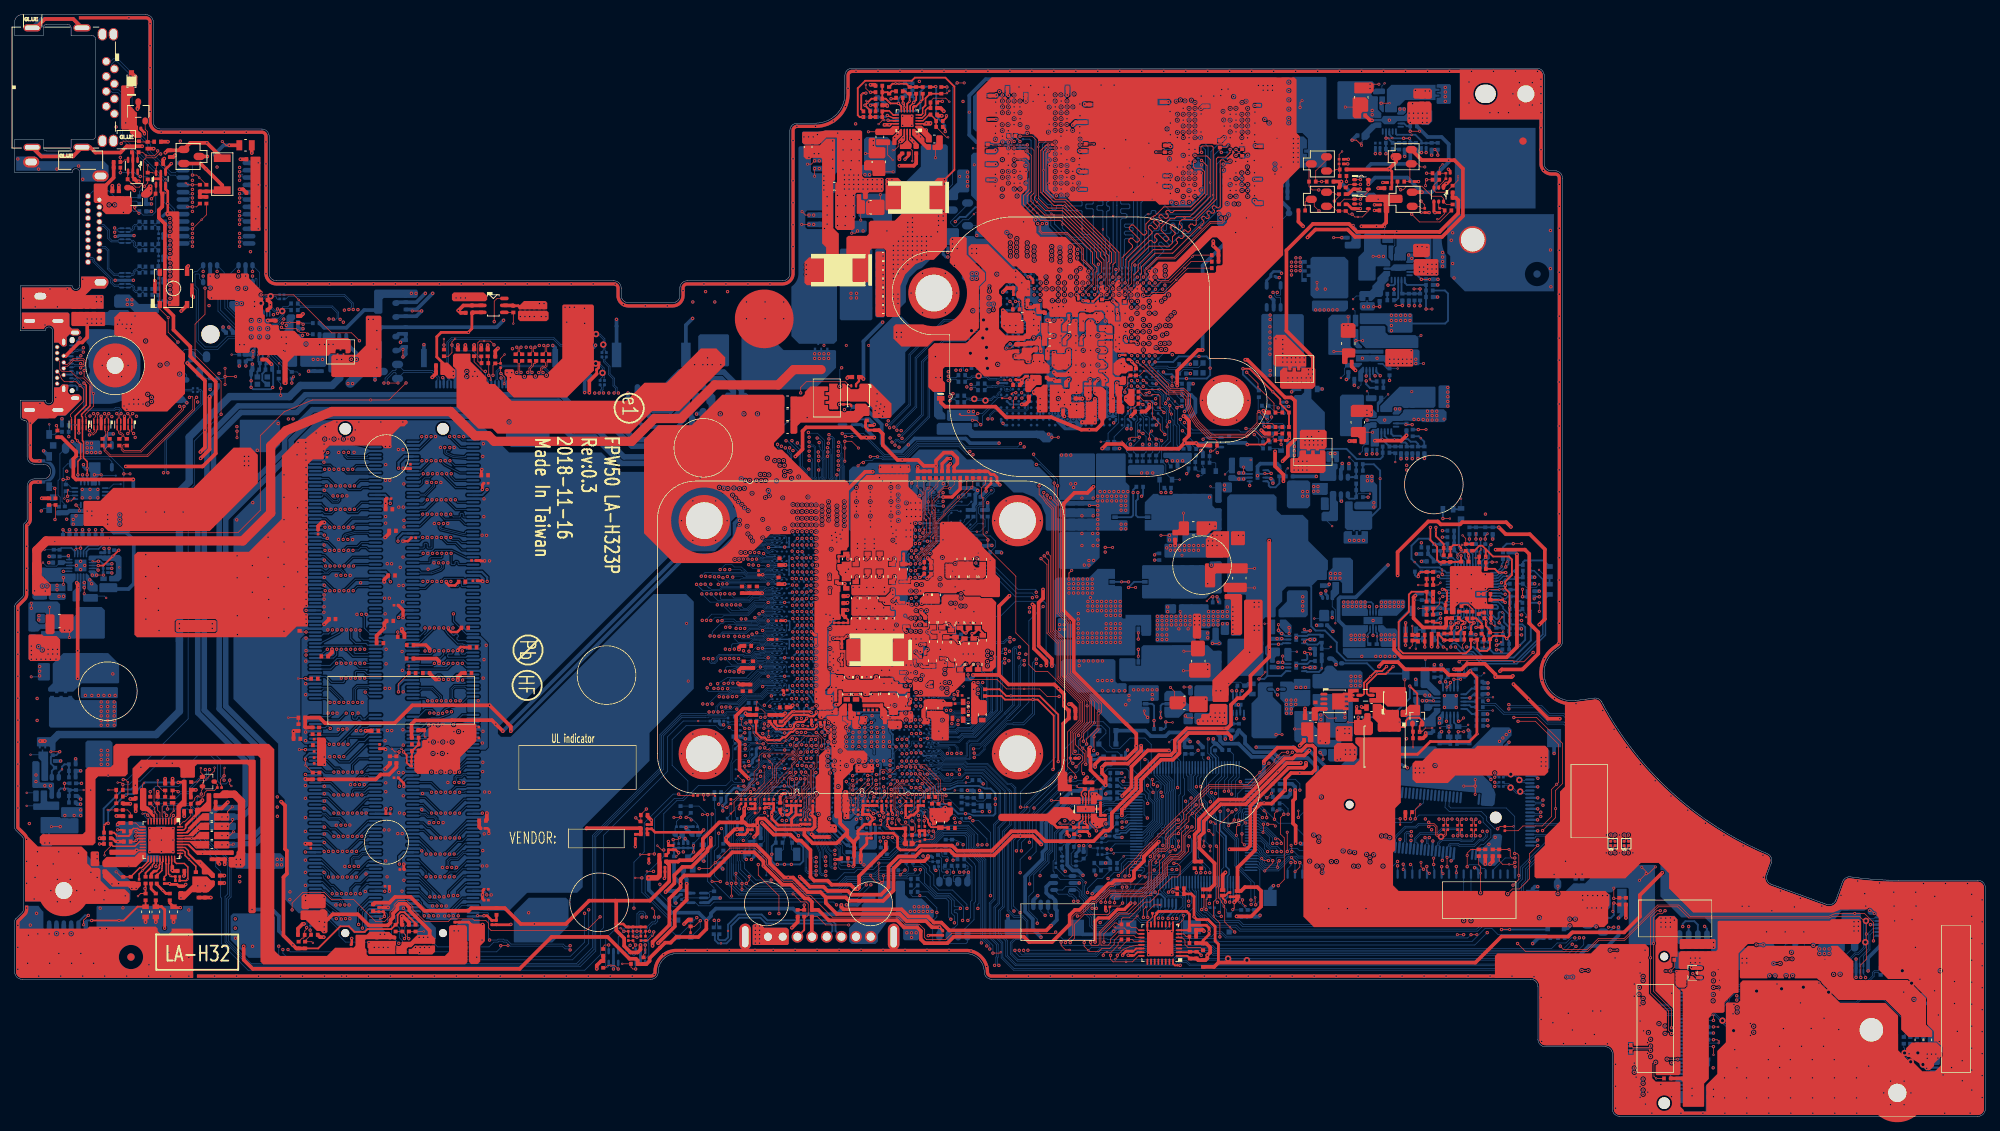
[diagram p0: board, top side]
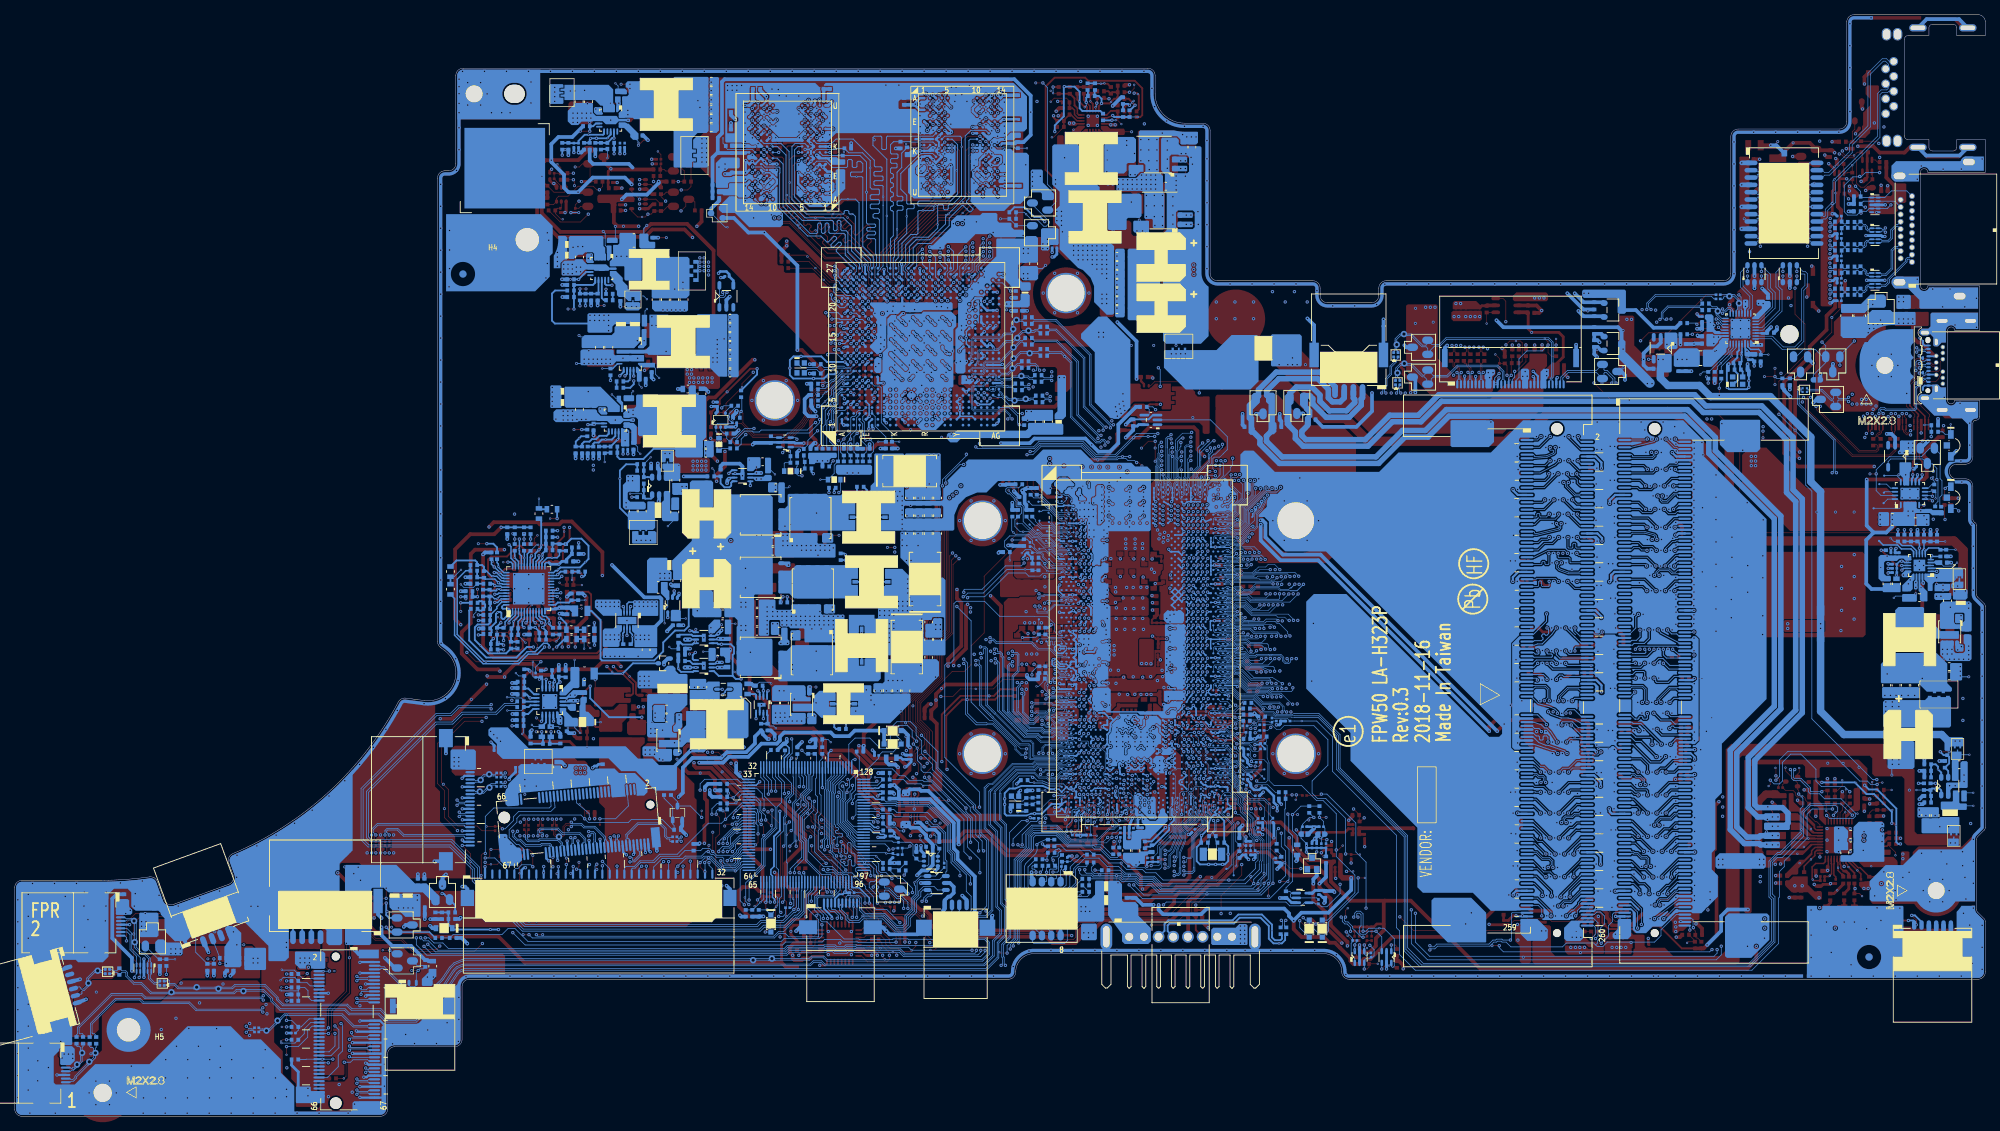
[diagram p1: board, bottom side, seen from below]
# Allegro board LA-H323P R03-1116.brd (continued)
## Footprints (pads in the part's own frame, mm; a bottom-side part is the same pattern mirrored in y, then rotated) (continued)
KC_FBMA-L11160808601LMA10T_2P
  rect 0.559x1.041 smd: 1(0,0) 2(1.3,0)
L2N7002DW1T1G_SC88-6
  oval 0.406x0.508 smd: 1(0,0) 2(0.65,0) 3(1.3,0) 4(1.3,1.9) 5(0.65,1.9) 6(0,1.9)
L03ESDL5V0CC3-2_SOT23-3
  oval 1.016x1.524 smd: 1(0,0) 2(0.965,2.083) 3(-0.965,2.083)
L05ESDL5V0NA-4_SLP2510P8-10-9
  rect 0.203x0.686 smd: 1(0,0) 2(-0.5,0) 4(-1.5,0) 5(-2,0) 6(-2,-0.875) 7(-1.5,-0.875) 8(-0.5,-0.875) 9(0,-0.875)
  rect 0.406x1.549 smd: 3(-1,-0.437)
L30ESD24VC3-2_SOT23-3
  oval 1.016x1.524 smd: 1(0,0) 2(0.965,2.083) 3(-0.965,2.083)
L_4X4X2_F_2P
  rect 1.194x3.708 smd: 1(0,0) 2(2.8,0)
L_5X5X3_M
  custom 0.54x0.54 smd: 1(0,0) 4(4.35,0)
  rect 0.762x0.508 smd: 2(0.699,0) 3(3.652,0)
L_5X5X3_M_2P
  rect 2.159x2.794 smd: 1(0,0) 2(4.35,0)
L_7X7X3_M
  custom 0.591x0.591 smd: 1(0,0) 4(6.05,0)
  rect 0.762x0.508 smd: 2(0.8,0) 3(5.25,0)
L_7X7X3_M_2P
  rect 2.362x3.505 smd: 1(0,0) 2(6.05,0)
L_7X7X4_M
  custom 0.591x0.591 smd: 1(0,0) 4(6.05,0)
  rect 0.762x0.508 smd: 2(0.8,0) 3(5.25,0)
LBSS138LT1G_SOT23-3
  oval 1.016x1.524 smd: 1(0,0) 2(0.965,2.083) 3(-0.965,2.083)
LED_LTW-110DC5-C_3P
  rect 1.194x0.787 smd: 1(0,0) 2(3,0)
  rect 0.889x0.889 smd: 3(1.5,-0.55)
LOTES_AHDM0064-P001A_19P
  round 0.787 hole 0.559: 1(0,0) 2(0.5,1.55) 3(1,0) 4(1.5,1.55) 5(2,0) 6(2.5,1.55) 7(3,0) 8(3.5,1.55) 9(4,0) 10(4.5,1.55) 11(5,0) 12(5.5,1.55) 13(6,0) 14(6.5,1.55) 15(7,0) 16(7.5,1.55) 17(8,0) 18(8.5,1.55) 19(9,0)
  oval 1.499x2.21 hole 0.889x1.6: 20(-2.75,1.7) 21(-4.65,-6.5) 22(11.75,1.7) 23(13.65,-7.75)
LOTES_APCI0019-P003H_67P
  round 1.092 hole 1.092 unplated: (-0.75,-5.275)
  round 1.6 hole 1.6 unplated: (19.25,-5.275)
  oval 0.305x1.549 smd: 1(0,0) 2(0.25,-7.55) 3(0.5,0) 4(0.75,-7.55) 5(1,0) 6(1.25,-7.55) 7(1.5,0) 8(1.75,-7.55) 9(2,0) 10(2.25,-7.55) 11(2.5,0) 12(2.75,-7.55) 13(3,0) 14(3.25,-7.55) 15(3.5,0) 16(3.75,-7.55) 17(4,0) 18(4.25,-7.55) 19(4.5,0) 20(4.75,-7.55) 21(5,0) 22(5.25,-7.55) 23(5.5,0) 24(7.75,-7.55) 25(8,0) 26(8.25,-7.55) 27(8.5,0) 28(8.75,-7.55) 29(9,0) 30(9.25,-7.55) 31(9.5,0) 32(9.75,-7.55) 33(10,0) 34(10.25,-7.55) 35(10.5,0) 36(10.75,-7.55) 37(11,0) 38(11.25,-7.55) 39(11.5,0) 40(11.75,-7.55) 41(12,0) 42(12.25,-7.55) 43(12.5,0) 44(12.75,-7.55) 45(13,0) 46(13.25,-7.55) 47(13.5,0) 48(13.75,-7.55) 49(14,0) 50(14.25,-7.55) 51(14.5,0) 52(14.75,-7.55) 53(15,0) 54(15.25,-7.55) 55(15.5,0) 56(15.75,-7.55) 57(16,0) 58(16.25,-7.55) 59(16.5,0) 60(16.75,-7.55) 61(17,0) 62(17.25,-7.55) 63(17.5,0) 64(17.75,-7.55) 65(18,0) 66(18.25,-7.55) 67(18.5,0)
  rect 1.194x2.743 smd: 68(-1.1,-0.775) 69(19.6,-0.775)
LUDZS3P6BT1G_SOD323-2
  rect 0.635x0.838 smd: 1(0,0) 2(2.225,0)
MMBF170-7-F_SOT23-3
  oval 1.016x1.524 smd: 1(0,0) 2(0.965,2.083) 3(-0.965,2.083)
MMBT3904WH_SOT323-3
  oval 0.61x0.787 smd: 1(0,0) 2(-0.65,-1.6) 3(0.65,-1.6)
MURAT_BLM15BD601SN1D_2P
  rect 0.508x0.762 smd: 1(0,0) 2(0.75,0)
MURAT_BLM15EG221SN1D_2P
  rect 0.508x0.762 smd: 1(0,0) 2(0.75,0)
MURAT_BLM15PX471SN1D_2P
  rect 0.508x0.762 smd: 1(0,0) 2(0.75,0)
MURAT_BLM18PG300SN1D_2P
  rect 0.66x1.041 smd: 1(0,0) 2(1.2,0)
MURAT_DLM0NSN900HY2D_4P
  rect 0.305x0.305 smd: 1(0,0) 2(0.6,0) 3(0.6,-0.5) 4(0,-0.5)
N16S-GT-S-A2_BGA_595P
  round 0.381 smd: A2(0.8,0) A3(1.6,0) A4(2.4,0) A6(4.1,0) A7(4.9,0) A9(6.58,0) A10(7.38,0) A12(9.06,0) A13(9.86,0) A15(11.54,0) A16(12.34,0) A18(14.02,0) A19(14.82,0) A21(16.5,0) A22(17.3,0) A24(19,0) A25(19.8,0) A26(20.6,0) AA1(0,-16.5) AA2(0.8,-16.5) AA3(1.6,-16.5) AA4(2.4,-16.5) AA5(3.2,-16.5) AA6(4.04,-16.5) AA7(4.9,-16.5) AA8(5.74,-16.5) AA9(6.58,-16.56) AA10(7.38,-16.56) AA12(9.06,-16.56) AA13(9.86,-16.56) AA14(10.7,-16.56) AA15(11.54,-16.56) AA16(12.34,-16.56) AA18(14.02,-16.56) AA19(14.82,-16.56) AA20(15.66,-16.5) AA21(16.5,-16.5) AA22(17.36,-16.5) AA23(18.2,-16.5) AA24(19,-16.5) AA25(19.8,-16.5) AA26(20.6,-16.5) AA27(21.4,-16.5) AB1(0,-17.3) AB2(0.8,-17.3) AB3(1.6,-17.3) AB4(2.4,-17.3) AB5(3.2,-17.3) AB6(4.1,-17.3) AB7(4.9,-17.36) AB8(5.74,-17.36) AB9(6.58,-17.36) AB10(7.38,-17.36) AB11(8.22,-17.36) AB12(9.06,-17.36) AB13(9.86,-17.36) AB14(10.7,-17.36) AB15(11.54,-17.36) AB16(12.34,-17.36) AB17(13.18,-17.36) AB18(14.02,-17.36) AB19(14.82,-17.36) AB20(15.66,-17.36) AB21(16.5,-17.36) AB22(17.3,-17.3) AB23(18.2,-17.3) AB24(19,-17.3) AB25(19.8,-17.3) AB26(20.6,-17.3) AB27(21.4,-17.3) AC2(0.8,-18.15) AC3(1.6,-18.15) AC4(2.4,-18.15) AC5(3.25,-18.15) AC6(4.1,-18.2) AC7(4.9,-18.2) AC8(5.74,-18.2) AC9(6.58,-18.2) AC10(7.38,-18.2) AC11(8.22,-18.2) AC12(9.06,-18.2) AC13(9.86,-18.2) AC14(10.7,-18.2) AC15(11.54,-18.2) AC16(12.34,-18.2) AC17(13.18,-18.2) AC18(14.02,-18.2) AC19(14.82,-18.2) AC20(15.66,-18.2) AC21(16.5,-18.2) AC22(17.3,-18.2) AC23(18.15,-18.15) AC24(19,-18.15) AC25(19.8,-18.15) AC26(20.6,-18.15) AD1(0,-19) AD2(0.8,-19) AD3(1.6,-19) AD4(2.4,-19) AD5(3.25,-19) AD6(4.1,-19) AD7(4.9,-19) AD8(5.74,-19) AD9(6.58,-19) AD10(7.38,-19) AD11(8.22,-19) AD12(9.06,-19) AD13(9.86,-19) AD14(10.7,-19) AD15(11.54,-19) AD16(12.34,-19) AD17(13.18,-19) AD18(14.02,-19) AD19(14.82,-19) AD20(15.66,-19) AD21(16.5,-19) AD22(17.3,-19) AD23(18.15,-19) AD24(19,-19) AD25(19.8,-19) AD26(20.6,-19) AD27(21.4,-19) AE1(0,-19.8) AE2(0.8,-19.8) AE3(1.6,-19.8) AE4(2.4,-19.8) AE5(3.25,-19.8) AE6(4.1,-19.8) AE7(4.9,-19.8) AE8(5.74,-19.8) AE9(6.58,-19.8) AE10(7.38,-19.8) AE11(8.22,-19.8) AE12(9.06,-19.8) AE13(9.86,-19.8) AE14(10.7,-19.8) AE15(11.54,-19.8) AE16(12.34,-19.8) AE17(13.18,-19.8) AE18(14.02,-19.8) AE19(14.82,-19.8) AE20(15.66,-19.8) AE21(16.5,-19.8) AE22(17.3,-19.8) AE23(18.15,-19.8) AE24(19,-19.8) AE25(19.8,-19.8) AE26(20.6,-19.8) AE27(21.4,-19.8) AF1(0,-20.6) AF2(0.8,-20.6) AF3(1.6,-20.6) AF4(2.4,-20.6) AF5(3.25,-20.6) AF6(4.1,-20.6) AF7(4.9,-20.6) AF8(5.74,-20.6) AF9(6.58,-20.6) AF10(7.38,-20.6) AF11(8.22,-20.6) AF12(9.06,-20.6) AF13(9.86,-20.6) AF14(10.7,-20.6) AF15(11.54,-20.6) AF16(12.34,-20.6) AF17(13.18,-20.6) AF18(14.02,-20.6) AF19(14.82,-20.6) AF20(15.66,-20.6) AF21(16.5,-20.6) AF22(17.3,-20.6) AF23(18.15,-20.6) AF24(19,-20.6) AF25(19.8,-20.6) AF26(20.6,-20.6) AF27(21.4,-20.6) AG2(0.8,-21.4) AG3(1.6,-21.4) AG4(2.4,-21.4) AG6(4.1,-21.4) AG7(4.9,-21.4) AG9(6.58,-21.4) AG10(7.38,-21.4) AG12(9.06,-21.4) AG13(9.86,-21.4) AG15(11.54,-21.4) AG16(12.34,-21.4) AG18(14.02,-21.4) AG19(14.82,-21.4) AG21(16.5,-21.4) AG22(17.3,-21.4) AG24(19,-21.4) AG25(19.8,-21.4) AG26(20.6,-21.4) B1(0,-0.8) B2(0.8,-0.8) B3(1.6,-0.8) B4(2.4,-0.8) B5(3.25,-0.8) B6(4.1,-0.8) B7(4.9,-0.8) B8(5.74,-0.8) B9(6.58,-0.8) B10(7.38,-0.8) B11(8.22,-0.8) B12(9.06,-0.8) B13(9.86,-0.8) B14(10.7,-0.8) B15(11.54,-0.8) B16(12.34,-0.8) B17(13.18,-0.8) B18(14.02,-0.8) B19(14.82,-0.8) B20(15.66,-0.8) B21(16.5,-0.8) B22(17.3,-0.8) B23(18.15,-0.8) B24(19,-0.8) B25(19.8,-0.8) B26(20.6,-0.8) B27(21.4,-0.8) C1(0,-1.6) C2(0.8,-1.6) C3(1.6,-1.6) C4(2.4,-1.6) C5(3.25,-1.6) C6(4.1,-1.6) C7(4.9,-1.6) C8(5.74,-1.6) C9(6.58,-1.6) C10(7.38,-1.6) C11(8.22,-1.6) C12(9.06,-1.6) C13(9.86,-1.6) C14(10.7,-1.6) C15(11.54,-1.6) C16(12.34,-1.6) C17(13.18,-1.6) C18(14.02,-1.6) C19(14.82,-1.6) C20(15.66,-1.6) C21(16.5,-1.6) C22(17.3,-1.6) C23(18.15,-1.6) C24(19,-1.6) C25(19.8,-1.6) C26(20.6,-1.6) C27(21.4,-1.6) D1(0,-2.4) D2(0.8,-2.4) D3(1.6,-2.4) D4(2.4,-2.4) D5(3.25,-2.4) D6(4.1,-2.4) D7(4.9,-2.4) D8(5.74,-2.4) D9(6.58,-2.4) D10(7.38,-2.4) D11(8.22,-2.4) D12(9.06,-2.4) D13(9.86,-2.4) D14(10.7,-2.4) D15(11.54,-2.4) D16(12.34,-2.4) D17(13.18,-2.4) D18(14.02,-2.4) D19(14.82,-2.4) D20(15.66,-2.4) D21(16.5,-2.4) D22(17.3,-2.4) D23(18.15,-2.4) D24(19,-2.4) D25(19.8,-2.4) D26(20.6,-2.4) D27(21.4,-2.4) E2(0.8,-3.25) E3(1.6,-3.25) E4(2.4,-3.25) E5(3.25,-3.25) E6(4.1,-3.2) E7(4.9,-3.2) E8(5.74,-3.2) E9(6.58,-3.2) E10(7.38,-3.2) E11(8.22,-3.2) E12(9.06,-3.2) E13(9.86,-3.2) E14(10.7,-3.2) E15(11.54,-3.2) E16(12.34,-3.2) E17(13.18,-3.2) E18(14.02,-3.2) E19(14.82,-3.2) E20(15.66,-3.2) E21(16.5,-3.2) E22(17.3,-3.2) E23(18.15,-3.25) E24(19,-3.25) E25(19.8,-3.25) E26(20.6,-3.25) F1(0,-4.1) F2(0.8,-4.1) F3(1.6,-4.1) F4(2.4,-4.1) F5(3.2,-4.1) F6(4.1,-4.1) F7(4.9,-4.04) F8(5.74,-4.04) F9(6.58,-4.04) F10(7.38,-4.04) F11(8.22,-4.04) F12(9.06,-4.04) F13(9.86,-4.04) F14(10.7,-4.04) F15(11.54,-4.04) F16(12.34,-4.04) F17(13.18,-4.04) F18(14.02,-4.04) F19(14.82,-4.04) F20(15.66,-4.04) F21(16.5,-4.04) F22(17.3,-4.1) F23(18.2,-4.1) F24(19,-4.1) F25(19.8,-4.1) F26(20.6,-4.1) F27(21.4,-4.1) G1(0,-4.9) G2(0.8,-4.9) G3(1.6,-4.9) G4(2.4,-4.9) G5(3.2,-4.9) G6(4.04,-4.9) G7(4.9,-4.9) G8(5.74,-4.9) G9(6.58,-4.84) G10(7.38,-4.84) G12(9.06,-4.84) G13(9.86,-4.84) G14(10.7,-4.84) G15(11.54,-4.84) G16(12.34,-4.84) G18(14.02,-4.84) G19(14.82,-4.84) G20(15.66,-4.9) G21(16.5,-4.9) G22(17.36,-4.9) G23(18.2,-4.9) G24(19,-4.9) G25(19.8,-4.9) G26(20.6,-4.9) G27(21.4,-4.9) H2(0.8,-5.74) H3(1.6,-5.74) H4(2.4,-5.74) H5(3.2,-5.74) H6(4.04,-5.74) H22(17.36,-5.74) H23(18.2,-5.74) H24(19,-5.74) H25(19.8,-5.74) H26(20.6,-5.74) J1(0,-6.58) J2(0.8,-6.58) J3(1.6,-6.58) J4(2.4,-6.58) J5(3.2,-6.58) J6(4.04,-6.58) J7(4.84,-6.58) J21(16.56,-6.58) J22(17.36,-6.58) J23(18.2,-6.58) J24(19,-6.58) J25(19.8,-6.58) J26(20.6,-6.58) J27(21.4,-6.58) K1(0,-7.38) K2(0.8,-7.38) K3(1.6,-7.38) K4(2.4,-7.38) K5(3.2,-7.38) K6(4.04,-7.38) K7(4.84,-7.38) K21(16.56,-7.38) K22(17.36,-7.38) K23(18.2,-7.38) K24(19,-7.38) K25(19.8,-7.38) K26(20.6,-7.38) K27(21.4,-7.38) L2(0.8,-8.22) L3(1.6,-8.22) L4(2.4,-8.22) L5(3.2,-8.22) L6(4.04,-8.22) L22(17.36,-8.22) L23(18.2,-8.22) L24(19,-8.22) L25(19.8,-8.22) L26(20.6,-8.22) M1(0,-9.06) M2(0.8,-9.06) M3(1.6,-9.06) M4(2.4,-9.06) M5(3.2,-9.06) M6(4.04,-9.06) M7(4.84,-9.06) M21(16.56,-9.06) M22(17.36,-9.06) M23(18.2,-9.06) M24(19,-9.06) M25(19.8,-9.06) M26(20.6,-9.06) M27(21.4,-9.06) N1(0,-9.86) N2(0.8,-9.86) N3(1.6,-9.86) N4(2.4,-9.86) N5(3.2,-9.86) N6(4.04,-9.86) N7(4.84,-9.86) N21(16.56,-9.86) N22(17.36,-9.86) N23(18.2,-9.86) N24(19,-9.86) N25(19.8,-9.86) N26(20.6,-9.86) N27(21.4,-9.86) P2(0.8,-10.7) P3(1.6,-10.7) P4(2.4,-10.7) P5(3.2,-10.7) P6(4.04,-10.7) P22(17.36,-10.7) P23(18.2,-10.7) P24(19,-10.7) P25(19.8,-10.7) P26(20.6,-10.7) R1(0,-11.54) R2(0.8,-11.54) R3(1.6,-11.54) R4(2.4,-11.54) R5(3.2,-11.54) R6(4.04,-11.54) R7(4.84,-11.54) R21(16.56,-11.54) R22(17.36,-11.54) R23(18.2,-11.54) R24(19,-11.54) R25(19.8,-11.54) R26(20.6,-11.54) R27(21.4,-11.54) T1(0,-12.34) T2(0.8,-12.34) T3(1.6,-12.34) T4(2.4,-12.34) T5(3.2,-12.34) T6(4.04,-12.34) T7(4.84,-12.34) T21(16.56,-12.34) T22(17.36,-12.34) T23(18.2,-12.34) T24(19,-12.34) T25(19.8,-12.34) T26(20.6,-12.34) T27(21.4,-12.34) U2(0.8,-13.18) U3(1.6,-13.18) U4(2.4,-13.18) U5(3.2,-13.18) U6(4.04,-13.18) U22(17.36,-13.18) U23(18.2,-13.18) U24(19,-13.18) U25(19.8,-13.18) U26(20.6,-13.18) V1(0,-14.02) V2(0.8,-14.02) V3(1.6,-14.02) V4(2.4,-14.02) V5(3.2,-14.02) V6(4.04,-14.02) V7(4.84,-14.02) V21(16.56,-14.02) V22(17.36,-14.02) V23(18.2,-14.02) V24(19,-14.02) V25(19.8,-14.02) V26(20.6,-14.02) V27(21.4,-14.02) W1(0,-14.82) W2(0.8,-14.82) W3(1.6,-14.82) W4(2.4,-14.82) W5(3.2,-14.82) W6(4.04,-14.82) W7(4.84,-14.82) W21(16.56,-14.82) W22(17.36,-14.82) W23(18.2,-14.82) W24(19,-14.82) W25(19.8,-14.82) W26(20.6,-14.82) W27(21.4,-14.82) Y2(0.8,-15.66) Y3(1.6,-15.66) Y4(2.4,-15.66) Y5(3.2,-15.66) Y6(4.04,-15.66) Y22(17.36,-15.66) Y23(18.2,-15.66) Y24(19,-15.66) Y25(19.8,-15.66) Y26(20.6,-15.66)
  round 0.406 smd: K10(6.7,-6.7) K11(7.7,-6.7) K12(8.7,-6.7) K13(9.7,-6.7) K14(10.7,-6.7) K15(11.7,-6.7) K16(12.7,-6.7) K17(13.7,-6.7) K18(14.7,-6.7) L10(6.7,-7.7) L11(7.7,-7.7) L12(8.7,-7.7) L13(9.7,-7.7) L14(10.7,-7.7) L15(11.7,-7.7) L16(12.7,-7.7) L17(13.7,-7.7) L18(14.7,-7.7) M10(6.7,-8.7) M11(7.7,-8.7) M12(8.7,-8.7) M13(9.7,-8.7) M14(10.7,-8.7) M15(11.7,-8.7) M16(12.7,-8.7) M17(13.7,-8.7) M18(14.7,-8.7) N10(6.7,-9.7) N11(7.7,-9.7) N12(8.7,-9.7) N13(9.7,-9.7) N14(10.7,-9.7) N15(11.7,-9.7) N16(12.7,-9.7) N17(13.7,-9.7) N18(14.7,-9.7) P10(6.7,-10.7) P11(7.7,-10.7) P12(8.7,-10.7) P13(9.7,-10.7) P14(10.7,-10.7) P15(11.7,-10.7) P16(12.7,-10.7) P17(13.7,-10.7) P18(14.7,-10.7) R10(6.7,-11.7) R11(7.7,-11.7) R12(8.7,-11.7) R13(9.7,-11.7) R14(10.7,-11.7) R15(11.7,-11.7) R16(12.7,-11.7) R17(13.7,-11.7) R18(14.7,-11.7) T10(6.7,-12.7) T11(7.7,-12.7) T12(8.7,-12.7) T13(9.7,-12.7) T14(10.7,-12.7) T15(11.7,-12.7) T16(12.7,-12.7) T17(13.7,-12.7) T18(14.7,-12.7) U10(6.7,-13.7) U11(7.7,-13.7) U12(8.7,-13.7) U13(9.7,-13.7) U14(10.7,-13.7) U15(11.7,-13.7) U16(12.7,-13.7) U17(13.7,-13.7) U18(14.7,-13.7) V10(6.7,-14.7) V11(7.7,-14.7) V12(8.7,-14.7) V13(9.7,-14.7) V14(10.7,-14.7) V15(11.7,-14.7) V16(12.7,-14.7) V17(13.7,-14.7) V18(14.7,-14.7)
NC7ST32P5X_SC70-5
  oval 0.406x0.508 smd: 1(0,0) 2(0.65,0) 3(1.3,0) 4(1.3,1.9) 5(0,1.9)
OCTEK_BTJ-08TFBRZB_8P
  round 1.6 hole 1.092: 1(0,0) 2(2,0) 3(4,0) 4(6,0) 5(8,0) 6(10,0) 7(12,0) 8(14,0)
  oval 1.6x3.607 hole 0.889x2.896: 9(-3.125,0) 10(17.125,0)
PESD5V0U2BT_SOT23-3
  oval 1.016x1.524 smd: 1(0,0) 2(0.965,2.083) 3(-0.965,2.083)
PJ2301_SOT23-3
  oval 1.016x1.524 smd: 1(0,0) 2(0.965,2.083) 3(-0.965,2.083)
Q_N_DFN56-8-5
  oval 0.61x1.27 smd: 1(0,0) 2(1.27,0) 3(2.54,0) 4(3.81,0)
  custom 1.105x1.105 smd: 5(1.905,3.715)
R0201_0OHM
  rect 0.381x0.356 smd: 1(0,0) 2(0.584,0)
R0402_0OHM
  rect 0.508x0.559 smd: 1(0,0) 2(0.914,0)
R0603_0OHM
  rect 0.635x0.889 smd: 1(0,0) 2(1.397,0)
R0603_0OHM-NPM
  rect 0.635x0.889 smd: 1(0,0) 2(1.397,0)
R0805_0OHM
  rect 0.813x1.397 smd: 1(0,0) 2(1.702,0)
R_0201
  rect 0.381x0.356 smd: 1(0,0) 2(0.584,0)
R_0402
  rect 0.508x0.559 smd: 1(0,0) 2(0.914,0)
R_0603
  rect 0.635x0.889 smd: 1(0,0) 2(1.397,0)
R_0805
  rect 0.813x1.397 smd: 1(0,0) 2(1.702,0)
R_1206
  rect 1.016x1.651 smd: 1(0,0) 2(2.667,0)
R_1206_4P-D
  custom 0.371x0.371 smd: 1(0,0) 4(3.327,0)
  custom 0.114x0.114 smd: 2(0.775,0) 3(2.553,0)
RB751S40T1G_SOD523-2
  rect 0.61x0.787 smd: 1(0,0) 2(1.7,0)
RB751V-40_SOD323-2
  rect 0.787x0.889 smd: 1(0,0) 2(2.14,0)
RT3602AJGQW_WQFN48_6X6
  oval 0.889x0.203 smd: 1(0,0) 2(0,-0.4) 3(0,-0.8) 4(0,-1.2) 5(0,-1.6) 6(0,-2) 7(0,-2.4) 8(0,-2.8) 9(0,-3.2) 10(0,-3.6) 11(0,-4) 12(0,-4.4) 25(6.1,-4.4) 26(6.1,-4) 27(6.1,-3.6) 28(6.1,-3.2) 29(6.1,-2.8) 30(6.1,-2.4) 31(6.1,-2) 32(6.1,-1.6) 33(6.1,-1.2) 34(6.1,-0.8) 35(6.1,-0.4) 36(6.1,0)
  oval 0.203x0.889 smd: 13(0.85,-5.25) 14(1.25,-5.25) 15(1.65,-5.25) 16(2.05,-5.25) 17(2.45,-5.25) 18(2.85,-5.25) 19(3.25,-5.25) 20(3.65,-5.25) 21(4.05,-5.25) 22(4.45,-5.25) 23(4.85,-5.25) 24(5.25,-5.25) 37(5.25,0.85) 38(4.85,0.85) 39(4.45,0.85) 40(4.05,0.85) 41(3.65,0.85) 42(3.25,0.85) 43(2.85,0.85) 44(2.45,0.85) 45(2.05,0.85) 46(1.65,0.85) 47(1.25,0.85) 48(0.85,0.85)
  rect 4.293x4.293 smd: 49(3.05,-2.2)
RT8812AGQW_WQFN20_3X3
  oval 0.203x0.889 smd: 1(0,0) 2(0.4,0) 3(0.8,0) 4(1.2,0) 5(1.6,0) 11(1.6,3.1) 12(1.2,3.1) 13(0.8,3.1) 14(0.4,3.1) 15(0,3.1)
  oval 0.889x0.203 smd: 6(2.35,0.75) 7(2.35,1.15) 8(2.35,1.55) 9(2.35,1.95) 10(2.35,2.35) 16(-0.75,2.35) 17(-0.75,1.95) 18(-0.75,1.55) 19(-0.75,1.15) 20(-0.75,0.75)
  rect 1.702x1.702 smd: 21(0.8,1.55)
RT9610CGQW_WDFN8_2X2
  oval 0.254x0.838 smd: 1(0,0) 2(0.5,0) 3(1,0) 4(1.5,0) 5(1.5,2.15) 6(1,2.15) 7(0.5,2.15) 8(0,2.15)
  rect 1.118x0.533 smd: 9(0.75,1.075)
RTL8166EH-CG_QFN32_4X4
  oval 0.203x0.889 smd: 1(0,0) 2(0.4,0) 3(0.8,0) 4(1.2,0) 5(1.6,0) 6(2,0) 7(2.4,0) 8(2.8,0) 17(2.8,4.1) 18(2.4,4.1) 19(2,4.1) 20(1.6,4.1) 21(1.2,4.1) 22(0.8,4.1) 23(0.4,4.1) 24(0,4.1)
  oval 0.889x0.203 smd: 9(3.45,0.65) 10(3.45,1.05) 11(3.45,1.45) 12(3.45,1.85) 13(3.45,2.25) 14(3.45,2.65) 15(3.45,3.05) 16(3.45,3.45) 25(-0.65,3.45) 26(-0.65,3.05) 27(-0.65,2.65) 28(-0.65,2.25) 29(-0.65,1.85) 30(-0.65,1.45) 31(-0.65,1.05) 32(-0.65,0.65)
  rect 2.692x2.692 smd: 33(1.4,2.05)
SHORTPADS
  custom 0.19x0.19 smd: 1(-0.483,0) 2(0.483,0)
SINGA_2RJ3081-1A8211F_12P-T
  round 1.194 hole 0.889: 1(0,0) 2(1.02,1.1) 3(2.04,0) 4(3.06,1.1) 5(4.08,0) 6(5.1,1.1) 7(6.12,0) 8(7.14,1.1)
  oval 0.991x2.388 hole 0.61x2.007: 9(-4.58,-3.3) 10(-4.58,-10.1) 11(11.72,-10.1) 12(11.72,-3.3)
  oval 1.702x1.295 hole 1.397x0.991: A1(10.845,0.98) A2(10.845,-0.52) B1(-3.705,0.98) B2(-3.705,-0.52)
SINGA_2UB3C02-002111F_24P-T
  round 0.66 hole 0.66 unplated: (-0.7,0.09)
  oval 0.838x0.66 hole 0.838x0.66 unplated: (6.2,0.09)
  oval 0.813x1.397 hole 0.508x1.092: 1(7.225,0.49)
  oval 0.991x2.007 hole 0.508x1.499: 2(8.825,-1.85) 3(8.825,-5.71) 5(-3.325,-1.85) 6(-3.325,-5.71)
  oval 0.991x1.6 hole 0.508x1.092: 4(-1.725,0.49)
  rect 0.508x0.305 smd: 7(5.95,0.78) 8(3.75,0.78) 9(1.75,0.78) 10(-0.45,0.78)
  oval 0.305x0.61 smd: A1(0,0) A2(0.5,0) A3(1,0) A4(1.5,0) A5(2,0) A6(2.5,0) A7(3,0) A8(3.5,0) A9(4,0) A10(4.5,0) A11(5,0)
  oval 0.229x0.61 smd: A12(5.462,0)
  oval 1.194x0.711 hole 0.889x0.406: B1(5.95,-1.05) B12(-0.45,-1.05)
  round 0.61 hole 0.406: B2(5.25,-1.95) B3(4.45,-1.95) B4(4.05,-1.05) B5(3.6,-1.95) B6(3.15,-1.05) B7(2.35,-1.05) B8(1.9,-1.95) B9(1.45,-1.05) B10(1.05,-1.95) B11(0.25,-1.95)
SLB9670VQ1P2-FW4P4X_VQFN32_5X5
  oval 0.889x0.254 smd: 1(0,0) 2(0,-0.5) 3(0,-1) 4(0,-1.5) 5(0,-2) 6(0,-2.5) 7(0,-3) 8(0,-3.5) 17(5.1,-3.5) 18(5.1,-3) 19(5.1,-2.5) 20(5.1,-2) 21(5.1,-1.5) 22(5.1,-1) 23(5.1,-0.5) 24(5.1,0)
  oval 0.254x0.889 smd: 9(0.8,-4.3) 10(1.3,-4.3) 11(1.8,-4.3) 12(2.3,-4.3) 13(2.8,-4.3) 14(3.3,-4.3) 15(3.8,-4.3) 16(4.3,-4.3) 25(4.3,0.8) 26(3.8,0.8) 27(3.3,0.8) 28(2.8,0.8) 29(2.3,0.8) 30(1.8,0.8) 31(1.3,0.8) 32(0.8,0.8)
  rect 3.607x3.607 smd: 33(2.55,-1.75)
SN74AHC1G08DCKR_SC70-5
  oval 0.381x1.295 smd: 1(0,0.15) 2(0.65,0.15) 3(1.3,0.15) 4(1.3,1.89) 5(0,1.89)
SSM3K7002FU_SC70-3
  oval 0.508x0.991 smd: 1(0,0) 2(0.65,1.9) 3(-0.65,1.9)
SW_TJG-533-V-T-R_6P
  rect 0.61x0.991 smd: 1(0,0) 2(0,-4.4) 3(-3.7,0) 4(-3.7,-4.4)
  rect 0.457x1.397 smd: 5(0.675,-2.2) 6(-4.375,-2.2)
SY8032ABC_SOT23-6
  oval 0.61x0.991 smd: 1(0,0) 2(0.95,0) 3(1.9,0) 4(1.9,2.4) 5(0.95,2.4) 6(0,2.4)
SY8270CTMC_QFN13_4X3
  custom 0.337x0.337 smd: 1(0,0)
  rect 0.457x1.702 smd: 2(1.18,-0.75) 12(1.18,1.25)
  rect 0.838x1.702 smd: 3(2.06,-0.75) 11(2.06,1.25)
  oval 0.203x0.787 smd: 4(2.81,-1.2) 10(2.81,1.7)
  oval 0.787x0.254 smd: 5(3.625,-0.65) 6(3.625,-0.2) 7(3.625,0.25) 8(3.625,0.7) 9(3.625,1.15)
  oval 0.254x0.787 smd: 13(0.55,1.7)
SY8284BRAC_QFN20_3X3
  oval 0.889x0.254 smd: 1(0,0) 2(0,-0.45) 3(0,-0.9) 4(0,-1.35) 5(0,-1.8) 11(3.1,-1.8) 12(3.1,-1.35) 13(3.1,-0.9) 14(3.1,-0.45) 15(3.1,0)
  oval 0.254x0.889 smd: 6(0.65,-2.45) 7(1.1,-2.45) 8(1.55,-2.45) 9(2,-2.45) 10(2.45,-2.45) 16(2.45,0.65) 17(2,0.65) 18(1.55,0.65) 19(1.1,0.65) 20(0.65,0.65)
  custom 0.15x0.15 smd: 21(1.55,-0.9)
SY8286RAC_QFN20_3X3
  oval 0.889x0.254 smd: 1(0,0) 2(0,-0.45) 3(0,-0.9) 4(0,-1.35) 5(0,-1.8) 11(3.1,-1.8) 12(3.1,-1.35) 13(3.1,-0.9) 14(3.1,-0.45) 15(3.1,0)
  oval 0.254x0.889 smd: 6(0.65,-2.45) 7(1.1,-2.45) 8(1.55,-2.45) 9(2,-2.45) 10(2.45,-2.45) 16(2.45,0.65) 17(2,0.65) 18(1.55,0.65) 19(1.1,0.65) 20(0.65,0.65)
  rect 0.991x0.991 smd: 21(1.55,-0.9)
TAI-T_HPC252012F-1R0Y_2P
  rect 0.94x2.21 smd: 1(0,0) 2(1.75,0)
TAI-T_LAN-8700GS_25P
  oval 0.635x1.778 smd: 1(0,0) 2(1,0) 3(2,0) 4(3,0) 5(4,0) 6(5,0) 7(6,0) 8(7,0) 9(8,0) 10(9,0) 11(10,0) 12(11,0) 13(11,8.99) 14(10,8.99) 15(9,8.99) 16(8,8.99) 17(7,8.99) 18(6,8.99) 19(5,8.99) 20(4,8.99) 21(3,8.99) 22(2,8.99) 23(1,8.99) 24(0,8.99)
  rect 0.889x0.787 smd: 25(-1.32,4.54)
TC7SH08FUF_SSOP5
  oval 0.457x0.711 smd: 1(0,0) 2(0.65,0) 3(1.3,0) 4(1.3,1.875) 5(0,1.875)
TPC12
  round 0.305 smd: 1(0,0)
TPS22961DNYR_WSON8
  oval 0.305x0.508 smd: 1(0,0) 2(0.65,0) 3(1.3,0) 4(1.95,0) 5(1.95,2.7)
  oval 1.6x0.508 smd: 6(0.65,2.7)
  rect 2.388x1.6 smd: 7(0.975,1.35)
TPS22966DPUR_SON14_2X3
  oval 0.203x0.762 smd: 1(0,0) 2(0.4,0) 3(0.8,0) 4(1.2,0) 5(1.6,0) 6(2,0) 7(2.4,0) 8(2.4,2.05) 9(2,2.05) 10(1.6,2.05) 11(1.2,2.05) 12(0.8,2.05) 13(0.4,2.05) 14(0,2.05)
  rect 2.489x0.889 smd: 15(1.2,1.025)
TPS25810RVCR_QFN20_4X3
  oval 0.254x0.889 smd: 1(0,0) 2(0.5,0) 3(1,0) 4(1.5,0) 5(2,0) 6(2.5,0) 11(2.5,3.1) 12(2,3.1) 13(1.5,3.1) 14(1,3.1) 15(0.5,3.1) 16(0,3.1)
  oval 0.889x0.254 smd: 7(3.3,0.8) 8(3.3,1.3) 9(3.3,1.8) 10(3.3,2.3) 17(-0.8,2.3) 18(-0.8,1.8) 19(-0.8,1.3) 20(-0.8,0.8)
  rect 2.591x1.6 smd: 21(1.25,1.55)
VISHAY_IHLP-2525CZ-01_2P
  rect 2.54x3.556 smd: 1(-2.857,0) 2(2.857,0)
WHL-U42_BGA_1528P-T
  round 0.356 smd: A3(0.919,0) A36(22.17,0) B2(0.46,-0.46) B37(22.63,-0.46) C1(0,-0.919) CP1(0,-44.17) CP37(22.63,-44.17) CR2(0.46,-44.63) CR36(22.17,-44.63)
  round 0.33 smd: A4(1.569,0) A35(21.52,0) B3(1.088,-0.628) B36(22.002,-0.628) C2(0.628,-1.088) C37(22.63,-1.11) CN1(0,-43.52) CN37(22.63,-43.52) CP2(0.628,-44.002) CP36(22.002,-44.002) CR3(1.11,-44.63) CR35(21.52,-44.63) D1(0,-1.569)
  round 0.305 smd: A5(2.219,-0.023) A6(3.083,0) A32(19.543,0) A34(20.87,0) AA4(1.95,-11.894) AA9(5.105,-11.691) AA24(14.994,-11.834) AA26(15.921,-11.834) AA34(20.68,-11.596) AB3(0.981,-12.552) AB4(1.99,-12.552) AB5(2.697,-12.153) AB6(3.347,-12.153) AB7(3.997,-12.153) AB8(4.647,-12.153) AB9(5.105,-12.615) AB10(5.562,-12.153) AB25(15.457,-12.29) AB27(16.384,-12.29) AB28(17.034,-12.29) AB29(17.684,-12.29) AB30(18.334,-12.29) AB31(18.984,-12.29) AB32(19.634,-12.29) AB33(20.355,-12.247) AB34(21.005,-12.247) AC4(1.95,-13.209) AC5(2.697,-13.077) AC6(3.347,-13.077) AC7(3.997,-13.077) AC8(4.647,-13.077) AC10(5.562,-13.077) AC24(14.994,-12.745) AC25(15.457,-13.201) AC26(15.921,-12.745) AC27(16.384,-13.201) AC28(17.034,-13.201) AC29(17.684,-13.201) AC30(18.334,-13.201) AC31(18.984,-13.201) AC32(19.634,-13.201) AC34(20.68,-12.898) AD4(1.625,-13.772) AD9(5.105,-13.539) AD24(14.994,-13.657) AD26(15.921,-13.657) AD33(20.355,-13.505) AD35(21.56,-13.505) AE4(1.95,-14.335) AE5(2.697,-14.001) AE6(3.347,-14.001) AE7(3.997,-14.001) AE8(4.647,-14.001) AE9(5.105,-14.463) AE10(5.562,-14.001) AE24(14.994,-14.568) AE25(15.457,-14.112) AE26(15.921,-14.568) AE27(16.384,-14.112) AE28(17.034,-14.112) AE29(17.684,-14.112) AE30(18.334,-14.112) AE31(18.984,-14.112) AE32(19.634,-14.112) AE34(20.68,-14.113) AF3(0.981,-14.993) AF4(1.99,-14.993) AF5(2.697,-14.925) AF6(3.347,-14.925) AF7(3.997,-14.925) AF8(4.647,-14.925) AF10(5.562,-14.925) AF25(15.457,-15.024) AF27(16.384,-15.024) AF28(17.034,-15.024) AF29(17.684,-15.024) AF30(18.334,-15.024) AF31(18.984,-15.024) AF32(19.634,-15.024) AF33(20.355,-14.764) AF34(21.005,-14.764) AG4(1.95,-15.65) AG5(2.697,-15.848) AG6(3.347,-15.848) AG7(3.997,-15.848) AG8(4.647,-15.848) AG9(5.105,-15.386) AG10(5.562,-15.848) AG24(14.994,-15.48) AG26(15.921,-15.48) AG34(20.68,-15.414) AH4(1.625,-16.213) AH9(5.105,-16.31) AH24(14.994,-16.391) AH25(15.457,-15.935) AH26(15.921,-16.391) AH27(16.384,-15.935) AH28(17.034,-15.935) AH29(17.684,-15.935) AH30(18.334,-15.935) AH31(18.984,-15.935) AH32(19.634,-15.935) AH33(20.355,-16.022) AH35(21.56,-16.022) AJ4(1.95,-16.776) AJ5(2.697,-16.772) AJ6(3.347,-16.772) AJ7(3.997,-16.772) AJ8(4.647,-16.772) AJ10(5.562,-16.772) AJ25(15.457,-16.847) AJ27(16.384,-16.847) AJ28(17.034,-16.847) AJ29(17.684,-16.847) AJ30(18.334,-16.847) AJ31(18.984,-16.847) AJ32(19.634,-16.847) AJ34(20.68,-16.63) AK3(0.981,-17.433) AK4(1.99,-17.433) AK9(5.105,-17.234) AK24(14.994,-17.302) AK26(15.921,-17.302) AK33(20.355,-17.281) AK34(21.005,-17.281) AL4(1.95,-18.091) AL5(2.697,-17.696) AL6(3.347,-17.696) AL7(3.997,-17.696) AL8(4.647,-17.696) AL9(5.105,-18.158) AL10(5.562,-17.696) AL24(14.994,-18.214) AL25(15.457,-17.758) AL26(15.921,-18.214) AL27(16.384,-17.758) AL28(17.034,-17.758) AL29(17.684,-17.758) AL30(18.334,-17.758) AL31(18.984,-17.758) AL32(19.634,-17.758) AL34(20.68,-17.932) AM4(1.625,-18.654) AM5(2.697,-18.62) AM6(3.347,-18.62) AM7(3.997,-18.62) AM8(4.647,-18.62) AM10(5.562,-18.62) AM25(15.457,-18.669) AM27(16.384,-18.669) AM28(17.034,-18.669) AM29(17.684,-18.669) AM30(18.334,-18.669) AM31(18.984,-18.669) AM32(19.634,-18.669) AM33(20.355,-18.539) AM35(21.56,-18.539) AN4(1.95,-19.217) AN5(2.697,-19.544) AN6(3.347,-19.544) AN7(3.997,-19.544) AN8(4.647,-19.544) AN9(5.105,-19.081) AN10(5.562,-19.544) AN24(14.994,-19.125) AN25(15.457,-19.581) AN26(15.921,-19.125) AN27(16.384,-19.581) AN28(17.034,-19.581) AN29(17.684,-19.581) AN30(18.334,-19.581) AN31(18.984,-19.581) AN32(19.634,-19.581) AN34(20.68,-19.147) AP3(0.981,-19.874) AP4(1.99,-19.874) AP9(5.105,-20.005) AP24(14.994,-20.037) AP26(15.921,-20.037) AP33(20.355,-19.798) AP34(21.005,-19.798) AR4(1.95,-20.532) AR5(2.697,-20.467) AR6(3.347,-20.467) AR7(3.997,-20.467) AR8(4.647,-20.467) AR10(5.562,-20.467) AR25(15.457,-20.492) AR27(16.384,-20.492) AR28(17.034,-20.492) AR29(17.684,-20.492) AR30(18.334,-20.492) AR31(18.984,-20.492) AR32(19.634,-20.492) AR34(20.68,-20.449) AT4(1.625,-21.094) AT9(5.105,-20.929) AT24(14.994,-20.948) AT26(15.921,-20.948) AT33(20.355,-21.056) AT35(21.56,-21.056) AU4(1.95,-21.658) AU5(2.697,-21.391) AU6(3.347,-21.391) AU7(3.997,-21.391) AU8(4.647,-21.391) AU9(5.105,-21.853) AU10(5.562,-21.391) AU24(14.994,-21.859) AU25(15.457,-21.404) AU26(15.921,-21.859) AU27(16.384,-21.404) AU28(17.034,-21.404) AU29(17.684,-21.404) AU30(18.334,-21.404) AU31(18.984,-21.404) AU32(19.634,-21.404) AU34(20.68,-21.664) AV3(0.981,-22.315) AV4(1.99,-22.315) AV5(2.697,-22.315) AV6(3.347,-22.315) AV7(3.997,-22.315) AV8(4.647,-22.315) AV10(5.562,-22.315) AV25(15.457,-22.315) AV27(16.384,-22.315) AV28(17.034,-22.315) AV29(17.684,-22.315) AV30(18.334,-22.315) AV31(18.984,-22.315) AV32(19.634,-22.315) AV33(20.355,-22.315) AV34(21.005,-22.315) AW4(1.95,-22.972) AW5(2.697,-23.239) AW6(3.347,-23.239) AW7(3.997,-23.239) AW8(4.647,-23.239) AW9(5.105,-22.777) AW10(5.562,-23.239) AW24(14.994,-22.771) AW25(15.457,-23.226) AW26(15.921,-22.771) AW27(16.384,-23.226) AW28(17.034,-23.226) AW29(17.684,-23.226) AW30(18.334,-23.226) AW31(18.984,-23.226) AW32(19.634,-23.226) AW34(20.68,-22.965) AY4(1.625,-23.535) AY9(5.105,-23.701) AY24(14.994,-23.682) AY26(15.921,-23.682) AY33(20.355,-23.573) AY35(21.56,-23.573) B4(1.8,-0.608) B5(2.449,-0.631) B33(20.216,-0.311) B34(20.711,-0.733) B35(21.352,-0.628) BA4(1.95,-24.098) BA5(2.697,-24.163) BA6(3.347,-24.163) BA7(3.997,-24.163) BA8(4.647,-24.163) BA10(5.562,-24.163) BA25(15.457,-24.138) BA27(16.384,-24.138) BA28(17.034,-24.138) BA29(17.684,-24.138) BA30(18.334,-24.138) BA31(18.984,-24.138) BA32(19.634,-24.138) BA34(20.68,-24.181) BB3(0.981,-24.756) BB4(1.99,-24.756) BB9(5.105,-24.625) BB24(14.994,-24.593) BB26(15.921,-24.593) BB33(20.355,-24.832) BB34(21.005,-24.832) BC4(1.95,-25.413) BC5(2.697,-25.086) BC6(3.347,-25.086) BC7(3.997,-25.086) BC8(4.647,-25.086) BC9(5.105,-25.548) BC10(5.562,-25.086) BC24(14.994,-25.505) BC25(15.457,-25.049) BC26(15.921,-25.505) BC27(16.384,-25.049) BC28(17.034,-25.049) BC29(17.684,-25.049) BC30(18.334,-25.049) BC31(18.984,-25.049) BC32(19.634,-25.049) BC34(20.68,-25.483) BD4(1.625,-25.976) BD5(2.697,-26.01) BD6(3.347,-26.01) BD7(3.997,-26.01) BD8(4.647,-26.01) BD10(5.562,-26.01) BD25(15.457,-25.961) BD27(16.384,-25.961) BD28(17.034,-25.961) BD29(17.684,-25.961) BD30(18.334,-25.961) BD31(18.984,-25.961) BD32(19.634,-25.961) BD33(20.355,-26.09) BD35(21.56,-26.09) BE4(1.95,-26.539) BE5(2.697,-26.934) BE6(3.347,-26.934) BE7(3.997,-26.934) BE8(4.647,-26.934) BE9(5.105,-26.472) BE10(5.562,-26.934) BE24(14.994,-26.416) BE25(15.457,-26.872) BE26(15.921,-26.416) BE27(16.384,-26.872) BE28(17.034,-26.872) BE29(17.684,-26.872) BE30(18.334,-26.872) BE31(18.984,-26.872) BE32(19.634,-26.872) BE34(20.68,-26.698) BF3(0.981,-27.197) BF4(1.99,-27.197) BF9(5.105,-27.396) BF24(14.994,-27.328) BF26(15.921,-27.328) BF33(20.355,-27.349) BF34(21.005,-27.349) BG4(1.95,-27.854) BG5(2.697,-27.858) BG6(3.347,-27.858) BG7(3.997,-27.858) BG8(4.647,-27.858) BG10(5.562,-27.858) BG25(15.457,-27.783) BG27(16.384,-27.783) BG28(17.034,-27.783) BG29(17.684,-27.783) BG30(18.334,-27.783) BG31(18.984,-27.783) BG32(19.634,-27.783) BG34(20.68,-27.999) BH4(1.625,-28.417) BH9(5.105,-28.32) BH24(14.994,-28.239) BH25(15.457,-28.695) BH26(15.921,-28.239) BH27(16.384,-28.695) BH28(17.034,-28.695) BH29(17.684,-28.695) BH30(18.334,-28.695) BH31(18.984,-28.695) BH32(19.634,-28.695) BH33(20.355,-28.608) BH35(21.56,-28.608) BJ4(1.95,-28.98) BJ5(2.697,-28.782) BJ6(3.347,-28.782) BJ7(3.997,-28.782) BJ8(4.647,-28.782) BJ9(5.105,-29.244) BJ10(5.562,-28.782) BJ24(14.994,-29.15) BJ26(15.921,-29.15) BJ34(20.68,-29.215) BK3(0.981,-29.637) BK4(1.99,-29.637) BK5(2.697,-29.705) BK6(3.347,-29.705) BK7(3.997,-29.705) BK8(4.647,-29.705) BK10(5.562,-29.705) BK25(15.457,-29.606) BK27(16.384,-29.606) BK28(17.034,-29.606) BK29(17.684,-29.606) BK30(18.334,-29.606) BK31(18.984,-29.606) BK32(19.634,-29.606) BK33(20.355,-29.866) BK34(21.005,-29.866) BL4(1.95,-30.295) BL5(2.697,-30.629) BL6(3.347,-30.629) BL7(3.997,-30.629) BL8(4.647,-30.629) BL9(5.105,-30.167) BL10(5.562,-30.629) BL24(14.994,-30.062) BL25(15.457,-30.518) BL26(15.921,-30.062) BL27(16.384,-30.518) BL28(17.034,-30.518) BL29(17.684,-30.518) BL30(18.334,-30.518) BL31(18.984,-30.518) BL32(19.634,-30.518) BL34(20.68,-30.517) BM4(1.625,-30.858) BM9(5.105,-31.091) BM24(14.994,-30.973) BM26(15.921,-30.973) BM33(20.355,-31.124) BM35(21.56,-31.124) BN4(1.95,-31.421) BN5(2.697,-31.553) BN6(3.347,-31.553) BN7(3.997,-31.553) BN8(4.647,-31.553) BN10(5.562,-31.553) BN25(15.457,-31.429) BN27(16.384,-31.429) BN28(17.034,-31.429) BN29(17.684,-31.429) BN30(18.334,-31.429) BN31(18.984,-31.429) BN32(19.634,-31.429) BN34(20.68,-31.732) BP3(0.981,-32.078) BP4(1.99,-32.078) BP5(2.697,-32.477) BP6(3.347,-32.477) BP7(3.997,-32.477) BP8(4.647,-32.477) BP9(5.297,-32.477) BP11(6.222,-32.101) BP12(7.062,-32.101) BP14(7.902,-32.101) BP15(8.741,-32.101) BP16(9.581,-32.101) BP18(10.421,-32.101) BP19(11.261,-32.101) BP20(12.101,-32.101) BP22(12.941,-32.101) BP23(13.78,-32.101) BP24(14.62,-32.101) BP25(15.46,-32.101) BP27(16.384,-32.34) BP28(17.034,-32.34) BP29(17.684,-32.34) BP30(18.334,-32.34) BP31(18.984,-32.34) BP32(19.634,-32.34) BP33(20.355,-32.383) BP34(21.005,-32.383) BR4(1.95,-32.736) BR11(6.222,-32.751) BR12(7.062,-32.751) BR14(7.902,-32.751) BR15(8.741,-32.751) BR16(9.581,-32.751) BR18(10.421,-32.751) BR19(11.261,-32.751) BR20(12.101,-32.751) BR22(12.941,-32.751) BR23(13.78,-32.751) BR24(14.62,-32.751) BR25(15.46,-32.751) BR34(20.68,-33.033) BT4(1.625,-33.299) BT5(2.697,-33.4) BT6(3.347,-33.4) BT7(3.997,-33.4) BT8(4.647,-33.4) BT9(5.297,-33.4) BT11(6.222,-33.4) BT12(7.062,-33.4) BT14(7.902,-33.4) BT15(8.741,-33.4) BT16(9.581,-33.4) BT18(10.421,-33.4) BT19(11.261,-33.4) BT20(12.101,-33.4) BT22(12.941,-33.4) BT23(13.78,-33.4) BT24(14.62,-33.4) BT25(15.46,-33.4) BT27(16.384,-33.252) BT28(17.034,-33.252) BT29(17.684,-33.252) BT30(18.334,-33.252) BT31(18.984,-33.252) BT32(19.634,-33.252) BT33(20.355,-33.642) BT35(21.56,-33.642) BU4(1.95,-33.862) BU5(2.697,-34.324) BU6(3.347,-34.324) BU7(3.997,-34.324) BU8(4.647,-34.324) BU9(5.297,-34.324) BU11(6.222,-34.05) BU12(7.062,-34.05) BU14(7.902,-34.05) BU15(8.741,-34.05) BU16(9.581,-34.05) BU18(10.421,-34.05) BU19(11.261,-34.05) BU20(12.101,-34.05) BU22(12.941,-34.05) BU23(13.78,-34.05) BU24(14.62,-34.05) BU25(15.46,-34.05) BU27(16.384,-34.163) BU28(17.034,-34.163) BU29(17.684,-34.163) BU30(18.334,-34.163) BU31(18.984,-34.163) BU32(19.634,-34.163) BU34(20.68,-34.249) BV3(0.981,-34.519) BV4(1.99,-34.519) BV11(6.222,-34.7) BV12(7.062,-34.7) BV14(7.902,-34.7) BV15(8.741,-34.7) BV16(9.581,-34.7) BV18(10.421,-34.7) BV19(11.261,-34.7) BV20(12.101,-34.7) BV22(12.941,-34.7) BV23(13.78,-34.7) BV24(14.62,-34.7) BV25(15.46,-34.7) BV27(16.384,-35.075) BV28(17.034,-35.075) BV29(17.684,-35.075) BV30(18.334,-35.075) BV31(18.984,-35.075) BV32(19.634,-35.075) BV33(20.355,-34.9) BV34(21.005,-34.9) BW4(1.95,-35.176) BW5(2.697,-35.248) BW6(3.347,-35.248) BW7(3.997,-35.248) BW8(4.647,-35.248) BW9(5.297,-35.248) BW11(6.222,-35.35) BW12(7.062,-35.35) BW14(7.902,-35.35) BW15(8.741,-35.35) BW16(9.581,-35.35) BW18(10.421,-35.35) BW19(11.261,-35.35) BW20(12.101,-35.35) BW22(12.941,-35.35) BW23(13.78,-35.35) BW24(14.62,-35.35) BW25(15.46,-35.35) BW34(20.68,-35.551) BY4(1.625,-35.739) BY5(2.697,-36.172) BY6(3.347,-36.172) BY7(3.997,-36.172) BY8(4.647,-36.172) BY9(5.297,-36.172) BY11(6.222,-36) BY12(7.062,-36) BY14(7.902,-36) BY15(8.741,-36) BY16(9.581,-36) BY18(10.421,-36) BY19(11.261,-36) BY20(12.101,-36) BY22(12.941,-36) BY23(13.78,-36) BY24(14.62,-36) BY25(15.46,-36) BY27(16.384,-35.986) BY28(17.034,-35.986) BY29(17.684,-35.986) BY30(18.334,-35.986) BY31(18.984,-35.986) BY32(19.634,-35.986) BY33(20.355,-36.158) BY35(21.56,-36.158) C3(1.256,-1.256) C4(2.102,-1.183) C9(5.01,-1.07) C21(12.59,-1.07) C25(15.107,-1.07) C29(17.624,-1.07) C33(20.141,-1.07) C34(20.711,-1.383) C35(21.352,-1.278) C36(22.002,-1.278) CA4(1.95,-36.302) CA11(6.222,-36.65) CA12(7.062,-36.65) CA14(7.902,-36.65) CA15(8.741,-36.65) CA16(9.581,-36.65) CA18(10.421,-36.65) CA19(11.261,-36.65) CA20(12.101,-36.65) CA22(12.941,-36.65) CA23(13.78,-36.65) CA24(14.62,-36.65) CA25(15.46,-36.65) CA27(16.384,-36.897) CA28(17.034,-36.897) CA29(17.684,-36.897) CA30(18.334,-36.897) CA31(18.984,-36.897) CA32(19.634,-36.897) CA34(20.68,-36.766) CB3(0.981,-36.96) CB4(1.99,-36.96) CB5(2.697,-37.096) CB6(3.347,-37.096) CB7(3.997,-37.096) CB8(4.647,-37.096) CB9(5.297,-37.096) CB11(6.222,-37.3) CB12(7.062,-37.3) CB14(7.902,-37.3) CB15(8.741,-37.3) CB16(9.581,-37.3) CB18(10.421,-37.3) CB19(11.261,-37.3) CB20(12.101,-37.3) CB22(12.941,-37.3) CB23(13.78,-37.3) CB24(14.62,-37.3) CB25(15.46,-37.3) CB33(20.355,-37.417) CB34(21.005,-37.417) CC4(1.95,-37.617) CC5(2.697,-38.019) CC6(3.347,-38.019) CC7(3.997,-38.019) CC8(4.647,-38.019) CC9(5.297,-38.019) CC11(6.222,-37.95) CC12(7.062,-37.95) CC14(7.902,-37.95) CC15(8.741,-37.95) CC16(9.581,-37.95) CC18(10.421,-37.95) CC19(11.261,-37.95) CC20(12.101,-37.95) CC22(12.941,-37.95) CC23(13.78,-37.95) CC24(14.62,-37.95) CC25(15.46,-37.95) CC27(16.384,-37.809) CC28(17.034,-37.809) CC29(17.684,-37.809) CC30(18.334,-37.809) CC31(18.984,-37.809) CC32(19.634,-37.809) CC34(20.68,-38.067) CD4(1.625,-38.18) CD11(6.222,-38.6) CD12(7.062,-38.6) CD14(7.902,-38.6) CD15(8.741,-38.6) CD16(9.581,-38.6) CD18(10.421,-38.6) CD19(11.261,-38.6) CD20(12.101,-38.6) CD22(12.941,-38.6) CD23(13.78,-38.6) CD24(14.62,-38.6) CD25(15.46,-38.6) CE4(1.95,-38.743) CE5(2.697,-38.943) CE6(3.347,-38.943) CE7(3.997,-38.943) CE8(4.647,-38.943) CE9(5.297,-38.943) CE27(16.384,-38.72) CE28(17.034,-38.72) CE29(17.684,-38.72) CE30(18.334,-38.72) CE31(18.984,-38.72) CE32(19.634,-38.72) CE33(20.355,-38.675) CE35(21.56,-38.675) CF3(0.981,-39.4) CF4(1.99,-39.4) CF11(5.945,-39.43) CF12(6.947,-39.43) CF14(7.985,-39.43) CF15(9.023,-39.43) CF17(10.061,-39.43) CF19(11.099,-39.43) CF20(12.137,-39.43) CF22(13.175,-39.43) CF23(14.213,-39.43) CF25(15.251,-39.43) CF27(16.384,-39.632) CF28(17.034,-39.632) CF29(17.684,-39.632) CF30(18.334,-39.632) CF31(18.984,-39.632) CF32(19.634,-39.632) CF34(20.68,-39.283) CG4(1.95,-40.058) CG5(2.697,-39.867) CG6(3.347,-39.867) CG7(3.997,-39.867) CG8(4.647,-39.867) CG9(5.297,-39.867) CG11(5.945,-40.08) CG12(6.947,-40.08) CG14(7.985,-40.08) CG15(9.023,-40.08) CG17(10.061,-40.08) CG19(11.099,-40.08) CG20(12.137,-40.08) CG22(13.175,-40.08) CG23(14.213,-40.08) CG25(15.251,-40.08) CG33(20.355,-39.934) CG34(21.005,-39.934) CH4(1.625,-40.621) CH5(2.697,-40.791) CH6(3.347,-40.791) CH7(3.997,-40.791) CH8(4.647,-40.791) CH9(5.297,-40.791) CH11(5.945,-40.73) CH12(6.947,-40.73) CH14(7.985,-40.73) CH15(9.023,-40.73) CH17(10.061,-40.73) CH19(11.099,-40.73) CH20(12.137,-40.73) CH22(13.175,-40.73) CH23(14.213,-40.73) CH25(15.251,-40.73) CH27(16.384,-40.543) CH28(17.034,-40.543) CH29(17.684,-40.543) CH30(18.334,-40.543) CH31(18.984,-40.543) CH32(19.634,-40.543) CH34(20.68,-40.585) CJ4(1.95,-41.184) CJ11(5.945,-41.38) CJ12(6.947,-41.38) CJ14(7.985,-41.38) CJ15(9.023,-41.38) CJ17(10.061,-41.38) CJ19(11.099,-41.38) CJ20(12.137,-41.38) CJ22(13.175,-41.38) CJ23(14.213,-41.38) CJ25(15.251,-41.38) CJ27(16.384,-41.454) CJ28(17.034,-41.454) CJ29(17.684,-41.454) CJ30(18.334,-41.454) CJ31(18.984,-41.454) CJ32(19.634,-41.454) CJ33(20.355,-41.147) CJ35(21.56,-41.192) CK1(0,-41.876) CK3(1.42,-42.144) CK4(1.99,-41.833) CK5(2.697,-41.715) CK6(3.347,-41.715) CK7(3.997,-41.715) CK8(4.647,-41.715) CK9(5.297,-41.715) CK11(5.945,-42.03) CK12(6.947,-42.03) CK14(7.985,-42.03) CK15(9.023,-42.03) CK17(10.061,-42.03) CK19(11.099,-42.03) CK20(12.137,-42.03) CK22(13.175,-42.03) CK23(14.213,-42.03) CK25(15.251,-42.03) CK33(20.465,-41.819) CK34(21.09,-41.641) CK36(21.927,-41.777) CK37(22.63,-41.689) CL2(0.419,-42.373) CL35(21.376,-42.225) CL36(22.263,-42.334) CM1(0,-42.87) CM3(0.982,-42.698) CM4(1.819,-42.658) CM5(2.533,-42.68) CM6(3.183,-42.685) CM7(3.75,-43.005) CM8(4.316,-42.685) CM9(5.01,-42.68) CM10(5.705,-42.685) CM11(6.271,-43.005) CM12(6.837,-42.685) CM13(7.532,-42.68) CM14(8.227,-42.685) CM15(8.793,-43.005) CM16(9.359,-42.685) CM17(10.054,-42.68) CM18(10.749,-42.685) CM19(11.315,-43.005) CM20(11.881,-42.685) CM21(12.576,-42.68) CM22(13.271,-42.685) CM23(13.837,-43.005) CM24(14.403,-42.685) CM25(15.098,-42.68) CM26(15.792,-42.685) CM27(16.359,-43.005) CM28(16.925,-42.685) CM29(17.619,-42.68) CM30(18.269,-42.68) CM31(18.846,-43.129) CM32(19.491,-42.68) CM33(20.141,-42.68) CM34(20.786,-42.601) CM35(21.762,-42.748) CM37(22.63,-42.87) CN2(0.563,-43.195) CN3(1.308,-43.261) CN4(1.957,-43.293) CN5(2.521,-43.682) CN9(5.01,-43.56) CN13(7.532,-43.56) CN17(10.054,-43.56) CN21(12.576,-43.56) CN25(15.098,-43.56) CN29(17.619,-43.56) CN33(20.141,-43.56) CN34(20.711,-43.247) CN35(21.352,-43.352) CN36(22.002,-43.352) CP3(1.278,-44.002) CP4(1.925,-43.942) CP5(2.373,-44.413) CP33(20.186,-44.283) CP34(20.711,-43.897) CP35(21.352,-44.002) CR4(1.76,-44.63) CR6(3.083,-44.63) CR32(19.636,-44.63) CR34(20.87,-44.63) D2(0.675,-1.736) D4(1.721,-1.71) D5(2.533,-1.95) D6(3.183,-1.944) D7(3.75,-1.625) D8(4.316,-1.944) D9(5.01,-1.81) D21(12.59,-1.72) D22(13.198,-1.95) D23(13.849,-1.625) D24(14.499,-1.95) D25(15.107,-1.72) D26(15.715,-1.95) D27(16.366,-1.625) D28(17.016,-1.95) D30(18.232,-1.95) D31(18.883,-1.625) D32(19.533,-1.95) D34(20.711,-2.033) D35(21.762,-1.882) D37(22.63,-1.76) E1(0,-2.219) E3(1.307,-2.226) E4(1.95,-2.32) E9(5.105,-2.453) E23(13.936,-2.275) E27(16.366,-2.275) E29(17.624,-2.275) E31(18.883,-2.275) E33(20.096,-2.275) E35(21.376,-2.405) E36(22.263,-2.296) F2(0.314,-2.788) F3(0.981,-2.788) F4(1.625,-2.883) F5(2.697,-2.915) F6(3.347,-2.915) F7(3.997,-2.915) F8(4.647,-2.915) F21(12.464,-2.6) F22(13.373,-2.6) F24(14.499,-2.6) F25(15.408,-2.6) F33(20.465,-2.811) F34(21.09,-2.989) F36(21.927,-2.852) F37(22.63,-2.941) G1(0,-3.471) G4(1.95,-3.446) G9(5.105,-3.377) G21(12.464,-3.25) G22(13.373,-3.25) G24(14.499,-3.25) G25(15.408,-3.25) G27(16.384,-3.176) G28(17.034,-3.176) G29(17.684,-3.176) G30(18.334,-3.176) G31(18.984,-3.176) G32(19.634,-3.176) G33(20.355,-3.482) G35(21.56,-3.437) H4(1.625,-4.009) H5(2.697,-3.839) H6(3.347,-3.839) H7(3.997,-3.839) H8(4.647,-3.839) H9(5.105,-4.301) H21(12.464,-3.9) H22(13.373,-3.9) H24(14.499,-3.9) H25(15.408,-3.9) H27(16.384,-4.087) H28(17.034,-4.087) H29(17.684,-4.087) H30(18.334,-4.087) H31(18.984,-4.087) H32(19.634,-4.087) H34(20.68,-4.045) J4(1.95,-4.572) J5(2.697,-4.763) J6(3.347,-4.763) J7(3.997,-4.763) J8(4.647,-4.763) J21(12.464,-4.55) J22(13.373,-4.55) J24(14.499,-4.55) J25(15.408,-4.55) J33(20.355,-4.696) J34(21.005,-4.696) K3(0.981,-5.229) K4(1.99,-5.229) K9(5.105,-5.225) K11(5.993,-5.2) K12(6.935,-5.2) K14(7.877,-5.2) K15(8.819,-5.2) K17(9.76,-5.2) K18(10.702,-5.2) K20(11.644,-5.2) K21(12.464,-5.2) K22(13.373,-5.2) K24(14.499,-5.2) K25(15.408,-5.2) K27(16.384,-4.998) K28(17.034,-4.998) K29(17.684,-4.998) K30(18.334,-4.998) K31(18.984,-4.998) K32(19.634,-4.998) K34(20.68,-5.346) L4(1.95,-5.887) L5(2.697,-5.687) L6(3.347,-5.687) L7(3.997,-5.687) L8(4.647,-5.687) L10(5.562,-5.687) L25(15.457,-5.91) L27(16.384,-5.91) L28(17.034,-5.91) L29(17.684,-5.91) L30(18.334,-5.91) L31(18.984,-5.91) L32(19.634,-5.91) L33(20.355,-5.955) L35(21.56,-5.955) M4(1.625,-6.45) M9(5.105,-6.148) M24(14.994,-6.365) M26(15.921,-6.365) N4(1.95,-7.013) N5(2.697,-6.61) N6(3.347,-6.61) N7(3.997,-6.61) N8(4.647,-6.61) N9(5.105,-7.072) N10(5.562,-6.61) N25(15.457,-6.821) N27(16.384,-6.821) N28(17.034,-6.821) N29(17.684,-6.821) N30(18.334,-6.821) N31(18.984,-6.821) N32(19.634,-6.821) N34(20.68,-6.562) P3(0.981,-7.67) P4(1.99,-7.67) P5(2.697,-7.534) P6(3.347,-7.534) P7(3.997,-7.534) P8(4.647,-7.534) P10(5.562,-7.534) P24(14.994,-7.277) P26(15.921,-7.277) P33(20.355,-7.213) P34(21.005,-7.213) R4(1.95,-8.327) R9(5.105,-7.996) R24(14.994,-8.188) R25(15.457,-7.733) R26(15.921,-8.188) R27(16.384,-7.733) R28(17.034,-7.733) R29(17.684,-7.733) R30(18.334,-7.733) R31(18.984,-7.733) R32(19.634,-7.733) R34(20.68,-7.864) T4(1.625,-8.891) T5(2.697,-8.458) T6(3.347,-8.458) T7(3.997,-8.458) T8(4.647,-8.458) T9(5.105,-8.92) T10(5.562,-8.458) T25(15.457,-8.644) T27(16.384,-8.644) T28(17.034,-8.644) T29(17.684,-8.644) T30(18.334,-8.644) T31(18.984,-8.644) T32(19.634,-8.644) T33(20.355,-8.471) T35(21.56,-8.471) U4(1.95,-9.454) U5(2.697,-9.382) U6(3.347,-9.382) U7(3.997,-9.382) U8(4.647,-9.382) U10(5.562,-9.382) U24(14.994,-9.1) U26(15.921,-9.1) U34(20.68,-9.079) V3(0.981,-10.111) V4(1.99,-10.111) V9(5.105,-9.844) V24(14.994,-10.011) V25(15.457,-9.555) V26(15.921,-10.011) V27(16.384,-9.555) V28(17.034,-9.555) V29(17.684,-9.555) V30(18.334,-9.555) V31(18.984,-9.555) V32(19.634,-9.555) V33(20.355,-9.73) V34(21.005,-9.73) W4(1.95,-10.768) W5(2.697,-10.306) W6(3.347,-10.306) W7(3.997,-10.306) W8(4.647,-10.306) W9(5.105,-10.767) W10(5.562,-10.306) W25(15.457,-10.467) W27(16.384,-10.467) W28(17.034,-10.467) W29(17.684,-10.467) W30(18.334,-10.467) W31(18.984,-10.467) W32(19.634,-10.467) W34(20.68,-10.38) Y4(1.625,-11.331) Y5(2.697,-11.229) Y6(3.347,-11.229) Y7(3.997,-11.229) Y8(4.647,-11.229) Y10(5.562,-11.229) Y24(14.994,-10.923) Y25(15.457,-11.378) Y26(15.921,-10.923) Y27(16.384,-11.378) Y28(17.034,-11.378) Y29(17.684,-11.378) Y30(18.334,-11.378) Y31(18.984,-11.378) Y32(19.634,-11.378) Y33(20.355,-10.988) Y35(21.56,-10.988)
  oval 0.254x0.343 smd: A8(4.4,0) A22(13.198,0) A24(14.499,0) A26(15.715,0) A28(17.016,0) A30(18.232,0) B6(3.099,-0.65) B7(3.75,-0.325) B8(4.4,-0.65) B9(5.01,-0.42) B21(12.59,-0.42) B22(13.198,-0.65) B23(13.849,-0.325) B24(14.499,-0.65) B25(15.107,-0.42) B26(15.715,-0.65) B27(16.366,-0.325) B28(17.016,-0.65) B29(17.624,-0.42) B30(18.232,-0.65) B31(18.883,-0.325) B32(19.533,-0.65) C6(3.099,-1.3) C7(3.75,-0.975) C8(4.316,-1.294) C22(13.198,-1.3) C23(13.849,-0.975) C24(14.499,-1.3) C26(15.715,-1.3) C27(16.366,-0.975) C28(17.016,-1.3) C30(18.232,-1.3) C31(18.883,-0.975) C32(19.533,-1.3) CN6(3.099,-43.33) CN7(3.75,-43.655) CN8(4.316,-43.335) CN10(5.705,-43.335) CN11(6.271,-43.655) CN12(6.837,-43.335) CN14(8.227,-43.335) CN15(8.793,-43.655) CN16(9.359,-43.335) CN18(10.749,-43.335) CN19(11.315,-43.655) CN20(11.881,-43.335) CN22(13.271,-43.335) CN23(13.837,-43.655) CN24(14.403,-43.335) CN26(15.792,-43.335) CN27(16.359,-43.655) CN28(16.925,-43.335) CN30(18.227,-43.329) CN31(18.919,-43.776) CN32(19.534,-43.329) CP6(3.099,-43.98) CP7(3.75,-44.305) CP8(4.4,-43.98) CP9(5.01,-44.21) CP10(5.621,-43.98) CP11(6.271,-44.305) CP12(6.922,-43.98) CP13(7.532,-44.21) CP14(8.142,-43.98) CP15(8.793,-44.305) CP16(9.444,-43.98) CP17(10.054,-44.21) CP18(10.664,-43.98) CP19(11.315,-44.305) CP20(11.965,-43.98) CP21(12.576,-44.21) CP22(13.186,-43.98) CP23(13.837,-44.305) CP24(14.487,-43.98) CP25(15.098,-44.21) CP26(15.708,-43.98) CP27(16.359,-44.305) CP28(17.009,-43.98) CP29(17.619,-44.21) CP30(18.298,-43.984) CP31(18.919,-44.505) CP32(19.611,-43.98) CR8(4.4,-44.63) CR10(5.621,-44.63) CR12(6.922,-44.63) CR14(8.142,-44.63) CR16(9.444,-44.63) CR18(10.664,-44.63) CR20(11.965,-44.63) CR22(13.186,-44.63) CR24(14.487,-44.63) CR26(15.708,-44.63) CR28(17.009,-44.63) CR30(18.227,-44.63)
  round 0.406 smd: A11(5.993,0) A12(6.935,0) A14(7.877,0) A15(8.819,0) A17(9.76,0) A18(10.702,0) A20(11.644,0) B11(5.993,-0.65) B12(6.935,-0.65) B14(7.877,-0.65) B15(8.819,-0.65) B17(9.76,-0.65) B18(10.702,-0.65) B20(11.644,-0.65) C11(5.993,-1.3) C12(6.935,-1.3) C14(7.877,-1.3) C15(8.819,-1.3) C17(9.76,-1.3) C18(10.702,-1.3) C20(11.644,-1.3) D11(5.993,-1.95) D12(6.935,-1.95) D14(7.877,-1.95) D15(8.819,-1.95) D17(9.76,-1.95) D18(10.702,-1.95) D20(11.644,-1.95) F11(5.993,-2.6) F12(6.935,-2.6) F14(7.877,-2.6) F15(8.819,-2.6) F17(9.76,-2.6) F18(10.702,-2.6) F20(11.644,-2.6) G11(5.993,-3.25) G12(6.935,-3.25) G14(7.877,-3.25) G15(8.819,-3.25) G17(9.76,-3.25) G18(10.702,-3.25) G20(11.644,-3.25) H11(5.993,-3.9) H12(6.935,-3.9) H14(7.877,-3.9) H15(8.819,-3.9) H17(9.76,-3.9) H18(10.702,-3.9) H20(11.644,-3.9) J11(5.993,-4.55) J12(6.935,-4.55) J14(7.877,-4.55) J15(8.819,-4.55) J17(9.76,-4.55) J18(10.702,-4.55) J20(11.644,-4.55)
  oval 0.343x0.254 smd: AA1(0,-11.894) AA2(0.65,-11.894) AA3(1.3,-11.894) AA35(21.33,-11.596) AA36(21.98,-11.596) AA37(22.63,-11.596) AB2(0.325,-12.552) AB35(21.655,-12.247) AB36(22.305,-12.247) AC1(0,-13.209) AC2(0.65,-13.209) AC3(1.3,-13.209) AC35(21.33,-12.898) AC36(21.98,-12.898) AC37(22.63,-12.898) AD3(0.975,-13.772) AD36(22.21,-13.505) AE1(0,-14.335) AE2(0.65,-14.335) AE3(1.3,-14.335) AE35(21.33,-14.113) AE36(21.98,-14.113) AE37(22.63,-14.113) AF2(0.325,-14.993) AF35(21.655,-14.764) AF36(22.305,-14.764) AG1(0,-15.65) AG2(0.65,-15.65) AG3(1.3,-15.65) AG35(21.33,-15.414) AG36(21.98,-15.414) AG37(22.63,-15.414) AH3(0.975,-16.213) AH36(22.21,-16.022) AJ1(0,-16.776) AJ2(0.65,-16.776) AJ3(1.3,-16.776) AJ35(21.33,-16.63) AJ36(21.98,-16.63) AJ37(22.63,-16.63) AK2(0.325,-17.433) AK35(21.655,-17.281) AK36(22.305,-17.281) AL1(0,-18.091) AL2(0.65,-18.091) AL3(1.3,-18.091) AL35(21.33,-17.932) AL36(21.98,-17.932) AL37(22.63,-17.932) AM3(0.975,-18.654) AM36(22.21,-18.539) AN1(0,-19.217) AN2(0.65,-19.217) AN3(1.3,-19.217) AN35(21.33,-19.147) AN36(21.98,-19.147) AN37(22.63,-19.147) AP2(0.325,-19.874) AP35(21.655,-19.798) AP36(22.305,-19.798) AR1(0,-20.532) AR2(0.65,-20.532) AR3(1.3,-20.532) AR35(21.33,-20.449) AR36(21.98,-20.449) AR37(22.63,-20.449) AT3(0.975,-21.094) AT36(22.21,-21.056) AU1(0,-21.658) AU2(0.65,-21.658) AU3(1.3,-21.658) AU35(21.33,-21.664) AU36(21.98,-21.664) AU37(22.63,-21.664) AV2(0.325,-22.315) AV35(21.655,-22.315) AV36(22.305,-22.315) AW1(0,-22.972) AW2(0.65,-22.972) AW3(1.3,-22.972) AW35(21.33,-22.965) AW36(21.98,-22.965) AW37(22.63,-22.965) AY3(0.975,-23.535) AY36(22.21,-23.573) BA1(0,-24.098) BA2(0.65,-24.098) BA3(1.3,-24.098) BA35(21.33,-24.181) BA36(21.98,-24.181) BA37(22.63,-24.181) BB2(0.325,-24.756) BB35(21.655,-24.832) BB36(22.305,-24.832) BC1(0,-25.413) BC2(0.65,-25.413) BC3(1.3,-25.413) BC35(21.33,-25.483) BC36(21.98,-25.483) BC37(22.63,-25.483) BD3(0.975,-25.976) BD36(22.21,-26.09) BE1(0,-26.539) BE2(0.65,-26.539) BE3(1.3,-26.539) BE35(21.33,-26.698) BE36(21.98,-26.698) BE37(22.63,-26.698) BF2(0.325,-27.197) BF35(21.655,-27.349) BF36(22.305,-27.349) BG1(0,-27.854) BG2(0.65,-27.854) BG3(1.3,-27.854) BG35(21.33,-27.999) BG36(21.98,-27.999) BG37(22.63,-27.999) BH3(0.975,-28.417) BH36(22.21,-28.608) BJ1(0,-28.98) BJ2(0.65,-28.98) BJ3(1.3,-28.98) BJ35(21.33,-29.215) BJ36(21.98,-29.215) BJ37(22.63,-29.215) BK2(0.325,-29.637) BK35(21.655,-29.866) BK36(22.305,-29.866) BL1(0,-30.295) BL2(0.65,-30.295) BL3(1.3,-30.295) BL35(21.33,-30.517) BL36(21.98,-30.517) BL37(22.63,-30.517) BM3(0.975,-30.858) BM36(22.21,-31.124) BN1(0,-31.421) BN2(0.65,-31.421) BN3(1.3,-31.421) BN35(21.33,-31.732) BN36(21.98,-31.732) BN37(22.63,-31.732) BP2(0.325,-32.078) BP35(21.655,-32.383) BP36(22.305,-32.383) BR1(0,-32.736) BR2(0.65,-32.736) BR3(1.3,-32.736) BR35(21.33,-33.033) BR36(21.98,-33.033) BR37(22.63,-33.033) BT3(0.975,-33.299) BT36(22.21,-33.642) BU1(0,-33.862) BU2(0.65,-33.862) BU3(1.3,-33.862) BU35(21.33,-34.249) BU36(21.98,-34.249) BU37(22.63,-34.249) BV2(0.325,-34.519) BV35(21.655,-34.9) BV36(22.305,-34.9) BW1(0,-35.176) BW2(0.65,-35.176) BW3(1.3,-35.176) BW35(21.33,-35.551) BW36(21.98,-35.551) BW37(22.63,-35.551) BY3(0.975,-35.739) BY36(22.21,-36.158) CA1(0,-36.302) CA2(0.65,-36.302) CA3(1.3,-36.302) CA35(21.33,-36.766) CA36(21.98,-36.766) CA37(22.63,-36.766) CB2(0.325,-36.96) CB35(21.655,-37.417) CB36(22.305,-37.417) CC1(0,-37.617) CC2(0.65,-37.617) CC3(1.3,-37.617) CC35(21.33,-38.067) CC36(21.98,-38.067) CC37(22.63,-38.067) CD3(0.975,-38.18) CE1(0,-38.743) CE2(0.65,-38.743) CE3(1.3,-38.743) CE36(22.21,-38.675) CF2(0.325,-39.4) CF35(21.33,-39.283) CF36(21.98,-39.283) CF37(22.63,-39.283) CG1(0,-40.058) CG2(0.65,-40.058) CG3(1.3,-40.058) CG35(21.655,-39.934) CG36(22.305,-39.934) CH3(0.975,-40.621) CH35(21.33,-40.585) CH36(21.98,-40.585) CH37(22.63,-40.585) CJ1(0,-41.184) CJ2(0.65,-41.184) CJ3(1.3,-41.184) CJ36(22.21,-41.192) CK2(0.83,-41.87) G2(0.65,-3.446) G3(1.3,-3.446) G36(22.21,-3.437) H3(0.975,-4.009) H35(21.33,-4.045) H36(21.98,-4.045) H37(22.63,-4.045) J1(0,-4.572) J2(0.65,-4.572) J3(1.3,-4.572) J35(21.655,-4.696) J36(22.305,-4.696) K2(0.325,-5.229) K35(21.33,-5.346) K36(21.98,-5.346) K37(22.63,-5.346) L1(0,-5.887) L2(0.65,-5.887) L3(1.3,-5.887) L36(22.21,-5.955) M3(0.975,-6.45) N1(0,-7.013) N2(0.65,-7.013) N3(1.3,-7.013) N35(21.33,-6.562) N36(21.98,-6.562) N37(22.63,-6.562) P2(0.325,-7.67) P35(21.655,-7.213) P36(22.305,-7.213) R1(0,-8.327) R2(0.65,-8.327) R3(1.3,-8.327) R35(21.33,-7.864) R36(21.98,-7.864) R37(22.63,-7.864) T3(0.975,-8.891) T36(22.21,-8.471) U1(0,-9.454) U2(0.65,-9.454) U3(1.3,-9.454) U35(21.33,-9.079) U36(21.98,-9.079) U37(22.63,-9.079) V2(0.325,-10.111) V35(21.655,-9.73) V36(22.305,-9.73) W1(0,-10.768) W2(0.65,-10.768) W3(1.3,-10.768) W35(21.33,-10.38) W36(21.98,-10.38) W37(22.63,-10.38) Y3(0.975,-11.331) Y36(22.21,-10.988)
Y_1TJF125BJ1A000A_2P
  rect 0.991x1.803 smd: 1(0,0) 2(2.5,0)
Y_XRCGB24M000F2P51R0_4P
  rect 0.762x0.711 smd: 1(0,0) 2(1.35,0) 3(1.35,1) 4(0,1)
Y_XRCGB25M000F2P34R0_4P
  rect 0.762x0.711 smd: 1(0,0) 2(1.35,0) 3(1.35,1) 4(0,1)
Y_XRCGB27M000F2P18R0_4P
  rect 0.762x0.711 smd: 1(0,0) 2(1.35,0) 3(1.35,1) 4(0,1)
YB8251ST23_TSOT-23-3
  oval 0.787x0.991 smd: 1(0,0) 2(-0.95,-2.6) 3(0.95,-2.6)
YSLC05CH_SOT23-3
  oval 1.016x1.524 smd: 1(0,0) 2(0.965,2.083) 3(-0.965,2.083)
YSUSB2P0-5_SOT-23-6-6
  oval 0.61x0.889 smd: 1(0,0) 2(0.95,0) 3(1.9,0) 4(1.9,2.3) 5(0.95,2.3) 6(0,2.3)

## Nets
1.35V_PWR_EN: PRW1.1 RV201.2 UV23.4
3V_FB: PC312.1 PU301.13
3V_FB_1: PC312.2 PR305.1
3V_SN: PC311.1 PR303.2
5V_3V_EN: PC327.1 PR301.2 PR311.2 PR313.1 PU301.12 PU302.6
5V_FB: PC326.1 PU302.7
5V_FB_1: PC326.2 PR312.1
5V_SN: PC324.1 PR308.2
+0.6V_0.6VS: CD7.1 CD8.1 CD9.1 CD66.1 CD67.1 CD68.1 JDIMM1.258 JDIMM2.258 PJM3.2
+0.6V_B_VREFDQ: CD82.1 RD27.2 UC1.E36
+0.6V_DDR_VREFCA: CD11.2 CD12.2 CD14.2 JDIMM1.164 RD8.1 RD9.1 RD10.2
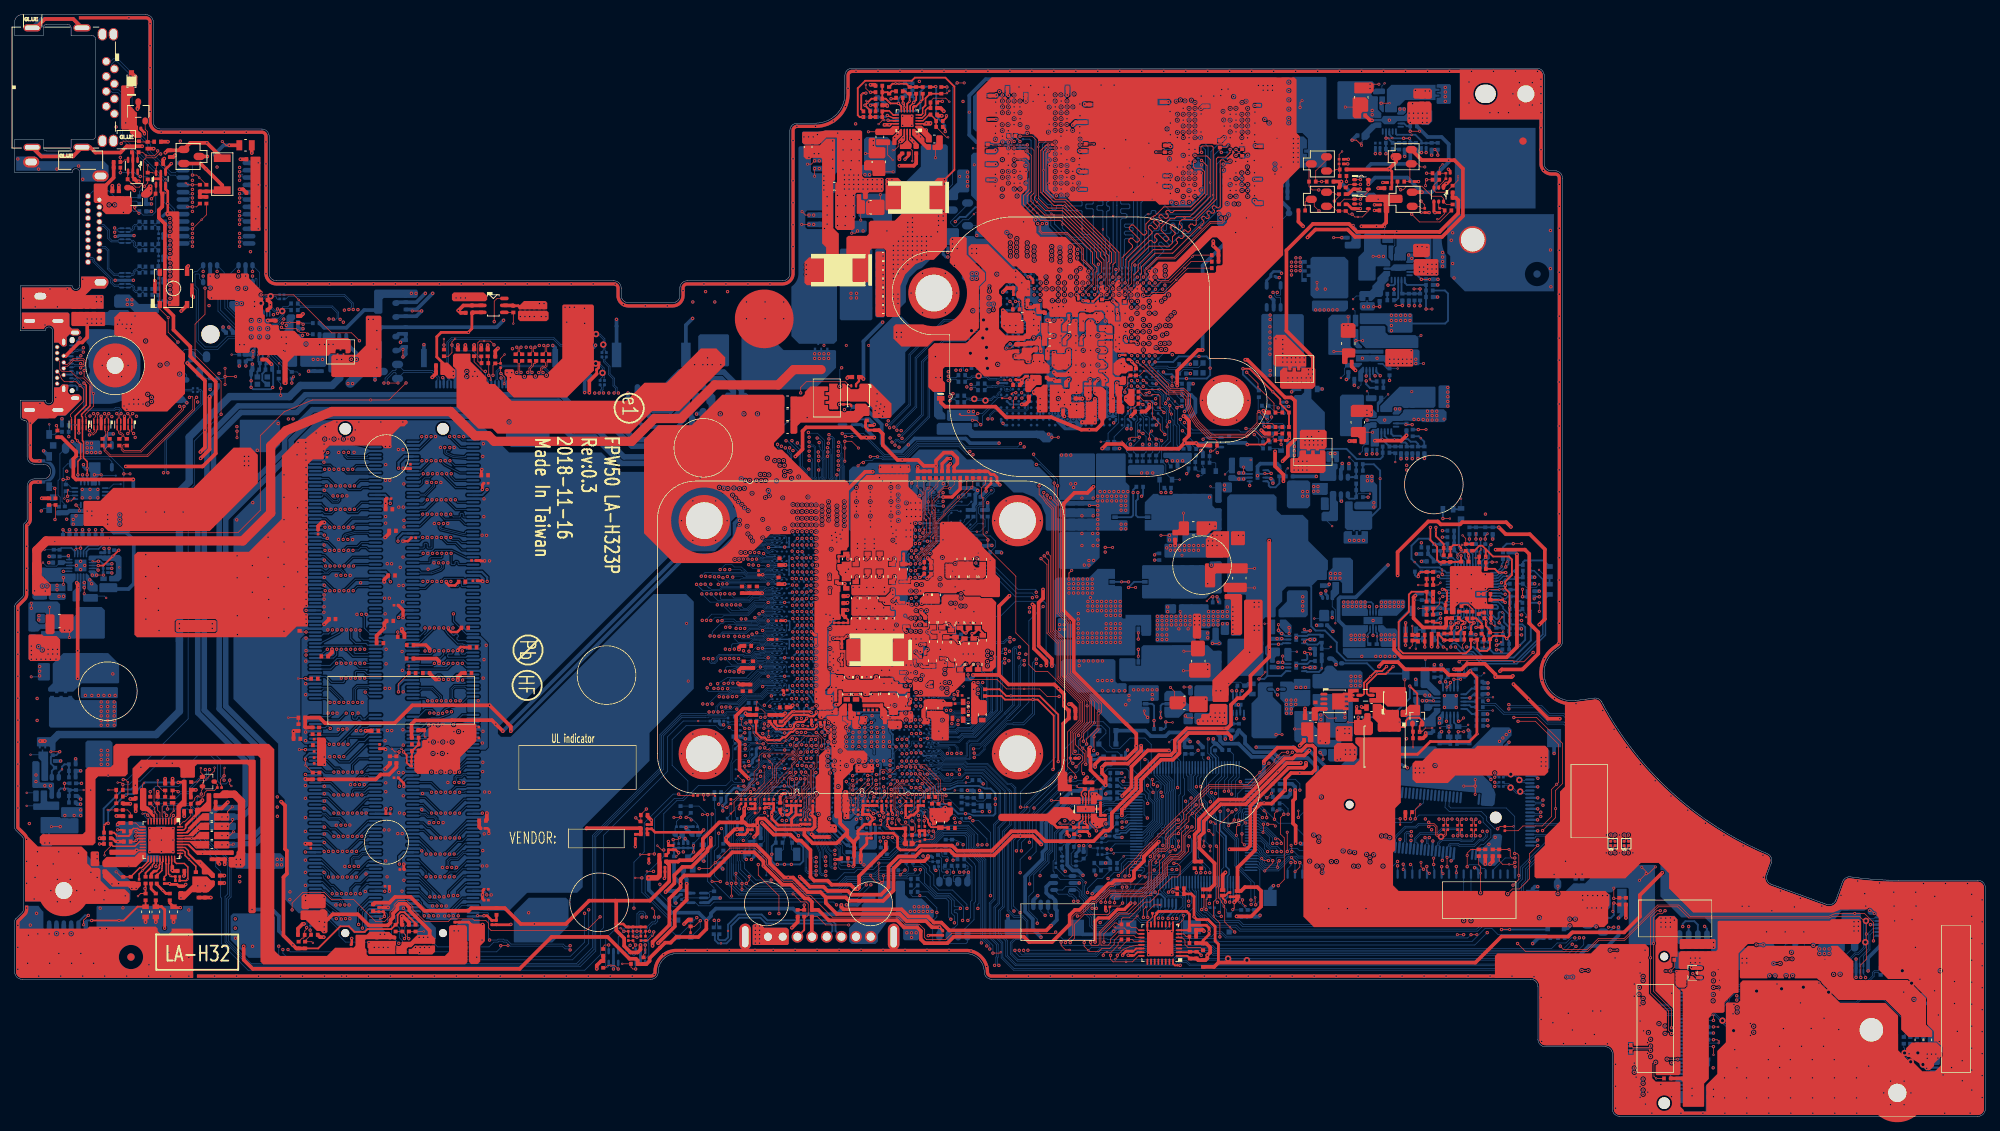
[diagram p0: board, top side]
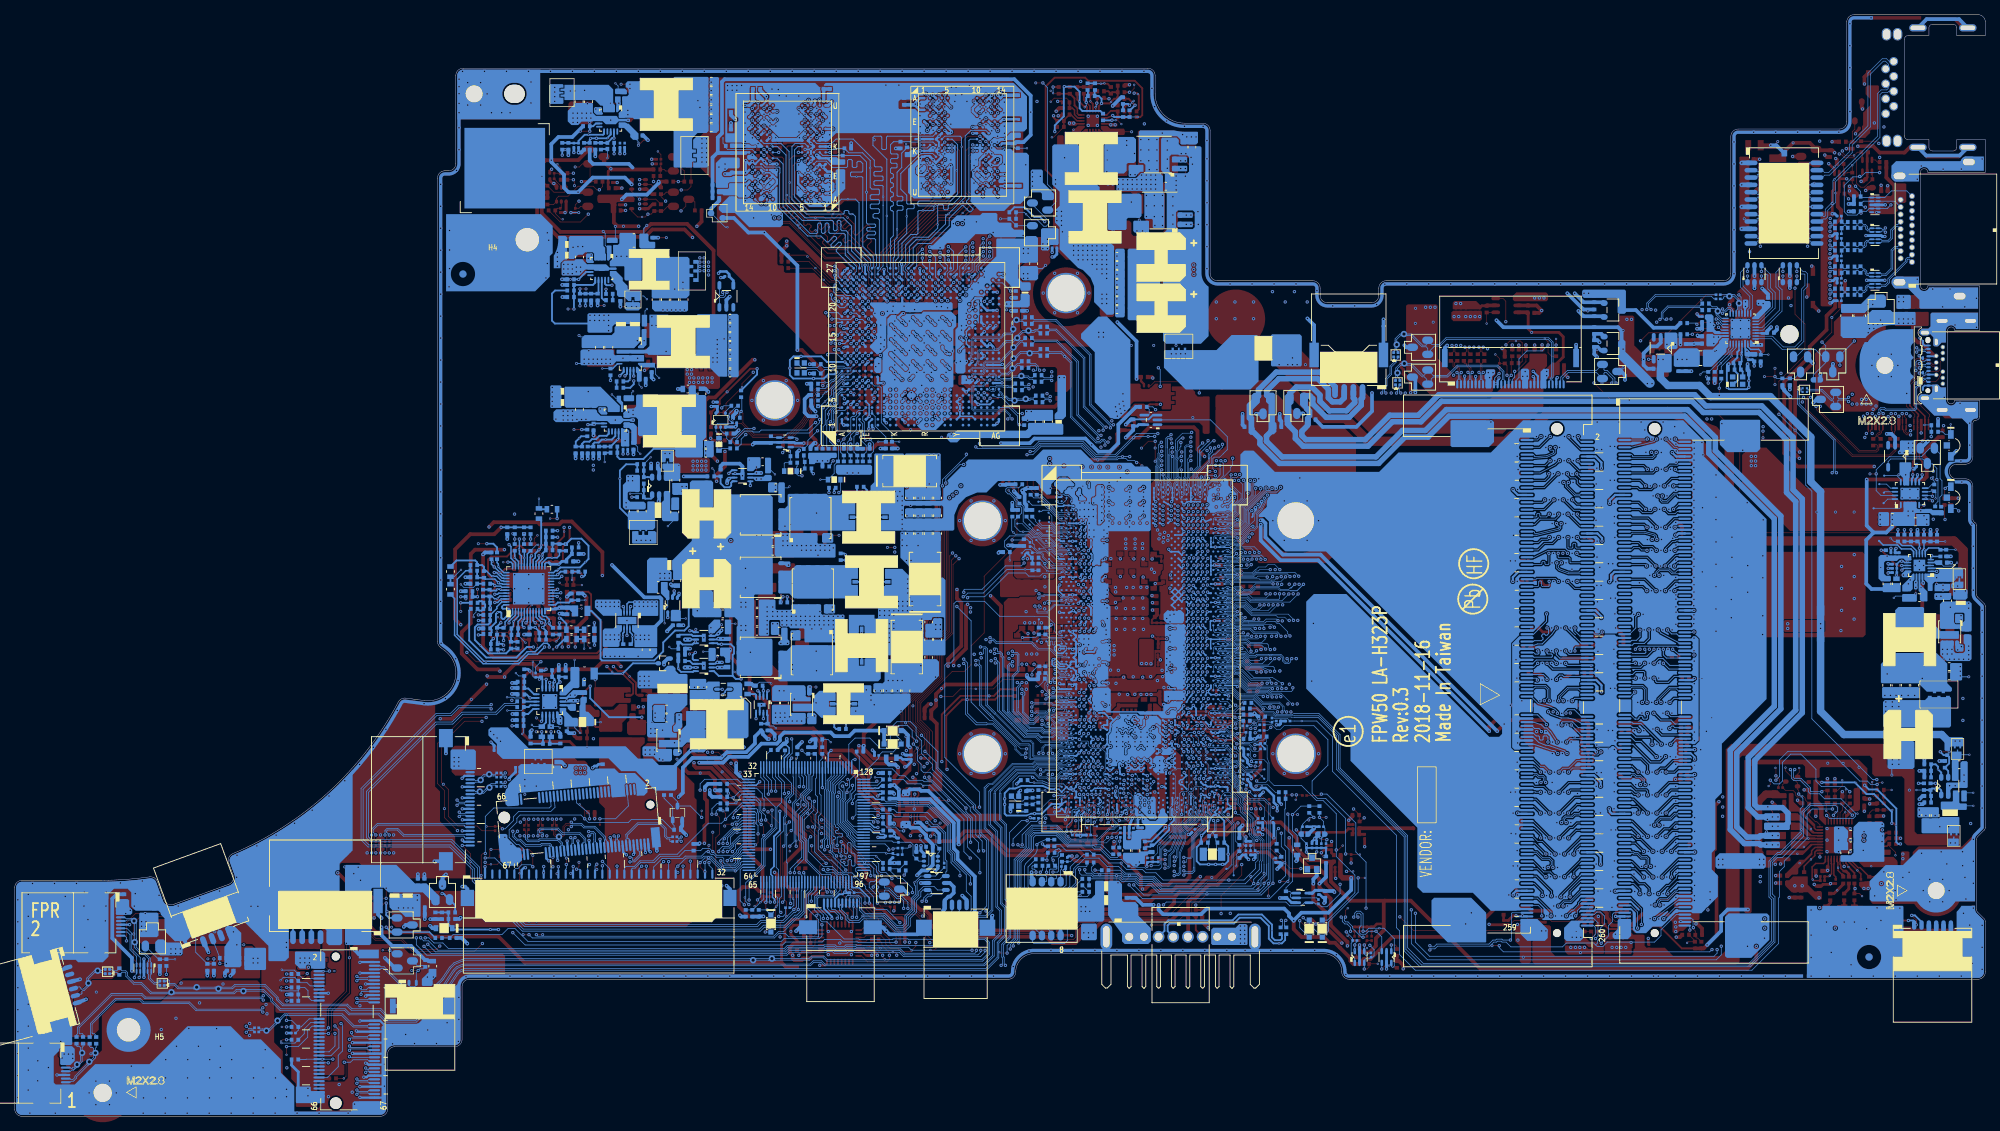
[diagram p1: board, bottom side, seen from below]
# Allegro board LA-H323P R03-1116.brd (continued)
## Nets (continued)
+0.6V_DDRB_VREFCA: CD69.2 CD70.2 CD72.2 CD81.2 JDIMM2.164 RD26.1 RD27.1 RD28.2
+0.6V_VREFCA: CD15.1 RD9.2 UC1.F36
+0.6VSP: PCM5.1 PCM6.1 PJM3.1 PUM1.2 PUM1.20
+1.0VS_DGPU: CV2.1 CV3.1 CV7.1 CV8.1 CV10.1 CV20.1 CV198.1 CV199.1 CV200.1 CV201.1 CV202.1 CV203.1 CV204.1 CV205.1 CV316.1 CV393.1 CV394.1 LV5.1 LV6.1 LV7.2 QV5.3 RV377.1 UV1.AA10 UV1.AA12 UV1.AA13 UV1.AA16 UV1.AA18 UV1.AA19 UV1.AA20 UV1.AA21 UV1.AA22 UV1.AB22 UV1.AB23 UV1.AC23 UV1.AC24 UV1.AD24 UV1.AD25 UV1.AE25 UV1.AE26 UV1.AE27 UV1.AF26 UV1.AF27
+1.0VS_PLLAVDD: CV22.1 CV51.1 CV52.2 CV53.1 CV55.1 LV7.1 UV1.F16 UV1.H22 UV1.P22
+1.2V_VDDQ: C174.1 CC37.1 CC38.1 CC39.1 CC40.1 CC41.1 CC42.1 CC43.1 CC44.1 CC45.1 CC46.1 CC57.1 CC58.1 CC59.1 CC60.1 CC356.1 CC357.1 CC366.2 CD13.2 CD16.1 CD17.1 CD18.1 CD19.1 CD20.1 CD21.1 CD22.1 CD23.1 CD24.1 CD25.1 CD26.1 CD27.1 CD28.1 CD29.1 CD30.1 CD31.1 CD71.2 CD73.1 CD74.1 CD75.1 CD76.1 CD77.1 CD78.1 CD79.1 CD80.1 CD83.1 CD84.1 CD85.1 CD86.1 CD87.1 CD88.1 CD89.1 CD90.1 CD93.1 CD94.1 CD95.1 CD96.1 JDIMM1.12 JDIMM1.33 JDIMM1.54 JDIMM1.75 JDIMM1.96 JDIMM1.111 JDIMM1.112 JDIMM1.117 JDIMM1.118 JDIMM1.123 JDIMM1.124 JDIMM1.129 JDIMM1.130 JDIMM1.135 JDIMM1.136 JDIMM1.141 JDIMM1.142 JDIMM1.147 JDIMM1.148 JDIMM1.153 JDIMM1.154 JDIMM1.159 JDIMM1.160 JDIMM1.163 JDIMM1.178 JDIMM1.199 JDIMM1.220 JDIMM1.241 JDIMM2.12 JDIMM2.33 JDIMM2.54 JDIMM2.75 JDIMM2.96 JDIMM2.111 JDIMM2.112 JDIMM2.117 JDIMM2.118 JDIMM2.123 JDIMM2.124 JDIMM2.129 JDIMM2.130 JDIMM2.135 JDIMM2.136 JDIMM2.141 JDIMM2.142 JDIMM2.147 JDIMM2.148 JDIMM2.153 JDIMM2.154 JDIMM2.159 JDIMM2.160 JDIMM2.163 JDIMM2.178 JDIMM2.199 JDIMM2.220 JDIMM2.241 PJM2.2 RC32.1 RC938.1 RD7.2 RD8.2 RD25.2 RD26.2 UC1.AD36 UC1.AH32 UC1.AH36 UC1.AM36 UC1.AN32 UC1.AW32 UC1.AY36 UC1.BE32 UC1.BH36 UC1.R32 UC1.Y36 UC3.5
+1.2VP: PCM8.1 PCM9.1 PCM10.1 PCM11.1 PCM12.1 PCM13.1 PJM2.1 PLM1.1 PRM6.2 PUM1.5 PUM1.19
+1.2VS_VCCPLL_OC: CC49.1 CC321.1 RC938.2 UC1.BL27 UC1.BM26
+1.05V_MPHYPLL: CC81.1 CC86.1 RC471.2 UC1.BV2
+1.05V_PRIM: CC61.1 CC68.1 CC76.1 CC80.1 CC82.1 CC91.1 CC97.1 CC111.1 CC112.1 CC117.1 CC134.1 CC270.1 CC317.1 CC329.1 CC351.1 CV133.1 CV314.1 JPHW1.1 PJ1002.2 QV5.1 RC14.2 RC393.1 RC471.1 RC477.1 UC1.BP14 UC1.BP20 UC1.BP22 UC1.BR12 UC1.BR14 UC1.BR15 UC1.BR20 UC1.BT12 UC1.BT18 UC1.BT19 UC1.BT22 UC1.BU12 UC1.BU14 UC1.BU15 UC1.BU18 UC1.BU19 UC1.BU22 UC1.BV12 UC1.BV14 UC1.BV15 UC1.BV16 UC1.BV18 UC1.BV19 UC1.BV20 UC1.BV22 UC1.BW12 UC1.BW14 UC1.BW16 UC1.BW18 UC1.BW19 UC1.BW20 UC1.BW22 UC1.BY12 UC1.BY14 UC1.BY16 UC1.BY20 UC1.CA12 UC1.CA14 UC1.CA16 UC1.CA18 UC1.CA19 UC1.CA20 UC1.CB12 UC1.CB14 UC1.CB15 UC1.CC12 UC6.1 UC6.2 UC7.1 UC7.2 UC7.7
+1.05V_PRIMP: PC1010.1 PC1011.1 PC1012.1 PC1013.1 PC1014.1 PJ1002.1 PL1001.2 PR1008.2
+1.05V_VCCDSW: CC316.1 UC1.BT24
+1.05V_VCCST: CC48.1 CC55.1 CC62.1 CC96.1 CC346.1 CC358.1 PCZ227.1 PRZ36.1 PRZ38.1 PRZ39.1 RC2.1 RC113.1 RC179.1 RC181.1 RC427.2 RC935.2 UC1.BP2 UC1.BP11 UC1.BR11 UC1.BT11
+1.05V_VCCSTU_IN: RC427.1 UC6.13 UC6.14
+1.05V_XTAL: CC318.1 CC319.1 RC477.2 UC1.CP5
+1.05VS_PG: PR1005.2 PU1001.9 UK1.108
+1.05VS_VCCIO: CC27.1 CC28.1 CC29.1 CC30.1 CC31.1 CC32.1 CC33.1 CC34.1 CC35.1 CC36.1 CC90.1 CC347.1 CC348.1 CC349.1 CC350.1 RC1.1 RC189.2 RC190.2 RC191.2 UC1.AK24 UC1.AK26 UC1.AL24 UC1.AL25 UC1.AL26 UC1.AL27 UC1.AM25 UC1.AM27 UC1.BH24 UC1.BH25 UC1.BH26 UC1.BH27 UC1.BJ24 UC1.BJ26 UC1.BP16 UC1.BP18
+1.05VS_VCCSTG: CC89.1 CC142.1 RC3.1 RC188.2 RC389.2 RC390.2 RC391.2 RC937.2 RC1157.1 UC1.BG1 UC1.BG2 UC1.BG3
+1.05VS_VCCSTG_IO: JPHW1.2 RC188.1 RC189.1 RC190.1 RC191.1 UC7.6
+1.8V_PG: PR1001.1 PR1801.2 PU1801.5
+1.8V_PRIM: CC87.1 CC103.1 CC115.1 CC116.1 CC274.1 CC337.1 CC338.1 CC341.1 PJ1802.2 R5093.1 RC72.2 RC183.2 RC403.1 RC404.2 RC1155.2 UC1.CC15 UC1.CC18 UC1.CC19 UC1.CD15 UC1.CD16 UC1.CD18 UC1.CD19 UC1.CP17 UC1.CP23 UC6.6 UC6.7
+1.8VS: CA39.2 CC275.1 RA5.1 UA1.29 UC6.8 UC6.9
+1.8VS_AVDD: CA8.1 RA5.2 UA1.33
+1.8VSP: PC1802.1 PC1803.1 PC1804.1 PJ1802.1 PL1801.2 PR1803.1
+1.35VGS_PGOOD: PRW5.2 PUW1.9 RV31.1
+1.35VRAMP: PCW10.1 PCW11.1 PCW12.1 PCW13.1 PCW14.1 PCW18.1 PCW19.1 PJW2.1 PLW1.2 PRW8.2
+1.35VS_VRAM: CV38.1 CV44.1 CV45.1 CV46.1 CV160.2 CV161.1 CV162.1 CV163.1 CV164.1 CV165.1 CV166.1 CV167.1 CV168.2 CV169.1 CV170.1 CV171.1 CV172.1 CV173.1 CV174.1 CV175.1 CV215.1 CV217.1 CV218.1 CV221.1 CV222.1 CV373.2 CV374.1 CV375.1 CV376.1 CV377.1 CV378.1 CV379.1 CV380.1 CV381.2 CV382.1 CV383.1 CV384.1 CV385.1 CV386.1 CV387.1 CV388.1 CV389.1 CV390.1 PJW2.2 RV41.2 RV82.2 RV83.2 RV117.2 RV125.1 RV2439.2 RV2440.2 UV1.B26 UV1.C25 UV1.E23 UV1.E26 UV1.F14 UV1.F21 UV1.G13 UV1.G14 UV1.G15 UV1.G16 UV1.G18 UV1.G19 UV1.G20 UV1.G21 UV1.H24 UV1.H26 UV1.J21 UV1.K21 UV1.L22 UV1.L24 UV1.L26 UV1.M21 UV1.N21 UV1.R21 UV1.T21 UV1.V21 UV1.W21 UV6.B1 UV6.B3 UV6.B12 UV6.B14 UV6.C5 UV6.C10 UV6.D1 UV6.D3 UV6.D11 UV6.D12 UV6.D14 UV6.E5 UV6.E10 UV6.F1 UV6.F3 UV6.F12 UV6.F14 UV6.G1 UV6.G2 UV6.G4 UV6.G11 UV6.G13 UV6.G14 UV6.H3 UV6.H12 UV6.K3 UV6.K12 UV6.L1 UV6.L2 UV6.L4 UV6.L11 UV6.L13 UV6.L14 UV6.M1 UV6.M3 UV6.M12 UV6.M14 UV6.N5 UV6.N10 UV6.P1 UV6.P3 UV6.P11 UV6.P12 UV6.P14 UV6.R5 UV6.R10 UV6.T1 UV6.T3 UV6.T12 UV6.T14 UV7.B1 UV7.B3 UV7.B12 UV7.B14 UV7.C5 UV7.C10 UV7.D1 UV7.D3 UV7.D11 UV7.D12 UV7.D14 UV7.E5 UV7.E10 UV7.F1 UV7.F3 UV7.F12 UV7.F14 UV7.G1 UV7.G2 UV7.G4 UV7.G11 UV7.G13 UV7.G14 UV7.H3 UV7.H12 UV7.K3 UV7.K12 UV7.L1 UV7.L2 UV7.L4 UV7.L11 UV7.L13 UV7.L14 UV7.M1 UV7.M3 UV7.M12 UV7.M14 UV7.N5 UV7.N10 UV7.P1 UV7.P3 UV7.P11 UV7.P12 UV7.P14 UV7.R5 UV7.R10 UV7.T1 UV7.T3 UV7.T12 UV7.T14
+2.5V: CC159.1 CD3.1 CD4.1 CD5.1 CD6.1 CD62.1 CD63.1 CD64.1 CD65.1 CD97.1 CD98.1 CD99.1 CD100.1 JDIMM1.257 JDIMM1.259 JDIMM2.257 JDIMM2.259 PJ2502.2
+2.5VP: PC2504.1 PC2505.1 PC2506.1 PJ2502.1 PL2501.2 PR2506.1
+3V_EC_VDD: RK3.1 UK1.125
+3V_FPR: JFPR.1 JFPR.2 RF1.2
+3V_HDA: CC269.1 RC150.2 UC1.BT20
+3V_LID: C18.1 CK11.1 DH2.1 PR18.2 PR20.1 R126.1 R215.1 RC462.1 U4018.2 UK1.111
+3V_LID_R: PJPB1.5 PR18.1
+3V_PRIM: CC51.1 CC63.1 CC67.1 CC72.1 CC73.1 CC74.1 CC102.1 CC141.1 CC314.1 CC328.1 CC332.1 CC333.1 CC334.1 CC335.1 CC336.1 CC343.1 PR1801.1 QC7.2 QC7.5 RC49.2 RC50.2 RC115.1 RC127.1 RC150.1 RC154.1 RC226.2 RC360.2 RC374.2 RC379.2 RC380.2 RC467.2 RC468.2 RC469.2 RC470.2 RC472.2 RC491.2 RC900.2 RC916.2 RC959.1 RC963.2 RC964.2 RC965.2 RC966.2 RC967.2 RC980.2 RC985.1 RC1158.2 RC1159.2 RD32.1 RD33.1 UC1.BP23 UC1.BW23 UC1.CB16 UC1.CB22 UC1.CB23 UC1.CC22 UC1.CC23 UC1.CD22 UC1.CD23 UC1.CP29
+3V_PRIM_DA: CD1.2 CD2.2 JDIMM1.255 RD32.2
+3V_PRIM_DB: CD60.1 CD61.2 JDIMM2.255 RD33.2
+3V_SMBUS: DH4.1 DH5.1 RK110.1 RK111.1
+3V_SPI: CC8.1 RC154.2 RC357.2 RC383.2 RC384.2 RC941.2 UC1.BV23 UC2.8
+3VALW: CC50.1 CC331.1 CL28.1 DT2.5 JL33.1 JTP1.1 JTP2.1 PC1006.1 PC1016.1 PCW8.1 PCW16.1 PJ302.2 PJ1801.1 PJ2501.1 PR304.1 PR1003.1 PR1005.1 PR2504.1 PRW3.1 PU1001.15 PUW1.15 Q21.6 Q21.7 QWL1.3 RC81.2 RC82.2 RC173.1 RC434.2 RC934.2 RC967.1 RK12.2 RK13.2 UL2.5
+3VALW_DSW: CC323.1 CC342.1 RC103.1 RC104.1 RC106.1 RC173.2 RC187.2 RC483.2 RC926.1 UC1.BR24 UC1.BT23
+3VALW_EC: CK1.1 CK2.1 CK8.1 LK1.1 PR9.1 RG67.2 RK1.2 RK2.2 RK7.2 RK21.1 RV26.2 UK1.9 UK1.22 UK1.33 UK1.96 UK1.124
+3VALWP: PC306.1 PC307.1 PC308.1 PC309.1 PJ302.1 PL302.2 PR305.2 PU301.14
+3VL: DC1.3 DH2.2 DH4.2 PJ303.2 PQ2.5 PR16.1 PRB15.1 PRB16.2 Q4108.2 R295.2 RK1.1 RK3.2
+3VLP: PC310.1 PJ303.1 PU301.16 PU301.17
+3VS: C570.1 C5233.1 CC14.1 CC127.1 CC315.1 CG1.1 CG4.1 CG75.1 CG76.1 CG77.1 CG78.1 CSS5.1 CSS6.1 CTS7.1 CV223.1 FG4.1 JCR.1 JPHW9.1 LED2.2 PRW5.1 PRZ23.2 Q21.8 Q21.9 QC1.2 QC1.5 QG1.2 QG1.5 QG2.2 QG2.5 QV20.3 QV26.3 R5201.1 RA1.1 RA2.1 RA10.1 RA23.2 RC105.1 RC107.2 RC117.1 RC118.1 RC122.2 RC165.1 RC201.1 RC215.2 RC216.2 RC381.2 RC382.2 RC409.2 RC410.2 RC429.1 RC475.2 RC952.1 RC953.1 RC954.1 RC955.1 RC961.2 RC962.2 RC978.2 RD1.1 RD2.1 RD4.1 RD19.1 RD20.1 RD21.1 RE50.1 RF1.1 RG47.1 RG110.1 RG111.1 RK14.1 RK112.1 RK113.1 RM6.1 RS21.2 RS22.1 RV15.2 UC4.5 UC11.4 UG1.5 UV12.5 UV23.5
+3VS_CAMERA: C5221.1 C5222.1 C5232.1 JEDP.24 JEDP.25 UG1.3
+3VS_DGPU: CV211.1 CV216.1 CV219.1 CV220.1 CV318.2 CV319.1 QV26.1 RV17.1 RV80.1 RV81.1 RV84.1 UV1.G8 UV1.G9
+3VS_DGPU_AON: CV4.1 CV5.1 CV207.1 CV212.1 CV213.1 CV214.1 CV311.2 CV312.1 PRV3.2 PRV22.2 PRV27.2 QV2.2 QV2.5 QV20.1 RV23.2 RV30.2 RV51.1 RV61.1 RV68.1 RV69.2 RV72.2 RV203.2 RV204.2 RV382.1 RV384.1 RV389.1 RV2751.1 RV2762.2 RV2763.2 RV2764.2 RV2765.2 RV2766.2 UV1.AA8 UV1.AA9 UV1.AB8 UV1.G10 UV1.G12 UV15.5
+3VS_SSD: CS8.1 CS9.1 CS10.1 CS27.1 CSS7.1 JPHW9.2 JSSD.2 JSSD.4 JSSD.12 JSSD.14 JSSD.16 JSSD.18 JSSD.62 JSSD.64 JSSD.66
+3VS_TOUCH: CTS3.1 FG4.3 JEDP.23
+3VS_TPM: CT1.1 CT2.1 CT3.1 CT4.1 CT5.1 RC934.1 RT10.2 RT35.1 UT1.1 UT1.8 UT1.14 UT1.22
+3VS_WLAN: C5181.1 C5182.1 C5183.1 C5184.1 CN3.1 CN4.1 CN5.1 CWL2.1 JWLAN.2 JWLAN.4 JWLAN.64 JWLAN.66 QWL1.1 R5179.1 R5180.1 R5273.1 RN3.1 RN7.2 RN15.1 RWL2.1
+5V_TYPEC: CC170.1 CC171.1 CU6.1 CU7.1 CU8.2 CU9.1 CU10.2 CU11.1 DC6.2 DC6.3 JTC1.A4 JTC1.A9 JTC1.B4 JTC1.B9 UU2.1
+5V_TYPEC_IC: CU12.1 UU1.14 UU1.15 UU2.5
+5VALW: CC88.1 CC98.1 CC339.1 CU3.2 CU4.2 CU13.2 JIO.1 JIO.2 JIO.3 JIO.4 JIO.5 PJ305.2 PRA1.1 PRG1.1 PRM4.1 PRM5.1 PRZ65.1 PRZ72.1 PRZ80.1 PRZ81.1 PRZ104.1 PRZ105.1 Q21.1 Q21.2 Q21.4 R5092.1 RLED3.2 RU2.1 RU3.2 RV2739.2 RV2745.2 RV2752.2 UC6.4 UC7.3 UU1.2 UU1.3 UU1.4 UU1.5
+5VALWP: PC301.1 PC319.1 PC322.1 PC323.1 PC328.1 PC329.1 PC330.1 PJ305.1 PL301.3 PL301.4 PR312.2 PU302.8
+5VLP: PC325.1 PU302.9
+5VS: C575.1 CC140.1 CC163.1 CTS1.1 FG1.1 FG2.1 JKB.1 JKB.6 PRV14.2 Q21.13 Q21.14 R23.1 R24.2 R201.1 R202.1 R5261.1 R5262.1 RA4.1 RA8.1 RA39.1 RK28.2
+5VS_AVDD: CA5.1 CA6.1 CA7.1 CA47.1 RA4.2 UA1.20
+5VS_HDD1: C140.2 JHDD.1 JHDD.2 R201.2 R202.2
+5VS_KBL: JKBL.3 JKBL.4 R24.1
+5VS_PVDD1: CA19.1 CA20.1 CA45.1 RA8.2 UA1.34
+5VS_PVDD2: CA21.1 CA22.1 CA46.1 RA39.2 UA1.39
+5VS_TOUCH: CTS6.1 FG2.3 JEDP.22
+12.6V_BATT: PC9.1 PC11.1 PCB9.1 PCB15.1 PCB16.1 PL13.2 PL14.2 PQB13.1 PQB13.2 PQB13.3 PRB11.4
+12.6V_BATT+: PC8.1 PC10.1 PJPB1.1 PJPB1.2 PL13.1 PL14.1
+19V_ADPIN: PC1.1 PC2.1 PD2.2 PJP1.1 PJP1.2 PL11.1 PL12.1
+19V_VIN: PC3.1 PC4.1 PCB4.1 PDB1.3 PL11.2 PL12.2 PQB11.5 PRB17.1
+19VB: FU1.2 PDB1.2 PJV1.2 PJW1.2 PL303.1 PL304.1 PL305.1 PL306.1 PL1002.1 PL1003.1 PLB11.1 PLM2.1 PLZ3.2 PQB13.5 PR19.1 PR307.1 PRB1.4
+19VB_1V: PC1001.1 PC1003.1 PC1004.1 PL1002.2 PL1003.2 PU1001.2 PU1001.3 PU1001.4 PU1001.5
+19VB_3V: PC303.1 PC304.1 PC305.1 PL303.2 PL304.2 PU301.2 PU301.3 PU301.4 PU301.5
+19VB_5V: PC314.1 PC315.1 PC316.1 PC317.1 PL305.2 PL306.2 PU302.1
+19VB_CHG: PCB6.1 PCB7.1 PCB8.1 PCB25.1 PLB11.2 PQB1.2 PQB1.3 PQB1.4 PQB1.10
+19VB_CPU: PCA2.1 PCA4.1 PCA5.1 PCA6.1 PCG4.1 PCG5.1 PCG10.1 PCG12.1 PCZ1.1 PCZ26.1 PCZ29.1 PCZ30.1 PCZ31.1 PCZ32.1 PCZ33.1 PCZ34.1 PCZ36.1 PCZ37.1 PCZ47.1 PCZ229.1 PLZ3.1 PQA1.2 PQA1.3 PQA1.4 PQA1.10 PQG1.5 PQZ1.5 PQZ3.5 PRZ53.2
+19VB_DDR: PCM1.1 PCM2.1 PLM2.2 PQM1.2 PQM1.3 PQM1.4 PQM1.10 PRM7.1
+19VB_VGA_CORE: PCV2.1 PCV3.1 PCV5.1 PCV6.1 PCV9.1 PCV10.1 PCV15.1 PCV16.1 PCV19.1 PCV20.1 PJV1.1 PQV1.3 PQV1.4 PQV1.10 PQV2.3 PQV2.4 PQV2.10 PRV15.1
+19VB_VRAM: PCW2.1 PCW3.1 PCW5.1 PCW17.1 PJW1.1 PUW1.2 PUW1.3 PUW1.4 PUW1.5
+DVDD: CA36.1 CA37.1 RA1.2 RA9.1 RA41.1 UA1.1
+DVDD_IO: CA32.1 CA33.1 RA2.2 UA1.8
+VCC_CORE: PCZ68.1 PCZ78.1 PCZ79.1 PCZ80.1 PCZ81.1 PCZ82.1 PCZ97.1 PCZ98.1 PCZ99.1 PCZ100.1 PCZ101.1 PCZ102.1 PCZ103.1 PCZ104.1 PCZ127.1 PCZ150.1 PCZ154.1 PCZ155.1 PCZ167.1 PCZ168.1 PCZ169.1 PCZ170.1 PCZ171.1 PCZ172.1 PCZ173.1 PCZ174.1 PCZ175.1 PCZ176.1 PCZ187.1 PCZ188.1 PCZ189.1 PCZ190.1 PCZ191.1 PCZ192.1 PCZ193.1 PCZ194.1 PCZ195.1 PCZ196.1 PCZ200.1 PCZ201.1 PCZ202.1 PCZ203.1 PCZ204.1 PCZ205.1 PCZ206.1 PCZ207.1 PCZ208.1 PCZ209.1 PCZ210.1 PCZ211.1 PCZ212.1 PCZ213.1 PCZ214.1 PCZ215.1 PCZ233.1 PCZ234.1 PCZ235.1 PCZ236.1 PCZ237.1 PCZ238.1 PCZ239.1 PCZ240.1 PCZ243.1 PCZ244.1 PCZ245.1 PCZ246.1 PCZ247.1 PCZ248.1 PLZ1.4 PLZ2.4 PRZ41.1 UC1.AA9 UC1.AB2 UC1.AB8 UC1.AB9 UC1.AB10 UC1.AC8 UC1.AD9 UC1.AE8 UC1.AE9 UC1.AE10 UC1.AF2 UC1.AF8 UC1.AF10 UC1.AG8 UC1.AG9 UC1.AH9 UC1.AJ8 UC1.AJ10 UC1.AK2 UC1.AK9 UC1.AL8 UC1.AL9 UC1.AL10 UC1.AM8 UC1.AN9 UC1.AN10 UC1.AN24 UC1.AN26 UC1.AN27 UC1.AP2 UC1.AP9 UC1.AP24 UC1.AP26 UC1.AR5 UC1.AR6 UC1.AR7 UC1.AR8 UC1.AR10 UC1.AR25 UC1.AR27 UC1.AT9 UC1.AT24 UC1.AT26 UC1.AU5 UC1.AU6 UC1.AU7 UC1.AU8 UC1.AU9 UC1.AU24 UC1.AU25 UC1.AU26 UC1.AU27 UC1.AV2 UC1.AV5 UC1.AV7 UC1.AV10 UC1.AV27 UC1.AW5 UC1.AW6 UC1.AW7 UC1.AW8 UC1.AW9 UC1.AW10 UC1.AW24 UC1.AW25 UC1.AW26 UC1.AW27 UC1.AY24 UC1.AY26 UC1.BA5 UC1.BA7 UC1.BA8 UC1.BA25 UC1.BA27 UC1.BB2 UC1.BB26 UC1.BC5 UC1.BC6 UC1.BC7 UC1.BC9 UC1.BC10 UC1.BC26 UC1.BC27 UC1.BD5 UC1.BD8 UC1.BD10 UC1.BD25 UC1.BD27 UC1.BE9 UC1.BE24 UC1.BE25 UC1.BE26 UC1.BE27 UC1.BF2 UC1.BF9 UC1.BF24 UC1.BF26 UC1.BG27 UC1.V2 UC1.Y8 UC1.Y10
+VCC_GT: PCZ69.1 PCZ70.1 PCZ71.1 PCZ72.1 PCZ73.1 PCZ74.1 PCZ75.1 PCZ76.1 PCZ77.1 PCZ85.1 PCZ86.1 PCZ109.1 PCZ110.1 PCZ111.1 PCZ112.1 PCZ113.1 PCZ114.1 PCZ115.1 PCZ116.1 PCZ117.1 PCZ131.1 PCZ132.1 PCZ134.1 PCZ135.1 PCZ136.1 PCZ137.1 PCZ157.1 PCZ158.1 PCZ159.1 PCZ160.1 PCZ161.1 PCZ162.1 PCZ163.1 PCZ164.1 PCZ165.1 PCZ166.1 PCZ177.1 PCZ178.1 PCZ179.1 PCZ180.1 PCZ181.1 PCZ182.1 PCZ183.1 PCZ184.1 PCZ185.1 PCZ186.1 PCZ197.1 PCZ198.1 PCZ199.1 PLG1.4 PRZ59.2 UC1.A5 UC1.A6 UC1.A8 UC1.A11 UC1.A12 UC1.A14 UC1.A15 UC1.A17 UC1.A18 UC1.A20 UC1.B3 UC1.B4 UC1.B6 UC1.B8 UC1.B11 UC1.B14 UC1.B17 UC1.B20 UC1.C2 UC1.C3 UC1.C6 UC1.C7 UC1.C8 UC1.C11 UC1.C12 UC1.C14 UC1.C15 UC1.C17 UC1.C18 UC1.C20 UC1.D4 UC1.D7 UC1.D11 UC1.D12 UC1.D14 UC1.D15 UC1.D17 UC1.D18 UC1.D20 UC1.E4 UC1.F5 UC1.F6 UC1.F7 UC1.F8 UC1.F11 UC1.F14 UC1.F17 UC1.F20 UC1.G11 UC1.G12 UC1.G14 UC1.G15 UC1.G17 UC1.G18 UC1.G20 UC1.H5 UC1.H6 UC1.H7 UC1.H8 UC1.H11 UC1.H12 UC1.H14 UC1.H15 UC1.H17 UC1.H18 UC1.H20 UC1.J7 UC1.J8 UC1.J11 UC1.J14 UC1.J17 UC1.J20 UC1.K2 UC1.K11 UC1.L7 UC1.L8 UC1.L10 UC1.M9 UC1.N7 UC1.N8 UC1.N9 UC1.N10 UC1.P2 UC1.P8 UC1.R9 UC1.T8 UC1.T9 UC1.T10 UC1.U8 UC1.U10 UC1.V9 UC1.W8 UC1.W9
+VCC_SA: PCZ87.1 PCZ88.1 PCZ89.1 PCZ90.1 PCZ91.1 PCZ93.1 PCZ94.1 PCZ95.1 PCZ96.1 PCZ119.1 PCZ140.1 PCZ141.1 PCZ142.1 PCZ143.1 PCZ144.1 PCZ145.1 PCZ146.1 PLA1.4 PRZ1.1 UC1.BG8 UC1.BG10 UC1.BH9 UC1.BJ8 UC1.BJ9 UC1.BJ10 UC1.BK8 UC1.BK25 UC1.BK27 UC1.BL8 UC1.BL9 UC1.BL10 UC1.BL24 UC1.BL26 UC1.BM24 UC1.BN25
+VCCDPHY_1P24: CC325.2 RC977.2 UC1.BY23 UC1.BY24 UC1.CA23 UC1.CA24
AVCCSA: PCA7.2 PCZ3.2 PHA1.2 PLA1.3 PRA8.2 PUZ1.41
AVCCSA_R: PHA1.1 PRA7.2 PRA8.1
GND: C11.2 C12.2 C13.2 C14.2 C18.2 C19.2 C117.2 C118.2 C140.1 C174.2 C193.1 C554.2 C557.2 C570.2 C575.2 C593.2 C594.2 C4801.2 C5181.2 C5182.2 C5183.2 C5184.2 C5185.2 C5186.2 C5214.2 C5221.2 C5222.2 C5228.2 C5230.2 C5231.2 C5232.2 C5233.2 CA9.1 CA10.1 CA11.1 CA12.1 CA13.1 CA15.1 CA19.2 CA20.2 CA21.2 CA22.2 CA23.2 CA28.2 CA32.2 CA33.2 CA34.1 CA36.2 CA37.2 CA39.1 CA41.2 CA45.2 CA46.2 CC7.1 CC8.2 CC9.2 CC10.1 CC11.1 CC12.2 CC13.2 CC14.2 CC15.2 CC16.2 CC27.2 CC28.2 CC29.2 CC30.2 CC31.2 CC32.2 CC33.2 CC34.2 CC35.2 CC36.2 CC37.2 CC38.2 CC39.2 CC40.2 CC41.2 CC42.2 CC43.2 CC44.2 CC45.2 CC46.2 CC48.2 CC49.2 CC50.2 CC51.2 CC55.2 CC57.2 CC58.2 CC59.2 CC60.2 CC61.2 CC62.2 CC63.2 CC67.2 CC68.2 CC71.2 CC72.2 CC73.2 CC74.2 CC76.2 CC80.2 CC81.2 CC82.2 CC86.2 CC87.2 CC88.2 CC89.2 CC90.2 CC91.2 CC94.2 CC95.2 CC96.2 CC97.2 CC98.2 CC102.2 CC103.2 CC111.2 CC112.2 CC115.2 CC116.2 CC117.2 CC122.2 CC123.2 CC127.2 CC134.2 CC140.2 CC141.2 CC142.2 CC144.2 CC159.2 CC163.2 CC170.2 CC171.2 CC256.2 CC261.2 CC269.2 CC270.2 CC274.2 CC275.2 CC292.1 CC293.1 CC295.1 CC296.2 CC297.1 CC298.2 CC299.2 CC300.2 CC301.1 CC302.2 CC303.2 CC312.1 CC314.2 CC315.2 CC316.2 CC317.2 CC318.2 CC319.2 CC320.2 CC321.2 CC323.2 CC324.1 CC325.1 CC328.2 CC329.2 CC331.2 CC332.2 CC333.2 CC334.2 CC335.2 CC336.2 CC337.2 CC338.2 CC339.2 CC341.2 CC342.2 CC343.2 CC346.2 CC347.2 CC348.2 CC349.2 CC350.2 CC351.2 CC352.2 CC353.2 CC354.1 CC355.1 CC356.2 CC357.2 CC358.2 CC359.2 CC360.2 CC361.2 CC362.2 CC363.2 CC364.2 CC365.2 CC366.1 CD1.1 CD2.1 CD3.2 CD4.2 CD5.2 CD6.2 CD7.2 CD8.2 CD9.2 CD10.2 CD11.1 CD12.1 CD13.1 CD14.1 CD16.2 CD17.2 CD18.2 CD19.2 CD20.2 CD21.2 CD22.2 CD23.2 CD24.2 CD25.2 CD26.2 CD27.2 CD28.2 CD29.2 CD30.2 CD31.2 CD60.2 CD61.1 CD62.2 CD63.2 CD64.2 CD65.2 CD66.2 CD67.2 CD68.2 CD69.1 CD70.1 CD71.1 CD72.1 CD73.2 CD74.2 CD75.2 CD76.2 CD77.2 CD78.2 CD79.2 CD80.2 CD81.1 CD83.2 CD84.2 CD85.2 CD86.2 CD87.2 CD88.2 CD89.2 CD90.2 CD92.2 CD93.2 CD94.2 CD95.2 CD96.2 CD97.2 CD98.2 CD99.2 CD100.2 CE24.2 CG1.2 CG2.2 CG3.2 CG4.2 CG46.2 CG47.2 CG75.2 CG76.2 CG77.2 CG78.2 CK1.2 CK2.2 CK4.2 CK5.1 CK8.2 CK9.1 CK10.2 CK11.2 CL1.1 CL3.2 CL4.2 CL5.2 CL8.2 CL9.2 CL10.2 CL11.2 CL12.2 CL13.2 CL14.2 CL15.2 CL16.2 CL19.2 CL20.2 CL23.2 CL24.1 CL25.1 CL26.2 CL27.2 CL28.2 CL29.2 CLED1.2 CLED2.2 CLRP1.1 CLRP2.1 CLRP3.2 CM17.2 CM26.2 CM27.2 CN3.2 CN4.2 CN5.2 CS8.2 CS9.2 CS10.2 CS16.1 CS27.2 CSS5.2 CSS6.2 CSS7.2 CT1.2 CT2.2 CT3.2 CT4.2 CT5.2 CTS1.2 CTS3.2 CTS6.2 CTS7.2 CU3.1 CU4.1 CU6.2 CU7.2 CU8.1 CU9.2 CU10.1 CU11.2 CU12.2 CU13.1 CV2.2 CV3.2 CV4.2 CV5.2 CV6.2 CV7.2 CV8.2 CV10.2 CV20.2 CV22.2 CV30.2 CV31.2 CV34.2 CV35.2 CV38.2 CV44.2 CV45.2 CV46.2 CV51.2 CV52.1 CV53.2 CV55.2 CV60.2 CV61.2 CV121.2 CV133.2 CV158.2 CV159.2 CV160.1 CV161.2 CV162.2 CV163.2 CV164.2 CV165.2 CV166.2 CV167.2 CV168.1 CV169.2 CV170.2 CV171.2 CV172.2 CV173.2 CV174.2 CV175.2 CV190.2 CV198.2 CV199.2 CV200.2 CV201.2 CV202.2 CV203.2 CV204.2 CV205.2 CV206.2 CV207.2 CV208.2 CV209.1 CV210.1 CV211.2 CV212.2 CV213.2 CV214.2 CV215.2 CV216.2 CV217.2 CV218.2 CV219.2 CV220.2 CV221.2 CV222.2 CV223.2 CV311.1 CV312.2 CV313.2 CV314.2 CV315.2 CV316.2 CV317.2 CV318.1 CV319.2 CV320.2 CV321.2 CV373.1 CV374.2 CV375.2 CV376.2 CV377.2 CV378.2 CV379.2 CV380.2 CV381.1 CV382.2 CV383.2 CV384.2 CV385.2 CV386.2 CV387.2 CV388.2 CV389.2 CV390.2 CV391.2 CV392.2 CV393.2 CV394.2 CV395.2 CV396.2 CWL1.2 CWL2.2 D1.1 D6.1 D7.1 D21.3 D22.3 D31.3 D32.3 D33.3 DA6.1 DA7.1 DC6.1 DG1.3 DL1.1 DM1.1 DM5.1 DM12.2 DM13.2 DM15.1 DM16.3 DT2.2 FG1.2 FG2.2 FG4.2 H4.1(TP-1) H5.1(TP-1) H6.1(TP-1) H7.1(TP-1) H8.1(TP-1) H9.1(TP-1) H10.1(TP-1) H11.1(TP-1) H13.1(TP-1) H14.1(TP-1) H15.1(TP-1) H17.1(TP-1) JCMOS1.2 JCR.3 JCR.6 JCR.7 JCR.8 JDIMM1.1 JDIMM1.2 JDIMM1.5 JDIMM1.6 JDIMM1.9 JDIMM1.10 JDIMM1.14 JDIMM1.15 JDIMM1.18 JDIMM1.19 JDIMM1.22 JDIMM1.23 JDIMM1.26 JDIMM1.27 JDIMM1.30 JDIMM1.31 JDIMM1.35 JDIMM1.36 JDIMM1.39 JDIMM1.40 JDIMM1.43 JDIMM1.44 JDIMM1.47 JDIMM1.48 JDIMM1.51 JDIMM1.52 JDIMM1.56 JDIMM1.57 JDIMM1.60 JDIMM1.61 JDIMM1.64 JDIMM1.65 JDIMM1.68 JDIMM1.69 JDIMM1.72 JDIMM1.73 JDIMM1.77 JDIMM1.78 JDIMM1.81 JDIMM1.82 JDIMM1.85 JDIMM1.86 JDIMM1.89 JDIMM1.90 JDIMM1.93 JDIMM1.94 JDIMM1.98 JDIMM1.99 JDIMM1.102 JDIMM1.103 JDIMM1.106 JDIMM1.107 JDIMM1.167 JDIMM1.168 JDIMM1.171 JDIMM1.172 JDIMM1.175 JDIMM1.176 JDIMM1.180 JDIMM1.181 JDIMM1.184 JDIMM1.185 JDIMM1.188 JDIMM1.189 JDIMM1.192 JDIMM1.193 JDIMM1.196 JDIMM1.197 JDIMM1.201 JDIMM1.202 JDIMM1.205 JDIMM1.206 JDIMM1.209 JDIMM1.210 JDIMM1.213 JDIMM1.214 JDIMM1.217 JDIMM1.218 JDIMM1.222 JDIMM1.223 JDIMM1.226 JDIMM1.227 JDIMM1.230 JDIMM1.231 JDIMM1.234 JDIMM1.235 JDIMM1.238 JDIMM1.239 JDIMM1.243 JDIMM1.244 JDIMM1.247 JDIMM1.248 JDIMM1.251 JDIMM1.252 JDIMM1.261 JDIMM1.262 JDIMM2.1 JDIMM2.2 JDIMM2.5 JDIMM2.6 JDIMM2.9 JDIMM2.10 JDIMM2.14 JDIMM2.15 JDIMM2.18 JDIMM2.19 JDIMM2.22 JDIMM2.23 JDIMM2.26 JDIMM2.27 JDIMM2.30 JDIMM2.31 JDIMM2.35 JDIMM2.36 JDIMM2.39 JDIMM2.40 JDIMM2.43 JDIMM2.44 JDIMM2.47 JDIMM2.48 JDIMM2.51 JDIMM2.52 JDIMM2.56 JDIMM2.57 JDIMM2.60 JDIMM2.61 JDIMM2.64 JDIMM2.65 JDIMM2.68 JDIMM2.69 JDIMM2.72 JDIMM2.73 JDIMM2.77 JDIMM2.78 JDIMM2.81 JDIMM2.82 JDIMM2.85 JDIMM2.86 JDIMM2.89 JDIMM2.90 JDIMM2.93 JDIMM2.94 JDIMM2.98 JDIMM2.99 JDIMM2.102 JDIMM2.103 JDIMM2.106 JDIMM2.107 JDIMM2.167 JDIMM2.168 JDIMM2.171 JDIMM2.172 JDIMM2.175 JDIMM2.176 JDIMM2.180 JDIMM2.181 JDIMM2.184 JDIMM2.185 JDIMM2.188 JDIMM2.189 JDIMM2.192 JDIMM2.193 JDIMM2.196 JDIMM2.197 JDIMM2.201 JDIMM2.202 JDIMM2.205 JDIMM2.206 JDIMM2.209 JDIMM2.210 JDIMM2.213 JDIMM2.214 JDIMM2.217 JDIMM2.218 JDIMM2.222 JDIMM2.223 JDIMM2.226 JDIMM2.227 JDIMM2.230 JDIMM2.231 JDIMM2.234 JDIMM2.235 JDIMM2.238 JDIMM2.239 JDIMM2.243 JDIMM2.244 JDIMM2.247 JDIMM2.248 JDIMM2.251 JDIMM2.252 JDIMM2.261 JDIMM2.262 JEDP.3 JEDP.6 JEDP.12 JEDP.28 JEDP.31 JEDP.32 JFAN.1 JFAN.5 JFAN.6 JFPR.5 JFPR.9 JFPR.10 JHDD.5 JHDD.8 JHDD.9 JHDD.10 JHDMI.2 JHDMI.5 JHDMI.8 JHDMI.11 JHDMI.17 JHDMI.20 JHDMI.21 JHDMI.22 JHDMI.23 JIO.7 JIO.10 JIO.13 JIO.16 JIO.19 JIO.22 JIO.25 JIO.27 JIO.28 JKB.33 JKB.34 JKBL.5 JKBL.6 JP6.1 JSPK.5 JSPK.6 JSSD.1 JSSD.3 JSSD.9 JSSD.15 JSSD.21 JSSD.27 JSSD.33 JSSD.39 JSSD.45 JSSD.51 JSSD.57 JSSD.63 JSSD.65 JSSD.67 JSSD.68 JSSD.69 JTC1.1 JTC1.2 JTC1.3 JTC1.4 JTC1.5 JTC1.6 JTC1.7 JTC1.8 JTC1.9 JTC1.10 JTC1.A1 JTC1.A12 JTC1.B1 JTC1.B12 JTP1.4 JTP1.11 JTP1.12 JTP2.4 JTP2.5 JTP2.6 JWLAN.1 JWLAN.7 JWLAN.13 JWLAN.18 JWLAN.19 JWLAN.25 JWLAN.31 JWLAN.37 JWLAN.43 JWLAN.49 JWLAN.55 JWLAN.61 JWLAN.67 JWLAN.68 JWLAN.69 LK2.1 PC1.2 PC2.2 PC3.2 PC4.2 PC5.2 PC6.2 PC8.2 PC9.2 PC10.2 PC11.2 PC301.2 PC303.2 PC304.2 PC305.2 PC306.2 PC307.2 PC308.2 PC309.2 PC310.2 PC311.2 PC314.2 PC315.2 PC316.2 PC317.2 PC318.2 PC319.2 PC322.2 PC323.2 PC324.2 PC325.2 PC327.2 PC328.2 PC329.2 PC330.2 PC331.2 PC1001.2 PC1003.2 PC1004.2 PC1005.2 PC1006.2 PC1008.2 PC1009.2 PC1011.2 PC1012.2 PC1013.2 PC1014.2 PC1016.2 PC1801.1 PC1803.2 PC1804.2 PC1805.2 PC1806.2 PC2501.1 PC2502.2 PC2503.2 PC2505.2 PC2506.2 PC2507.2 PCA1.2 PCA2.2 PCA4.2 PCA5.2 PCA6.2 PCA8.2 PCB1.2 PCB6.2 PCB7.2 PCB8.2 PCB11.2 PCB13.1 PCB14.2 PCB15.2 PCB16.2 PCB17.2 PCB18.2 PCB19.2 PCB21.2 PCB22.2 PCB23.2 PCB24.2 PCB25.2 PCG1.2 PCG4.2 PCG5.2 PCG9.2 PCG10.2 PCG12.2 PCM1.2 PCM2.2 PCM3.2 PCM5.2 PCM6.2 PCM7.1 PCM8.2 PCM9.2 PCM10.2 PCM11.2 PCM12.2 PCM13.2 PCM14.2 PCM15.2 PCM16.2 PCM17.2 PCM18.2 PCM19.2 PCM20.1 PCM21.1 PCV1.2 PCV2.2 PCV3.2 PCV5.2 PCV6.2 PCV9.2 PCV10.2 PCV11.2 PCV15.2 PCV16.2 PCV18.2 PCV19.2 PCV20.2 PCV22.2 PCV25.2 PCV28.2 PCV29.2 PCV30.2 PCV31.2 PCV32.2 PCV34.2 PCV35.2 PCV37.2 PCV38.2 PCV39.2 PCV40.2 PCV41.2 PCV42.2 PCV43.2 PCV44.2 PCV45.2 PCV46.2 PCV47.2 PCV48.2 PCV49.2 PCV50.2 PCV51.2 PCV52.2 PCV53.2 PCV56.2 PCV57.2 PCV58.2 PCV59.2 PCV60.2 PCV61.2 PCV66.2 PCV67.2 PCV68.2 PCV69.2 PCV70.2 PCV71.2 PCV72.2 PCV73.2 PCV74.2 PCV75.2 PCV76.2 PCW1.2 PCW2.2 PCW3.2 PCW4.2 PCW5.2 PCW7.2 PCW8.2 PCW9.2 PCW11.2 PCW12.2 PCW13.2 PCW14.2 PCW16.2 PCW17.2 PCW18.2 PCW19.2 PCZ1.2 PCZ3.1 PCZ4.2 PCZ7.2 PCZ9.1 PCZ13.1 PCZ15.2 PCZ16.1 PCZ18.2 PCZ19.2 PCZ23.2 PCZ26.2 PCZ29.2 PCZ30.2 PCZ31.2 PCZ32.2 PCZ33.2 PCZ34.2 PCZ36.2 PCZ37.2 PCZ40.2 PCZ41.2 PCZ44.2 PCZ45.2 PCZ47.2 PCZ68.2 PCZ69.2 PCZ70.2 PCZ71.2 PCZ72.2 PCZ73.2 PCZ74.2 PCZ75.2 PCZ76.2 PCZ77.2 PCZ78.2 PCZ79.2 PCZ80.2 PCZ81.2 PCZ82.2 PCZ85.2 PCZ86.2 PCZ87.2 PCZ88.2 PCZ89.2 PCZ90.2 PCZ91.2 PCZ93.2 PCZ94.2 PCZ95.2 PCZ96.2 PCZ97.2 PCZ98.2 PCZ99.2 PCZ100.2 PCZ101.2 PCZ102.2 PCZ103.2 PCZ104.2 PCZ109.2 PCZ110.2 PCZ111.2 PCZ112.2 PCZ113.2 PCZ114.2 PCZ115.2 PCZ116.2 PCZ117.2 PCZ119.2 PCZ127.2 PCZ131.2 PCZ132.2 PCZ134.2 PCZ135.2 PCZ136.2 PCZ137.2 PCZ140.2 PCZ141.2 PCZ142.2 PCZ143.2 PCZ144.2 PCZ145.2 PCZ146.2 PCZ150.2 PCZ154.2 PCZ155.2 PCZ157.2 PCZ158.2 PCZ159.2 PCZ160.2 PCZ161.2 PCZ162.2 PCZ163.2 PCZ164.2 PCZ165.2 PCZ166.2 PCZ167.2 PCZ168.2 PCZ169.2 PCZ170.2 PCZ171.2 PCZ172.2 PCZ173.2 PCZ174.2 PCZ175.2 PCZ176.2 PCZ177.2 PCZ178.2 PCZ179.2 PCZ180.2 PCZ181.2 PCZ182.2 PCZ183.2 PCZ184.2 PCZ185.2 PCZ186.2 PCZ187.2 PCZ188.2 PCZ189.2 PCZ190.2 PCZ191.2 PCZ192.2 PCZ193.2 PCZ194.2 PCZ195.2 PCZ196.2 PCZ197.2 PCZ198.2 PCZ199.2 PCZ200.2 PCZ201.2 PCZ202.2 PCZ203.2 PCZ204.2 PCZ205.2 PCZ206.2 PCZ207.2 PCZ208.2 PCZ209.2 PCZ210.2 PCZ211.2 PCZ212.2 PCZ213.2 PCZ214.2 PCZ215.2 PCZ227.2 PCZ228.1 PCZ229.2 PCZ230.2 PCZ233.2 PCZ234.2 PCZ235.2 PCZ236.2 PCZ237.2 PCZ238.2 PCZ239.2 PCZ240.2 PCZ243.2 PCZ244.2 PCZ245.2 PCZ246.2 PCZ247.2 PCZ248.2 PD1.1 PD2.1 PD3.2 PJP1.3 PJP1.4 PJP1.9 PJP1.10 PJPB1.7 PJPB1.8 PJPB1.9 PJPB1.10 PQ2.1 PQ2.4 PQA1.5 PQA1.6 PQA1.7 PQB1.5 PQB1.6 PQB1.7 PQG2.1 PQG2.2 PQG2.3 PQM1.5 PQM1.6 PQM1.7 PQV1.9 PQV2.9 PQZ2.1 PQZ2.2 PQZ2.3 PQZ4.1 PQZ4.2 PQZ4.3 PR2.2 PR5.2 PR6.2 PR13.2 PR21.2 PR309.2 PR313.2 PR1002.2 PR1004.2 PR1009.2 PR1805.2 PR1806.2 PR2503.2 PR2507.2 PRB2.1 PRB20.2 PRB21.2 PRM9.2 PRV26.2 PRV28.2 PRV33.2 PRW2.2 PRW4.2 PRW9.2 PRZ21.1 PRZ22.1 PRZ28.2 PRZ29.2 PRZ30.2 PRZ31.2 PRZ73.2 PRZ74.2 PRZ75.2 PRZ107.2 PU301.7 PU301.8 PU301.18 PU301.21 PU302.3 PU302.11 PU1001.7 PU1001.8 PU1001.18 PU1001.21 PU1801.2 PU2501.2 PUA1.6 PUA1.9 PUB1.14 PUB1.21 PUG1.6 PUG1.9 PUM1.1 PUM1.3 PUM1.14 PUM1.21 PUV1.21 PUW1.7 PUW1.8 PUW1.18 PUW1.21 PUZ1.49 PUZ2.6 PUZ2.9 PUZ3.6 PUZ3.9 Q9.3 Q21.11 Q21.15 Q5001.1 Q5001.4 QG1.4 QS1.3 QU3.3 QV30.1 QV30.4 QV50.3 QV146.3 QWL2.3 R163.2 R5176.2 R5179.2 R5180.2 RA6.1 RA7.1 RA17.2 RA51.1 RA52.1 RA54.1 RC5.2 RC6.2 RC38.2 RC39.2 RC40.2 RC51.2 RC76.1 RC96.2 RC100.1 RC101.2 RC119.2 RC123.1 RC124.1 RC128.2 RC132.1 RC185.2 RC193.2 RC218.2 RC227.1 RC388.2 RC398.2 RC399.2 RC401.2 RC402.2 RC421.2 RC473.2 RC474.2 RC480.2 RC481.2 RC482.2 RC484.2 RC485.2 RC486.1 RC487.1 RC488.1 RC489.1 RC901.1 RC936.2 RC940.1 RC956.1 RC957.1 RC958.1 RC979.2 RC983.2 RC984.2 RC986.2 RC987.2 RC1154.2 RC1156.1 RD3.2 RD5.2 RD6.2 RD10.1 RD11.1 RD22.2 RD23.2 RD24.2 RD28.1 RD29.1 RG56.2 RK4.1 RK26.2 RK27.2 RK108.1 RK115.1 RK116.1 RK117.1 RL11.1 RL55.2 RM11.1 RS46.2 RT11.2 RT12.2 RV20.2 RV21.2 RV42.1 RV43.1 RV64.2 RV65.2 RV67.2 RV70.2 RV71.2 RV88.1 RV102.2 RV116.2 RV118.2 RV119.2 RV120.2 RV121.2 RV127.2 RV205.2 RV206.2 RV218.1 RV376.2 RV378.2 RV380.2 RV381.2 RV383.2 RV385.2 RV387.2 RV388.2 RV390.2 RV579.2 RV2437.1 RV2438.1 RV2753.1 RV2758.2 RV2759.2 RV2760.2 RV2761.2 RV2767.2 RV2768.2 RWL2.2 SW1.3 SW1.4 SW1.5 SW1.6 U4018.1 UA1.41 UC1.A3 UC1.A4 UC1.A32 UC1.A36 UC1.AB3 UC1.AB4 UC1.AB7 UC1.AB27 UC1.AB30 UC1.AB33 UC1.AB36 UC1.AC5 UC1.AC10 UC1.AC27 UC1.AC30 UC1.AD33 UC1.AD35 UC1.AE7 UC1.AE24 UC1.AE25 UC1.AE26 UC1.AE27 UC1.AE30 UC1.AF3 UC1.AF4 UC1.AF7 UC1.AF25 UC1.AF27 UC1.AF30 UC1.AF33 UC1.AF36 UC1.AG5 UC1.AG10 UC1.AG24 UC1.AG26 UC1.AH24 UC1.AH25 UC1.AH27 UC1.AH28 UC1.AH29 UC1.AH30 UC1.AH31 UC1.AH33 UC1.AH35 UC1.AJ7 UC1.AJ25 UC1.AJ28 UC1.AK3 UC1.AK4 UC1.AK33 UC1.AK36 UC1.AL7 UC1.AL28 UC1.AL29 UC1.AL32 UC1.AM5 UC1.AM10 UC1.AM28 UC1.AM33 UC1.AM35 UC1.AN7 UC1.AN8 UC1.AN25 UC1.AN28 UC1.AN29 UC1.AN30 UC1.AN31 UC1.AP3 UC1.AP4 UC1.AP33 UC1.AP36 UC1.AR4 UC1.AR28 UC1.AT4 UC1.AT33 UC1.AT35 UC1.AT36 UC1.AU4 UC1.AU10 UC1.AU28 UC1.AU29 UC1.AU32 UC1.AV3 UC1.AV4 UC1.AV6 UC1.AV8 UC1.AV25 UC1.AV28 UC1.AV33 UC1.AV36 UC1.AW1 UC1.AW3 UC1.AW4 UC1.AW28 UC1.AW29 UC1.AW30 UC1.AW31 UC1.AY4 UC1.AY33 UC1.AY35 UC1.B2 UC1.B5 UC1.B7 UC1.B9 UC1.B12 UC1.B15 UC1.B18 UC1.B21 UC1.B23 UC1.B25 UC1.B27 UC1.B29 UC1.B31 UC1.B34 UC1.B36 UC1.B37 UC1.BA3 UC1.BA4 UC1.BA6 UC1.BA10 UC1.BA28 UC1.BB3 UC1.BB4 UC1.BB33 UC1.BB36 UC1.BC4 UC1.BC8 UC1.BC25 UC1.BC29 UC1.BC32 UC1.BD4 UC1.BD6 UC1.BD7 UC1.BD28 UC1.BD33 UC1.BD35 UC1.BD36 UC1.BE3 UC1.BE4 UC1.BE8 UC1.BE10 UC1.BE28 UC1.BE29 UC1.BE30 UC1.BE31 UC1.BF3 UC1.BF4 UC1.BF33 UC1.BF36 UC1.BG4 UC1.BG25 UC1.BG28 UC1.BH28 UC1.BH29 UC1.BH32 UC1.BH33 UC1.BH35 UC1.BJ7 UC1.BK2 UC1.BK3 UC1.BK4 UC1.BK7 UC1.BK10 UC1.BK28 UC1.BK33 UC1.BL7 UC1.BL25 UC1.BL28 UC1.BL29 UC1.BL30 UC1.BL31 UC1.BL32 UC1.BM9 UC1.BM33 UC1.BM35 UC1.BM36 UC1.BN7 UC1.BN30 UC1.BP3 UC1.BP4 UC1.BP7 UC1.BP12 UC1.BP15 UC1.BP19 UC1.BP25 UC1.BP32 UC1.BP33 UC1.BP36 UC1.BR16 UC1.BR19 UC1.BR22 UC1.BR25 UC1.BT5 UC1.BT14 UC1.BT15 UC1.BT16 UC1.BT25 UC1.BT28 UC1.BT33 UC1.BT35 UC1.BT36 UC1.BU7 UC1.BU11 UC1.BU16 UC1.BU20 UC1.BU23 UC1.BU24 UC1.BU25 UC1.BV3 UC1.BV4 UC1.BV11 UC1.BV31 UC1.BV33 UC1.BW7 UC1.BW11 UC1.BW15 UC1.BW24 UC1.BY5 UC1.BY11 UC1.BY15 UC1.BY18 UC1.BY19 UC1.BY22 UC1.BY25 UC1.BY28 UC1.BY33 UC1.BY35 UC1.BY36 UC1.C1 UC1.C4 UC1.C9 UC1.C21 UC1.C25 UC1.C29 UC1.C33 UC1.C36 UC1.C37 UC1.CA11 UC1.CA15 UC1.CA22 UC1.CA25 UC1.CB2 UC1.CB3 UC1.CB4 UC1.CB7 UC1.CB11 UC1.CB18 UC1.CB19 UC1.CB20 UC1.CB24 UC1.CB25 UC1.CB33 UC1.CC7 UC1.CC11 UC1.CC14 UC1.CC16 UC1.CC20 UC1.CC24 UC1.CC25 UC1.CC28 UC1.CC31 UC1.CD11 UC1.CD12 UC1.CD14 UC1.CD20 UC1.CD24 UC1.CD25 UC1.CE7 UC1.CE33 UC1.CE35 UC1.CE36 UC1.CF2 UC1.CF3 UC1.CF4 UC1.CF11 UC1.CF14 UC1.CF19 UC1.CF23 UC1.CF28 UC1.CG7 UC1.CG33 UC1.CH31 UC1.CJ2 UC1.CJ3 UC1.CJ4 UC1.CJ11 UC1.CJ14 UC1.CJ19 UC1.CJ23 UC1.CJ28 UC1.CJ33 UC1.CJ35 UC1.CJ36 UC1.CK1 UC1.CK4 UC1.CK7 UC1.CK37 UC1.CL2 UC1.CM1 UC1.CM4 UC1.CM5 UC1.CM9 UC1.CM13 UC1.CM17 UC1.CM21 UC1.CM25 UC1.CM29 UC1.CM31 UC1.CM33 UC1.CM37 UC1.CN1 UC1.CN2 UC1.CN5 UC1.CN9 UC1.CN13 UC1.CN17 UC1.CN21 UC1.CN25 UC1.CN29 UC1.CN37 UC1.CP1 UC1.CP2 UC1.CP9 UC1.CP11 UC1.CP13 UC1.CP15 UC1.CP19 UC1.CP21 UC1.CP27 UC1.CP35 UC1.CP37 UC1.CR2 UC1.CR6 UC1.CR34 UC1.CR36 UC1.D1 UC1.D5 UC1.D6 UC1.D8 UC1.D9 UC1.D21 UC1.D25 UC1.E9 UC1.E23 UC1.E27 UC1.E29 UC1.E31 UC1.E33 UC1.E35 UC1.F2 UC1.F3 UC1.F4 UC1.F12 UC1.F15 UC1.F18 UC1.F21 UC1.F24 UC1.F33 UC1.G9 UC1.G21 UC1.G27 UC1.G33 UC1.G35 UC1.G36 UC1.H9 UC1.H21 UC1.H27 UC1.J5 UC1.J6 UC1.J12 UC1.J15 UC1.J18 UC1.J21 UC1.J24 UC1.J33 UC1.J36 UC1.K3 UC1.K4 UC1.K9 UC1.K21 UC1.K22 UC1.K24 UC1.K25 UC1.K27 UC1.K28 UC1.K29 UC1.K30 UC1.K31 UC1.K32 UC1.L6 UC1.L27 UC1.L33 UC1.L35 UC1.L36 UC1.N6 UC1.N25 UC1.N27 UC1.P3 UC1.P4 UC1.P7 UC1.P10 UC1.P33 UC1.P36 UC1.R27 UC1.R28 UC1.R29 UC1.R30 UC1.R31 UC1.T7 UC1.T27 UC1.T30 UC1.T33 UC1.T35 UC1.T36 UC1.U7 UC1.U24 UC1.U26 UC1.V3 UC1.V4 UC1.V26 UC1.V27 UC1.V30 UC1.V33 UC1.V36 UC1.W7 UC1.W10 UC1.W27 UC1.W30 UC1.Y7 UC1.Y26 UC1.Y27 UC1.Y30 UC1.Y33 UC1.Y35 UC2.4 UC3.3 UC4.3 UC6.11 UC6.15 UC7.5 UC11.2 UG1.2 UK1.11 UK1.24 UK1.35 UK1.94 UK1.113 UL1.33 UL2.2 UT1.2 UT1.9 UT1.16 UT1.23 UT1.32 UT1.33 UU1.12 UU1.21 UU2.2 UV1.A2 UV1.A26 UV1.AA7 UV1.AB7 UV1.AB11 UV1.AB14 UV1.AB17 UV1.AB20 UV1.AB24 UV1.AC2 UV1.AC5 UV1.AC8 UV1.AC22 UV1.AC26 UV1.AD12 UV1.AD13 UV1.AD15 UV1.AD16 UV1.AD18 UV1.AD19 UV1.AD21 UV1.AD22 UV1.AE11 UV1.AE14 UV1.AE17 UV1.AE20 UV1.AF1 UV1.AF5 UV1.AF8 UV1.AF11 UV1.AF14 UV1.AF17 UV1.AF20 UV1.AF23 UV1.AG2 UV1.AG26 UV1.B1 UV1.B5 UV1.B8 UV1.B11 UV1.B14 UV1.B17 UV1.B20 UV1.B23 UV1.B27 UV1.E2 UV1.E5 UV1.E8 UV1.E11 UV1.E14 UV1.E17 UV1.E20 UV1.E22 UV1.E25 UV1.H2 UV1.H5 UV1.H23 UV1.H25 UV1.K11 UV1.K13 UV1.K15 UV1.K17 UV1.L2 UV1.L5 UV1.L10 UV1.L12 UV1.L14 UV1.L16 UV1.L18 UV1.L23 UV1.L25 UV1.M11 UV1.M13 UV1.M15 UV1.M17 UV1.N10 UV1.N12 UV1.N14 UV1.N16 UV1.N18 UV1.P2 UV1.P5 UV1.P11 UV1.P13 UV1.P15 UV1.P17 UV1.P23 UV1.P26 UV1.R10 UV1.R12 UV1.R14 UV1.R16 UV1.R18 UV1.T11 UV1.T13 UV1.T15 UV1.T17 UV1.U2 UV1.U5 UV1.U10 UV1.U12 UV1.U14 UV1.U16 UV1.U18 UV1.U23 UV1.U26 UV1.V11 UV1.V13 UV1.V15 UV1.V17 UV1.Y2 UV1.Y5 UV1.Y23 UV1.Y26 UV6.A1 UV6.A3 UV6.A12 UV6.A14 UV6.B5 UV6.B10 UV6.C1 UV6.C3 UV6.C4 UV6.C11 UV6.C12 UV6.C14 UV6.D10 UV6.E1 UV6.E3 UV6.E12 UV6.E14 UV6.F5 UV6.F10 UV6.G5 UV6.G10 UV6.H1 UV6.H2 UV6.H13 UV6.H14 UV6.K1 UV6.K2 UV6.K13 UV6.K14 UV6.L5 UV6.L10 UV6.M5 UV6.M10 UV6.N1 UV6.N3 UV6.N12 UV6.N14 UV6.P10 UV6.R1 UV6.R3 UV6.R4 UV6.R11 UV6.R12 UV6.R14 UV6.T5 UV6.T10 UV6.U1 UV6.U3 UV6.U12 UV6.U14 UV7.A1 UV7.A3 UV7.A12 UV7.A14 UV7.B5 UV7.B10 UV7.C1 UV7.C3 UV7.C4 UV7.C11 UV7.C12 UV7.C14 UV7.D10 UV7.E1 UV7.E3 UV7.E12 UV7.E14 UV7.F5 UV7.F10 UV7.G5 UV7.G10 UV7.H1 UV7.H2 UV7.H13 UV7.H14 UV7.K1 UV7.K2 UV7.K13 UV7.K14 UV7.L5 UV7.L10 UV7.M5 UV7.M10 UV7.N1 UV7.N3 UV7.N12 UV7.N14 UV7.P10 UV7.R1 UV7.R3 UV7.R4 UV7.R11 UV7.R12 UV7.R14 UV7.T5 UV7.T10 UV7.U1 UV7.U3 UV7.U12 UV7.U14 UV12.3 UV15.3 UV23.3 YC2.2 YC2.4
GND_SENSE_GPU: PRV18.1 UV1.F1
GNDA: CA5.2 CA6.2 CA7.2 CA8.2 CA9.2 CA10.2 CA11.2 CA12.2 CA13.2 CA24.2 CA25.2 CA26.2 CA27.2 CA29.1 CA30.1 CA31.1 CA47.2 JHP.4 JHP.6 JHP.7 JHP.8 RA6.2 RA7.2 RA24.1 RA51.2 RA52.2 RA54.2 UA1.13 UA1.19 UA1.31
PVCC_NVVDD: PCV22.1 PRV14.1 PUV1.18
VCC_1V: PC1008.1 PU1001.16 PU1001.17
VCC_5V: PC318.1 PU302.10
VCC_CHG: PCB13.2 PRB6.2 PUB1.20
VCC_CORE1: PCZ40.1 PRZ80.2 PUZ2.8
VCC_CORE2: PCZ41.1 PRZ81.2 PUZ3.8
VCC_GT: PCG1.1 PRG1.2 PUG1.8
VCC_SA: PCA1.1 PRA1.2 PUA1.8
VCC_VRAM: PCW9.1 PUW1.16 PUW1.17
VCCCORE_SENSE: PRZ47.1 UC1.AN6
VCCDPHY_EC_1P24: CC320.1 RC977.1 UC1.CP25
VCCGT_SENSE: PRZ50.2 UC1.E3
VCCSA_SENSE: PRZ15.1 UC1.BG7
VCCSA_SENSE_R: PCZ5.1 PRZ1.2 PRZ8.1 PRZ15.2
VDD_DDR: PCM3.1 PCM16.1 PCM19.1 PRM2.1 PRM4.2 PUM1.11
VDD_SENSE_GPU: PRV24.1 UV1.F2
VDDP_DDR: PCM7.2 PCM20.2 PCM21.2 PRM5.2 PUM1.12
VSSCORE_SENSE: PRZ95.1 UC1.AN5
VSSGT_SENSE: PRZ93.2 UC1.D2
VSSSA_SENSE: PRZ94.1 UC1.BE7
+EC_VCCA: CK3.1 LK1.2 UK1.67
+FAN1: C4801.1 C5214.1 JFAN.4 R5261.2 R5262.2 RE51.1
+FB_VREFC0: CV158.1 CV159.1 RV125.2 RV127.1 RV200.2 UV6.J14 UV7.J14
+HDMI_CRT_5V: CG46.1 CG47.1 FG1.3 JHDMI.18 RG105.1 RG109.1
+LAN_REGOUT: LL2.1 UL1.24
+LAN_VDD_1V0: CL8.1 CL11.1 CL12.1 CL13.1 CL14.1 CL15.1 CL23.1 CL26.1 CL27.1 CL29.1 LL2.2 UL1.3 UL1.8 UL1.22 UL1.30
+LAN_VDD_3V3: CL5.1 CL9.1 CL10.1 CL16.1 CL19.1 CL20.1 DM12.5 DM13.5 JL33.2 JLAN.A1 JLAN.B1 RL15.1 RL56.2 UL1.11 UL1.23 UL1.32 UL2.1
+LCDVDD: C5231.1 CG2.1 CG3.1 JEDP.9 JEDP.10 UG1.1
+RTCVCC: CC7.2 CC324.2 DC1.1 RC91.1 RC93.1 RC94.1 RC462.2 UC1.BR23
+V_DAC: CL1.2 CL4.1 TSL1.1 TSL1.4 TSL1.7 TSL1.10
+VGA_CORE: PCV28.1 PCV29.1 PCV30.1 PCV31.1 PCV32.1 PCV34.1 PCV35.1 PCV37.1 PCV38.1 PCV39.1 PCV40.1 PCV41.1 PCV42.1 PCV43.1 PCV44.1 PCV45.1 PCV46.1 PCV47.1 PCV48.1 PCV49.1 PCV50.1 PCV51.1 PCV52.1 PCV53.1 PCV56.1 PCV57.1 PCV58.1 PCV59.1 PCV60.1 PCV61.1 PCV66.1 PCV67.1 PCV68.1 PCV69.1 PCV70.1 PCV71.1 PCV72.1 PCV73.1 PCV74.1 PCV75.1 PCV76.1 PLV3.3 PLV3.4 PLV4.3 PLV4.4 RV217.1 UV1.K10 UV1.K12 UV1.K14 UV1.K16 UV1.K18 UV1.L11 UV1.L13 UV1.L15 UV1.L17 UV1.M10 UV1.M12 UV1.M14 UV1.M16 UV1.M18 UV1.N11 UV1.N13 UV1.N15 UV1.N17 UV1.P10 UV1.P12 UV1.P14 UV1.P16 UV1.P18 UV1.R11 UV1.R13 UV1.R15 UV1.R17 UV1.T10 UV1.T12 UV1.T14 UV1.T16 UV1.T18 UV1.U11 UV1.U13 UV1.U15 UV1.U17 UV1.V10 UV1.V12 UV1.V14 UV1.V16 UV1.V18
A4WP_PRESENT: RC936.1 UC1.CF17
AC_LED#: PR1.1 PR2.1 UK1.34
AC_PRESENT_R: RC106.2 RC108.1 UC1.BU35
ACDET_CHG: PCB22.1 PRB17.2 PRB21.1 PUB1.6
ACDRV_CHG: PRB9.2 PUB1.4
ACDRV_CHG_R: PCB4.2 PCB5.2 PQB2.1 PQB11.4 PQB12.4 PRB9.1
ACIN: RC108.2 UK1.93
ACIN_LED: PD1.2 PJP1.8 PR1.2
ACN_CHG: PCB10.2 PCB11.1 PRB1.3 PUB1.1
ACP_CHG: PCB1.1 PCB10.1 PRB1.2 PUB1.2
ADP_I: PCB24.1 PR10.1 PRB22.2 UK1.65
ADP_ID: PC5.1 PC6.1 PD3.1 PR3.2 PR5.1 UK1.75
ADP_SIGNAL: PD2.3 PJP1.6 PR3.1
AISP1: PCG8.1 PRG7.1 PRG9.2 PUZ1.29
AISP1_R: PLG1.2 PRG6.1
AISPCORE1: PCZ42.1 PRZ88.1 PRZ102.2 PUZ1.10
AISPCORE1_R: PLZ1.2 PRZ85.1 PRZ108.2
AISPCORE2: PCZ43.1 PRZ90.1 PRZ103.2 PRZ104.2 PUZ1.9
AISPCORE2_R: PLZ2.2 PRZ87.1 PRZ109.2
AISPVCCSA: PCA7.1 PRA7.1 PRA9.2 PUZ1.40
AISPVCCSA_R: PLA1.2 PRA6.1
AVCORE1: PCZ13.2 PCZ42.2 PLZ1.3 PRZ88.2 PUZ1.7
AVCORE2: PCZ16.2 PCZ43.2 PLZ2.3 PRZ90.2 PRZ106.1
AVGT1: PCG8.2 PCZ18.1 PHG1.2 PLG1.3 PRG8.2 PUZ1.28
AVGT1_R: PHG1.1 PRG7.2 PRG8.1
B/I#: PR16.2 PR17.2 UK1.63
B/I#_R: PJPB1.6 PR17.1
BAT_CHG_LED: PR4.1 PR6.1 UK1.90
BATDRV_CHG: PRB5.1 PUB1.11
BATDRV_CHG_R: PCB9.2 PQB13.4 PRB5.2
BKL_PWM_CPU: R259.1 UC1.CH11
BOARD_ID: RK2.1 RK4.2 UK1.66
BST1_NVVDD: PRV12.1 PUV1.1
BST1_NVVDD-R: PCV14.1 PRV12.2
BST2_NVVDD: PRV20.1 PUV1.15
BST2_NVVDD-R: PCV24.2 PRV20.2
BST_1V: PR1006.1 PU1001.1
BST_1V_R: PC1007.1 PR1006.2
BST_3V: PR302.1 PU301.1
BST_3V_R: PC302.1 PR302.2
BST_5V: PR306.1 PU302.13
BST_5V_R: PC313.1 PR306.2
BST_DDR: PRM1.2 PUM1.18
BST_DDR_R: PCM4.1 PRM1.1
BST_VRAM: PRW7.1 PUW1.1
BST_VRAM_R: PCW6.1 PRW7.2
BT_ON_EC: JWLAN.46 RN15.2 UK1.121
BTST_CHG: PRB7.2 PUB1.17
CAP_LOCK#: R203.1 UK1.91
CAP_LOCK#_R: CC122.1 JKB.5 R203.2
CATERR#: RC935.1 UC1.AA4
CBN: CA16.2 CA48.2 UA1.28
CBP: CA16.1 CA48.1 UA1.30
CC1: D33.4 D33.7 JTC1.A5 UU1.11
CC2: D33.2 D33.8 JTC1.B5 UU1.13
CFG0: RC480.1 RC1157.2 UC1.T4
CFG1: RC481.1 UC1.R4
CFG2: RC486.2 UC1.T3
CFG3: RC482.1 UC1.R3
CFG4: RC193.1 UC1.J4
CFG5: RC487.2 UC1.M4
CFG6: RC488.2 UC1.J3
CFG7: RC489.2 UC1.M3
CFG8: T365.1(TP-1) UC1.R2
CFG9: T366.1(TP-1) UC1.N2
CFG10: T367.1(TP-1) UC1.R1
CFG11: T368.1(TP-1) UC1.N1
CFG12: T369.1(TP-1) UC1.J2
CFG13: T370.1(TP-1) UC1.L2
CFG14: T371.1(TP-1) UC1.J1
CFG15: T372.1(TP-1) UC1.L1
CFG16: T323.1(TP-1) UC1.L3
CFG17: T324.1(TP-1) UC1.L4
CFG18: T325.1(TP-1) UC1.N3
CFG19: T326.1(TP-1) UC1.N4
CFG_RCOMP: RC185.1 UC1.AB5
CHARGE_LED: PD1.3 PJP1.7 PR4.2
CHG: PLB1.2 PRB11.1
CHG_N001: PCB12.2 PDB2.1 PRB7.1
CHG_N002: PQB2.2 PRB2.2 PRB3.1
CHG_N003: PDB1.1 PRB6.1
CL_CK_R: T327.1(TP-1) UC1.CH7
CL_DATA_R: T328.1(TP-1) UC1.CH8
CL_RST_N_R: T329.1(TP-1) UC1.CH9
CLK_PCI0: RC457.1 UC1.BV32
CLK_PCI_LPC: CC256.1 RC457.2 RK109.2 UK1.12
CLK_PCIE_N1: UC1.BC1 UL1.16
CLK_PCIE_N2: C5185.1 JWLAN.41 UC1.BD3
CLK_PCIE_N3: JSSD.53 UC1.BH3
CLK_PCIE_P1: UC1.BC2 UL1.15
CLK_PCIE_P2: C5186.1 JWLAN.39 UC1.BC3
CLK_PCIE_P3: JSSD.55 UC1.BH4
CLK_PCIE_XDP_DN: T306.1(TP-1) UC1.AU1
CLK_PCIE_XDP_DP: T307.1(TP-1) UC1.AU2
CLK_PEG_N0: UC1.AW2 UV1.AD8
CLK_PEG_P0: UC1.AY3 UV1.AE8
CLKIN_XTAL_LCP: JWLAN.56 RC957.2 UC1.CM3
CLKREQ_PCIE#0_R: QV3.3 RV68.2 RV375.1 UV1.AC6
CLKREQ_PCIE#1: RC954.2 UC1.CE32 UL1.12
CLKREQ_PCIE#2: JWLAN.45 RC953.2 UC1.CF30
CLKREQ_PCIE#3: JSSD.52 RC955.2 UC1.CE31
CLKREQ_PCIE#4: RC165.2 UC1.CE30
CLKREQ_PCIE#5: RC105.2 UC1.CF31
CLKREQ_PEG#0: QV3.1 RC952.2 RV375.2 UC1.CF32
CLR_CMOS#: JCMOS1.1 R1088.1 R1089.1 UK1.27
CMSRC_CHG: PRB10.2 PUB1.3
CNV_WT_RCOMP: RC132.2 UC1.CP32 UC1.CR32
CNVI_BRI_DT: RC404.1 RW8.2 UC1.CJ20
CNVI_BRI_DT_R: JWLAN.28 RW8.1
CNVI_BRI_RSP: RW5.2 UC1.CK20
CNVI_BRI_RSP_R: JWLAN.22 RC72.1 RW5.1 RW11.1
CNVI_RF_RESET_N: RC401.1 RW3.2 UC1.CJ32
CNVI_RF_RESET_R_N: JWLAN.10 RW3.1
CNVI_RGI_DT: RC1155.1 RW6.2 UC1.CG19
CNVI_RGI_DT_R: JWLAN.24 RC183.1 RW6.1 RW12.1
CNVI_RGI_RSP: RC403.2 RW7.2 UC1.CH19
CNVI_RGI_RSP_R: JWLAN.26 RW7.1
CNVI_WGR_CLK_DN: JWLAN.21 UC1.CN31
CNVI_WGR_CLK_DP: JWLAN.23 UC1.CP31
CNVI_WGR_DATA0_DN: JWLAN.15 UC1.CR30
CNVI_WGR_DATA0_DP: JWLAN.17 UC1.CP30
CNVI_WGR_DATA1_DN: JWLAN.9 UC1.CM30
CNVI_WGR_DATA1_DP: JWLAN.11 UC1.CN30
CNVI_WT_CLK_DN: JWLAN.63 UC1.CP34
CNVI_WT_CLK_DP: JWLAN.65 UC1.CN34
CNVI_WT_DATA0_DN: JWLAN.57 UC1.CN32
CNVI_WT_DATA0_DP: JWLAN.59 UC1.CM32
CNVI_WT_DATA1_DN: JWLAN.51 UC1.CP33
CNVI_WT_DATA1_DP: JWLAN.53 UC1.CN33
COMP_CORE: PCZ12.2 PRZ45.2 PUZ1.4
COMP_GT: PCZ20.1 PRZ54.1 PUZ1.26
COMP_SA: PCZ6.2 PRZ10.2 PUZ1.43
CORE1_BST: PRZ76.1 PUZ2.4
CORE1_BST_R: PCZ28.1 PRZ76.2
CORE1_LG: PQZ2.4 PUZ2.7
CORE1_LX: PCZ28.2 PLZ1.1 PQZ1.1 PQZ1.2 PQZ1.3 PQZ2.5 PRZ82.1 PUZ2.2
CORE1_SNUB: PCZ44.1 PRZ82.2
CORE1_UG: PQZ1.4 PUZ2.3
CORE2_BST: PRZ77.1 PUZ3.4
CORE2_BST_R: PCZ35.1 PRZ77.2
CORE2_LG: PQZ4.4 PUZ3.7
CORE2_LX: PCZ35.2 PLZ2.1 PQZ3.1 PQZ3.2 PQZ3.3 PQZ4.5 PRZ84.1 PUZ3.2
CORE2_SNUB: PCZ45.1 PRZ84.2
CORE2_UG: PRZ79.1 PUZ3.3
CORE2_UG_R: PQZ3.4 PRZ79.2
CPU_C10_GATE#: RC985.2 UC1.CN27
CPU_POPIRCOMP: RC5.1 UC1.BP27
CPU_XDP_TCK0: RC398.1 UC1.P6 UC1.T6
CPVEE: CA15.2 UA1.27
CS_DDR: PRM2.2 PUM1.13
D_MIC_CLK: CA41.1 DM1.2 JEDP.29 LA6.2
D_MIC_CLK_R: LA6.1 UA1.3
D_MIC_DATA: DM1.3 JEDP.30 UA1.2
DDI2_HPD: T408.1(TP-1) UC1.CM6
DDI3_HPD: T2404.1(TP-1) UC1.CP7
DDR_DRAMRST#: CC359.1 CD10.1 CD92.1 JDIMM1.108 JDIMM2.108 RC32.2 UC1.BU31
DDR_M0_ACT#: JDIMM1.114 UC1.V35
DDR_M0_ALERT#: JDIMM1.116 UC1.W37
DDR_M0_BA0: JDIMM1.150 UC1.W32
DDR_M0_BA1: JDIMM1.145 UC1.AB31
DDR_M0_BG0: JDIMM1.115 UC1.V34
DDR_M0_BG1: JDIMM1.113 UC1.W35
DDR_M0_CKE0: JDIMM1.109 UC1.U36
DDR_M0_CKE1: JDIMM1.110 UC1.U37
DDR_M0_CLK0: JDIMM1.137 UC1.V31
DDR_M0_CLK1: JDIMM1.138 UC1.T31
DDR_M0_CLK#0: JDIMM1.139 UC1.V32
DDR_M0_CLK#1: JDIMM1.140 UC1.T32
DDR_M0_CS#0: JDIMM1.149 UC1.AE32
DDR_M0_CS#1: JDIMM1.157 UC1.AF32
DDR_M0_D0: JDIMM1.7 UC1.A26
DDR_M0_D1: JDIMM1.16 UC1.D26
DDR_M0_D2: JDIMM1.4 UC1.D28
DDR_M0_D3: JDIMM1.17 UC1.C28
DDR_M0_D4: JDIMM1.3 UC1.B26
DDR_M0_D5: JDIMM1.8 UC1.C26
DDR_M0_D6: JDIMM1.21 UC1.B28
DDR_M0_D7: JDIMM1.20 UC1.A28
DDR_M0_D8: JDIMM1.24 UC1.B30
DDR_M0_D9: JDIMM1.25 UC1.D30
DDR_M0_D10: JDIMM1.42 UC1.B33
DDR_M0_D11: JDIMM1.41 UC1.D32
DDR_M0_D12: JDIMM1.28 UC1.A30
DDR_M0_D13: JDIMM1.29 UC1.C30
DDR_M0_D14: JDIMM1.37 UC1.B32
DDR_M0_D15: JDIMM1.38 UC1.C32
DDR_M0_D16: JDIMM1.45 UC1.H37
DDR_M0_D17: JDIMM1.50 UC1.H34
DDR_M0_D18: JDIMM1.63 UC1.K34
DDR_M0_D19: JDIMM1.58 UC1.K35
DDR_M0_D20: JDIMM1.49 UC1.H36
DDR_M0_D21: JDIMM1.46 UC1.H35
DDR_M0_D22: JDIMM1.62 UC1.K36
DDR_M0_D23: JDIMM1.59 UC1.K37
DDR_M0_D24: JDIMM1.67 UC1.N36
DDR_M0_D25: JDIMM1.66 UC1.N34
DDR_M0_D26: JDIMM1.83 UC1.R37
DDR_M0_D27: JDIMM1.79 UC1.R34
DDR_M0_D28: JDIMM1.71 UC1.N37
DDR_M0_D29: JDIMM1.70 UC1.N35
DDR_M0_D30: JDIMM1.84 UC1.R36
DDR_M0_D31: JDIMM1.80 UC1.R35
DDR_M0_D32: JDIMM1.174 UC1.AN35
DDR_M0_D33: JDIMM1.169 UC1.AN34
DDR_M0_D34: JDIMM1.187 UC1.AR35
DDR_M0_D35: JDIMM1.183 UC1.AR34
DDR_M0_D36: JDIMM1.170 UC1.AN37
DDR_M0_D37: JDIMM1.173 UC1.AN36
DDR_M0_D38: JDIMM1.182 UC1.AR36
DDR_M0_D39: JDIMM1.186 UC1.AR37
DDR_M0_D40: JDIMM1.190 UC1.AU35
DDR_M0_D41: JDIMM1.191 UC1.AU34
DDR_M0_D42: JDIMM1.207 UC1.AW35
DDR_M0_D43: JDIMM1.208 UC1.AW34
DDR_M0_D44: JDIMM1.195 UC1.AU37
DDR_M0_D45: JDIMM1.194 UC1.AU36
DDR_M0_D46: JDIMM1.203 UC1.AW36
DDR_M0_D47: JDIMM1.204 UC1.AW37
DDR_M0_D48: JDIMM1.215 UC1.BA35
DDR_M0_D49: JDIMM1.212 UC1.BA34
DDR_M0_D50: JDIMM1.229 UC1.BC35
DDR_M0_D51: JDIMM1.225 UC1.BC34
DDR_M0_D52: JDIMM1.211 UC1.BA37
DDR_M0_D53: JDIMM1.216 UC1.BA36
DDR_M0_D54: JDIMM1.228 UC1.BC36
DDR_M0_D55: JDIMM1.224 UC1.BC37
DDR_M0_D56: JDIMM1.232 UC1.BE35
DDR_M0_D57: JDIMM1.236 UC1.BE34
DDR_M0_D58: JDIMM1.245 UC1.BG35
DDR_M0_D59: JDIMM1.249 UC1.BG34
DDR_M0_D60: JDIMM1.237 UC1.BE37
DDR_M0_D61: JDIMM1.233 UC1.BE36
DDR_M0_D62: JDIMM1.250 UC1.BG36
DDR_M0_D63: JDIMM1.246 UC1.BG37
DDR_M0_DQS0: JDIMM1.13 UC1.D27
DDR_M0_DQS1: JDIMM1.34 UC1.C31
DDR_M0_DQS2: JDIMM1.55 UC1.J34
DDR_M0_DQS3: JDIMM1.76 UC1.P35
DDR_M0_DQS4: JDIMM1.179 UC1.AP34
DDR_M0_DQS5: JDIMM1.200 UC1.AV35
DDR_M0_DQS6: JDIMM1.221 UC1.BB34
DDR_M0_DQS7: JDIMM1.242 UC1.BF35
DDR_M0_DQS#0: JDIMM1.11 UC1.C27
DDR_M0_DQS#1: JDIMM1.32 UC1.D31
DDR_M0_DQS#2: JDIMM1.53 UC1.J35
DDR_M0_DQS#3: JDIMM1.74 UC1.P34
DDR_M0_DQS#4: JDIMM1.177 UC1.AP35
DDR_M0_DQS#5: JDIMM1.198 UC1.AV34
DDR_M0_DQS#6: JDIMM1.219 UC1.BB35
DDR_M0_DQS#7: JDIMM1.240 UC1.BF34
DDR_M0_MA0: JDIMM1.144 UC1.AC37
DDR_M0_MA1: JDIMM1.133 UC1.AC36
DDR_M0_MA2: JDIMM1.132 UC1.AC34
DDR_M0_MA3: JDIMM1.131 UC1.AC35
DDR_M0_MA4: JDIMM1.128 UC1.AA35
DDR_M0_MA5: JDIMM1.126 UC1.AB35
DDR_M0_MA6: JDIMM1.127 UC1.AA37
DDR_M0_MA7: JDIMM1.122 UC1.AA36
DDR_M0_MA8: JDIMM1.125 UC1.AB34
DDR_M0_MA9: JDIMM1.121 UC1.W36
DDR_M0_MA10: JDIMM1.146 UC1.Y31
DDR_M0_MA11: JDIMM1.120 UC1.W34
DDR_M0_MA12: JDIMM1.119 UC1.AA34
DDR_M0_MA13: JDIMM1.158 UC1.AC32
DDR_M0_MA14_WE#: JDIMM1.151 UC1.AC31
DDR_M0_MA15_CAS#: JDIMM1.156 UC1.AB32
DDR_M0_MA16_RAS#: JDIMM1.152 UC1.Y32
DDR_M0_ODT0: JDIMM1.155 UC1.AE31
DDR_M0_ODT1: JDIMM1.161 UC1.AF31
DDR_M0_PAR: JDIMM1.143 UC1.W31
DDR_M1_ACT#: JDIMM2.114 UC1.W28
DDR_M1_ALERT#: JDIMM2.116 UC1.Y29
DDR_M1_BA0: JDIMM2.150 UC1.AJ37
DDR_M1_BA1: JDIMM2.145 UC1.AJ36
DDR_M1_BG0: JDIMM2.115 UC1.W29
DDR_M1_BG1: JDIMM2.113 UC1.Y28
DDR_M1_CKE0: JDIMM2.109 UC1.T28
DDR_M1_CKE1: JDIMM2.110 UC1.T29
DDR_M1_CLK0: JDIMM2.137 UC1.AF29
DDR_M1_CLK1: JDIMM2.138 UC1.AE29
DDR_M1_CLK#0: JDIMM2.139 UC1.AF28
DDR_M1_CLK#1: JDIMM2.140 UC1.AE28
DDR_M1_CS#0: JDIMM2.149 UC1.AL37
DDR_M1_CS#1: JDIMM2.157 UC1.AL35
DDR_M1_D0: JDIMM2.28 UC1.J22
DDR_M1_D1: JDIMM2.42 UC1.H25
DDR_M1_D2: JDIMM2.25 UC1.G22
DDR_M1_D3: JDIMM2.24 UC1.H22
DDR_M1_D4: JDIMM2.41 UC1.F25
DDR_M1_D5: JDIMM2.38 UC1.J25
DDR_M1_D6: JDIMM2.37 UC1.G25
DDR_M1_D7: JDIMM2.29 UC1.F22
DDR_M1_D8: JDIMM2.16 UC1.D22
DDR_M1_D9: JDIMM2.3 UC1.C22
DDR_M1_D10: JDIMM2.7 UC1.C24
DDR_M1_D11: JDIMM2.20 UC1.D24
DDR_M1_D12: JDIMM2.21 UC1.A22
DDR_M1_D13: JDIMM2.17 UC1.B22
DDR_M1_D14: JDIMM2.4 UC1.A24
DDR_M1_D15: JDIMM2.8 UC1.B24
DDR_M1_D16: JDIMM2.45 UC1.G31
DDR_M1_D17: JDIMM2.49 UC1.G32
DDR_M1_D18: JDIMM2.58 UC1.H29
DDR_M1_D19: JDIMM2.62 UC1.H28
DDR_M1_D20: JDIMM2.50 UC1.G28
DDR_M1_D21: JDIMM2.46 UC1.G29
DDR_M1_D22: JDIMM2.63 UC1.H31
DDR_M1_D23: JDIMM2.59 UC1.H32
DDR_M1_D24: JDIMM2.71 UC1.L31
DDR_M1_D25: JDIMM2.70 UC1.L32
DDR_M1_D26: JDIMM2.80 UC1.N29
DDR_M1_D27: JDIMM2.84 UC1.N28
DDR_M1_D28: JDIMM2.66 UC1.L28
DDR_M1_D29: JDIMM2.67 UC1.L29
DDR_M1_D30: JDIMM2.79 UC1.N31
DDR_M1_D31: JDIMM2.83 UC1.N32
DDR_M1_D32: JDIMM2.170 UC1.AJ29
DDR_M1_D33: JDIMM2.173 UC1.AJ30
DDR_M1_D34: JDIMM2.187 UC1.AM32
DDR_M1_D35: JDIMM2.183 UC1.AM31
DDR_M1_D36: JDIMM2.182 UC1.AM30
DDR_M1_D37: JDIMM2.186 UC1.AM29
DDR_M1_D38: JDIMM2.174 UC1.AJ31
DDR_M1_D39: JDIMM2.169 UC1.AJ32
DDR_M1_D40: JDIMM2.191 UC1.AR31
DDR_M1_D41: JDIMM2.190 UC1.AR32
DDR_M1_D42: JDIMM2.204 UC1.AV30
DDR_M1_D43: JDIMM2.208 UC1.AV29
DDR_M1_D44: JDIMM2.195 UC1.AR30
DDR_M1_D45: JDIMM2.194 UC1.AR29
DDR_M1_D46: JDIMM2.207 UC1.AV32
DDR_M1_D47: JDIMM2.203 UC1.AV31
DDR_M1_D48: JDIMM2.216 UC1.BA32
DDR_M1_D49: JDIMM2.212 UC1.BA31
DDR_M1_D50: JDIMM2.225 UC1.BD31
DDR_M1_D51: JDIMM2.229 UC1.BD32
DDR_M1_D52: JDIMM2.211 UC1.BA30
DDR_M1_D53: JDIMM2.215 UC1.BA29
DDR_M1_D54: JDIMM2.228 UC1.BD29
DDR_M1_D55: JDIMM2.224 UC1.BD30
DDR_M1_D56: JDIMM2.232 UC1.BG31
DDR_M1_D57: JDIMM2.236 UC1.BG32
DDR_M1_D58: JDIMM2.249 UC1.BK32
DDR_M1_D59: JDIMM2.245 UC1.BK31
DDR_M1_D60: JDIMM2.237 UC1.BG29
DDR_M1_D61: JDIMM2.233 UC1.BG30
DDR_M1_D62: JDIMM2.250 UC1.BK30
DDR_M1_D63: JDIMM2.246 UC1.BK29
DDR_M1_DQS0: JDIMM2.34 UC1.G24
DDR_M1_DQS1: JDIMM2.13 UC1.D23
DDR_M1_DQS2: JDIMM2.55 UC1.H30
DDR_M1_DQS3: JDIMM2.76 UC1.N30
DDR_M1_DQS4: JDIMM2.179 UC1.AL30
DDR_M1_DQS5: JDIMM2.200 UC1.AU30
DDR_M1_DQS6: JDIMM2.221 UC1.BC30
DDR_M1_DQS7: JDIMM2.242 UC1.BH30
DDR_M1_DQS#0: JDIMM2.32 UC1.H24
DDR_M1_DQS#1: JDIMM2.11 UC1.C23
DDR_M1_DQS#2: JDIMM2.53 UC1.G30
DDR_M1_DQS#3: JDIMM2.74 UC1.L30
DDR_M1_DQS#4: JDIMM2.177 UC1.AL31
DDR_M1_DQS#5: JDIMM2.198 UC1.AU31
DDR_M1_DQS#6: JDIMM2.219 UC1.BC31
DDR_M1_DQS#7: JDIMM2.240 UC1.BH31
DDR_M1_MA0: JDIMM2.144 UC1.AG36
DDR_M1_MA1: JDIMM2.133 UC1.AG35
DDR_M1_MA2: JDIMM2.132 UC1.AF34
DDR_M1_MA3: JDIMM2.131 UC1.AG37
DDR_M1_MA4: JDIMM2.128 UC1.AE35
DDR_M1_MA5: JDIMM2.126 UC1.AF35
DDR_M1_MA6: JDIMM2.127 UC1.AE37
DDR_M1_MA7: JDIMM2.122 UC1.AC29
DDR_M1_MA8: JDIMM2.125 UC1.AE36
DDR_M1_MA9: JDIMM2.121 UC1.AB29
DDR_M1_MA10: JDIMM2.146 UC1.AG34
DDR_M1_MA11: JDIMM2.120 UC1.AC28
DDR_M1_MA12: JDIMM2.119 UC1.AB28
DDR_M1_MA13: JDIMM2.158 UC1.AK35
DDR_M1_MA14_WE#: JDIMM2.151 UC1.AJ35
DDR_M1_MA15_CAS#: JDIMM2.156 UC1.AK34
DDR_M1_MA16_RAS#: JDIMM2.152 UC1.AJ34
DDR_M1_ODT0: JDIMM2.155 UC1.AL36
DDR_M1_ODT1: JDIMM2.161 UC1.AL34
DDR_M1_PAR: JDIMM2.143 UC1.AE34
DDR_PG_CTRL: UC1.C35 UC3.2
DEVSLP0: T2405.1(TP-1) UC1.CP8
DEVSLP1: RC978.1 UC1.CR8
DEVSLP2: JSSD.38 RS46.1 UC1.CM8
DGPU_HOLD_RST#: RV2753.2 UC1.CH12 UV12.2
DGPU_MAIN_EN: PRV5.2 RV2747.1 RV2763.1 UV1.A3
DGPU_MAIN_EN#: QV30.6 QV146.2 RV2745.1 RV2746.1
DGPU_MAIN_EN#_GATE: CV320.1 QV26.2 RV2746.2
DGPU_MAIN_EN_GATE: QV146.1 RV85.1 RV2752.1
DGPU_MAIN_EN_R_GATE: CV315.1 QV5.2 RV85.2
DGPU_OVT#: QG4.1 RG67.1 UK1.19
DGPU_PWR_EN: RC382.1 RV2748.1 UC1.CG12 UK1.106
DGPU_PWR_EN#: QV30.3 RV2739.1 RV2741.1
DGPU_PWR_EN#_GATE: CV313.1 QV20.2 RV2741.2
DGPU_PWROK: CC353.1 DV3.1 PRV22.1 PUV1.13 RV16.1 RV201.1 UV23.1
DH1_NVVDD: PQV1.1 PUV1.2
DH2_NVVDD: PQV2.1 PUV1.14
DIMM1_CHA_EVENT#: JDIMM1.134 RD7.1
DIMM2_CHB_EVENT#: JDIMM2.134 RD25.1
DISPOFF#: C594.1 JEDP.15 R166.2
DL1_NVVDD: PQV1.8 PRV28.1 PUV1.19
DL2_NVVDD: PQV2.8 PUV1.17
DRVEN: PUA1.1 PUG1.1 PUZ1.35 PUZ2.1 PUZ3.1
DRVEN_SET: PRZ72.2 PRZ75.1 PUZ1.18
E51RXD_P80CLK: JWLAN.32 UK1.31
E51TXD_P80DATA: JWLAN.30 RK26.1 UK1.30
EC_BEEP#: CA44.1 UK1.23
EC_BKOFF#: CC364.1 R166.1 R5176.1 UK1.105
EC_CC_CHG: UK1.83 UU1.7
EC_CC_CHG_HI: UK1.84 UU1.8
EC_CC_EN: UK1.73 UU1.6
EC_FAN_PWM1: JFAN.2 RE51.2 UK1.26
EC_KBRST#: RC381.1 UC1.BV29 UK1.2
EC_LAN_ISOLATEB#_R: RM6.2 RM11.2 UL1.20
EC_MUTE#: R5260.1 UK1.72
EC_ON: CC363.1 DH5.2 PR301.1 RK116.2 UK1.112
EC_PCIE_WAKE#: JWLAN.47 RK6.1 RN3.2
EC_PECI: RK17.1 UK1.118
EC_PME#: R5178.2 RL15.2 UL1.21
EC_PME#_EC_R: R5178.1 UK1.76
EC_RST#: CK5.2 RK7.1 UK1.37
EC_SCI#: RC410.1 RK14.2 UC1.CP6 UK1.20
EC_SMB_CK1: PR14.2 PRB19.2 RK110.2 UK1.77
EC_SMB_CK1_R: PJPB1.3 PR14.1
EC_SMB_CK2: QV2.3 RK112.2 UC11.1 UK1.79
EC_SMB_DA1: PR15.2 PRB18.2 RK111.2 UK1.78
EC_SMB_DA1_R: PJPB1.4 PR15.1
EC_SMB_DA2: QV2.6 RK113.2 UC11.5 UK1.80
EC_SPI_CLK: RC369.1 UK1.126
EC_SPI_CS0#: RC948.1 UK1.128
EC_SPI_SI: RC947.1 UK1.120
EC_SPI_SO: RC946.1 UK1.119
EC_VCCST_PG: RC116.2 UC1.BJ2
EC_VCCST_PG_R: RC113.2 RC116.1 UK1.18
EC_VCIN1_AC_BYPASS: CV190.1 DV4.1 RV26.1 RV126.2 RV579.1 UK1.64
ECAGND: CK3.2 LK2.2 PH1.2 UK1.69
EDP_AUXN: CT101.1 UC1.AH4
EDP_AUXN_C: CT101.2 JEDP.8
EDP_AUXP: CT102.1 UC1.AH3
EDP_AUXP_C: CT102.2 JEDP.7
EDP_COMP: RC1.2 UC1.AM6
EDP_HPD: RT11.1 RT34.1 UC1.CM7
EDP_HPD_R: JEDP.11 RT34.2
EDP_TXN0: CT97.1 UC1.AG4
EDP_TXN0_C: CT97.2 JEDP.5
EDP_TXN1: CT100.1 UC1.AG2
EDP_TXN1_C: CT100.2 JEDP.2
EDP_TXP0: CT98.1 UC1.AG3
EDP_TXP0_C: CT98.2 JEDP.4
EDP_TXP1: CT103.1 UC1.AG1
EDP_TXP1_C: CT103.2 JEDP.1
EMMC_RCOMP: RC227.2 UC1.CK15
EN_1.0V_VCCSTU: CC261.1 RC142.2 UC6.3
EN_1.8V: PC1805.1 PR1804.2 PR1805.1 PU1801.1
EN_1V: PC1005.1 PR1001.2 PR1002.1 PU1001.11
EN_2.5V: PC2502.1 PR2501.2 PR2502.2 PR2503.1 PU2501.1
ENBKL: RC124.2 UC1.CK11 UK1.97
ENLDO_3V5V: PC331.1 PR307.2 PR309.1 PU301.11 PU302.5
ENVDD_CPU: RC123.2 UC1.CG11 UG1.6
FAN_SPEED1: CE24.1 JFAN.3 RE50.2 UK1.28
FB_1.8V: PC1802.2 PR1803.2 PR1806.1 PU1801.6
FB_1V: PR1008.1 PR1009.1 PR1010.2 PU1001.14
FB_2.5V: PC2504.2 PR2506.2 PR2507.1 PU2501.6
FB_CLAMP: RV2768.1 UV1.F3
FB_CLK0: RV123.2 UV1.D24 UV6.J12
FB_CLK1: RV175.2 UV1.N22 UV7.J12
FB_CLK#0: RV123.1 UV1.D25 UV6.J11
FB_CLK#1: RV175.1 UV1.M22 UV7.J11
FB_CMD0: UV1.C27 UV6.G12
FB_CMD1: UV1.C26 UV6.H10
FB_CMD2: UV1.E24 UV6.H11
FB_CMD3: UV1.F24 UV6.K11
FB_CMD4: UV1.D27 UV6.K10
FB_CMD5: UV1.D26 UV6.L12
FB_CMD6: UV1.F25 UV6.K4
FB_CMD7: UV1.F26 UV6.K5
FB_CMD8: UV1.F23 UV6.J4
FB_CMD9: UV1.G22 UV6.J5
FB_CMD10: UV1.G23 UV6.H4
FB_CMD11: UV1.G24 UV6.H5
FB_CMD12: UV1.F27 UV6.G3
FB_CMD13: RV2438.2 UV1.G25 UV6.J2
FB_CMD14: RV2439.1 UV1.G27 UV6.J3
FB_CMD15: UV1.G26 UV6.L3
FB_CMD16: UV1.M24 UV7.L12
FB_CMD17: UV1.M23 UV7.K10
FB_CMD18: UV1.K24 UV7.K11
FB_CMD19: UV1.K23 UV7.H11
FB_CMD20: UV1.M27 UV7.H10
FB_CMD21: UV1.M26 UV7.G12
FB_CMD22: UV1.M25 UV7.H4
FB_CMD23: UV1.K26 UV7.H5
FB_CMD24: UV1.K22 UV7.J4
FB_CMD25: UV1.J23 UV7.J5
FB_CMD26: UV1.J25 UV7.K4
FB_CMD27: UV1.J24 UV7.K5
FB_CMD28: UV1.K27 UV7.L3
FB_CMD29: RV2437.2 UV1.K25 UV7.J2
FB_CMD30: RV2440.1 UV1.J27 UV7.J3
FB_CMD31: UV1.J26 UV7.G3
FB_CORE: PCZ11.2 PCZ12.1 PRZ43.2 PRZ45.1 PUZ1.3
FB_D0: UV1.E18 UV6.A4
FB_D1: UV1.F18 UV6.A2
FB_D2: UV1.E16 UV6.B4
FB_D3: UV1.F17 UV6.B2
FB_D4: UV1.D20 UV6.E4
FB_D5: UV1.D21 UV6.E2
FB_D6: UV1.F20 UV6.F4
FB_D7: UV1.E21 UV6.F2
FB_D8: UV1.E15 UV6.A11
FB_D9: UV1.D15 UV6.A13
FB_D10: UV1.F15 UV6.B11
FB_D11: UV1.F13 UV6.B13
FB_D12: UV1.C13 UV6.E11
FB_D13: UV1.B13 UV6.E13
FB_D14: UV1.E13 UV6.F11
FB_D15: UV1.D13 UV6.F13
FB_D16: UV1.B15 UV6.U11
FB_D17: UV1.C16 UV6.U13
FB_D18: UV1.A13 UV6.T11
FB_D19: UV1.A15 UV6.T13
FB_D20: UV1.B18 UV6.N11
FB_D21: UV1.A18 UV6.N13
FB_D22: UV1.A19 UV6.M11
FB_D23: UV1.C19 UV6.M13
FB_D24: UV1.B24 UV6.U4
FB_D25: UV1.C23 UV6.U2
FB_D26: UV1.A25 UV6.T4
FB_D27: UV1.A24 UV6.T2
FB_D28: UV1.A21 UV6.N4
FB_D29: UV1.B21 UV6.N2
FB_D30: UV1.C20 UV6.M4
FB_D31: UV1.C21 UV6.M2
FB_D32: UV1.R22 UV7.U4
FB_D33: UV1.R24 UV7.U2
FB_D34: UV1.T22 UV7.T4
FB_D35: UV1.R23 UV7.T2
FB_D36: UV1.N25 UV7.N4
FB_D37: UV1.N26 UV7.N2
FB_D38: UV1.N23 UV7.M4
FB_D39: UV1.N24 UV7.M2
FB_D40: UV1.V23 UV7.U11
FB_D41: UV1.V22 UV7.U13
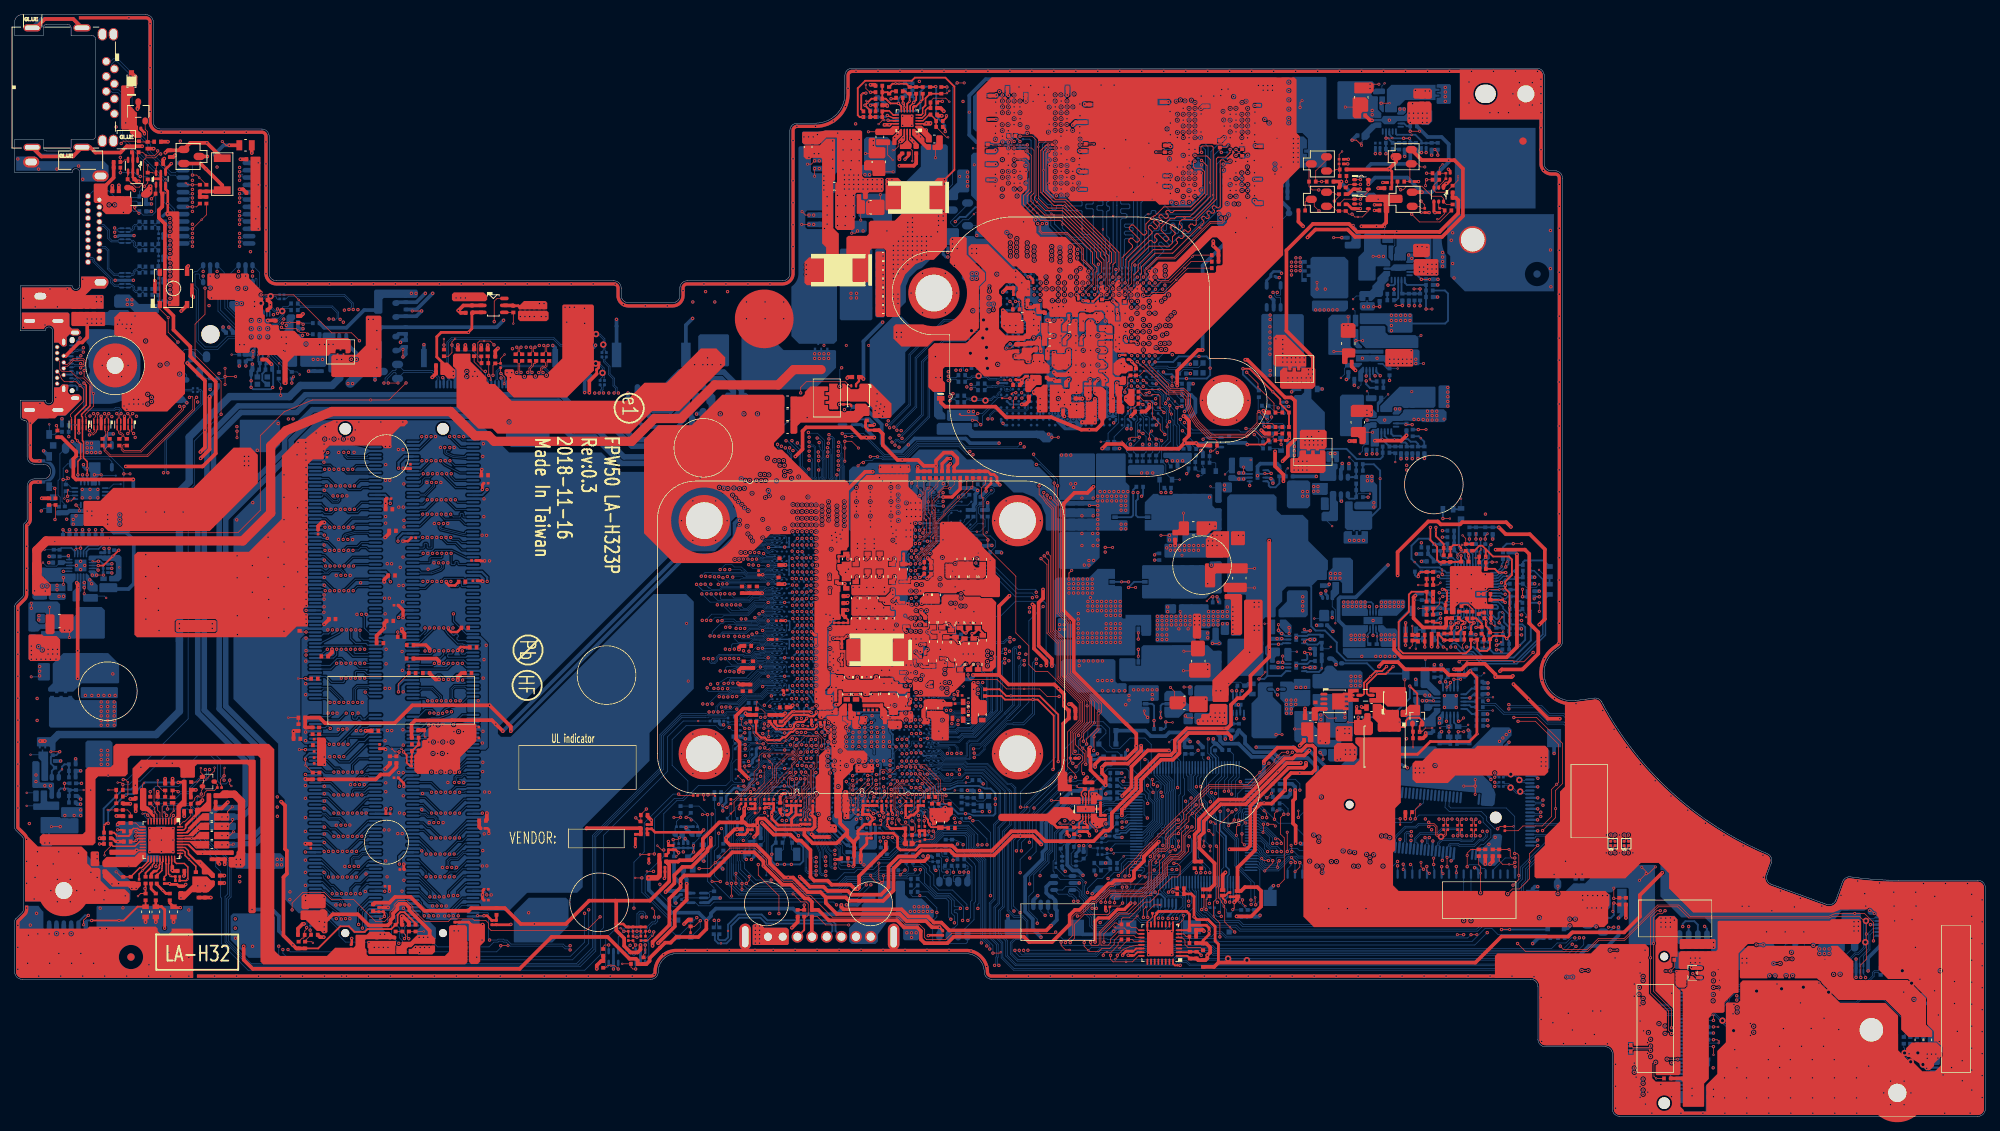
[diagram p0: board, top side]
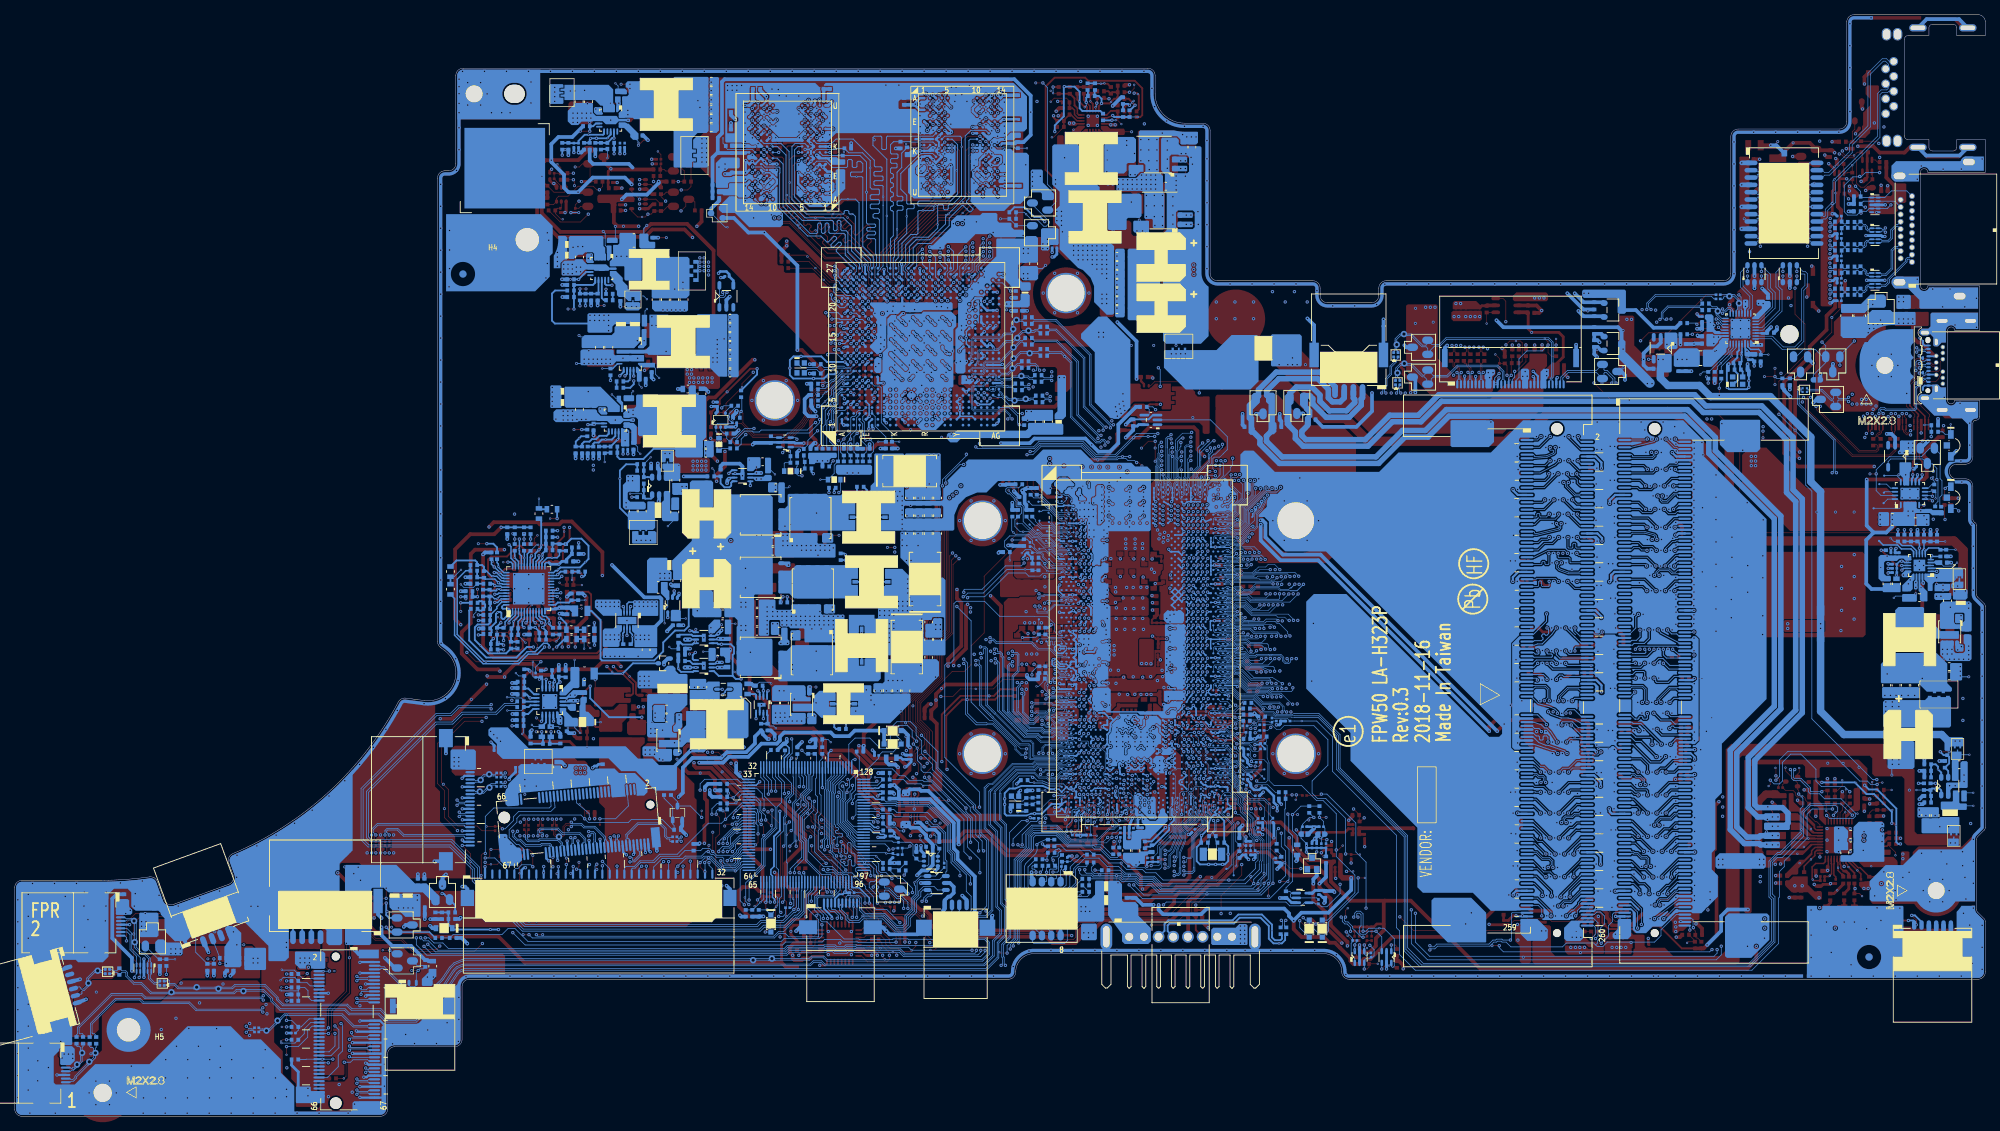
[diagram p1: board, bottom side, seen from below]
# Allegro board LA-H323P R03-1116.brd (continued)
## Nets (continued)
FB_D42: UV1.T23 UV7.T11
FB_D43: UV1.U22 UV7.T13
FB_D44: UV1.Y24 UV7.N11
FB_D45: UV1.AA24 UV7.N13
FB_D46: UV1.Y22 UV7.M11
FB_D47: UV1.AA23 UV7.M13
FB_D48: UV1.AD27 UV7.A11
FB_D49: UV1.AB25 UV7.A13
FB_D50: UV1.AD26 UV7.B11
FB_D51: UV1.AC25 UV7.B13
FB_D52: UV1.AA27 UV7.E11
FB_D53: UV1.AA26 UV7.E13
FB_D54: UV1.W26 UV7.F11
FB_D55: UV1.Y25 UV7.F13
FB_D56: UV1.R26 UV7.A4
FB_D57: UV1.T25 UV7.A2
FB_D58: UV1.N27 UV7.B4
FB_D59: UV1.R27 UV7.B2
FB_D60: UV1.V26 UV7.E4
FB_D61: UV1.V27 UV7.E2
FB_D62: UV1.W27 UV7.F4
FB_D63: UV1.W25 UV7.F2
FB_DBI0: UV1.D19 UV6.D2
FB_DBI1: UV1.D14 UV6.D13
FB_DBI2: UV1.C17 UV6.P13
FB_DBI3: UV1.C22 UV6.P2
FB_DBI4: UV1.P24 UV7.P2
FB_DBI5: UV1.W24 UV7.P13
FB_DBI6: UV1.AA25 UV7.D13
FB_DBI7: UV1.U25 UV7.D2
FB_DDR: PRM6.1 PRM9.1 PUM1.6
FB_EDC0: UV1.E19 UV6.C2
FB_EDC1: UV1.C15 UV6.C13
FB_EDC2: UV1.B16 UV6.R13
FB_EDC3: UV1.B22 UV6.R2
FB_EDC4: UV1.R25 UV7.R2
FB_EDC5: UV1.W23 UV7.R13
FB_EDC6: UV1.AB26 UV7.C13
FB_EDC7: UV1.T26 UV7.C2
FB_GT: PCZ20.2 PCZ21.1 PRZ54.2 PRZ56.1 PUZ1.24
FB_SA: PCZ5.2 PCZ6.1 PRZ8.2 PRZ10.1 PUZ1.45
FB_VRAM: PRW8.1 PRW9.1 PRW10.2 PUW1.14
FB_VREF: T2401.1(TP-1) UV1.D23
FB_WCK01: UV1.D18 UV6.D4
FB_WCK01#: UV1.C18 UV6.D5
FB_WCK23: UV1.D17 UV6.P4
FB_WCK23#: UV1.D16 UV6.P5
FB_WCK45: UV1.T24 UV7.P4
FB_WCK45#: UV1.U24 UV7.P5
FB_WCK67: UV1.V24 UV7.D4
FB_WCK67#: UV1.V25 UV7.D5
FPR_LOCK#: DM16.4 DM16.7 JFPR.6 UK1.68
FPR_OFF: DM16.5 DM16.6 JFPR.7 UK1.1
GC6_FB_EN: RV88.2 RV202.2 UC1.CE27 UV23.2
GPIO0_GC6_FB_EN: RV202.1 UV1.C6
GPIO8_OVERT#: QG4.3 RV69.1 UV1.A6
GPIO9_ALERT#: RV2766.1 UV1.F8
GPU_ALL_PGOOD: CC352.1 DV3.2 RV30.1 RV31.2 UC1.CF12
GPU_BUFRST: C5230.1 RV67.1 UV1.D11
GPU_EVENT#: DV1.1 UC1.CN14
GPU_EVENT#_D: DV1.2 RV72.1 UV1.A4
GPU_JTAG_TCK: T231.1(TP-1) UV1.AE5
GPU_JTAG_TDI: T242.1(TP-1) UV1.AE6
GPU_JTAG_TDO: T243.1(TP-1) UV1.AF6
GPU_JTAG_TMS: T232.1(TP-1) UV1.AD6
GPU_JTAG_TRST#: RV2767.1 UV1.AG4
GPU_PLLVDD: CV31.1 CV395.1 CV396.1 LV5.2 UV1.L6
GPU_TESTMODE: RV71.1 UV1.AD9
GPU_VID0: PRV6.1 UV1.E7
GSPI0_MOSI: RC118.2 UC1.CE29
GSPI1_MOSI: RC201.2 UC1.CA30
GT_BST: PRG2.1 PUG1.4
GT_BST_R: PCG2.1 PRG2.2
GT_LG: PQG2.4 PUG1.7
GT_LX: PCG2.2 PLG1.1 PQG1.1 PQG1.2 PQG1.3 PQG2.5 PRG4.1 PUG1.2
GT_SNUB: PCG9.1 PRG4.2
GT_UG: PRG3.1 PUG1.3
GT_UG_R: PQG1.4 PRG3.2
H_CPUPWRGD: CC303.1 RC102.2 UC1.AR2
H_PECI: RK17.2 UC1.AR1
H_PROCHOT#_EC: CC365.1 RK9.1 UK1.103
H_PROCHOT#_R: RC4.2 UC1.Y4
H_THERMTRIP#: RC2.2 UC1.BJ1
HDA_BIT_CLK: RC459.2 RC987.1 UC1.BN37
HDA_BIT_CLK_R: CC296.1 RA53.2 RC459.1 UA1.5
HDA_RST#: RC950.2 UC1.BL35
HDA_RST#_R: QA2.3 RC950.1
HDA_SDIN0: CC312.2 RA26.2 UC1.BN35
HDA_SDIN0_R: RA26.1 UA1.7
HDA_SDOUT: RC77.2 RC951.2 RC980.1 UC1.BN36
HDA_SDOUT_R: RC951.1 RC1156.2 UA1.4
HDA_SPKR: CA43.1 RC117.2 UC1.CF35
HDA_SYNC: RC949.2 UC1.BN34
HDA_SYNC_R: RC949.1 UA1.9
HDMI_CLKN: CG15.2 RG60.1 RG117.2
HDMI_CLKP: CG14.2 RG59.1 RG116.2
HDMI_CTRL_CLK: CM26.1 DG1.4 DG1.7 JHDMI.15 QG2.6 RG105.2
HDMI_CTRL_DAT: CM27.1 DG1.2 DG1.8 JHDMI.16 QG2.3 RG109.2
HDMI_HPD: QG1.6 RG56.1 RG108.1
HDMI_R_CLKN: CG71.1 D21.4 D21.7 JHDMI.12 RG60.2
HDMI_R_CLKP: CG71.2 D21.5 D21.6 JHDMI.10 RG59.2
HDMI_R_TX_N0: CG74.1 D21.1 D21.9 JHDMI.9 RG13.2
HDMI_R_TX_N1: CG73.1 D22.1 D22.9 JHDMI.6 RG10.2
HDMI_R_TX_N2: CG72.2 D22.4 D22.7 JHDMI.3 RG63.2
HDMI_R_TX_P0: CG74.2 D21.2 D21.8 JHDMI.7 RG12.2
HDMI_R_TX_P1: CG73.2 D22.2 D22.8 JHDMI.4 RG65.2
HDMI_R_TX_P2: CG72.1 D22.5 D22.6 JHDMI.1 RG61.2
HDMI_TX_N0: CG13.2 RG13.1 RG119.2
HDMI_TX_N1: CG11.2 RG10.1 RG115.2
HDMI_TX_N2: CG9.2 RG63.1 RG113.2
HDMI_TX_P0: CG12.2 RG12.1 RG118.2
HDMI_TX_P1: CG10.2 RG65.1 RG114.2
HDMI_TX_P2: CG8.2 RG61.1 RG112.2
HOST_DP1_CTRL_CLK: QG2.1 RG110.2 UC1.CC8
HOST_DP1_CTRL_DATA: QG2.4 RG111.2 UC1.CC9
HOST_DP1_HPD: QG1.1 RG47.2 UC1.CN6
HOST_DP1_N0: CG9.1 UC1.AL5
HOST_DP1_N1: CG11.1 UC1.AJ5
HOST_DP1_N2: CG13.1 UC1.AF6
HOST_DP1_N3: CG15.1 UC1.AE5
HOST_DP1_P0: CG8.1 UC1.AL6
HOST_DP1_P1: CG10.1 UC1.AJ6
HOST_DP1_P2: CG12.1 UC1.AF5
HOST_DP1_P3: CG14.1 UC1.AE6
HOST_SPI_0_CLK: RC456.1 RC986.1 RT6.1 UC1.CH37
HOST_SPI_0_CLK_R: CC144.1 CC295.2 RC369.2 RC456.2 UC2.6
HOST_SPI_0_CLK_R_TPM: RT6.2 UT1.19
HOST_SPI_0_CS0#: CC9.1 RC357.1 RC948.2 RC1160.1 UC2.1
HOST_SPI_0_CS0#_R: RC1160.2 UC1.CG36
HOST_SPI_0_CS2#: RT7.1 UC1.CH34
HOST_SPI_0_CS2#_TPM: RT7.2 UT1.20
HOST_SPI_0_HOLD#: RC942.2 UC2.7
HOST_SPI_0_SI: RC941.1 RC943.1 RT8.1 UC1.CF36
HOST_SPI_0_SI_R: RC943.2 RC947.2 UC2.5
HOST_SPI_0_SI_TPM: RT8.2 UT1.21
HOST_SPI_0_SIO2: RC383.1 RC944.1 UC1.CF34
HOST_SPI_0_SIO3: RC51.1 RC384.1 RC942.1 UC1.CG34
HOST_SPI_0_SO: RC945.1 RT9.1 UC1.CF37
HOST_SPI_0_SO_R: RC945.2 RC946.2 UC2.2
HOST_SPI_0_SO_TPM: RT9.2 UT1.24
HOST_SPI_0_WP#: RC944.2 UC2.3
HP_DETECT: CM17.1 DG1.1 DG1.9 JHDMI.19 RG108.2
HP_OUTL: RA14.1 RA37.2
HP_OUTL_R: CA25.1 JHP.3 RA14.2
HP_OUTR: RA15.1 RA38.2
HP_OUTR_R: CA26.1 JHP.5 RA15.2
HPOUT_L: RA37.1 UA1.25
HPOUT_R: RA38.1 UA1.26
I2C0_SCL_TP: R5265.1 RC1158.1 UC1.CN11
I2C0_SDA_TP: R5268.1 RC1159.1 UC1.CM11
I2C_INT: DT2.1 JTP1.7 R5269.2
I2CA_SCL: RV2758.1 UV1.B7
I2CA_SDA: RV2759.1 UV1.A7
I2CB_SCL: RV2761.1 UV1.C9
I2CB_SDA: RV2760.1 UV1.C8
I2CC_SCL: RV205.1 UV1.A9
I2CC_SDA: RV206.1 UV1.B9
I2CS_SCL: QV2.4 RV203.1 UV1.D9
I2CS_SDA: QV2.1 RV204.1 UV1.D8
ILIM_CHG: PCB21.1 PRB16.1 PRB20.1 PUB1.10
ILMT_1V: PR1003.2 PR1004.1 PU1001.13
ILMT_VRAM: PRW3.2 PRW4.1 PUW1.13
IMON_CORE: PCZ9.2 PCZ231.1 PCZ232.1 PRZ35.2 PUZ1.1
IMON_CORE_R: PHZ1.2 PRZ33.2 PRZ35.1
IMON_GT: PCZ15.1 PRZ48.1 PUZ1.30
IMON_SA: PCZ4.1 PRZ13.2 PUZ1.39
IN_1.8V: PC1801.2 PJ1801.2 PU1801.4
IN_2.5V: PC2501.2 PJ2501.2 PU2501.4
INPUT3VSEL: RC187.1 RC474.1 UC1.BT27
INT_MIC: RA13.1 RA40.1 UA1.14
INT_MIC_R: CA24.1 JHP.1 RA13.2
INVPWR_B+: C117.1 C118.1 FU1.1 JEDP.19 JEDP.20
INVTPWM: C593.1 JEDP.16 R163.1 R259.2
IOUT_CHG: PCB23.1 PRB22.1 PUB1.7
ISEN1N_MAIN: PRZ105.2 PRZ106.2 PUZ1.8
IST_TRIG: T377.1(TP-1) UC1.CP36
KBL_ON: Q9.2 UK1.21
KBL_ON_GND: JKBL.1 JKBL.2 Q9.1 R23.2
KSI0: C193.2 JKB.21 UK1.55
KSI1: JKB.32 UK1.56
KSI2: JKB.25 UK1.57
KSI3: JKB.24 UK1.58
KSI4: JKB.28 UK1.59
KSI5: JKB.27 UK1.60
KSI6: JKB.30 UK1.61
KSI7: JKB.31 UK1.62
KSO0: JKB.26 UK1.39
KSO1: JKB.22 UK1.40
KSO2: JKB.20 UK1.41
KSO3: JKB.15 UK1.42
KSO4: JKB.19 UK1.43
KSO5: JKB.23 UK1.44
KSO6: JKB.16 UK1.45
KSO7: JKB.18 UK1.46
KSO8: JKB.17 UK1.47
KSO9: JKB.29 UK1.48
KSO10: JKB.10 UK1.49
KSO11: JKB.11 UK1.50
KSO12: JKB.14 UK1.51
KSO13: JKB.13 UK1.52
KSO14: JKB.12 UK1.53
KSO15: JKB.9 UK1.54
KSO16: JKB.8 UK1.81
KSO17: JKB.7 UK1.82
LAN_ACT#: RL31.2 UL1.27
LAN_ACT#_R: JLAN.A2 RL31.1
LAN_LINK#: RL30.2 UL1.25
LAN_LINK#_R: JLAN.B2 RL30.1
LAN_MDIN0: DM12.3 TSL1.3 UL1.2
LAN_MDIN1: DM12.6 TSL1.6 UL1.5
LAN_MDIN2: DM13.3 TSL1.9 UL1.7
LAN_MDIN3: DM13.6 TSL1.12 UL1.10
LAN_MDIP0: DM12.4 TSL1.2 UL1.1
LAN_MDIP1: DM12.1 TSL1.5 UL1.4
LAN_MDIP2: DM13.4 TSL1.8 UL1.6
LAN_MDIP3: DM13.1 TSL1.11 UL1.9
LAN_PWR_EN: UK1.86 UL2.4
LAN_WAKE#: RC926.2 UC1.BU32
LANGND: CL2.1 CL3.1 DL1.2 JLAN.9 JLAN.10 JLAN.11 JLAN.12
LDO1_CAP: CA30.2 RA24.2 UA1.21
LED1/GPO: RL56.1 UL1.26
LG_CHG: PQB1.8 PUB1.15
LG_DDR: PQM1.8 PUM1.15
LID_SW#: C19.1 C5228.1 D1.2 JFPR.8 R126.2 U4018.3 UK1.115
LPC_AD0: UC1.CA29 UK1.10
LPC_AD1: UC1.BY29 UK1.8
LPC_AD2: UC1.BY27 UK1.7
LPC_AD3: UC1.BV27 UK1.5
LPC_FRAME#: UC1.CA28 UK1.4
LX1_NVVDD: PCV14.2 PQV1.2 PUV1.20
LX1_NVVDD-1: PLV3.1 PLV3.2 PQV1.5 PQV1.6 PQV1.7 PRV7.1
LX2_NVVDD: PCV24.1 PQV2.2 PUV1.16
LX2_NVVDD-1: PLV4.1 PLV4.2 PQV2.5 PQV2.6 PQV2.7 PRV17.1
LX_1.8V: PL1801.1 PR1802.1 PU1801.3
LX_1V: PC1007.2 PL1001.1 PR1007.1 PU1001.6 PU1001.19 PU1001.20
LX_2.5V: PL2501.1 PR2505.1 PU2501.3
LX_3V: PC302.2 PL302.1 PR303.1 PU301.6 PU301.19 PU301.20
LX_5V: PC313.2 PL301.1 PL301.2 PR308.1 PU302.2 PU302.12
LX_CHG: PCB12.1 PLB1.1 PQB1.9 PRB12.1 PUB1.19
LX_DDR: PCM4.2 PLM1.2 PQM1.9 PRM3.1 PUM1.16
LX_VRAM: PCW6.2 PLW1.1 PRW6.1 PUW1.6 PUW1.19 PUW1.20
MAINPWON: PR311.1 UK1.104
MCT1: RL57.1 TSL1.24
MCT2: RL58.1 TSL1.21
MCT3: RL59.1 TSL1.18
MCT4: RL60.1 TSL1.15
ME_FLASH_EN: RC77.1 UK1.99
MEM_VREF: QV50.2 RV102.1 UV1.C5
MIC2-VREFO: RA40.2 UA1.23
MIC2_CAP: CA29.2 UA1.15
MUTE_LED_IN: RK108.2 UA1.24 UK1.25
MUTE_LED_OUT: R207.1 RK28.1 UK1.36
MUTE_LED_OUT_R: CC123.1 JKB.4 R207.2
NMI_DBG#: DK2.1 RK21.2 UK1.70
NMI_DBG#_CPU: DK2.2 RC374.1 UC1.CE9
NVVDD_EN: PCV1.1 PRV3.1 PRV5.1 PUV1.3
NVVDD_PSI_R: PRV1.2 PRV26.1 PUV1.4
NVVDD_VID: PRV6.2 PRV27.1 PUV1.5
ON/OFF#: CC355.2 Q4108.1 R215.2 UK1.114
ON/OFF#_R: D1.3 JP6.2 Q4108.3 SW1.1 SW1.2
OPC_RCOMP: RC485.1 UC1.N5
OPCE_RCOMP: RC484.1 UC1.L5
P1: PCB5.1 PQB2.3 PQB11.1 PQB11.2 PQB11.3 PQB12.1 PQB12.2 PQB12.3 PRB3.2 PRB10.1
P2: PQB12.5 PRB1.1
PBTN_OUT#: R295.1 RC109.2 UK1.122
PBTN_OUT#_R: RC109.1 UC1.BU28
PC_BEEP: CA42.2 UA1.11
PC_BEEP_R: CA43.2 CA44.2 RA16.1
PCH_DPWROK: RC101.1 RC230.2 UK1.127
PCH_DPWROK_R: RC230.1 UC1.BP30
PCH_JTAG_TCK1: RC399.1 UC1.W6
PCH_OPIRCOMP: RC6.1 UC1.BW25
PCH_PWR_EN: CC362.1 PR1804.1 Q5001.2 RK117.2 UK1.107
PCH_PWR_EN#: Q5001.5 Q5001.6 R5092.2
PCH_PWROK: CC299.1 DC3.2 RC956.2 UC1.BP31 UK1.32
PCH_RSMRST#: CC298.1 CC361.1 DC3.1 DC4.2 RC958.2 UC1.BR36 UK1.100
PCH_RTCRST#: CC11.2 CLRP2.2 R1088.2 RC93.2 UC1.BR34
PCH_RTCX1: CC15.1 RC98.1 UC1.BN31 YC1.1
PCH_RTCX2: CC16.1 RC98.2 UC1.BN32 YC1.2
PCH_SMBCLK: JDIMM1.253 JDIMM2.253 QC1.1 RC216.1
PCH_SMBDATA: JDIMM1.254 JDIMM2.254 QC1.4 RC215.1
PCH_SRTCRST#: CC10.2 CLRP1.2 R1089.2 RC91.2 UC1.BR37
PCH_SUSWARN#: UC1.BV34 UK1.17
PCH_XTAL24_IN: CC13.1 RC92.2 RC448.2 YC2.1
PCH_XTAL24_IN_R: RC448.1 UC1.CK3
PCH_XTAL24_OUT: CC12.1 RC92.1 RC447.2 YC2.3
PCH_XTAL24_OUT_R: RC447.1 UC1.CK2
PCIE_CRX_C_DTX_N9: CR13.2 UL1.18
PCIE_CRX_C_DTX_P9: CR11.2 UL1.17
PCIE_CRX_DTX_N9: CR13.1 UC1.BP5
PCIE_CRX_DTX_N10: JWLAN.35 UC1.BN6
PCIE_CRX_DTX_N13: JSSD.5 UC1.BK6
PCIE_CRX_DTX_N14: JSSD.17 UC1.BJ6
PCIE_CRX_DTX_N15: JSSD.29 UC1.BG5
PCIE_CRX_DTX_N16: JSSD.43 UC1.BE5
PCIE_CRX_DTX_P9: CR11.1 UC1.BP6
PCIE_CRX_DTX_P10: JWLAN.33 UC1.BN5
PCIE_CRX_DTX_P13: JSSD.7 UC1.BK5
PCIE_CRX_DTX_P14: JSSD.19 UC1.BJ5
PCIE_CRX_DTX_P15: JSSD.31 UC1.BG6
PCIE_CRX_DTX_P16: JSSD.41 UC1.BE6
PCIE_CTX_C_DRX_N9: CC327.1 UL1.14
PCIE_CTX_C_DRX_N10: CC20.2 JWLAN.29
PCIE_CTX_C_DRX_N13: CC184.1 JSSD.11
PCIE_CTX_C_DRX_N14: CC186.1 JSSD.23
PCIE_CTX_C_DRX_N15: CC288.1 JSSD.35
PCIE_CTX_C_DRX_N16: CC290.1 JSSD.47
PCIE_CTX_C_DRX_P9: CC326.1 UL1.13
PCIE_CTX_C_DRX_P10: CC19.2 JWLAN.27
PCIE_CTX_C_DRX_P13: CC185.1 JSSD.13
PCIE_CTX_C_DRX_P14: CC187.1 JSSD.25
PCIE_CTX_C_DRX_P15: CC289.1 JSSD.37
PCIE_CTX_C_DRX_P16: CC291.1 JSSD.49
PCIE_CTX_DRX_N9: CC327.2 UC1.BR2
PCIE_CTX_DRX_N10: CC20.1 UC1.BR4
PCIE_CTX_DRX_N13: CC184.2 UC1.BM4
PCIE_CTX_DRX_N14: CC186.2 UC1.BL2
PCIE_CTX_DRX_N15: CC288.2 UC1.BL4
PCIE_CTX_DRX_N16: CC290.2 UC1.BJ4
PCIE_CTX_DRX_P9: CC326.2 UC1.BR1
PCIE_CTX_DRX_P10: CC19.1 UC1.BR3
PCIE_CTX_DRX_P13: CC185.2 UC1.BM3
PCIE_CTX_DRX_P14: CC187.2 UC1.BL1
PCIE_CTX_DRX_P15: CC289.2 UC1.BL3
PCIE_CTX_DRX_P16: CC291.2 UC1.BJ3
PCIE_RCOMPN: RC120.2 UC1.CE6
PCIE_RCOMPP: RC120.1 UC1.CE5
PDB: CA23.1 QA2.1 R5260.2 RA9.2 UA1.40
PEG_CRX_C_GTX_N5: CV12.2 UV1.AB9
PEG_CRX_C_GTX_N6: CV14.2 UV1.AC10
PEG_CRX_C_GTX_N7: CV16.2 UV1.AC11
PEG_CRX_C_GTX_N8: CV18.2 UV1.AB12
PEG_CRX_C_GTX_P5: CV11.2 UV1.AC9
PEG_CRX_C_GTX_P6: CV13.2 UV1.AB10
PEG_CRX_C_GTX_P7: CV15.2 UV1.AD11
PEG_CRX_C_GTX_P8: CV17.2 UV1.AC12
PEG_CRX_GTX_N5: CV12.1 UC1.BW9
PEG_CRX_GTX_N6: CV14.1 UC1.BU6
PEG_CRX_GTX_N7: CV16.1 UC1.BT7
PEG_CRX_GTX_N8: CV18.1 UC1.BU9
PEG_CRX_GTX_P5: CV11.1 UC1.BW8
PEG_CRX_GTX_P6: CV13.1 UC1.BU5
PEG_CRX_GTX_P7: CV15.1 UC1.BT6
PEG_CRX_GTX_P8: CV17.1 UC1.BU8
PEG_CTX_C_GRX_N5: CC276.1 UV1.AG7
PEG_CTX_C_GRX_N6: CC277.1 UV1.AE7
PEG_CTX_C_GRX_N7: CC279.1 UV1.AF9
PEG_CTX_C_GRX_N8: CC282.1 UV1.AG10
PEG_CTX_C_GRX_P5: CC281.1 UV1.AG6
PEG_CTX_C_GRX_P6: CC278.1 UV1.AF7
PEG_CTX_C_GRX_P7: CC280.1 UV1.AE9
PEG_CTX_C_GRX_P8: CC283.1 UV1.AG9
PEG_CTX_GRX_N5: CC276.2 UC1.BW4
PEG_CTX_GRX_N6: CC277.2 UC1.BU4
PEG_CTX_GRX_N7: CC279.2 UC1.BU2
PEG_CTX_GRX_N8: CC282.2 UC1.BT4
PEG_CTX_GRX_P5: CC281.2 UC1.BW3
PEG_CTX_GRX_P6: CC278.2 UC1.BU3
PEG_CTX_GRX_P7: CC280.2 UC1.BU1
PEG_CTX_GRX_P8: CC283.2 UC1.BT3
PEX_PLL_CLK_OUT: RV4.2 UV1.AF22
PEX_PLL_CLK_OUT#: RV4.1 UV1.AE22
PEX_PLLVDD_GPU: CV6.1 CV206.1 CV208.1 RV377.2 UV1.AA14 UV1.AA15
PEX_TERMP: RV376.1 UV1.AF25
PG_+2.5V: PC2507.1 PR2504.2 PRM8.1 PU2501.5
PHZ1_R: PHZ1.1 PRZ26.2
PLAT_SEL0: RC916.1 RC940.2 UC1.CM35
PLT_RST#: CK4.1 JWLAN.44 R28.1 R5270.2 RK115.2 RT3.2 UC4.4 UK1.13 UL1.19 UV12.1
PLT_RST#_PCH: CC300.1 R5270.1 UC1.BJ35 UC4.1 UC4.2
PLT_RST#_SSD: JSSD.50 RT3.1
PLT_RST#_TPM: R28.2 UT1.17
PLT_RST_VGA#: QG4.2 RV378.1 RV379.2 UV1.AC7 UV15.4
PLT_RST_VGA_HOLD#: RV2762.1 UV1.C4 UV15.2
PLT_RST_VGA_MON#: RV70.1 RV379.1 UV1.E9 UV12.4 UV15.1
PLUG_IN#: JHP.2 RA42.1
PM_BATLOW#: RC103.2 UC1.BV36
PM_CLKRUN#: RC107.1 RK10.1 UC1.BY30
PM_CLKRUN#_R: RK6.2 RK10.2 UK1.38
PM_SLP_A#: T258.1(TP-1) UC1.BU37
PM_SLP_S0#: T254.1(TP-1) UC1.BJ37
PM_SLP_S3#: RC979.1 UC1.BU36 UK1.6
PM_SLP_S4#: PR2501.1 RC983.1 UC1.BU27 UK1.123
PM_SLP_S5#: T257.1(TP-1) UC1.BT29 UK1.14
PM_SLP_SUS#: RC984.1 UC1.BU29 UK1.16
PRIMCORE_VID0: T62.1(TP-1) UC1.CB36
PRIMCORE_VID1: T63.1(TP-1) UC1.CB35
PROCHOT#: CC292.2 RC3.2 RC4.1 RK8.2 RK9.2
PROJECT_ID: RC127.2 RC128.1 UC1.CL36
PSI: PRV1.1 RV2764.1 UV1.B4
PWM_CORE1: PUZ1.17 PUZ2.5
PWM_CORE2: PUZ1.16 PUZ3.5
PWM_GT: PUG1.5 PUZ1.22
PWM_SA: PUA1.5 PUZ1.36
PWR_LED#: CLED1.1 RLED1.2 UK1.92
PWR_LED#_R: LED1.1 RLED1.1
PWROK_DDR: PTPM1.1(TP-1) PUM1.10
REFADJ_NVVDD: PRV10.2 PUV1.6
REFIN_NVVDD: PCV12.1 PRV9.1 PRV11.1 PUV1.7
REGN_CHG: PCB14.1 PDB2.2 PUB1.16
RGND_AUXI: PCZ230.1 PRZ93.1 PRZ107.1 PUZ1.25
RGND_MAIN: PRZ21.2 PRZ95.2 PUZ1.48
RGND_NVVDD: PCV12.2 PCV13.2 PCV21.2 PCV26.1 PRV13.2 PRV18.2 PUV1.10 RV218.2
RGND_SA: PRZ22.2 PRZ94.2 PUZ1.44
RJ45_MDIN0: JLAN.2 TSL1.22
RJ45_MDIN1: JLAN.6 TSL1.19
RJ45_MDIN2: JLAN.5 TSL1.16
RJ45_MDIN3: JLAN.8 TSL1.13
RJ45_MDIP0: JLAN.1 TSL1.23
RJ45_MDIP1: JLAN.3 TSL1.20
RJ45_MDIP2: JLAN.4 TSL1.17
RJ45_MDIP3: JLAN.7 TSL1.14
ROM_SCLK: RV80.2 RV381.1 UV1.C12
ROM_SI: RV65.1 RV84.2 UV1.B12
ROM_SO: RV64.1 RV81.2 UV1.A12
RSET: RL11.2 UL1.31
RT3602_EN: PRZ25.1 PUZ1.37
RT3602_SET1: PRZ5.2 PRZ17.1 PUZ1.2
RT3602_SET2: PRZ6.2 PRZ18.1 PUZ1.5
RT3602_SET3: PRZ11.2 PRZ19.1 PUZ1.6
RT3602_VCC: PCZ23.1 PRZ65.2 PUZ1.13
RT3602_VIN: PCZ19.1 PRZ53.1 PUZ1.12
RT3602_VREF: PRZ2.1 PRZ3.1 PRZ4.1 PRZ14.1 PRZ24.2 PRZ26.1 PRZ33.1 PRZ49.2 PRZ63.1 PRZ64.1 PUZ1.42
S0_C10_STATE: RC492.2 UC7.4
S3_DDR: PCM18.1 PRM11.2 PRM12.2 PUM1.7
S5_DDR: PCM17.1 PRM8.2 PRM10.2 PUM1.8
SA0_CHA_DIM1: JDIMM1.256 RD1.2 RD3.1
SA0_CHB_DIM2: JDIMM2.256 RD19.2 RD22.1
SA1_CHA_DIM1: JDIMM1.260 RD4.2 RD5.1
SA1_CHB_DIM2: JDIMM2.260 RD20.2 RD23.1
SA2_CHA_DIM1: JDIMM1.166 RD2.2 RD6.1
SA2_CHB_DIM2: JDIMM2.166 RD21.2 RD24.1
SA_BST: PRA2.1 PUA1.4
SA_BST_R: PCA3.1 PRA2.2
SA_LG: PQA1.8 PUA1.7
SA_LX: PCA3.2 PLA1.1 PQA1.9 PRA4.1 PUA1.2
SA_SNUB: PCA8.1 PRA4.2
SA_UG: PQA1.1 PUA1.3
SATA_CRX_C_DTX_N0: C153.2 JHDD.6
SATA_CRX_C_DTX_P0: C154.2 JHDD.7
SATA_CRX_DTX_N0: C153.1 UC1.BN10
SATA_CRX_DTX_P0: C154.1 UC1.BN8
SATA_CTX_C_DRX_N0: C156.2 JHDD.4
SATA_CTX_C_DRX_P0: C155.2 JHDD.3
SATA_CTX_DRX_N0: C156.1 UC1.BN4
SATA_CTX_DRX_P0: C155.1 UC1.BN3
SATA_GP0: RC962.1 UC1.CN8
SATA_LED#: CLED2.1 RC961.1 RLED2.2 UC1.CN7
SATA_LED#_R: LED2.1 RLED2.1
SCL_CHG: PRB19.1 PUB1.9
SD_RCOMP: RC76.2 UC1.CK33 UC1.CM34
SDA_CHG: PRB18.1 PUB1.8
SERIRQ: R5202.1 RC122.1 UC1.BV28 UK1.3
SM_INTRUDER#: RC94.2 UC1.BR35
SM_PG_CTRL: PRM12.1 RC429.2 UC3.4
SM_RCOMP0: RC38.1 UC1.BN28
SM_RCOMP1: RC39.1 UC1.BN27
SM_RCOMP2: RC40.1 UC1.BN29
SMBALERT#: R5269.1 RC380.1 UC1.CJ15
SMBCLK: QC1.6 R5266.1 RC470.1 UC1.CK14
SMBDATA: QC1.3 R5267.1 RC469.1 UC1.CH15
SML0ALERT#: RC218.1 RC360.1 T305.1(TP-1) UC1.CG15
SML0CLK: RC49.1 UC1.CH14
SML0DATA: RC50.1 UC1.CF15
SML1ALERT#: RC379.1 T90.1(TP-1) UC1.CC34
SML1CLK: RC467.1 UC1.CN15
SML1DATA: RC468.1 UC1.CM15
SNB_1V: PC1009.1 PR1007.2
SNB_2.5V: PC2503.1 PR2505.2
SNB_DDR: PCM14.1 PRM3.2
SNUB_1.8V: PC1806.1 PR1802.2
SNUB_CHG: PCB19.1 PRB12.2
SNUB_NVVDD1: PCV11.1 PRV7.2
SNUB_NVVDD2: PCV25.1 PRV17.2
SNUB_VRAM: PCW7.1 PRW6.2
SOC_GPIOA7: RC475.1 UC1.CC32
SOC_GPIOA12: T354.1(TP-1) UC1.BW37
SOC_GPIOB4: T81.1(TP-1) UC1.CC35
SOC_GPIOB21: RC409.1 UC1.CC30
SOC_GPP_D7: RC483.1 UC1.BV35
SOC_GPP_H21: RC472.1 RC473.1 UC1.CF25
SOC_GPP_H23: RC491.1 UC1.CM26
SOC_SVID_ALERT#: RC180.1 UC1.AA3
SOC_VRALERT#: RC115.2 UC1.CC36
SOC_XDP_TDI: RC389.1 UC1.U5 UC1.U6
SOC_XDP_TDO: RC391.1 RC937.1 UC1.W5 UC1.Y5
SOC_XDP_TMS: RC390.1 UC1.P5 UC1.T5
SOC_XDP_TRST#: CC293.2 RC421.1 UC1.AB6 UC1.Y6
SPK_L+: RA35.1 UA1.35
SPK_L+_CONN: C14.1 DA6.3 JSPK.4 RA35.2
SPK_L-: RA33.1 UA1.36
SPK_L-_CONN: C13.1 DA6.2 JSPK.3 RA33.2
SPK_R+: RA34.1 UA1.38
SPK_R+_CONN: C12.1 DA7.3 JSPK.2 RA34.2
SPK_R-: RA36.1 UA1.37
SPK_R-_CONN: C11.1 DA7.2 JSPK.1 RA36.2
SPOK: CC354.2 DC4.1 PR304.2 PR310.2 PU301.9 RC434.1
SPOK_5V: PR310.1 PU302.4
SRN: PRB14.1 PUB1.12
SRN_R: PCB18.1 PCB20.2 PRB11.3 PRB14.2
SRP: PRB13.1 PUB1.13
SRP_R: PCB17.1 PCB20.1 PRB11.2 PRB13.2
SS_NVVDD: PRV29.1 PRV31.2 PUV1.11
SSD1_IF: QS1.1 RS21.1 UC1.CP10
SSD_PDET: CS16.2 JSSD.61 QS1.2 RS22.2
STRAP0: RV383.1 RV384.2 UV1.D1
STRAP1: RV51.2 RV390.1 UV1.D2
STRAP2: RV382.2 RV388.1 UV1.E4
STRAP3: RV387.1 RV389.2 UV1.E3
STRAP4: RV61.2 RV385.1 UV1.D3
STRAPREF0: RV380.1 RV2751.2 UV1.F6
SUSACK#: RC110.2 UK1.15
SUSACK#_R: RC110.1 UC1.BY32
SUSCLK: CC297.2 JWLAN.42 RC100.2 RC460.1
SUSCLK_R: RC460.2 UC1.BT32
SUSP#: CK10.1 PRM11.1 Q21.3 Q21.5 RC492.1 RK27.1 UC6.5 UK1.116
SYS_PWROK: CC301.2 UC1.CR10 UK1.74
SYS_RESET#: CC302.1 CLRP3.1 RC959.2 UC1.CN10
SYSON: CC360.1 PR2502.1 PRM10.1 RC142.1 UK1.95
TBTB_SBU1: D33.1 D33.9 JTC1.A8
TBTB_SBU2: D33.5 D33.6 JTC1.B8
TON_DDR: PRM7.2 PUM1.9
TON_NVVDD: PRV15.2 PUV1.9
TP_CLK: DM5.3 JTP1.3 RK12.1 UK1.87
TP_DATA: DM5.2 JTP1.2 RK13.1 UK1.88
TP_ENABLE: DT2.6 JTP1.8 UK1.117
TP_L_BTN: JTP1.9 JTP2.2
TP_R_BTN: JTP1.10 JTP2.3
TP_SMBCLK: DT2.3 JTP1.5 QC7.6 R5272.2 RC81.1
TP_SMBDATA: DT2.4 JTP1.6 QC7.3 R5271.2 RC82.1
TPM_GPIO: RT10.1 UT1.6
TPM_PP: RT12.1 RT35.2 UT1.7
TPM_SERIRQ: R5202.2 UT1.18
TS_GPIO: JEDP.17 R5187.2
TS_GPIO_EC: R5187.1 UK1.89
TSEN_CORE: PHZ2.2 PRZ52.2 PUZ1.11
TSEN_CORE_R: PHZ2.1 PRZ51.1 PRZ67.2 PRZ70.1
TSEN_GT: PHZ3.1 PRZ66.1 PUZ1.23
TSEN_GT_R: PHZ3.2 PRZ68.2 PRZ69.2 PRZ71.1
UART_2_CRXD_DTXD: RW11.2 UC1.CR12
UART_2_CTXD_DRXD: RW12.2 UC1.CP12
UFP: QU3.1 RU3.1 UU2.4
UFP#: QU3.2 RU2.2 UU1.19
UG1_EN2: R5201.2 UG1.4
UG_CHG: PQB1.1 PUB1.18
UG_DDR: PQM1.1 PUM1.17
USB2_COMP: RC119.1 UC1.CC5
USB2_ID: RC388.1 UC1.CE8
USB2_VBUSSENSE: RC402.1 UC1.CC6
USB3_CRX_DTX_N1: D31.4 D31.7 JTC1.B10 UC1.CB5
USB3_CRX_DTX_N2: D32.2 D32.8 JTC1.A10 UC1.BY8
USB3_CRX_DTX_N3: JIO.14 UC1.BY7
USB3_CRX_DTX_N4: JIO.17 UC1.BW6
USB3_CRX_DTX_P1: D31.5 D31.6 JTC1.B11 UC1.CB6
USB3_CRX_DTX_P2: D32.1 D32.9 JTC1.A11 UC1.BY9
USB3_CRX_DTX_P3: JIO.15 UC1.BY6
USB3_CRX_DTX_P4: JIO.18 UC1.BW5
USB3_CTX_C_DRX_N1: CS31.1 D32.4 D32.7 JTC1.A3
USB3_CTX_C_DRX_N2: CS34.1 D31.2 D31.8 JTC1.B3
USB3_CTX_C_DRX_N3: CS2.2 JIO.8
USB3_CTX_C_DRX_N4: CS23.2 JIO.11
USB3_CTX_C_DRX_P1: CS32.1 D32.5 D32.6 JTC1.A2
USB3_CTX_C_DRX_P2: CS33.1 D31.1 D31.9 JTC1.B2
USB3_CTX_C_DRX_P3: CS1.2 JIO.9
USB3_CTX_C_DRX_P4: CS24.2 JIO.12
USB3_CTX_DRX_N1: CS31.2 UC1.CA4
USB3_CTX_DRX_N2: CS34.2 UC1.CA2
USB3_CTX_DRX_N3: CS2.1 UC1.BY4
USB3_CTX_DRX_N4: CS23.1 UC1.BW2
USB3_CTX_DRX_P1: CS32.2 UC1.CA3
USB3_CTX_DRX_P2: CS33.2 UC1.CA1
USB3_CTX_DRX_P3: CS1.1 UC1.BY3
USB3_CTX_DRX_P4: CS24.1 UC1.BW1
USB20_N1: LM3.4 RS48.1 UC1.CE3
USB20_N1_R: JIO.20 LM3.3 RS48.2
USB20_N2: LM5.4 RS50.1 UC1.CE1
USB20_N2_R: JIO.23 LM5.3 RS50.2
USB20_N3: LM7.1 UC1.CG3
USB20_N3_C: DM15.3 JTC1.A7 JTC1.B7 LM7.2
USB20_N4: CC154.2 LM6.4 RS53.1 UC1.CD3
USB20_N4_R: JCR.4 LM6.3 RS53.2
USB20_N5: L12.4 R170.1 UC1.CG5
USB20_N5_R: D7.2 JEDP.26 L12.3 R170.2
USB20_N6: L14.4 R5263.1 UC1.CC1
USB20_N6_R: DM16.1 DM16.9 JFPR.3 L14.3 R5263.2
USB20_N7: L13.1 R5175.1 UC1.CG8
USB20_N7_R: D6.3 JEDP.14 L13.2 R5175.2
USB20_N10: JWLAN.5 UC1.CC3
USB20_P1: LM3.1 RS47.1 UC1.CE4
USB20_P1_R: JIO.21 LM3.2 RS47.2
USB20_P2: LM5.1 RS49.1 UC1.CE2
USB20_P2_R: JIO.24 LM5.2 RS49.2
USB20_P3: LM7.4 UC1.CG4
USB20_P3_C: DM15.2 JTC1.A6 JTC1.B6 LM7.3
USB20_P4: CC154.1 LM6.1 RS54.1 UC1.CD4
USB20_P4_R: JCR.5 LM6.2 RS54.2
USB20_P5: L12.1 R171.1 UC1.CG6
USB20_P5_R: D7.3 JEDP.27 L12.2 R171.2
USB20_P6: L14.1 R5264.1 UC1.CC2
USB20_P6_R: DM16.2 DM16.8 JFPR.4 L14.2 R5264.2
USB20_P7: L13.4 R173.1 UC1.CG9
USB20_P7_R: D6.2 JEDP.13 L13.3 R173.2
USB20_P10: JWLAN.3 UC1.CC4
USB_OC0#: RC965.1 UC1.CK6
USB_OC1#: RC963.1 UC1.CK5
USB_OC2#: RC966.1 UC1.CK8
USB_OC3#: RC964.1 UC1.CK9
USB_ON#: JIO.26 UK1.101
VCIN0_PH: PH1.1 PR9.2 UK1.109
VCIN1_AC_IN_R: R5094.2 UK1.110
VCIN1_ACOK: PRB15.2 PUB1.5 R5094.1
VCIN1_PH: PR10.2 PR13.1 UK1.102
VD33STB: RA23.1 UA1.16
VGA_AC_DET: DV4.2 RV15.1 RV126.1 RV2765.1 UV1.D7
VID_PLLVDD: CV30.1 CV34.1 CV35.1 CV60.1 CV61.1 LV6.2 UV1.M6 UV1.N6
VR_ALERT#: PUZ1.33 RC179.2 RC180.2
VR_HOT#: PRZ39.2 PRZ100.2 RK8.1
VR_ON: PRZ25.2 UK1.85
VR_PSYS: PCZ7.1 PRZ20.1 PUZ1.46
VR_PWRGD: PRZ23.1 PUZ1.38 UK1.71
VR_SVID_CLK: PRZ36.2 PRZ98.2 UC1.AA1
VR_SVID_DATA: PRZ38.2 PRZ99.2 RC181.2 UC1.AA2
VRAMCLK_SEL: RC900.1 RC901.2 UC1.CL35
VREF: CA31.2 UA1.22
VREF_NVVDD: PCV21.1 PRV8.1 PUV1.8
VSEN_CORE: PCZ11.1 PRZ41.2 PRZ43.1 PRZ47.2 PUZ1.47
VSEN_GT: PCZ21.2 PRZ50.1 PRZ56.2 PRZ59.1 PUZ1.27
VSNS_NVVDD: PCV26.2 PRV24.2 PRV30.2 PRV31.1 RV217.2
VSNS_NVVDD_R: PRV30.1 PRV32.1 PUV1.12
VTTREF_DDR: PCM15.1 PUM1.4
WAKE#: RC104.2 UC1.BU30
WL_OFF#: JWLAN.48 RC226.1 UC1.CM14
WL_PWREN_EC#: QWL2.2 RWL1.1 UK1.98
XCLK_BIASREF: RC96.1 UC1.CJ1
XDP_BPM#0: T96.1(TP-1) UC1.U1
XDP_BPM#1: T103.1(TP-1) UC1.U2
XDP_BPM#2: T78.1(TP-1) UC1.U3
XDP_BPM#3: T79.1(TP-1) UC1.U4
XDP_ITP_PMODE: RC393.2 UC1.W4
XDP_PRDY#: T178.1(TP-1) UC1.W1
XDP_PREQ#: RC14.1 UC1.W2
XGND: RL55.1 TSL1.25
XTAL_CLKREQ: RC1154.1 RW4.2 UC1.CH29
XTAL_CLKREQ_R: JWLAN.14 RW4.1
XTAL_OUT: CV209.2 UV1.B10 YV1.3
XTAL_OUTBUFF: RV20.1 RV23.1 UV1.C10
XTALIN: CV210.2 UV1.C11 YV1.1
XTLI: CL25.2 RL7.2 UL1.28 YL1.1
XTLO: CL24.2 RL7.1 UL1.29 YL1.3
N17253436: Q5001.3 R5093.2
N19936727: PQ2.6 PR19.2
N19936733: PQ2.2 PQ2.3 PR20.2 PR21.1
N19945980: PC1010.2 PR1010.1
N19949685: PRZ20.2 PRZ31.1
N19949733: PRZ48.2 PRZ49.1
N19949817: PRZ100.1 PUZ1.31
N19949829: PRZ3.2 PRZ6.1
N19949837: PRZ19.2 PRZ30.1
N19949849: PRZ2.2 PRZ5.1
N19949851: PRZ4.2 PRZ11.1
N19949853: PRZ18.2 PRZ29.1
N19949855: PRZ17.2 PRZ28.1
N19950053: PRZ51.2 PRZ52.1
N19950078: PRZ98.1 PUZ1.34
N19950080: PRZ99.1 PUZ1.32
N19950082: PRZ64.2 PRZ68.1
N19950094: PRZ63.2 PRZ67.1
N19950096: PRZ71.2 PRZ74.1
N19950098: PRZ70.2 PRZ73.1
N19950243: PRZ13.1 PRZ14.2
N19951289: PCZ228.2 PRZ24.1
N19951364: PRZ66.2 PRZ69.1
N19954151: PRZ85.2 PRZ102.1
N19954155: PRZ87.2 PRZ103.1
N19954157: PRG6.2 PRG9.1
N19955043: PRA6.2 PRA9.1
N19956576: PCW1.1 PCW4.1 PRW1.2 PRW2.1 PUW1.11
N19967665: PCW10.2 PRW10.1
N25791938: QV50.1 RV200.1
N27704602: CD15.2 RD11.2
N27707230: CD82.2 RD29.2
N29443682: PCV13.1 PRV8.2 PRV9.2 PRV10.1
N31237512: RU1.2 UU1.10
N31237514: RU1.1 UU1.9
N31237586: T404.1(TP-1) UU1.16
N31237588: T405.1(TP-1) UU1.17
N31237590: T406.1(TP-1) UU1.18
N31237594: T402.1(TP-1) UU1.1
N31237596: T403.1(TP-1) UU1.20
N32566675: CV321.1 CV392.1 QV30.2 RV2747.2
N32566729: CV317.1 QV30.5 RV2748.2
N34065508: JSSD.10 TS123.1(TP-1)
N35399579: CWL1.1 QWL1.2 RWL1.2
N36039023: QA2.2 RA10.2
N36039105: RA41.2 RA42.2 UA1.12
N36039393: CA27.1 UA1.32
N36039405: CA28.1 UA1.6
N36039462: CA42.1 RA16.2 RA17.1
N36040271: CA34.2 RA53.1
N36339666: JWLAN.6 RN7.1
N37258528: C557.1 Q21.12
N37258636: C554.1 Q21.10
N38526335: CK9.2 RK109.1
N39192541: PCZ232.2 PRZ108.1
N39192659: PCZ231.2 PRZ109.1
N39559226: PRV11.2 PRV13.1
N39644525: PCV18.1 PRV29.2 PRV32.2 PRV33.1
N39815852: CV121.1 CV391.1 QV3.2 RV16.2 RV17.2
N40833009: T2406.1(TP-1) UC1.CR35
N42543998: LED1.2 RLED3.1
N43563713: QC7.1 R5265.2 R5266.2 R5272.1
N43563982: QC7.4 R5267.2 R5268.2 R5271.1
N44699188: QWL2.1 R5273.2
N91785360: QG1.3 RG112.1 RG113.1 RG114.1 RG115.1 RG116.1 RG117.1 RG118.1 RG119.1
N100118189: CL2.2 DL1.3 RL57.2 RL58.2 RL59.2 RL60.2
N101473516: RV116.1 UV6.J1
N101473793: RV120.1 UV6.J13
N101474312: RV118.1 UV6.J10
N101484120: RV117.1 UV7.J1
N101484397: RV121.1 UV7.J13
N101484914: RV119.1 UV7.J10
N114621639: CC95.1 UC6.12
N114621686: CC94.1 UC6.10
N119900622: RV21.1 UV1.A10
N119904431: RV43.2 UV1.B25
N119904459: RV41.1 UV1.D22
N119904461: RV42.2 UV1.C24
N119910434: RV82.1 UV1.F22
N119910451: RV83.1 UV1.J22
N124440208: RC102.1 T140.1(TP-1)
N124859178: T276.1(TP-1) UC1.AM7
N125272452: CC71.1 UC1.BP24

Pads without a net: DC1 2; DG1 5 6; FD1 1; FD2 1; FD3 1; FD4 1; JCR 2; JDIMM1 87 88 91 92 95 97 100 101 104 105 162 165; JDIMM2 87 88 91 92 95 97 100 101 104 105 162 165; JEDP 18 21; JHDMI 13 14; JIO 6; JKB 2 3; JSSD 6 8 20 22 24 26 28 30 32 34 36 40 42 44 46 48 54 56 58 59 60; JWLAN 8 12 16 20 34 36 38 40 50 52 54 58 60 62; LED1 3; LED2 3; PJP1 5; PU301 10 15; PU1001 10 12; PUW1 10 12; PUZ1 14 15 19 20 21; UA1 10 17 18; UC1 A34 A35 AA24 AA26 AB25 AC1 AC2 AC3 AC4 AC6 AC7 AC24 AC25 AC26 AD3 AD4 AD24 AD26 AE1 AE2 AE3 AE4 AG6 AG7 AH26 AJ1 AJ2 AJ3 AJ4 AJ27 AL1 AL2 AL3 AL4 AM3 AM4 AN1 AN2 AN3 AN4 AR3 AT3 AU3 AY9 B35 BA1 BA2 BB9 BB24 BC24 BC28 BE1 BE2 BJ34 BJ36 BK34 BK35 BK36 BL5 BL6 BL34 BL36 BL37 BN1 BN2 BP8 BP9 BP28 BP29 BP34 BP35 BR18 BT8 BT9 BT30 BT31 BU34 BV24 BV25 BV30 BW34 BW35 BW36 BY31 C34 CA27 CA31 CA32 CA34 CA35 CA36 CA37 CB8 CB9 CB34 CC27 CC29 CC37 CE28 CF20 CF22 CF27 CF29 CG1 CG2 CG14 CG17 CG20 CG22 CG23 CG25 CG35 CH3 CH4 CH5 CH6 CH17 CH20 CH22 CH23 CH25 CH27 CH28 CH30 CH32 CH35 CH36 CJ12 CJ17 CJ22 CJ25 CJ27 CJ29 CJ30 CJ31 CK12 CK17 CK19 CK22 CK23 CK25 CK34 CK36 CM10 CM12 CM16 CM18 CM19 CM20 CM22 CM23 CM24 CM27 CM28 CN3 CN4 CN12 CN16 CN18 CN19 CN20 CN22 CN23 CN24 CN26 CN28 CN35 CN36 CP3 CP4 CP14 CP16 CP18 CP20 CP22 CP24 CP26 CP28 CR3 CR4 CR14 CR16 CR18 CR20 CR22 CR24 CR26 CR28 D34 D35 D37 E1 F34 F37 G1 G2 G3 G4 H3 H4 K12 K14 K15 K17 K18 K20 L25 M24 M26 P24 P26 R24 R25 R26 T25 U34 U35 V24 V25 V28 V29 W3 W25 Y3 Y24 Y25; UC3 1; UC11 3; UK1 29; UL2 3; UT1 3 4 5 10 11 12 13 15 25 26 27 28 29 30 31; UU2 3; UV1 A16 A22 AA1 AA2 AA3 AA4 AA5 AA6 AB1 AB2 AB3 AB4 AB5 AB6 AB13 AB15 AB16 AB18 AB19 AB21 AB27 AC3 AC4 AC13 AC14 AC15 AC16 AC17 AC18 AC19 AC20 AC21 AD1 AD2 AD3 AD4 AD5 AD7 AD10 AD14 AD17 AD20 AD23 AE1 AE2 AE3 AE4 AE10 AE12 AE13 AE15 AE16 AE18 AE19 AE21 AE23 AE24 AF2 AF3 AF4 AF10 AF12 AF13 AF15 AF16 AF18 AF19 AF21 AF24 AG3 AG12 AG13 AG15 AG16 AG18 AG19 AG21 AG22 AG24 AG25 B2 B3 B6 B19 C1 C2 C3 C7 C14 D4 D5 D6 D10 D12 E6 E10 E12 F4 F5 F7 F9 F10 F11 F12 F19 G1 G2 G3 G4 G5 G6 G7 H3 H4 H6 J1 J2 J3 J4 J5 J6 J7 K1 K2 K3 K4 K5 K6 K7 L3 L4 M1 M2 M3 M4 M5 M7 N1 N2 N3 N4 N5 N7 P3 P4 P6 P25 R1 R2 R3 R4 R5 R6 R7 T1 T2 T3 T4 T5 T6 T7 T27 U3 U4 U6 V1 V2 V3 V4 V5 V6 V7 W1 W2 W3 W4 W5 W6 W7 W22 Y3 Y4 Y6; UV6 A5 A10 U5 U10; UV7 A5 A10 U5 U10; YL1 2 4; YV1 2 4

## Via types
v1: diameter 0.305, hole 0.152, TOP to BOTTOM, 443 vias
v2: diameter 0.406, hole 0.203, TOP to BOTTOM, 368 vias
v3: diameter 0.457, hole 0.203, TOP to BOTTOM, 5804 vias
v4: diameter 0.884, hole 0.442, TOP to BOTTOM, 39 vias

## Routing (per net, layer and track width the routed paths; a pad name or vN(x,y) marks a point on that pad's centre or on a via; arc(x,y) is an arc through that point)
1.35V_PWR_EN: length 56.4
  TOP w0.102: v3(194.04,131.13) 194.04,131.52 v2(193.65,131.91)
  IN1 w0.127: v3(194.04,131.13) 194.42,130.75 194.42,123.44 193.3,122.32 183.33,122.32 182.85,121.84 180.75,121.84 179.65,120.74 179.65,118.64 177.4,116.4 177.4,114.75 174.86,112.21 174.13,112.21 171.85,109.94 171.85,107.84 171.57,107.56 171.57,102.25 172.29,101.54 v3(172.29,96.65)
  BOTTOM w0.102: v3(172.29,96.65) 172,96.95 RV201.2 171.79,96.14 UV23.4
  BOTTOM w0.254: PRW1.1 v3(194.04,131.13)
3V_FB: length 3.2
  BOTTOM w0.254: PU301.13 188.64,111.64 188.35,111.35 PC312.1
3V_FB_1: length 0.9
  BOTTOM w0.254: PR305.1 187.16,111.35 PC312.2
3V_SN: length 2.2
  BOTTOM w0.127: v2(182.51,121.56) 182.91,121.15 PR303.2
5V_3V_EN: length 26.7
  TOP w0.102: v3(191.63,112.88) v2(190.8,112.88)
  IN2 w0.254: v3(185.49,101.02) 185.49,100.74 185.8,100.44 186.48,100.44 186.99,100.95 191.18,100.95 193.42,103.18 193.42,109.98 191.63,111.77 v3(191.63,112.88)
  BOTTOM w0.254: v3(191.63,112.88) PR301.2 PR311.2 PR313.1 PC327.1 189.09,112.36 PU301.12 ; PU302.6 185.21,101.3 v3(185.49,101.02)
5V_FB: length 2.4
  BOTTOM w0.254: PC326.1 185.07,100.26 v1(184.78,100.55) 184.78,101.23 184.76,101.25 PU302.7
5V_FB_1: length 0.9
  BOTTOM w0.254: PR312.1 186.62,99.4 PC326.2
5V_SN: length 2.1
  TOP w0.102: 182,104.35 v2(179.88,104.35)
+0.6V_0.6VS: length 84.9
  TOP w0.508: v3(42.27,26.48) 43.36,27.57 46.78,27.57 48.29,26.06 50.88,26.06 51.24,26.41 51.24,26.77 51.6,27.13 51.6,27.69 52.17,28.27 52.17,28.72 52.46,29 53.28,29 53.82,28.47 53.82,28.1 56.59,25.33 56.59,24.69 v3(56.33,24.43)
  IN1 w1.016: 31.53,32.99 31.87,33.33 31.87,38.44 30.23,40.08 30.23,41.03 29.32,41.94 28.58,41.94 28.28,42.25 24.94,42.25 23.78,43.4 17.39,43.4 16.59,44.2 6.65,44.2 5.89,44.97 5.89,46.44 7.22,47.77 7.22,60.22 9.19,62.19 9.19,68.09 7.79,69.49 6.13,69.49 4.91,70.71
  vias: v2(41.52,26.59) v3(3.78,72.35) v3(4.39,72.37) v3(30.68,32.72) v3(30.69,32.01) v3(42.21,25.85) v3(42.21,25.21) v3(55.15,24.42) v3(55.75,24.42)
+0.6V_B_VREFDQ: length 85.4
  TOP w0.508: RD27.2 39.67,53.06 39.6,53.13 CD82.1 41.58,54.39 42.34,53.63 51.79,53.63 54.24,56.08 v2(64.75,56.08) 67.65,53.18 v3(67.65,52.55)
  IN1 w0.457: v3(98.8,80.73) 99.12,80.73 99.84,81.45 100.86,81.45 102.91,83.51 102.91,84.65 102.89,84.67 v3(102.89,84.67)
  BOTTOM w0.203: v3(102.89,84.67) 102.89,84.31 103.3,83.9 103.62,83.9 UC1.E36
  BOTTOM w0.508: v3(67.65,52.55) 90.96,75.86 96.1,75.86 98.8,78.57 v3(98.8,80.73)
+0.6V_DDR_VREFCA: length 8.8
  TOP w0.127: v3(53.01,49.72) 53.01,49.87 v1(52.72,50.17)
  TOP w0.254: 54.1,47.8 CD14.2 ; 54.1,47.8 CD12.2 54.1,48.42 CD11.2 54.17,49.13 RD10.2 RD8.1 RD9.1 ; 54.1,47.8 53.92,47.8 53.45,48.26 53.45,49.27 v3(53.01,49.72)
  BOTTOM w0.305: v3(53.01,49.72) 53.32,50.03 JDIMM1.164
+0.6V_DDRB_VREFCA: length 2.2
  TOP w0.127: v3(39.64,50.03) v2(38.81,50.03)
  BOTTOM w0.305: JDIMM2.164 39.69,50.03 39.68,50.03 v3(39.64,50.03)
+0.6V_VREFCA: length 67.8
  TOP w0.508: v3(66.56,52.55) v2(65.6,53.51) 65.06,54.05 59.6,54.05 59.57,54.01 54.6,54.01 54.11,53.53 CD15.1 54.11,51.72 RD9.2
  IN1 w0.457: v3(98.83,81.32) 99.53,82.02 100.61,82.02 102.37,83.78 v3(102.37,84.42)
  BOTTOM w0.203: v3(102.37,84.42) 102.37,84.42 103.23,83.56 103.46,83.56 103.56,83.46 103.84,83.46 UC1.F36
  BOTTOM w0.508: v3(98.83,81.32) 98.55,81.32 98.15,80.92 98.15,79.01 95.78,76.64 90.64,76.64 v3(66.56,52.55)
+0.6VSP: length 0.9
  TOP w0.102: v3(6.64,73.49) v2(6.64,72.59)
+1.0VS_DGPU:
  vias: v2(125.54,103.65) v3(125.61,100.79) v3(126.25,100.79) v3(130.52,118.38) v3(130.52,117.74) v3(131.15,118.38) v3(131.15,117.74) v3(136.49,115.3) v3(136.49,114.5) v3(137.32,113.71) v3(138.18,112.86) v3(138.93,103) v3(138.95,109.55) v3(138.95,108.72) v3(138.95,107.9) v3(139.6,107.85) v3(139.6,107.27) v3(139.75,103) v3(140.32,102.81)
+1.0VS_PLLAVDD: length 4.8
  TOP w0.102: v3(133.44,110.82) v2(133.44,110.03)
  TOP w0.356: CV52.2 149.77,111.23 v3(149.73,111.23)
  TOP w0.381: CV53.1 151.44,105.91 v3(151.44,106.27) ; v3(145.68,111.27) 146.33,111.27 CV55.1
  BOTTOM w0.305: v3(145.68,111.27) 145.3,111.66 UV1.P22 ; UV1.H22 v3(149.73,111.23) ; UV1.F16 151.49,106.27 v3(151.44,106.27)
  vias: v3(132.85,110.82)
+1.2V_VDDQ: length 92.6
  TOP w0.381: CC366.2 85.35,38.48 RC938.1
  TOP w0.508: RC938.1 85.38,39.26 RC32.1 78.01,39.31 77.96,39.26 ; v3(117.2,92.6) v2(116.12,92.6) 115.41,92.6 114.02,94 107.93,94 107.42,93.49 107.42,91 v3(106.45,90.02) ; CD95.1 63.34,39.5 CD30.1
  IN1 w0.508: v3(106.45,90.02) 106.45,88.68 107.46,87.66 107.46,85.83 103.59,81.96 103.59,79.29 104.02,78.86 v3(106.73,78.86)
  BOTTOM w0.089: UC1.AD36 103.41,72.63
  BOTTOM w0.09: v3(102.74,75.15) 102.75,75.14 103.68,75.14 103.68,75.14 103.73,75.14 UC1.Y36 ; v3(102.74,67.6) UC1.AM36 ; UC1.AY36 v3(102.74,62.56) ; 103.41,72.63 v3(102.74,72.63)
  BOTTOM w0.102: UC1.AH36 103.51,70.11 103.48,70.1 103.43,70.11 v3(102.74,70.11)
  BOTTOM w0.2: UC1.AN32 v3(106.73,67.01)
  BOTTOM w0.203: UC1.AW32 106.31,62.91 106.73,63.36 v3(106.73,63.36) ; UC1.BH36 103.66,57.45 103.26,57.45 v3(103.17,57.36) ; v3(106.71,70.59) 106.71,70.59 106.71,70.58 106.34,70.2 UC1.AH32 ; v3(106.73,78.86) UC1.R32 ; UC1.BE32 v3(106.73,59.72)
  BOTTOM w0.305: v3(52.46,34.42) 52.46,35.44 53.04,36.03 54.3,36.03 JDIMM1.220 ; JDIMM2.96 v3(39.74,69.03) ; v3(64.4,85.52) 64.4,85.46 64.37,85.43 64.37,85.39 63.75,84.78 JDIMM1.33 ; JDIMM2.54 40.98,79.53 41.83,79.53 42.06,79.3 v3(42.22,79.3) ; v3(50.46,30.71) 50.17,30.71 50.11,30.78 JDIMM2.241 ; v3(52.27,78.48) 52.27,78.89 52.9,79.53 54.3,79.53 JDIMM1.54 ; JDIMM2.220 39.67,36.03 v3(39.64,36.06) ; JDIMM2.178 39.81,46.53 39.69,46.64 v3(39.64,46.64) ; JDIMM1.96 53.16,69.03 52.37,68.23 v3(52.37,68.05) ; JDIMM2.199 49.18,41.27 50.9,41.27 51.21,41.58 51.21,41.89 v3(51.28,41.96) ; v3(52.46,45.03) 52.46,45.64 53.34,46.53 JDIMM1.178 ; v3(63.78,41.37) 63.68,41.28 JDIMM1.199 ; JDIMM2.75 50.57,74.28 51.02,73.82 51.02,73.15 v3(51.24,72.93) ; JDIMM1.241 63.97,30.78 64.38,30.37 v3(64.38,30.21) ; JDIMM1.75 63.7,74.28 64.43,73.55 v3(64.43,72.98) ; v3(42.69,90.56) 42.15,90.02 40.98,90.02 JDIMM2.12 ; JDIMM2.33 50.48,84.78 51.21,84.04 v3(51.21,83.63) ; v3(52.34,88.43) 52.34,89.2 53.17,90.03 JDIMM1.12
  BOTTOM w0.381: UC3.5 115.44,94.37 115.63,94.18 116.19,94.18 CC57.1
  BOTTOM w0.508: CC57.1 116.19,93.62 v3(117.2,92.6)
  vias: v3(11.79,56.54) v3(11.79,55.9) v3(11.79,55.27) v3(11.79,54.63) v3(11.79,54) v3(11.79,53.36) v3(12.68,56.54) v3(12.68,55.9) v3(12.68,55.27) v3(12.68,54.63) v3(12.68,54) v3(12.68,53.36) v3(13.57,56.54) v3(13.57,55.9) v3(13.57,55.27) v3(13.57,54.63) v3(13.57,54) v3(13.57,53.36) v3(39.72,65.24) v3(39.73,63.52) v3(39.69,62.1) v3(39.68,59.03) v3(39.68,57.53) v3(39.67,52.43) v3(39.67,51.25) v3(50.51,58.39) v3(50.5,51.24) v3(50.65,63.72) v3(50.64,61.74) v3(50.82,52.64) v3(51.11,58.39) v3(51.42,52.64) v3(52.82,63.43) v3(52.86,60.85) v3(52.93,52.75) v3(52.97,57.91) v3(52.98,50.65) v3(63.2,56.7) v3(63.77,50.94) v3(63.88,59.79) v3(63.85,52.54) v3(64,62.3) v3(64.29,64.26)
+1.2VP: length 38.9
  TOP w0.508: v3(8.59,59.75) v2(8.59,63.52) 8.59,72.65 v3(8.47,72.78)
  IN2 w0.254: v3(7.32,76.49) 14.05,76.49 15.07,75.47 15.07,62.05 v3(13.38,60.36)
  BOTTOM w0.203: PRM6.2 7.22,76.38 v3(7.32,76.49) 7.44,76.37 PUM1.5
+1.2VS_VCCPLL_OC: length 38.9
  TOP w0.076: v3(109.3,56.02) 109.06,56.02 v2(108.72,55.68)
  TOP w0.356: RC938.2 86.22,38.58 CC321.1 CC49.1 87.32,38.76 93.62,38.76 v3(93.95,39.08)
  IN1 w0.254: v3(93.95,39.08) 93.95,41.99 98.71,46.76 98.71,48.16 98.81,48.26 98.81,51.94 98.71,52.04 98.71,53.64 99.38,54.31 100.59,54.31 101.44,55.16 103.3,55.16 103.77,55.63 106.96,55.63 106.96,55.63 107.33,55.63 107.33,55.63 108.91,55.63 v3(109.3,56.02)
  BOTTOM w0.203: v3(109.3,56.02) 109.32,56.02 109.32,56 UC1.BL27 UC1.BM26
+1.05V_MPHYPLL: length 0.9
  BOTTOM w0.18: UC1.BV2 126.51,51.62 v3(126.52,51.62)
  vias: v2(126.01,52.55)
+1.05V_PRIM: length 32.7
  TOP w0.381: 141.59,39.95 142.11,39.43 CC97.1
  TOP w0.457: RC393.1 127.28,88.74 v3(127.57,89.03)
  TOP w1.016: 134.6,40.79 141.68,40.79
  IN1 w0.508: v3(134.56,76.88) 133.39,76.88 131.49,78.77 131.49,81.34 128.55,84.28 128.55,85.52 127.57,86.49 v3(127.57,89.03)
  BOTTOM w0.254: UC1.CC12 119.27,47.88 v3(119.35,47.89) ; UC1.BU14 v3(118.46,52.41) UC1.BT12 ; v3(116.82,53.06) 116.82,53.09 UC1.BR15 ; 117.56,53.71 117.55,53.66 UC1.BR15 ; UC1.BR15 117.55,53.12 v3(117.56,53.04) ; UC1.BP14 118.46,53.71 UC1.BR12 ; UC1.BU12 v3(118.46,51.76) ; UC1.CA12 UC1.CB12 118.88,48.78 118.48,48.5 v3(118.46,48.5)
  BOTTOM w0.508: RC14.2 134.45,76.98 v3(134.56,76.88)
  vias: v2(117.58,98.57) v3(113.42,51.11) v3(113.42,50.46) v3(114.3,52.38) v3(114.26,51.73) v3(114.26,51.11) v3(114.26,50.46) v3(115.14,52.43) v3(115.14,51.73) v3(115.14,51.1) v3(115.91,53.03) v3(115.94,52.41) v3(115.94,51.11) v3(115.94,50.46) v3(116.83,51.78) v3(116.84,51.08) v3(116.91,54.66) v3(116.85,48.5) v3(117.33,96.29) v3(117.46,96.92) v3(117.58,97.56) v3(117.62,51.8) v3(117.61,51.1) v3(117.62,50.46) v3(117.6,48.52) v3(117.84,95.91) v3(117.97,96.54) v3(118.09,97.18) v3(118.35,95.52) v3(118.4,53.04) v3(118.45,50.46) v3(118.47,96.16) v3(118.46,51.12) v3(118.6,96.79) v3(119.27,51.1) v3(120.25,106.95) v3(120.25,106.32) v3(120.89,106.95) v3(120.89,106.32) v3(127.87,119.65) v3(127.87,119.02) v3(127.87,118.38) v3(128.13,40.66) v3(128.25,40.09) v3(128.51,119.02) v3(128.51,118.38) v3(128.89,40.09) v3(174.44,88.75) v3(174.44,88.17) v3(174.46,89.38) v3(175.04,89.38) v3(175.03,88.75) v3(175.03,88.17) v3(175.62,89.38) v3(175.61,88.75) v3(175.61,88.17) v3(176.21,89.38) v3(176.2,88.75) v3(176.2,88.17)
+1.05V_PRIMP: length 12.9
  BOTTOM w0.254: PR1008.2 PC1010.1 186.53,90.01 186.2,89.68 182.98,89.68 181.59,91.07 176.32,91.07 175.85,90.6
  vias: v2(177.81,93.44) v3(175.94,92.18) v3(175.94,91.6) v3(176.25,92.72) v3(176.53,92.18) v3(176.53,91.6) v3(176.83,92.72) v3(177.11,92.18) v3(177.11,91.6) v3(177.69,92.18) v3(177.69,91.6) v3(178.28,92.18) v3(178.28,91.6)
+1.05V_VCCDSW: length 2.7
  TOP w0.076: v2(110.47,51.97) v3(110.91,52.41)
  TOP w0.254: v3(110.91,52.41) 110.42,52.89 CC316.1
  BOTTOM w0.2: UC1.BT24 111.23,52.73 v3(110.91,52.41)
+1.05V_VCCST: length 182
  TOP w0.508: 134.22,60.22 134.22,69.62 135.62,71.01 v3(135.63,71.01) ; 134.22,60.22 v3(130.67,60.22) ; 134.22,60.22 135.52,58.92 141.77,58.92 v2(142.32,58.37) 143.07,57.61 v3(143.07,56.79) 143.07,55.99 CC358.1 CC346.1 142.97,53.58 142.97,46.74 ; v3(202.37,80.36) 203.31,79.42 206.59,79.42 208.64,77.36 208.64,67.84 v3(207.88,67.08)
  IN1 w0.254: v3(135.63,71.01) 135.62,71.01 135.62,71.37 131.54,75.44 131.54,75.74 v3(131.2,76.08)
  IN1 w0.508: v3(207.88,67.08) 207.88,65.87 205.7,63.69 205.7,52.11 203.78,50.19 201.5,50.19 196.45,45.13 184.24,45.13 183.5,45.87 176.68,45.87 175.78,46.77 169.2,46.77 168.78,47.19 154.35,47.19 152.48,49.05 151.13,49.05 145.25,54.93 144.14,54.93 143.07,56 v3(143.07,56.79) 143.07,57.61 142.78,57.91 140.39,57.91 136.76,54.27 133.6,54.27 131.42,52.09 127.82,52.09 126.49,53.43 v3(126.49,54.06)
  BOTTOM w0.203: UC1.BP2 126.1,54.06 126.1,54.06 v3(126.49,54.06)
  BOTTOM w0.254: RC179.1 129.93,76.14 RC181.1 130.01,76.22 130.54,76.75 RC935.2 130.72,76.89 130.92,76.69 130.92,76.53 131.2,76.25 v3(131.2,76.08) ; UC1.BP11 UC1.BR11 120.15,53.38 v3(120.4,53.14) 119.79,52.72 UC1.BT11 ; v3(202.37,80.36) PCZ227.1 PRZ36.1 PRZ38.1 PRZ39.1
  BOTTOM w0.508: RC113.1 129.14,60.33 RC2.1 129.23,59.62 130.32,59.62 130.67,59.96 v3(130.67,60.22)
+1.05V_VCCSTU_IN: length 2
  TOP w0.102: RC427.1 v2(141.36,43.11)
+1.05V_XTAL: length 5.8
  TOP w0.076: v3(124.06,40.91) v1(124.06,41.55)
  TOP w0.254: RC477.2 127.22,39.39 CC318.1 126.16,39.45 124.98,39.45 124.72,39.71 CC319.1 124.53,40.09 124.53,40.44 v3(124.06,40.91)
  BOTTOM w0.254: v3(124.06,40.91) 123.94,41.04 123.94,41.23 123.82,41.35 123.82,41.48 UC1.CP5
+1.05VS_PG: length 128.3
  TOP w0.102: v3(190.54,94.37) v2(189.7,94.37)
  IN1 w0.127: v3(190.54,94.37) 192.48,94.37 203.15,83.69 203.15,79.37 202.76,78.98 202.76,73.72 202.93,73.55 203.31,73.55 203.82,74.06 203.82,74.57 205.85,76.6 207.78,76.6 209.08,75.3 209.08,66.05 206.4,63.37 206.4,51.81 204.08,49.49 201.79,49.49 196.74,44.43 183.95,44.43 183.21,45.17 176.39,45.17 175.49,46.07 163.76,46.07 161.58,43.89 160.9,43.89 160.68,44.1 159.78,44.1 159.59,43.91 157.72,43.91 156.57,45.06 v3(155.82,45.06)
  BOTTOM w0.102: v3(155.82,45.06) 155.62,44.85 155.62,43.3 155.88,43.04 155.88,40.15 154.4,38.67 154.4,38.5 153.87,37.97 UK1.108
  BOTTOM w0.254: PU1001.9 189.75,94.54 PR1005.2 189.92,94.37 v3(190.54,94.37)
+1.05VS_VCCIO: length 43.8
  TOP w0.508: 113.42,85.39 115.96,87.93 v3(117,87.93) ; RC1.1 124.16,68.18 123.58,68.77 v3(123.58,68.99)
  IN1 w0.508: v3(123.58,68.99) 123.58,68.75 124.42,67.91 126.23,67.91 126.86,68.54 126.86,70.25 128,71.39 128.27,71.39 129.43,72.56 129.43,73.7 128.93,74.21 127.68,74.21 127.06,74.83 127.06,76.78 128.01,77.74 128.01,80.47 127.04,81.45 125.32,81.45 124.71,82.06 124.71,85.22 124.48,85.45 124.48,86.98 123.52,87.93 v3(117,87.93)
  BOTTOM w0.254: UC1.BP18 115.92,54.34 115.96,54.34 v3(116.04,54.4) 116.35,54.16 UC1.BP16 v3(115.94,53.71)
  vias: v2(110.63,68.5) v3(109.27,57.9) v3(109.32,56.96) v3(111.17,68.38) v3(111.17,67.47) v3(111.4,79.23) v3(111.4,57.26) v3(111.4,56.66) v3(111.46,78.59) v3(111.62,67.92) v3(111.91,79.67) v3(112.04,78.97) v3(112.1,78.34) v3(112.54,79.42) v3(112.67,78.78) v3(112.86,79.99)
+1.05VS_VCCSTG: length 91.7
  TOP w0.356: RC3.1 132.7,88 CC142.1
  TOP w0.381: CC142.1 133.52,87.59 133.93,87.18 133.93,86.56 v3(134.34,86.15) ; 117.2,93.62 116.4,93.62 116.02,94 CC89.1 116.02,94.77 RC188.2
  TOP w0.457: RC390.2 v3(125.62,88.75) 125.62,89.46 ; RC3.1 RC937.2 RC391.2 RC389.2 128.1,88.65 128.11,88.67
  TOP w0.508: v3(138.77,69.85) 138.98,69.64 138.98,63.82 140.68,62.13 v3(140.68,61.5) ; 125.62,89.46 126.71,90.55 127.78,90.55 128.53,89.79 128.53,89.08 128.11,88.67 ; v3(125.62,88.75) 123.96,88.75 123.16,89.55 v2(121.01,89.55) 120.38,89.55 118.37,91.56 118.37,93.1 117.85,93.62 117.2,93.62
  IN1 w0.508: v3(125.62,88.75) 125.11,88.24 125.11,85.71 125.34,85.48 125.34,82.66 125.95,82.05 127.53,82.05 128.61,80.97 128.61,77.49 127.66,76.54 127.66,75.15 128,74.81 129.41,74.81 130.13,74.09 130.13,73.43 133.52,70.04 138.58,70.04 v3(138.77,69.85) ; v3(126.42,58.43) 125.69,57.7 125.69,56.56 126.22,56.03 128.51,56.03 129.67,57.19 130.39,57.19 130.67,56.92 136.55,56.92 140.68,61.05 v3(140.68,61.5)
  BOTTOM w0.254: v3(126.42,58.43) 126.28,58.28 UC1.BG1 UC1.BG2 UC1.BG3
  BOTTOM w0.508: v3(134.34,86.15) 133.59,86.15 133.51,86.23 RC1157.1
+1.05VS_VCCSTG_IO:
  vias: v2(108.06,95.33)
+1.8V_PG: length 16.1
  TOP w0.127: v3(191.38,93.7) v2(192.44,93.7)
  IN1 w0.381: v3(191.38,93.7) 187.32,89.63 181.44,89.63 181.01,89.2 v3(181.01,89.07)
  BOTTOM w0.254: PR1001.1 v3(191.38,93.7)
  BOTTOM w0.508: v3(181.01,89.07) PR1801.2 180.83,88.23 PU1801.5
+1.8V_PRIM: length 294.5
  TOP w0.508: v3(204.36,58.96) v2(206.43,56.89) 209.08,54.25 v3(210.68,54.25)
  IN1 w0.508: v3(183.92,78.58) 188.91,78.58 192.49,82.16 v3(200.54,82.16) ; v3(145.66,32.89) 146.25,32.3 147.76,32.3 148.23,31.83 149.65,31.83 149.74,31.92 158.94,31.92 160.87,33.85 163.97,33.85 164.48,33.34 164.48,33.03 165.21,32.3 165.21,32.28 165.57,31.92 167.01,31.92 170.39,28.54 202.86,28.54 211.45,19.96 211.45,18.87 212.54,17.77 214.38,17.77 220.96,11.2 220.96,8.02 223.66,5.32 226.67,5.32 227.97,6.62 v3(231.59,6.62) 233.12,8.15 233.12,10.85 232.6,11.37 v3(231.63,11.37) 231.05,11.37 230.6,11.82 230.6,16.07 231.15,16.62 v3(231.61,16.62) ; 114.97,41.42 114.97,44.02 115.04,44.1 115.04,45.3 114.83,45.51 114.83,46.94 v3(115.1,47.21) ; 117.25,39.17 117.77,38.66 122.92,38.66 123.1,38.83 123.71,38.83 124.3,38.23 129.07,38.23 129.17,38.14 133.58,38.14 135.34,39.9 142.1,39.9 142.74,39.25 146.4,39.25 v3(147.11,39.96)
  IN2 w0.508: v3(200.54,82.16) 203.68,82.16 206.48,79.36 206.48,72.54 207.25,71.78 207.25,65.67 205.6,64.02 205.6,60.2 v3(204.36,58.96) ; v3(210.68,54.25) 213.8,54.25 237.78,30.27 237.78,23.11 238.34,22.55 238.34,18.63 240.18,16.78 240.18,10.31 236.49,6.62 v3(231.59,6.62)
  BOTTOM w0.254: v3(115.1,47.86) UC1.CC18 ; v3(115.1,47.86) UC1.CC19 ; v3(115.1,47.86) UC1.CD18 ; v3(116.84,47.86) 117.17,47.53 UC1.CD15 ; v3(116.84,47.86) 116.88,47.86 UC1.CC15 ; v3(116.84,47.86) 116.83,47.85 116.78,47.86 UC1.CD16 ; UC1.CD16 116.76,47.22 116.81,47.23 v3(116.88,47.18) ; UC1.CD16 116.14,47.31 115.75,47.31 UC1.CD18 ; UC1.CD18 v3(115.1,47.21) 114.83,47.42 UC1.CD19
  BOTTOM w0.356: RC183.2 v3(231.63,11.37)
  BOTTOM w0.508: RC72.2 v3(231.61,16.62) ; v3(147.11,39.96) 146.52,39.36 145.44,39.36 144.42,38.35 144.42,37.98 143.52,37.08 R5093.1 143.52,34.28 144.25,33.55 145,33.55 v3(145.66,32.89)
  vias: v3(114.78,40.53) v3(147.62,39.52) v3(182.01,78.58) v3(182.65,78.58) v3(183.28,78.58)
+1.8VS: length 159.2
  TOP w0.203: 21.5,34.09 21.41,34.18 UA1.29
  TOP w0.508: v3(107.04,32.7) 108.42,31.33 110.28,31.33 110.85,30.75 113.6,30.75 114.12,30.23 118.13,30.23 119.15,31.25 119.15,34.08 120.52,35.45 122.79,35.45 123.62,36.28 127.52,36.28 128.19,35.61 133.51,35.61 136.14,38.23 v2(137.13,38.23) 138.82,38.23 v3(139.96,37.1) ; CA39.2 21.58,33.48 v3(21.5,33.56) 21.5,34.09 ; RA5.1 v3(28.59,32.85)
  IN1 w0.508: v3(102.95,27.69) 98.78,27.69 96.6,25.51 90.38,25.51 89.77,26.12 82.77,26.12 79.38,22.73 78.57,22.73 77.49,21.65 40.64,21.65 38.07,24.21 34.69,24.21 30.83,28.07 30.83,28.67 29.23,30.27 29.23,32.2 v3(28.59,32.85) 28.59,32.88 27.16,34.31 27.16,34.69 24.24,37.61 22.37,37.61 21.83,37.08 21.42,37.08 20.81,36.47 20.81,34.25 v3(21.5,33.56)
  IN2 w0.508: v3(102.95,27.69) 102.95,28.61 v3(107.04,32.7)
  BOTTOM w0.508: v3(146.95,43.97) 146.95,44.31 146.65,44.61 145.31,44.61 145.11,44.41 144.13,44.41 143.08,43.35 140.01,40.29 140.01,37.15 v3(139.96,37.1)
  vias: v3(147.53,43.87)
+1.8VS_AVDD:
  vias: v1(25.32,34.55)
+1.8VSP: length 10.3
  BOTTOM w0.254: 185.06,81.9 186.18,83.01 v2(186.18,87) 186.18,88.11 185.33,88.96 183.82,88.96 ; 183.82,88.96 183.82,88.11 PC1802.1 ; 183.82,88.96 PR1803.1
+1.35VGS_PGOOD: length 71.3
  TOP w0.102: v3(190.28,134.4) v2(191.58,134.4)
  IN1 w0.127: v3(169.01,93.02) 169.18,93.18 169.18,93.91 169.77,94.51 170.67,94.51 170.88,94.3 171.77,94.3 171.98,94.51 172.68,95.21 172.68,96.45 172.82,96.59 172.82,98 172.54,98.28 172.54,101.67 171.83,102.38 171.83,107.46 172.11,107.74 172.11,109.83 174.23,111.96 174.97,111.96 177.66,114.64 177.66,116.29 179.92,118.55 179.92,120.62 180.88,121.58 182.95,121.58 183.43,122.07 193.4,122.07 194.67,123.34 194.67,133.18 193.45,134.4 v3(190.28,134.4)
  BOTTOM w0.102: v3(169.01,93.02) 169.64,92.39 169.64,91.71 RV31.1
  BOTTOM w0.254: v3(190.28,134.4) PRW5.2 189.82,135.08 189.45,135.46 PUW1.9
+1.35VRAMP: length 18.4
  TOP w0.102: v3(175.26,137.64) 175.26,138.29 v2(175.54,138.57)
  IN2 w0.254: v3(186.97,131.33) 185.71,132.58 185.39,132.58 183.93,134.04 176.26,134.04 175.26,135.04 v3(175.26,137.64)
  BOTTOM w0.254: PRW8.2 186.97,132.81 PCW10.1 v3(186.97,131.33)
+1.35VS_VRAM: length 87.1
  IN2 w0.203: 166.53,126.31 v3(166.53,126.31)
  BOTTOM w0.127: v3(166.53,127.11) 166.53,127.11 166.53,126.88 166.53,126.55 166.53,126.55 v3(166.53,126.31) 166.53,126.31 165.75,126.31 v3(165.75,126.31) ; v3(136.28,127.31) v3(137.08,127.31) ; UV7.M1 144.28,129.71 144.28,128.98 144.25,128.95 144.25,128.93 144.27,128.93
  BOTTOM w0.203: UV6.E10 165.76,128.74 166.49,128.74 v3(166.52,128.71) ; UV7.N10 137.1,129.7 137.1,130.5 137.05,130.55 ; v3(135.48,129.76) 135.47,129.75 135.25,129.75 135.24,129.74 134.66,129.74 UV7.M14
  BOTTOM w0.254: UV7.M14 134.2,130.19 134.2,130.83 UV7.L14 ; UV7.L1 144.56,131.04 144,131.04 UV7.L2 ; v3(160.93,131.92) 160.93,131.91 160.13,131.91 v3(160.13,131.92) 160.13,131.68 v3(160.13,131.1) ; v3(142.67,132.12) 142.68,132.14 142.68,132.91 UV7.H3 ; UV6.B12 166.93,125.91 v3(166.53,126.31) ; UV7.T3 v3(142.68,126.51) ; UV6.H12 UV6.G13 167.76,129.91 v3(168.12,130.28) ; v3(152.75,116.13) 152.75,115 UV1.E26 ; UV1.L26 147.77,114.99 v3(147.77,116.26) ; UV6.D12 v3(166.53,127.11)
  BOTTOM w0.305: v3(153.08,112.88) 152.65,112.46 UV1.E23 ; UV1.L22 147.68,110.77 v3(147.43,110.52) ; v3(150.16,115.54) 150.16,115.54 UV1.H26 ; v3(150.59,113.69) 150.19,113.3 UV1.H24 ; UV1.C25 v3(154.7,114.5) ; UV7.T14 133.7,126.91 ; UV1.L24 147.68,113.3 v3(148.1,112.88) ; v3(154.7,115.29) 155.1,114.9 UV1.B26
  BOTTOM w0.33: UV6.G11 v3(166.49,130.27) UV6.H12 ; UV6.M3 159.74,133.91 v3(160.13,133.52) 160.53,133.12 UV6.L4 160.52,133.11 v3(160.12,132.72) 159.73,132.32 UV6.K3 159.73,132.31 v3(160.13,131.92) ; UV7.L2 143.88,130.91 v3(143.47,130.51) 143.08,130.12 UV7.M3 UV7.L4 142.29,130.91 v3(142.69,131.31) 143.08,131.71 UV7.K3 143.08,131.71 v3(142.67,132.12) ; UV7.G4 142.28,134.1 v3(142.66,133.72) 143.07,133.31 UV7.H3 ; v3(160.92,126.3) 160.93,126.3 160.93,126.31 UV6.C5 161.87,127.25 161.87,128.62 v3(161.8,128.68) 161.77,128.68 161.4,128.31 UV6.E5 ; UV6.G4 160.51,129.91 v3(160.13,130.3) 159.73,130.7 UV6.H3 159.74,130.71 v3(160.13,131.1) ; v3(160.13,127.11) 159.73,127.51 UV6.D3 ; UV7.P12 135.88,128.51 v3(136.28,128.11) 136.28,128.11 UV7.P11 v3(137.08,128.91) UV7.N10 137.5,129.31 v3(137.9,128.91) 137.98,128.83 137.98,128.22 UV7.R10 137.48,127.71 v3(137.08,127.31) ; v3(145.14,129.84) 145.66,129.31 145.66,128.73 145.33,128.4 144.79,128.4 UV7.P1 144.27,128.92 144.27,128.93 v3(144.28,128.93) ; v3(145.14,129.84) 144.86,130.11 UV7.M1 ; v3(145.14,129.84) 145.21,129.91 v3(145.21,130.69) 144.99,130.91 UV7.L1 ; v3(158.52,129.51) 158.13,129.13 UV6.F1 157.9,128.89 157.43,128.89 157.38,128.84 157.36,128.84 157.06,128.53 157.06,128.1 157.07,128.08 157.07,128.06 157.4,127.73 157.53,127.73 v3(157.57,127.69) ; v3(158.52,129.51) 158.13,129.9 UV6.G1 ; v3(158.52,129.51) 158.53,129.51 UV6.G2 158.93,129.9 v3(159.32,129.52) 159.72,129.11 UV6.F3 ; v3(168.12,130.28) 168.14,130.28 168.51,129.91 UV6.G14 v3(169.02,130.4) 169.02,128.77 v3(169.05,128.74) 168.91,128.74 UV6.F14 ; UV7.T1 144.68,126.91 v3(144.28,127.31) ; UV6.M12 166.93,133.92 v3(166.53,134.32) ; v3(166.53,127.11) 166.13,127.51 UV6.D11 v3(165.72,127.92) UV6.E10 165.31,128.31 164.79,127.79 164.79,127.26 UV6.C10 165.35,126.71 v3(165.75,126.31) ; UV7.P14 v3(133.73,128.51) ; UV7.L13 135.08,130.92 v3(135.48,131.31) 135.88,131.71 UV7.K12 136.27,131.32 v3(136.27,131.32) 136.67,130.91 UV7.L11 137.05,130.55 ; UV7.L13 134.96,131.03 134.4,131.03 UV7.L14 ; UV7.L13 UV7.M12 135.53,129.76 v3(135.48,129.76) ; v3(142.69,128.92) 143.08,128.53 UV7.P3 143.08,128.51 v3(143.47,128.12) ; UV6.L11 166.13,133.12 v3(165.74,133.51) ; v3(157.57,127.69) 157.07,127.2 157.07,126.42 157.58,125.92 v3(157.58,125.91) 157.58,125.91 UV6.B1 ; v3(157.57,127.69) 157.95,127.69 UV6.D1 ; UV7.T12 135.89,126.91 v3(136.28,127.31) ; UV6.B3 v3(160.14,125.5) ; UV7.N5 v3(141.09,129.71) 141.03,129.65 141.03,129.61 140.98,129.57 140.98,127.37 v3(141.05,127.3) 141.06,127.3 141.06,127.3 141.48,127.71 UV7.R5 ; 133.7,126.91 v3(133.7,126.91) ; UV6.F12 166.53,128.71 v3(166.52,128.71)
  BOTTOM w0.35: UV7.B1 v3(145.24,138.11)
  BOTTOM w0.508: RV2439.2 v3(154.65,132.77) ; RV2440.2 v3(148.56,132.05) ; v3(171.84,128.56) 171.12,128.56 CV374.1 170.87,128.74 v3(169.05,128.74) ; CV166.1 v3(165.44,140.15) ; CV168.2 133.66,126.96 v3(133.7,126.91)
  vias: v2(151.5,133.23) v3(133.73,134.11) v3(133.76,138.37) v3(133.82,136.9) v3(133.76,135.09) v3(134.68,133.72) v3(135.48,134.46) v3(136.28,137.72) v3(136.28,136.92) v3(136.27,135.3) v3(136.94,140.43) v3(137.06,137.72) v3(137.09,136.11) v3(138.54,140.62) v3(138.86,138.47) v3(139.56,139.39) v3(140.34,140.41) v3(140.39,139.33) v3(140.51,138.47) v3(140.98,140.41) v3(141.05,135.36) v3(141.49,110.3) v3(141.88,137.72) v3(142.34,110.47) v3(142.7,138.51) v3(142.98,110.47) v3(143.49,136.1) v3(143.47,134.52) v3(145.23,135.02) v3(145.22,134.17) v3(145.26,136.51) v3(146,110.06) v3(148.13,140.69) v3(148.92,110.52) v3(148.99,109.86) v3(149.71,109.83) v3(149.91,140.69) v3(150.1,105.92) v3(150.16,104.99) v3(150.61,107.95) v3(150.61,106.3) v3(150.6,105.41) v3(150.65,104.65) v3(151.41,109.55) v3(151.5,107.06) v3(155.53,111.18) v3(157.54,137.09) v3(157.58,135.51) v3(157.58,133.91) v3(158.53,133.55) v3(159.33,137.53) v3(159.34,135.91) v3(161.79,139.2) v3(161.77,136.75) v3(161.76,134.3) v3(163.5,139.2) v3(164.45,139.26) v3(164.58,140.09) v3(164.92,135.11) v3(165.73,136.72) v3(165.73,135.11) v3(166.53,136.72) v3(166.53,135.91) v3(167.33,132.72) v3(168.11,133.5) v3(169.11,137.01) v3(169.11,135.51) v3(169.09,133.91) v3(169.08,133) v3(169.07,126.94) v3(169.05,125.6) v3(169.58,140.65) v3(170.23,140.62) v3(170.23,139.99) v3(170.87,140.62) v3(170.87,139.99) v3(171.5,140.62) v3(171.5,139.99) v3(174.35,133.37) v3(174.35,132.74) v3(174.35,132.1) v3(174.35,131.47) v3(174.35,130.83) v3(174.35,130.2) v3(174.99,133.37) v3(174.99,132.74) v3(174.99,132.1) v3(174.99,131.47) v3(174.99,130.83) v3(174.99,130.2)
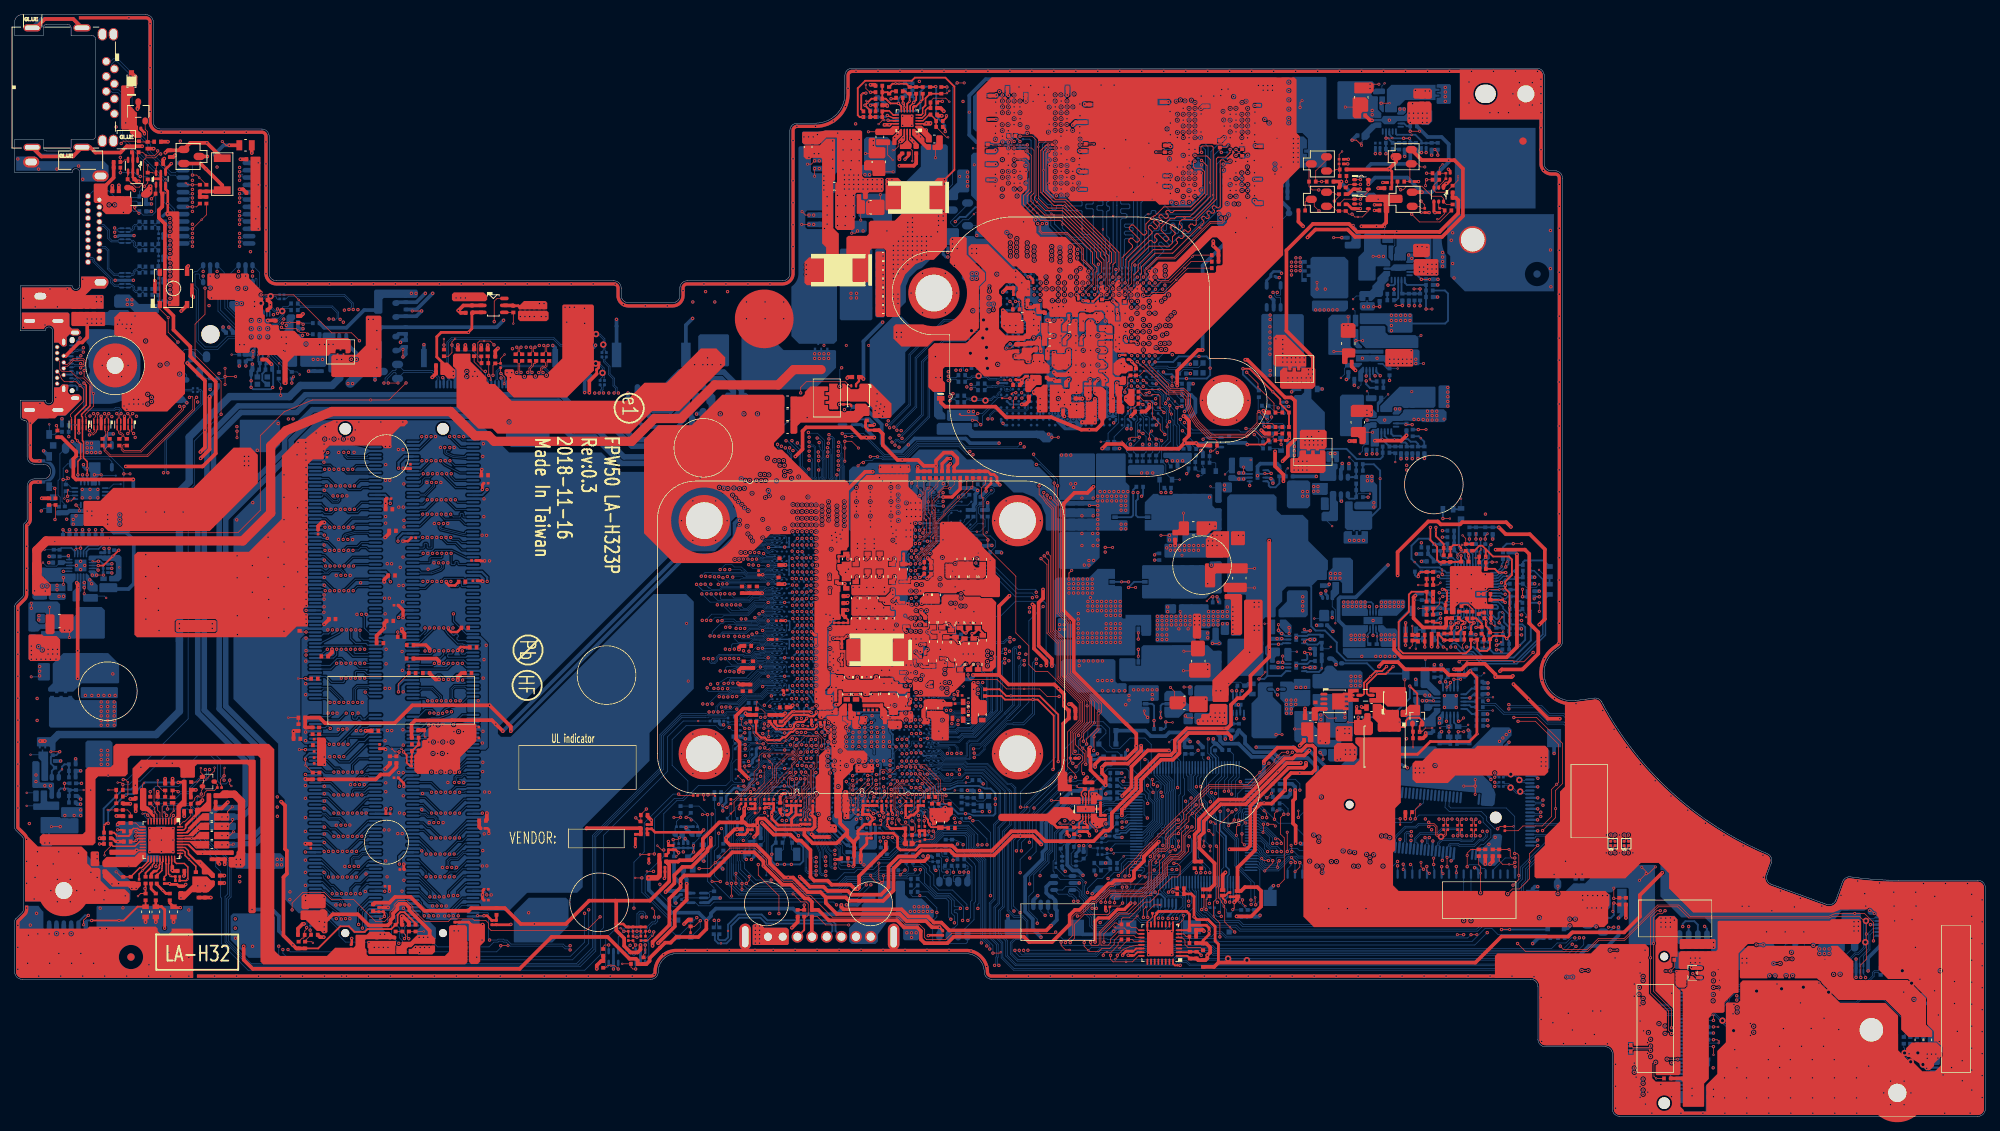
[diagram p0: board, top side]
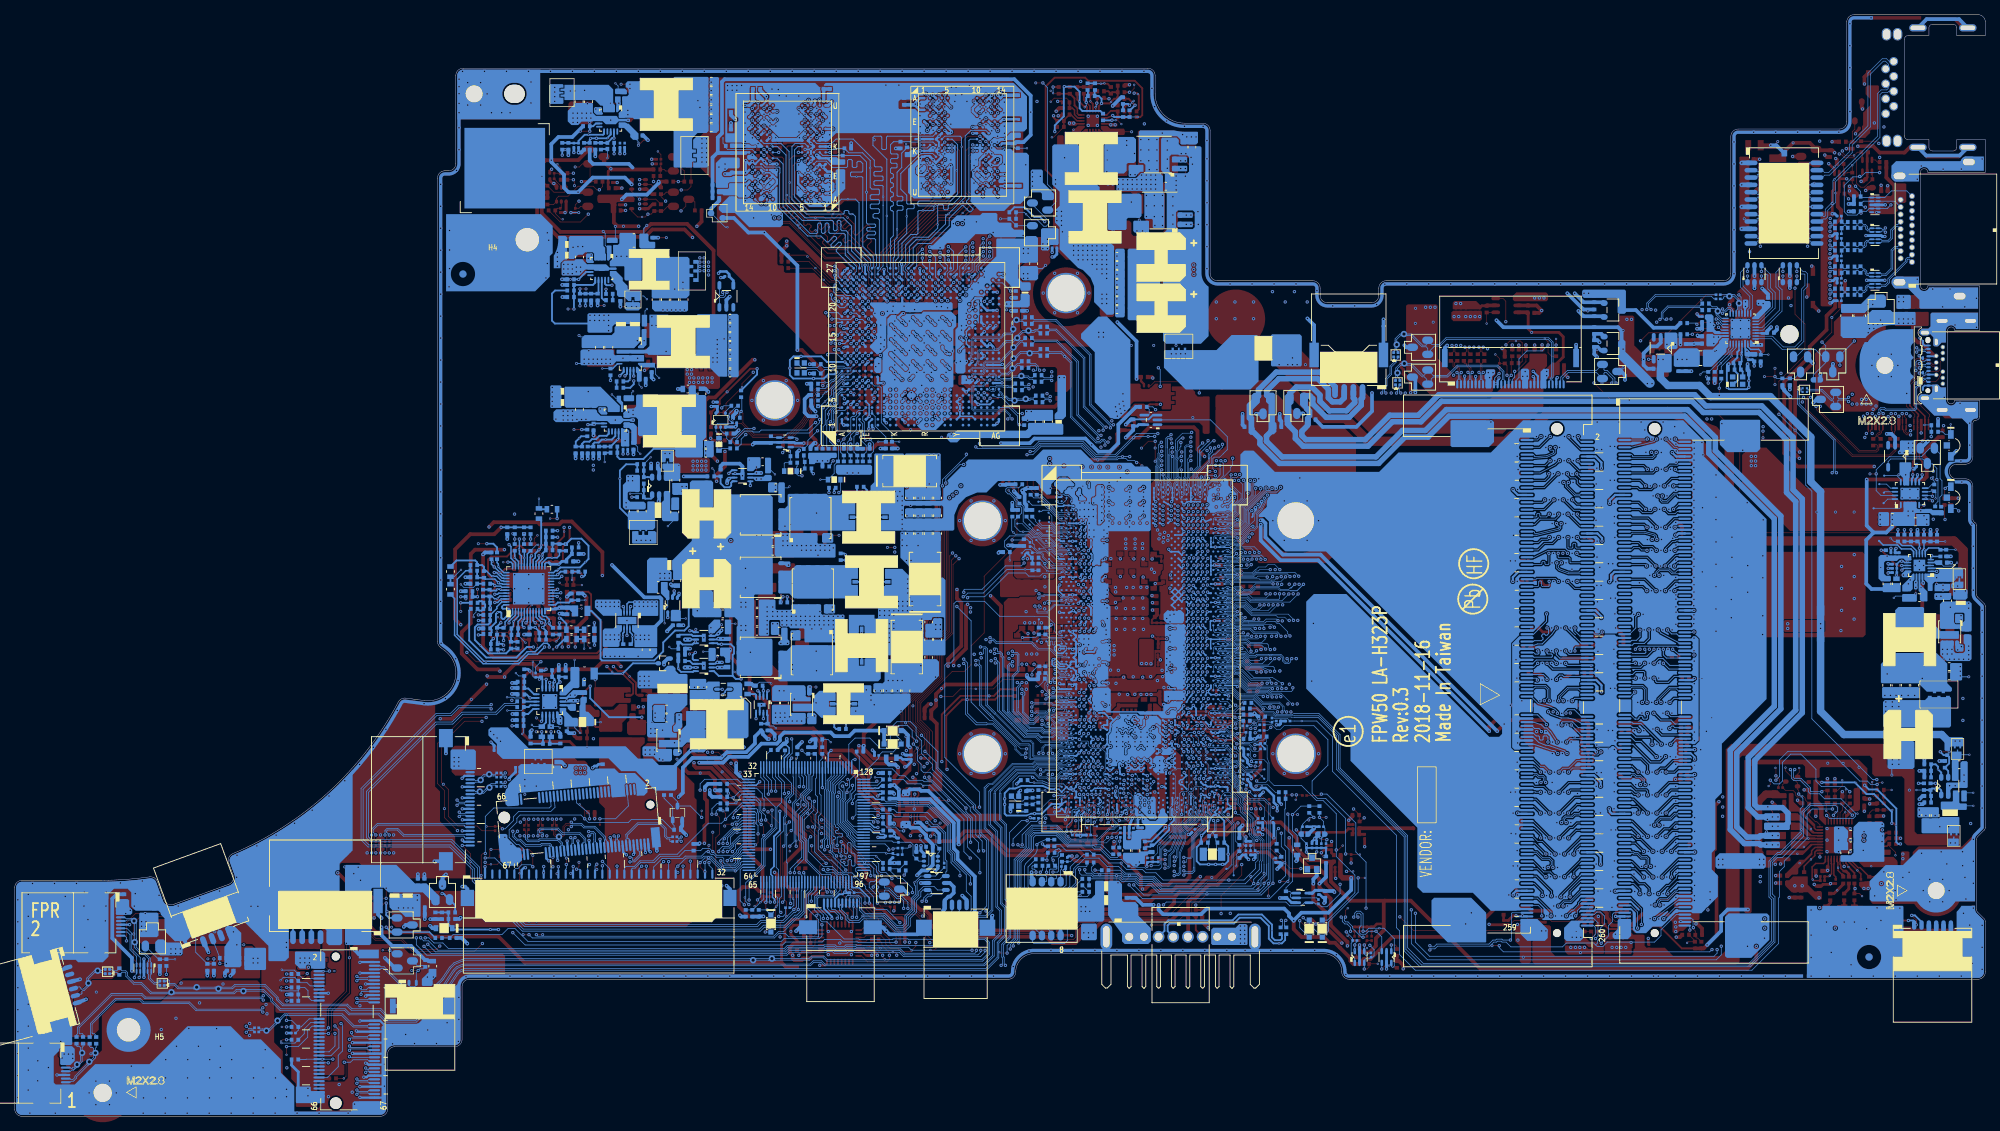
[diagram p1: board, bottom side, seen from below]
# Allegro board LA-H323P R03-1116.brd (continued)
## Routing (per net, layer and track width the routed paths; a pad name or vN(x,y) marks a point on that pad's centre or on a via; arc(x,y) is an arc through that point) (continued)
+2.5V:
  vias: v2(10.36,44.51) v3(4.11,37.29) v3(4.75,37.29) v3(49.84,24.84) v3(50.45,24.84) v3(59.92,25.3) v3(60.5,25.3)
+2.5VP: length 11.6
  TOP w0.102: v3(6.21,39.52) v2(5,39.52)
  IN2 w0.254: v3(6.21,39.52) 7.48,40.79 7.48,45.61 v3(9,47.14)
  BOTTOM w0.508: PR2506.1 PC2504.1 v3(9,47.14)
+3V_EC_VDD: length 2.8
  BOTTOM w0.203: UK1.125 v1(151.38,44.77) 150.9,44.77 150.59,45.08 RK3.1
+3V_FPR: length 0.8
  TOP w0.102: v3(252.94,28.1) 253.12,28.1 v2(253.56,27.66)
+3V_HDA: length 3
  TOP w0.076: v2(113.71,52.58) 113.42,52.87 v3(113.42,53.06)
  TOP w0.254: CC269.1 113.88,53.51 v3(113.42,53.06)
  TOP w0.356: RC150.2 113.19,54.21 113.61,53.79 CC269.1
  BOTTOM w0.254: UC1.BT20 113.49,53.01 v3(113.42,53.06)
+3V_LID: length 410.5
  TOP w0.508: v3(26.58,98.19) 26.58,98.07 26.58,98.07 26.58,91 v3(25.35,89.77) ; v3(156,37.47) 153.97,35.44 153.97,34.83 152.61,33.47 152.61,32.52 152.27,32.18 150,32.18 149.59,31.77 149.18,31.77 147.17,29.76 146.79,29.76 145.19,28.16 144.57,28.16 143.85,27.45 143.85,26.18 141.45,23.78 138.32,23.78 137.6,24.51 128.05,24.51 127.17,23.63 124.07,23.63 123.55,24.15 123.55,25.29 123.07,25.77 121.27,25.77 120.3,26.74 111.01,26.74 109.58,28.16 PR18.2 108.69,29.26 108.23,29.73 107.73,29.73 105.85,31.6 104.68,31.6 102.1,34.19 102.1,34.78 100.86,36.02 v2(99.16,36.02) 97.85,36.02 94.69,32.86 91.31,32.86 90.8,32.35 v3(90.8,31.74) 90.8,31.24 89.26,29.7 89.26,26.09 86.98,23.81 v3(86.98,23.26) ; v3(176.07,48.24) 176.07,47.85 175.78,47.56 173.71,47.56 168.48,42.32 168.48,36.95 167.97,36.44 v3(165.65,36.44) ; v3(201.93,77.31) 205.93,77.31 206.51,76.73 206.51,67.28 207.74,66.05 207.74,63.13 205.59,60.98 202.78,60.98 v3(202.54,60.74)
  IN1 w0.508: v3(165.65,36.44) 165.62,36.44 164.32,37.74 160.93,37.74 160.72,37.52 159.46,37.52 159.25,37.73 156.36,37.73 156.1,37.47 v3(156,37.47) 155.97,37.49 155.94,37.49 155.7,37.74 151.3,37.74 v3(150.99,38.06) ; v3(201.93,77.31) 200.05,75.43 196.31,75.43 195.88,75 195.88,73.31 195.08,72.51 183.71,72.51 182.62,71.42 180.5,71.42 177.52,68.44 v3(177.52,67) ; v3(202.54,60.74) 202.54,53.24 197.83,48.53 188.64,48.53 187.37,47.26 177.28,47.26 176.3,48.24 v3(176.07,48.24) ; v3(30.08,26.94) 30.57,26.94 36.76,20.76 78.01,20.76 78.71,21.46 85.56,21.46 86.98,22.87 v3(86.98,23.26) ; v3(15.13,135.53) 15.13,125.58 14.82,125.27 14.82,117.05 17.32,114.55 17.32,107.31 24.45,100.18 24.45,100.14 26.4,98.19 v3(26.58,98.19)
  IN2 w0.508: v3(30.08,26.94) 32.39,26.94 33.41,27.96 33.41,44.68 25.35,52.74 v3(25.35,89.77)
  BOTTOM w0.203: 149.94,38.23 150.19,38.48 150.64,38.48 150.85,38.68 151.56,38.68 152.05,39.17 UK1.111
  BOTTOM w0.356: v3(150.99,38.06) 150.97,38.04 150.14,38.04 149.94,38.23 CK11.1
  BOTTOM w0.508: v3(26.58,98.19) 27.41,99.02 27.41,99.14 27.67,99.4 R215.1 ; PR20.1 v3(177.52,67) ; v3(90.8,31.74) 89.9,32.65 RC462.1
+3V_LID_R: length 8.3
  TOP w0.102: PR18.1 109.44,27.25 110.59,26.11 v2(113.72,26.11)
  TOP w0.508: PR18.1 108.69,24.53 PJPB1.5
+3V_PRIM: length 268
  TOP w0.076: 114.37,37.36 114.33,37.39
  TOP w0.356: v3(121.48,40.79) 121.48,42.36 RC964.2 RC966.2 ; RC1158.2 RC470.2 RC1159.2 RC469.2 83.38,25.84 82.98,26.25 82.02,26.25 ; CC336.1 116.91,38.63 119.82,38.63 ; RC965.2 RC963.2
  TOP w0.381: v3(99.46,41.96) 99.46,42.13 99.68,42.35 RC115.1 ; RC965.2 123.17,41.7 122.58,41.1 122.21,41.1 121.89,40.79 v3(121.48,40.79) ; CC314.1 114.46,34.26 v3(114.32,34.12) ; 114.98,38.56 114.98,38.04 ; 114.98,38.56 114.98,38.95 115.88,39.85 RC467.2 116.62,40.08 v3(117.2,40.66) 117.03,40.66 116.49,41.19 RC468.2 115.62,41.19 RC360.2 RC380.2 115.68,41.89 RC50.2 RC49.2 RC226.2 RC374.2 ; 114.98,38.56 115.01,38.54 CC74.1 CC336.1 ; RC985.1 108.82,41.51 v3(108.54,41.23) ; RC959.1 122.83,36.34 120.76,36.34 120.38,36.72 120.38,38.07 119.82,38.63
  TOP w0.508: RC154.1 99.17,40.79 99.46,41.08 v3(99.46,41.96) ; RC154.1 96.07,40.1 93.84,37.87 93.84,36.47 92.31,34.95 90.66,34.95 90.47,34.75 RC967.2 89.09,34.5 89.09,34.49 89.24,34.34 89.24,32.05 86.61,29.42 81.91,29.42 ; RC154.1 99.51,40.1 CC67.1 CC332.1 100.69,39.68 100.72,39.71 v3(101.28,39.71) ; 107.68,39.14 108.69,39.14 109.08,39.52 109.08,40.7 v3(108.54,41.23) ; 107.68,39.14 107.68,38.37 108.8,37.26 112.06,37.26 113.52,38.72 ; 107.68,39.14 103.74,39.14 102.25,40.63 101.43,40.63 101.25,40.45 101.25,39.73 v3(101.28,39.71) ; v3(171.05,78.56) 171.05,62.67 168.5,60.12 168.5,58.17 167.37,57.04 166.73,57.04 165.84,56.15 165.84,53.44 165.34,52.93 159.83,52.93 158.19,51.29 158.19,49.82 157.65,49.28 156.03,49.28 152.91,46.16 152.91,44.7 149.6,41.39 149.6,39.44 149.16,39 148.55,39 147.1,37.55 140.52,37.55 139.19,38.88 135.89,38.88 133.24,36.24 128.49,36.24 127.8,36.94 RC959.1 ; v3(101.28,39.71) 101.28,38.58 v3(100.82,38.12) ; 81.91,29.42 82.02,29.31 82.02,25.37 83.1,24.29 83.1,23.25 83.99,22.36 84.93,22.36 85.33,22.75 v3(85.33,23.37) ; 81.91,29.42 78.33,29.42 75.15,26.25 v2(70.86,26.25) 68.99,26.25 66.82,28.42 RD32.1 62.26,28.42 61.89,28.04 55.87,28.04 53.98,29.93 51.88,29.93 51.09,29.14 49.12,29.14 48.9,28.93 RD33.1 ; 113.52,38.72 113.52,39.01 112.56,39.97 112.56,40.91 ; 113.52,38.72 113.52,38.2 114.33,37.39 114.98,38.04 ; 114.37,37.36 114.46,37.26 CC314.1 ; RC980.2 100.21,55.62 99.34,55.62 98.37,54.65 98.37,51.49 98.84,51.02 98.84,47.31 v3(100.08,46.07)
  IN1 w0.508: v3(171.05,78.56) 173.83,81.34 173.83,85.43 174.99,86.58 180.13,86.58 181.92,88.37 v3(181.92,89.06) ; v3(99.46,41.96) 99.46,41.61 99.98,41.09 99.98,38.96 v3(100.82,38.12)
  IN2 w0.508: v3(99.46,41.96) 99.46,44.26 100.1,44.89 100.1,46.06 v3(100.08,46.07)
  BOTTOM w0.203: UC1.CP29 108.54,41.71 v3(108.54,41.23)
  BOTTOM w0.254: UC1.BP23 111.95,53.92 v3(111.74,53.71) ; v3(115.92,48.49) 116.27,48.83 UC1.CB16 ; UC1.BW23 v3(111.76,50.47) ; RC491.2 RC472.2 114.16,34.72 CC51.1 114.32,34.55 v3(114.32,34.12)
  BOTTOM w0.356: v3(100.08,46.07) 100.08,46.28 100.44,46.63 RC379.2
  BOTTOM w0.381: v3(85.33,23.37) 85.33,20.94 ; v3(100.82,38.12) RC127.1 RC916.2
  BOTTOM w0.508: v3(101.28,39.71) 101.71,39.27 RC900.2 ; PR1801.1 v3(181.92,89.06)
  vias: v3(111.81,47.86) v3(112.58,48.51) v3(112.58,47.86) v3(112.58,47.21)
+3V_PRIM_DA: length 5.2
  TOP w0.102: v3(63.99,27.37) 63.12,27.37 v2(63.11,27.38)
  TOP w0.356: RD32.2 CD2.2 CD1.2 64.42,27.37 v3(63.99,27.37)
  BOTTOM w0.254: JDIMM1.255 62.5,27.28 63.9,27.28 v3(63.99,27.37)
+3V_PRIM_DB: length 4.1
  TOP w0.102: v1(49.82,26.97) 50.11,26.97 v3(50.41,27.28)
  TOP w0.254: v3(50.41,27.28) 50.41,27.78 CD61.2 CD60.1 48.97,27.92 RD33.2
  BOTTOM w0.305: JDIMM2.255 49.18,27.28 v3(50.41,27.28)
+3V_SMBUS: length 57.7
  TOP w0.508: RK111.1 RK110.1 163.61,31.64 163.61,34.51 161.53,36.6 161.53,38.12 162.14,38.73 162.14,40.27 164.45,42.58 167.83,42.58 v2(172.24,46.99) 173.45,48.19 175.29,48.19 v3(175.36,48.25)
  BOTTOM w0.508: DH5.1 DH4.1 154.16,52.62 154.91,51.87 156.93,51.87 157.42,52.37 163.77,52.37 164.36,51.79 164.36,51.27 164.78,50.85 166.87,50.85 168.67,49.05 171.32,49.05 172.11,48.25 v3(175.36,48.25)
+3V_SPI: length 85.3
  TOP w0.356: v3(126.09,25.8) 126.55,25.34 CC8.1
  TOP w0.508: v3(126.09,25.8) 125.08,25.8 124.24,26.64 121.63,26.64 120.66,27.6 112.1,27.6 110.6,29.1 110.6,29.87 ; v3(124.53,35.52) 124.53,35.33 124.02,34.82 120.85,34.82 119.83,33.8 119.83,30.82 118.42,29.41 113.79,29.41 113.33,29.86 110.6,29.86 ; 110.6,29.87 109.88,30.59 108.12,30.59 106.14,32.58 v2(105.47,32.58) 104.93,32.58 102.96,34.55 102.96,35.18 101.1,37.04 97.52,37.04 97.01,37.55 v3(97.01,37.99) 98.17,39.15 v3(98.5,39.15) 98.54,39.19 RC154.2
  IN2 w0.254: v3(111.74,51.11) 111.23,50.6 111.23,50.11 111.35,49.99 111.35,49.63 111.34,49.62 111.34,47.61 110.77,47.03 110.77,46.92 108.44,44.6 107.81,44.6 107.36,44.15 107.36,43.14 106.03,41.8 106.03,40.47 105.44,39.88 104.57,39.88 102.77,40.63 102.39,40.79 101.24,40.79 100.69,40.24 99.77,40.24 98.68,39.15 v3(98.5,39.15)
  BOTTOM w0.254: UC1.BV23 v3(111.74,51.11)
  BOTTOM w0.356: v3(124.53,35.52) 124.98,35.52 RC357.2
  BOTTOM w0.381: RC941.2 97.01,39.96 v3(97.01,37.99) ; RC384.2 RC383.2 98.53,39.18 v3(98.5,39.15)
  BOTTOM w0.508: UC2.8 v3(126.09,25.8)
+3VALW: length 405.2
  TOP w0.381: 164.13,20.98 164.13,23.5 163.69,23.95 163.69,25.88 162.72,26.84 161.2,26.84 v3(160.82,27.22) 160.81,27.23 160.81,29.97 160.43,30.35 RK12.2 RK13.2
  TOP w0.508: v3(189.77,92.9) 189.06,92.18 v3(185.47,92.18) ; v3(141.31,26) 140.67,25.37 127.42,25.37 126.36,26.44 125.34,26.44 124.5,27.27 121.89,27.27 120.92,28.24 113.04,28.24 112.72,28.56 v3(112.72,28.84) ; v3(224.65,33.23) 221.6,30.18 221.6,27.25 219.45,25.1 212.4,25.1 211.82,24.52 202.71,24.52 199.17,20.98 164.13,20.98 163.55,20.39 RC934.2 ; v3(94.31,26.7) 94.31,25.55 93.23,24.47 RC434.2 90.22,24.47 89.44,23.69 88.69,23.69 88,23.01 87.99,23.01 86.57,21.58 86.57,21.2 86.14,20.77 RC81.2 84.98,20.77 RC82.2 84.95,21.27 84.72,21.5 83.83,21.5 80.84,24.48 73.21,24.48 68.85,20.12 32.46,20.12 31.22,21.36 v3(31.22,23.2) ; v3(3.48,51.2) v3(4.11,51.2)
  IN1 w0.508: v3(141.31,26) 143.21,26 144.47,24.74 149.5,24.74 149.65,24.59 157.15,24.59 157.21,24.53 159.88,24.53 160.82,25.47 v3(160.82,27.22)
  IN2 w0.457: v3(157.27,26.99) 157.27,27.24 157.63,27.6 158.67,27.6 159.09,27.17 160.76,27.17 v3(160.82,27.22)
  IN2 w0.508: v3(31.22,23.2) 31.22,23.64 34.68,27.1 34.68,45.21 26.95,52.94 v3(26.95,66.57)
  IN2 w1.016: 180.91,90.43 182.42,90.43 184.39,88.46 188.78,88.46
  BOTTOM w0.254: v3(157.27,26.99) 157.27,27.26 158.35,28.34 JTP1.1
  BOTTOM w0.508: 184.45,129.43 184.96,129.94 189.85,129.94 190.29,130.39 PRW3.1 ; DT2.5 141.18,31.83 140.66,31.31 140.66,30.49 141.17,29.98 141.39,29.98 141.9,29.47 JTP2.1 141.9,28.28 142.1,28.09 142.1,26.79 v3(141.31,26) ; PR1003.1 v3(189.81,89.73) ; v3(86.47,32.53) 86.47,30.88 89.57,27.78 93.25,27.78 94.31,26.73 v3(94.31,26.7) 94.94,27.34 94.94,27.68 95.6,28.34 106.15,28.34 106.92,27.58 112.12,27.58 112.72,28.18 v3(112.72,28.84) ; PR304.1 v3(194.06,114.19) ; PR1005.1 v3(189.77,92.9)
  BOTTOM w1.016: 22.46,68.47 22.46,85.24 23.8,86.57 23.8,92.67 29.32,98.19 37.45,98.19 38.97,99.72 43.29,99.72 44.31,100.74 CL28.1 ; 22.46,65.3 22.46,55.27 19.29,52.09 5.95,52.09 5.06,51.2
  vias: v2(49.39,107.21) v2(49.39,104.67) v2(49.39,102.13) v3(22.46,67.2) v3(22.46,66.57) v3(26.95,67.2) v3(43.94,103.26) v3(44.58,103.26) v3(48.24,108.73) v3(48.88,108.73) v3(174.1,116.54) v3(174.1,115.96) v3(174.1,115.37) v3(174.1,114.79) v3(174.69,117.13) v3(174.69,116.54) v3(174.69,115.96) v3(174.69,115.37) v3(175.28,117.13) v3(175.28,116.54) v3(175.28,115.96) v3(175.28,115.37) v3(179.38,90.43) v3(180.02,90.43) v3(186.35,70.15) v3(186.35,69.56) v3(186.93,70.15) v3(186.93,69.56) v3(187.52,70.15) v3(187.52,69.56) v3(188.1,70.15) v3(188.1,69.56) v3(188.69,70.15) v3(188.69,69.56) v3(189.27,70.15) v3(189.27,69.56) v3(189.8,88.82) v3(189.8,88.18) v3(246.12,22.84) v3(246.12,22.21) v3(246.76,22.84) v3(246.76,22.21) v3(247.39,22.84) v3(247.39,22.21)
+3VALW_DSW: length 20.4
  TOP w0.102: v1(90.2,35.44) 90.53,35.77 v3(90.53,35.96)
  TOP w0.356: v3(90.53,35.96) 90.13,36.37 CC342.1 CC323.1 89.14,35.95 RC173.2
  TOP w0.381: v3(100.08,41.97) RC187.2 RC926.1 RC103.1
  IN2 w0.508: v3(99.35,37.65) 97.94,37.65 97.39,37.1 92.38,37.1 91.87,36.6 91.87,35.77 91.39,35.29 90.95,35.29 90.53,35.71 v3(90.53,35.96)
  BOTTOM w0.254: v3(110.89,53.08) 110.92,53.07 UC1.BR24 ; v3(111.72,52.44) 111.78,52.43 UC1.BT23
  BOTTOM w0.356: v3(100.13,47.85) 100.22,47.85 100.63,48.25 RC483.2 100.63,48.66 101.11,49.14 RC106.1
  BOTTOM w0.381: v3(101.65,50.27) 101.26,50.27 RC104.1 RC106.1
+3VALW_EC: length 245.9
  TOP w0.457: v3(147.32,23.78) 147.32,26.61 147.77,27.07 149.21,27.07 150.38,28.24 151.32,28.24 v3(152.17,29.1)
  TOP w0.508: v3(166.61,27.28) 168.59,27.28 169.95,28.63 169.95,30.77 169.44,31.27 167.75,31.27 167.22,30.75 LK1.1 166.73,33.92 169.11,36.3 169.11,41.88 169.9,42.67 171.38,42.67 v3(173.22,44.51) 173.22,46.02 174.04,46.83 v2(175.23,46.83) 176.86,46.83 177.33,47.3 177.33,50.22 176.96,50.59 176.16,50.59 175.45,49.88 174.89,49.88 174.48,50.29 172.18,50.29 170.33,48.43 v3(170.33,48.18) ; v3(147.09,85.88) 146.26,85.06 144.5,85.06 143.01,83.57 143.01,69.01 144.41,67.61 144.41,60.67 151.59,53.49 151.62,53.49 152.93,52.18 v3(152.93,50.57) 152.93,50.15 151.59,48.81 148.09,48.81 147.33,48.05 v3(147.33,47.67) ; v3(167.79,103.22) 168.07,103.22 173.21,98.08 174.09,98.08 174.57,97.59 174.57,92.35 173.6,91.38 173.6,90.11 v3(172.88,89.39) ; RG67.2 175.04,122.06 v3(175.67,121.43) ; v3(151.02,43.71) 152.27,44.96 152.27,47.7 154.49,49.92 v3(157.39,49.92)
  IN1 w0.508: v3(170.33,48.18) 169.63,48.88 v3(162.76,48.88) 162.58,48.7 159.43,48.7 159.07,49.05 159.06,49.05 158.2,49.92 v3(157.39,49.92) 157.3,50.01 155.78,50.01 155.32,50.46 154.39,50.46 153.85,49.93 153.24,49.93 152.93,50.24 v3(152.93,50.57) ; v3(167.79,103.22) 167.79,107.61 169.22,109.05 169.22,114.98 v3(175.67,121.43) ; v3(166.61,27.28) 165.96,27.28 161.62,22.93 148.12,22.93 147.32,23.73 v3(147.32,23.78)
  IN2 w0.508: v3(147.09,85.88) 158.01,85.88 v3(159.8,87.68) 160.18,87.68 161.07,88.56 164.73,88.56 165.06,88.89 172.39,88.89 v3(172.88,89.39)
  BOTTOM w0.203: v3(151.02,43.71) 150.77,43.96 150.53,43.96 CK8.1 150.48,44.37 UK1.124 ; v3(152.17,29.1) 152.17,29.8 153.57,31.19 154.36,31.19 154.57,31.4 UK1.96 ; UK1.22 162.97,48.67 v3(162.76,48.88) ; v3(157.39,49.92) 157.76,49.54 UK1.9 ; UK1.33 169.38,45.97 169.79,46.38
  BOTTOM w0.254: RV26.2 160.06,87.93 v3(159.8,87.68)
  BOTTOM w0.356: RK1.2 147.85,48.93 147.62,48.7 CK1.1 146.48,48.7 CK2.1 146.46,48.36 147.15,47.67 v3(147.33,47.67)
  BOTTOM w0.508: RK7.2 173.19,44.47 v3(173.22,44.51) ; RK2.2 RK21.1 167.16,27.25 167.13,27.28 v3(166.61,27.28) ; v3(170.33,48.18) 170.33,46.92 169.79,46.38 ; PR9.1 152.98,50.52 v3(152.93,50.57)
+3VALWP: length 23.6
  TOP w0.102: v3(177.58,112.86) v2(177.58,113.79)
  IN2 w0.254: v3(177.58,112.86) 178.59,111.86 185.35,111.86 186.34,112.85 v3(188.07,112.85)
  IN2 w0.381: v3(178.7,112.86) 179.2,112.36 185.15,112.36 186.18,113.39 v3(187.26,113.39)
  BOTTOM w0.254: PR305.2 v3(188.07,112.85) ; v3(187.26,113.39) 188.02,113.39 188.19,113.57 PU301.14
+3VL: length 480.5
  TOP w0.508: v3(87.74,23.64) 90,25.9 90,27.91 91.63,29.53 v3(91.63,31.73) ; DH2.2 16.48,141.81 v3(16.48,140.85) ; v3(23.54,102.76) 25.94,100.36 v2(25.94,93.62) 25.94,91.26 v3(25.32,90.63) ; v3(204.28,60.09) 204.12,59.94 v3(201.9,59.94) 201.9,60.29 200.46,61.73 198,61.73 197.26,60.99 v3(196.25,60.99) ; PR16.1 106.76,26.52 v3(105.97,25.73) ; v3(153.59,50.57) 153.59,49.92 151.8,48.13 148.76,48.13 v3(148.26,47.62) 148.26,46.82 148.75,46.32 v3(148.75,45.18) 146.69,47.24 146.69,48.95 146.51,49.14 146.51,50.2 v3(146.63,50.32) ; v3(188.57,73.79) 188.57,76.98 192.74,81.16 194.05,81.16 194.45,80.77 197.09,80.77 197.38,81.06 203.37,81.06 v3(204.02,80.42)
  IN1 w0.508: v3(204.02,80.42) 204.02,95.96 193.96,106.01 193.96,110.37 193.04,111.3 185.56,111.3 185.03,110.78 ; v3(201.9,59.94) 201.9,53.78 201.39,53.28 v3(200.88,53.28) 200.88,52.49 197.57,49.17 188.38,49.17 187.11,47.9 177.54,47.9 176.56,48.88 171.97,48.88 171.22,49.63 162.42,49.63 162.12,49.33 159.69,49.33 159.44,49.58 158.38,50.64 156.04,50.64 155.58,51.1 154.12,51.1 v3(153.59,50.57) ; v3(16.48,140.85) 16.48,140.32 16.02,139.87 16.02,127.49 17.08,126.43 17.08,116.04 18.21,114.91 18.21,108.1 v3(23.54,102.76) ; v3(188.57,73.79) 183.46,73.79 182.1,72.44 180.02,72.44 179.27,71.69 v3(178.77,71.69) ; v3(139.94,24.44) 125.65,24.44 124.44,25.65 121.38,25.65 120.21,26.82 119.36,26.82 118.59,26.04 114.62,26.04 114.51,25.93 106.65,25.93 106.45,25.73 v3(105.97,25.73) 105.22,26.48 103.74,26.48 103.52,26.7 99.13,26.7 96.56,24.14 88.24,24.14 v3(87.74,23.64) 87.74,22.74 85.76,20.76 78.96,20.76 78.33,20.12 36.5,20.12 30.94,25.67 v3(30.08,25.67)
  IN2 w0.508: v3(25.32,90.63) 25.62,90.63 25.99,90.27 25.99,53 34.04,44.94 34.04,27.55 32.16,25.67 v3(30.08,25.67) ; v3(204.02,80.42) 205.72,78.71 205.72,71.9 206.48,71.14 206.48,65.81 204.96,64.28 204.96,60.78 v3(204.28,60.09)
  BOTTOM w0.254: PRB15.1 196.43,60.81 v3(196.25,60.99) ; PRB16.2 v3(200.88,53.28)
  BOTTOM w0.381: v3(178.77,71.69) 178.77,71.24 179,71.01 PQ2.5
  BOTTOM w0.508: R295.2 148.18,43.35 ; 148.18,43.35 148.09,43.26 143.88,43.26 140.65,40.02 140.65,36.55 140.14,36.04 140.14,35.09 137.78,32.72 137.78,27.94 138.82,26.9 138.82,25.56 v3(139.94,24.44) ; 148.18,43.35 148.14,43.39 148.14,44.57 v3(148.75,45.18) 149.28,45.18 RK3.2 ; v3(146.63,50.32) 146.9,50.59 146.9,52.01 147.51,52.62 DH4.2 ; RK1.1 149.87,48.38 149.49,48 148.64,48 v3(148.26,47.62) ; DC1.3 91.15,32.83 91.63,32.35 v3(91.63,31.73) ; v3(23.54,102.76) 24.23,103.45 Q4108.2
  vias: v3(183.93,110.45) v3(184.56,110.45)
+3VLP: length 1.2
  BOTTOM w0.102: v1(182.49,111.49) 182.93,111.92 183.5,111.92
+3VS: length 605.5
  TOP w0.254: RD20.1 41.39,22.91 44.4,25.93 45.58,25.93 46.34,25.17 47.74,25.17 48.12,25.55 51.35,25.55 RD1.1 52.22,26.41 52.22,27.49 52.59,27.86 53.13,27.86 54.66,26.34 RD4.1 ; v3(11.57,37.16) 12.17,37.16 RA23.2
  TOP w0.356: QG1.5 QG1.2 19.92,126.08 RG47.1 ; RC952.1 RC105.1 RC953.1 RC955.1 ; RG110.1 16.11,131.4 QG2.2 QG2.5 16.11,128.11 16.32,127.91 RG111.1
  TOP w0.381: RC105.1 105.9,41.51 105.52,41.13 RC954.1 ; v3(18.91,127.91) 19.92,127.91 ; RC122.2 RC201.1 RC118.1 107.04,39.73 105.93,39.73 ; RC410.2 RC382.2 RC961.2 123.38,38.89 v3(123.38,38.23) ; 106.54,41.17 106.57,41.13 RC165.1 ; 106.54,41.17 RC953.1 ; 106.54,41.17 105.93,40.56 105.93,39.73 ; 105.93,39.73 104.1,39.73 103.23,40.6 v3(103.23,41.19) 103.23,41.52 103.49,41.78 RC381.2 RC475.2 RC107.2 ; R5201.1 68.66,110.59 CG1.1
  TOP w0.508: v3(15.15,88.66) 25.63,88.66 27.41,90.44 27.41,100.22 23.95,103.69 23.95,105.01 21.65,107.31 21.65,109.21 20.49,110.37 20.49,121.76 19.67,122.58 19.67,123.65 20.13,124.11 RG47.1 ; v3(140.22,71.88) 140.22,70.67 139.62,70.07 139.62,64.19 141.43,62.38 v3(141.43,61.44) ; RG111.1 16.38,127.85 16.66,127.56 v3(16.94,127.56) ; v3(79.37,20.12) 79.37,20.59 79.95,21.18 RC215.2 RC216.2 ; QV20.3 v3(191.88,126.08) ; v3(176.53,49.92) 175.85,49.24 174.66,49.24 174.25,48.83 173.18,48.83 167.57,43.21 164.18,43.21 161.48,40.5 161.48,39.02 160.89,38.44 RK113.1 RK112.1 ; RD21.1 v3(42.24,45.98) 49.24,45.98 49.89,46.63 51.04,46.63 52.05,47.64 RD2.1 ; v3(94.92,37.99) 94.92,36.91 94.47,36.47 94.47,36.21 92.3,34.03 91.07,34.03 89.95,32.91 89.95,31.8 v3(88.76,30.6) ; v3(204.83,76.66) 204.83,64.03 203.44,62.63 189.12,62.63 188.08,63.67 v3(188.08,65.04) ; R5201.1 67.94,110.64 66.76,110.64 ; QV26.3 191.85,130.46 195.52,130.46 v3(195.53,130.45) 196.31,130.45 197.47,129.29 197.47,122.83 194.62,119.98 182.76,119.98 181.76,120.99 177.35,120.99 v3(176.27,119.91) ; v3(118.79,37.49) 118.79,36.43 115.13,32.77 115.13,31.22 v3(114.92,31.01) 114.56,31.01 113.97,31.6 111.4,31.6 110.85,32.15 109.01,32.15 108.5,32.66 108.5,36.33 107.21,37.62 106.61,37.62 105.8,38.44 103.49,38.44 v3(101.9,40.03) ; v3(36.33,42.93) 36.86,42.4 36.86,36.47 37.12,36.22 37.12,33.09 36.65,32.62 36.65,24.67 v3(37.93,23.39) 38.41,22.91 RD19.1 RD20.1 ; UV12.5 v3(184.57,127.15)
  IN1 w0.508: v3(94.92,37.99) 95.3,38.37 95.3,39.76 96.56,41.02 v3(96.56,41.68) ; v3(169.27,50.36) 164.18,50.36 164.18,50.36 162.49,50.36 161.78,51.08 v3(161.35,51.08) 161.08,51.08 160.42,50.41 159.5,50.41 158.64,51.28 156.3,51.28 155.32,52.26 151.19,52.26 142.01,61.44 v3(141.43,61.44) ; v3(134.22,91.84) 134.65,91.84 138.58,87.91 144.81,87.91 145.3,88.4 152.51,88.4 153.14,89.02 156.23,89.02 157.61,87.64 158.75,87.64 159.86,88.75 160.38,88.75 160.87,89.24 160.87,89.99 v3(161.73,90.86) 162.3,90.86 163.13,91.69 167,91.69 167.71,92.4 170.5,92.4 173.26,95.16 173.26,96.38 173.72,96.84 v3(173.72,96.84) ; v3(101.9,40.03) 102.73,40.03 103.23,40.53 v3(103.23,41.19) ; v3(176.27,119.91) 172.74,116.37 v3(172.74,115.02) ; v3(140.22,71.88) 139.82,72.28 135.42,72.28 133.18,74.53 133.18,75.11 130.09,78.19 130.09,80.76 128.6,82.25 128.17,82.25 127.78,82.64 126.25,82.64 125.98,82.92 125.98,85.75 125.75,85.98 125.75,87.98 126.59,88.82 126.59,89.7 125.98,90.3 123.15,90.3 v3(121.85,91.61) ; v3(26.5,110.61) 24.63,110.61 22.72,112.53 22.72,126.89 21.7,127.91 v3(18.91,127.91) 17.76,127.91 17.42,127.56 v3(16.94,127.56) ; v3(36.33,42.93) 37.61,44.22 40.48,44.22 v3(42.24,45.98) ; v3(118.79,37.49) 120.63,37.49 121.15,38.01 123.15,38.01 v3(123.38,38.23)
  IN2 w0.508: v3(173.72,96.84) 174.11,97.23 174.11,97.84 172.6,99.34 172.6,102.09 171.79,102.91 171.79,109.58 173.12,110.92 173.12,114.64 v3(172.74,115.02) ; v3(3.94,90.79) 5.99,90.79 7.22,89.56 12.56,89.56 13.45,88.66 v3(15.15,88.66)
  BOTTOM w0.254: v3(16.45,45.17) 15.87,44.59 14.74,44.59 12.13,41.98 12.13,37.42 11.88,37.16 v3(11.57,37.16)
  BOTTOM w0.356: UC11.4 170.71,114.03 CC127.1 171.28,114.89 171.65,115.26 172.5,115.26 v3(172.74,115.02) ; RC409.2 100.59,45.83 100.15,45.38 RC117.1 100.15,44.98 99.72,44.55 98.98,44.55 98.73,44.8 98.11,44.8 97.01,43.7 97.01,42.82 96.56,42.36 v3(96.56,41.68)
  BOTTOM w0.381: UV23.5 172.88,96.13 CV223.1 173.71,96.86 173.72,96.84 v3(173.72,96.84) ; v3(81.64,20.1) QC1.5 QC1.2 ; RC962.2 123.52,38.37 v3(123.38,38.23) 123.24,38.37 RC978.2
  BOTTOM w0.406: UC4.5 91.76,30.45 91.38,30.83 CC14.1 90.13,30.83 CC315.1
  BOTTOM w0.508: 178.75,47.24 178.75,47.7 v3(176.53,49.92) 174.84,49.92 174.39,50.36 v3(169.27,50.36) ; RC429.1 115.81,96.79 118.22,94.38 118.22,91.84 119.37,90.69 120.93,90.69 v3(121.85,91.61) 122.72,92.48 129.65,92.48 130.28,91.84 v3(134.22,91.84) ; v3(37.93,23.39) 36.03,25.29 36.03,27.33 35.14,28.21 v3(32.37,28.21) ; v3(161.73,90.86) 162.01,90.59 RV15.2 ; LED2.2 v3(3.94,90.79) ; RE50.1 v3(241.54,19.2) ; v3(88.76,30.6) 88.9,30.74 CC315.1 ; RK14.1 161.98,50.44 v3(161.35,51.08) ; RF1.1 254.78,30.3 255.39,29.69 255.39,24.3 252.71,21.62 v3(252.71,19.84) ; PRW5.1 192.67,133.61 194.56,133.61 195.53,132.64 v3(195.53,130.45) 195.53,130.2 193.8,128.47 193.8,126.69 193.19,126.08 v3(191.88,126.08) 189.89,128.07 185.5,128.07 v3(184.57,127.15) ; FG4.1 47.65,110 45.24,107.59 42.2,107.59 RM6.1 ; JCR.1 v3(262.54,19.86) ; PRZ23.2 204.57,76.93 v3(204.83,76.66)
  vias: v2(17.22,47.62) v2(19.39,48.17) v2(21.48,48.18) v3(54.08,112.29) v3(54.72,112.29) v3(71.55,110.89) v3(72.18,110.89) v3(186.33,65.68) v3(186.33,65.04) v3(186.91,65.68) v3(186.91,65.04) v3(187.5,65.68) v3(187.5,65.04) v3(188.08,65.68) v3(202.46,51.16) v3(202.92,51.62) v3(203.37,52.08) v3(203.81,52.52)
+3VS_CAMERA: length 13.2
  TOP w0.381: 62.34,109.54 62.34,107.46 61.86,106.98 v2(61.86,106.95) 58.15,106.95 57.55,106.36 57.55,103.6 58.36,102.79 C5221.1 ; 62.34,109.54 62.34,109.61 ; 62.34,109.54 C5232.1
  TOP w0.508: 62.34,109.61 62.42,109.69 UG1.3
  vias: v3(59.8,101.63) v3(59.81,101.05)
+3VS_DGPU: length 90.5
  TOP w0.254: v3(167.47,102) 168.4,102 v2(171.56,98.84) 172.56,97.84 172.56,97.21 RV81.1 RV80.1
  TOP w0.356: CV319.1 187.78,126.73 CV318.2 187.78,128.92 v3(187.41,129.28)
  TOP w0.508: RV17.1 187.31,129.18 v3(187.41,129.28) 188.35,130.22 QV26.1
  IN1 w0.508: v3(167.47,102) 166.85,102.62 166.85,108.02 168.33,109.51 168.33,115.79 175.37,122.83 175.37,127.27 179.43,131.34 184.01,131.34 186.06,129.28 v3(187.41,129.28)
  IN2 w0.254: v3(167.47,102) 167.21,101.73 163.57,101.73 161.04,99.2 157.03,99.2 155.84,100.39 154.88,100.39 154.16,101.1 151.36,101.1 v3(150.28,100.02)
  BOTTOM w0.254: v3(167.47,102) 167.47,101.21 RV84.1
  BOTTOM w0.305: v3(150.28,100.02) 150.3,100.04 UV1.G8 151,100.82 UV1.G9
+3VS_DGPU_AON: length 168.1
  TOP w0.254: v3(168.07,91.65) 170.4,91.65 RV30.2 ; v3(126.88,134.35) 126.88,134.67 PRV3.2 ; v3(125.59,140.48) 125.54,140.43 PRV27.2
  TOP w0.508: RV2765.2 161.4,91.54 v3(161.1,91.84) 159.51,91.84 v3(159.5,91.85) ; v3(159.5,91.85) 159.5,92.27 160.12,92.89 160.12,94.82 160.01,94.99 160,95.02 159.5,95.52 v3(159.37,95.52) ; v3(159.5,91.85) 158.73,91.08 151.75,91.08 151.1,91.73 148.89,91.73 v3(148.28,91.12) ; RV69.2 180.7,126.85 180.7,127.34 v3(180.89,127.53) RV68.1 ; CV312.1 187,121.94 186.5,121.43 v2(185.7,121.43) v3(183.62,121.43)
  IN1 w0.254: v3(126.88,134.35) 126.88,133.95 122.3,129.37 122.3,127.28 116.75,121.73 116.75,120.82 115.83,119.91 114.41,119.91 113.5,118.99 113.5,108.58 122.35,99.73 128,99.73 128.93,100.65 132.21,100.65 133.66,99.21 138.03,99.21
  IN1 w0.508: v3(168.07,91.65) 170.65,91.65 173.9,94.9 173.9,95.94 174.48,96.53 174.48,97.45 172.99,98.95 172.99,101.93 172.27,102.65 172.27,107.27 172.55,107.55 172.55,109.65 174.42,111.51 175.15,111.51 176.27,112.63 176.27,112.63 178.29,114.65 178.29,116.1 v3(183.62,121.43)
  BOTTOM w0.254: PRV22.2 120.67,137.17 123.12,137.17 123.49,137.54 123.49,139.78 124.19,140.48 v3(125.59,140.48) 125.65,140.42 125.65,136.42 126.88,135.19 v3(126.88,134.35)
  BOTTOM w0.356: v3(161.1,91.84) 162.29,91.84 162.4,91.95 QV2.2 QV2.5 165.51,91.95 RV203.2
  BOTTOM w0.508: v3(159.37,95.52) 160.48,95.52 160.99,96.03 160.99,97.85 160.41,98.42 RV23.2 ; v3(185.91,125.12) 185.28,125.75 182.48,125.75 180.89,127.34 v3(180.89,127.53) ; v3(168.07,91.65) 167.84,91.88 RV203.2 ; RV204.2 160.18,91.35 159.68,91.85 v3(159.5,91.85) ; RV2766.2 v3(148.28,91.12)
  vias: v3(138.16,100.44) v3(138.95,100.44) v3(150.88,102.7) v3(151.3,102.29) v3(151.53,97.94) v3(153.65,87.78) v3(154.41,87.78) v3(155.18,87.78)
+3VS_SSD: length 3.6
  TOP w0.127: v3(199.14,45.05) v2(197.58,45.05) ; v3(199.14,45.05) v2(199.14,45.94) ; v3(199.14,45.05) v2(199.14,43.92)
+3VS_TOUCH: length 7.2
  TOP w0.127: v3(55.48,109.88) v2(54.2,109.88)
  BOTTOM w0.254: JEDP.23 61,99.97 61,100.98 v3(61.65,101.63)
  BOTTOM w0.508: FG4.3 52.09,109.16 CTS3.1 54.77,109.16 v3(55.48,109.88)
+3VS_TPM: length 38.8
  TOP w0.254: CT2.1 152.55,22.54 152.9,22.89 UT1.22 ; UT1.1 159.9,21.89 CT3.1 ; CT5.1 155.72,27.55 155.44,27.27 UT1.14 ; CT4.1 160.15,25.39 UT1.8
  TOP w0.381: v3(151.08,21.98) 151.08,22.07 151.54,22.54 CT2.1 ; 160.18,26.07 CT4.1 ; 160.18,26.07 160.18,27.57 159.8,27.95 155.96,27.95 CT5.1 ; 160.18,26.07 162.48,26.07 162.86,25.69 v2(162.86,25.24) 162.86,24.81 162.03,23.98 RT10.2
  TOP w0.508: RT35.1 161.98,23.64 RT10.2 162.47,23.59 163,23.06 163,22.36 v3(162.62,21.98) 162.62,21.56 162.37,21.31 RC934.1 161.37,21.31 CT1.1 CT3.1
  IN1 w0.508: v3(151.08,21.98) 151.08,21.86 151.64,21.31 158.21,21.31 158.52,21.61 159.81,21.61 160.12,21.31 162.15,21.31 162.62,21.78 v3(162.62,21.98)
+3VS_WLAN: length 8.1
  TOP w0.508: v3(228.71,3.82) 227.36,5.18 RN3.1
  BOTTOM w0.102: 227.96,21.62 227.82,21.62
  BOTTOM w0.381: C5184.1 230.03,6.07 230.95,6.98 RN15.1
  vias: v2(238.87,25.17) v2(241.41,25.17) v2(243.95,25.17) v3(228.51,21.59) v3(228.51,20.95) v3(228.71,2.8) v3(229.14,21.59) v3(229.14,20.95) v3(229.78,21.59) v3(229.78,20.95) v3(250.79,26.55) v3(250.79,25.91) v3(250.79,25.28) v3(251.39,26.56) v3(251.39,25.93) v3(251.39,25.29)
+5V_TYPEC: length 8.3
  TOP w0.508: JTC1.B4 6.96,103.75 8.79,105.58 9.19,105.58 9.89,106.28 v3(9.89,108.2)
  BOTTOM w0.254: JTC1.A4 6.74,101.2 JTC1.B9 ; JTC1.A9 6.74,103.7 JTC1.B4
  vias: v2(16.42,109.19) v3(9.89,108.78) v3(9.89,91.84) v3(9.89,91.21) v3(9.89,90.57) v3(10.52,108.78) v3(10.52,108.2) v3(10.47,91.84) v3(10.47,91.21) v3(10.47,90.57) v3(11.06,90.57) v3(11.16,108.78) v3(11.16,108.2) v3(11.64,90.57) v3(11.79,108.78) v3(11.79,108.2) v3(14.03,108.07) v3(14.3,108.64) v3(14.66,108.07) v3(14.91,96.91) v3(15.2,107.49) v3(15.3,108.07) v3(15.3,96.46) v3(15.6,97.18) v3(15.79,107.47) v3(15.93,108.07) v3(15.97,106.92) v3(16.24,97.81) v3(16.24,97.18) v3(16.87,97.81) v3(16.87,97.18) v3(17.51,97.18)
+5V_TYPEC_IC: length 0.9
  TOP w0.102: v3(10.87,87.52) v2(11.79,87.52)
+5VALW: length 208.7
  TOP w0.203: v3(145.88,40.07) 145.88,40.1 146.03,40.25 UC6.4
  TOP w0.305: v3(145.88,40.07) 146.29,39.67 CC339.1 CC98.1 ; CC88.1 115.12,100.3 114.72,99.9 UC7.3
  TOP w0.508: RV2739.2 RV2745.2 196.52,125.32 196.83,125 196.83,123.21 194.29,120.67 183.02,120.67 181.94,121.75 177.01,121.75 173.4,118.14 173.4,107.17 177,103.58 v3(177,101.86) ; RLED3.2 6.4,92.65 8.39,90.66 8.39,90.08 8,89.69 8,87.26 8.36,86.89 16.16,86.89 v3(16.17,86.88) ; CC88.1 115.48,100.86 v3(115.73,100.6) ; v3(190.97,71.04) 190.74,70.81 190.74,67.97 192.01,66.7 PRZ104.1 195.18,66.9 PRZ72.1 195.26,67.97 PRZ105.1 ; v3(165.87,51.48) 165.87,51.79 165.36,52.29 160.09,52.29 158.82,51.03 158.82,49.56 157.91,48.65 156.32,48.65 153.58,45.91 153.58,44.47 150.97,41.86 v3(150.97,41.05)
  IN1 w0.508: v3(176.61,63.81) 177.41,63.81 178.9,65.3 178.9,68.36 180.7,70.16 v3(181.21,70.16) ; v3(145.88,40.07) 146.03,40.07 146.68,40.72 150.64,40.72 v3(150.97,41.05) ; v3(184.13,70.16) 185.01,71.04 v3(190.97,71.04)
  IN2 w0.508: v3(118.35,108.35) 119.11,109.11 119.11,112.57 121.83,115.29 124.76,116.5 125.46,117.2 125.46,119.02 126.86,120.42 126.86,121.18 127.74,122.07 v3(128.25,122.07)
  BOTTOM w0.203: Q21.4 185.21,69.91 184.96,70.16 v3(184.13,70.16)
  BOTTOM w0.254: RV2752.2 132.39,124.02 130.99,124.02 129.67,122.7 128.89,122.7 v3(128.25,122.07)
  BOTTOM w0.508: v3(177.48,87.31) PRG1.1 ; v3(118.35,108.35) 115.73,105.73 v3(115.73,100.6) ; PRZ81.1 PRZ80.1 177.27,63.81 v3(176.61,63.81) ; PRZ65.1 191.27,71.34 v3(190.97,71.04) ; v3(16.17,86.88) 16.17,80.6 15.22,79.65 ; v3(178.18,43.57) 177.59,44.15 177.59,47.58 176.28,48.89 172.37,48.89 171.58,49.68 168.95,49.68 167.76,50.87 167.76,51.81 PRA1.1 166.71,52.43 166.71,52.15 166.04,51.48 v3(165.87,51.48) ; v3(145.88,40.07) 145.25,40.07 144.28,39.11 143.21,39.11 142.63,38.53 R5092.1 ; 15.22,79.65 13.51,79.65 12.68,80.47 v3(12.68,80.79) ; 15.22,79.65 16.24,78.63 16.24,72.66 15.52,71.94 PRM4.1
  vias: v2(17.89,82.44) v2(20.43,82.44) v2(22.97,82.44) v3(9.89,82.57) v3(10.52,82.57) v3(10.52,81.94) v3(12.68,82.06) v3(12.68,81.43) v3(31.33,90.04) v3(31.33,89.4) v3(31.33,88.77) v3(31.91,90.04) v3(31.91,89.4) v3(31.91,88.77) v3(173.6,100.74) v3(173.6,100.16) v3(174.24,100.74) v3(174.24,100.16) v3(174.87,100.74) v3(174.87,100.13) v3(175.46,100.74) v3(175.47,100.13) v3(176.09,100.74) v3(176.11,100.13) v3(176.41,101.86) v3(176.41,101.26) v3(176.68,100.74) v3(176.69,100.13) v3(177,101.26) v3(181.21,69.57) v3(181.79,70.16) v3(181.79,69.57) v3(182.38,70.16) v3(182.38,69.57) v3(182.96,70.16) v3(182.96,69.57) v3(183.54,70.16) v3(183.54,69.57) v3(184.13,69.57) v3(190.98,47.51) v3(190.98,46.87) v3(191.56,47.51) v3(191.56,46.87) v3(192.15,47.51) v3(192.15,46.87) v3(208.14,48.95) v3(208.14,48.37) v3(208.14,47.78) v3(208.78,48.95) v3(208.78,48.37) v3(208.78,47.78)
+5VALWP: length 28.8
  IN2 w0.254: v3(172.91,104.1) 176.07,104.1 179.05,101.11 181.87,101.11 182.67,100.31 184.26,100.31 v3(184.29,100.34)
  IN2 w0.381: v3(184.29,101) 184.26,101.02 182.72,101.02 182.12,101.62 179.31,101.62 176.25,104.68 v3(172.91,104.68)
  BOTTOM w0.254: PU302.8 184.31,101.02 v3(184.29,101) ; PR312.2 184.77,99.4 184.29,99.88 v3(184.29,100.34)
  vias: v2(171.97,106.08) v3(172.91,105.95) v3(172.91,105.32) v3(172.91,103.49) v3(172.91,102.9) v3(173.49,103.49) v3(173.49,102.9) v3(174.07,103.49) v3(174.07,102.9) v3(174.66,103.49) v3(174.66,102.9) v3(175.24,103.49) v3(175.24,102.9) v3(175.83,103.49) v3(175.83,102.9)
+5VLP: length 1.3
  BOTTOM w0.102: v1(183.21,99.42) 183.57,99.79 PC325.1
+5VS: length 244.5
  TOP w0.381: v3(121.39,130.58) 121.92,131.1 PRV14.2
  TOP w0.508: v3(174.6,44.51) 174.6,43.35 174.3,43.06 174.3,39.97 174.66,39.62 v3(174.66,37.26) ; v3(171.85,90.71) 171.85,88.69 173,87.55 v3(173,86.65)
  TOP w1.016: 28.61,43.95 29.94,43.95 30.93,42.96 30.93,35.87
  IN1 w0.508: v3(187.26,75.22) 186.81,75.66 172.82,75.66 170.1,78.38 170.1,79.34 173,82.24 v3(173,86.65) ; 110.37,109.43 108.67,109.43 106.7,107.46 67.8,107.46 v3(66.66,108.61) ; 110.37,109.43 121.28,98.52 124.24,98.52 133.65,89.11 136.48,89.11 138.32,87.27 145.07,87.27 145.56,87.76 152.78,87.76 153.4,88.39 155.96,88.39 157.36,86.99 160.08,86.99 161.12,88.03 162.34,88.03 165.02,90.71 v3(171.85,90.71) ; 110.37,109.43 110.37,117.14 115.17,121.94 115.88,121.94 121.39,127.45 v3(121.39,130.58)
  BOTTOM w0.305: JKB.1 v3(204.57,34.07) ; JKB.6 199.57,33.61 199.26,33.92 v3(199.06,33.92)
  BOTTOM w0.508: v3(174.6,44.51) 174.6,44.94 174.18,45.36 RK28.2 ; 181.59,66.57 180.51,67.65 180.51,70.58 180.74,70.81 182.85,70.81 v3(187.26,75.22) ; v3(218.68,25.8) 218.68,24.71 217.23,23.26 214.66,23.26 R23.1 212.39,21.31 212.25,21.17 R24.2 ; v3(66.66,108.61) 65.72,107.67 CTS1.1 50.09,107.67 49.58,107.16 FG2.1
  BOTTOM w2.032: 32.16,34.81 34.44,34.81
  vias: v2(257.57,16.95) v3(11.24,35.78) v3(11.24,35.15) v3(18.52,126.89) v3(18.52,126.26) v3(30.21,35.07) v3(30.21,34.31) v3(30.79,35.07) v3(30.79,34.31) v3(35.8,35.07) v3(35.8,34.31) v3(36.38,35.07) v3(36.38,34.31) v3(37.32,95.14) v3(37.96,95.14) v3(45.45,99.97) v3(46.08,99.97) v3(182.22,65.64) v3(182.22,65.05) v3(182.81,65.64) v3(182.81,65.05) v3(183.39,65.64) v3(183.39,65.05) v3(183.98,65.64) v3(183.98,65.05) v3(235.54,21.56) v3(235.54,20.92) v3(236.18,21.56) v3(236.18,20.92)
+5VS_AVDD:
  vias: v1(15.56,34.13)
+5VS_HDD1:
  vias: v2(258.3,8.53) v2(260.71,6.56) v2(262.24,7.96) v3(260.78,8.49) v3(260.78,7.91) v3(261.36,8.49) v3(261.95,8.49)
+5VS_KBL: length 0.8
  TOP w0.102: v3(212.43,19.01) v2(211.6,19.01)
+5VS_PVDD1:
  vias: v1(25.63,35.82)
+5VS_PVDD2:
  vias: v1(24.43,40.75)
+5VS_TOUCH: length 17.9
  TOP w0.127: v3(52.94,103.6) v2(52.94,104.64)
  IN1 w0.508: v3(61.65,100.93) 61.65,100.27 60.85,99.47 54.9,99.47 52.94,101.43 v3(52.94,103.6)
  BOTTOM w0.254: JEDP.22 61.5,100.78 v3(61.65,100.93)
  BOTTOM w0.508: v3(52.94,103.6) 53.32,103.98 CTS6.1 52.88,104.97 52.39,104.48 FG2.3
+12.6V_BATT:
  vias: v2(123.43,30.12) v3(122.12,27.96) v3(122.66,28.6) v3(122.7,27.96) v3(123.29,28.6) v3(123.29,27.96) v3(123.87,28.6) v3(123.87,27.96) v3(124.46,28.6) v3(124.46,27.96) v3(125.08,27.96) v3(173.4,56.79) v3(173.4,56.2) v3(173.43,55.58) v3(173.43,55) v3(174.04,56.79) v3(174.04,56.2) v3(174.06,55.58) v3(174.06,55) v3(174.67,56.79) v3(174.67,56.2)
+12.6V_BATT+: length 6
  TOP w0.102: v3(118.26,31.87) 117.52,31.87 116.72,32.67 v2(116.72,32.89) ; v3(118.26,31.87) 118.26,31.9 117.83,32.33 v2(117.83,34.55) ; v3(118.26,31.87) 118.46,32.07 v2(118.46,32.84)
+19V_ADPIN: length 4
  TOP w0.102: v3(222.46,33.12) 222.46,33.38 v2(221.86,33.98) ; v3(222.46,33.12) v2(221.55,32.2) ; v3(222.46,33.12) 222.79,33.12 v2(223.71,34.03)
+19V_VIN: length 44.5
  TOP w0.381: v3(198.45,60.76) 199.37,59.84 199.37,52.15 198.36,51.14 193.02,51.14 191.28,49.39 PQB11.5
  TOP w0.508: v3(198.45,60.76) 197.93,60.23 195.56,60.23 194.8,60.99 189.58,60.99 188.6,61.97 186.61,61.97 186.04,61.4 v3(186.04,61.36)
  IN1 w0.508: v3(180.16,61.63) 180.88,61.63 181.11,61.4 186,61.4 v3(186.04,61.36)
  BOTTOM w0.381: PRB17.1 198.69,60.99 v3(198.45,60.76)
  BOTTOM w0.508: PDB1.3 179.65,62.46 180.16,61.95 v3(180.16,61.63)
  vias: v2(179.18,28.34) v2(181.72,28.34) v2(184.26,28.34) v3(213.8,30.12) v3(213.8,29.51) v3(214.42,28.43) v3(214.49,30.12) v3(215.06,28.43) v3(215.18,30.12) v3(215.68,28.43) v3(215.82,30.12) v3(216.37,28.43) v3(216.52,30.12) v3(217.15,30.12)
+19VB: length 139.3
  TOP w1.27: 109.96,101.87 106.21,101.87 104.12,99.79 95.45,99.79 90.86,95.21 87.24,95.21 84.13,92.1 65.38,92.1 64.61,92.86 62.73,92.86 59.43,96.16 43.26,96.16 37.02,93.57 34.91,91.46 34.91,82.32 31.1,78.51 4.3,78.51 3.02,77.22 3.02,74.28 3.01,74.26
  BOTTOM w0.254: 190.5,108.16 195.04,108.16 195.44,108.55 195.44,112.25 195.02,112.67 PR307.1
  vias: v2(110.35,105.18) v2(113.39,105.18) v2(116.44,105.18) v3(2.71,71.69) v3(4.17,71.66) v3(109.08,104.03) v3(109.08,103.4) v3(109.71,104.03) v3(109.71,103.4) v3(110.35,104.03) v3(110.35,103.4) v3(110.98,104.03) v3(110.98,103.4) v3(179.43,74.06) v3(179.43,73.43) v3(180.07,74.06) v3(180.07,73.43) v3(180.7,74.06) v3(180.7,73.43) v3(182.22,60.03) v3(182.22,59.39) v3(182.22,58.76) v3(182.84,60.03) v3(182.84,59.39) v3(182.84,58.76) v3(183.45,60.03) v3(183.45,59.39) v3(183.45,58.76) v3(187.71,109.29) v3(187.71,108.58) v3(187.71,107.89) v3(187.71,107.18) v3(188.35,109.29) v3(188.35,108.58) v3(188.98,109.29) v3(188.98,108.58) v3(189.62,109.29) v3(189.62,108.58) v3(190.25,109.29) v3(190.25,108.58) v3(194.7,117.86) v3(194.7,117.23) v3(194.7,116.62) v3(194.7,115.98) v3(195.06,140.38) v3(195.07,139.75) v3(195.06,139.11) v3(195.07,138.48) v3(195.41,99.44) v3(195.41,98.81) v3(195.41,98.17) v3(195.41,97.54) v3(195.41,96.9)
+19VB_1V:
  vias: v2(190.5,98.88)
+19VB_3V:
  vias: v2(192.57,118.56) v3(191.26,118.66) v3(191.89,118.66)
+19VB_5V: length 1.1
  BOTTOM w0.102: 190.75,106.34 191.56,106.34 v2(191.75,106.53)
+19VB_CHG:
  vias: v2(180.36,52.69) v3(181.38,52.88) v3(181.38,52.24) v3(181.96,52.88) v3(181.96,52.24)
+19VB_CPU: length 28.2
  BOTTOM w0.254: 176.51,72.52 176.79,72.24 176.79,66.86 177.38,66.28 178.65,66.28 180.27,64.65 180.27,63.43 181.5,62.2 188.63,62.2 188.82,62.39 188.82,67.72 190.06,68.96 PRZ53.2
  vias: v2(168.38,63.32) v3(163.81,58.06) v3(164.45,58.06) v3(166.86,79.27) v3(167.5,79.27) v3(169.02,70.12) v3(169.02,69.49) v3(169.02,66.95) v3(169.02,66.31) v3(169.65,70.12) v3(169.65,69.49) v3(169.65,66.95) v3(169.65,66.31)
+19VB_DDR: length 20.5
  TOP w0.102: v3(2.27,69.32) v2(2.27,70.01)
  IN1 w0.254: v3(2.27,69.32) 3.25,70.3 3.25,78.66 3.73,79.14 11.3,79.14 11.92,79.76 v3(11.92,80.03)
  BOTTOM w0.254: v3(11.92,80.03) PRM7.1
+19VB_VGA_CORE: length 17.7
  TOP w0.254: v3(119.49,138.83) 120.05,138.83 PRV15.1
  IN1 w0.254: v3(119.49,138.83) 119.49,141.24 119.03,141.7 115.25,141.7 114.5,140.95 114.5,137.27 111.54,134.31 v3(111.54,133.08)
  vias: v2(110.42,121.13) v3(108.3,130.83) v3(109.01,131.34) v3(109.63,131.34) v3(110.33,128.29) v3(110.33,127.66) v3(110.33,127.02) v3(110.33,126.39) v3(110.78,125.46) v3(110.78,124.21) v3(110.78,122.97) v3(110.78,121.72) v3(111.02,115.88) v3(111.02,115.25) v3(111.02,114.61) v3(111.54,131.83) v3(111.54,130.59) v3(111.54,129.34) v3(111.67,115.86) v3(111.67,115.22) v3(111.67,114.59)
+19VB_VRAM:
  vias: v2(190.99,139.97) v3(192.32,139.9) v3(192.93,139.89)
+DVDD: length 15.3
  TOP w0.254: RA41.1 12.18,38.83 12.19,38.84 v1(12.19,39.68) 12.5,39.98 v3(12.75,39.98)
  TOP w0.381: v3(22.29,45.56) 22.32,45.58 RA1.2
  BOTTOM w0.254: v3(12.75,39.98) 12.75,41.54 15.18,43.97 16.2,43.97 17.79,45.56 v3(22.29,45.56)
+DVDD_IO: length 2.1
  TOP w0.102: RA2.2 17.42,45.28 v1(17.63,45.5)
  TOP w0.203: 19.01,41.09 19.01,40.24 UA1.8
+VCC_CORE: length 98.6
  TOP w0.127: v2(144.13,74.49) 143.75,74.11 v3(143.75,73.3)
  TOP w0.356: v3(109.27,64.28) 109.23,64.32 PCZ205.1
  IN1 w0.254: v3(205.47,68.41) 202.67,65.62 202.67,63.14 201.39,61.86 201.39,56.17 200.07,54.85 200.07,52.39 197.41,49.73 192.64,49.73 190.37,52 188.27,52 184.95,48.67 177.89,48.67 177.25,49.31 177.25,50.1 176.91,50.44 175.99,50.44 175.5,49.94 174.98,49.94 174.73,50.19 170.17,50.19 169.36,51 163.92,51 162.57,51 161.76,51.81 156.49,51.81 155.54,52.76 151.87,52.76 144.38,60.25 144.38,64.03 v3(145.02,64.66)
  IN1 w0.508: v3(145.02,65.3) v3(145.02,64.66)
  BOTTOM w0.18: UC1.BB2 126.17,61.38 126.61,61.81 v3(126.82,61.81) ; v3(126.16,66.06) 125.96,66.26 UC1.AP2
  BOTTOM w0.203: UC1.AF2 125.75,71.14 125.77,71.16 125.81,71.16 126.39,71.74 126.39,72.24 126.2,72.43 v3(126.2,72.5) ; v3(126.24,68.78) 126.16,68.7 UC1.AK2
  BOTTOM w0.254: PRZ41.1 v3(205.47,68.41) ; v3(126.49,76.24) 126.3,76.05 126,76.05 125.97,76.02 UC1.V2 ; UC1.AV2 126.11,63.82 v3(126.22,63.71) ; v3(126.22,59.08) 126.08,58.94 UC1.BF2 ; v3(126.16,73.35) 125.94,73.58 UC1.AB2
  vias: v3(109.24,62.46) v3(109.27,63.36) v3(109.27,61.54) v3(109.27,60.63) v3(109.27,59.72) v3(109.27,58.81) v3(111.17,65.64) v3(111.17,64.73) v3(111.17,62.91) v3(111.17,62) v3(111.59,63.35) v3(111.62,62.45) v3(111.59,60.69) v3(111.65,61.58) v3(112.25,60.85) v3(113.81,59.99) v3(114.79,66.44) v3(114.89,67.93) v3(116.1,67.93) v3(116.06,66.44) v3(116.19,59.96) v3(117.31,67.93) v3(117.33,66.44) v3(118.22,60.85) v3(118.51,67.93) v3(118.47,66.44) v3(118.6,70.12) v3(118.79,64.22) v3(118.79,63.58) v3(118.79,62.95) v3(119.27,60.88) v3(119.43,64.22) v3(119.43,63.58) v3(119.43,62.95) v3(119.72,71.8) v3(119.75,71.2) v3(119.75,69.36) v3(119.72,67.93) v3(119.88,66.35) v3(119.88,65.74) v3(120.1,69.83) v3(121.56,61.57) v3(121.75,69.83) v3(122.2,61.56) v3(122.2,60.52) v3(122.26,65.13) v3(122.27,64.35) v3(122.89,65.13) v3(122.93,64.38) v3(123.49,63.39) v3(123.59,65.13) v3(128.25,69.24) v3(128.7,67.33) v3(129.33,63.08) v3(129.65,67.33) v3(130.03,63.08) v3(130.28,67.33) v3(130.73,63.08) v3(130.79,68.85) v3(130.98,67.33) v3(143.75,72.66) v3(143.75,72.03) v3(143.75,71.39) v3(144.38,73.3) v3(144.38,72.66) v3(144.38,72.03) v3(144.38,71.39) v3(145.02,73.3) v3(145.02,72.66) v3(145.02,72.03) v3(145.02,71.39) v3(145.02,68.6) v3(145.02,67.84) v3(145.02,67.2) v3(145.02,66.57) v3(145.02,65.93) v3(145.65,73.3) v3(145.65,72.66) v3(145.65,72.03) v3(145.65,71.39) v3(145.65,65.93) v3(145.65,65.3) v3(145.65,64.66) v3(146.29,73.3) v3(146.29,72.66) v3(146.29,72.03) v3(146.29,71.39) v3(146.34,70.25) v3(146.34,69.62) v3(146.34,68.98) v3(146.29,65.93) v3(146.29,65.3) v3(146.29,64.66) v3(146.67,70.76) v3(146.92,73.3) v3(146.92,72.66) v3(146.92,72.03) v3(146.92,71.39) v3(146.92,65.93) v3(146.92,65.3) v3(146.92,64.66) v3(146.97,70.25) v3(146.97,69.62) v3(146.97,68.98) v3(147.61,70.25) v3(147.61,69.62) v3(147.61,68.98) v3(147.56,65.93) v3(147.56,65.3) v3(147.56,64.66) v3(148.19,70.25) v3(148.19,69.62) v3(148.19,68.98) v3(148.19,65.93) v3(148.19,65.3) v3(148.19,64.66) v3(148.83,70.25) v3(148.83,69.62) v3(148.83,68.98) v3(148.83,68.35) v3(148.83,67.2) v3(148.83,66.57) v3(148.83,65.93) v3(148.83,65.3) v3(148.83,64.66) v3(149.46,70.25) v3(149.46,69.62) v3(149.46,68.98) v3(149.46,68.35) v3(149.46,67.2) v3(149.46,66.57) v3(149.46,65.93) v3(149.46,65.3) v3(149.46,64.66) v3(150.1,70.25) v3(150.1,69.62) v3(150.1,68.98) v3(150.1,68.35) v3(150.1,67.2) v3(150.1,66.57) v3(150.1,65.93) v3(150.1,65.3) v3(150.1,64.66) v3(150.73,70.25) v3(150.73,69.62) v3(150.73,68.98) v3(150.73,68.35) v3(150.73,67.2) v3(150.73,66.57) v3(150.73,65.93) v3(150.73,65.3) v3(150.73,64.66)
+VCC_GT: length 56.3
  TOP w0.102: v3(147.68,83.33) v2(146.54,83.33)
  IN2 w0.254: v3(194.67,79.9) 194.03,79.26 191.38,79.26 189.49,77.36 162.21,77.36 161.35,76.5 157.44,76.5 156.19,77.74 149.33,77.74 149.21,77.87 149.21,80.03 148.45,80.79 v3(147.68,80.79)
  BOTTOM w0.203: v3(126.6,80.86) 126.55,80.91 126.22,80.91 UC1.K2 ; UC1.N7 v3(122.18,79.99)
  BOTTOM w0.254: PRZ59.2 v3(194.67,79.9) ; v3(126.58,78.66) 126.24,78.66 126.05,78.46 UC1.P2 ; v3(122.18,79.99) UC1.L7
  vias: v3(113.31,74.21) v3(113.69,74.66) v3(114.32,72.18) v3(114.77,85.16) v3(114.79,84.51) v3(114.77,83.21) v3(114.77,82.56) v3(114.92,78.13) v3(114.92,77.49) v3(115.15,72.18) v3(115.93,78.76) v3(115.93,78.13) v3(115.93,77.49) v3(116.19,72.16) v3(116.66,85.16) v3(116.66,84.51) v3(116.66,83.21) v3(116.66,82.56) v3(116.66,81.26) v3(116.7,80.41) v3(117.08,72.16) v3(117.2,78.76) v3(117.2,78.13) v3(117.2,77.49) v3(117.92,87.13) v3(118.37,86.67) v3(118.6,72.16) v3(118.58,71.55) v3(119.24,76.09) v3(119.47,86.46) v3(119.48,85.16) v3(119.48,84.51) v3(119.48,83.21) v3(119.48,82.56) v3(119.48,81.22) v3(119.53,80.44) v3(119.75,79.52) v3(120.18,79.99) v3(120.18,79.06) v3(120.18,78.14) v3(121.55,79.99) v3(121.55,79.06) v3(121.62,82.78) v3(121.62,81.83) v3(122.18,83.68) v3(122.18,80.91) v3(122.18,79.06) v3(122.27,82.78) v3(122.26,81.83) v3(122.82,83.68) v3(122.84,81.84) v3(122.86,82.79) v3(123.44,82.74) v3(123.45,83.68) v3(123.47,81.84) v3(123.53,71.67) v3(128.23,72.24) v3(129.43,71.74) v3(130.62,76.07) v3(147.68,84.6) v3(147.68,83.97) v3(147.68,82.7) v3(147.68,82.06) v3(147.68,81.43) v3(147.68,80.16) v3(148,85.24) v3(148.32,84.6) v3(148.32,83.97) v3(148.61,85.24) v3(148.95,84.6) v3(148.95,83.97) v3(149.25,85.24) v3(149.59,84.6) v3(149.59,83.97) v3(149.88,85.24) v3(150.22,84.6) v3(150.22,83.97) v3(150.52,85.24) v3(150.86,84.6) v3(150.86,83.97) v3(150.86,83.33) v3(150.86,82.7) v3(150.86,80.79) v3(150.86,80.16) v3(151.15,85.24) v3(151.49,84.6) v3(151.49,83.97) v3(151.49,83.33) v3(151.49,82.7) v3(151.49,80.79) v3(151.49,80.16) v3(151.79,85.24)
+VCC_SA: length 73.6
  TOP w0.127: v3(154.48,54.43) 154.02,54.88 v2(154.02,55.29)
  IN1 w0.203: v3(197.98,64.03) 196.24,62.29 189.51,62.29 188.34,63.46 180.22,63.46 178.94,62.17 178.94,60.63 177.91,59.6 174.73,59.6 174.21,59.08 171.84,59.08 169.25,56.48 169.25,53.59 168.02,52.36 165.71,52.36 165.52,52.17 156.72,52.17 155.76,53.12 152.41,53.12 151.49,54.04 v3(151.49,56.15)
  BOTTOM w0.254: PRZ1.1 206.73,69.01 206.73,64.92 204.4,62.59 200.3,62.59 198.86,64.03 v3(197.98,64.03)
  vias: v3(112.04,56.18) v3(113.75,57.56) v3(114.35,57.56) v3(115.13,57.56) v3(116.95,57.55) v3(118.09,57.59) v3(119.4,56.11) v3(119.91,57.59) v3(121.48,55.96) v3(151.94,57.42) v3(151.94,56.79) v3(152.57,58.19) v3(153.21,58.19) v3(153.84,58.19) v3(154.48,58.19) v3(155.11,58.19) v3(155.11,57.55) v3(155.11,56.92) v3(155.75,58.19)
+VCCDPHY_1P24: length 5.6
  TOP w0.076: v3(110.91,49.81) v2(110.91,50.34)
  BOTTOM w0.254: UC1.CA23 UC1.CA24 v3(110.91,49.81) 110.98,49.8 ; RC977.2 113.69,37.5 v3(111.78,39.41)
AVCCSA: length 74.7
  TOP w0.102: v3(155.35,54) v1(155.35,53.27)
  IN1 w0.203: v3(155.35,54) 156.85,52.5 165.38,52.5 165.57,52.69 167.88,52.69 168.92,53.73 168.92,56.62 171.7,59.41 174.07,59.41 174.6,59.93 177.77,59.93 178.61,60.77 178.61,62.31 180.1,63.8 188.47,63.8 189.63,62.63 196.11,62.63 196.96,63.48 196.96,64.03 197.72,64.79 200.64,64.79 203.12,67.27 203.12,68.85 202.57,69.4 202.57,72.64 v3(202.74,72.81)
  BOTTOM w0.203: PUZ1.41 202.16,72.58 202.26,72.68 202.61,72.68 v3(202.74,72.81) 203.23,73.3 204.53,73.3 PCA7.2
  BOTTOM w0.254: PCA7.2 205.57,73.48 PCZ3.2 PRA8.2 ; PLA1.3 155.1,56.28 155.35,56.03 v3(155.35,54) PHA1.2
AVCCSA_R: length 76.7
  TOP w0.102: v1(157.88,53.74) 157.02,53.74 v3(156.95,53.8)
  IN1 w0.203: v3(195.82,64.03) 195.82,63.39 195.39,62.96 189.77,62.96 188.6,64.13 179.96,64.13 178.28,62.45 178.28,60.91 177.63,60.26 174.4,60.26 173.88,59.74 171.57,59.74 168.59,56.76 168.59,53.86 167.74,53.02 165.44,53.02 165.25,52.83 157.16,52.83 156.95,53.03 v3(156.95,53.8)
  BOTTOM w0.203: PRA8.1 207.18,74.44 208.36,73.26 208.36,65.76 204.69,62.08 200.12,62.08 198.81,63.39 197.73,63.39 196.59,64.54 196.07,64.54 195.82,64.28 v3(195.82,64.03)
  BOTTOM w0.254: PRA7.2 PRA8.1 ; v3(156.95,53.8) 156.95,53.11 156.7,52.85 PHA1.1
GND: length 1932.2
  TOP w0.127: UT1.16 154.44,26.53 154.64,26.73 154.67,26.73 155.13,27.18 155.13,27.41 155.14,27.42 CT5.2 ; v3(235.54,28.66) v2(236.47,28.66) ; v2(183.65,132.48) 182.95,133.18 v3(182.35,133.18) ; v3(180.96,119.88) v2(179.84,119.88) ; v3(186.11,110.46) v2(185.3,110.46) ; v3(189.21,110.62) v2(188.34,110.62) ; v2(158.91,68.87) 158.99,68.79 v3(158.99,68.22) ; v3(216.26,14.37) v2(215.17,14.37)
  TOP w0.203: v3(145.97,43.96) 146.03,43.9 UC6.11 v3(146.03,41.93)
  TOP w0.254: UT1.2 160.2,22.39 CT3.2 CT1.2 161.31,22.45 v3(161.78,21.98) ; v3(157.77,25.22) 157.94,25.39 UT1.9 ; v3(158.92,20.6) 158.57,20.6 158.56,20.59 158.2,20.59 157.94,20.85 UT1.32 ; PCZ179.2 CC30.2 ; PCZ189.2 PCZ167.2 PCZ168.2 PCZ200.2 113.65,67.36 113.65,67.72 CC347.2 ; CV53.2 152.78,105.73 v3(153.08,105.44) ; RV381.2 170.43,94.05 v3(170.4,94.09) ; v3(118.99,39.69) 118.99,40.51 R163.2 ; UC7.5 113.9,97.14 CC117.2 v3(112.47,97.14) ; RC983.2 98.81,42.43 v3(98.81,41.96) ; v3(8.75,93.24) D33.3 ; UT1.23 153.08,22.39 152.64,21.95 CT2.2 ; v3(150.65,103.81) 150.71,103.87 CV222.2 ; UT1.16 154.44,25.39 v3(154.62,25.22) ; CC270.2 v3(128.6,57.96) ; v3(119.71,41.2) 119.71,41.45 119.49,41.66 RC124.1
  TOP w0.279: v3(148.1,112.08) 147.96,112.08 147.07,111.19 CV55.2
  TOP w0.305: PCZ98.2 127.67,61.73 v3(127.1,62.3) 126.92,62.48 PCZ174.2 ; PCZ238.2 129.41,65.18 128.89,64.66 v3(128.7,64.66) 128.63,64.66 128.29,65.01 PCZ237.2 PCZ127.2 ; CC29.2 v3(111.12,73.86) ; PCZ110.2 113.06,76.4 CC30.2 ; PCZ103.2 129.62,61.68 v3(129.71,61.68) ; v3(130.73,61.68) 130.13,61.08 PCZ101.2 ; PCZ170.2 v3(111.62,65.16) ; PCZ208.2 124.16,63.42 v3(124.43,63.69) ; PCZ234.2 125.13,66.71 v3(124.51,66.09) 125.18,65.43 PCZ236.2 ; v3(113.57,65.51) 113.42,65.51 113.06,65.16 PCZ169.2 ; v3(124.5,58.78) 124.65,58.63 PCZ214.2 ; v3(122.87,63.36) 122.87,63.32 123.46,62.72 PCZ173.2 ; PCZ195.2 122.73,61.74 v3(122.89,61.58) ; PCZ79.2 130.11,66.39 129.71,66 v3(129.71,65.93) 129.52,65.93 128.89,66.57 PCZ240.2 ; PCZ233.2 127.68,66.76 v3(127.36,67.08) 126.83,67.08 PCZ246.2 ; v3(123.51,64.33) 123.57,64.38 PCZ187.2 ; PCZ102.2 130.54,65.41 v3(130.54,65.87) 130.6,65.93 130.86,65.93 131.33,66.4 PCZ80.2 132,65.95 PCZ104.2 ; PCZ97.2 124.98,61.31 PCZ203.2 ; v3(111.18,72.05) 111.15,72.02 CC31.2 ; PCZ99.2 v3(131.35,61.69)
  TOP w0.356: v3(122.18,75.37) 122.15,75.34 PCZ166.2 121.22,75.38 PCZ199.2 PCZ197.2 ; CC342.2 CC323.2 v3(89.14,37.5) ; v3(108.63,66.1) 109.07,65.67 PCZ205.2 ; RC101.2 v3(86.47,34.56) ; PCZ203.2 123.77,61.31 v3(123.5,61.58) ; v3(146.64,100.52) CV34.2 CV60.2 ; CV171.2 133.66,127.76 v3(133.7,127.72) ; CD25.2 53.06,45.44 v3(53.06,45.02) ; CD65.2 CD99.2 ; CD22.2 61.3,63.98 61.26,64.03 60.81,64.03 60.5,63.72 60.5,63.56 v3(60.39,63.56) ; CD85.2 53.63,78.48 v3(52.93,78.48) ; CV201.2 136.57,100.45 v3(137.31,100.45) 137.84,100.98 CV207.2 ; v3(59.13,66.63) 59.13,66.44 59.49,66.08 60.35,66.08 CD16.2 ; v3(169.11,137.91) 169.13,137.94 CV161.2 ; CC45.2 102.75,65.07 v3(102.74,65.08) ; v3(124.5,58.78) 124.5,58.87 124.85,59.23 PCZ207.2 ; v3(133.79,136.02) CV172.2 ; CC339.2 146.29,38.77 146.56,38.5 v3(146.56,38.29) ; PCZ210.2 PCZ211.2 120.48,70.31 PCZ183.2 120.17,70.75 v3(119.74,70.31) ; v3(157.58,128.31) 156.81,128.31 CV163.2 ; CD31.2 63.79,29.7 v3(63.79,30.21) 63.84,30.26 63.84,30.83 CD96.2 ; v3(132.45,85.3) 132.45,85.69 133.12,86.35 CC142.2 ; CV45.2 150.41,109.5 v3(150.38,109.53) 150.3,109.61 CV52.1 ; CG2.2 79.62,102.14 CG3.2 79.36,101.3 ; v3(195.49,129.22) 195.73,128.98 CV321.2 ; PCZ142.2 122.18,56.43 v3(122.18,56.89) ; CV221.2 145.02,111.9 v3(144.82,112.11) ; CD61.1 CD60.2 ; CC43.2 104.46,67.62 v3(105.11,67.62) ; PCZ170.2 PCZ169.2 112.77,65.13 PCZ192.2 ; v3(122.15,73.51) 121.94,73.31 PCZ178.2 ; v3(104.87,57.53) 104.87,58.03 CC46.2 ; v3(21.35,129.97) 20.57,129.19 QG1.4 ; CV205.2 138.85,114.15 138.46,114.53 v3(138.19,114.53) ; RC474.2 102.33,42.15 v3(102.83,42.15) ; CD30.2 64.46,39.3 64.66,39.1 v3(64.66,38.6) ; CA15.1 v3(21.11,31.75) ; CV317.2 v3(193.66,123.3) ; v3(88.58,32.47) 88.67,32.56 CC331.2 CC50.2 ; v3(121.56,66.15) 121.31,66.4 PCZ213.2 PCZ212.2 ; v3(157.58,126.79) 157.5,126.87 156.83,126.87 CV164.2 ; v3(145.08,126.52) 145.13,126.47 CV170.2 ; v3(192.86,123.3) CV313.2 ; v3(118.99,39.69) 119.42,39.26 ; CD98.2 45.96,23.52 v3(45.96,24.28) ; v3(86.8,40.41) 86.85,40.36 CC49.2 CC321.2 ; CD18.2 60.54,72.93 60.05,72.43 59.22,72.43 58.84,72.81 v3(58.84,72.98) ; CV31.2 147.27,100.07 v3(147.7,100.5) ; v3(112.48,62.27) 112.8,61.96 PCZ209.2 ; CC8.2 124.62,24.71 v3(124.57,24.66) ; CV204.2 136.18,112.1 CV202.2 ; v3(121.56,59.68) 121.86,59.37 PCZ204.2 ; v3(108.75,53.34) 108.64,53.45 CC71.2 ; CV162.2 v3(169.05,127.85) ; CV391.2 v3(181.85,130.58) ; v3(102.01,73.89) 101.97,73.86 CC44.2 ; v3(109.94,53.2) 109.94,53.41 109.84,53.51 CC316.2 ; RV380.2 152.9,102.36 152.34,102.92 v3(152.34,102.97) 152.06,103.25 CV214.2
  TOP w0.381: v3(50.62,41.96) 50.62,41.96 CD27.2 ; C18.2 17.2,134.69 17.7,134.2 v3(17.7,134.04) ; CV392.2 195.73,127.66 195.35,127.27 v3(195.18,127.27) ; v3(63.83,72.98) 63.83,72.97 63.73,73.06 CD86.2 ; v3(143.81,38.24) 143.81,38.26 143.78,38.26 143.49,38.55 CC97.2 ; v3(143.7,108.5) 143.73,108.53 CV390.2 ; 148.06,41.93 CC275.2 ; 148.06,41.93 CC341.2 CC274.2 ; 148.06,41.93 v3(146.03,41.93) ; v3(98.53,38.44) 99.55,38.44 99.93,38.82 CC67.2 CC332.2 ; CD24.2 50.48,50.15 v3(50.59,50.05) ; v3(151.83,21.98) 151.83,21.98 151.98,21.98 152,21.95 CT2.2 ; CLRP3.2 121.42,38.35 CC302.2 CC301.1 119.42,39.26 ; CC366.1 v3(84.63,36.79) ; CC364.2 145.09,48.85 v3(145.14,48.9) ; CC339.2 CC98.2 CC261.2 ; CD26.2 51.1,31.37 v3(51.1,30.73) ; RC1154.2 112.56,35.05 v3(111.84,35.05) ; CD99.2 61.91,26.49 62.32,26.08 62.32,25.35 CD62.2 ; v3(169.15,132.42) 169.25,132.32 CV160.1 ; RC76.1 104.38,41.42 v3(104.69,41.1) ; v3(52.97,88.43) 53.02,88.37 CD89.2 ; CD83.2 63.77,86.17 v3(63.77,85.52) ; v3(112.48,62.27) 112.82,62.62 PCZ191.2 ; v3(53.06,34.42) 53.06,33.72 CD87.2 ; v3(173.8,92.51) 173.52,92.22 CC352.2 ; v3(145.7,106.5) 145.4,106.2 PCV47.2 ; PCZ206.2 112.78,64.47 PCZ192.2 ; CV312.2 v3(185.4,123.59) ; v3(186.55,127.4) CV318.1 ; v3(64.09,75.78) 63.57,75.78 63.54,75.8 63.43,75.8 63.39,75.84 CD94.2 ; CV121.2 v3(181.77,129.94) ; v3(118.41,41.41) 118.22,41.6 RC123.1 ; PCZ135.2 113.21,72.22 113.21,72.66 v3(113.18,72.69) ; CD93.2 63.63,88.16 v3(63.71,88.24) ; PCZ180.2 PCZ177.2 PCZ178.2 ; CV311.1 v3(185.4,124.35) ; v3(67.66,26.19) 67.61,26.14 CD2.1 CD1.1 ; v3(21.11,31.75) 21.22,31.64 22.13,31.64 22.38,31.4 CA11.1 23.08,31.4 v3(23.33,31.64) ; v3(121.59,60.49) 121.52,60.56 PCZ176.2 ; v3(144.02,46.29) 143.91,46.18 CC96.2 ; CC361.2 148.73,28.14 v3(148.83,28.04) ; CV320.2 v3(191.42,127.53) ; v3(117.2,94.38) 117.08,94.25 CC89.2 ; CC336.2 CC74.2 116.19,37.18 115.38,36.37 CC314.2
  TOP w0.406: RV378.2 181.73,124.43 182.33,123.83 UV15.3 v3(183.49,123.83) ; D32.3 v3(14.97,95.51) ; QV30.4 193.52,123.44 v3(193.66,123.3) ; D31.3 v3(11.79,95.51)
  TOP w0.432: RV2753.1 181.83,125.81 182.52,126.5 UV12.3 v3(183.48,126.5)
  TOP w0.457: CC27.2 112.3,72.69 v3(113.18,72.69) ; v3(124.42,73.39) 124.94,73.91 RC185.2 ; v3(19.09,114) 19.13,113.97 SW1.5 ; CD75.2 56.06,64.3 56.59,63.77 v3(56.59,63.5) ; RC421.2 CC293.1 124.94,75.72 v3(124.48,76.18) ; CA39.1 23.14,32.86 v3(23.06,32.78) ; v3(123.15,88.63) RC484.2 RC485.2 RC398.2 ; v3(119.95,76.05) 119.95,75.7 PCZ158.2 ; v3(135.48,139.31) 135.37,139.43 CV387.2 ; CD13.1 52.95,69.07 v3(52.95,68.05) ; RV67.2 173.8,93.1 v3(173.8,92.51) ; RC481.2 126.45,89.02 127.17,89.75 v3(127.58,89.75) ; SW1.6 24.17,112.3 24.18,112.3 24.18,111.97 24.37,111.78 v3(24.35,111.78) ; v3(119.97,73.64) 119.97,73.3 PCZ165.2 ; RC399.2 128.91,85.58 127.83,84.49 v3(126.59,84.49)
  TOP w0.508: CV204.2 135.28,113 v3(134.73,112.45) ; CD84.2 50.59,84.14 v3(50.59,83.63) 50.58,83.62 CD80.2 ; CA46.2 27.41,42.03 CA21.2 28.22,42.02 v3(29.07,42.86) ; CC88.2 113.65,100.86 v3(113.52,100.73) ; v3(39.31,109.48) 39.01,109.18 RM11.1 ; QWL2.3 228.76,20.23 v3(228.65,20.34) ; v3(101.93,71.38) 101.21,71.38 CC42.2 CC356.2 CC357.2 ; v3(52.78,66.48) 52.81,66.48 52.81,66.35 52.84,66.33 52.84,66.18 53.15,65.88 CD92.2 ; CC349.2 113.5,70.02 v3(113.56,70.08) ; CV384.2 145.94,138.05 v3(145.89,138.09) ; CV174.2 145.23,128.88 v3(145.14,128.97) ; CC38.2 105.81,55.8 v3(106.09,56.07) ; RV118.2 164.5,133.1 v3(164.92,133.52) ; RV64.2 170.51,96.02 v3(170.26,96.27) ; CV386.2 137.86,138.53 v3(137.88,138.51) ; CLED1.2 v3(3.69,84.32) ; CV375.2 169.89,124.58 169.37,124.58 169.04,124.91 v3(169.07,124.91) ; v3(43.27,63.72) 43.27,63.3 CD19.2 ; v3(182.82,101.77) 182.3,102.29 PC324.2 ; C5228.2 v3(18.96,132.02) ; v3(116.7,140.74) 117.25,140.74 RV218.1 ; CA41.2 v3(21.53,46.07) ; PCV18.2 118.89,137.94 v3(118.98,137.85) ; v3(126.69,137.13) 126.26,137.56 PRV26.2 ; v3(13.87,40.97) 14.76,40.97 CA9.1 ; CA19.2 27.75,34.61 v3(27.92,34.44) ; CA19.2 CA45.2 v3(28.64,34.38) ; CA19.2 CA20.2 ; CV2.2 138.09,111.26 v3(138.09,110.39) 138.85,110.39 139.05,110.59 CV44.2 139.56,110.09 139.61,110.04 CV203.2 140.37,109.72 CV38.2 ; CC122.2 v3(200.52,34.42) ; RT12.2 CT4.2 162.01,25.42 v3(162.15,25.28) ; PRZ74.2 v3(193.4,70.89) PRZ73.2 ; v3(39.64,46.03) 39.69,45.98 RD24.2 ; v3(86.8,40.41) 86.29,40.91 CC359.2 ; PCV43.2 142.96,95.68 v3(143.14,95.5) ; U4018.1 16.85,137.66 16.75,137.56 v3(16.75,137.43) ; v3(133.76,129.89) 133.75,129.89 CV382.2 ; CC59.2 105.08,75.22 v3(105.09,75.23) ; v3(91.27,26.23) 91.87,26.83 CC354.1 ; v3(39.45,26.26) 39.27,26.26 38.63,25.62 RD22.2 ; CC314.2 115.35,35.55 v3(115.35,34.69) ; SW1.4 23.5,115.83 v3(23.67,116) ; RT11.2 65.53,104.41 v3(65.9,104.78) ; PCV50.2 141.88,100.32 v3(141.7,100.5) 141.67,100.53 141,100.53 CV393.2 ; v3(195.18,127.27) 194.82,126.91 QV30.1 ; PCZ111.2 114.66,75.42 114.83,75.59 v3(114.83,76.05) ; v3(169.98,93.61) 170.44,93.15 C5230.2 ; v3(143.53,139.35) 143.55,139.37 CV385.2 ; CV319.2 v3(185.91,126.64) ; CD23.2 50.41,67.29 v3(50.41,66.63) 49.35,65.57 CD79.2 ; v3(42.19,67.13) 42.83,67.77 CD21.2 ; v3(143.7,106.5) 143.15,105.94 PCV46.2 ; v3(24.71,44.54) CA36.2 CA37.2 ; RC40.2 RC39.2 RC38.2 104.82,54.76 v3(105.05,55) ; v3(152.18,95.5) 152.75,96.07 RV102.2 ; CA23.2 23.11,41.62 v3(23.11,40.95) ; CL19.2 35.51,108.58 v3(34.5,108.58) ; 79.36,101.3 78.35,100.3 v3(78.35,98.72) ; v3(30.67,126.48) 31.13,126.48 CL1.1 ; PCW7.2 184.82,135.88 v3(185.07,135.88) ; PCG9.2 v3(158.22,77.87) ; CC325.1 109.04,38.11 108.67,38.47 v3(108.67,38.47) ; v3(116.1,76.05) 116.3,76.26 PCZ112.2 ; CD74.2 57.52,62.46 57.86,62.12 v3(57.86,61.81) ; CD17.2 50.39,73.23 v3(50.39,72.93) ; CG47.2 v3(14.21,127.02) ; C117.2 v3(61.45,105.23) ; CC40.2 CC39.2 99.07,61.17 98.74,60.84 v3(98.74,60.64) ; LK2.1 164.7,32.9 v3(165.09,33.29) ; PCZ157.2 v3(117.94,76.07) ; PCZ134.2 114.83,73.08 v3(114.83,73.58) ; C19.2 v3(20.9,132.96) ; PCV22.2 120.63,130.98 v3(120.63,130.58) ; CD73.2 56.57,60.43 57.4,59.61 v3(57.86,59.61) ; RD3.2 52.77,26.22 v3(52.77,27.28) 52.95,27.28 53.75,26.47 RD5.2 ; PRB2.1 192.03,51.58 192.39,51.94 v3(192.39,52.28) ; v3(120.63,129.69) 122.59,129.69 122.92,130.02 PRV28.2 ; CC60.2 104.97,72.61 v3(104.99,72.63) ; RA17.2 14.82,42.64 v3(15.77,42.64) ; CC41.2 99.28,58.91 CC58.2 98.78,58.92 v3(98.62,59.08) ; CD20.2 60.93,60.47 60.42,59.96 v3(60.42,59.53) ; CD77.2 51.07,79.53 v3(50.51,78.98) ; CC37.2 98.98,64.18 98.76,63.96 v3(98.76,63.69) ; v3(163.43,119.4) v3(163.43,118.77) 164.14,118.05 RV43.1 RV42.1 ; v3(50.51,47.38) 51.16,48.03 RD6.2 ; v3(113.61,76.04) 113.61,76.51 PCZ110.2 ; v3(47.84,52.61) 47.86,52.6 CD76.2 ; PCZ16.1 v3(193.2,64.08) ; RA6.1 v3(11.57,37.94) ; CA32.2 16.4,43.3 v3(15.76,43.3) ; v3(99.65,54.99) 99.88,54.76 RC6.2 RC5.2 ; C5185.2 C5186.2 219.44,10.67 220.42,11.66 v3(222.11,11.66) ; v3(143.7,108.5) 143.15,107.95 PCV58.2 ; CA10.1 RA7.1 v3(26.74,29.85) ; v3(113.56,69.07) CC350.2 112.94,68.43 CC347.2 ; v3(143.7,100.5) 143.37,100.17 PCV56.2 ; CL9.2 34.87,110.4 v3(34.87,110.73) 34.87,111 CL20.2 ; RL55.2 v3(32.33,131.43) ; v3(39.64,37.21) 39.67,37.18 CD71.1 ; RG56.2 20.25,130.53 v3(20.39,130.66) ; CV383.2 144.66,135.63 v3(144.27,135.25) ; CC346.2 CC358.2 144.64,55.68 144.08,56.24 v3(143.76,56.24) ; v3(161.75,137.52) 162.04,137.81 CV376.2 ; R5176.2 v3(63.61,105.21) ; CG46.2 v3(13.32,126.96) ; C5221.2 C5222.2 57.45,101.34 v3(56.93,100.82) ; v3(133.73,131.82) 133.58,131.67 RV119.2 ; v3(116.1,73.64) 116.31,73.85 PCZ109.2 ; CL5.2 34.36,103.25 v3(34.99,102.62) ; C594.2 v3(64.5,105.23) ; 63.76,110.64 62.35,110.64 C5231.2 61.18,110.62 v3(60.5,109.94) 60.82,109.62 C5232.2 ; v3(146.23,46.25) 145.91,45.93 CC95.2 CC94.2 ; CA12.1 v3(28.59,31.83) ; PCV49.2 145.56,97.94 v3(145.6,97.9) ; v3(133.85,139.34) 133.75,139.24 CV388.2 ; C593.2 v3(62.64,105.24) ; RS46.2 v3(189.62,40.61) ; CV373.1 157.27,138.38 v3(157.29,138.4) ; v3(137.33,97.13) 137.84,97.13 138.29,97.57 CV4.2 ; RD23.2 41.64,24.45 v3(42.14,24.45) ; DL1.1 v3(26.27,130.96) ; CL4.2 v3(30.78,130.58) ; CD95.2 64.39,40.48 v3(64.39,41.37) ; CA13.1 11.28,33.33 11.28,32.62 v3(11.25,32.59) ; v3(126.41,136.51) 125.95,136.51 PCV1.2 ; CC348.2 113.56,70.97 v3(113.62,71.04) ; v3(21.89,131.15) 21.63,130.88 CL3.2 ; RD29.1 38.1,52.59 v3(38.03,52.53) CD78.2 ; RV71.2 137.31,100.04 v3(137.31,100.45) ; v3(145.25,131.72) 145.25,131.73 145.28,131.7 CV175.2 ; FG1.2 15.94,126.7 v3(16.32,126.32) ; v3(157.58,132.31) 157.43,132.46 RV116.2 ; v3(22.72,109.88) 23.5,110.66 SW1.3 ; v3(25.6,43.13) 25.17,42.7 CA22.2 ; PR2.2 v3(219.69,27.07) ; v3(42.22,81.03) 41.88,81.03 41.37,80.52 CD29.2 ; v3(50.91,28.51) CD61.1 ; PCZ164.2 v3(117.94,73.64) ; v3(175.21,50.57) 175.8,51.16 PCB19.2 ; v3(201.16,34.41) 201.53,34.78 CC123.2 ; CA34.1 v3(20.51,46.07) ; CA33.2 v3(16.5,41.62) ; PC1009.2 v3(181.96,92.13) ; C118.2 v3(60.43,105.25) ; CA28.2 v3(19.5,44.29)
  VCC w0.203: 91.9,51.6 H10.1 ; H10.1 94.03,46.54 ; H10.1 91.1,49.47 ; H10.1 96.16,51.6 ; H10.1 91.9,47.34 ; H10.1 96.96,49.47 ; H10.1 94.03,52.4 ; H10.1 96.16,47.34 ; H8.1 96.96,81.27 ; H8.1 96.16,79.14 ; H8.1 94.03,78.34 ; H8.1 91.9,83.4 ; H8.1 96.16,83.4 ; H8.1 91.9,79.14 ; H8.1 94.03,84.2 ; H8.1 91.1,81.27 ; JHDMI.22 12.98,128.3 ; JHDMI.22 10.42,128.3 ; JHDMI.22 11.7,129.23 ; JHDMI.22 12.98,127.37 ; JHDMI.22 10.42,129.23 ; JHDMI.22 10.42,127.37 ; JHDMI.22 12.98,129.23 ; JHDMI.22 11.7,127.37 ; 10.42,112.87 JHDMI.20 ; JHDMI.20 10.42,113.8 ; JHDMI.20 12.98,112.87 ; JHDMI.20 11.7,112.87 ; JHDMI.20 12.98,114.73 ; JHDMI.20 11.7,114.73 ; JHDMI.20 12.98,113.8 ; JHDMI.20 10.42,114.73 ; JHDMI.23 3.53,130.2 ; JHDMI.23 2.25,131.13 ; JHDMI.23 3.53,131.13 ; JHDMI.23 2.25,129.27 ; JHDMI.23 3.53,129.27 ; JHDMI.23 0.97,129.27 ; JHDMI.23 0.97,130.2 ; JHDMI.23 0.97,131.13 ; H5.1 254.65,10.31 ; H5.1 255.2,11.8 ; H5.1 253.17,9.77 ; H5.1 251.13,11.8 ; H5.1 251.68,10.31 ; H5.1 253.17,13.83 ; H5.1 251.68,13.29 ; H5.1 254.65,13.29 ; 204.88,140.67 H15.1 ; H15.1 207.64,139.5 ; H15.1 206.05,141.09 ; H15.1 207.22,138.33 ; H15.1 204.88,138.33 ; H15.1 204.46,139.5 ; H15.1 207.22,140.67 ; H15.1 206.05,137.91 ; H13.1 14.87,101.28 ; H13.1 12.11,102.45 ; H13.1 15.29,102.45 ; H13.1 12.53,103.62 ; H13.1 13.7,104.04 ; H13.1 13.7,100.86 ; H13.1 12.53,101.28 ; H13.1 14.87,103.62 ; H14.1 7.87,29.63 ; H14.1 8.29,30.8 ; H14.1 7.87,31.97 ; H14.1 6.7,29.21 ; H14.1 5.53,29.63 ; H14.1 5.11,30.8 ; H14.1 6.7,32.39 ; H14.1 5.53,31.97 ; H4.1 200.29,118.11 ; H4.1 196.77,119.6 ; H4.1 197.31,121.09 ; H4.1 200.29,121.09 ; H4.1 198.8,121.63 ; H4.1 200.83,119.6 ; H4.1 197.31,118.11 ; H4.1 198.8,117.57 ; 256.7,1.52 H17.1 ; H17.1 257.94,4.44 ; H17.1 255.46,4.44 ; H17.1 256.7,4.88 ; H17.1 255.46,1.96 ; H17.1 255.02,3.2 ; H17.1 257.94,1.96 ; H17.1 258.38,3.2 ; 2.22,111.9 JHDMI.21 ; JHDMI.21 2.22,112.83 ; JHDMI.21 2.22,110.97 ; JHDMI.21 3.5,110.97 ; JHDMI.21 4.78,111.9 ; JHDMI.21 4.78,112.83 ; JHDMI.21 3.5,112.83 ; JHDMI.21 4.78,110.97
  GND w0.203: 94.03,78.34 H8.1 ; H8.1 91.1,81.27 ; H8.1 91.9,83.4 ; H8.1 96.16,79.14 ; H8.1 96.96,81.27 ; H8.1 94.03,84.2 ; H8.1 96.16,83.4 ; H8.1 91.9,79.14 ; JTC1.5 7.07,97.05 ; JTC1.5 5.3,95.7 ; JTC1.5 7.07,96.37 ; JTC1.5 5.89,95.7 ; JTC1.5 4.71,96.37 ; JTC1.5 7.07,95.7 ; JTC1.5 4.71,95.7 ; JTC1.5 5.89,97.05 ; 101.75,24.5 PJPB1.8 ; PJPB1.8 102.72,25.48 ; PJPB1.8 102.72,23.52 ; PJPB1.8 103.47,23.76 ; PJPB1.8 103.47,25.24 ; PJPB1.8 101.98,23.76 ; PJPB1.8 102.31,23.54 ; PJPB1.8 101.98,25.24 ; H15.1 207.22,138.33 ; H15.1 206.05,141.09 ; H15.1 207.22,140.67 ; H15.1 204.46,139.5 ; H15.1 204.88,140.67 ; H15.1 204.88,138.33 ; H15.1 206.05,137.91 ; H15.1 207.64,139.5 ; 2.03,107.85 JTC1.3 ; JTC1.3 3.21,107.85 ; JTC1.3 3.21,108.53 ; JTC1.3 2.03,109.2 ; JTC1.3 2.62,109.2 ; JTC1.3 3.21,108.86 ; JTC1.3 1.44,107.85 ; JTC1.3 3.21,109.2 ; 3.5,110.97 JHDMI.21 ; JHDMI.21 4.78,111.9 ; JHDMI.21 2.22,110.97 ; JHDMI.21 4.78,110.97 ; JHDMI.21 2.22,112.83 ; JHDMI.21 2.22,111.9 ; JHDMI.21 4.78,112.83 ; JHDMI.21 3.5,112.83 ; 11.7,127.37 JHDMI.22 ; JHDMI.22 10.42,127.37 ; JHDMI.22 11.7,129.23 ; JHDMI.22 12.98,127.37 ; JHDMI.22 10.42,128.3 ; JHDMI.22 12.98,128.3 ; JHDMI.22 12.98,129.23 ; JHDMI.22 10.42,129.23 ; 0.97,130.2 JHDMI.23 ; JHDMI.23 0.97,129.27 ; JHDMI.23 2.25,131.13 ; JHDMI.23 3.53,131.13 ; JHDMI.23 3.53,129.27 ; JHDMI.23 2.25,129.27 ; JHDMI.23 0.97,131.13 ; JHDMI.23 3.53,130.2 ; 9.41,118.29 JHDMI.5 ; JHDMI.5 9.54,118.09 ; JHDMI.5 9.54,119 ; JHDMI.5 10.57,118.55 ; JHDMI.5 10.46,119 ; JHDMI.5 9.43,118.55 ; JHDMI.5 10.46,118.09 ; JHDMI.5 10.59,118.81 ; 5.53,29.63 H14.1 ; H14.1 7.87,29.63 ; H14.1 6.7,29.21 ; H14.1 8.29,30.8 ; H14.1 7.87,31.97 ; H14.1 6.7,32.39 ; H14.1 5.53,31.97 ; H14.1 5.11,30.8 ; PJPB1.10 99.6,26.48 ; PJPB1.10 98.62,22.52 ; PJPB1.10 98.62,26.48 ; PJPB1.10 98.62,24.5 ; PJPB1.10 100.58,22.52 ; PJPB1.10 100.58,26.48 ; PJPB1.10 100.58,24.5 ; PJPB1.10 99.6,22.52 ; 9.54,125 JHDMI.17 ; JHDMI.17 9.54,124.09 ; JHDMI.17 9.43,124.55 ; JHDMI.17 10.57,124.55 ; JHDMI.17 10.46,124.09 ; JHDMI.17 9.41,124.29 ; JHDMI.17 10.59,124.81 ; JHDMI.17 10.46,125 ; H11.1 139.67,49.47 ; H11.1 138.87,51.6 ; H11.1 136.74,46.54 ; H11.1 134.61,51.6 ; H11.1 133.81,49.47 ; H11.1 136.74,52.4 ; H11.1 134.61,47.34 ; H11.1 138.87,47.34 ; 10.96,119.79 JHDMI.8 ; JHDMI.8 11.09,120.5 ; JHDMI.8 12.01,120.5 ; JHDMI.8 11.09,119.59 ; JHDMI.8 12.01,119.59 ; JHDMI.8 12.12,120.05 ; JHDMI.8 10.98,120.05 ; JHDMI.8 12.14,120.31 ; JTC1.6 3.21,96.71 ; JTC1.6 2.03,97.05 ; JTC1.6 3.21,95.7 ; JTC1.6 2.03,95.7 ; JTC1.6 3.21,97.05 ; JTC1.6 2.62,97.05 ; JTC1.6 1.44,95.7 ; JTC1.6 3.21,96.37 ; 6.42,98.47 JTC1.B12 ; JTC1.B12 6.16,99.25 ; JTC1.B12 7.23,98.47 ; JTC1.B12 6.16,98.47 ; JTC1.B12 6.69,98.47 ; JTC1.B12 6.96,100.03 ; JTC1.B12 7.23,100.03 ; JTC1.B12 6.69,100.03 ; JTC1.2 7.07,107.85 ; JTC1.2 7.07,108.53 ; JTC1.2 5.89,107.85 ; JTC1.2 5.89,109.2 ; JTC1.2 7.07,109.2 ; JTC1.2 4.71,108.53 ; JTC1.2 5.3,107.85 ; JTC1.2 4.71,109.2 ; 94.03,46.54 H10.1 ; H10.1 96.16,51.6 ; H10.1 94.03,52.4 ; H10.1 91.9,51.6 ; H10.1 91.1,49.47 ; H10.1 91.9,47.34 ; H10.1 96.96,49.47 ; H10.1 96.16,47.34 ; H5.1 254.65,13.29 ; H5.1 251.13,11.8 ; H5.1 251.68,13.29 ; H5.1 254.65,10.31 ; H5.1 255.2,11.8 ; H5.1 251.68,10.31 ; H5.1 253.17,13.83 ; H5.1 253.17,9.77 ; 104.31,23.54 PJPB1.7 ; PJPB1.7 104.72,25.48 ; PJPB1.7 105.47,23.76 ; PJPB1.7 103.98,25.24 ; PJPB1.7 105.14,25.46 ; PJPB1.7 105.47,25.24 ; PJPB1.7 103.98,23.76 ; PJPB1.7 104.72,23.52 ; JTC1.B1 6.69,106.43 ; JTC1.B1 7.23,104.87 ; JTC1.B1 6.16,106.43 ; JTC1.B1 6.42,104.87 ; JTC1.B1 6.96,106.43 ; JTC1.B1 6.16,105.65 ; JTC1.B1 7.23,106.43 ; JTC1.B1 6.69,104.87 ; H13.1 14.87,101.28 ; H13.1 12.53,101.28 ; H13.1 14.87,103.62 ; H13.1 13.7,100.86 ; H13.1 12.53,103.62 ; H13.1 15.29,102.45 ; H13.1 12.11,102.45 ; H13.1 13.7,104.04 ; JHDMI.20 11.7,114.73 ; JHDMI.20 12.98,113.8 ; JHDMI.20 11.7,112.87 ; JHDMI.20 12.98,114.73 ; JHDMI.20 12.98,112.87 ; JHDMI.20 10.42,113.8 ; JHDMI.20 10.42,114.73 ; JHDMI.20 10.42,112.87 ; JTC1.1 8.67,107.51 ; JTC1.1 9.11,106.34 ; JTC1.1 9.11,107.51 ; JTC1.1 9.11,106.93 ; JTC1.1 7.35,106.63 ; JTC1.1 8.23,107.51 ; JTC1.1 7.35,106.93 ; JTC1.1 7.35,107.51 ; 118.87,22.52 PJPB1.9 ; PJPB1.9 118.87,26.48 ; PJPB1.9 119.85,22.52 ; PJPB1.9 120.83,22.52 ; PJPB1.9 120.83,24.5 ; PJPB1.9 119.85,26.48 ; PJPB1.9 120.83,26.48 ; PJPB1.9 118.87,24.5 ; JHDMI.11 10.46,121.09 ; JHDMI.11 9.41,121.29 ; JHDMI.11 10.46,122 ; JHDMI.11 10.59,121.81 ; JHDMI.11 10.57,121.55 ; JHDMI.11 9.54,122 ; JHDMI.11 9.43,121.55 ; JHDMI.11 9.54,121.09 ; H4.1 198.8,121.63 ; H4.1 200.29,121.09 ; H4.1 200.29,118.11 ; H4.1 197.31,118.11 ; H4.1 196.77,119.6 ; H4.1 200.83,119.6 ; H4.1 198.8,117.57 ; H4.1 197.31,121.09 ; JTC1.4 9.21,97.3 ; JTC1.4 8.23,97.3 ; JTC1.4 7.25,97.98 ; JTC1.4 8.72,98.65 ; JTC1.4 9.21,98.65 ; JTC1.4 7.74,97.3 ; JTC1.4 7.25,97.3 ; JTC1.4 9.21,97.98 ; 136.74,78.34 H9.1 ; H9.1 134.61,79.14 ; H9.1 138.87,83.4 ; H9.1 138.87,79.14 ; H9.1 134.61,83.4 ; H9.1 139.67,81.27 ; H9.1 136.74,84.2 ; H9.1 133.81,81.27 ; H7.1 167.99,97.68 ; H7.1 162.93,99.81 ; H7.1 167.19,99.81 ; H7.1 162.13,97.68 ; H7.1 162.93,95.55 ; H7.1 167.19,95.55 ; H7.1 165.06,94.75 ; H7.1 165.06,100.61 ; 11.55,116.48 JHDMI.2 ; JHDMI.2 11.09,117.5 ; JHDMI.2 12.01,116.59 ; JHDMI.2 12.12,117.05 ; JHDMI.2 12.01,117.5 ; JHDMI.2 11.29,116.46 ; JHDMI.2 11.09,116.59 ; JHDMI.2 10.98,117.05 ; H17.1 257.94,1.96 ; H17.1 255.46,4.44 ; H17.1 257.94,4.44 ; H17.1 256.7,4.88 ; H17.1 255.46,1.96 ; H17.1 255.02,3.2 ; H17.1 256.7,1.52 ; H17.1 258.38,3.2 ; H6.1 128.27,112.32 ; H6.1 122.41,112.32 ; H6.1 127.47,114.45 ; H6.1 125.34,109.39 ; H6.1 123.21,110.19 ; H6.1 125.34,115.25 ; H6.1 127.47,110.19 ; H6.1 123.21,114.45
  BOTTOM w0.076: 112.1,86.89 112.1,86.83 112.1,86.83 UC1.B23 ; v3(102.74,80.18) 103.02,80.18 103.02,80.18 103.61,80.18 103.61,80.18 UC1.L36 ; UC1.BD35 UC1.BD36 v3(102.74,60.04) ; v3(101.99,81.44) 103.34,81.44 UC1.J36 ; UC1.B27 109.58,87.11 109.58,88.08 109.62,88.12 v3(109.62,88.18) ; 104.39,55.01 UC1.BM35 UC1.BM36 ; v3(102.91,47.57) 103.02,47.46 UC1.CE36 ; UC1.BP33 105.26,54.08 103.97,54.08 UC1.BP36 ; UC1.G35 UC1.G36 ; UC1.P36 v3(102.01,78.92)
  BOTTOM w0.089: UC1.AF36 103.33,71.37 103.29,71.36 103.25,71.37 v3(101.93,71.38) ; v3(102.74,65.08) UC1.AT36 ; v3(101.98,66.29) 102.03,66.34 UC1.AP36 ; v3(102.01,68.85) UC1.AK36
  BOTTOM w0.1: UC1.AV3 125.3,63.82 ; 125.3,63.82 125.3,64.05 125.41,64.16 125.47,64.16 ; 125.3,63.82 125.3,63.65 125.38,63.57
  BOTTOM w0.102: UC1.CJ2 125.7,45.36 127.56,45.36 128.55,45.77 129.23,45.77 129.71,46.25 v3(129.9,46.25) 130.09,46.44 131.75,46.44 132.57,45.61 132.57,44.72 ; v3(138.19,114.53) 138.19,113.71 UV1.AB24
  BOTTOM w0.127: v3(191.05,102.71) v2(192.1,102.71) ; v2(128.14,116.1) 128.6,115.64 CV7.2 ; v3(141.87,139.37) v3(141.87,138.52) ; v3(112.11,87.52) 112.1,87.51 112.1,86.89 ; 12.75,47.51 v2(12.75,46.55) ; v3(3.41,60.09) 3.28,59.96 v2(2.26,59.96) ; v3(111.13,40.61) 111.17,40.65 111.17,42.04 111.11,42.1 111.11,42.12 110.85,42.38 UC1.CN25 ; v3(101.96,63.87) 101.96,63.87 102.01,63.82 UC1.AV36 ; v3(192.86,123.3) v2(191.79,123.3) ; UC1.L33 v3(104.99,80.18) UC1.L35 UC1.L36 ; v3(102.79,77.61) 102.79,77.61 103.68,77.61 UC1.T36 ; UC1.CL2 v3(126.98,43.76) ; v3(102.11,76.78) 102.13,76.78 102.5,76.4 UC1.V36
  BOTTOM w0.152: UC1.BF36 102.14,58.79 v3(101.99,58.63) ; UC1.BK3 UC1.BK2 126.49,56.5 v3(126.6,56.61) ; UC1.CP27 109.59,41.2 v3(109.58,41.2) ; v3(106.89,87.23) 107.06,87.06 UC1.B31
  BOTTOM w0.16: UC1.AH33 v3(104.99,70.11)
  BOTTOM w0.178: UC1.AB36 v3(102.01,73.89)
  BOTTOM w0.18: UC1.CF2 125.62,46.74 124.97,46.74 UC1.CF3 ; v3(119.71,41.2) 119.67,41.23 UC1.CP11 ; UC1.BB36 103.63,61.32 101.69,61.32 v3(101.67,61.3) ; UC1.CP15 117.3,41.83 117.5,41.64 117.5,41.33 117.8,41.03 v3(117.93,41.03) ; UC1.CB2 UC1.CB3
  BOTTOM w0.2: v3(119.95,76.05) 120.17,75.83 UC1.W10 ; v3(119.74,70.31) 119.77,70.29 UC1.AG10 ; v3(120.23,67.04) 120.23,67.36 UC1.AM10 ; v3(111.46,55.1) 111.46,55.22 111.07,55.62 UC1.BL25 ; UC1.P10 v3(119.75,78.6) ; v3(117.48,44.68) 117.53,44.72 117.78,44.72 117.81,44.76 UC1.CJ14 ; UC1.BB3 125.29,61.71 125.84,61.71 126.11,61.71 126.84,62.44 126.96,62.44 v3(127.1,62.3) 127.24,62.16 ; UC1.BB3 124.74,61.15 124.43,61.15 ; UC1.BB3 125.29,61.05 126.24,61.05 126.58,61.4 127,61.4 ; v3(124.5,58.78) 124.65,58.94 UC1.BF3 ; v3(108,59.72) 108.26,59.26 UC1.BE29 ; v3(108,61.54) UC1.BC29 ; UC1.BC32 106.11,61.51 v3(106.06,61.53) UC1.BB33 ; UC1.AU29 v3(108,65.19) ; v3(102.83,42.15) 102.84,42.26 UC1.CN37 UC1.CM37 ; UC1.CK1 126.32,44.63 v3(126.78,44.63) ; 125.47,64.16 126.12,64.16 126.22,64.26 126.23,64.26 126.27,64.31 126.6,64.31 126.91,63.99 126.91,63.64 126.44,63.16 UC1.AW1 125.79,63.16 125.38,63.57 ; UC1.AV3 124.56,63.82 v3(124.43,63.69) ; v3(122.18,75.37) UC1.W7 ; UC1.AU32 106.1,65.18 v3(106.11,65.22) ; UC1.B25 UC1.C25 ; UC1.AF4 v3(124.46,71.14) ; UC1.BH28 v3(108.63,57.9) ; 108.13,68.6 v3(108,68.83) ; UC1.Y35 105.01,75.15 v3(105.09,75.23) 105.17,75.15 UC1.Y33 ; UC1.BC25 v3(111.17,61.09) ; v3(111.4,58.53) 111.22,58.35 UC1.BG25 ; UC1.AN25 v3(111.17,66.55) ; UC1.Y7 v3(122.18,74.44) ; UC1.AV25 v3(111.17,63.82)
  BOTTOM w0.203: UC1.AH28 108.63,69.92 v3(108.63,69.74) 108.26,70.12 UC1.AH29 ; v3(106.11,65.22) 106.06,65.16 106,65.16 UC1.AT33 ; UC1.T36 UC1.T35 v3(104.99,77.66) UC1.T33 105.59,78.11 105.61,78.13 105.61,78.41 105.59,78.43 UC1.P33 ; UC1.AE30 108,72.41 v3(108,72.44) ; UC1.B36 UC1.A36 ; UC1.BD28 v3(108.63,60.63) ; UC1.AT33 105.62,65.05 105.62,63.85 UC1.AV33 ; UC1.AT33 UC1.AT35 UC1.AT36 ; UC1.W30 107.44,76 107.41,76.01 107.34,76.14 v3(107.36,76.17) ; UC1.AJ7 121.94,69.35 121.95,69.35 ; v3(109.27,76.12) UC1.W27 UC1.V26 ; UC1.CJ28 109.48,45.25 109.7,45.25 109.9,45.45 109.9,45.73 109.7,45.93 109.48,45.93 UC1.CF28 109.24,46.83 v3(109.24,46.91) ; UC1.CB3 124.91,49.23 124.3,49.23 124.25,49.18 UC1.CB4 ; RC979.2 98.24,50.21 98.83,50.79 RC956.1 ; UC1.R31 v3(107.36,78.86) UC1.R30 ; v3(124.39,44.5) 124.41,44.51 UC1.CJ3 ; v3(124.39,44.5) 124.4,44.52 UC1.CJ4 123.99,45.12 v3(123.73,45.38) ; v3(124.39,44.5) 124.39,44.5 UC1.CK4 ; v3(124.39,44.5) 124.97,44.61 UC1.CJ2 125.29,44.91 UC1.CK1 ; UC1.AH25 110.54,70.15 UC1.AH24 UC1.AJ25 ; UC1.AH25 UC1.AG26 ; UC1.AH25 UC1.AG24 UC1.AF25 ; UC1.A32 106.28,86.26 106.23,86.36 106.23,86.75 v3(105.94,87.04) ; UC1.CP9 v3(120.93,41.42) ; UC1.CM31 106.89,43.89 v3(106.92,43.93) 106.7,43.93 106.56,43.8 106.27,43.8 106.07,43.51 UC1.CM33 ; UC1.AW3 UC1.AW4 ; UC1.AB3 124.61,73.58 v3(124.42,73.39) 124.22,73.58 UC1.AB4 ; UC1.BL28 UC1.BL29 v3(108,56.07) UC1.BL30 ; UC1.CN5 123.48,42.95 ; UC1.F4 UC1.F3 UC1.F2 125.75,83.23 126.6,83.23 v3(126.62,83.25) ; UC1.AF25 UC1.AE26 ; UC1.AF25 UC1.AG26 ; UC1.AF25 UC1.AE24 UC1.AE25 UC1.AE26 ; RK108.1 163.1,50.27 163.1,49.54 163.76,48.87 UK1.24 ; UC1.BL32 v3(106.09,56.07) UC1.BK33 ; UC1.CM1 UC1.CN1 UC1.CN2 ; UC1.J21 113.15,81.42 v3(113.11,81.27) ; v3(107.27,73.36) 107.4,73.33 UC1.AC30 ; UC1.V30 v3(107.36,77.04) ; UV1.AB14 138.94,105.4 138.94,106.2 v3(138.96,106.23) 138.94,106.25 138.94,107.08 UV1.AB17 ; UC1.P7 UC1.T7 v3(122.3,77.17) ; UC1.N6 v3(122.82,79.06) ; v3(109.27,70.66) UC1.AH27 UC1.AG26 ; v3(113.11,81.9) 113.15,82.06 UC1.H21 ; v3(108.01,71.52) 108.01,71.52 108.01,71.51 UC1.AF30 ; UC1.C25 UC1.D25 ; UC1.BU7 121.95,51.75 v3(121.64,51.44) ; UC1.AG26 UC1.AF27 ; UC1.BM33 105.15,55.01 105.11,54.97 105.08,54.97 v3(105.05,55) 105.03,55 105.01,55.01 104.39,55.01 ; UC1.AL28 v3(108.63,68.83) UC1.AJ28 ; 127,61.4 127.24,61.64 127.24,62.16 ; v3(122.21,55.04) 122.21,55.05 UC1.BL7 ; UC1.CC31 v3(106.73,47.87) ; UC1.AH31 107.32,70.61 v3(107.35,70.61) 107.4,70.6 UC1.AH30 ; UC1.BE31 v3(107.36,59.72) UC1.BE30 ; UC1.F21 113.16,83.37 v3(113.11,83.19) ; UC1.BT25 110.28,52.73 110.07,52.53 v3(110.07,52.43) 110.07,52.41 110.39,52.08 UC1.BU25 ; UC1.CE33 v3(104.99,47.46) UC1.CE35 UC1.CE36 ; UC1.AN28 v3(108.63,67.01) ; UC1.AY33 v3(104.99,62.56) UC1.AY35 ; UK1.113 152.04,39.97 151.48,39.42 v3(151,39.42) ; UC1.AF27 UC1.AE26 ; UC1.AF27 v3(109.27,71.57) ; v3(109.27,77.04) UC1.V27 UC1.U26 UC1.U24 111.1,77.04 111.34,77.27 v3(111.34,77.37) ; UC1.AK33 106.03,68.83 106.03,68.84 v3(106.1,68.84) 106.09,68.83 UC1.AL32 ; UC1.AD35 v3(104.99,72.63) UC1.AD33 ; UC1.CJ35 UC1.CJ36 ; UC1.T27 v3(109.27,77.95) ; UC1.AB7 v3(122.15,73.51) ; v3(158.56,44.85) 158.57,44.86 UK1.11 ; UC1.AB33 105.59,74.38 105.61,74.4 105.61,74.68 105.59,74.7 UC1.Y33 105.59,75.59 105.61,75.61 105.61,75.9 105.59,75.91 UC1.V33 ; UC1.AE26 UC1.AE27 v3(109.27,72.48) ; UC1.BL31 v3(106.7,56.1) ; UC1.BE28 v3(108.63,59.72) ; UC1.BK4 123.99,56.54 124.93,56.54 UC1.BK3 ; UC1.AM35 105.09,67.6 v3(105.11,67.62) 105.13,67.6 UC1.AM33 105.67,67.51 105.67,66.42 UC1.AP33 ; UC1.AW31 v3(107.36,63.36) UC1.AW30 ; UC1.K27 v3(109.27,80.68) ; UC1.H27 v3(109.27,81.59) ; UC1.CJ11 120.5,44.76 120.51,44.76 121.44,44.76 121.78,44.42 UC1.CK7 ; UC1.AM28 v3(108.63,67.92) ; UC1.AL29 108.13,68.6 ; UC1.BY28 108.71,49.82 108.71,49.81 v3(108.66,49.73) ; UC1.CC16 v3(115.93,47.85) ; UC1.J24 v3(110.99,81.35) UC1.K24 ; PUM1.1 v3(6.64,74.35) ; UC1.U7 121.81,76.62 121.81,75.96 UC1.W7 ; v3(113.11,83.84) 113.11,83.87 113.35,84.12 UC1.D21 UC1.C21 UC1.B21 ; UC1.K28 v3(108.63,81.59) ; UC1.V3 124.64,76.02 v3(124.48,76.18) 124.32,76.02 UC1.V4 ; v3(8.91,106.19) 8.52,105.8 JTC1.7 ; v3(114.25,46.47) UC1.CF19 ; v3(185.21,65.62) Q21.11 v3(185.21,67.65) ; v3(126.88,41.52) 126.19,41.63 UC1.CP1 UC1.CR2 UC1.CP2 ; UC1.AB27 v3(109.27,74.3) ; UC1.AW29 v3(108,63.36) ; UC1.AH35 v3(104.99,70.11) ; UC1.BG28 v3(108.63,58.81) ; UC1.BP25 UC1.BR25 110.13,53.38 109.94,53.19 109.94,53.2 v3(109.94,53.2) ; v3(121.59,60.49) 121.54,60.55 121.54,60.65 121.33,61.04 UC1.BC8 ; UC1.AV28 v3(108.63,64.28) ; UC1.BD33 v3(104.99,60.04) UC1.BD35 ; v3(11.38,74.53) 11.15,74.75 PUM1.14 ; v3(155.5,30.6) 155.37,30.73 UK1.94 ; v3(109.35,75.19) 109.33,75.11 UC1.Y27 UC1.Y26 ; UC1.BV3 124.49,51.62 v3(124.45,51.57) 124.41,51.62 UC1.BV4 ; UC1.AN30 v3(107.36,67.01) UC1.AN31 ; PUM1.3 v3(8.42,75.15) ; v3(108.33,43.96) UC1.CM29 UC1.CN29 ; UC1.E23 UC1.F24 v3(110.99,83.26) ; UC1.CC28 v3(108.57,47.77) ; UC1.B37 UC1.C37 UC1.C36 ; UC1.L27 v3(109.27,79.77) UC1.N27 UC1.N25 ; UC1.AB30 v3(107.38,74.27) ; UC1.K21 113.18,80.79 v3(113.11,80.58) ; UC1.K31 v3(106.73,81.59) UC1.K32 UC1.J33 ; UC1.AW28 v3(108.63,63.36) ; v3(108.75,53.34) 108.76,53.34 108.76,53.03 UC1.BT28 ; UC1.T30 v3(107.36,77.95) ; UC1.B29 UC1.C29 ; UC1.AU28 v3(108.63,65.19) ; UC1.J12 v3(119.48,81.91) ; UC1.AN29 v3(108,67.01) ; v3(113.1,82.59) 113.12,82.67 UC1.G21 ; UC1.CM5 UC1.CM4 ; UC1.AC27 v3(109.27,73.39) ; UC1.E27 v3(109.27,83.42) 108.84,83.84 108.79,83.84 108.77,83.86 UC1.E29 107.87,83.86 107.86,83.84 107.57,83.84 107.55,83.86 UC1.E31 ; UC1.BY36 UC1.BY35 v3(104.99,49.98) UC1.BY33 ; UC1.R28 v3(108.63,78.86) ; UC1.AF3 v3(124.46,71.14) ; 106.08,57.94 UC1.BH33 v3(104.87,57.53) UC1.BH35 ; JTC1.8 8.71,103.45 v3(9.03,103.77) ; UC1.K22 v3(112.12,80.72) ; UK1.35 167.6,45.17 v3(167.11,45.65) ; UC1.K29 v3(108,81.59) ; v3(9,101.4) 8.96,101.45 JTC1.9 ; UC1.G27 v3(109.27,82.5) ; UC1.K30 v3(107.36,81.59) ; UC1.R29 v3(108,78.86) ; UC1.R27 v3(109.27,78.86) ; UC1.BA28 v3(108.63,62.45) ; UC1.AR28 v3(108.63,66.1) ; UC1.CR34 104.59,41.99 UC1.CP35 ; UC1.K25 v3(110.08,80.72) ; UV1.AC2 138.15,95.5 139.8,95.5 139.82,95.52 ; v3(106.08,57.94) 106.32,57.49 UC1.BH32 ; v3(123.45,80.91) UC1.J5 ; UC1.CN25 UC1.CM25 ; v3(107.33,75.23) 107.36,75.22 UC1.Y30 ; v3(152.18,95.5) 152.19,95.51 152.19,97.09 UV1.E5 ; 130.11,41.3 130.72,41.04 ; v3(108,57.9) UC1.BH29 108.51,57.19 UC1.BK28 ; UC1.CC7 v3(122.18,47.65)
  BOTTOM w0.229: JTC1.7 8.52,105.4 8.29,105.16 JTC1.A12 ; UV1.AC22 138.12,111.17 138.12,110.42 v3(138.09,110.39) ; UC1.AC5 v3(122.77,73.51) ; 7.14,99.7 JTC1.A1 8.29,99.7 8.52,99.47 JTC1.10
  BOTTOM w0.25: UV1.B17 v3(155.65,107.48)
  BOTTOM w0.254: UC1.BP12 118.32,54.47 v3(118.26,54.46) ; UC1.BP12 119.22,54.38 v3(119.36,54.38) 119.46,54.38 120.12,55.04 UC1.BM9 ; UC1.BP12 119.27,53.58 119.27,53.17 119.28,53.16 119.39,52.46 UC1.BU11 UC1.BV11 UC1.BW11 ; UC1.CJ19 114.82,44.7 v3(114.28,44.52) ; v3(114.2,48.51) 114.25,48.56 114.41,48.56 UC1.CB19 114.7,48.72 114.99,48.5 115.11,48.51 v3(115.12,48.5) 115.21,48.58 115.22,48.6 UC1.CB18 ; v3(121.64,51.44) 121.95,51.13 UC1.BW7 ; UV6.U12 166.8,137.91 166.2,138.51 v3(166.2,139.12) ; UC1.CM13 118.63,43.67 118.63,44.32 v3(118.58,44.38) ; UC1.CG33 105.77,46.2 v3(106.01,45.96) ; UC1.AF7 v3(122.18,71.67) UC1.AE7 ; v3(106.13,48.79) 105.67,48.79 UC1.CB33 ; PUA1.6 167.11,55.9 v3(166.86,56.15) ; UC1.L6 v3(122.82,79.99) ; UC1.BY22 112.86,50.13 112.54,49.89 v3(112.54,49.84) 112.54,49.83 112.59,49.8 112.6,49.69 112.86,49.48 UC1.CA22 ; UC1.BF33 105.59,58.43 106.08,57.94 v3(106.08,57.94) ; v3(122.89,61.58) 122.76,61.62 UC1.BA6 ; UC1.BY25 110.89,50.45 110.89,50.46 v3(110.89,51.1) 111.21,50.78 UC1.BW24 ; UC1.AL7 121.95,69.35 ; UC1.AK3 v3(124.35,68.99) UC1.AK4 ; UC1.AU4 123.66,64.48 v3(123.51,64.33) ; UC1.AU4 123.99,63.86 UC1.AV4 ; UC1.AU4 123.99,64.72 UC1.AT4 123.99,65.37 UC1.AR4 124.05,65.6 124.51,66.06 v3(124.51,66.09) ; UC1.BD6 122.6,60.2 122.83,60.43 122.83,60.52 v3(122.85,60.54) ; UC1.BJ7 v3(122.18,56.89) 122.18,56.66 UC1.BK7 ; UC1.AP3 124.79,66.09 v3(124.51,66.09) ; UC1.CM4 123.96,43.65 UC1.CK4 ; v3(123.53,52.24) 123.53,52.46 UC1.BT5 ; v3(119.49,64.85) 120,64.85 120.11,64.74 UC1.AU10 ; UC1.CH31 106.96,45.58 106.6,45.22 106.33,45.22 106.1,44.99 UC1.CJ33 105.04,44.99 v3(104.94,45.09) 104.53,45.09 UC1.CJ35 ; UC1.AV6 122.63,63.81 122.84,63.37 v3(122.87,63.36) 121.55,63.36 UC1.AV8 ; UC1.BY18 v3(115.1,50.46) UC1.BY19 ; UC1.K3 UC1.K4 123.46,80.91 v3(123.45,80.91) 123.45,80.91 v3(122.82,80.91) UC1.J6 ; UU1.12 9.53,86.93 9.25,87.21 v3(9.25,87.52) ; v3(119.66,61.7) 119.93,61.97 UC1.BA10 ; v3(156.63,101.55) 156.94,101.24 157.77,101.24 158.36,100.66 v3(159.78,100.66) 162.54,100.66 163,101.12 v3(163,102.08) 163,103.18 162.51,103.68 v3(161.48,103.68) 158.72,103.68 157.96,102.92 v3(155.5,102.92) ; v3(126.78,44.63) 127.44,44.63 128.52,45.08 131.44,45.08 132.3,44.72 133.07,44.72 133.71,44.08 v3(133.71,43.33) v3(133.71,42.57) 133.71,41.3 133.46,41.04 130.72,41.04 ; v3(106.03,51.58) 105.94,51.58 UC1.BV33 ; UC1.CC11 119.37,48.46 v3(119.36,48.52) 119.36,48.56 UC1.CB11 UC1.CA11 UC1.BY11 119.72,50.14 v3(119.3,50.46) UC1.BW11 ; v3(116.67,85.83) 116.78,85.83 UC1.B15 ; UC1.CA25 110.82,49.15 110.85,49.15 v3(110.85,49.15) 110.92,49.15 111.23,48.83 UC1.CB24 111.42,48.83 v3(111.79,48.47) 111.41,48.17 UC1.CC24 110.91,47.86 110.91,47.86 v3(110.87,47.83) ; UC1.B7 122.2,86.28 v3(122.32,86.4) ; v3(126.88,42.14) 126.34,42.14 125.94,42.54 UC1.CN1 127.31,42.61 128.63,41.3 v3(129.65,41.3) 130.11,41.3 ; v3(120.18,50.4) 120.16,50.4 119.78,50.78 UC1.BW11 ; UC1.CF3 124.92,46.69 v3(124.44,46.69) 124,46.69 UC1.CF4 ; v3(104.69,41.1) 105.2,41.1 105.58,40.72 105.9,39.95 105.9,39.28 v3(106.87,38.31) 106.92,38.27 CC15.2 107.53,36.73 107.53,34.82 107.08,34.37 v3(105.9,34.37) v3(104.96,34.37) v3(104,34.37) 103.68,34.37 103.23,34.82 v3(103.23,35.77) 103.23,36.84 103.74,37.34 CC16.2 103.78,40.32 104.57,41.1 v3(104.69,41.1) ; v3(104.69,41.1) 105.07,41.48 UC1.CR34 ; UC1.BR22 112.58,53.06 112.53,53.01 112.53,52.45 UC1.BU23 111.83,51.83 v3(111.75,51.84) 111.66,51.82 UC1.BU24 ; v3(98.53,38.44) 98.88,38.78 RC51.2 ; UC1.BT36 UC1.BT35 104.57,52.3 v3(104.99,52.3) 105.4,52.3 UC1.BT33 ; UC1.BY5 123.25,49.9 v3(123.56,49.59) 123.56,49.57 UC1.CB4 ; UC1.BE10 120.38,59.2 119.7,59.2 v3(119.59,59.1) ; UC1.BP7 122.23,53.94 v3(122.23,54.08) 122.19,54.09 UC1.BN7 ; UC1.AF33 105.9,71.37 v3(106.05,71.52) ; v3(202.04,64.92) PCZ9.1 ; UC1.CR36 UC1.CP37 103.01,41.96 v3(102.83,42.15) ; v3(169.46,87.4) 169.71,87.65 PUG1.6 ; UC1.CK37 103.32,44.84 103.42,44.94 UC1.CJ36 ; v3(119.97,73.64) 120.04,73.64 120.38,73.29 UC1.AC10 ; UC1.CD25 v3(110.87,47.83) ; v3(110.87,47.83) 110.93,47.83 111.23,47.53 UC1.CD24 ; v3(110.87,47.83) 110.86,47.9 110.49,48.18 UC1.CC25 110.8,48.49 110.82,48.49 ; v3(114.77,81.91) UC1.J18 ; UC1.BP4 124.43,54.06 v3(124.44,54.05) 124.45,54.06 UC1.BP3 ; 110.82,48.49 UC1.CB25 ; 110.82,48.49 v3(110.89,48.49) ; UC1.CB20 113.7,48.69 113.7,48.33 UC1.CC20 v3(113.42,47.86) UC1.CD20 ; UC1.CM9 120.67,43.19 v3(120.67,42.98) 120.67,42.84 UC1.CN9 ; JTC1.B12 7.14,99.7 ; 124.46,78.46 v3(124.46,78.47) 124.46,78.46 ; 124.46,78.46 UC1.P4 ; 124.46,78.46 UC1.P3 ; PUB1.14 195.25,54.32 195.22,54.29 v3(195.22,53.91) ; UC1.CD11 119.72,47.48 119.47,47.22 v3(119.35,47.22) 119.19,47.22 UC1.CD12 ; UC1.CR6 123.24,41.13 v3(123.24,41.04) ; v3(110.96,83.86) 110.84,83.98 UC1.D25 ; v3(174.73,61.49) 174.98,61.74 PUZ3.6 176.27,61.74 176.66,62.12 PCZ41.2 ; UC1.BD4 124.32,59.92 UC1.BE3 124.53,59.48 124.11,59.48 UC1.BE4 123.96,59.63 123.96,59.79 123.74,60 v3(123.74,60.14) 123.99,60.39 UC1.BC4 124,60.72 124.43,61.15 ; UC1.CF23 111.72,46.72 v3(111.72,47.22) ; UC1.BB3 124.74,61.61 124.74,61.95 UC1.BA3 UC1.BA4 ; PCZ40.2 178.02,65.72 176.41,65.72 176.24,65.55 PUZ2.6 174.98,65.55 v3(174.73,65.3) ; v3(122.32,69.83) 122.32,69.74 UC1.AJ7 ; v3(121.61,48.47) 121.61,48.47 121.61,48.7 UC1.CB7 ; UC1.BP32 105.81,53.3 v3(105.76,53.3) 105.59,53.47 UC1.BP33 ; v3(124.51,66.09) 124.34,66.26 UC1.AP4 ; v3(122.21,66.19) 122.14,66.21 UC1.AN7 ; UC1.BE8 121.3,59.42 v3(121.56,59.68) 121.59,59.9 121.67,59.97 121.67,59.98 UC1.BD7 ; v3(117.48,46.62) 117.75,46.62 UC1.CF14 117.96,46.71 118.04,47.53 UC1.CD14 118.13,47.62 118.13,48.1 UC1.CC14 117.96,48.18 v3(117.66,47.89) ; UC1.CN13 UC1.CP13 118.31,41.72 v3(118.41,41.41) ; UC1.CA15 UC1.BY15 116.85,50.41 v3(116.85,50.46) 116.85,50.51 UC1.BW15 ; v3(116.67,81.9) 116.82,81.9 UC1.J15 ; UV1.AF5 135.72,97.13 v3(137.33,97.13) ; UC1.B18 114.83,85.77 v3(114.77,85.81) ; UC1.BU16 v3(115.94,51.76) ; v3(126.59,84.49) 126.58,84.48 126.03,84.48 UC1.D1 ; UC1.BA4 123.99,61.42 UC1.BB4 123.73,61.38 123.53,61.58 v3(123.5,61.58) ; UC1.BA4 123.99,62.27 UC1.AY4 123.99,62.92 UC1.AW4 123.96,63.2 UC1.AV4 ; UC1.AN8 121.51,66.16 v3(121.56,66.15) ; UC1.BG4 123.96,58.32 UC1.BF4 ; v3(123.68,70) 123.39,70.29 UC1.AG5 ; UC1.BT14 117.67,52.45 v3(117.66,52.38) UC1.BT15 116.85,52.41 v3(116.84,52.41) 116.75,52.41 UC1.BT16 ; RC957.1 130.15,40.66 v3(130.24,40.75) ; UC1.BP15 v3(116.82,53.74) 116.82,53.74 UC1.BR16 ; UC3.3 113.51,95.67 114.08,95.09 CC57.2 ; UC1.AV4 124.31,63.82 v3(124.43,63.69) ; v3(106.55,50.58) 106.55,50.69 106.92,51.06 UC1.BV31 ; CC13.2 130.86,41.57 v3(131.94,41.57) ; v3(155.5,30.6) 155.8,30.3 156.27,30.3 156.85,29.72 JTP1.4 ; JEDP.3 v3(71,100.99) ; UC1.AM5 v3(123.45,67.06) ; UC1.BU20 v3(113.42,51.76) ; UC1.BN30 UC1.BL30 ; v3(66.32,100.74) 66.32,100.57 66.5,100.38 JEDP.12 ; v3(112.29,44.99) 111.97,44.99 UC1.CJ23 ; UC1.E29 108.32,84.34 v3(108.16,84.5) 108.32,84.66 UC1.C29 ; UC1.BP19 114.71,54.01 114.71,53.41 UC1.BR19 115,53.07 v3(115.15,53.07) ; v3(120.02,56.07) UC1.BK10 ; CL25.1 35.25,101.74 35.25,99.51 v3(35.18,99.44) 34.95,99.21 32.49,99.21 v3(32.24,99.46) v3(32.24,100.35) 32.24,101.11 ; UC1.F15 v3(116.66,83.86) ; UC1.F12 v3(119.48,83.86) ; v3(114.78,83.85) UC1.F18 ; JEDP.6 v3(69.5,100.95) ; CC295.1 128.24,36.84 v3(128.56,37.15) ; UC1.CG7 122.26,46.58 v3(122.26,46.73) 122.28,46.81 122.12,47.13 UC1.CE7 ; UV1.Y2 139.82,95.52 v3(139.82,96.3) v3(139.82,97.1) 139.84,97.1 UV1.Y5 v3(139.82,97.92) ; v3(99.59,50.72) 98.99,50.72 RC956.1 ; JIO.22 207.67,38.95 v3(207.67,38.95) ; UC1.B12 v3(119.47,85.8) ; v3(119.35,46.39) 119.66,46.71 UC1.CF11 ; v3(119.52,44.59) UC1.CJ11 ; 123.48,42.95 UC1.CM5
  BOTTOM w0.305: v3(222.64,10.05) JWLAN.37 218.36,10.05 218.36,10.05 ; UV1.P5 145.2,97.5 v3(145.6,97.9) ; UV1.U14 142.2,104.7 v3(141.71,104.2) 141.5,104 UV1.V13 ; UV1.B8 155.21,99.93 v3(155.65,99.93) ; UV1.AE17 136.1,107.49 v3(135.7,107.89) ; UV1.AD19 UV1.AD18 136.53,107.96 136.53,107.92 v3(136.51,107.9) ; UV1.AF1 135.01,94.3 v3(134.76,94.55) 134.5,94.81 UV1.AG2 ; v3(138.16,103) 138.16,102.89 138.54,102.52 UV1.AB11 ; UV1.AB7 138.92,98.82 v3(138.95,98.82) 139.02,98.82 UV1.AA7 ; v3(147.52,109.53) 147.67,109.53 UV1.L18 148.2,108.96 v3(147.68,108.44) 147.64,108.44 UV1.M17 ; JWLAN.19 220.68,16.55 v3(220.84,16.39) ; UV1.T11 v3(143.7,102.5) UV1.R12 ; v3(221.63,2.59) 221.58,2.55 JWLAN.67 218.31,2.55 218.3,2.56 ; UV1.AD13 136.9,104.14 v3(136.5,103.74) 136.88,103.36 UV1.AD12 ; v3(221.63,21.01) 221.58,21.05 JWLAN.1 ; v3(138.19,114.53) 138.12,114.53 UV1.AC26 ; UV1.L2 v3(147.29,94.71) ; v3(134.91,107.87) 135.3,107.48 UV1.AF17 ; 218.25,8.55 JWLAN.43 222.6,8.55 v3(222.64,8.59) ; v3(207.67,44.95) 207.67,44.95 JIO.10 ; UV1.AC8 137.52,100.22 137.52,100.22 137.31,100.43 v3(137.31,100.45) ; UV1.U23 142.68,112.5 v3(142.29,112.88) ; v3(188.89,37.79) JSSD.27 ; UC1.BF4 124.23,58.94 124.39,58.78 v3(124.5,58.78) ; v3(134.07,100.07) 134.11,100.04 UV1.AF8 ; UV1.T17 v3(143.7,108.5) UV1.R18 ; UV1.AF14 135.52,105.22 135.69,105.39 v3(135.74,105.39) 135.94,105.18 135.94,105.16 UV1.AE14 136.42,105.32 136.9,105.8 UV1.AD15 ; UV1.P11 v3(145.7,102.5) UV1.N12 ; JSSD.57 196.21,35.17 v3(195.86,34.86) ; UV1.A26 155.9,114.98 v3(155.54,115.34) 155.18,115.7 UV1.B27 ; v3(134.75,109.96) UV1.AF20 UV1.AE20 136.15,109.96 136.9,110.71 UV1.AD21 136.94,110.84 136.94,110.97 136.95,110.98 136.95,111.38 136.94,111.38 136.94,111.56 UV1.AD22 UV1.AC22 ; UV1.N14 v3(145.7,104.5) UV1.P13 ; UV1.P15 v3(145.7,106.5) UV1.N16 ; UV1.B14 155.5,105 v3(155.63,104.87) ; v3(153.03,110.39) 152.7,110.06 UV1.E20 ; v3(221.63,4.05) JWLAN.61 218.34,4.05 v3(218.28,4.11) ; v3(207.69,46.12) 207.36,46.45 JIO.7 ; UV1.K17 148.73,107.53 v3(148.73,107.5) 148.23,107 UV1.L16 v3(147.7,106.5) UV1.M15 ; JIO.13 207.67,43.45 v3(207.67,43.45) ; JSSD.15 185.7,35.99 v3(185.29,35.68) ; UV1.L23 v3(148.1,112.08) ; v3(140.64,112.91) 140.24,112.51 UV1.Y23 ; v3(58.36,100.78) 58.5,100.65 JEDP.28 ; UV1.R10 v3(143.7,100.5) ; UV1.B5 155.43,97.22 v3(155.59,97.22) ; UV1.B20 v3(155.49,109.57) ; v3(187.5,38.02) 187.35,37.49 JSSD.21 ; v3(39.31,109.48) 39.31,109.42 39,109.11 CL15.2 ; v3(150.57,114.49) 150.19,114.1 UV1.H25 ; UV1.B23 155.15,112.45 v3(155.55,112.85) ; UV1.E17 152.7,107.49 v3(152.29,107.9) ; UV1.P26 145.28,114.98 v3(145.28,115.68) ; UV1.V11 v3(141.7,102.5) UV1.U12 ; UV1.U26 142.72,115.24 v3(142.51,115.45) ; UV1.L5 v3(147.3,97.88) ; v3(134.04,102.59) 134.11,102.52 UV1.AF11 UV1.AE11 ; JSSD.51 v3(194.66,34.92) ; JSSD.33 v3(190.39,37.64) ; JSSD.1 182.22,36.25 v3(182.04,36.09) ; UV1.AC5 v3(137.33,97.13) ; JIO.16 207.67,41.95 v3(207.67,41.95) ; JHDD.5 v3(262.93,5.65) ; UV1.T15 v3(143.7,106.5) UV1.R16 ; UV1.U18 142.09,109 v3(141.7,108.61) 141.2,108.11 UV1.V17 ; UV1.E2 152.59,95.1 v3(152.18,95.5) ; v3(152.34,102.97) 152.34,102.88 UV1.E11 ; v3(153.08,105.44) 152.7,105.06 UV1.E14 ; UV1.V15 v3(141.67,106.47) UV1.U16 ; v3(144.82,112.11) 144.82,112.12 UV1.P23 ; UV1.P17 v3(145.7,108.5) UV1.N18 ; JWLAN.18 v3(225.94,16.8) ; 218.11,12.28 218.88,13.05 JWLAN.25 221.58,13.05 v3(221.63,13.01) ; UV1.AF23 134.73,112.45 v3(134.73,112.45) ; UV1.L25 v3(148.1,114.52) ; UV7.A12 v3(135.48,139.31) ; UV7.A12 v3(136.28,138.51) ; UV7.A12 v3(135.48,138.51) ; 218.23,11.58 218.26,11.55 JWLAN.31 222,11.55 v3(222.11,11.66) ; UV1.Y26 v3(140.63,114.51) ; v3(221.09,5.35) 220.71,5.35 220.51,5.55 JWLAN.55 218.36,5.55 218.36,5.54 ; JSSD.3 v3(182.7,35.98) ; CC303.2 127.77,66.67 v3(127.36,67.08) ; JFPR.5 v3(253.03,26.15) ; UV1.B11 v3(155.5,102.92) ; JWLAN.7 v3(221.63,19.55) ; UV1.AB20 138.51,109.96 v3(138.09,110.39) ; v3(147.7,100.5) UV1.L10 148.23,101 v3(148.73,101.5) 148.73,101.53 UV1.K11 ; v3(143.14,95.5) 143.12,95.5 UV1.U2 ; v3(155.66,94.33) 155.9,94.57 UV1.A2 ; v3(150.58,112.13) 150.21,112.5 UV1.H23 ; JSSD.39 v3(191.91,37.56) ; UV1.AG26 v3(133.91,114.9) ; JIO.25 207.42,37.45 v3(207.67,37.7) ; v3(136.49,107.05) UV1.AD16 ; v3(184.34,35.73) 184.21,35.88 184.3,37.03 ; JSSD.45 v3(193.37,37.56) ; v3(220.84,7.26) 220.69,7.26 220.47,7.05 JWLAN.49 218.34,7.05 v3(218.28,7.11) ; v3(152.29,100.38) 152.36,100.38 UV1.E8 ; v3(149.85,94.61) 150.16,94.93 UV1.H2 ; v3(153.08,114.5) 153.05,114.5 UV1.E25 ; UV1.R14 v3(143.7,104.5) UV1.T13 ; JWLAN.13 v3(220.84,18.05) ; v3(207.65,40.45) JIO.19 ; UV1.M13 v3(147.7,104.5) UV1.L14 v3(148.7,105.5) UV1.K15 ; UV1.U10 v3(141.7,100.5) ; UV1.U5 v3(142.3,97.92) ; UV1.H5 v3(149.76,97.9) ; UV7.C11 v3(137.08,136.92)
  BOTTOM w0.33: UV7.E3 143.07,135.71 v3(142.68,135.32) ; v3(157.13,134.71) UV6.N1 ; UV6.R11 166.13,136.31 v3(165.72,135.91) 165.33,135.52 UV6.P10 165.27,135.51 v3(164.85,135.94) ; v3(157.58,132.31) UV6.K1 UV6.K2 ; UV6.R14 168.12,136.72 168.12,136.73 v3(168.13,136.73) ; v3(158.53,136.73) 158.53,136.73 158.53,136.73 158.13,136.33 UV6.R1 ; v3(167.34,135.92) 166.94,136.31 UV6.R12 ; v3(143.5,137.72) 143.48,137.72 UV7.C3 143.08,137.31 v3(142.68,136.92) 142.29,137.31 UV7.C4 ; v3(138.06,134.94) 138.03,134.91 UV7.F10 ; v3(167.34,135.13) 167.32,135.13 167.32,135.11 UV6.N12 166.93,134.71 v3(167.37,134.28) ; v3(159.31,134.25) 159.31,134.3 UV6.N3 159.73,134.72 v3(160.12,135.11) ; v3(143.53,139.35) 143.51,139.35 UV7.A3 ; v3(138.07,134.12) 138.06,134.11 UV7.G10 ; UV7.E1 144.68,135.71 144.27,135.31 v3(144.27,135.25) ; v3(135.45,135.3) 135.42,135.3 135.42,135.33 135.47,135.37 135.54,135.37 UV7.E12 ; UV7.D10 138.06,137.09 138.06,137.53 UV7.B10 137.48,138.12 v3(137.88,138.51) ; v3(134.69,137.72) 134.66,137.72 134.66,137.69 UV7.C14 ; v3(160.13,136.72) 159.73,136.33 UV6.R3 v3(160.13,135.92) 160.53,136.31 UV6.R4 160.54,136.31 160.92,136.7 160.92,136.7 v3(160.93,136.7) 161.33,137.11 UV6.T5 160.94,137.51 v3(160.94,137.51) ; v3(134.68,139.34) 134.28,138.94 UV7.A14 134.27,138.91 v3(133.85,139.34) ; v3(141.87,134.52) 141.48,134.13 UV7.G5 141.11,134.11 v3(140.95,134.27) 140.95,134.39 UV7.F5 141.48,134.93 v3(141.87,135.32) ; 168.15,135.11 168.15,135.1 UV6.N14 ; UV7.E14 133.98,136.02 v3(133.79,136.02) ; UV6.T10 164.76,137.11 v3(164.76,137.12) ; v3(141.87,138.52) 141.48,138.12 141.48,138.11 UV7.B5 ; UV7.C12 v3(135.49,136.92) ; v3(159.58,138.54) 159.58,138.07 UV6.U3 ; UV7.A1 145.27,138.91 145.82,138.36 145.82,138.17 v3(145.89,138.09) 145.82,138.02 145.82,137.82 145.32,137.31 UV7.C1
  BOTTOM w0.35: v3(169.11,137.91) UV6.U14 168.53,137.91 ; v3(161.75,137.52) 161.74,137.52 UV6.T5 ; v3(141.06,137.68) 141.49,138.11 UV7.B5
  BOTTOM w0.356: v3(13.25,74.12) 13.19,74.19 PCM7.1 ; v3(170.4,94.09) 170.26,94.23 CC353.2 ; CS10.2 CS8.2 201.28,46.1 v3(201.28,45.95) ; PCW1.2 v3(191.82,131.49) ; v3(133.79,136.02) 133.78,136.03 131.81,136.03 CV169.2 ; CK2.2 146.48,49.28 CK1.2 147.29,49.28 147.47,49.46 v3(147.65,49.46) ; v3(189.9,47.56) 189.66,47.8 CS9.2 189.09,48.04 CSS7.2 ; CK11.2 148.85,38.23 v3(148.78,38.31) 148.78,38.74 149.03,39 RK116.1 ; CC7.1 91.17,37.61 v3(91.42,37.87) 91.8,37.49 CC324.1 ; PC1006.2 v3(185.74,90.37) ; CSS5.2 CSS6.2 203.33,50.63 v3(203.75,51.05) ; v3(12.17,77.49) 12.3,77.36 PCM19.2 ; CC315.2 90.32,29.83 90.74,30.25 CC14.2 ; RC901.1 101.29,35.67 RC128.2 ; v3(172.42,114.43) 172.41,114.43 172.03,114.43 CC127.2 ; PCM16.2 v3(12.87,77.49) ; CC10.1 91.68,39.52 v3(91.55,39.39) 91.42,39.52 CC11.1 ; v3(13.24,74.76) PCM20.1 ; v3(155.5,30.6) 155.41,30.51 CC360.2 ; CL11.2 v3(31.52,102.37) ; PC1016.2 v3(185.11,90.39)
  BOTTOM w0.381: v3(153.08,112.06) 153.08,111.98 UV1.E22 ; RC940.1 RC986.2 99.55,35.26 v3(99.76,35.05) ; PCW8.2 v3(185.53,131.34) ; PCW16.2 v3(186.16,131.34) ; v3(251.07,18.96) DM16.3 v3(251.07,21.46) ; CC337.2 CC338.2 RC227.1 116.73,39.61 116.29,40.67 v3(116.29,40.67) ; CC299.2 99.18,51.81 99.49,51.5 v3(99.64,51.5) CC298.2 RC958.1 ; UC4.3 94.6,29.15 95.23,29.79 CC300.2 ; v3(115.38,40.66) 115.55,40.49 CC87.2 CC103.2 ; v3(155.66,94.33) 155.63,94.3 UV1.B1 ; PCM3.2 PCM19.2 ; v3(96.67,53.41) 96.25,53.41 96.08,53.58 RC987.2 CC296.2 ; PQ2.4 178.35,70.85 178.11,71.09 v3(178.11,71.36) ; v3(16.19,114.07) D22.3 v3(13.7,114.07) ; PCW4.2 v3(192.45,131.49) ; CU12.2 9.38,88.63 v3(9.38,88.92) ; v3(13.7,120.04) 14.06,120.04 14.18,120.16 D21.3 v3(16.28,120.16) ; PCM21.1 13.19,75.33 v3(13.25,75.39) ; CC256.2 96.33,42.93 v3(95.98,42.58) ; RC128.2 100.82,35.41 v3(100.45,35.05) ; DG1.3 v3(13.64,124.35) ; v3(148.78,38.31) 148.44,37.97 CC362.2 ; v3(98.46,44.23) RC984.2 ; CC363.2 151.47,49.69 v3(151.75,49.97) ; v3(127.24,117.24) 126.98,117.24 126.6,117.62 CV314.2 ; CV133.2 v3(127.24,117.88) ; PQ2.1 v3(179.65,68.04) ; CL11.2 31.74,103.22 CL27.2 ; v3(131.55,44.47) 131.79,44.23 YC2.2 ; UV1.N10 v3(146.64,100.52) ; UV1.P2 v3(145.59,94.71) ; CC9.2 125.4,33.76 v3(125.6,33.55) ; CV223.2 v3(173.45,97.44) ; RC100.1 96.16,34.65 CC297.1 ; v3(132.06,45.36) 131.55,45.87 RC96.2 ; RC132.1 108.46,38.47 v3(108.67,38.47) ; CC365.2 149,35.29 149.39,34.91 PR13.2
  BOTTOM w0.4: v3(168.13,135.13) 168.14,135.13 168.14,135.12 168.15,135.11 ; v3(157.29,138.4) 157.77,137.91 UV6.U1 ; 168.53,137.91 167.95,138.5 v3(167.91,138.5)
  BOTTOM w0.406: v3(170.4,94.09) 170.43,94.05 171.76,94.05 UV23.3
  BOTTOM w0.432: v3(145.13,36.92) 145.13,36.25 144.72,35.84 Q5001.1 ; v3(143.24,33.42) 142.82,33.84 Q5001.4
  BOTTOM w0.457: CC312.1 99.82,54.82 v3(99.65,54.99) 99.2,54.54 RC1156.1 ; v3(169.98,93.61) 170.44,93.15 RV88.1 ; CV165.2 158.38,140.12 v3(158.38,138.49) ; CV209.1 v3(160.31,101.34) ; CV210.1 v3(160.31,102.61)
  BOTTOM w0.508: JTP2.4 138.9,29.51 v3(139.5,30.11) ; FG4.2 52.1,111.07 CTS7.2 54.77,111.07 v3(55.99,112.29) ; v3(207.67,31.34) 207.3,31.34 206.97,31.01 JKB.33 ; CC12.2 130.65,44.47 v3(129.9,44.47) ; PRW2.2 v3(193.2,131.13) ; v3(235.54,28.66) 234.83,29.38 PJP1.10 ; v3(193.4,70.89) 192.96,71.33 PCZ23.2 ; CV378.2 171.03,136.59 v3(170.45,136.01) ; PCB11.2 v3(193.57,61.62) ; RV2768.2 v3(150.65,91.12) ; DT2.2 v3(145.14,31.83) ; v3(192.39,52.28) 193.15,52.28 PCB14.2 ; RV376.2 v3(132.83,111.68) ; JTP2.6 135.45,26.35 135.45,27.32 v3(135.38,27.39) ; v3(189.53,130.97) PRW9.2 ; v3(20.77,102.66) 20.8,102.63 D1.1 ; DA7.1 93.05,95.89 v3(92.97,95.82) ; v3(96.2,29.79) CC300.2 ; QU3.3 8.77,91.16 v3(7.84,92.08) ; CC292.1 132.57,77.82 132.64,77.89 v3(133.25,77.89) ; 32.24,101.11 32.24,101.7 CL24.1 v3(32.42,102.63) ; v3(240.03,19.17) 240.03,19.62 C5214.2 ; JFAN.5 v3(245.24,23.33) ; PC311.2 v3(180.96,119.88) ; PCM15.2 v3(4.65,75.54) ; CL12.2 29.62,112.15 v3(30.42,112.95) ; PR2507.2 v3(8.31,48.78) ; v3(153.81,91.69) RV383.2 RV390.2 ; v3(218.22,21.61) 216.85,20.24 Q9.3 ; C13.2 95.99,94.85 C12.2 v3(96.21,95.84) ; v3(34.99,102.62) 35.11,102.5 CL25.1 ; DM1.1 49.64,101.62 49.13,101.11 v3(49.13,100.48) ; v3(218.68,27.06) 219.15,27.53 PJP1.9 ; C11.2 91.32,95.03 90.36,94.06 85.76,94.06 83.63,96.2 v3(83.63,98.69) ; v3(132.92,41.57) 132.92,42.21 YC2.4 ; PRW4.2 191.46,131.49 v3(191.82,131.49) ; CL26.2 28.42,107.32 v3(28.42,107.68) ; CV22.2 v3(130.64,109.9) ; v3(96.55,33.75) 95.99,34.31 CC297.1 ; JKB.34 171.17,31 v3(171.64,31.47) ; v3(207.89,27.1) 208.06,26.93 PR5.2 ; RK117.1 v3(145.75,36.93) ; v3(117.2,94.38) 116.49,95.09 CC57.2 ; CWL1.2 v3(248.9,19.39) ; CV166.2 167.04,139.96 v3(166.2,139.12) ; JFAN.1 v3(242.27,22.38) ; PCB17.2 194.29,52.22 v3(194.55,52.47) ; CS27.2 194.14,48.33 v3(193.67,47.86) ; v3(146.92,30.37) 147.56,31.01 DM5.1 ; RV205.2 RV206.2 159.96,96.77 159.96,96.61 v3(159.5,96.16) ; v3(130.04,33.3) 130.04,32.62 129.9,32.48 UC2.4 ; v3(182.35,133.18) 182.99,133.81 PCW9.2 ; PC1.2 v3(213.72,33.04) ; JIO.27 v3(209.9,49.51) ; v3(22.5,101.26) 22.49,101.25 JP6.1 ; JTP2.5 145.61,24.84 149.41,24.84 149.82,25.24 v3(149.85,25.24) 149.85,25.28 150.38,25.8 JTP1.12 ; v3(177.12,38.37) 177.85,39.1 CS16.1 177.87,39.43 177.68,39.62 QS1.3 ; v3(209.9,33) 210.37,32.53 PD2.1 ; PC3.2 PC4.2 v3(212.78,26.91) ; v3(173.92,44.51) 173.92,43.92 173.58,43.58 CK5.1 ; v3(79.21,105.2) 78.93,104.92 D7.1 ; RV65.2 170.74,95.59 170.31,96.02 170.31,96.17 170.28,96.19 170.28,96.25 v3(170.26,96.27) ; CC355.1 v3(26.65,99.16) ; RV387.2 v3(152.13,91.7) ; PRZ107.2 v3(191.11,76.73) ; DA6.1 v3(99.44,95.84) ; PR313.2 v3(190.1,110.61) ; C193.1 175.4,37.17 v3(175.31,37.26) ; CL29.2 39.73,105.37 v3(39.72,105.37) 39.67,105.42 CL10.2 ; v3(212.03,26.91) PC6.2 PC5.2 ; v3(169.81,27.43) 169.63,27.25 RK4.1 ; v3(23.47,97.35) 23.01,97.81 DM15.1 ; PR6.2 207.75,24.34 v3(206.98,23.57) ; PR309.2 v3(194.04,113.43) ; UL2.2 44.26,105.56 44.77,105.05 45.65,105.05 46.59,104.11 v3(46.59,103.27) 46.59,102.5 46.08,101.99 CL28.2 ; CV173.2 133.83,139.32 v3(133.85,139.34) ; CV379.2 171.03,135.51 v3(171.04,135.52) ; RK115.1 CK4.2 159.51,50.46 CK9.1 159.96,51.43 v3(160.27,51.12) ; C14.2 101.28,94.34 v3(101.28,95.84) ; PCB24.2 v3(148.75,34.56) PR13.2 ; v3(91.42,37.87) 91.02,38.27 CLRP2.1 ; v3(215.64,25.85) 215.39,26.11 PD1.1 ; PRM9.2 v3(4.7,76.39) ; CK8.2 148.97,44.19 v3(148.78,43.99) ; PC1012.2 174.54,99.27 v3(174.11,98.84) ; JSSD.68 v3(181.14,36.22) ; PR1002.2 v3(191.33,89.74) ; v3(39.25,106.54) 39.16,106.44 CL16.2 ; v3(163.43,51.49) 163.43,51.09 RK108.1 163.86,50.85 164.66,50.05 RK26.2 ; PCM18.2 v3(7.48,80.03) ; JFAN.6 v3(239.59,28.05) ; v3(179.74,66.16) 179.74,66.21 PR21.2 ; PC2.2 v3(212.83,33.04) ; v3(180.91,83.93) 180.83,84.01 PU1801.2 ; v3(158.56,89.43) RV70.2 ; JKBL.5 216.55,15.05 216.26,14.76 v3(216.26,14.37) ; v3(150.95,46.82) 150.92,46.84 CC144.2 ; v3(31.48,112.97) 31.48,112.97 DM13.2 ; PR2503.2 8.56,43.71 v3(8.99,43.28) ; v3(222.31,22.66) 221.8,22.15 JWLAN.68 ; v3(167.91,138.5) 168.06,138.65 168.06,140.12 CV377.2 ; PCM17.2 v3(9.25,80.03) ; v3(39.31,107.45) CL13.2 CL14.2 ; PCZ19.2 193.94,68.5 194.03,68.59 v3(194.42,68.59) ; PRB21.2 200.28,59.13 v3(200.88,59.13) ; JEDP.31 73.7,104.85 v3(73.38,105.17) ; v3(145.89,138.09) 145.98,138.01 CV381.1 ; DM12.2 v3(26.65,113) ; PCZ228.1 v3(207.25,72.66) ; PC1008.2 v3(184.32,90.3) ; v3(8.99,42.59) 8.54,42.59 PC2502.2 ; v3(132.67,83.72) RC486.1 RC480.2 ; RV388.2 v3(155.64,91.69) ; 260.16,15.5 v3(258.97,15.96) ; PCA1.2 165.6,52.65 165.07,52.12 v3(165.07,51.48) ; PC318.2 181.85,100.79 v3(181.58,100.53) ; CLED2.2 v3(6.45,95.17) ; v3(30.63,102.37) RL11.1 ; RV385.2 v3(154.72,91.69) ; PRZ21.1 205.39,66.57 v3(205.45,66.51) ; PCB21.2 v3(200.84,54.89) ; v3(113.41,28.85) 114.89,28.85 115.86,29.81 PC10.2 PC8.2 ; v3(13.44,93.11) 12.81,93.11 12.3,92.6 UU2.2 ; v3(93.96,34.82) 93.84,34.95 JCMOS1.2 ; JKBL.6 v3(209.74,12.77) ; PCG1.2 172.45,88.72 172.12,89.05 169.85,89.05 169.46,88.67 v3(169.46,87.4) ; PRB20.2 v3(200.84,54.05) ; v3(82.06,108.73) 82.06,107.81 82.07,107.8 JSPK.5 ; v3(239.29,19.17) 238.87,19.59 C4801.2 ; PC310.2 v3(186.11,110.46) ; v3(148.78,39.9) 148.84,39.96 CK10.2 RK27.2 ; v3(118.98,137.85) 117.8,139.03 PRV33.2 ; PCB18.2 198.36,52.52 v3(198.19,52.69) ; PCB1.2 v3(194.51,61.6) ; v3(18.65,124.48) CM27.2 CM17.2 ; C5184.2 v3(231.63,3.69) ; CC315.2 90.04,29.22 v3(90.15,29.1) ; PR1009.2 v3(189.02,89.72) ; FG2.2 52.35,106.75 CTS1.2 CTS6.2 52.88,105.89 v3(52.6,105.61) ; RC193.2 RC488.1 130.7,85.72 130.85,85.57 130.98,85.57 131.15,85.39 v3(131.3,85.39) 131.3,85.34 131.24,85.27 131.24,85.13 130.98,84.87 130.98,83.64 130.76,83.41 130.76,82.73 RC487.1 RC489.1 ; PCZ230.2 v3(191.82,75.71) ; v3(262.42,10.21) 262.33,10.12 C140.1 ; v3(212.06,25.99) 211.73,25.67 PD3.2 ; PC327.2 v3(189.21,110.62) ; v3(132.45,85.3) 132.37,85.22 132.37,85.18 131.71,84.52 RC482.2 ; JCR.3 v3(259.79,18.7) ; JEDP.32 v3(55.8,105.28) ; PR1004.2 v3(190.57,89.73) ; R5179.2 v3(231.63,2.68) ; RV20.2 RV21.2 v3(160.69,99.95) ; CV380.2 157.55,140.16 CV165.2 ; PC331.2 v3(194.01,111.78) ; JIO.28 v3(211.46,34.8) ; UC11.2 171.66,111.37 v3(171.2,111.83) ; v3(191.03,59.62) 191.1,59.56 PCB13.1 ; PCZ3.1 v3(207.25,73.55) ; v3(200.9,57.63) 200.2,57.63 PCB23.2 ; PRZ22.1 v3(207.88,71.65) ; CLRP1.1 92.31,38.5 91.55,39.26 v3(91.55,39.39) ; CTS3.2 54.79,110.08 v3(57,112.29) ; CM26.2 v3(18.65,123.46) ; v3(92.44,108.86) 91.52,107.94 JSPK.6 ; JTP1.11 161.63,25.8 v3(162.15,25.28) ; v3(77.72,98.75) 77.72,100.46 D6.1 ; v3(40.07,101.66) CL23.2 CL8.2 ; PCB22.2 v3(200.9,58.45) ; CE24.2 v3(242.43,19.2) ; CV51.2 v3(132.85,109.9) ; PC325.2 v3(182.66,99.74) ; PC2507.2 v3(6.27,48.48) ; PCZ13.1 v3(199.25,65.73) ; PC1014.2 v3(178.28,99.23) ; PCZ227.2 v3(201.53,78.76) ; PCZ47.2 179.05,72.41 v3(179.23,72.59) ; PC1005.2 v3(192.22,89.76)
  vias: v2(5.63,62.38) v2(38.5,90.25) v2(38.57,83.03) v2(38.59,74.28) v2(48.31,23.71) v2(55.22,22.33) v2(63,21.71) v2(91.61,67.25) v2(91.84,59.38) v2(93.47,87.09) v2(112.23,134.14) v2(128.85,128.24) v2(130.84,129.81) v2(137.57,122.03) v2(143.14,59.93) v2(155.76,127.36) v2(159.16,76.55) v2(164.73,53.69) v2(167.94,122.57) v2(172.68,129.51) v2(180.32,48.62) v2(180.78,48.76) v2(190.29,135.59) v2(190.42,104.46) v2(190.61,138.16) v2(194.9,95.12) v2(234.83,6.62) v2(240.66,6.66) v3(0.43,130.61) v3(0.43,69.04) v3(0.43,66.04) v3(0.43,63.04) v3(0.43,60.05) v3(0.43,57.05) v3(0.43,54.05) v3(0.43,51.06) v3(0.43,48.06) v3(0.43,45.06) v3(0.43,42.06) v3(1.21,111.61) v3(1.21,107.64) v3(1.63,77.78) v3(1.63,74.78) v3(1.63,71.79) v3(1.63,37.79) v3(1.63,34.8) v3(1.63,31.8) v3(1.84,80.79) v3(2,39.95) v3(2.13,94.58) v3(2.13,91.58) v3(2.13,83.75) v3(2.27,64.16) v3(2.27,63.56) v3(2.27,62.97) v3(2.27,62.36) v3(2.65,29.65) v3(2.8,110.43) v3(2.78,32.6) v3(2.9,46.57) v3(2.9,45.68) v3(2.97,62.36) v3(3.06,57.01) v3(3.06,54.01) v3(3.11,36.1) v3(3.09,34.2) v3(3.21,86.54) v3(3.27,129.23) v3(3.33,89.41) v3(3.45,97.27) v3(3.41,61.36) v3(3.41,60.73) v3(3.6,62.36) v3(4.14,107.97) v3(4.11,45.11) v3(4.24,62.36) v3(4.55,63.71) v3(4.55,63.08) v3(4.82,112.87) v3(4.87,62.36) v3(4.87,45.11) v3(4.93,30.8) v3(5.19,63.71) v3(5.19,63.08) v3(5.25,34.44) v3(5.6,98.09) v3(5.76,129.23) v3(5.82,110.43) v3(5.77,72.45) v3(5.77,71.84) v3(5.82,63.71) v3(5.82,63.08) v3(5.82,32.33) v3(5.82,29.27) v3(6.02,36.09) v3(6.05,70.95) v3(6.66,70.95) v3(6.84,41.04) v3(7.09,88.02) v3(7.09,81.47) v3(7.18,112.87) v3(7.58,32.33) v3(7.58,29.27) v3(7.98,81.43) v3(7.98,80.79) v3(8.11,41.04) v3(8.36,81.94) v3(8.47,30.8) v3(8.73,129.65) v3(8.7,35.9) v3(8.99,75.72) v3(8.99,74.58) v3(9,41.8) v3(9,41.04) v3(9.21,85.53) v3(9.21,84.39) v3(9.28,127.85) v3(9.28,114.21) v3(9.56,75.15) v3(9.63,57.42) v3(10.27,95.54) v3(10.27,94.25) v3(10.28,85.53) v3(10.28,84.39) v3(10.4,33.29) v3(10.52,57.42) v3(10.9,30.88) v3(11.16,111.78) v3(11.16,111.15) v3(11.34,85.53) v3(11.34,84.39) v3(11.41,57.42) v3(11.79,111.78) v3(11.79,111.15) v3(11.79,49.93) v3(11.79,49.3) v3(11.79,48.66) v3(11.79,48.03) v3(11.93,102.45) v3(12.17,57.42) v3(12.17,29.55) v3(12.3,30.8) v3(12.68,49.93) v3(12.68,49.3) v3(12.68,48.66) v3(12.68,48.03) v3(12.82,103.98) v3(12.82,100.92) v3(12.94,57.42) v3(13.25,95.46) v3(13.7,57.42) v3(13.83,134.98) v3(14.33,82.06) v3(14.33,81.43) v3(14.33,80.79) v3(14.58,103.98) v3(14.58,100.92) v3(15.08,30.08) v3(15.35,111.4) v3(15.35,110.76) v3(15.47,102.45) v3(15.58,149.87) v3(15.98,111.4) v3(15.98,110.76) v3(16.43,92.62) v3(16.61,95.52) v3(17.88,76.64) v3(17.88,73.64) v3(17.88,70.64) v3(17.89,67.84) v3(18.14,98.51) v3(18.14,97.18) v3(18.43,39.26) v3(18.43,37.69) v3(18.43,36.11) v3(18.47,149.07) v3(18.47,146.07) v3(18.47,143.07) v3(18.47,140.08) v3(18.47,137.08) v3(19.6,75.02) v3(19.6,72.03) v3(19.6,69.03) v3(19.69,66.27) v3(19.97,134.27) v3(20.01,39.26) v3(20.01,37.69) v3(20.01,36.11) v3(21.15,122.5) v3(21.18,120.75) v3(21.18,119.45) v3(21.18,117.7) v3(21.19,116.4) v3(21.18,114.65) v3(21.18,113.35) v3(21.18,111.6) v3(21.58,39.26) v3(21.58,37.69) v3(21.58,36.11) v3(22.59,134.27) v3(22.59,133.05) v3(24.24,127.71) v3(24.24,126.46) v3(24.24,124.71) v3(24.24,123.46) v3(24.24,121.71) v3(24.24,120.46) v3(24.24,118.71) v3(24.95,97.46) v3(25.59,134.27) v3(27.26,19.13) v3(27.59,129.51) v3(28.59,134.27) v3(30.11,24.31) v3(30.29,81.38) v3(30.33,76.47) v3(30.33,73.47) v3(30.35,68.3) v3(30.26,19.13) v3(30.37,65.73) v3(30.67,129.46) v3(30.67,127.71) v3(30.67,124.71) v3(30.67,123.46) v3(30.67,121.71) v3(30.67,120.46) v3(30.67,118.71) v3(31.58,134.27) v3(32.15,117.96) v3(32.27,108.58) v3(32.27,107.46) v3(32.27,106.34) v3(32.4,75.14) v3(32.4,71.51) v3(32.43,23.2) v3(32.47,83.73) v3(33.08,90.88) v3(33.25,19.13) v3(33.38,108.58) v3(33.38,107.46) v3(33.38,106.34) v3(34.27,132.94) v3(34.27,129.94) v3(34.27,126.94) v3(34.27,123.95) v3(34.27,120.95) v3(34.27,117.95) v3(34.27,114.95) v3(34.5,107.46) v3(34.5,106.34) v3(34.55,79.01) v3(34.55,76.27) v3(34.55,73.53) v3(34.64,70.52) v3(34.64,68.03) v3(35.29,109.37) v3(35.81,43.58) v3(35.81,42.2) v3(35.82,40.94) v3(35.92,94.51) v3(36.25,19.13) v3(36.72,87.51) v3(36.72,84.46) v3(36.72,81.41) v3(36.72,78.37) v3(36.72,75.32) v3(36.72,72.27) v3(36.72,69.22) v3(36.72,66.17) v3(36.93,113.57) v3(37.54,30.63) v3(37.52,29.56) v3(38.64,91.94) v3(39.25,19.13) v3(39.64,45.13) v3(39.64,43.39) v3(39.64,40.76) v3(39.64,38.87) v3(39.64,34.96) v3(39.64,33.29) v3(39.64,31.51) v3(39.7,91.94) v3(39.7,91.15) v3(39.7,90.37) v3(39.73,89.53) v3(39.73,88.53) v3(39.73,86.52) v3(39.73,85.53) v3(39.73,84.02) v3(39.73,83.03) v3(39.73,82.03) v3(39.73,79.03) v3(39.73,78.03) v3(39.73,76.99) v3(39.73,76.03) v3(39.73,75.03) v3(39.73,73.52) v3(39.73,72.53) v3(39.73,71.53) v3(39.73,70.53) v3(39.73,68.42) v3(39.73,67.84) v3(39.73,62.94) v3(39.67,30.1) v3(39.66,29.45) v3(39.75,87.53) v3(39.75,81.05) v3(39.75,80.05) v3(39.75,69.67) v3(39.76,67.22) v3(39.92,113.57) v3(41.11,93.23) v3(42.14,90.77) v3(42.19,91.71) v3(42.17,89.25) v3(42.22,85.41) v3(42.19,77.95) v3(42.22,75.89) v3(42.22,73.53) v3(42.22,72.46) v3(42.19,71.14) v3(42.19,70.56) v3(42.19,69.51) v3(42.17,68.78) v3(42.22,49.03) v3(42.22,48.03) v3(42.22,45.03) v3(42.22,44.01) v3(42.22,43.02) v3(42.19,42.03) v3(42.22,39.47) v3(42.22,38.53) v3(42.22,37.36) v3(42.19,36.14) v3(42.19,33.29) v3(42.19,29.86) v3(42.25,19.13) v3(42.35,94.1) v3(42.62,78.86) v3(42.7,66.37) v3(42.74,55) v3(42.92,113.57) v3(42.86,108.78) v3(42.91,92.4) v3(42.91,88.28) v3(42.95,80.37) v3(42.95,77.22) v3(43.02,75.08) v3(42.98,71.71) v3(42.97,49.07) v3(43.14,86.01) v3(43.14,82.82) v3(43.41,84.65) v3(43.43,36.15) v3(43.43,32.65) v3(43.52,50.75) v3(43.59,56.47) v3(43.85,73.81) v3(43.84,39.72) v3(43.8,28.84) v3(43.94,94.72) v3(43.93,30.37) v3(43.97,66.37) v3(43.96,55) v3(44.11,52.8) v3(44.18,92.4) v3(44.18,90.57) v3(44.18,88.28) v3(44.22,80.37) v3(44.16,78.7) v3(44.22,77.22) v3(44.25,49.07) v3(44.16,46.96) v3(44.16,43.85) v3(44.16,41.37) v3(44.16,38.2) v3(44.29,75.08) v3(44.25,71.71) v3(44.41,86.01) v3(44.41,82.82) v3(44.54,63.72) v3(44.54,61.82) v3(44.54,59.79) v3(44.54,26.92) v3(44.6,19.13) v3(44.7,36.15) v3(44.7,32.65) v3(44.81,108.35) v3(44.79,50.78) v3(44.96,109.99) v3(45.01,34.1) v3(45.24,66.37) v3(45.2,30.37) v3(45.24,19.13) v3(45.3,84.65) v3(45.32,52.85) v3(45.45,88.28) v3(45.43,46.96) v3(45.43,43.85) v3(45.43,41.37) v3(45.43,38.2) v3(45.45,92.4) v3(45.49,80.37) v3(45.49,77.22) v3(45.52,71.71) v3(45.49,56.47) v3(45.56,75.08) v3(45.61,28.84) v3(45.68,86.01) v3(45.68,82.82) v3(45.7,39.74) v3(45.7,26.96) v3(45.75,73.81) v3(45.81,63.72) v3(45.81,61.82) v3(45.81,59.79) v3(45.8,45.25) v3(45.92,113.57) v3(45.97,36.15) v3(45.97,32.65) v3(46.08,78.69) v3(46.28,90.6) v3(46.43,93.64) v3(46.51,66.37) v3(46.47,30.37) v3(46.57,52.61) v3(46.66,68.49) v3(46.7,46.96) v3(46.7,43.85) v3(46.7,41.37) v3(46.7,38.2) v3(46.8,110.06) v3(46.83,55.02) v3(46.93,94.72) v3(46.87,34.1) v3(47.08,63.72) v3(47.08,61.82) v3(47.08,59.79) v3(47.17,72.79) v3(47.4,56.47) v3(47.67,45.25) v3(47.8,30.68) v3(47.93,68.49) v3(47.93,41.38) v3(47.91,33.06) v3(48.24,19.13) v3(48.91,113.57) v3(49.03,23.05) v3(49.67,23.05) v3(49.93,94.72) v3(50.26,23.05) v3(50.4,39.07) v3(50.54,91.39) v3(50.45,70.7) v3(50.51,68.55) v3(50.59,88.91) v3(50.56,86.78) v3(50.58,81.82) v3(50.59,80.93) v3(50.6,45.5) v3(50.6,44.29) v3(50.58,34.84) v3(50.8,75.39) v3(50.78,32.67) v3(50.9,23.05) v3(51.03,39.07) v3(51.15,91.41) v3(51.15,86.78) v3(51.09,70.7) v3(51.24,19.13) v3(51.4,75.39) v3(51.91,113.57) v3(52.24,38.57) v3(52.32,90.97) v3(52.37,83.12) v3(52.39,72.43) v3(52.37,46.9) v3(52.48,41.4) v3(52.57,74.9) v3(52.84,38.57) v3(52.81,30.73) v3(52.93,94.72) v3(52.89,70.2) v3(52.95,90.97) v3(52.99,83.12) v3(52.95,76.3) v3(52.98,72.43) v3(52.98,46.88) v3(52.99,43.73) v3(53.01,28.39) v3(53.06,86.28) v3(53.08,81.32) v3(53.08,80.42) v3(53.11,41.28) v3(53.07,32.21) v3(54.23,19.13) v3(54.66,23.05) v3(54.91,113.57) v3(55.29,23.05) v3(55.51,41.84) v3(55.51,36.22) v3(55.61,44.05) v3(55.89,23.05) v3(56.14,92.74) v3(56.16,89.45) v3(56.21,86.49) v3(56.35,87.67) v3(56.27,82.16) v3(56.27,78.98) v3(56.34,76.81) v3(56.3,72.98) v3(56.36,74.65) v3(56.46,51.06) v3(56.51,40.07) v3(56.49,27.35) v3(56.52,23.05) v3(56.59,66.63) v3(56.59,55.03) v3(56.75,35.78) v3(56.75,32.69) v3(56.91,84.11) v3(56.93,56.69) v3(56.97,28.7) v3(57.1,53.4) v3(57.22,80.89) v3(57.17,75.52) v3(57.23,19.13) v3(57.25,29.95) v3(57.38,92.74) v3(57.43,89.45) v3(57.54,82.14) v3(57.54,78.98) v3(57.48,46.96) v3(57.48,44.22) v3(57.48,41.37) v3(57.45,37.98) v3(57.62,87.67) v3(57.61,76.81) v3(57.57,72.98) v3(57.73,51.06) v3(57.67,49.5) v3(57.76,54.97) v3(57.76,27.35) v3(57.91,113.57) v3(57.86,66.63) v3(57.86,63.53) v3(58.02,35.78) v3(58.02,32.69) v3(58.06,91.25) v3(58.11,86.49) v3(58.18,84.11) v3(58.33,33.96) v3(58.37,53.4) v3(58.42,40.07) v3(58.52,29.95) v3(58.61,27.33) v3(58.7,89.45) v3(58.75,46.96) v3(58.75,44.22) v3(58.75,41.37) v3(58.72,37.98) v3(58.81,82.14) v3(58.81,78.98) v3(58.81,56.69) v3(58.84,28.7) v3(58.89,87.67) v3(58.88,76.81) v3(58.93,55.2) v3(59,51.06) v3(59.04,49.5) v3(59.06,80.88) v3(59.07,75.52) v3(59.13,63.53) v3(59.13,61.81) v3(59.13,59.61) v3(59.07,45.55) v3(59.29,35.78) v3(59.29,32.69) v3(59.45,84.11) v3(59.83,30.12) v3(59.8,27.36) v3(59.95,92.75) v3(59.93,91.25) v3(59.89,52.49) v3(60.02,46.96) v3(60.02,44.22) v3(60.02,41.37) v3(59.99,37.98) v3(60.24,33.96) v3(60.23,19.13) v3(60.4,61.81) v3(60.74,56.69) v3(60.9,113.57) v3(61.2,92.74) v3(61.19,52.49) v3(61.23,45.55) v3(63.23,19.13) v3(63.73,79.28) v3(63.74,24.05) v3(63.83,90.03) v3(63.83,48.31) v3(63.81,47.02) v3(63.83,36.26) v3(63.77,34.16) v3(63.8,26.18) v3(63.9,113.57) v3(63.9,91.77) v3(63.99,84.24) v3(63.97,81.82) v3(64.02,38.53) v3(64.09,44.25) v3(64.34,79.27) v3(64.38,34.17) v3(64.72,44.22) v3(64.75,75.78) v3(64.97,30.2) v3(66.22,19.13) v3(66.9,113.57) v3(67.42,94.73) v3(67.88,104.72) v3(68.94,109.11) v3(69.22,19.13) v3(69.58,109.11) v3(69.74,104.93) v3(69.9,113.57) v3(70.08,27.77) v3(70.21,109.11) v3(70.85,109.11) v3(71.53,105.17) v3(71.8,109.11) v3(72.22,19.13) v3(72.44,109.11) v3(72.5,101.11) v3(72.89,113.57) v3(75.21,19.13) v3(75.89,113.57) v3(78.21,19.13) v3(78.89,113.57) v3(79.09,98.67) v3(81.01,98.69) v3(81.21,19.13) v3(81.88,113.54) v3(82.99,110.75) v3(84.21,19.13) v3(85.99,110.57) v3(87.2,19.35) v3(88.49,22.05) v3(88.98,110.57) v3(90.92,81.27) v3(90.92,49.47) v3(91.13,112.66) v3(91.43,22.63) v3(92.46,111.1) v3(92.47,83.96) v3(92.47,78.58) v3(92.47,52.16) v3(92.47,46.78) v3(93.56,72.58) v3(93.75,67.66) v3(93.83,56.26) v3(93.99,113.57) v3(93.96,62.45) v3(94.2,112.51) v3(94.2,73.69) v3(94.37,71.29) v3(94.43,22.63) v3(94.69,55.17) v3(94.91,72.6) v3(94.89,58.95) v3(95.1,56.26) v3(95.34,58.38) v3(95.4,65.51) v3(95.46,111.1) v3(95.59,83.96) v3(95.59,78.58) v3(95.64,71.29) v3(95.59,52.16) v3(95.59,46.78) v3(95.81,69.78) v3(95.86,67.59) v3(96.01,73.63) v3(96.2,60.77) v3(96.31,62.43) v3(96.52,72.64) v3(96.51,58.34) v3(96.51,55.19) v3(96.67,85.71) v3(96.72,59.06) v3(96.65,57.22) v3(96.83,74.59) v3(96.83,71.3) v3(96.9,63.74) v3(96.98,113.57) v3(97.14,81.27) v3(97.14,49.47) v3(97.2,112.51) v3(97.3,65.49) v3(97.43,22.63) v3(97.53,66.73) v3(97.49,62.47) v3(97.56,55.83) v3(97.73,69.78) v3(98.09,71.29) v3(98.67,83.88) v3(98.95,66.57) v3(99.07,86.99) v3(99.07,67.86) v3(99.36,76.03) v3(99.41,65.49) v3(99.51,83.03) v3(99.63,49.22) v3(99.78,111.1) v3(99.78,108.82) v3(99.98,113.57) v3(100.29,76.93) v3(100.57,75.99) v3(100.69,75.22) v3(100.93,22.63) v3(100.99,25.97) v3(100.99,25.38) v3(100.99,24.8) v3(100.99,24.21) v3(100.99,23.63) v3(101.57,25.97) v3(101.57,25.38) v3(101.57,24.8) v3(101.57,24.21) v3(101.57,23.63) v3(102.25,87.57) v3(102.32,111.1) v3(102.32,108.82) v3(102.39,86.76) v3(102.76,85.37) v3(102.98,113.57) v3(103.42,22.63) v3(103.64,89.45) v3(103.87,86.7) v3(104.54,91.42) v3(104.83,89.45) v3(104.86,111.1) v3(104.86,108.82) v3(104.94,88.82) v3(106.13,133.13) v3(106.13,130.64) v3(106.13,127.64) v3(106.13,124.64) v3(106.13,121.65) v3(106.13,118.65) v3(106.13,115.65) v3(106.12,90.83) v3(106.42,22.63) v3(106.65,135.07) v3(107.62,133.62) v3(107.93,116.16) v3(107.93,115.53) v3(107.92,114.85) v3(108.25,133.62) v3(108.33,92.65) v3(108.33,90.75) v3(108.89,133.62) v3(109.19,135.07) v3(109.28,34.11) v3(109.42,22.63) v3(109.46,133.94) v3(109.57,90.64) v3(110,54.46) v3(110.6,34.21) v3(110.94,91.84) v3(111.63,135.79) v3(112,58.5) v3(112.19,125.64) v3(112.19,124.22) v3(112.19,122.75) v3(112.19,121.54) v3(112.16,59.99) v3(112.3,91.38) v3(112.3,89.42) v3(112.42,22.63) v3(112.89,117.37) v3(112.89,116.64) v3(112.89,115.97) v3(112.89,59.46) v3(112.95,133.26) v3(112.95,131.84) v3(112.95,130.37) v3(112.95,129.16) v3(113.14,128.42) v3(113.14,127.78) v3(113.14,127.15) v3(113.14,126.51) v3(113.23,121.54) v3(113.24,44.24) v3(113.27,137.75) v3(113.31,125.64) v3(113.31,124.22) v3(113.31,122.75) v3(113.25,40.75) v3(113.41,41.32) v3(113.63,140.25) v3(113.6,43.03) v3(113.77,128.42) v3(113.77,127.78) v3(113.77,127.15) v3(113.77,126.51) v3(113.77,61.74) v3(114,129.16) v3(114.03,112.29) v3(114.03,111.65) v3(114.07,133.26) v3(114.07,131.84) v3(114.07,130.37) v3(114.41,128.42) v3(114.41,127.78) v3(114.41,127.15) v3(114.41,126.51) v3(114.38,125.64) v3(114.38,124.22) v3(114.38,122.75) v3(114.41,61.77) v3(114.39,54.46) v3(114.72,142.57) v3(114.66,135.4) v3(114.79,112.29) v3(114.79,111.65) v3(114.83,69.32) v3(114.89,70.72) v3(114.89,59.91) v3(115.04,128.42) v3(115.04,127.78) v3(115.04,127.15) v3(115.04,126.51) v3(115.03,61.78) v3(115.15,133.26) v3(115.15,131.84) v3(115.15,130.37) v3(115.41,22.63) v3(115.54,43.79) v3(115.68,127.78) v3(115.68,127.15) v3(115.68,126.51) v3(115.8,34.31) v3(115.97,57.58) v3(116.1,69.27) v3(116.23,70.72) v3(116.31,127.78) v3(116.31,127.15) v3(116.31,126.51) v3(116.95,127.78) v3(116.95,127.15) v3(116.95,126.51) v3(117.24,69.27) v3(117.5,59.91) v3(117.58,127.78) v3(117.58,127.15) v3(117.58,126.51) v3(117.56,70.72) v3(117.72,142.57) v3(118.07,88.56) v3(118.22,127.78) v3(118.22,127.15) v3(118.22,126.51) v3(118.41,117.37) v3(118.41,116.73) v3(118.41,116.1) v3(118.41,115.46) v3(118.41,114.83) v3(118.41,114.07) v3(118.41,113.43) v3(118.41,112.8) v3(118.41,112.16) v3(118.41,111.53) v3(118.41,110.89) v3(118.41,110.26) v3(118.41,22.63) v3(118.49,69.37) v3(118.54,59.08) v3(118.98,127.78) v3(118.98,127.2) v3(119.11,94.89) v3(119.36,92.55) v3(119.62,127.78) v3(119.62,127.2) v3(119.66,88.58) v3(120.47,85.87) v3(120.47,84.78) v3(120.47,84.04) v3(120.47,83.19) v3(120.47,82.36) v3(120.5,81.28) v3(120.59,91.3) v3(120.71,142.57) v3(120.77,88.58) v3(120.87,93.55) v3(121.07,136.44) v3(121.07,135.2) v3(121.41,22.63) v3(121.57,83.69) v3(121.65,25.04) v3(121.86,88.59) v3(122.23,112.32) v3(122.32,136.44) v3(122.32,135.2) v3(122.26,70.66) v3(122.28,25.04) v3(122.28,24.4) v3(122.92,25.04) v3(123.35,141.19) v3(123.41,84.69) v3(123.71,142.57) v3(123.78,115.01) v3(123.78,109.63) v3(124.4,22.63) v3(125.11,40.95) v3(125.43,40.46) v3(126.6,86.32) v3(126.71,142.57) v3(126.9,115.01) v3(126.9,109.63) v3(127.3,101.58) v3(127.4,22.63) v3(127.78,53.57) v3(127.94,98.6) v3(128.35,101.8) v3(128.25,73.62) v3(128.45,112.32) v3(129.31,138.46) v3(129.71,142.57) v3(129.83,99.51) v3(129.93,128.81) v3(129.93,128.18) v3(129.93,127.54) v3(129.93,126.91) v3(130.08,96.16) v3(130.4,22.55) v3(130.56,114.96) v3(130.56,114.33) v3(130.71,96.16) v3(130.76,59.16) v3(130.75,58.26) v3(131.14,114.96) v3(131.14,114.33) v3(131.19,120.18) v3(132.53,20.45) v3(132.7,142.57) v3(133.12,62.46) v3(133.21,63.19) v3(133.63,81.27) v3(133.63,49.47) v3(133.73,133.31) v3(134.71,132.93) v3(135.18,83.96) v3(135.18,78.58) v3(135.18,52.16) v3(135.18,46.78) v3(135.23,19.13) v3(135.28,120.58) v3(135.48,132.92) v3(135.49,132.12) v3(135.49,128.92) v3(135.47,128.11) v3(135.63,63.46) v3(135.56,62.16) v3(135.7,142.57) v3(135.76,119.16) v3(135.76,117.96) v3(136.3,126.51) v3(136.25,65.04) v3(136.64,119.74) v3(136.62,118.57) v3(136.63,117.38) v3(136.91,62.56) v3(137.08,128.11) v3(137.89,129.72) v3(137.9,127.32) v3(137.87,63.04) v3(138.04,117.98) v3(138.06,118.56) v3(138.23,19.13) v3(138.3,83.96) v3(138.3,78.58) v3(138.3,52.16) v3(138.3,46.78) v3(138.7,142.57) v3(138.99,118.03) v3(138.98,117.39) v3(139.01,112.07) v3(139.2,122.32) v3(139.85,81.27) v3(139.94,61.49) v3(139.85,49.47) v3(140.7,121.79) v3(141.06,130.48) v3(141.22,19.13) v3(141.4,118.03) v3(141.4,117.44) v3(141.69,142.57) v3(141.88,131.3) v3(141.88,129.71) v3(141.88,126.51) v3(142.52,118.5) v3(142.53,117.2) v3(142.48,67.08) v3(142.48,66.44) v3(142.68,128.11) v3(142.68,127.31) v3(142.7,125.69) v3(142.73,90.22) v3(143.11,67.08) v3(143.11,66.44) v3(143.37,90.22) v3(143.49,132.11) v3(143.48,129.71) v3(143.93,118.61) v3(143.91,117.34) v3(144,90.22) v3(144,86.28) v3(144.22,19.13) v3(144.38,85.8) v3(144.65,86.33) v3(144.69,142.57) v3(144.91,117.69) v3(145.08,127.32) v3(145.14,62.12) v3(145.14,61.49) v3(145.27,133.32) v3(145.52,84.35) v3(145.52,81.94) v3(145.52,79.52) v3(145.52,77.87) v3(145.84,75.2) v3(145.78,62.12) v3(146.41,62.12) v3(146.48,75.84) v3(146.48,75.2) v3(147.05,84.35) v3(147.05,81.94) v3(146.99,79.52) v3(147.05,77.87) v3(147.05,62.12) v3(147.11,75.84) v3(147.22,19.13) v3(147.29,95.51) v3(147.69,142.57) v3(147.7,102.5) v3(147.68,79.52) v3(147.68,78.63) v3(147.68,77.87) v3(147.68,62.12) v3(147.68,59.46) v3(148.32,62.12) v3(148.32,59.46) v3(148.32,58.06) v3(148.73,103.5) v3(148.95,59.46) v3(149.08,58.06) v3(149.59,59.46) v3(149.84,58.06) v3(150.21,19.13) v3(150.6,58.06) v3(150.69,142.57) v3(151.37,58.06) v3(153.21,19.13) v3(153.68,142.57) v3(154.62,22.07) v3(155.47,106.26) v3(155.81,68.22) v3(155.81,67.63) v3(155.81,67.05) v3(155.81,66.47) v3(155.81,65.68) v3(155.81,65.04) v3(156.19,23.64) v3(156.21,19.13) v3(156.45,68.22) v3(156.45,67.63) v3(156.45,67.05) v3(156.45,66.47) v3(156.45,65.68) v3(156.45,65.04) v3(156.68,142.57) v3(156.83,111.6) v3(156.82,105.46) v3(156.88,115.37) v3(156.94,104.61) v3(157.08,106.79) v3(157.08,77.55) v3(157.08,68.22) v3(157.08,67.63) v3(157.08,67.05) v3(157.08,66.47) v3(157.08,65.68) v3(157.08,65.04) v3(157.46,130.62) v3(157.53,107.87) v3(157.59,77.87) v3(157.59,77.24) v3(157.73,124.71) v3(157.67,109.22) v3(157.72,68.22) v3(157.72,67.63) v3(157.72,67.05) v3(157.77,22.07) v3(157.86,89.43) v3(158.22,77.24) v3(158.35,68.22) v3(158.35,67.63) v3(158.35,67.05) v3(158.73,66.5) v3(158.86,77.87) v3(158.86,77.24) v3(158.99,67.63) v3(158.99,67.05) v3(159.21,19.13) v3(159.33,131.1) v3(159.34,127.91) v3(159.28,124.68) v3(159.25,89.43) v3(159.49,77.87) v3(159.49,77.24) v3(159.62,68.22) v3(159.62,67.63) v3(159.62,67.05) v3(159.68,142.57) v3(160,66.5) v3(160.13,128.71) v3(160.13,126.31) v3(160.13,77.87) v3(160.13,77.24) v3(160.26,68.22) v3(160.26,67.63) v3(160.26,67.05) v3(160.44,138.64) v3(160.76,77.87) v3(160.76,77.24) v3(160.93,134.32) v3(160.94,128.71) v3(160.89,68.22) v3(160.89,67.63) v3(160.89,67.05) v3(161.4,77.87) v3(161.4,77.24) v3(161.4,53.93) v3(161.53,68.22) v3(161.53,67.63) v3(161.53,67.05) v3(161.7,133.51) v3(161.82,129.8) v3(161.79,126.38) v3(161.95,97.68) v3(162.03,77.87) v3(162.03,53.93) v3(162.16,68.22) v3(162.16,67.63) v3(162.16,67.05) v3(162.2,19.13) v3(162.68,142.57) v3(162.67,77.87) v3(162.67,53.93) v3(162.77,78.51) v3(162.8,68.85) v3(162.8,68.22) v3(162.8,67.63) v3(162.8,67.05) v3(163.05,54.5) v3(163.3,77.87) v3(163.3,53.93) v3(163.36,79.27) v3(163.36,78.51) v3(163.43,68.85) v3(163.43,68.22) v3(163.43,67.63) v3(163.43,67.05) v3(163.5,100.37) v3(163.5,94.99) v3(163.69,55.02) v3(163.69,54.44) v3(163.94,79.27) v3(163.94,78.51) v3(163.94,77.87) v3(164,53.93) v3(164.07,68.85) v3(164.07,68.22) v3(164.07,67.63) v3(164.07,67.05) v3(164.2,123.09) v3(164.32,55.02) v3(164.32,54.44) v3(164.57,79.27) v3(164.7,68.85) v3(164.7,68.22) v3(164.8,129.91) v3(164.83,129.09) v3(164.96,55.02) v3(164.96,54.44) v3(165.2,19.13) v3(165.33,124.52) v3(165.34,69.49) v3(165.34,68.85) v3(165.34,68.22) v3(165.52,122.99) v3(165.67,142.57) v3(165.73,127.11) v3(166.1,69.49) v3(166.1,68.85) v3(166.1,68.22) v3(166.1,67.63) v3(166.1,67.05) v3(166.1,66.47) v3(166.1,65.87) v3(166.54,125.51) v3(166.62,100.37) v3(166.62,94.99) v3(167.33,127.92) v3(167.33,127.13) v3(168.12,131.13) v3(168.11,126.31) v3(168.17,97.68) v3(168.2,19.13) v3(168.67,142.57) v3(171.18,109.32) v3(171.18,108.72) v3(171.15,107.73) v3(171.15,107) v3(171.15,106.22) v3(171.15,105.49) v3(171.15,104.69) v3(171.15,103.97) v3(171.18,101.76) v3(171.18,101.12) v3(171.19,19.13) v3(171.67,142.57) v3(171.84,129.92) v3(171.84,129.24) v3(173.73,141.09) v3(173.73,139.95) v3(173.73,138.68) v3(173.73,137.41) v3(173.73,136.14) v3(173.72,135.54) v3(174.19,19.13) v3(174.48,91.37) v3(174.48,90.79) v3(174.48,90.2) v3(174.66,142.57) v3(174.73,58.53) v3(175.37,58.53) v3(175.62,85.24) v3(175.62,84.6) v3(175.62,70.89) v3(175.62,70.25) v3(175.62,69.62) v3(175.62,68.98) v3(176,58.53) v3(176.26,85.24) v3(176.26,84.6) v3(177.12,85.92) v3(177.12,85.29) v3(177.19,19.13) v3(177.38,110.02) v3(177.66,142.57) v3(177.71,85.92) v3(177.71,85.29) v3(177.97,110.02) v3(178.55,110.02) v3(179.14,110.02) v3(179.72,110.02) v3(180.19,19.13) v3(180.31,110.03) v3(180.66,142.57) v3(181.38,55.01) v3(181.38,54.43) v3(181.45,49.98) v3(181.45,49.4) v3(182.09,49.98) v3(182.09,49.4) v3(182.72,49.98) v3(182.72,49.4) v3(183.18,19.13) v3(183.66,142.57) v3(183.69,62.76) v3(183.76,103.43) v3(184.39,94.99) v3(184.45,87.29) v3(184.45,86.71) v3(185.05,87.29) v3(185.05,86.71) v3(185.33,83.71) v3(185.33,83.13) v3(185.59,62.76) v3(185.76,103.43) v3(186.23,62.76) v3(186.18,19.13) v3(186.65,142.57) v3(186.8,94.99) v3(186.86,62.76) v3(187.43,135.91) v3(187.49,103.3) v3(187.49,102.71) v3(187.5,62.76) v3(188.07,103.3) v3(188.07,102.71) v3(188.13,62.76) v3(188.66,103.3) v3(188.66,102.71) v3(189.24,103.3) v3(189.24,102.71) v3(189.18,19.13) v3(189.65,142.57) v3(189.83,103.3) v3(189.83,102.71) v3(190.13,136.86) v3(190.13,136.19) v3(190.41,103.3) v3(190.41,102.71) v3(190.74,136.86) v3(190.74,136.19) v3(190.81,95.09) v3(191.05,103.3) v3(191.35,136.86) v3(191.35,136.19) v3(191.41,95.07) v3(191.54,115.86) v3(191.54,115.22) v3(191.96,136.86) v3(191.96,136.19) v3(191.96,135.59) v3(192.04,95.07) v3(192.12,115.86) v3(192.12,115.22) v3(192.18,19.13) v3(192.35,40.57) v3(192.65,142.57) v3(192.57,136.86) v3(192.57,136.19) v3(192.57,135.59) v3(192.64,96.2) v3(192.64,95.61) v3(192.64,95) v3(192.67,116.24) v3(192.67,115.6) v3(192.67,114.97) v3(193.2,39.1) v3(193.25,116.24) v3(193.25,115.6) v3(193.25,114.97) v3(193.27,96.2) v3(193.27,95.61) v3(193.27,95) v3(193.84,116.24) v3(193.84,115.6) v3(193.84,114.97) v3(193.91,96.2) v3(193.91,95.61) v3(193.91,95) v3(194.22,40.56) v3(194.95,57.39) v3(194.95,55.79) v3(195.17,19.13) v3(195.64,142.57) v3(195.88,119.53) v3(195.98,40.56) v3(196.07,120.54) v3(196.07,116.35) v3(196.15,38.27) v3(196.26,114.38) v3(196.55,57.39) v3(196.55,55.79) v3(196.69,73.9) v3(196.69,71.98) v3(196.69,70.07) v3(197.93,40.53) v3(197.98,38.27) v3(198.17,19.13) v3(198.3,141.11) v3(198.3,138.26) v3(198.64,142.57) v3(198.61,73.9) v3(198.61,71.98) v3(198.61,70.07) v3(199.75,40.14) v3(199.8,38.27) v3(200.53,73.9) v3(200.53,71.98) v3(200.53,70.07) v3(201.01,37.12) v3(201.15,136.93) v3(201.17,19.13) v3(201.64,142.57) v3(201.86,38.07) v3(202.29,136.93) v3(203.69,136.93) v3(204.16,19.13) v3(204.28,139.5) v3(204.64,142.57) v3(205.17,141.03) v3(205.17,137.97) v3(206.93,141.03) v3(206.93,137.97) v3(207.16,19.06) v3(207.63,142.56) v3(208.11,141.5) v3(208.11,140.48) v3(208.11,139.53) v3(208.11,138.2) v3(208.11,136.93) v3(208.12,134.88) v3(208.12,131.88) v3(208.13,16.22) v3(208.13,13.22) v3(208.24,59.45) v3(208.2,10.23) v3(208.45,129.05) v3(208.57,62.43) v3(209.41,120.86) v3(209.41,118.19) v3(209.41,115.65) v3(209.47,113.18) v3(209.97,57) v3(210.55,64.54) v3(210.62,127.16) v3(210.62,124.16) v3(210.62,121.16) v3(210.62,118.16) v3(210.62,115.17) v3(210.62,112.17) v3(210.62,109.17) v3(210.62,106.18) v3(210.62,103.18) v3(210.62,100.18) v3(210.62,97.18) v3(210.62,94.19) v3(210.62,91.19) v3(210.62,88.19) v3(210.62,85.2) v3(210.62,82.2) v3(210.62,79.2) v3(210.62,76.2) v3(210.62,73.17) v3(210.62,70.25) v3(210.62,67.27) v3(211.18,9.93) v3(211.83,14.07) v3(212.39,11.78) v3(212.88,56.3) v3(214.18,9.93) v3(215.39,11.17) v3(216.53,55.37) v3(217.04,38.39) v3(217.03,35.94) v3(217.18,9.89) v3(218.08,52.81) v3(218.28,1.11) v3(218.82,38.39) v3(218.8,35.94) v3(219.8,50.35) v3(220.65,35.95) v3(221.63,15.09) v3(221.67,48.01) v3(222.36,1.67) v3(222.68,3.3) v3(223.23,0.43) v3(223.69,45.79) v3(224.48,27.05) v3(224.48,26.46) v3(224.48,25.83) v3(224.46,4.35) v3(225.11,27.05) v3(225.11,26.46) v3(225.11,25.83) v3(225.75,26.46) v3(225.75,25.83) v3(225.84,43.71) v3(225.76,27.07) v3(225.92,2.69) v3(226.3,26.77) v3(227.2,0.43) v3(228.13,41.77) v3(230.19,0.43) v3(230.54,39.99) v3(231.64,23.72) v3(231.64,23.07) v3(233.06,38.36) v3(233.14,5.25) v3(233.15,2.52) v3(233.19,0.43) v3(234.3,13.99) v3(234.42,15.26) v3(234.54,9.1) v3(235.67,36.9) v3(236.14,5.25) v3(236.15,2.52) v3(236.19,0.43) v3(236.66,12.67) v3(236.67,11.04) v3(238.38,35.62) v3(238.43,32.62) v3(239.11,7.73) v3(239.13,5.25) v3(239.15,2.52) v3(239.18,0.43) v3(240.29,18.05) v3(240.64,9.56) v3(240.77,30.74) v3(241.17,11.97) v3(242.11,7.73) v3(242.13,5.25) v3(242.14,2.52) v3(242.18,0.43) v3(242.67,28.57) v3(243.48,29.75) v3(243.49,15.48) v3(243.64,9.56) v3(244.95,12) v3(245.1,7.73) v3(245.13,5.25) v3(245.14,2.52) v3(245.18,0.43) v3(246.01,18.18) v3(246.4,28.69) v3(246.64,9.56) v3(246.71,13.38) v3(248.1,7.73) v3(248.12,5.25) v3(248.14,2.52) v3(248.18,0.43) v3(248.71,11.84) v3(249.02,30.16) v3(251.12,5.25) v3(251.13,2.52) v3(251.17,0.43) v3(251.29,32.1) v3(252.26,30.39) v3(252.4,28.68) v3(252.79,6.85) v3(254.28,31.84) v3(254.85,3.2) v3(255.77,4.81) v3(255.77,1.59) v3(256.21,30.58) v3(256.25,28.69) v3(256.33,26.66) v3(257.63,4.81) v3(257.63,1.59) v3(258.55,3.2) v3(258.71,26.84) v3(259.21,30.58) v3(259.16,23.06) v3(259.25,28.69) v3(260.27,31.77) v3(261.81,30) v3(261.78,17.13) v3(262.29,13.82) v3(263.16,0.43) v3(263.27,31.77) v3(264.1,6.66) v3(264.5,18.39) v3(264.5,15.39) v3(264.88,11.6) v3(265.55,7.58) v3(265.56,4.85) v3(266.27,31.77) v3(266.63,0.44) v3(266.84,30.29) v3(266.84,27.29) v3(266.84,24.3) v3(266.84,21.3) v3(266.84,18.3) v3(266.84,15.3) v3(266.84,12.31) v3(266.84,9.31) v3(266.84,6.31) v3(266.86,3.58) v3(268.27,29.54) v3(268.27,26.54) v3(268.27,23.54) v3(268.27,20.55) v3(268.27,17.55) v3(268.27,14.55) v3(268.27,11.55) v3(268.27,8.56) v3(268.27,5.56) v3(268.27,2.56)
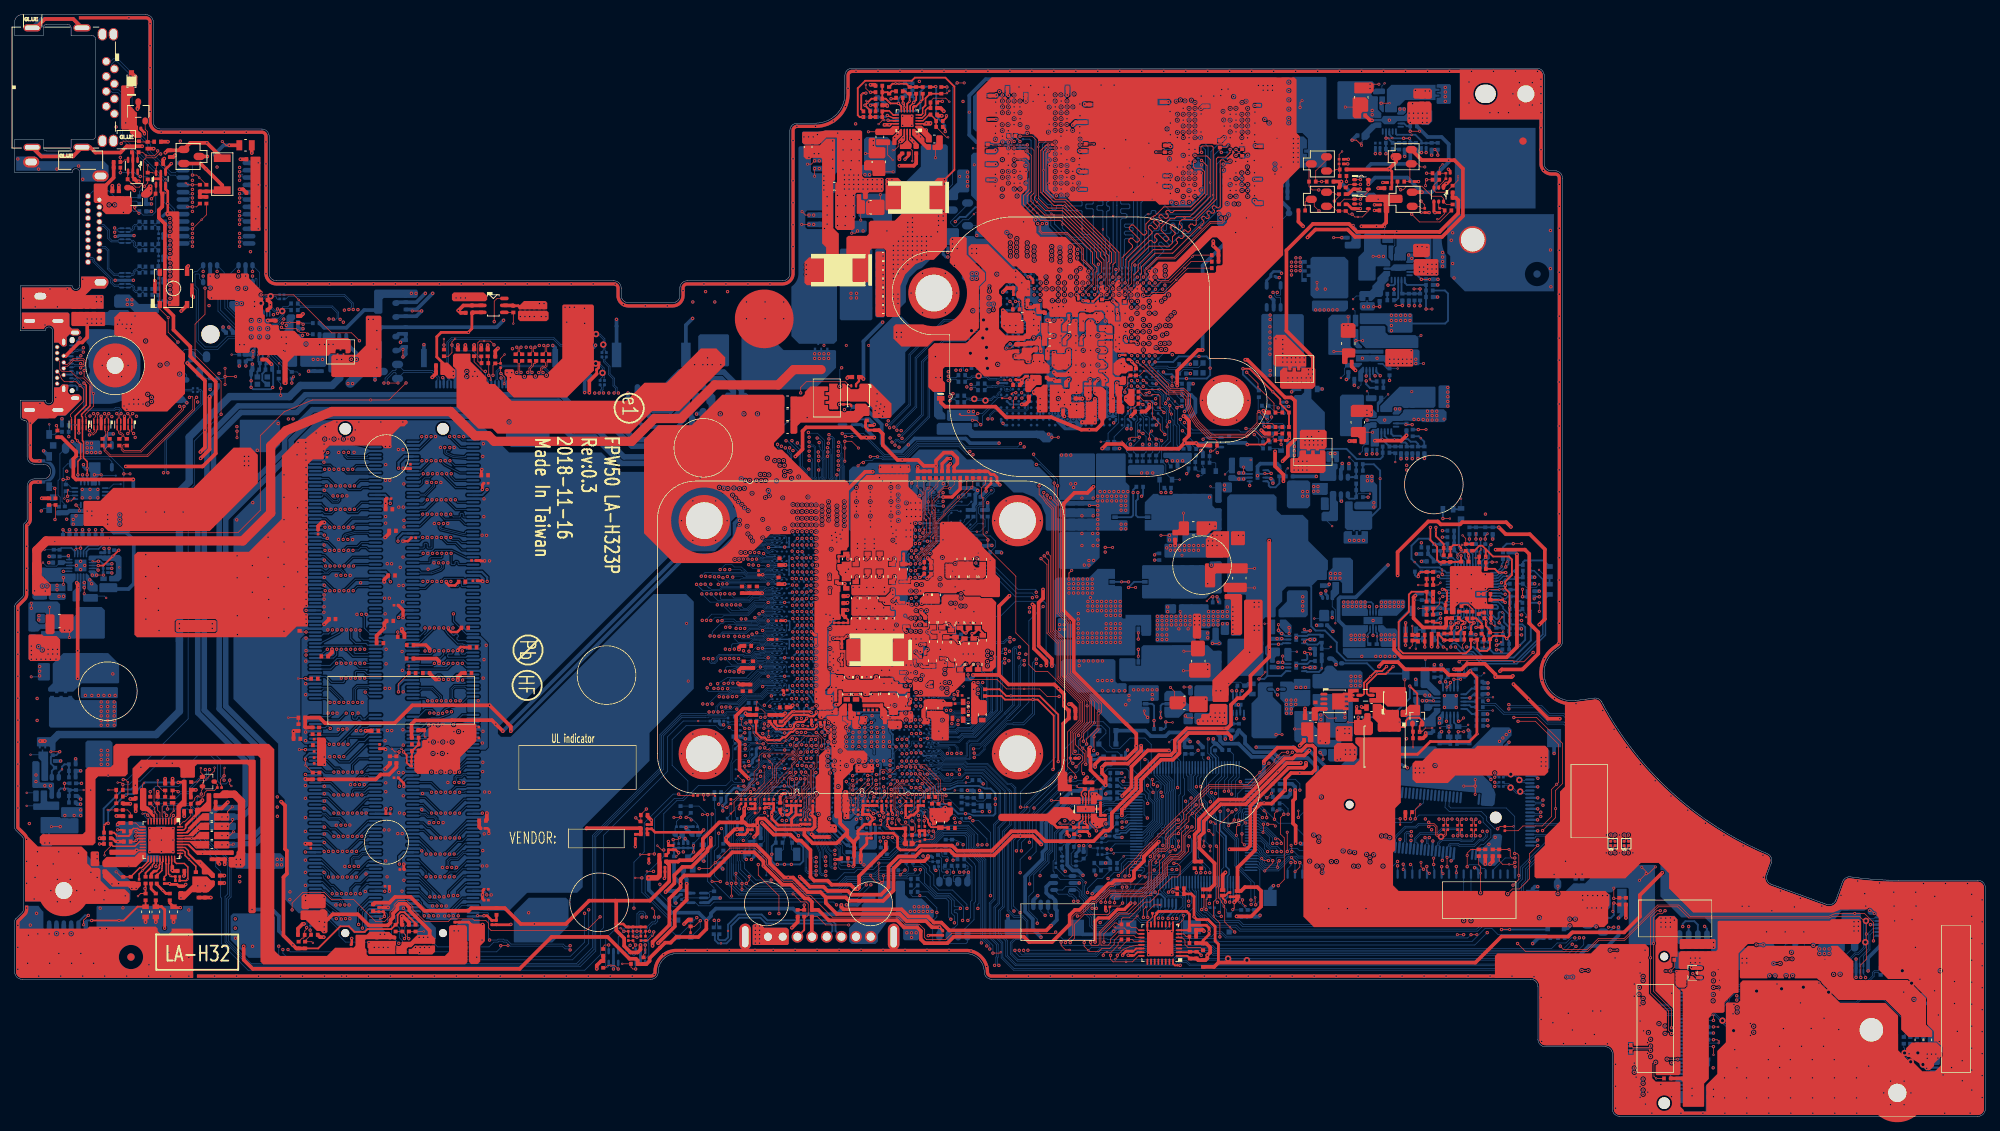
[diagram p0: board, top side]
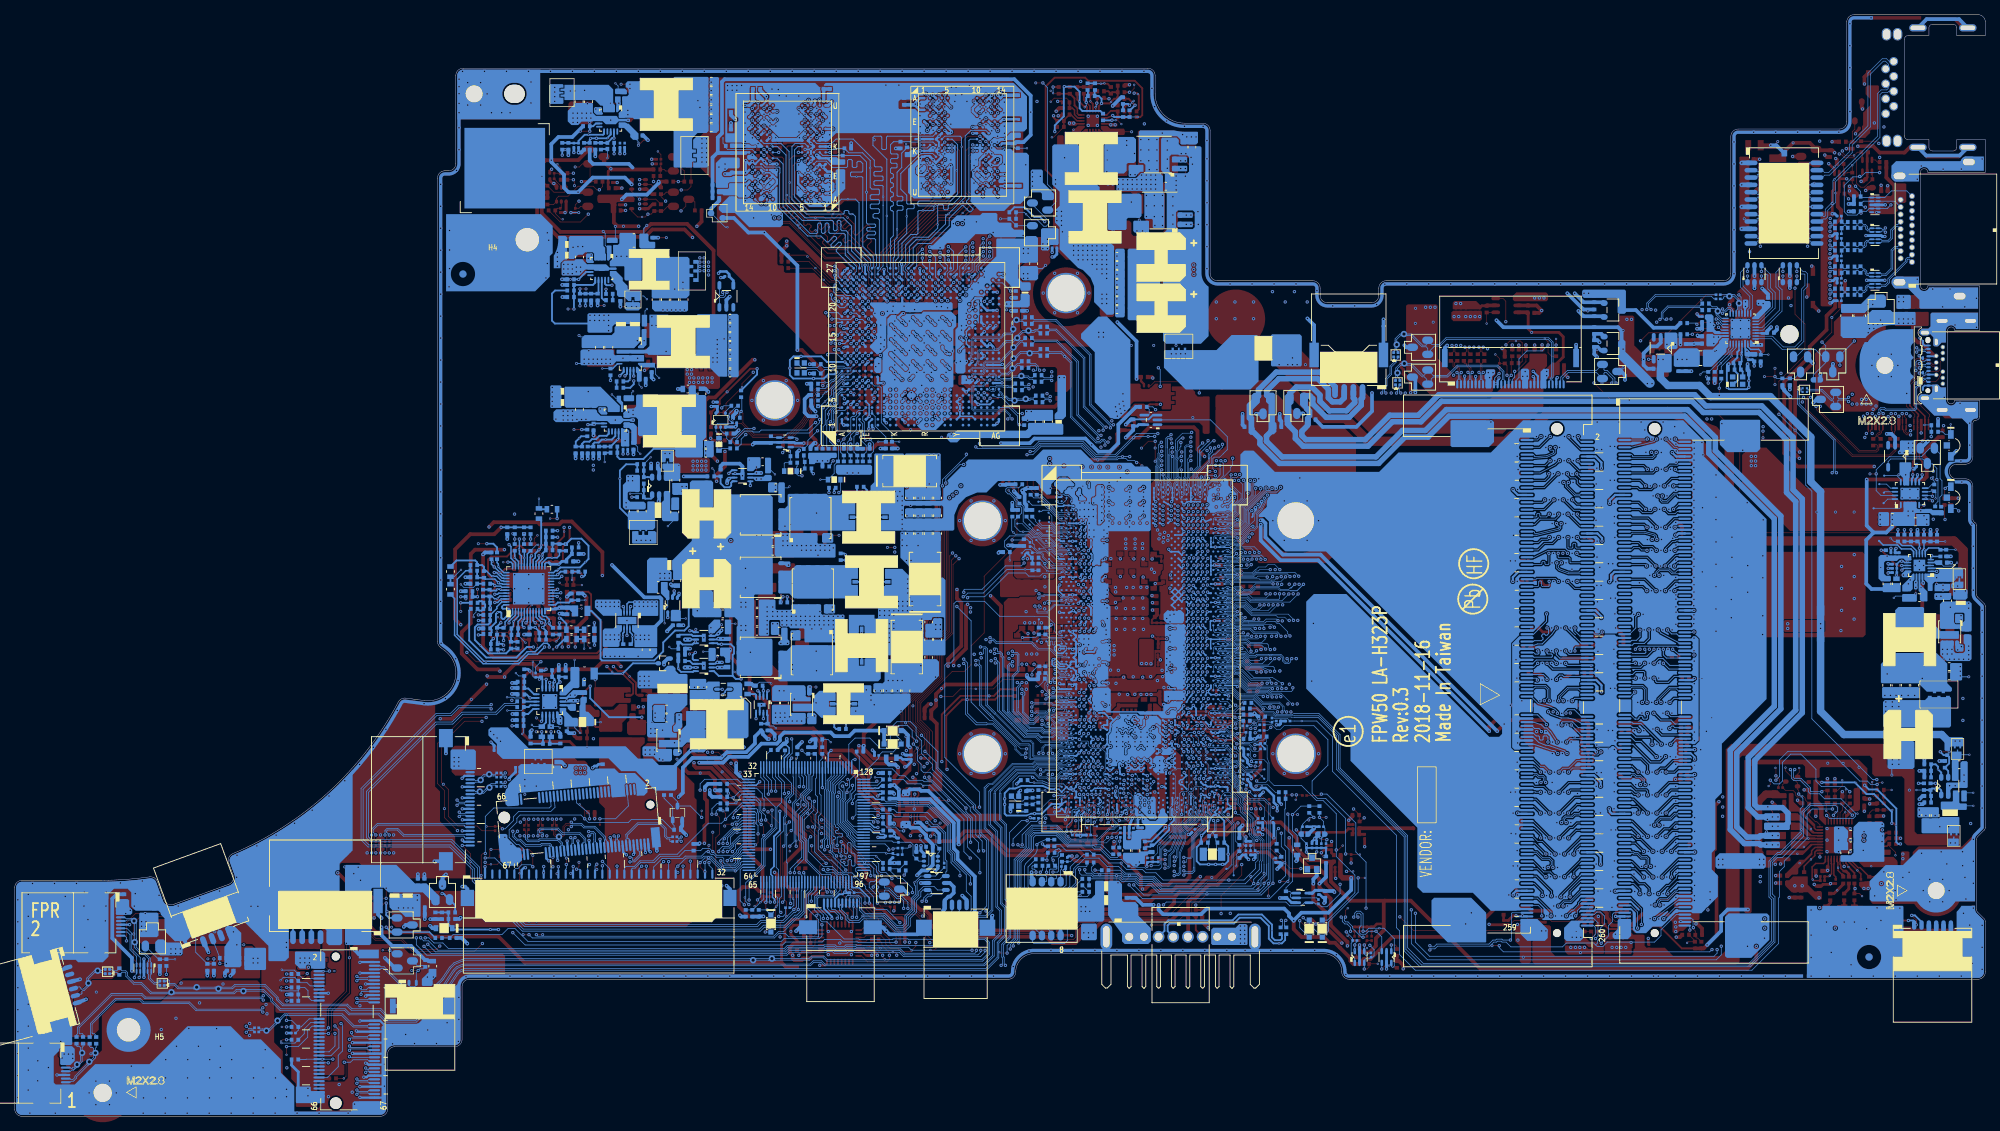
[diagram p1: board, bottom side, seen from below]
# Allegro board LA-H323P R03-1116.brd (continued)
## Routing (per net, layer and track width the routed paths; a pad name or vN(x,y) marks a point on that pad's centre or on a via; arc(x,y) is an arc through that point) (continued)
GND_SENSE_GPU: length 75.1
  TOP w0.102: v1(116.06,140.74) 116.06,140.24 116.58,139.72 v3(116.7,139.72)
  TOP w0.254: PRV18.1 v3(116.7,139.72)
  IN2 w0.254: v3(116.7,139.72) 116.78,139.81 122.55,139.81 124.74,137.61 127.03,137.61 127.88,136.76 127.88,124.44 129.46,122.86 129.46,119.41 129.15,119.1 129.15,117.17 129.95,116.37 131.22,116.37 132.13,115.47 132.13,113.95 131.16,112.99 131.16,109.31 133.53,106.94 135.45,106.94 136.25,106.14 137.9,106.14 138.79,105.25 141.64,105.25 142.21,104.68 142.84,104.68 143.85,103.66 144.68,103.66 145.24,103.1 145.24,102.31 145.51,102.04 145.91,102.04 146.16,101.79 146.16,101.3 146.48,100.99 146.96,100.99 147.24,100.7 147.24,100.31 147.51,100.04 148.01,100.04 149.28,98.78 149.28,97.73 151.33,95.68 151.33,94.73 151.65,94.41 v3(151.65,93.8)
  BOTTOM w0.305: v3(151.65,93.8) 151.65,93.93 151.8,94.08 UV1.F1
GNDA: length 15.4
  TOP w0.102: v3(4.7,24.89) v2(3.16,24.89) ; v3(12.52,25.62) v2(11.64,25.62)
  TOP w0.203: v3(16.53,38.84) 16.69,38.69 UA1.13 ; UA1.31 v3(22.56,35.39)
  TOP w0.381: v3(14.08,37.49) 13.78,37.49 13.32,37.94 RA6.2
  TOP w0.508: CA25.2 v3(19.24,26.51) ; CA24.2 v3(17.85,26.51) ; CA9.2 14.24,40.02 v3(14.06,39.84) ; CA26.2 v3(21.66,26.51) ; v3(14.08,37.49) CA29.1
  BOTTOM w0.508: JHP.8 v3(1.88,24.71) ; JHP.7 v3(12.52,25.62)
  BOTTOM w0.635: JHP.4 6.7,24.93 v3(6.7,24.92) ; v3(4.7,24.89) 4.7,24.89 JHP.6
  vias: v2(13.26,31.7) v3(0.43,26.06) v3(0.43,23.06) v3(0.43,20.06) v3(1.63,28.42) v3(1.77,20.88) v3(2.13,26.09) v3(2.98,27.71) v3(3.28,19.13) v3(4.77,20.88) v3(6.02,22.22) v3(6.28,19.13) v3(7.76,20.88) v3(9.02,22.22) v3(9.28,19.13) v3(10.76,20.88) v3(11.65,28.4) v3(12.27,19.13) v3(14.17,31.75) v3(14.77,28.44) v3(15.27,19.13) v3(15.98,31.09) v3(16.18,25.6) v3(16.65,36.29) v3(16.56,31.09) v3(18.31,20.68) v3(18.27,19.13) v3(21.01,22.36) v3(21.26,19.13) v3(22.67,29.81) v3(23.75,28.15) v3(23.75,24.72) v3(23.75,21.67) v3(23.75,19.13) v3(24.97,31.45) v3(25.98,31.45)
PVCC_NVVDD: length 2.2
  TOP w0.102: v1(122.39,130.32) 122.39,131.8 121.89,132.29 PRV14.1
VCC_1V: length 1.9
  BOTTOM w0.102: PC1008.1 183.75,91.32 183.75,90.74 v1(183.4,90.38)
VCC_5V: length 2.2
  BOTTOM w0.102: PC318.1 181.73,102.46 181.34,102.06 181.34,101.25 v1(180.83,100.74)
VCC_CHG: length 1.9
  BOTTOM w0.102: PRB6.2 v1(192.35,62.28)
VCC_CORE1: length 4.8
  BOTTOM w0.102: PRZ80.2 179.18,63.79 v1(179.45,64.05)
  BOTTOM w0.254: PUZ2.8 176.12,64.55 176.3,64.37 177.64,64.37 177.94,64.67 178.16,64.67 PCZ40.1
  BOTTOM w0.381: PRZ80.2 178.21,64.61 PCZ40.1
VCC_CORE2: length 4.6
  BOTTOM w0.254: PUZ3.8 176.12,60.74 176.22,60.64 177.83,60.64 178.21,61.02 v1(178.21,61.13) PCZ41.1
  BOTTOM w0.508: PRZ81.2 PCZ41.1
VCC_GT: length 5.8
  BOTTOM w0.102: PRG1.2 173.33,88.15 v1(173.59,88.41)
  BOTTOM w0.254: PRG1.2 173.31,87.32 PCG1.1 172.45,86.35 171.92,85.82 171.23,85.82 171,86.05 171,86.44 170.8,86.65 PUG1.8
VCC_SA: length 3.8
  BOTTOM w0.102: PCA1.1 165.73,53.26 165.21,53.26 v1(164.91,52.95)
  BOTTOM w0.254: PRA1.2 PCA1.1 166.04,54.72 166.11,54.79 PUA1.8
VCC_VRAM: length 1.2
  BOTTOM w0.102: PCW9.1 184.02,133.34 183.7,133.03 183.7,132.87 v1(183.62,132.8)
VCCCORE_SENSE: length 111.1
  IN1 w0.127: v3(138.36,69.39) 132.87,69.39 131.85,68.38 129.06,68.38 128.84,68.16 127.49,68.16 126.73,67.39 125.26,67.39 124.55,66.69 124.19,66.69 124.03,66.53 123.21,66.53 v3(122.84,66.15)
  IN2 w0.127: v3(205.47,67.65) 203.94,66.12 203.94,63.17 199.88,59.1 199.88,56.34 199.67,56.13 199.67,51.88 197.69,49.9 191.85,49.9 191.52,49.58 187.65,49.58 184.85,46.78 175.24,46.78 173.73,47.04 173.08,47.31 171.54,48.85 168.65,48.85 166.44,51.06 164.9,51.06 164.57,51.38 164.57,51.71 163.91,52.37 151.93,52.37 141.84,62.46 141.84,64.77 138.79,67.82 138.79,68.98 138.55,69.23 138.53,69.23 v3(138.36,69.39)
  BOTTOM w0.102: v3(122.84,66.15) 122.81,66.16 UC1.AN6
  BOTTOM w0.254: v3(205.47,67.65) PRZ47.1
VCCDPHY_EC_1P24: length 7.6
  BOTTOM w0.229: 110.64,40.82 110.9,41.09 110.9,41.78 UC1.CP25
  BOTTOM w0.254: RC977.1 114.4,36.79 113.85,36.79 CC320.1 113.38,36.99 111.29,39.09 v1(111.29,39.53) 111.29,39.72 110.64,40.37 110.64,40.82
VCCGT_SENSE: length 80.5
  TOP w0.102: v3(148.7,77.62) v2(149.7,77.62)
  IN1 w0.127: v3(148.7,77.62) 148.32,77.24 146.14,77.24 144.52,75.61 133.94,75.61 130.98,78.56 130.98,81.13 127.04,85.07 126.7,85.07 126.69,85.08 v3(126.59,85.08)
  IN2 w0.127: v3(194.67,79.01) 194.52,78.86 191.49,78.86 189.67,77.05 162.34,77.05 161.48,76.18 157.23,76.18 155.98,77.43 148.89,77.43 v3(148.7,77.62)
  BOTTOM w0.102: UC1.E3 124.64,84.3 125.06,84.72 125.49,84.72 125.66,84.89 126.39,84.89 v3(126.59,85.08)
  BOTTOM w0.254: PRZ50.2 v3(194.67,79.01)
VCCSA_SENSE: length 118
  TOP w0.102: v3(207.88,70.06) v2(207.88,68.89)
  IN1 w0.127: v3(122.15,58.74) 123.73,58.74 124.44,58.03 124.44,56.81 126.39,54.87 129.1,54.87 129.95,54.02 131.38,54.02 132.57,55.21 136.15,55.21 139.67,58.73 143.62,58.73 151.77,50.58 151.94,50.58 153.1,49.42 153.98,49.42 154.22,49.66 155.44,49.66 155.68,49.42 157.78,49.42 159.05,48.15 169.34,48.15 169.77,47.72 176.18,47.72 177.08,46.82 183.9,46.82 184.63,46.08 196.01,46.08 202.98,53.06 202.98,62.46 206.61,66.09 206.61,67.66 207.88,68.93 207.88,69.21 207.79,69.31 206.88,69.31 206.75,69.44 206.75,69.91 206.9,70.06 v3(207.88,70.06)
  BOTTOM w0.102: UC1.BG7 122.15,58.48 v3(122.15,58.74)
  BOTTOM w0.254: PRZ15.1 v3(207.88,70.06)
VCCSA_SENSE_R: length 4.3
  BOTTOM w0.102: PRZ1.2 205.79,69.03 205.79,68.79 206.12,68.46 v1(206.12,68.12)
  BOTTOM w0.254: PRZ15.2 205.36,70.28 205,70.28 PRZ8.1 204.55,69.83 204.55,69.47 PCZ5.1 205.02,68.99 205.34,68.99 PRZ1.2
VDD_DDR:
  vias: v1(14.26,74.89)
VDD_SENSE_GPU: length 78.7
  TOP w0.254: PRV24.1 115.43,137.41 115.43,139.34 v1(115.55,139.47) 115.68,139.59 v3(116.06,139.59)
  IN2 w0.254: v3(152.24,93.8) 152.24,94.33 151.69,94.88 151.69,96.86 148.2,100.36 148.2,100.88 147.03,102.04 146.5,102.04 146.16,102.38 146.16,102.82 144.93,104.04 144.51,104.04 144.24,104.31 144.24,104.73 143.94,105.04 142.35,105.04 141.78,105.61 138.94,105.61 138.05,106.5 136.4,106.5 135.57,107.32 133.69,107.32 131.54,109.47 131.54,112.83 132.51,113.8 132.51,115.62 131.38,116.75 130.11,116.75 129.53,117.33 129.53,118.94 129.84,119.26 129.84,123.02 128.33,124.53 128.33,136.93 127.26,137.99 124.9,137.99 122.68,140.22 116.33,140.22 116.06,139.95 v3(116.06,139.59)
  BOTTOM w0.254: UV1.F2 152.24,94.66 v3(152.24,93.8)
VDDP_DDR: length 4.6
  TOP w0.102: v3(11.41,75.73) v1(10.63,75.73)
  BOTTOM w0.203: PUM1.12 11.01,75.55 11.19,75.73 v3(11.41,75.73) 11.67,75.73 PCM21.2 PCM20.2 PCM7.2 12.07,73.39 PRM5.2
VSSCORE_SENSE: length 111.1
  IN1 w0.127: v3(123.47,66.15) 123.96,66.15 124.28,66.47 124.7,66.47 125.33,67.1 126.77,67.1 127.57,67.9 128.95,67.9 129.17,68.12 131.96,68.12 132.95,69.12 137.68,69.12 137.8,69 137.8,68.59 137.92,68.47 138.27,68.47 138.37,68.57 v3(138.37,68.81)
  IN2 w0.127: v3(205.47,65.68) 205.47,65.89 204.98,66.38 204.56,66.38 204.2,66.02 204.2,63.04 200.13,58.98 200.13,56.24 199.92,56.02 199.92,51.77 197.79,49.64 191.95,49.64 191.63,49.32 187.76,49.32 184.96,46.52 175.22,46.52 174.18,46.7 174.18,46.7 173.66,46.79 172.94,47.09 171.43,48.6 168.55,48.6 166.34,50.81 164.79,50.81 164.32,51.28 164.32,51.6 163.81,52.12 151.83,52.12 141.56,62.38 141.56,64.66 138.52,67.71 138.52,68.28 138.43,68.36 138.34,68.36 138.22,68.49 138.22,68.66 138.37,68.81 v3(138.37,68.81)
  BOTTOM w0.102: v3(123.47,66.15) 123.48,66.2 UC1.AN5
  BOTTOM w0.254: PRZ95.1 204.91,65.68 v3(205.47,65.68)
VSSGT_SENSE: length 75.1
  IN1 w0.127: v3(126.59,83.9) 126.62,83.87 127.7,83.87 130.6,80.97 130.6,78.4 133.78,75.23 144.67,75.23 146.3,76.86 148.57,76.86 v3(148.7,76.98)
  IN2 w0.127: v3(148.7,76.98) 148.89,77.17 155.88,77.17 157.12,75.93 161.58,75.93 162.45,76.79 190.34,76.79 v3(191.8,78.25)
  BOTTOM w0.102: v3(126.59,83.9) 126.3,83.61 125.81,83.61 125.27,84.15 UC1.D2
  BOTTOM w0.254: PRZ93.2 v3(191.8,78.25)
VSSSA_SENSE: length 118.2
  TOP w0.102: v2(207.18,70.59) 207.48,70.89 v3(207.88,70.89)
  IN1 w0.127: v3(207.88,70.89) 208.39,70.38 208.39,68.99 207.12,67.72 207.12,66.06 203.23,62.17 203.23,52.9 196.16,45.83 184.53,45.83 183.79,46.57 176.97,46.57 176.07,47.47 169.66,47.47 169.23,47.9 158.95,47.9 157.68,49.17 155.58,49.17 155.34,49.41 154.32,49.41 154.08,49.17 152.99,49.17 152.66,49.5 151.41,49.5 150.91,50 150.91,50.87 143.41,58.36 139.9,58.36 136.49,54.95 132.79,54.95 131.47,53.64 129.79,53.64 128.9,54.53 126.24,54.53 124.05,56.72 124.05,57.94 123.61,58.38 122.41,58.38 122.2,58.17 121.77,58.17 121.51,58.42 v3(121.51,58.75)
  BOTTOM w0.102: v3(121.51,58.75) 121.95,59.19 UC1.BE7
  BOTTOM w0.254: PRZ94.1 v3(207.88,70.89)
+EC_VCCA: length 5.9
  TOP w0.127: v3(166.28,29.2) 166.28,28.4 v2(166.09,28.2)
  TOP w0.356: LK1.2 166.69,29.95 CK3.1
  TOP w0.508: LK1.2 166.73,29.65 v3(166.28,29.2)
  BOTTOM w0.203: UK1.67 166.17,29.32 v3(166.28,29.2)
+FAN1: length 1
  TOP w0.127: v3(238.41,23.4) v2(237.46,23.4)
+FB_VREFC0: length 74
  BOTTOM w0.305: UV6.J14 168.98,131.51 169.06,131.43
  BOTTOM w0.33: 133.32,132.73 134.06,132.73 UV7.J14
  BOTTOM w0.508: RV200.2 RV125.2 RV127.1 173.55,130.81 172.83,131.52 ; 133.32,132.73 132.33,132.73 132.14,132.92 CV159.1 131.9,132.91 131.15,132.91 130.16,133.89 v2(130.16,137) 130.16,139.26 132.4,141.5 171.9,141.5 172.26,141.14 172.26,134.12 172.83,133.54 172.83,131.52 ; 172.83,131.52 172.75,131.43 CV158.1 169.06,131.43
+HDMI_CRT_5V: length 3.8
  TOP w0.508: RG109.1 RG105.1 13.5,128.07 12.3,126.88
  vias: v2(14.83,123.32)
+LAN_REGOUT:
  vias: v1(36.65,104.48)
+LAN_VDD_1V0: length 3.4
  TOP w0.102: v3(32.49,104.38) v2(32.49,103.58)
  BOTTOM w0.203: UL1.3 30.55,106.86 30.5,106.81 ; 29.84,106.81 CL26.1
  BOTTOM w0.381: 30.5,106.81 29.84,106.81
  BOTTOM w0.508: v3(29.21,107.67) 29.74,107.13 CL26.1
  vias: v3(30.29,110.88) v3(30.93,110.88) v3(37.03,107.91) v3(40.71,103.26) v3(41.34,103.26) v3(41.98,103.26)
+LAN_VDD_3V3: length 52.2
  IN1 w0.508: JLAN.A1 14.44,134.04 14.44,136.01 14.79,136.37 14.79,146.3 JLAN.B1
  IN2 w0.508: v3(26.84,111.65) 25.51,111.65 25,112.16 25,112.23 24.51,112.73 24.51,116.53 23.47,117.57 23.47,118.74 22.61,119.59 22.61,122.55 21.32,123.85 20.56,123.85 19.41,122.7 17.51,122.7 17.13,123.08 17.13,124.23 15.44,125.91 15.44,130.77 13.47,132.75 JLAN.A1
  BOTTOM w0.508: RL15.1 v3(41.57,105.29) ; DM12.5 v3(26.65,114.64) ; DM13.5 v3(31.48,114.64) ; RL56.2 v3(36.9,100.03)
  vias: v2(36.86,104.39) v3(30.68,105.28) v3(31.29,105.28) v3(32.71,111.14) v3(32.71,110.5) v3(36.39,106.31) v3(37.02,106.31) v3(37.02,105.42) v3(42.25,105.32) v3(42.83,105.32) v3(43.42,105.32)
+LCDVDD:
  vias: v2(75.28,108.35) v2(77.69,110.24) v2(77.72,108.19) v3(60.18,111.65) v3(60.82,111.65) v3(61.45,111.65) v3(67.13,101.47) v3(67.6,100.78) v3(67.78,101.47) v3(75.04,110.38) v3(75.67,110.38) v3(76.31,110.38)
+RTCVCC: length 45.1
  TOP w0.102: v3(92.57,36.06) v2(92.57,36.94)
  IN1 w0.254: v3(92.57,36.06) 93.46,36.96 93.46,42.05 98.37,46.96 98.37,48.3 98.47,48.4 98.47,51.78 98.37,51.87 98.37,53.79 99.21,54.62 99.21,55.21 99.64,55.64 101.31,55.64 101.45,55.5 103.16,55.5 104.2,56.54 106.52,56.54 106.52,56.55 106.89,56.55 106.94,56.5 107.54,56.5 107.56,56.52 109.42,56.52 109.47,56.47 109.48,56.47 109.9,56.05 109.9,55.58 111.02,54.46 111.62,54.46 112.25,53.84 112.25,53.43 111.84,53.02 v3(111.74,53.02)
  BOTTOM w0.254: DC1.1 v3(92.57,36.06) RC91.1 CC324.2 CC7.2 RC93.1 RC94.1 RC462.2 ; v3(111.74,53.02) 111.8,53.02 UC1.BR23
+V_DAC: length 5.1
  BOTTOM w0.635: TSL1.10 v3(33.21,121.08) ; TSL1.4 v3(33.21,127.08) ; TSL1.7 v3(33.21,124.08) ; TSL1.1 v3(33.21,130.08)
  vias: v2(32.88,122.45)
+VGA_CORE: length 32.1
  TOP w0.254: RV217.1 115.21,136.34 114.96,136.6 114.96,140.27 115.97,141.28 122.32,141.28 122.74,141.7 126.9,141.7 128.13,140.48 128.13,129.13 v3(126.78,127.78)
  vias: v2(118.93,120.8) v3(119.81,118.77) v3(119.81,118.13) v3(119.81,117.5) v3(119.81,116.86) v3(119.81,116.23) v3(119.81,115.59) v3(119.81,114.96) v3(119.81,114.32) v3(119.81,112.16) v3(119.81,111.53) v3(119.81,110.89) v3(120.44,118.77) v3(120.44,118.13) v3(120.44,117.5) v3(120.44,116.86) v3(120.44,116.23) v3(120.44,115.59) v3(120.44,114.96) v3(120.44,112.16) v3(120.44,111.53) v3(120.44,110.89) v3(120.51,119.4) v3(121.14,120.04) v3(121.14,119.4) v3(121.14,118.77) v3(121.14,118.13) v3(121.14,117.5) v3(121.14,116.86) v3(121.14,116.23) v3(121.14,115.59) v3(121.78,121.94) v3(121.78,121.31) v3(121.78,120.67) v3(121.78,120.04) v3(121.78,119.4) v3(121.78,118.77) v3(121.78,118.13) v3(121.78,117.5) v3(121.78,116.86) v3(121.78,116.23) v3(122.41,122.58) v3(122.41,121.94) v3(122.41,121.31) v3(122.41,120.67) v3(122.41,120.04) v3(122.41,119.4) v3(122.41,118.77) v3(122.41,118.13) v3(122.41,117.5) v3(122.41,116.86) v3(123.05,120.04) v3(123.05,119.4) v3(123.05,118.77) v3(123.05,118.13) v3(123.05,117.5) v3(123.05,116.86) v3(123.68,120.04) v3(123.68,119.4) v3(123.68,118.77) v3(123.68,118.13) v3(123.68,117.5) v3(123.68,116.86) v3(124.32,120.04) v3(124.32,119.4) v3(124.32,118.77) v3(124.32,118.13) v3(124.32,117.5) v3(124.44,124.99) v3(124.95,120.04) v3(125.84,120.67) v3(125.97,123.46) v3(125.97,122.83) v3(125.97,122.19) v3(125.97,121.56) v3(126.6,123.46) v3(126.6,122.83) v3(126.6,122.19) v3(126.78,127.2) v3(140.8,108.61) v3(140.83,104.41) v3(141.7,101.5) v3(142.3,98.78) v3(142.3,97.1) v3(142.53,105.53) v3(142.7,108.61) v3(142.67,106.47) v3(143.14,98.78) v3(143.14,97.1) v3(143.7,101.5) v3(143.96,97.1) v3(144.7,108.5) v3(144.7,106.5) v3(144.69,105.51) v3(144.7,104.5) v3(144.7,102.5) v3(144.7,101.5) v3(144.78,98.78) v3(144.8,97.1) v3(144.8,96.3) v3(145.03,99.72) v3(145.7,101.5) v3(146.7,108.5) v3(146.7,106.5) v3(146.7,104.5) v3(146.7,102.5) v3(146.7,101.5) v3(148.7,108.5) v3(148.7,106.5) v3(148.7,104.5) v3(148.7,102.5) v3(148.7,100.5)
A4WP_PRESENT: length 5.7
  TOP w0.076: RC936.1 114.13,42.63 114.13,43.26 113.9,43.49 113.9,45.22 114.14,45.46 114.65,45.46 v1(114.86,45.66) 115.11,45.91 v3(115.42,45.91)
  BOTTOM w0.076: UC1.CF17 115.73,46.64 v3(115.42,45.91)
AC_LED#: length 64.5
  TOP w0.102: PR2.1 PR1.1 218.73,29.74 v3(218.04,29.74) v2(218.04,31.14)
  IN1 w0.127: v3(175.24,44.51) 175.59,44.15 182.79,44.15 183.53,43.42 198.05,43.42 198.37,43.74 203.16,43.74 206.84,40.05 206.84,33.5 208.83,31.52 211.66,31.52 212.44,30.73 217.81,30.73 218.04,30.5 v3(218.04,29.74)
  BOTTOM w0.102: UK1.34 169.77,45.57 170.18,45.98 174.62,45.98 175.24,45.36 v3(175.24,44.51)
AC_PRESENT_R: length 9.8
  IN1 w0.076: v3(99.6,50.13) 99.6,49.8 100.07,49.33 v3(100.07,48.43)
  BOTTOM w0.076: RC106.2 100.53,49.13 100.07,48.68 v3(100.07,48.43) 99.95,48.3 RC108.1 ; UC1.BU35 104.36,51.89 104.26,51.99 104.26,51.99 104.11,52.15 102.68,52.15 102.25,51.72 101.72,51.19 101.72,51.09 101.47,50.84 100.31,50.84 v3(99.6,50.13)
ACDET_CHG: length 5
  BOTTOM w0.102: v1(200.36,60.47) 199.97,60.08 PRB17.2
  BOTTOM w0.254: PUB1.6 197.88,57.59 198.67,58.37 199.21,58.37 PCB22.1 PRB21.1 199.21,60.07 PRB17.2
ACDRV_CHG: length 32.1
  TOP w0.102: v3(196.24,59.62) v2(197.15,59.62)
  TOP w0.381: PRB9.2 182.98,55.36 v3(182.98,55.87)
  IN1 w0.381: v3(196.24,59.62) 197.87,57.98 197.87,56.64 199.54,54.97 199.54,52.49 197.31,50.26 192.85,50.26 187.42,55.68 184.5,55.68 183.94,55.13 183.18,55.13 182.98,55.32 v3(182.98,55.87)
  BOTTOM w0.254: PUB1.4 196.25,59.6 v3(196.24,59.62)
ACDRV_CHG_R: length 15.5
  TOP w0.102: PRB9.1 v1(181.81,53.75)
  TOP w0.254: v3(190.23,58.69) 191.24,57.68 PQB2.1
  TOP w0.381: PRB9.1 v3(183.19,54.45)
  BOTTOM w0.254: v3(183.19,54.45) 187.64,54.45 190.23,57.04 v3(190.23,58.69)
ACIN: length 84
  TOP w0.076: v1(100.03,47) 99.55,47.48 v3(99.55,47.77)
  IN1 w0.076: 98.94,45.82 98.94,45.84 99.3,46.19 99.3,47.5 99.55,47.76 v3(99.55,47.77)
  IN1 w0.127: 98.94,45.82 98.94,45.39 98.03,44.47 98.03,36.09 99.61,34.51 100.56,34.51 101.14,33.93 101.68,33.93 101.96,34.21 101.96,36.66 102.94,37.64 109.68,37.64 110.6,36.72 112.01,36.72 113.66,35.07 116.08,35.07 116.52,34.63 120.94,34.63 121.24,34.33 125.89,34.33 126.48,33.74 130.41,33.74 130.73,33.42 136.32,33.42 136.83,33.93 137.36,33.93 137.53,33.76 139.3,33.76 139.38,33.84 147.8,33.84 148.01,33.64 149.93,33.64 150.07,33.77 153.78,33.77 154.04,33.51 154.87,33.51 155.2,33.18 155.9,33.18 156.39,33.67 v3(157.81,33.67)
  BOTTOM w0.076: v3(99.55,47.77) 99.04,47.77 98.83,47.99 RC108.2
  BOTTOM w0.102: UK1.93 155.76,32.82 155.97,33.03 156.47,33.03 157.11,33.67 v3(157.81,33.67)
ACIN_LED: length 20.6
  TOP w0.102: PR1.2 218.47,28.9 218.26,29.1 v3(218.04,29.1) 217.91,28.98 v2(217.91,27.96)
  IN1 w0.254: v3(218.04,29.1) 227.24,29.1 v3(230.42,25.92)
  BOTTOM w0.254: PD1.2 217.65,27.07 218.04,27.46 v3(218.04,29.1) ; PJP1.8 230.75,25.59 v3(230.42,25.92)
ACN_CHG: length 17.3
  TOP w0.254: PRB1.3 183.77,57.44 183.99,57.66 183.99,59.14 v1(184.86,60.01) 185.59,60.75 186.44,60.75 v3(187.05,61.36)
  IN2 w0.254: v3(194.33,59.24) 193.35,60.22 188.2,60.22 v3(187.05,61.36)
  BOTTOM w0.254: PCB11.1 193.65,59.97 PCB10.2 194.51,59.55 194.33,59.37 v3(194.33,59.24) 194.46,59.24 194.75,58.94 PUB1.1
ACP_CHG: length 17.4
  TOP w0.254: v3(187.94,61.36) v1(187.23,60.65) 186.93,60.35 185.76,60.35 184.37,58.95 184.37,57.7 184.62,57.44 PRB1.2
  IN2 w0.254: v3(195.09,59.29) 193.78,60.6 188.7,60.6 v3(187.94,61.36)
  BOTTOM w0.254: PCB1.1 PCB10.1 195.09,59.64 v3(195.09,59.29) 195.17,59.29 195.25,59.21 PUB1.2
ADP_I: length 34.4
  TOP w0.102: v1(167.81,28.67) 167.41,29.07 v3(167.41,29.53)
  IN1 w0.127: v3(167.41,29.53) 166.44,30.5 160.62,30.5 159.06,28.93 154.1,28.93 153.52,29.52 150.73,29.52 150.35,29.89 148.37,29.89 147.93,30.33 147.66,30.33 147.15,30.84 146.59,30.84 v3(146.29,30.54)
  BOTTOM w0.102: UK1.65 166.97,29.97 v3(167.41,29.53) ; v3(146.29,30.54) 146.29,31.11 147.63,32.46 148.28,32.46 149.39,33.56 PR10.1 148.34,33.78 PRB22.2 148.12,33.65 PCB24.1
ADP_ID: length 55.9
  TOP w0.102: v3(202.73,25.48) v2(203.85,25.48)
  IN1 w0.127: v3(202.73,25.48) 200.37,27.85 165.74,27.85 165.2,28.39 163.55,28.39 v3(162.9,29.04)
  BOTTOM w0.102: UK1.75 162.97,29.11 v3(162.9,29.04)
  BOTTOM w0.254: PC6.1 PC5.1 PR3.2 PR5.1 209.56,26.19 PD3.1 208.85,25.48 v3(202.73,25.48)
ADP_SIGNAL: length 27.4
  TOP w0.102: v2(210.42,31.4) v3(210.42,30.39)
  IN1 w0.254: v3(228.25,25.9) 228.25,25.49 226.78,24.02 216.7,24.02 210.42,30.3 v3(210.42,30.39)
  BOTTOM w0.254: v3(210.42,30.39) 210.22,30.39 PD2.3 208.64,28.81 PR3.1 ; PJP1.6 v3(228.25,25.9)
AISP1: length 10.2
  TOP w0.254: PCG8.1 195.77,76.58 PRG7.1 196.16,77.93 v1(196.85,77.93) 196.88,77.93 197.21,77.6 v3(197.21,77.29)
  BOTTOM w0.203: 197.72,76.78 197.72,76.22 198.01,75.93 PUZ1.29
  BOTTOM w0.254: 197.72,76.78 v3(197.21,77.29) 196.91,77.59 196.91,81.24 PRG9.2
AISP1_R: length 51.5
  TOP w0.102: v3(194.74,81.55) v1(195.69,81.55)
  IN2 w0.203: v3(194.74,81.55) 191.51,81.55 189.96,80 169.93,80 167.01,82.93 157.81,82.93 155.62,85.11 v3(153.14,85.11)
  BOTTOM w0.254: PLG1.2 153.14,81.74 152.89,82 152.89,83.97 153.14,84.22 v3(153.14,85.11) ; v3(194.74,81.55) PRG6.1
AISPCORE1: length 10
  IN1 w0.254: v3(194.42,67.97) 196.07,67.97 196.3,67.74 196.3,67.1 v3(196.71,66.7)
  BOTTOM w0.203: v3(196.71,66.7) 196.32,67.08 v1(196.32,67.18) 196.32,67.63 196.49,67.8 196.79,67.8 197.21,68.21 PUZ1.10
  BOTTOM w0.254: PRZ102.2 193.47,67.2 194.23,67.97 v3(194.42,67.97) ; PRZ88.1 PCZ42.1 196.25,66.24 v3(196.71,66.7)
AISPCORE1_R: length 47.3
  TOP w0.102: v3(151.87,72.16) v2(152.84,72.16)
  TOP w0.254: v3(189.66,67.33) 189.64,67.32 PRZ108.2
  IN2 w0.254: v3(151.87,72.16) 152,72.03 159.24,72.03 160.89,73.68 174.32,73.68 179.47,68.52 180.27,68.52 180.58,68.22 188.77,68.22 v3(189.66,67.33)
  BOTTOM w0.254: PLZ1.2 152.64,72.92 v3(151.87,72.16) ; PRZ85.1 v3(189.66,67.33)
AISPCORE2: length 12.3
  TOP w0.102: v1(195.3,63.71) 194.98,64.03 v3(194.8,64.03)
  TOP w0.254: v3(196.83,67.33) 196.53,67.33 PRZ104.2 195.89,65.96 PCZ43.1 PRZ90.1
  IN1 w0.254: v3(194.8,64.03) 194.8,64.79 195.94,65.93 196.96,65.93 197.21,66.19 197.21,66.95 v3(196.83,67.33)
  BOTTOM w0.203: PUZ1.9 197.61,68.11 v3(196.83,67.33)
  BOTTOM w0.254: PRZ103.2 193.71,65.12 v3(194.8,64.03)
AISPCORE2_R: length 45.4
  TOP w0.102: v3(153.21,63.71) v2(153.21,62.77) ; PRZ109.2 v3(189.64,64.28)
  IN2 w0.254: v3(189.64,64.28) 188.76,63.39 180.61,63.39 179.48,62.27 179.48,60.85 177.83,59.2 171.83,59.2 170.71,60.32 166.51,60.32 163.56,63.27 153.65,63.27 v3(153.21,63.71)
  BOTTOM w0.254: v3(189.64,64.28) 189.66,64.29 PRZ87.1 ; v3(153.21,63.71) PLZ2.2
AISPVCCSA: length 9.7
  BOTTOM w0.203: PUZ1.40 202.04,72.98 202.13,73.07 202.34,73.07 202.95,73.68 v1(203.49,73.68) 203.64,73.68 204.35,74.39 PCA7.1
  BOTTOM w0.254: PRA9.2 208.45,75.84 205.9,75.84 205.65,75.59 PRA7.1 204.96,75.2 204.71,74.95 PCA7.1
AISPVCCSA_R: length 74.4
  TOP w0.102: v3(156.26,54.38) v1(156.26,55.2)
  IN1 w0.203: v3(196.45,64.03) 196.45,64.59 196.25,64.79 195.82,64.79 195.31,64.28 195.31,63.77 194.83,63.29 189.95,63.29 188.78,64.46 179.82,64.46 177.95,62.59 177.95,61.04 177.5,60.59 174.2,60.59 173.68,60.08 171.44,60.08 168.26,56.9 168.26,54 167.61,53.35 165.3,53.35 165.11,53.16 157.79,53.16 157.59,53.36 157.59,53.87 157.15,54.31 156.32,54.31 v3(156.26,54.38)
  BOTTOM w0.203: v3(196.45,64.03) 197.42,63.06 198.68,63.06 199.99,61.75 204.83,61.75 208.72,65.64 208.72,70.64 PRA6.1
  BOTTOM w0.254: PLA1.2 156.51,56.28 156.26,56.03 v3(156.26,54.38)
AVCORE1: length 61.1
  TOP w0.102: v3(151.87,72.92) v2(150.92,72.92)
  IN2 w0.254: v3(151.87,72.92) 152.38,72.41 158.99,72.41 160.64,74.06 174.48,74.06 179.63,68.9 180.43,68.9 180.73,68.6 191.37,68.6 192.39,69.62 195.69,69.62 196.32,68.98 196.32,67.08 196.09,66.84 196.09,66.48 196.46,66.11 197.13,66.11 v3(197.72,66.7)
  BOTTOM w0.203: PCZ13.2 198.48,66.9 198.41,66.97 PUZ1.7
  BOTTOM w0.254: PCZ13.2 198.43,66.7 v3(197.72,66.7) 197.16,66.14 PCZ42.2 PRZ88.2 ; v3(151.87,72.92) PLZ1.3
AVCORE2: length 53.6
  TOP w0.102: v3(153.21,65.11) v2(153.21,65.96)
  TOP w0.254: PRZ106.1 PCZ43.2 PRZ90.2 194.12,65.78 ; 194.12,65.78 PCZ16.2 ; 194.12,65.78 194.04,65.7 v3(194.04,64.03)
  IN2 w0.254: v3(153.21,65.11) 153.21,64.6 154.16,63.65 163.72,63.65 166.66,60.7 170.87,60.7 171.98,59.58 177.67,59.58 179.09,61.01 179.09,62.42 180.45,63.77 188.45,63.77 189.47,64.79 193.2,64.79 193.96,64.03 v3(194.04,64.03)
  BOTTOM w0.254: PLZ2.3 v3(153.21,65.11)
AVGT1: length 60.9
  TOP w0.254: v3(197.21,76.47) PCZ18.1 196.67,75.66 196.64,75.64 PCG8.2 PRG8.2 194.24,75.64 193.95,75.93 193.95,77.71 v1(193.58,78.07) 193.04,78.62 v3(193.04,80.35)
  IN2 w0.203: v3(193.04,80.35) 191.3,80.35 190.29,79.34 169.52,79.34 166.88,81.99 157.67,81.99 155.56,84.09 153.02,84.09 152.51,84.6 v3(152.51,85.11)
  BOTTOM w0.203: PUZ1.28 197.61,75.7 197.21,76.09 v3(197.21,76.47)
  BOTTOM w0.254: PHG1.2 152.51,85.45 v3(152.51,85.11) 152.51,82 152.26,81.74 PLG1.3
AVGT1_R: length 48.4
  TOP w0.254: PRG8.1 PRG7.2 194.85,78.07 193.78,79.14 v1(193.78,79.79) v3(193.78,80.35)
  IN2 w0.203: v3(153.65,84.6) 155.59,84.6 157.83,82.37 167.03,82.37 169.73,79.67 190.1,79.67 191.23,80.8 193.33,80.8 v3(193.78,80.35)
  BOTTOM w0.254: PHG1.1 153.86,84.81 v3(153.65,84.6)
B/I#: length 74.9
  TOP w0.102: v3(169.21,28.86) 169.15,28.92 v1(169.15,29.87)
  TOP w0.254: v3(107.65,28.83) PR17.2 PR16.2
  IN1 w0.127: v3(169.21,28.86) 168.8,28.46 167.76,28.46 166.38,29.84 161.8,29.84 160.13,28.17 150.86,28.17 149.8,27.11 146.23,27.11 144.98,28.35 144.05,28.35 143.79,28.62 138.94,28.62 138.11,29.45 137.54,29.45 137.29,29.7 134.58,29.7 133.9,29.01 132.11,29.01 131.8,29.33 125.5,29.33 125.04,29.78 118.26,29.78 117.54,29.06 114.21,29.06 113.62,29.65 111.96,29.65 111.82,29.52 108.86,29.52 108.17,28.83 v3(107.65,28.83)
  BOTTOM w0.102: UK1.63 169.46,33.97 169.78,33.65 169.78,29.43 v3(169.21,28.86)
B/I#_R: length 7.9
  TOP w0.102: v2(106.13,30.35) 107.22,29.26 107.91,29.26 108.2,28.96 108.2,27.43 108.02,27.25 PR17.1
  TOP w0.254: PJPB1.6 107.65,25.43 PR17.1
BAT_CHG_LED: length 65.2
  TOP w0.102: v2(159.34,27.43) 159.34,26.84 v3(158.63,26.13)
  IN2 w0.127: v3(158.44,26.99) 158.63,26.8 v3(158.63,26.13)
  BOTTOM w0.102: v3(158.44,26.99) 158.44,27.49 159.44,28.49 159.44,29.85 159.14,30.15 157.19,30.15 156.69,30.66 156.69,30.88 156.97,31.16 UK1.90 ; v3(158.63,26.13) 158.62,26.12 158.62,24.61 158.96,24.26 163.78,24.26 164.17,23.87 198.73,23.87 200.49,25.64 201.42,25.64 202.26,24.8 208.92,24.8 PR6.1 PR4.1
BATDRV_CHG: length 30.2
  TOP w0.102: v3(196.87,53.91) 197.11,53.91 v2(197.56,54.35)
  TOP w0.508: PRB5.1 v3(175.94,55.65)
  IN1 w0.508: v3(196.87,53.91) 197.49,53.28 197.49,52.14 196.69,51.34 194.22,51.34 192.46,53.11 191.84,53.11 187.5,57.45 179.68,57.45 177.77,55.54 176.04,55.54 v3(175.94,55.65)
  BOTTOM w0.254: PUB1.11 196.75,54.02 v3(196.87,53.91)
BATDRV_CHG_R: length 2.6
  TOP w0.102: v1(180.11,54.33) 179.08,54.33 178.51,54.9 PQB13.4
BKL_PWM_CPU: length 4.8
  TOP w0.076: v1(119.66,45.91) 120.19,45.91 v3(120.35,45.74) 120.35,45.63 119.88,45.16 119.88,44.46 119.62,44.2 119.38,44.2 119.05,43.86 119.05,43.49 118.85,43.3 R259.1
  BOTTOM w0.076: UC1.CH11 120.01,45.41 v3(120.35,45.74)
BOARD_ID: length 5.4
  BOTTOM w0.102: UK1.66 166.57,29.65 v1(167.01,29.2) 168.05,28.16 RK2.1 RK4.2
BST1_NVVDD:
  vias: v1(124.33,134.6)
BST1_NVVDD-R: length 1.4
  TOP w0.102: PCV14.1 v2(125.55,130.78)
BST2_NVVDD: length 1.6
  TOP w0.102: PRV20.1 v2(116.4,134.32)
BST2_NVVDD-R: length 2.7
  TOP w0.102: v1(119.73,130.47) 119.03,131.17 PCV24.2
BST_1V: length 1.2
  BOTTOM w0.102: v1(187.27,98.5) 186.74,97.96 PR1006.1
BST_1V_R: length 1
  BOTTOM w0.102: v1(184.39,98.93) 184.57,98.75 PC1007.1
BST_3V: length 2.7
  BOTTOM w0.102: v2(188.45,120.73) 188.18,120.47 188.18,118.84 187.87,118.52 PR302.1 187.64,118.52
BST_3V_R: length 2
  BOTTOM w0.102: PC302.1 v2(186.8,121.42)
BST_5V: length 0.9
  TOP w0.102: v2(183.8,105.82) v3(182.88,105.82)
BST_5V_R: length 1.3
  BOTTOM w0.102: v1(182.49,110.14) 182.76,109.88 PC313.1
BST_DDR:
  vias: v1(8.76,72.13)
BST_DDR_R: length 1.7
  BOTTOM w0.102: v1(12.48,70.73) 12.24,70.97 PCM4.1
BST_VRAM: length 1.2
  TOP w0.102: v3(186.32,138.22) v1(187.47,138.22)
BST_VRAM_R: length 1.3
  BOTTOM w0.102: v1(186.79,140.94) 186.42,140.57 186.42,139.75
BT_ON_EC: length 105.5
  TOP w0.102: v3(225.31,7.8) v2(226.76,7.8)
  IN1 w0.127: v3(154.44,40.7) 154.61,40.86 159.42,40.86 159.6,40.69 161.03,40.69 161.04,40.67 163.27,40.67 164.28,39.66 164.94,39.66 168.1,36.5 168.1,34.79 170.05,32.83 172.53,32.83 173,32.37 175.88,32.37 176.06,32.19 203.09,32.19 203.37,32.47 204.99,32.47 206.17,31.29 206.17,27.91 207.59,26.48 208.85,26.48 211.64,23.69 211.64,22.98 212.73,21.89 216.48,21.89 218.21,20.16 222.51,20.16 223.97,18.7 223.97,16.06 226.83,13.2 226.83,8.34 226.29,7.8 v3(225.31,7.8)
  BOTTOM w0.102: RN15.2 228.99,7.76 228.95,7.8 JWLAN.46 v3(225.31,7.8) ; UK1.121 153.78,43.17 153.99,42.96 153.99,41.15 v3(154.44,40.7)
CAP_LOCK#: length 52.8
  TOP w0.102: R203.1 199.63,34.35 199.88,34.09 v1(199.88,33.17) v3(199.88,30.5)
  IN1 w0.127: v3(199.88,30.5) 199.46,30.92 176.89,30.92 176.2,30.22 170.43,30.22 166.16,34.49 165.43,35.22 160.46,35.22 159.66,34.42 159.2,34.42 v3(158.45,33.68)
  BOTTOM w0.102: UK1.91 156.57,32.8 156.99,33.23 158.01,33.23 v3(158.45,33.68)
CAP_LOCK#_R: length 8
  TOP w0.102: CC122.1 R203.2 198.56,36.42 198.05,35.91 v2(198.05,35.59) v3(198.05,34.06)
  BOTTOM w0.102: JKB.5 200.57,33.66 200.43,33.8 200.08,33.8 199.56,34.32 198.32,34.32 v3(198.05,34.06)
CATERR#: length 9.1
  BOTTOM w0.076: UC1.AA4 124.28,74.52 125.09,74.52 125.46,74.89 127.2,74.89 128.6,76.29 128.6,76.6 128.77,76.78 129.31,76.78 129.42,76.89 129.68,76.89
  BOTTOM w0.102: 129.68,76.89 RC935.1 129.96,77.06 130.21,77.31 130.91,77.31 v1(131.38,76.84)
CBN: length 3.7
  TOP w0.203: UA1.28 21.01,34.49 20.97,34.45 20.97,33.09 v1(21.21,32.84) 21.33,32.72 CA16.2
  TOP w0.254: CA16.2 CA48.2
CBP: length 5.9
  TOP w0.203: CA48.1 23.38,32.15 v1(23.53,32.3) 23.62,32.39 23.62,34.01 23.14,34.5 22.06,34.5 21.81,34.75 UA1.30
  TOP w0.254: CA16.1 CA48.1
CC1: length 17.5
  TOP w0.203: v3(8.62,87.52) 8.62,89.36 9,89.75 9,91.74 v2(8.58,92.16) 8.25,92.49 D33.7 D33.4 8.25,95.53 9.76,97.05 9.76,99.73 v3(9.45,100.04)
  BOTTOM w0.089: v3(9.45,100.04) 8.45,101.04 8.31,101.04 8.21,101.14 8.21,101.39 7.9,101.7 JTC1.A5
  BOTTOM w0.254: v3(8.62,87.52) 8.62,87.21 9.03,86.8 UU1.11
CC2: length 20.7
  TOP w0.089: JTC1.B5 6.16,102.94 6.16,101.93 6.35,101.69 6.5,101.59 7.69,101.59 8.56,100.73 9.32,100.73 10.27,99.79 10.27,99.59
  TOP w0.203: v3(9.89,87.52) v2(9.89,88.42) 9.89,89.34 9.38,89.85 9.38,92.06 9.25,92.19 D33.8 D33.2 9.25,95.39 9.12,95.52 9.12,95.77 10.27,96.92 10.27,99.59
  BOTTOM w0.254: UU1.13 10.03,87.01 9.89,87.14 v3(9.89,87.52)
CFG0: length 18.8
  BOTTOM w0.076: 129.68,79.15 129.22,79.15 128.2,78.12 127.37,78.12 126.97,77.72 126.67,77.72 126.32,77.37 125.25,77.37 125.12,77.5 124.57,77.5 UC1.T4
  BOTTOM w0.102: 129.68,79.15 129.78,79.15 130.39,79.76 v1(131.19,79.76) 131.61,79.76 132.32,80.47 132.32,81.39 131.89,81.81 RC480.1 131.42,82.3 131.42,83.04 131.54,83.17 132.06,83.17 132.17,83.27 132.17,83.86 132.41,84.1 132.41,84.28 133.04,84.92 133.26,84.92 133.56,85.22 133.56,85.57 133.37,85.76 131.78,85.76 RC1157.2
CFG1: length 11.8
  TOP w0.076: v3(123.69,77.4) 123.99,77.4 124.88,78.29 124.88,79.15 125.22,79.5 125.22,82.25 v1(125.09,82.38) 124.96,82.51 124.96,85.05 125.88,85.96 125.88,86.52 126.27,86.91
  TOP w0.102: RC481.1 126.27,86.91
  BOTTOM w0.076: UC1.R4 123.99,77.71 v3(123.69,77.4)
CFG2: length 10.9
  BOTTOM w0.076: 129.68,78.92 129.55,78.92 129.53,78.95 129.26,78.95 128.12,77.82 127.3,77.82 126.69,77.2 125.18,77.2 125.14,77.24 UC1.T3
  BOTTOM w0.102: RC486.2 132.75,81.74 132.75,79.89 v1(132.53,79.66) 132.28,79.42 130.42,79.42 129.93,78.92 129.68,78.92
CFG3: length 13.1
  BOTTOM w0.076: 129.68,79.69 129.5,79.51 129.07,79.51 128.63,79.08 127.63,79.08 126.76,78.21 126.42,78.21 126.41,78.19 125.28,78.19 124.89,77.81 UC1.R3
  BOTTOM w0.102: 129.68,79.69 130.25,80.26 130.31,80.26 131.19,81.14 131.19,83.24 131.55,83.6 RC482.1 131.71,83.73 132.17,84.18 132.17,84.36 133.17,85.37 v1(133.17,85.41)
CFG4: length 7.1
  BOTTOM w0.076: 127.15,83.18 126.35,82.38 125.83,82.38 125.81,82.41 124.2,82.41 123.99,82.2 UC1.J4
  BOTTOM w0.102: 127.15,83.18 128.77,84.8 RC193.1
CFG5: length 7.5
  BOTTOM w0.076: UC1.M4 124.57,79.69 124.82,79.43 125.12,79.43 125.34,79.65 126.88,79.65 127.37,80.14 128.77,80.14 129.28,80.65 129.64,80.65 129.68,80.7
  BOTTOM w0.102: 129.68,80.7 130.73,81.74 RC487.2
CFG6: length 6.9
  BOTTOM w0.076: UC1.J3 124.95,81.87 125.12,81.87 125.12,81.88 125.18,81.88 125.37,82.07 126.27,82.07 127.22,83.02 127.24,83.02 127.71,83.49 127.78,83.49
  BOTTOM w0.102: RC488.2 129.74,84.37 128.66,84.37 127.78,83.49
CFG7: length 6
  BOTTOM w0.076: 129.51,81.37 129.51,81.17 128.67,80.33 127.32,80.33 126.82,79.83 125.11,79.83 UC1.M3
  BOTTOM w0.102: 129.51,81.37 RC489.2
CFG8: length 3.3
  BOTTOM w0.076: UC1.R2 125.54,77.56 125.79,77.56 125.8,77.55 126.09,77.55 126.1,77.56 126.24,77.56 126.56,77.88 126.9,77.88 127.32,78.3 127.82,78.3 T365.1
CFG9: length 3
  BOTTOM w0.076: UC1.N2 125.47,79.12 125.84,79.49 126.95,79.49 127.28,79.83 T366.1
CFG10: length 7.3
  BOTTOM w0.076: UC1.R1 126.25,77.81 126.49,78.05 126.83,78.05 127.63,78.85 128.69,78.85 129.18,79.34 129.64,79.34 130.3,80 130.46,80 131.33,80.87 T367.1
CFG11: length 3.6
  BOTTOM w0.076: UC1.N1 126.09,79.12 126.28,79.31 127.19,79.31 127.28,79.41 128.5,79.41 129.08,79.99 T368.1
CFG12: length 4.8
  BOTTOM w0.076: UC1.J2 125.37,81.56 125.69,81.88 126.31,81.88 127.29,82.85 127.3,82.85 127.64,83.19 127.78,83.19
  BOTTOM w0.102: 127.78,83.19 127.8,83.19 128.47,83.85 T369.1
CFG13: length 3.9
  BOTTOM w0.076: UC1.L2 125.46,80.25 125.71,80.5 126.01,80.5 126.13,80.5 126.22,80.41 126.7,80.41 127.27,80.98 127.27,81.89 T370.1
CFG14: length 5.5
  BOTTOM w0.076: UC1.J1 126.23,81.56 127.36,82.69 127.37,82.69 127.65,82.96 127.78,82.96
  BOTTOM w0.102: 127.78,82.96 127.9,82.96 128.32,83.38 129.97,83.38 T371.1
CFG15: length 2.1
  BOTTOM w0.076: T372.1 127.48,80.86 127.39,80.86 126.77,80.25 UC1.L1
CFG16: length 5.1
  BOTTOM w0.076: T323.1 128.96,80.97 128.62,80.63 127.38,80.63 126.75,79.99 125.15,79.99 125,80.14 125,80.16 124.9,80.25 UC1.L3
CFG17: length 6.3
  BOTTOM w0.076: UC1.L4 123.99,80.31 124.23,80.55 124.72,80.55 124.8,80.63 125.08,80.63 125.24,80.79 125.24,81.02 125.24,81.02 125.24,81.05 125.43,81.24 126.16,81.24 127.62,82.7 127.78,82.7
  BOTTOM w0.102: T324.1 128.66,82.54 128.51,82.7 127.78,82.7
CFG18: length 6.7
  BOTTOM w0.076: T325.1 129.92,80.33 129.92,80.23 129.36,79.67 129,79.67 128.57,79.24 127.35,79.24 127.25,79.15 126.37,79.15 126.06,78.83 125.18,78.83 124.89,79.12 UC1.N3
CFG19: length 1.1
  TOP w0.076: T326.1 124.04,79.78 v3(123.85,79.59)
  BOTTOM w0.076: UC1.N4 123.99,79.44 v3(123.85,79.59)
CFG_RCOMP: length 1.9
  TOP w0.076: v1(123.07,73.97) 123.07,73.82 123.38,73.51 v3(123.4,73.51)
  TOP w0.254: v3(123.4,73.51) 123.52,73.51 RC185.1
  BOTTOM w0.254: UC1.AB5 v3(123.4,73.51)
CHARGE_LED: length 23.6
  TOP w0.102: v3(218.04,25.8) v2(217.31,25.8)
  IN1 w0.254: v3(218.04,25.8) 218.04,24.87 218.45,24.47 226.02,24.47 v3(227.44,25.89)
  BOTTOM w0.203: v3(218.04,25.8) 217.38,25.14 PD1.3 212.15,25.14 PR4.2
  BOTTOM w0.254: v3(227.44,25.89) 227.44,26.26 227.81,26.63 229.01,26.63 229.5,26.14 PJP1.7
CHG: length 0.8
  TOP w0.102: v3(171.99,52.08) v2(172.8,52.08)
CHG_N001: length 1.4
  BOTTOM w0.102: PDB2.1 v1(188.79,53.78)
CHG_N002: length 3.2
  TOP w0.102: PRB2.2 v1(190.66,50.36)
  TOP w0.254: PRB2.2 PRB3.1 190.59,52.54 PQB2.2
CHG_N003: length 9.3
  BOTTOM w0.254: PDB1.1 184.39,61.81 v1(185.79,60.4) PRB6.1
CL_CK_R: length 4.1
  TOP w0.076: T327.1 120.33,43.56 120.33,44.12 120.52,44.31 120.52,44.86 120.85,45.19 121.91,45.19 v3(122.25,44.85)
  BOTTOM w0.076: v3(122.25,44.85) 122.29,44.88 122.29,45.01 UC1.CH7
CL_DATA_R: length 7.9
  TOP w0.076: v3(121.65,45.76) 121.29,45.4 120.77,45.4 120.3,44.93 120.3,44.34 120.05,44.08 120.05,42.03 120.54,41.54 120.54,40.93 120.13,40.52 120.13,40.07 120.14,40.06 T328.1
  BOTTOM w0.076: UC1.CH8 121.3,45.41 v3(121.65,45.76)
CL_RST_N_R: length 6
  TOP w0.076: v3(121.07,45.76) 120.9,45.76 120.1,44.97 120.1,44.38 119.88,44.16 119.88,41.89 120.21,41.56 T329.1
  BOTTOM w0.076: UC1.CH9 v3(121.07,45.76)
CLK_PCI0: length 15.1
  TOP w0.076: v3(99.44,45.04) v1(98.64,45.04)
  IN2 w0.076: v3(99.44,45.04) 99.72,45.32 99.72,45.9 99.7,45.91 99.7,46.27 99.93,46.5 100.22,46.5 101.3,47.58 101.3,47.82 102.05,48.57 102.64,48.57 102.85,48.79 v3(102.85,49.17)
  BOTTOM w0.076: UC1.BV32 106.31,50.84 106.19,50.73 106.19,50.59 105.91,50.3 105.15,50.3 105.12,50.33 104.77,50.33 104.76,50.33 103.87,50.33 103.57,50.2 103.46,50.13 102.98,49.65 102.98,49.5 102.85,49.37 v3(102.85,49.17) ; v3(99.44,45.04) 99.25,45.23 97.84,45.23 96.82,44.22 RC457.1
CLK_PCI_LPC: length 100.3
  IN2 w0.127: v3(148,26.44) 147.98,26.46 146.37,26.46 145.09,27.74 144.62,27.74 141.07,31.29 139.85,31.29 138.9,32.24 137.83,32.24 137.61,32.02 136.64,32.02 136.44,32.23 132.12,32.23 131.68,31.79 127.25,31.79 126.49,32.54 121.1,32.54 120.85,32.29 117.93,32.29 117.59,31.95 117.1,31.95 v3(116.74,31.59)
  BOTTOM w0.102: v3(148,26.44) 149.78,28.21 151.24,28.21 151.62,28.6 151.62,30 152.67,31.05 152.67,31.37 154.52,33.22 155.59,33.22 157.34,34.97 157.64,34.97 159.14,36.46 159.14,39 159.01,39.12 159.01,39.85 159.08,39.91 159.08,40.95 158.75,41.28 158.75,43.79 158.97,44.01 UK1.12 158.97,48.44 158.59,48.81 RK109.2 ; v3(116.74,31.59) 116.74,31.51 114.95,29.72 97.57,29.72 94.94,32.34 94.94,36.43 95.51,37 95.51,41.9 95.41,42.01 CC256.1 RC457.2
CLK_PCIE_N1: length 141.1
  IN2 w0.076: 130.29,74.09 130.29,69.7 128.14,67.55 128.14,67.18 127.49,66.53 127.49,60.69 127.36,60.56 127.27,60.56 127.19,60.64 127.19,60.8 127.24,60.84 127.24,60.99 127.16,61.07 126.91,61.07 126.84,60.99 v3(126.84,60.98)
  IN2 w0.127: 130.29,74.09 130.32,74.13 130.38,74.13 130.77,74.52 130.77,74.52 130.77,74.57 131.62,75.43 131.62,76.25 130.5,77.37 130.5,86.38 131.05,86.92 131.05,87.97 114.56,104.45 106.45,104.45 105.58,105.32 80.64,105.32 79,106.96 68.57,106.96 67.55,105.94 54.85,105.94 53.83,104.92 46.37,104.92 44.08,107.21 43.25,107.21 40.56,109.9 37.7,109.9 37.7,109.89 36.26,109.89 35.93,109.56 v3(35.84,109.56)
  BOTTOM w0.076: UC1.BC1 125.67,60.72 125.58,60.63 125.58,60.52 125.65,60.45 126.09,60.45 126.41,60.77 126.76,60.77 126.84,60.84 v3(126.84,60.98)
  BOTTOM w0.102: UL1.16 34.78,109.82 34.69,109.92 34.69,110 34.79,110.1 35.06,110.1 35.42,109.75 35.65,109.75 v3(35.84,109.56)
CLK_PCIE_N2: length 176.8
  TOP w0.102: C5185.1 220.72,9.19 222.87,9.19 v3(223.06,9.01)
  IN2 w0.127: v3(127.45,59.19) 127.62,59.02 127.85,59.02 129.8,60.98 141.96,60.98 151.51,51.43 155.02,51.43 155.47,50.99 157.69,50.99 159.42,49.26 161.73,49.26 162.02,49.55 166.16,49.55 169.43,46.27 171.93,45.24 185.57,45.24 186.6,46.27 196.22,46.27 203.23,53.28 206.62,53.28 206.95,53.61 212.09,53.61 236.3,29.4 236.3,22.64 237,21.94 237,17.93 238.97,15.96 238.97,11.4 235.52,7.94 227.66,7.94 226.44,9.17 223.22,9.17 v3(223.06,9.01)
  BOTTOM w0.076: UC1.BD3 124.93,60.19 124.93,60.3 125.04,60.4 125.15,60.4 125.31,60.24 125.31,60.15 125.39,60.08
  BOTTOM w0.102: 125.39,60.08 126.15,60.08 126.33,59.9 127.02,59.9 127.25,59.67 127.25,59.33 127.39,59.19 v3(127.45,59.19) ; JWLAN.41 220.43,9.05 220.57,9.19 222.87,9.19 v3(223.06,9.01)
CLK_PCIE_N3: length 97.2
  IN2 w0.127: v3(200.14,38.9) 200.52,39.28 200.52,41.42 197.97,43.96 187.78,43.96 186.67,42.86 184.1,42.86 182.65,41.4 177.06,41.4 176,42.46 172.23,42.46 172.08,42.62 169.53,42.62 167.83,44.32 167.25,44.32 164.76,46.81 157.6,46.81 156.65,47.76 153.58,47.76 152.89,48.45 152.15,48.45 151.99,48.61 151.05,48.61 144.75,54.91 143.64,54.91 139.92,58.63 133.6,58.63 131.98,57.02 131.06,57.02 130.45,57.63 129.96,57.63 129.22,58.38 129.21,58.38 128.33,58.38 127.77,57.82 v3(127.11,57.82)
  BOTTOM w0.076: v3(127.11,57.82) 126.9,58.03 126.79,58.03 126.59,57.83 125.4,57.83 125.34,57.78 125.34,57.53 125.27,57.45 125.09,57.45 124.97,57.57 UC1.BH3
  BOTTOM w0.102: v3(200.14,38.9) 200.56,38.48 200.56,38.23 200.13,37.8 199.72,37.8 198.98,37.07 197.04,37.07 196.87,37.23 195.7,37.23 195.49,37.02 195.47,36.84 195.31,36.71 JSSD.53
CLK_PCIE_P1: length 141.5
  IN2 w0.076: v3(126.84,60.39) 127.43,60.39 127.66,60.62 127.66,66.46 128.3,67.11 128.3,67.48 130.45,69.63 130.45,70.82 130.5,70.87 130.5,73.95
  IN2 w0.127: v3(35.84,110.15) 37.59,110.15 37.6,110.15 40.66,110.15 43.35,107.46 44.19,107.46 46.48,105.18 53.73,105.18 54.74,106.19 67.44,106.19 68.46,107.21 79.11,107.21 80.75,105.57 105.69,105.57 106.55,104.71 114.67,104.71 131.3,88.07 131.3,86.82 130.76,86.27 130.76,77.47 131.88,76.35 131.88,75.32 130.5,73.95
  BOTTOM w0.076: UC1.BC2 125.39,60.63 125.39,60.44 125.57,60.26 126.13,60.26 126.48,60.6 126.63,60.6 v3(126.84,60.39)
  BOTTOM w0.102: v3(35.84,110.15) 35.65,109.96 35.51,109.96 35.15,110.32 34.7,110.32 34.47,110.09 34.47,109.91 34.38,109.82 UL1.15
CLK_PCIE_P2: length 176.8
  TOP w0.102: C5186.1 220.66,9.41 222.87,9.41 v3(223.06,9.59)
  IN2 w0.127: v3(126.87,59.19) 127.29,58.77 127.9,58.77 129.74,60.61 129.81,60.61 129.93,60.73 141.85,60.73 151.41,51.18 154.92,51.18 155.36,50.73 157.59,50.73 159.31,49 161.84,49 162.13,49.3 166.05,49.3 169.29,46.06 171.88,44.99 185.67,44.99 186.71,46.02 196.33,46.02 203.34,53.03 206.73,53.03 207.06,53.36 211.98,53.36 236.05,29.29 236.05,22.53 236.75,21.83 236.75,17.82 238.72,15.85 238.72,11.5 235.42,8.2 227.77,8.2 226.54,9.43 223.22,9.43 v3(223.06,9.59)
  BOTTOM w0.076: 125.37,59.88 124.85,59.88 124.64,60.08 UC1.BC3
  BOTTOM w0.102: 125.37,59.88 125.38,59.86 126.1,59.86 126.25,59.71 126.95,59.71 127.06,59.59 127.06,59.38 v3(126.87,59.19) ; JWLAN.39 220.44,9.55 220.58,9.41 222.87,9.41 v3(223.06,9.59)
CLK_PCIE_P3: length 97.7
  IN2 w0.127: v3(200.78,38.9) 200.78,41.52 198.08,44.22 187.67,44.22 186.57,43.11 184,43.11 182.54,41.66 177.17,41.66 176.11,42.72 172.34,42.72 172.19,42.87 169.64,42.87 167.94,44.57 167.35,44.57 164.86,47.06 157.71,47.06 156.76,48.01 153.68,48.01 153,48.7 152.26,48.7 152.09,48.86 151.15,48.86 144.85,55.16 143.75,55.16 140.03,58.88 133.49,58.88 131.88,57.27 131.16,57.27 130.55,57.88 130.07,57.88 129.33,58.62 128.27,58.62 127.68,58.03 127.48,58.03 v3(127.11,58.4)
  BOTTOM w0.076: v3(127.11,58.4) 126.91,58.2 126.72,58.2 126.52,57.99 124.92,57.99 124.32,57.73 UC1.BH4
  BOTTOM w0.102: JSSD.55 195.81,36.65 195.68,36.8 195.7,36.92 195.79,37.02 196.78,37.02 196.95,36.85 199.07,36.85 199.81,37.59 200.22,37.59 200.78,38.14 v3(200.78,38.9)
CLK_PCIE_XDP_DN: length 4.4
  BOTTOM w0.076: UC1.AU1 125.94,64.76 126.02,64.84 126.8,64.84 126.88,64.76 126.88,64.4 126.97,64.31 127.11,64.31 127.19,64.38 127.19,64.76 127.26,64.84 127.41,64.84 127.49,64.76 127.49,64.29 127.59,64.19 127.74,64.19 127.83,64.28 127.83,64.73 127.91,64.81 T306.1
CLK_PCIE_XDP_DP: length 4.4
  BOTTOM w0.076: T307.1 128.99,65.14 125.96,65.14 UC1.AU2
CLK_PEG_N0: length 62.6
  IN2 w0.127: v3(135.71,65.32) 135.55,65.16 135.37,65.16 135.21,65.32 135.21,71.78 138.68,75.25 140.64,75.25 142.89,77.49 142.89,84.66 141.04,86.51 141.04,86.6 135.58,92.06 135.58,92.68 133.95,94.3 133.73,94.3 133.17,94.86 133.17,95.03 v3(133.29,95.15)
  BOTTOM w0.076: v3(133.29,95.15) 133.08,95.36 133.08,95.65 133.65,96.22 137.95,96.22 138.23,96.5 138.23,98.12 138.2,98.15 138.2,99.54 138.02,99.71 136.65,99.71 136.51,99.86 136.51,100.07 136.58,100.15 136.79,100.15 UV1.AD8 ; 129.53,64.29 129.52,64.28 129.52,64.24 129.1,63.82 127.42,63.82 126.45,62.86 125.87,62.86 125.76,62.74 125.35,62.74 125.24,62.85 125.24,63.11 UC1.AW2
  BOTTOM w0.102: v3(135.71,65.32) 135.51,65.12 135.19,65.12 134.81,64.74 129.98,64.74 129.53,64.29
CLK_PEG_P0: length 62.6
  IN2 w0.127: v3(135.71,64.73) 135.53,64.91 135.27,64.91 134.96,65.22 134.96,71.89 138.58,75.51 140.54,75.51 142.63,77.6 142.63,84.56 140.79,86.4 140.79,86.5 135.33,91.96 135.33,92.57 133.85,94.05 133.63,94.05 132.92,94.76 132.92,94.92 132.87,94.97 132.87,94.98 v3(132.7,95.15)
  BOTTOM w0.076: v3(132.7,95.15) 132.91,95.36 132.91,95.72 133.58,96.38 137.88,96.38 138.07,96.57 138.07,98.05 138.03,98.08 138.03,99.47 137.96,99.54 136.58,99.54 136.32,99.81 136.32,99.89 136.17,100.04 UV1.AE8 ; UC1.AY3 125.04,62.67 125.15,62.67 125.27,62.55 125.84,62.55 125.95,62.67 126.55,62.67 127.5,63.62 129.18,63.62 129.68,64.12
  BOTTOM w0.102: 129.68,64.12 129.72,64.16 129.72,64.18 130.07,64.52 134.9,64.52 135.28,64.9 135.54,64.9 v3(135.71,64.73)
CLKIN_XTAL_LCP: length 129.4
  IN2 w0.127: v3(132.57,37.05) 132.99,36.63 137.44,36.63 138.32,35.76 138.5,35.76 139.1,35.16 140.37,35.16 141.68,33.85 142.21,33.85 143.2,32.86 143.33,32.86 146.46,29.73 149.9,29.73 150.37,29.53 150.64,29.26 150.64,28.87 150.84,28.68 159.02,28.68 159.47,28.23 160.89,28.23 161.32,28.66 162.62,28.66 163.05,28.23 163.05,26.96 165.29,24.73 196.7,24.73 197.23,25.25 198.99,25.25 199.69,24.55 203.48,24.55 204.18,25.25 207.74,25.25 208.44,24.55 210.23,24.55 211.22,23.57 211.22,22.88 212.49,21.61 217.1,21.61 218.14,20.57 222.5,20.57 224.2,18.86 v3(224.2,12.65)
  BOTTOM w0.076: 125.68,41.14 125.42,41.14 125.13,41.43 125.13,41.63 124.96,41.79 UC1.CM3
  BOTTOM w0.102: JWLAN.56 226.05,5.3 224.58,6.76 224.58,8.33 224.01,8.9 224.01,12.46 v3(224.2,12.65) ; 125.68,41.14 128.17,41.14 128.65,40.66 RC957.2 129.1,40.47 129.36,40.22 130.2,40.22 132.57,37.85 v3(132.57,37.05)
CLKREQ_PCIE#0_R: length 94.8
  TOP w0.102: QV3.3 178.87,130.47 177.4,129 RV375.1 v3(178.21,127.53) RV68.2
  IN1 w0.127: v3(178.21,127.53) 178.54,127.53 180.7,125.37 180.7,123.98 178.54,121.82 178.54,118.98 176.39,116.82 176.39,115.17 174.7,113.48 170.93,113.48 170.18,112.73 170.18,108.65 169.35,107.83 169.35,102.72 169.99,102.09 169.99,99.79 171.27,98.51 171.27,97.6 170.93,97.26 170.93,95.99 170.43,95.49 169.52,95.49 168.31,94.28 168.31,93.67 168.04,93.4 167.39,93.4 167.36,93.38 167.18,93.3 166.22,92.83 162.78,92.83 162.5,93.11 160.96,93.11 160.45,92.6 158.32,92.6 157.22,93.7 156.37,93.7 156.1,93.42 156.1,90.83 155.97,90.7 153.47,90.7 152.12,89.35 144.9,89.35 144.41,88.86 140.06,88.86 139.52,89.4 138.55,89.4 136.63,91.31 136.63,97.28 v3(137.33,97.98)
  BOTTOM w0.102: UV1.AC6 137.7,98.35 v3(137.33,97.98)
CLKREQ_PCIE#1: length 193.4
  TOP w0.076: v3(106.5,46.93) 106.5,46.72 106.1,46.32 105.84,46.32 105.65,46.12 105.65,45.23 106.17,44.71 106.17,43.77 105.97,43.57 105.26,43.57 104.88,43.2 104.88,41.78 104.95,41.71 RC954.2
  TOP w0.102: v3(47.01,105.81) 45.93,106.89 43.23,106.89 v1(38.72,111.4) 38.05,112.07 v3(33.61,112.07)
  IN1 w0.127: v3(91.17,36.07) 91.17,36.09 90.28,36.98 87.55,36.98 85.83,35.26 85.83,34.92 77.66,26.75 74.23,26.75 73.24,25.76 62.25,25.76 61.72,26.3 59.58,26.3 58.18,26.88 55.68,26.88 54.77,27.78 53.31,27.78 53.13,27.96 52.35,27.96 52.21,27.82 50.91,27.82 50.14,28.6 46.68,28.6 45.89,29.38 43.44,29.38 42.75,28.69 39.29,28.69 38.79,29.19 38.79,37.07 35.12,40.74 35.12,65.92 35.82,66.62 35.82,86.58 35.39,87.01 35.39,92.61 36.61,93.83 41,93.83 47.01,99.84 v3(47.01,105.81)
  IN2 w0.076: v3(106.5,46.93) 106.5,46.85 106.15,46.5 104.25,46.5 100.88,43.14 100.88,41.61 100.31,41.04 98.41,41.04 98,40.63
  IN2 w0.127: v3(91.17,36.07) 91.17,37.02 93.67,39.52 95.85,39.52 96.1,39.77 97.14,39.77 98,40.63
  BOTTOM w0.076: UC1.CE32 106.31,47.23 106.5,47.05 v3(106.5,46.93)
  BOTTOM w0.102: v3(33.61,112.07) 33.31,111.77 33.31,110.09 33.18,109.97 UL1.12
CLKREQ_PCIE#2: length 150.9
  TOP w0.076: RC953.2 107.29,43.73 107.29,44.95 v1(107.62,45.29) 107.75,45.42 v3(107.75,46.04)
  IN1 w0.076: v3(107.75,46.04) 106.13,44.42 106.13,42.72 106.28,42.56
  IN1 w0.127: v3(223.06,8.14) 223.64,8.73 223.64,11.73 214.5,20.87 212.12,20.87 205.41,27.58 205.41,29.87 204.1,31.17 176.79,31.17 176.09,30.47 170.54,30.47 166.42,34.6 166.42,34.6 165.54,35.48 160.36,35.48 159.56,34.68 158.82,34.68 158.23,34.09 157.24,34.09 157.16,34.02 154.25,34.02 153.99,34.28 149.86,34.28 149.72,34.14 148.22,34.14 148.01,34.35 139.17,34.35 139.13,34.31 137.7,34.31 137.57,34.44 136.62,34.44 136.11,33.93 130.94,33.93 130.62,34.25 126.69,34.25 126.1,34.83 121.45,34.83 121.23,35.06 116.7,35.06 116.64,35.12 116.26,35.5 113.94,35.5 112.22,37.23 110.81,37.23 109.89,38.14 109.59,38.14 108.84,38.89 107.41,38.89 106.28,40.03 106.28,42.56
  BOTTOM w0.076: UC1.CF30 107.69,46.42 107.69,46.1 v3(107.75,46.04)
  BOTTOM w0.102: JWLAN.45 222.97,8.05 v3(223.06,8.14)
CLKREQ_PCIE#3: length 138.8
  TOP w0.076: v3(107.26,46.97) 107.26,46.67 107.42,46.5 107.91,46.5 108.11,46.31 108.11,45.28 107.46,44.64 107.46,43.28 RC955.2
  TOP w0.102: v3(204.3,31.54) 205.09,32.33 v2(205.09,32.87) 205.09,35.62 204.85,35.86 v3(204.53,35.86)
  IN1 w0.076: v3(107.26,46.97) 107.33,46.97 107.84,46.46 107.91,46.46 108.11,46.26 108.11,45.89 107.12,44.91 106.85,44.91 106.29,44.35 106.29,43.05 106.47,42.87 106.47,42.12 106.54,42.06
  IN1 w0.127: 106.54,42.06 106.54,40.13 107.52,39.15 108.95,39.15 109.7,38.4 110,38.4 110.92,37.48 112.33,37.48 114.09,35.72 116.35,35.72 116.79,35.28 121.32,35.28 121.51,35.09 126.21,35.09 126.79,34.5 130.73,34.5 131.05,34.18 136,34.18 136.51,34.69 137.68,34.69 137.81,34.56 139.03,34.56 139.06,34.6 148.14,34.6 148.52,34.98 149.34,34.98 149.79,34.54 154.09,34.54 154.36,34.27 157.05,34.27 157.71,34.93 158.82,34.93 159.45,34.93 160.25,35.73 165.64,35.73 166.67,34.7 170.64,30.73 175.98,30.73 176.68,31.43 204.19,31.43 v3(204.3,31.54)
  BOTTOM w0.076: v3(107.26,46.97) 106.96,47.27 UC1.CE31
  BOTTOM w0.102: v3(204.53,35.86) 204.53,40.91 203.37,42.07 195.82,42.07 195.56,42.33 JSSD.52
CLKREQ_PCIE#4: length 6.5
  TOP w0.076: RC165.2 107.63,42.17 107.63,44.42 108.31,45.11 108.31,46.49 v3(107.84,46.96)
  BOTTOM w0.076: UC1.CE30 107.84,47.18
  BOTTOM w0.089: 107.84,47.18 v3(107.84,46.96)
CLKREQ_PCIE#5: length 4.1
  TOP w0.076: v3(107.17,46.05) 106.66,45.54 v1(106.66,44.39) 106.52,44.25 106.52,43.59 105.92,42.98 RC105.2
  BOTTOM w0.076: UC1.CF31 106.96,46.25 v3(107.17,46.05)
CLKREQ_PEG#0: length 183.9
  TOP w0.076: RC952.2 105.27,43.33 105.35,43.41 106.11,43.41 106.34,43.64 106.34,45.83 v3(106.58,46.07)
  TOP w0.102: v3(177.81,126.39) 176.94,126.39 176.48,126.84 RV375.2 176.48,129.64 QV3.1
  IN1 w0.076: v3(106.58,46.07) 106.58,46.41 106.85,46.68 106.85,47.08 106.62,47.31 106.38,47.31 104.54,49.15 104.54,50.4 105.18,51.03 105.94,51.03 107.13,51.03 107.26,51.16 107.4,51.16 107.53,51.03 109.69,51.03 110.13,51.48 112.46,51.48 112.8,51.81 112.8,53.64 111.7,54.74 111.12,54.74 110.17,55.7 110.17,56.2 109.87,56.5 109.87,57 109.46,57.41 105.91,57.41 105.62,57.7 105.62,58.13 104.42,59.34 104.42,66.29 105.52,67.4 105.52,68.84 106.05,69.37 106.22,69.37 106.24,69.39 108.92,69.39 109.87,70.33 109.87,79.98 110.51,80.63 110.51,86.53 110.48,86.56 110.48,86.86 110.51,86.89 110.51,87.92 111.62,89.02
  IN1 w0.127: v3(177.81,126.39) 179.33,126.39 180.45,125.26 180.45,124.09 178.29,121.93 178.29,119.08 176.13,116.92 176.13,115.28 174.59,113.74 170.82,113.74 169.92,112.83 169.92,108.76 169.1,107.93 169.1,102.61 169.73,101.98 169.73,99.68 171.02,98.4 171.02,97.71 170.68,97.37 170.68,96.09 170.33,95.74 169.26,95.74 167.83,94.31 167.12,93.83 166.96,93.77 166.1,93.34 163,93.34 162.71,93.62 160.13,93.62 159.62,93.11 158.53,93.11 156.89,94.75 155.49,94.75 154.29,93.55 154.29,91.33 154.16,91.21 153.25,91.21 151.91,89.86 144.69,89.86 144.2,89.37 140.27,89.37 139.73,89.91 138.76,89.91 138.13,90.54 138.13,91.49 137.65,91.97 137.31,91.97 v3(137.14,91.8) ; v3(112.83,93.16) 111.8,92.12 111.8,89.2 111.62,89.02
  BOTTOM w0.076: v3(106.58,46.07) 106.58,46.1 106.31,46.37 UC1.CF32
  BOTTOM w0.102: v3(112.83,93.16) 112.85,93.17 115.75,93.17 118.66,90.26 121.21,90.26 123,92.04 129.07,92.04 129.78,91.33 136.76,91.33 137.14,91.71 v3(137.14,91.8)
CLR_CMOS#: length 115.2
  TOP w0.102: v3(94.47,41.17) v2(93.77,41.17)
  IN1 w0.127: v3(168.56,29.51) 166.76,31.31 160.56,31.31 158.76,29.51 154.29,29.51 153.77,30.02 150.94,30.02 150.57,30.4 148.64,30.4 148.2,30.84 147.87,30.84 147.36,31.35 145.69,31.35 145.5,31.16 143.87,31.16 143.48,31.55 139.24,31.55 138.57,32.22 137.91,32.22 137.76,32.06 135.95,32.06 135.88,32.13 131.25,32.13 130.99,31.87 126.55,31.87 126.1,32.32 120.87,32.32 120.05,33.13 117.85,33.13 117.23,32.52 115.73,32.52 115.65,32.44 114.18,32.44 113.92,32.19 110.9,32.19 110.77,32.06 107.81,32.06 107.61,31.86 106.16,31.86 104.52,33.5 102.69,33.5 102.11,32.92 100.69,32.92 100.12,33.49 99.19,33.49 96.84,35.83 94.66,35.83 94.15,36.34 94.15,38.56 94.47,38.88 v3(94.47,41.17)
  BOTTOM w0.102: UK1.27 164.97,46.37 164.16,45.56 164.16,42.8 164.77,42.19 164.77,39.3 166.38,37.68 166.38,34.17 168.56,31.99 v3(168.56,29.51) ; JCMOS1.1 93.84,38.33 94.47,38.97 v3(94.47,41.17) 93.32,42.32 R1089.1 R1088.1
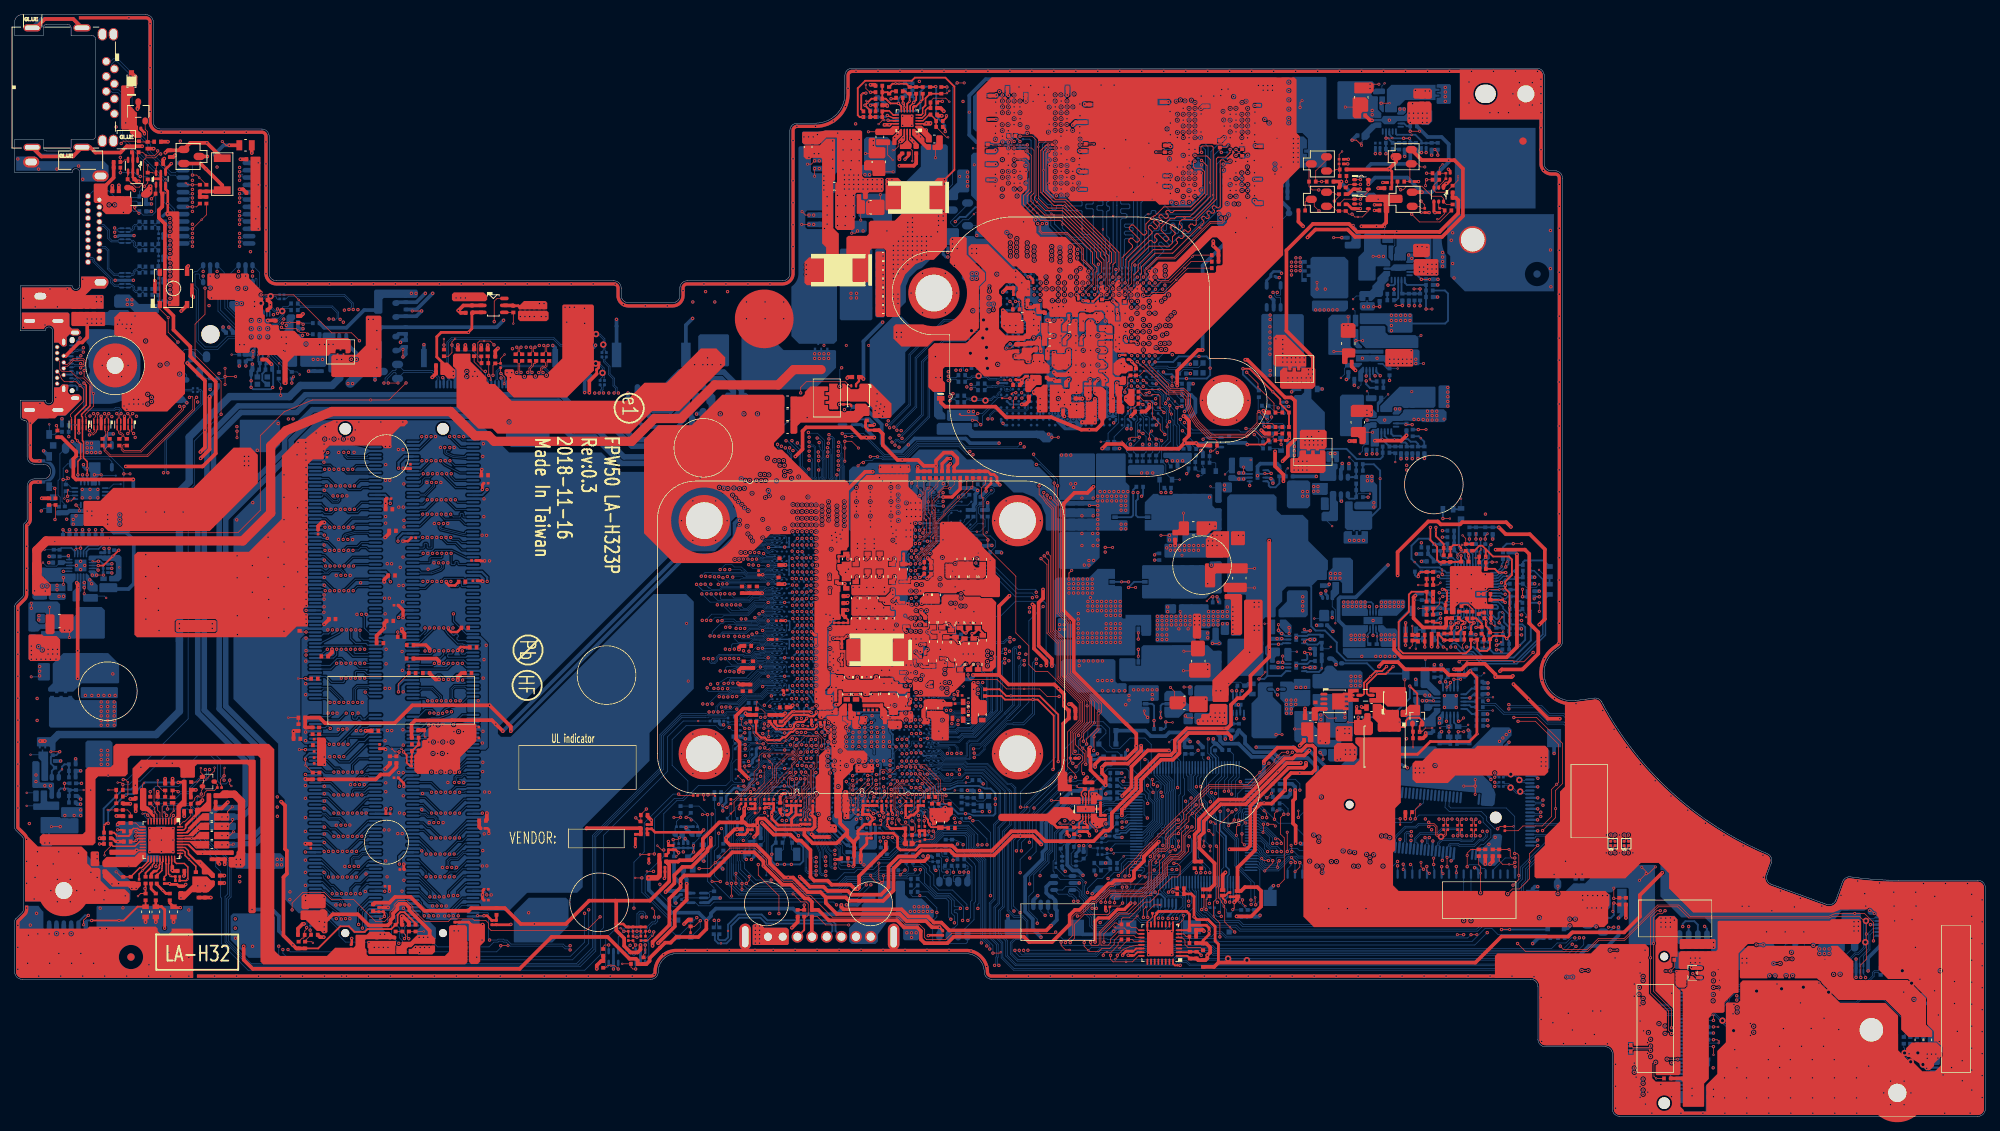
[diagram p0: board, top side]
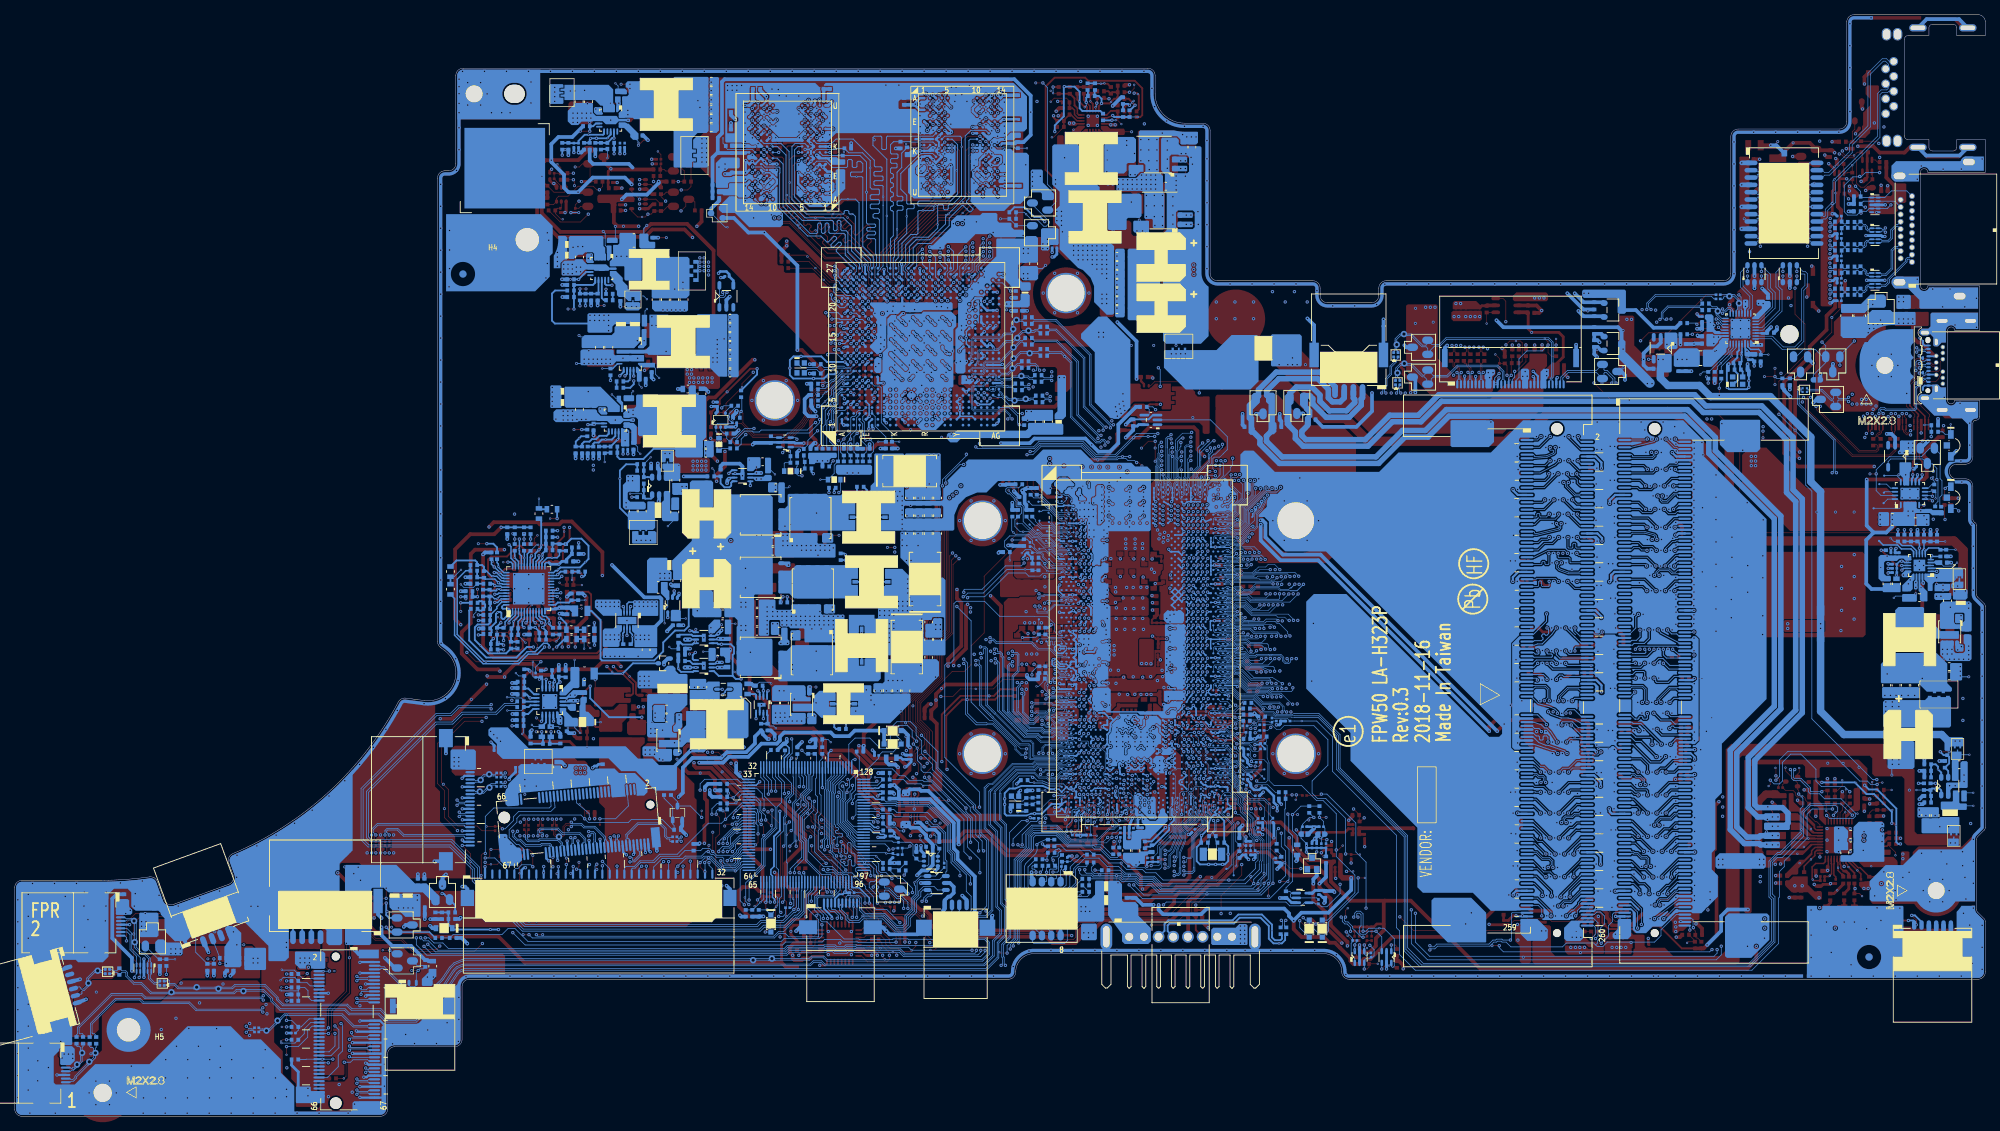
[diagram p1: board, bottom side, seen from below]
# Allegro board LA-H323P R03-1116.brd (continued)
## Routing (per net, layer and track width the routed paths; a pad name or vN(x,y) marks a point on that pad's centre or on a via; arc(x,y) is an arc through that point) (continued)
CMSRC_CHG: length 28.8
  TOP w0.102: v3(195.75,59.19) 195.75,59.03 v2(195.28,58.55)
  TOP w0.381: PRB10.2 183.73,55.77 v3(183.62,55.87)
  IN1 w0.381: v3(195.75,59.19) 197.34,57.6 197.34,56.37 198.98,54.73 198.98,52.65 197.1,50.77 193.1,50.77 187.68,56.19 183.94,56.19 v3(183.62,55.87)
  BOTTOM w0.254: PUB1.3 v3(195.75,59.19)
CNV_WT_RCOMP: length 3.6
  BOTTOM w0.076: UC1.CP32 106.31,42.13 UC1.CR32 106.53,40.97 106.92,40.39 106.92,39.9 v1(107.14,39.68) 107.67,39.15 RC132.2
CNVI_BRI_DT: length 13.4
  IN2 w0.076: v3(113.39,45.68) 113.71,45.36 113.71,43.64 115.94,41.42 115.94,40.52 116.88,39.58 116.89,39.58
  IN2 w0.127: v3(118.48,38.05) 118.42,38.05 116.89,39.58
  BOTTOM w0.076: UC1.CJ20 113.81,45.01 113.39,45.42 v3(113.39,45.68) ; 118.87,36.71 118.41,37.17 118.41,37.98 v3(118.48,38.05) 118.48,38.18 117.97,38.69 RC404.1
  BOTTOM w0.102: RW8.2 118.87,36.71
CNVI_BRI_DT_R: length 147.7
  TOP w0.102: v3(231.63,9.51) v1(231.63,8.39)
  IN2 w0.127: v3(136.97,22.65) 136.55,22.23 134.38,22.23 133.36,23.25 v3(132.54,23.25) ; v3(231.63,9.51) 229.31,11.84 229.31,16.41 226.56,19.16 226.56,22.53 226.08,23.01 223.76,23.01 223.34,23.43 213.12,23.43 v3(212.89,23.19)
  BOTTOM w0.076: 121.28,37.13 124.96,37.13 125.06,37.23
  BOTTOM w0.102: v3(136.97,22.65) 136.97,22.42 137.36,22.03 147.42,22.03 148,22.61 154.13,22.61 154.22,22.7 155.09,22.7 155.32,22.47 156.87,22.47 157.1,22.7 158.05,22.7 158.14,22.61 163.09,22.61 163.5,22.21 211.9,22.21 v3(212.89,23.19) ; 125.06,37.23 126.57,38.74 129.77,38.74 130.26,38.25 130.26,36.56 131.97,34.85 131.97,24.09 132.54,23.51 v3(132.54,23.25) ; 121.28,37.13 121.19,37.04 120.45,37.04 119.17,35.76 RW8.1 ; v3(231.63,9.51) 230.03,9.51 228.75,10.79 228.75,11.71 228.16,12.3 JWLAN.28
CNVI_BRI_RSP: length 146.4
  TOP w0.102: v1(134.45,22.4) 134.32,22.27 v3(133.38,22.27)
  IN2 w0.076: v3(114.28,43.9) 116.73,41.45 116.73,41.17 116.82,41.08 116.82,40.42 117.03,40.21 117.56,40.21 118.2,39.58
  IN2 w0.127: v3(231.58,15.76) 231.58,15.81 227.57,19.82 227.57,22.95 226.5,24.02 224.19,24.02 223.44,24.77 213.76,24.77 v3(213.35,24.36) ; v3(119.67,38.06) 119.67,38.11 118.2,39.58 ; v3(138.16,22.66) 138.16,22.25 137.64,21.72 133.93,21.72 v3(133.38,22.27)
  BOTTOM w0.076: 130.7,36.76 130.7,38.4 129.86,39.25 126.59,39.25 124.81,37.47 120.25,37.47 v3(119.67,38.06) ; v3(114.28,43.9) 114.08,44.11 UC1.CK20
  BOTTOM w0.102: v3(138.16,22.66) 146.41,22.66 146.82,23.07 153.94,23.07 154.03,23.16 155.28,23.16 155.51,22.93 156.68,22.93 156.91,23.16 158.24,23.16 158.33,23.07 163.28,23.07 163.69,22.66 210.99,22.66 212.27,23.95 212.93,23.95 v3(213.35,24.36) ; RW5.2 v3(231.58,15.76) ; v3(133.38,22.27) 133.38,23.32 132.42,24.28 132.42,35.04 130.7,36.76
CNVI_BRI_RSP_R: length 8.4
  BOTTOM w0.102: v1(232.47,17.23) 232.35,17.11 230.11,17.11 230.03,17.19 ; JWLAN.22 228.23,15.8 228.71,16.28 228.71,17.16 229.14,17.59 RW11.1 230.03,17.19 ; RW5.1 RC72.1 230.03,17.19
CNVI_RF_RESET_N: length 155.1
  TOP w0.102: v1(143.85,22.7) 143.29,22.7 142.68,23.31 v3(142.68,23.77)
  IN2 w0.127: v3(231.63,19.42) 231.63,20.59 227.94,24.28 224.29,24.28 223.54,25.03 213.39,25.03 v3(212.72,24.35) ; v3(131.33,28.37) 131.56,28.14 135.22,28.14 136.1,27.26 139.88,27.26 140.71,26.42 141.48,26.42 142.36,25.55 142.36,24.09 v3(142.68,23.77)
  BOTTOM w0.076: 112.44,33.87 112.29,34.02 112.29,36.41 110.66,38.03 110.4,38.67 110.4,39.34 109.23,40.51 109.23,42.19 109.16,42.36 109.01,42.5 108.82,42.5 108.69,42.63 108.69,44.15 108.5,44.34 108.12,44.34 107.93,44.53 107.93,44.79 107.76,44.96 106.84,44.96 106.56,44.68 UC1.CJ32 ; 116.66,34.14 116.62,34.14 116.42,33.94 114.64,33.94 114.42,33.71 113.85,33.71
  BOTTOM w0.102: 116.66,34.14 RC401.1 116.86,34.14 117.76,35.05 119.33,35.05 120.73,36.46 121.47,36.46 121.78,36.76 125.13,36.76 126.66,38.3 129.51,38.3 129.78,38.03 129.78,36.39 131.49,34.68 131.49,29.08 131.33,28.92 v3(131.33,28.37) ; v3(212.72,24.35) 212.21,24.35 211.51,23.65 210.32,23.65 209.56,22.89 163.78,22.89 163.38,23.3 158.42,23.3 158.33,23.39 156.82,23.39 156.59,23.16 155.61,23.16 155.38,23.39 153.93,23.39 153.85,23.3 142.78,23.3 142.68,23.4 v3(142.68,23.77) ; RW3.2 v3(231.63,19.42) ; 112.44,33.87 112.59,33.71 113.85,33.71
CNVI_RF_RESET_R_N: length 5.6
  BOTTOM w0.102: JWLAN.10 229.41,18.8 RW3.1 230.56,19.95 232.21,19.95 v1(232.28,20.01)
CNVI_RGI_DT: length 14.7
  IN2 w0.076: v3(114.25,45.84) 113.73,45.84 113.54,46.03 113.25,46.03 112.89,45.67 112.89,44.34 112.89,44.34 112.89,43.24 113.45,42.68 113.75,42.68 113.96,42.88 114.24,42.88 115.75,41.37 115.75,40.12 116.29,39.58
  IN2 w0.127: v3(118.03,37.55) 117.97,37.61 117.97,37.91 116.29,39.58
  BOTTOM w0.076: v3(114.25,45.84) UC1.CG19 ; RW6.2 118.03,36.74 v3(118.03,37.55) 117.94,37.64 RC1155.1
CNVI_RGI_DT_R: length 147.3
  TOP w0.102: v1(231.63,13.85) v3(231.63,13.09)
  IN2 w0.127: v3(131.82,23.66) 131.83,23.67 133.3,23.67 134.34,22.63 136.36,22.63 v3(136.38,22.65) ; v3(213.93,24.35) 223.5,24.35 224.08,23.77 226.39,23.77 227.32,22.84 227.32,19.55 230.11,16.76 230.11,13.67 230.69,13.09 v3(231.63,13.09)
  BOTTOM w0.076: RW6.1 118.09,35.58
  BOTTOM w0.102: JWLAN.24 228.54,13.3 229.64,12.2 RW12.1 ; v3(231.63,13.09) 230.92,13.09 RW12.1 ; v3(213.93,24.35) 213.93,23.41 212.5,21.98 163.4,21.98 163,22.38 158.02,22.38 157.93,22.47 157.2,22.47 156.97,22.25 155.23,22.25 155,22.47 154.31,22.47 154.22,22.38 148.1,22.38 147.51,21.8 137,21.8 136.38,22.42 v3(136.38,22.65) ; RW12.1 230.03,11.75 RC183.1 ; v3(131.82,23.66) 131.74,23.74 131.74,34.76 130.03,36.46 130.03,38.16 129.64,38.55 126.65,38.55 125.05,36.95 121.55,36.95 121.35,36.75 120.69,36.75 119.25,35.31 118.36,35.31 118.09,35.58
CNVI_RGI_RSP: length 153.9
  TOP w0.102: v3(231.63,10.45) 232.15,10.45 v1(232.38,10.22)
  IN2 w0.076: 117.84,39.58 117.37,40.05 116.96,40.05 116.66,40.35 116.66,40.95 113.88,43.73 113.88,44.63 114.32,45.08 v3(114.33,45.08)
  IN2 w0.127: v3(132.95,22.83) 133.42,22.83 134.27,21.98 137.17,21.98 137.57,22.38 v3(137.57,22.65) ; 117.84,39.58 119.08,38.34 v3(119.08,38.06) ; v3(231.63,10.45) 231.24,10.45 229.56,12.13 229.56,16.52 226.81,19.27 226.81,22.63 226.18,23.26 223.87,23.26 223.45,23.68 212.58,23.68 v3(212.38,23.48)
  BOTTOM w0.076: UC1.CH19 v3(114.33,45.08) ; RC403.2 118.54,38.73 118.94,38.73 119.08,38.59 v3(119.08,38.06) 119.83,37.31 124.88,37.31 126.57,39 129.82,39 130.49,38.33 130.49,36.65
  BOTTOM w0.102: v3(212.38,23.48) 211.33,22.44 163.59,22.44 163.19,22.84 158.23,22.84 158.14,22.93 157.01,22.93 156.78,22.7 155.42,22.7 155.19,22.93 154.12,22.93 154.04,22.84 147.91,22.84 147.32,22.26 137.77,22.26 137.57,22.46 v3(137.57,22.65) ; 130.49,36.65 132.2,34.95 132.2,24.19 132.95,23.43 v3(132.95,22.83) ; RW7.2 v3(231.63,10.45)
CNVI_RGI_RSP_R: length 6.7
  BOTTOM w0.102: JWLAN.26 228.33,12.8 229.22,11.91 229.22,11.26 RW7.1 230.49,9.99 v1(232.33,9.99)
CNVI_WGR_CLK_DN: length 132.9
  IN2 w0.127: v3(222.04,16.09) 221.91,15.96 219.17,15.96 216.71,18.42 212.4,18.42 208.58,22.24 163.42,22.24 162.93,22.74 157.41,22.74 157.17,22.5 155.52,22.5 155.28,22.74 150.78,22.74 149.03,24.49 145.21,24.49 140.87,28.84 139.21,28.84 138.64,29.41 132.57,29.41 132.09,29.89 126.49,29.89 125.71,30.67 121.88,30.67 121.29,30.08 117.95,30.08 117.63,29.75 114.27,29.75 112.33,31.69 112.33,32.8 111.43,33.7 111.43,35.01 111.13,35.3 110.66,35.3 v3(110.58,35.39)
  BOTTOM w0.076: v3(110.58,35.39) 110.56,35.38 110.31,35.38 110.26,35.43 110.26,36.39 109.57,38.05 109.57,38.87 109.08,39.36 108.97,39.36 107.54,40.8 107.4,41.12 107.3,41.37 107.3,41.69 UC1.CN31
  BOTTOM w0.102: JWLAN.21 220.4,16.05 220.54,15.91 221.86,15.91 v3(222.04,16.09)
CNVI_WGR_CLK_DP: length 132.9
  IN2 w0.127: v3(222.04,15.51) 221.84,15.71 219.06,15.71 216.6,18.17 212.3,18.17 208.48,21.99 163.32,21.99 162.82,22.49 157.51,22.49 157.27,22.25 155.42,22.25 155.18,22.49 150.68,22.49 148.94,24.23 145.12,24.23 140.76,28.58 139.11,28.58 138.53,29.16 132.46,29.16 131.98,29.64 126.38,29.64 125.61,30.41 121.99,30.41 121.4,29.82 118.06,29.82 117.73,29.5 114.16,29.5 112.07,31.59 112.07,32.7 111.17,33.6 111.17,34.9 111.03,35.05 110.82,35.05 v3(110.58,34.8)
  BOTTOM w0.076: v3(110.58,34.8) 110.36,34.8 110.31,34.86 110.31,35.15 110.09,35.36 110.09,36.36 109.41,38.02 109.41,38.81 109.01,39.2 108.9,39.2 107.4,40.71 107.16,41.28 107.13,41.3 107.13,41.52 UC1.CP31
  BOTTOM w0.102: v3(222.04,15.51) 221.86,15.69 220.54,15.69 220.4,15.55 JWLAN.23
CNVI_WGR_DATA0_DN: length 131.5
  IN2 w0.127: v3(221.53,17.59) 221.6,17.59 221.76,17.43 221.76,17.27 221.65,17.16 219.14,17.16 216.86,19.44 212.96,19.44 212.5,19.9 211.9,19.9 208.87,22.93 163.71,22.93 162.96,23.68 157.21,23.68 156.72,23.2 155.8,23.2 155.57,23.43 151.07,23.43 149.32,25.18 145.5,25.18 141.08,29.6 139.42,29.6 138.92,30.1 135.37,30.1 134.46,31 132.58,31 132.18,30.59 126.75,30.59 125.99,31.35 121.6,31.35 121.01,30.76 117.67,30.76 117.34,30.44 114.81,30.44 113.27,31.98 113.27,33.05 112.02,34.29 112.02,34.29 v3(111.86,34.44)
  BOTTOM w0.076: UC1.CR30 107.68,41.32 107.82,40.99 109.06,39.75 109.21,39.75 109.9,39.05 109.9,38.26 110.77,36.18 111.31,35.63 111.31,34.12 111.4,34.03 111.45,34.03 v3(111.86,34.44)
  BOTTOM w0.102: v3(221.53,17.59) 221.53,17.37 221.43,17.27 220.76,17.27 220.48,17.55 JWLAN.15
CNVI_WGR_DATA0_DP: length 131.4
  IN2 w0.127: v3(221.47,16.65) 221.47,16.66 221.23,16.9 219.04,16.9 216.76,19.18 212.86,19.18 212.4,19.64 211.8,19.64 208.76,22.68 163.6,22.68 162.85,23.43 157.31,23.43 156.83,22.94 155.69,22.94 155.46,23.17 150.97,23.17 149.22,24.92 145.39,24.92 140.97,29.34 139.31,29.34 138.82,29.84 135.26,29.84 134.36,30.74 132.69,30.74 132.28,30.34 126.65,30.34 125.89,31.1 121.7,31.1 121.11,30.51 117.77,30.51 117.45,30.18 114.7,30.18 113.01,31.87 113.01,32.94 112.07,33.89 111.89,33.89 v3(111.86,33.86)
  BOTTOM w0.076: 111.86,33.87 111.33,33.87 111.15,34.05 111.15,35.56 110.63,36.08 109.74,38.23 109.74,38.98 109.14,39.58 108.99,39.58 107.68,40.89 107.51,41.3 107.46,41.41 107.46,41.8 107.65,41.98 UC1.CP30
  BOTTOM w0.102: v3(221.47,16.65) 221.47,16.95 221.37,17.05 JWLAN.17 ; 111.86,33.87 v3(111.86,33.86)
CNVI_WGR_DATA1_DN: length 131.6
  IN2 w0.127: v3(222.04,19.09) 221.87,18.93 218.44,18.93 216.73,20.63 212.14,20.63 209.15,23.61 207.91,23.61 207.21,24.32 204.57,24.32 203.87,23.61 163.99,23.61 163.24,24.37 151.72,24.37 150.17,25.92 145.73,25.92 140.86,30.78 135.76,30.78 134.82,31.72 132.33,31.72 131.89,31.28 127.04,31.28 126.28,32.04 121.31,32.04 120.72,31.45 117.38,31.45 117.06,31.12 115.95,31.12 114.14,32.93 114.14,33.21 112.96,34.39 112.96,35.48 112.32,36.12 112.02,36.12 v3(111.84,36.3)
  BOTTOM w0.076: v3(111.84,36.3) 111.27,36.3 111.1,36.47 110.66,37.52 110.23,38.56 110.23,39.23 109.34,40.13 109.14,40.13 108.19,41.08 108.19,41.5 108.07,41.84 108.07,42.28 107.97,42.51 107.97,43.16 UC1.CM30
  BOTTOM w0.102: v3(222.04,19.09) 221.86,18.91 220.58,18.91 220.44,19.05 JWLAN.9
CNVI_WGR_DATA1_DP: length 131.6
  IN2 w0.127: v3(222.04,18.51) 221.87,18.67 218.33,18.67 216.63,20.38 212.03,20.38 209.05,23.36 207.81,23.36 207.11,24.06 204.68,24.06 203.98,23.36 163.89,23.36 163.14,24.11 151.62,24.11 150.07,25.66 145.62,25.66 140.76,30.53 135.65,30.53 134.72,31.47 132.44,31.47 132,31.02 126.93,31.02 126.17,31.78 121.42,31.78 120.83,31.19 117.49,31.19 117.17,30.87 115.84,30.87 113.89,32.82 113.89,33.11 112.71,34.29 112.71,35.37 112.21,35.87 111.99,35.87 111.92,35.8 v3(111.84,35.72)
  BOTTOM w0.076: v3(111.84,35.72) 111.42,36.13 111.2,36.13 110.96,36.38 110.07,38.53 110.07,39.16 109.27,39.96 109.08,39.96 108.02,41.02 108.02,41.47 107.9,41.82 107.9,42.25 107.81,42.47 107.63,42.47 107.55,42.54 107.55,42.73 107.63,42.81 UC1.CN30
  BOTTOM w0.102: v3(222.04,18.51) 221.86,18.69 220.58,18.69 220.44,18.55 JWLAN.11
CNVI_WT_CLK_DN: length 148.4
  IN2 w0.127: v3(222.04,3.59) 221.85,3.4 219.99,3.4 219.69,3.71 219.69,9.98 216.86,12.81 215.11,12.81 207.73,20.19 141.66,20.19 138.51,23.34 134.6,23.34 133.57,24.37 126.93,24.37 124.9,26.4 121.69,26.4 120.65,27.43 119.05,27.43 118.55,26.93 109.79,26.93 108.69,28.03 108.69,32.77 108.97,33.04 109.16,33.04 v3(109.28,32.92)
  BOTTOM w0.076: UC1.CP34 105.23,42.52 105.18,42.57 104.98,42.57 104.92,42.51 104.92,42.01 105,41.93 105.24,41.93 105.31,41.85 105.31,41.67 105.47,41.52 105.63,41.12 106.22,40.23 106.22,39.49 107.78,37.92 107.78,33.91
  BOTTOM w0.102: v3(109.28,32.92) 109.05,33.15 108.1,33.15 107.78,33.47 107.78,33.91 ; JWLAN.63 220.39,3.55 220.53,3.41 221.86,3.41 v3(222.04,3.59)
CNVI_WT_CLK_DP: length 148.4
  IN2 w0.127: v3(222.04,3.01) 221.9,3.15 219.89,3.15 219.43,3.6 219.43,9.88 216.76,12.55 215,12.55 207.62,19.93 141.55,19.93 138.4,23.08 134.5,23.08 133.46,24.12 126.82,24.12 124.8,26.14 121.58,26.14 120.55,27.18 119.15,27.18 118.65,26.68 109.69,26.68 108.44,27.92 108.44,32.87 108.86,33.3 109.08,33.3 v3(109.28,33.5)
  BOTTOM w0.076: UC1.CN34 105.51,42.61 105.51,42.12 105.48,42.09 105.48,41.74 105.61,41.61 105.77,41.2 106.38,40.28 106.38,39.55 107.95,37.99 107.95,34 107.96,33.99 107.96,33.96 108,33.92 108,33.87
  BOTTOM w0.102: v3(109.28,33.5) 109.15,33.37 108.18,33.37 108,33.56 108,33.87 ; JWLAN.65 220.4,3.05 220.54,3.19 221.86,3.19 v3(222.04,3.01)
CNVI_WT_DATA0_DN: length 146.9
  IN2 w0.127: v3(110.6,32.84) 110.7,32.94 110.86,32.94 111.23,32.56 111.23,28.39 111.57,28.05 118.08,28.05 118.59,28.55 121.92,28.55 122.51,29.14 125.04,29.14 126.35,27.83 126.35,27.24 128.1,25.49 134.03,25.49 135.05,24.47 138.96,24.47 142.12,21.3 158.06,21.3 158.54,21.79 160.14,21.79 160.62,21.3 208.19,21.3 212.62,16.87 214.38,16.87 220.8,10.45 220.8,9.07 222.63,7.25 222.63,5.93 222.93,5.63 222.93,4.89 222.8,4.76 222.63,4.76 222.52,4.87 222.52,5.37 222.39,5.49 222.17,5.49 222.04,5.37 v3(222.04,5.09)
  BOTTOM w0.076: UC1.CN32 106.21,42.81 106.15,42.75 106.15,42.58 106.24,42.5 106.51,42.5 106.59,42.42 106.59,41.55 106.85,40.9 107.08,40.5 108.73,38.84 108.86,38.84 109.08,38.63 109.08,37.51 109.72,35.95 109.72,33.98 109.7,33.95 109.7,33.87
  BOTTOM w0.102: 109.7,33.87 109.7,33.14 110,32.84 v3(110.6,32.84) ; JWLAN.57 220.42,5.05 220.56,4.91 221.86,4.91 v3(222.04,5.09)
CNVI_WT_DATA0_DP: length 146.9
  IN2 w0.127: v3(222.04,4.51) 222.91,4.51 223.19,4.78 223.19,5.74 222.88,6.04 222.88,7.36 221.06,9.18 221.06,10.55 214.48,17.13 212.73,17.13 208.3,21.56 160.73,21.56 160.24,22.04 158.44,22.04 157.95,21.56 142.23,21.56 139.06,24.72 135.16,24.72 134.14,25.74 128.2,25.74 126.6,27.34 126.6,27.94 125.15,29.4 122.41,29.4 121.82,28.81 118.48,28.81 117.98,28.3 111.68,28.3 111.49,28.49 111.49,32.67 110.97,33.19 110.83,33.19 v3(110.6,33.43)
  BOTTOM w0.076: UC1.CM32 106.45,43.27 106.75,42.97 106.75,42.7 106.75,42.7 106.75,41.58 107,40.97 107.21,40.6 108.8,39.01 108.93,39.01 109.24,38.7 109.24,37.55 109.89,35.98 109.89,33.91 109.91,33.88 109.91,33.87
  BOTTOM w0.102: JWLAN.59 220.4,4.55 220.54,4.69 221.86,4.69 v3(222.04,4.51) ; 109.91,33.87 109.91,33.23 110.09,33.06 110.23,33.06 v3(110.6,33.43)
CNVI_WT_DATA1_DN: length 148.8
  IN2 w0.127: v3(220.83,6.59) 220.83,6.74 220.95,6.85 221.31,6.85 221.38,6.78 221.38,6.36 221.48,6.26 221.78,6.26 221.94,6.42 221.94,6.97 220.12,8.79 220.12,10.16 217.01,13.27 215.26,13.27 213.84,14.68 213.84,15.07 214.42,15.65 214.42,15.83 214.1,16.15 213.92,16.15 213.34,15.57 212.95,15.57 207.91,20.62 159.84,20.62 159.43,21.02 158.75,21.02 158.34,20.62 141.84,20.62 138.69,23.77 134.78,23.77 133.75,24.8 127.81,24.8 125.67,26.94 121.92,26.94 121,27.87 118.87,27.87 118.37,27.36 110.8,27.36 110.55,27.61 110.55,27.92 110.46,28.01 109.68,28.01 109.36,28.34 109.36,28.8 109.67,29.12 110.43,29.12 110.55,29.23 110.55,29.77 110.42,29.9 109.61,29.9 109.34,30.17 109.34,30.69 109.58,30.93 110.4,30.93 110.55,31.08 110.55,31.47 110.43,31.59 110.1,31.59 109.89,31.8 109.89,34.97 109.78,35.07 109.65,35.07 v3(109.29,34.72)
  BOTTOM w0.076: v3(109.29,34.72) 109.18,34.6 109.01,34.6 108.9,34.72 108.9,35.07 108.81,35.16 108.32,35.16 108.11,35.37 108.11,38.06 106.56,39.61 106.56,40.33 105.91,41.3 105.86,41.42 105.86,41.75 UC1.CP33
  BOTTOM w0.102: JWLAN.51 220.33,6.55 220.48,6.4 220.64,6.4 v3(220.83,6.59)
CNVI_WT_DATA1_DP: length 148.8
  IN2 w0.127: v3(109.29,35.32) 109.89,35.32 110.14,35.07 110.14,31.91 110.21,31.85 110.54,31.85 110.8,31.58 110.8,30.98 110.5,30.68 109.69,30.68 109.6,30.59 109.6,30.27 109.71,30.16 110.52,30.16 110.8,29.88 110.8,29.12 110.54,28.86 109.78,28.86 109.61,28.69 109.61,28.44 109.79,28.26 110.56,28.26 110.8,28.02 110.8,27.72 110.9,27.62 118.26,27.62 118.76,28.12 121.11,28.12 122.03,27.2 125.78,27.2 127.92,25.06 133.85,25.06 134.89,24.02 138.79,24.02 141.94,20.87 158.24,20.87 158.64,21.28 159.54,21.28 159.94,20.87 208.01,20.87 213.06,15.83 213.24,15.83 213.82,16.41 214.21,16.41 214.68,15.94 214.68,15.55 214.1,14.97 214.1,14.79 215.37,13.52 217.12,13.52 220.37,10.27 220.37,8.9 222.19,7.07 222.19,6.32 221.88,6.01 v3(220.83,6.01)
  BOTTOM w0.076: v3(109.29,35.32) 108.39,35.32 108.28,35.44 108.28,38.13 106.73,39.68 106.73,40.38 106.06,41.37 106.03,41.45 106.03,41.73 106.04,41.74 106.04,42.34 UC1.CN33
  BOTTOM w0.102: v3(220.83,6.01) 220.66,6.18 220.47,6.18 220.34,6.05 JWLAN.53
COMP_CORE: length 4.9
  BOTTOM w0.102: PRZ45.2 200.06,65.63 v1(199.04,64.61)
  BOTTOM w0.203: PUZ1.4 199.61,67.98 200.06,67.53 PCZ12.2
  BOTTOM w0.254: PCZ12.2 PRZ45.2
COMP_GT: length 4.8
  BOTTOM w0.203: PCZ20.1 194.42,76.52 194.74,76.21 v1(195.44,76.21) 196.08,76.21 196.81,75.48 PUZ1.26
  BOTTOM w0.254: PCZ20.1 PRZ54.1
COMP_SA: length 3.4
  BOTTOM w0.203: PUZ1.43 202.44,71.78 202.57,71.91 v1(202.88,71.91)
  BOTTOM w0.254: PRZ10.2 PCZ6.2 203.82,71.72 203.07,71.72 v1(202.88,71.91)
CORE1_BST: length 0.8
  TOP w0.102: v3(173.77,66.67) v2(173.77,65.87)
CORE1_BST_R: length 1.1
  BOTTOM w0.102: PRZ76.2 v1(170.43,67.2)
CORE1_LG: length 24.2
  TOP w0.102: v3(176.64,65.05) 176.2,65.05 v2(175.88,64.73)
  IN2 w0.508: 175.37,64.41 174.73,63.77 168.51,63.77 167.5,64.79 167.5,69.59 166.99,70.1 165.08,70.1 164.45,69.46 159.72,69.46 159.49,69.24 158.1,69.24
  vias: v3(157.21,69.49) v3(157.21,68.85) v3(177.22,65.05)
CORE1_LX: length 14.8
  TOP w0.102: PRZ82.1 v2(169.06,74.76)
  IN1 w0.762: 171.43,67.33 171.43,71.9 170.54,72.79 163.69,72.79
  vias: v3(162.67,72.66) v3(172.13,65.17) v3(172.77,65.17)
CORE1_SNUB: length 2.1
  TOP w0.102: PRZ82.2 v2(169.05,72.09)
CORE1_UG: length 16.9
  TOP w0.102: v3(172.32,66.31) v2(172.32,67.08)
  IN1 w0.762: v3(163.18,75.2) 170.29,75.2 172.7,72.79 172.7,67.2
  vias: v3(172.77,65.87)
CORE2_BST: length 1.3
  BOTTOM w0.102: PRZ77.1 v1(174.82,63.39)
CORE2_BST_R:
  vias: v1(171.09,63.69)
CORE2_LG: length 13.8
  TOP w0.102: v3(176.64,61.23) v2(175.83,61.23)
  IN2 w0.508: 175.5,62.38 174.99,62.89 167.5,62.89 164.83,65.55 163.81,65.55
  vias: v3(162.67,65.93) v3(162.67,65.3) v3(177.27,61.23)
CORE2_LX: length 8.8
  TOP w0.102: PRZ84.1 v2(159.37,60.79)
  IN1 w0.635: 163.56,61.36 170.29,61.36
  vias: v3(162.67,61.62) v3(162.67,60.98) v3(172.26,61.23) v3(172.86,61.23)
CORE2_SNUB: length 2
  TOP w0.102: PRZ84.2 v2(159.42,63.46)
CORE2_UG: length 9.6
  TOP w0.102: v3(172.89,61.93) v2(172.89,62.8)
  IN1 w0.508: 165.08,66.19 165.08,63.14 166.01,62.21 170.38,62.21
  vias: v3(164.7,67.2) v3(165.34,67.2) v3(172.26,61.93)
CORE2_UG_R: length 0.9
  TOP w0.102: v3(163.32,64.52) v2(164.23,64.52)
CPU_C10_GATE#: length 2.8
  TOP w0.102: RC985.2 108.82,43.2 109.33,43.71 v3(109.33,43.96)
  BOTTOM w0.076: v3(109.33,43.96) 109.33,43.36 109.29,43.32 109.29,42.78 UC1.CN27
CPU_POPIRCOMP: length 11.8
  TOP w0.254: 105.68,52.31 105.81,52.44 106.11,52.44 106.54,52.88 107.97,52.88 108.05,52.8 109.01,52.8 109.36,53.14 v3(109.36,53.36)
  TOP w0.305: 105.68,52.31 105.07,51.71 104.73,51.71 104.35,51.32 v1(103.55,51.32) 102.63,51.32 102.28,51.67 101.77,51.67 101.09,52.35 RC5.1
  BOTTOM w0.203: UC1.BP27 109.37,53.6 109.37,53.36 v3(109.36,53.36)
CPU_XDP_TCK0: length 11.5
  TOP w0.076: 124.8,86.91 124.8,85.96 v2(124.55,85.71) 124.18,85.34 124.18,82.12 124.74,81.57 124.74,79.69 123.75,78.71 123.33,78.71 122.82,78.2 v3(122.82,78.14)
  TOP w0.102: RC398.1 124.8,86.91
  BOTTOM w0.076: UC1.P6 v3(122.82,78.14) UC1.T6
CPVEE: length 2.9
  TOP w0.203: UA1.27 20.61,34.49 20.65,34.45 20.65,32.92 20.39,32.67 CA15.2
CS_DDR: length 5.2
  TOP w0.254: v3(14.19,77.24) v2(13.39,76.44) 12.1,75.14 v3(11.4,75.14)
  BOTTOM w0.203: v3(11.4,75.14) 11.38,75.15 PUM1.13 ; PRM2.2 v3(14.19,77.24)
D_MIC_CLK: length 93.8
  TOP w0.102: LA6.2 CA41.1 22.11,44.47 v3(22.29,44.29)
  IN2 w0.127: v3(50.35,100.04) 50.49,99.9 50.49,99.45 50.26,99.22 43.52,99.22 40.51,96.21 29.17,96.21 24.44,91.48 24.44,50.7 26.13,49 26.13,47.45 v3(25.99,47.31)
  BOTTOM w0.102: v3(25.99,47.31) 26.14,47.16 26.14,46.22 26.04,46.12 25.13,46.12 23.86,44.85 23.86,44.39 23.76,44.29 v3(22.29,44.29) ; v3(50.35,100.04) 50.5,100.2 50.5,100.71 51.56,101.76 51.9,101.76 52,101.86 52,102.38 DM1.2 53.03,101.76 56.98,101.76 57.89,100.85 57.89,100.46 58,100.35 JEDP.29
D_MIC_CLK_R: length 2.9
  TOP w0.102: LA6.1 21.7,42.61 v1(21.7,41.68) 21.22,41.21 21.22,40.92 21.01,40.71 UA1.3
D_MIC_DATA: length 104.1
  TOP w0.102: v3(21.64,41.05) 21.64,40.91 21.41,40.68 UA1.2 ; v3(50.94,100.04) v2(52.27,100.04)
  IN2 w0.127: v3(50.94,100.04) 50.8,99.9 50.8,99.32 50.39,98.91 43.65,98.91 40.64,95.91 29.29,95.91 24.74,91.35 24.74,50.83 26.44,49.13 26.44,47.45 v3(26.58,47.31)
  BOTTOM w0.102: v3(21.64,41.05) 21.25,40.66 17.99,40.66 17.73,40.92 17.73,41.39 19.67,43.33 21.92,43.33 22.61,44.01 23.87,44.01 24.14,44.28 24.14,44.74 25.24,45.84 26.16,45.84 26.42,46.11 26.42,47.16 v3(26.58,47.31) ; JEDP.30 57.5,100.34 57.61,100.45 57.61,100.74 56.86,101.48 53.03,101.48 DM1.3 52,100.86 52,101.38 51.9,101.48 51.67,101.48 50.78,100.59 50.78,100.2 v3(50.94,100.04)
DDI2_HPD: length 3.5
  TOP w0.076: T408.1 122.27,41.55 122.66,41.94 122.66,43.65 v3(122.94,43.93)
  BOTTOM w0.076: UC1.CM6 v3(122.94,43.93)
DDI3_HPD: length 2.8
  BOTTOM w0.076: UC1.CP7 122.25,41.77 122.25,41.47 122.71,41.01 122.71,39.59 T2404.1
DDR_DRAMRST#: length 156.1
  TOP w0.102: v3(86.14,41.93) 85.38,41.17 CC359.1 85.38,40.28 RC32.2 85.19,40.23 v3(84.69,40.72) ; v3(66.28,23.29) v2(67.27,23.29) ; CD92.1 v3(52.23,66.07) ; CD10.1 39,66.08 v3(39.73,66.08)
  IN2 w0.076: 91.68,44.37 92.04,44.72 96.36,44.72 97.88,46.25 98.88,48.41 98.88,51.3 99.17,51.59 99.17,53.11 99.38,53.31 99.85,53.31 102.06,55.52 102.16,55.52 102.57,55.94 102.57,56.06 102.81,56.3 103.66,56.3 104.16,55.8 104.16,54.02 105.24,52.94 106.45,52.94 106.65,52.74 106.89,52.74 v3(107.25,52.38)
  IN2 w0.127: 91.68,44.37 91.1,43.78 89.88,42.57 86.77,42.57 v3(86.14,41.93) ; v3(52.23,66.07) 52.15,66.16 49.2,66.16 48.72,65.68 42.28,65.68 41.68,66.28 39.93,66.28 v3(39.73,66.08) 39.73,65.93 40.62,65.04 40.62,28.6 37.27,25.24 v3(37.27,22.75) ; v3(84.69,40.72) 84.69,40.36 67.62,23.29 v3(66.28,23.29)
  BOTTOM w0.076: v3(107.25,52.38) 106.97,51.97 UC1.BU31
  BOTTOM w0.102: JDIMM2.108 40.05,66.03 39.99,66.08 v3(39.73,66.08) ; v3(52.23,66.07) 52.59,65.71 53.2,65.71 53.51,66.03 JDIMM1.108 ; v3(37.27,22.75) 37.58,22.45 65.72,22.45 66.28,23.01 v3(66.28,23.29)
DDR_M0_ACT#: length 68.7
  IN1 w0.076: v3(100.89,76.93) 100.69,77.13 99.93,77.49 97.84,77.49 96.92,76.57 92.02,76.57 89.38,79.22 89.38,81.48 89.01,81.85
  IN1 w0.157: v3(57.23,66.63) 56.79,66.2 55.73,66.2 55.34,66.58 55.34,71.06 55.86,71.58 64.55,71.58 74.95,81.98 88.87,81.98 89.01,81.85
  BOTTOM w0.076: v3(100.89,76.93) 100.89,77.01 101.26,77.37 102.04,77.37 102.63,76.78 102.84,76.78 103,76.63 103.41,76.63 103.53,76.67 103.73,76.67 104.19,76.5 UC1.V35
  BOTTOM w0.127: v3(57.23,66.63) 56.01,65.41 55.99,65.41 55.1,64.53 JDIMM1.114
DDR_M0_ALERT#: length 69.7
  IN1 w0.076: 87.65,79.43 87.95,79.43 91.76,75.62 98.39,75.62 v3(98.78,76)
  IN1 w0.157: v3(55.96,63.5) 55.95,63.5 55.84,63.39 53.62,63.39 53.21,62.99 51.34,62.99 51.08,63.25 51.08,65.3 51.21,65.43 52.61,65.43 52.98,65.79 56.96,65.79 57.24,66.06 59.81,66.06 61.84,68.09 64.54,68.09 75.89,79.43 87.65,79.43
  BOTTOM w0.076: 101.32,76.39 101.64,76.07 101.8,76.07 102,75.87 103.2,75.87 UC1.W37
  BOTTOM w0.089: 101.32,76.39 98.99,76.39 98.78,76.17 v3(98.78,76)
  BOTTOM w0.127: v3(55.96,63.5) 55.96,63.9 55.83,64.03 JDIMM1.116
DDR_M0_BA0: length 64.6
  IN1 w0.076: v3(106.02,76.11) 105.99,76.08 105.19,76.08 102.6,73.49 101.43,73.49 98.4,70.47 92.34,70.47 90.75,72.05 89.01,72.05
  IN1 w0.157: v3(59.55,55.2) 59.58,55.17 64.5,55.17 73.3,63.96 73.9,63.96 74.13,64.2 74.13,64.8 74.33,65 74.64,65 74.72,64.92 74.94,64.92 75.17,65.14 75.17,65.36 75.09,65.44 75.09,65.67 75.31,65.89 75.53,65.89 75.61,65.81 75.84,65.81 76.06,66.03 76.06,66.25 75.98,66.34 75.98,66.56 76.2,66.78 76.42,66.78 76.5,66.7 76.73,66.7 76.95,66.92 76.95,67.14 76.87,67.23 76.87,67.45 77.09,67.67 77.31,67.67 77.4,67.59 77.62,67.59 82.08,72.05 89.01,72.05
  BOTTOM w0.076: v3(106.02,76.11) 106.01,76.09 UC1.W32
  BOTTOM w0.127: JDIMM1.150 54.92,53.53 55.86,54.07 55.97,54.14 56.88,54.35 57.82,54.35 59.21,54.86 v3(59.55,55.2)
DDR_M0_BA1: length 67.2
  IN1 w0.076: v3(106.74,74.28) 106.74,74.28 106.38,74.64 105.94,74.64 105.37,74.07 105.22,74.07 103.4,72.25 102.05,72.25 101.06,71.26 101.06,71.2 99.09,69.22 92.65,69.22 91.46,70.4 89.01,70.4
  IN1 w0.157: 89.01,70.4 82.85,70.4 75.54,63.1 75.54,62.87 75.96,62.45 75.96,62.22 75.74,62 75.52,62 75.09,62.43 74.87,62.43 74.67,62.23 74.67,62 75.09,61.58 75.09,61.35 74.87,61.13 74.65,61.13 74.22,61.56 74,61.56 73.78,61.33 73.78,61.11 74.2,60.68 74.2,60.46 73.98,60.24 73.76,60.24 73.33,60.67 73.11,60.67 72.88,60.44 72.88,60.22 73.31,59.79 73.31,59.57 73.09,59.35 72.87,59.35 72.44,59.78 72.22,59.78 71.98,59.54 71.98,58.3 71.55,57.87 69.72,57.87 65.25,53.4 59.9,53.4 v3(59.86,53.44)
  BOTTOM w0.076: UC1.AB31 v3(106.74,74.28)
  BOTTOM w0.127: v3(59.86,53.44) 59.86,53.57 61.06,54.78 JDIMM1.145
DDR_M0_BG0: length 67.3
  IN1 w0.076: v3(101.48,76.92) 101.48,77.13 101.84,77.49 102.22,77.49 102.66,77.05 102.66,76.47 102.47,76.28 101.52,76.28 101.33,76.47 97.96,76.47 97.57,76.08 91.77,76.08 88.7,79.15 88.7,79.72
  IN1 w0.157: 88.7,79.72 88.14,80.28 75.57,80.28 65.23,69.94 60.42,69.94 60.26,69.78 60.26,68.27 60.11,68.12 59.39,68.12 58.91,68.6 57.75,68.6 57.59,68.44 57.59,67.22 57.75,67.07 58.06,67.07 v3(58.5,66.63)
  BOTTOM w0.076: UC1.V34 104.68,76.14 104.2,76.14 104.08,76.18 103.84,76.18 103.73,76.14 103.55,76.14 103.36,76.21 102.26,76.21 102.25,76.22 102.14,76.22 101.56,76.8 101.56,76.84 v3(101.48,76.92)
  BOTTOM w0.127: v3(58.5,66.63) 59.12,65.75 60.41,64.45 61.07,64.45 61.53,64.28 JDIMM1.115
DDR_M0_BG1: length 68.5
  IN1 w0.076: 88.12,79.72 88.32,79.51 88.32,79.29 91.7,75.91 98.13,75.91 v3(98.19,75.97)
  IN1 w0.157: v3(59.77,66.63) 59.82,66.69 59.82,66.91 59.66,67.07 58.64,67.07 58,67.71 58,67.93 58.26,68.19 58.74,68.19 59.22,67.7 60.18,67.7 60.43,67.46 60.62,67.46 60.94,67.78 60.94,67.97 60.67,68.23 60.67,69.33 60.83,69.49 61.2,69.49 61.32,69.36 61.32,68.62 61.45,68.49 61.76,68.49 61.91,68.65 61.91,69.37 62.07,69.53 62.39,69.53 62.54,69.37 62.54,68.66 62.7,68.5 63.02,68.5 63.17,68.66 63.17,69.37 63.33,69.53 63.65,69.53 63.8,69.37 63.8,68.66 63.96,68.5 64.37,68.5 64.49,68.61 64.49,69.37 64.64,69.53 65.4,69.53 65.69,69.82 75.71,79.84 87.99,79.84 88.12,79.72
  BOTTOM w0.076: 102.12,76.05 103.33,76.04 103.52,75.98 103.76,75.98 103.87,76.02 104.06,76.02 104.52,75.85 UC1.W35
  BOTTOM w0.089: 102.12,76.05 102.07,76.05 101.87,76.24 101.72,76.24 101.39,76.57 98.71,76.57 98.19,76.05 v3(98.19,75.97)
  BOTTOM w0.127: JDIMM1.113 61.63,64.78 61.51,64.9 60.51,64.9 60.31,65.1 60.31,65.28 60.48,65.45 60.48,65.63 60.3,65.81 60.12,65.81 59.95,65.64 59.77,65.64 59.55,65.86 59.55,66.41 v3(59.77,66.63)
DDR_M0_CKE0: length 66.6
  IN1 w0.076: 89.01,80.28 89.01,79.07 91.84,76.24 97.5,76.24 98.18,76.93 v3(99.02,76.93)
  IN1 w0.157: 89.01,80.28 88.39,80.89 75.31,80.89 64.97,70.56 56.52,70.56 56.37,70.4 56.37,69.94 56.52,69.78 57,69.78 57.16,69.62 57.16,69.37 57.32,69.21 57.63,69.21 57.79,69.37 57.79,69.62 57.95,69.78 58.26,69.78 58.42,69.62 58.42,69.37 58.58,69.21 58.89,69.21 59.05,69.37 59.05,69.62 59.21,69.78 59.49,69.78 59.65,69.62 59.65,68.73 v3(59.83,68.55)
  BOTTOM w0.076: UC1.U36 103.41,77.36 103.16,77.32 103.16,77.32 102.95,77.11 102.77,77.11 102.18,77.7 99.66,77.7
  BOTTOM w0.089: 99.66,77.7 99.02,77.06 v3(99.02,76.93)
  BOTTOM w0.127: JDIMM1.109 61.59,65.78 59.83,67.54 v3(59.83,68.55)
DDR_M0_CKE1: length 65.9
  IN1 w0.076: v3(99.64,76.93) 99.73,77.02 99.73,77.2 99.6,77.32 97.93,77.32 97.01,76.41 91.94,76.41 89.21,79.13 89.21,80.78 89.01,80.99
  IN1 w0.157: v3(55.96,66.63) 55.96,66.95 56.11,67.1 56.82,67.1 56.98,67.26 56.98,67.58 56.82,67.73 56.11,67.73 55.96,67.89 55.96,68.21 56.11,68.36 56.76,68.36 56.92,68.52 56.92,68.84 56.76,68.99 56.11,68.99 55.96,69.15 55.96,70.81 56.11,70.97 64.8,70.97 75.2,81.37 88.62,81.37 89.01,80.99
  BOTTOM w0.076: UC1.U37 103.02,76.95 103.02,76.95 102.7,76.95 102.11,77.53 100.13,77.53 99.72,77.12 99.72,77.01 v3(99.64,76.93)
  BOTTOM w0.127: v3(55.96,66.63) 55.96,66.21 55.27,65.53 JDIMM1.110
DDR_M0_CLK0: length 65.6
  IN1 w0.076: 89.01,72.7 89.02,72.7 89.04,72.73 89.1,72.73 89.13,72.75 90.29,72.75 92.4,70.63 92.45,70.63 92.49,70.67 98.23,70.67 100.1,72.54 100.16,72.54 101.94,74.32 102.73,74.32 104.88,76.47 106.32,76.47 106.61,76.76 106.61,76.89 v3(106.76,77.05)
  IN1 w0.127: 89.01,72.7 81.81,72.7 81.43,72.32 81.04,72.32 80.97,72.38 80.79,72.38 80.52,72.11 80.52,71.93 80.59,71.87 80.59,71.48 80.17,71.06 79.78,71.06 79.71,71.13 79.54,71.13 79.27,70.85 79.27,70.68 79.33,70.61 79.33,70.22 78.91,69.8 78.52,69.8 78.46,69.87 78.28,69.87 78.01,69.6 78.01,69.42 78.07,69.35 78.07,68.96 77.65,68.55 77.26,68.55 77.2,68.61 77.02,68.61 64.43,56.02 61.93,56.02 61.73,55.82 59.74,55.82 59.45,56.11 v3(59.45,56.69)
  BOTTOM w0.076: UC1.V31 v3(106.76,77.05)
  BOTTOM w0.102: JDIMM1.137 59.96,58.78 59.5,58.32 59.5,56.74 v3(59.45,56.69)
DDR_M0_CLK1: length 64.8
  IN1 w0.076: v3(106.73,77.95) 106.66,77.95 106.18,77.47 105.78,77.47 105.3,76.99 104.67,76.99 103.27,75.59 102.66,75.59 98.76,71.68 92.36,71.68 90.43,73.62 89.05,73.62 89.02,73.59 89.01,73.59
  IN1 w0.127: 89.01,73.59 80.74,73.59 64.51,57.35 58.34,57.35 58.12,57.13 58.12,56.75 v3(58.18,56.69)
  BOTTOM w0.076: UC1.T31 v3(106.73,77.95)
  BOTTOM w0.102: v3(58.18,56.69) 58.18,57.31 56.96,58.53 JDIMM1.138
DDR_M0_CLK#0: length 65.6
  IN1 w0.076: 89.01,72.95 90.37,72.95 92.49,70.84 98.16,70.84 101.85,74.52 102.65,74.52 104.8,76.67 106.23,76.67 106.4,76.84 106.4,77.18 106.33,77.25 106.15,77.25 v3(106.01,77.11)
  IN1 w0.127: v3(60.13,56.69) 60.04,56.69 59.7,56.35 59.7,56.22 59.84,56.08 61.63,56.08 61.83,56.28 64.33,56.28 76.91,68.86 77.3,68.86 77.37,68.8 77.55,68.8 77.82,69.07 77.82,69.25 77.75,69.31 77.75,69.7 78.17,70.12 78.56,70.12 78.63,70.06 78.81,70.06 79.08,70.33 79.08,70.51 79.01,70.57 79.01,70.96 79.43,71.38 79.82,71.38 79.88,71.32 80.06,71.32 80.33,71.59 80.33,71.76 80.27,71.83 80.27,72.22 80.69,72.64 81.08,72.64 81.14,72.57 81.32,72.57 81.7,72.95 89.01,72.95
  BOTTOM w0.076: UC1.V32 v3(106.01,77.11)
  BOTTOM w0.102: v3(60.13,56.69) 59.72,57.11 59.72,58.23 60.05,58.56 61.38,58.56 61.66,58.27 JDIMM1.139
DDR_M0_CLK#1: length 64.8
  IN1 w0.076: 89.01,73.84 89.02,73.84 89.05,73.82 90.52,73.82 92.45,71.89 98.67,71.89 102.58,75.79 103.19,75.79 104.58,77.19 105.22,77.19 105.7,77.67 106.09,77.67 106.17,77.75 106.17,77.87 v3(106.09,77.94)
  IN1 w0.127: v3(57.54,56.69) 57.86,57.01 57.86,57.23 58.24,57.61 64.4,57.61 80.64,73.84 89.01,73.84
  BOTTOM w0.076: UC1.T32 v3(106.09,77.94)
  BOTTOM w0.102: v3(57.54,56.69) 57.6,56.69 57.96,57.05 57.96,57.22 56.87,58.31 55.48,58.31 55.19,58.03 JDIMM1.140
DDR_M0_CS#0: length 69.3
  IN1 w0.076: 89.01,68.14 89.14,68.14 92.97,68.38 100.27,68.38 102.19,70.3 104.59,71.14 106.25,71.14 v3(106.64,71.52)
  IN1 w0.157: v3(58.37,51.06) 58.8,50.63 59.18,50.63 59.72,50.09 67.84,50.09 68.29,50.55 68.29,50.77 67.79,51.27 67.79,51.49 68.01,51.72 68.24,51.72 68.74,51.21 68.96,51.21 69.57,51.82 69.57,52.04 68.63,52.98 68.63,53.2 68.86,53.42 69.08,53.42 69.61,52.89 69.83,52.89 70.05,53.12 70.05,53.34 69.5,53.89 69.5,54.11 69.73,54.33 69.95,54.33 70.5,53.78 70.72,53.78 85.08,68.14 89.01,68.14
  BOTTOM w0.076: UC1.AE32 106.64,71.7 v3(106.64,71.52)
  BOTTOM w0.127: JDIMM1.149 61.56,53.78 60.52,53.41 60.09,52.98 59.79,52.98 59.29,52.48 v3(58.37,51.06)
DDR_M0_CS#1: length 68.4
  IN1 w0.076: 89.01,67.32 93.08,68.02 97.01,68.02 98.93,67.5 99.71,67.5 100.99,67.66 101.12,67.74 104.85,70.47 104.88,70.51 v3(106.06,70.61)
  IN1 w0.157: 89.01,67.32 85.42,67.32 73.76,55.66 73.39,54.48 67.98,49.07 62.34,49.07 62.05,48.78 55.67,48.78 55.56,48.89 55.56,49.37 55.67,49.49 57.02,49.49 v3(57.03,49.5)
  BOTTOM w0.076: UC1.AF32 106.04,70.72 106.06,70.61 v3(106.06,70.61)
  BOTTOM w0.127: JDIMM1.157 61.65,51.78 61.41,51.54 61.41,51.53 60.89,51.01 59.92,50.62 59.6,50.62 57.38,49.84 v3(57.03,49.5)
DDR_M0_D0: length 72
  IN1 w0.127: v3(59.31,92.75) 59.67,93.11 59.67,94.07 59.8,94.2 60.1,94.2 60.23,94.33 60.23,94.58 60.1,94.71 59.29,94.71 59.16,94.84 59.16,95.11 59.29,95.23 60.38,95.23 60.51,95.36 60.51,95.61 60.38,95.74 59.8,95.74 59.67,95.87 59.67,96.19 60.69,97.2 61.14,97.2 61.27,97.07 61.27,96.92 61.4,96.79 61.65,96.79 61.78,96.92 61.78,97.07 61.91,97.2 84.69,97.2 85.39,97.9 106.11,97.9 109.84,94.17 109.84,92.06 109.7,91.93 v3(109.69,91.93)
  BOTTOM w0.076: 109.82,91.28 109.82,91.02 110.12,90.71 110.12,89.79 110.33,89.58 110.33,87.2 110.12,87 110.12,86.24 UC1.A26
  BOTTOM w0.102: v3(109.69,91.93) 109.69,91.4 109.82,91.28 ; v3(59.31,92.75) 60.79,91.28 JDIMM1.7
DDR_M0_D1: length 73.3
  IN1 w0.127: v3(108.22,93.31) 108.22,93.52 106.03,95.71 104.47,95.71 104.34,95.84 104.34,96.15 104.21,96.27 103.96,96.27 103.83,96.15 103.83,95.84 103.7,95.71 103.45,95.71 103.32,95.84 103.32,96.15 103.2,96.27 102.94,96.27 102.82,96.15 102.82,95.84 102.69,95.71 102.43,95.71 102.31,95.84 102.31,96.15 102.18,96.27 100.86,96.27 100.73,96.15 100.73,95.8 100.61,95.68 100.34,95.68 100.21,95.8 100.21,96.16 100.08,96.29 94.26,96.29 94.13,96.16 94.13,95.73 94,95.6 93.75,95.6 93.62,95.73 93.62,96.16 93.49,96.29 86.11,96.29 85.42,95.6 65.73,95.6 60.96,90.83 56.91,90.83 v3(55.53,89.45)
  BOTTOM w0.076: UC1.D26 110.31,84.18 110.56,84.43 110.56,85.79 110.6,85.86 110.65,85.94 110.65,86.35 110.48,86.52 110.48,86.86 110.48,86.86 110.48,86.87 110.66,87.05 110.66,89.72 110.47,89.91 110.47,90.83 110.42,90.88 110.42,90.89 ; 110.42,91.79 110.42,92.24 109.46,93.2 108.33,93.2 v3(108.22,93.31)
  BOTTOM w0.102: 110.42,90.89 110.42,91.79 ; JDIMM1.16 55.11,89.02 v3(55.53,89.45)
DDR_M0_D2: length 72.8
  IN1 w0.127: v3(109.62,89.45) 110.35,90.18 110.35,91.34 110.52,91.52 110.52,94.42 106.38,98.56 85.01,98.56 84.39,97.94 60.31,97.94 55.51,93.13 v3(55.51,92.74)
  BOTTOM w0.076: UC1.D28 109.65,84.23 109.69,84.23 109.89,84.43 109.89,85.15 109.76,85.47 109.87,85.8 109.77,86.09 109.77,87.11 109.83,87.17 110,87.34 110,88.31 109.56,88.75 109.56,89.39 v3(109.62,89.45)
  BOTTOM w0.102: JDIMM1.4 55.13,92.03 55.51,92.4 v3(55.51,92.74)
DDR_M0_D3: length 72.6
  IN1 w0.076: v3(108.28,88.31) 108.28,88.19 108.57,87.9 109,87.9 109.08,87.98 109.08,88.48
  IN1 w0.127: v3(59.34,89.45) 59.35,89.46 61,89.46 63.88,92.34 64.06,92.34 64.6,91.8 64.78,91.8 64.96,91.98 64.96,92.16 64.42,92.7 64.42,92.88 64.65,93.11 64.83,93.11 66.19,91.75 66.37,91.75 66.55,91.93 66.55,92.11 65.19,93.47 65.19,93.65 65.37,93.83 65.55,93.83 66.91,92.47 67.09,92.47 67.27,92.65 67.27,92.83 67.15,92.95 67.15,93.13 67.33,93.31 67.51,93.31 67.63,93.19 67.81,93.19 69.15,94.53 104,94.53 105.44,93.09 105.79,93.09 106.14,92.75 106.92,92.75 107.25,92.42 107.25,90.23 107.27,90.2 107.27,89.02 107.59,88.7 108.95,88.7 109.08,88.58 109.08,88.48
  BOTTOM w0.076: UC1.C28 108.61,85.15 108.61,85.74 108.58,85.81 108.57,85.84 108.55,85.89 108.51,85.93 108.51,87.03 108.45,87.08 108.45,88.13 v3(108.28,88.31)
  BOTTOM w0.102: v3(59.34,89.45) 60.01,88.78 JDIMM1.17
DDR_M0_D4: length 70.4
  IN1 w0.127: v3(109.42,92.54) 109.51,92.63 109.51,94.03 105.97,97.57 85.53,97.57 84.83,96.87 64.22,96.87 64.1,96.74 64.1,95.76 63.97,95.63 63.72,95.63 63.59,95.76 63.59,96.74 63.46,96.87 63.11,96.87 61.31,95.06 61.31,94.88 61.87,94.32 61.87,94.14 61.68,93.95 61.5,93.95 60.94,94.51 60.76,94.51 60.56,94.32 60.56,94.13 60.92,93.77 60.92,93.59 60.79,93.45 60.61,93.45 60.31,93.74 60.13,93.74 60,93.62 60,93.33 v3(60.58,92.75)
  BOTTOM w0.076: UC1.B26 110.39,85.65 110.39,85.85 110.48,85.98 110.48,86.28 110.32,86.45 110.32,86.96 110.49,87.13 110.49,89.65 110.29,89.85 110.29,90.77 110.12,90.95 110.12,91.28
  BOTTOM w0.102: JDIMM1.3 62.5,92.27 61.06,92.27 v3(60.58,92.75) ; 110.12,91.28 110.12,92.07 109.65,92.54 v3(109.42,92.54)
DDR_M0_D5: length 72.2
  IN1 w0.127: v3(109.62,90.05) 110.02,90.46 110.02,91.48 110.19,91.66 110.19,94.28 106.25,98.23 85.22,98.23 84.59,97.59 60.43,97.59 58.75,95.91 58.75,95.73 58.78,95.7 58.78,95.52 58.6,95.34 58.42,95.34 58.39,95.37 58.21,95.37 56.35,93.5 56.35,93.17 v3(56.78,92.74)
  BOTTOM w0.076: UC1.C26 110.08,84.98 110.08,85.11 109.94,85.48 110.05,85.8 109.96,86.05 109.96,87.07 110.16,87.27 110.16,89.51 109.95,89.72 109.95,89.89 109.8,90.05 109.62,90.05 v3(109.62,90.05)
  BOTTOM w0.102: v3(56.78,92.74) 56.78,92.57 55.24,91.03 JDIMM1.8
DDR_M0_D6: length 72.1
  IN1 w0.127: v3(58.07,89.45) 58.49,89.86 60.93,89.86 66.01,94.94 66.4,94.94 66.58,94.77 66.58,94.59 66.01,94.02 66.01,93.84 66.19,93.66 66.37,93.66 66.92,94.21 67.13,94.21 67.66,93.68 67.84,93.68 68.08,93.92 68.08,94.1 67.83,94.35 67.83,94.53 68.01,94.71 68.19,94.71 68.44,94.46 68.62,94.46 69.08,94.93 104.07,94.93 105.57,93.43 105.93,93.43 106.27,93.08 107.05,93.08 107.58,92.55 107.58,90.33 107.6,90.31 107.6,89.16 107.73,89.03 109.08,89.03 109.2,89.16 109.2,89.43 109.08,89.56 108.4,89.56 v3(108.33,89.48)
  BOTTOM w0.076: v3(108.33,89.48) 108.63,89.17 108.63,87.14 108.84,86.93 108.84,86.47 108.67,86.3 108.67,86 108.74,85.88 108.93,85.54 UC1.B28
  BOTTOM w0.102: JDIMM1.21 60.71,87.78 58.63,88.89 v3(58.07,89.45)
DDR_M0_D7: length 70.9
  IN1 w0.127: v3(56.8,89.45) 56.62,89.62 56.62,89.86 56.74,89.97 57.75,89.97 57.88,90.1 57.88,90.37 58.01,90.5 58.52,90.5 58.64,90.37 58.64,90.32 58.77,90.2 59.02,90.2 59.15,90.32 59.15,90.37 59.28,90.5 59.53,90.5 59.66,90.37 59.66,90.32 59.79,90.2 60.04,90.2 60.17,90.32 60.17,90.37 60.29,90.5 61.1,90.5 65.87,95.27 95.01,95.27 95.13,95.4 95.13,95.83 95.26,95.96 95.51,95.96 95.64,95.83 95.64,95.4 95.77,95.27 96.54,95.27 96.67,95.4 96.67,95.83 96.8,95.96 97.05,95.96 97.18,95.83 97.18,95.4 97.31,95.27 97.56,95.27 97.69,95.4 97.69,95.83 97.81,95.96 98.07,95.96 98.19,95.83 98.19,95.4 98.32,95.27 98.55,95.27 98.68,95.4 98.68,95.52 98.8,95.65 99.02,95.65 99.15,95.52 99.15,95.4 99.27,95.27 105.22,95.27 105.62,94.87 105.62,94.69 105.29,94.35 105.29,94.17 105.47,93.99 105.65,93.99 105.98,94.33 106.16,94.33 106.98,93.52 107.08,93.52 107.91,92.69 107.91,90.44 108.23,90.11 v3(108.33,90.11)
  BOTTOM w0.076: UC1.A28 109.02,86.42 109.02,86.98 108.8,87.2 108.8,89.64 v3(108.33,90.11)
  BOTTOM w0.102: v3(56.8,89.45) 55.38,88.02 JDIMM1.20
DDR_M0_D8: length 65.1
  IN1 w0.127: v3(105.98,92.18) 105.58,92.59 105.22,92.59 103.79,94.02 69.36,94.02 66.56,91.22 63.48,91.22 61.11,88.86 55.08,88.86 54.95,88.73 54.95,87.79 55.08,87.67 v3(55.71,87.67)
  BOTTOM w0.076: 107.16,88.69 107.97,87.88 107.97,86 107.87,85.82 107.87,85.75 107.8,85.57 UC1.B30
  BOTTOM w0.102: 107.16,88.69 107.16,90.86 105.98,92.04 v3(105.98,92.18) ; JDIMM1.24 55.2,87.02 55.71,87.54 v3(55.71,87.67)
DDR_M0_D9: length 66.7
  IN1 w0.127: v3(59.52,87.67) 61.32,87.67 61.65,88 61.83,88 62.07,87.75 62.25,87.75 62.43,87.93 62.43,88.11 62.19,88.36 62.19,88.54 62.39,88.74 62.57,88.74 63.59,87.72 63.77,87.72 64.22,88.16 64.22,88.34 63.24,89.33 63.24,89.51 63.42,89.69 63.6,89.69 64.92,88.36 65.1,88.36 69.77,93.03 101.95,93.03 102.46,92.53 102.64,92.53 102.89,92.79 103.07,92.79 103.25,92.61 103.25,92.43 103,92.17 103,91.99 103.55,91.43 103.77,91.43 v3(104.02,91.68)
  BOTTOM w0.076: 105.52,90.06 105.52,89.05 106.15,88.41 106.15,87.65 106.54,87.27 106.54,87.08 106.85,86.76 106.85,86.04 106.81,85.93 106.81,85.69 106.82,85.67 106.84,85.64 106.84,85.34 106.83,85.33 106.78,85.21 106.78,84.4 106.99,84.18 UC1.D30
  BOTTOM w0.102: 105.52,90.06 105.23,90.35 104.97,90.35 104.02,91.3 v3(104.02,91.68) ; JDIMM1.25 60.04,86.78 59.52,87.29 v3(59.52,87.67)
DDR_M0_D10: length 65
  IN1 w0.127: v3(102.63,89.78) 102.15,90.25 102.15,90.61 101.01,91.76 70.3,91.76 64.94,86.4 60.43,86.4 60.31,86.27 60.31,85.01 60.18,84.88 59.86,84.88 59.73,85.01 59.73,85.81 59.61,85.94 59.35,85.94 59.22,85.81 59.22,85.01 59.1,84.88 57.74,84.88 57.48,85.14 56.91,85.14 56.67,85.38 56.17,85.38 56.04,85.25 56.04,84.87 56.17,84.74 56.31,84.74 56.52,84.53 57.12,84.53 v3(57.54,84.11)
  BOTTOM w0.076: 102.96,88.54 102.96,88.12 104.66,86.41 105.19,86.41 105.41,86.19 105.41,85.98 105.57,85.82 UC1.B33
  BOTTOM w0.102: 102.96,88.54 102.63,88.87 v3(102.63,89.78) ; JDIMM1.42 55.15,82.53 55.31,82.68 56.11,82.68 v3(57.54,84.11)
DDR_M0_D11: length 64.4
  IN1 w0.127: v3(58.81,84.11) 58.81,84.42 58.94,84.55 60.51,84.55 60.64,84.68 60.64,85.1 60.77,85.22 61.1,85.22 61.22,85.1 61.22,84.6 61.35,84.48 61.6,84.48 61.73,84.6 61.73,85.94 61.86,86.07 65.07,86.07 69.49,90.49 70.03,90.49 70.16,90.61 70.16,91.15 70.29,91.28 70.56,91.28 70.69,91.15 70.69,90.85 70.82,90.72 71.07,90.72 71.2,90.85 71.2,91.31 71.33,91.43 100.35,91.43 101.45,90.34 101.45,89.72 101.45,89.72 101.59,89.58 101.9,89.27 101.99,89.27 102.02,89.23 103.24,89.23 103.46,89.01 103.84,89.01 104.23,89.39 104.23,89.45 v3(104.23,89.45)
  BOTTOM w0.076: UC1.D32 106.23,84.56 106.09,84.84 106.09,85.71 105.85,86.23
  BOTTOM w0.089: 105.85,86.23 105.49,86.59 104.72,86.59 103.91,87.41 103.91,89.13 104.23,89.45 v3(104.23,89.45)
  BOTTOM w0.102: JDIMM1.41 60.15,82.78 v3(58.81,84.11)
DDR_M0_D12: length 64.5
  IN1 w0.127: v3(105.17,92.17) 103.65,93.69 69.5,93.69 66.7,90.89 63.62,90.89 61.25,88.53 56.18,88.53 56.06,88.4 56.06,88.21 56.18,88.09 56.89,88.09 56.98,87.99 v3(56.98,87.67)
  BOTTOM w0.076: UC1.A30 107.63,86.21 107.63,87.02 107.77,87.16 107.77,87.83 106.97,88.63 106.97,89.49
  BOTTOM w0.102: v3(56.98,87.67) 56.98,87.54 56.55,87.11 55.89,87.11 55.64,86.86 55.64,86.41 55.25,86.02 54.3,86.02 JDIMM1.28 ; 106.97,89.49 106.97,90.56 105.36,92.17 v3(105.17,92.17)
DDR_M0_D13: length 65.5
  IN1 w0.127: v3(106.73,91.87) 106.61,91.75 105,91.75 103.39,93.36 69.64,93.36 66.84,90.56 65.55,90.56 65.43,90.44 65.43,89.94 65.3,89.81 64.99,89.81 64.87,89.94 64.87,90.44 64.74,90.56 63.75,90.56 61.39,88.2 58.78,88.2 v3(58.25,87.67)
  BOTTOM w0.076: UC1.C30 108.03,85.44 108.03,85.78 108.12,85.93 108.13,85.96 108.15,85.98 108.15,87.93 107.41,88.67 107.41,91.18 107.34,91.26
  BOTTOM w0.102: v3(58.25,87.67) 60.15,85.78 JDIMM1.29 ; 107.34,91.26 v3(106.73,91.87)
DDR_M0_D14: length 63.2
  IN1 w0.127: v3(60.08,84.11) 60.38,83.82 62.1,83.82 62.23,83.95 62.23,84.84 62.36,84.97 62.61,84.97 62.74,84.84 62.74,83.95 62.86,83.82 63.12,83.82 63.24,83.95 63.24,84.98 63.37,85.11 64.58,85.11 67.47,88 67.65,88 68.11,87.54 68.29,87.54 68.47,87.72 68.47,87.9 68.01,88.36 68.01,88.54 68.19,88.72 68.37,88.72 68.86,88.22 69.04,88.22 69.22,88.4 69.22,88.58 68.73,89.08 68.73,89.26 68.91,89.44 69.09,89.44 69.58,88.94 69.76,88.94 69.94,89.12 69.94,89.3 69.45,89.8 69.45,89.98 69.63,90.16 69.81,90.16 70.3,89.66 70.48,89.66 71.92,91.1 99.59,91.1 101.3,89.39 101.31,89.39 101.45,89.25 101.77,88.94 101.85,88.94 101.88,88.9 102.83,88.9 103.06,88.68 104.21,88.68 v3(104.35,88.82)
  BOTTOM w0.076: UC1.B32 106.3,85.6 106.3,85.69 106.17,85.94 106.01,86.28 106,86.34
  BOTTOM w0.089: 106,86.34 105.3,87.03 104.83,87.03 104.35,87.51 v3(104.35,88.82)
  BOTTOM w0.102: JDIMM1.37 60.42,83.78 v3(60.08,84.11)
DDR_M0_D15: length 63.7
  IN1 w0.127: v3(56.27,84.11) 56.23,84.07 54.87,84.07 54.75,83.94 54.75,83.36 54.87,83.23 55.75,83.23 56.01,83.49 63.43,83.49 63.57,83.64 63.57,84.41 63.94,84.78 64.71,84.78 67.14,87.21 68.49,87.21 71.98,90.7 99.42,90.7 101.06,89.06 101.18,89.06 101.32,88.92 101.63,88.61 101.72,88.61 101.75,88.57 102.7,88.57 103.28,87.99 103.34,87.99 104.02,87.3 104.89,87.3 v3(104.98,87.4)
  BOTTOM w0.076: 105.2,87.4 106.15,87.4 106.37,87.18 106.37,87.01 106.58,86.81 106.58,86.46 106.69,86.35 106.69,86.08 106.63,85.94 106.63,85.76 106.62,85.73 106.67,85.58 106.67,85.39 106.64,85.31 106.63,85.28 UC1.C32
  BOTTOM w0.102: 105.2,87.4 v3(104.98,87.4) ; v3(56.27,84.11) 55.69,83.52 54.3,83.52 JDIMM1.38
DDR_M0_D16: length 62.1
  IN1 w0.127: v3(59.45,82.16) 59.48,82.18 63.78,82.18 63.9,82.31 64.08,82.31 64.57,81.81 64.75,81.81 64.93,81.99 64.93,82.17 64.44,82.67 64.44,82.85 64.62,83.02 64.8,83.02 65.29,82.53 65.47,82.53 65.65,82.71 65.65,82.89 65.16,83.38 65.16,83.56 65.34,83.74 65.52,83.74 66.01,83.25 66.19,83.25 66.37,83.43 66.37,83.61 65.88,84.1 65.88,84.28 66.05,84.46 66.23,84.46 66.73,83.97 66.91,83.97 72.47,89.53 98.71,89.53 100.42,87.81 100.66,87.81 101.11,87.36 101.2,87.36 v3(101.8,86.76)
  BOTTOM w0.076: UC1.H37 103.12,81.97 102.5,81.97 102.05,82.42 102.05,83.48 101.31,84.22 101.31,86.26 v3(101.8,86.76)
  BOTTOM w0.102: v3(59.45,82.16) 59.83,81.78 60.65,81.78 60.75,81.88 60.75,82.16 60.85,82.27 61.06,82.27 61.16,82.16 61.16,81.88 61.26,81.78 JDIMM1.45
DDR_M0_D17: length 63.6
  IN1 w0.127: v3(102.83,87.52) 102.83,87.58 102.42,87.99 101.51,87.99 101.47,88.02 101.39,88.02 101.07,88.33 100.93,88.47 100.7,88.47 98.98,90.19 72.19,90.19 68.7,86.7 67.36,86.7 63.6,82.94 60.17,82.94 60.14,82.91 57.91,82.91 57.79,82.78 57.79,82.7 57.66,82.57 57.4,82.57 57.28,82.7 57.28,82.78 57.15,82.91 56.73,82.91 56.6,82.78 56.6,82.42 56.86,82.16 v3(56.91,82.16)
  BOTTOM w0.076: v3(102.83,87.52) 102.91,87.44 102.91,86.02 101.95,85.06 101.95,84.04 102.38,83.62 102.38,83.48 102.38,83.48 102.38,82.56 102.38,82.55 102.38,82.55 102.59,82.34 102.59,82.34 102.62,82.32 102.9,82.32 103.09,82.52 103.3,82.52 103.32,82.52 103.35,82.51 103.48,82.51 103.59,82.45 103.67,82.37 104.69,82.37 UC1.H34
  BOTTOM w0.102: v3(56.91,82.16) 55.28,80.53 JDIMM1.50
DDR_M0_D18: length 65.2
  IN1 w0.127: v3(100.54,85.01) 101.2,85.01 101.33,85.13 101.33,86.13 101.2,86.26 100.73,86.26 100.6,86.13 100.6,85.85 100.48,85.72 100.22,85.72 100.1,85.85 100.1,86.13 99.97,86.26 99.2,86.26 97.53,87.93 75.17,87.93 75.05,87.8 75.05,87.51 74.92,87.38 74.67,87.38 74.54,87.51 74.54,87.8 74.41,87.93 74.16,87.93 74.03,87.8 74.03,87.51 73.9,87.38 73.65,87.38 73.52,87.51 73.52,87.8 73.4,87.93 73.13,87.93 73,87.8 73,87.51 72.87,87.38 72.58,87.38 64.9,79.7 63.56,79.7 63.54,79.69 58.3,79.69 58.18,79.56 v3(58.18,78.98)
  BOTTOM w0.076: UC1.K34 105.26,81.51 105.06,81.72 104.24,81.72 104.09,81.66 103.84,81.66 103.76,81.69 103.52,81.69 103.47,81.68 103.47,81.67 103.39,81.64 103.38,81.64 103.32,81.62 102.35,81.62 101.72,82.25 101.72,83.34 100.54,84.51 v3(100.54,85.01)
  BOTTOM w0.102: v3(58.18,78.98) 59,78.16 60.12,78.16 61.01,77.28 JDIMM1.63
DDR_M0_D19: length 64.3
  IN1 w0.076: 97.59,86.2 v3(98.06,85.73)
  IN1 w0.127: v3(55.64,78.98) 55.63,78.98 55.63,80.07 55.52,80.18 54.28,80.18 54.11,80.02 54.11,78.36 54.24,78.23 59.04,78.23 59.16,78.11 60.5,78.11 60.54,78.07 64.67,78.07 72.99,86.39 84.9,86.39 85.44,86.94 96.85,86.94 97.59,86.2
  BOTTOM w0.076: UC1.K35 104.32,80.49 103.72,80.49 103.49,80.37 103.05,80.37 102.89,80.54 102.59,80.54 102.46,80.41 101.57,80.41 100.87,81.1 100.87,82.87 98.06,85.69 v3(98.06,85.73)
  BOTTOM w0.102: JDIMM1.58 55.19,78.53 v3(55.64,78.98)
DDR_M0_D20: length 63.4
  IN1 w0.127: v3(101.66,87.57) 101.46,87.57 101.34,87.69 101.25,87.69 100.94,88 100.8,88.14 100.56,88.14 98.85,89.86 72.33,89.86 68.34,85.88 68.16,85.88 67.67,86.37 67.49,86.37 67.31,86.19 67.31,86.01 67.81,85.52 67.81,85.34 67.63,85.16 67.45,85.16 66.95,85.65 66.77,85.65 63.73,82.61 60.31,82.61 60.27,82.58 58.6,82.58 v3(58.18,82.16)
  BOTTOM w0.076: UC1.H36 103.83,82.14 103.7,82.2 103.6,82.2 103.49,82.32 103.44,82.34 103.17,82.34 102.98,82.15 102.55,82.15 102.21,82.49 102.21,83.55 101.47,84.29 101.47,84.94 101.66,85.12 101.7,85.12 102.74,86.16 102.74,87.08 102.67,87.15 102.08,87.15 v3(101.66,87.57)
  BOTTOM w0.102: JDIMM1.49 61.41,80.78 60.71,81.47 58.63,81.47 58.18,81.92 v3(58.18,82.16)
DDR_M0_D21: length 63.9
  IN1 w0.127: v3(55.64,82.16) 55.64,82.4 55.51,82.53 54.29,82.53 54.16,82.4 54.16,81.67 54.29,81.54 59.62,81.54 59.8,81.72 62.79,81.72 63.36,81.16 64.56,81.16 72.6,89.2 98.57,89.2 100.29,87.48 100.52,87.48 101.15,86.86 v3(101.15,86.78)
  BOTTOM w0.076: UC1.H35 104.28,81.91 104.06,81.83 103.87,81.83 103.74,81.88 103.55,81.88 103.5,81.86 103.49,81.86 103.38,81.82 103.38,81.81 103.35,81.8 103.33,81.8 103.29,81.79 102.41,81.79 101.88,82.32 101.88,83.41 101.05,84.24 101.05,86.68 v3(101.15,86.78)
  BOTTOM w0.102: JDIMM1.46 55.21,81.53 55.64,81.95 v3(55.64,82.16)
DDR_M0_D22: length 64
  IN1 w0.127: v3(98.83,85.63) 97.19,87.27 85.01,87.27 84.89,87.14 84.89,86.85 84.76,86.72 84.5,86.72 84.38,86.85 84.38,87.14 84.25,87.27 84,87.27 83.87,87.14 83.87,86.85 83.74,86.72 83.49,86.72 83.36,86.85 83.36,87.14 83.23,87.27 82.98,87.27 82.85,87.14 82.85,86.85 82.73,86.72 82.47,86.72 82.35,86.85 82.35,87.14 82.22,87.27 81.96,87.27 81.84,87.14 81.84,86.85 81.71,86.72 81.46,86.72 81.33,86.85 81.33,87.14 81.2,87.27 80.95,87.27 80.82,87.14 80.82,86.85 80.69,86.72 72.86,86.72 64.53,78.4 60.68,78.4 60.64,78.44 59.29,78.44 59.18,78.56 56.92,78.56 56.79,78.68 56.79,78.86 v3(56.91,78.98)
  BOTTOM w0.076: UC1.K36 103.73,80.69 103.45,80.54 103.44,80.53 103.12,80.53 102.95,80.7 102.51,80.7 102.38,80.57 101.64,80.57 101.04,81.17 101.04,83.01 98.83,85.22 v3(98.83,85.63)
  BOTTOM w0.102: JDIMM1.62 55.74,77.53 55.84,77.63 55.84,78.07 55.94,78.18 56.14,78.18 56.25,78.07 56.25,77.63 56.35,77.53 56.81,77.53 56.91,77.63 v3(56.91,78.98)
DDR_M0_D23: length 63.2
  IN1 w0.127: v3(59.45,78.98) 59.37,79.05 59.37,79.23 59.5,79.36 60.12,79.36 60.21,79.27 60.21,78.9 60.28,78.82 60.65,78.82 60.78,78.95 60.78,79.23 60.9,79.36 61.16,79.36 61.28,79.23 61.28,78.86 61.41,78.73 61.67,78.73 61.79,78.86 61.79,79.23 61.92,79.36 62.17,79.36 62.3,79.23 62.3,78.86 62.43,78.73 62.68,78.73 62.81,78.86 62.81,79.23 62.94,79.36 63.19,79.36 63.32,79.23 63.32,78.86 63.44,78.73 64.4,78.73 72.72,87.05 75.25,87.05 75.38,87.18 75.38,87.47 75.5,87.6 75.76,87.6 75.88,87.47 75.88,87.18 76.01,87.05 76.26,87.05 76.39,87.18 76.39,87.47 76.52,87.6 76.77,87.6 76.9,87.47 76.9,87.18 77.03,87.05 77.28,87.05 77.41,87.18 77.41,87.47 77.53,87.6 77.79,87.6 77.92,87.47 77.92,87.18 78.04,87.05 78.33,87.05 78.46,87.18 78.46,87.47 78.59,87.6 78.84,87.6 78.97,87.47 78.97,87.18 79.1,87.05 79.35,87.05 79.48,87.18 79.48,87.47 79.6,87.6 79.86,87.6 79.99,87.47 79.99,87.18 80.11,87.05 80.37,87.05 80.49,87.18 80.49,87.47 80.62,87.6 97.4,87.6 99.31,85.69 v3(99.49,85.69)
  BOTTOM w0.076: UC1.K37 103.22,80.88 102.46,80.88 102.32,80.74 101.7,80.74 101.2,81.24 101.2,83.07 99.49,84.79 v3(99.49,85.69)
  BOTTOM w0.102: JDIMM1.59 60.98,78.28 60.53,78.73 59.7,78.73 v3(59.45,78.98)
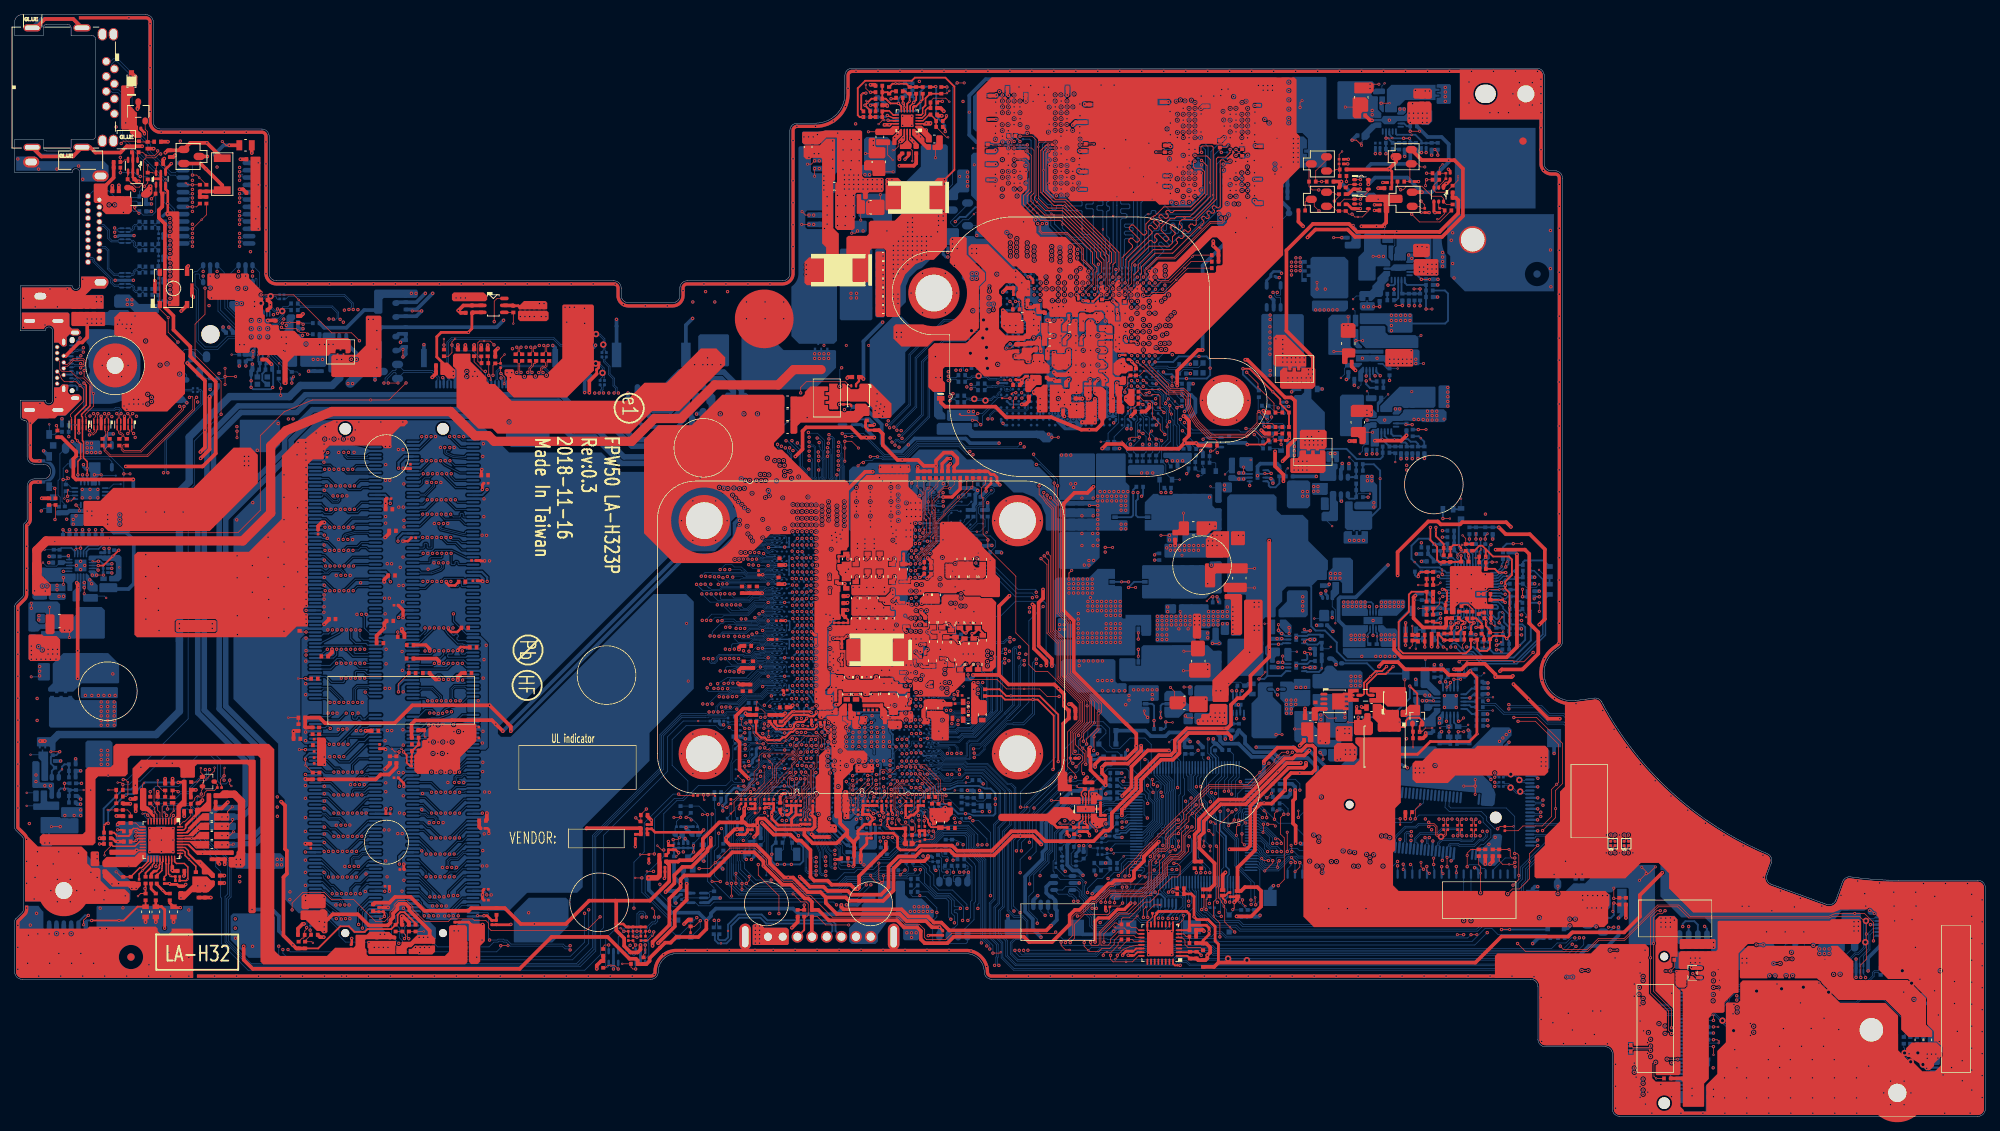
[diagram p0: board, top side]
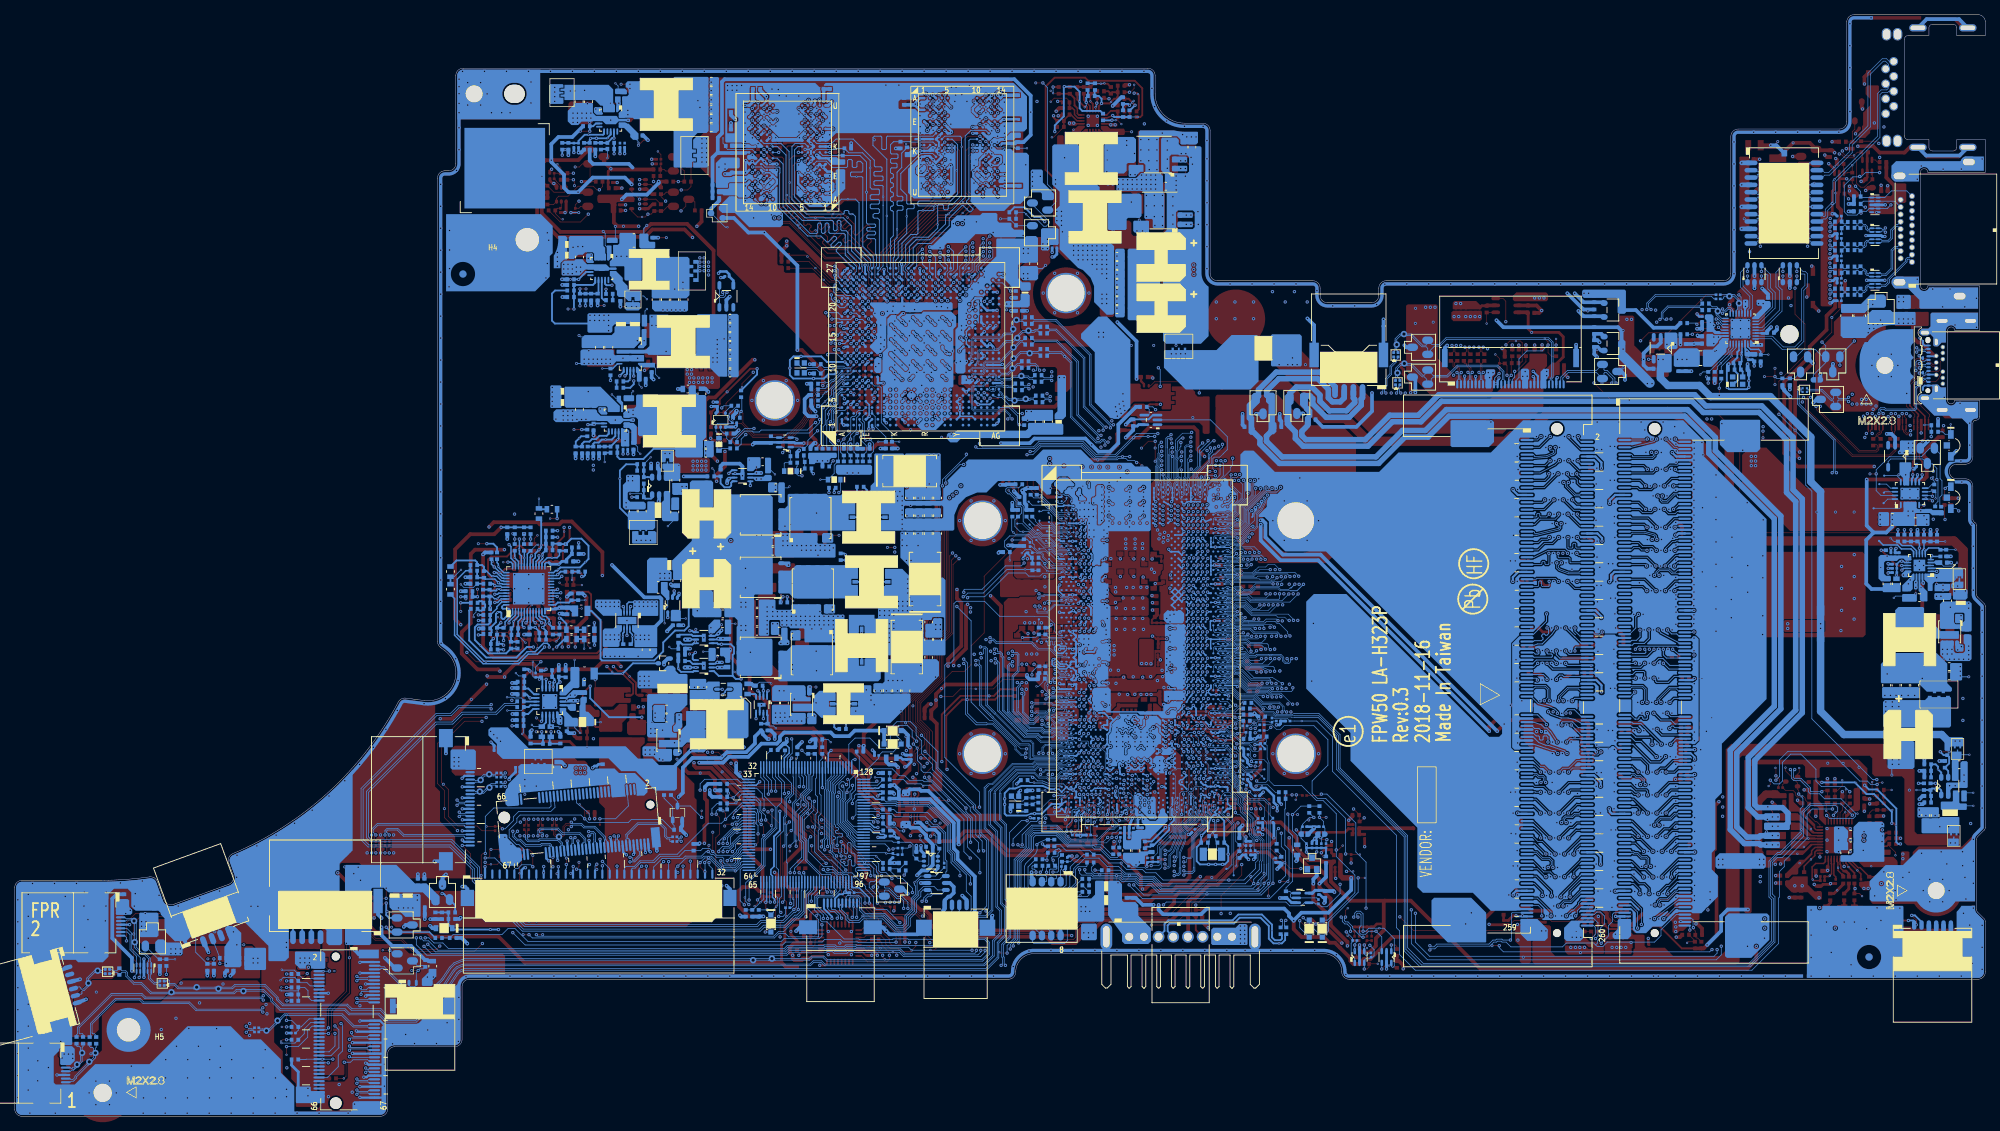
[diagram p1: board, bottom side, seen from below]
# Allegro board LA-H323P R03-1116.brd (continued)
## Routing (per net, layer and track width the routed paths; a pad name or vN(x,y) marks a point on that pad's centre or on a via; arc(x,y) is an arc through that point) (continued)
DDR_M0_D24: length 65.5
  IN1 w0.127: v3(96.09,85.81) 95.88,86.02 90.76,86.02 90.63,85.9 90.63,85.69 90.5,85.57 90.25,85.57 90.12,85.69 90.12,85.9 90,86.02 89.73,86.02 89.66,85.95 89.66,85.64 89.57,85.55 89.27,85.55 89.14,85.68 89.14,85.9 89.01,86.02 88.76,86.02 88.63,85.9 88.63,85.68 88.51,85.55 88.25,85.55 88.13,85.68 88.13,85.9 88,86.02 87.74,86.02 87.62,85.9 87.62,85.68 87.49,85.55 87.24,85.55 87.11,85.68 87.11,85.9 86.98,86.02 86.73,86.02 86.6,85.9 86.6,85.68 86.47,85.55 86.22,85.55 86.09,85.68 86.09,85.9 85.97,86.02 85.71,86.02 85.59,85.9 85.59,85.68 85.46,85.55 73.34,85.55 65.01,77.22 60.93,77.22 60.8,77.1 60.8,76.8 60.67,76.68 60.42,76.68 60.29,76.8 60.29,77.1 60.16,77.22 59.63,77.22 59.58,77.27 58.81,77.27 58.7,77.39 56.84,77.39 56.73,77.27 56.73,76.97 56.88,76.81 v3(56.97,76.81)
  BOTTOM w0.076: UC1.N36 103.83,79.61 103.42,79.83 103.16,79.83 102.99,79.66 102.51,79.66 102.3,79.87 101.57,79.87 100.51,80.93
  BOTTOM w0.102: 100.51,80.93 100.51,82.66 98,85.17 96.63,85.17 96.09,85.71 v3(96.09,85.81) ; v3(56.97,76.81) 57.38,77.22 59.61,77.22 61.52,76.28 JDIMM1.67
DDR_M0_D25: length 64.5
  IN1 w0.127: v3(55.7,76.81) 55.96,76.56 55.96,75.38 55.83,75.25 55.02,75.25 54.86,75.41 54.86,77.56 55.02,77.72 58.83,77.72 58.95,77.6 60.29,77.6 60.33,77.56 64.88,77.56 73.2,85.88 85.11,85.88 85.58,86.35 96.56,86.35 97.25,85.66 v3(97.25,85.66)
  BOTTOM w0.076: 100.7,82.14 100.7,80.99 101.64,80.04 102.37,80.04 102.59,79.82 102.89,79.82 103.06,79.99 103.49,79.99 103.65,79.9 104.57,79.9 UC1.N34
  BOTTOM w0.102: JDIMM1.66 55.41,76.53 v3(55.7,76.81) ; 100.7,82.14 100.7,82.74 98.07,85.36 97.54,85.36 v3(97.25,85.66)
DDR_M0_D26: length 64.6
  IN1 w0.076: v3(99.97,79.47) 99.97,78.93 99.22,78.17 97.25,78.17 96.25,77.17 92.31,77.17 90.03,79.46 90.03,83.2 89.94,83.29 89.01,83.29
  IN1 w0.127: 89.01,83.29 74.41,83.29 65.12,74 61.21,74 61.09,73.88 61.09,73.02 60.96,72.89 60.7,72.89 60.58,73.02 60.58,73.88 60.45,74 60.18,74 60.06,73.88 60.06,73.55 59.93,73.43 59.67,73.43 59.55,73.55 59.55,73.88 59.42,74 58.59,74 58.5,73.92 58.5,73.57 58.64,73.43 59.02,73.43 v3(59.48,72.98)
  BOTTOM w0.076: UC1.R37 103.24,78.35 102.53,78.35 102.38,78.19 101.68,78.19 100.4,79.47 v3(99.97,79.47)
  BOTTOM w0.102: v3(59.48,72.98) 59.48,72.38 59.58,72.28 60.4,72.28 60.51,72.38 60.51,72.94 60.61,73.05 60.81,73.05 60.91,72.94 60.91,72.38 61.01,72.28 JDIMM1.83
DDR_M0_D27: length 65
  IN1 w0.076: 89.01,83.62 89.99,83.62 90.22,83.39 90.22,79.52 92.28,77.46 95.9,77.46 97.01,78.57 97.94,78.57 v3(99.87,80.5)
  IN1 w0.127: v3(58.21,72.98) 58.18,72.98 57.61,73.56 57.61,74.21 57.73,74.34 64.98,74.34 74.27,83.62 89.01,83.62
  BOTTOM w0.076: v3(99.87,80.5) 100.16,80.5 101.31,79.35 102.09,79.35 102.31,79.14 103.36,79.14 103.5,79.18 103.77,79.18 103.86,79.15 104.07,79.15 104.22,79.19 104.25,79.2 105.06,79.2 105.26,78.99 UC1.R34
  BOTTOM w0.102: v3(58.21,72.98) 58.61,73.39 61.15,73.39 61.26,73.28 JDIMM1.79
DDR_M0_D28: length 64.3
  IN1 w0.076: 93.37,85.69 95.64,85.69 96.06,85.27 99.76,85.27 100.6,84.43 100.6,84.28 99.77,83.45 99.77,83.34 99.91,83.2 100.02,83.2 101.55,84.74 101.66,84.74 101.82,84.58 101.82,84.44 v3(100.01,82.63)
  IN1 w0.127: v3(59.51,76.81) 59.7,76.81 59.8,76.72 59.8,76.09 59.96,75.94 61.18,75.94 61.31,76.06 61.31,76.75 61.43,76.88 65.14,76.88 73.48,85.22 90.8,85.22 91.27,85.69 93.37,85.69
  BOTTOM w0.076: UC1.N37 103.21,79.47 102.44,79.47 102.23,79.69 101.5,79.69 100.33,80.85 100.33,82.32 v3(100.01,82.63)
  BOTTOM w0.102: v3(59.51,76.81) 59.51,75.38 59.61,75.28 59.95,75.28 60.05,75.38 60.05,75.6 60.15,75.7 60.35,75.7 60.45,75.6 60.45,75.38 60.56,75.28 JDIMM1.71
DDR_M0_D29: length 64.4
  IN1 w0.076: 89.01,84.89 90.84,84.89 91.45,85.5 95.6,85.5 95.99,85.11 98.47,85.11 99.57,84.01 99.57,83.91 v3(99.15,83.49)
  IN1 w0.127: v3(58.24,76.81) 58.24,76.7 58.7,76.25 59.29,76.25 59.42,76.12 59.42,75.75 59.56,75.61 61.51,75.61 61.64,75.73 61.64,76.42 61.76,76.55 62.02,76.55 62.14,76.42 62.14,75.73 62.27,75.61 62.54,75.61 62.67,75.73 62.67,76.42 62.8,76.55 63.05,76.55 63.18,76.42 63.18,75.73 63.31,75.61 63.54,75.61 63.67,75.73 63.67,76.42 63.79,76.55 65.27,76.55 73.62,84.89 89.01,84.89
  BOTTOM w0.076: UC1.N35 104.6,79.56 104.22,79.42 104.14,79.34 104.05,79.32 103.88,79.32 103.66,79.38 103.62,79.38 103.34,79.3 102.38,79.3 102.16,79.52 101.43,79.52 99.64,81.31 99.64,82.19 99.15,82.67 v3(99.15,83.49)
  BOTTOM w0.102: JDIMM1.70 56.57,75.53 56.62,75.58 56.62,76.09 56.75,76.21 58.14,76.21 58.24,76.32 v3(58.24,76.81)
DDR_M0_D30: length 64.7
  IN1 w0.076: 89.01,82.96 89.77,82.2 89.77,79.46 92.31,76.92 96.5,76.92 97.59,78.01 99.34,78.01 v3(100.35,79.02)
  IN1 w0.127: 89.01,82.96 74.54,82.96 65.26,73.67 63.53,73.67 63.41,73.55 63.41,72.69 63.28,72.56 63.07,72.56 62.94,72.69 62.94,73.55 62.81,73.67 62.56,73.67 62.43,73.55 62.43,72.69 62.3,72.56 62.05,72.56 61.92,72.69 61.92,73.55 61.8,73.67 61.54,73.67 61.42,73.55 61.42,72.69 61.29,72.56 57.06,72.56 56.94,72.69 v3(56.94,72.98)
  BOTTOM w0.076: UC1.R36 103.78,78.08 103.53,78.08 103.5,78.05 103.43,78.02 103.15,78.02 103.01,78.16 102.58,78.16 102.44,78.03 102.37,78.03 101.93,78.03 101.58,78.03 100.53,79.08 100.41,79.08 v3(100.35,79.02)
  BOTTOM w0.102: JDIMM1.84 55.98,72.03 v3(56.94,72.98)
DDR_M0_D31: length 64.3
  IN1 w0.076: 89.01,82.63 89.61,82.03 89.61,79.37 92.24,76.74 96.7,76.74 97.81,77.84 99.98,77.84 v3(100.62,78.48)
  IN1 w0.127: 89.01,82.63 74.68,82.63 64.28,72.23 54.46,72.23 54.33,72.36 54.33,73.43 54.46,73.55 55.54,73.55 55.67,73.43 v3(55.67,72.98)
  BOTTOM w0.076: v3(100.62,78.48) 100.67,78.48 100.72,78.54 100.82,78.54 101.5,77.86 102,77.86 102,77.86 102.13,77.86 102.13,77.86 102.53,77.86 102.66,77.99 102.94,77.99 103.08,77.85 103.46,77.85 103.6,77.92 104.26,77.92 UC1.R35
  BOTTOM w0.102: JDIMM1.80 55.62,73.03 v3(55.67,72.98)
DDR_M0_D32: length 61.5
  IN1 w0.076: 89.01,66.67 90.61,66.67 90.67,66.73 v3(96.94,66.73)
  IN1 w0.127: 89.01,66.67 85.69,66.67 74.36,55.34 74.36,54.53 68.25,48.42 64.53,48.42 63.99,47.88 56.36,47.88 56.23,47.75 56.23,47.09 56.36,46.96 v3(56.84,46.96)
  BOTTOM w0.076: UC1.AN35 104.61,67.07 104.39,67.3 103.68,67.3 103.47,67.42 103.09,67.42 102.92,67.24 102.86,67.24 102.59,67.24 102.37,67.46 101.58,67.46 101.25,67.13 97.35,67.13 v3(96.94,66.73)
  BOTTOM w0.102: JDIMM1.174 56.28,47.53 v3(56.84,46.96)
DDR_M0_D33: length 59.8
  IN1 w0.076: 89.01,66.27 90.81,66.27 90.91,66.37 97.67,66.37 98.23,66.93 99.58,66.93 100.65,66.5 v3(101.18,65.98)
  IN1 w0.127: v3(59.38,46.96) 59.73,47.3 60.44,47.55 64.13,47.55 64.67,48.09 68.39,48.09 74.76,54.46 74.76,55.27 85.76,66.27 89.01,66.27
  BOTTOM w0.076: UC1.AN34 105.26,66.25 105.23,66.22 105.23,66.22 105.05,66.04 104.3,66.04 104.08,66.11 103.85,66.11 103.73,66.07 103.59,66.07 103.48,66.1 103.43,66.11 102.33,66.11 102.04,65.83 101.28,65.83 101.18,65.94 v3(101.18,65.98)
  BOTTOM w0.102: JDIMM1.169 61.66,48.78 60.64,47.75 60.18,47.75 v3(59.38,46.96)
DDR_M0_D34: length 61.3
  IN1 w0.076: 89.01,64.31 93.23,64.31 93.6,64.69 96.41,64.69 96.83,65.11 97.67,65.11 97.75,65.19 97.75,65.56 98.06,65.88 100.44,65.88 100.54,65.78 v3(100.54,65.78)
  IN1 w0.127: v3(60.65,44.22) 60.71,44.17 62.47,44.17 62.65,44.34 62.65,44.86 62.77,44.99 63.03,44.99 63.15,44.86 63.15,44.34 63.28,44.22 63.46,44.22 64.25,45 68.03,45 69.71,46.68 69.89,46.68 70.12,46.44 70.3,46.44 70.48,46.62 70.48,46.8 70.25,47.04 70.25,47.22 70.43,47.4 70.61,47.4 70.84,47.16 71.02,47.16 71.2,47.34 71.2,47.52 70.97,47.76 70.97,47.94 71.15,48.12 71.33,48.12 71.56,47.88 71.74,47.88 71.92,48.06 71.92,48.24 71.69,48.48 71.69,48.66 71.86,48.83 72.04,48.83 72.28,48.6 72.46,48.6 72.64,48.78 72.64,48.96 72.4,49.19 72.4,49.37 72.58,49.55 72.76,49.55 73,49.32 73.18,49.32 76.76,52.9 76.76,54.54 86.53,64.31 89.01,64.31
  BOTTOM w0.076: 100.96,65.62 102.01,65.62 102.06,65.67 102.11,65.67 102.4,65.95 103.41,65.95 103.5,65.91 103.76,65.91 103.79,65.92 103.87,65.95 103.89,65.94 104.08,65.94 104.4,65.83 UC1.AR35
  BOTTOM w0.089: 100.96,65.62 100.71,65.62 100.55,65.78 v3(100.54,65.78)
  BOTTOM w0.102: v3(60.65,44.22) 61.34,44.22 61.4,44.28 61.4,44.27 JDIMM1.187
DDR_M0_D35: length 62.2
  IN1 w0.076: 89.01,63.98 93.31,63.98 93.79,64.46 96.41,64.46 96.9,64.95 98.12,64.95 98.19,65.02 v3(98.19,65.49)
  IN1 w0.127: v3(59.38,44.22) 59.8,43.8 65.4,43.8 65.53,43.92 65.53,44.3 65.66,44.43 65.91,44.43 66.04,44.3 66.04,43.92 66.16,43.8 66.47,43.8 66.61,43.93 66.61,44.55 66.73,44.67 68.17,44.67 69.5,46.01 70.33,46.01 77.09,52.76 77.09,54.4 86.67,63.98 89.01,63.98
  BOTTOM w0.076: 100.23,64.67 100.62,65.06 101.1,65.06 101.11,65.05 102.21,65.05 102.61,65.45 102.9,65.45 103.09,65.26 103.41,65.26 103.43,65.25 103.45,65.25 103.47,65.26 103.5,65.28 103.7,65.38 104.64,65.38 UC1.AR34
  BOTTOM w0.089: v3(98.19,65.49) 98.19,65.11 98.64,64.67 100.23,64.67
  BOTTOM w0.102: v3(59.38,44.22) 60.19,45.02 61.46,45.02 61.72,45.27 JDIMM1.183
DDR_M0_D36: length 61
  IN1 w0.076: v3(99.54,66.56) 99.52,66.56 99,66.04 94.31,66.04 93.88,65.61 89.01,65.61
  IN1 w0.127: v3(58.11,46.96) 58.02,46.87 58.02,45.61 58.15,45.49 58.52,45.49 58.65,45.61 58.65,46.15 58.77,46.27 66.79,46.27 67.95,47.43 68.66,47.43 75.42,54.19 75.42,55 86.03,65.61 89.01,65.61
  BOTTOM w0.076: UC1.AN37 103.2,66.99 103.12,66.91 102.81,66.91 102.72,66.91 102.45,66.91 102.45,66.91 102.4,66.91 102.29,67.02 101.68,67.02 101.41,66.76 99.78,66.76
  BOTTOM w0.089: 99.78,66.76 99.59,66.56 v3(99.54,66.56)
  BOTTOM w0.102: v3(58.11,46.96) 57.58,47.49 56.75,47.49 55.71,48.53 JDIMM1.170
DDR_M0_D37: length 61.1
  IN1 w0.076: 89.01,65.94 93.97,65.94 94.24,66.21 98.01,66.21 v3(98.37,66.56)
  IN1 w0.127: v3(60.65,46.96) 60.92,47.22 62.24,47.22 62.37,47.09 62.37,46.73 62.49,46.6 62.75,46.6 62.88,46.73 62.88,47.09 63,47.22 63.26,47.22 63.38,47.09 63.38,46.73 63.51,46.6 64.55,46.6 64.68,46.73 64.68,47.63 64.8,47.76 65.06,47.76 65.19,47.63 65.19,46.73 65.31,46.6 65.57,46.6 65.69,46.73 65.69,47.63 65.82,47.76 66.07,47.76 66.2,47.63 66.2,46.73 66.33,46.6 66.66,46.6 66.78,46.73 66.78,47.63 66.91,47.76 68.52,47.76 75.09,54.33 75.09,55.13 85.9,65.94 89.01,65.94
  BOTTOM w0.076: UC1.AN36 103.91,67.14 103.64,67.14 103.43,67.25 103.16,67.25 102.98,67.07 102.79,67.07 102.52,67.08 102.3,67.3 101.65,67.3 101.3,66.95
  BOTTOM w0.089: v3(98.37,66.56) 98.37,66.87 98.46,66.96 99.28,66.96 99.28,66.95 101.3,66.95
  BOTTOM w0.102: v3(60.65,46.96) 61.47,47.78 JDIMM1.173
DDR_M0_D38: length 62.3
  IN1 w0.076: v3(98.83,65.49) 98.83,65.43 98.18,64.78 96.97,64.78 96.48,64.29 93.85,64.29 93.13,63.57 92.51,63.57
  IN1 w0.127: 92.51,63.57 86.72,63.57 77.5,54.35 77.5,52.71 70.12,45.33 69.94,45.33 69.77,45.5 69.59,45.5 69.41,45.32 69.41,45.14 69.58,44.97 69.58,44.79 69.4,44.61 69.22,44.61 69.06,44.78 68.88,44.78 68.44,44.34 67.49,44.34 66.61,43.47 58.26,43.47 58.11,43.62 v3(58.11,44.22)
  BOTTOM w0.076: v3(98.83,65.49) 99.18,65.14 100.38,65.14 100.48,65.24 100.85,65.24 100.85,65.24 102.12,65.24 102.12,65.24 102.16,65.24 102.54,65.62 102.98,65.62 103.17,65.42 103.38,65.42 103.4,65.43 103.44,65.43 103.49,65.46 103.54,65.51 103.87,65.69 UC1.AR36
  BOTTOM w0.102: JDIMM1.182 56.81,45.53 v3(58.11,44.22)
DDR_M0_D39: length 61.8
  IN1 w0.076: 92.51,63.24 93.03,63.24 93.92,64.13 96.55,64.13 97.04,64.62 99.22,64.62 100.03,65.43 v3(100.03,65.49)
  IN1 w0.127: v3(56.84,44.22) 57.92,43.14 67.32,43.14 67.44,43.26 67.44,43.84 67.57,43.96 67.83,43.96 67.95,43.84 67.95,43.26 68.08,43.14 68.33,43.14 68.46,43.26 68.46,43.84 68.59,43.96 69.22,43.96 77.83,52.58 77.83,54.21 86.86,63.24 92.51,63.24
  BOTTOM w0.076: 102.13,65.49 102.17,65.49 102.46,65.78 103.22,65.78 UC1.AR37
  BOTTOM w0.089: 102.13,65.49 102.05,65.41 100.92,65.41 100.92,65.41 100.11,65.41 v3(100.03,65.49)
  BOTTOM w0.102: v3(56.84,44.22) 56.54,44.53 JDIMM1.186
DDR_M0_D40: length 67.5
  IN1 w0.076: v3(99.37,63.52) 99.63,63.52 99.92,63.81 100.26,63.81 100.47,63.6 100.47,63.31 100.16,62.99 93.96,62.99 93.6,62.64 93.6,62.53 92.81,61.74 92.51,61.74
  IN1 w0.127: 92.51,61.74 87.48,61.74 79.36,53.62 79.36,48.15 74.81,43.61 71.32,43.61 68.67,40.95 58.53,40.95 v3(58.11,41.37)
  BOTTOM w0.076: 99.6,63.3 99.79,63.1 100.26,63.1 100.66,63.5 100.66,63.62 101.33,64.29 101.64,64.29 101.74,64.39 102.18,64.39 102.2,64.36 102.22,64.36 102.38,64.21 102.39,64.21 103.28,64.21 103.31,64.22 103.4,64.22 103.47,64.23 103.5,64.25 103.52,64.27 103.75,64.27 103.77,64.26 103.8,64.23 103.89,64.22 104.08,64.22 104.13,64.23 104.15,64.25 104.23,64.27 104.4,64.33 UC1.AU35
  BOTTOM w0.089: 99.6,63.3 v3(99.37,63.52)
  BOTTOM w0.102: v3(58.11,41.37) 55.96,43.53 JDIMM1.190
DDR_M0_D41: length 67.4
  IN1 w0.076: v3(97.48,63.68) 97.13,63.32 93.82,63.32 92.89,62.4 92.51,62.4
  IN1 w0.127: 92.51,62.4 87.21,62.4 78.7,53.89 78.7,49.74 76.48,47.52 76.3,47.52 75.22,48.6 75.04,48.6 74.86,48.42 74.86,48.24 75.94,47.16 75.94,46.98 75.76,46.8 75.58,46.8 74.5,47.88 74.32,47.88 68.65,42.21 60.64,42.21 60.51,42.08 60.51,41.98 60.38,41.85 60.13,41.85 60,41.98 60,42.08 59.87,42.21 59.51,42.21 59.38,42.08 v3(59.38,41.37)
  BOTTOM w0.076: 100.69,64.88 101.53,64.88 101.54,64.89 102.38,64.89 102.39,64.88 102.44,64.88 102.59,64.72 102.66,64.72 102.67,64.71 102.9,64.71 103.1,64.91 103.46,64.91 103.72,64.76 104.66,64.76 UC1.AU34
  BOTTOM w0.089: 100.69,64.88 100.29,64.48 97.92,64.48 97.75,64.31 97.75,63.94 v3(97.48,63.68)
  BOTTOM w0.102: JDIMM1.191 61.29,43.27 v3(59.38,41.37)
DDR_M0_D42: length 69
  IN1 w0.076: v3(96.89,62.45) 96.52,62.07 96.4,62.07 95.61,61.29 94.17,61.29 93.02,60.14 92.51,60.14
  IN1 w0.127: v3(60.63,37.98) 60.75,37.98 61.2,38.43 61.2,39.23 61.33,39.35 61.6,39.35 61.73,39.23 61.73,38.38 61.86,38.26 62.11,38.26 62.24,38.38 62.24,39.23 62.37,39.35 62.62,39.35 62.75,39.23 62.75,38.38 62.87,38.26 63.13,38.26 63.25,38.38 63.25,39.11 63.36,39.21 65.29,39.21 65.43,39.35 69.87,39.35 70.95,40.44 71.13,40.44 72.22,39.35 72.4,39.35 72.58,39.53 72.58,39.71 71.49,40.79 71.49,40.97 72.53,42.01 76.25,42.01 80.98,46.74 80.98,52.98 88.14,60.14 92.51,60.14
  BOTTOM w0.076: 102.18,62.64 102.29,62.75 102.42,62.75 102.59,62.92 102.89,62.92 103.06,62.74 103.47,62.74 103.67,62.85 104.3,62.85 UC1.AW35
  BOTTOM w0.089: 102.18,62.64 102.13,62.64 102.13,62.64 101.19,62.64 100.12,61.57 97.77,61.57 v3(96.89,62.45)
  BOTTOM w0.102: JDIMM1.207 61.52,39.28 60.63,38.38 v3(60.63,37.98)
DDR_M0_D43: length 66.9
  IN1 w0.076: v3(101.38,63.83) 101.38,63.74 100.46,62.82 96.09,62.82 94.72,61.45 94.1,61.45 93.11,60.47 92.51,60.47
  IN1 w0.127: v3(56.82,37.98) 57.48,38.65 58.67,38.65 59.7,39.68 69.49,39.68 72.14,42.34 76.12,42.34 80.65,46.87 80.65,53.11 88.01,60.47 92.51,60.47
  BOTTOM w0.076: UC1.AW34 105.26,63.91 105.06,64.11 104.26,64.11 104.09,64.04 103.93,64.04 103.75,64.07 103.73,64.08 103.55,64.08 103.44,64.04 102.29,64.04 102.11,64.23 101.81,64.23 101.49,63.91 101.45,63.91 v3(101.38,63.83)
  BOTTOM w0.102: v3(56.82,37.98) 55.78,39.03 55.77,39.03 JDIMM1.208
DDR_M0_D44: length 67.2
  IN1 w0.076: v3(100.12,63.46) 99.82,63.16 93.89,63.16 93.11,62.38 93.11,62.27 92.91,62.07 92.51,62.07
  IN1 w0.127: 92.51,62.07 87.34,62.07 79.03,53.75 79.03,49.6 75.52,46.09 75.34,46.09 74.26,47.17 74.08,47.17 73.9,46.99 73.9,46.81 74.98,45.73 74.98,45.55 74.8,45.37 74.62,45.37 73.54,46.45 73.36,46.45 73.18,46.27 73.18,46.09 74.26,45.01 74.26,44.83 74.08,44.65 73.9,44.65 72.82,45.73 72.64,45.73 72.44,45.52 72.44,45.35 73.26,44.52 73.26,44.34 73.08,44.16 72.9,44.16 72.08,44.99 71.9,44.99 68.79,41.88 61.16,41.88 v3(60.65,41.37)
  BOTTOM w0.076: v3(100.12,63.46) 100.16,63.5 100.16,63.78 100.83,64.45 101.57,64.45 101.67,64.56 102.24,64.56 102.27,64.53 102.29,64.53 102.45,64.37 103.22,64.37 UC1.AU37
  BOTTOM w0.102: v3(60.65,41.37) 61.56,42.27 JDIMM1.195
DDR_M0_D45: length 67.3
  IN1 w0.076: 92.51,62.73 92.89,62.73 94.13,63.96 96.62,63.96 96.95,64.29 97.89,64.29 98.13,64.05 v3(98.13,63.75)
  IN1 w0.127: 92.51,62.73 87.07,62.73 78.37,54.03 78.37,52.39 77.34,51.36 77.34,51.18 78,50.53 78,50.35 77.82,50.17 77.64,50.17 76.98,50.82 76.8,50.82 76.62,50.64 76.62,50.47 77.28,49.8 77.28,49.62 77.1,49.44 76.92,49.44 76.26,50.11 76.08,50.11 75.84,49.87 75.84,49.69 76.32,49.21 76.32,49.03 76.14,48.85 75.96,48.85 75.48,49.33 75.31,49.33 68.53,42.55 58.03,42.55 v3(56.84,41.37)
  BOTTOM w0.076: UC1.AU36 103.91,64.46 103.41,64.73 103.16,64.73 102.97,64.54 102.61,64.54 102.59,64.56 102.52,64.56 102.41,64.67 102.39,64.67 102.36,64.69 102.34,64.69 102.31,64.72 101.61,64.72 101.55,64.67 101.01,64.67
  BOTTOM w0.089: 101.01,64.67 100.81,64.67 100.43,64.29 98.67,64.29 98.13,63.75 v3(98.13,63.75)
  BOTTOM w0.102: JDIMM1.194 55.69,42.53 v3(56.84,41.37)
DDR_M0_D46: length 67.7
  IN1 w0.076: 92.51,59.81 93,59.81 94.32,61.12 95.68,61.12 95.85,61.29 97.05,61.29 98.07,62.31 v3(98.07,62.47)
  IN1 w0.127: 92.51,59.81 88.28,59.81 81.31,52.84 81.31,46.6 74.85,40.13 74.67,40.13 73.62,41.18 73.44,41.18 73.26,41 73.26,40.82 74.31,39.77 74.31,39.59 73.74,39.02 65.56,39.02 65.44,38.9 65.44,38.13 65.23,37.92 61.16,37.92 60.8,37.56 59.78,37.56 v3(59.36,37.98)
  BOTTOM w0.076: 102.24,62.93 102.37,62.93 102.52,63.08 102.95,63.08 103.13,62.91 103.41,62.91 103.9,63.17 103.93,63.17 UC1.AW36
  BOTTOM w0.089: v3(98.07,62.47) 98.07,62.27 98.59,61.75 100.05,61.75 101.11,62.82 101.67,62.82 101.78,62.93 102.24,62.93
  BOTTOM w0.102: JDIMM1.203 61.65,40.28 v3(59.36,37.98)
DDR_M0_D47: length 67.5
  IN1 w0.076: v3(98.7,62.45) 98.7,62.19 97.63,61.12 95.92,61.12 95.75,60.96 94.39,60.96 92.91,59.48 92.51,59.48
  IN1 w0.127: v3(58.09,37.98) 58.09,37.83 58.68,37.23 60.94,37.23 61.3,37.59 65.64,37.59 65.77,37.72 65.77,38.57 65.89,38.69 66.15,38.69 66.27,38.57 66.27,37.72 66.4,37.59 66.66,37.59 66.78,37.72 66.78,38.57 66.91,38.69 73.87,38.69 81.64,46.46 81.64,52.7 88.42,59.48 92.51,59.48
  BOTTOM w0.076: UC1.AW37 103.24,63.25 102.38,63.25 102.26,63.13 102.21,63.13 102.19,63.11
  BOTTOM w0.089: v3(98.7,62.45) 98.94,62.21 100.26,62.21 101.04,62.99 101.6,62.99 101.71,63.11 102.19,63.11
  BOTTOM w0.102: v3(58.09,37.98) 56.65,39.42 56.28,39.42 55.67,40.03 JDIMM1.204
DDR_M0_D48: length 70.7
  IN1 w0.076: v3(99.33,60.6) 99.31,60.58 99.31,60.42 98.97,60.08 94.4,60.08 92.55,58.23 92.51,58.23
  IN1 w0.127: 92.51,58.23 88.96,58.23 82.84,52.11 82.84,45.88 73.51,36.54 73.2,36.54 73.11,36.63 73.11,37.37 73.02,37.46 72.73,37.46 72.61,37.34 72.61,35.87 72.48,35.75 72.23,35.75 72.1,35.87 72.1,36.22 71.98,36.35 71.76,36.35 71.63,36.22 71.63,35.84 71.5,35.71 71.25,35.71 71.12,35.84 71.12,36.22 71,36.35 70.74,36.35 70.62,36.22 70.62,35.91 70.49,35.78 70.23,35.78 70.11,35.91 70.11,36.22 69.98,36.35 69.73,36.35 69.6,36.22 69.6,35.91 69.47,35.78 69.22,35.78 69.09,35.91 69.09,36.22 68.96,36.35 68.71,36.35 68.58,36.22 68.58,35.91 68.46,35.78 68.2,35.78 68.08,35.91 68.08,36.22 67.95,36.35 67.69,36.35 67.57,36.22 67.57,35.91 67.44,35.78 67.19,35.78 67.06,35.91 67.06,36.22 66.93,36.35 66.68,36.35 66.55,36.22 66.55,35.91 66.42,35.78 66.17,35.78 66.04,35.91 66.04,36.22 65.92,36.35 65.66,36.35 65.54,36.22 65.54,35.91 65.41,35.78 v3(59.92,35.78)
  BOTTOM w0.076: 101.99,61.84 102.12,61.71 102.47,61.71 102.47,61.71 103.11,61.71 103.12,61.7 103.43,61.7 103.52,61.73 103.78,61.73 103.9,61.69 104.06,61.69 104.14,61.72 104.23,61.81 UC1.BA35
  BOTTOM w0.089: 101.99,61.84 101.4,61.84 100.41,60.86 99.59,60.86 99.33,60.6 v3(99.33,60.6)
  BOTTOM w0.102: JDIMM1.215 61.41,37.28 v3(59.92,35.78)
DDR_M0_D49: length 71.4
  IN1 w0.076: 92.51,58.89 92.59,58.89 94.11,60.41 96.6,60.41 v3(96.91,60.72)
  IN1 w0.127: 92.51,58.89 88.69,58.89 82.16,52.36 82.16,46.13 74.15,38.12 69.56,38.12 69.43,37.99 69.43,37.14 69.3,37.01 69.05,37.01 68.92,37.14 68.92,37.99 68.79,38.12 68.54,38.12 68.41,37.99 68.41,37.14 68.29,37.01 67.93,37.01 67.8,37.14 67.8,37.97 67.67,38.09 67.42,38.09 67.29,37.97 67.29,37.14 67.16,37.01 61.54,37.01 61.21,36.68 58.27,36.68 v3(57.38,35.78)
  BOTTOM w0.076: 102.21,62.46 102.31,62.46 102.32,62.45 102.32,62.45 102.36,62.41 102.39,62.41 102.59,62.21 102.91,62.21 103.09,62.38 103.1,62.38 103.1,62.39 103.45,62.39 103.46,62.38 103.47,62.38 103.68,62.27 104.62,62.27 104.68,62.25 UC1.BA34
  BOTTOM w0.089: 102.21,62.46 102.2,62.46 101.26,62.46 100.19,61.39 97.14,61.39 96.95,61.2 96.95,60.76 v3(96.91,60.72)
  BOTTOM w0.102: JDIMM1.212 55.14,38.03 v3(57.38,35.78)
DDR_M0_D50: length 71.2
  IN1 w0.076: v3(94.42,58.47) 94.42,58.2 92.82,56.6 92.51,56.6
  IN1 w0.127: v3(59.92,32.69) 63.86,32.69 63.98,32.81 63.98,33.48 64.11,33.61 64.37,33.61 64.49,33.48 64.49,32.81 64.62,32.69 64.88,32.69 65.01,32.81 65.01,33.99 65.13,34.11 65.39,34.11 65.51,33.99 65.51,32.81 65.64,32.69 65.9,32.69 66.02,32.81 66.02,33.99 66.15,34.11 66.41,34.11 66.54,33.99 66.54,32.84 66.66,32.71 66.92,32.71 67.05,32.84 67.05,33.99 67.17,34.11 73.34,34.11 84.46,45.24 84.46,51.47 89.59,56.6 92.51,56.6
  BOTTOM w0.076: UC1.BC35 104.51,60.65 104.18,60.32 103.64,60.32 103.47,60.23 103.06,60.23 102.89,60.4 102.57,60.4 102.42,60.25 101.9,60.25 100.41,58.76 99.3,58.76
  BOTTOM w0.089: v3(94.42,58.47) 94.42,58.15 94.59,57.98 97.35,57.98 97.69,58.32 98.86,58.32 99.3,58.76
  BOTTOM w0.102: v3(59.92,32.69) 59.98,32.69 61.07,33.78 JDIMM1.229
DDR_M0_D51: length 71.5
  IN1 w0.076: v3(95.85,59.03) 95.56,58.74 95.19,58.74 94.7,58.24 94.7,58.11 92.86,56.27 92.51,56.27
  IN1 w0.127: 92.51,56.27 89.73,56.27 84.92,51.46 84.92,45.23 73.48,33.78 69.73,33.78 69.49,33.55 69.49,32.48 69.27,32.27 68.93,32.27 68.81,32.39 68.81,33.62 68.68,33.75 68.43,33.75 68.3,33.62 68.3,32.39 68.17,32.27 59.07,32.27 v3(58.65,32.69)
  BOTTOM w0.076: UC1.BC34 105.26,61.37 105.06,61.58 104.24,61.58 104.08,61.53 103.85,61.53 103.73,61.57 103.55,61.57 103.46,61.53 102.41,61.53 102.4,61.55 102.03,61.55 101.91,61.66
  BOTTOM w0.089: v3(95.85,59.03) 97.24,59.89 99.75,59.89 101.52,61.66 101.91,61.66
  BOTTOM w0.102: JDIMM1.225 61.63,34.78 60.2,33.35 59.31,33.35 v3(58.65,32.69)
DDR_M0_D52: length 69.6
  IN1 w0.076: v3(98.08,60.64) 97.69,60.25 94.25,60.25 92.57,58.56 92.51,58.56
  IN1 w0.127: 92.51,58.56 88.83,58.56 82.51,52.24 82.51,46.01 74.29,37.79 72.29,37.79 72.16,37.66 72.16,36.81 72.04,36.68 71.72,36.68 71.59,36.81 71.59,37.66 71.46,37.79 71.21,37.79 71.08,37.66 71.08,36.81 70.96,36.68 70.7,36.68 70.57,36.81 70.57,37.66 70.45,37.79 70.19,37.79 70.07,37.66 70.07,36.81 69.94,36.68 63.05,36.68 62.93,36.55 62.93,36.24 62.8,36.11 62.55,36.11 62.42,36.24 62.42,36.55 62.29,36.68 61.96,36.68 61.83,36.55 61.83,36.24 61.7,36.11 61.07,36.11 60.96,36.22 59.09,36.22 v3(58.65,35.78)
  BOTTOM w0.076: 102.07,62.02 102.21,61.88 102.54,61.88 102.54,61.87 103.02,61.87 UC1.BA37
  BOTTOM w0.089: 102.07,62.02 101.32,62.02 100.34,61.04 98.48,61.04 v3(98.08,60.64)
  BOTTOM w0.102: v3(58.65,35.78) 60.38,37.52 61.04,37.52 61.79,38.28 JDIMM1.211
DDR_M0_D53: length 70.2
  IN1 w0.076: v3(97.5,60.72) 97.5,60.73 97.99,61 99.43,61 99.68,60.75 99.68,60.45 99.15,59.92 94.61,59.92 92.6,57.9 92.51,57.9
  IN1 w0.127: 92.51,57.9 89.1,57.9 83.17,51.97 83.17,45.74 72.81,35.38 60.29,35.38 60.27,35.36 56.53,35.36 v3(56.11,35.78)
  BOTTOM w0.076: UC1.BA36 103.91,61.95 103.45,62.21 103.15,62.21 102.98,62.04 102.52,62.04 102.37,62.2 102.07,62.2
  BOTTOM w0.089: v3(97.5,60.72) 97.66,60.88 98.44,61.21 100.27,61.21 101.25,62.2 102.07,62.2
  BOTTOM w0.102: JDIMM1.216 55.28,37.03 55.9,36.41 v3(56.11,35.78)
DDR_M0_D54: length 69.7
  IN1 w0.076: 92.51,55.61 92.66,55.61 93.88,56.82 94.58,56.82 95.74,57.98 95.77,57.98 95.78,57.99 97.01,57.99 97.21,58.19 v3(97.21,58.35)
  IN1 w0.127: 92.51,55.61 90,55.61 85.58,51.19 85.58,44.95 72.23,31.61 72.05,31.61 71.93,31.73 71.93,32.96 71.8,33.09 71.55,33.09 71.42,32.96 71.42,31.73 71.29,31.61 57.19,31.61 v3(56.11,32.69)
  BOTTOM w0.076: UC1.BC36 103.79,60.48 103.59,60.48 103.53,60.44 103.43,60.39 103.13,60.39 102.95,60.57 102.5,60.57 102.35,60.42 101.75,60.42 100.29,58.95 99.6,58.95 99.24,58.95
  BOTTOM w0.089: v3(97.21,58.35) 97.37,58.35 97.51,58.5 98.78,58.5 99.24,58.95
  BOTTOM w0.102: JDIMM1.228 55.48,34.03 56.11,33.39 v3(56.11,32.69)
DDR_M0_D55: length 69.3
  IN1 w0.076: 92.51,55.94 92.76,55.94 93.81,56.99 94.51,56.99 95.89,58.36 v3(95.93,58.36)
  IN1 w0.127: v3(57.38,32.69) 58.13,31.94 69.8,31.94 69.93,32.06 69.93,33.16 70.13,33.36 70.31,33.36 70.44,33.23 70.44,32.06 70.56,31.94 70.82,31.94 70.95,32.06 70.95,33.29 71.07,33.42 73.58,33.42 85.25,45.09 85.25,51.32 89.86,55.94 92.51,55.94
  BOTTOM w0.076: UC1.BC37 103.24,60.73 102.43,60.73 102.28,60.58 102.2,60.58 102.18,60.58 101.6,60.58 100.16,59.14 99.19,59.14 98.75,58.7 96.57,58.7
  BOTTOM w0.089: v3(95.93,58.36) 95.93,58.62 96.01,58.71 96.56,58.71 96.57,58.7
  BOTTOM w0.102: JDIMM1.224 55.04,35.03 v3(57.38,32.69)
DDR_M0_D56: length 71.1
  IN1 w0.076: 89.68,54.1 90.27,54.69 91.5,54.69 91.95,55.14 93.59,55.14 94.32,55.87 95.2,55.87 95.58,56.24 95.58,56.66 95.45,56.78 95.45,57.43 95.8,57.78 97.34,57.78 v3(97.86,57.26)
  IN1 w0.127: v3(57.89,29.95) 58.63,30.69 61.12,30.69 61.24,30.56 61.24,30.24 61.37,30.12 61.62,30.12 61.75,30.24 61.75,30.56 61.88,30.69 62.13,30.69 62.26,30.56 62.26,30.24 62.39,30.12 62.64,30.12 62.77,30.24 62.77,30.56 62.89,30.69 72.63,30.69 77.34,35.4 77.71,35.4 86.44,44.13 86.44,50.86 89.68,54.1
  BOTTOM w0.076: UC1.BE35 104.42,59.44 104.2,59.22 104.14,59.21 104.12,59.19 104.1,59.18 104.05,59.18 104.05,59.18 103.88,59.18 103.83,59.18 103.81,59.19 103.76,59.24 103.72,59.27 103.56,59.27 103.52,59.24 103.47,59.19 103.43,59.17 101.77,59.17 100.6,58 100.26,58 99.5,58 99.14,57.64 98.13,57.64 97.86,57.37 97.86,57.26 v3(97.86,57.26)
  BOTTOM w0.102: JDIMM1.232 55.12,33.03 55.23,32.86 55.25,32.83 55.28,32.79 55.28,32.78 57.89,30.18 v3(57.89,29.95)
DDR_M0_D57: length 70.9
  IN1 w0.076: v3(94.45,56.22) 94.38,56.22 93.45,55.3 91.88,55.3 91.65,55.07 90.19,55.07 89.68,54.57
  IN1 w0.127: 89.68,54.57 86.11,51 86.11,44.27 77.64,35.79 77.26,35.79 72.5,31.02 57.56,31.02 57.43,30.89 57.43,30.5 57.3,30.37 57.05,30.37 56.92,30.5 56.92,30.89 56.8,31.02 56.36,31.02 56.24,30.89 56.24,30.08 56.36,29.95 v3(56.62,29.95)
  BOTTOM w0.076: 100.46,58.57 101.56,59.67 102.9,59.67 103.09,59.86 103.47,59.86 103.72,59.73 104.66,59.73 UC1.BE34 ; 96.05,57.74 94.53,56.22 v3(94.45,56.22)
  BOTTOM w0.089: 100.46,58.57 99.36,58.57 98.93,58.14 97.76,58.14 97.37,57.74 96.05,57.74
  BOTTOM w0.102: v3(56.62,29.95) 56.62,30.65 55.24,32.03 JDIMM1.236
DDR_M0_D58: length 71.2
  IN1 w0.076: v3(98.46,55.56) 98.46,55.3 97.49,54.33 96.67,54.33 95.84,53.51 92.68,53.51 90.85,51.68 90.85,51.57 90.01,50.73 90.01,47.64
  IN1 w0.127: v3(59.21,27.35) 59.22,27.35 59.59,26.98 59.7,26.93 63.16,26.93 63.48,26.62 72.14,26.62 72.27,26.75 72.27,27.33 72.4,27.45 72.65,27.45 72.78,27.33 72.78,26.75 72.9,26.62 73.2,26.62 74.29,27.71 76.31,27.71 81.9,33.29 81.9,34.69 84.56,37.36 85.96,37.36 90.01,41.41 90.01,47.64
  BOTTOM w0.076: 99.85,56.9 101.96,56.9 102.78,57.72 103.49,57.72 103.61,57.78 104.13,57.78 104.48,58.14 UC1.BG35
  BOTTOM w0.089: 99.85,56.9 98.51,55.56 v3(98.46,55.56)
  BOTTOM w0.102: JDIMM1.245 61.08,29.78 59.21,27.9 v3(59.21,27.35)
DDR_M0_D59: length 71.5
  IN1 w0.076: 89.68,47.97 89.68,50.63 90.67,51.62 90.67,51.73 92.71,53.77 95.81,53.77 96.54,54.5 97.34,54.5 98,55.16 98,56.84 v3(98.45,57.28)
  IN1 w0.127: v3(60.48,27.35) 63.21,27.35 63.61,26.95 70.47,26.95 70.59,27.08 70.59,27.97 70.72,28.1 70.98,28.1 71.1,27.97 71.1,27.08 71.23,26.95 71.42,26.95 72.56,28.09 76.18,28.09 81.52,33.42 81.52,34.82 84.39,37.69 85.83,37.69 89.68,41.55 89.68,47.97
  BOTTOM w0.076: UC1.BG34 105.26,58.87 105.22,58.9 105.06,59.07 104.61,59.18 104.57,59.13 104.12,59.02 103.8,59.02 103.73,59.04 103.69,59.07 103.59,59.07 103.56,59.04 103.46,59.01 102.45,59.01 102.44,59.01 101.86,59.01 100.66,57.81 100.32,57.81 99.55,57.81 99.14,57.41 98.57,57.41 v3(98.45,57.28)
  BOTTOM w0.102: JDIMM1.249 60.97,28.78 60.48,28.29 v3(60.48,27.35)
DDR_M0_D60: length 69.1
  IN1 w0.076: 89.68,53.63 90.36,54.31 91.35,54.31 92.01,54.97 93.66,54.97 94.39,55.7 95.27,55.7 95.74,56.17 95.74,56.73 95.61,56.85 95.61,57.36 95.87,57.62 96.88,57.62 97.24,57.26 v3(97.24,57.22)
  IN1 w0.127: 89.68,53.63 86.77,50.73 86.77,44 77.72,34.95 77.35,34.95 75.78,33.37 75.78,33.19 76.48,32.5 76.48,32.32 76.3,32.14 76.12,32.14 75.42,32.83 75.24,32.83 75.06,32.65 75.06,32.47 75.72,31.81 75.72,31.63 75.54,31.45 75.37,31.45 74.7,32.11 74.52,32.11 74.29,31.88 74.29,31.7 74.6,31.39 74.6,31.21 74.42,31.03 74.24,31.03 73.93,31.34 73.75,31.34 72.77,30.36 66.28,30.36 65.7,29.79 60.54,29.79 60.41,29.91 v3(60.41,30.12)
  BOTTOM w0.076: v3(97.24,57.22) 97.31,57.22 97.9,57.8 99.07,57.8 99.46,58.19 100.19,58.19 100.55,58.19 101.7,59.34 102.01,59.34 102.01,59.34 103,59.34 103.12,59.34 103.21,59.44 UC1.BE37
  BOTTOM w0.102: JDIMM1.237 61.51,31.78 60.43,30.7 60.43,30.14 v3(60.41,30.12)
DDR_M0_D61: length 70.1
  IN1 w0.076: v3(96.07,57.26) 96.07,56.27 95.34,55.54 94.46,55.54 93.73,54.81 92.08,54.81 91.21,53.93
  IN1 w0.127: v3(59.16,30.08) 59.28,30.08 59.9,29.46 65.84,29.46 66.41,30.03 74.89,30.03 77.21,32.35 77.21,32.53 76.4,33.35 76.4,33.53 76.58,33.7 76.76,33.7 77.22,33.24 77.4,33.24 77.58,33.42 77.58,33.6 77.3,33.88 77.3,34.06 87.1,43.86 87.1,50.59 90.45,53.93 91.21,53.93
  BOTTOM w0.076: v3(96.07,57.26) 96.05,57.28 96.05,57.38 96.24,57.57 97.44,57.57 97.84,57.97 99,57.97 99.42,58.38 100.19,58.38 100.51,58.38 101.63,59.5 101.94,59.5 101.94,59.51 102.11,59.51 102.97,59.51 103.07,59.6 103.07,59.6 103.16,59.7 103.43,59.7 103.67,59.56 103.68,59.56 103.7,59.55 103.85,59.55 UC1.BE36
  BOTTOM w0.102: v3(59.16,30.08) 59.16,30.71 61.22,32.78 JDIMM1.233
DDR_M0_D62: length 70.5
  IN1 w0.076: 89.68,51.37 89.68,51.48 92.38,54.18 95.75,54.18 96.4,54.83 96.76,54.83 96.87,54.94 96.87,55.34 96.39,55.82 v3(96.39,55.83)
  IN1 w0.127: v3(55.86,27.35) 56.69,28.19 68.18,28.19 68.75,28.76 75.46,28.76 80.75,34.06 80.75,35.33 83.82,38.39 85.38,38.39 88.81,41.82 88.81,50.49 89.68,51.37
  BOTTOM w0.076: UC1.BG36 103.62,57.95 103.57,57.95 103.45,57.88 103.12,57.88 103.12,57.88 102.71,57.88 101.9,57.07 99.78,57.07 98.62,55.91 98.14,55.91 97.71,55.48 96.75,55.48 v3(96.39,55.83)
  BOTTOM w0.102: v3(55.86,27.35) 55.64,27.57 55.64,28.06 55.17,28.53 JDIMM1.250
DDR_M0_D63: length 69.5
  IN1 w0.076: v3(96.97,55.84) 97.03,55.78 97.03,54.74 96.96,54.66 96.47,54.66 95.82,54.01 92.68,54.01 90.36,51.69 90.36,51.58 89.68,50.9
  IN1 w0.127: v3(57.13,27.35) 57.63,27.86 68.95,27.86 69.53,28.43 75.76,28.43 81.14,33.8 81.14,35.07 84.12,38.06 85.54,38.06 89.14,41.66 89.14,50.36 89.68,50.9
  BOTTOM w0.076: v3(96.97,55.84) 97.32,56.19 98.66,56.19 99.71,57.24 101.79,57.24 102.69,58.14 UC1.BG37
  BOTTOM w0.102: v3(57.13,27.35) 56.36,28.12 56.21,28.12 55.45,28.88 55.45,29.14 55.06,29.53 JDIMM1.246
DDR_M0_DQS0: length 72.9
  IN1 w0.127: v3(58.64,91.25) 58.64,92.03 58.93,92.32 60.3,92.32 60.37,92.24 60.79,92.24 60.87,92.32 61.37,92.32 61.7,92.65 62.89,93.83 62.89,94.01 62.13,94.78 62.13,95.16 62.55,95.58 62.94,95.58 63.7,94.82 63.88,94.82 65.42,96.36 85.1,96.36 85.79,97.05 105.77,97.05 109,93.82 109,92.36 109.18,92.19 109.18,91.66 108.9,91.38 v3(108.33,91.38)
  BOTTOM w0.076: UC1.D27 109.24,84.78 109.2,84.89 109.15,85.02 109.11,85.16 109.21,85.47 109.2,85.53 109.13,85.82 109.15,85.89 109.19,86.11 109.19,86.35 109.19,86.35 109.19,86.66 109.19,86.79 109.19,87.05 109.03,87.2 109.03,91.23 108.87,91.4 108.6,91.4 108.54,91.46 108.4,91.46 v3(108.33,91.38)
  BOTTOM w0.102: v3(58.64,91.25) 58.64,90.93 58.65,90.93 58.65,90.5 58.83,90.32 59.77,89.91 61.47,89.78 JDIMM1.13
DDR_M0_DQS1: length 65.5
  IN1 w0.127: v3(57.48,86.49) 57.44,86.49 57.1,86.15 57.1,86.03 57.23,85.9 58.12,85.9 59.38,87.16 64.62,87.16 69.99,92.53 101.52,92.53 103.53,90.52 105.26,90.52 105.41,90.67 105.41,90.86 105.08,91.19 v3(105.08,91.2)
  BOTTOM w0.076: 105.75,89.82 105.75,89.8 105.76,89.79 105.76,89.25 107.43,87.58 107.43,87.3 107.28,87.15 107.28,86.01 107.31,85.92 107.32,85.87 107.32,85.72 107.28,85.6 107.28,85.44 107.34,85.22 107.34,85.08 107.29,84.96 107.17,84.84 107.05,84.83 106.96,84.89 106.95,84.97 UC1.C31
  BOTTOM w0.102: v3(57.48,86.49) 57.24,86.25 57.24,85.92 55.98,84.66 55.27,84.66 55.14,84.53 JDIMM1.34 ; v3(105.08,91.2) 105.39,90.89 105.39,90.63 105.75,90.28 105.75,89.82
DDR_M0_DQS2: length 64.3
  IN1 w0.127: v3(99.64,86.77) 99.69,86.82 99.69,87 98.26,88.44 72.92,88.44 64.85,80.37 63.51,80.37 63.33,80.2 62.69,80.2 62.41,80.47 62.41,80.84 62.28,80.96 61.9,80.96 61.78,80.84 61.78,80.47 61.5,80.2 60.91,80.2 60.63,80.47 60.63,80.84 60.51,80.96 60.12,80.96 60,80.84 60,80.47 59.72,80.2 58.22,80.2 57.95,80.47 57.95,80.77 v3(57.84,80.88)
  BOTTOM w0.076: v3(99.64,86.77) 99.82,86.59 99.82,85.92 99.84,85.89 99.84,84.7 101.37,83.18 101.37,81.31 101.77,80.9 102.11,80.9 102.42,81.05 103.39,81.05 103.54,81 103.71,81 103.77,81.01 103.79,81.02 103.8,81.02 103.87,81.04 104.06,81.04 104.15,81.01 104.17,81 104.42,81 104.51,81.04 104.64,81.17 UC1.J34
  BOTTOM w0.102: JDIMM1.55 61.16,79.28 58.09,80.02 57.89,80.27 57.89,80.29 57.89,80.41 57.89,80.83 v3(57.84,80.88)
DDR_M0_DQS3: length 64.9
  IN1 w0.076: 89.01,84.13 89.02,84.14 89.69,84.14 93.09,85.08 94.57,85.08 95.42,84.84 96.31,84.39 97.54,83.98 97.62,83.97 97.94,83.97 v3(98.3,84.34)
  IN1 w0.127: v3(58.44,75.52) 58.28,75.67 58.28,75.94 58,76.22 56.92,76.22 56.49,75.8 56.49,75.24 56.89,74.84 64.77,74.84 74.06,84.13 89.01,84.13
  BOTTOM w0.076: v3(98.3,84.34) 98.3,83.79 98.79,82.8 99.4,82.19 99.4,80.47 99.72,80.15 100.24,80.15 101.83,78.57 102.22,78.57 102.36,78.71 103.08,78.71 103.09,78.72 103.37,78.72 103.53,78.67 103.73,78.67 103.89,78.72 104.04,78.72 104.22,78.64 104.31,78.64 104.38,78.72 104.38,78.83 UC1.P35
  BOTTOM w0.102: JDIMM1.76 56.86,74.02 58.12,74.49 58.44,74.81 v3(58.44,75.52)
DDR_M0_DQS4: length 61.7
  IN1 w0.076: 89.01,65.1 89.02,65.1 89.04,65.08 90.93,65.08 90.95,65.06 96.26,65.06 96.36,65.16 96.36,65.31 96.18,65.49 v3(96.03,65.49)
  IN1 w0.127: 89.01,65.1 86.24,65.1 75.97,54.83 75.97,54.02 75.5,53.54 75.5,53.15 75.62,53.03 75.62,52.85 75.44,52.67 75.26,52.67 75.14,52.79 74.75,52.79 74.42,52.47 74.42,52.08 74.52,51.98 74.52,51.8 74.33,51.62 74.16,51.62 74.06,51.72 73.67,51.72 73.34,51.39 73.34,51 73.44,50.9 73.44,50.72 73.26,50.54 73.08,50.54 72.98,50.64 72.59,50.64 68.77,46.82 68.55,46.82 67.89,46.16 67.89,45.94 67.72,45.77 62.17,45.77 61.9,45.49 61.9,45.09 61.73,44.93 60.43,44.93 60.3,45.05 60.3,45.28 60.58,45.55 v3(60.59,45.55)
  BOTTOM w0.076: UC1.AP34 104.83,66.34 104.76,66.41 104.76,66.59 104.69,66.66 104.4,66.78 104.2,66.78 104.06,66.73 103.87,66.73 103.72,66.8 103.54,66.8 103.51,66.77 103.38,66.73 103.16,66.73
  BOTTOM w0.089: v3(96.03,65.49) 96.3,65.76 96.3,65.87 96.51,66.08 99.67,66.08 100.17,66.59 101.48,66.59 101.75,66.85 102.22,66.85 102.33,66.74 102.38,66.74 102.38,66.74 102.65,66.74 102.81,66.74 103.15,66.74 103.16,66.73
  BOTTOM w0.102: JDIMM1.179 61.75,46.27 61.47,46.56 61.24,46.56 60.96,46.27 60.36,46.27 60.26,46.17 60.26,45.82 60.53,45.55 v3(60.59,45.55)
DDR_M0_DQS5: length 67.7
  IN1 w0.076: 92.51,60.98 92.52,60.98 92.55,61 93.41,61 94.03,61.62 94.57,61.62 94.87,61.92 94.87,62.11 v3(95.21,62.45)
  IN1 w0.127: 92.51,60.98 87.8,60.98 80.12,53.3 80.12,47.06 75.91,42.84 71.64,42.84 68.98,40.19 59.49,40.19 58.46,39.16 57.59,39.16 57.32,39.43 57.32,39.91 v3(57.15,40.07)
  BOTTOM w0.076: UC1.AV35 104.34,63.87 104.49,63.87 104.57,63.79 104.57,63.67 104.49,63.59 104.38,63.55 104.21,63.55 104.03,63.61 103.86,63.61 103.74,63.57 103.53,63.57 103.44,63.61 102.39,63.61 102.38,63.62
  BOTTOM w0.089: v3(95.21,62.45) 95,62.24 95,62.05 95.09,61.96 95.39,61.96 95.65,62.23 95.65,62.64 96.05,63.03 97.25,63.03 97.25,63.03 97.72,63.03 97.72,63.03 99.37,63.03 99.55,62.86 100.37,62.86 100.88,63.38 101.44,63.38 101.55,63.49 102.04,63.49 102.06,63.51 102.11,63.51 102.22,63.62 102.38,63.62
  BOTTOM w0.102: v3(57.15,40.07) 57.36,40.28 57.36,40.57 57.18,40.75 56.3,40.75 55.93,41.12 55.33,41.12 55.23,41.03 JDIMM1.200
DDR_M0_DQS6: length 70.3
  IN1 w0.076: 92.51,57.37 92.51,57.37 92.54,57.34 93.76,58.56 93.76,58.68 94.7,59.62 97.25,59.62 97.45,59.42 97.48,59.42 97.81,59.09 v3(97.93,59.09)
  IN1 w0.127: 92.51,57.37 92.5,57.37 92.5,57.36 89.28,57.36 83.68,51.76 83.68,45.53 73.02,34.88 62.7,34.88 62.43,34.6 62.43,33.74 62.3,33.61 61.92,33.61 61.79,33.74 61.79,34.6 61.51,34.88 60.93,34.88 60.66,34.6 60.66,33.57 60.53,33.45 59.36,33.45 59.3,33.51 59.3,33.66 59.35,33.71 59.36,33.71 v3(59.6,33.96)
  BOTTOM w0.076: UC1.BB34 104.87,61.3 104.8,61.23 104.8,61.11 104.63,60.94 104.52,60.91 104.37,60.85 104.2,60.85 104.06,60.91 103.85,60.91 103.71,60.86 103.53,60.86 103.43,60.91 102.52,60.91 102.51,60.9 102.36,60.9 102.36,60.9 102.21,60.75 101.38,60.75 100.13,59.5 97.68,59.5 97.66,59.48
  BOTTOM w0.089: v3(97.93,59.09) 97.75,59.09 97.66,59.18 97.66,59.48
  BOTTOM w0.102: JDIMM1.221 61.64,35.78 61.54,35.87 61.22,35.87 60.42,35.07 59.48,35.07 59.18,34.77 59.18,34.33 59.56,33.96 v3(59.6,33.96)
DDR_M0_DQS7: length 71.1
  IN1 w0.076: v3(95.27,55.17) 95.49,54.95 95.49,54.85 95.19,54.55 92.17,54.55 90.61,52.99 90.22,52.99 89.68,52.45
  IN1 w0.127: v3(57.57,28.7) 57.65,28.7 57.82,28.87 57.82,29.04 57.89,29.1 57.89,29.1 58.16,29.37 59.16,29.37 59.59,28.95 66.05,28.95 66.62,29.52 75.1,29.52 79.35,33.77 79.35,35.17 84.46,40.28 85.71,40.28 87.87,42.44 87.87,50.63 89.68,52.45
  BOTTOM w0.076: 95.6,55.37 95.6,55.38 95.61,55.39 95.61,55.9 96.23,56.52 98.48,56.52 99.59,57.62 100.96,57.62 101.47,57.62 101.66,57.62 102.23,58.18 102.63,58.58 103.44,58.58 103.53,58.53 103.74,58.53 103.86,58.58 104.03,58.58 104.21,58.52 104.38,58.52 104.49,58.56 104.57,58.64 104.57,58.76 104.49,58.84 104.34,58.84 UC1.BF35
  BOTTOM w0.089: 95.6,55.37 95.4,55.17 v3(95.27,55.17)
  BOTTOM w0.102: v3(57.57,28.7) 57.67,28.8 57.67,28.88 57.38,29.17 56.49,29.17 55.14,30.53 JDIMM1.242
DDR_M0_DQS#0: length 73
  IN1 w0.127: v3(59.33,91.25) 59.41,91.34 59.41,91.54 59.28,91.67 59,91.67 58.9,91.77 58.9,91.92 59.03,92.06 60.19,92.06 60.27,91.99 60.9,91.99 60.98,92.06 61.48,92.06 61.96,92.54 63.15,93.73 63.15,94.12 62.38,94.88 62.38,95.06 62.65,95.33 62.83,95.33 63.59,94.57 63.98,94.57 65.52,96.11 85.21,96.11 85.89,96.79 105.67,96.79 108.75,93.72 108.75,92.26 108.92,92.08 108.92,91.77 108.8,91.64 108.71,91.64 v3(108.33,92.02)
  BOTTOM w0.076: v3(108.33,92.02) 108.33,91.94 108.68,91.59 108.95,91.59 109.2,91.34 109.2,87.29 109.37,87.12 109.37,86.72 109.37,86.36 109.36,86.35 109.36,86.28 109.36,86.28 109.36,86.1 109.31,85.8 109.38,85.47 109.28,85.15 109.31,85.07 109.38,84.88 109.5,84.82 109.61,84.86 109.65,84.96 UC1.C27
  BOTTOM w0.102: v3(59.33,91.25) 59.43,91.15 59.43,90.98 59.33,90.88 58.96,90.88 58.86,90.78 58.86,90.59 58.96,90.5 59.82,90.12 61.41,90 61.51,90.1 61.51,90.17 61.62,90.28 JDIMM1.11
DDR_M0_DQS#1: length 65.5
  IN1 w0.127: v3(105.66,91.2) 105.66,90.56 105.37,90.26 103.42,90.26 101.42,92.27 70.09,92.27 64.72,86.91 59.49,86.91 58.23,85.65 57.12,85.65 56.84,85.93 v3(56.84,86.49)
  BOTTOM w0.076: UC1.D31 107.06,84.56 107.36,84.69 107.53,85.1 107.53,85.14 107.46,85.41 107.46,85.57 107.5,85.69 107.5,85.89 107.49,85.97 107.46,86.04 107.46,87.08 107.61,87.23 107.61,87.67 105.95,89.33 105.95,89.79 105.95,89.8 105.95,89.8 105.95,89.82
  BOTTOM w0.102: v3(56.84,86.49) 57.02,86.31 57.02,86.01 55.89,84.88 55.27,84.88 55.12,85.02 JDIMM1.32 ; v3(105.66,91.2) 105.61,91.15 105.61,90.72 105.95,90.38 105.95,89.82
DDR_M0_DQS#2: length 64.2
  IN1 w0.127: v3(100.22,86.77) 100.19,86.77 100.03,86.93 100.03,87.03 98.36,88.69 72.81,88.69 64.74,80.62 63.4,80.62 63.23,80.45 62.79,80.45 62.66,80.58 62.66,80.94 62.39,81.22 61.8,81.22 61.52,80.94 61.52,80.58 61.39,80.45 61.01,80.45 60.89,80.58 60.89,80.94 60.61,81.22 60.02,81.22 59.74,80.94 59.74,80.58 59.62,80.45 58.33,80.45 58.2,80.58 58.2,80.68 58.41,80.88 v3(58.47,80.88)
  BOTTOM w0.076: UC1.J35 104.45,81.44 104.52,81.36 104.49,81.28 104.4,81.19 104.35,81.17 104.2,81.17 104.05,81.22 103.84,81.22 103.74,81.19 103.7,81.19 103.56,81.19 103.41,81.23 102.38,81.23 102.07,81.08 101.85,81.08 101.55,81.38 101.55,83.25 100.01,84.79 100.01,85.96 99.98,85.99 99.98,86.66 100.09,86.77 v3(100.22,86.77)
  BOTTOM w0.102: v3(58.47,80.88) 58.47,80.66 58.38,80.57 58.21,80.57 58.11,80.47 58.11,80.35 58.22,80.21 61.18,79.49 61.37,79.49 61.49,79.61 61.49,79.71 61.55,79.78 JDIMM1.53
DDR_M0_DQS#3: length 65
  IN1 w0.076: v3(97.89,84.75) 97.95,84.7 97.95,84.27 97.81,84.14 97.63,84.14 97.58,84.15 96.37,84.55 95.48,84.99 94.59,85.25 93.06,85.25 89.67,84.31 89.08,84.31 89.01,84.39
  IN1 w0.127: 89.01,84.39 73.95,84.39 64.67,75.1 56.99,75.1 56.75,75.34 56.75,75.69 57.02,75.97 57.9,75.97 58.03,75.84 58.03,75.74 v3(57.8,75.52)
  BOTTOM w0.076: v3(97.89,84.75) 97.95,84.7 97.95,84.19 98.14,84 98.14,83.75 98.65,82.71 99.21,82.15 99.21,80.39 99.65,79.96 100.17,79.96 101.75,78.38 102.3,78.38 102.44,78.52 103.16,78.52 103.16,78.53 103.42,78.53 103.52,78.48 103.75,78.48 103.85,78.53 104.07,78.53 104.21,78.45 104.38,78.45 104.41,78.48 104.56,78.54 UC1.P34
  BOTTOM w0.102: v3(57.8,75.52) 57.84,75.52 58.22,75.13 58.22,74.9 58,74.68 56.82,74.24 55.4,74.24 55.11,74.53 JDIMM1.74
DDR_M0_DQS#4: length 61.7
  IN1 w0.076: v3(96.67,65.49) 96.57,65.39 96.57,65.08 96.34,64.85 90.86,64.85 90.85,64.87 89.14,64.87 89.11,64.85 89.01,64.85
  IN1 w0.127: 89.01,64.85 86.35,64.85 76.22,54.72 76.22,53.91 75.75,53.44 75.75,53.26 75.88,53.13 75.88,52.74 75.55,52.41 75.16,52.41 75.03,52.54 74.85,52.54 74.67,52.36 74.67,52.18 74.77,52.08 74.77,51.69 74.44,51.36 74.05,51.36 73.95,51.46 73.77,51.46 73.59,51.28 73.59,51.1 73.69,51 73.69,50.61 73.36,50.28 72.97,50.28 72.87,50.38 72.69,50.38 68.88,46.57 68.66,46.57 68.14,46.05 68.14,45.83 67.82,45.51 62.28,45.51 62.15,45.39 62.15,44.99 61.84,44.67 60.32,44.67 60.05,44.95 60.05,45.46 v3(59.96,45.55)
  BOTTOM w0.076: 103.08,66.52 103.25,66.52 103.26,66.54 103.39,66.54 103.59,66.61 103.6,66.62 103.71,66.62 103.9,66.54 103.99,66.54 104.23,66.62 104.36,66.62 104.5,66.55 104.55,66.51 104.55,66.4 104.49,66.34 UC1.AP35
  BOTTOM w0.089: v3(96.67,65.49) 96.5,65.66 96.5,65.79 96.59,65.88 99.75,65.88 100.26,66.38 101.57,66.38 101.83,66.65 102.13,66.65 102.24,66.54 102.3,66.54 102.3,66.54 102.57,66.54 102.57,66.54 102.72,66.54 102.81,66.53 103.07,66.53 103.08,66.52
  BOTTOM w0.102: v3(59.96,45.55) 60.05,45.64 60.05,46.26 60.27,46.49 60.87,46.49 61.15,46.78 JDIMM1.177
DDR_M0_DQS#5: length 67.8
  IN1 w0.076: v3(94.57,62.45) 94.67,62.35 94.67,62.01 94.49,61.82 93.95,61.82 93.33,61.2 92.55,61.2 92.52,61.23 92.51,61.23
  IN1 w0.127: v3(57.78,40.07) 57.7,40.07 57.57,39.94 57.57,39.54 57.7,39.41 58.35,39.41 59.39,40.44 68.88,40.44 71.53,43.1 75.8,43.1 79.87,47.16 79.87,53.4 87.69,61.23 92.51,61.23
  BOTTOM w0.076: UC1.AV34 104.87,63.82 104.8,63.74 104.8,63.63 104.63,63.46 104.52,63.42 104.37,63.37 104.2,63.37 104.06,63.42 103.85,63.42 103.71,63.38 103.53,63.38 103.43,63.42 102.39,63.42 102.38,63.42
  BOTTOM w0.089: 102.38,63.42 102.31,63.42 102.19,63.3 102.14,63.3 102.12,63.28 101.64,63.28 101.53,63.17 100.97,63.17 100.45,62.66 99.46,62.66 99.29,62.83 97.64,62.83 97.64,62.83 97.34,62.83 96.13,62.83 95.86,62.55 95.86,62.14 95.47,61.76 94.97,61.76 94.76,61.97 94.76,62.26 v3(94.57,62.45)
  BOTTOM w0.102: JDIMM1.198 55.19,41.53 55.38,41.33 56.02,41.33 56.39,40.97 57.27,40.97 57.58,40.66 57.58,40.28 v3(57.78,40.07)
DDR_M0_DQS#6: length 70.2
  IN1 w0.076: v3(97.31,59.09) 97.26,59.14 97.26,59.32 97.16,59.41 94.78,59.41 93.96,58.6 93.96,58.48 92.59,57.11 92.51,57.11
  IN1 w0.127: v3(58.97,33.96) 59.05,33.88 59.05,33.4 59.25,33.19 60.64,33.19 60.91,33.47 60.91,34.49 61.04,34.62 61.41,34.62 61.54,34.49 61.54,33.63 61.81,33.36 62.4,33.36 62.68,33.63 62.68,34.49 62.81,34.62 73.13,34.62 83.93,45.42 83.93,51.65 89.38,57.11 92.51,57.11
  BOTTOM w0.076: 97.45,59.48 97.45,59.49 97.46,59.5 97.46,59.56 97.58,59.68 97.59,59.68 97.6,59.69 100.06,59.69 101.3,60.94 102.13,60.94 102.28,61.09 102.51,61.09 102.52,61.1 103.44,61.1 103.53,61.05 103.74,61.05 103.86,61.1 104.03,61.1 104.21,61.03 104.38,61.03 104.49,61.07 104.57,61.16 104.57,61.27 104.49,61.35 104.34,61.35 UC1.BB35
  BOTTOM w0.089: 97.45,59.48 97.45,59.24 97.31,59.09 v3(97.31,59.09)
  BOTTOM w0.102: JDIMM1.219 61.7,36.28 61.51,36.09 61.13,36.09 60.33,35.29 59.39,35.29 58.97,34.86 v3(58.97,33.96)
DDR_M0_DQS#7: length 71.1
  IN1 w0.076: 89.68,52.09 89.87,52.28 89.87,52.41 90.29,52.83 90.73,52.83 92.25,54.34 95.27,54.34 95.69,54.76 95.69,54.95 v3(95.91,55.17)
  IN1 w0.127: 89.68,52.09 88.12,50.53 88.12,42.33 85.81,40.03 84.56,40.03 79.6,35.06 79.6,33.66 75.21,29.27 66.73,29.27 66.15,28.69 59.48,28.69 59.06,29.12 58.26,29.12 58.21,29.06 v3(58.21,28.7)
  BOTTOM w0.076: UC1.BF34 104.87,58.79 104.8,58.71 104.8,58.59 104.63,58.43 104.52,58.39 104.37,58.34 104.2,58.34 104.06,58.39 103.85,58.39 103.71,58.34 103.53,58.34 103.43,58.39 102.7,58.39 102.36,58.05 101.74,57.43 101.47,57.43 100.96,57.43 99.63,57.43 98.55,56.35 96.3,56.35 95.8,55.85 95.8,55.39 95.81,55.38 95.81,55.37
  BOTTOM w0.089: 95.81,55.37 95.81,55.27 v3(95.91,55.17)
  BOTTOM w0.102: v3(58.21,28.7) 58.16,28.7 57.47,29.39 56.58,29.39 55.57,30.4 55.57,30.41 54.96,31.03 JDIMM1.240
DDR_M0_MA0: length 67.4
  IN1 w0.076: 88.68,74.49 90.07,74.49 92.51,72.05 97.25,72.05 98.27,73.07 98.27,73.71 98.06,73.92 97.46,73.92 v3(97.18,73.64)
  IN1 w0.157: v3(56.32,56.69) 56.32,55.84 56.17,55.68 55.61,55.68 55.45,55.84 55.45,58.1 55.61,58.26 56.27,58.26 56.43,58.1 56.43,57.45 56.59,57.3 56.9,57.3 57.06,57.45 57.06,58.1 57.22,58.26 64.13,58.26 80.37,74.49 88.68,74.49
  BOTTOM w0.076: UC1.AC37 103.22,73.33 103.04,73.33 102.47,73.33 102.32,73.18 102.16,73.18 102.15,73.18 101.74,73.18 101.59,73.33 99.02,73.33 98.87,73.18 97.63,73.18 v3(97.18,73.64)
  BOTTOM w0.127: v3(56.32,56.69) 55.99,57.03 JDIMM1.144
DDR_M0_MA1: length 68.7
  IN1 w0.076: v3(96.57,73.49) 96.09,73 92.04,73 89.72,75.32 87.86,75.32
  IN1 w0.157: 87.86,75.32 80.03,75.32 70.4,65.69 70.18,65.69 69.53,66.34 69.31,66.34 69.08,66.11 69.08,65.89 69.73,65.24 69.73,65.02 69.51,64.8 69.29,64.8 68.64,65.45 68.41,65.45 68.19,65.22 68.19,65 68.84,64.35 68.84,64.13 68.62,63.91 68.39,63.91 67.75,64.56 67.52,64.56 67.3,64.33 67.3,64.11 67.95,63.46 67.95,63.24 67.73,63.02 67.5,63.02 66.86,63.66 66.63,63.66 66.41,63.44 66.41,63.22 67.06,62.57 67.06,62.35 66.83,62.13 66.61,62.13 65.96,62.77 65.74,62.77 65.52,62.55 65.52,62.33 66.17,61.68 66.17,61.46 65.94,61.23 65.72,61.23 65.07,61.88 64.85,61.88 64.63,61.66 64.63,61.44 65.28,60.79 65.28,60.57 65.05,60.34 64.83,60.34 64.18,60.99 63.96,60.99 63.74,60.77 63.74,60.55 64.38,59.9 64.38,59.68 63.79,59.08 62.59,59.08 62.43,59.24 62.43,59.57 62.28,59.73 61.96,59.73 61.8,59.57 61.8,59.24 61.65,59.08 61.23,59.08 61.08,59.24 v3(61.08,59.53)
  BOTTOM w0.076: UC1.AC36 103.72,73.24 103.61,73.14 103.61,73.13 103.52,73.04 103.52,73.03 103.49,73.01 103.44,72.98 103.15,72.98 102.99,73.15 102.52,73.15 102.39,73.01 97.48,73.01 97.32,73.17 96.9,73.17 v3(96.57,73.49)
  BOTTOM w0.127: v3(61.08,59.53) 61.08,59.63 61.22,59.78 JDIMM1.133
DDR_M0_MA2: length 68.5
  IN1 w0.076: v3(97.91,73.56) 97.94,73.54 97.94,72.98 97.19,72.23 92.58,72.23 89.9,74.91 88.27,74.91
  IN1 w0.157: 88.27,74.91 80.2,74.91 63.96,58.67 55.16,58.67 55,58.83 55,59.31 55.16,59.47 56.79,59.47 57.08,59.17 58.17,59.17 58.47,59.47 v3(58.47,59.61)
  BOTTOM w0.076: UC1.AC34 105,73.5 103.88,73.5 103.72,73.45 103.69,73.46 103.52,73.46 103.4,73.5 102.42,73.5 102.42,73.5 102.39,73.5 102.38,73.5 102.23,73.35 101.81,73.35 101.66,73.5 99.39,73.5 99.19,73.7 98.05,73.7 v3(97.91,73.56)
  BOTTOM w0.127: v3(58.47,59.61) 58.47,59.79 58.23,60.03 58.22,60.03 58.03,60.21 57.69,60.21 57.51,60.03 JDIMM1.132
DDR_M0_MA3: length 69.6
  IN1 w0.076: 87.65,75.73 89.54,75.73 92.1,73.16 94.97,73.16 v3(95.41,73.61)
  IN1 w0.157: 87.65,75.73 79.86,75.73 75.9,71.77 75.68,71.77 75.03,72.42 74.81,72.42 74.6,72.22 74.6,72 75.25,71.35 75.25,71.12 75.03,70.9 74.81,70.9 74.16,71.55 73.93,71.55 73.71,71.33 73.71,71.1 74.36,70.46 74.36,70.23 74.14,70.01 73.91,70.01 73.27,70.66 73.04,70.66 72.82,70.44 72.82,70.21 73.47,69.57 73.47,69.34 73.25,69.12 73.02,69.12 72.38,69.77 72.15,69.77 71.93,69.54 71.93,69.32 72.58,68.67 72.58,68.45 72.35,68.23 72.13,68.23 71.48,68.88 71.26,68.88 71.04,68.65 71.04,68.43 71.69,67.78 71.69,67.56 71.46,67.34 71.24,67.34 70.59,67.99 70.37,67.99 70.15,67.76 70.15,67.54 70.8,66.89 70.8,66.67 70.57,66.45 70.35,66.45 69.7,67.09 69.48,67.09 62.52,60.14 60.29,60.14 v3(59.77,59.61)
  BOTTOM w0.076: v3(95.41,73.61) 96.01,73 97.25,73 97.41,72.85 102.46,72.85 102.59,72.99 102.92,72.99 103.08,72.82 103.48,72.82 103.59,72.88 103.62,72.9 103.65,72.92 104.3,72.92 UC1.AC35
  BOTTOM w0.127: JDIMM1.131 60.25,60.28 59.77,59.79 v3(59.77,59.61)
DDR_M0_MA4: length 66.8
  IN1 w0.076: 87.65,76.96 89.01,76.96 91.74,74.23 97.14,74.23 v3(97.5,74.59)
  IN1 w0.157: 87.65,76.96 79.34,76.96 78.77,76.39 78.55,76.39 77.98,76.96 77.76,76.96 77.54,76.74 77.54,76.52 78.11,75.95 78.11,75.73 77.87,75.49 77.64,75.49 77,76.14 76.77,76.14 76.5,75.86 76.5,75.64 77.15,74.99 77.15,74.77 76.93,74.55 76.7,74.55 76.06,75.19 75.83,75.19 75.61,74.97 75.61,74.75 76.26,74.1 76.26,73.88 76.04,73.66 75.81,73.66 75.16,74.3 74.94,74.3 64.4,63.76 63.6,63.76 62.29,62.45 62.07,62.45 61.84,62.68 61.62,62.68 61.4,62.45 61.4,62.23 61.63,62 61.63,61.78 61.22,61.37 59.92,61.37 59.77,61.53 v3(59.77,61.81)
  BOTTOM w0.076: v3(97.5,74.59) 98.95,74.59 99.14,74.4 99.49,74.4 99.88,74.01 101.26,74.01 101.66,74.41 102.25,74.41 102.35,74.3 102.38,74.28 103.08,74.28 103.09,74.28 103.43,74.28 103.48,74.3 103.49,74.31 103.79,74.31 103.85,74.28 104.08,74.28 104.52,74.44 UC1.AA35
  BOTTOM w0.127: JDIMM1.128 58.98,61.03 v3(59.77,61.81)
DDR_M0_MA5: length 68
  IN1 w0.076: 88.47,76.14 89.36,76.14 92.17,73.33 94.5,73.33 v3(94.81,73.64)
  IN1 w0.157: v3(57.23,61.81) 53.7,61.81 53.54,61.65 53.54,59.99 53.7,59.83 54.56,59.83 54.92,60.19 59.01,60.19 59.37,60.55 61.88,60.55 63.2,61.86 63.2,62.12 63.82,62.74 64.54,62.74 74.64,72.83 76.38,72.83 79.68,76.14 88.47,76.14
  BOTTOM w0.076: UC1.AB35 104.07,73.67 103.85,73.67 103.76,73.63 103.52,73.63 103.43,73.67 102.29,73.67 102.15,73.53 101.86,73.53 101.73,73.66 99.73,73.66 99.39,74
  BOTTOM w0.089: 99.39,74 95.17,74 v3(94.81,73.64)
  BOTTOM w0.127: v3(57.23,61.81) 56.94,61.53 JDIMM1.126
DDR_M0_MA6: length 67.7
  IN1 w0.076: v3(96.2,74.59) 91.62,74.59 88.83,77.37 87.65,77.37
  IN1 w0.157: v3(61.04,61.81) 61.04,62.04 60.73,62.35 53.79,62.35 53.63,62.5 53.63,62.73 53.79,62.89 61.2,62.89 61.4,63.09 62.35,63.09 63.96,64.7 64.75,64.7 77.43,77.37 87.65,77.37
  BOTTOM w0.076: v3(96.2,74.59) 96.9,75.29 97.79,75.29 98.13,74.95 99.1,74.95 99.48,74.57 99.56,74.57 99.95,74.17 101.12,74.17 101.52,74.57 102.31,74.57 102.45,74.44 103.02,74.44 103.11,74.54 UC1.AA37
  BOTTOM w0.127: JDIMM1.127 61.57,61.28 v3(61.04,61.81)
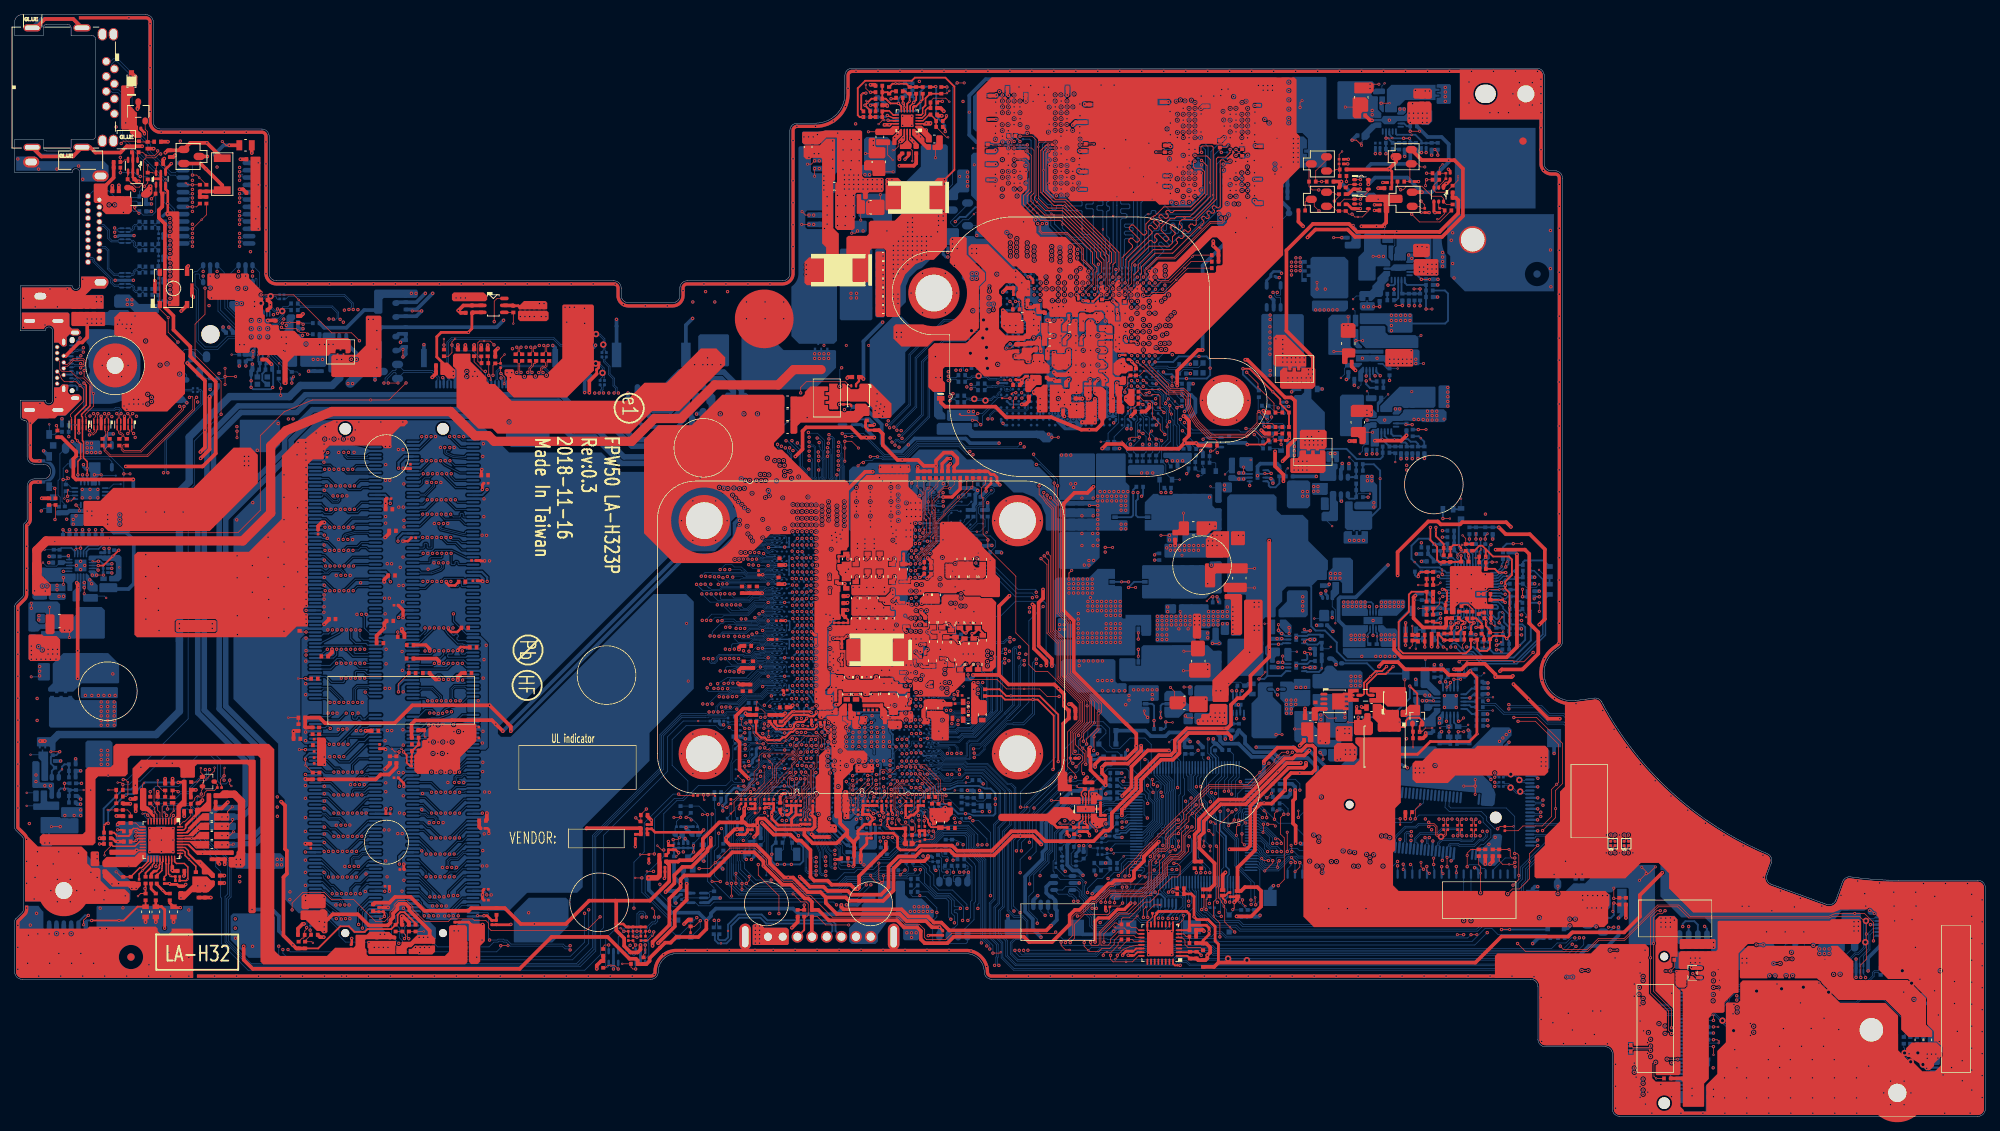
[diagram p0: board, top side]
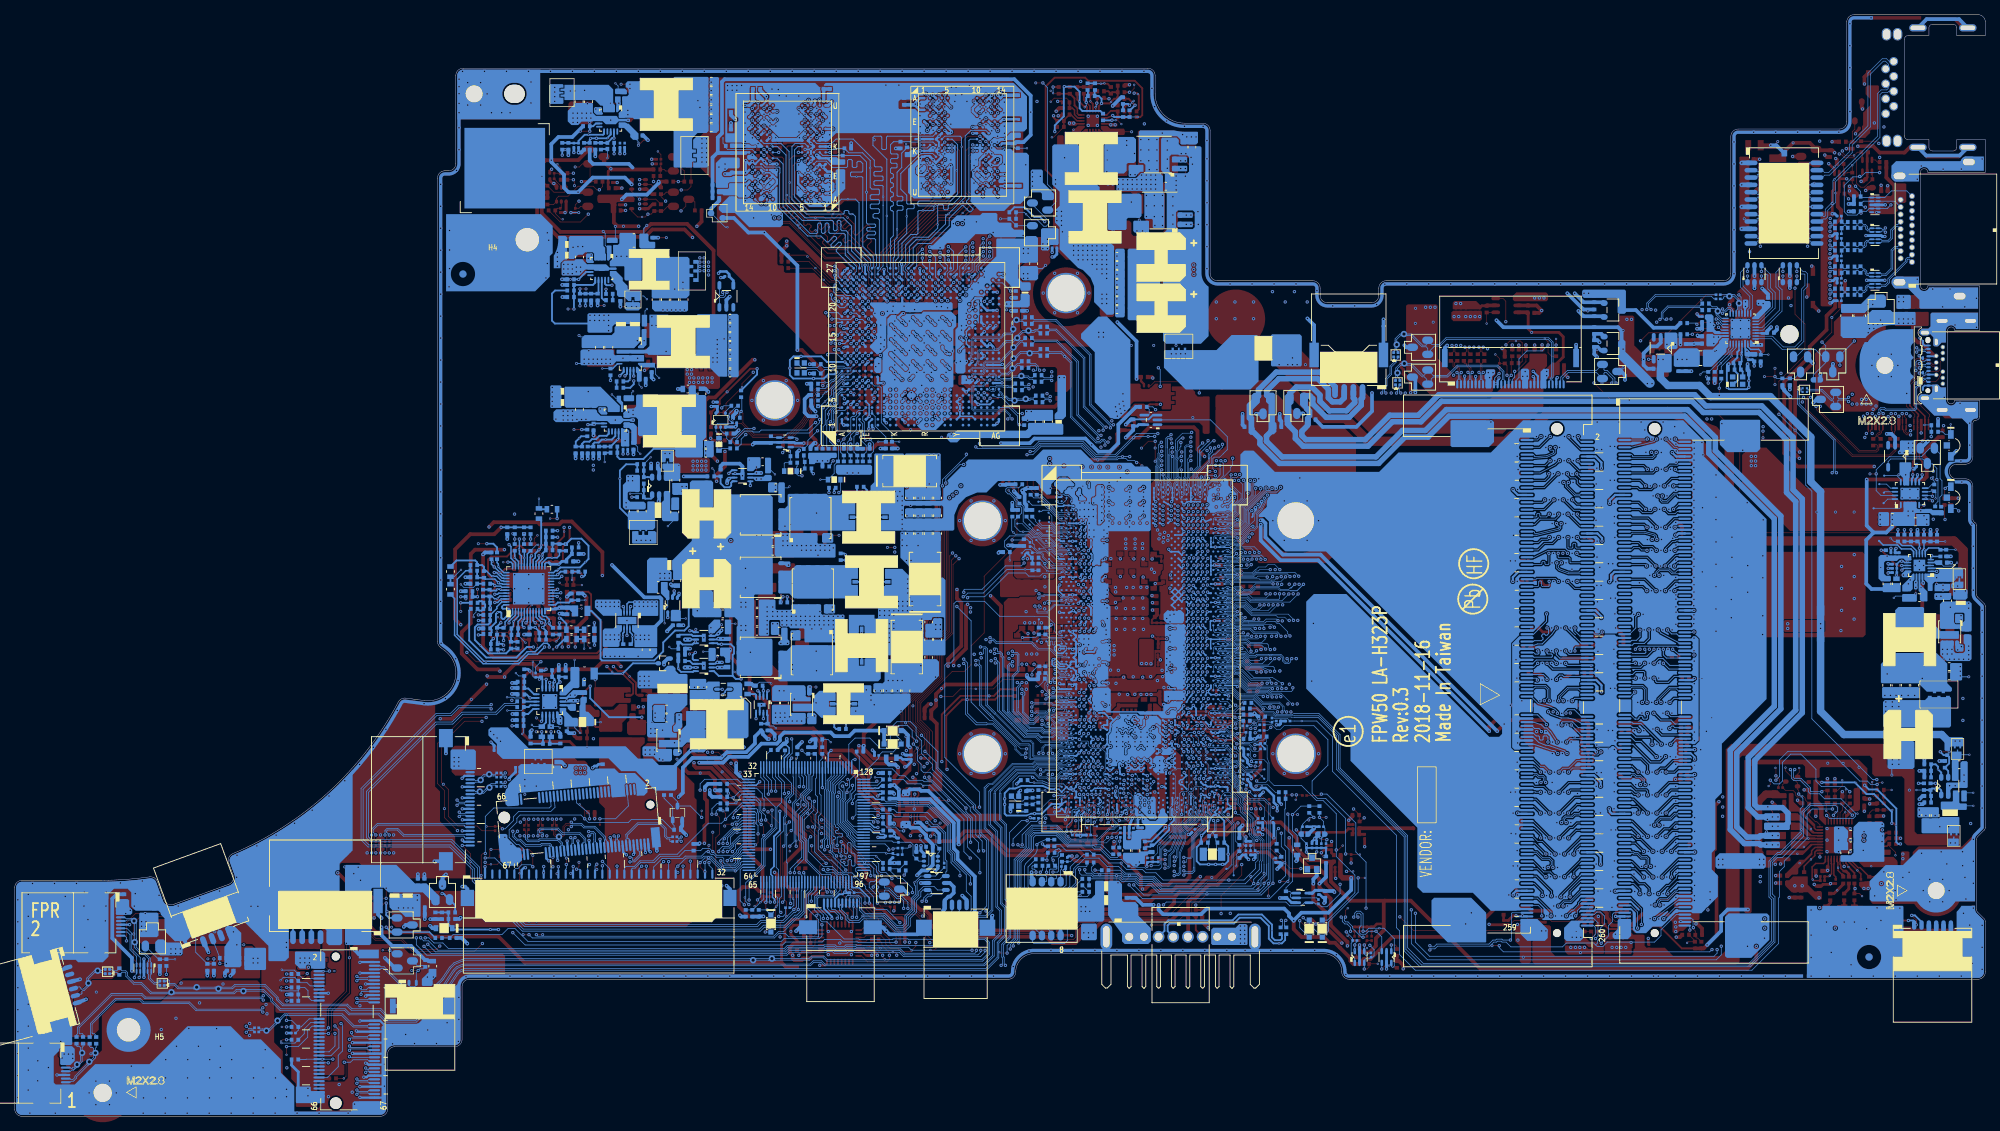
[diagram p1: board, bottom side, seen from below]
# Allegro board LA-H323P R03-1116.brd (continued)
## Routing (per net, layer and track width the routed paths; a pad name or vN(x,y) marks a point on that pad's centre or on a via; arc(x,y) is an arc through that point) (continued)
DDR_M0_MA7: length 67.8
  IN1 w0.076: v3(100.1,75.27) 99.6,74.77 98.97,74.77 98.46,75.28 91.63,75.28 88.3,78.61 87.65,78.61
  IN1 w0.157: v3(58.5,63.5) 58.5,63.68 58.21,63.96 57.55,63.96 57.17,64.34 55.09,64.34 54.94,64.5 54.94,64.71 55.06,64.84 57.18,64.84 57.58,65.24 60.15,65.24 62.06,67.15 62.52,67.15 63.53,66.14 63.76,66.14 63.91,66.3 63.91,66.52 63.74,66.69 63.74,66.91 63.96,67.14 64.19,67.14 64.36,66.96 64.58,66.96 76.23,78.61 87.65,78.61
  BOTTOM w0.076: v3(100.1,75.27) 100.59,74.77 102.35,74.77 102.5,74.63 102.97,74.63 103.13,74.79 103.44,74.79 103.49,74.77 103.63,74.63 103.77,74.56 UC1.AA36
  BOTTOM w0.127: JDIMM1.122 58.04,62.53 58.5,62.98 v3(58.5,63.5)
DDR_M0_MA8: length 66.1
  IN1 w0.076: 87.65,76.55 89.18,76.55 92.05,73.69 v3(93.62,73.69)
  IN1 w0.157: 87.65,76.55 79.51,76.55 76.21,73.24 74.46,73.24 64.37,63.15 63.57,63.15 61.39,60.96 59.15,60.96 58.9,60.71 55.64,60.71 55.48,60.87 55.48,61.21 55.64,61.37 58.34,61.37 58.5,61.52 v3(58.5,61.81)
  BOTTOM w0.076: UC1.AB34 104.69,74.14 104.17,74.14 104.11,74.12 103.82,74.12 103.76,74.14 103.52,74.14 103.44,74.11 102.29,74.11 102.15,74.24 101.74,74.24 101.59,74.09
  BOTTOM w0.089: v3(93.62,73.69) 94.11,74.18 99.47,74.18 99.81,73.83 101.33,73.83 101.59,74.09
  BOTTOM w0.127: v3(58.5,61.81) 58.95,62.26 61.23,62.26 61.71,61.78 JDIMM1.125
DDR_M0_MA9: length 66.2
  IN1 w0.076: v3(101.15,76.03) 101.05,75.92 101.05,75.07 100.42,74.44 99.04,74.44 98.37,75.11 91.57,75.11 88.48,78.2 87.65,78.2
  IN1 w0.157: 87.65,78.2 77.09,78.2 76.91,78.02 76.69,78.02 76.57,78.15 76.35,78.15 76.12,77.92 76.12,77.7 76.25,77.58 76.25,77.35 76.06,77.17 75.86,77.17 75.74,77.3 75.5,77.3 75.32,77.12 75.32,76.9 75.45,76.78 75.45,76.55 75.22,76.33 75,76.33 74.88,76.45 74.65,76.45 74.43,76.23 74.43,76.01 74.56,75.89 74.56,75.66 74.33,75.44 74.11,75.44 73.99,75.56 73.76,75.56 63.81,65.61 63.71,65.61 63.15,65.06 62.89,65.06 62.41,65.53 62.41,65.75 62.75,66.09 62.75,66.34 62.4,66.69 62.18,66.69 60.32,64.83 58.48,64.83 58.32,64.67 58.32,64.44 58.48,64.28 59.89,64.28 60.05,64.12 60.05,63.84 59.77,63.55 v3(59.77,63.5)
  BOTTOM w0.076: UC1.W36 103.91,75.75 103.6,75.59 103.45,75.5 103.15,75.5 102.95,75.7 101.91,75.7 101.71,75.91 101.27,75.91 v3(101.15,76.03)
  BOTTOM w0.127: v3(59.77,63.5) 59.77,63.21 59.64,63.08 59.16,63.08 59.04,62.95 59.04,62.73 59.13,62.64 61.55,62.64 61.69,62.78 JDIMM1.121
DDR_M0_MA10: length 66.3
  IN1 w0.076: v3(106.76,75.23) 106.43,75.56 105.78,75.56 105.62,75.4 105.62,75.26 105,74.64 104.52,74.64 103.04,73.16 101.57,73.16 98.54,70.14 92.2,70.14 91.11,71.23 89.01,71.23
  IN1 w0.157: 89.01,71.23 82.42,71.23 71.74,60.55 71.23,60.55 64.97,54.29 58.04,54.29 57.6,53.85 56.53,53.85 56.37,54.01 56.37,54.44 56.53,54.6 57.1,54.6 57.18,54.67 v3(57.18,55.02)
  BOTTOM w0.076: UC1.Y31 v3(106.76,75.23)
  BOTTOM w0.127: v3(57.18,55.02) 57.18,55.2 56.91,55.48 56.02,55.48 55.07,54.53 JDIMM1.146
DDR_M0_MA11: length 65.8
  IN1 w0.076: 87.65,79.02 88.12,79.02 91.69,75.45 99.41,75.45 v3(99.98,76.03)
  IN1 w0.157: 87.65,79.02 76.06,79.02 64.6,67.56 61.89,67.56 59.98,65.65 57.41,65.65 57.01,65.25 54.68,65.25 54.52,65.09 54.52,64.09 54.68,63.93 56.89,63.93 57.23,63.6 v3(57.23,63.5)
  BOTTOM w0.076: UC1.W34 104.61,75.44 104.28,75.44 104.26,75.42 103.64,75.42 103.49,75.34 103.08,75.34 102.9,75.52 101.85,75.52 101.75,75.63
  BOTTOM w0.089: 101.75,75.63 100.38,75.63 v3(99.98,76.03)
  BOTTOM w0.127: JDIMM1.120 56.77,63.03 57.23,63.49 v3(57.23,63.5)
DDR_M0_MA12: length 67
  IN1 w0.076: v3(101.43,75.15) 100.34,74.06 98.92,74.06 98.03,74.95 91.5,74.95 88.66,77.79 87.65,77.79
  IN1 w0.157: 87.65,77.79 77.26,77.79 74.39,74.91 74.16,74.91 74.04,75.03 73.82,75.03 73.59,74.81 73.59,74.59 73.72,74.47 73.72,74.24 73.49,74.02 73.27,74.02 73.15,74.14 72.93,74.14 72.7,73.92 72.7,73.7 72.83,73.57 72.83,73.35 72.6,73.13 72.38,73.13 72.26,73.25 72.03,73.25 71.81,73.03 71.81,72.81 71.94,72.68 71.94,72.46 71.71,72.24 71.49,72.24 71.37,72.36 71.14,72.36 70.92,72.14 70.92,71.92 71.04,71.79 71.04,71.57 70.82,71.35 70.6,71.35 70.47,71.47 70.25,71.47 70.03,71.25 70.03,71.03 70.15,70.9 70.15,70.68 69.93,70.46 69.71,70.46 69.58,70.58 69.36,70.58 69.14,70.36 69.14,70.13 69.26,70.01 69.26,69.79 69.04,69.56 68.82,69.56 68.69,69.69 68.47,69.69 68.25,69.47 68.25,69.24 68.37,69.12 68.37,68.9 68.15,68.67 67.93,68.67 67.8,68.8 67.58,68.8 67.36,68.57 67.36,68.35 67.48,68.23 67.48,68.01 67.26,67.78 67.03,67.78 66.91,67.91 66.69,67.91 66.47,67.68 66.47,67.46 66.59,67.34 66.59,67.11 66.37,66.89 66.14,66.89 66.02,67.02 65.8,67.02 65.57,66.79 65.57,66.57 65.7,66.45 65.7,66.22 65.47,66 65.25,66 65.13,66.12 64.91,66.12 64.68,65.9 64.68,65.68 64.81,65.56 64.81,65.33 64.58,65.11 64.36,65.11 64.24,65.23 64.02,65.23 63.88,65.1 63.78,65.1 63.13,64.45 62.91,64.45 61.83,65.53 61.61,65.53 61.39,65.31 61.39,65.09 62.46,64.01 62.46,63.78 62.25,63.57 62.03,63.57 60.94,64.66 60.74,64.66 60.47,64.39 60.47,64.17 61.04,63.6 v3(61.04,63.5)
  BOTTOM w0.076: UC1.AA34 104.61,74.86 103.68,74.86 103.61,74.89 103.61,74.89 103.53,74.93 103.49,74.96 103.05,74.96 102.89,74.79 102.59,74.79 102.23,75.15 v3(101.43,75.15)
  BOTTOM w0.127: v3(61.04,63.5) 61.03,63.49 60.99,63.49 60.87,63.36 60.87,63.18 60.99,63.06 61.37,63.06 61.59,63.28 JDIMM1.119
DDR_M0_MA13: length 67.4
  IN1 w0.076: 89.01,69.17 89.14,69.17 92.12,68.71 100.13,68.71 103.17,71.75 103.87,71.75 105.14,72.28 105.52,72.66 v3(106.02,73.38)
  IN1 w0.157: v3(57.1,51.06) 57.1,51.55 56.97,51.68 55.86,51.68 55.7,51.84 55.7,52.16 55.86,52.32 57.58,52.32 57.74,52.16 57.74,51.85 57.9,51.7 58.21,51.7 58.37,51.85 58.37,52.16 58.53,52.32 59.17,52.32 59.29,52.2 59.29,51.84 59.49,51.64 64.15,51.64 64.63,52.12 66.87,52.12 67.04,52.29 67.04,53.35 70.33,56.64 72.13,56.64 84.66,69.17 89.01,69.17
  BOTTOM w0.076: UC1.AC32 v3(106.02,73.38)
  BOTTOM w0.127: v3(57.1,51.06) 56.64,51.53 JDIMM1.158
DDR_M0_MA14_WE#: length 67.8
  IN1 w0.076: v3(106.58,73.37) 106.58,73.49 106.33,73.74 105.36,73.74 103.54,71.92 103.11,71.92 100.06,68.87 92.19,68.87 91.48,69.58 89.01,69.58
  IN1 w0.157: 89.01,69.58 84.49,69.58 84.06,69.15 83.84,69.15 83.41,69.58 83.19,69.58 82.96,69.36 82.96,69.14 83.39,68.71 83.39,68.49 83.17,68.26 82.95,68.26 82.52,68.69 82.3,68.69 82.07,68.47 82.07,68.25 82.5,67.82 82.5,67.6 82.28,67.37 82.05,67.37 81.63,67.8 81.4,67.8 81.18,67.58 81.18,67.35 81.61,66.93 81.61,66.7 81.39,66.48 81.16,66.48 80.74,66.91 80.51,66.91 80.29,66.69 80.29,66.46 80.72,66.04 80.72,65.81 80.5,65.59 80.27,65.59 79.85,66.02 79.62,66.02 79.4,65.79 79.4,65.57 79.83,65.14 79.83,64.92 79.6,64.7 79.38,64.7 78.95,65.13 78.73,65.13 78.51,64.9 78.51,64.68 78.94,64.25 78.94,64.03 71.95,57.05 70.06,57.05 65.59,52.58 64.51,52.58 64.03,52.1 61.79,52.1 61.73,52.05 60.96,52.05 v3(60.53,52.49)
  BOTTOM w0.076: UC1.AC31 v3(106.58,73.37)
  BOTTOM w0.127: JDIMM1.151 61.81,53.27 61.44,52.91 60.84,52.91 60.53,52.59 v3(60.53,52.49)
DDR_M0_MA15_CAS#: length 67
  IN1 w0.076: 89.01,69.99 91.3,69.99 92.24,69.06 94.75,69.06 94.77,69.04 99.14,69.04 101.23,71.13 101.23,71.19 102.12,72.08 103.47,72.08 105.29,73.91 105.72,73.91 v3(106.09,74.28)
  IN1 w0.157: 89.01,69.99 83.02,69.99 77.93,64.9 77.93,64.68 78.35,64.25 78.35,64.03 78.13,63.81 77.91,63.81 77.48,64.24 77.26,64.24 77.04,64.01 77.04,63.79 77.46,63.36 77.46,63.14 77.24,62.92 77.02,62.92 76.59,63.34 76.37,63.34 76.12,63.1 76.12,62.87 76.55,62.45 76.55,62.22 71.78,57.46 69.89,57.46 65.42,52.99 62.35,52.99 62.29,52.92 60.63,52.92 60.57,52.99 59.1,52.99 58.85,52.74 57.12,52.74 v3(56.46,53.4)
  BOTTOM w0.076: UC1.AB32 v3(106.09,74.28)
  BOTTOM w0.127: JDIMM1.156 55.09,52.03 v3(56.46,53.4)
DDR_M0_MA16_RAS#: length 64.7
  IN1 w0.076: 89.01,70.82 91.29,70.82 92.68,69.43 99.06,69.43 100.9,71.27 100.9,71.33 102.57,73 103.11,73 104.59,74.47 105.31,74.47 105.77,74.93 105.79,74.93 106.04,75.18 v3(106.08,75.18)
  IN1 w0.157: v3(57.73,53.4) 58.21,53.88 65.14,53.88 69.99,58.72 70.72,58.72 71.16,58.28 71.38,58.28 71.57,58.47 71.57,58.7 71.13,59.13 71.13,59.36 82.59,70.82 89.01,70.82
  BOTTOM w0.076: UC1.Y32 v3(106.08,75.18)
  BOTTOM w0.127: JDIMM1.152 55.5,53.03 56.29,53.82 57.67,53.82 57.8,53.69 57.8,53.46 v3(57.73,53.4)
DDR_M0_ODT0: length 69.9
  IN1 w0.076: v3(106.64,72.46) 106.11,71.93 105.9,71.93 105.48,71.51 103.17,71.51 100.2,68.54 89.02,68.54 89.01,68.56
  IN1 w0.157: v3(59.64,51.06) 59.64,50.75 59.89,50.5 60.37,50.5 60.52,50.66 60.52,50.87 60.68,51.03 61,51.03 61.15,50.87 61.15,50.66 61.31,50.5 61.63,50.5 61.78,50.66 61.78,50.87 61.94,51.03 62.26,51.03 62.41,50.87 62.41,50.66 62.57,50.5 64.33,50.5 64.49,50.66 64.49,51.11 64.65,51.27 64.96,51.27 65.12,51.11 65.12,50.66 65.28,50.5 65.59,50.5 65.75,50.66 65.75,51.35 65.91,51.51 66.18,51.51 66.34,51.35 66.34,50.66 66.5,50.5 66.87,50.5 67.02,50.66 67.02,51.31 68.17,52.46 68.17,52.68 67.82,53.04 67.82,53.26 69.71,55.15 69.94,55.15 70.61,54.48 70.83,54.48 71.06,54.7 71.06,54.92 70.38,55.6 70.38,55.82 70.58,56.02 70.85,56.02 71.51,55.37 71.73,55.37 84.91,68.56 89.01,68.56
  BOTTOM w0.076: UC1.AE31 v3(106.64,72.46)
  BOTTOM w0.127: JDIMM1.155 61.61,52.27 61.24,51.9 60.93,51.9 60.8,51.78 60.8,51.46 60.67,51.33 60.42,51.33 60.29,51.46 60.29,51.78 60.16,51.9 59.83,51.9 59.64,51.72 v3(59.64,51.06)
DDR_M0_ODT1: length 69.5
  IN1 w0.076: 89.01,67.73 93.01,68.19 98.65,68.19 98.68,68.21 100.34,68.21 101.66,69.54 102.9,69.54 103.74,70.38 104.29,70.38 104.88,70.97 106.82,70.97 v3(107.37,71.52)
  IN1 w0.157: v3(58.3,49.5) 57.74,50.07 55.95,50.07 55.82,50.2 55.82,50.49 55.97,50.63 58.01,50.63 58.42,50.22 59.01,50.22 59.55,49.68 68.01,49.68 72.98,54.65 72.98,55.46 85.25,67.73 89.01,67.73
  BOTTOM w0.076: v3(107.37,71.52) 107.37,71.52 UC1.AF31
  BOTTOM w0.127: v3(58.3,49.5) 58.65,49.85 58.87,49.92 59.04,49.92 60.69,50.48 61.56,50.78 JDIMM1.161
DDR_M0_PAR: length 64.3
  IN1 w0.076: 89.01,71.64 90.93,71.64 92.27,70.3 98.47,70.3 101.5,73.33 102.67,73.33 105.06,75.73 106.39,75.73 106.61,75.94 106.61,76.13 v3(106.68,76.2)
  IN1 w0.157: 89.01,71.64 82.25,71.64 71.57,60.96 70.88,60.96 64.61,54.7 64.61,54.7 58.63,54.7 v3(58.34,54.98)
  BOTTOM w0.076: UC1.W31 106.66,76.04 v3(106.68,76.2)
  BOTTOM w0.102: JDIMM1.143 61.92,57.27
  BOTTOM w0.127: v3(58.34,54.98) 58.34,55.21 58.68,55.55 59.51,55.92 59.52,55.92 60.96,56.31 61.92,57.27
DDR_M1_ACT#: length 75.3
  IN2 w0.076: 89.01,77.96 89.03,77.96 90.99,76 91.94,75.61 96.87,75.61 97.64,75.93 97.99,76.27 98.35,76.42 102.15,76.42 102.2,76.43 105.61,77.47 107.43,77.47 108.54,76.37 v3(108.54,76.2)
  IN2 w0.157: 89.01,77.96 74.6,77.96 66.76,70.13 54.62,70.13 54.08,69.9 53.42,69.24 53.19,69.15 50.85,69.15 49.58,68.65 48.46,67.53 48.24,67.44 45.89,67.44 45.53,67.29 v3(44.6,66.37)
  BOTTOM w0.076: v3(108.54,76.2) 108.55,76.17 108.61,76.16 UC1.W28
  BOTTOM w0.102: JDIMM2.114 41.74,64.53 41.89,64.67
  BOTTOM w0.127: v3(44.6,66.37) 44.24,65.93 41.89,64.67
DDR_M1_ALERT#: length 77.6
  IN2 w0.076: 89.01,75.49 89.39,75.49 90.15,75.08 90.79,74.44 95.36,74.04 97.77,74.04 101.71,73.53 102.22,73.53 105.52,73.73 108.71,73.73 108.89,73.91 109.55,73.91 109.62,73.99 109.62,74.58 109.55,74.66 108.45,74.66 v3(107.92,75.19)
  IN2 w0.157: 89.01,75.49 76.45,75.49 75.92,74.96 75.17,74.96 73.24,73.04 73.24,72.29 69.1,68.14 67.7,67.63 64.45,67.63 64.11,67.29 61.22,67.29 60.12,66.2 57.79,66.2 54.5,65.84 52.93,64.27 50.58,64.27 50.03,63.72 v3(47.72,63.72)
  BOTTOM w0.076: UC1.Y29 108.03,75.16 v3(107.92,75.19)
  BOTTOM w0.102: JDIMM2.116 41.89,64.03
  BOTTOM w0.127: v3(47.72,63.72) 47.3,64.14 42.05,64.14 41.94,64.03 41.89,64.03
DDR_M1_BA0: length 76.4
  IN2 w0.076: v3(96.46,69.78) 96.37,69.78 96.01,69.43 92.95,69.43 92.45,68.93 89.01,68.93
  IN2 w0.157: 89.01,68.93 80.12,68.93 77.07,65.89 76.14,65.89 74.03,63.78 74.03,63.56 74.28,63.31 74.28,63.09 74.05,62.87 73.83,62.87 73.58,63.11 73.36,63.11 73.14,62.89 73.14,62.67 73.38,62.42 73.38,62.2 73.16,61.98 72.94,61.98 72.69,62.22 72.47,62.22 68.61,58.36 67.43,58.36 67.26,58.2 67.26,56.78 67.11,56.62 66.68,56.62 66.52,56.78 66.52,56.97 66.36,57.13 65.92,57.13 65.76,56.97 65.76,56.78 65.6,56.62 65.29,56.62 65.13,56.78 65.13,56.97 64.97,57.13 64.66,57.13 64.5,56.97 64.5,56.78 64.34,56.62 64.03,56.62 63.87,56.78 63.87,56.97 63.71,57.13 62.29,57.13 62.14,56.97 62.14,56.78 61.98,56.62 61.66,56.62 61.51,56.78 61.51,56.97 61.35,57.12 55.54,57.12 54.56,56.14 54.56,55.26 53.82,54.53 45.37,54.53 45.21,54.68 v3(45.21,55)
  BOTTOM w0.076: UC1.AJ37 103.22,69.41 102.55,69.41 102.54,69.41 102.45,69.41 102.12,69.73 101.01,69.73 99.96,68.68 97.6,68.68 96.5,69.78 v3(96.46,69.78)
  BOTTOM w0.102: JDIMM2.150 41.89,53.53
  BOTTOM w0.127: 41.89,53.53 42.29,53.53 42.84,54.07 44.24,54.07 45.09,54.93 45.14,54.93 v3(45.21,55)
DDR_M1_BA1: length 77.9
  IN2 w0.076: v3(97.1,69.78) 97.1,69.68 96.69,69.26 93.01,69.26 92.28,68.52 89.01,68.52
  IN2 w0.157: 89.01,68.52 80.29,68.52 76.77,65 76.55,65 76.3,65.25 76.08,65.25 75.86,65.03 75.86,64.8 76.1,64.56 76.1,64.33 75.88,64.11 75.66,64.11 75.41,64.36 75.19,64.36 74.97,64.13 74.97,63.91 75.21,63.67 75.21,63.44 67.98,56.21 60.35,56.21 60.18,56.04 56.12,56.04 55.69,56.47 55.47,56.47 54.97,55.97 54.97,55.09 53.99,54.11 53.65,54.11 45.03,54.11 44.43,54.71 44.43,55.69 44.61,55.87 45.38,55.87 46.08,55.18 v3(46.08,54.96)
  BOTTOM w0.076: UC1.AJ36 103.91,69.5 103.61,69.67 103.48,69.74 103.38,69.77 103.22,69.77 103.21,69.76 103.17,69.76 102.98,69.57 102.61,69.57 102.61,69.57 102.51,69.57 102.19,69.9 100.94,69.9 100.03,68.99 97.81,68.99 97.14,69.66
  BOTTOM w0.089: 97.14,69.66 97.14,69.78 97.13,69.78 v3(97.1,69.78)
  BOTTOM w0.102: JDIMM2.145 48.38,54.78 47.79,54.19 47.73,54.19
  BOTTOM w0.127: v3(46.08,54.96) 46.08,54.95 46.08,54.32 46.21,54.19 46.59,54.19 46.71,54.32 46.71,54.45 46.84,54.58 47.09,54.58 47.22,54.45 47.22,54.32 47.35,54.19 47.69,54.19 47.69,54.19 47.73,54.19
DDR_M1_BG0: length 75.4
  IN2 w0.076: 89.01,77.55 89.21,77.55 89.42,77.34 91.32,75.44 99.76,75.44 99.98,75.66 100.34,75.66 100.37,75.64 102.3,75.64 102.89,76.23 105.05,76.23 105.42,76.6 107.53,76.6 v3(107.94,76.18)
  IN2 w0.157: 89.01,77.55 74.77,77.55 66.91,69.69 60.24,69.69 60.1,69.55 55.87,69.55 55.67,69.35 55.29,69.35 54.93,69.71 54.7,69.71 54.39,69.4 54.39,69.18 54.51,69.06 54.51,68.84 53.85,68.17 53.63,68.17 53.2,68.6 51.18,68.6 50.69,68.12 49.66,68.12 48.57,67.03 45.97,67.03 45.79,66.85 45.79,66.45 v3(45.87,66.37)
  BOTTOM w0.076: v3(107.94,76.18) 107.98,76.17 108.06,76.04 108.05,76.03 UC1.W29
  BOTTOM w0.102: JDIMM2.115 48.36,64.28
  BOTTOM w0.127: 48.36,64.28 48.13,64.28 47.89,64.52 46.48,64.52 45.82,65.18 45.82,66.32 v3(45.87,66.37)
DDR_M1_BG1: length 75.8
  IN2 w0.076: v3(108.74,75.23) 108.74,75.64 108.64,75.75 102.84,75.75 101.88,74.79 100,74.79 99.79,75.01 99.74,75.01 99.47,75.28 91.25,75.28 89.38,77.14 89.01,77.14
  IN2 w0.157: v3(47.09,66.33) 47.09,66.46 47.25,66.62 48.74,66.62 49.19,67.07 49.63,67.07 49.79,67.22 49.79,67.55 49.95,67.7 50.54,67.7 50.69,67.55 50.69,66.96 50.85,66.81 51.15,66.81 51.3,66.96 51.3,68.03 51.46,68.19 51.74,68.19 51.89,68.03 51.89,66.96 52.05,66.81 52.34,66.81 52.52,66.99 52.52,67.46 52.68,67.62 53.94,67.62 55.27,68.94 56.26,68.94 56.46,69.14 60.27,69.14 60.41,69.28 67.08,69.28 74.94,77.14 89.01,77.14
  BOTTOM w0.076: v3(108.74,75.23) 108.71,75.09 UC1.Y28
  BOTTOM w0.102: JDIMM2.113 48.36,64.78
  BOTTOM w0.127: v3(47.09,66.33) 47.08,66.31 47.08,65.44 47.58,64.94 48.2,64.94 48.36,64.78
DDR_M1_CKE0: length 73.3
  IN2 w0.076: v3(108.63,77.95) 108.63,78.15 108.28,78.5 103.18,78.5 102.13,77.45 98.28,77.45 96.77,75.94 92.29,75.94 91.92,76.3 91.15,76.3 89.9,77.56 89.9,78.32 89.51,78.71 89.51,78.91 89.43,78.99 89.01,78.99
  IN2 w0.157: v3(47.3,68.49) 48.98,70.17 51.46,70.17 52.31,71.03 53.73,71.03 53.85,71.15 66.21,71.15 74.05,78.99 89.01,78.99
  BOTTOM w0.076: UC1.T28 v3(108.63,77.95)
  BOTTOM w0.102: 47.98,66.31 48.51,65.78 JDIMM2.109
  BOTTOM w0.127: v3(47.3,68.49) 47.66,68.12 47.66,66.62 47.98,66.31
DDR_M1_CKE1: length 75.5
  IN2 w0.076: 89.01,78.58 89.41,78.58 89.73,78.25 89.73,77.49 91.09,76.14 91.85,76.14 92.22,75.77 96.84,75.77 97.6,76.54 98.93,77.28 102.55,77.28 102.58,77.26 102.94,77.26 103.1,77.41 105.48,78.34 107.48,78.34 107.87,77.95 v3(108,77.95)
  IN2 w0.157: 89.01,78.58 74.23,78.58 66.4,70.74 54.05,70.74 53.07,69.76 49.82,69.76 49.17,69.11 48.11,68.05 45.02,68.05 v3(43.33,66.37)
  BOTTOM w0.076: UC1.T29 v3(108,77.95)
  BOTTOM w0.102: JDIMM2.110 41.78,65.53 41.89,65.63
  BOTTOM w0.127: v3(43.33,66.37) 42.79,65.82 42.08,65.82 41.89,65.63
DDR_M1_CLK0: length 80.8
  IN2 w0.076: 89.01,69.58 89.02,69.58 89.04,69.61 92.64,69.61 93.16,70.14 101.47,70.14 102.14,70.8 104.78,70.8 104.94,70.96 107.96,70.96 108.07,70.85 108.07,70.74 v3(107.97,70.64)
  IN2 w0.127: v3(46.13,56.47) 46.24,56.36 46.24,55.94 46.73,55.44 47.08,55.44 47.35,55.18 47.97,55.18 48.24,55.45 48.24,56.09 48.37,56.22 48.9,56.22 49.03,56.09 49.03,55.45 49.31,55.18 50.02,55.18 50.29,55.45 50.29,56 50.42,56.13 50.8,56.13 50.93,56 50.93,55.45 51.2,55.18 51.72,55.18 52,55.45 52,56 52.13,56.13 52.51,56.13 52.63,56 52.63,55.45 52.91,55.18 53.55,55.18 53.91,55.53 53.91,56.41 55.28,57.78 66.34,57.78 66.61,58.06 66.61,58.88 66.74,59.01 68.34,59.01 75.87,66.54 76.8,66.54 79.85,69.58 89.01,69.58
  BOTTOM w0.076: v3(107.97,70.64) 108.14,70.64 108.26,70.75 UC1.AF29
  BOTTOM w0.102: JDIMM2.137 46.7,58.78 46.25,58.33 46.25,56.68 46.13,56.56 v3(46.13,56.47)
DDR_M1_CLK1: length 80
  IN2 w0.076: v3(108.59,71.67) 108.59,71.83 108.44,71.98 108.33,71.98 108.23,71.88 100.79,71.88 99.38,70.47 90.32,70.47 90.25,70.54 89.07,70.54 89.01,70.47
  IN2 w0.127: v3(44.86,56.47) 43.98,57.35 43.84,57.35 43.76,57.43 43.76,58.32 43.89,58.45 44.73,58.45 44.85,58.32 44.85,57.79 45.54,57.11 49.65,57.11 49.74,57.02 53.26,57.02 54.91,58.67 65.07,58.67 66.3,59.9 67.97,59.9 75.5,67.43 76.44,67.43 79.48,70.47 89.01,70.47
  BOTTOM w0.076: UC1.AE29 108.26,71.99 v3(108.59,71.67)
  BOTTOM w0.102: JDIMM2.138 43.08,58.53 44.63,56.98 44.63,56.7 v3(44.86,56.47)
DDR_M1_CLK#0: length 80.7
  IN2 w0.076: v3(108.67,70.64) 108.57,70.64 108.04,71.17 104.86,71.17 104.7,71.01 102.05,71.01 101.35,70.3 93.1,70.3 92.57,69.78 89.09,69.78 89.02,69.84 89.01,69.84
  IN2 w0.127: v3(46.76,56.47) 46.7,56.47 46.49,56.26 46.49,56.04 46.84,55.7 47.19,55.7 47.46,55.43 47.86,55.43 47.99,55.56 47.99,56.2 48.26,56.47 49.01,56.47 49.28,56.2 49.28,55.56 49.41,55.43 49.91,55.43 50.04,55.56 50.04,56.11 50.31,56.38 50.91,56.38 51.18,56.11 51.18,55.56 51.31,55.43 51.62,55.43 51.74,55.56 51.74,56.11 52.02,56.38 52.61,56.38 52.89,56.11 52.89,55.56 53.01,55.43 53.45,55.43 53.65,55.64 53.65,56.52 55.17,58.03 66.23,58.03 66.36,58.16 66.36,58.99 66.64,59.27 68.24,59.27 75.76,66.79 76.7,66.79 79.75,69.84 89.01,69.84
  BOTTOM w0.076: UC1.AF28 108.67,70.87 v3(108.67,70.64)
  BOTTOM w0.102: v3(46.76,56.47) 46.73,56.47 46.46,56.74 46.46,58.24 46.79,58.56 48.18,58.56 48.46,58.28 JDIMM2.139
DDR_M1_CLK#1: length 80
  IN2 w0.076: 89.01,70.73 89.02,70.73 89.04,70.7 90.32,70.7 90.39,70.63 99.31,70.63 100.72,72.04 108.11,72.04 108.25,72.18 108.3,72.18 v3(108.58,72.46)
  IN2 w0.127: 89.01,70.73 79.38,70.73 76.33,67.68 75.39,67.68 67.87,60.15 66.19,60.15 64.96,58.92 54.8,58.92 53.15,57.27 49.84,57.27 49.75,57.36 45.64,57.36 45.11,57.9 45.11,58.43 44.83,58.7 43.78,58.7 43.51,58.43 43.51,57.33 43.74,57.1 43.88,57.1 44.22,56.75 v3(44.22,56.47)
  BOTTOM w0.076: UC1.AE28 108.58,72.35 v3(108.58,72.46)
  BOTTOM w0.102: JDIMM2.140 41.83,58.03 42.11,58.31 42.99,58.31 44.41,56.89 44.41,56.66 v3(44.22,56.47)
DDR_M1_CS#0: length 77
  IN2 w0.076: v3(99.68,67.86) 99.33,68.21 97.61,68.21 95.56,66.17 92.74,66.17 92.01,65.44 89.01,65.44
  IN2 w0.157: v3(44.17,50.78) 44.17,50.43 43.85,50.11 43.85,49.88 44.22,49.51 44.52,49.51 45.2,50.19 46.31,50.19 47.29,49.21 54.55,49.21 54.97,49.63 54.97,50.19 56.31,51.53 59.82,51.53 60.56,50.79 61.37,50.79 63.7,53.12 69.25,53.12 81.57,65.44 89.01,65.44
  BOTTOM w0.076: 102.46,68.29 102.51,68.34 103.18,68.34 UC1.AL37
  BOTTOM w0.089: v3(99.68,67.86) 99.76,67.86 99.95,67.67 100.56,67.67 101.07,67.67 101.37,67.97 101.93,67.97 102.11,68.14 102.27,68.14 102.42,68.29 102.46,68.29
  BOTTOM w0.102: JDIMM2.149 48.2,53.78
  BOTTOM w0.127: v3(44.17,50.78) 44.17,50.81 46.97,53.6 48.03,53.6 48.2,53.78
DDR_M1_CS#1: length 77.9
  IN2 w0.076: 89.01,65.03 92.01,65.03 92.98,66 95.72,66 97.21,67.5 101.24,67.5 101.59,67.85 101.59,68.03 101.4,68.22 101.11,68.22 v3(100.93,68.04)
  IN2 w0.157: v3(44.87,49.08) 44.87,49.27 45.37,49.77 46.14,49.77 46.4,49.51 46.4,48.93 46.53,48.8 54.72,48.8 55.39,49.46 55.39,49.71 56.24,50.57 59.53,50.57 59.79,50.31 61.94,50.31 63.46,51.83 64.38,51.83 64.54,51.99 64.54,52.55 64.7,52.71 65.01,52.71 65.17,52.55 65.17,51.99 65.32,51.83 68.55,51.83 81.74,65.03 89.01,65.03
  BOTTOM w0.076: UC1.AL35 104.35,68.47 103.88,68.47 103.72,68.41 103.69,68.42 103.52,68.42 103.3,68.5 102.39,68.5 102.2,68.31 102.15,68.31 101.75,68.31 101.58,68.14
  BOTTOM w0.089: 101.58,68.14 101.44,68.14 101.3,68.14 101.28,68.13 101.25,68.15 100.93,68.04 v3(100.93,68.04)
  BOTTOM w0.102: JDIMM2.157 48.36,51.78
  BOTTOM w0.127: 48.36,51.78 48.35,51.78 47.73,51.15 46.94,51.15 v3(44.87,49.08)
DDR_M1_D0: length 81.4
  IN2 w0.076: 101.56,91.14 102.5,91.14 102.98,90.66 104.83,90.66 108.89,86.59 109.62,86.59 110.38,85.83 110.83,85.83 112.65,84.02 112.65,81.88 v3(112.12,81.35)
  IN2 w0.127: v3(42.51,86.01) 43.7,87.2 47.31,87.2 48.51,88.4 51.28,88.4 51.8,88.92 53.07,88.92 53.57,88.42 62.46,88.42 63.06,87.82 65.49,87.82 69.18,91.51 94.67,91.51 95.04,91.14 101.56,91.14
  BOTTOM w0.076: UC1.J22 v3(112.12,81.35)
  BOTTOM w0.102: v3(42.51,86.01) 42.49,86.03 JDIMM2.28
DDR_M1_D1: length 84.2
  IN2 w0.076: v3(110.08,81.99) 110.44,82.34 110.44,83.75 110.08,84.1 109.22,84.1 108.4,84.92 108.04,84.92 107.87,85.08 104.55,85.08 103.51,86.12 103.51,87.8 102.9,88.42 97.2,88.42 96.96,88.18 93.73,88.18 92.99,88.92 92.9,88.92
  IN2 w0.127: v3(43.78,82.82) 43.78,83.21 43.65,83.33 43.16,83.33 43.04,83.46 43.04,83.71 43.15,83.82 45.49,83.82 45.75,83.57 48.47,83.57 48.59,83.69 48.59,83.87 48.72,83.99 48.98,83.99 49.1,83.87 49.1,83.69 49.23,83.57 49.53,83.57 49.66,83.69 49.66,84.38 50.05,84.77 53.69,84.77 53.9,84.98 60.28,84.98 61.12,84.14 61.12,83.67 61.29,83.49 61.65,83.49 61.78,83.62 61.78,84.27 61.91,84.39 62.16,84.39 62.29,84.27 62.29,83.62 62.41,83.49 65.44,83.49 70.87,88.92 92.9,88.92
  BOTTOM w0.076: UC1.H25 v3(110.08,81.99)
  BOTTOM w0.102: JDIMM2.42 42,82.53 42.3,82.22 43.18,82.22 v3(43.78,82.82)
DDR_M1_D2: length 80.8
  IN2 w0.076: v3(112.12,82.62) 111.76,82.98 111.76,84.2 110.78,85.18 109.17,85.18 108.33,86.03 108.03,86.03 107.51,86.54 107.51,87.27 104.65,90.14 101.56,90.14
  IN2 w0.127: 101.56,90.14 94.24,90.14 93.86,90.52 69.59,90.52 65.73,86.66 64.6,86.66 64.48,86.53 64.48,86.24 64.35,86.11 64.09,86.11 63.97,86.24 63.97,86.53 63.84,86.66 63.59,86.66 63.46,86.53 63.46,86.24 63.33,86.11 63.08,86.11 62.95,86.24 62.95,86.53 62.82,86.66 62.57,86.66 62.44,86.53 62.44,86.24 62.32,86.11 62.06,86.11 61.94,86.24 61.94,86.53 61.81,86.66 58.97,86.66 58.72,86.91 55.42,86.91 55.12,87.2 52.35,87.2 52.22,87.07 52.22,86.76 52.1,86.63 51.84,86.63 51.71,86.76 51.71,87.07 51.59,87.2 49.77,87.2 49.65,87.07 49.65,86.49 49.52,86.37 49.27,86.37 49.14,86.49 49.14,87.07 49.01,87.2 48.73,87.2 47.54,86.01 v3(46.32,86.01)
  BOTTOM w0.076: UC1.G22 v3(112.12,82.62)
  BOTTOM w0.102: v3(46.32,86.01) 47.08,86.78 JDIMM2.25
DDR_M1_D3: length 80.6
  IN2 w0.076: 101.56,90.81 102.6,90.81 102.92,90.48 104.77,90.48 107.84,87.41 107.84,86.68 108.17,86.36 108.46,86.36 109.31,85.51 110.92,85.51 112.47,83.96 112.47,82.34 v3(112.12,81.99)
  IN2 w0.127: v3(43.78,86.01) 44.63,86.86 47.46,86.86 48.61,88.01 54.52,88.01 54.6,88.09 62.32,88.09 62.98,87.43 65.57,87.43 69.31,91.18 94.13,91.18 94.51,90.81 101.56,90.81
  BOTTOM w0.076: UC1.H22 v3(112.12,81.99)
  BOTTOM w0.102: v3(43.78,86.01) 42.76,87.03 JDIMM2.24
DDR_M1_D4: length 84.6
  IN2 w0.076: 92.57,88.59 92.84,88.59 93.41,88.02 97.03,88.02 97.26,88.26 102.83,88.26 103.35,87.74 103.35,86.05 104.48,84.92 106.85,84.92 107.22,84.55 107.22,84.55 107.51,84.27 107.72,84.27 107.85,84.13 108.25,84.13 108.45,83.94 109.74,83.94 110,83.67 110,83.34 v3(110.08,83.26)
  IN2 w0.127: 92.57,88.59 77.8,88.59 77.67,88.46 77.67,88.12 77.54,88 77.29,88 77.16,88.12 77.16,88.46 77.04,88.59 76.78,88.59 76.65,88.46 76.65,88.12 76.53,88 76.27,88 76.15,88.12 76.15,88.46 76.02,88.59 75.77,88.59 75.64,88.46 75.64,88.12 75.51,88 75.26,88 75.13,88.12 75.13,88.46 75,88.59 74.75,88.59 74.62,88.46 74.62,88.12 74.5,88 74.24,88 74.11,88.12 74.11,88.46 73.99,88.59 73.73,88.59 73.61,88.46 73.61,88.12 73.48,88 73.23,88 73.1,88.12 73.1,88.46 72.97,88.59 72.72,88.59 72.59,88.46 72.59,88.12 72.46,88 72.21,88 72.08,88.12 72.08,88.46 71.96,88.59 71,88.59 65.57,83.16 61.16,83.16 60.5,83.82 60.5,84.29 60.14,84.65 56.21,84.65 56,84.44 53.82,84.44 53.69,84.31 53.69,84.15 53.57,84.02 53.31,84.02 53.19,84.15 53.19,84.31 53.06,84.44 52.8,84.44 52.68,84.31 52.68,84.15 52.55,84.02 52.3,84.02 52.17,84.15 52.17,84.31 52.04,84.44 50.18,84.44 49.99,84.24 49.99,83.47 49.75,83.24 45.18,83.24 45.05,83.11 v3(45.05,82.82)
  BOTTOM w0.076: UC1.F25 v3(110.08,83.26)
  BOTTOM w0.102: JDIMM2.41 47.16,82.78 46.75,82.36 45.5,82.36 v3(45.05,82.82)
DDR_M1_D5: length 82.8
  IN2 w0.076: v3(110.08,81.35) 110.6,81.87 110.6,83.82 110.15,84.27 109.28,84.27 108.47,85.08 108.11,85.08 107.94,85.25 105.4,85.25 104.23,86.43 104.23,86.84 103.81,87.25 103.81,87.74 102.97,88.59 97.13,88.59 96.89,88.35 94.07,88.35 93.33,89.09 93.29,89.09 93.18,89.2
  IN2 w0.127: v3(42.51,82.82) 41.98,82.82 41.85,82.94 41.85,83.91 42.1,84.15 45.63,84.15 45.89,83.9 48.16,83.9 48.58,84.32 49.15,84.32 49.28,84.45 49.28,84.97 49.41,85.1 53.55,85.1 53.76,85.31 60.54,85.31 61,84.84 62.62,84.84 62.75,84.72 62.75,83.95 62.88,83.82 65.3,83.82 70.73,89.25 93.13,89.25 93.18,89.2
  BOTTOM w0.076: UC1.J25 v3(110.08,81.35)
  BOTTOM w0.102: JDIMM2.38 41.8,83.53 v3(42.51,82.82)
DDR_M1_D6: length 81.5
  IN2 w0.076: 92.24,88.26 92.7,88.26 93.11,87.85 97.18,87.85 97.42,88.09 102.76,88.09 103.18,87.67 103.18,85.98 104.42,84.75 106.77,84.75 107.13,84.38 107.16,84.38 107.44,84.1 107.65,84.1 107.78,83.97 108.19,83.97 108.38,83.77 109.5,83.77 109.69,83.58 109.69,83.02 v3(110.08,82.62)
  IN2 w0.127: 92.24,88.26 80.29,88.26 80.16,88.13 80.16,87.79 80.03,87.67 79.78,87.67 79.65,87.79 79.65,88.13 79.52,88.26 79.27,88.26 79.14,88.13 79.14,87.79 79.02,87.67 78.76,87.67 78.64,87.79 78.64,88.13 78.51,88.26 78.25,88.26 78.13,88.13 78.13,87.79 78,87.67 70.55,87.67 65.62,82.74 61.11,82.74 60.44,83.41 55.36,83.41 55.23,83.54 55.23,83.73 55.1,83.85 54.85,83.85 54.72,83.73 54.72,83.54 54.59,83.41 53.6,83.41 53.42,83.59 51.88,83.59 51.36,83.08 50.06,83.08 49.7,82.72 49.27,82.72 49.1,82.55 49.1,82.12 48.93,81.95 48.67,81.95 48.54,82.08 48.54,82.78 48.42,82.91 48.16,82.91 48.04,82.78 48.04,82.08 47.91,81.95 47.66,81.95 47.53,82.08 47.53,82.78 47.4,82.91 47.15,82.91 47.02,82.78 47.02,82.08 46.89,81.95 46.45,81.95 46.32,82.08 v3(46.32,82.82)
  BOTTOM w0.076: UC1.G25 v3(110.08,82.62)
  BOTTOM w0.102: v3(46.32,82.82) 47.28,83.78 JDIMM2.37
DDR_M1_D7: length 81
  IN2 w0.076: 101.56,90.47 102.7,90.47 102.85,90.32 104.71,90.32 107.68,87.34 107.68,86.61 108.1,86.19 108.4,86.19 109.24,85.35 110.85,85.35 112.07,84.12 112.07,83.3 v3(112.11,83.26)
  IN2 w0.127: 101.56,90.47 101.55,90.48 94.37,90.48 94,90.85 69.45,90.85 65.63,87.03 61.92,87.03 61.79,87.15 61.79,87.63 61.67,87.76 61.41,87.76 61.29,87.63 61.29,87.15 61.16,87.03 60.9,87.03 60.78,87.15 60.78,87.63 60.65,87.76 60.4,87.76 60.27,87.63 60.27,87.15 60.14,87.03 59.07,87.03 58.84,87.25 55.54,87.25 55.11,87.68 48.74,87.68 47.51,86.44 45.48,86.44 v3(45.05,86.01)
  BOTTOM w0.076: UC1.F22 v3(112.11,83.26)
  BOTTOM w0.102: v3(45.05,86.01) 45.55,85.51 47.16,85.51 47.43,85.78 JDIMM2.29
DDR_M1_D8: length 88.2
  IN2 w0.076: v3(112.35,91.96) 111.95,91.56 111.95,90.67 110.37,89.1 108.86,89.1 108.86,89.1
  IN2 w0.127: v3(43.54,88.28) 43.59,88.28 44.33,89.03 46.75,89.03 48.21,90.49 53.98,90.49 54.32,90.83 62.97,90.83 63.35,90.45 64.39,90.45 64.52,90.33 64.52,89.86 64.64,89.74 64.9,89.74 65.02,89.86 65.02,90.33 65.15,90.45 66,90.45 67.22,91.67 67.22,92.12 68.1,93.01 95.29,93.01 95.41,92.9 106.55,92.9 107.32,92.12 107.32,89.94 108.17,89.1 108.86,89.1
  BOTTOM w0.076: 112.71,91.28 112.71,90.57 112.81,90.47 112.81,89.88 112.99,89.7 112.99,88.86 113.18,88.67 113.18,86.01 113.17,86 113.07,85.78 113.07,84.59 112.75,84.27 UC1.D22
  BOTTOM w0.102: v3(43.54,88.28) 42.98,88.84 41.99,88.84 41.81,89.03 JDIMM2.16 ; 112.71,91.28 112.71,91.61 v3(112.35,91.96)
DDR_M1_D9: length 87.9
  IN2 w0.076: v3(112.3,88.83) 112.81,89.34 112.81,92.01 112.47,92.35 112.47,92.78 111.36,93.88 110.35,93.88 108.74,95.5
  IN2 w0.127: 108.74,95.5 102.68,95.5 101.9,96.27 81.95,96.27 81.73,96.05 81.73,95.94 81.61,95.82 81.35,95.82 81.23,95.94 81.23,96.15 81.1,96.27 80.85,96.27 80.72,96.15 80.72,95.94 80.59,95.82 80.34,95.82 80.21,95.94 80.21,96.16 80.08,96.29 79.83,96.29 79.7,96.16 79.7,95.94 79.58,95.82 79.32,95.82 79.19,95.94 79.19,96.25 79.07,96.37 78.81,96.37 78.69,96.25 78.69,95.94 78.56,95.82 78.31,95.82 78.18,95.94 78.18,96.25 78.05,96.37 77.8,96.37 77.67,96.25 77.67,95.94 77.54,95.82 77.29,95.82 77.16,95.94 77.16,96.25 77.04,96.37 76.78,96.37 76.65,96.25 76.65,95.94 76.53,95.82 76.27,95.82 76.15,95.94 76.15,96.25 76.02,96.37 75.77,96.37 75.64,96.25 75.64,95.94 75.51,95.82 75.26,95.82 75.13,95.94 75.13,96.25 75,96.37 66.12,96.37 63.89,94.15 61.18,94.15 59.42,95.91 55.87,95.91 53.91,93.95 48.03,93.95 46.48,92.4 v3(46.09,92.4)
  BOTTOM w0.076: 112.67,86.55 112.67,86.46 112.48,86.27 112.48,86.21 112.52,85.9 112.52,85.72 112.49,85.55 112.49,85.42 112.5,85.37 UC1.C22
  BOTTOM w0.102: JDIMM2.3 46.22,92.28 v3(46.09,92.4) ; 112.67,86.55 112.67,88.46 v3(112.3,88.83)
DDR_M1_D10: length 87.1
  IN2 w0.076: v3(110.83,90.05) 111.68,90.9 111.68,91.81 112.09,92.21 112.09,92.92 111.29,93.72 110.25,93.72 108.81,95.16 108.63,95.16
  IN2 w0.127: v3(44.82,92.4) 45.24,91.98 46.55,91.98 48.18,93.62 54.86,93.62 55.83,94.59 55.83,94.77 55.6,94.99 55.6,95.17 55.78,95.35 55.96,95.35 56.19,95.13 56.37,95.13 56.82,95.58 59.28,95.58 61.04,93.82 64.03,93.82 66.26,96.04 73.09,96.04 73.65,95.49 73.91,95.49 74.03,95.61 74.03,95.92 74.16,96.04 74.41,96.04 74.54,95.92 74.54,95.61 74.76,95.4 95.82,95.4 96.05,95.17 108.62,95.17 108.63,95.16
  BOTTOM w0.076: v3(110.83,90.05) 110.97,89.91 110.97,87.08 111.19,86.86 111.19,86.56 111.02,86.39 111.02,85.98 111.02,85.98 111.02,85.94 111.02,85.93 111.06,85.89 111.09,85.84 111.09,85.81 111.13,85.74 111.13,85.45 111.31,84.98 111.45,84.84 UC1.C24
  BOTTOM w0.102: JDIMM2.7 48.29,91.28 45.16,92.06 v3(44.82,92.4)
DDR_M1_D11: length 87.2
  IN2 w0.076: 101.56,91.65 102.28,91.65 103.11,90.82 104.9,90.82 107.9,87.83 111.93,87.83 v3(112.3,88.21)
  IN2 w0.127: 101.56,91.65 95.26,91.65 94.88,92.02 68.97,92.02 65.28,88.33 64.37,88.33 63.77,88.93 53.78,88.93 53.28,89.43 50.52,89.43 50,88.9 48.3,88.9 47.1,87.71 42.37,87.71 42.16,87.5 42.16,86.38 41.9,86.12 41.16,86.12 41.03,86.25 41.03,87.02 41.16,87.15 41.24,87.15 41.37,87.28 41.37,87.53 41.24,87.66 41.16,87.66 41.03,87.78 41.03,88.15 41.16,88.28 v3(42.27,88.28)
  BOTTOM w0.076: 112.48,86.8 112.48,86.71 112.31,86.53 112.31,86.2 112.35,85.87 112.35,85.75 112.33,85.56 112.33,85.41 112.35,85.22 112.38,84.52 112.38,84.39 112.22,84.24 UC1.D24
  BOTTOM w0.102: 112.48,86.8 112.48,88.03 v3(112.3,88.21) ; JDIMM2.20 42.02,88.03 v3(42.27,88.28)
DDR_M1_D12: length 86.5
  IN2 w0.076: v3(112.29,90.16) 112.24,90.11 111.66,90.11 110.43,88.88 108.86,88.88
  IN2 w0.127: 108.86,88.88 108.08,88.88 107.11,89.85 107.11,92.03 106.57,92.57 95.27,92.57 95.16,92.68 68.24,92.68 67.57,92 67.57,91.55 65.01,89 64.63,89 64.02,89.61 63.66,89.61 62.77,90.5 61.66,90.5 61.53,90.38 61.53,90.19 61.41,90.06 61.15,90.06 61.03,90.19 61.03,90.38 60.9,90.5 60.64,90.5 60.52,90.38 60.52,89.84 60.39,89.71 60.14,89.71 60.01,89.84 60.01,90.38 59.88,90.5 59.63,90.5 59.5,90.38 59.5,90.32 59.37,90.2 59.12,90.2 58.99,90.32 58.99,90.38 58.87,90.5 58.61,90.5 58.49,90.38 58.49,90.32 58.36,90.2 58.1,90.2 57.98,90.32 57.98,90.38 57.85,90.5 57.6,90.5 57.47,90.38 57.47,90.32 57.34,90.2 57.09,90.2 56.96,90.32 56.96,90.38 56.83,90.5 56.58,90.5 56.45,90.38 56.45,90.32 56.33,90.2 56.07,90.2 55.95,90.32 55.95,90.38 55.82,90.5 55.56,90.5 55.44,90.38 55.44,90.32 55.31,90.2 55.06,90.2 54.93,90.32 54.93,90.38 54.8,90.5 54.46,90.5 54.12,90.16 48.35,90.16 46.88,88.7 45.23,88.7 v3(44.81,88.28)
  BOTTOM w0.076: UC1.A22 112.8,86.19 112.8,86.36 112.85,86.41 112.85,88.54 112.66,88.73 112.66,89.56 112.29,89.93 v3(112.29,90.16)
  BOTTOM w0.102: v3(44.81,88.28) 45.32,87.78 JDIMM2.21
DDR_M1_D13: length 87.3
  IN2 w0.076: v3(112.3,90.75) 112.3,90.71 112.65,90.37 112.65,89.91 112.52,89.78 112.15,89.78 111.87,89.5 111.87,88.07 111.79,87.99 110.89,87.99 110.22,88.66 108.03,88.66 106.8,89.89 106.8,90.89 105.97,91.72 105.02,91.72 104.68,92.06
  IN2 w0.127: 104.68,92.06 95.31,92.06 95.02,92.35 68.83,92.35 68.48,92 68.3,92 68.26,92.05 68.08,92.05 67.9,91.87 67.9,91.69 67.94,91.64 67.94,91.46 65.15,88.67 64.5,88.67 63.88,89.28 62.89,89.28 62.76,89.41 62.76,90.05 62.63,90.17 62.34,90.17 62.21,90.05 62.21,89.41 62.09,89.28 61.57,89.28 61.44,89.41 61.44,89.61 61.31,89.73 61.06,89.73 60.93,89.61 60.93,89.41 60.8,89.28 60.1,89.28 59.51,89.86 55.4,89.86 55.37,89.83 54.77,89.83 54.64,89.7 54.64,89.38 54.52,89.26 54.26,89.26 54.13,89.38 54.13,89.7 54.01,89.83 49.54,89.83 49.42,89.7 49.42,89.36 49.29,89.23 49.04,89.23 48.91,89.36 48.91,89.68 48.78,89.81 48.47,89.81 46.93,88.28 v3(46.08,88.28)
  BOTTOM w0.076: v3(112.3,90.75) 112.65,90.4 112.65,89.81 112.82,89.63 112.82,88.79 113.02,88.6 113.02,86.2 113,86.19 113,86.05 112.98,86 112.75,85.49 UC1.B22
  BOTTOM w0.102: v3(46.08,88.28) 46.58,88.78 JDIMM2.17
DDR_M1_D14: length 86.7
  IN2 w0.076: 110.03,93.36 111.18,93.36 111.76,92.79 111.76,92.35 111.35,91.94 111.35,91.71 110.87,91.23 v3(110.83,91.23)
  IN2 w0.127: v3(42.28,92.4) 42.89,91.79 44.24,91.32 46.86,91.32 48.47,92.93 55.11,92.93 55.79,93.61 56.09,93.61 56.33,93.38 56.51,93.38 56.69,93.56 56.69,93.74 56.39,94.03 56.39,94.21 57.09,94.92 59.01,94.92 60.77,93.16 62.07,93.16 62.2,93.03 62.2,92.31 62.33,92.18 62.58,92.18 62.71,92.31 62.71,93.03 62.83,93.16 63.09,93.16 63.22,93.03 63.22,92.47 63.34,92.35 63.6,92.35 63.72,92.47 63.72,93.03 63.85,93.16 64.46,93.16 66.46,95.15 68.68,95.15 69.11,94.72 95.49,94.72 95.7,94.51 108.88,94.51 110.03,93.36
  BOTTOM w0.076: UC1.A24 111.54,86.42 111.54,86.42 111.54,86.97 111.54,86.97 111.54,86.98 111.36,87.16 111.36,90.25 111.29,90.33 111.29,90.96 111.04,91.21 110.85,91.21 v3(110.83,91.23)
  BOTTOM w0.102: v3(42.28,92.4) 41.9,92.03 JDIMM2.4
DDR_M1_D15: length 87.5
  IN2 w0.076: 110.14,93.55 111.22,93.55 111.92,92.85 111.92,92.28 111.51,91.88 111.51,91.28 v3(110.87,90.64)
  IN2 w0.127: v3(43.55,92.4) 43.88,92.07 44.87,91.65 46.71,91.65 48.33,93.28 54.98,93.28 56.96,95.25 59.15,95.25 60.91,93.49 64.16,93.49 66.39,95.71 68.59,95.71 69.15,95.16 69.4,95.16 69.53,95.28 69.53,95.59 69.65,95.71 69.91,95.71 70.03,95.59 70.03,95.28 70.16,95.16 70.42,95.16 70.54,95.28 70.54,95.59 70.67,95.71 70.92,95.71 71.05,95.59 71.05,95.28 71.18,95.16 71.43,95.16 71.56,95.28 71.56,95.59 71.69,95.71 71.94,95.71 72.07,95.59 72.07,95.28 72.19,95.16 72.45,95.16 72.57,95.28 72.57,95.59 72.7,95.71 72.96,95.71 73.08,95.59 73.08,95.28 73.3,95.07 95.66,95.07 95.89,94.84 108.86,94.84 110.14,93.55
  BOTTOM w0.076: UC1.B24 111.45,85.54 111.26,85.88 111.19,86.01 111.18,86.02 111.18,86.29 111.38,86.48 111.38,86.91 111.2,87.09 111.2,87.93 111.2,90.19 110.86,90.52 110.86,90.63 v3(110.87,90.64)
  BOTTOM w0.102: JDIMM2.8 41.84,91.03 42.1,91.28 42.42,91.28 v3(43.55,92.4)
DDR_M1_D16: length 74.7
  IN2 w0.076: 91.07,87.09 91.31,87.09 91.43,87.21 98.42,87.21 98.56,87.34 100.15,87.34 100.58,86.91 100.58,86.37 101.46,85.48 101.46,84.82 102.36,83.93 103.2,83.93 103.74,83.39 105.47,83.39 105.9,83.83 106.32,83.83 v3(106.73,83.42)
  IN2 w0.127: v3(44.86,80.37) 45.28,80.78 49.85,80.78 50.42,81.35 50.7,81.35 51.09,81.74 51.56,81.74 51.69,81.61 51.69,81.12 51.82,80.99 52.07,80.99 52.2,81.12 52.2,81.61 52.33,81.74 53.19,81.74 53.21,81.72 60.26,81.72 60.62,81.36 63.37,81.36 63.67,81.06 65.59,81.06 71.03,86.5 81.07,86.5 81.66,87.09 91.07,87.09
  BOTTOM w0.076: UC1.G31 v3(106.73,83.42)
  BOTTOM w0.102: v3(44.86,80.37) 44.86,80.48 46,81.62 48.2,81.62 48.36,81.78 JDIMM2.45
DDR_M1_D17: length 76.3
  IN2 w0.076: v3(106.12,83.47) 105.87,83.23 103.67,83.23 103.13,83.76 102.29,83.76 101.27,84.78 101.27,85.43 100.29,86.41 98.64,86.41 98.01,87.04 91.53,87.04 90.66,86.17 90.15,86.17
  IN2 w0.127: v3(46.13,80.37) 52.43,80.37 52.97,80.9 53.25,80.9 53.74,81.39 60.13,81.39 60.49,81.03 63.23,81.03 63.53,80.73 65.73,80.73 71.17,86.17 81.55,86.17 81.67,86.29 81.67,86.63 81.8,86.76 82.06,86.76 82.18,86.63 82.18,86.29 82.31,86.17 82.56,86.17 82.69,86.29 82.69,86.63 82.82,86.76 83.07,86.76 83.2,86.63 83.2,86.29 83.33,86.17 83.58,86.17 83.71,86.29 83.71,86.63 83.83,86.76 84.09,86.76 84.21,86.63 84.21,86.29 84.34,86.17 84.6,86.17 84.72,86.29 84.72,86.63 84.85,86.76 85.1,86.76 85.23,86.63 85.23,86.29 85.36,86.17 85.61,86.17 85.74,86.29 85.74,86.63 85.87,86.76 86.12,86.76 86.25,86.63 86.25,86.29 86.37,86.17 86.63,86.17 86.75,86.29 86.75,86.63 86.88,86.76 87.14,86.76 87.26,86.63 87.26,86.29 87.39,86.17 87.64,86.17 87.77,86.29 87.77,86.63 87.9,86.76 88.15,86.76 88.28,86.63 88.28,86.29 88.41,86.17 88.66,86.17 88.79,86.29 88.79,86.63 88.91,86.76 89.17,86.76 89.29,86.63 89.29,86.29 89.42,86.17 90.15,86.17
  BOTTOM w0.076: v3(106.12,83.47) 106.09,83.41 UC1.G32
  BOTTOM w0.102: JDIMM2.49 46.54,80.78 v3(46.13,80.37)
DDR_M1_D18: length 75.9
  IN2 w0.076: 89.01,84.09 90.16,84.09 91.83,85.76 95.59,85.76 95.77,85.58 95.83,85.58 95.94,85.46 96.41,85.46 96.52,85.35 96.69,85.35 99.76,82.28 101.2,82.28 101.38,82.46 103.01,82.46 103.52,81.95 106.3,81.95 106.47,82.12 107.62,82.12 108,82.49 v3(108,82.5)
  IN2 w0.127: 89.01,84.09 71.82,84.09 65.92,78.19 59.31,78.19 59.26,78.14 53.66,78.14 53.13,77.61 50.1,77.61 49.97,77.48 49.97,76.81 49.84,76.68 49.61,76.68 49.48,76.81 49.48,77.23 49.36,77.36 49.1,77.36 48.97,77.23 48.97,76.81 48.85,76.68 43.72,76.68 43.59,76.81 v3(43.59,77.22)
  BOTTOM w0.076: UC1.H29 v3(108,82.5)
  BOTTOM w0.102: JDIMM2.58 42.17,78.53 42.29,78.4 42.67,78.4 43.59,77.48 v3(43.59,77.22)
DDR_M1_D19: length 75.4
  IN2 w0.076: v3(108.63,82.5) 108.63,82.43 108.16,81.95 106.57,81.95 106.4,81.78 103.45,81.78 102.94,82.29 101.44,82.29 101.27,82.11 99.55,82.11 96.47,85.19 96.45,85.19 96.34,85.29 95.88,85.29 95.76,85.41 95.7,85.41 95.52,85.59 91.9,85.59 90.07,83.76 89.01,83.76
  IN2 w0.127: v3(42.32,77.22) 42.05,76.95 42.05,76.48 42.18,76.35 49.98,76.35 50.91,77.28 53.26,77.28 53.79,77.81 59.4,77.81 59.45,77.86 66.05,77.86 71.96,83.76 89.01,83.76
  BOTTOM w0.076: UC1.H28 v3(108.63,82.5)
  BOTTOM w0.102: v3(42.32,77.22) 42.01,77.53 JDIMM2.62
DDR_M1_D20: length 74.3
  IN2 w0.076: 91.74,87.75 91.8,87.69 98.23,87.69 98.27,87.73 100.53,87.73 101.09,87.17 102.48,87.17 102.96,86.69 102.96,85.94 103.28,85.61 103.28,85.32 104.59,84.02 105.62,84.02 105.83,84.22 107.09,84.22 107.37,83.94 107.58,83.94 107.75,83.77 108.15,83.77 108.48,83.44 108.61,83.44 v3(108.63,83.42)
  IN2 w0.127: 91.74,87.75 81.39,87.75 80.8,87.16 70.76,87.16 65.83,82.23 60.9,82.23 60.23,82.91 53.42,82.91 53.09,82.57 50.27,82.57 49.14,81.45 44.27,81.45 42.78,80.83 v3(42.32,80.37)
  BOTTOM w0.076: UC1.G28 v3(108.63,83.42)
  BOTTOM w0.102: v3(42.32,80.37) 42.16,80.53 JDIMM2.50
DDR_M1_D21: length 76
  IN2 w0.076: 91.4,87.42 98.19,87.42 98.33,87.56 100.16,87.56 100.74,86.98 100.74,86.65 101.05,86.34 102.32,86.34 103.12,85.54 103.12,84.95 103.25,84.82 103.25,84.65 104.34,83.56 105.4,83.56 105.9,84.05 107.02,84.05 107.3,83.77 107.51,83.77 107.87,83.42 v3(108,83.42)
  IN2 w0.127: v3(43.59,80.37) 44.34,81.12 49.28,81.12 50.4,82.24 53.23,82.24 53.56,82.58 54.06,82.58 54.19,82.45 54.19,82.18 54.32,82.05 54.57,82.05 54.7,82.18 54.7,82.45 54.82,82.58 60.09,82.58 60.97,81.69 63.5,81.69 63.8,81.4 64.39,81.4 64.52,81.52 64.52,81.69 64.65,81.82 64.9,81.82 65.03,81.69 65.03,81.52 65.16,81.4 65.46,81.4 70.89,86.83 80.93,86.83 81.53,87.42 91.4,87.42
  BOTTOM w0.076: UC1.G29 v3(108,83.42)
  BOTTOM w0.102: v3(43.59,80.37) 42.43,81.53 JDIMM2.46
DDR_M1_D22: length 75.3
  IN2 w0.076: v3(106.73,82.47) 106.59,82.47 106.24,82.12 103.59,82.12 102.65,83.06 100.22,83.06 97.6,85.68 97.6,85.8 97.24,86.17 92.01,86.17 90.26,84.42 89.01,84.42
  IN2 w0.127: 89.01,84.42 71.68,84.42 65.78,78.52 59.17,78.52 59.12,78.47 55.11,78.47 54.98,78.59 54.98,79.24 54.85,79.37 54.6,79.37 54.47,79.24 54.47,78.59 54.34,78.47 53.52,78.47 53.41,78.36 52.99,77.94 48.77,77.94 48.64,77.81 48.64,77.14 48.52,77.01 48.26,77.01 48.14,77.14 48.14,77.81 48.01,77.94 47.76,77.94 47.63,77.81 47.63,77.14 47.5,77.01 47.25,77.01 47.12,77.14 47.12,77.81 46.99,77.94 46.05,77.94 45.92,77.81 45.92,77.43 v3(46.13,77.22)
  BOTTOM w0.076: UC1.H31 106.75,82.47 v3(106.73,82.47)
  BOTTOM w0.102: JDIMM2.63 48.25,77.28 47.94,77.59 47.18,77.59 46.86,77.28 46.19,77.28 v3(46.13,77.22)
DDR_M1_D23: length 77
  IN2 w0.076: v3(106.09,82.48) 105.9,82.29 103.66,82.29 102.72,83.23 100.48,83.23 98.43,85.28 98.43,85.86 97.96,86.33 91.94,86.33 90.36,84.75 89.01,84.75
  IN2 w0.127: v3(44.86,77.22) 44.86,77.46 44.73,77.59 44.41,77.59 44.29,77.72 44.29,78.14 44.41,78.27 51.47,78.27 52.09,78.9 53.23,78.9 54.03,79.7 55.95,79.7 56.11,79.54 60.23,79.54 60.36,79.41 60.36,78.97 60.48,78.85 61.02,78.85 61.15,78.97 61.15,79.41 61.27,79.54 61.53,79.54 61.65,79.41 61.65,78.97 61.78,78.85 62.03,78.85 62.16,78.97 62.16,79.41 62.29,79.54 62.54,79.54 62.67,79.41 62.67,78.97 62.8,78.85 65.64,78.85 71.54,84.75 89.01,84.75
  BOTTOM w0.076: v3(106.09,82.48) 106.11,82.47 UC1.H32
  BOTTOM w0.102: JDIMM2.59 47.28,78.28 46.73,77.73 45.37,77.73 v3(44.86,77.22)
DDR_M1_D24: length 78.8
  IN2 w0.076: v3(106.74,80.68) 106.7,80.73 106.6,80.73 106.26,81.07 103.34,81.07 102.61,81.79 101.85,81.79 101.67,81.62 99.34,81.62 96.27,84.69 96.24,84.69 96.14,84.8 95.67,84.8 95.55,84.91 95.5,84.91 95.31,85.1 92.11,85.1 89.6,82.59 89.01,82.59
  IN2 w0.127: 89.01,82.59 72.65,82.59 65.78,75.72 65.4,75.72 64.93,76.2 63.79,76.2 63.67,76.07 63.67,75.53 63.54,75.41 63.29,75.41 63.16,75.53 63.16,76.56 63.03,76.69 62.78,76.69 62.65,76.56 62.65,75.53 62.52,75.41 62.27,75.41 62.14,75.53 62.14,76.56 62.02,76.69 61.76,76.69 61.64,76.56 61.64,75.53 61.51,75.41 61.03,75.41 60.9,75.53 60.9,76.56 60.77,76.69 60.54,76.69 60.42,76.56 60.42,75.57 60.29,75.45 59.77,75.45 59.65,75.57 59.65,75.94 59.52,76.06 56.93,76.06 56.27,75.41 55.98,75.41 55.64,75.07 53.26,75.07 53.01,75.32 52.4,75.32 52.03,74.95 46.32,74.95 v3(46.19,75.08)
  BOTTOM w0.076: UC1.L31 106.8,80.54 106.73,80.67 v3(106.74,80.68)
  BOTTOM w0.102: JDIMM2.71 46.39,75.28 v3(46.19,75.08)
DDR_M1_D25: length 79.3
  IN2 w0.076: 89.01,82.26 89.81,82.26 90.22,81.85 90.22,80.51 90.8,79.11 92.62,77.29 96.16,77.29 100.32,81.45 101.48,81.45 101.85,81.08 103.09,81.08 103.27,80.9 105.92,80.9 106.09,80.73 v3(106.09,80.68)
  IN2 w0.127: 89.01,82.26 72.96,82.26 65.71,75 58.12,75 58.05,75.08 56.2,75.08 55.86,74.74 52.99,74.74 52.99,74.73 52.74,74.48 52.16,74.48 52.02,74.62 47.1,74.62 46.81,74.33 43.4,74.33 43.27,74.2 43.27,73.32 43.12,73.17 42.89,73.17 42.76,73.3 42.76,74.2 42.64,74.33 41.44,74.33 41.29,74.47 41.29,74.91 41.45,75.08 v3(42.38,75.08)
  BOTTOM w0.076: UC1.L32 106.09,80.68 v3(106.09,80.68)
  BOTTOM w0.102: v3(42.38,75.08) 41.93,75.53 JDIMM2.70
DDR_M1_D26: length 77.6
  IN2 w0.076: 89.01,80.15 89.27,80.15 89.45,79.97 89.97,78.72 92.42,76.27 96.57,76.27 98.08,77.78 101.99,77.78 103.46,79.25 106.31,79.25 106.48,79.41 107.64,79.41 v3(108,79.77)
  IN2 w0.127: v3(43.62,71.71) 43.62,70.45 43.74,70.33 43.98,70.33 44.12,70.47 44.12,70.61 44.25,70.74 44.5,70.74 44.63,70.6 44.63,70.45 44.76,70.33 45.68,70.33 45.82,70.47 45.82,70.84 45.95,70.96 48.36,70.96 49.41,72.01 53.32,72.01 53.44,72.13 65.77,72.13 73.79,80.15 89.01,80.15
  BOTTOM w0.076: UC1.N29 v3(108,79.77)
  BOTTOM w0.102: v3(43.62,71.71) 42.3,73.03 JDIMM2.80
DDR_M1_D27: length 77.2
  IN2 w0.076: v3(108.63,79.77) 108.4,79.53 107.79,79.25 106.55,79.25 106.38,79.08 103.53,79.08 102.06,77.61 98.15,77.61 96.64,76.1 92.35,76.1 89.83,78.62 89.41,79.64 89.23,79.82 89.01,79.82
  IN2 w0.127: 89.01,79.82 73.96,79.82 65.94,71.8 53.58,71.8 53.46,71.68 49.55,71.68 48.5,70.63 46.68,70.63 45.93,69.89 42.9,69.89 42.65,70.14 42.65,71.41 v3(42.35,71.71)
  BOTTOM w0.076: UC1.N28 v3(108.63,79.77)
  BOTTOM w0.102: v3(42.35,71.71) 42.03,72.03 JDIMM2.84
DDR_M1_D28: length 75.2
  IN2 w0.076: 89.01,83.25 89.79,83.25 91.97,85.43 95.45,85.43 95.63,85.25 95.69,85.25 95.81,85.13 96.27,85.13 96.38,85.02 96.4,85.02 99.48,81.95 101.53,81.95 101.71,82.13 102.81,82.13 103.54,81.4 106.4,81.4 106.59,81.2 108.11,81.2 v3(108.63,80.68)
  IN2 w0.127: v3(43.65,75.08) 44.41,75.83 50.18,75.83 50.33,75.98 51.11,76.77 53.74,76.77 54.28,77.3 59.6,77.3 59.65,77.35 66.27,77.35 72.17,83.25 89.01,83.25
  BOTTOM w0.076: v3(108.63,80.68) 108.72,80.54 UC1.L28
  BOTTOM w0.102: JDIMM2.66 42.2,76.53 v3(43.65,75.08)
DDR_M1_D29: length 76.9
  IN2 w0.076: 89.01,82.92 89.7,82.92 92.04,85.26 95.38,85.26 95.56,85.08 95.62,85.08 95.74,84.96 96.21,84.96 96.31,84.86 96.34,84.86 99.41,81.78 101.6,81.78 101.78,81.96 102.7,81.96 103.43,81.23 106.33,81.23 106.52,81.04 107.81,81.04 108,80.85 v3(108,80.68)
  IN2 w0.127: 89.01,82.92 72.3,82.92 66.4,77.02 60.08,77.02 59.95,76.89 59.95,76.52 59.83,76.39 56.34,76.39 56.26,76.31 56.26,75.86 56.14,75.74 55.41,75.74 55.28,75.86 55.28,76.41 55.16,76.53 54.85,76.53 54.72,76.41 54.72,75.86 54.59,75.74 52.92,75.74 52.85,75.81 50.63,75.81 50.1,75.28 47.1,75.28 46.88,75.5 45.03,75.5 44.92,75.4 v3(44.92,75.08)
  BOTTOM w0.076: v3(108,80.68) 108.08,80.54 UC1.L29
  BOTTOM w0.102: JDIMM2.67 46.12,76.28 v3(44.92,75.08)
DDR_M1_D30: length 78
  IN2 w0.076: v3(106.73,79.77) 106.6,79.77 106.24,79.41 103.39,79.41 101.92,77.94 98.01,77.94 96.5,76.43 92.49,76.43 90.11,78.81 89.47,80.37 89.35,80.48 89.01,80.48
  IN2 w0.127: 89.01,80.48 73.66,80.48 65.63,72.46 61.88,72.46 61.75,72.59 61.75,73.07 61.62,73.2 61.37,73.2 61.24,73.07 61.24,72.59 61.12,72.46 60.86,72.46 60.74,72.59 60.74,73.01 60.61,73.13 60.35,73.13 60.23,73.01 60.23,72.59 60.1,72.46 53.54,72.46 53.15,72.85 51.75,72.85 51.41,72.51 49.44,72.51 48.22,71.29 45.81,71.29 45.39,70.87 45.01,70.87 44.89,71 v3(44.89,71.71)
  BOTTOM w0.076: UC1.N31 v3(106.73,79.77)
  BOTTOM w0.102: JDIMM2.79 46.45,73.28 v3(44.89,71.71)
DDR_M1_D31: length 79.2
  IN2 w0.076: v3(106.09,79.77) 105.9,79.58 103.32,79.58 101.85,78.11 97.95,78.11 96.43,76.6 92.56,76.6 90.28,78.88 89.45,80.87 89.33,80.99 89.01,80.99
  IN2 w0.127: v3(46.16,71.71) 46.16,72.06 46.38,72.28 47.25,72.28 47.91,71.62 48.09,71.62 48.27,71.8 48.27,71.98 47.7,72.55 47.7,72.73 47.89,72.92 48.07,72.92 48.62,72.37 48.83,72.37 48.99,72.53 48.99,72.71 48.71,72.99 48.71,73.17 48.89,73.35 49.07,73.35 49.35,73.07 49.53,73.07 49.81,73.35 51.49,73.35 51.66,73.18 53.29,73.18 53.67,72.79 54.05,72.79 54.22,72.96 54.22,73.27 54.34,73.4 54.61,73.4 54.74,73.27 54.74,72.92 54.87,72.79 55.12,72.79 55.25,72.92 55.25,73.27 55.37,73.4 57.04,73.4 57.37,73.73 62.06,73.73 62.29,73.51 62.29,72.92 62.41,72.79 62.67,72.79 62.8,72.92 62.8,73.6 62.92,73.73 64.79,73.73 65.12,73.4 65.12,72.92 65.24,72.79 65.5,72.79 65.62,72.92 65.62,73.4 65.75,73.53 66.03,73.53 73.49,80.99 89.01,80.99
  BOTTOM w0.076: UC1.N32 v3(106.09,79.77)
  BOTTOM w0.102: JDIMM2.83 46.72,72.28 v3(46.16,71.71)
DDR_M1_D32: length 79.4
  IN2 w0.076: v3(108,69.74) 107.48,69.22 106.51,69.22 106.48,69.19 105.62,69.19 102.2,65.76 101.94,65.76 101.31,65.14 100.85,65.14 100.36,64.64 93.01,64.64 91.35,62.98 89.01,62.98
  IN2 w0.127: v3(44.79,46.96) 44.79,46.63 44.92,46.5 48.09,46.5 48.68,45.92 51.42,45.92 51.58,46.07 54.24,46.07 54.92,46.74 55.57,46.74 56.2,47.38 61.98,47.38 62.11,47.25 62.11,47.04 62.24,46.91 62.49,46.91 62.62,47.04 62.62,47.31 62.74,47.44 63.2,47.44 63.21,47.44 64.03,47.44 65.17,48.58 68.71,48.58 83.1,62.98 89.01,62.98
  BOTTOM w0.076: UC1.AJ29 v3(108,69.74)
  BOTTOM w0.102: JDIMM2.170 42.58,48.53 43.59,47.51 44.24,47.51 v3(44.79,46.96)
DDR_M1_D33: length 78.9
  IN2 w0.076: 89.01,63.31 91.45,63.31 92.95,64.81 100.29,64.81 100.79,65.3 101.24,65.3 101.87,65.93 102.13,65.93 103.09,66.9 103.09,68.39 104.07,69.36 106.42,69.36 106.45,69.39 107.01,69.39 v3(107.36,69.74)
  IN2 w0.127: v3(47.33,46.96) 48.1,46.96 48.78,46.29 51.33,46.29 51.44,46.4 54.11,46.4 54.78,47.07 55.43,47.07 56.07,47.71 62.2,47.71 63.4,48.92 64.2,48.92 64.33,49.04 64.33,49.84 64.45,49.97 64.76,49.97 64.89,49.84 64.89,49.09 65.06,48.92 65.32,48.92 65.44,49.04 65.44,49.82 65.57,49.94 65.83,49.94 65.95,49.82 65.95,49.04 66.08,48.92 66.33,48.92 66.46,49.04 66.46,49.82 66.59,49.94 66.84,49.94 66.97,49.82 66.97,49.04 67.1,48.92 68.57,48.92 82.96,63.31 89.01,63.31
  BOTTOM w0.076: UC1.AJ30 v3(107.36,69.74)
  BOTTOM w0.102: JDIMM2.173 48.15,47.78 48.15,47.78 v3(47.33,46.96)
DDR_M1_D34: length 79.3
  IN2 w0.076: v3(106.09,67.92) 105.44,67.26 105.02,67.26 104.27,66.51 104.27,66.1 102.77,64.6 101.08,64.6 100.58,64.11 93.36,64.11 90.96,61.71 89.01,61.71
  IN2 w0.127: v3(47.33,43.85) 47.33,44.07 47.46,44.2 47.99,44.2 48.12,44.07 48.12,43.56 48.24,43.43 48.5,43.43 48.62,43.56 48.62,44.07 48.75,44.2 49,44.2 49.13,44.07 49.13,43.56 49.26,43.43 49.51,43.43 49.64,43.56 49.64,44.07 49.77,44.2 50.02,44.2 50.1,44.13 50.1,43.53 50.19,43.43 50.97,43.43 51.09,43.56 51.09,44.07 51.22,44.2 51.47,44.2 51.6,44.07 51.6,43.56 51.73,43.43 52.57,43.43 52.7,43.31 53.28,43.31 54.94,44.97 55.98,44.97 56.11,45.09 56.11,45.39 56.24,45.52 56.49,45.52 56.62,45.39 56.62,45.09 56.74,44.97 57,44.97 57.13,45.09 57.13,45.51 57.25,45.64 57.51,45.64 57.63,45.51 57.63,45.09 57.76,44.97 58.01,44.97 58.14,45.09 58.14,45.51 58.27,45.64 58.52,45.64 58.65,45.51 58.65,45.09 58.78,44.97 59.55,44.97 59.7,45.12 61.39,45.12 61.9,45.64 68.04,45.64 84.11,61.71 89.01,61.71
  BOTTOM w0.089: v3(106.09,67.92) UC1.AM32
  BOTTOM w0.102: JDIMM2.187 49.18,44.28 48.18,44.28 47.84,43.93 47.42,43.93 v3(47.33,43.85)
DDR_M1_D35: length 79.9
  IN2 w0.076: v3(106.73,67.92) 106.6,67.92 106.24,67.56 105.97,67.56 105.49,67.08 105.07,67.08 104.43,66.44 104.43,66.03 102.83,64.44 101.14,64.44 100.65,63.94 100.03,63.94 99.76,63.67 99.76,63.27 99.65,63.16 99.23,63.16 99.07,63.32 96.7,63.32 96.08,63.94 93.43,63.94 90.86,61.38 89.01,61.38
  IN2 w0.127: 89.01,61.38 84.24,61.38 68.18,45.31 63.03,45.31 62.9,45.18 62.9,44.55 62.78,44.42 62.52,44.42 62.39,44.55 62.39,45.14 62.27,45.27 62.09,45.27 61.52,44.7 60.17,44.7 60.1,44.64 55.08,44.64 54.96,44.51 54.96,44.36 55.15,44.17 55.15,44.09 55.01,43.96 54.95,43.96 54.74,44.17 54.6,44.17 53.41,42.98 52.06,42.98 51.94,43.1 46.98,43.1 46.9,43.18 46.9,43.31 46.79,43.42 46.68,43.42 46.6,43.34 46.6,43.21 46.48,43.09 46.26,43.09 46.06,43.29 v3(46.06,43.85)
  BOTTOM w0.089: v3(106.73,67.92) UC1.AM31
  BOTTOM w0.102: v3(46.06,43.85) 46.06,44.38 46.23,44.54 47.58,44.54 48.32,45.28 JDIMM2.183
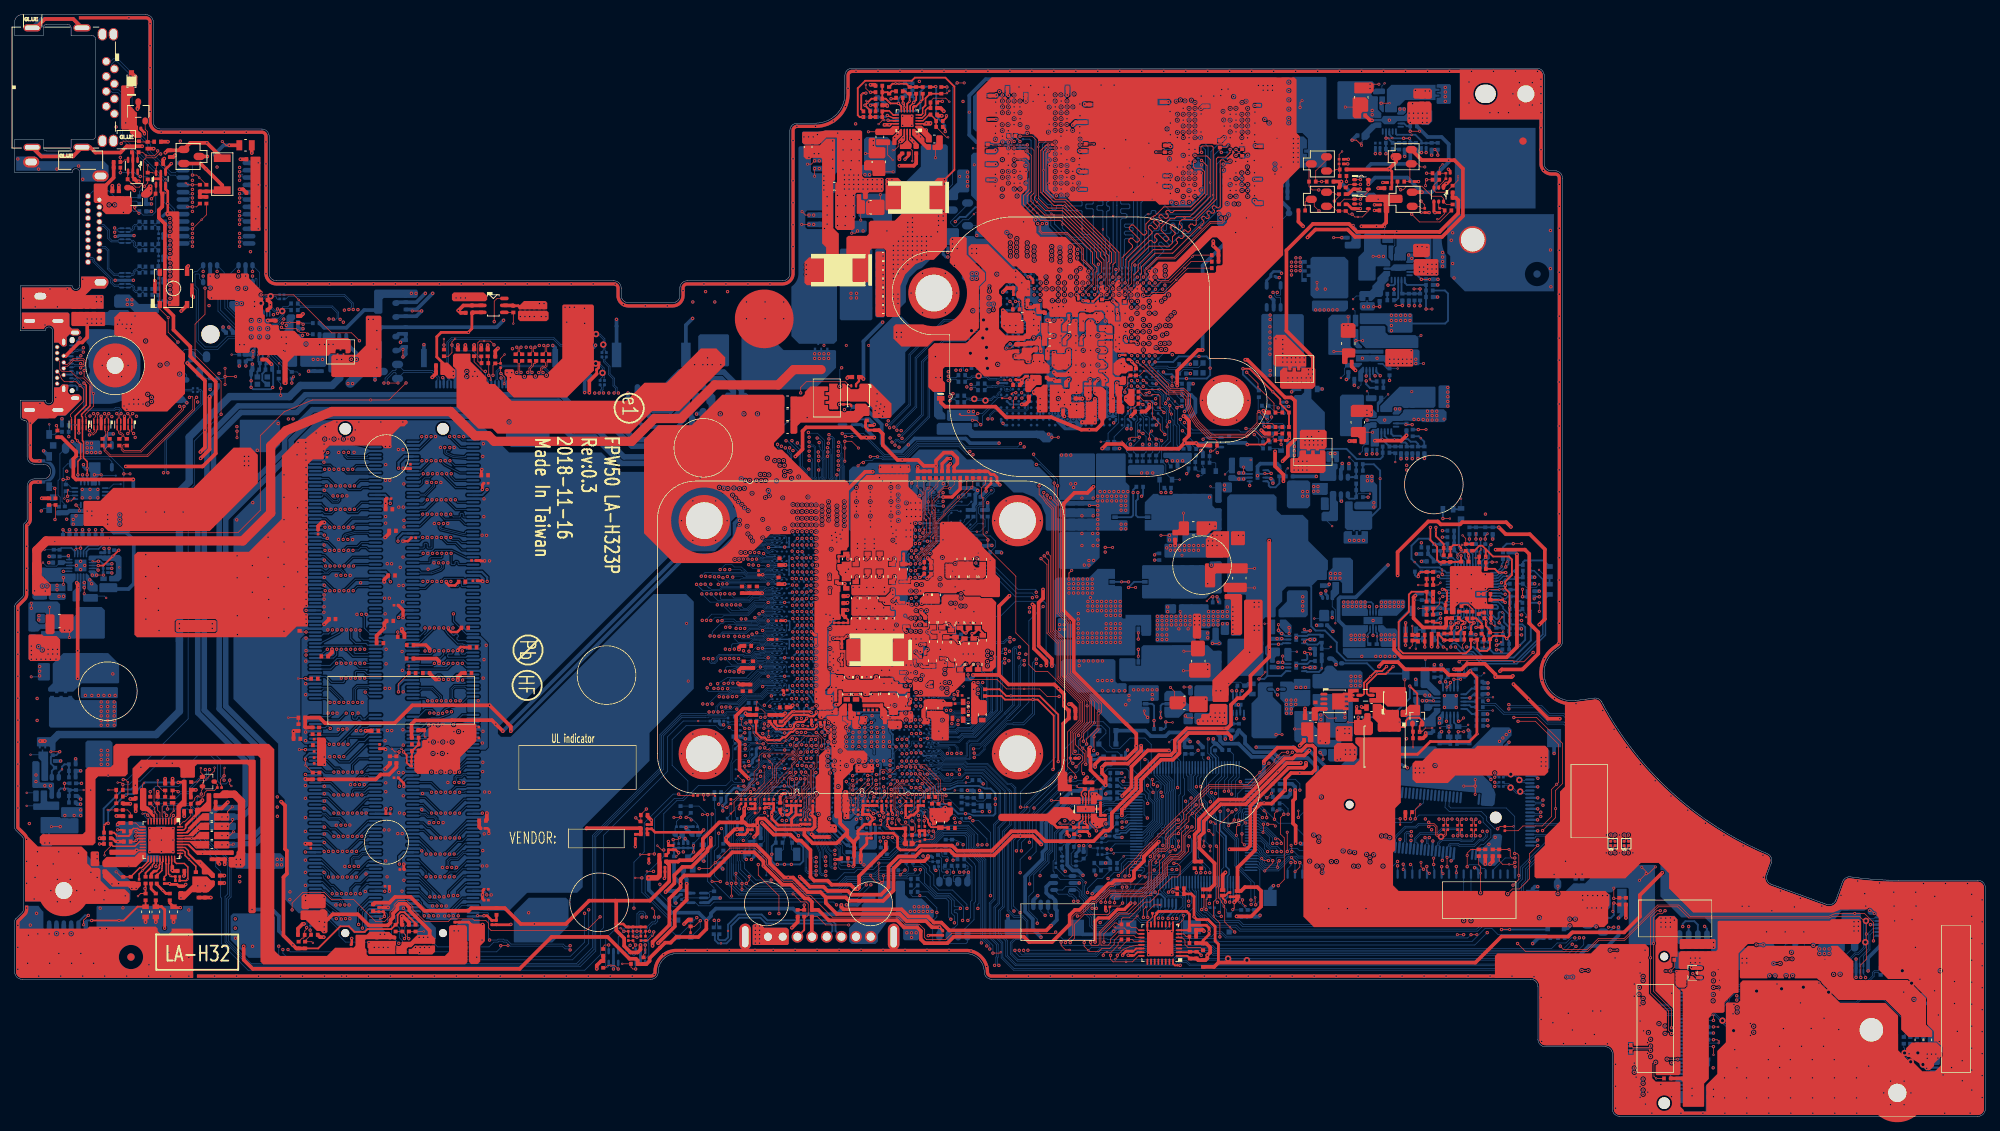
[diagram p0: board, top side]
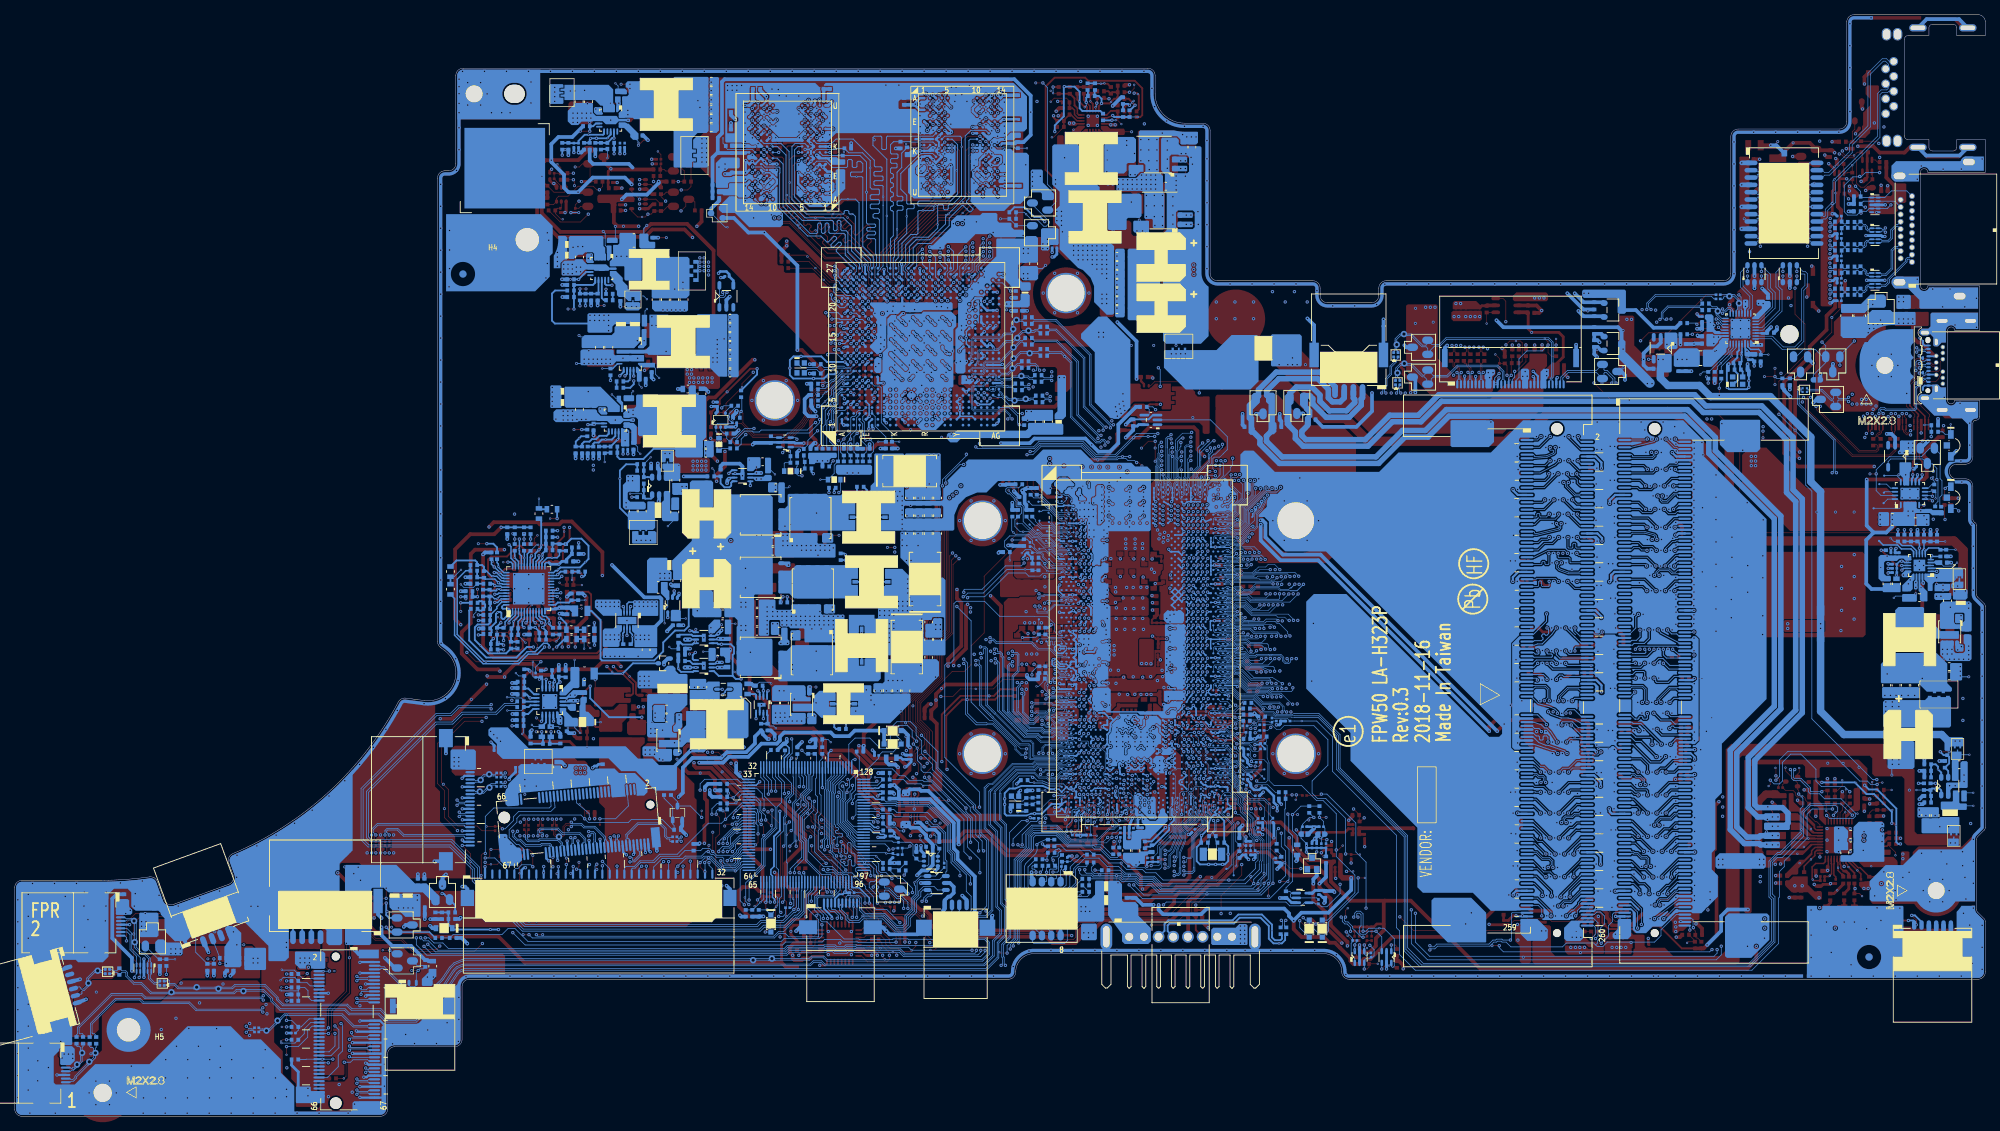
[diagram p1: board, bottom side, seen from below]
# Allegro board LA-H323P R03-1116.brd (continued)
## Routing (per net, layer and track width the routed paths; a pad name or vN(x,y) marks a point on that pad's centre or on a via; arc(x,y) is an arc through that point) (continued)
DDR_M1_D36: length 80.3
  IN2 w0.076: 89.01,61.05 90.77,61.05 93.5,63.78 95.66,63.78 96.28,63.16 99,63.16 99.17,62.99 100.15,62.99 100.47,63.31 100.47,63.47 101.27,64.27 102.9,64.27 104.6,65.97 104.6,66.37 105.14,66.92 105.56,66.92 106.04,67.4 106.31,67.4 106.46,67.54 106.99,67.54 v3(107.36,67.92)
  IN2 w0.127: 89.01,61.05 84.38,61.05 68.2,44.86 63.8,44.86 62.99,44.06 62.03,44.06 61.97,44.12 61.97,44.43 61.91,44.49 61.78,44.49 61.69,44.4 61.69,44.15 61.59,44.05 61.2,44.05 60.81,43.66 55.77,43.66 55.74,43.63 54.53,43.63 53.55,42.65 51.93,42.65 51.86,42.71 45.93,42.71 v3(44.79,43.85)
  BOTTOM w0.076: UC1.AM30 v3(107.36,67.92)
  BOTTOM w0.102: JDIMM2.182 40.98,45.53 43.12,45.53 v3(44.79,43.85)
DDR_M1_D37: length 80.9
  IN2 w0.076: 89.01,60.71 90.67,60.71 93.57,63.61 95.59,63.61 96.21,62.99 98.93,62.99 99.1,62.82 100.22,62.82 100.87,63.47 102.07,63.47 102.7,64.11 102.97,64.11 104.76,65.9 104.76,66.3 105.21,66.75 105.63,66.75 106.11,67.23 106.38,67.23 106.53,67.38 107.46,67.38 v3(108,67.92)
  IN2 w0.127: 89.01,60.71 84.74,60.71 67.66,43.63 66.69,43.63 66.57,43.76 66.57,44.14 66.44,44.26 66.1,44.26 65.97,44.14 65.97,43.76 65.84,43.63 61.3,43.63 60.99,43.33 55.91,43.33 55.88,43.3 54.67,43.3 53.69,42.32 51.79,42.32 51.73,42.38 44.99,42.38 v3(43.52,43.85)
  BOTTOM w0.076: UC1.AM29 v3(108,67.92)
  BOTTOM w0.102: v3(43.52,43.85) 42.85,44.53 JDIMM2.186
DDR_M1_D38: length 77.6
  IN2 w0.076: v3(106.65,69.75) 106.32,70.09 105.94,70.09 105.71,70.09 105.32,69.7 103.95,69.7 100.45,66.21 98.13,66.21 97.75,65.83 97.75,65.26 97.63,65.14 92.81,65.14 91.64,63.97 89.01,63.97
  IN2 w0.127: 89.01,63.97 82.48,63.97 69.29,50.77 64.32,50.77 62.78,49.23 59.36,49.23 58.71,48.58 56.01,48.58 55.16,47.73 51.11,47.73 50.93,47.56 50.93,47.21 50.69,46.96 50.34,46.96 50.1,47.21 50.1,47.56 49.92,47.73 44.3,47.73 v3(43.52,46.96)
  BOTTOM w0.076: UC1.AJ31 106.65,69.75 v3(106.65,69.75)
  BOTTOM w0.102: v3(43.52,46.96) 42.4,46.96 41.83,47.53 JDIMM2.174
DDR_M1_D39: length 78.3
  IN2 w0.076: v3(106.07,69.72) 105.58,69.72 105.39,69.54 104.01,69.54 101.56,67.08 101.56,65.86 101.17,65.47 100.72,65.47 100.22,64.97 92.88,64.97 91.54,63.64 89.01,63.64
  IN2 w0.127: v3(46.06,46.96) 46.51,47.4 49.64,47.4 49.77,47.28 49.77,46.76 49.89,46.63 51.2,46.63 51.33,46.76 51.33,47.28 51.46,47.4 55.29,47.4 56.14,48.25 59.46,48.25 59.59,48.38 59.59,48.77 59.72,48.9 59.97,48.9 60.1,48.77 60.1,48.38 60.22,48.25 60.48,48.25 60.61,48.38 60.61,48.77 60.73,48.9 60.99,48.9 61.11,48.77 61.11,48.38 61.24,48.25 62.27,48.25 64.37,50.35 69.54,50.35 82.83,63.64 89.01,63.64
  BOTTOM w0.076: v3(106.07,69.72) 106.11,69.71 UC1.AJ32
  BOTTOM w0.102: v3(46.06,46.96) 46.06,47.91 46.93,48.78 JDIMM2.169
DDR_M1_D40: length 80.8
  IN2 w0.076: 89.01,59.88 90.3,59.88 92.5,62.07 99.11,62.07 99.53,62.49 100.44,62.49 101.09,63.14 102.2,63.14 102.73,63.67 103.08,63.67 105.86,66.45 106.38,66.45 v3(106.73,66.1)
  IN2 w0.127: v3(46.06,41.37) 46.06,40.94 46.19,40.81 52.01,40.81 52.39,40.43 54.7,40.43 55.96,41.69 56.45,41.69 56.57,41.82 56.57,42.3 56.7,42.43 56.98,42.43 57.11,42.3 57.11,41.92 57.23,41.79 57.49,41.79 57.61,41.92 57.61,42.3 57.74,42.43 57.99,42.43 58.12,42.3 58.12,41.92 58.25,41.79 58.5,41.79 58.63,41.92 58.63,42.3 58.76,42.43 59.01,42.43 59.14,42.3 59.14,41.92 59.26,41.79 59.52,41.79 59.65,41.92 59.65,42.3 59.77,42.43 60.03,42.43 60.15,42.3 60.15,41.9 60.28,41.77 60.53,41.77 60.66,41.9 60.66,42.3 60.79,42.43 61.28,42.43 61.51,42.65 68.07,42.65 85.29,59.88 89.01,59.88
  BOTTOM w0.076: UC1.AR31 v3(106.73,66.1)
  BOTTOM w0.102: JDIMM2.191 47.97,43.28 v3(46.06,41.37)
DDR_M1_D41: length 80.4
  IN2 w0.076: v3(106.09,66.1) 105.74,66.1 103.04,63.39 102.69,63.39 102.27,62.98 101.16,62.98 100.37,62.19 100.16,62.19 99.88,61.91 92.57,61.91 90.2,59.55 89.01,59.55
  IN2 w0.127: 89.01,59.55 85.43,59.55 68.2,42.32 62.66,42.32 62.53,42.2 62.53,41.45 62.41,41.32 62.15,41.32 62.03,41.45 62.03,42.2 61.9,42.32 61.64,42.32 61.52,42.2 61.52,40.95 61.39,40.82 55.56,40.82 54.84,40.1 52.25,40.1 51.87,40.48 45.92,40.48 45.84,40.56 45.27,40.56 44.79,41.04 v3(44.79,41.37)
  BOTTOM w0.076: UC1.AR32 v3(106.09,66.1)
  BOTTOM w0.102: v3(44.79,41.37) 42.64,43.53 JDIMM2.190
DDR_M1_D42: length 82.7
  IN2 w0.076: 88.99,57.29 89.51,57.29 92.35,60.12 99.09,60.12 99.13,60.08 99.98,60.08 100.86,60.95 101.82,60.95 102.38,61.51 103.22,61.51 104.25,62.53 104.25,63.1 104.9,63.75 106.31,63.75 106.48,63.92 107.17,63.92 107.36,64.12 v3(107.36,64.28)
  IN2 w0.127: v3(44.79,38.2) 44.79,37.11 44.9,37.01 45.04,37.01 45.14,37.11 45.14,37.67 45.25,37.78 45.4,37.78 45.5,37.67 45.5,37.1 45.61,36.99 54.49,36.99 54.98,37.48 60.86,37.48 61.5,38.12 65.25,38.12 65.38,38.24 65.38,38.56 65.5,38.69 65.76,38.69 65.89,38.56 65.89,38.24 66.01,38.12 67.24,38.12 86.41,57.29 88.99,57.29
  BOTTOM w0.076: UC1.AV30 v3(107.36,64.28)
  BOTTOM w0.102: JDIMM2.204 42.24,40.03 43.05,39.22 43.78,39.22 v3(44.79,38.2)
DDR_M1_D43: length 83
  IN2 w0.076: 88.99,56.96 89.42,56.96 92.41,59.95 99.02,59.95 99.06,59.91 100.05,59.91 100.92,60.78 101.89,60.78 102.45,61.34 103.29,61.34 104.42,62.46 104.42,63.04 104.97,63.59 106.38,63.59 106.55,63.76 107.48,63.76 v3(108,64.28)
  IN2 w0.127: 88.99,56.96 86.55,56.96 67.35,37.75 61.6,37.75 61,37.15 55.13,37.15 54.64,36.66 44.24,36.66 44.18,36.72 44.18,37.6 44.12,37.66 43.9,37.66 43.84,37.6 43.84,36.72 43.78,36.66 43.61,36.66 43.52,36.75 v3(43.52,38.2)
  BOTTOM w0.089: v3(108,64.28) UC1.AV29
  BOTTOM w0.102: JDIMM2.208 42.7,39.03 v3(43.52,38.2)
DDR_M1_D44: length 81.4
  IN2 w0.076: 89.01,60.21 90.4,60.21 93.04,62.85 94.51,62.85 94.53,62.83 98.86,62.83 99.03,62.66 100.37,62.66 101.02,63.31 102.13,63.31 102.66,63.84 103.01,63.84 105.83,66.65 106.81,66.65 v3(107.36,66.1)
  IN2 w0.127: v3(47.33,41.37) 47.33,41.75 47.46,41.87 48.22,41.87 48.35,41.75 48.35,41.27 48.47,41.14 48.73,41.14 48.86,41.27 48.86,41.75 48.99,41.87 49.24,41.87 49.37,41.75 49.37,41.27 49.49,41.14 49.75,41.14 49.87,41.27 49.87,41.61 50,41.74 50.26,41.74 50.38,41.61 50.38,41.27 50.51,41.14 50.85,41.14 50.98,41.27 50.98,41.42 51.1,41.54 51.36,41.54 51.48,41.42 51.48,41.27 51.61,41.14 52.15,41.14 52.43,40.86 53.94,40.86 54.1,41.01 54.1,41.19 53.77,41.52 53.77,41.7 53.95,41.88 54.13,41.88 54.81,41.19 54.99,41.19 55.17,41.37 55.17,41.55 54.5,42.23 54.5,42.41 54.73,42.64 54.91,42.64 55.23,42.32 55.41,42.32 55.87,42.79 61.17,42.79 61.37,42.98 67.93,42.98 85.15,60.21 89.01,60.21
  BOTTOM w0.076: UC1.AR30 v3(107.36,66.1)
  BOTTOM w0.102: v3(47.33,41.37) 47.1,41.61 47.1,41.89 47.49,42.28 JDIMM2.195
DDR_M1_D45: length 82.2
  IN2 w0.076: v3(108,66.1) 107.6,65.7 105.58,65.7 103.1,63.23 102.75,63.23 102.34,62.81 101.23,62.81 100.44,62.02 100.22,62.02 99.95,61.74 92.63,61.74 90.11,59.22 89.01,59.22
  IN2 w0.127: v3(43.52,41.37) 43.21,41.37 43.09,41.25 43.09,40.36 43.21,40.23 43.49,40.23 43.62,40.36 43.62,40.86 43.75,40.98 44,40.98 44.13,40.86 44.13,40.36 44.25,40.23 45.71,40.23 45.79,40.15 51.74,40.15 52.12,39.77 55.62,39.77 56.34,40.49 62.09,40.49 63.6,41.99 68.34,41.99 85.56,59.22 89.01,59.22
  BOTTOM w0.076: UC1.AR29 v3(108,66.1)
  BOTTOM w0.102: JDIMM2.194 42.37,42.53 v3(43.52,41.37)
DDR_M1_D46: length 81.4
  IN2 w0.076: v3(106.09,64.27) 104.95,64.27 103.92,63.24 103.92,62.67 103.09,61.84 101.13,61.84 100.5,61.21 92.86,61.21 89.59,57.95 89.01,57.95
  IN2 w0.127: 89.01,57.95 86.14,57.95 68.26,40.06 65.51,40.06 65.39,39.94 65.39,39.47 65.26,39.35 65.01,39.35 64.88,39.47 64.88,39.94 64.75,40.06 64.5,40.06 64.37,39.94 64.37,39.47 64.24,39.35 63.99,39.35 63.86,39.47 63.86,39.94 63.74,40.06 63.46,40.06 63.34,39.94 63.34,39.42 63.28,39.35 62.75,39.35 62.42,39.02 59.56,39.02 59.44,38.89 56.66,38.89 56.28,38.5 53.96,38.5 53.82,38.36 53.82,37.76 53.71,37.65 53.29,37.65 53.16,37.78 53.16,38.03 53.04,38.15 52.78,38.15 52.66,38.03 52.66,37.78 52.53,37.65 52.27,37.65 52.15,37.78 52.15,38.01 52.02,38.14 51.77,38.14 51.64,38.01 51.64,37.78 51.51,37.65 49.9,37.65 49.8,37.75 49.8,38 49.67,38.13 49.49,38.13 49.4,38.04 49.4,37.78 49.27,37.65 49,37.65 48.88,37.78 48.88,38.63 48.75,38.76 48.49,38.76 48.36,38.63 48.36,37.78 48.23,37.65 47.98,37.65 47.85,37.78 47.85,38.63 47.72,38.76 47.46,38.76 47.33,38.63 v3(47.33,38.2)
  BOTTOM w0.089: v3(106.09,64.27) UC1.AV32
  BOTTOM w0.102: JDIMM2.207 48.2,39.28 47.33,38.41 v3(47.33,38.2)
DDR_M1_D47: length 81.6
  IN2 w0.076: v3(106.73,64.28) 106.6,64.28 106.24,63.92 104.83,63.92 104.09,63.17 104.09,62.6 103.16,61.67 101.21,61.67 99.78,60.24 99.2,60.24 99.16,60.28 92.16,60.28 89.5,57.62 89.01,57.62
  IN2 w0.127: v3(46.06,38.2) 46.06,37.45 46.19,37.32 46.45,37.32 46.57,37.45 46.57,37.66 46.7,37.78 46.95,37.78 47.08,37.66 47.08,37.45 47.21,37.32 53.85,37.32 54.59,38.06 56.31,38.06 56.64,38.4 59.42,38.4 59.7,38.69 62.55,38.69 62.89,39.02 65.59,39.02 65.72,39.14 65.72,39.61 65.84,39.73 66.22,39.73 66.35,39.61 66.35,38.57 66.48,38.45 66.73,38.45 66.86,38.57 66.86,39.61 66.99,39.73 67.24,39.73 67.37,39.61 67.37,39.28 67.49,39.15 67.77,39.15 67.9,39.28 67.9,39.63 68,39.73 68.39,39.73 86.28,57.62 89.01,57.62
  BOTTOM w0.089: UC1.AV31 v3(106.73,64.28)
  BOTTOM w0.102: v3(46.06,38.2) 48.14,40.28 JDIMM2.203
DDR_M1_D48: length 78.7
  IN2 w0.076: 88.99,55.46 91.52,57.99 97.35,57.99 97.48,58.12 99.52,58.12 101.52,60.12 102.16,60.12 102.72,60.68 104.14,60.68 105.91,62.45 106,62.45 v3(106.06,62.5)
  IN2 w0.127: v3(42.79,36.15) 43.87,35.07 49.75,35.07 50.41,34.42 51.65,34.42 52.07,34.84 54.07,34.84 54.47,34.44 60.1,34.44 60.42,34.75 66.58,34.75 87.28,55.46 88.99,55.46
  BOTTOM w0.076: UC1.BA32 106.07,62.5 v3(106.06,62.5)
  BOTTOM w0.102: v3(42.79,36.15) 41.92,37.03 JDIMM2.216
DDR_M1_D49: length 79.7
  IN2 w0.076: 88.99,55.79 92.66,59.46 98.82,59.46 98.86,59.42 100.26,59.42 101.13,60.29 102.1,60.29 102.66,60.85 104.04,60.85 105.41,62.21 105.43,62.21 105.53,62.31 105.53,62.82 105.63,62.92 106.18,62.92 106.68,62.42 v3(106.73,62.42)
  IN2 w0.127: v3(44.06,36.15) 44.81,35.4 54.59,35.4 55.18,34.82 60.01,34.82 60.46,35.26 66.62,35.26 87.14,55.79 88.99,55.79
  BOTTOM w0.076: v3(106.73,62.42) 106.75,62.41 UC1.BA31
  BOTTOM w0.102: JDIMM2.212 42.19,38.03 v3(44.06,36.15)
DDR_M1_D50: length 81.6
  IN2 w0.076: 88.99,53.86 91.82,56.69 97.61,56.69 97.65,56.74 98.64,56.74 99.19,57.29 99.71,57.29 101.58,59.16 103.6,59.16 104.13,59.69 105.13,59.69 105.72,60.27 106.24,60.27 106.6,60.63 v3(106.73,60.63)
  IN2 w0.127: 88.99,53.86 87.94,53.86 66.62,32.54 61.36,32.54 60.63,31.8 53.81,31.8 53.68,31.93 53.68,32.51 53.55,32.63 52.42,32.63 52.22,32.43 52.22,31.95 52.07,31.8 50.75,31.8 50.62,31.93 50.62,32.1 50.5,32.23 50.24,32.23 50.12,32.1 50.12,31.93 49.99,31.8 46.58,31.8 46.45,31.93 46.45,32.03 46.32,32.16 46.07,32.16 45.94,32.03 45.94,31.93 45.82,31.8 45.53,31.8 45.33,32.01 v3(45.33,32.65)
  BOTTOM w0.076: UC1.BD31 v3(106.73,60.63)
  BOTTOM w0.102: v3(45.33,32.65) 46.34,33.66 47.06,33.66 48.18,34.78 JDIMM2.225
DDR_M1_D51: length 80.7
  IN2 w0.076: 88.99,54.19 91.66,56.86 97.54,56.86 97.58,56.9 98.57,56.9 99.12,57.46 99.64,57.46 101.51,59.32 103.53,59.32 104.84,60.63 v3(106.09,60.63)
  IN2 w0.127: 88.99,54.19 87.81,54.19 66.59,32.98 61.33,32.98 60.49,32.14 55.29,32.14 55.17,32.26 55.17,32.95 55.04,33.08 54.79,33.08 54.66,32.95 54.66,32.26 54.53,32.14 54.21,32.14 54.07,32.27 54.07,32.98 53.96,33.09 52.03,33.09 51.91,32.96 51.91,32.53 51.78,32.41 51.53,32.41 51.4,32.53 51.4,32.96 51.27,33.09 50.6,33.09 50.16,32.65 49.79,32.65 49.66,32.52 49.66,32.26 49.53,32.14 49.28,32.14 49.15,32.26 49.15,32.52 49.03,32.65 48.77,32.65 48.65,32.52 48.65,32.26 48.52,32.14 48.26,32.14 48.14,32.26 48.14,32.52 48.01,32.65 47.76,32.65 47.63,32.52 47.63,32.26 47.5,32.14 47.25,32.14 47.12,32.26 47.12,32.52 46.99,32.65 46.6,32.65 v3(46.6,32.65)
  BOTTOM w0.089: UC1.BD32 v3(106.09,60.63)
  BOTTOM w0.102: v3(46.6,32.65) 47.73,33.78 JDIMM2.229
DDR_M1_D52: length 80.6
  IN2 w0.076: v3(107.36,62.45) 106.97,62.84 106.51,62.84 106.27,63.09 105.55,63.09 105.37,62.91 105.37,62.44 103.94,61.01 102.59,61.01 102.03,60.45 101.06,60.45 100.19,59.58 98.93,59.58 98.89,59.62 92.55,59.62 89.05,56.12
  IN2 w0.127: 89.05,56.12 87.01,56.12 79.19,48.3 79.08,48.3 66.41,35.63 65.99,35.63 65.86,35.76 65.86,35.93 65.73,36.06 65.48,36.06 65.35,35.93 65.35,35.76 65.23,35.63 60.36,35.63 59.88,35.15 55.31,35.15 54.73,35.73 45.46,35.73 45.33,35.86 v3(45.33,36.15)
  BOTTOM w0.089: v3(107.36,62.45) UC1.BA30
  BOTTOM w0.102: v3(45.33,36.15) 46.97,37.79 47.59,37.79 48.07,38.28 JDIMM2.211
DDR_M1_D53: length 81.4
  IN2 w0.076: v3(108,62.45) 107.44,63.01 106.58,63.01 106.34,63.25 105.09,63.25 104.61,62.77 104.61,62.42 103.36,61.18 102.52,61.18 101.96,60.62 100.99,60.62 100.12,59.75 99,59.75 98.95,59.79 92.48,59.79 89.14,56.45 88.99,56.45
  IN2 w0.127: v3(46.6,36.15) 54.85,36.15 55.34,36.64 57.96,36.64 58.09,36.51 61.88,36.51 62.01,36.64 62.01,37.12 62.14,37.24 62.53,37.24 62.66,37.12 62.66,36.25 62.78,36.13 63.04,36.13 63.17,36.25 63.17,37.12 63.29,37.24 64.12,37.24 64.25,37.12 64.25,36.09 64.38,35.96 64.63,35.96 64.76,36.09 64.76,37.12 64.88,37.24 67.56,37.24 78.95,48.63 79.05,48.63 86.87,56.45 88.99,56.45
  BOTTOM w0.089: UC1.BA29 v3(108,62.45)
  BOTTOM w0.102: v3(46.6,36.15) 47.72,37.28 JDIMM2.215
DDR_M1_D54: length 82
  IN2 w0.076: v3(108,60.63) 107.44,60.07 106.53,60.07 106.38,59.92 105.84,59.92 105.27,59.36 104.27,59.36 103.74,58.83 102.68,58.83 102.13,58.28 101.19,58.28 99.87,56.96 99.33,56.96 98.77,56.41 97.79,56.41 97.75,56.36 95.93,56.36 95.27,55.7 91.56,55.7 88.99,53.13
  IN2 w0.127: v3(42.79,32.65) 42.79,31.57 43.21,31.14 60.97,31.14 61.61,31.78 66.8,31.78 88.14,53.12 88.98,53.12 88.99,53.13
  BOTTOM w0.089: UC1.BD29 v3(108,60.63)
  BOTTOM w0.102: v3(42.79,32.65) 42.79,33.29 42.06,34.03 JDIMM2.228
DDR_M1_D55: length 81.4
  IN2 w0.076: 88.99,53.53 91.33,55.87 95.2,55.87 95.86,56.53 97.68,56.53 97.72,56.57 98.71,56.57 99.26,57.12 99.78,57.12 101.64,58.99 103.67,58.99 104.2,59.52 105.2,59.52 105.79,60.11 106.31,60.11 106.48,60.27 106.88,60.27 107.23,60.63 v3(107.36,60.63)
  IN2 w0.127: v3(44.06,32.65) 43.77,32.36 43.77,31.9 44.2,31.47 60.83,31.47 61.49,32.14 66.69,32.14 88.01,53.45 88.91,53.45 88.99,53.53
  BOTTOM w0.089: v3(107.36,60.63) 107.54,60.31 UC1.BD30
  BOTTOM w0.102: v3(44.06,32.65) 44.06,32.85 41.88,35.03 JDIMM2.224
DDR_M1_D56: length 85.2
  IN2 w0.076: v3(106.73,58.81) 106.51,59.03 106.45,59.03 106.32,59.16 105.81,59.16 105.51,58.86 104.48,58.86 103.94,58.33 102.89,58.33 102.34,57.78 101.4,57.78 100.08,56.46 99.53,56.46 98.98,55.91 98.31,55.91 98.07,55.67 98.07,55.59 97.13,54.65 91.68,54.65 88.99,51.95
  IN2 w0.127: v3(44.57,30.37) 44.57,29.71 44.7,29.58 45.97,29.58 46.3,29.26 52.02,29.26 52.14,29.13 52.14,28.64 52.27,28.52 52.52,28.52 52.65,28.64 52.65,29.13 52.78,29.26 53.58,29.26 53.7,29.13 53.7,28.41 53.83,28.28 59.76,28.28 61.14,29.66 65.26,29.66 65.39,29.79 65.39,30.42 65.52,30.55 65.74,30.55 65.87,30.42 65.87,29.79 65.99,29.66 66.25,29.66 66.37,29.79 66.37,30.42 66.5,30.55 67.22,30.55 88.63,51.95 88.99,51.95
  BOTTOM w0.089: UC1.BG31 v3(106.73,58.81)
  BOTTOM w0.102: v3(44.57,30.37) 43.44,31.5 43.14,31.5 42.11,32.53 42.11,32.79 41.88,33.03 JDIMM2.232
DDR_M1_D57: length 84.9
  IN2 w0.076: 88.99,51.62 89.03,51.62 91.89,54.48 97.89,54.48 99.71,56.3 100.15,56.3 101.47,57.62 102.41,57.62 102.95,58.16 104.01,58.16 104.54,58.7 105.99,58.7 v3(106.06,58.77)
  IN2 w0.127: v3(43.3,30.37) 43.3,29.38 43.43,29.25 45.83,29.25 46.16,28.93 51.69,28.93 51.81,28.8 51.81,28.09 51.95,27.95 53.75,27.95 53.88,27.82 53.88,27.39 54.01,27.26 54.26,27.26 54.39,27.39 54.39,27.82 54.52,27.95 54.8,27.95 54.93,27.82 54.93,27.39 55.06,27.26 55.31,27.26 55.44,27.39 55.44,27.82 55.57,27.95 59.89,27.95 60.25,28.3 60.43,28.3 60.78,27.95 60.96,27.95 61.13,28.13 61.13,28.31 60.79,28.66 60.79,28.84 61.03,29.09 61.22,29.09 61.5,28.81 61.81,28.81 62.33,29.33 66.62,29.33 66.84,29.55 66.84,29.7 66.84,29.7 88.77,51.62 88.99,51.62
  BOTTOM w0.089: v3(106.06,58.77) 106.16,58.67 UC1.BG32
  BOTTOM w0.102: JDIMM2.236 42.01,32.03 43.3,30.74 v3(43.3,30.37)
DDR_M1_D58: length 84.5
  IN2 w0.076: v3(105.95,56.99) 105.76,57.17 105.76,57.23 105.11,57.88 104.66,57.88 104.41,57.63 104.15,57.63 103.48,56.96 101.57,56.96 100.37,55.77 99.93,55.77 98.09,53.93 92.2,53.93 89.9,51.63 89.9,51.08 89.4,50.58 89.4,50.36 88.99,49.95
  IN2 w0.127: 88.99,49.95 73.01,33.97 73.01,33.93 67.08,28 66.26,28 66.13,27.87 66.13,27.31 66,27.19 65.75,27.19 65.62,27.31 65.62,27.87 65.49,28 65.24,28 65.11,27.87 65.11,27.31 64.99,27.19 64.73,27.19 64.61,27.31 64.61,27.87 64.48,28 63.7,28 63.57,27.87 63.57,27.33 63.44,27.2 63.17,27.2 63.04,27.33 63.04,27.62 62.92,27.74 62.66,27.74 62.53,27.62 62.53,27.33 62.41,27.2 62,27.2 61.85,27.05 61.85,26.52 61.32,25.99 59.84,25.99 59.43,25.58 59.04,25.58 58.63,25.99 51.24,25.99 50.92,25.68 49.73,25.68 49.28,26.12 49.28,26.45 49.18,26.55 48.62,26.55 48.49,26.42 48.49,26.03 48.36,25.9 48.11,25.9 47.98,26.03 47.98,26.42 47.85,26.55 47.55,26.55 47.42,26.42 v3(47.42,25.68)
  BOTTOM w0.076: UC1.BK32 105.95,56.89 v3(105.95,56.99)
  BOTTOM w0.102: JDIMM2.249 48.33,28.78 47.42,27.87 v3(47.42,25.68)
DDR_M1_D59: length 85.4
  IN2 w0.076: v3(106.6,57.01) 106.48,57.01 106.1,56.63 105.8,56.63 105.26,57.17 104.54,57.17 104.45,57.26 104.02,57.26 103.55,56.8 101.63,56.8 100.07,55.24 100.07,54.87 99.74,54.54 98.98,54.54 98.2,53.77 92.27,53.77 90.06,51.56 90.06,51.01 89.57,50.51 89.57,50.06 88.99,49.48
  IN2 w0.127: v3(46.9,26.18) 46.9,25.61 47.24,25.26 50.98,25.26 51.37,25.66 57.41,25.66 57.54,25.53 57.54,24.54 57.94,24.14 59.93,24.14 61.76,25.97 62.17,25.97 62.3,26.09 62.3,26.63 62.42,26.75 62.68,26.75 62.81,26.63 62.81,26.09 62.93,25.97 63.25,25.97 63.37,26.08 63.37,26.61 63.53,26.78 64.27,26.78 64.4,26.65 64.4,26.09 64.52,25.97 64.78,25.97 64.9,26.09 64.9,26.65 65.03,26.78 66.33,26.78 73.14,33.58 73.34,33.79 73.34,33.83 88.99,49.48
  BOTTOM w0.076: v3(106.6,57.01) 106.82,56.57 UC1.BK31
  BOTTOM w0.102: v3(46.9,26.18) 46.9,28.34 48.34,29.78 JDIMM2.245
DDR_M1_D60: length 86
  IN2 w0.076: v3(108,58.81) 107.44,59.36 106.58,59.36 106.45,59.49 105.64,59.49 105.34,59.19 104.34,59.19 103.8,58.66 102.75,58.66 102.2,58.11 101.26,58.11 99.94,56.79 99.39,56.79 98.84,56.24 97.86,56.24 97.81,56.2 96,56.2 95.34,55.54 91.91,55.54 88.99,52.62
  IN2 w0.127: 88.99,52.62 88.35,52.62 67.01,31.27 63.07,31.27 62.94,31.15 62.94,30.45 62.82,30.32 62.56,30.32 62.44,30.45 62.44,31.15 62.31,31.27 61.98,31.27 61.86,31.15 61.86,30.46 61.72,30.32 61.24,30.32 61.02,30.54 56.72,30.54 56.62,30.64 56.22,30.64 56.09,30.51 56.09,30.23 55.97,30.11 55.71,30.11 55.59,30.23 55.59,30.51 55.46,30.64 55.2,30.64 55.08,30.51 55.08,29.99 54.95,29.86 54.7,29.86 54.57,29.99 54.57,30.51 54.44,30.64 54.21,30.64 54.07,30.5 54.07,30.06 53.93,29.92 53.64,29.92 53.51,30.04 53.51,30.27 53.38,30.4 53.13,30.4 53,30.27 53,30.04 52.88,29.92 52.4,29.92 52.28,30.04 52.28,30.51 52.15,30.64 51.89,30.64 51.77,30.51 51.77,30.04 51.64,29.92 50.22,29.92 50.1,30.04 50.1,30.51 49.97,30.64 49.71,30.64 49.59,30.51 49.59,30.04 49.46,29.92 49.17,29.92 49.05,30.04 49.05,30.51 48.92,30.64 48.66,30.64 48.54,30.51 48.54,30.04 48.41,29.92 47.24,29.92 47.11,30.04 v3(47.11,30.37)
  BOTTOM w0.089: UC1.BG29 v3(108,58.81)
  BOTTOM w0.102: JDIMM2.237 47.93,31.78 47.11,30.95 v3(47.11,30.37)
DDR_M1_D61: length 85.8
  IN2 w0.076: v3(107.36,58.81) 106.97,59.2 106.51,59.2 106.38,59.33 105.71,59.33 105.41,59.03 104.41,59.03 103.87,58.5 102.82,58.5 102.27,57.95 101.33,57.95 100.01,56.63 99.46,56.63 98.91,56.08 98.24,56.08 97.9,55.73 97.9,55.66 97.06,54.81 91.51,54.81 88.99,52.29
  IN2 w0.127: v3(45.84,30.37) 45.84,30.18 46.43,29.59 53.85,29.59 54.03,29.4 54.03,29.08 54.16,28.95 54.42,28.95 54.54,29.08 54.54,29.4 54.67,29.53 54.91,29.53 55.03,29.4 55.03,28.74 55.16,28.61 55.41,28.61 55.54,28.74 55.54,29.4 55.67,29.53 55.92,29.53 56.05,29.4 56.05,28.74 56.18,28.61 56.43,28.61 56.56,28.74 56.56,29.4 56.68,29.53 57,29.53 57.13,29.4 57.13,29.24 57.26,29.12 57.51,29.12 57.64,29.24 57.64,29.4 57.77,29.53 58.02,29.53 58.15,29.4 58.15,29.36 58.27,29.23 58.53,29.23 58.66,29.36 58.66,29.4 58.78,29.53 59.27,29.53 59.4,29.4 59.4,28.94 59.53,28.81 59.78,28.81 59.91,28.94 59.91,29.4 60.03,29.53 60.54,29.53 61,29.99 62.98,29.99 63.87,30.88 67.09,30.88 88.49,52.29 88.99,52.29
  BOTTOM w0.089: v3(107.36,58.81) UC1.BG30
  BOTTOM w0.102: JDIMM2.233 48.24,32.78 47.2,31.73 46.46,31.73 45.84,31.11 v3(45.84,30.37)
DDR_M1_D62: length 85.9
  IN2 w0.076: v3(107.36,56.94) 107.08,56.66 107.08,55.98 106.82,55.72 105.88,55.72 105.13,56.47 101.77,56.47 100.4,55.1 100.4,54.74 99.88,54.21 99.36,54.21 97.68,52.53 96.38,52.53 95.63,53.28 92.3,53.28 90.41,51.39 90.41,50.88 89.9,50.38 89.9,48.83 88.99,47.92
  IN2 w0.127: 88.99,47.92 88.78,47.92 66,25.13 62.07,25.13 60.42,23.48 56.89,23.48 56.55,23.82 52.98,23.82 52.71,24.09 47.48,24.09 45.44,26.13 44.68,26.13 v3(43.85,26.96)
  BOTTOM w0.089: v3(107.36,56.94) 107.58,56.54 UC1.BK30
  BOTTOM w0.102: v3(43.85,26.96) 42.29,28.53 JDIMM2.250
DDR_M1_D63: length 86.7
  IN2 w0.076: 88.99,48.38 89.73,49.13 89.73,50.44 90.24,50.95 90.24,51.46 92.23,53.45 95.7,53.45 96.44,52.7 97.61,52.7 99.29,54.37 99.81,54.37 100.24,54.81 100.24,55.17 101.7,56.63 103.62,56.63 104.09,57.1 104.38,57.1 104.47,57.01 105.19,57.01 105.73,56.47 106.29,56.47 106.38,56.56 106.65,56.56 107,56.91 107,57.09 107.3,57.38 107.6,57.38 v3(108,56.98)
  IN2 w0.127: v3(45.12,26.96) 45.12,26.92 47.62,24.42 51.18,24.42 51.61,24.85 56.76,24.85 57.8,23.81 60.28,23.81 62.11,25.64 66.04,25.64 88.78,48.38 88.99,48.38
  BOTTOM w0.089: UC1.BK29 v3(108,56.98)
  BOTTOM w0.102: JDIMM2.246 41.82,29.53 41.89,29.48 45.02,27.07 v3(45.12,26.96)
DDR_M1_DQS0: length 81.4
  IN2 w0.076: v3(110.99,82.62) 110.99,82.43 111.09,82.34 111.14,82.34 111.29,82.19 111.4,82.19 111.49,82.28 111.49,82.64 111.39,82.74 111.39,84.05 110.63,84.81 109.02,84.81 108.58,85.25 108.17,85.25 107.59,85.83 106.64,85.83
  IN2 w0.127: 106.64,85.83 105.62,85.83 104.16,87.29 104.16,87.99 103.06,89.09 103.05,89.09 103.02,89.13 101.56,89.13 101.52,89.09 94.01,89.09 93.34,89.76 69.9,89.76 64.8,84.66 63.63,84.66 62.94,85.35 61.21,85.35 60.75,85.81 53.55,85.81 53.34,85.61 48.79,85.61 48.43,85.25 44.46,85.25 44.31,85.1 44.31,85 v3(44.67,84.65)
  BOTTOM w0.076: v3(110.99,82.62) 111.29,82.62 111.45,82.78 UC1.G24
  BOTTOM w0.102: v3(44.67,84.65) 44.31,84.29 44.31,84.03 44.08,83.8 43.35,83.8 42.36,84.79 42.04,84.79 41.99,84.74 41.99,84.59 41.92,84.53 JDIMM2.34
DDR_M1_DQS1: length 87.6
  IN2 w0.076: v3(111.02,92.42) 110.08,92.42 109.54,92.96 109.51,92.96
  IN2 w0.127: v3(44.88,90.59) 44.93,90.54 44.93,90.52 44.94,90.51 44.94,89.94 45.23,89.64 46.39,89.64 48.82,92.07 53.01,92.07 53.14,91.94 53.14,91.66 53.42,91.39 54.01,91.39 54.28,91.66 54.28,91.94 54.41,92.07 54.79,92.07 54.92,91.94 54.92,91.66 55.19,91.39 55.79,91.39 56.06,91.66 56.06,91.94 56.19,92.07 60.05,92.07 60.74,91.38 63.28,91.38 63.57,91.09 64.6,91.09 65.07,91.56 65.07,91.95 64.79,92.23 64.79,92.41 64.97,92.59 65.15,92.59 65.43,92.31 65.82,92.31 66.15,92.64 66.15,93.03 65.87,93.3 65.87,93.48 66.05,93.66 67.17,93.66 67.47,93.96 95.06,93.96 95.35,93.67 101.02,93.67 101.1,93.75 108.57,93.75 109.35,92.96 109.51,92.96
  BOTTOM w0.076: UC1.D23 111.81,84.63 111.79,84.68 111.72,84.89 111.67,85.02 111.62,85.16 111.72,85.47 111.71,85.53 111.65,85.82 111.67,85.89 111.71,86.11 111.71,86.35 111.71,86.35 111.71,87.05 111.55,87.2 111.55,87.27 111.54,87.28 111.54,91.18 111.53,91.19 111.53,91.25 111.52,91.27 111.52,91.28
  BOTTOM w0.102: 111.52,91.28 111.52,92.41 111.41,92.51 111.11,92.51 v3(111.02,92.42) ; v3(44.88,90.59) 45.04,90.42 45.04,90.08 45.34,89.78 JDIMM2.13
DDR_M1_DQS2: length 75.7
  IN2 w0.076: v3(107.36,82.5) 107.44,82.58 107.44,82.76 107.29,82.91 107.15,82.91 107.07,82.83 103.54,82.83 102.98,83.39 102.13,83.39 100.9,84.63 100.9,85.15 100.01,86.04 98.49,86.04 97.91,86.62 91.65,86.62 90.48,85.45 89.69,85.45 89.65,85.41 89.64,85.41
  IN2 w0.127: v3(45.43,78.7) 45.05,79.09 45.05,79.37 45.18,79.5 46.6,79.5 46.73,79.37 46.73,79.1 47,78.83 47.59,78.83 47.87,79.1 47.87,79.37 48,79.5 48.38,79.5 48.5,79.37 48.5,79.2 48.78,78.93 49.37,78.93 49.65,79.2 49.65,79.37 49.77,79.5 53.11,79.5 53.91,80.3 56.53,80.3 56.78,80.05 63.15,80.05 63.24,79.97 66.05,79.97 71.48,85.41 89.64,85.41
  BOTTOM w0.076: UC1.H30 v3(107.36,82.5)
  BOTTOM w0.102: JDIMM2.55 48.43,79.28 48.14,79.56 46.41,79.56 45.19,79.23 45.06,79.1 45.06,79.01 45.37,78.7 v3(45.43,78.7)
DDR_M1_DQS3: length 76.9
  IN2 w0.076: v3(107.36,79.77) 107.36,80.05 107.29,80.13 105.55,80.13 105.13,80.54 102.59,80.54 101.88,79.82 99.21,79.82 96.31,76.93 92.46,76.93 90.49,78.9 90.49,78.9 89.77,80.64 89.77,81.24 89.52,81.5 89.01,81.5
  IN2 w0.127: 89.01,81.5 73.28,81.5 66.02,74.24 57.16,74.24 56.9,73.97 53.31,73.97 53.06,73.72 51.84,73.72 51.71,73.86 47.42,73.86 46.35,72.79 45,72.79 44.64,73.16 44.64,73.65 v3(44.48,73.81)
  BOTTOM w0.076: UC1.N30 v3(107.36,79.77)
  BOTTOM w0.102: JDIMM2.76 42.73,74.03 43.16,74.45 44.4,74.45 44.69,74.16 44.69,74.02 v3(44.48,73.81)
DDR_M1_DQS4: length 78.4
  IN2 w0.076: 89.01,62.21 89.03,62.24 90.87,62.24 91,62.36 91.39,62.36 93.29,64.27 100.51,64.27 101.01,64.77 101.46,64.77 102.09,65.4 102.35,65.4 102.39,65.43 102.42,65.43 105.26,68.28 106.91,68.28 107.08,68.45 107.08,68.64 107.31,68.87 v3(107.35,68.87)
  IN2 w0.127: v3(47.02,45.25) 46.79,45.48 46.79,45.61 46.92,45.74 47.78,45.74 48.09,45.43 48.09,45.02 48.4,44.71 51.83,44.71 52.19,44.35 53.34,44.35 54.3,45.31 54.56,45.31 55.23,45.98 56.03,45.98 56.2,46.15 65.04,46.15 65.31,46.42 65.31,46.94 65.45,47.08 65.95,47.08 66.07,46.96 66.07,46.42 66.35,46.15 66.92,46.15 67.19,46.42 67.19,47.47 67.32,47.59 69.28,47.59 83.9,62.21 89.01,62.21
  BOTTOM w0.089: UC1.AL30 107.35,68.86 v3(107.35,68.87)
  BOTTOM w0.102: JDIMM2.179 48.28,46.28 48.24,46.32 48.24,46.48 48.16,46.56 47.92,46.56 47.64,46.28 47.13,46.28 46.67,45.82 46.67,45.6 v3(47.02,45.25)
DDR_M1_DQS5: length 80.9
  IN2 w0.076: v3(107.37,65.23) 107.25,65.11 107.25,64.83 107.06,64.63 105.03,64.63 103.53,63.13 103.53,62.56 102.97,62 101.06,62 100.43,61.37 92.79,61.37 89.89,58.48 89.05,58.48 89.02,58.45 89.01,58.45
  IN2 w0.127: v3(44.48,39.72) 44.48,39.14 44.75,38.86 46.05,38.86 46.45,39.26 49.25,39.26 50.12,38.4 51.31,38.4 51.92,39.01 56.06,39.01 56.45,39.4 59.23,39.4 59.35,39.53 62.21,39.53 63.25,40.57 68.05,40.57 85.93,58.45 89.01,58.45
  BOTTOM w0.076: v3(107.37,65.23) 107.36,65.19 UC1.AU30
  BOTTOM w0.102: JDIMM2.200 41.76,41.03 41.87,41.13 42.29,41.13 42.85,40.57 44.25,40.57 44.68,40.13 44.68,39.92 v3(44.48,39.72)
DDR_M1_DQS6: length 80.8
  IN2 w0.076: v3(107.36,61.54) 107.05,61.86 106.66,61.86 106.42,62.1 105.78,62.1 103.38,59.69 101.35,59.69 99.62,57.96 97.55,57.96 97.42,57.82 91.86,57.82 88.99,54.95
  IN2 w0.127: 88.99,54.95 87.49,54.95 66.28,33.74 61.02,33.74 60.81,33.54 56.48,33.54 56.17,33.85 53.47,33.85 50.29,33.85 50.02,33.59 49.12,33.59 48.99,33.71 48.99,34.29 48.72,34.57 48.12,34.57 47.85,34.29 47.85,33.86 47.72,33.74 47.25,33.74 46.98,33.47 46.13,33.47 46,33.6 46,33.88 46.23,34.1 v3(46.28,34.1)
  BOTTOM w0.089: v3(107.36,61.54) UC1.BC30
  BOTTOM w0.102: JDIMM2.221 48.34,35.78 48.24,35.87 48.03,35.87 47.93,35.78 47.47,35.78 46.93,35.24 46.27,35.24 46.12,35.08 46.12,34.27 v3(46.28,34.1)
DDR_M1_DQS7: length 85.3
  IN2 w0.076: v3(107.33,57.95) 107.2,57.82 107.2,57.57 107.01,57.37 105.86,57.37 105.18,58.05 104.59,58.05 104.34,57.8 103.11,57.8 102.56,57.25 101.62,57.25 100.3,55.93 99.86,55.93 98.04,54.12 92.15,54.12 89.25,51.22 89.25,51.15 89.18,51.07 89.18,50.95 88.99,50.76
  IN2 w0.127: v3(44.39,28.84) 44.52,28.7 44.52,28.3 44.8,28.02 47.6,28.02 47.73,27.9 47.73,27.33 48.01,27.06 48.6,27.06 48.87,27.33 48.87,27.9 49,28.02 49.61,28.02 49.74,27.9 49.74,26.8 50.04,26.5 60.58,26.5 62.65,28.57 66.94,28.57 72.49,34.12 72.49,34.17 88.64,50.32 88.64,50.41 88.87,50.64 88.99,50.76
  BOTTOM w0.089: UC1.BH30 107.61,57.44 v3(107.33,57.95)
  BOTTOM w0.102: v3(44.39,28.84) 44.49,28.94 44.49,29.25 44.27,29.47 43.27,29.47 42.22,30.53 JDIMM2.242
DDR_M1_DQS#0: length 81.3
  IN2 w0.076: v3(110.99,81.99) 111.48,81.99 111.69,82.19 111.69,82.72 111.59,82.82 111.59,84.13 110.71,85.02 109.1,85.02 108.67,85.45 108.26,85.45 107.67,86.04 106.69,86.04 106.64,86.09
  IN2 w0.127: 106.64,86.09 105.73,86.09 104.42,87.4 104.42,88.03 104.38,88.07 104.38,88.08 103.15,89.3 103.14,89.3 103.11,89.34 94.11,89.34 93.44,90.01 69.8,90.01 64.7,84.91 63.74,84.91 63.04,85.61 61.32,85.61 60.85,86.07 53.44,86.07 53.24,85.86 48.68,85.86 48.33,85.5 44.36,85.5 44.06,85.2 44.06,84.67 v3(44.03,84.65)
  BOTTOM w0.076: UC1.H24 111.45,82.24
  BOTTOM w0.089: 111.45,82.24 v3(110.99,81.99)
  BOTTOM w0.102: JDIMM2.32 41.87,85.03 41.89,85.01 42.45,85.01 43.43,84.02 43.99,84.02 44.1,84.12 44.1,84.58 v3(44.03,84.65)
DDR_M1_DQS#1: length 87.5
  IN2 w0.076: 109.51,93.22 109.52,93.22 109.54,93.19 109.6,93.19 110.16,92.63 110.65,92.63 v3(111.03,93.01)
  IN2 w0.127: 109.51,93.22 109.46,93.22 108.67,94 100.99,94 100.92,93.92 95.46,93.92 95.17,94.22 67.36,94.22 67.07,93.92 65.94,93.92 65.61,93.59 65.61,93.2 65.89,92.92 65.89,92.74 65.71,92.56 65.53,92.56 65.25,92.84 64.86,92.84 64.53,92.51 64.53,92.12 64.81,91.84 64.81,91.66 64.5,91.35 63.67,91.35 63.38,91.64 60.84,91.64 60.16,92.32 56.08,92.32 55.81,92.04 55.81,91.77 55.68,91.64 55.3,91.64 55.17,91.77 55.17,92.04 54.9,92.32 54.3,92.32 54.03,92.04 54.03,91.77 53.9,91.64 53.52,91.64 53.39,91.77 53.39,92.04 53.12,92.32 48.71,92.32 46.29,89.9 45.34,89.9 45.19,90.04 45.19,90.27 v3(45.51,90.59)
  BOTTOM w0.076: 111.73,91.28 111.73,87.28 111.89,87.12 111.89,86.36 111.87,86.35 111.87,86.28 111.87,86.28 111.87,86.1 111.82,85.8 111.9,85.47 111.8,85.15 111.83,85.07 111.87,84.96 111.97,84.91 112.09,84.95 112.14,85.05 UC1.C23
  BOTTOM w0.102: v3(111.03,93.01) 111.31,92.73 111.5,92.73 111.73,92.5 111.73,91.28 ; JDIMM2.11 48.22,90.28 48.13,90.18 48.13,90.09 48.02,89.99 45.43,89.99 45.26,90.16 45.26,90.33 v3(45.51,90.59)
DDR_M1_DQS#2: length 75.7
  IN2 w0.076: 89.64,85.66 89.66,85.66 89.7,85.62 90.41,85.62 91.59,86.79 98.03,86.79 98.57,86.25 100.09,86.25 101.1,85.24 101.1,84.72 102.22,83.6 103.06,83.6 103.63,83.04 106.98,83.04 v3(107.36,83.42)
  IN2 w0.127: 89.64,85.66 71.38,85.66 65.94,80.22 63.34,80.22 63.26,80.3 56.89,80.3 56.64,80.55 53.81,80.55 53,79.75 49.67,79.75 49.39,79.47 49.39,79.31 49.27,79.18 48.89,79.18 48.76,79.31 48.76,79.47 48.48,79.75 47.89,79.75 47.62,79.47 47.62,79.21 47.49,79.08 47.11,79.08 46.98,79.21 46.98,79.47 46.7,79.75 45.07,79.75 44.79,79.47 v3(44.79,78.7)
  BOTTOM w0.076: UC1.G30 v3(107.36,83.42)
  BOTTOM w0.102: JDIMM2.53 46.38,79.78 45.08,79.42 44.85,79.19 44.85,78.76 v3(44.79,78.7)
DDR_M1_DQS#3: length 77
  IN2 w0.076: v3(107.36,80.68) 107.36,80.45 107.25,80.33 105.63,80.33 105.22,80.74 102.51,80.74 101.79,80.03 99.12,80.03 96.23,77.13 92.55,77.13 90.66,79.02 89.93,80.77 89.93,81.31 89.56,81.69 89.08,81.69 89.02,81.75 89.01,81.75
  IN2 w0.127: v3(45.12,73.81) 44.89,73.58 44.89,73.26 45.11,73.05 46.25,73.05 47.32,74.11 51.81,74.11 51.95,73.97 52.95,73.97 53.21,74.23 56.79,74.23 57.06,74.49 65.92,74.49 73.17,81.75 89.01,81.75
  BOTTOM w0.076: UC1.L30 107.44,80.54 v3(107.36,80.68)
  BOTTOM w0.102: v3(45.12,73.81) 44.91,74.02 44.91,74.25 44.49,74.67 43.07,74.67 42.64,74.24 42.24,74.24 41.95,74.53 JDIMM2.74
DDR_M1_DQS#4: length 78.5
  IN2 w0.076: v3(106.71,68.87) 106.92,68.66 106.92,68.52 106.84,68.44 105.2,68.44 102.35,65.6 102,65.6 101.37,64.97 100.92,64.97 100.43,64.48 93.21,64.48 91.3,62.57 90.91,62.57 90.79,62.44 89.04,62.44 89.02,62.47 89.01,62.47
  IN2 w0.127: v3(46.38,45.25) 46.54,45.41 46.54,45.72 46.81,45.99 47.88,45.99 48.34,45.53 48.34,45.12 48.5,44.96 51.93,44.96 52.3,44.6 53.24,44.6 54.19,45.56 54.45,45.56 55.13,46.23 55.93,46.23 56.09,46.4 64.93,46.4 65.06,46.53 65.06,47.05 65.35,47.34 66.05,47.34 66.33,47.06 66.33,46.53 66.45,46.4 66.81,46.4 66.94,46.53 66.94,47.57 67.21,47.85 69.17,47.85 83.79,62.47 89.01,62.47
  BOTTOM w0.076: UC1.AL31 v3(106.71,68.87)
  BOTTOM w0.102: JDIMM2.177 47.83,46.78 47.55,46.49 47.04,46.49 46.45,45.91 46.45,45.32 v3(46.38,45.25)
DDR_M1_DQS#5: length 80.9
  IN2 w0.076: 89.01,58.71 89.02,58.71 89.05,58.68 89.81,58.68 92.7,61.58 100.35,61.58 100.98,62.21 102.89,62.21 103.32,62.64 103.32,63.21 104.95,64.83 106.98,64.83 107.05,64.91 107.05,65.07 106.89,65.23 v3(106.74,65.23)
  IN2 w0.127: 89.01,58.71 85.82,58.71 67.94,40.83 63.15,40.83 62.1,39.78 59.25,39.78 59.12,39.65 56.35,39.65 55.96,39.26 51.81,39.26 51.2,38.65 50.22,38.65 49.36,39.52 46.34,39.52 45.94,39.12 44.86,39.12 44.73,39.24 44.73,39.36 45.09,39.72 v3(45.11,39.72)
  BOTTOM w0.076: v3(106.74,65.23) 106.72,65.2 UC1.AU31
  BOTTOM w0.102: JDIMM2.198 41.81,41.53 41.99,41.35 42.38,41.35 42.94,40.78 44.34,40.78 44.9,40.22 44.9,39.94 v3(45.11,39.72)
DDR_M1_DQS#6: length 80.8
  IN2 w0.076: 88.99,54.7 89,54.7 89.03,54.72 89.04,54.72 91.94,57.62 97.5,57.62 97.64,57.75 99.71,57.75 101.44,59.49 103.46,59.49 105.87,61.89 106.34,61.89 106.72,61.52 v3(106.72,61.5)
  IN2 w0.127: v3(45.65,34.1) 45.75,34 45.75,33.49 46.03,33.22 47.09,33.22 47.35,33.48 47.83,33.48 48.1,33.76 48.1,34.18 48.23,34.31 48.61,34.31 48.74,34.18 48.74,33.61 49.01,33.33 50.13,33.33 50.39,33.6 56.06,33.6 56.38,33.28 60.92,33.28 61.12,33.48 66.38,33.48 87.6,54.7 88.99,54.7
  BOTTOM w0.089: v3(106.72,61.5) 106.76,61.49 UC1.BC31
  BOTTOM w0.102: JDIMM2.219 48.45,36.28 48.26,36.09 47.94,36.09 47.84,35.99 47.38,35.99 46.84,35.45 46.18,35.45 45.9,35.17 45.9,34.35 v3(45.65,34.1)
DDR_M1_DQS#7: length 85.2
  IN2 w0.076: 88.99,51.12 89.09,51.22 89.09,51.34 92.06,54.32 97.96,54.32 99.77,56.13 100.22,56.13 101.53,57.45 102.48,57.45 103.02,58 104.25,58 104.51,58.25 105.27,58.25 105.94,57.57 106.92,57.57 107,57.65 107,57.83 106.88,57.95 v3(106.7,57.95)
  IN2 w0.127: v3(45.02,28.84) 44.78,28.59 44.78,28.4 44.91,28.28 47.71,28.28 47.98,28 47.98,27.44 48.11,27.31 48.49,27.31 48.62,27.44 48.62,28 48.89,28.28 49.72,28.28 50,28 50,26.91 50.15,26.75 60.47,26.75 62.54,28.82 66.83,28.82 72.23,34.23 72.23,34.27 88.39,50.43 88.39,50.52 88.99,51.12
  BOTTOM w0.089: v3(106.7,57.95) 106.74,57.87 106.75,57.86 UC1.BH31
  BOTTOM w0.102: v3(45.02,28.84) 44.7,29.15 44.7,29.34 44.36,29.69 43.36,29.69 42.31,30.74 42.08,30.74 41.79,31.03 JDIMM2.240
DDR_M1_MA0: length 75.4
  IN2 w0.076: 89.01,71.79 89.95,71.79 90.17,71.56 93.41,71.56 v3(93.7,71.27)
  IN2 w0.157: v3(43,56.47) 43,56.1 42.85,55.94 42.31,55.94 42.15,56.11 42.15,59.2 42.31,59.35 45.37,59.35 46.01,58.72 50.23,58.72 50.5,58.99 51.54,58.99 51.78,59.23 53.61,59.23 54.41,60.03 57.08,60.03 57.99,60.93 62.04,60.93 62.48,61.37 67.57,61.37 74.94,68.74 75.89,68.74 78.94,71.79 89.01,71.79
  BOTTOM w0.076: UC1.AG36 103.72,70.72 103.49,70.49 103.46,70.48 103.45,70.47 103.44,70.47 103.17,70.47 103.02,70.62 103.02,70.65 102.97,70.65 102.97,70.65 102.5,70.65 102.38,70.53 101.55,70.53 101.49,70.59 100.68,70.59
  BOTTOM w0.089: v3(93.7,71.27) 94.81,70.16 100.25,70.16 100.68,70.59
  BOTTOM w0.102: JDIMM2.144 41.89,57.03
  BOTTOM w0.127: v3(43,56.47) 42.45,57.03 41.89,57.03
DDR_M1_MA1: length 76.4
  IN2 w0.076: 89.01,72.61 90.71,72.61 91.43,71.89 96.53,71.89 96.63,71.8 96.63,71.68 v3(96.24,71.29)
  IN2 w0.157: 89.01,72.61 78.42,72.61 75.37,69.56 74.6,69.56 69.69,64.66 68.72,64.66 68.56,64.51 68.56,63.58 68.41,63.42 68.09,63.42 67.93,63.58 67.93,64.53 67.78,64.69 67.49,64.69 67.34,64.53 67.34,62.35 67.18,62.19 66.86,62.19 66.71,62.35 66.71,64.59 66.55,64.75 66.29,64.75 66.14,64.59 66.14,64.18 65.98,64.02 65.51,64.02 64.9,63.42 63.11,63.42 61.93,62.24 55.45,62.24 54.95,61.74 54.95,61.51 55.23,61.23 55.23,61.01 55.08,60.85 54.85,60.85 54.42,61.28 54.2,61.28 53.34,60.42 52.94,60.42 52.79,60.26 52.79,60.21 52.63,60.05 52.37,60.05 52.21,60.21 52.21,60.36 52.05,60.52 51.78,60.52 51.33,60.07 50.17,60.07 50.01,59.92 50.01,59.73 49.85,59.57 49.54,59.57 49.38,59.73 49.38,59.92 49.22,60.07 49.03,60.07 48.87,59.92 48.87,59.7 48.71,59.54 48.49,59.54 48.33,59.7 48.33,59.92 48.17,60.07 47.87,60.07 47.72,59.92 v3(47.72,59.79)
  BOTTOM w0.076: UC1.AG35 104.52,70.82 104.06,70.98 104.06,70.98 103.87,70.98 103.86,70.98 103.86,70.97 103.77,70.94 103.76,70.94 103.72,70.93 103.69,70.94 103.52,70.94 103.52,70.94 103.36,71 102.35,71 102.21,70.86 101.69,70.86 101.5,71.05 100.66,71.05 100.15,70.54 99.47,70.54
  BOTTOM w0.089: v3(96.24,71.29) 96.24,70.63 96.33,70.54 99.47,70.54
  BOTTOM w0.102: JDIMM2.133 48.36,59.78
  BOTTOM w0.127: 48.36,59.78 47.73,59.78 v3(47.72,59.79)
DDR_M1_MA2: length 76.8
  IN2 w0.076: 89.01,73.02 90.53,73.02 91.5,72.06 97.72,72.06 97.79,71.98 97.79,71.58 v3(97.51,71.29)
  IN2 w0.157: v3(45.18,59.79) 44.74,60.22 43.45,60.22 43.29,60.38 43.29,60.82 43.45,60.97 44.86,60.97 45.35,60.48 51.16,60.48 51.76,61.08 52.25,61.08 52.46,61.29 53.62,61.29 54.99,62.65 61.76,62.65 62.94,63.83 64.73,63.83 66.07,65.16 69.61,65.16 74.43,69.98 75.19,69.98 78.24,73.02 89.01,73.02
  BOTTOM w0.076: v3(97.51,71.29) 97.51,71.27 98.07,70.71 99.92,70.71 100.41,71.21 100.41,71.21 101.57,71.21 101.76,71.03 102.14,71.03 102.3,71.18 103.35,71.18 103.55,71.11 103.73,71.11 103.81,71.14 103.84,71.15 104.08,71.15 104.19,71.11 104.68,71.11 UC1.AF34
  BOTTOM w0.102: JDIMM2.132 41.89,60.03
  BOTTOM w0.127: 41.89,60.03 42.41,60.03 43.22,59.21 44.81,59.21 44.94,59.34 44.94,59.55 v3(45.18,59.79)
DDR_M1_MA3: length 77.5
  IN2 w0.076: 89.01,72.2 90.89,72.2 91.36,71.73 94.51,71.73 v3(94.97,71.27)
  IN2 w0.157: 89.01,72.2 78.59,72.2 75.55,69.15 74.77,69.15 69.86,64.25 69.13,64.25 68.98,64.09 68.98,63.41 67.35,61.78 66.45,61.78 66.29,61.94 66.29,63.45 66.13,63.61 65.82,63.61 65.66,63.45 65.66,61.94 65.5,61.78 65.22,61.78 65.02,61.98 65.02,62.65 64.91,62.76 64.6,62.76 64.44,62.6 64.44,61.94 64.28,61.78 63.72,61.78 63.56,61.94 63.56,62.75 63.4,62.91 63.18,62.91 63.02,62.75 63.02,62.03 62.77,61.78 62.31,61.78 61.87,61.34 57.27,61.34 57.12,61.19 57.12,60.65 56.91,60.44 56.57,60.44 56.41,60.6 56.41,61.67 56.25,61.83 55.8,61.83 55.64,61.67 55.64,60.6 55.49,60.44 54.24,60.44 53.44,59.64 51.61,59.64 51.37,59.4 50.33,59.4 50.06,59.13 46.6,59.13 46.45,59.29 v3(46.45,59.79)
  BOTTOM w0.076: UC1.AG37 103.22,70.82 103.03,70.82 103.03,70.82 102.4,70.82 102.28,70.7 101.62,70.7 101.55,70.76 100.6,70.76 100.18,70.33
  BOTTOM w0.089: 100.18,70.33 95.91,70.33 v3(94.97,71.27)
  BOTTOM w0.102: JDIMM2.131 48.36,60.28
  BOTTOM w0.127: v3(46.45,59.79) 46.45,60.56 46.57,60.69 47.68,60.69 48.09,60.28 48.36,60.28
DDR_M1_MA4: length 76.4
  IN2 w0.076: 89.01,73.44 90.35,73.44 91.56,72.23 93.71,72.23 94.08,72.6 v3(94.15,72.6)
  IN2 w0.157: v3(43.91,61.82) 42.05,61.82 41.89,61.66 41.89,60.88 42.05,60.73 42.62,60.73 42.78,60.88 42.78,61.23 42.94,61.39 45.03,61.39 45.52,60.9 50.99,60.9 51.59,61.49 52.08,61.49 52.29,61.7 53.45,61.7 54.82,63.06 61.59,63.06 62.77,64.24 63.65,64.24 64.24,64.83 65.15,64.83 65.9,65.57 69.44,65.57 74.25,70.39 75.02,70.39 78.07,73.44 89.01,73.44
  BOTTOM w0.076: UC1.AE35 104.33,71.74 103.91,71.74 103.9,71.75 103.78,71.79 103.49,71.79 103.46,71.78 103.3,71.72 102.39,71.72 102.21,71.9 102.19,71.93 101.64,71.93 101.25,71.54 100.16,71.54 99.58,72.12 96.33,72.12 96.08,71.88 95,71.88 94.78,72.09
  BOTTOM w0.102: JDIMM2.128 41.89,61.03
  BOTTOM w0.127: 41.89,61.03 43.11,61.03 v3(43.91,61.82) ; 94.78,72.09 94.66,72.09 v3(94.15,72.6)
DDR_M1_MA5: length 76.8
  IN2 w0.076: 89.01,73.85 90.18,73.85 91.23,72.79 92.77,72.79 v3(92.97,72.58)
  IN2 w0.157: v3(45.18,61.82) 45.69,61.31 48.2,61.31 48.36,61.46 48.36,61.82 48.51,61.98 48.82,61.98 48.97,61.82 48.97,61.46 49.13,61.31 49.37,61.31 49.5,61.43 49.5,61.82 49.66,61.98 49.99,61.98 50.15,61.82 50.15,61.49 50.33,61.31 50.82,61.31 51.42,61.9 51.91,61.9 52.11,62.11 53.28,62.11 55.23,64.05 58.23,64.05 58.39,64.21 58.39,64.39 58.55,64.55 58.86,64.55 59.02,64.39 59.02,64.12 59.18,63.96 59.4,63.96 59.56,64.12 59.56,64.34 59.71,64.5 60.03,64.5 60.19,64.34 60.19,64.15 60.34,64 60.63,64 60.79,64.15 60.79,64.42 60.94,64.58 61.17,64.58 61.62,64.13 62.07,64.13 62.48,64.53 62.48,65.49 62.63,65.65 62.86,65.65 63.01,65.49 63.01,64.81 63.17,64.65 63.48,64.65 63.66,64.83 63.66,65.18 63.78,65.3 65.03,65.3 65.72,65.99 69.27,65.99 74.08,70.8 74.85,70.8 77.9,73.85 89.01,73.85
  BOTTOM w0.076: UC1.AF35 104.26,71.41 103.85,71.56 103.84,71.57 103.84,71.57 103.81,71.61 103.76,71.62 103.52,71.62 103.47,71.61 103.43,71.56 103.36,71.56 103.29,71.54 103.29,71.55 102.33,71.55 102.14,71.74 102.08,71.74 102.08,71.74 101.78,71.74 101.78,71.74 101.68,71.74 101.32,71.38 100.09,71.38 99.51,71.95 96.39,71.95 96.15,71.71 94.78,71.71
  BOTTOM w0.102: JDIMM2.126 41.89,61.53
  BOTTOM w0.127: v3(92.97,72.58) 93.85,71.71 94.78,71.71 ; v3(45.18,61.82) 44.54,62.45 43.95,62.45 43.02,61.53 41.89,61.53
DDR_M1_MA6: length 75.7
  IN2 w0.076: 89.01,74.67 89.87,74.67 91.42,73.12 95.13,73.12 95.16,73.09 96.13,73.09 96.23,72.98 96.23,72.85 95.97,72.58 v3(95.94,72.58)
  IN2 w0.157: v3(46.45,61.82) 46.01,62.25 43.98,62.25 43.82,62.41 43.82,62.64 43.98,62.8 46.52,62.8 46.59,62.73 46.59,62.46 46.74,62.31 46.96,62.31 47.13,62.48 47.13,62.73 47.2,62.8 51.61,62.8 51.77,62.96 51.77,63.29 51.93,63.45 52.15,63.45 52.31,63.29 52.31,63.09 52.46,62.93 52.94,62.93 53.36,63.35 53.36,63.54 54.84,65.02 57.78,65.02 58.13,65.38 60.46,65.38 61.56,66.47 64.45,66.47 64.79,66.81 68.93,66.81 74.35,72.23 74.35,72.45 74.2,72.61 74.2,72.83 74.42,73.05 74.65,73.05 74.8,72.9 75.02,72.9 75.24,73.12 75.24,73.35 75.09,73.5 75.09,73.72 75.31,73.94 75.54,73.94 75.69,73.79 75.91,73.79 76.79,74.67 89.01,74.67
  BOTTOM w0.076: UC1.AE37 103.18,71.89 102.83,71.89 102.77,71.94 102.45,71.94 102.33,72.07 102.28,72.07 102.26,72.09 101.52,72.09 101.13,71.71 100.22,71.71 99.65,72.28 96.24,72.28 v3(95.94,72.58)
  BOTTOM w0.102: JDIMM2.127 48.36,61.28
  BOTTOM w0.127: 48.36,61.28 46.99,61.28 v3(46.45,61.82)
DDR_M1_MA7: length 75.2
  IN2 w0.076: v3(107.95,73.3) 107.66,73.01 96.5,73.01 96.25,73.25 95.29,73.25 95.26,73.28 93.52,73.28 92.98,73.82 90.95,73.82 89.69,75.08 89.01,75.08
  IN2 w0.157: v3(43.91,63.72) 44.42,63.21 50.93,63.21 51.08,63.37 51.08,63.69 51.26,63.86 53.1,63.86 54.67,65.43 57.61,65.43 57.96,65.79 60.29,65.79 61.39,66.88 64.28,66.88 64.62,67.22 68.76,67.22 73.65,72.12 73.65,72.87 75.34,74.55 76.09,74.55 76.62,75.08 89.01,75.08
  BOTTOM w0.076: v3(107.95,73.3) 107.97,73.27 108.08,73.24 UC1.AC29
  BOTTOM w0.102: JDIMM2.122 41.89,62.53
  BOTTOM w0.127: 41.89,62.53 43.48,62.53 43.91,62.95 v3(43.91,63.72)
DDR_M1_MA8: length 74.6
  IN2 w0.076: v3(97.11,72.65) 99.35,72.65 99.42,72.57 99.42,72.11 99.35,72.03 98.66,72.03 98.47,72.23 95.79,72.23 95.06,72.95 91.35,72.95 90.05,74.26 89.09,74.26
  IN2 w0.157: v3(47.72,61.82) 47.48,62.05 47.48,62.25 47.62,62.39 51.81,62.39 51.94,62.52 53.11,62.52 53.77,63.18 53.77,63.37 54.87,64.46 57.81,64.46 58.3,64.96 60.63,64.96 61.16,65.49 61.38,65.49 61.54,65.33 61.54,64.8 61.67,64.68 61.91,64.68 62.06,64.83 62.06,65.9 62.22,66.06 63.03,66.06 63.33,65.75 63.56,65.75 63.86,66.06 64.25,66.06 64.55,65.75 64.9,65.75 65.55,66.4 69.1,66.4 74.07,71.37 74.3,71.37 74.46,71.21 74.68,71.21 74.9,71.43 74.9,71.66 74.74,71.82 74.74,72.04 74.97,72.26 75.19,72.26 75.35,72.1 75.57,72.1 75.79,72.32 75.79,72.55 75.63,72.71 75.63,72.93 75.86,73.15 76.08,73.15 76.24,72.99 76.46,72.99 76.68,73.22 76.68,73.44 76.52,73.6 76.52,73.82 76.96,74.26 89.09,74.26
  BOTTOM w0.076: UC1.AE36 103.87,72.02 103.69,72.12 103.65,72.17 103.43,72.29 103.41,72.29 103.17,72.29 103.02,72.14 102.99,72.14 102.95,72.11 102.52,72.11 102.38,72.26 101.45,72.26 101.06,71.87 100.29,71.87 99.52,72.65 v3(97.11,72.65)
  BOTTOM w0.102: JDIMM2.125 48.36,61.78
  BOTTOM w0.127: 48.36,61.78 47.76,61.78 v3(47.72,61.82)
DDR_M1_MA9: length 73.2
  IN2 w0.076: v3(108.02,74.26) 107.81,74.48 107.42,74.64 106.04,74.64 105.62,74.46 98.73,74.46 97.57,74.95 91.11,74.95 89.74,76.32 89.01,76.32
  IN2 w0.157: 89.01,76.32 76.2,76.32 74.69,75.69 67.45,68.46 64.25,68.46 61.2,68.16 60.93,68.1 60.31,67.85 60.29,67.83 59.81,67.63 55.84,67.63 54.61,67.12 52.59,65.09 50.09,65.09 48.93,64.61 46.07,64.61 v3(45.18,63.72)
  BOTTOM w0.076: v3(108.02,74.26) UC1.AB29
  BOTTOM w0.102: JDIMM2.121 48.36,62.78
  BOTTOM w0.127: v3(45.18,63.72) 46.12,62.78 48.36,62.78
DDR_M1_MA10: length 76.8
  IN2 w0.076: v3(98.91,69.78) 98.86,69.78 98.01,68.93 93.44,68.93 92.21,67.7 89.01,67.7
  IN2 w0.157: v3(43.37,55) 41.87,53.5 41.87,53.27 42.79,52.34 43.06,52.34 43.49,52.77 43.49,52.79 43.97,53.28 54.01,53.28 54.02,53.29 54.33,53.29 55.49,54.44 59,54.44 59.32,54.76 59.73,54.76 59.81,54.84 61.97,54.84 62.51,55.39 68.32,55.39 80.63,67.7 89.01,67.7
  BOTTOM w0.076: v3(98.91,69.78) 99.38,69.32 99.86,69.32 100.88,70.35 102.13,70.35 102.13,70.34 102.47,70.34 102.59,70.47 102.61,70.47 102.63,70.49 102.8,70.49 102.82,70.47 102.89,70.47 103.06,70.29 103.45,70.29 103.46,70.29 103.48,70.3 103.53,70.31 103.56,70.34 103.59,70.36 103.6,70.37 103.6,70.37 103.72,70.43 104.66,70.43 UC1.AG34
  BOTTOM w0.102: JDIMM2.146 41.89,54.53
  BOTTOM w0.127: 41.89,54.53 42.89,54.53 v3(43.37,55)
DDR_M1_MA11: length 77.5
  IN2 w0.076: 89.01,76.73 89.56,76.73 91.18,75.11 97.6,75.11 99.93,74.63 102.71,74.63 105.02,75.59 107.89,75.59 108.12,75.49 108.35,75.26 108.35,75.24 108.44,75.03 108.54,74.93 108.78,74.83 109.61,74.83 109.79,74.65 109.79,73.92 109.62,73.75 109.2,73.75 108.95,73.64 v3(108.65,73.34)
  IN2 w0.157: 89.01,76.73 76.11,76.73 74.4,76.02 67.25,68.87 64.23,68.87 61.14,68.56 60.81,68.5 60.08,68.19 60.06,68.18 59.73,68.04 55.76,68.04 54.38,67.47 52.42,65.51 50.01,65.51 48.85,65.03 46.03,65.03 45.97,65.02 43.84,64.41 43,64.08 v3(42.64,63.72)
  BOTTOM w0.076: v3(108.65,73.34) 108.67,73.33 UC1.AC28
  BOTTOM w0.102: 41.89,63.12 41.77,63.03 JDIMM2.120
  BOTTOM w0.127: 41.89,63.12 v3(42.64,63.72)
DDR_M1_MA12: length 76.5
  IN2 w0.076: 89.01,75.9 89.79,75.9 91.06,74.63 94.98,74.63 95.38,74.23 99.79,74.23 99.8,74.24 102.27,74.24 102.62,73.9 103.45,73.9 103.74,74.19 105.23,74.19 105.52,73.9 108.59,73.9 108.66,73.97 v3(108.66,74.26)
  IN2 w0.157: v3(46.45,63.72) 46.41,63.72 46.27,63.86 46.27,64.08 46.4,64.2 49.89,64.2 50.37,64.68 52.76,64.68 54.64,66.57 55.28,66.57 55.92,67.22 60.56,67.22 61.05,67.7 63.94,67.7 64.28,68.04 67.62,68.04 68.3,68.72 68.56,68.72 68.72,68.56 68.88,68.56 69.09,68.77 69.09,68.99 68.94,69.14 68.94,69.36 69.16,69.58 69.39,69.58 69.54,69.43 69.76,69.43 69.97,69.64 69.97,69.86 69.82,70.01 69.82,70.24 70.04,70.46 70.26,70.46 70.41,70.31 70.64,70.31 70.86,70.53 70.86,70.75 70.71,70.91 70.71,71.13 70.93,71.35 71.15,71.35 71.3,71.2 71.53,71.2 71.76,71.44 71.76,71.66 71.63,71.79 71.63,72.01 71.86,72.24 72.08,72.24 72.21,72.1 72.43,72.1 72.63,72.31 72.63,72.53 72.51,72.66 72.51,72.88 75,75.37 75.75,75.37 76.28,75.9 89.01,75.9
  BOTTOM w0.076: v3(108.66,74.26) 108.66,74.25 UC1.AB28
  BOTTOM w0.102: 47.73,63.16 48.11,63.16 48.23,63.28 JDIMM2.119
  BOTTOM w0.127: 47.73,63.16 46.42,63.16 46.29,63.28 46.29,63.57 v3(46.45,63.72)
DDR_M1_MA13: length 76.2
  IN2 w0.076: v3(101.49,68.56) 101.29,68.77 96.53,68.77 94.47,66.7 92.24,66.7 92.01,66.47 89.01,66.47
  IN2 w0.157: 89.01,66.47 81.15,66.47 68.83,54.15 63.02,54.15 62.48,53.61 61.7,53.61 61.54,53.45 61.54,53.17 61.39,53.01 61.07,53.01 60.91,53.17 60.91,53.45 60.76,53.61 60.39,53.61 60.29,53.5 60.29,53.08 60.13,52.92 59.62,52.92 59.25,52.55 55.88,52.55 54.11,50.78 53.47,50.78 53.16,51.09 51.22,51.09 51.19,51.06 50.94,51.06 50.68,50.81 50.32,50.81 49.92,51.21 43.45,51.21 42.77,51.89 42.03,51.89 41.87,51.73 41.87,50.92 42.03,50.76 v3(42.9,50.76)
  BOTTOM w0.076: v3(101.49,68.56) 101.51,68.56 101.59,68.48 102.13,68.48 102.32,68.67 103.33,68.67 103.55,68.59 103.73,68.59 104.19,68.76 UC1.AK35
  BOTTOM w0.102: JDIMM2.158 41.89,51.53
  BOTTOM w0.127: v3(42.9,50.76) 42.14,51.53 41.89,51.53
DDR_M1_MA14_WE#: length 77.1
  IN2 w0.076: v3(94.33,67.66) 94.39,67.66 94.72,67.99 94.72,68.09 94.85,68.22 95.23,68.22 95.36,68.35 95.36,68.65 95.28,68.73 93.47,68.73 92.03,67.29 89.01,67.29
  IN2 w0.157: 89.01,67.29 80.8,67.29 68.49,54.98 62.68,54.98 62.14,54.43 59.97,54.43 59.89,54.35 59.49,54.35 59.17,54.03 56.2,54.03 56.08,53.92 55.86,53.92 55.81,53.96 55.59,53.96 55.37,53.74 55.37,53.52 55.42,53.47 55.42,53.25 55.28,53.11 55.06,53.11 55.01,53.16 54.78,53.16 54.56,52.94 54.56,52.71 54.61,52.67 54.61,52.44 54.35,52.18 54.12,52.18 53.96,52.34 53.96,52.71 53.8,52.87 53.53,52.87 53.37,52.71 53.37,52.12 53.17,51.91 52.66,51.91 52.5,52.07 52.5,52.71 52.34,52.87 52.03,52.87 51.87,52.71 51.87,52.04 51.75,51.91 51.02,51.91 50.85,52.09 50.47,52.09 50.31,52.24 50.31,52.71 50.15,52.87 49.84,52.87 49.68,52.71 49.68,52.24 49.52,52.09 49.06,52.09 48.91,52.24 48.91,52.71 48.75,52.87 48.43,52.87 48.28,52.71 48.28,52.19 48.12,52.03 47.37,52.03 47.21,52.19 v3(47.21,52.61)
  BOTTOM w0.076: UC1.AJ35 104.58,69.5 104.4,69.37 104.06,69.24 103.87,69.24 103.67,69.31 103.53,69.31 103.48,69.27 103.43,69.25 103.37,69.25 103.31,69.25 103.28,69.24 102.48,69.24 102.48,69.24 102.38,69.24 102.06,69.56 101.07,69.56 100.02,68.52 95.05,68.52
  BOTTOM w0.089: v3(94.33,67.66) 94.33,67.79 95.05,68.52
  BOTTOM w0.102: 48.17,53.12 48.33,53.28 JDIMM2.151
  BOTTOM w0.127: 48.17,53.12 48.07,53.02 47.44,53.02 47.21,52.79 v3(47.21,52.61)
DDR_M1_MA15_CAS#: length 76.9
  IN2 w0.076: v3(94.92,67.65) 94.83,67.65 94.48,67.31 92.62,67.31 92.19,66.88 89.01,66.88
  IN2 w0.157: v3(44.74,52.8) 44.31,52.37 43.66,52.37 43.46,52.17 43.46,51.78 43.62,51.62 44.38,51.62 44.53,51.78 44.53,52.04 44.69,52.19 45.01,52.19 45.16,52.04 45.16,51.78 45.32,51.62 45.61,51.62 45.76,51.78 45.76,52.02 45.92,52.18 46.24,52.18 46.39,52.02 46.39,51.78 46.55,51.62 49.96,51.62 50.01,51.67 50.68,51.67 50.85,51.5 54.25,51.5 55.71,52.96 58.68,52.96 59.66,53.94 60.11,53.94 60.19,54.02 62.31,54.02 62.85,54.56 68.66,54.56 80.98,66.88 89.01,66.88
  BOTTOM w0.076: UC1.AK34 104.68,69.12 104.21,69.12 104.2,69.12 104.05,69.06 104.02,69.08 103.84,69.08 103.64,69.15 103.6,69.15 103.57,69.13 103.46,69.09 103.34,69.08 103.31,69.08 102.31,69.08 101.98,69.4 101.14,69.4 100.09,68.35 96.73,68.35 96.48,68.1 95.52,68.1 95.08,67.65 v3(94.92,67.65)
  BOTTOM w0.102: JDIMM2.156 41.89,52.03
  BOTTOM w0.127: 41.89,52.03 44.1,52.03 44.74,52.67 v3(44.74,52.8)
DDR_M1_MA16_RAS#: length 75.6
  IN2 w0.076: v3(98.33,69.78) 98.33,69.63 97.79,69.1 93.08,69.1 92.1,68.11 89.01,68.11
  IN2 w0.157: v3(43.03,52.93) 42.57,53.39 42.57,53.61 42.72,53.77 42.96,53.77 43.31,53.42 43.53,53.42 43.75,53.64 43.75,53.87 43.4,54.22 43.4,54.45 43.52,54.57 43.99,54.57 44.85,53.7 54.16,53.7 56.09,55.63 62.17,55.63 62.34,55.8 68.15,55.8 80.46,68.11 89.01,68.11
  BOTTOM w0.076: UC1.AJ34 104.59,69.83 104.5,69.83 104.5,69.83 104.27,69.83 104.27,69.83 103.65,69.83 103.51,69.91 103.5,69.91 103.4,69.93 103.09,69.93 102.9,69.74 102.58,69.74 102.25,70.07 100.88,70.07 99.96,69.15 98.98,69.15 98.35,69.78 v3(98.33,69.78)
  BOTTOM w0.102: JDIMM2.152 41.89,53.03
  BOTTOM w0.127: 41.89,53.03 42.33,53.03 42.56,53.25 42.74,53.25 43.03,52.96 v3(43.03,52.93)
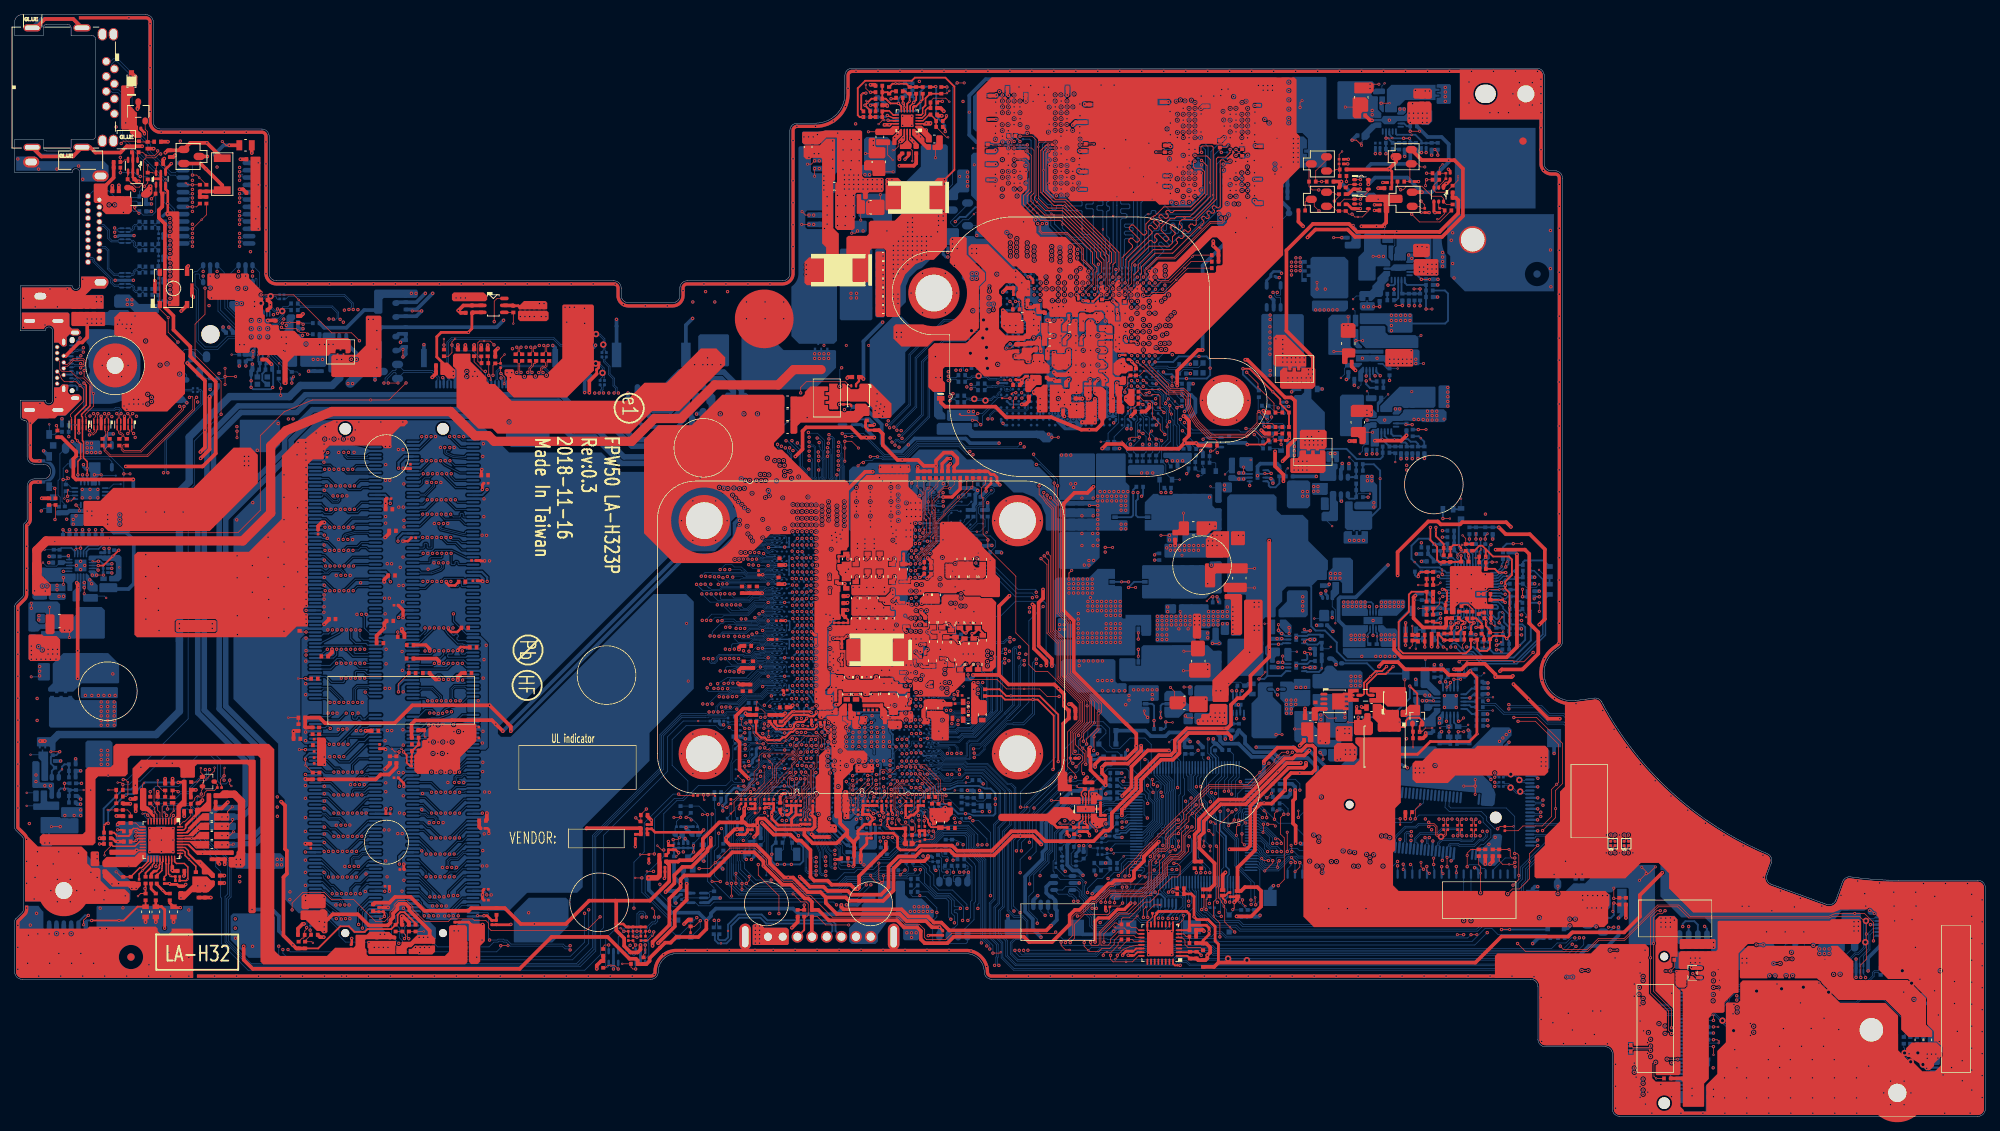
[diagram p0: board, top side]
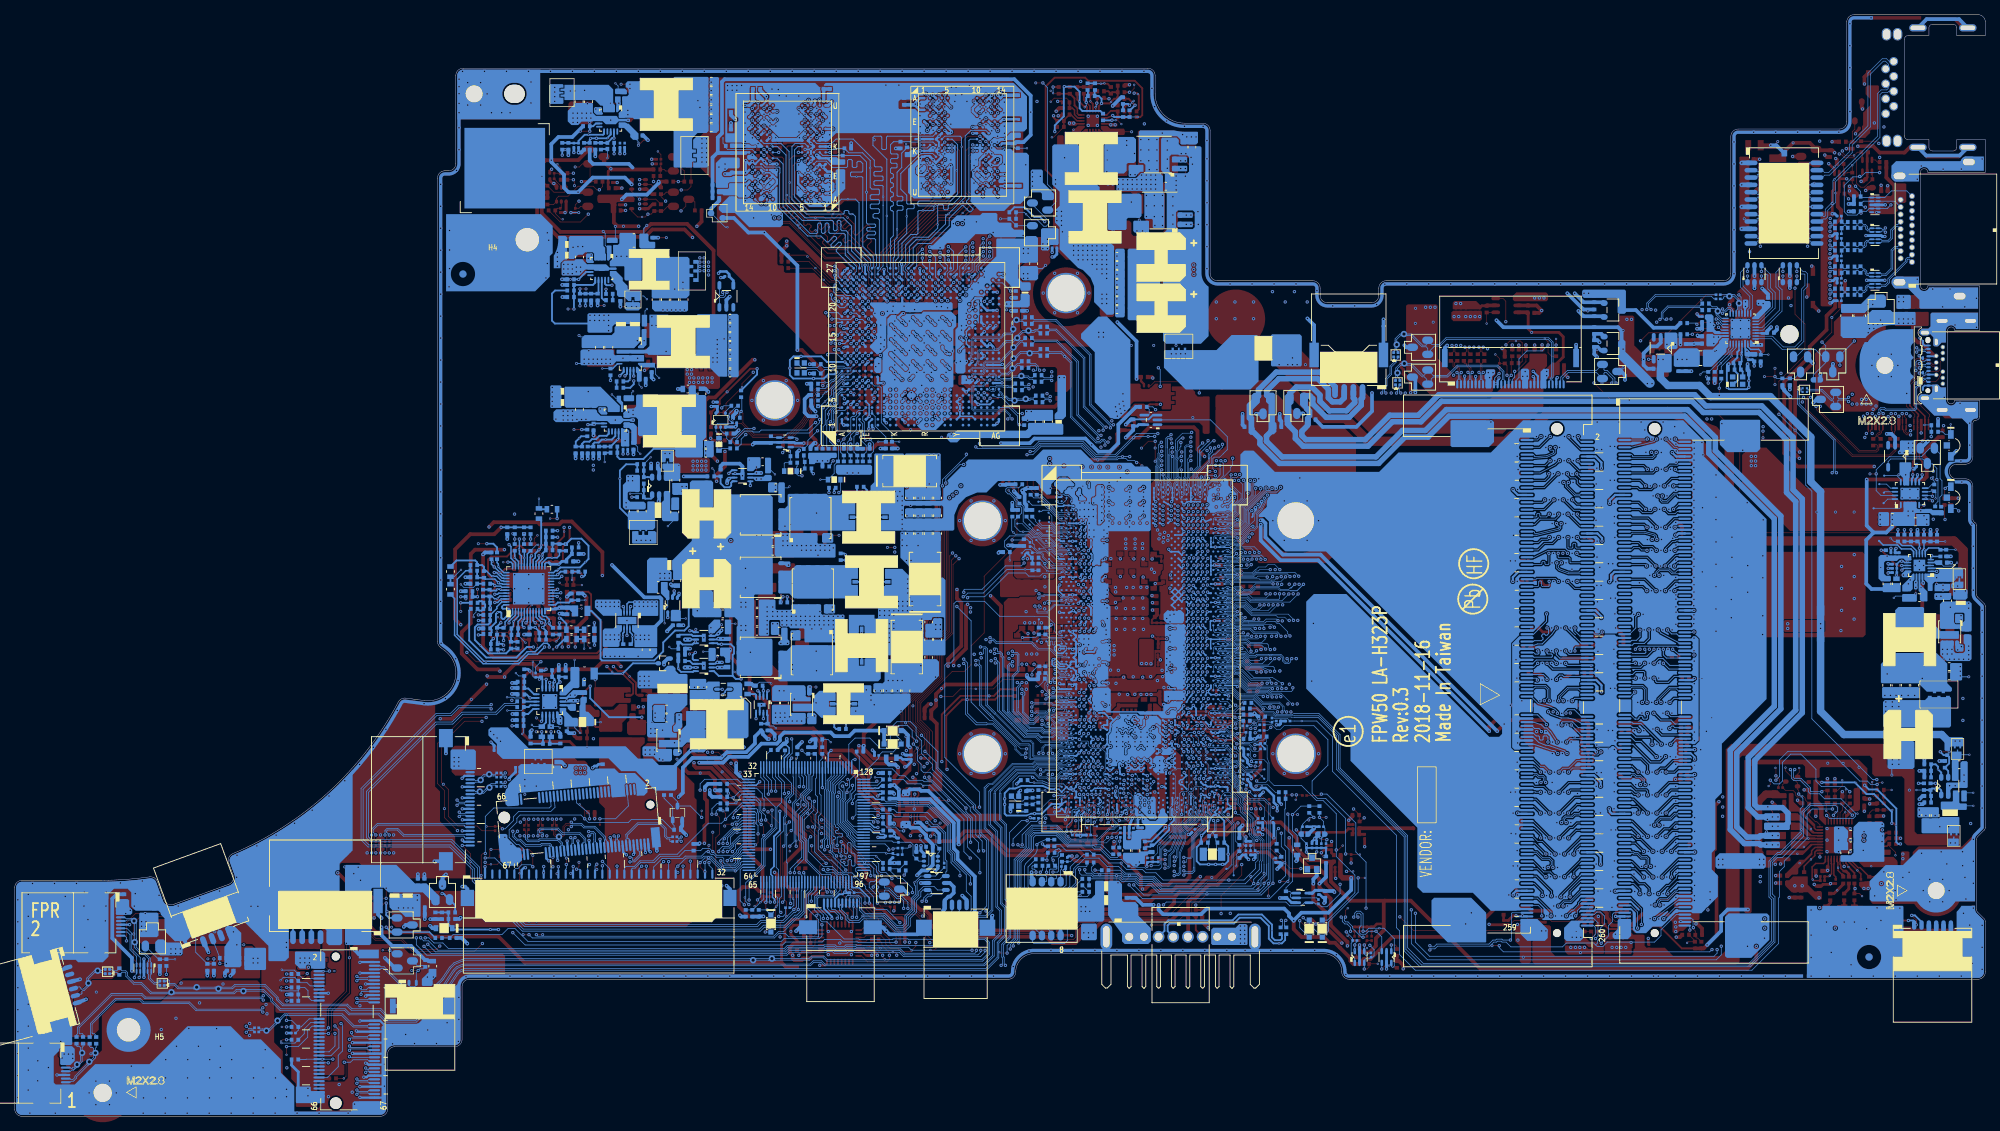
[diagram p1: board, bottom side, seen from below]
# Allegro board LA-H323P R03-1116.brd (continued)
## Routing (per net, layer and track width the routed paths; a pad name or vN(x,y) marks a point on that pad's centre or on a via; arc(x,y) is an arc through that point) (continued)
DDR_M1_ODT0: length 78.3
  IN2 w0.076: 89.01,65.85 92.01,65.85 92.49,66.33 95.15,66.33 v3(96.44,67.63)
  IN2 w0.157: v3(45.44,50.76) 45.61,50.6 47.14,50.6 47.3,50.44 47.3,49.78 47.46,49.62 47.77,49.62 47.93,49.78 47.93,50.44 48.09,50.6 48.4,50.6 48.56,50.44 48.56,49.78 48.72,49.62 49.03,49.62 49.19,49.78 49.19,50.44 49.35,50.6 49.66,50.6 49.82,50.44 49.82,49.78 49.98,49.62 51.43,49.62 51.57,49.76 51.57,50.35 51.7,50.48 52.35,50.48 52.66,50.16 53.69,50.16 53.85,50.01 53.85,49.78 54,49.62 54.31,49.62 54.55,49.85 54.55,50.35 56.14,51.94 60.09,51.94 60.1,51.94 60.41,51.94 60.57,51.78 60.57,51.43 60.79,51.2 61.13,51.2 61.29,51.36 61.29,51.93 61.76,52.4 62.39,52.4 62.85,52.85 62.85,53.11 63.28,53.54 69.09,53.54 81.4,65.85 89.01,65.85
  BOTTOM w0.076: UC1.AL36 103.9,68.2 103.41,67.94 103.16,67.94 102.93,68.17 102.58,68.17 102.53,68.12 102.52,68.12 102.2,67.79 101.44,67.79 101.14,67.49 100.49,67.49
  BOTTOM w0.089: v3(96.44,67.63) 96.66,67.84 98.06,67.84 98.41,67.49 100.49,67.49
  BOTTOM w0.102: JDIMM2.155 48.36,52.28
  BOTTOM w0.127: 48.36,52.28 48.22,52.28 47.66,51.72 45.63,51.72 45.44,51.54 v3(45.44,50.76)
DDR_M1_ODT1: length 79.2
  IN2 w0.076: 89.01,64.62 92.05,64.62 92.98,65.54 v3(94.81,65.54)
  IN2 w0.157: 89.01,64.62 81.94,64.62 68.74,51.42 63.63,51.42 62.09,49.88 59.56,49.88 59.5,49.94 56.44,49.94 54.89,48.38 46.05,48.38 45.9,48.54 45.9,48.82 45.74,48.98 45.42,48.98 45.27,48.82 45.27,48.54 45.11,48.38 43.39,48.38 43.28,48.5 43.28,48.76 v3(43.6,49.08)
  BOTTOM w0.076: UC1.AL34 105.07,68.2 104.75,67.89 103.68,67.89 103.48,67.78 103.46,67.78 103.46,67.78 103.09,67.78 102.92,67.95 102.59,67.95 102.26,67.63 101.51,67.63 101.2,67.32 100.46,67.32
  BOTTOM w0.089: 100.46,67.32 100.44,67.3 98.22,67.3 98,67.53 96.85,67.53 96.59,67.26 96.28,67.26 95.14,66.13 95.14,65.87 v3(94.81,65.54)
  BOTTOM w0.102: JDIMM2.161 48.36,50.78
  BOTTOM w0.127: 48.36,50.78 48.05,50.78 45.63,48.36 44.32,48.36 v3(43.6,49.08)
DDR_M1_PAR: length 72.6
  IN2 w0.076: 89.01,71.38 89.71,71.38 90.03,71.06 90.56,71.06 90.78,70.85 99.2,70.85 100.62,72.27 105.86,72.27 v3(106.07,72.48)
  IN2 w0.157: v3(47.8,57.88) 47.93,58.01 50.02,58.01 50.11,57.92 51.35,57.92 52.25,58.82 53.78,58.82 54.58,59.62 57.25,59.62 58.16,60.52 58.56,60.52 58.71,60.36 58.71,60.21 58.87,60.05 59.19,60.05 59.34,60.21 59.34,60.36 59.5,60.52 59.82,60.52 59.97,60.36 59.97,60.21 60.13,60.05 60.45,60.05 60.6,60.21 60.6,60.36 60.76,60.52 61.08,60.52 61.23,60.36 61.23,60.21 61.39,60.05 61.71,60.05 61.86,60.21 61.86,60.36 62.02,60.52 62.41,60.52 62.57,60.36 62.57,59.73 62.72,59.57 63.04,59.57 63.2,59.73 63.2,60.65 63.35,60.8 64.15,60.8 64.31,60.65 64.31,59.87 64.46,59.72 64.78,59.72 64.94,59.87 64.94,60.65 65.09,60.8 67.6,60.8 75.12,68.33 76.06,68.33 79.11,71.38 89.01,71.38
  BOTTOM w0.076: UC1.AE34 v3(106.07,72.48)
  BOTTOM w0.102: JDIMM2.143 48.4,57.28
  BOTTOM w0.127: 48.4,57.28 v3(47.8,57.88)
DDR_PG_CTRL: length 23.1
  TOP w0.102: v3(104.99,87.99) v2(105.73,87.99)
  IN1 w0.127: v3(104.99,87.99) 105.58,87.99 106.36,87.21 106.36,86 v3(104.73,84.37)
  BOTTOM w0.076: v3(104.73,84.37) 104.59,84.51 UC1.C35 ; v3(104.99,87.99) 105.33,88.33 105.33,89.75 105.14,89.94 104.38,89.94 103.93,90.39
  BOTTOM w0.102: UC3.2 105.65,95.02 103.36,92.73 103.36,90.95 103.93,90.39
DEVSLP0: length 3.6
  BOTTOM w0.076: UC1.CP8 121.29,41.9 121.29,41.36 121.44,41.21 121.61,41.21 121.84,40.98 121.84,39.86 121.55,39.57 T2405.1
DEVSLP1: length 4.2
  BOTTOM w0.076: UC1.CR8 122,41.05 122,38.39 RC978.1 121.9,38.29 v1(121.15,38.29)
DEVSLP2: length 79.3
  TOP w0.102: v3(190.32,40.6) 190.32,41.28 RS46.1
  IN1 w0.076: v3(121.83,43.93) 121.83,43.47 122.66,42.63 129.44,42.63 129.68,42.39
  IN1 w0.127: v3(190.32,40.6) 189.89,41.03 183.3,41.03 182.81,40.55 179.4,40.55 178.7,41.24 174.7,41.24 174,40.55 172.74,40.55 171.78,41.5 169.48,41.5 169.09,41.11 166.03,41.11 165.55,40.63 164.02,40.63 163.47,41.19 160.84,41.19 159.81,41.19 159.63,41.37 153.88,41.37 152.47,42.78 149.77,42.78 149.44,43.11 135.41,43.11 133.2,40.9 131.66,40.9 130.17,42.39 129.68,42.39
  BOTTOM w0.076: UC1.CM8 v3(121.83,43.93)
  BOTTOM w0.102: v3(190.32,40.6) 190.38,41.34 192.08,42.76 JSSD.38
DGPU_HOLD_RST#: length 137.4
  TOP w0.102: RV2753.2 181.91,127.15 UV12.2 v3(183.5,127.15)
  IN2 w0.076: v3(130.74,50.13) 130.43,50.44 125.9,50.44 v3(123.53,51.42)
  IN2 w0.127: v3(140.23,69.55) 140.81,70.14 140.81,71 146.45,76.64 146.45,85.31 146.39,85.37 146.39,86.49 146.8,86.9 148.47,86.9 148.78,86.6 156.57,86.6 158.46,88.49 159.66,88.49 160.45,89.28 160.45,90.38 161.51,91.45 161.51,92.84 161.78,93.11 162.32,93.11 162.99,92.45 169.5,92.45 171.94,94.89 171.94,96.03 171.35,96.63 171.35,98.25 170.52,99.08 170.52,102.05 169.62,102.95 169.62,110.51 170.54,111.43 170.54,113.86 174.55,117.88 177.91,117.88 182.67,122.64 183.82,122.64 184.89,123.72 184.89,124.49 183.06,126.32 183.06,126.79 183.42,127.15 v3(183.5,127.15)
  BOTTOM w0.076: UC1.CH12 119,45.45 119.88,46.33 120.03,46.33 120.28,46.59 120.28,46.82 120,47.1 120,49.71 120.47,50.19 120.47,50.19 120.53,50.24 120.7,50.24 120.89,50.17 121.06,50.17 121.24,50.24 121.35,50.24 121.45,50.2 121.48,50.18 121.75,50.18 121.79,50.19 121.8,50.2 122.01,50.29 122.32,50.6 122.32,51.12 122.39,51.2 123.31,51.2 v3(123.53,51.42) ; v3(130.74,50.13) 131.48,50.13 135.34,54 135.76,54 135.88,54.11
  BOTTOM w0.102: 135.88,54.11 138.29,56.52 138.29,67.61 v3(140.23,69.55)
DGPU_MAIN_EN: length 175.8
  TOP w0.102: RV2763.1 153.5,98.05 153.93,97.62 154.83,97.62 155.13,97.32 155.13,95.51 v2(155.36,95.28) 156.19,94.45 156.19,93.66 v3(156.83,93.02) ; RV2747.1 v3(192.51,128.67)
  TOP w0.254: PRV5.2 127.05,136.28 v3(127.05,136.51)
  IN1 w0.127: v3(192.51,128.67) 193.53,127.66 193.53,125.12 190.99,122.58 183.22,122.58 182.74,122.09 180.64,122.09 179.37,120.82 179.37,118.72 177.15,116.5 177.15,114.86 174.76,112.47 174.02,112.47 171.6,110.04 171.6,108.4 171.41,108.21 170.84,108.21 170.11,107.49 170.11,103.04 170.75,102.4 170.75,100.11 172.03,98.82 172.03,97.28 171.87,97.12 171.87,96.36 172.19,96.03 172.19,95.08 171.66,94.55 170.98,94.55 170.78,94.76 169.67,94.76 168.92,94.02 168.92,93.54 168.28,92.9 167.58,92.9 166.82,92.13 162.95,92.13 162.12,91.3 158.88,91.3 157.16,93.02 v3(156.83,93.02) 156.64,92.84 156.64,90.38 156.45,90.19 153.68,90.19 152.33,88.84 145.11,88.84 144.62,88.35 139.23,88.35 136.19,91.39 136.19,96.22 132.08,100.34 129.06,100.34 128.12,99.4 122.22,99.4 112.44,109.18 112.44,118.49 114.24,120.29 115.76,120.29 116.43,120.95 116.43,121.86 121.91,127.33 121.91,129.51 126.35,133.95 126.35,135.81 v3(127.05,136.51)
  BOTTOM w0.102: v3(156.83,93.02) 156.83,93.32 156.48,93.67 156.48,95.32 UV1.A3
DGPU_MAIN_EN#: length 102.1
  TOP w0.102: RV2745.1 195.21,124.4 QV30.6 194.82,125.24 194.52,125.53 193.24,125.53 191.88,126.89 189.81,126.89 189.33,126.41 v3(188.98,126.41) 188.55,126.84 RV2746.1 ; v3(128.51,140.99) v2(129.47,140.99)
  IN2 w0.127: v3(128.51,140.99) 129.27,141.75 174.68,141.75 174.82,141.61 174.82,134.92 176.2,133.55 181.16,133.55 184.53,130.18 188.08,130.18 188.98,129.28 v3(188.98,126.41)
  BOTTOM w0.102: v3(128.51,140.99) 127.87,140.36 127.87,127.15 126.73,126 126.73,124.76 QV146.2
DGPU_MAIN_EN#_GATE: length 5.3
  TOP w0.102: v2(192.27,129.52) 191.71,129.52 191.28,129.95 QV26.2 190.24,129.76 CV320.1 RV2746.2
DGPU_MAIN_EN_GATE: length 10.1
  BOTTOM w0.102: RV85.1 RV2752.1 131.05,123.34 v1(130.79,123.08) 130.03,122.32 129.27,122.32 128.38,121.43 128.05,121.43 127.59,121.9 127.59,122.04 129.93,124.38 QV146.1
DGPU_MAIN_EN_R_GATE: length 4.7
  BOTTOM w0.102: QV5.2 132.11,121.51 CV315.1 133.05,122.45 RV85.2 v2(134.29,122.45)
DGPU_OVT#: length 139.8
  TOP w0.102: v3(142.2,86.02) 142.2,84.13 142.58,83.75 142.58,68.83 143.98,67.43 143.98,60.49 148.22,56.24 148.22,55.17 147.84,54.79 147.84,52.71 147.17,52.05 v2(147.17,51.79) 147.17,49.97 v3(147.12,49.91) ; v3(177.85,123.53) 177.2,124.18 177.2,124.71 QG4.1 176.31,125.12 175.95,124.76 RG67.1
  IN1 w0.127: v3(147.12,49.91) 148.69,49.91 150.59,48 152.04,48 154.2,45.84 156.51,45.84 157.93,44.42 159.38,44.42 159.57,44.61 160.89,44.61 160.98,44.52 161.34,44.52 161.72,44.9 v3(161.72,44.98) ; v3(138.93,90.33) 139.67,90.33 140.38,89.62 144.1,89.62 144.59,90.11 151.8,90.11 152.76,91.07 152.76,93.11 155.26,95.6 157.82,95.6 159.56,93.87 162.82,93.87 163.1,93.59 166.04,93.59 166.86,94 167,94.06 167.67,94.5 168.24,95.07 169.38,96.78 169.73,96.78 170.76,97.81 170.76,98.27 169.48,99.55 169.48,101.88 168.84,102.51 168.84,108.04 169.67,108.86 169.67,112.94 170.72,113.99 174.49,113.99 175.88,115.38 175.88,117.03 177.85,119 v3(177.85,123.53)
  BOTTOM w0.102: UK1.19 161.76,46.34 161.59,46.16 161.59,45.11 v3(161.72,44.98) ; v3(142.2,86.02) 142.2,86.85 138.93,90.12 v3(138.93,90.33)
DGPU_PWR_EN: length 198.1
  TOP w0.102: RV2748.1 194.32,122.02 191.55,122.02 v3(190.48,123.08) ; v3(124.01,40.33) 124.01,39.64 RC382.1 ; v3(141.74,86.4) 141.74,84.26 142.35,83.65 142.35,68.73 143.75,67.34 143.75,60.39 147.84,56.3 v2(147.84,55.33) 147.6,55.09 147.6,52.91 146.15,51.47 146.15,50.81 v3(146.16,50.79)
  IN1 w0.076: v3(118.45,46.12) 118.54,46.12 119.02,45.64 119.02,44.56 119.34,44.24 119.98,44.24 120.32,43.9 120.32,43.64 120.51,43.45 120.76,43.45 121.39,42.82 121.39,41.3 121.13,41.03 121.13,39.99 121.34,39.78 122.43,39.78 122.7,40.05 123.73,40.05 124.01,40.33 v3(124.01,40.33) 124.24,40.11 126.94,40.11 127.87,41.04 128.86,41.04 129.68,40.22
  IN1 w0.127: v3(139.31,88.93) 139.63,88.61 144.52,88.61 145.01,89.1 152.22,89.1 153.57,90.44 156.22,90.44 156.35,90.57 156.35,93.31 156.48,93.44 157.12,93.44 158.29,92.27 161.48,92.27 162.01,91.74 162.19,91.74 162.84,92.39 166.71,92.39 167.47,93.15 168.18,93.15 168.67,93.64 168.67,94.12 169.56,95.01 170.88,95.01 171.01,94.89 171.51,94.89 171.94,95.32 171.94,95.93 171.61,96.25 171.61,97.22 171.78,97.39 171.78,98.72 170.49,100 170.49,102.3 169.86,102.93 169.86,107.59 170.68,108.41 170.68,112.43 171.23,112.97 174.91,112.97 176.89,114.96 176.89,116.61 179.11,118.82 179.11,120.92 180.54,122.35 182.63,122.35 183.37,123.08 v3(190.48,123.08) ; 129.68,40.22 129.99,39.92 132.93,39.92 134.69,41.68 138.86,41.68 138.99,41.8 v3(138.99,42.06) ; v3(137.27,36.22) 138.74,36.22 139.34,35.62 147.72,35.62 148.1,36 149.14,36 v3(149.51,36.37)
  BOTTOM w0.076: UC1.CG12 118.51,46.06 v3(118.45,46.12)
  BOTTOM w0.102: v3(141.74,86.4) 141.74,86.99 139.8,88.93 v3(139.31,88.93) ; v3(149.51,36.37) 149.51,36.65 150.04,37.17 UK1.106 ; v3(137.27,36.22) 137.27,37.36 138.13,38.22 138.13,40.71 138.99,41.56 v3(138.99,42.06) 143.86,46.93 144.79,46.93 145.11,47.26 145.11,48.04 145.6,48.53 145.6,50.23 v3(146.16,50.79)
DGPU_PWR_EN#: length 6.4
  TOP w0.102: v1(196.81,128.24) 196.81,127.71 RV2739.1 195.18,126.08 193.77,126.08 193.52,126.34 QV30.3 193.52,127.06 RV2741.1
DGPU_PWR_EN#_GATE: length 7.9
  TOP w0.102: QV20.2 191.51,124.15 191.78,123.88 CV313.1 192.26,124.35 v3(191.75,124.86) ; v2(192.38,126.97) 192.38,127.64 v3(192.51,127.78) RV2741.2
  IN1 w0.127: v3(192.51,127.78) 192.51,125.62 v3(191.75,124.86)
DGPU_PWROK: length 141.8
  TOP w0.102: RV16.1 v3(181.59,127.53)
  TOP w0.203: PUV1.13 119.2,135.82 119.11,135.91 v3(119.08,135.91)
  IN1 w0.127: v3(171.37,95.41) 171.31,95.47 171.31,97.28 171.52,97.5 171.52,98.61 170.24,99.9 170.24,102.19 169.61,102.83 169.61,107.7 170.43,108.52 170.43,112.53 171.12,113.23 174.8,113.23 176.64,115.07 176.64,116.71 178.8,118.87 178.8,121.72 181.01,123.93 181.01,126.18 181.59,126.76 v3(181.59,127.53) 182.48,128.42 187.94,128.42 188.45,128.93 188.45,130.87 186.27,133.05 183.45,133.05 182.75,133.75 176.26,133.75 174.84,135.17 174.84,141.56 174.63,141.77 123.19,141.77 119.87,138.45 119.87,136.67 119.11,135.91 v3(119.08,135.91)
  BOTTOM w0.102: RV201.1 170.19,96.95 171.31,95.83 171.31,95.47 v3(171.37,95.41) 171.37,95.27 171.38,95.26 171.38,95.12 171.02,94.76 170.98,94.76 CC353.1 170.97,94.49 172.9,94.49 173.09,94.3 UV23.1 173.09,93.43 172.66,93.01 DV3.1 ; v3(119.08,135.91) v1(118.56,135.91)
  BOTTOM w0.254: v3(119.08,135.91) 119.11,135.88 PRV22.1
DH1_NVVDD: length 32
  TOP w0.102: v3(108.31,121.69) v2(107.31,121.69)
  IN2 w1.016: 108.57,120.92 108.57,119.4 109.58,118.38 117.63,118.38 120.25,121 120.25,122.66 125.84,128.25 125.84,133.5 124.82,134.51
  vias: v3(108.95,121.69) v3(124.29,135.5) v3(124.87,135.5)
DH2_NVVDD: length 13.7
  TOP w0.102: v3(109.08,129.31) v2(109.08,128.26)
  IN2 w0.508: 108.31,129.18 107.62,129.88 107.62,131.15 110.65,134.18 111.76,134.64 114.92,134.64 116.19,135.91
  vias: v3(109.71,129.31) v3(118.65,135.28) v3(119.24,135.28)
DIMM1_CHA_EVENT#: length 7.3
  TOP w0.102: v1(53.75,61.46) RD7.1 53.75,60.45 52.33,59.02 v3(52.33,57.91)
  BOTTOM w0.305: v3(52.33,57.91) 52.33,58.8 53.06,59.53 JDIMM1.134
DIMM2_CHB_EVENT#: length 3.2
  TOP w0.102: v1(38.64,59.73) v3(39.68,59.73) 40.4,59.73 RD25.1
  BOTTOM w0.305: v3(39.68,59.73) 39.89,59.53 JDIMM2.134
DISPOFF#: length 4.8
  TOP w0.102: C594.1 64.58,103.63 R166.2 64.64,102.7 v3(64.64,101.1) 64.91,100.83 v1(64.91,100.48)
  BOTTOM w0.102: v3(64.64,101.1) 65,100.74 JEDP.15
DL1_NVVDD: length 13.6
  TOP w0.102: v2(114.13,120.48) 114.6,120.48 v3(114.92,120.8)
  IN2 w1.016: 116.31,121.94 116.31,122.67 122.28,128.64 122.28,132.1
  vias: v3(115.68,120.8) v3(122.18,133.37) v3(122.59,132.94)
DL2_NVVDD: length 6.7
  TOP w0.102: v1(119.73,131.81) 119.96,131.81 120.47,132.32 120.47,132.7 v3(120.76,132.99)
  IN2 w0.508: 116.31,129.69 117.46,130.83 118.85,130.83 120.25,132.23
  vias: v3(115.93,128.47) v3(116.57,128.47) v3(121.14,133.5)
DRVEN: length 104.4
  TOP w0.102: v3(169.65,59.67) 170.53,60.54 v1(170.53,60.64)
  IN1 w0.254: v3(168.39,86.06) 168.39,83.15 167.05,81.81 158.22,81.81 156.45,80.03 156.45,76.47 161.15,71.78 170.04,71.78 170.54,71.27 170.54,64.92 171.05,64.41 v3(172.32,64.41) 173.34,64.41 173.85,64.92 173.85,65.53 180.25,71.93 182.41,71.93 183.61,73.13 194.7,73.13 195.14,73.58 195.14,77.15 195.99,78 v3(201.29,78)
  IN2 w0.254: v3(165.97,58.06) 165.97,59.57 166.08,59.67 v3(169.65,59.67)
  BOTTOM w0.203: v3(201.29,78) 201.02,77.73 201.02,76.14 200.41,75.53 PUZ1.35
  BOTTOM w0.254: PUZ2.1 172.92,64.55 172.78,64.41 v3(172.32,64.41) 171.05,64.41 170.62,63.98 170.62,63.14 170.8,62.96 170.8,60.09 ; PUZ3.1 173.35,60.74 172.7,60.09 170.8,60.09 170.8,60.09 ; PUA1.1 166.11,57.92 v3(165.97,58.06) ; 170.8,60.09 170.38,59.67 v3(169.65,59.67) ; PUG1.1 v3(168.39,86.06)
DRVEN_SET: length 4.6
  TOP w0.254: v3(194.67,71.9) 194.98,71.9 v1(195.25,71.63) 195.3,71.58 195.3,70.38 195.11,70.19 PRZ75.1 195.11,68.88 PRZ72.2
  BOTTOM w0.203: v3(194.67,71.9) 194.79,71.78 PUZ1.18
E51RXD_P80CLK: length 95
  TOP w0.102: v3(225.92,11.3) 225.51,11.71 225.51,14.37 223.06,16.82 v2(223.06,21.64) 223.06,27.2 223.92,28.06 v3(224.37,28.06)
  IN1 w0.127: v3(165.93,43.96) 166.23,43.67 166.91,43.67 167.81,42.77 179.1,42.77 179.97,43.64 182.58,43.64 183.33,42.9 198.25,42.9 198.58,43.23 202.95,43.23 206.34,39.84 206.34,33.29 208.62,31.01 211.45,31.01 211.91,30.55 211.91,29.27 213.62,27.55 223.86,27.55 v3(224.37,28.06)
  BOTTOM w0.102: JWLAN.32 v3(225.92,11.3) ; UK1.31 166.57,46.32 165.93,45.69 v3(165.93,43.96)
E51TXD_P80DATA: length 97.9
  TOP w0.102: v3(225.03,28.06) 224.61,27.64 224.02,27.64 223.48,27.1 v2(223.48,23.6) 223.48,17.03 225.92,14.59 v3(225.92,12.08)
  IN1 w0.127: v3(225.03,28.06) 224.55,28.54 223.72,28.54 223.03,27.86 213.68,27.86 212.16,29.37 212.16,30.66 211.56,31.26 208.72,31.26 206.59,33.39 206.59,39.94 203.05,43.48 198.48,43.48 198.16,43.16 183.42,43.16 182.68,43.9 179.87,43.9 178.99,43.03 167.92,43.03 167.01,43.94 166.81,43.94 166.37,44.38 v3(165.53,44.38)
  BOTTOM w0.102: v3(165.53,44.38) 165.53,45.83 166.17,46.46 UK1.30 166.17,49.4 RK26.1 ; v3(225.92,12.08) 226.19,11.8 JWLAN.30
EC_BEEP#: length 274.7
  TOP w0.102: v3(25.95,112.99) 25.95,109.44 24.6,108.08 24.6,103.84 28.14,100.29 v3(28.14,95.78) ; v3(14.8,45.94) 15.09,45.94 v1(15.44,45.59) 15.44,43.87 15.21,43.64 CA44.1
  IN2 w0.127: v3(162.76,51.49) 162.61,51.65 155.72,51.65 155.51,51.86 151.72,51.86 141.14,62.44 141.14,64.22 137.9,67.46 137.9,69.53 138.29,69.91 138.29,71.15 139.69,72.56 141.65,72.56 145.94,76.85 145.94,85.1 145.88,85.16 145.88,89.5 140,95.37 138.82,95.37 137.82,96.37 136.72,96.37 134.73,98.35 134.73,102.49 132.54,104.68 120.33,104.68 116.32,108.69 108.69,108.69 107.08,110.31 91.63,110.31 90.97,109.66 82.88,109.66 79.77,112.77 34.78,112.77 33.79,113.75 26.72,113.75 v3(25.95,112.99)
  BOTTOM w0.102: UK1.23 163.36,47.6 163.36,48.87 162.68,49.55 162.68,51.42 v3(162.76,51.49) ; v3(28.14,95.78) 24.49,92.13 24.49,86.13 23.66,85.29 23.66,54.24 15.36,45.94 v3(14.8,45.94)
EC_BKOFF#: length 154.6
  TOP w0.102: v3(65.36,105.25) 64.84,105.77 v1(64,105.77) 63.38,105.77 63.15,105.54 63.15,103 63.39,102.76 R166.1 63.66,103.64 R5176.1 ; v3(139.94,76.09) 140.75,75.28 140.75,65.92 142.13,64.54 142.13,59.74 145.39,56.49 145.39,53.93 143.95,52.5 143.95,48.86 CC364.1 143.96,48.49 v3(144.28,48.17)
  IN1 w0.127: v3(139.94,76.09) 139.94,78.38 140.58,79.02 140.58,82.86 135.78,87.65 130.27,87.65 118.75,99.17 115.83,99.17 113.85,101.15 112.31,101.15 111.9,101.56 105.67,101.56 104.5,102.72 100.16,102.72 96.63,106.26 66.37,106.26 v3(65.36,105.25) ; v3(144.28,48.17) 145.59,48.17 146.49,49.07 146.92,49.07 147.37,48.62 148.39,48.62 149.52,47.49 151.68,47.49 152.57,46.6 152.57,46.03 154.46,44.14 154.7,44.14 155.04,43.8 155.6,43.8 156.02,44.22 v3(156.32,44.22)
  BOTTOM w0.102: v3(156.32,44.22) 156.08,43.97 156.08,43.49 156.34,43.23 156.34,39.96 154.99,38.61 154.99,38.33 154.14,37.48 154.14,36.99 153.92,36.77 UK1.105
EC_CC_CHG: length 214.4
  TOP w0.102: v3(7.21,83.97) 7.73,83.97 v1(8.12,84.36)
  IN1 w0.127: v3(160.07,28.73) 159.76,28.42 150.75,28.42 149.69,27.36 146.33,27.36 145.09,28.61 144.16,28.61 143.89,28.88 139.04,28.88 138.22,29.7 137.65,29.7 137.39,29.95 134.48,29.95 133.79,29.27 132.22,29.27 131.91,29.58 125.6,29.58 125.15,30.03 118.16,30.03 117.43,29.31 114.32,29.31 114.27,29.36 113.72,29.9 111.85,29.9 111.72,29.77 108.76,29.77 108.56,29.57 105.14,29.57 104.5,30.21 90.5,30.21 89.42,29.13 87.33,29.13 86.94,29.52 83.2,29.52 78.91,25.23 74.87,25.23 73.88,24.24 65.54,24.24 64.93,23.63 57.93,23.63 57.01,24.55 57.01,24.91 56.65,25.27 54.91,25.27 54.34,25.84 48.89,25.84 46.91,23.86 45,23.86 43.8,25.06 43.8,26.04 42.42,27.42 39.15,27.42 37.53,27.42 36.44,28.5 36.44,32.54 37.27,33.37 37.27,36.44 33.12,40.59 33.12,44.3 33.6,44.79 33.6,67.11 17.06,83.65 8.81,83.65 8.49,83.97 v3(7.21,83.97)
  BOTTOM w0.102: UK1.83 159.76,30.94 160.48,30.22 160.48,29.13 160.09,28.73 v3(160.07,28.73) ; UU1.7 7.45,84.21 v3(7.21,83.97)
EC_CC_CHG_HI: length 212.4
  TOP w0.102: v1(7.26,85.45) 7.21,85.4 v3(7.21,84.6)
  IN1 w0.127: v3(160.07,29.36) 159.39,28.68 150.64,28.68 149.58,27.62 146.44,27.62 145.19,28.86 144.26,28.86 144,29.13 139.15,29.13 138.32,29.95 137.75,29.95 137.5,30.21 134.37,30.21 133.7,29.53 132.31,29.53 132.01,29.84 125.71,29.84 125.26,30.29 118.05,30.29 117.33,29.56 114.42,29.56 114.14,29.85 114.13,29.85 113.83,30.16 111.74,30.16 111.61,30.02 108.65,30.02 108.45,29.83 105.24,29.83 104.61,30.46 90.39,30.46 89.31,29.38 87.57,29.38 87.18,29.78 83.09,29.78 78.8,25.48 74.76,25.48 73.77,24.49 61.77,24.49 61.25,23.97 59.14,23.97 59.05,23.88 58.04,23.88 57.28,24.64 57.28,25.06 56.82,25.52 55.23,25.52 54.66,26.09 48.78,26.09 47.67,24.98 46.63,24.98 45.64,25.97 44.23,25.97 42.52,27.67 37.64,27.67 36.71,28.6 36.71,32.45 37.52,33.26 37.52,36.54 33.37,40.69 33.37,44.2 33.85,44.68 33.85,67.22 17.17,83.9 8.91,83.9 8.22,84.6 v3(7.21,84.6)
  BOTTOM w0.102: v3(160.07,29.36) 160.07,30.15 159.37,30.86 UK1.84 ; v3(7.21,84.6) 7.31,84.71 UU1.8
EC_CC_EN: length 217.1
  TOP w0.102: v2(8.81,82.61) 8.81,82.95 v3(8.36,83.4)
  IN1 w0.127: v3(163.99,29.22) 163.62,29.59 161.91,29.59 160.24,27.91 150.96,27.91 149.9,26.85 146,26.85 144.75,28.1 143.95,28.1 143.68,28.37 138.83,28.37 138.01,29.19 137.44,29.19 137.18,29.45 134.69,29.45 134,28.76 132.01,28.76 131.7,29.07 125.39,29.07 124.94,29.53 118.42,29.53 117.7,28.8 114.11,28.8 113.51,29.4 112.06,29.4 111.93,29.26 108.97,29.26 108.11,28.41 107.48,28.41 106.98,28.91 106.57,29.32 105.03,29.32 104.4,29.95 97.06,29.95 96.42,29.32 93.36,29.32 92.67,28.63 89.73,28.63 89.49,28.87 87.18,28.87 86.79,29.27 83.33,29.27 79.03,24.98 75.04,24.98 74.02,23.96 65.71,23.96 65.11,23.37 57.83,23.37 56.75,24.45 56.75,24.81 56.54,25.01 54.81,25.01 54.32,25.5 48.9,25.5 47.01,23.6 44.9,23.6 43.54,24.95 43.54,25.8 42.18,27.16 37.43,27.16 36.17,28.42 36.17,32.62 37.02,33.47 37.02,36.33 32.85,40.5 32.85,44.4 33.35,44.89 33.35,67.01 17.02,83.33 8.39,83.33 8.36,83.36 v3(8.36,83.4)
  BOTTOM w0.102: v3(163.99,29.22) 163.76,29.44 UK1.73 ; v3(8.36,83.4) 8.38,83.41 UU1.6
EC_FAN_PWM1: length 102
  TOP w0.102: v3(240.72,20.85) v2(239.84,20.85)
  IN1 w0.127: v3(163.75,44.04) 163.77,44.04 163.93,44.2 164.5,44.2 165.55,43.15 166.72,43.15 167.6,42.26 179.14,42.26 179.84,41.56 182.28,41.56 183.09,42.37 198.45,42.37 198.79,42.72 202.74,42.72 205.83,39.63 205.83,32.71 206.94,31.6 206.94,30.6 209.43,28.11 209.43,27.46 211.65,25.24 214.13,25.24 215.93,23.45 228.81,23.45 232.55,19.71 239.58,19.71 v3(240.72,20.85)
  BOTTOM w0.102: UK1.26 164.57,46.4 163.74,45.58 163.74,44.04 v3(163.75,44.04) ; JFAN.2 RE51.2 v3(240.72,20.85)
EC_KBRST#: length 118.8
  TOP w0.076: RC381.1 103.49,43.67 104.38,44.56 105.14,44.56 v3(105.77,43.93) 105.9,44.06 105.9,44.6 105.39,45.1 105.39,46.12 105.76,46.48 105.94,46.48 106.09,46.63 106.09,47.88 106.79,48.58 106.79,49.03 107.02,49.26 107.4,49.26 107.65,49.51 107.65,49.78 108.33,50.45 108.33,51.16 v3(108.61,51.44)
  TOP w0.102: v2(95.09,32.04) v3(96.21,32.04)
  IN2 w0.076: v3(105.77,43.93) 105.3,43.45 102.09,43.45 101.33,42.69 101.33,41.29 100.67,40.63 99.27,40.63
  IN2 w0.127: v3(136.59,36.22) 136.05,35.68 132.09,35.68 130.12,37.65 123.15,37.65 121.59,36.09 121.08,35.75 120.82,35.64 120.44,35.39 119.9,34.84 119.65,34.68 117.17,34.68 115.17,36.68 114.49,36.68 112.95,38.22 110.63,38.22 109.69,37.29 108.54,37.29 107.32,36.07 107.32,34.7 106.99,34.37 105.68,33.83 103.56,33.83 102.27,32.53 96.7,32.53 v3(96.21,32.04) ; v3(95.99,38.63) 97.26,38.63 99.27,40.63
  BOTTOM w0.076: UC1.BV29 108.61,51.41 v3(108.61,51.44)
  BOTTOM w0.102: v3(95.99,38.63) 95.99,36.8 95.42,36.22 95.42,32.82 v3(96.21,32.04) ; v3(136.59,36.22) 136.79,36.41 136.79,37.56 137.65,38.42 137.65,40.91 138.41,41.67 138.41,42.17 143.53,47.28 143.53,47.99 145.03,49.49 145.03,51.24 145.79,52 145.79,53.08 146.55,53.84 148.41,53.84 149.31,52.94 149.31,50.54 149.64,50.21 150.69,50.21 152.09,51.61 154.11,51.61 154.97,50.75 UK1.2
EC_LAN_ISOLATEB#_R: length 5.7
  TOP w0.102: v3(36.5,108.22) 36.6,108.31 v1(37.5,108.31) 38.63,108.31 RM11.2 39.12,108.27 v3(39.33,108.06)
  BOTTOM w0.102: v3(39.33,108.06) 39.49,108.22 RM6.2 ; v3(36.5,108.22) 36.3,108.22 35.74,107.66 UL1.20
EC_MUTE#: length 170
  TOP w0.102: R5260.1 28.22,45.17 28.06,45.32 28.06,45.96 v3(28.56,46.46) 28.56,47.47 v1(28.63,47.54)
  IN1 w0.127: v3(28.56,46.46) 29.49,46.46 31.89,44.06 31.89,40.32 33.7,38.5 33.7,29.39 37.69,25.4 38.46,25.4 41.26,22.6 47.22,22.6 48.26,23.64 51.54,23.64 52.59,22.6 73.74,22.6 75.35,24.21 79.44,24.21 82.73,27.5 84.88,27.5 85.36,27.99 88.54,27.99 88.86,27.67 92.9,27.67 93.79,28.56 96.74,28.56 97.34,29.15 104.12,29.15 104.72,28.56 106.25,28.56 107.16,27.65 113.69,27.65 113.85,27.81 117.82,27.81 118.58,28.57 120.88,28.57 122.09,27.36 126.69,27.36 127.14,27.82 128.48,27.82 128.61,27.69 134.01,27.69 135,28.68 136.87,28.68 137.12,28.43 137.69,28.43 138.63,27.49 139.47,27.49 140.49,26.47 143.37,26.47 144.66,25.19 149.17,25.19 149.69,25.71 159.1,25.71 160.09,26.7 160.09,27.41 161.37,28.68 162.66,28.68 163.52,27.82 v3(164.23,27.82)
  BOTTOM w0.102: v3(164.23,27.82) 164.42,28.01 164.42,29.74 164.17,30 UK1.72
EC_ON: length 136.9
  TOP w0.102: v3(145.73,51.18) 145.73,52.19 v2(147.21,53.68) 147.21,56.6 143.52,60.3 143.52,67.24 142.12,68.64 142.12,83.5 v3(141.24,84.39)
  IN1 w0.127: v3(141.24,84.39) 144.71,84.39 146.63,86.3 155.79,86.3 156.56,85.53 161.59,85.53 165.3,89.24 171.59,89.24 173.69,87.13 176.7,87.13 178.42,88.84 178.42,90.29 181.06,92.93 187.19,92.93 192.28,98.02 192.28,108.68 191.63,109.34 v3(191.63,110.59)
  BOTTOM w0.102: v3(145.73,51.18) 146.33,51.78 146.33,52.66 147.01,53.34 148.11,53.34 148.79,52.66 148.79,52.26 147.83,51.29 DH5.2 148.91,49.72 150.4,49.72 CC363.1 150.88,48.89 153.14,46.63 153.59,46.63 154.06,46.16 154.06,44.51 154.57,44 154.57,43.35 155.19,42.72 155.19,40.43 154.33,39.57 UK1.112 152.04,39.57 151.47,39 RK116.2
  BOTTOM w0.254: v3(191.63,110.59) PR301.1
EC_PCIE_WAKE#: length 93.6
  TOP w0.102: v3(223.76,7.38) 223.52,7.14 223.52,5.48 v1(223.82,5.18) RN3.2
  IN1 w0.127: v3(223.76,7.38) 224.36,6.78 226.35,6.78 227.08,7.51 227.08,13.47 224.48,16.07 224.48,19.04 223.11,20.42 218.54,20.42 216.68,22.27 212.83,22.27 211.9,23.21 211.9,24.01 208.92,26.98 208.92,27.9 206.42,30.4 206.42,31.4 205.32,32.5 205.32,39.42 202.52,42.21 199,42.21 198.48,41.69 183.17,41.69 182.54,41.05 179.61,41.05 178.91,41.75 174.17,41.75 v3(173.63,41.22)
  BOTTOM w0.102: v3(223.76,7.38) 222.91,7.38 222.58,7.72 220.57,7.72 220.4,7.55 JWLAN.47 ; v3(173.63,41.22) 173.63,41.96 172.91,42.69 RK6.1
EC_PECI: length 2.7
  BOTTOM w0.102: RK17.1 150.61,41.87 150.71,41.97 v1(151.37,41.97) UK1.118
EC_PME#: length 215
  TOP w0.102: v3(140.82,76.86) 141.21,76.47 141.21,66.11 142.6,64.72 142.6,59.92 145.84,56.68 145.84,53.7 144.41,52.27 144.41,49.98 v3(144.59,49.8) ; v3(36.37,107.65) 36.4,107.65 36.58,107.46 38.39,107.46 v1(38.67,107.19) 38.91,106.95 39.7,106.95 v3(39.94,106.7)
  IN1 w0.127: v3(140.82,76.86) 141.08,77.12 141.08,83.07 135.99,88.16 130.48,88.16 118.96,99.68 116.07,99.68 114.08,101.66 112.52,101.66 112.11,102.06 105.94,102.06 104.72,103.28 100.32,103.28 96.84,106.76 61.13,106.76 56.88,111.02 48.36,111.02 44.04,106.7 v3(39.94,106.7) ; v3(137.09,27.77) 137.67,27.2 139.4,27.2 141.04,25.56 143.03,25.56 144.29,24.3 149.31,24.3 149.46,24.15 156.7,24.15 156.95,23.9 161.78,23.9 164.52,26.64 v3(164.52,27.28)
  BOTTOM w0.102: RL15.2 v3(39.94,106.7) ; v3(36.37,107.65) 36.37,107.64 35.99,107.26 UL1.21 ; v3(137.09,27.77) 137.09,27.78 136.18,28.69 136.18,37.63 137.17,38.62 137.17,41.11 137.93,41.87 137.93,42.37 143.05,47.48 143.05,48.26 v3(144.59,49.8) ; v3(164.52,27.28) 163.92,27.28 163.6,27.6 R5178.2
EC_PME#_EC_R: length 3.9
  BOTTOM w0.102: UK1.76 v1(162.57,29.7) 162.46,29.6 162.46,28.8 162.8,28.47 R5178.1
EC_RST#: length 5.2
  TOP w0.102: v3(170.73,43.45) v2(171.37,44.09)
  BOTTOM w0.102: RK7.1 CK5.2 171.43,43.45 v3(170.73,43.45) 169.82,44.37 UK1.37
EC_SCI#: length 60
  TOP w0.089: v3(125.24,38.91) 125.46,38.69 125.46,38.04 125.18,37.76 RC410.1
  TOP w0.102: v3(162.82,38.99) 163.4,38.41 v1(163.42,38.41)
  IN1 w0.127: v3(162.82,38.99) 161.9,39.91 159.49,39.91 159.09,39.52 155.57,39.52 155.43,39.38 153.54,39.38 151.42,41.5 150.38,41.5 150.05,41.17 146.5,41.17 145.92,40.59 145.65,40.59 144.75,39.69 142.93,39.69 142.28,40.34 135.16,40.34 133.4,38.58 129.3,38.58 129.2,38.68 126.16,38.68 125.93,38.91 v3(125.24,38.91)
  BOTTOM w0.102: UC1.CP6 122.91,42.09 123.65,42.09 123.84,41.9 124.35,41.9 124.53,41.72 124.53,40.32 125.24,39.61 v3(125.24,38.91) ; RK14.2 161.98,48.82 162.17,48.64 UK1.20 162.17,43.21 162.64,42.73 162.64,39.17 v3(162.82,38.99)
EC_SMB_CK1: length 186.2
  TOP w0.102: RK110.2 162.45,29.57 v3(162.45,28.21)
  IN2 w0.127: v3(95.99,26.74) 95.82,26.92 95.82,27.36 96.32,27.87 100.92,27.87 106.17,33.12 107.39,33.62 108.13,34.36 108.13,35.73 108.87,36.48 110.15,36.48 111.08,37.41 112.61,37.41 114.15,35.87 114.83,35.87 116.84,33.87 120.06,33.87 120.39,34.2 120.41,34.21 120.76,34.56 120.95,34.68 121.34,34.85 121.83,35.17 123.33,36.67 127.9,36.67 128.14,36.43 128.93,36.43 131.01,34.35 140.03,34.35 141.34,33.04 141.88,33.04 142.87,32.05 142.99,32.05 145.66,29.38 145.66,28.47 146.79,27.35 148.34,27.35 148.97,26.73 151.27,26.73 152.24,25.75 157.87,25.75 158.21,25.41 161.3,25.41 162.38,26.49 162.38,28.14 v3(162.45,28.21)
  BOTTOM w0.102: PRB19.2 200.41,56.07 201.78,56.07 202.99,54.86 207.61,54.86 208.96,53.51 211.17,53.51 220.45,44.23 220.45,38.12 220.07,37.74 209.06,37.74 205.33,34.01 205.33,32.5 204.71,31.87 204.71,30.16 204.03,29.48 202.37,29.48 199.07,26.18 167.52,26.18 166.98,26.72 163.95,26.72 v3(162.45,28.21) 162.1,28.56 162.1,30.65 162.1,30.84 162.17,30.9 UK1.77 ; PR14.2 95.84,26.02 95.84,26.59 v3(95.99,26.74)
EC_SMB_CK1_R: length 21.9
  BOTTOM w0.254: PR14.1 95.91,24.68 95.91,24.23 96.1,24.03 96.88,24.03 97.26,24.42 v1(97.26,25.31) 97.26,26.16 98.64,27.53 101.85,27.53 102.64,26.74 111.41,26.74 111.92,26.23 111.92,25.3 PJPB1.3
EC_SMB_CK2: length 224.6
  TOP w0.102: RK112.2 161.74,33.81 v3(161.74,33.24)
  IN2 w0.127: v3(171.57,112.42) 171.74,112.25 171.74,111.5 170.39,110.15 170.39,103.25 171.86,101.78 171.86,97.98 172.73,97.11 172.73,93.31 170.65,91.23 167.46,91.23 166.84,91.85 162.86,91.85 162.34,92.37 v3(162.04,92.37) 162.04,91.71 162.48,91.27 162.48,90.7 162.99,90.19 162.99,89.7 163.41,89.28 164.46,89.28 164.82,89.63 171.93,89.63 172.33,90.04 173.15,90.04 173.6,89.58 173.6,84.79 177.38,81.02 189.25,81.02 191.63,83.4 203.48,83.4 208.3,78.57 208.3,65.8 206.31,63.8 206.31,59.72 204.64,58.05 203.55,58.05 202.55,57.06 202.55,56.01 202.85,55.71 203.61,55.71 v3(203.73,55.59)
  BOTTOM w0.102: v3(171.57,112.42) 171.75,112.24 171.75,111.97 171.99,111.73 172.51,111.73 172.61,111.63 UC11.1 ; v3(203.73,55.59) 203.88,55.74 208.11,55.74 209.18,54.68 211.13,54.68 221.19,44.62 221.19,37.83 220.39,37.03 209.25,37.03 206.03,33.8 206.03,32.22 205.44,31.63 205.44,29.85 204.34,28.75 202.56,28.75 199.36,25.55 167.13,25.55 166.59,26.08 163.69,26.08 162.32,27.45 162.04,27.45 161.45,28.05 161.45,30.74 161.36,30.83 161.36,31.94 UK1.79 161.37,32.87 v3(161.74,33.24) ; QV2.3 162.18,92.6 162.04,92.46 v3(162.04,92.37)
EC_SMB_DA1: length 187.7
  TOP w0.102: v3(161.86,28.21) 162.17,28.53 162.17,29.9 RK111.2
  IN2 w0.127: v3(95.39,26.74) 95.51,26.87 95.51,27.49 96.19,28.17 100.8,28.17 106,33.37 107.22,33.88 107.83,34.49 107.83,35.86 108.75,36.78 110.02,36.78 110.96,37.71 112.74,37.71 114.28,36.18 114.96,36.18 116.96,34.17 119.93,34.17 120.2,34.43 120.22,34.45 120.57,34.79 120.81,34.95 121.2,35.12 121.64,35.41 123.2,36.98 128.02,36.98 128.27,36.74 129.06,36.74 131.14,34.65 140.16,34.65 141.47,33.34 142,33.34 142.99,32.35 143.12,32.35 145.97,29.5 145.97,28.6 146.91,27.66 147.62,27.66 147.62,27.65 148.47,27.65 149.09,27.03 151.39,27.03 152.37,26.06 158,26.06 158.34,25.71 161.17,25.71 162.07,26.61 162.07,28 v3(161.86,28.21)
  BOTTOM w0.102: v3(95.39,26.74) 95.56,26.56 95.56,26.02 PR15.2 ; UK1.78 161.76,30.9 161.83,30.84 161.83,30.65 161.83,28.24 161.85,28.21 v3(161.86,28.21) 162.26,27.81 162.47,27.81 163.83,26.44 166.87,26.44 167.4,25.9 199.18,25.9 202.48,29.2 204.15,29.2 204.99,30.04 204.99,31.76 205.61,32.38 205.61,33.89 209.18,37.46 220.19,37.46 220.73,38.01 220.73,44.34 211.29,53.79 209.08,53.79 207.73,55.14 203.11,55.14 201.9,56.34 200.46,56.34 PRB18.2
EC_SMB_DA1_R: length 21.8
  BOTTOM w0.254: PJPB1.4 111.49,25.26 111.49,26.06 111.23,26.31 102.46,26.31 101.67,27.1 98.82,27.1 97.7,25.98 97.7,24.24 97.06,23.6 v1(96.3,23.6) 95.92,23.6 95.47,24.05 95.47,24.71 PR15.1
EC_SMB_DA2: length 223.3
  TOP w0.102: RK113.2 161.12,33.62 v3(161.12,33.24)
  IN2 w0.127: v3(203.73,56.18) 203.56,56.01 202.98,56.01 202.85,56.14 202.85,56.93 203.67,57.75 204.76,57.75 206.61,59.6 206.61,63.68 208.61,65.67 208.61,78.7 203.61,83.7 191.5,83.7 189.12,81.33 177.5,81.33 173.91,84.92 173.91,89.71 173.27,90.34 172.21,90.34 171.8,89.94 164.69,89.94 164.33,89.58 163.53,89.58 163.29,89.82 163.29,90.15 163.7,90.55 v3(163.98,90.55) 163.79,90.74 163.79,91.42 163.92,91.55 166.71,91.55 167.33,90.93 170.77,90.93 173.03,93.19 173.03,97.23 172.16,98.11 172.16,101.91 170.7,103.37 170.7,110.03 172.04,111.37 172.04,112.3 v3(172.16,112.42)
  BOTTOM w0.102: v3(161.12,33.24) 160.97,33.09 UK1.80 160.97,30.83 161.09,30.71 161.09,30.71 161.17,30.63 161.17,27.93 161.93,27.17 162.2,27.17 163.57,25.8 166.48,25.8 167.01,25.27 199.47,25.27 202.67,28.47 204.45,28.47 205.72,29.74 205.72,31.52 206.31,32.1 206.31,33.69 209.37,36.75 220.51,36.75 221.47,37.71 221.47,44.74 211.25,54.96 209.29,54.96 208.23,56.02 203.88,56.02 v3(203.73,56.18) ; UC11.5 172.61,112.11 172.51,112.01 172.11,112.01 172.03,112.09 172.03,112.29 v3(172.16,112.42) ; v3(163.98,90.55) 163.79,90.74 163.79,91.17 163.93,91.3 QV2.6
EC_SPI_CLK: length 4.2
  BOTTOM w0.102: UK1.126 151.06,45.17 150.3,45.93 RC369.1 150.59,46.25 v1(151.39,46.25)
EC_SPI_CS0#: length 40.6
  IN2 w0.127: v3(127.13,33.32) 127.53,33.72 128.3,33.72 128.43,33.6 128.43,32.86 128.49,32.8 130.5,32.8 130.94,33.24 v3(137.1,33.24)
  BOTTOM w0.102: UK1.128 152.16,45.97 151.93,46.21 151.93,47.1 151.61,47.42 149.03,47.42 148.08,46.46 147.32,46.46 146.7,45.85 144.89,45.85 144.7,45.65 143.72,45.65 138.79,40.72 138.79,36.74 137.1,35.05 v3(137.1,33.24) ; RC948.1 126.36,35.2 126.36,33.47 126.51,33.32 v3(127.13,33.32)
EC_SPI_SI: length 47.8
  IN2 w0.127: v3(139.43,26.35) 135.22,26.35 134.44,27.12 130.85,27.12 130.54,27.44 128.2,27.44 v3(127.65,26.89)
  BOTTOM w0.102: v3(139.43,26.35) 139.43,26.9 138.29,28.04 138.29,30.03 138.95,30.69 138.95,32.96 140.8,34.81 140.8,35.77 141.31,36.28 141.31,39.75 144.12,42.57 148.43,42.57 148.53,42.67 150.59,42.67 150.69,42.77 UK1.120 ; RC947.1 124.58,30.63 125.5,29.71 127.01,29.71 127.36,29.36 127.36,27.17 v3(127.65,26.89)
EC_SPI_SO: length 34
  IN2 w0.127: v3(139.81,32.84) 139.64,33 137.51,33 137.3,32.79 136.96,32.79 136.76,32.99 131.04,32.99 130.6,32.55 128.33,32.55 128,32.87 v3(128,33.3)
  BOTTOM w0.102: RC946.1 128,33.94 v3(128,33.3) ; UK1.119 151.99,42.37 151.8,42.57 150.81,42.57 150.68,42.44 148.63,42.44 148.52,42.34 144.22,42.34 141.54,39.66 141.54,36.18 141.03,35.67 141.03,34.6 139.81,33.38 v3(139.81,32.84)
EC_VCCST_PG: length 5.6
  BOTTOM w0.076: UC1.BJ2 125.54,57.16 125.85,57.46 127.26,57.46 127.91,58.11 127.91,58.74 v1(127.87,58.78)
  BOTTOM w0.102: RC116.2 127.82,60.14 127.82,58.93 127.87,58.88 v1(127.87,58.78)
EC_VCCST_PG_R: length 44.1
  TOP w0.102: v3(142.41,57.28) 140.78,57.28 139.75,58.31 v1(137.65,58.31) 135.24,58.31 133.94,59.61 130.26,59.61 129.99,59.88 v3(129.99,60.23)
  IN1 w0.127: v3(161.13,44.97) 160.62,45.48 158.35,45.48 157.55,46.27 154.38,46.27 152.22,48.43 150.88,48.43 145.49,53.82 143.94,53.82 142.41,55.35 v3(142.41,57.28)
  BOTTOM w0.102: UK1.18 161.37,46.49 161.13,46.26 v3(161.13,44.97) ; RC116.1 RC113.2 129.23,61.4 129.99,60.64 v3(129.99,60.23)
EC_VCIN1_AC_BYPASS: length 104.4
  TOP w0.102: v3(139.68,86.04) 139.68,84.85 140.14,84.4 140.64,83.65 141.44,82.85 141.44,66.21 142.83,64.82 142.83,60.02 146.22,56.62 v2(146.22,56) 146.22,53.76 144.64,52.17 144.64,50.7 145.84,49.49 145.84,48.4 145.49,48.05 145.49,46.99 v3(145.73,46.75)
  IN1 w0.127: v3(161.35,87.4) 160.5,86.55 157.08,86.55 156.31,87.32 145.83,87.32 145.33,86.82 140.47,86.82 v3(139.68,86.04) ; v3(165.44,41.78) 164.81,41.14 164.23,41.14 163.68,41.7 160.14,41.7 159.96,41.88 154.09,41.88 151.61,44.36 150.77,44.36 149.5,45.62 146.2,45.62 145.73,46.09 v3(145.73,46.75)
  BOTTOM w0.102: CV190.1 161.1,89.41 RV579.1 RV26.1 161.33,88.03 DV4.1 ; DV4.1 162.07,87.64 161.83,87.4 v3(161.35,87.4) ; DV4.1 162.07,88.6 162.01,88.67 RV126.2 ; v3(165.44,41.78) 165.44,39.27 166.84,37.87 166.84,34.35 167.63,33.57 UK1.64
ECAGND: length 58.5
  TOP w0.254: v3(141.57,47.33) 141.68,47.44 141.68,54.67 139.49,56.85 v2(138.83,56.85) 135.03,56.85 134.54,57.35 PH1.2 ; CK3.2 165.5,30.54 165.09,30.12 LK2.2 164.7,29.8 165.08,29.42 v3(165.08,29.23)
  IN1 w0.254: v3(141.57,47.33) 141.78,47.11 144.97,47.11 145.14,47.29 145.99,47.29 146.74,46.53 149.09,46.53 150.95,44.67 151.74,44.67 154.22,42.2 160.1,42.2 160.27,42.02 163.97,42.02 v3(164.37,41.62)
  BOTTOM w0.203: v3(165.08,29.23) 165.08,29.6 165.37,29.88 UK1.69 165.37,32.79 165.59,33.01 165.59,33.67 165.17,34.1
  BOTTOM w0.254: v3(164.37,41.62) 164.37,38.99 165.17,38.19 165.17,34.1
EDP_AUXN: length 97.9
  TOP w0.102: v3(68.46,104.93) 68.65,104.75 68.65,104.32 CT101.1
  IN2 w0.127: v3(129.59,69.62) 129.43,69.78 129.43,70.2 130.07,70.84 130.07,87.08 128.51,88.64 128.51,89.9 114.62,103.78 112.15,103.78 111.25,102.88 107.37,102.88 105.47,104.78 78.14,104.78 76.39,106.53 69.04,106.53 68.46,105.94 v3(68.46,104.93)
  BOTTOM w0.076: UC1.AH4 124.82,69.67 126.89,69.67 127.91,68.65 129.21,68.65 129.4,68.84 129.4,69.43 v3(129.59,69.62)
EDP_AUXN_C: length 3.6
  TOP w0.102: v3(68.46,101.49) 68.65,101.68 68.65,102.73 CT101.2
  BOTTOM w0.102: JEDP.8 68.5,100.36 68.64,100.51 68.64,101.31 v3(68.46,101.49)
EDP_AUXP: length 97.8
  TOP w0.102: v3(69.05,104.93) 68.86,104.75 68.86,104.32 CT102.1
  IN2 w0.127: v3(69.05,104.93) 69.29,105.18 69.29,105.39 69.16,105.52 68.84,105.52 68.72,105.64 68.72,105.84 69.15,106.27 76.29,106.27 78.03,104.53 105.36,104.53 107.26,102.63 111.35,102.63 112.25,103.53 114.52,103.53 128.25,89.79 128.25,88.54 129.82,86.98 129.82,70.95 129.21,70.35 129.21,70.25 129.08,70.12 128.89,70.12 128.76,70 128.76,69.86 v3(129.01,69.62)
  BOTTOM w0.076: UC1.AH3 125.26,70.21 125.37,70.21 125.46,70.12 125.46,69.95 125.57,69.83 126.96,69.83 127.97,68.82 129.15,68.82 129.24,68.91 129.24,69.16 129.16,69.24 128.8,69.24 128.72,69.31 128.72,69.54 128.8,69.62 v3(129.01,69.62)
EDP_AUXP_C: length 3.6
  TOP w0.102: v3(69.04,101.49) 68.86,101.67 68.86,102.73 CT102.2
  BOTTOM w0.102: v3(69.04,101.49) 68.86,101.31 68.86,100.49 69,100.34 JEDP.7
EDP_COMP: length 2.3
  TOP w0.279: RC1.2 123.74,67.51 123.22,67.51 122.82,67.11 v3(122.82,67.05)
  BOTTOM w0.254: UC1.AM6 v3(122.82,67.05)
EDP_HPD: length 122.1
  TOP w0.102: v1(66.81,103.94) 66.25,103.39 RT34.1 RT11.1 65.22,102.42 v3(65.22,101.1)
  IN1 w0.076: 112.04,66.92 111.32,66.2 111.04,66.2 110.55,65.71 110.55,61.16 110.78,60.94 110.78,60.76 111.25,60.28 111.81,60.28 111.9,60.37 112.48,60.37 114.19,58.65 114.22,58.65 114.25,58.63 115.72,58.63 116.56,57.8 116.56,57.05 118.96,54.65 118.96,54.02 119.27,53.71 119.27,51.84 119.82,51.29 119.82,49.2 120,49.02 120,47.75 119.91,47.66 119.91,46.04 119.83,45.97 119.83,45.46 120.89,44.41 121.91,44.41 v3(122.38,43.93)
  IN1 w0.127: 112.04,66.92 112.04,69.59 112.45,70.01 112.45,76.24 114.35,78.14 114.35,86.05 117.84,89.54 117.84,94.45 113.14,99.15 113.14,99.55 112.56,100.12 111.64,100.12 111.34,100.43 92.16,100.43 91.77,100.05 65.62,100.05 65.22,100.44 v3(65.22,101.1)
  BOTTOM w0.076: UC1.CM7 v3(122.38,43.93)
EDP_HPD_R: length 4.2
  TOP w0.102: RT34.2 66.25,101.39 v3(66.3,101.34) 66.75,100.9 v2(66.75,99.94)
  BOTTOM w0.102: v3(66.3,101.34) 66.92,100.72 66.92,100.49 67,100.41 JEDP.11
EDP_TXN0: length 92
  TOP w0.102: v3(70.37,104.94) 70.54,104.77 70.54,104.31 CT97.1
  IN2 w0.127: v3(70.37,104.94) 70.37,105.55 70.66,105.84 76.11,105.84 77.85,104.1 105.18,104.1 107.09,102.2 111.83,102.2 112.65,103.02 114.39,103.02 127.11,90.3 127.11,88.9 129.37,86.64 129.37,76.45 129.33,76.41 129.33,72.5 128.51,71.68 128.51,71.42 128.63,71.3 v3(129.04,71.3)
  BOTTOM w0.076: v3(129.04,71.3) 128.84,71.1 128.43,71.1 128.31,71.23 126.26,71.23 125.96,70.93 125.87,70.93 125.84,70.91 125.79,70.91 125.74,70.89 125.5,70.89 125.45,70.91 125.14,70.91 125.04,70.86 124.96,70.86 124.88,70.79 124.49,70.79 124.18,70.49 UC1.AG4
EDP_TXN0_C: length 3.8
  TOP w0.102: CT97.2 70.4,103.07 70.51,102.97 70.51,102.47 70.13,102.09 70.13,101.67 v3(69.96,101.5)
  BOTTOM w0.102: JEDP.5 70,100.38 70.14,100.52 70.14,101.32 v3(69.96,101.5)
EDP_TXN1: length 85.9
  TOP w0.102: v3(72.14,105.17) 72.33,104.98 72.33,104.32 CT100.1
  IN2 w0.076: v3(127.66,70.01) 127.87,70.22 127.87,71.71 127.71,71.88 127.71,72.75 128.06,73.09 ; 128.11,73.09 128.12,73.11 128.13,73.11 128.15,73.13 128.16,73.13
  IN2 w0.127: 128.16,73.13 128.31,73.13 128.63,73.46 128.63,75.55 128.43,75.75 128.43,86.05 126.04,88.44 126.04,89.94 116.99,99 115.85,99 113.59,101.26 106.59,101.26 104.69,103.15 77.46,103.15 76.13,104.48 72.62,104.48 72.36,104.74 72.36,104.95 v3(72.14,105.17) ; 128.06,73.09 128.11,73.09
  BOTTOM w0.076: UC1.AG2 125.82,70.23 127.44,70.23 127.63,70.04 127.66,70.01 v3(127.66,70.01)
EDP_TXN1_C: length 4.1
  TOP w0.102: CT100.2 72.12,103.07 72.37,102.81 72.37,102.45 72.27,102.34 71.97,102.34 71.69,102.06 71.69,101.7 v3(71.46,101.48)
  BOTTOM w0.102: v3(71.46,101.48) 71.64,101.29 71.64,100.55 71.5,100.4 JEDP.2
EDP_TXP0: length 91.9
  TOP w0.102: CT98.1 70.75,104.33 70.75,104.74 v3(70.95,104.94)
  IN2 w0.127: v3(129.04,70.71) 129.04,70.76 128.72,71.08 128.54,71.08 128.29,71.33 128.29,71.77 129.12,72.59 129.12,86.53 126.86,88.79 126.86,90.19 114.28,102.76 112.76,102.76 111.94,101.94 106.98,101.94 105.08,103.84 77.75,103.84 76,105.59 70.76,105.59 70.62,105.44 70.62,105.28 70.7,105.2 70.86,105.2 70.95,105.11 v3(70.95,104.94)
  BOTTOM w0.076: v3(129.04,70.71) 128.86,70.9 128.35,70.9 128.22,71.02 126.34,71.02 126.06,70.74 125.83,70.74 125.77,70.72 125.47,70.72 125.42,70.74 125.18,70.74 125.08,70.7 124.96,70.58 124.96,70.31 124.85,70.2 124.58,70.2 124.51,70.28 124.51,70.43 124.57,70.49 UC1.AG3
EDP_TXP0_C: length 3.9
  TOP w0.102: v3(70.54,101.5) 70.34,101.7 70.34,102 70.72,102.38 70.72,102.63 70.82,102.73 71.02,102.73 71.1,102.81 CT98.2
  BOTTOM w0.102: JEDP.4 70.5,100.39 70.36,100.54 70.36,101.32 v3(70.54,101.5)
EDP_TXP1: length 86
  TOP w0.102: v3(72.73,105.17) 72.55,104.99 72.55,104.32 CT103.1
  IN2 w0.076: 128.11,72.88 128.07,72.88 127.87,72.68 127.87,71.94 128.04,71.78 128.04,70.24 v3(128.27,70.01)
  IN2 w0.127: v3(72.73,105.17) 72.61,105.05 72.61,104.85 72.72,104.74 76.24,104.74 77.57,103.41 104.8,103.41 106.7,101.51 113.69,101.51 115.96,99.25 117.1,99.25 126.3,90.05 126.3,88.54 128.68,86.16 128.68,75.86 128.89,75.66 128.89,73.35 128.41,72.88 128.11,72.88
  BOTTOM w0.076: v3(128.27,70.01) 128.27,70.02 127.89,70.4 126.3,70.4 126.25,70.44 125.99,70.44 UC1.AG1
EDP_TXP1_C: length 4.1
  TOP w0.102: CT103.2 72.68,103.07 72.59,102.98 72.59,102.36 72.36,102.13 72.06,102.13 71.9,101.98 71.9,101.61 v3(72.04,101.48)
  BOTTOM w0.102: v3(72.04,101.48) 71.86,101.29 71.86,100.56 72,100.42 JEDP.1
EMMC_RCOMP: length 5.4
  BOTTOM w0.076: UC1.CK15 116.66,44.11 116.17,43.61 116.17,41.81 116.11,41.75 116.08,41.68 116.08,40.96 115.94,40.82 115.94,39.54 RC227.2
EN_1.0V_VCCSTU: length 4.6
  TOP w0.102: RC142.2 144.42,39.42 143.96,39.87 142.65,39.87 v2(142.52,40.01)
  TOP w0.203: UC6.3 145.63,40.48 145.13,39.97 CC261.1
  TOP w0.254: RC142.2 145.12,39.42 CC261.1
EN_1.8V: length 5.5
  BOTTOM w0.102: v1(184.79,84.94) 183.22,84.94 182.91,84.64
  BOTTOM w0.254: PC1805.1 PR1805.1 PR1804.2 182.71,84.27 181.95,84.27 181.78,84.44 PU1801.1
EN_1V: length 8.3
  BOTTOM w0.254: 192.19,91.38 192.19,92.05 v1(191.73,92.51) 191.46,92.78 PR1001.2 ; 192.19,91.38 PR1002.1 191.33,91.76 191.04,92.04 190.33,92.04 189.99,92.39 189.43,92.39 188.97,92.84 187.98,92.84 187.7,93.13 PU1001.11 ; 192.19,91.38 PC1005.1
EN_2.5V: length 5.9
  BOTTOM w0.102: PR2501.2 v1(9.41,44.52)
  BOTTOM w0.254: PR2502.2 7.48,43.78 PR2503.1 PC2502.1 ; PR2502.2 PR2501.2 ; PR2502.2 7.27,44.72 6.27,44.72 6.01,44.47 PU2501.1
ENBKL: length 58.4
  TOP w0.076: RC124.2 119.49,43.77 v3(119.52,43.8)
  TOP w0.102: v3(158.67,40.44) 158.37,40.44 153.49,35.57 153.49,35.29 v2(152.83,34.63) 151.98,33.78 v3(151.98,32.84)
  IN1 w0.076: 122.56,39.64 122.5,39.61 121.27,39.61 120.96,39.92 120.96,40.74 120.38,41.32 120.38,41.8 119.52,42.66 v3(119.52,43.8)
  IN1 w0.127: 122.56,39.64 122.78,39.86 126.58,39.86 126.77,39.66 133.04,39.66 134.8,41.42 139.25,41.42 139.55,41.72 144.49,41.72 145.37,42.6 147.51,42.6 147.84,42.27 151.72,42.27 153.84,40.15 154.92,40.15 155.09,40.32 157.68,40.32 157.81,40.44 v3(158.67,40.44)
  BOTTOM w0.076: UC1.CK11 v3(119.52,43.8)
  BOTTOM w0.102: v3(151.98,32.84) 151.98,33.45 152.1,33.57 UK1.97
ENLDO_3V5V: length 23.3
  TOP w0.102: v3(192.44,110.14) v2(193.25,110.14)
  IN2 w0.254: v3(192.44,110.14) 192.97,109.61 192.97,103.33 191,101.37 186.52,101.37 v3(186.19,101.04)
  BOTTOM w0.254: PU302.5 185.66,101.57 v3(186.19,101.04) ; v3(192.44,110.14) PC331.1 PR307.2 PR309.1 189.85,113.43 189.54,113.73 PU301.11
ENVDD_CPU: length 125.8
  TOP w0.076: RC123.2 118.22,43.44 v1(118.62,43.84) 118.98,44.2 118.98,44.85 v3(119.46,45.33)
  TOP w0.102: UG1.6 65.77,111.59 65.39,111.21 v3(65.39,108.41)
  IN1 w0.076: 114.14,58.46 115.66,58.46 116.39,57.73 116.39,56.99 118.79,54.59 118.79,53.95 119.02,53.72 119.02,52.94 119.02,52.94 119.02,51.85 119.66,51.22 119.66,49.13 119.83,48.95 119.83,47.82 119.74,47.73 119.74,46.11 119.46,45.83 v3(119.46,45.33)
  IN1 w0.127: v3(112.5,99.59) 112.5,99.42 116.57,95.36 116.57,92.22 117.2,91.59 117.2,89.26 114.14,86.2 114.14,78.23 112.24,76.33 112.24,70.1 110.74,68.6 110.74,66.17 110.36,65.79 110.36,61.08 110.49,60.96 110.59,60.86 110.59,60.41 111.51,59.49 112.25,59.49 112.76,58.98 113.16,58.98 113.68,58.46 114.14,58.46 ; v3(65.39,108.41) 65.39,108.21 66.58,107.02 96.95,107.02 100.35,103.61 105.08,103.61 106.37,102.32 112.57,102.32 v3(112.76,102.13)
  BOTTOM w0.076: v3(119.46,45.33) 119.46,45.52 UC1.CG11
  BOTTOM w0.102: v3(112.5,99.59) 112.5,101.87 v3(112.76,102.13)
FAN_SPEED1: length 108.1
  TOP w0.102: v3(241.54,21.48) v2(242.36,21.48)
  IN1 w0.127: v3(164.94,44.36) 165.9,43.4 166.82,43.4 167.71,42.52 179.2,42.52 180.08,43.39 182.47,43.39 183.22,42.64 198.35,42.64 198.69,42.97 202.84,42.97 206.08,39.73 206.08,32.82 207.21,31.69 207.21,30.69 209.69,28.21 209.69,27.59 211.76,25.52 214.21,25.52 216.03,23.71 228.91,23.71 232.66,19.96 239,19.96 240.52,21.48 v3(241.54,21.48)
  BOTTOM w0.102: v3(241.54,21.48) RE50.2 CE24.1 244.01,22.38 244.01,24.59 243.37,25.24 241.78,25.78 241.22,25.78 240.94,25.65 240.57,24.67 ; UK1.28 165.37,46.25 164.94,45.83 v3(164.94,44.36)
FB_1.8V: length 4.2
  BOTTOM w0.102: v1(181.97,89.92) 182.51,89.39 182.51,89.38 182.89,89 182.89,88.98 PR1803.2
  BOTTOM w0.254: PU1801.6 182.37,87.2 182.37,87.21 PR1806.1 PC1802.2 182.91,88.89 182.9,88.91 PR1803.2
FB_1V: length 4.1
  BOTTOM w0.254: PU1001.14 186.35,92.47 v1(186.49,92.33) PR1008.1 188.24,91.38 PR1010.2 188.25,91.38 189.02,91.38 PR1009.1
FB_2.5V: length 4.5
  BOTTOM w0.254: PR2506.2 PC2504.2 PR2507.1 6.78,48.03 6.46,47.71 v1(6.46,47.35) 6.01,46.91 PU2501.6
FB_CLAMP: length 5.7
  BOTTOM w0.102: v1(150.96,92.03) RV2768.1 149.91,92.69 151.37,94.16 151.37,95.47 UV1.F3
FB_CLK0: length 38.8
  TOP w0.076: 154.34,115.51 154.33,115.5 154.3,115.5 154.2,115.4 154.2,115.07 154.27,115 154.27,114.06 v3(153.9,113.69)
  TOP w0.109: RV123.2 167.02,131.39 166.81,131.39 v3(166.52,131.1) ; 154.34,115.51 155.82,116.99 158.19,116.99 163.06,121.86 164.68,121.86 164.92,122.09 164.92,122.38 v3(165.11,122.57)
  IN1 w0.14: v3(165.11,122.57) 165.09,122.59 165.09,123.88 164.71,124.26 164.22,124.26 163.38,123.42 163.11,123.42 162.83,123.7 162.83,123.97 163.85,125 163.85,125.37 164.04,125.56 164.47,125.56 164.81,125.9 164.81,126.38 164.47,126.71 164.04,126.71 163.85,126.9 163.85,127.17 164.04,127.36 164.47,127.36 164.81,127.7 164.81,128.18 164.47,128.52 164.04,128.52 163.85,128.71 163.85,129.59 164.33,130.07 164.33,130.6 163.85,131.07 163.85,132.62 164.07,132.84 164.73,132.84 164.97,132.6 164.97,131.68 165.44,131.22 166.43,131.22 166.52,131.13 v3(166.52,131.1)
  BOTTOM w0.109: UV6.J12 166.55,131.13 166.52,131.13 v3(166.52,131.1) ; v3(153.9,113.69) 153.51,113.3 UV1.D24
FB_CLK1: length 31.9
  TOP w0.076: v3(145.62,112.08) 145.8,112.08 145.97,112.25 145.97,112.63 146.94,113.6 146.94,115.44 146.77,115.61 146.74,115.61 146.73,115.62
  TOP w0.109: v3(136.28,133.01) 135.55,133.74 RV175.2 ; 146.73,115.62 145.5,116.85 145.5,118.32 143.45,120.38 140.03,120.38 139.69,120.72 139.69,121.59 v3(139.48,121.79)
  IN2 w0.14: v3(139.48,121.79) 139.69,122 139.69,122.66 140.04,123.01 140.24,123.01 140.39,123.16 140.39,123.57 140.24,123.71 140.04,123.71 139.69,124.07 139.69,124.52 139.24,124.97 139.24,130.12 138.38,130.98 137.42,130.98 137.01,131.39 137.01,131.98 136.51,132.47 136.51,132.77 v3(136.28,133.01)
  BOTTOM w0.109: v3(136.28,133.01) 135.88,132.61 UV7.J12 ; UV1.N22 v3(145.62,112.08)
FB_CLK#0: length 38.8
  TOP w0.076: 154.19,115.66 154.18,115.65 154.18,115.61 154.03,115.47 154.03,115 154.1,114.93 154.1,114.7 v3(153.9,114.5)
  TOP w0.109: RV123.1 167.02,131.6 166.84,131.6 v3(166.53,131.91) ; v3(164.49,122.57) 164.58,122.57 164.7,122.45 164.7,122.18 164.6,122.07 162.98,122.07 158.11,117.2 155.73,117.2 154.19,115.66
  IN1 w0.14: v3(166.53,131.91) 166.53,131.7 166.3,131.47 165.55,131.47 165.23,131.79 165.23,132.71 164.84,133.1 163.97,133.1 163.59,132.73 163.59,130.97 164.07,130.49 164.07,130.17 163.59,129.69 163.59,128.6 163.93,128.26 164.36,128.26 164.55,128.07 164.55,127.81 164.36,127.62 163.93,127.62 163.59,127.28 163.59,126.8 163.93,126.46 164.36,126.46 164.55,126.27 164.55,126 164.36,125.81 163.93,125.81 163.59,125.47 163.59,125.1 162.57,124.08 162.57,123.6 163,123.17 163.49,123.17 164.33,124 164.6,124 164.84,123.77 164.84,122.92 164.71,122.8 164.63,122.8 164.49,122.65 v3(164.49,122.57)
  BOTTOM w0.109: UV6.J11 v3(166.53,131.91) ; UV1.D25 v3(153.9,114.5)
FB_CLK#1: length 31.8
  TOP w0.076: v3(146.44,112.08) 146.33,112.08 146.14,112.28 146.14,112.56 147.1,113.53 147.1,115.51 146.89,115.73 146.89,115.76 146.87,115.77
  TOP w0.109: v3(140.12,121.8) 139.9,121.58 139.9,120.8 140.11,120.59 143.53,120.59 145.71,118.41 145.71,116.94 146.87,115.77 ; RV175.1 136.46,133.69 137.07,133.08 v3(137.07,133)
  IN2 w0.14: v3(140.12,121.8) 139.94,121.97 139.94,122.56 140.15,122.76 140.35,122.76 140.64,123.05 140.64,123.68 140.35,123.97 140.15,123.97 139.94,124.17 139.94,124.63 139.5,125.07 139.5,130.22 138.49,131.23 137.53,131.23 137.27,131.5 137.27,132.08 136.77,132.58 136.77,132.8 136.97,133 v3(137.07,133)
  BOTTOM w0.109: UV1.M22 146.44,112.06 v3(146.44,112.08) ; v3(137.07,133) 136.68,132.61 UV7.J11
FB_CMD0: length 26.4
  BOTTOM w0.127: UV6.G12 166.76,129.91 166.35,129.51 164.49,129.51 164.36,129.37 164.36,128.72 164.44,128.63 164.44,123.97 v1(161.67,121.19) 160.58,120.11 158.78,120.11 157.96,119.29 157.75,119.29 157,120.04 156.79,120.04 156.64,119.9 156.64,119.69 157.39,118.93 157.39,118.72 157.25,118.57 157.03,118.57 156.35,119.26 156.14,119.26 155.99,119.11 155.99,118.9 156.68,118.22 156.68,118 154.68,116.01 154.55,116.01 154.3,115.76 UV1.C27
FB_CMD1: length 28.7
  BOTTOM w0.089: UV1.C26 153.91,115.29 153.91,115.96
  BOTTOM w0.127: 153.91,115.96 155.45,117.5 155.45,120.29 155.63,120.47 157.54,120.47 157.69,120.61 v1(157.69,121.35) 157.69,121.72 157.83,121.87 158.04,121.87 158.19,121.72 158.19,120.61 158.34,120.47 158.55,120.47 158.7,120.61 158.7,121.72 158.85,121.87 159.06,121.87 159.21,121.72 159.21,120.61 159.36,120.47 160.27,120.47 163.93,124.13 163.93,129.93 164.72,130.72 165.33,130.72 UV6.H10
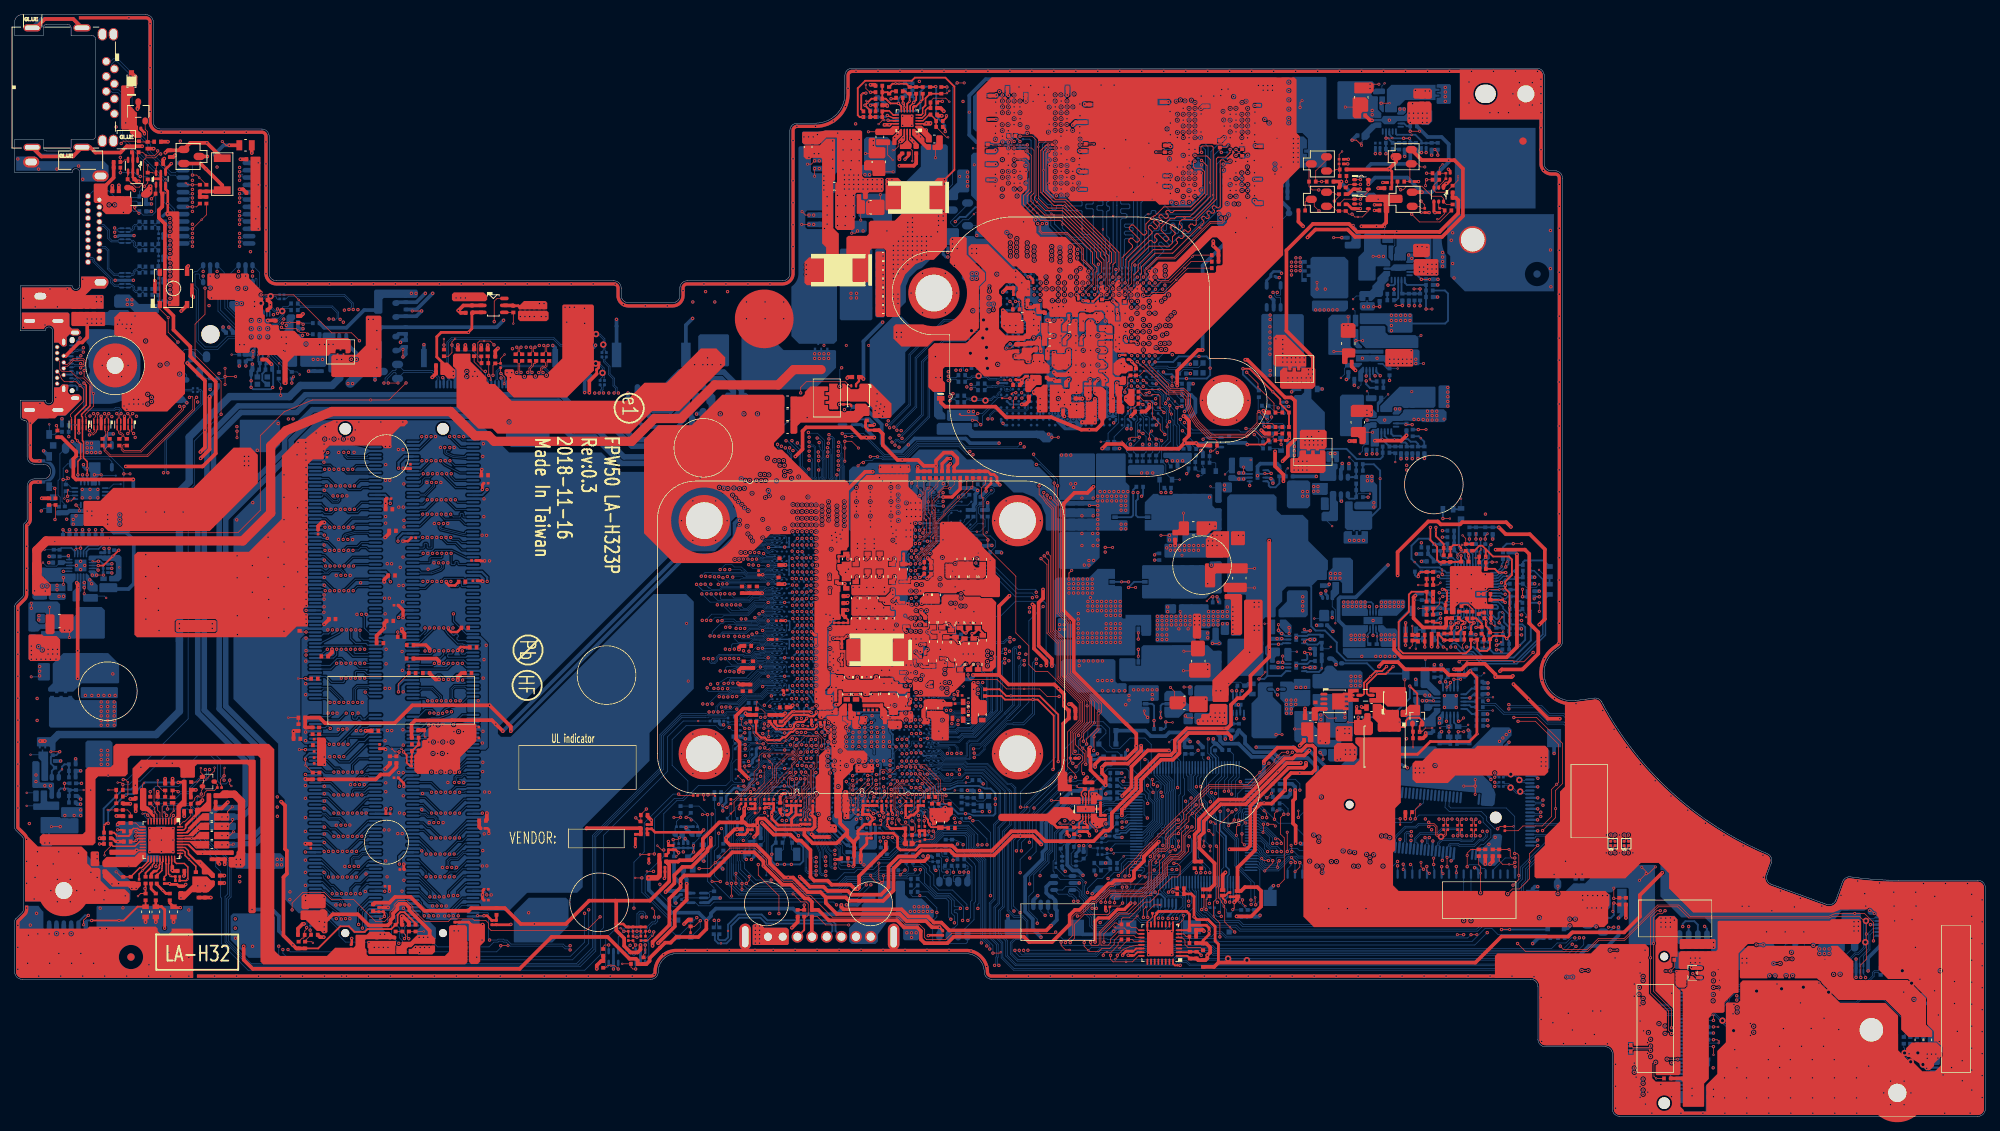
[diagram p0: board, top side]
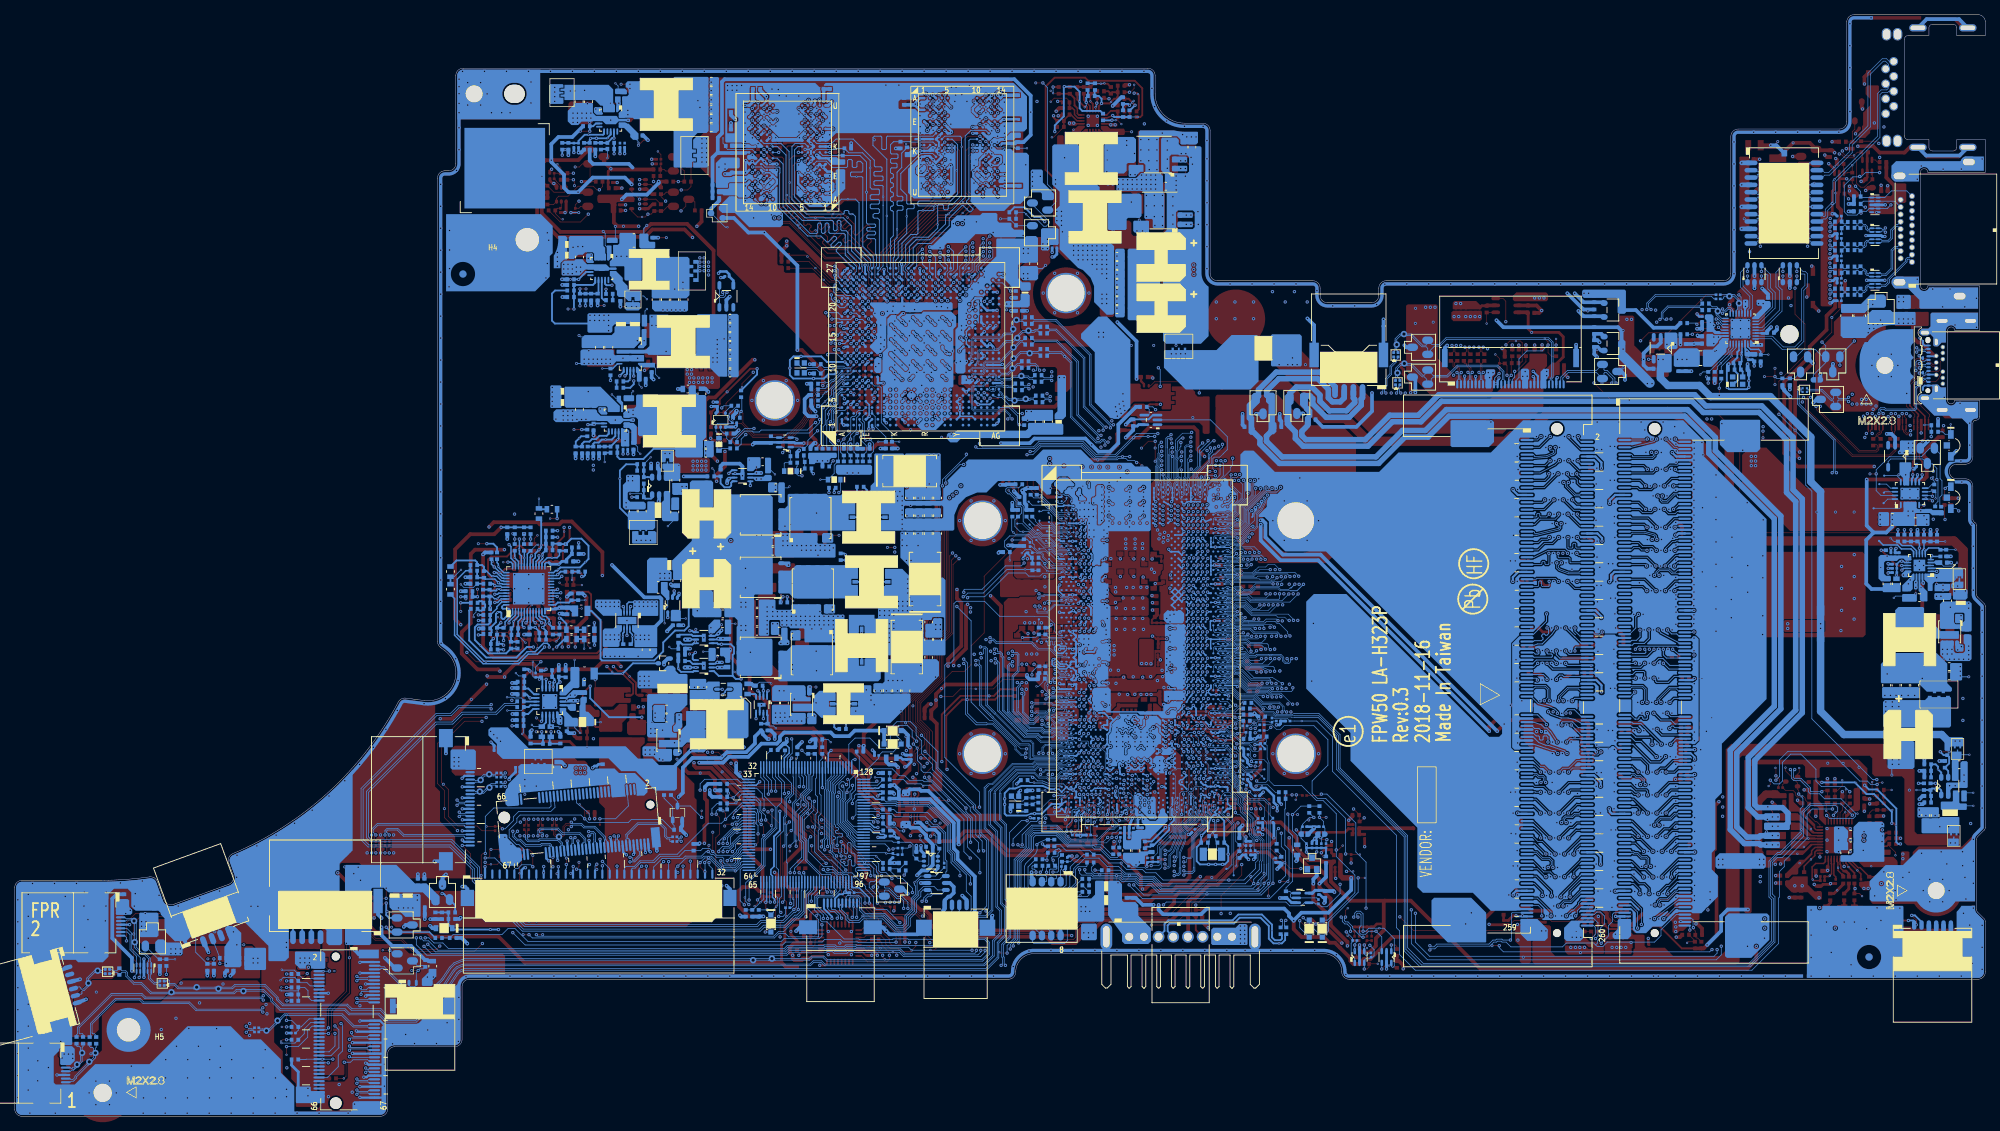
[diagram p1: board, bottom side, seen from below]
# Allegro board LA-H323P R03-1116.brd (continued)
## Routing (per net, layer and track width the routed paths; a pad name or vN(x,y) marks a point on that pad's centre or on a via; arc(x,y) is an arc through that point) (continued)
FB_CMD2: length 28.6
  TOP w0.089: 153.48,114.82 153.48,114.13 153.08,113.73
  TOP w0.127: 153.48,114.82 153.62,114.97 153.62,115.9 155.48,117.76 157.89,117.76 161.45,121.32 161.53,121.32 v1(161.85,121.64) 162.14,121.93 162.14,122.14 161.86,122.42 161.86,122.63 162.01,122.78 162.22,122.78 162.5,122.5 162.71,122.5 162.86,122.65 162.86,122.86 162.58,123.14 162.58,123.35 162.73,123.5 162.94,123.5 163.22,123.22 163.43,123.22 163.58,123.37 163.58,123.58 163.3,123.86 163.3,124.07 163.45,124.22 163.66,124.22 163.94,123.94 164.15,123.94 164.38,124.16 164.38,130.35 164.5,130.48 164.83,130.48 165.1,130.21 165.62,130.21 v3(165.72,130.31) ; 153.08,113.73 v3(153.08,113.69)
  BOTTOM w0.127: v3(153.08,113.69) 153.04,113.69 UV1.E24 ; v3(165.72,130.31) 166.12,130.71 UV6.H11
FB_CMD3: length 30.1
  TOP w0.089: 152.61,114.79 152.61,113.28 v3(152.21,112.88)
  TOP w0.127: 152.61,114.79 153.19,115.37 153.19,116.19 155.25,118.24 157.65,118.24 158.54,119.13 158.54,119.31 158.38,119.47 158.38,119.65 158.65,119.92 158.83,119.92 158.99,119.76 159.17,119.76 159.44,120.03 159.44,120.21 159.21,120.43 159.21,120.61 159.48,120.88 v1(159.49,120.88) 159.66,120.88 159.89,120.65 160.07,120.65 160.34,120.92 160.34,121.1 160.11,121.33 160.11,121.51 160.34,121.73 160.61,121.73 160.79,121.55 160.97,121.55 161.1,121.68 161.1,122.37 163.85,125.12 163.85,130.64 164.07,130.86 165.09,130.86 165.72,131.5 v3(165.72,131.92)
  BOTTOM w0.127: UV6.K11 166.12,132.31 v3(165.72,131.92) ; v3(152.21,112.88) 151.8,113.29 UV1.F24
FB_CMD4: length 27.7
  BOTTOM w0.127: UV6.K10 164.71,132.31 164.7,132.32 163.53,131.15 163.53,124.45 161.31,122.23 157.21,122.23 157.06,122.08 157.06,120.97 156.92,120.82 156.71,120.82 156.56,120.97 156.56,122.08 156.41,122.23 156.2,122.23 156.05,122.08 v1(156.05,121.56) 156.05,120.97 155.9,120.82 155.32,120.82 155.09,120.59 155.09,117.86 153.5,116.27 UV1.D27
FB_CMD5: length 28.6
  BOTTOM w0.089: 153.18,115.95 153.09,115.87 153.09,115.31 UV1.D26
  BOTTOM w0.127: UV6.L12 166.92,133.11 166.53,132.72 164.19,132.72 163.11,131.64 163.11,124.75 160.95,122.59 v1(159.51,122.59) 155.7,122.59 154.58,121.47 154.58,118.07 153.18,116.66 153.18,115.95
FB_CMD6: length 29.7
  BOTTOM w0.089: 152.34,116.54 152.34,116.02 152.41,115.95 152.41,115.35 152.21,115.16 152.21,114.51 151.8,114.1 UV1.F25
  BOTTOM w0.127: UV6.K4 160.54,132.31 160.94,132.71 162.3,132.71 162.72,132.3 162.72,125.07 160.74,123.1 155.73,123.1 155.6,123.22 155.6,123.45 155.47,123.58 155.09,123.58 154.96,123.45 154.96,123.22 154.84,123.1 v1(154.58,123.1) 154.38,123.1 154.08,122.79 154.08,118.28 152.34,116.54
FB_CMD7: length 28.7
  BOTTOM w0.089: 152,116.92 152,116.03 152.18,115.85 152.18,115.49 151.8,115.11 UV1.F26
  BOTTOM w0.127: 152,116.92 153.57,118.49 153.57,124.65 154.05,125.13 v1(155.09,125.13) 155.98,125.13 157.5,123.6 160.53,123.6 162.36,125.43 162.36,131.85 161.9,132.31 UV6.K5
FB_CMD8: length 31.6
  TOP w0.089: 151.88,116.59 151.88,113.61 151.4,113.12 v3(151.4,112.9)
  TOP w0.127: v3(160.93,131.11) 161.02,131.02 162.55,131.02 163.01,130.56 v1(163.01,127.4) 163.01,125.51 160.25,122.75 158.41,122.75 158.12,122.46 157.53,122.46 156.33,121.26 156.33,120.86 157.36,119.83 157.36,119.65 157.09,119.38 156.91,119.38 155.88,120.41 155.7,120.41 155.43,120.14 155.43,119.96 155.75,119.65 155.75,119.45 155.49,119.19 155.31,119.19 154.99,119.51 154.81,119.51 151.88,116.59
  BOTTOM w0.127: UV6.J4 160.53,131.51 v3(160.93,131.11) ; UV1.F23 v3(151.4,112.9)
FB_CMD9: length 33.5
  TOP w0.089: v3(151.4,112.12) 151.4,112.37 151.84,112.81 151.84,113.18 152.31,113.65 152.31,116.29
  TOP w0.127: 152.31,116.29 154.73,118.72 157.42,118.72 157.87,119.18 157.87,120.01 158.22,120.36 158.22,120.54 157.57,121.2 157.57,121.38 157.84,121.65 158.02,121.65 158.67,120.99 158.85,120.99 159.12,121.26 159.12,121.44 158.83,121.73 158.83,122.01 159.18,122.37 160.59,122.37 163.41,125.2 v1(163.41,125.69) 163.41,132.23 163.25,132.39 161.91,132.39 161.75,132.23 161.75,131.6 v3(161.84,131.51)
  BOTTOM w0.127: UV1.G22 151,111.72 v3(151.4,112.12) ; UV6.J5 161.84,131.51 v3(161.84,131.51)
FB_CMD10: length 32.8
  TOP w0.089: 150.98,117.12 150.98,113.3 v3(150.58,112.9)
  TOP w0.127: v3(160.93,130.31) 160.74,130.12 160.74,129.53 160.93,129.34 161.81,129.34 162.22,128.93 162.22,125.95 160.35,124.08 156.7,124.08 155.48,122.86 155.37,122.86 v1(155.13,122.62) 154.24,121.73 154.24,120.86 154.36,120.74 154.36,120.51 154.1,120.25 153.88,120.25 152.52,121.61 152.29,121.61 151.98,121.3 151.98,121.07 153.34,119.71 153.34,119.48 153.13,119.28 152.9,119.28 152.37,119.81 152.14,119.81 151.91,119.58 151.91,119.31 152.43,118.8 152.43,118.57 150.98,117.12
  BOTTOM w0.127: v3(150.58,112.9) 150.98,112.5 UV1.G23 ; v3(160.93,130.31) 160.53,130.71 UV6.H4
FB_CMD11: length 30.1
  TOP w0.089: 151.45,116.88 151.45,113.75 v3(151.41,113.71)
  TOP w0.127: v3(161.82,130.41) 161.87,130.41 162.58,129.69 162.58,125.8 160.35,123.57 158.13,123.57 157.86,123.29 157.65,123.29 157.33,123.61 157.12,123.61 156.97,123.46 156.97,123.25 v1(157.12,123.1) 157.29,122.93 157.29,122.72 157.08,122.52 156.87,122.52 156.4,122.99 156.19,122.99 156.04,122.85 156.04,122.64 156.51,122.16 156.51,121.95 156.36,121.8 156.15,121.8 155.68,122.28 155.47,122.28 155.32,122.13 155.32,121.92 155.79,121.44 155.79,121.23 155.65,121.08 155.43,121.08 154.96,121.56 154.75,121.56 154.6,121.41 154.6,121.2 155.08,120.72 155.08,120.51 151.45,116.88
  BOTTOM w0.127: v3(161.82,130.41) 161.52,130.71 UV6.H5 ; UV1.G24 v3(151.41,113.71)
FB_CMD12: length 27.8
  BOTTOM w0.127: UV1.F27 151.63,115.87 151.63,117.27 153.06,118.7 153.06,128.06 153.19,128.19 v1(153.92,128.19) 154.61,128.19 154.74,128.32 154.74,128.7 154.61,128.82 153.19,128.82 153.06,128.95 153.06,129.98 153.37,130.29 153.71,130.29 153.86,130.14 153.86,129.59 153.99,129.46 154.37,129.46 154.49,129.59 154.49,130.41 154.62,130.54 155,130.54 155.13,130.41 155.13,129.59 155.26,129.46 157.19,129.46 158.04,130.31 159.34,130.31 UV6.G3
FB_CMD13: length 28.5
  BOTTOM w0.089: 151.18,116.05 151.39,115.84 151.39,114.49 UV1.G25
  BOTTOM w0.127: 151.18,116.05 151.18,117.54 151.31,117.67 151.31,119.59 151.46,119.74 152.37,119.74 152.51,119.89 152.51,120.1 152.37,120.25 151.46,120.25 151.31,120.4 151.31,120.61 151.46,120.76 152.37,120.76 152.51,120.91 152.51,121.12 152.37,121.27 151.46,121.27 151.31,121.42 151.31,121.61 151.43,121.74 152.39,121.74 152.55,121.9 v2(152.55,126.08) 152.55,130.19 153.44,131.08 RV2438.2 155.82,131.1 158.53,131.1 158.93,131.51 UV6.J2
FB_CMD14: length 30.1
  BOTTOM w0.102: UV6.J3 159.73,131.53 159.34,131.92
  BOTTOM w0.127: UV1.G27 150.8,115.9 150.8,122.31 151.03,122.54 151.51,122.54 151.66,122.69 151.66,122.99 151.49,123.17 150.95,123.17 150.8,123.32 150.8,123.7 150.93,123.83 151.92,123.83 152.04,123.95 152.04,124.34 151.92,124.46 150.93,124.46 150.8,124.59 150.8,124.97 150.93,125.1 151.92,125.1 152.04,125.22 152.04,125.61 151.92,125.73 150.93,125.73 150.8,125.86 150.8,126.37 150.93,126.5 151.82,126.5 152.04,126.73 v1(152.04,129.39) 152.04,130.4 153.1,131.46 154.97,131.46 RV2439.1 156.65,132.06 156.79,131.92 159.34,131.92
FB_CMD15: length 30.8
  BOTTOM w0.102: UV1.G26 151,115.21 150.66,115.56 150.66,115.66 150.29,116.02
  BOTTOM w0.127: 150.29,116.02 150.29,124.29 150.29,124.29 v1(150.29,125.46) 150.29,126.88 150.42,127.01 151.41,127.01 151.54,127.14 151.54,127.52 151.41,127.64 150.42,127.64 150.29,127.77 150.29,128.15 150.42,128.28 151.41,128.28 151.54,128.41 151.54,128.79 151.41,128.91 150.56,128.91 150.44,129.04 150.44,129.39 150.6,129.55 151.37,129.55 151.49,129.67 151.49,130.44 154.37,133.33 156.71,133.33 157.31,132.72 159.33,132.72 UV6.L3
FB_CMD16: length 26.8
  TOP w0.089: v3(147.24,112.89) 147.42,113.07 147.42,115.14 ; v3(136.29,130.51) v1(137.63,130.51) 137.82,130.51 138.32,130.01 138.32,126.38
  TOP w0.127: 147.42,115.14 147.57,115.29 147.57,115.76 146.96,116.38 146.96,117.86 142.58,122.24 139.88,122.24 139.38,122.74 139.27,122.74 137.55,124.46 137.55,125.61 138.32,126.38
  BOTTOM w0.127: v3(147.24,112.89) 146.84,113.29 UV1.M24 ; v3(136.29,130.51) 135.88,130.91 UV7.L12
FB_CMD17: length 27.5
  TOP w0.089: 138.68,126.22 138.68,131.06 v3(138.02,131.71) ; v3(147.26,112.09) 147.67,112.5 147.67,114.65 148.22,115.2
  TOP w0.127: 138.68,126.22 138.05,125.6 138.05,124.63 v1(139.44,123.25) 140.08,122.6 142.8,122.6 147.52,117.88 147.52,117.15 148.22,116.45 148.22,115.2
  BOTTOM w0.127: v3(147.26,112.09) 146.85,112.5 UV1.M23 ; UV7.K10 138.02,131.71 v3(138.02,131.71)
FB_CMD18: length 28
  TOP w0.089: v3(148.12,113.69) 148.51,114.08 148.51,116.85 ; 138.99,125.96 138.99,131.77 138.64,132.12 v3(136.27,132.12)
  TOP w0.127: 148.51,116.85 148.03,117.33 148.03,117.88 142.95,122.96 v1(141.72,122.96) 140.44,122.96 138.56,124.84 138.56,125.54 138.99,125.96
  BOTTOM w0.127: UV1.K24 148.51,113.3 v3(148.12,113.69) ; v3(136.27,132.12) 136.67,131.71 UV7.K11
FB_CMD19: length 29.3
  TOP w0.089: v3(148.91,112.9) 148.78,113.03 148.78,117.3 ; 139.27,125.62 139.27,133.19 138.74,133.72 v3(137.09,133.72)
  TOP w0.127: 139.27,125.62 139.07,125.42 139.07,125.05 v1(139.39,124.74) 140.56,123.56 142.86,123.56 148.54,117.88 148.54,117.54 148.78,117.3
  BOTTOM w0.127: UV1.K23 148.52,112.51 v3(148.91,112.9) ; UV7.H11 136.69,133.31 v3(137.09,133.72)
FB_CMD20: length 25.7
  BOTTOM w0.127: UV1.M27 146.19,116.35 146.19,118.45 145.56,119.08 143.73,119.08 141.27,121.54 141.27,122.52 139.54,124.25 139.36,124.25 v1(138.86,123.75) 138.52,123.4 138.34,123.4 138.03,123.71 138.03,123.82 138.91,124.7 138.91,124.88 138.59,125.2 138.59,133.13 138.41,133.31 137.48,133.31 UV7.H10
FB_CMD21: length 27.1
  BOTTOM w0.089: UV1.M26 146.84,115.14 147.22,115.52 147.22,115.86 146.71,116.38
  BOTTOM w0.127: UV7.G12 136.29,134.52 138.32,134.52 139.1,133.74 139.1,125.41 v1(141.38,123.13) 141.78,122.73 141.78,121.75 143.94,119.59 145.77,119.59 146.71,118.65 146.71,116.38
FB_CMD22: length 29.3
  BOTTOM w0.089: UV1.M25 147.26,114.52 147.26,115.18 147.47,115.39 147.47,116.02 147.22,116.28
  BOTTOM w0.127: UV7.H4 142.28,133.31 141.88,133.72 139.78,133.72 139.6,133.54 139.6,125.62 140.85,124.38 141.28,124.38 141.41,124.25 141.41,123.82 141.54,123.69 141.92,123.69 142.05,123.82 142.05,124.25 142.17,124.38 142.72,124.38 142.85,124.25 v1(142.85,121.67) 142.85,121.19 144.09,119.94 146.16,119.94 147.22,118.89 147.22,116.28
FB_CMD23: length 29.9
  BOTTOM w0.089: 148.18,116.46 148.18,116.03 148.13,115.98 148.13,115.29 148.52,114.9 UV1.K26
  BOTTOM w0.127: UV7.H5 140.89,133.31 140.89,133.32 140.13,132.56 140.13,125.84 141.09,124.88 145.39,124.88 145.54,124.73 145.54,124.33 145.41,124.21 143.48,124.21 143.36,124.08 143.36,123.7 143.48,123.57 145.41,123.57 145.54,123.45 v1(145.54,121.11) 145.54,120.48 145.72,120.3 146.52,120.3 147.72,119.1 147.72,116.92 148.18,116.46
FB_CMD24: length 29.7
  TOP w0.089: v3(141.88,132.92) 139.8,132.92 139.58,132.7 v1(139.58,132.28) 139.58,125.26 ; 149.05,116.53 149.05,113.42 149.32,113.15 149.32,112.5 v3(148.92,112.1)
  TOP w0.127: 139.58,125.26 140.92,123.92 143.01,123.92 148.9,118.03 148.9,117.69 149.19,117.4 149.19,116.67 149.05,116.53
  BOTTOM w0.127: v3(148.92,112.1) 148.52,111.7 UV1.K22 ; UV7.J4 142.28,132.52 v3(141.88,132.92)
FB_CMD25: length 26.4
  TOP w0.089: v3(149.72,112.9) 149.72,113.17 149.32,113.57 149.32,116.29
  TOP w0.127: 149.32,116.29 149.55,116.52 149.55,117.88 v1(143.16,124.27) 141.71,124.27 139.91,126.07 139.91,131.78 140.65,132.52 v3(140.92,132.52)
  BOTTOM w0.127: v3(140.92,132.52) 140.92,132.51 UV7.J5 ; UV1.J23 v3(149.72,112.9)
FB_CMD26: length 25.1
  TOP w0.089: v3(141.87,132.11) 140.75,132.11 140.48,131.84 ; 149.74,116.19 v3(149.74,114.5)
  TOP w0.127: 149.74,116.19 150.06,116.51 150.06,117.88 143.18,124.75 141.73,124.75 140.27,126.22 v1(140.27,129.06) 140.27,131.63 140.48,131.84
  BOTTOM w0.127: UV1.J25 149.34,114.1 v3(149.74,114.5) ; UV7.K4 142.27,131.71 v3(141.87,132.11)
FB_CMD27: length 24.6
  TOP w0.089: 150.57,115.32 150.16,114.91 150.16,114.24 149.74,113.82 v3(149.74,113.72)
  TOP w0.127: 150.57,115.32 150.57,117.88 v1(144.85,123.59) 143.33,125.11 141.88,125.11 140.63,126.37 140.63,131.43 v3(140.91,131.71)
  BOTTOM w0.127: UV7.K5 v3(140.91,131.71) ; v3(149.74,113.72) 149.32,113.3 UV1.J24
FB_CMD28: length 21.8
  BOTTOM w0.089: UV1.K27 148.63,115.81 148.63,116.74
  BOTTOM w0.127: UV7.L3 143.08,130.92 143.52,131.36 145.03,131.36 145.07,131.32 145.19,131.32 147.88,128.63 147.88,126.48 147.07,125.67 147.07,124.59 146.94,124.46 146.18,124.46 146.05,124.33 146.05,123.95 146.18,123.83 146.94,123.83 147.07,123.7 v1(147.07,122.78) 147.07,120.47 148.23,119.31 148.23,117.14 148.63,116.74
FB_CMD29: length 25
  BOTTOM w0.127: UV7.J2 143.88,132.51 144.27,132.12 146.94,132.12 RV2437.2 147.28,131.96 147.28,131.89 147.75,131.41 147.75,129.44 148.39,128.8 148.39,125.65 148.26,125.52 147.73,125.52 147.6,125.4 147.6,125.01 147.73,124.89 148.26,124.89 148.39,124.76 148.39,124.38 148.26,124.25 147.7,124.25 147.57,124.13 147.57,123.74 147.7,123.62 148.26,123.62 148.39,123.49 v1(148.39,121) 148.39,119.87 148.74,119.52 148.74,117.27 148.91,117.1 148.91,114.49 UV1.K25
FB_CMD30: length 28.8
  BOTTOM w0.127: UV7.J3 143.08,132.52 143.49,132.92 146.6,132.92 146.64,132.97 RV2440.1 148.86,132.97 149.27,132.56 149.27,131.43 149.15,131.3 148.39,131.3 148.26,131.17 148.26,130.79 148.39,130.67 149.15,130.67 149.27,130.54 149.27,130.16 149.15,130.03 148.51,130.03 148.39,129.9 148.39,129.52 148.51,129.4 149.15,129.4 149.27,129.27 149.27,128.75 149.15,128.63 149.02,128.63 148.89,128.5 148.89,128.12 149.02,127.99 149.15,127.99 149.27,127.87 149.27,127.48 149.15,127.36 149.02,127.36 148.89,127.23 148.89,126.85 149.02,126.72 149.15,126.72 149.27,126.6 149.27,126.21 149.15,126.09 149.02,126.09 148.89,125.96 148.89,125.58 149.02,125.45 149.15,125.45 149.27,125.33 149.27,124.94 149.15,124.82 149.02,124.82 148.89,124.69 148.89,124.31 149.02,124.18 149.15,124.18 149.27,124.06 149.27,123.67 149.15,123.55 149.02,123.55 148.9,123.43 148.9,120.14 149.27,119.76 v1(149.27,118.74) 149.27,117.59 149.3,117.56 149.3,115.72 UV1.J27
FB_CMD31: length 31.8
  BOTTOM w0.089: 149.71,115.86 149.71,115.29 UV1.J26
  BOTTOM w0.127: UV7.G3 143.47,133.72 149.71,133.72 149.83,133.59 149.83,132.03 149.96,131.9 150.34,131.9 150.47,132.03 150.47,133.59 150.6,133.72 151.49,133.72 151.68,133.53 151.68,132.47 149.78,130.58 v1(149.78,122.84) 149.78,115.93 149.71,115.86
FB_CORE: length 5.5
  BOTTOM w0.203: PCZ12.1 200.71,66.83 v1(200.71,67.52) 200.01,68.22 PUZ1.3
  BOTTOM w0.254: PRZ43.2 PCZ11.2 201.02,65.63 PRZ45.1 PCZ12.1
FB_D0: length 21.5
  IN2 w0.089: 156.23,110.31 156.14,110.23 156.14,109.62 155.67,109.14 154.34,109.14 v3(153.9,108.71)
  IN2 w0.157: 156.23,110.31 158.17,112.25 158.17,121.81 160.39,124.03 160.39,124.51 160.2,124.7 v3(160.15,124.7)
  BOTTOM w0.127: UV1.E18 152.7,108.32 153.09,108.71 v3(153.9,108.71) ; v3(160.15,124.7) 160.19,124.73 160.19,124.77 UV6.A4
FB_D1: length 20.3
  IN2 w0.089: v3(152.27,108.79) 152.86,108.79 154.25,110.19 154.25,110.19 154.28,110.22 154.28,111.36 155.09,112.17 155.09,113.53 155.09,113.53 155.09,113.86 155.09,113.86 155.09,115.11 155.1,115.13 155.1,115.67 155.09,115.67
  IN2 w0.157: v3(158.37,124.55) 157.9,124.09 157.58,124.09 155.09,121.6 155.09,115.67
  BOTTOM w0.127: UV6.A2 v3(158.37,124.55) ; UV1.F18 151.86,108.38 v3(152.27,108.79)
FB_D2: length 24.2
  IN2 w0.089: v3(152.28,107.06) 153.52,108.3 154.07,108.3 154.08,108.31 154.09,108.31 154.6,108.82 155.71,108.82 156.49,109.59 156.49,109.92
  IN2 w0.157: v3(160.93,125.52) 160.91,125.49 160.91,123.81 158.8,121.71 158.8,112.23 156.49,109.92
  BOTTOM w0.127: UV1.E16 v3(152.28,107.06) ; UV6.B4 v3(160.93,125.52)
FB_D3: length 23
  IN2 w0.089: 156.06,112.46 155.12,111.52 155.12,110.27 154.89,110.04 154.58,110.04 154.29,109.74 152.91,108.36 151.92,108.36 v3(151.49,107.93)
  IN2 w0.157: v3(159.33,125.5) 158.83,124.99 158.83,124.35 158.09,123.62 157.77,123.62 156.06,121.91 156.06,112.46
  BOTTOM w0.127: v3(151.49,107.93) 151.86,107.55 UV1.F17 ; UV6.B2 158.93,125.9 v3(159.33,125.5)
FB_D4: length 22.3
  IN2 w0.089: v3(160.14,127.92) 159.72,127.51 159.09,127.51 158.87,127.29 158.87,126.79 158.98,126.68 158.98,126.14 158.59,125.76 158.13,125.76 ; v3(153.88,110.39) 153.88,111.51 153.49,111.89 153.49,112.22 153.48,112.23 153.48,115.04
  IN2 w0.157: 158.13,125.76 153.94,121.57 153.94,115.49 153.48,115.04
  BOTTOM w0.127: v3(153.88,110.39) 153.5,110.02 UV1.D20 ; UV6.E4 v3(160.14,127.92)
FB_D5: length 22
  IN2 w0.089: 151.89,113.61 151.82,113.54 151.82,111.91 152.09,111.64 152.45,111.64 152.91,111.18 v3(153.1,111.18)
  IN2 w0.157: 151.89,113.61 151.89,122.2 156.93,127.23 157.85,127.23 v3(158.52,127.91)
  BOTTOM w0.127: v3(153.1,111.18) 153.48,110.8 UV1.D21 ; UV6.E2 v3(158.52,127.91)
FB_D6: length 28.1
  IN2 w0.089: v3(152.27,110.39) 151.97,110.7 151.75,110.7 150.73,111.72 150.41,111.72 150.16,111.97 150.16,114.69
  IN2 w0.157: v3(160.13,129.51) 159.98,129.51 159.5,130 157.02,130 150.86,123.84 150.86,115.39 150.16,114.69
  BOTTOM w0.127: v3(152.27,110.39) 151.86,109.98 UV1.F20 ; UV6.F4 v3(160.13,129.51)
FB_D7: length 24.4
  IN2 w0.089: v3(152.3,111.2) 151.77,111.2 150.99,111.98 150.99,114.21
  IN2 w0.157: 150.99,114.21 151.38,114.6 151.38,123.09 157.09,128.81 159.24,128.81 v3(159.34,128.71)
  BOTTOM w0.127: UV1.E21 v3(152.3,111.2) ; v3(159.34,128.71) 158.94,129.11 UV6.F2
FB_D8: length 28.6
  IN2 w0.089: v3(153.11,106.2) 153.5,105.81 154.07,105.81 154.33,106.07 154.33,106.36 154.64,106.68 156.02,106.68 156.58,107.24
  IN2 w0.157: v3(166.28,124.47) 165.89,124.08 163.95,124.08 160.58,120.72 160.58,111.14 159.01,109.56 159.01,108.73 157.52,107.24 156.58,107.24
  BOTTOM w0.127: v3(166.28,124.47) 166.13,124.62 UV6.A11 ; v3(153.11,106.2) 152.75,105.84 UV1.E15
FB_D9: length 28.3
  IN2 w0.089: 166.82,123.73 166.82,124.4 v3(166.88,124.47) ; 157.57,106.63 157.1,106.17 155.95,106.17 155.63,105.85 155.13,105.85 155.12,105.83 154.49,105.83 154.06,105.4 v3(153.91,105.4)
  IN2 w0.157: 157.57,106.63 159.47,108.53 159.47,109.29 161.04,110.86 161.04,118.81 164.22,121.99 165.44,121.99 166.82,123.36 166.82,123.73
  BOTTOM w0.127: UV6.A13 167.09,124.47 v3(166.88,124.47) ; UV1.D15 153.5,105.81 v3(153.91,105.4)
FB_D10: length 29.2
  IN2 w0.089: 157.54,108.31 156.77,108.31 156.52,108.07 156.52,107.67 155.92,107.06 155.39,107.06 154.97,107.48 154.55,107.48 154.3,107.23 154.3,106.89 154.02,106.61 152.63,106.61 v3(152.31,106.29)
  IN2 w0.157: 157.54,108.31 158.54,109.31 158.54,109.76 160.12,111.33 160.12,120.91 164.72,125.51 v3(165.73,125.51)
  BOTTOM w0.127: UV6.B11 v3(165.73,125.51) ; UV1.F15 v3(152.31,106.29)
FB_D11: length 32.7
  IN2 w0.089: v3(152.31,103.8) 152.31,104.46 152.85,105.01 155.08,105.01 155.35,105.27 155.81,105.27 156.05,105.03 157.59,105.03 ; 168.08,124.27 168.08,125.47 v3(168.13,125.52)
  IN2 w0.157: 168.08,124.27 168.2,124.14 168.2,122.82 163.56,118.18 163.56,115.45 162.51,114.4 162.51,110.45 160.8,108.74 160.8,107.98 158.03,105.22 157.77,105.22 157.59,105.03
  BOTTOM w0.102: UV6.B13 167.74,125.91 v3(168.13,125.52)
  BOTTOM w0.127: v3(152.31,103.8) 151.94,104.16 UV1.F13
FB_D12: length 37
  IN2 w0.089: v3(154.7,103.75) 154.92,103.75 155.33,104.16 155.67,104.16 155.7,104.14 155.7,104.14 156.36,103.48 ; v3(166.54,127.92) 166.91,127.54 168.62,127.54 168.75,127.41
  IN2 w0.157: 168.75,127.41 169.33,127.41 169.76,126.98 169.76,122.49 164.89,117.63 164.89,114.1 163.87,113.08 163.87,109.93 162.13,108.19 162.13,107.43 158.18,103.48 156.36,103.48
  BOTTOM w0.127: UV6.E11 166.14,128.31 v3(166.54,127.92) ; v3(154.7,103.75) 154.3,104.15 UV1.C13
FB_D13: length 37.3
  IN2 w0.089: 156.3,103.07 155.62,103.75
  IN2 w0.157: 156.3,103.07 156.35,103.01 158.37,103.01 162.59,107.24 162.59,107.99 164.34,109.74 164.34,112.89 165.36,113.91 165.36,117.44 170.22,122.3 170.22,127.72 169.65,128.29 167.74,128.29 v3(167.32,128.72) ; 155.62,103.75 v3(155.5,103.75)
  BOTTOM w0.127: UV6.E13 167.72,128.31 v3(167.32,128.72) ; UV1.B13 155.1,104.16 v3(155.5,103.75)
FB_D14: length 44.6
  IN2 w0.089: v3(153.11,103.76) 153.49,103.05 153.49,102.91 153.58,102.71 153.73,102.56 153.9,102.52 154.13,102.52
  IN2 w0.157: 154.13,102.52 155.37,102.42 155.41,102.41 155.53,102.4 155.77,102.38 156.06,102.09 158.75,102.09 163.52,106.86 163.52,107.61 165.26,109.35 165.26,112.5 166.31,113.56 166.31,117.08 171.56,122.34 171.56,127.89 169.78,129.68 168.24,129.68 v3(168.09,129.52)
  BOTTOM w0.127: v3(153.11,103.76) 152.71,104.16 UV1.E13 ; UV6.F11 166.44,129.11 166.85,129.52 v3(168.09,129.52)
FB_D15: length 40.3
  IN2 w0.089: 156.05,102.74 156.05,102.96 155.66,103.34 154.31,103.34 v3(153.91,103.74)
  IN2 w0.157: v3(168.13,128.77) 168.58,129.22 169.59,129.22 170.88,127.92 170.88,122.3 165.85,117.28 165.85,113.75 164.8,112.7 164.8,109.54 163.06,107.8 163.06,107.05 158.56,102.55 156.23,102.55 156.05,102.74
  BOTTOM w0.127: v3(168.13,128.77) 168.11,128.79 168.06,128.79 UV6.F13 ; UV1.D13 153.5,104.15 v3(153.91,103.74)
FB_D16: length 51.8
  IN1 w0.089: 156.63,105.03 157.24,105.03 157.44,104.83
  IN1 w0.102: v3(156.23,105.43) 156.63,105.03
  IN1 w0.157: v3(166.53,137.52) 166.86,137.86 166.86,138.49 167.34,138.97 168.16,138.97 168.72,138.41 170.37,138.41 172.47,136.31 172.47,135.51 172.97,135.01 172.97,131.87 173.21,131.63 173.21,123.55 170.43,120.77 170.34,120.77 167.52,117.95 167.52,117.41 166.39,116.29 166.39,115.21 166.64,114.96 166.64,110.85 166.46,110.66 166.46,110.64 164.88,109.07 164.86,109.07 163.67,107.87 163.54,107.87 160.49,104.83 157.44,104.83
  BOTTOM w0.127: UV1.B15 155.51,105.43 v3(156.23,105.43) ; v3(166.53,137.52) UV6.U11
FB_D17: length 46.9
  IN1 w0.089: 169.33,136.53 168.9,136.53 168.6,136.83 168.6,137.04 v3(168.12,137.52) ; 157.78,105.76 157.73,105.76 157.54,105.95 155.88,105.95 155.74,105.82 155.18,105.82 v3(154.75,106.24)
  IN1 w0.157: 169.33,136.53 169.43,136.63 170.69,136.63 171.55,135.77 171.55,135.13 172.05,134.63 172.05,131.48 172.28,131.25 172.28,123.93 170.05,121.69 169.95,121.69 166.6,118.34 166.6,117.8 165.47,116.67 165.47,114.83 165.72,114.58 165.72,111.23 165.53,111.04 165.53,111.03 164.5,109.99 164.48,109.99 163.29,108.8 163.15,108.8 160.12,105.76 157.78,105.76
  BOTTOM w0.127: v3(154.75,106.24) 154.7,106.24 UV1.C16 ; UV6.U13 v3(168.12,137.52)
FB_D18: length 53.5
  IN1 w0.157: v3(156.33,104.61) 156.33,104.6 156.66,104.27 156.7,104.27 156.77,104.2 157.11,104.2 157.27,104.37 160.69,104.37 163.73,107.42 163.88,107.42 167.11,110.64 167.11,115.15 166.85,115.4 166.85,116.1 167.98,117.22 167.98,117.76 170.53,120.31 170.62,120.31 173.67,123.36 173.67,131.9 173.44,132.13 173.44,135.2 172.93,135.71 172.93,136.5 170.47,138.97 168.9,138.97 168.44,139.43 167.15,139.43 166.4,138.68 166.4,138.18 v3(165.73,137.51)
  BOTTOM w0.127: v3(156.33,104.61) 155.9,104.18 UV1.A13 ; v3(165.73,137.51) 166.13,137.11 UV6.T11
FB_D19: length 48.2
  IN1 w0.089: v3(157.4,105.49) 157.6,105.3
  IN1 w0.157: 157.6,105.3 160.3,105.3 163.34,108.34 163.48,108.34 164.67,109.53 164.69,109.53 165.99,110.83 165.99,110.85 166.18,111.04 166.18,114.77 165.93,115.02 165.93,116.48 167.06,117.61 167.06,118.14 170.15,121.23 170.24,121.23 172.75,123.74 172.75,131.44 172.51,131.68 172.51,134.82 172.01,135.32 172.01,136.04 170.57,137.47 168.83,137.47 168.25,138.06 167.57,138.06 167.34,138.28 v3(167.34,138.32)
  BOTTOM w0.127: UV1.A15 155.94,105.88 157.01,105.88 v3(157.4,105.49) ; v3(167.34,138.32) 167.32,138.3 167.32,137.52 UV6.T13
FB_D20: length 39.4
  IN1 w0.089: 169.33,134.4 168.7,134.4 168.38,134.71 166.94,134.71 v3(166.53,135.12) ; 157.95,107.7 157.7,107.44 156.5,107.44 v3(156.11,107.83)
  IN1 w0.157: 169.33,134.4 170.05,133.68 170.05,124.52 169.22,123.69 169.13,123.69 164.6,119.16 164.6,118.63 163.47,117.5 163.47,112.54 159.12,108.2 158.67,108.2 158.17,107.7 157.95,107.7
  BOTTOM w0.127: UV6.N11 166.13,134.72 v3(166.53,135.12) ; UV1.B18 155.49,107.93 156.02,107.93 v3(156.11,107.83)
FB_D21: length 36.4
  IN1 w0.089: v3(156.93,107.89) 157.33,108.28 158.1,108.28
  IN1 w0.157: 158.1,108.28 158.47,108.66 158.93,108.66 163.01,112.74 163.01,117.69 164.14,118.82 164.14,119.12 164.14,119.35 164.86,120.08 164.86,120.34 164.5,120.7 164.5,120.96 164.68,121.14 164.94,121.14 165.3,120.78 165.56,120.78 168.94,124.15 169.03,124.15 169.59,124.72 169.59,133.18 169.32,133.46 168.85,133.46 168.15,134.16 v3(168.15,134.27)
  BOTTOM w0.127: UV1.A18 156.5,108.32 156.5,108.32 v3(156.93,107.89) ; UV6.N13 167.73,134.71 168.15,134.29 v3(168.15,134.27)
FB_D22: length 37.5
  IN1 w0.089: v3(165.73,134.31) 166.23,133.81 166.23,133.14 167.03,132.34 167.5,132.34 167.68,132.15
  IN1 w0.157: v3(158.11,109.64) 158.33,109.64 162.05,113.36 162.05,122.55 162.21,122.71 162.52,122.71 162.71,122.53 162.71,122.32 162.89,122.13 163.15,122.13 163.34,122.32 163.34,122.53 163.52,122.71 163.88,122.71 164.03,122.55 164.03,122.31 164.21,122.13 165.61,122.13 166.42,122.95 166.42,123.72 165.77,124.37 165.77,124.77 165.26,125.27 165.26,128.3 167.68,130.72 167.68,131.73 167.69,131.73 167.69,132.09 167.68,132.1 167.68,132.15
  BOTTOM w0.127: UV1.A19 156.42,109.64 v3(158.11,109.64) ; UV6.M11 v3(165.73,134.31)
FB_D23: length 38.4
  IN1 w0.157: v3(157.27,108.77) 157.85,108.77 158.21,109.12 158.7,109.12 162.55,112.97 162.55,121.51 162.7,121.67 163.14,121.67 163.32,121.49 163.32,120.52 163.51,120.34 163.77,120.34 163.95,120.52 163.95,121.49 164.14,121.67 165.8,121.67 168.57,124.44 168.57,132.28 v3(167.33,133.52)
  BOTTOM w0.127: UV6.M13 167.72,133.91 v3(167.33,133.52) ; UV1.C19 154.73,108.69 156.15,108.69 156.28,108.82 157.22,108.82 v3(157.27,108.77)
FB_D24: length 34.7
  IN1 w0.089: 155.99,115.51 155.99,114.18 155.56,113.75
  IN1 w0.157: 155.99,115.51 153,118.5 153,135.79 156.35,139.15 160.65,139.15 160.94,138.85 v3(160.94,138.33) ; 155.56,113.75 155.53,113.71 155.51,113.71 v3(155.5,113.71)
  BOTTOM w0.127: v3(155.5,113.71) 155.1,113.3 UV1.B24 ; UV6.U4 160.53,137.92 v3(160.94,138.33)
FB_D25: length 33.3
  IN1 w0.089: 156.44,115.72 156.44,114.02 155.7,113.28 155.06,113.28 154.69,112.91 154.69,112.89 154.68,112.88 v3(154.68,112.87) ; v3(158.95,138.68) 158.95,138.38 158.6,138.03 157.52,138.03 157.42,137.93 157.04,137.93
  IN1 w0.157: 157.04,137.93 156.91,138.06 156,138.06 153.53,135.59 153.53,118.62 156.44,115.72
  BOTTOM w0.127: v3(158.95,138.68) 158.93,138.66 UV6.U2 ; UV1.C23 154.3,112.48 v3(154.68,112.87)
FB_D26: length 30.7
  IN1 w0.089: 157.22,137.39 157.37,137.55 158.54,137.55 158.97,137.13 159.74,137.13 v3(160.12,137.51)
  IN1 w0.157: 157.22,137.39 156.07,137.39 154.07,135.39 154.07,118.75 156.83,115.98 v3(156.87,115.98)
  BOTTOM w0.127: UV6.T4 160.52,137.11 v3(160.12,137.51) ; v3(156.87,115.98) 156.43,115.54 156.43,114.63 UV1.A25
FB_D27: length 30.2
  IN1 w0.089: 157.06,136.79 157.24,136.79 157.44,136.58 157.98,136.58 158.21,136.35 158.97,136.35 v3(159.33,136.71)
  IN1 w0.157: v3(156.88,114.76) 156.96,114.76 157.34,115.14 157.34,116.75 154.63,119.47 154.63,132.11 155.11,132.6 155.11,135.77 156.12,136.79 157.06,136.79
  BOTTOM w0.127: UV1.A24 156.23,113.62 156.23,113.77 156.52,114.07 156.78,114.07 156.91,114.2 156.91,114.72 v3(156.88,114.76) ; UV6.T2 v3(159.33,136.71)
FB_D28: length 30.2
  IN1 w0.089: 156.33,111.26 156.33,111.81 157.1,112.58 157.26,112.58 159.34,114.66 ; v3(160.12,134.3) 159.73,134.69 158.17,134.69 157.86,134.37 157.39,134.37 157.1,134.08
  IN1 w0.157: v3(156.38,111.21) 156.33,111.26 ; 157.1,134.08 157.1,131.77 156.62,131.29 156.62,120.3 159.34,117.58 159.34,114.66
  BOTTOM w0.127: v3(156.38,111.21) 155.98,110.8 UV1.A21 ; UV6.N4 v3(160.12,134.3)
FB_D29: length 29.1
  IN1 w0.157: v3(158.54,134.24) 158.05,133.75 158.05,130.56 157.08,129.59 157.08,120.49 159.8,117.77 159.8,114.42 157.47,112.09 157.37,112.09 v3(157.34,112.07)
  BOTTOM w0.127: v3(157.34,112.07) 157.34,111.5 156.17,110.33 155.57,110.33 UV1.B21 ; UV6.N2 158.54,134.32 v3(158.54,134.24)
FB_D30: length 30.2
  IN1 w0.157: v3(160.94,133.51) 162.4,132.05 162.4,125.83 160.35,123.77 160.35,118.53 160.46,118.42 160.73,118.15 160.73,113.99 157.83,111.1 157.58,111.1 156.48,110 155.16,110 v3(154.71,110.46)
  BOTTOM w0.127: UV6.M4 160.54,133.91 v3(160.94,133.51) ; v3(154.71,110.46) 154.3,110.05 UV1.C20
FB_D31: length 29.4
  IN1 w0.157: v3(159.34,133.53) 158.79,132.99 158.79,130.59 157.96,129.75 157.96,129.15 158.05,129.05 158.05,125.65 158.83,124.87 158.83,119.4 160.26,117.96 160.26,114.18 157.64,111.56 157.39,111.56 156.34,110.51 155.38,110.51 v3(154.7,111.2)
  BOTTOM w0.127: UV6.M2 158.95,133.91 v3(159.34,133.53) ; UV1.C21 v3(154.7,111.2)
FB_D32: length 16
  IN2 w0.089: 143.45,114.41 143.78,114.09 144.12,114.09 144.37,113.83 144.37,112.45 v3(144,112.08)
  IN2 w0.157: v3(142.04,125.59) 142.05,125.59 142.05,125.56 143.45,124.16 143.45,123.92 143.45,123.92 143.45,114.41
  BOTTOM w0.127: UV1.R22 144,112.02 v3(144,112.08) ; v3(142.04,125.59) 142.05,125.59 142.05,125.88 142.28,126.11 UV7.U4
FB_D33: length 14.1
  IN2 w0.089: 143.91,115.83 143.91,115.13 144.39,114.65 144.39,114.31 144.8,113.89 v3(144.8,113.72)
  IN2 w0.157: v3(143.5,125.7) 143.5,124.77 144.4,123.87 144.4,116.5 143.91,116.01 143.91,115.83
  BOTTOM w0.127: v3(144.8,113.72) 144.38,113.3 UV1.R24 ; v3(143.5,125.7) 143.88,126.09 UV7.U2
FB_D34: length 18.5
  IN2 w0.089: 142.99,114.44 143.55,113.87 143.55,111.65 v3(143.14,111.24)
  IN2 w0.157: 142.99,114.44 142.99,114.44 142.99,118.65 142.79,118.84 142.79,124.07 141.42,125.44 141.42,126.85 v3(141.88,127.32)
  BOTTOM w0.127: UV7.T4 142.28,126.92 v3(141.88,127.32) ; UV1.T22 v3(143.14,111.24)
FB_D35: length 16.3
  IN2 w0.089: 146.07,116.57 145.67,116.17 145.67,114.39 145.21,113.92 145.21,113.3 v3(144.79,112.88)
  IN2 w0.157: v3(144.28,126.51) 144.31,126.51 144.88,125.94 144.88,125.8 146.33,124.34 146.33,118.86 146.07,118.6 146.07,116.57
  BOTTOM w0.127: v3(144.79,112.88) 144.41,112.5 UV1.R23 ; UV7.T2 143.88,126.9 v3(144.28,126.51)
FB_D36: length 21.1
  IN2 w0.089: v3(142.68,129.73) 142.68,129.69 143.06,129.31 143.88,129.31 143.97,129.41 145.32,129.41
  IN2 w0.157: 145.32,129.41 145.58,129.41 148.23,126.76 148.23,116.08 147.79,115.65 147.6,115.65 v3(146.44,114.49)
  BOTTOM w0.127: v3(146.44,114.49) 146.05,114.1 UV1.N25 ; UV7.N4 142.28,129.33 v3(142.68,129.73)
FB_D37: length 18
  IN2 w0.089: v3(146.45,115.3) 147.36,116.21 147.36,116.43 147.4,116.48 147.4,116.72 ; 145.46,128.54 143.86,128.54 v3(143.48,128.91)
  IN2 w0.157: 147.4,116.72 147.4,118.04 147.77,118.41 147.77,126.23 145.46,128.54
  BOTTOM w0.102: UV7.N2 v3(143.48,128.91)
  BOTTOM w0.127: UV1.N26 146.04,114.9 v3(146.45,115.3)
FB_D38: length 27.2
  IN2 w0.089: v3(145.61,112.91) 147.31,113.66 147.74,114.1 148.3,114.1
  IN2 w0.157: v3(141.87,130.52) 142.64,130.52 143.28,131.16 145.63,131.16 149.32,127.47 149.32,115.8 148.61,115.09 148.61,114.41 148.3,114.1
  BOTTOM w0.127: UV7.M4 142.28,130.11 v3(141.87,130.52) ; UV1.N23 146.01,112.5 v3(145.61,112.91)
FB_D39: length 21.6
  IN2 w0.089: 145.87,130.27 144.53,130.27 v3(144.29,130.51)
  IN2 w0.157: 145.87,130.27 148.78,127.35 148.78,115.93 146.54,113.69 v3(146.44,113.69)
  BOTTOM w0.127: UV1.N24 146.05,113.3 v3(146.44,113.69) ; UV7.M2 143.9,130.11 v3(144.29,130.51)
FB_D40: length 17.4
  IN2 w0.089: 141.24,115.64 141.24,113.87 141.9,113.21 141.9,112.48 v3(142.3,112.08)
  IN2 w0.157: 141.24,115.64 140.39,116.49 140.39,119.53 138.31,121.61 138.31,124.3 137.95,124.66 137.95,124.95 137.3,125.61 136.73,125.61 v3(136.68,125.56)
  BOTTOM w0.127: v3(142.3,112.08) UV1.V23 ; UV7.U11 136.68,125.56 v3(136.68,125.56)
FB_D41: length 19
  IN2 w0.089: 139.8,114.25 139.87,114.25 140.25,113.87 140.25,113.53 140.45,113.34 140.79,113.34 141.05,113.08 141.05,112.73 141.34,112.43 141.34,111.42 v3(141.49,111.27)
  IN2 w0.157: 139.8,114.25 137.05,117 137.05,119.91 136.81,120.15 136.33,120.15 134.52,121.96 134.52,125.41 v3(134.64,125.52)
  BOTTOM w0.127: UV1.V22 v3(141.49,111.27) ; UV7.U13 135.08,125.96 v3(134.64,125.52)
FB_D42: length 18.3
  IN2 w0.089: v3(143.14,112.1) 142.71,112.53 142.71,113.13 142.54,113.31 142.15,113.31 141.47,114 141.47,116.06 141.44,116.09
  IN2 w0.157: v3(137.08,126.51) 138.42,125.18 138.42,124.85 138.77,124.49 138.77,121.8 140.96,119.61 140.96,116.57 141.44,116.09
  BOTTOM w0.127: UV7.T11 136.68,126.91 v3(137.08,126.51) ; v3(143.14,112.1) 143.16,112.1 UV1.T23
FB_D43: length 22.3
  IN2 w0.089: v3(142.29,111.28) 141.86,110.85 141.33,110.85 141.07,111.1 141.07,111.89 140.23,112.74 140.23,113.08 140.02,113.29 139.63,113.29
  IN2 w0.157: 139.63,113.29 139.38,113.53 139.38,113.95 136.42,116.92 135.61,116.92 133.63,118.9 133.63,125.46 v3(134.68,126.51)
  BOTTOM w0.127: v3(142.29,111.28) 142.67,111.66 UV1.U22 ; v3(134.68,126.51) UV7.T13
FB_D44: length 25.9
  IN2 w0.089: v3(136.28,128.91) 135.57,129.3 135.04,129.3 ; v3(139.82,112.88) 139.05,112.49 138.7,112.49
  IN2 w0.157: 135.04,129.3 134.91,129.43 133.21,129.43 132.58,128.79 132.58,118.52 136.04,115.06 136.04,114.28 137.92,112.4 138.61,112.4 138.7,112.49
  BOTTOM w0.127: UV7.N11 136.68,129.31 v3(136.28,128.91) ; UV1.Y24 v3(139.82,112.88)
FB_D45: length 21.4
  IN2 w0.157: v3(134.69,128.92) 134.64,128.97 133.47,128.97 133.04,128.54 133.04,118.82 135.4,116.46 135.97,116.46 137.48,114.95 137.48,114.44 v3(139.01,112.91)
  BOTTOM w0.127: v3(134.69,128.92) 135.08,129.31 UV7.N13 ; UV1.AA24 139.4,113.3 v3(139.01,112.91)
FB_D46: length 29.5
  IN2 w0.157: v3(139.81,111.31) 139.28,111.17 138.45,111.17 137.58,111.42 134.44,114.56 134.44,115.13 131.63,117.94 131.63,129.31 133.32,131 134.74,131 134.95,130.91 135.28,130.63 v3(136.27,129.79)
  BOTTOM w0.127: v3(139.81,111.31) 139.89,111.31 UV1.Y22 ; UV7.M11 v3(136.27,129.79)
FB_D47: length 26.3
  IN2 w0.157: v3(139.83,112.1) 139.63,112.1 139.16,111.63 138.85,111.63 138.57,111.91 137.76,111.91 135.58,114.09 135.58,114.76 132.09,118.24 132.09,129.12 133.29,130.32 134.47,130.32 v3(134.67,130.52)
  BOTTOM w0.127: UV7.M13 135.08,130.11 v3(134.67,130.52) ; v3(139.83,112.1) 139.43,112.5 UV1.AA23
FB_D48: length 35.6
  IN1 w0.157: v3(135.76,118.55) 134.19,118.55 128.57,124.18 128.57,135.54 133.52,140.5 135.1,140.5 v3(136.27,139.34)
  BOTTOM w0.089: UV1.AD27 136.9,115.85 135.78,116.97 135.59,116.97 135.33,117.23 135.33,118.22 135.67,118.55 v3(135.76,118.55)
  BOTTOM w0.127: UV7.A11 136.68,138.92 v3(136.27,139.34)
FB_D49: length 35.8
  IN1 w0.089: v3(136.62,119.16) 136.17,119.61
  IN1 w0.157: 136.17,119.61 133.78,119.61 129.03,124.37 129.03,135.35 133.54,139.87 134.2,139.87 v3(134.28,139.79)
  BOTTOM w0.089: v3(136.62,119.16) 136.71,119.16 137.06,118.81 137.06,117.86 137.31,117.61 137.31,117.19 138.15,116.35 138.15,115.52 138.37,115.31 138.7,115.31 138.99,115.01 138.99,114.49 UV1.AB25
  BOTTOM w0.127: v3(134.28,139.79) 134.78,139.79 135.08,139.49 UV7.A13
FB_D50: length 38.9
  IN1 w0.157: v3(137.08,138.52) 137.08,139.52 135.63,140.96 133.33,140.96 128.38,136.01 128.1,135.74 128.1,123.98 134,118.09 134.44,118.09 135.16,117.37 v3(135.79,117.37)
  BOTTOM w0.089: UV1.AD26 137.07,115.07 137.07,115.22 137.33,115.48 137.33,115.94 136.67,116.59 136.53,116.59 135.82,117.3 135.82,117.32 135.79,117.34 v3(135.79,117.37)
  BOTTOM w0.127: UV7.B11 136.68,138.12 v3(137.08,138.52)
FB_D51: length 33.2
  IN1 w0.089: 134.87,120.14 135.69,120.14 v3(135.74,120.1)
  IN1 w0.157: 134.87,120.14 134.33,120.69 133.36,120.69 129.49,124.56 129.49,135.16 133.16,138.83 134.37,138.83 v3(134.67,138.52)
  BOTTOM w0.089: v3(135.74,120.1) 136.19,119.64 136.19,117.25 136.62,116.82 136.77,116.82 137.6,115.98 137.6,115.38 137.34,115.12 137.34,114.51 137.75,114.1 UV1.AC25
  BOTTOM w0.127: UV7.B13 134.68,138.52 134.68,138.52 v3(134.67,138.52)
FB_D52: length 28.8
  IN1 w0.089: 138.07,120.47 v3(138.07,119.17)
  IN1 w0.157: v3(136.27,136.11) 134.56,136.11 134.2,136.47 133.62,136.47 131.82,134.67 131.82,125.42 134.55,122.69 135.85,122.69 138.07,120.47
  BOTTOM w0.089: v3(138.07,119.17) 138.09,119.17 138.54,118.72 138.54,116.71 139.4,115.85 UV1.AA27
  BOTTOM w0.127: UV7.E11 136.67,135.71 v3(136.27,136.11)
FB_D53: length 27.8
  IN1 w0.157: v3(134.65,135.28) 134.39,135.54 133.59,135.54 132.29,134.24 132.29,125.61 134.54,123.35 136.95,123.35 137.37,122.94 137.37,121.83 138.55,120.64 138.55,117.66 138.28,117.39 v3(138.07,117.39)
  BOTTOM w0.089: UV1.AA26 139.4,115.19 139,115.59 139,115.91 138.07,116.84 v3(138.07,117.39)
  BOTTOM w0.127: UV7.E13 v3(134.65,135.28)
FB_D54: length 29.4
  IN1 w0.089: v3(137.09,135.31) 136.66,134.88 134.19,134.88
  IN1 w0.157: 134.19,134.88 133.92,134.61 133.49,134.61 132.75,133.87 132.75,125.91 134.84,123.81 137.15,123.81 137.83,123.13 137.83,122.12 139.01,120.93 v3(139.01,118.62)
  BOTTOM w0.089: UV1.W26 140.84,114.9 140.15,115.59
  BOTTOM w0.127: v3(139.01,118.62) 140.15,117.48 140.15,115.59 ; UV7.F11 136.69,134.91 v3(137.09,135.31)
FB_D55: length 28.8
  IN1 w0.157: v3(139.83,113.69) 139.47,114.05 139.47,121.12 138.29,122.31 138.29,124.12 138.13,124.28 136.74,124.28 136.56,124.46 136.56,124.98 136.37,125.16 136.11,125.16 135.93,124.98 135.93,124.46 135.74,124.28 135.03,124.28 133.21,126.1 133.21,132.29 133.45,132.53 133.99,132.53 134.21,132.76 134.21,134.03 v3(134.66,134.47)
  BOTTOM w0.127: UV7.F13 134.66,134.49 v3(134.66,134.47) ; UV1.Y25 v3(139.83,113.69)
FB_D56: length 35.6
  IN1 w0.157: v3(142.66,139.37) 143.41,140.12 147.11,140.12 151.48,135.75 151.48,124.85 148.42,121.8 148.42,119.05 145.51,116.13 145.11,116.13 144.78,115.8 v3(144.78,115.32)
  BOTTOM w0.127: UV1.R26 v3(144.78,115.32) ; v3(142.66,139.37) 142.28,138.99 UV7.A4
FB_D57: length 33.7
  IN1 w0.157: v3(144.45,139.49) 144.55,139.59 146.9,139.59 150.94,135.55 150.94,124.97 147.96,121.99 147.96,119.32 145.27,116.63 144.95,116.63 143.95,115.63 143.95,114.53 v3(143.96,114.51)
  BOTTOM w0.127: UV7.A2 v3(144.45,139.49) ; UV1.T25 143.56,114.11 v3(143.96,114.51)
FB_D58: length 31.4
  IN1 w0.089: v3(142.68,137.72) 143.08,138.12 143.84,138.12 144.03,138.3
  IN1 w0.157: v3(144.93,118.3) 146.61,119.97 146.61,122.32 149.81,125.52 149.81,135.21 146.43,138.59 145.07,138.59 144.78,138.3 144.03,138.3
  BOTTOM w0.111: v3(142.68,137.72) 142.29,138.11 UV7.B4
  BOTTOM w0.127: UV1.N27 145.71,116.03 145.71,117.52 v3(144.93,118.3)
FB_D59: length 31.6
  IN1 w0.089: 145.16,117.33 v3(144.93,117.1)
  IN1 w0.157: v3(143.48,138.53) 143.71,138.77 144.59,138.77 144.88,139.05 146.7,139.05 150.42,135.33 150.42,125.11 147.5,122.18 147.5,119.59 145.24,117.33 145.16,117.33
  BOTTOM w0.127: v3(143.48,138.53) 143.46,138.53 143.46,138.54 143.53,138.54 143.88,138.19 UV7.B2 ; v3(144.93,117.1) 144.93,116.27 144.36,115.7 UV1.R27
FB_D60: length 28.4
  IN1 w0.089: v3(142.67,136.11) 143.08,136.52 144.21,136.52 144.69,136.03 145.49,136.03
  IN1 w0.157: 145.49,136.03 145.63,136.03 147.31,134.36 147.31,126.04 147.19,125.92 147.19,125.9 144.39,123.09 144.39,120.7 142.99,119.31 142.99,118.15 142.72,117.87 v3(142.53,117.87)
  BOTTOM w0.089: UV1.V26 141.88,115.03 141.49,115.42 141.49,116.07
  BOTTOM w0.127: v3(142.67,136.11) 142.28,135.72 UV7.E4 ; 141.49,116.07 141.87,116.45 141.87,117.21 v3(142.53,117.87)
FB_D61: length 25.6
  IN1 w0.089: v3(143.47,135.32) 143.83,135.68 144.64,135.68 144.85,135.47
  IN1 w0.157: v3(142.53,116.6) 142.51,116.6 141.95,117.16 141.95,119.03 143.85,120.92 143.85,123.21 146.73,126.09 146.73,126.11 146.78,126.16 146.78,134.15 145.46,135.47 144.85,135.47
  BOTTOM w0.127: v3(143.47,135.32) 143.87,135.71 UV7.E2 ; UV1.V27 142.53,116.35 v3(142.53,116.6)
FB_D62: length 24.2
  IN1 w0.089: v3(142.68,134.51) 143.44,133.75 145.56,133.75
  IN1 w0.157: v3(141.39,116.84) 141.36,116.84 140.95,117.25 140.95,119.53 142.79,121.36 142.79,123.5 145.75,126.46 145.75,133.56 145.56,133.75
  BOTTOM w0.127: v3(141.39,116.84) 141.39,116.8 141.08,116.53 141.08,115.7 UV1.W27 ; v3(142.68,134.51) 142.28,134.91 UV7.F4
FB_D63: length 25.6
  IN1 w0.089: v3(144.26,134.51) 144.33,134.58 145.49,134.58
  IN1 w0.157: 145.49,134.58 146.26,133.82 146.26,126.28 143.33,123.34 143.33,121.14 141.42,119.23 141.42,118.67 v3(141.4,118.66)
  BOTTOM w0.089: 140.7,115.56 140.94,115.33 141.19,115.33 141.5,115.01 141.5,114.52 UV1.W25
  BOTTOM w0.127: 140.7,115.56 140.7,118.01 141.4,118.65 v3(141.4,118.66) ; v3(144.26,134.51) 143.88,134.9 UV7.F2
FB_DBI0: length 21.8
  IN2 w0.089: 155.96,111.37 155.96,110.65 154.88,109.57 v3(154.7,109.57) ; 159.72,124.31 159.72,125.92 159.49,126.16 159.49,126.96 v3(159.34,127.1)
  IN2 w0.157: 155.96,111.37 157.42,112.83 157.42,122.01 159.72,124.31
  BOTTOM w0.127: UV1.D19 153.5,109.12 153.95,109.57 v3(154.7,109.57) ; UV6.D2 159.34,127.11 159.34,127.1 v3(159.34,127.1)
FB_DBI1: length 33.6
  IN2 w0.089: v3(168.13,127.1) 168.13,127.09 168.13,127.06 168.67,126.53 168.67,124.62 ; v3(153.91,104.55) 154.28,104.17 154.89,104.17 155.17,104.46 155.75,104.46 156.06,104.14
  IN2 w0.157: 168.67,124.62 168.87,124.42 168.87,123.1 168.87,122.55 164.23,117.9 164.23,114.48 164.05,114.3 163.75,114.3 163.5,114.05 163.5,113.69 163.18,113.37 163.18,110.18 161.47,108.46 161.47,107.71 158.16,104.4 157.35,104.4 157.35,104.4 157.09,104.14 156.06,104.14
  BOTTOM w0.127: UV1.D14 153.5,104.95 v3(153.91,104.55) ; v3(168.13,127.1) 168.09,127.1 167.73,127.47 UV6.D13
FB_DBI2: length 41.5
  IN1 w0.089: 158.74,107.33 158.49,107.08 157.61,107.08 157.5,107.19 156.33,107.19 156.2,107.07 v3(154.71,107.07) ; v3(168.13,135.92) 168.13,135.88 168.65,135.36 168.65,135.24 168.87,135.01 169.79,135.01
  IN1 w0.157: 158.74,107.33 158.94,107.53 159.4,107.53 162,110.13 162.74,110.13 163.93,111.32 163.95,111.32 164.2,111.58 164.2,111.59 164.39,111.78 164.39,114.03 164.14,114.28 164.14,117.22 165.26,118.35 165.26,118.89 169.4,123.03 169.5,123.03 170.72,124.25 170.72,134.08 169.79,135.01
  BOTTOM w0.127: v3(168.13,135.92) 167.73,135.52 UV6.P13 ; UV1.C17 v3(154.71,107.07)
FB_DBI3: length 30.8
  IN1 w0.089: v3(156.53,112.86) 156.89,112.86 158.67,114.64 ; 156.81,135.18 157.24,135.18 157.35,135.08 157.92,135.08 157.96,135.12 v3(159.32,135.12)
  IN1 w0.157: 158.67,114.64 158.67,117.3 155.96,120.02 155.96,131.56 156.44,132.04 156.44,134.81 156.81,135.18
  BOTTOM w0.127: UV6.P2 v3(159.32,135.12) ; UV1.C22 154.69,111.99 155.32,111.99 156.19,112.86 v3(156.53,112.86)
FB_DBI4: length 17.7
  IN2 w0.089: v3(145.64,113.7) 146.03,114.1 146.03,115.9 146.74,116.6
  IN2 w0.157: v3(144.29,128.1) 144.57,127.83 145.23,127.83 147.1,125.95 147.1,118.68 146.74,118.32 146.74,116.6
  BOTTOM w0.127: UV1.P24 145.24,113.3 v3(145.64,113.7) ; UV7.P2 v3(144.29,128.1)
FB_DBI5: length 18.3
  IN2 w0.089: 140.17,114.35 140.66,113.86
  IN2 w0.157: 140.66,113.86 v3(140.66,113.77) ; 140.17,114.35 140.17,114.58 137.63,117.12 137.63,120.27 137,120.91 136.51,120.91 135.19,122.23 135.19,126.57 135.12,126.74 134.68,127.18 v3(134.68,128.11)
  BOTTOM w0.127: UV1.W24 141.08,113.35 v3(140.66,113.77) ; v3(134.68,128.11) 135.08,128.51 UV7.P13
FB_DBI6: length 31.5
  IN1 w0.089: v3(139.02,116.81) 138.07,116.81 137.59,117.3 137.59,120.01 137.04,120.55 ; 133.57,137.36 134.24,137.36 v3(134.67,136.92)
  IN1 w0.102: 136.13,121.47 137.04,120.55
  IN1 w0.157: 133.57,137.36 130.82,134.61 130.82,131 131.16,130.67 131.16,125.14 134.28,122.02 135.58,122.02 136.13,121.47
  BOTTOM w0.089: v3(139.02,116.81) 139.83,115.99 139.83,114.53 UV1.AA25
  BOTTOM w0.127: v3(134.67,136.92) 135.08,136.51 UV7.D13
FB_DBI7: length 29.4
  IN1 w0.089: v3(143.47,136.92) 143.55,137 145.61,137 ; 143.75,119.18 143.48,118.91 143.48,118.28 143.6,118.17 143.76,118 v3(143.93,118)
  IN1 w0.157: 145.61,137 147.98,134.63 147.98,125.76 147.85,125.64 147.85,125.62 145.28,123.04 145.28,120.53 143.93,119.18 143.75,119.18
  BOTTOM w0.127: UV7.D2 143.88,136.51 v3(143.47,136.92) ; v3(143.93,118) 143.13,117.21 143.13,114.51 UV1.U25
FB_DDR: length 4.8
  BOTTOM w0.102: PRM9.1 v1(4.07,77.31)
  BOTTOM w0.203: PUM1.6 8.19,77.08 7.73,77.54 6.36,77.54 PRM6.1 5.34,77.3 PRM9.1
FB_EDC0: length 22
  IN2 w0.089: 157.28,126.38 158.45,126.38 v3(158.52,126.31) ; v3(153.03,109.55) 153.47,109.99 153.47,110.97 153.52,111.03 153.52,111.36 153.26,111.61 152.96,111.61 152.67,111.9 152.67,113.5 152.57,113.6
  IN2 w0.157: 157.28,126.38 153.23,122.33 153.23,115.82 152.57,115.16 152.57,113.6
  BOTTOM w0.127: UV1.E19 152.7,109.22 v3(153.03,109.55) ; UV6.C2 158.93,126.71 v3(158.52,126.31)
FB_EDC1: length 33
  IN2 w0.089: 157.76,105.88 156.04,105.88 155.74,105.59 155.24,105.59 155.07,105.42 v3(154.66,105.42) ; 167.45,123.96 167.45,125.02 167.35,125.13 v3(167.35,126.31)
  IN2 w0.157: 167.45,123.96 167.54,123.87 167.54,123.14 165.72,121.32 164.56,121.32 162.01,118.78 162.01,118.5 162.17,118.35 162.72,118.35 162.88,118.19 162.88,117.87 162.72,117.72 162.17,117.72 162.01,117.56 162.01,117.24 162.17,117.09 162.72,117.09 162.88,116.93 162.88,116.61 162.72,116.46 162.17,116.46 162.01,116.3 162.01,115.99 162.17,115.83 162.36,115.83 162.52,115.67 162.52,115.36 162.36,115.2 162.17,115.2 161.85,114.88 161.85,110.73 160.13,109.01 160.13,108.26 157.76,105.88
  BOTTOM w0.127: v3(154.66,105.42) 154.3,105.78 UV1.C15 ; v3(167.35,126.31) 167.73,126.7 UV6.C13
FB_EDC2: length 44.2
  IN1 w0.089: 157.47,106.43 157.44,106.4 157.09,106.4 v3(156.51,106.58) ; v3(167.33,136.71) 167.68,136.35 168.39,136.35 168.8,135.94 169.8,135.94 169.87,135.87
  IN1 w0.157: 157.47,106.43 159.84,106.43 160.39,106.98 160.39,107.24 160.35,107.28 160.35,107.54 160.54,107.73 160.8,107.73 160.84,107.69 161.1,107.69 162.88,109.46 163.01,109.46 164.21,110.66 164.22,110.66 164.87,111.3 164.87,111.32 165.05,111.51 165.05,114.3 164.8,114.55 164.8,116.95 165.93,118.07 165.93,118.61 169.68,122.36 169.77,122.36 171.38,123.97 171.38,124.52 171.38,134.35 169.87,135.87
  BOTTOM w0.127: v3(156.51,106.58) 156.08,107 155.46,107 UV1.B16 ; v3(167.33,136.71) 167.72,136.31 UV6.R13
FB_EDC3: length 30.8
  IN1 w0.089: v3(158.52,135.91) 158.48,135.86 158.11,135.86 157.98,136 157.32,136
  IN1 w0.157: 157.32,136 156.27,136 155.77,135.5 155.77,132.32 155.29,131.84 155.29,119.75 158.01,117.03 158.01,114.59 v3(156.83,113.4)
  BOTTOM w0.127: UV6.R2 v3(158.52,135.91) ; v3(156.83,113.4) 157.01,113.22 157.01,112.47 156.51,111.97 155.74,111.97 155.38,111.6 UV1.B22
FB_EDC4: length 15.3
  IN2 w0.089: v3(144.78,114.5) 144.78,114.74 144.39,115.13 144.39,115.55
  IN2 w0.157: v3(143.48,127.31) 143.48,126.38 144.21,125.64 144.21,125 145.06,124.14 145.06,119.31 145.41,118.97 145.41,116.56 144.39,115.55
  BOTTOM w0.127: UV1.R25 144.38,114.1 v3(144.78,114.5) ; v3(143.48,127.31) 143.88,127.71 UV7.R2
FB_EDC5: length 23.9
  IN2 w0.089: 140.83,115.1 141.04,114.9 141.04,113.64 141.48,113.2 v3(141.48,112.9)
  IN2 w0.157: v3(135.48,127.32) 135.75,127.05 135.85,126.81 135.85,125.12 136.04,124.94 137.03,124.94 137.21,124.76 137.21,124.49 137.03,124.31 136.04,124.31 135.85,124.13 135.85,123.79 136.04,123.6 137.46,123.6 137.64,123.42 137.64,123.16 137.46,122.97 136.04,122.97 135.85,122.79 135.85,122.51 136.03,122.33 136.89,122.33 137.05,122.17 137.05,121.29 139.49,118.86 139.49,116.45 140.83,115.1
  BOTTOM w0.127: v3(141.48,112.9) 141.08,112.51 UV1.W23 ; v3(135.48,127.32) 135.09,127.71 UV7.R13
FB_EDC6: length 32.4
  IN1 w0.089: 136.67,117.98 137.07,118.38 137.07,119.97 136.64,120.4 136.31,120.4 136.09,120.62 ; 134.16,137.93 134.35,138.12 135.09,138.12 v3(135.49,137.72)
  IN1 w0.102: 135.21,121.35 135.36,121.35 136.09,120.62
  IN1 w0.157: 135.21,121.35 134,121.35 130.49,124.86 130.49,125.16 130.49,130.39 130.16,130.73 130.16,134.89 133.2,137.93 134.16,137.93 ; 136.67,117.98 v3(136.62,117.98)
  BOTTOM w0.089: UV1.AB26 138.38,114.9 137.87,115.42 137.87,116.28 137.06,117.09 137.06,117.54 v3(136.62,117.98)
  BOTTOM w0.127: v3(135.49,137.72) 135.47,137.72 135.47,137.71 135.45,137.71 135.08,137.33 UV7.C13
FB_EDC7: length 28.5
  IN1 w0.089: 144.42,118.73 144.42,117.23 v3(143.93,116.75) ; v3(144.29,137.72) 144.46,137.56 145.89,137.56
  IN1 w0.157: 144.42,118.73 145.94,120.25 145.94,122.59 149.04,125.69 149.04,134.51 145.99,137.56 145.89,137.56
  BOTTOM w0.127: UV7.C2 143.89,137.31 v3(144.29,137.72) ; v3(143.93,116.75) 143.93,115.27 143.56,114.9 UV1.T26
FB_GT: length 14.2
  BOTTOM w0.203: 194.95,74.44 195.21,74.18 PUZ1.24
  BOTTOM w0.254: PCZ21.1 PRZ56.1 194.47,78.13 PCZ20.2 PRZ54.2 192.79,78.81 191.42,78.81 190.46,77.85 190.46,76.04 v1(190.89,75.61) 191.61,74.89 194.28,74.89 194.72,74.44 194.95,74.44
FB_SA: length 5.2
  BOTTOM w0.203: PUZ1.45 202.54,70.98 v1(202.9,70.62) 203.28,70.62 203.6,70.94 PCZ6.1
  BOTTOM w0.254: PRZ10.1 PCZ6.1 203.94,70.2 203.87,70.12 PRZ8.2 PCZ5.2
FB_VRAM: length 4.6
  TOP w0.102: v3(186.98,133.46) v1(187.84,133.46)
  BOTTOM w0.254: PUW1.14 v3(186.98,133.46) 187.23,133.46 PRW8.1 188.13,132.82 188.13,132.81 PRW10.2 PRW9.1
FB_VREF: length 1.2
  TOP w0.102: T2401.1 154.27,112.52 v3(153.9,112.89)
  BOTTOM w0.102: v3(153.9,112.89) 153.5,112.49 UV1.D23
FB_WCK01: length 26.4
  IN2 w0.076: 156.45,109 156.44,108.98 156.44,108.92 156.02,108.5 154.58,108.5 154.28,108.2 154.28,108.03 154.14,107.89 v3(153.95,107.89)
  IN2 w0.14: 156.45,109 159.41,111.95 159.41,121.2 162.25,124.04 162.25,126.71 161.44,127.52 161.05,127.52 160.91,127.38 v3(160.91,127.11)
  BOTTOM w0.109: UV1.D18 153.52,108.32 v3(153.95,107.89) ; UV6.D4 160.53,127.5 v3(160.91,127.11)
FB_WCK01#: length 26.6
  IN2 w0.076: 156.63,108.82 156.62,108.8 156.56,108.8 156.09,108.33 154.65,108.33 154.45,108.13 154.45,108.03 154.59,107.89 v3(154.73,107.89)
  IN2 w0.14: v3(160.92,127.92) 161.08,127.77 161.55,127.77 162.5,126.82 162.5,123.93 159.66,121.1 159.66,111.85 156.63,108.82
  BOTTOM w0.109: UV1.C18 v3(154.73,107.89) ; UV6.D5 v3(160.92,127.92)
FB_WCK23: length 37.5
  IN1 w0.14: v3(153.09,107.04) 153.29,107.04 153.43,107.18 153.43,107.4 153.22,107.61 153.22,108.99 153.62,109.39 154.18,109.39 154.45,109.12 156.47,109.12 157.85,110.49 157.97,110.49 161.34,113.86 161.34,124.12 162.86,125.64 162.86,134.24 161.64,135.46 161.07,135.46 160.93,135.32 v3(160.93,135.12)
  BOTTOM w0.109: v3(153.09,107.04) 153.5,107.45 UV1.D17 ; v3(160.93,135.12) 160.54,135.51 UV6.P4
FB_WCK23#: length 37.5
  IN1 w0.14: v3(160.93,135.91) 161.13,135.72 161.74,135.72 163.11,134.35 163.11,125.53 161.59,124.02 161.59,113.76 158.08,110.24 157.95,110.24 156.58,108.87 154.35,108.87 154.08,109.13 153.72,109.13 153.48,108.89 153.48,107.72 153.68,107.51 153.68,107.23 v3(153.87,107.04)
  BOTTOM w0.109: v3(153.87,107.04) 153.5,106.67 UV1.D16 ; UV6.P5 v3(160.93,135.91)
FB_WCK45: length 21.6
  IN1 w0.076: v3(143.13,112.88) 142.72,113.29 142.72,114.67 143.01,114.95 143.01,115.15 142.96,115.2 142.96,115.21
  IN1 w0.14: v3(141.88,128.91) 141.76,128.79 141.3,128.79 140.33,127.81 140.33,127.5 140.33,125.8 141.13,125 141.13,121.61 140.88,121.37 140.86,121.37 140.09,120.59 140.09,116.47 140.69,115.87 142.72,115.87 142.96,115.63 142.96,115.21
  BOTTOM w0.109: v3(141.88,128.91) 142.27,128.51 UV7.P4 ; v3(143.13,112.88) 143.56,113.3 UV1.T24
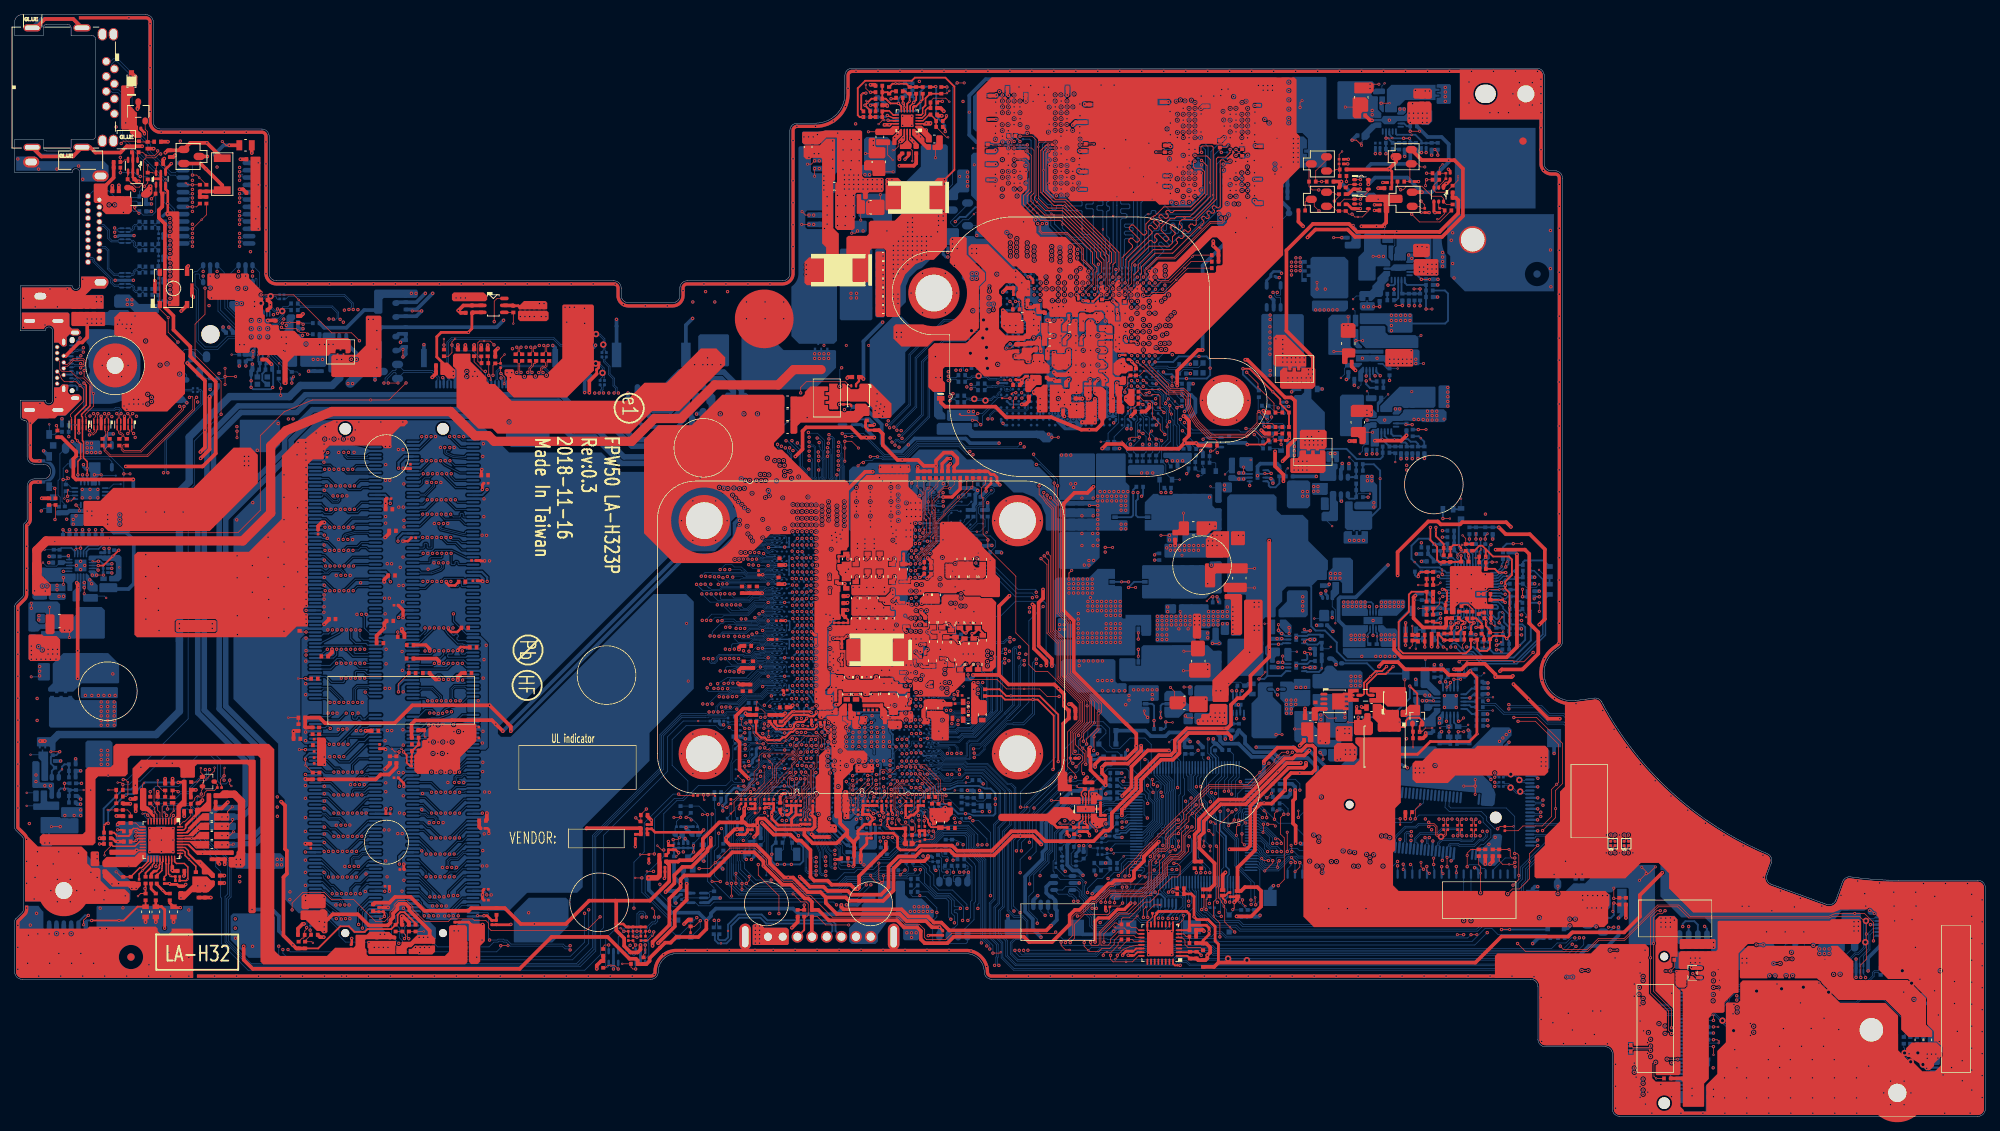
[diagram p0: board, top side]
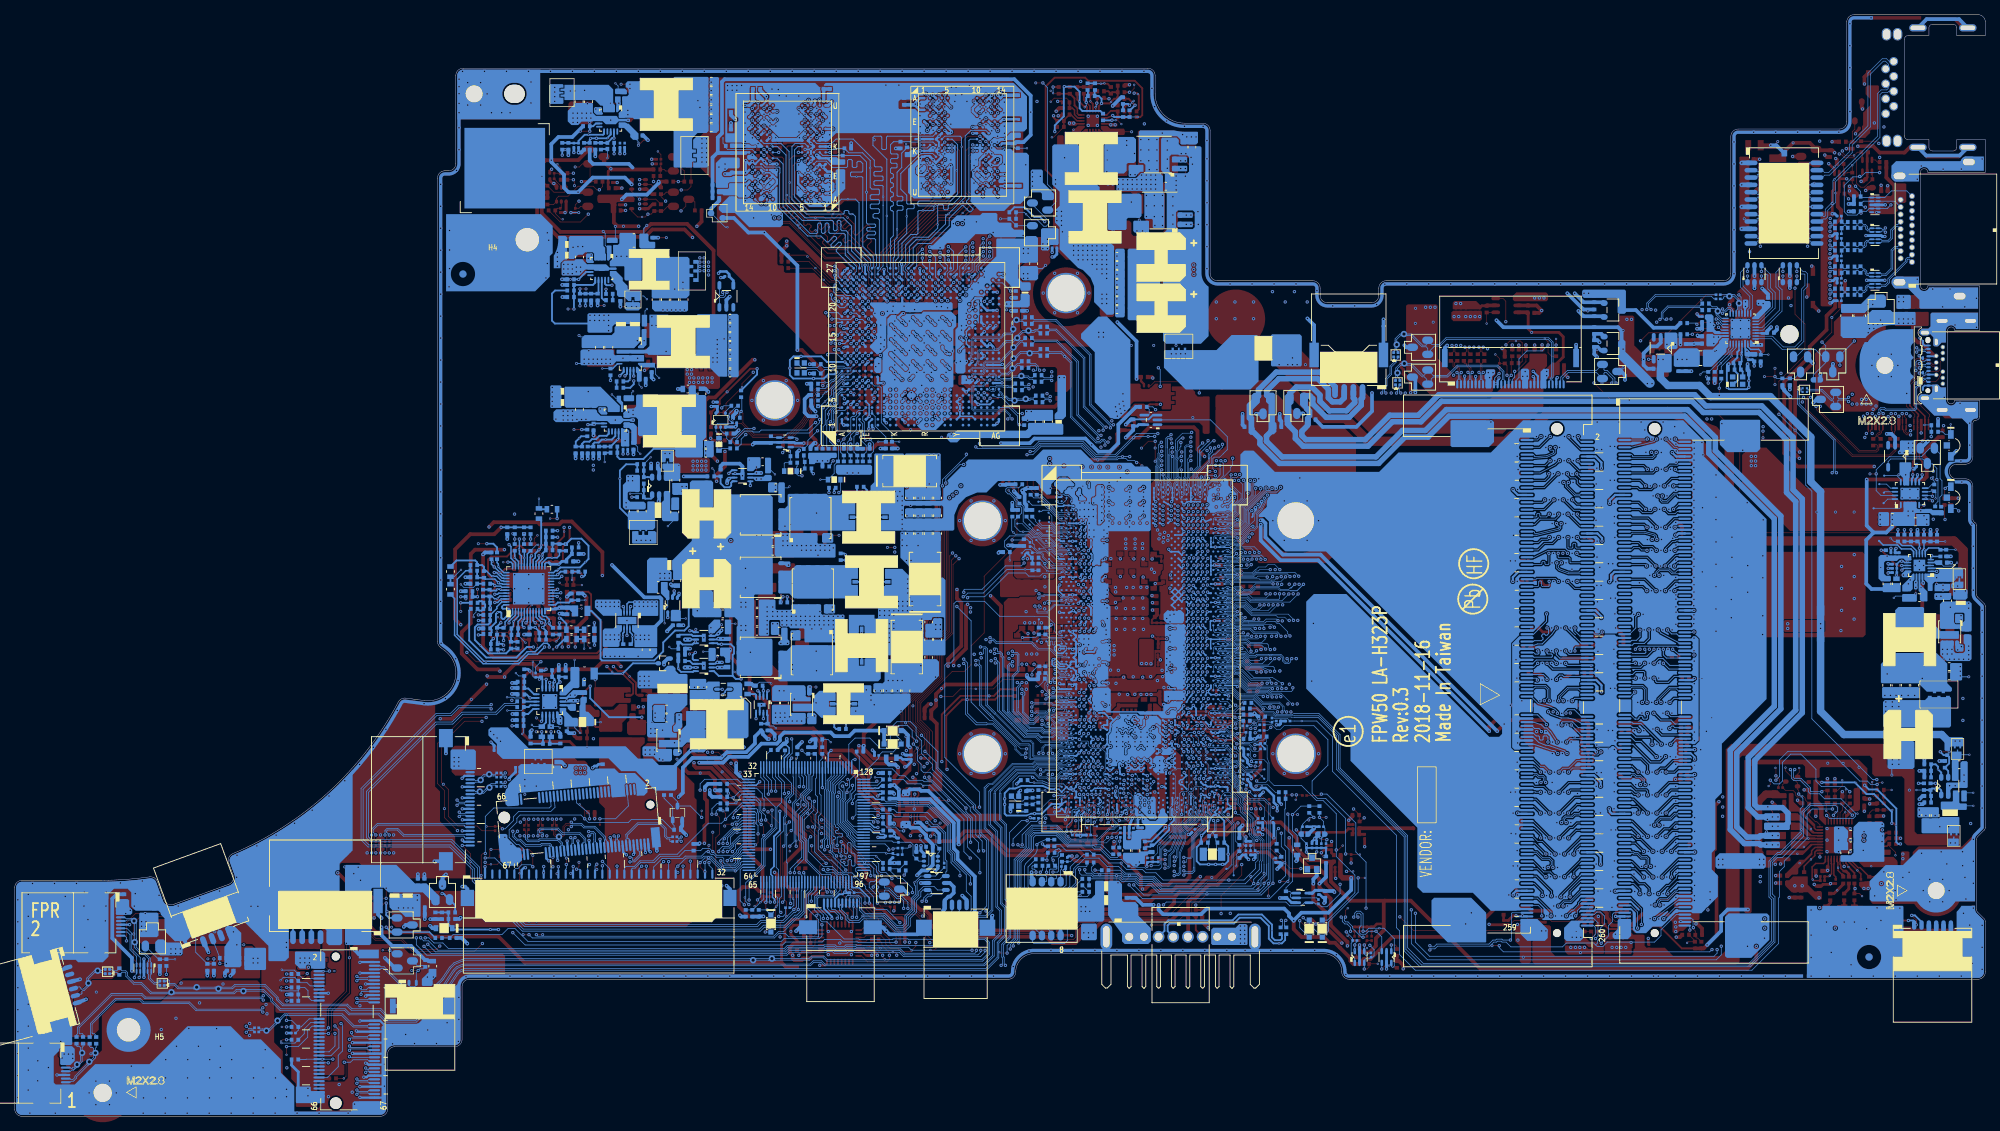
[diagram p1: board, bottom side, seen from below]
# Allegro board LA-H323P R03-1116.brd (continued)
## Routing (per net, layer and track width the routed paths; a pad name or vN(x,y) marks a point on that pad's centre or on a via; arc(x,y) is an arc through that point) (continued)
FB_WCK45#: length 21.6
  IN1 w0.076: v3(143.14,113.7) 143.32,113.53 143.49,113.53 143.57,113.61 143.57,113.99 143.47,114.09 142.96,114.09 142.88,114.17 142.88,114.6 143.17,114.89 143.17,115.15 143.22,115.19 143.22,115.21
  IN1 w0.14: 143.22,115.21 143.22,115.74 142.83,116.13 140.8,116.13 140.35,116.58 140.35,120.49 140.97,121.11 140.98,121.11 141.38,121.51 141.38,125.1 140.58,125.91 140.58,127.6 140.58,127.71 141.4,128.53 141.67,128.53 141.88,128.32 v3(141.88,128.11)
  BOTTOM w0.109: UV1.U24 142.74,113.3 v3(143.14,113.7) ; UV7.P5 v3(141.88,128.11)
FB_WCK67: length 26.7
  IN2 w0.076: v3(142.29,113.73) 142.29,113.85 142.2,113.94 141.96,113.94 141.68,114.21 141.68,115.11 141.88,115.31 141.88,116.21 141.84,116.26
  IN2 w0.14: v3(141.88,136.91) 141.09,136.91 140.22,136.04 140.22,125.82 140.51,125.53 140.51,125.04 141.84,123.7 141.84,118.9 141.84,118.89 141.84,116.26
  BOTTOM w0.109: UV7.D4 142.27,136.51 v3(141.88,136.91) ; UV1.V24 141.88,113.32 v3(142.29,113.73)
FB_WCK67#: length 26.6
  IN2 w0.076: 142.09,116.26 142.05,116.21 142.05,115.24 141.85,115.04 141.85,114.28 142.03,114.1 142.3,114.1 142.38,114.18 142.38,114.45 v3(142.31,114.51)
  IN2 w0.14: 142.09,116.26 142.09,118.79 142.1,118.79 142.1,123.81 140.77,125.14 140.77,125.64 140.48,125.93 140.48,135.93 141.17,136.62 141.56,136.62 141.88,136.3 v3(141.88,136.11)
  BOTTOM w0.109: v3(142.31,114.51) 141.9,114.1 UV1.V25 ; UV7.D5 141.48,136.51 v3(141.88,136.11)
FPR_LOCK#: length 113.8
  TOP w0.102: v3(204.92,23.58) 206,22.5 214.49,22.5 216.01,24.02 219.53,24.02 224.1,28.6 226.74,28.6 228.27,27.06 247.36,27.06 247.82,27.25 251.57,27.25 252.47,26.35 v2(252.47,24.87) 252.47,21.43 251.72,20.68 v3(251.72,18.94)
  IN1 w0.127: v3(165.67,29.23) 165.67,28.39 165.96,28.1 202.68,28.1 204.92,25.86 v3(204.92,23.58)
  BOTTOM w0.102: v3(165.67,29.23) 165.76,29.33 UK1.68 ; v3(251.72,18.94) 251.57,19.09 DM16.7 DM16.4 251.57,21.66 252.74,22.83 252.74,24.99 253.4,25.65 JFPR.6
FPR_OFF: length 144.6
  TOP w0.102: v3(208.33,38.98) 210.1,40.76 v2(210.1,41.98) 210.1,44.46 211.03,45.38 211.03,50.9 207.51,54.41 v3(204.41,54.41)
  IN1 w0.127: v3(208.33,38.98) 207.1,37.75 207.1,33.61 208.93,31.77 211.77,31.77 212.28,31.26 226.15,31.26 233.24,24.17 249.48,24.17 252.04,21.61 252.04,19.26 v3(252.37,18.93) ; v3(154.12,48.69) 156.24,48.69 157.01,47.92 157.27,47.92 157.55,47.65 169.13,47.65 169.56,47.21 175.96,47.21 176.87,46.31 183.69,46.31 184.42,45.57 196.27,45.57 204.41,53.72 v3(204.41,54.41)
  BOTTOM w0.102: UK1.1 154.57,48.55 154.43,48.69 v3(154.12,48.69) ; JFPR.7 253.35,25.15 252.97,24.77 252.97,22.74 252.07,21.84 DM16.5 DM16.6 252.07,19.43 252.37,19.13 v3(252.37,18.93)
GC6_FB_EN: length 130.2
  TOP w0.102: v2(114.16,92.76) v3(113.27,92.76)
  IN1 w0.076: v3(111.21,46.84) 111.84,46.84 112.16,47.17 112.16,49.57 112.12,49.61 112.12,50.12 112.2,50.31
  IN1 w0.127: v3(167.89,93.85) 167.6,93.85 167.24,93.61 167.07,93.53 166.16,93.08 162.89,93.08 162.61,93.37 160.85,93.37 160.34,92.86 158.42,92.86 157.33,93.95 156.26,93.95 155.21,92.9 155.21,91.08 155.08,90.95 153.36,90.95 152.01,89.61 144.8,89.61 144.31,89.12 140.17,89.12 139.63,89.65 138.65,89.65 137.69,90.61 137.69,91.29 v3(137.65,91.33) ; 112.2,50.31 112.2,50.95 112.99,51.73 112.99,54.11 111.62,55.48 111.21,55.48 110.06,56.63 110.06,57.64 109.43,58.27 109.43,58.27 109.37,58.33 105.69,58.33 104.61,59.42 104.61,66.21 105.71,67.32 105.71,68.08 105.94,68.3 106.38,68.3 106.38,68.31 108.86,68.31 109.11,68.56 109.11,69.31 110.06,70.25 110.06,79.73 111.52,81.19 111.52,83.76 112.51,84.75 112.51,87.09 112.77,87.35 112.77,92.27 v3(113.27,92.76)
  BOTTOM w0.076: v3(111.21,46.84) 110.8,47.26 110.37,47.26 110.21,47.41 UC1.CE27
  BOTTOM w0.102: v3(137.65,91.33) 137.42,91.1 129.68,91.1 128.97,91.82 123.09,91.82 121.3,90.03 118.56,90.03 115.83,92.76 v3(113.27,92.76) ; v3(167.89,93.85) 169.16,93.85 170.43,92.58 170.73,92.58 170.92,92.39 170.92,92.18 RV202.2 171.61,92.46 RV88.2 171.98,93.15 172.44,93.61 UV23.2
GPIO0_GC6_FB_EN: length 20.9
  TOP w0.102: v1(154.2,98.64) 154.34,98.78 v3(154.7,98.78)
  IN2 w0.127: v3(154.7,98.78) 154.7,97.7 155.19,97.21 155.19,96.4 156.37,95.22 157.6,95.22 158.17,94.66 v3(159.5,94.66)
  BOTTOM w0.102: UV1.C6 154.32,98.4 v3(154.7,98.78) ; RV202.1 170.21,92.41 169.13,93.49 168.13,93.49 168,93.37 167.18,93.37 166.91,93.63 160.63,93.63 159.6,94.66 v3(159.5,94.66)
GPIO8_OVERT#: length 59.1
  TOP w0.102: v3(179.94,124.86) 180.58,125.5 RV69.1 180.12,125.81 179.85,126.08 QG4.3
  IN1 w0.127: v3(155.57,97.9) 155.57,98.25 157.66,100.34 158.72,100.34 160.63,98.42 160.63,96.42 163.21,93.84 165.98,93.84 166.75,94.23 166.88,94.28 167.5,94.7 168.04,95.24 168.9,96.52 168.9,98.88 168.59,99.18 168.59,101.51 167.34,102.75 167.34,107.79 168.78,109.23 168.78,115.35 176.26,122.83 176.26,124.1 177.02,124.86 v3(179.94,124.86)
  BOTTOM w0.102: v3(155.57,97.9) 155.57,98.07 UV1.A6
GPIO9_ALERT#: length 10.6
  BOTTOM w0.102: UV1.F8 151.46,99.64 150.76,99.64 150.53,99.41 150.53,94.64 149.09,93.19 RV2766.1 v1(148.09,92.03)
GPU_ALL_PGOOD: length 120.3
  TOP w0.102: v3(116.66,90) v2(117.65,90) ; v3(172.68,91.69) 172.66,91.7 CC352.1 RV30.1
  IN1 w0.076: 112,70.24 110.55,68.79 110.55,66.25 110.17,65.87 110.17,61 110.3,60.88 110.4,60.78 110.4,60.33 111.43,59.3 112.17,59.3 112.68,58.79 113.08,58.79 113.78,58.1 115.2,58.1 115.62,57.68 115.62,57.43 117.85,55.19 117.85,54.17 118.82,53.21 118.82,49.65 118.99,49.48 118.99,47.51 v3(118.43,46.95)
  IN1 w0.127: v3(172.68,91.69) 172.68,90.71 172.14,90.18 165.16,90.18 161.28,86.29 156.88,86.29 156.1,87.07 146.29,87.07 144.38,85.15 142.14,85.15 141.67,85.62 139.25,85.62 136.21,88.67 132.99,88.67 130.96,90.7 v3(130.24,90.7) ; v3(116.66,90) 116.51,89.84 116.51,88.98 113.92,86.4 113.92,78.32 112.02,76.42 112.02,70.26 112,70.24
  BOTTOM w0.076: v3(118.43,46.95) 118.62,46.95 118.86,46.71 UC1.CF12
  BOTTOM w0.102: v3(116.66,90) 118.27,90 118.47,89.8 121.4,89.8 123.18,91.59 128.88,91.59 129.77,90.7 v3(130.24,90.7) ; RV31.2 172.29,91.13 172.59,90.83 DV3.2 172.92,91.08 172.92,91.45 v3(172.68,91.69)
GPU_BUFRST: length 26.7
  TOP w0.102: RV67.1 C5230.1 171.5,92.68 170.04,92.68 169.23,93.49 168.9,93.49 168.01,92.6 162.97,92.6 161.26,94.31 160.59,95.31 159.85,97.11 159.85,98.1 v1(159.36,98.6) 159.15,98.8 157.35,98.8 153.9,102.26 153.76,102.26 v3(153.06,102.96)
  BOTTOM w0.102: UV1.D11 v3(153.06,102.96)
GPU_EVENT#: length 103.9
  TOP w0.102: v2(114.99,88.74) 115.45,89.2 v3(115.72,89.2)
  IN1 w0.076: v3(118.48,44.95) 118.08,45.36 118.08,47.18 118.83,47.94 118.83,48.75 118.06,49.52 118.06,52.88 118.04,52.89 118.04,53.15 117.58,53.61 117.58,55.14 115.73,57 114.92,57 114.71,57.2 113.6,57.2 113.39,57.41 113.39,57.88 113.39,58.01 112.94,58.46 112.54,58.46 112.04,58.97 111.43,58.97 111.29,58.97 110.07,60.19 110.07,60.64 109.9,60.81 109.84,60.87 109.84,66.01 110.22,66.39 110.22,69.09 110.38,69.26
  IN1 w0.127: 110.38,69.26 111.59,70.47 111.59,77.01 113.49,78.9 113.49,84.35 113.45,84.39 113.45,86.93 v3(115.72,89.2) ; v3(130.67,90.27) 131.03,90.27 132.89,88.41 136.1,88.41 140.8,83.71 141.97,83.71 142.18,83.93 145.75,83.93 147.48,85.66 155.77,85.66 v3(156.32,85.11)
  BOTTOM w0.076: v3(118.48,44.95) 118.48,44.84 118.18,44.54 118.18,44.28 118.24,44.22 118.24,43.71 118.07,43.54 118.07,43.1 117.77,42.8 UC1.CN14
  BOTTOM w0.102: DV1.1 156.11,85.32 v3(156.32,85.11) ; v3(115.72,89.2) 115.99,89.47 116.91,89.47 117.2,89.77 118.18,89.77 118.38,89.57 121.49,89.57 123.28,91.36 128.78,91.36 129.87,90.27 v3(130.67,90.27)
GPU_EVENT#_D: length 12.9
  BOTTOM w0.102: v1(158.85,86.87) DV1.2 156.96,87.71 156.96,88.85 RV72.1 156.39,89.42 156.39,91.53 157.23,92.37 157.23,94.46 157.09,94.61 157.09,94.64 157,94.73 157,95.03 157.08,95.11 157.08,95.86 157.09,95.87 157.09,96.18 157.08,96.19 157.08,96.27 156.65,96.7 UV1.A4
GPU_JTAG_TCK: length 1.7
  TOP w0.102: T231.1 v3(135.7,97.98)
  BOTTOM w0.102: UV1.AE5 136.1,97.58 v3(135.7,97.98)
GPU_JTAG_TDI: length 1.2
  TOP w0.102: v3(136.51,98.72) 136.1,98.72 T242.1
  BOTTOM w0.102: UV1.AE6 136.42,98.72 v3(136.51,98.72)
GPU_JTAG_TDO: length 7.6
  TOP w0.102: T243.1 129.05,95.6 131.03,95.6 v3(131.32,95.89)
  BOTTOM w0.102: UV1.AF6 135.17,98.27 134.69,98.07 134.11,98.07 131.93,95.89 v3(131.32,95.89)
GPU_JTAG_TMS: length 2
  TOP w0.102: v3(136.5,98) 136.18,97.68 T232.1
  BOTTOM w0.102: v3(136.5,98) 136.9,98.4 UV1.AD6
GPU_JTAG_TRST#: length 6.4
  TOP w0.102: v3(131.73,94.36) 131.12,94.97 v2(130.59,94.97)
  BOTTOM w0.102: RV2767.1 131.67,94.3 v3(131.73,94.36) 131.95,94.58 131.95,95.54 133.11,96.7 UV1.AG4
GPU_PLLVDD: length 25.4
  TOP w0.508: 148.3,95.27 148.3,94.51 147.48,93.68 v2(146.53,93.68) 145.44,93.68 141.3,95.4 135.15,95.4 133.73,96.82 126.87,96.82 126.27,97.42 LV5.2
  BOTTOM w0.305: UV1.L6 147.68,98.34 v3(147.29,98.73)
GPU_TESTMODE: length 3
  TOP w0.102: v1(134.96,100.45) 135.75,100.45 v3(135.75,100.45) 136.13,100.07 RV71.1
  BOTTOM w0.102: v3(135.75,100.45) 135.75,100.45 136.47,100.45 UV1.AD9
GPU_VID0: length 63.1
  TOP w0.254: PRV6.1 v3(127.11,140.43)
  IN2 w0.127: v3(152.26,99.64) 152.16,99.54 149.88,99.54 149.53,99.89 149.53,101.35 148.78,102.11 148.43,102.11 148.31,102.23 148.31,102.58 147.24,103.64 147.24,104.84 146.23,105.86 146.23,106.53 145.74,107.02 140.68,107.02 140.54,106.87 138.54,106.87 136.43,108.99 133.18,108.99 132.33,109.83 132.33,112.81 133.08,113.56 133.08,115.86 131.62,117.32 130.35,117.32 130.1,117.57 130.1,118.71 130.41,119.02 130.41,124.13 129.21,125.34 129.21,137.62 127.11,139.72 v3(127.11,140.43)
  BOTTOM w0.102: v3(127.11,140.43) v1(127.11,139.59) ; UV1.E7 v3(152.26,99.64)
GSPI0_MOSI: length 8.6
  TOP w0.076: RC118.2 107.17,40.46 107.55,40.84 107.55,41.64 107.96,42.04 v1(107.96,43.63) 107.96,44.35 108.5,44.9 108.5,47.23 v3(107.94,47.79)
  BOTTOM w0.076: v3(107.94,47.79) 108.26,47.47 UC1.CE29
GSPI1_MOSI: length 11
  TOP w0.076: 107.81,40.63 107.81,41.52 108.26,41.98 108.26,43.29 108.68,43.71 108.68,47.28 109.1,47.7 109.1,48.08 v1(109.01,48.17) 108.87,48.3 107.68,48.3 107.18,48.8 v3(107.18,48.81)
  TOP w0.102: RC201.2 107.81,40.63
  BOTTOM w0.076: v3(107.18,48.81) 107.61,49.24 UC1.CA30
GT_BST:
  vias: v1(168.52,89.54)
GT_BST_R: length 1.2
  BOTTOM w0.102: v1(165.03,87.59) 165.55,88.11 PCG2.1
GT_LG: length 18.5
  TOP w0.102: v3(157.46,79.27) v2(156.29,79.27)
  IN1 w0.762: 158.22,79.01 161.4,79.01 162.42,80.03 168.19,80.03 171.43,83.27 171.43,85.62
  vias: v3(157.46,78.63) v3(171.31,87) v3(171.56,86.38)
GT_LX: length 5.7
  IN1 w0.762: v3(162.92,84.48) 166.86,84.48 167.24,84.86 167.24,86.13
  vias: v2(163.67,80.51) v3(162.92,80.79) v3(166.92,86.95) v3(167.56,86.95)
GT_SNUB: length 2.1
  TOP w0.102: PRG4.2 v2(159.37,82.3)
GT_UG: length 1.8
  TOP w0.102: v3(167.56,87.78) v2(167.56,88.58)
  IN1 w0.762: 165.36,87.17 166.1,87.9
  vias: v3(164.96,86.13) v3(164.96,85.49) v3(166.92,87.78)
GT_UG_R: length 1.3
  BOTTOM w0.102: v1(163.05,85.95) 163.25,85.75 PRG3.2
H_CPUPWRGD: length 6.4
  BOTTOM w0.076: UC1.AR2 125.55,65.35 127.76,65.35 CC303.1 RC102.2 129.48,65.32 129.68,65.32
  BOTTOM w0.102: v2(131.29,65.32) 129.68,65.32
H_PECI: length 63.2
  TOP w0.102: v3(137.14,42.18) v1(138.07,42.18)
  IN2 w0.127: v3(137.14,42.18) 137.67,42.71 141.23,42.71 143.19,40.76 v3(143.19,40.33)
  BOTTOM w0.076: UC1.AR1 126.32,65.6 126.89,66.17 126.89,67.18 127.94,68.22 129.68,68.22
  BOTTOM w0.102: 129.68,68.22 134.4,68.22 136.45,70.27 140.32,70.27 140.64,69.95 140.64,62.3 141.09,61.84 141.6,61.84 141.88,61.56 141.88,48.98 137.14,44.24 v3(137.14,42.18) ; RK17.2 148.83,41.87 148.43,41.47 144.24,41.47 143.19,40.43 v3(143.19,40.33)
H_PROCHOT#_EC: length 4.8
  BOTTOM w0.102: UK1.103 150.01,35.97 149.91,35.87 v1(149.84,35.87) CC365.1 148.79,35.71 RK9.1
H_PROCHOT#_R: length 7.4
  BOTTOM w0.076: UC1.Y4 124.63,75.11 127.19,75.11 128.43,76.36 128.43,76.7 128.67,76.94 129.22,76.94 129.68,77.4
  BOTTOM w0.102: RC4.2 130.02,77.73 129.69,77.4 129.68,77.4
H_THERMTRIP#: length 6.1
  BOTTOM w0.076: UC1.BJ1 125.94,57.22 126.02,57.3 127.33,57.3 128.23,58.19 128.23,59.06 128.01,59.28 128.01,59.49 RC2.2 128.47,59.47 128.47,59.28 129.09,58.66 v1(129.37,58.66)
HDA_BIT_CLK: length 8.3
  BOTTOM w0.076: UC1.BN37 102.94,54.4 102.45,53.92 102.07,53.92 101.76,53.61 101.76,53.06 101.69,52.98 100.22,52.98 v3(100.15,52.91) 100.15,53.06 99.91,53.31 99.45,53.31 99.35,53.41 99.35,53.7 99.22,53.83 97.65,53.83 97.58,53.77 RC459.2 97.1,53.93 RC987.1
HDA_BIT_CLK_R: length 123.5
  TOP w0.102: UA1.5 20.21,40.83 20.1,40.94 20.1,42.28 RA53.2 20.84,42.36 v3(20.84,41.93)
  BOTTOM w0.076: 94.22,53.93 CC296.1 95.19,54.31 96.91,54.31 96.95,54.35 RC459.1
  BOTTOM w0.102: 94.22,53.93 v1(93.2,53.93) 91.17,53.93 89.01,51.77 89.01,47.06 80.3,38.35 80.3,25.74 79.87,25.31 79.87,22.07 77.73,19.93 31.83,19.93 28.2,23.56 28.2,29.78 28.05,29.93 28.05,33.42 27.41,34.06 27.41,34.82 24.3,37.93 24.3,41.23 23.6,41.93 20.84,41.93 v3(20.84,41.93)
HDA_RST#: length 4.5
  BOTTOM w0.076: RC950.2 101.39,56.41 102.47,55.33 103.41,55.33 103.47,55.38 103.54,55.4 103.65,55.52 103.65,55.77 103.75,55.87 104.36,55.87 UC1.BL35
HDA_RST#_R: length 125.5
  TOP w0.102: v3(25.45,43.97) 25.45,44.47 25.6,44.63 QA2.3 25.6,45.48 27.25,47.13 v1(27.25,47.57)
  BOTTOM w0.076: 94.22,54.95 94.34,54.95 94.48,54.81 96.65,54.81 97.03,55.2 98.73,55.2 99.94,56.41 RC950.1
  BOTTOM w0.102: 94.22,54.95 90.85,54.95 87.98,52.08 87.98,47.52 78.77,38.31 78.77,23.01 76.64,20.87 32.22,20.87 29.14,23.95 29.14,29.56 29.51,29.92 29.51,34.82 28.35,35.97 28.04,35.97 25.24,38.77 25.24,41.94 24.87,42.31 24.87,43.4 v3(25.45,43.97)
HDA_SDIN0: length 137.7
  TOP w0.102: RA26.2 v3(18.48,44.29) ; v1(29.55,45.07) 29.32,45.3 v3(29.32,45.87)
  IN2 w0.076: v3(101.72,54.43) 101.08,53.79 101.08,52.63 100.1,51.65 100.1,51.33 99.86,51.09 99.31,51.09 99.04,50.82 99.04,48.37 98.02,46.15 96.18,44.32
  IN2 w0.127: 96.18,44.32 96.09,44.32 94.98,43.2 91.68,43.2 88.46,39.99 85.22,39.99 67.48,22.24 30.93,22.24 29.1,24.07 29.1,26.82 32.94,30.65 32.94,42.25 v3(29.32,45.87)
  BOTTOM w0.076: v3(101.72,54.43) 101.56,54.59 101.38,54.59 CC312.2 101.29,54.96 103.38,54.96 103.55,54.79 103.65,54.76 104.12,54.76 104.48,54.4 UC1.BN35
  BOTTOM w0.102: v3(18.48,44.29) 19.17,44.98 22.33,44.98 23.1,45.74 23.1,47.35 25.17,49.42 26.53,49.42 27.67,48.28 27.67,45.74 28.05,45.36 28.81,45.36 v3(29.32,45.87)
HDA_SDIN0_R: length 2.8
  TOP w0.102: UA1.7 19.41,41.18 v1(19.1,41.48) 19.1,42.07 RA26.1
HDA_SDOUT: length 6.9
  TOP w0.076: v1(101.19,56.55) RC980.1 101.85,55.56 102.31,55.1 v3(102.31,54.44)
  BOTTOM w0.076: UC1.BN36 103.96,54.47 103.84,54.59 103.62,54.59 103.46,54.65 103.43,54.68 102.55,54.68 v3(102.31,54.44) 101.84,53.97 RC951.2 101.19,53.35 RC77.2
HDA_SDOUT_R: length 127.2
  TOP w0.102: v1(20.41,41.49) 20.71,41.19 v3(20.71,41.06) 20.61,40.96 UA1.4
  BOTTOM w0.076: RC951.1 100.17,54.07 98.66,54.07 RC1156.2 98.19,54.57 98,54.76 97.06,54.76 96.78,54.48 94.64,54.48 94.58,54.42 94.22,54.42
  BOTTOM w0.102: v3(20.71,41.06) 20.18,41.6 20.18,42.18 20.4,42.41 23.81,42.41 24.79,41.43 24.79,38.21 27.67,35.33 28.35,35.33 29.05,34.63 29.05,30.34 28.69,29.98 28.69,23.76 32.03,20.41 77.09,20.41 79.23,22.55 79.23,38.12 88.44,47.33 88.44,51.89 90.97,54.42 94.22,54.42
HDA_SPKR: length 136.8
  TOP w0.102: v1(14.04,45.53) 14.5,45.53 v3(14.76,45.28) CA43.1
  IN2 w0.127: v3(101.32,45.45) 101.58,45.18 101.58,44.34 100.69,43.45 100.69,41.79 100.26,41.36 98.16,41.36 97.05,40.24 96.21,40.24 95.87,39.9 93.2,39.9 91.74,38.44 91.11,38.44 90.91,38.25 90.91,37.17 87.61,33.87 87.61,32.66 86.03,31.07 76.66,31.07 67.58,21.99 30.83,21.99 28.85,23.97 28.85,26.98 32.66,30.79 32.66,41.76 v3(28.56,45.87)
  BOTTOM w0.076: RC117.2 101.01,45.45 v3(101.32,45.45) 101.32,45.49 102.07,46.25 102.07,46.53 102.69,47.15 102.97,47.15 103.1,47.27 103.49,47.27 103.69,47.16 104.31,47.16 UC1.CF35
  BOTTOM w0.102: v3(14.76,45.28) 15.62,45.28 16.08,45.74 17.13,45.74 21.19,49.8 26.91,49.8 28.05,48.66 28.05,46.38 v3(28.56,45.87)
HDA_SYNC: length 6.2
  BOTTOM w0.076: RC949.2 101.77,55.64 102.26,55.16 103.48,55.16 103.56,55.24 103.74,55.29 104.6,55.29 104.67,55.36 105.15,55.36 105.17,55.34 105.66,55.34 105.89,55.11 105.89,54.8 105.49,54.4 UC1.BN34
HDA_SYNC_R: length 128.5
  TOP w0.102: v1(17.45,41.29) 17.93,41.29 v3(18.13,41.09) 18.61,40.62 UA1.9
  BOTTOM w0.076: 94.22,54.65 96.71,54.65 97.1,55.04 98.8,55.04 99.41,55.64 RC949.1
  BOTTOM w0.102: 94.22,54.65 90.88,54.65 88.21,51.98 88.21,47.42 79,38.21 79,22.78 76.87,20.64 32.12,20.64 28.91,23.85 28.91,29.71 29.28,30.08 29.28,34.72 28.29,35.71 27.92,35.71 25.01,38.62 25.01,41.53 23.9,42.64 19.69,42.64 v3(18.13,41.09)
HDMI_CLKN: length 1.9
  BOTTOM w0.102: RG117.2 19.63,119.06 CG15.2 19.27,118.7 19.02,118.7 RG60.1
HDMI_CLKP: length 1.9
  BOTTOM w0.102: RG59.1 19.06,118.49 19.24,118.49 CG14.2 19.59,117.41 RG116.2
HDMI_CTRL_CLK: length 23.3
  TOP w0.102: QG2.6 16.76,128.59 v3(17.13,128.23) ; RG105.2 v3(14.41,128.75)
  IN2 w0.127: v3(12.87,124.35) 12.87,125.18 12.34,125.71 11.09,125.71 10.59,125.21 10.59,124.14 JHDMI.15
  BOTTOM w0.102: v3(14.41,128.75) 16.35,128.75 16.94,128.16 17.06,128.16 v3(17.13,128.23) 17.19,128.23 17.24,128.18 18.06,128.18 19.24,127 19.24,123.41 18.78,122.96 17.51,122.96 CM26.1 16.23,123.46 15.84,123.85 DG1.4 DG1.7 13.37,123.85 v3(12.87,124.35)
HDMI_CTRL_DAT: length 17.3
  TOP w0.102: v2(16.95,123.2) 16.35,123.79 v3(16.35,124.04) ; v3(14.41,130.83) RG109.2 14.71,130.2 15.01,130.49 QG2.3
  IN2 w0.127: v3(16.35,124.04) 14.83,125.56 14.83,129.64 14.41,130.06 v3(14.41,130.83)
  BOTTOM w0.102: JHDMI.16 12.35,124.85 DG1.8 DG1.2 16.63,124.85 CM27.1 16.56,124.04 v3(16.35,124.04)
HDMI_HPD: length 3.4
  TOP w0.102: RG56.1 19.34,129.37 19.27,129.31 QG1.6 18.82,128.71 18.78,128.75 RG108.1 v1(18.14,129.76)
HDMI_R_CLKN: length 9
  BOTTOM w0.102: JHDMI.12 11.94,121.66 12.18,121.66 12.9,120.93 12.9,119.87 13.25,119.52 14.1,119.52 14.24,119.66 D21.7 D21.4 15.75,119.66 15.89,119.52 16.17,119.52 16.45,119.24 16.45,118.84 16.57,118.73 16.72,118.73 CG71.1 17.37,118.69 17.56,118.69 RG60.2
HDMI_R_CLKP: length 9
  BOTTOM w0.102: JHDMI.10 11.94,121.44 12.09,121.44 12.68,120.84 12.68,119.78 13.16,119.3 14.12,119.3 14.27,119.16 D21.6 D21.5 15.77,119.16 15.91,119.3 16.08,119.3 16.24,119.15 16.24,118.75 16.48,118.51 16.63,118.51 CG71.2 17.28,118.37 17.65,118.37 RG59.2
HDMI_R_TX_N0: length 17.2
  IN2 w0.127: JHDMI.9 10,120.29 10.13,120.16 10.55,120.16 10.91,119.8 10.91,116.5 11.2,116.21 12.2,116.21 12.53,116.54 12.53,120.64 12.93,121.04 13.46,121.04 v3(13.63,121.2)
  BOTTOM w0.102: RG13.2 17.56,121.74 17.37,121.74 CG74.1 16.63,121.69 16.36,121.69 16.1,121.42 16.1,121.15 15.97,121.02 15.79,121.02 15.65,121.16 D21.1 D21.9 14.19,121.16 14.05,121.02 13.81,121.02 v3(13.63,121.2)
HDMI_R_TX_N1: length 10.4
  BOTTOM w0.102: RG10.2 17.55,115.63 17.38,115.63 CG73.1 16.63,115.59 16.44,115.59 16.16,115.31 16.16,115.04 16.04,114.92 15.94,114.92 15.8,115.07 D22.1 D22.9 14.31,115.07 14.16,114.92 13.63,114.92 12.85,115.7 12.85,118.19 12.38,118.66 11.94,118.66 JHDMI.6
HDMI_R_TX_N2: length 11
  BOTTOM w0.102: JHDMI.3 10.39,117.16 10.66,117.16 10.89,116.92 10.89,116.66 13.29,114.26 13.29,113.81 13.68,113.42 14.16,113.42 14.3,113.57 D22.7 D22.4 15.74,113.57 15.88,113.42 16.11,113.42 16.37,113.16 16.37,112.8 16.56,112.61 16.7,112.61 CG72.2 17.37,112.59 17.56,112.59 RG63.2
HDMI_R_TX_P0: length 17.2
  IN2 w0.127: v3(13.63,120.62) 13.46,120.78 13.04,120.78 12.78,120.53 12.78,116.44 12.31,115.96 11.1,115.96 10.66,116.39 10.66,119.69 10.44,119.91 10.13,119.91 10,119.78 JHDMI.7
  BOTTOM w0.102: RG12.2 17.55,121.52 17.38,121.52 CG74.2 16.72,121.47 16.45,121.47 16.31,121.33 16.31,121.06 16.06,120.8 15.76,120.8 15.62,120.66 D21.2 D21.8 14.22,120.66 14.07,120.8 13.81,120.8 v3(13.63,120.62)
HDMI_R_TX_P1: length 10.4
  BOTTOM w0.102: JHDMI.4 11.94,118.44 12.29,118.44 12.63,118.1 12.63,115.61 13.54,114.71 14.12,114.71 14.27,114.57 D22.8 D22.2 15.8,114.57 15.94,114.71 16.13,114.71 16.38,114.95 16.38,115.22 16.53,115.37 16.72,115.37 CG73.2 17.36,115.4 17.57,115.4 RG65.2
HDMI_R_TX_P2: length 11.1
  BOTTOM w0.102: RG61.2 17.55,112.38 17.38,112.38 CG72.1 16.66,112.39 16.47,112.39 16.15,112.71 16.15,113.07 16.02,113.21 15.88,113.21 15.73,113.07 D22.5 D22.6 14.32,113.07 14.18,113.21 13.59,113.21 13.08,113.72 13.08,114.17 10.68,116.58 10.68,116.83 10.57,116.94 10.39,116.94 JHDMI.1
HDMI_TX_N0: length 1.9
  BOTTOM w0.102: RG13.1 19.02,121.75 19.27,121.75 CG13.2 19.63,122.11 RG119.2
HDMI_TX_N1: length 1.9
  BOTTOM w0.102: RG10.1 19.03,115.64 19.26,115.64 CG11.2 19.59,116.69 RG115.2
HDMI_TX_N2: length 1.9
  BOTTOM w0.102: RG63.1 19.05,112.58 19.25,112.58 CG9.2 19.59,113.65 RG113.2
HDMI_TX_P0: length 1.9
  BOTTOM w0.102: RG118.2 19.59,120.45 CG12.2 19.24,121.53 19.06,121.53 RG12.1
HDMI_TX_P1: length 1.9
  BOTTOM w0.102: RG65.1 19.05,115.42 19.25,115.42 CG10.2 19.59,114.36 RG114.2
HDMI_TX_P2: length 1.9
  BOTTOM w0.102: RG61.1 19.03,112.36 19.26,112.36 CG8.2 19.59,111.31 RG112.2
HOST_DP1_CTRL_CLK: length 225.5
  TOP w0.102: QG2.1 16.76,131.43 16.86,131.53 RG110.2 17.46,131.53 v1(17.89,131.1) 17.94,131.05 19.05,131.05 19.5,131.5 v3(19.5,131.71)
  IN2 w0.076: v3(120.96,48.46) 120.62,48.16 120.51,48.17 120.5,48.17 120.42,48.25 120.42,49.39 120.86,49.83 121.8,49.83 122.28,50.31 122.28,50.59 122.57,50.87 123.76,50.87 126.03,49.93 129.51,49.93 130.23,49.21 130.6,49.21 v3(130.83,48.97)
  IN2 w0.127: v3(139.3,61.79) 139.44,61.93 139.76,61.93 140.06,62.24 140.06,62.76 139.3,63.52 139.3,65.34 137.32,67.32 137.32,69.74 137.73,70.14 137.73,71.31 139.48,73.07 141.44,73.07 144.99,76.62 144.99,84.78 145.37,85.16 145.37,86.98 133.65,98.7 133.65,102.21 131.7,104.17 120.12,104.17 116.11,108.19 108.36,108.19 106.95,109.6 91.92,109.6 91.47,109.15 82.67,109.15 79.89,111.93 64.84,111.93 63.67,110.76 53.7,110.76 52.21,112.26 34.56,112.26 34.01,112.81 32.08,112.81 31.73,112.47 25.83,112.47 25.26,113.04 25.26,128.8 21.78,132.28 20.29,132.28 19.72,131.71 v3(19.5,131.71)
  BOTTOM w0.076: UC1.CC8 121.3,48.22 121.06,48.46 v3(120.96,48.46) ; 136.17,53.42 136.15,53.42 136.09,53.48 135.36,53.48 132.32,50.44 132.32,50.06 131.49,49.23 131.1,49.23 v3(130.83,48.97)
  BOTTOM w0.102: v3(139.3,61.79) 139.05,61.54 139.05,54.87 137.6,53.42 136.17,53.42
HOST_DP1_CTRL_DATA: length 230.3
  TOP w0.102: QG2.4 15.46,128.4 15.4,128.34 RG111.2 15.4,127.82 15.78,127.44 15.82,127.44 16.49,126.77 17,126.77 17.57,127.34 17.57,130.45 17.89,130.77 19.16,130.77 19.69,131.3 v3(19.91,131.3)
  IN2 w0.076: v3(130.83,49.56) 130.65,49.37 130.3,49.37 129.57,50.1 126.06,50.1 123.79,51.04 122.5,51.04 122.12,50.65 122.12,50.38 121.73,49.99 120.78,49.99 120.26,49.47 120.26,48.18 120.43,48 120.5,48 120.76,47.99 v3(120.97,47.75)
  IN2 w0.127: v3(19.91,131.3) 19.91,131.46 20.42,131.97 21.66,131.97 24.95,128.68 24.95,112.91 25.7,112.16 25.95,112.16 31.86,112.16 32.21,112.51 33.89,112.51 34.44,111.96 52.08,111.96 53.58,110.46 63.8,110.46 64.97,111.63 79.76,111.63 82.54,108.84 91.6,108.84 92.05,109.3 106.82,109.3 108.24,107.88 115.98,107.88 120,103.87 131.57,103.87 133.35,102.09 133.35,98.57 145.07,86.85 145.07,85.29 144.69,84.91 144.69,76.75 141.32,73.37 139.36,73.37 137.42,71.44 137.42,70.27 137.02,69.86 137.02,67.2 139,65.22 139,63.39 139.76,62.63 139.76,62.36 139.63,62.24 139.44,62.24 v3(139.3,62.38)
  BOTTOM w0.076: UC1.CC9 120.78,48.08 v3(120.97,47.75) ; 136.17,53.7 136.15,53.7 136.09,53.64 135.29,53.64 132.15,50.5 132.15,50.13 131.42,49.4 130.99,49.4 v3(130.83,49.56)
  BOTTOM w0.102: 136.17,53.7 137.48,53.7 138.77,54.99 138.77,61.84 v3(139.3,62.38)
HOST_DP1_HPD: length 226.8
  TOP w0.102: v3(30.32,93.48) v2(30.32,92.59) ; v3(18.65,125.18) 19.21,125.74 RG47.2 19.27,125.94 QG1.1
  IN1 w0.127: v3(30.32,93.48) 29.84,93.48 28.82,94.5 28.82,99.3 28.23,99.88 27.05,99.88 18.65,108.28 18.65,115.21 17.89,115.97 17.89,124.9 18.17,125.18 v3(18.65,125.18)
  IN2 w0.076: 106.7,40.63 113.22,47.16 114.54,47.16 115.2,46.5 115.62,46.5 115.93,46.18 115.93,45.24 116.23,44.94 116.53,44.94 116.82,45.24 116.82,45.49 117.01,45.68 117.01,46.06 117.2,46.25 117.78,46.25 118.03,45.99 118.03,44.22 118.35,43.9 118.79,43.9 119.05,44.15 119.87,44.15 120,44.28 123.15,44.28 v3(123.5,43.93)
  IN2 w0.127: 106.7,40.63 105.63,39.57 104.51,39.57 102.24,40.51 101.43,40.51 99.79,38.87 99.79,37.35 99.55,37.1 98.15,37.1 97.65,36.6 94.03,36.6 91.87,34.44 88.88,34.44 88.02,33.57 88.02,32.43 86.15,30.56 79.93,30.56 77.71,28.34 v3(77.71,27.71) ; v3(30.32,93.48) 30.13,93.48 27.19,90.55 27.19,68.99 28.28,67.9 28.28,53.34 36.86,44.76 36.86,26.28 36.57,25.99 v3(36.57,22.75)
  BOTTOM w0.076: UC1.CN6 123.13,43.09 123.13,43.6 123.46,43.93 v3(123.5,43.93)
  BOTTOM w0.102: v3(36.57,22.75) 36.57,22.26 36.99,21.84 75.77,21.84 77.71,23.77 v3(77.71,27.71)
HOST_DP1_N0: length 154.3
  IN2 w0.076: v3(123.48,67.98) 123.3,68.15 123.3,68.33 123.09,68.54 121.72,68.54 120.89,69.37 120.89,72.28 120.61,72.56 120.61,76.37 120.23,76.75
  IN2 w0.127: v3(21.18,112.77) 21.32,112.63 21.64,112.63 21.92,112.36 21.92,110.61 18.61,107.31 18.61,101.66 20.18,100.1 20.18,95.77 21.42,94.53 25.74,94.53 28.22,97.01 39.98,97.01 44.4,101.43 56.52,101.43 57.49,102.4 70.72,102.4 70.97,102.15 75.16,102.15 76.49,100.82 91.45,100.82 92.35,99.92 103.97,99.92 105.61,98.28 110.11,98.28 112.48,95.91 113.86,95.91 115.27,94.49 115.27,88.56 116.44,87.4 117.05,87.4 118.42,86.03 118.42,80.05 118.69,79.78 118.69,78.02 119.96,76.75 120.23,76.75
  BOTTOM w0.076: UC1.AL5 123.45,67.99 v3(123.48,67.98)
  BOTTOM w0.102: v3(21.18,112.77) 21,112.59 20.84,112.59 CG9.1
HOST_DP1_N1: length 156
  IN2 w0.076: v3(122.97,69.88) 122.97,69.63 122.89,69.54 122.56,69.54 122.31,69.3 121.65,69.3 121.27,69.68 121.27,72.85 121.13,72.98 121.13,76.8 120.42,77.51
  IN2 w0.127: v3(21.18,115.82) 21.28,115.72 21.61,115.72 22.01,115.33 22.01,113.79 22.55,113.25 22.55,110.34 19.25,107.04 19.25,102.27 20.81,100.71 20.81,96.03 21.68,95.16 25.48,95.16 27.96,97.64 39.54,97.64 44.01,102.12 56.31,102.12 57.22,103.03 70.99,103.03 71.24,102.78 75.43,102.78 76.76,101.45 91.71,101.45 92.61,100.55 104.24,100.55 105.33,99.46 109.96,99.46 111.62,97.81 112.85,97.81 116.15,94.51 116.15,89.85 119.05,86.95 119.05,80.32 119.33,80.04 119.33,78.29 120.1,77.51 120.42,77.51
  BOTTOM w0.076: UC1.AJ5 v3(122.97,69.88)
  BOTTOM w0.102: CG11.1 20.51,115.89 20.76,115.63 21,115.63 v3(21.18,115.82)
HOST_DP1_N2: length 164.3
  IN2 w0.076: v3(122.9,70.82) 123.12,71.04 123.77,71.04 124.19,71.46 124.19,73.01 124,73.2 124,75.79 123.97,75.82 123.97,76.34 124.11,76.47 124.14,76.47 124.15,76.48
  IN2 w0.127: v3(21.18,121.91) 21.35,121.75 21.72,121.75 21.99,121.47 21.99,119.33 22.84,118.48 22.84,116.29 23.28,115.85 23.28,114.32 23.82,113.78 23.82,111.54 24.2,111.16 24.2,109.41 22.94,108.16 22.94,105.15 22.08,104.28 22.08,96.56 22.21,96.43 24.62,96.43 25.7,97.51 25.7,99.4 26.27,99.97 30.53,99.97 31.58,98.91 39.01,98.91 42.78,102.69 42.78,103.88 43.2,104.3 71.51,104.3 71.76,104.05 75.95,104.05 77.28,102.72 92.24,102.72 93.14,101.82 104.96,101.82 105.96,100.82 112.43,100.82 113.67,99.58 113.67,99.35 118.09,94.93 118.09,91.15 120.34,88.9 120.34,88.17 121.9,86.61 121.9,85.98 122.39,85.49 123.72,85.49 124.53,84.68 124.53,79.17 124.02,78.67 124.02,78.22 124.37,77.87 124.37,76.7 124.22,76.55 124.15,76.48
  BOTTOM w0.076: UC1.AF6 122.6,71.12 v3(122.9,70.82)
  BOTTOM w0.102: v3(21.18,121.91) 21,121.73 20.76,121.73 20.51,121.98 CG13.1
HOST_DP1_N3: length 154.6
  IN2 w0.076: v3(123.67,72.55) 123.47,72.75 123.47,72.92 123.23,73.16 121.89,73.16 121.77,73.28 121.77,77.76 121.13,78.4 121.13,82.06 121.15,82.08 121.15,82.1
  IN2 w0.127: 121.15,82.1 121.15,86.14 119.24,88.05 119.24,88.38 116.78,90.84 116.78,94.91 113.12,98.57 111.85,98.57 110.32,100.1 105.62,100.1 104.53,101.19 92.87,101.19 91.97,102.09 77.02,102.09 75.69,103.42 71.5,103.42 71.25,103.67 56.96,103.67 56.06,102.76 43.76,102.76 39.27,98.28 27.38,98.28 24.89,95.8 21.94,95.8 21.45,96.3 21.45,107.59 23.57,109.71 23.57,110.9 23.19,111.28 23.19,113.51 22.64,114.06 22.64,115.59 22.21,116.02 22.21,118.22 21.66,118.77 21.28,118.77 v3(21.18,118.87)
  BOTTOM w0.076: UC1.AE5 v3(123.67,72.55)
  BOTTOM w0.102: v3(21.18,118.87) 21,118.68 20.76,118.68 20.51,118.94 CG15.1
HOST_DP1_P0: length 154.2
  IN2 w0.076: 120.12,76.5 120.35,76.27 120.35,72.46 120.68,72.13 120.68,69.34 121.65,68.37 123.03,68.37 123.14,68.26 123.14,68.18 123.14,68.09 122.97,67.93 122.86,67.93 v3(122.81,67.98)
  IN2 w0.127: 120.12,76.5 119.86,76.5 118.44,77.92 118.44,79.67 118.16,79.95 118.16,85.92 116.95,87.14 116.34,87.14 115.02,88.46 115.02,94.38 113.75,95.65 112.38,95.65 110,98.03 105.51,98.03 103.87,99.66 92.24,99.66 91.34,100.56 76.39,100.56 75.06,101.89 70.87,101.89 70.62,102.14 57.59,102.14 56.62,101.18 44.51,101.18 40.09,96.76 28.33,96.76 25.84,94.27 21.31,94.27 19.92,95.66 19.92,99.99 18.36,101.55 18.36,107.41 21.66,110.71 21.66,112.25 21.53,112.38 21.33,112.38 21.18,112.23 v3(21.18,112.19)
  BOTTOM w0.076: v3(122.81,67.98) 122.85,68.09 122.71,68.4 UC1.AL6
  BOTTOM w0.102: v3(21.18,112.19) 21,112.37 20.84,112.37 CG8.1
HOST_DP1_P1: length 155.9
  IN2 w0.076: 120.31,77.26 120.93,76.65 120.93,72.9 121.06,72.76 121.06,69.59 121.56,69.09 122.4,69.09 122.64,69.34 122.91,69.34 122.98,69.27 122.98,69.06 122.92,68.99 v3(122.91,68.99)
  IN2 w0.127: 120.31,77.26 119.99,77.26 119.07,78.18 119.07,79.94 118.8,80.21 118.8,86.84 115.9,89.74 115.9,94.4 112.74,97.56 111.51,97.56 109.86,99.21 105.22,99.21 104.13,100.3 92.51,100.3 91.61,101.2 76.65,101.2 75.32,102.53 71.13,102.53 70.88,102.78 57.33,102.78 56.41,101.86 44.11,101.86 39.64,97.39 28.06,97.39 25.58,94.91 21.58,94.91 20.56,95.93 20.56,100.6 18.99,102.17 18.99,107.15 22.3,110.45 22.3,113.14 21.75,113.69 21.75,115.22 21.51,115.46 21.41,115.46 v3(21.18,115.23)
  BOTTOM w0.076: v3(122.91,68.99) 122.9,68.99 122.6,69.29 UC1.AJ6
  BOTTOM w0.102: CG10.1 20.51,115.16 20.76,115.42 21,115.42 v3(21.18,115.23)
HOST_DP1_P2: length 164.3
  IN2 w0.076: v3(122.92,71.65) 122.8,71.65 122.66,71.51 122.66,71.28 122.74,71.2 123.7,71.2 124.02,71.53 124.02,72.94 123.83,73.13 123.83,75.73 123.81,75.75 123.81,76.46 123.96,76.61 123.96,76.65 123.98,76.66
  IN2 w0.127: v3(21.18,121.33) 21.35,121.5 21.61,121.5 21.74,121.37 21.74,119.23 22.59,118.37 22.59,116.18 23.02,115.75 23.02,114.21 23.57,113.67 23.57,111.44 23.95,111.06 23.95,109.52 22.69,108.26 22.69,105.25 21.83,104.39 21.83,96.45 22.1,96.18 24.73,96.18 25.95,97.41 25.95,99.29 26.38,99.72 30.42,99.72 31.48,98.66 39.11,98.66 43.04,102.58 43.04,103.78 43.31,104.05 71.41,104.05 71.66,103.8 75.85,103.8 77.18,102.47 92.13,102.47 93.03,101.57 104.85,101.57 105.85,100.57 112.32,100.57 113.42,99.47 113.42,99.25 117.84,94.83 117.84,91.04 120.09,88.79 120.09,88.07 121.65,86.51 121.65,85.87 122.28,85.24 123.61,85.24 124.28,84.57 124.28,79.28 123.77,78.77 123.77,78.11 124.11,77.77 124.11,76.8 123.98,76.66
  BOTTOM w0.076: v3(122.92,71.65) 123.25,71.32 UC1.AF5
  BOTTOM w0.102: v3(21.18,121.33) 21,121.51 20.76,121.51 20.51,121.26 CG12.1
HOST_DP1_P3: length 154.6
  IN2 w0.076: 120.9,82.1 120.9,82.08 120.93,82.06 120.93,78.32 121.56,77.68 121.56,73.19 121.76,72.99 123.16,72.99 123.3,72.85 123.3,72.55 123.22,72.48 123.04,72.48 v3(122.97,72.55)
  IN2 w0.127: v3(21.18,118.28) 21.41,118.51 21.55,118.51 21.95,118.11 21.95,115.92 22.39,115.48 22.39,113.95 22.93,113.41 22.93,111.17 23.31,110.79 23.31,109.82 21.19,107.69 21.19,96.19 21.84,95.54 25,95.54 27.48,98.03 39.38,98.03 43.86,102.51 56.16,102.51 57.07,103.41 71.15,103.41 71.39,103.16 75.59,103.16 76.92,101.83 91.87,101.83 92.77,100.93 104.42,100.93 105.52,99.84 110.22,99.84 111.74,98.32 113.01,98.32 116.53,94.8 116.53,90.73 118.99,88.27 118.99,87.94 120.9,86.03 120.9,82.1
  BOTTOM w0.076: v3(122.97,72.55) 122.97,72.5 UC1.AE6
  BOTTOM w0.102: CG14.1 20.51,118.21 20.76,118.47 21,118.47 v3(21.18,118.28)
HOST_SPI_0_CLK: length 43.8
  BOTTOM w0.076: UC1.CH37 103.25,45.55 102.79,45.09 102.79,44.27 101.8,43.29 101.8,42.68 101.29,42.17 101.29,41.57 100.16,40.44 100.16,39.24 100.05,39.12 100.05,38.3 99.7,37.95 99.7,36.41 RC986.1 99.17,35.87 99.17,34.96 99.53,34.6 99.53,34.35
  BOTTOM w0.102: RC456.1 126.7,37.08 126.16,37.08 125.32,36.24 122.11,36.24 RT6.1 120.67,35.71 119.53,34.57 117.96,34.57 117.06,33.66 114.91,33.66 114.47,33.23 113.1,33.23 112.11,32.24 v3(103.15,32.24) 101.09,32.24 99.53,33.8 99.53,34.35
HOST_SPI_0_CLK_R: length 45.4
  IN2 w0.127: v3(138.41,35.24) 138.34,35.17 131.52,35.17 129.57,37.12 129.39,37.12 v3(129.32,37.06)
  BOTTOM w0.102: UC2.6 130.81,26.84 130.81,29.08 131.01,29.28 131.01,34.13 130.83,34.5 129.47,35.86 129.29,36.3 129.29,37.03 v3(129.32,37.06) 129.03,37.35 128.12,37.75 CC295.2 RC456.2 ; v3(138.41,35.24) 139.27,36.1 139.27,40.52 143.92,45.17 144.92,45.17 145.11,45.36 146.91,45.36 147.51,45.96 RC369.2 CC144.1
HOST_SPI_0_CLK_R_TPM: length 41.1
  TOP w0.102: UT1.19 152.89,24.39 152.64,24.65 150.57,24.65 149.92,24 149.92,23.49 149.31,22.88 148.23,22.88 147.82,22.47 146.55,22.47 v1(146.38,22.65) 145.83,23.2 v3(145.83,23.72)
  IN2 w0.127: v3(129.84,28.37) 130.31,28.84 131.95,28.84 132.14,28.65 138.32,28.65 138.9,28.07 140.48,28.07 140.92,27.64 140.92,27.24 141.22,26.93 141.69,26.93 142.87,25.76 142.87,24.3 143.04,24.13 144.09,24.13 144.5,23.72 v3(145.83,23.72)
  BOTTOM w0.102: v3(129.84,28.37) 129.84,28.91 127.88,30.87 126.01,30.87 125.33,31.55 125.33,32.94 124.77,33.5 124.77,33.87 124.77,33.87 124.77,34.02 124.03,34.76 123.87,34.82 122.99,35.71 RT6.2
HOST_SPI_0_CS0#: length 10.3
  TOP w0.102: v3(121.4,33.6) v2(120.74,32.95)
  IN2 w0.127: v3(121.4,33.6) 121.95,33.6 v3(123.86,35.52)
  BOTTOM w0.102: v3(123.86,35.52) 124.14,35.23 124.3,35.17 124.73,34.74 RC357.1 RC948.2 125.9,34.16 CC9.1 125.98,33.7 126.09,33.59 UC2.1 ; RC1160.1 121.37,33.57 v3(121.4,33.6)
HOST_SPI_0_CS0#_R: length 39.4
  TOP w0.102: v2(100.15,32.74) 100.15,32.16 v3(99.75,31.77)
  BOTTOM w0.076: UC1.CG36 103.19,46.2 102.9,45.91 102.9,45.91 102.41,45.42 102.41,44.94 102,44.53 102,44.14 101.33,43.47 101.33,42.88 100.87,42.42 100.87,41.79 99.73,40.65 99.73,39.53 99.64,39.44 99.64,38.42 99.43,38.21 99.17,38.21 98.53,37.57 98.53,34.9 98.67,34.76 98.67,34.35
  BOTTOM w0.102: RC1160.2 117.97,33.57 117.35,32.95 115.59,32.95 115.16,32.52 113.4,32.52 112.29,31.41 100.11,31.41 v3(99.75,31.77) 99.75,32.34 98.67,33.42 98.67,34.35
HOST_SPI_0_CS2#: length 80.1
  TOP w0.102: RT7.1 150.45,23.67 150.45,23.34 149.51,22.4 v1(148.95,22.4) 148.67,22.4 148.43,22.15 v3(148.43,21.98)
  IN2 w0.127: v3(129.25,26.72) 129.69,26.28 134.21,26.28 135.07,25.42 139.63,25.42 140.36,24.7 140.36,24.04 142.41,21.99 148.42,21.99 v3(148.43,21.98)
  BOTTOM w0.076: 99,34.35 99,34.76 98.79,34.97 98.79,37.59 99.24,38.04 99.5,38.04 99.83,38.38 99.83,39.31 99.96,39.44 99.96,40.62 101.08,41.75 101.08,42.31 101.58,42.81 101.58,43.39 102.6,44.41 102.6,45.36 103.11,45.87 105.01,45.87 105.26,45.61 UC1.CH34
  BOTTOM w0.102: v3(129.25,26.72) 129.36,26.83 129.36,28.6 127.57,30.39 125.81,30.39 124.82,31.38 124.82,32.76 124.29,33.3 124.29,33.82 123.76,34.35 123.6,34.42 122.79,35.22 120.87,35.22 119.73,34.09 118.16,34.09 117.26,33.18 115.5,33.18 115.06,32.75 113.3,32.75 112.29,31.73 100.91,31.73 99,33.64 99,34.35
HOST_SPI_0_CS2#_TPM: length 3.6
  TOP w0.102: UT1.20 152.62,23.89 152.38,24.12 RT7.2 v1(150.64,22.94)
HOST_SPI_0_HOLD#: length 16.2
  BOTTOM w0.102: UC2.7 127.36,25.14 127.92,25.7 128.1,25.7 128.54,26.15 128.54,27.63 128.39,27.78 128.21,27.78 128.1,27.88 128.1,28.08 128.21,28.18 128.86,28.18 128.95,28.27 v3(128.95,28.38) 128.95,28.5 128.86,28.6 128.21,28.6 128.1,28.7 128.1,29.42 127.37,30.16 125.71,30.16 124.06,31.82 124.06,33.68 123.68,34.06 122.59,34.06 122.49,34.16 RC942.2
HOST_SPI_0_SI: length 48.9
  TOP w0.102: v2(97.76,30.06) 97.74,30.08 v3(97.74,31.79)
  BOTTOM w0.076: UC1.CF36 103.85,46.97 103.8,46.97 103.78,46.99 103.65,46.99 103.45,47.11 103.17,47.11 103.04,46.98 102.76,46.98 102.24,46.46 102.24,46.18 101.71,45.65 101.71,45.18 101.34,44.81 101.34,44.42 100.31,43.39 98.28,43.39 97.52,42.63 97.52,41.05
  BOTTOM w0.102: 97.52,41.05 RC941.1 97.52,40.29 97.52,32 v3(97.74,31.79) 97.74,31.59 98.9,30.43 112.71,30.43 113.79,31.52 115.48,31.52 116,32.04 117.73,32.04 118.1,32.41 RT8.1 RC943.1
HOST_SPI_0_SI_R: length 16.5
  BOTTOM w0.102: UC2.5 129.9,23.77 129.73,23.59 125.55,23.59 125.17,23.97 125.17,26.66 125.74,27.22 v3(125.74,27.82) 125.74,28.46 124.2,29.99 122.44,29.99 122.21,30.22 RC947.2 123.1,31.52 RC943.2
HOST_SPI_0_SI_TPM: length 38.7
  TOP w0.102: UT1.21 153.3,23.39 152.05,23.14 151.14,22.77 v3(150.35,21.98) 150.35,21.71 v1(150.06,21.42)
  IN2 w0.127: v3(150.35,21.98) 149.64,22.69 148.15,22.69 147.96,22.5 142.64,22.5 140.86,24.27 140.86,24.91 139.84,25.93 135.28,25.93 134.34,26.87 130.73,26.87 130.41,27.19 128.92,27.19 v3(128.14,26.4)
  BOTTOM w0.102: RT8.2 125.59,29.93 127.27,29.93 127.73,29.47 127.73,27.73 128.14,27.33 v3(128.14,26.4)
HOST_SPI_0_SIO2: length 56.4
  IN2 w0.127: v3(128.85,33.3) 128.85,35 128.49,35.36 127.58,35.36 127.4,35.54 126.59,35.54 126.15,35.1 124.24,35.1 v3(122.79,33.65)
  BOTTOM w0.076: UC1.CF34 105,46.59 104.52,46.59 104.41,46.63 104.17,46.63 104.06,46.59 103.87,46.59 103.76,46.63 103.53,46.63 103.52,46.62 103.5,46.62 103.43,46.6 102.84,46.6 102.57,46.32 102.57,46.04 102.04,45.52 102.04,45.04 102,45 101.67,44.67 101.67,44.28 101,43.61 101,43.31 100.57,42.88 99.04,42.88 98.28,42.12 98.28,40.89 RC383.1 98.53,40.62 98.03,40.11 98.03,34.35
  BOTTOM w0.102: v3(128.85,33.3) 128.56,33.6 RC944.1 ; 98.03,34.35 98.03,32.94 98.76,32.2 98.76,31.5 99.38,30.89 112.41,30.89 113.55,32.02 115.34,32.02 115.81,32.49 117.54,32.49 117.92,32.88 121.57,32.88 121.86,33.17 122.59,33.17 122.79,33.37 v3(122.79,33.65)
HOST_SPI_0_SIO3: length 45.9
  TOP w0.102: v3(99.17,31.76) v2(99.17,30.97)
  BOTTOM w0.076: 98.35,34.35 98.35,37.68 99.04,38.37 99.36,38.37 99.47,38.49 99.47,39.06 RC51.1 99.17,39.38 99.5,39.71 99.5,40.3 RC384.1 99.96,41.42 100.19,41.42 100.48,41.71 100.48,42.41 101.16,43.1 101.16,43.54 101.83,44.21 101.83,44.6 102.21,44.97 102.21,45.45 102.73,45.98 102.73,46.25 102.91,46.43 103.46,46.43 103.53,46.46 103.56,46.46 103.58,46.46 103.73,46.46 103.85,46.42 104.09,46.42 104.09,46.42 104.11,46.42 104.12,46.43 104.18,46.46 104.4,46.46 104.5,46.42 104.72,46.42 UC1.CG34
  BOTTOM w0.102: RC942.1 121.57,34.28 121.85,34.01 121.85,33.48 121.48,33.11 117.83,33.11 117.45,32.72 115.71,32.72 115.28,32.29 113.49,32.29 112.32,31.11 99.82,31.11 v3(99.17,31.76) 99.17,32.12 98.35,32.94 98.35,34.35
HOST_SPI_0_SO: length 54.5
  TOP w0.102: v3(98.34,31.79) v2(98.34,33.15)
  IN2 w0.127: v3(127.95,34.95) 127.53,34.53 124.37,34.53 v3(123.49,33.65)
  BOTTOM w0.076: 97.77,34.51 97.77,42.54 98.37,43.14 100.44,43.14 100.82,43.52 100.83,43.52 100.83,43.68 101.5,44.35 101.5,44.74 101.88,45.11 101.88,45.58 102.4,46.11 102.4,46.39 102.83,46.82 103.28,46.82 UC1.CF37
  BOTTOM w0.102: RT9.1 128.18,35.07 128.05,34.95 v3(127.95,34.95) 127.95,35.38 127.82,35.5 RC945.1 ; v3(123.49,33.65) 123.49,33.17 123.24,32.91 121.93,32.91 121.67,32.65 118.02,32.65 117.64,32.27 115.9,32.27 115.41,31.77 113.72,31.77 112.61,30.66 99.1,30.66 98.34,31.41 v3(98.34,31.79) 97.77,32.36 97.77,34.51
HOST_SPI_0_SO_R: length 9.2
  BOTTOM w0.102: UC2.2 127.36,32.28 127.24,32.41 126.77,32.41 126.67,32.51 126.67,32.81 126.77,32.91 127.49,32.91 127.6,33.02 127.6,33.62 127.49,33.73 126.69,33.73 126.59,33.83 126.59,34.06 126.72,34.18 RC946.2 127.1,34.44 v3(127.1,34.95) 127.29,35.14 127.29,35.33 127.2,35.41 126.56,35.41 126.44,35.54 126.44,35.93 126.26,36.1 126.09,36.1 126.04,36.15 126.04,36.27 126.29,36.51 126.42,36.51 126.55,36.38 126.74,36.38 126.91,36.22 RC945.2
HOST_SPI_0_SO_TPM: length 36.2
  TOP w0.102: UT1.24 153.22,21.89 152.41,21.08 v1(151.53,21.08) 149.78,21.08 149.43,21.43 v3(149.43,21.98)
  IN2 w0.127: v3(149.43,21.98) 149.01,22.4 148.22,22.4 148.06,22.24 142.51,22.24 140.61,24.15 140.61,24.8 139.74,25.67 135.17,25.67 134.23,26.62 130.08,26.62 v3(129.97,26.73)
  BOTTOM w0.102: v3(129.97,26.73) 130.32,27.08 130.32,29.28 130.53,29.48 130.53,34.02 RT9.2
HOST_SPI_0_WP#: length 4.9
  BOTTOM w0.102: UC2.3 128.09,32.02 127.99,32.12 127.99,32.72 128.15,32.89 129.37,32.89 129.43,32.95 v3(129.43,33.32) 129.43,33.5 129.66,33.73 129.89,33.73 129.99,33.83 129.99,34.08 129.89,34.18 RC944.2
HP_DETECT: length 10.5
  TOP w0.102: v3(17.7,126.89) 18.14,127.33 RG108.2
  BOTTOM w0.102: JHDMI.19 10.71,126.26 12.81,126.26 13.71,125.35 DG1.9 DG1.1 16.86,125.35 CM17.1 17,126.19 v3(17.7,126.89)
HP_OUTL: length 1.6
  TOP w0.381: RA14.1 18.61,31.03 RA37.2
HP_OUTL_R: length 19.4
  TOP w0.381: v3(20.45,25.67) 20.45,28.2 20.04,28.61 CA25.1 RA14.2
  IN2 w0.381: v3(20.45,25.67) 19.18,24.4 8.23,24.4 v3(7.7,24.92)
  BOTTOM w0.635: v3(7.7,24.92) 7.7,24.93 JHP.3
HP_OUTR: length 2.4
  TOP w0.381: RA38.2 19.37,31.66 v1(20.2,30.84) 20.64,30.4 RA15.1
HP_OUTR_R: length 24.5
  TOP w0.381: RA15.2 21.15,29.11 CA26.1 21.79,28.47 v3(22.59,28.47)
  IN2 w0.381: v3(5.71,24.94) 7.39,23.26 19.92,23.26 22.59,25.93 v3(22.59,28.47)
  BOTTOM w0.635: v3(5.71,24.94) 5.7,24.95 JHP.5
HPOUT_L: length 3.1
  TOP w0.203: 19.32,33.46 19.71,33.85 19.71,34.28 19.81,34.38 UA1.25
  TOP w0.381: RA37.1 18.61,33.05 19.01,33.46 19.32,33.46
HPOUT_R: length 2.8
  TOP w0.203: UA1.26 20.21,34.75 20.11,34.66 20.11,33.96 v1(20.08,33.93) 20.08,33.54 19.52,32.97 19.51,32.97
  TOP w0.381: RA38.1 19.37,32.84 19.51,32.97
I2C0_SCL_TP: length 53.2
  TOP w0.102: v3(86.56,25.25) RC1158.1 R5265.1
  IN2 w0.076: 120.7,39.58 120.7,39.6 120.63,39.67 120.63,39.82 120.02,40.39 119.95,40.39 119.85,40.4 v3(119.66,40.62)
  IN2 w0.127: v3(87.83,27.19) 87.69,27.33 87.69,27.91 87.93,28.15 90.34,28.15 92.69,30.5 92.69,31.9 95.94,35.15 98.19,35.15 98.69,35.66 100.01,35.66 101.09,36.73 101.09,37.12 102.24,38.27 106.24,38.27 107.95,39.97 109.38,39.97 111.34,41.93 113.63,41.93 114.04,41.52 114.04,40.14 114.54,39.64 114.92,39.64 117.81,36.75 119.06,36.75 119.54,37.23 120.07,37.45 120.35,37.64 120.5,37.81 120.7,38.18 120.7,39.58
  BOTTOM w0.076: v3(119.66,40.62) 120.07,41.03 120.07,42.08 UC1.CN11
  BOTTOM w0.102: v3(86.56,25.25) 86.56,25.79 87.02,26.25 87.33,26.25 87.68,26.59 87.68,27.03 v3(87.83,27.19)
I2C0_SDA_TP: length 57.1
  TOP w0.102: RC1159.1 R5268.1 84.44,24.44 v3(84.84,24.44) ; v1(86.93,28.39) 87.24,28.07 v3(87.24,27.19)
  IN2 w0.076: v3(119.62,40.04) 119.84,40.23 119.94,40.22 119.95,40.22 120.47,39.75 120.47,39.67 120.4,39.6 120.4,39.58
  IN2 w0.127: v3(87.24,27.19) 87.38,27.33 87.38,28.04 87.8,28.46 90.22,28.46 92.39,30.63 92.39,32.02 95.82,35.45 98.06,35.45 98.57,35.96 99.89,35.96 100.78,36.86 100.78,37.24 102.12,38.58 106.12,38.58 107.82,40.28 109.26,40.28 111.21,42.23 113.76,42.23 114.35,41.64 114.35,40.27 114.66,39.95 115.04,39.95 117.94,37.05 118.93,37.05 119.37,37.49 119.93,37.72 120.15,37.87 120.25,37.98 120.4,38.26 120.4,39.58
  BOTTOM w0.076: v3(119.62,40.04) 119.24,40.42 119.24,41.3 119.42,41.48 119.42,42.88 UC1.CM11
  BOTTOM w0.102: v3(87.24,27.19) 87.4,27.03 87.4,26.7 87.22,26.52 86.9,26.52 86.28,25.9 86.28,25.67 85.05,24.44 v3(84.84,24.44)
I2C_INT: length 22.9
  BOTTOM w0.102: R5269.2 143.13,32.78 DT2.1 145.15,32.78 v1(146.03,31.9) 146.03,31.58 145.88,31.43 145.88,30.32 146.45,29.74 146.45,28.25 147.32,27.39 147.32,26.36 147.67,26 148.37,26 150.05,27.68 152.74,27.68 153.27,28.21 153.27,29.81 153.62,30.15 155.14,30.15 155.35,29.95 JTP1.7
I2CA_SCL: length 10.6
  TOP w0.102: v3(157.47,94.76) 157.13,94.43 v2(157.13,94.06)
  BOTTOM w0.102: 157.59,92.1 157.59,94.64 v3(157.47,94.76) 157.35,94.88 157.35,96.29 156.45,97.19 156.45,98.39 156.04,98.8 155.5,98.8 UV1.B7
  BOTTOM w0.127: 157.59,92.1 156.88,91.39 156.88,91.09 RV2758.1
I2CA_SDA: length 9.9
  TOP w0.102: v3(156.93,97.26) 156.93,97.5 v2(157.31,97.87)
  BOTTOM w0.102: RV2759.1 157.97,91.33 157.97,94.28 157.95,94.3 157.95,94.97 157.72,95.19 157.72,96.21 156.93,96.99 v3(156.93,97.26) 156.65,97.54 156.65,98.48 155.93,99.2 UV1.A7
I2CB_SCL: length 13.2
  TOP w0.102: v3(158.47,96.68) 158.64,96.84 v2(159.15,96.84)
  BOTTOM w0.102: UV1.C9 154.72,100.46 155.45,100.46 155.59,100.32 155.82,100.32 157.06,99.08 157.06,98.18 157.84,97.39 157.84,97.31 v3(158.47,96.68) 158.53,96.62 158.53,94.55 158.82,94.26 158.82,91.74 159.37,91.19 RV2761.1
I2CB_SDA: length 12.7
  TOP w0.102: v3(157.49,96.97) 157.49,96.04 v2(157.73,95.8)
  BOTTOM w0.102: RV2760.1 158.55,91.51 158.47,91.59 158.47,94.11 158.18,94.4 158.18,96.29 v3(157.49,96.97) 157.49,97.24 156.86,97.88 156.86,98.74 156.05,99.55 154.79,99.55 UV1.C8
I2CC_SCL: length 4.7
  BOTTOM w0.102: RV205.1 159.12,97.66 158.51,98.28 158.51,98.42 v1(158.11,98.81) 157.97,98.81 155.9,100.88 UV1.A9
I2CC_SDA: length 6.2
  BOTTOM w0.102: UV1.B9 155.36,100.88 155.72,100.52 155.97,100.52 157.31,99.18 157.31,98.43 v1(158.21,97.53) 158.84,96.9 RV206.1
I2CS_SCL: length 17.9
  TOP w0.102: v3(153.89,100.4) 154.01,100.4 v1(154.35,100.06)
  IN2 w0.127: v3(158.94,95.08) 158.42,95.6 156.57,95.6 156.08,96.09 156.08,98.44 154.12,100.4 v3(153.89,100.4)
  BOTTOM w0.102: UV1.D9 153.89,100.49 v3(153.89,100.4) ; v3(158.94,95.08) 158.94,94.64 160.36,93.22 163.31,93.22 163.93,92.6 QV2.4 165.4,92.6 RV203.1
I2CS_SDA: length 15.2
  IN2 w0.102: v3(153.87,99.6) 153.87,97.97 154.32,97.53 154.32,96.44 156.63,94.13 156.69,94.13
  IN2 w0.127: v3(159.23,93.53) 159.19,93.53 159.06,93.66 157.16,93.66 156.69,94.13
  BOTTOM w0.102: QV2.1 161.5,91.3 161.25,91.06 RV204.1 160.55,91.61 160.55,92.21 v3(159.23,93.53) ; v3(153.87,99.6) 153.87,99.67 UV1.D8
ILIM_CHG: length 4.8
  BOTTOM w0.102: v1(199.5,52.18) 199.3,52.38 PRB16.1
  BOTTOM w0.254: PUB1.10 197.98,55.59 198.68,54.89 PCB21.1 PRB20.1 199.31,53.29 PRB16.1
ILMT_1V: length 5.2
  BOTTOM w0.254: PU1001.13 186.8,92.81 187.28,92.32 v1(188.12,92.32) 188.65,92.32 189.05,91.93 189.63,91.93 189.81,91.76 PR1003.2 PR1004.1
ILMT_VRAM: length 5.5
  TOP w0.102: v3(189.38,133.43) v2(190.18,133.43)
  BOTTOM w0.254: PUW1.13 187.43,133.94 187.94,133.43 v3(189.38,133.43) 190.08,133.43 190.29,133.22 PRW3.2 PRW4.1
IMON_CORE: length 22.1
  TOP w0.102: v1(202.84,68.1) 202.41,67.67 v3(202.41,67.34)
  TOP w0.254: v3(192.26,64.03) PCZ231.1 PCZ232.1
  IN1 w0.254: v3(192.26,64.03) 192.26,67.25 194.22,69.21 200.54,69.21 v3(202.41,67.34)
  BOTTOM w0.203: PUZ1.1 200.81,68.47 201.84,67.44 201.84,66.85 PCZ9.2
  BOTTOM w0.254: PCZ9.2 PRZ35.2 202.93,66.82 v3(202.41,67.34)
IMON_CORE_R: length 76
  TOP w0.102: v1(202.69,64.71) 202.26,64.28 v3(202.04,64.28)
  IN2 w0.203: v3(202.04,64.28) 202.32,64.28 202.57,64.54 202.57,66.62 203.94,68 203.94,76.35 203.06,77.24 203.06,78.38 201.66,79.78 197.72,79.78 195.69,77.74 195.69,72.85 195.25,72.41 194.45,72.41 193.69,71.65 191.72,71.65 187.2,76.17 162.71,76.17 161.84,75.31 156.47,75.31 155.89,75.89 v3(155.43,75.89)
  BOTTOM w0.254: PHZ1.2 v3(155.43,75.89) ; PRZ35.1 202.93,64.54 PRZ33.2 202.22,64.46 v3(202.04,64.28)
IMON_GT: length 4.5
  TOP w0.102: PRZ48.1 197.57,76.88 196.99,76.88 v1(196.72,76.61)
  TOP w0.254: PCZ15.1 v3(198.23,76.47) 198.23,76.78 PRZ48.1
  BOTTOM w0.203: PUZ1.30 198.41,76.29 v3(198.23,76.47)
IMON_SA: length 5.8
  TOP w0.254: v3(203.31,74.19) v1(202.54,74.19) 202.32,74.19 201.81,74.7 PCZ4.1 PRZ13.2
  BOTTOM w0.203: PUZ1.39 202,73.38 202.04,73.43 202.23,73.43 202.99,74.19 v3(203.31,74.19)
IN_1.8V:
  vias: v1(178.14,88.81)
IN_2.5V: length 1.2
  BOTTOM w0.102: 3.34,49.33 v1(2.17,49.33)
INPUT3VSEL: length 21.5
  TOP w0.076: RC187.1 101.3,41.38 101.62,41.7 RC474.1 101.61,42.02 101.61,43.48 103.87,45.74 103.87,47.52 v1(104.81,48.46) 105.52,49.16 106.4,49.16 106.79,49.55 106.79,50.06 106.93,50.2 106.93,50.96 107.76,51.79 109.4,51.79 109.65,51.54 109.65,50.31 109.96,49.99 110.22,49.99 110.44,50.22 110.44,51.38 109.47,52.36 v3(109.29,52.36)
  BOTTOM w0.076: UC1.BT27 v3(109.29,52.36)
INT_MIC: length 11.6
  TOP w0.127: v1(16.81,30.04) 17.16,30.4 RA13.1
  TOP w0.203: v3(16.53,38.26) 16.56,38.29 UA1.14
  TOP w0.254: RA40.1 17.85,31.16 v3(17.76,31.07) 17.85,30.99 RA13.1
  IN2 w0.254: v3(16.53,38.26) 16.97,38.26 17.24,37.99 17.24,37.3 17.85,36.69 17.85,31.16 v3(17.76,31.07)
INT_MIC_R: length 10.3
  TOP w0.254: v3(10.5,26.72) v2(14.23,26.72) 14.87,26.72 16.76,28.61 CA24.1 RA13.2
  BOTTOM w0.254: v3(10.5,26.72) 9.83,26.72 9.7,26.59 JHP.1
INVPWR_B+: length 18.7
  TOP w0.102: v3(93.84,102.55) v2(92.71,102.55) ; v3(95.11,102.55) v2(96.29,102.55) ; v3(94.47,102.55) v2(94.47,103.47)
  TOP w3.048: 78.95,95.38 83.63,95.38 86.05,97.81 89.47,97.81 92.25,100.59
  vias: v3(62.47,100.97) v3(62.75,101.62) v3(63.08,100.96)
INVTPWM: length 125.4
  TOP w0.076: v3(118.47,40.83) 118.85,41.21 R163.1 119.11,41.42 118.85,41.68 R259.2
  TOP w0.102: v3(64.18,101.63) 63.97,101.63 62.64,102.95 C593.1 ; v2(113.19,89.38) v2(113.19,91.18) v3(113.19,92.1) 114.13,92.1 v2(115.06,91.17)
  IN1 w0.076: v3(118.47,40.83) 118.77,41.12 118.77,42.78 117.87,43.68 117.87,47.3 118.11,47.53 118.11,48.9 117.2,49.81 117.2,52.56 117.19,52.57 117.19,53.35 117.33,53.49 117.33,55.14 115.64,56.83 114.85,56.83 114.64,57.04 113.53,57.04 112.87,57.7 112.23,57.7 112.1,57.83 111.46,57.83 110.98,58.31 110.98,58.36 110.88,58.46
  IN1 w0.127: v3(113.19,92.1) 113.19,90.88 113.03,90.71 113.03,84.35 112.72,84.04 112.72,81.19 112.71,81.19 112.71,80.47 112.36,80.12 111.64,80.12 110.71,79.18 110.71,69.96 110.03,69.28 110.03,66.47 109.65,66.09 109.65,60.79 109.71,60.73 109.71,60.73 109.88,60.56 109.88,60.12 110.88,59.11 110.88,58.46
  IN2 w0.076: 104.28,96.44 104.55,96.16 109.32,96.16 113.19,92.29 v3(113.19,92.1)
  IN2 w0.127: 104.28,96.44 103.61,97.1 66.57,97.1 64.18,99.49 v3(64.18,101.63)
  BOTTOM w0.102: JEDP.16 64.5,100.53 64.18,100.85 v3(64.18,101.63)
IOUT_CHG: length 72.6
  TOP w0.102: v3(150.49,32.85) 153.26,35.62 153.26,35.71 162.79,45.24 168.09,45.24 v2(169.79,46.94) v3(171.03,48.18)
  IN1 w0.127: v3(150.49,32.85) 150.44,32.85 150.41,32.87 147.46,32.87 v3(147.42,32.91) ; v3(200.91,56.76) 198.74,56.76 v3(198.42,57.09)
  IN2 w0.127: v3(171.03,48.18) 172.2,47.01 173.11,46.63 175.19,46.27 185.06,46.27 187.86,49.07 191.74,49.07 192.06,49.39 197.9,49.39 200.17,51.66 200.17,55.85 200.91,56.59 v3(200.91,56.76)
  BOTTOM w0.102: PRB22.1 147.2,33.13 v3(147.42,32.91)
  BOTTOM w0.254: PCB23.1 198.89,57.56 v3(198.42,57.09) PUB1.7
ISEN1N_MAIN: length 4.7
  TOP w0.254: PRZ105.2 197.29,67.58 197.47,67.58 v3(197.72,67.33) 197.56,67.17 197.44,67.17 v1(197.21,66.95) 197.21,66.44 196.71,65.93 PRZ106.2
  BOTTOM w0.203: v3(197.72,67.33) 198.01,67.62 PUZ1.8
IST_TRIG: length 10
  BOTTOM w0.076: T377.1 102.48,33.21 102.47,33.22 102.47,39.77 104.08,41.38 104.08,42 UC1.CP36
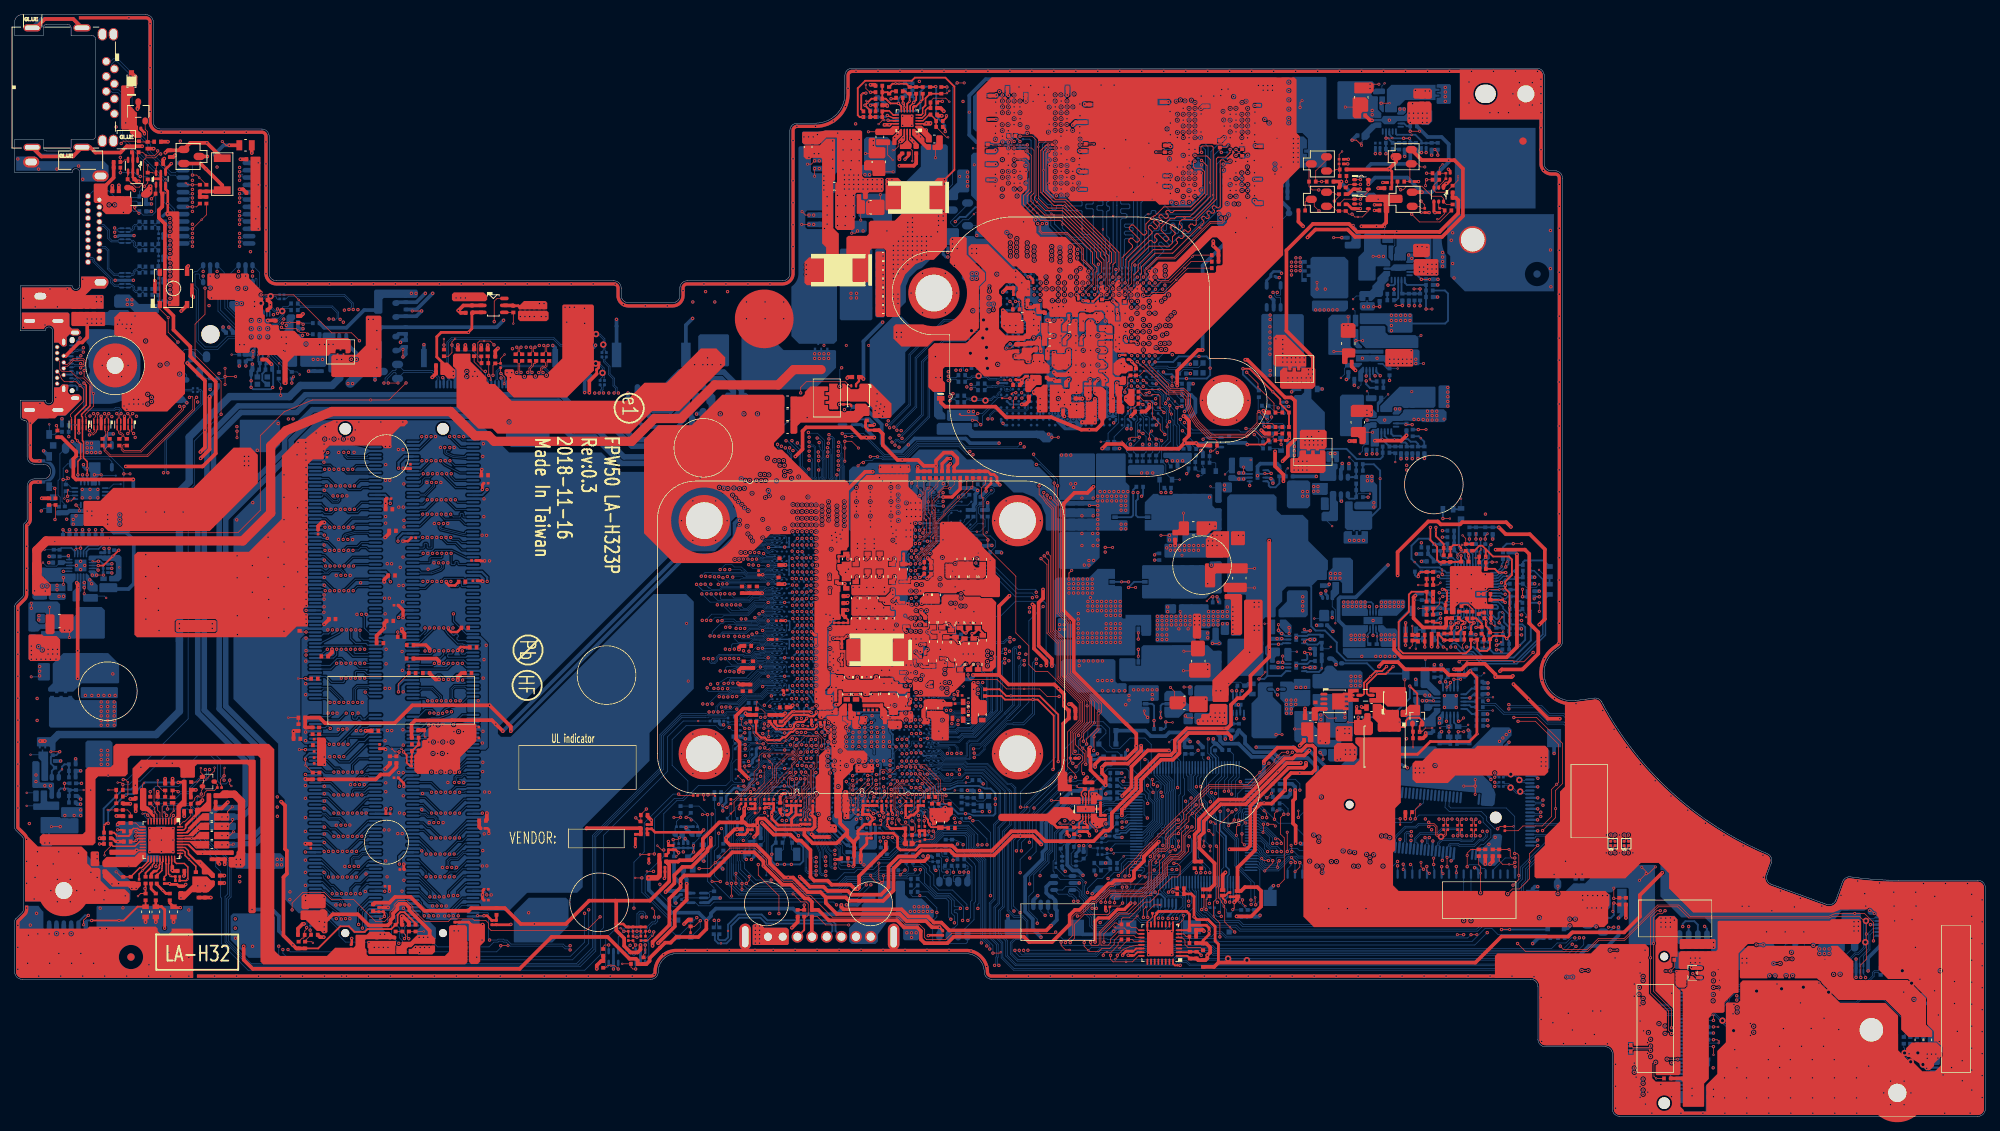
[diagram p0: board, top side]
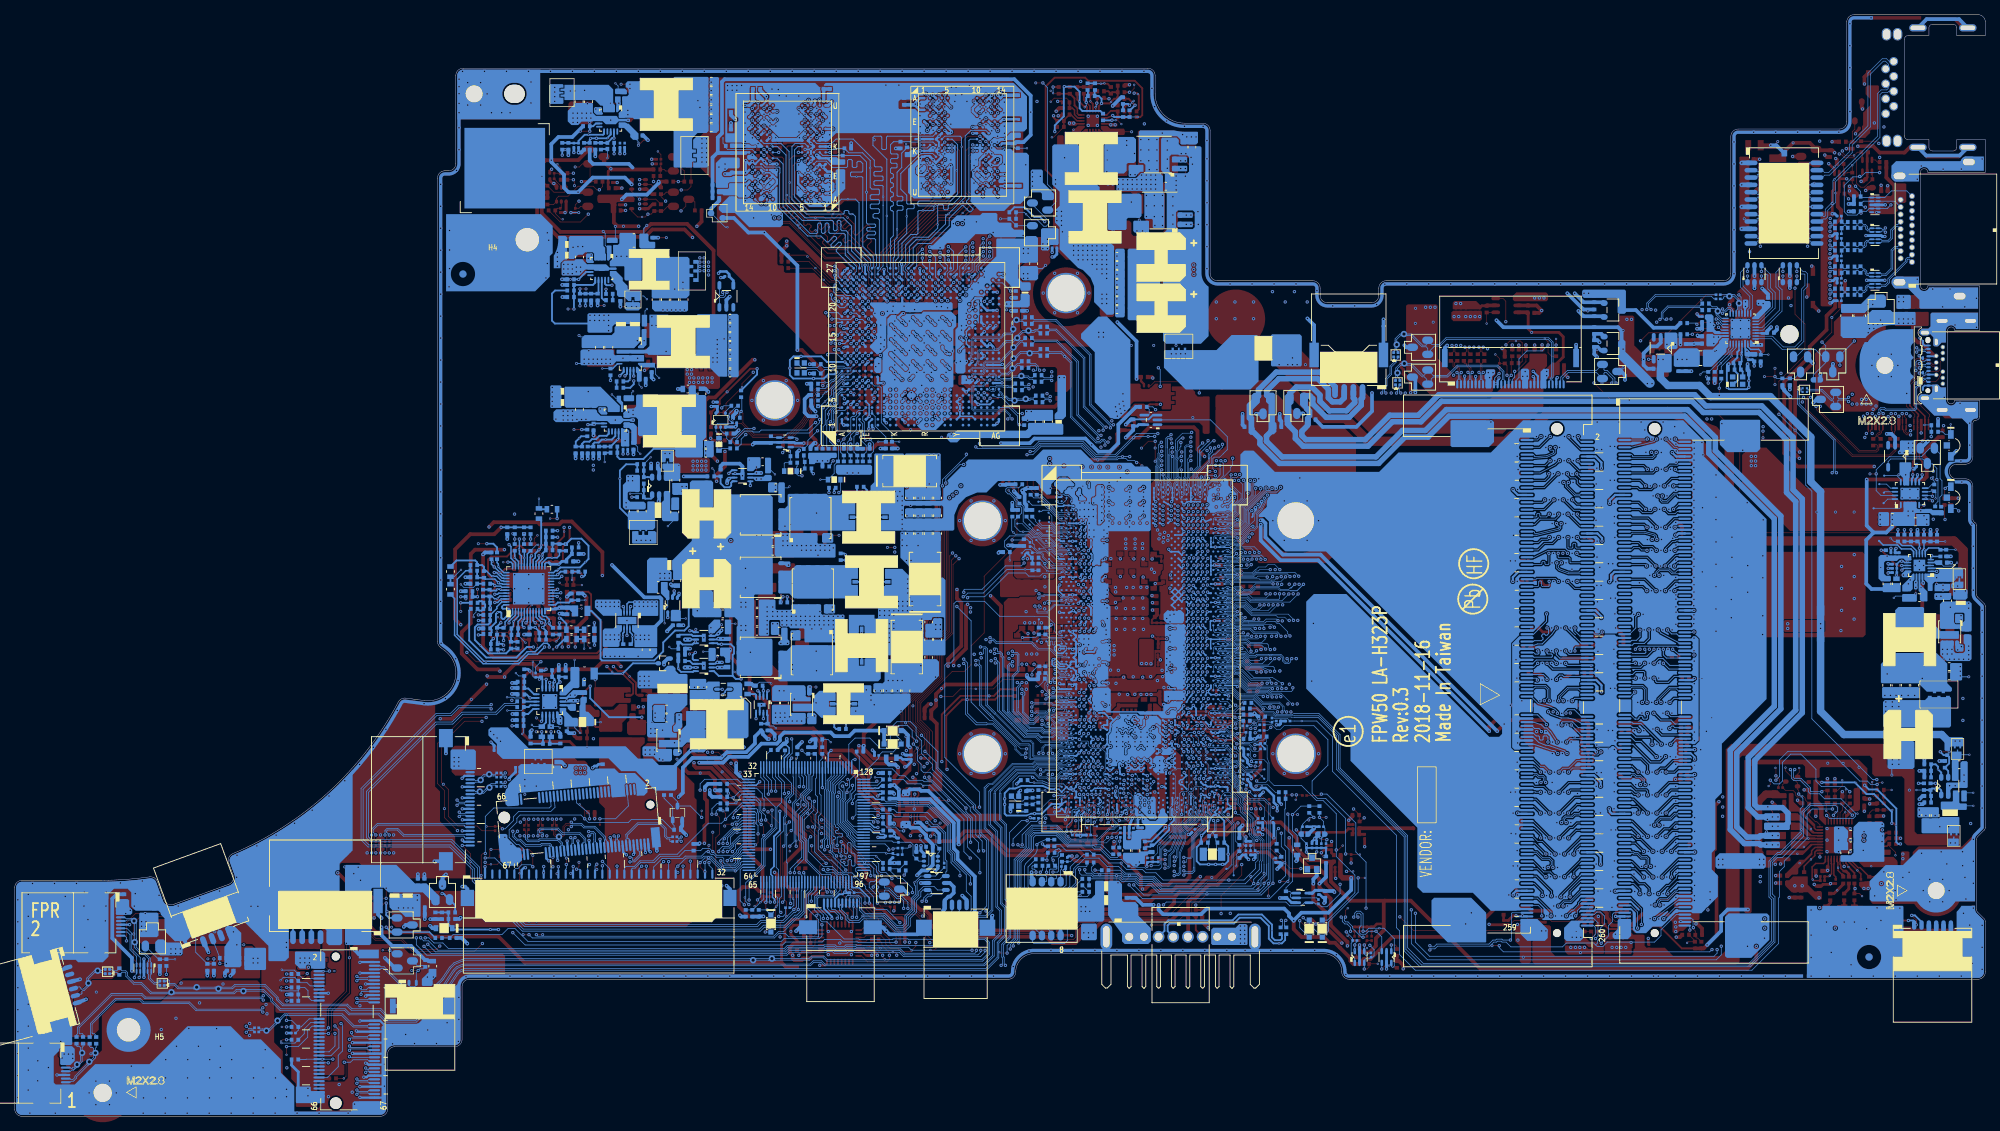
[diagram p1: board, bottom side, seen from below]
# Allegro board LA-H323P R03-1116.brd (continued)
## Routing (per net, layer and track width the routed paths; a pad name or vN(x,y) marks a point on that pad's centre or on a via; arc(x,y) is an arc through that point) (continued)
KBL_ON: length 76
  TOP w0.102: v3(217.55,22.66) v1(218.51,22.66)
  IN1 w0.127: v3(217.55,22.66) 214.93,22.66 213.79,23.81 212.67,23.81 209.18,27.3 209.18,28 206.68,30.5 206.68,31.5 205.57,32.6 205.57,39.52 202.63,42.47 198.9,42.47 198.49,42.06 183.14,42.06 182.39,41.31 179.74,41.31 179.04,42.01 167.5,42.01 166.61,42.9 163.06,42.9 v3(163.03,42.92)
  BOTTOM w0.102: v3(217.55,22.66) 217.06,22.17 Q9.2 ; v3(163.03,42.92) 163.03,43.43 162.5,43.95 162.5,46.26 162.57,46.32 UK1.21
KBL_ON_GND: length 7.8
  TOP w0.102: v3(213.69,19.9) v2(214.56,19.9)
  BOTTOM w0.102: JKBL.1 214.94,17.87 214.74,17.67 214.16,17.67 213.94,17.9 JKBL.2 213.94,19.64 v3(213.69,19.9) 213.47,20.11 212.99,20.11 R23.2 212.91,20.59 213.85,20.59 Q9.1
KSI0: length 21.6
  TOP w0.102: v3(173.52,36.13) v2(173.52,38.77)
  BOTTOM w0.102: UK1.55 169.37,37.17 170.3,36.24 170.3,36.07 170.76,35.62 172.97,35.62 173.48,36.13 v3(173.52,36.13) 173.92,36.53 174.89,36.53 175.17,36.25 C193.2 177.31,36.25 178.09,35.48 180.63,35.48 181.48,34.63 183.35,34.63 184.11,33.87 184.45,33.87 184.57,33.75 JKB.21
KSI1: length 10.4
  TOP w0.102: v2(170.45,33.48) 171.54,34.57 v3(171.54,34.88)
  IN1 w0.127: v3(171.54,34.88) 171.95,35.29 173.36,35.29 v3(174.02,34.62)
  BOTTOM w0.102: v3(174.02,34.62) 174.02,34.25 173.57,33.79 JKB.32 ; v3(171.54,34.88) 171.03,35.39 170.66,35.39 170,36.06 170,36.21 169.44,36.77 UK1.56
KSI2: length 16.5
  TOP w0.102: v3(170.96,34.89) 170.33,34.89 v2(170.04,35.19)
  IN1 w0.127: v3(180.23,34.75) 179.8,34.32 179.15,34.32 178.77,34.7 177.22,34.7 176.92,34.4 176.17,34.4 175.43,35.14 174,35.14 173.59,35.54 171.44,35.54 170.96,35.06 v3(170.96,34.89)
  BOTTOM w0.102: v3(180.23,34.75) 180.57,34.41 JKB.25 ; v3(170.96,34.89) 170.84,34.89 169.74,35.99 169.74,36.13 169.51,36.37 UK1.57
KSI3: length 17.6
  TOP w0.102: v3(174.14,36.13) 174.14,36.88 v2(174.04,36.98)
  BOTTOM w0.102: JKB.24 181.57,34.03 180.41,35.19 177.59,35.19 177.27,35.5 175.05,35.5 174.43,36.13 v3(174.14,36.13) 173.73,35.72 173.39,35.72 173.03,35.35 172.18,35.35 172.01,35.18 172.01,34.6 171.84,34.42 170.62,34.42 170.4,34.65 170.4,35.01 169.44,35.97 UK1.58
KSI4: length 12.6
  TOP w0.102: v2(172.2,33.98) 172.2,34.65 v3(172.42,34.87)
  IN1 w0.127: v3(177.57,34.14) 177.57,34.14 173.73,34.14 173.01,34.87 v3(172.42,34.87)
  BOTTOM w0.102: JKB.28 v3(177.57,34.14) ; UK1.59 169.51,35.57 170.17,34.91 170.17,34.55 170.55,34.17 172.03,34.17 172.42,34.57 v3(172.42,34.87)
KSI5: length 13.7
  TOP w0.102: v3(178.27,34.14) v2(178.27,33.28)
  BOTTOM w0.102: JKB.27 178.57,33.84 v3(178.27,34.14) 177.17,35.24 174.99,35.24 174.73,35.49 173.67,35.49 172.12,33.95 170.45,33.95 169.94,34.46 169.94,34.82 169.59,35.17 UK1.60
KSI6: length 11.4
  TOP w0.102: v2(174.58,33.37) 175.24,34.02 v3(175.24,34.62)
  BOTTOM w0.102: JKB.30 175.57,34.29 v3(175.24,34.62) 174.6,35.26 173.76,35.26 172.22,33.72 170.36,33.72 169.71,34.36 169.71,34.6 169.54,34.77 UK1.61
KSI7: length 9.7
  TOP w0.102: v2(174.1,35.3) 174.62,34.78 v3(174.62,34.63)
  BOTTOM w0.102: UK1.62 169.38,34.37 170.26,33.49 172.31,33.49 173.86,35.03 174.22,35.03 v3(174.62,34.63) 174.57,34.58 JKB.31
KSO0: length 24.3
  TOP w0.102: v3(166.3,40.43) 165.53,39.66 v2(165.53,39.66)
  IN1 w0.127: v3(166.3,40.43) 166.04,40.17 166.04,39.07 167.11,37.99 175.99,37.99 179.23,34.75 v3(179.53,34.75)
  BOTTOM w0.102: JKB.26 179.53,33.09 v3(179.53,34.75) ; UK1.39 167.57,43.57 166.97,42.96 166.97,41.7 166.31,41.05 166.31,40.45 v3(166.3,40.43)
KSO1: length 26.7
  TOP w0.102: v3(166.88,40.41) 167.47,40.41 v2(167.86,40.01)
  IN1 w0.127: v3(183.21,34.13) 181.77,35.57 179.14,35.57 176.2,38.5 168.51,38.5 168.05,38.96 166.61,38.96 166.42,39.15 166.42,39.94 v3(166.88,40.41)
  BOTTOM w0.102: JKB.22 183.57,33.77 v3(183.21,34.13) ; UK1.40 167.61,43.17 167.2,42.76 167.2,41.61 166.88,41.3 v3(166.88,40.41)
KSO2: length 22.8
  TOP w0.102: v3(171.78,40.53) 171.78,41.33 v2(172.12,41.68)
  BOTTOM w0.102: JKB.20 185.57,33.86 185.34,34.09 184.2,34.09 183.44,34.86 181.67,34.86 180.77,35.76 178.35,35.76 174.13,39.99 172.32,39.99 v3(171.78,40.53) 169.54,42.77 UK1.41
KSO3: length 27.8
  TOP w0.102: v3(170.71,40.75) 170.71,41.34 v2(170.35,41.7)
  IN1 w0.127: v3(190.33,34.36) 189.15,35.54 187.64,35.54 185.78,37.4 183.92,37.4 181.44,39.87 171.8,39.87 170.92,40.75 v3(170.71,40.75)
  BOTTOM w0.102: v3(190.33,34.36) 190.57,34.12 JKB.15 ; v3(170.71,40.75) 170.71,41.18 169.52,42.37 UK1.42
KSO4: length 28.7
  TOP w0.102: v2(166.58,38.34) 166.58,39.5 v3(166.91,39.82)
  IN1 w0.127: v3(166.91,39.82) 167.34,39.39 169.15,39.39 169.68,38.86 180.92,38.86 183.56,36.22 185.36,36.22 186.57,35.01 v3(186.57,34.13)
  BOTTOM w0.102: JKB.19 v3(186.57,34.13) ; v3(166.91,39.82) 167.29,40.21 167.29,41.38 167.42,41.51 167.42,41.84 167.55,41.97 UK1.43
KSO5: length 23.8
  TOP w0.102: v3(167.34,38.54) 167.34,37.36 v2(167.66,37.04)
  IN1 w0.127: v3(182.57,34.13) 181.39,35.31 179.03,35.31 176.1,38.25 167.88,38.25 167.58,38.54 v3(167.34,38.54)
  BOTTOM w0.102: UK1.44 167.81,41.57 167.52,41.29 167.52,39.85 167.34,39.67 v3(167.34,38.54) ; JKB.23 v3(182.57,34.13)
KSO6: length 26.2
  TOP w0.102: v3(189.33,34.4) v2(189.33,33.68)
  IN1 w0.127: v3(170.13,40.76) 170.13,40.42 170.26,40.28 171.03,40.28 171.69,39.62 181.24,39.62 183.78,37.08 185.63,37.08 187.46,35.25 188.92,35.25 189.33,34.84 v3(189.33,34.4)
  BOTTOM w0.102: v3(189.33,34.4) 189.57,34.16 JKB.16 ; v3(170.13,40.76) 169.72,41.17 UK1.45
KSO7: length 25.7
  TOP w0.102: v2(171.89,39.61) 171.65,39.85 v3(170.86,39.85)
  IN1 w0.127: v3(188.55,34.77) 187.55,34.77 185.57,36.75 183.75,36.75 181.13,39.36 171.34,39.36 v3(170.86,39.85)
  BOTTOM w0.102: JKB.18 187.57,33.79 v3(188.55,34.77) ; v3(170.86,39.85) 170.44,40.27 170.05,40.27 169.54,40.77 UK1.46
KSO8: length 24.9
  TOP w0.102: v3(170.27,39.86) 170.27,38.8 v2(170.21,38.74)
  IN1 w0.127: v3(188.56,34.18) 187.77,34.18 185.45,36.49 183.64,36.49 181.03,39.11 170.86,39.11 170.27,39.7 v3(170.27,39.86)
  BOTTOM w0.102: v3(188.56,34.18) 188.57,34.17 JKB.17 ; v3(170.27,39.86) 170.04,39.86 169.52,40.37 UK1.47
KSO9: length 13.2
  TOP w0.102: v2(171.92,37.87) 172.32,37.87 172.7,37.49 v3(172.7,37.23)
  IN1 w0.127: v3(172.7,37.23) 173.83,37.23 176.25,34.82 v3(176.57,34.82)
  BOTTOM w0.102: v3(172.7,37.23) 172.7,37.46 170.71,39.45 170.04,39.45 169.7,39.8 169.68,39.8 169.51,39.97 UK1.48 ; JKB.29 v3(176.57,34.82)
KSO10: length 41.9
  TOP w0.102: v3(195.31,34.06) v2(195.31,35.33)
  IN1 w0.127: v3(172.12,37.23) 172.12,37.24 171.62,37.74 169.64,37.74 168.5,36.61 168.5,34.74 170.16,33.09 172.63,33.09 173.1,32.62 175.99,32.62 176.16,32.44 193.96,32.44 195.31,33.79 v3(195.31,34.06)
  BOTTOM w0.102: JKB.10 195.57,33.8 v3(195.31,34.06) ; UK1.49 169.6,39.57 169.95,39.22 170.61,39.22 172.12,37.72 v3(172.12,37.23)
KSO11: length 38.4
  TOP w0.102: v2(194.75,33.1) 194.57,33.28 v3(194.57,34.05)
  IN1 w0.127: v3(194.57,34.05) 193.21,32.7 176.27,32.7 176.09,32.87 173.21,32.87 172.74,33.34 170.26,33.34 168.76,34.85 168.76,36.5 169.74,37.49 171.28,37.49 v3(171.53,37.23)
  BOTTOM w0.102: v3(171.53,37.23) 171.53,37.98 170.52,39 169.85,39 169.67,39.17 UK1.50 ; JKB.11 v3(194.57,34.05)
KSO12: length 38.2
  TOP w0.102: v2(191.75,34.65) 191.75,34.05 v3(192.09,33.72)
  IN1 w0.127: v3(172.7,36.13) 172.7,36.3 172.19,36.81 171.34,36.81 171.18,36.98 169.59,36.98 169.01,36.39 169.01,34.95 170.37,33.6 172.84,33.6 173.31,33.13 176.2,33.13 176.37,32.95 191.18,32.95 191.94,33.72 v3(192.09,33.72)
  BOTTOM w0.102: v3(192.09,33.72) 191.67,33.72 191.57,33.61 JKB.14 ; v3(172.7,36.13) 172.7,36.3 172.18,36.82 171.35,36.82 171.11,37.06 171.11,38.08 170.51,38.68 169.53,38.68 169.44,38.77 UK1.51
KSO13: length 36.1
  TOP w0.102: v2(192.88,33.15) 192.54,33.5 v3(192.54,34.09)
  IN1 w0.127: v3(192.54,34.09) 192.49,34.14 191.92,34.14 190.99,33.21 176.48,33.21 176.3,33.38 173.42,33.38 172.95,33.85 170.47,33.85 169.26,35.06 169.26,36.29 169.67,36.7 171.1,36.7 171.24,36.56 171.99,36.56 172.11,36.45 v3(172.11,36.11)
  BOTTOM w0.102: JKB.13 192.57,34.06 v3(192.54,34.09) ; UK1.52 169.77,38.37 170.88,37.26 170.88,36.97 171.25,36.6 171.96,36.6 172.11,36.45 v3(172.11,36.11)
KSO14: length 32.3
  TOP w0.102: v3(193.48,34.36) v2(193.48,35.22)
  IN1 w0.127: v3(171.52,36.13) 170.99,35.59 170.72,35.59 170.38,35.25 170.38,34.66 170.68,34.36 173.16,34.36 173.63,33.89 176.51,33.89 176.69,33.71 190.72,33.71 191.82,34.82 193.02,34.82 v3(193.48,34.36)
  BOTTOM w0.102: JKB.12 193.57,33.73 193.48,33.81 v3(193.48,34.36) ; v3(171.52,36.13) 171.4,36.13 170.65,36.87 170.65,37.16 169.84,37.97 UK1.53
KSO15: length 34.9
  TOP w0.102: v3(196.57,34.08) v2(196.57,33.23)
  IN1 w0.127: v3(196.57,34.08) 196.01,34.08 195.6,34.49 194.33,34.49 193.77,33.93 193.3,33.93 192.67,34.56 191.93,34.56 190.82,33.46 176.59,33.46 176.41,33.64 173.52,33.64 173.06,34.1 170.58,34.1 170.11,34.57 170.11,35.4 v3(170.83,36.12)
  BOTTOM w0.102: UK1.54 169.92,37.57 170.42,37.07 170.42,36.53 v3(170.83,36.12) ; JKB.9 v3(196.57,34.08)
KSO16: length 51.5
  TOP w0.102: v3(197.57,24.79) v2(196.71,24.79)
  IN1 w0.127: v3(197.57,24.79) v3(197.57,26.69)
  BOTTOM w0.102: v3(197.57,24.79) 197.35,24.57 165.2,24.57 164.58,25.19 163.86,25.19 162.11,26.94 161.81,26.94 160.94,27.82 160.94,30.57 160.57,30.95 UK1.81 ; v3(197.57,26.69) JKB.8
KSO17: length 57.5
  TOP w0.102: v3(198.57,24.79) v2(199.37,24.79)
  IN1 w0.127: v3(198.57,24.79) v3(198.57,26.69)
  BOTTOM w0.102: JKB.7 v3(198.57,26.69) ; v3(198.57,24.79) 198.13,24.34 165.11,24.34 164.49,24.96 163.64,24.96 163.16,24.49 159.1,24.49 159.08,24.52 159.08,26.83 160.71,28.46 160.71,30.31 160.17,30.86 UK1.82
LAN_ACT#: length 4.7
  BOTTOM w0.102: RL31.2 36.01,102.3 v1(34.6,103.7) 34.55,103.75 34.55,104.3 33.98,104.87 UL1.27
LAN_ACT#_R: length 63.6
  TOP w0.102: v3(36.27,99.33) v2(36.27,98.36)
  IN1 w0.127: JLAN.A2 11.97,131.7 13.48,130.18 13.48,128.62 13.76,128.34 13.76,126.09 14.12,125.74 14.12,116.76 16.62,114.26 16.62,100.86 25.18,92.3 30.93,92.3 36.27,97.65 v3(36.27,99.33)
  BOTTOM w0.102: RL31.1 36.01,100.23 36.27,99.97 v3(36.27,99.33)
LAN_LINK#: length 6.4
  BOTTOM w0.102: UL1.25 34.78,104.89 35.06,104.62 35.06,104.2 37.7,101.56 RL30.2 38.51,101.56 v1(38.87,101.2)
LAN_LINK#_R: length 80.5
  TOP w0.102: v3(37.79,100.04) 37.79,100.66 v2(38.02,100.9)
  IN1 w0.127: JLAN.B2 11.97,148.47 12.23,148.72 14.32,148.72 15.58,147.47 15.58,125.36 15.26,125.04 15.26,117.23 17.76,114.73 17.76,107.49 25.21,100.05 25.21,100.01 26.59,98.63 26.98,98.63 27.48,98.13 27.48,94.57 29.24,92.81 30.72,92.81 35.6,97.69 35.6,99.61 36.44,100.45 37.37,100.45 v3(37.79,100.04)
  BOTTOM w0.102: RL30.1 v3(37.79,100.04)
LAN_MDIN0: length 37.3
  IN2 w0.102: v3(25.7,114.64) 26.03,114.97 26.11,114.97 26.39,115.25 26.39,124.71 30.25,128.57 30.39,128.57 v3(30.67,128.29)
  BOTTOM w0.089: v3(25.7,114.64) DM12.3 25.22,114.29 25.22,114.82 25.12,114.92 24.68,114.92 24.6,114.83 24.6,113.34 25.09,112.85 25.09,105.86 25.98,104.97 27.55,104.97 29.02,106.43 30.88,106.43 30.91,106.46 UL1.2 ; TSL1.3 31.2,128.08 31.11,128.17 31.11,128.44 31.02,128.53 30.87,128.53 30.67,128.33 v3(30.67,128.29)
LAN_MDIN1: length 25.6
  IN2 w0.102: v3(30.67,125.29) 30.39,125.57 30.25,125.57 27.3,122.63 27.3,115.36 27.4,115.26 27.59,115.26 v3(27.6,115.27)
  BOTTOM w0.089: v3(27.6,115.27) DM12.6 28.56,115.15 28.56,113.13 28.06,112.64 28.06,109.99 30.45,107.6 30.82,107.6 30.88,107.66 UL1.5 ; v3(30.67,125.29) 30.78,125.41 31.06,125.41 31.38,125.08 TSL1.6
LAN_MDIN2: length 22.2
  IN2 w0.102: v3(30.53,114.64) 30.94,115.04 30.94,116.02 28.99,117.97 28.99,121.81 29.75,122.57 30.39,122.57 v3(30.67,122.29)
  BOTTOM w0.089: v3(30.53,114.64) DM13.3 30.11,114.23 30.11,114.77 30.02,114.85 29.76,114.85 29.65,114.74 29.65,112.9 29,112.25 29,110.41 30.95,108.46 UL1.7 ; TSL1.9 31.22,122.08 31.14,122.17 31.14,122.44 31.05,122.53 30.91,122.53 v3(30.67,122.29)
LAN_MDIN3: length 15.5
  IN2 w0.102: v3(30.67,119.29) 30.53,119.43 30.27,119.43 30.17,119.33 30.17,118.08 32.11,116.14 32.11,115.59 v3(32.43,115.27)
  BOTTOM w0.089: v3(32.43,115.27) DM13.6 33.38,115.15 33.38,113.13 32.11,111.86 32.11,110.32 32.38,110.05 UL1.10 ; TSL1.12 31.38,119.08 31.06,119.41 30.79,119.41 v3(30.67,119.29)
LAN_MDIP0: length 37.4
  IN2 w0.102: v3(30.67,128.87) 30.12,128.87 26.08,124.84 26.08,115.37 25.98,115.27 v3(25.7,115.27)
  BOTTOM w0.089: v3(25.7,115.27) DM12.4 24.86,115.26 24.54,115.26 24.25,114.97 24.25,113.2 24.75,112.71 24.75,105.72 25.84,104.63 27.7,104.63 29.16,106.09 30.88,106.09 30.91,106.06 UL1.1 ; v3(30.67,128.87) 31.19,128.87 31.4,129.08 TSL1.2
LAN_MDIP1: length 25.6
  IN2 w0.102: v3(30.67,125.87) 30.12,125.87 27,122.75 27,115.23 27.28,114.96 27.35,114.96 27.6,114.7 v3(27.6,114.64)
  BOTTOM w0.089: TSL1.5 31.4,126.08 31.06,125.75 30.79,125.75 v3(30.67,125.87) ; v3(27.6,114.64) DM12.1 27.95,114.15 28.13,114.15 28.22,114.06 28.22,113.27 27.72,112.78 27.72,109.85 30.31,107.26 UL1.4
LAN_MDIP2: length 22.3
  IN2 w0.102: v3(30.53,115.27) 30.63,115.37 30.63,115.9 28.68,117.84 28.68,121.94 29.62,122.87 v3(30.67,122.87)
  BOTTOM w0.089: TSL1.8 31.4,123.08 31.19,122.87 v3(30.67,122.87) ; UL1.6 30.89,108.06 30.83,108.12 30.81,108.12 28.66,110.27 28.66,112.39 29.31,113.04 29.31,114.88 DM13.4 v3(30.53,115.27)
LAN_MDIP3: length 15.5
  IN2 w0.102: v3(30.67,119.87) 30.53,119.73 30.15,119.73 29.87,119.45 29.87,117.96 31.81,116.01 31.81,115.26 v3(32.43,114.64)
  BOTTOM w0.089: UL1.9 31.98,109.96 31.98,109.97 31.77,110.18 31.77,112 33.04,113.27 33.04,114.23 32.95,114.32 32.86,114.32 32.77,114.23 32.77,113.96 32.61,113.8 DM13.1 v3(32.43,114.64) ; v3(30.67,119.87) 30.79,119.75 31.07,119.75 31.4,120.08 TSL1.11
LAN_PWR_EN: length 225.4
  TOP w0.102: v3(141.94,25.14) 141.74,24.94 127.74,24.94 126.92,24.11 124.35,24.11 124.04,24.43 124.04,25.52 123.35,26.21 121.45,26.21 120.48,27.17 111.49,27.17 108.51,30.16 107.94,30.16 106.03,32.07 104.82,32.07 102.53,34.37 102.53,35 100.93,36.6 97.52,36.6 v2(95.52,34.6) 94.72,33.8 v3(93.33,33.8)
  IN1 w0.127: v3(45.91,103.29) 46.76,102.44 46.76,99.95 40.9,94.09 36.51,94.09 35.14,92.72 35.14,86.91 35.57,86.48 35.57,66.72 34.87,66.03 34.87,40.63 38.54,36.96 38.54,29.08 39.19,28.43 43.2,28.43 43.49,28.14 50.23,28.14 50.8,27.57 52.31,27.57 52.45,27.71 53.03,27.71 53.2,27.53 54.67,27.53 55.57,26.62 58.07,26.62 59.47,26.04 61.61,26.04 62.15,25.51 73.35,25.51 74.34,26.5 77.77,26.5 85.42,34.14 92.99,34.14 v3(93.33,33.8)
  BOTTOM w0.102: UL2.4 v3(45.91,103.29) ; UK1.86 158.57,31.05 159.66,29.95 159.66,28.17 158.85,27.35 158.85,26.77 158.62,26.54 157.94,26.54 155.6,24.2 153.61,24.2 153.52,24.11 149.03,24.11 148.93,24.21 146.92,24.21 146.86,24.15 142.93,24.15 v3(141.94,25.14)
LAN_WAKE#: length 12.2
  TOP w0.076: v3(106.64,51.46) 106.15,50.97 106.15,50.31 106.54,49.93 106.54,49.55 106.32,49.33 105.26,49.33 103.61,47.68 103.61,45.91 v1(103.13,45.42) RC926.2
  BOTTOM w0.076: UC1.BU32 106.64,51.64 v3(106.64,51.46)
LANGND: length 101.3
  TOP w0.508: v3(17.38,132.35) 15.29,132.35 14.42,131.49 11.01,131.49 10.3,132.2 JLAN.12 7.95,130.96 3.63,130.96 JLAN.11 ; CL2.1 v2(26.21,132.81) 23.94,132.81 23.07,131.95 DL1.2 22.94,131.8 CL3.1 20.87,131.8 v3(20.54,131.47) ; JLAN.10 2.92,148.5 4.14,149.71 7.98,149.71 JLAN.9
  IN1 w0.508: JLAN.12 8.07,131.08 3.54,131.08 2.42,132.2 JLAN.11 ; JLAN.10 3.6,149.71 7.98,149.71 JLAN.9 10.31,149.63 14.64,149.63 17.38,146.88 17.38,135.39 16.86,134.87 16.86,132.87 v3(17.38,132.35) 17.72,132.7 19.64,132.7 20.54,131.8 v3(20.54,131.47)
  IN2 w0.508: JLAN.10 3.58,149.69 8,149.69 JLAN.9
  BOTTOM w0.508: JLAN.10 3.58,149.69 8,149.69 JLAN.9 ; JLAN.11 3.51,131.08 8.07,131.08 JLAN.12
LDO1_CAP: length 5.9
  TOP w0.102: v2(13.83,33.35) 14.51,32.67 RA24.2
  TOP w0.203: RA24.2 15.81,32.67 CA30.2 17.07,33.93 17.34,33.93 18.21,34.8 UA1.21
LED1/GPO: length 4.9
  BOTTOM w0.102: RL56.1 36.49,101.97 36.49,102.3 v1(36.06,102.73) 34.82,103.97 34.82,104.41 34.38,104.85 UL1.26
LG_CHG: length 16.7
  TOP w0.102: v2(178.39,48.72) 178.39,49.23 v3(178,49.62)
  IN2 w0.762: 193.15,53.87 186.36,53.87 183.66,51.17 180.48,51.17 179.18,49.87
  vias: v3(194.28,54.29) v3(194.28,53.65)
LG_DDR: length 13.1
  TOP w0.102: v3(11.17,73.84) v2(12.14,73.84)
  IN2 w0.762: 3.77,65.31 8.72,65.31 11.77,68.36 11.77,71.03 11.9,71.15
  vias: v3(3.26,64.08) v3(3.77,63.63) v3(10.59,73.84)
LID_SW#: length 403.1
  TOP w0.102: C5228.1 18.13,134.34 17.8,134.67 U4018.3 ; C5228.1 18.99,132.94 C19.1 ; C5228.1 17.04,132.94 R126.2 14.83,133.04 v3(14.52,132.74) ; v3(253.45,23.93) 253.45,26.45 252.22,27.68 v2(250.9,27.68) 248.26,27.68 247.31,27.29 228.46,27.29 226.92,28.82 224.01,28.82 219.43,24.25 215.92,24.25 214.42,22.75 211.2,22.75 210.74,23.21 v3(210.74,23.23) ; v3(160.52,39.49) 159.33,38.3 159.33,36.12 158.68,35.47 157.65,35.47 156.73,34.54 156.73,33.07 153.84,30.18 149.72,30.18 149.34,29.8 149.34,29.2 v3(149.33,29.2)
  IN1 w0.127: v3(17.86,105.78) 16.87,106.76 16.87,114.36 14.37,116.86 14.37,125.45 14.69,125.77 14.69,127.77 13.74,128.72 13.74,131.25 14.43,131.95 14.43,132.64 v3(14.52,132.74) ; v3(150.98,40.15) 150.98,40.04 151.48,39.54 152.21,39.54 152.88,38.87 155.64,38.87 155.78,39.01 160.01,39.01 160.49,39.49 v3(160.52,39.49) 161.64,38.37 165.51,38.37 167.47,36.41 167.47,34.69 169.99,32.18 172.47,32.18 172.91,31.73 175.8,31.73 175.85,31.68 203.3,31.68 203.58,31.96 204.78,31.96 205.66,31.08 205.66,27.69 207.41,25.94 208.03,25.94 v3(210.74,23.23) ; v3(19.83,102.48) 19.83,98.28 25.56,92.55 30.82,92.55 35.85,97.59 35.85,99.51 36.1,99.75 36.45,99.75 36.8,99.4 36.8,99.07 36.6,98.86 36.6,97.61 34.63,95.64 34.63,86.7 35.06,86.27 35.06,66.93 34.36,66.24 34.36,44.47 33.99,44.1 33.99,40.79 38.03,36.75 38.03,28.87 38.98,27.93 42.99,27.93 43.28,27.64 47.07,27.64 47.85,26.86 49.34,26.86 49.59,26.6 54.87,26.6 55.36,26.11 57.97,26.11 58.81,25.77 58.95,25.67 59.07,25.55 59.17,25.41 59.18,25.38 59.67,24.88 60.78,24.88 60.9,25 73.56,25 74.55,25.99 77.98,25.99 82.41,30.42 87.71,30.42 88.02,30.12 89.01,30.12 89.86,30.97 104.82,30.97 105.45,30.33 108.24,30.33 108.44,30.53 111.4,30.53 111.53,30.67 114.04,30.67 114.31,30.4 114.63,30.07 117.12,30.07 117.84,30.8 125.47,30.8 125.92,30.34 131.62,30.34 131.81,30.54 137.53,30.54 137.86,30.21 138.43,30.21 139.25,29.38 139.97,29.38 140.47,29.89 145.16,29.89 145.93,29.12 146.06,29.12 146.45,28.72 146.45,28.11 146.67,27.9 147.61,27.9 148.14,28.42 148.39,28.42 148.65,28.68 148.82,28.68 149.33,29.19 v3(149.33,29.2)
  BOTTOM w0.102: JFPR.8 253.71,24.65 253.45,24.39 v3(253.45,23.93) ; v3(150.98,40.15) 150.98,40.15 151.61,40.77 UK1.115 ; v3(17.86,105.78) 19.83,103.81 D1.2 v3(19.83,102.48)
LPC_AD0: length 102.4
  TOP w0.102: v3(158.7,36.77) v2(158.7,37.56)
  IN1 w0.076: v3(107.98,48.84) 107.98,49.14 108.06,49.21 109.22,49.21 109.29,49.14 109.29,48.48 109.76,48.01 109.76,46.32 109.84,46.25 109.96,46.25 110.17,46.03 110.17,45.82 110.1,45.74 109.28,45.74 109.2,45.66 109.2,45.46 108.82,45.08 108.82,44.73 108.9,44.65 109.38,44.65 109.46,44.58 109.46,44.43 109.38,44.35 109.05,44.35 108.97,44.27 108.97,43.62 108.79,43.43 107.84,43.43 107.77,43.36 107.77,43.25 107.84,43.17 108.76,43.17 108.84,43.1 108.84,42.9 108.76,42.82 107.84,42.82 107.77,42.74 107.77,42.63 107.84,42.56 108.46,42.56 108.54,42.48 108.54,42.3 108.46,42.23 107.84,42.23 107.77,42.15 107.77,42 107.84,41.92 108.34,41.92 108.48,41.78 108.82,41.78 108.9,41.7 108.9,40.83 108.97,40.75 109.15,40.75 109.23,40.83 109.23,41.66 109.34,41.78 109.85,41.78 109.95,41.68 109.95,40.81 110.04,40.72 110.23,40.72 110.32,40.81 110.32,41.71 110.4,41.79 110.57,41.79 110.65,41.71 110.65,40.94 110.73,40.86 110.86,40.86 110.95,40.95 110.95,41.71 111.03,41.79 111.22,41.79 111.3,41.71 111.3,41.13
  IN1 w0.127: v3(158.7,36.77) 159.22,36.77 159.36,36.63 159.36,36.28 159.03,35.95 158.61,35.95 158.4,35.95 157.92,35.95 157.82,36.05 156.17,36.05 155.98,36.25 155.59,36.25 155.47,36.13 154.78,36.13 154.65,36.25 154.65,36.41 154.53,36.53 154.27,36.53 154.14,36.41 154.14,36.25 154.02,36.13 153.76,36.13 153.64,36.25 153.64,36.41 153.51,36.53 153.26,36.53 153.13,36.41 153.13,36.25 153,36.13 152.75,36.13 152.62,36.25 152.62,36.41 152.49,36.53 152.24,36.53 152.11,36.41 152.11,36.25 151.99,36.13 151.73,36.13 151.6,36.25 151.6,36.41 151.48,36.53 151.22,36.53 151.1,36.41 151.1,36.25 150.97,36.13 150.59,36.13 150.48,36.24 150.48,36.79 149.98,37.29 148.8,37.29 148.6,37.1 148.42,37.1 147.45,36.13 139.55,36.13 138.95,36.72 138.02,36.72 137.81,36.94 136.04,36.94 135.91,36.81 135.91,35.89 135.48,35.45 131.57,35.45 131.26,35.77 129.16,35.77 128.55,36.38 125.7,36.38 125.13,36.95 122.21,36.95 121.69,36.43 117.42,36.43 117.06,36.79 116.78,36.79 116.63,36.94 116.63,37.26 116.5,37.38 116.23,37.38 116.1,37.26 116.1,36.9 116,36.8 115.69,36.8 115.62,36.88 115.62,37.13 115.46,37.28 115.26,37.28 114.88,36.9 114.65,36.9 114.48,37.07 114.48,37.23 114.72,37.48 114.72,37.66 114.54,37.84 114.38,37.84 114.16,37.61 113.94,37.61 113.71,37.84 113.71,38.02 113.98,38.29 113.98,38.46 113.8,38.64 113.61,38.64 113.35,38.38 113.17,38.38 113.03,38.52 113.03,38.67 113.33,38.97 113.33,39.12 113.09,39.36 112.9,39.36 112.61,39.08 112.4,39.08 112.23,39.25 112.23,39.45 112.53,39.76 112.53,40.8 112.39,40.94 112.15,40.94 112.01,40.8 112.01,39.97 111.86,39.83 111.56,39.83 111.41,39.98 111.41,40.21 111.55,40.35 111.55,40.88 111.3,41.13
  BOTTOM w0.076: v3(107.98,48.84) 107.98,49.07 108.15,49.24 UC1.CA29
  BOTTOM w0.102: v3(158.7,36.77) 158.53,36.93 158.53,37.72 158.26,37.99 158.26,44.57 158.15,44.68 158.15,45.41 158.17,45.43 UK1.10
LPC_AD1: length 103.2
  TOP w0.102: v3(158.25,36.37) 157.79,36.37 v2(157.53,36.1)
  IN1 w0.076: v3(108.08,49.7) 108.08,49.7 108.08,49.45 108.16,49.38 109.42,49.38 109.77,49.72 110.13,49.72 110.28,49.57 110.28,49.46 110.13,49.3 109.6,49.3 109.52,49.23 109.52,49.12 109.6,49.04 110.21,49.04 110.28,48.97 110.28,48.86 110.21,48.78 109.53,48.78 109.46,48.71 109.46,48.55 109.53,48.48 110.14,48.48 110.28,48.33 110.28,48.1 110.21,48.02 110,48.02 109.93,47.94 109.93,47.79 110,47.72 110.21,47.72 110.28,47.64 110.28,47.49 110.21,47.41 110,47.41 109.93,47.33 109.93,47.18 110,47.11 110.21,47.11 110.28,47.03 110.28,46.82 110.21,46.75 110.03,46.75 109.95,46.67 109.95,46.52 110.03,46.44 110.21,46.44 110.28,46.37 110.28,46.16 110.41,46.03
  IN1 w0.127: v3(158.25,36.37) 158.19,36.3 156.28,36.3 156.08,36.5 155.59,36.5 155.3,36.79 150.85,36.79 150.08,37.55 148.7,37.55 148.5,37.35 148.31,37.35 147.34,36.38 139.66,36.38 139.06,36.98 138.19,36.98 137.94,37.22 137.94,37.49 137.82,37.61 137.27,37.61 137.14,37.49 137.14,37.32 137.01,37.19 136.76,37.19 136.63,37.32 136.63,37.49 136.51,37.61 136.25,37.61 135.83,37.19 135.79,37.19 135.66,37.07 135.66,35.99 135.37,35.71 132.1,35.71 131.78,36.02 131.49,36.02 131.17,36.35 130.99,36.35 130.79,36.16 130.79,36.15 130.67,36.02 129.78,36.02 129.6,36.2 129.6,36.43 129.4,36.63 125.8,36.63 125.27,37.17 121.74,37.17 121.22,36.65 117.6,36.65 117.06,37.18 117.06,37.49 116.92,37.62 115.31,37.62 114.56,38.37 114.56,38.55 114.92,38.9 114.92,39.08 114.74,39.26 114.56,39.26 114.21,38.9 114.03,38.9 113.85,39.08 113.85,39.26 114.2,39.62 114.2,39.8 114.02,39.98 113.84,39.98 113.49,39.62 113.31,39.62 113.13,39.8 113.13,40.29 112.86,40.56 112.86,40.95 112.53,41.28 111.65,41.28 111.49,41.44 111.49,41.88 111.36,42 108.93,42 108.73,42.21 108.73,42.39 108.85,42.51 111.53,42.51 111.65,42.64 111.65,42.82 111.53,42.95 109.15,42.95 109.03,43.07 109.03,43.41 109.16,43.54 111.36,43.54 111.49,43.67 111.49,43.85 111.36,43.98 109.81,43.98 109.68,44.1 109.68,44.36 109.81,44.48 111.36,44.48 111.49,44.61 111.49,44.84 111.36,44.97 109.49,44.97 109.36,45.09 109.36,45.35 109.49,45.47 111.36,45.47 111.49,45.6 111.49,45.83 111.29,46.03 110.41,46.03
  BOTTOM w0.076: v3(108.08,49.7) 108.26,49.88 UC1.BY29
  BOTTOM w0.102: UK1.8 157.37,46.41 157.92,45.85 157.92,44.59 158.04,44.48 158.04,37.89 158.29,37.64 158.29,36.41 v3(158.25,36.37)
LPC_AD2: length 104.6
  IN1 w0.127: v3(157.86,36.81) 157.6,36.56 156.38,36.56 156.19,36.75 155.69,36.75 155.41,37.04 150.95,37.04 150.19,37.8 148.59,37.8 148.39,37.6 147.68,37.6 147.55,37.48 147.55,36.95 147.43,36.83 147.17,36.83 147.05,36.95 147.05,37.48 146.92,37.6 144.24,37.6 144.11,37.48 144.11,37.11 143.98,36.99 143.73,36.99 143.6,37.11 143.6,37.48 143.48,37.6 143.22,37.6 143.09,37.48 143.09,37.11 142.97,36.99 142.71,36.99 142.59,37.11 142.59,37.48 142.46,37.6 142.21,37.6 142.08,37.48 142.08,37.11 141.95,36.99 141.7,36.99 141.57,37.11 141.57,37.48 141.44,37.6 141.19,37.6 141.06,37.48 141.06,37.11 140.94,36.99 140.68,36.99 140.55,37.11 140.55,37.48 140.43,37.6 140.07,37.6 139.81,37.87 136.48,37.87 136.36,37.99 136.36,39.01 136.23,39.14 135.98,39.14 135.85,39.01 135.85,37.57 135.72,37.44 135.31,37.44 135.19,37.57 135.19,38.25 135.06,38.37 134.81,38.37 134.68,38.25 134.68,37.03 134.81,36.9 135.28,36.9 135.41,36.77 135.41,36.52 135.28,36.39 134.81,36.39 134.68,36.27 134.68,36.09 134.55,35.96 134.22,35.96 134.1,36.09 134.1,37.28 133.97,37.41 133.71,37.41 133.59,37.28 133.59,36.09 133.46,35.96 133.21,35.96 133.08,36.09 133.08,36.52 132.95,36.65 132.7,36.65 132.57,36.52 132.57,36.09 132.44,35.96 132.2,35.96 132.08,36.09 132.08,36.49 131.95,36.62 131.03,36.62 130.91,36.75 130.91,37.31 130.78,37.44 130.49,37.44 130.36,37.31 130.36,36.41 130.23,36.28 129.98,36.28 129.85,36.41 129.85,37.31 129.72,37.44 128.93,37.44 128.84,37.54 128.03,37.54 127.9,37.41 127.9,37.02 127.78,36.89 127.52,36.89 127.4,37.02 127.4,37.41 127.27,37.54 127.02,37.54 126.89,37.41 126.89,37.02 126.76,36.89 126.51,36.89 126.38,37.02 126.38,37.41 126.25,37.54 124.91,37.54 124.76,37.38 121.41,37.38 120.89,36.86 117.69,36.86 117.32,37.23 117.32,37.79 117.18,37.93 116.38,37.93 116.05,38.25 115.87,38.25 115.52,37.9 115.34,37.9 115.16,38.08 115.16,38.26 115.51,38.61 115.51,38.79 113.84,40.47 113.84,41.5 113.64,41.7 111.92,41.7 111.79,41.83 111.79,42.01 111.92,42.13 113.8,42.13 113.99,42.32 113.99,42.5 113.86,42.63 112,42.63 111.87,42.76 111.87,43.06 112,43.18 112.54,43.18 112.66,43.31 112.66,43.56 112.54,43.69 112,43.69 111.87,43.82 111.87,44.34 112.12,44.6 112.44,44.6 113.01,45.17 113.01,45.83 113.59,46.41 113.59,46.81 113.46,46.94 113.15,46.94 112.47,46.25 112.27,46.25 112.14,46.12 112.14,45.42 112.01,45.3 111.83,45.3 111.71,45.42 111.71,46.12 111.58,46.25 110.84,46.25 110.47,46.62 110.47,49.65 110.21,49.92 109.45,49.92 v3(109.29,49.75)
  BOTTOM w0.076: v3(109.29,49.75) 109.56,50.02 UC1.BY27
  BOTTOM w0.102: UK1.7 156.97,46.48 157.7,45.75 157.7,44.49 157.81,44.38 157.81,37.8 157.86,37.75 v3(157.86,36.81)
LPC_AD3: length 125
  TOP w0.102: v3(156.64,35.53) 156.64,35.37 156.09,34.81 156.09,33.07 153.65,30.64 149.31,30.64 148.11,29.44 148.11,29.22 v3(148.12,29.2) ; v3(87.1,33.42) v1(86.2,33.42)
  IN1 w0.127: v3(148.12,29.2) 148.05,29.2 147.63,29.62 146.14,29.62 145.37,30.4 142.83,30.4 142.51,30.72 138.07,30.72 137.74,31.05 131.6,31.05 131.41,30.85 126.13,30.85 125.68,31.3 117.63,31.3 117.02,30.69 115.83,30.69 115.09,31.43 114.6,31.43 114.35,31.17 111.32,31.17 111.19,31.04 108.23,31.04 108.03,30.84 105.66,30.84 104.69,31.82 100.35,31.82 99.7,32.47 98.76,32.47 98.14,33.1 93.14,33.1 92.82,33.42 v3(87.1,33.42)
  IN2 w0.076: v3(109.27,50.6) 109.27,50.52 109.65,50.15 109.65,49.47 109.1,48.92 109.1,47.61 108.88,47.39 105.66,47.39 105.15,46.88 104,46.88 103.15,46.04 101.32,46.04 100.96,45.68 100.96,45.03 101.24,44.75 101.24,44.34 100.47,43.57 100.47,41.83 100.19,41.55 97.84,41.55
  IN2 w0.127: 97.84,41.55 96.92,40.63 96.09,40.63 95.9,40.44 93.19,40.44 91.72,38.97 91.06,38.97 90.6,38.5 90.6,37.29 87.1,33.8 v3(87.1,33.42)
  BOTTOM w0.076: UC1.BV27 109.56,50.9 v3(109.27,50.6)
  BOTTOM w0.102: v3(156.64,35.53) 157.22,36.11 157.22,37.12 157.35,37.25 157.35,44.19 157.24,44.3 157.24,45.46 156.17,46.53 UK1.5
LPC_FRAME#: length 102.6
  TOP w0.102: v3(156.01,35.53) 156.01,35.28 155.61,34.87 v2(155.61,34.63)
  IN1 w0.076: 107.55,41.04 107.55,41.17 107.63,41.24 108.1,41.24 108.17,41.32 108.17,41.51 108.09,41.6 107.68,41.6 107.6,41.67 107.6,43.59 107.68,43.67 107.9,43.67 107.98,43.74 107.98,43.9 107.9,43.97 107.68,43.97 107.6,44.05 107.6,44.24 107.68,44.32 107.95,44.32 108.02,44.39 108.02,44.83 108.1,44.91 108.25,44.91 108.33,44.83 108.33,44.39 108.41,44.31 108.57,44.31 108.66,44.39 108.66,45.32 109,45.66 109,45.88 109.11,45.99 109.6,45.99 109.68,46.07 109.68,46.17 109.6,46.25 109.05,46.25 108.97,46.32 108.97,46.48 109.05,46.55 109.52,46.55 109.6,46.63 109.6,47.19 109.52,47.26 109.36,47.26 109.28,47.34 109.28,47.57 109.36,47.65 109.52,47.65 109.6,47.72 109.6,47.93 109.53,48 109.37,48 109.29,48.08 109.29,48.25 109.13,48.42 109.13,48.93 109.02,49.04 108.78,49.04 v3(108.59,48.86)
  IN1 w0.127: v3(156.01,35.53) 156.01,35.75 155.89,35.87 154.45,35.87 154.39,35.81 150.38,35.81 150.2,35.99 150.2,36.71 149.87,37.04 148.91,37.04 148.71,36.84 148.52,36.84 147.55,35.87 139.45,35.87 138.85,36.47 137.92,36.47 137.7,36.68 136.29,36.68 136.17,36.56 136.17,35.78 135.58,35.2 131.47,35.2 131.15,35.52 129.05,35.52 128.44,36.13 125.59,36.13 125.02,36.7 122.66,36.7 122.18,36.22 117.08,36.22 116.71,36.58 114.66,36.58 112.72,38.53 112.47,38.53 112.17,38.82 111.88,38.82 111.58,38.51 111.32,38.51 111.11,38.73 111.11,38.88 111.34,39.11 111.34,39.43 111.23,39.53 111.04,39.53 110.94,39.63 110.94,40.18 110.82,40.3 110.56,40.3 110.43,40.18 110.43,39.6 110.31,39.48 110.08,39.48 109.95,39.61 109.95,40.36 109.81,40.49 109.38,40.49 109.08,40.19 108.69,40.19 108.57,40.32 108.57,40.7 108.45,40.81 108.21,40.81 108.12,40.72 108.12,40.34 108,40.23 107.88,40.23 107.55,40.55 107.55,41.04
  BOTTOM w0.076: v3(108.59,48.86) 108.59,49.09 108.74,49.24 UC1.CA28
  BOTTOM w0.102: v3(156.01,35.53) 155.47,35.53 155.33,35.39 155.33,35.22 155.47,35.08 155.95,35.08 156.05,34.98 156.05,34.77 155.94,34.65 155.62,34.65 155.53,34.56 155.53,34.28 155.44,34.2 155.19,34.2 155.08,34.31 155.08,34.91 154.95,35.03 154.71,35.03 154.58,34.91 154.58,34.26 154.47,34.14 154.25,34.14 154.12,34.27 154.12,35.73 154.29,35.9 154.53,35.9 154.66,36.02 154.66,37.24 154.79,37.37 155,37.37 155.11,37.26 155.11,35.96 155.21,35.86 155.46,35.86 155.53,35.93 155.53,36.95 155.64,37.06 155.89,37.06 155.99,36.96 155.99,35.99 156.08,35.9 156.28,35.9 156.39,36.01 156.39,36.47 156.49,36.57 156.89,36.57 156.99,36.67 156.99,37.21 157.12,37.34 157.12,37.66 157.02,37.76 156.89,37.76 156.78,37.87 156.78,38.07 156.89,38.17 157.02,38.17 157.12,38.27 157.12,44.1 157.01,44.21 157.01,45.3 155.76,46.54 UK1.4
LX1_NVVDD: length 26.6
  TOP w0.102: v2(107.36,123.43) 107.83,122.96 v3(108.31,122.96)
  IN2 w1.016: 124.19,132.35 124.19,128.21 119.11,123.13 119.11,121.64 117.13,119.65 110.73,119.65 109.84,120.54 109.84,122.7
  vias: v3(108.95,122.96) v3(123.05,134.01) v3(123.53,133.62)
LX1_NVVDD-1: length 1.7
  TOP w0.102: PRV7.1 v2(118.03,125.74)
  vias: v3(116.44,124.73)
LX2_NVVDD: length 12.2
  TOP w0.102: v2(108.11,129.9) 108.62,129.9 v3(109.08,130.36)
  IN2 w0.508: 110.6,130.58 110.6,133.12 111.04,133.55 111.82,133.88 117.71,133.88 117.97,133.62 118.73,133.62
  vias: v3(109.71,130.36) v3(120,133.52) v3(120.4,133.95)
LX2_NVVDD-1: length 0.6
  TOP w0.102: 116.63,131.36 v2(116.01,131.36)
  vias: v3(117.08,133.12) v3(117.08,132.48)
LX_1.8V: length 1.6
  BOTTOM w0.102: v1(179.64,80.53) 178.7,81.47 PR1802.1
LX_1V:
  vias: v2(184.98,96.08) v3(184.38,96.33) v3(184.38,95.75) v3(188.27,96.51) v3(188.86,96.51)
LX_2.5V: length 1.3
  BOTTOM w0.102: PR2505.1 v1(1.63,42.36)
LX_3V: length 0.8
  TOP w0.102: v3(186.01,117.33) v2(185.23,117.33)
  vias: v3(186.62,117.33) v3(190.08,117.51) v3(190.5,117.05)
LX_5V: length 1.2
  TOP w0.102: v2(181.81,109.09) v3(181.81,107.9)
  vias: v3(181.23,107.9)
LX_CHG: length 17.8
  IN2 w0.762: 193.7,57.34 193.7,56.45 192.34,55.09 185.78,55.09 184.35,53.65 180.36,53.65 178.68,51.98
  vias: v2(178.74,50.97) v3(178,51.21) v3(192.3,57.46) v3(192.93,57.46)
LX_DDR: length 7.2
  TOP w0.102: v3(7.45,66.33) v2(7.45,65.32)
  IN2 w0.762: 6.69,67.09 7.7,67.09 10.37,69.76 10.37,71.15
  vias: v3(6.82,66.33) v3(10.24,73.18) v3(10.5,72.65)
LX_VRAM: length 1.2
  TOP w0.102: v3(184.81,140.81) v2(186.01,140.81)
  vias: v3(184.81,140.23) v3(185.09,137.24) v3(185.09,136.65) v3(188.88,137.42) v3(189.47,137.42)
MAINPWON: length 136.2
  TOP w0.102: v3(146.04,48.03) 146.07,48.06 146.07,49.8 v2(145.64,50.24) 145.27,50.6 145.27,51.48 145.5,51.71 145.5,52.34 146.83,53.68 146.83,56.66 143.29,60.21 143.29,65.01 141.9,66.4 141.9,83.14 140.78,84.26 v3(140.78,84.75)
  IN1 w0.127: v3(140.78,84.75) 140.88,84.86 141.71,84.86 141.93,84.64 144.59,84.64 146.51,86.56 155.89,86.56 156.67,85.78 161.49,85.78 165.2,89.49 171.69,89.49 173.79,87.4 176.61,87.4 178.16,88.95 178.16,90.43 180.92,93.19 187.09,93.19 191.52,97.62 191.52,108.44 190.86,109.1 v3(190.86,110.59) ; v3(156.49,43.66) 155.82,43.66 155.71,43.54 154.93,43.54 154.59,43.89 154.35,43.89 152.32,45.92 152.32,46.5 151.58,47.24 149.42,47.24 148.5,48.15 147.34,48.15 146.92,48.57 146.59,48.57 v3(146.04,48.03)
  BOTTOM w0.102: v3(156.49,43.66) 156.56,43.58 156.56,39.86 155.22,38.51 155.22,38.24 154.39,37.41 154.39,36.89 153.87,36.37 UK1.104
  BOTTOM w0.254: PR311.1 v3(190.86,110.59)
MCT1: length 5.2
  TOP w0.102: v3(24.24,128.42) 24.82,128.42 v1(25.17,128.07) RL57.1
  BOTTOM w0.102: TSL1.24 23.97,130.08 24.24,129.81 v3(24.24,128.42)
MCT2: length 3.3
  TOP w0.102: RL58.1 24.25,127.1 v3(24.24,127.08) 23.58,127.08 v1(23.33,127.34)
  BOTTOM w0.102: TSL1.21 v3(24.24,127.08)
MCT3: length 3.2
  TOP w0.102: v1(23.55,124.08) v3(24.24,124.08) 24.81,124.08 RL59.1
  BOTTOM w0.102: TSL1.18 v3(24.24,124.08)
MCT4: length 5.5
  TOP w0.102: v3(24.24,121.08) v1(25.49,122.34) 26.14,122.99 RL60.1
  BOTTOM w0.102: TSL1.15 v3(24.24,121.08)
ME_FLASH_EN: length 85.4
  IN1 w0.076: 98.76,46 99.13,46.37 99.13,47.99 99.23,48.09 99.23,52.13 99.13,52.23 99.13,53.28 99.53,53.67 v3(99.7,53.67)
  IN1 w0.127: v3(151.39,32.79) 150.91,33.27 150.28,33.27 150.14,33.13 147.8,33.13 147.59,33.33 145.18,33.33 144.17,32.32 139.66,32.32 138.72,33.26 137.8,33.26 137.37,32.82 136.27,32.82 136.18,32.91 130.95,32.91 130.67,32.63 126.87,32.63 126.39,33.1 121.23,33.1 120.48,33.86 120.41,33.86 120.37,33.9 117.53,33.9 116.97,33.33 115.47,33.33 115.34,33.21 113.86,33.21 113.68,33.03 111.91,33.03 111.29,33.65 111.29,35.67 109.58,37.38 103.05,37.38 102.22,36.55 102.22,34.11 101.79,33.68 101.03,33.68 100.46,34.25 99.5,34.25 97.77,35.98 97.77,44.58 98.69,45.49 98.69,45.93 98.76,46
  BOTTOM w0.076: RC77.1 100.24,53.28 99.85,53.67 v3(99.7,53.67)
  BOTTOM w0.102: v3(151.39,32.79) 151.56,32.95 151.56,33.8 152.13,34.37 UK1.99
MEM_VREF: length 39.6
  TOP w0.508: RV102.1 154.17,96.16 154.7,96.68 v3(154.7,97.11) ; v3(161.98,104.54) 161.35,104.54 158.51,101.7 v3(158.51,99.69)
  IN1 w0.508: v3(158.51,99.69) 158.51,98.52 157.98,97.99 156.8,97.99 156.33,97.51 156.33,97.48 156.32,97.48 156.32,97.03 155.9,96.61 155.18,96.61 154.7,97.1 v3(154.7,97.11)
  BOTTOM w0.305: UV1.C5 154.3,97.51 v3(154.7,97.11)
  BOTTOM w0.508: v3(161.98,104.54) 161.98,116.07 v2(166.48,120.57) 168.64,120.57 170.63,122.56 QV50.2
MIC2-VREFO: length 2.9
  TOP w0.203: UA1.23 19.01,34.53 18.78,34.31 18.78,34.14 v1(18.66,34.01)
  TOP w0.254: v1(18.66,34.01) 17.85,33.21 RA40.2
MIC2_CAP: length 1.8
  TOP w0.203: UA1.15 16.78,37.89 v3(16.56,37.67) 16.38,37.49 CA29.2
MUTE_LED_IN: length 186.8
  TOP w0.102: v3(164.33,24.48) 164.33,26.36 163.48,27.21 v1(163.48,27.3) 163.48,29.28 163.91,29.71 163.91,31.31 164.04,31.43 164.04,36.67 v3(163.85,36.86) ; v3(19.25,34.09) 19.25,34.32 19.41,34.47 UA1.24
  IN1 w0.127: v3(164.33,24.48) 162.34,22.49 142.52,22.49 140.03,24.98 125.74,24.98 124.63,26.09 121.56,26.09 120.35,27.3 119.11,27.3 118.3,26.49 114.44,26.49 114.33,26.38 106.64,26.38 106.09,26.93 103.93,26.93 103.7,27.15 98.87,27.15 96.43,24.71 88.04,24.71 87.27,23.93 86.8,23.93 86.53,23.67 86.53,23.06 85.61,22.13 78.71,22.13 77.78,21.2 36.94,21.2 29.17,28.98 21.57,28.98 19.25,31.3 v3(19.25,34.09)
  BOTTOM w0.102: v3(163.85,36.86) 163.66,37.05 163.66,40.7 163.44,40.92 163.44,43.34 162.77,44.01 162.77,45.43 164.17,46.83 UK1.25 164.17,48.93 163.67,49.42 RK108.2
MUTE_LED_OUT: length 56.7
  TOP w0.102: v3(204.55,34.65) 204.29,34.39 v1(203.77,34.39) 202.89,34.39 202.42,34.86 R207.1
  IN1 w0.127: v3(204.55,34.65) 205.04,35.14 205.04,39.34 202.42,41.96 199.11,41.96 198.43,41.28 183.13,41.28 182.64,40.8 179.5,40.8 178.8,41.5 174.6,41.5 173.9,40.8 172.84,40.8 171.89,41.76 166.6,41.76 v3(166.52,41.83)
  BOTTOM w0.102: RK28.1 170.39,45.36 169.8,44.77 UK1.36 167.52,44.77 166.76,44.01 166.76,43.44 166.52,43.2 v3(166.52,41.83)
MUTE_LED_OUT_R: length 8.1
  TOP w0.102: CC123.1 R207.2 v2(203.75,36.42) 203.92,36.25 203.92,35.48 204.15,35.25 v3(204.54,35.25)
  BOTTOM w0.102: JKB.4 201.57,33.59 203.23,35.25 v3(204.54,35.25)
NMI_DBG#: length 6.9
  BOTTOM w0.102: UK1.70 164.97,30.13 164.65,29.81 164.65,28.82 v1(164.87,28.61) 165.24,28.24 165.24,27.83 DK2.1 166.28,28.16 RK21.2
NMI_DBG#_CPU: length 77.6
  TOP w0.076: v3(120.42,47.62) 119.67,46.87 119.12,46.87 118.66,47.33 118.16,47.33 117.98,47.15 117.98,43.38 RC374.1
  TOP w0.102: v3(166.35,25.14) v1(165.7,25.8) 164.99,26.5 164.99,28.74 164.57,29.16 164.57,29.37 164.14,29.8 164.14,31.21 164.27,31.34 164.27,37.28 164.26,37.29 164.26,39.81 v3(166,41.55)
  IN1 w0.076: 129.68,42.66 129.52,42.82 126.86,42.82 123.43,46.25 121.01,46.25 120.42,46.84 v3(120.42,47.62)
  IN1 w0.127: 129.68,42.66 130.26,42.66 131.76,41.15 133.09,41.15 135.31,43.37 149.54,43.37 149.87,43.03 152.57,43.03 153.98,41.63 159.74,41.63 159.91,41.45 160.74,41.45 163.57,41.45 164.13,40.89 165.34,40.89 v3(166,41.55)
  BOTTOM w0.076: UC1.CE9 120.65,47.39 v3(120.42,47.62)
  BOTTOM w0.102: DK2.2 v3(166.35,25.14)
NVVDD_EN: length 6.2
  TOP w0.102: PRV3.1 127.06,133.57 v1(127.28,133.57)
  TOP w0.203: PUV1.3 123.85,135.82 124.7,136.67 PCV1.1 125.64,135.91 PRV5.1 PRV3.1
NVVDD_PSI_R: length 6.4
  TOP w0.102: PRV1.2 124.87,138.5 125.28,138.91 126.96,138.91 v1(127.44,138.42)
  TOP w0.203: PRV26.1 124.49,137.56 124.19,137.26 124.19,136.67 123.74,136.22 PUV1.4
  TOP w0.254: PRV26.1 PRV1.2
NVVDD_VID: length 6.5
  TOP w0.102: v1(127.44,139.91) 127.05,139.52 PRV6.2
  TOP w0.203: PUV1.5 123.6,136.62 123.81,136.82 123.81,137.55
  TOP w0.254: 123.81,137.55 124.19,137.93 124.19,138.88 PRV27.1 PRV6.2
ON/OFF#: length 238.9
  TOP w0.102: v3(148.73,29.21) 148.73,29.74 149.4,30.41 153.75,30.41 156.5,33.16 156.5,34.63 157.56,35.69 158.58,35.69 159.1,36.22 159.1,38.69 v3(159.9,39.49) ; v3(28.68,100.92) v2(30.12,100.92) ; v3(28.68,100.92) v2(28.68,99.83) ; v3(28.68,100.92) v2(28.68,102.05)
  IN1 w0.127: v3(28.68,100.92) 28.93,100.68 31.24,100.68 32.37,101.81 36.6,101.81 38.2,100.21 38.2,98.86 34.88,95.53 34.88,86.8 35.31,86.37 35.31,66.83 34.62,66.13 34.62,44.36 34.35,44.1 34.35,40.79 38.29,36.86 38.29,28.98 39.08,28.18 43.09,28.18 43.39,27.89 48.8,27.89 49.83,26.86 54.98,26.86 55.47,26.37 58.02,26.37 59.42,25.79 61.51,25.79 62.04,25.25 73.45,25.25 74.44,26.25 77.88,26.25 82.85,31.22 104.92,31.22 105.56,30.59 108.14,30.59 108.34,30.79 111.29,30.79 111.43,30.92 114.15,30.92 114.41,30.65 114.41,30.65 114.53,30.54 114.74,30.33 117.01,30.33 117.73,31.05 125.57,31.05 126.02,30.6 131.51,30.6 131.71,30.79 137.63,30.79 137.96,30.46 138.54,30.46 139.36,29.64 139.86,29.64 140.37,30.14 145.26,30.14 146.04,29.37 147.47,29.37 147.69,29.16 147.69,28.92 147.88,28.73 148.28,28.73 148.73,29.18 v3(148.73,29.21) ; v3(151.58,40.16) 151.58,39.94 151.72,39.8 152.31,39.8 152.99,39.12 155.53,39.12 155.67,39.26 159.67,39.26 v3(159.9,39.49)
  BOTTOM w0.102: v3(151.58,40.16) 151.79,40.37 UK1.114 ; Q4108.1 26.06,100.68 CC355.2 R215.2 28.44,100.68 v3(28.68,100.92)
ON/OFF#_R: length 21.8
  TOP w0.102: SW1.2 SW1.1 19.8,110.12 v2(20.93,108.99) 20.93,106.97 v3(22.27,105.63)
  BOTTOM w0.102: JP6.2 23.45,101.14 21.76,102.83 D1.3 ; v3(22.27,105.63) 21.76,105.12 D1.3 ; D1.3 22.18,103.63 23.16,104.6 24.81,104.6 25.79,103.63 Q4108.3
OPC_RCOMP: length 9.3
  TOP w0.076: v3(123.45,79.07) 123.87,79.07 124.35,79.55 124.35,81.25 v1(124.23,81.37) 124.01,81.59 124.01,85.14 123.97,85.18 123.97,86.91
  TOP w0.102: RC485.1 123.97,86.91
  BOTTOM w0.203: UC1.N5 v3(123.45,79.07)
OPCE_RCOMP: length 8.2
  TOP w0.076: v3(123.4,79.97) 123.85,80.42 123.85,85.07 123.15,85.77 123.15,85.88 v1(123.06,85.97) 123.06,86.82 123.15,86.91
  TOP w0.102: RC484.1 123.15,86.91
  BOTTOM w0.203: v3(123.4,79.97) 123.39,79.97 123.42,80.05 UC1.L5
P1: length 7.8
  TOP w0.102: v1(193.28,52.98) 192.39,52.98 191.88,52.47 PRB3.2
  TOP w0.254: 188.71,53.11 189.47,53.11 189.72,53.36 189.72,54 190.1,54.38 191.5,54.38 191.89,53.98 PQB2.3 191.58,53.26 PRB3.2
P2: length 1.1
  TOP w0.102: 189.54,58.43 v2(189.54,59.56)
PBTN_OUT#: length 94.2
  IN1 w0.076: v3(97.43,53.07) 97.43,51.7 97.88,51.25 97.88,48.64 97.79,48.55 97.79,47.66 97.45,47.32
  IN1 w0.127: v3(138.39,31.71) 138.29,31.81 131.29,31.81 131.09,31.61 126.45,31.61 125.99,32.07 120.76,32.07 119.95,32.88 117.95,32.88 117.34,32.27 115.87,32.27 115.79,32.19 114.28,32.19 114.03,31.94 111.01,31.94 110.87,31.8 107.91,31.8 107.72,31.6 106.05,31.6 104.41,33.24 102.79,33.24 102.21,32.66 100.59,32.66 100.01,33.24 99.08,33.24 96.83,35.49 92.54,35.49 92.06,35.98 92.06,43.52 93.9,45.36 95.36,45.36 95.99,45.99 96.12,45.99 97.45,47.32
  BOTTOM w0.076: RC109.2 97.85,52.65 v3(97.43,53.07)
  BOTTOM w0.102: R295.1 149.87,42.9 148.44,42.9 148.33,42.79 144.03,42.79 141.08,39.84 141.08,36.37 140.57,35.86 140.57,34.91 138.39,32.72 v3(138.39,31.71)
  BOTTOM w0.203: UK1.122 151.61,43.57 151.29,43.25 150.43,43.25 R295.1
PBTN_OUT#_R: length 11.6
  TOP w0.076: v1(98.97,51.91) 99.39,52.33 v3(99.56,52.33)
  IN1 w0.076: v3(107.84,52.38) 107.29,52.93 105.57,52.93 105.43,53.07 103.19,53.07 102.71,52.59 100.48,52.59 100.41,52.52 99.75,52.52 v3(99.56,52.33)
  BOTTOM w0.076: RC109.1 99.13,52.65 99.45,52.33 v3(99.56,52.33)
  BOTTOM w0.089: v3(107.84,52.38) 108.5,52.38 UC1.BU28
PC_BEEP: length 1.9
  TOP w0.102: UA1.11 17.04,39.49 16.51,40.02 CA42.2
PC_BEEP_R: length 2.9
  TOP w0.102: RA16.1 13.84,42.73 CA44.2 CA43.2 v1(12.77,44.53)
PCH_DPWROK: length 134.2
  TOP w0.102: v3(87.22,35.79) 86.55,35.79 RC101.1 v1(85.28,35.72) ; v3(149.97,29.15) 149.97,29.85 150.07,29.95 153.95,29.95 156.98,32.98 156.98,34.47 157.75,35.24 158.77,35.24 159.56,36.03 159.56,38.16 160.33,38.93 160.69,38.93 160.99,39.24 160.99,41.22 161.91,42.14 v3(161.91,42.56)
  IN1 w0.127: v3(151.14,45.73) 151.52,45.73 153.61,43.63 154.49,43.63 154.88,43.24 157.18,43.24 157.35,43.4 159.83,43.4 160.28,42.96 161.51,42.96 v3(161.91,42.56) ; v3(87.22,35.79) 88.62,34.4 97.2,34.4 98.87,32.73 99.8,32.73 100.39,32.14 102.43,32.14 102.98,32.7 104.17,32.7 105.77,31.1 107.93,31.1 108.12,31.29 111.08,31.29 111.22,31.43 114.24,31.43 114.5,31.68 115.2,31.68 115.87,31.01 116.8,31.01 118.16,32.37 119.74,32.37 120.55,31.56 125.78,31.56 126.23,31.11 131.3,31.11 131.5,31.3 137.84,31.3 138.17,30.97 142.62,30.97 142.93,30.65 145.47,30.65 146.17,29.95 147.91,29.95 148.23,29.64 149.48,29.64 149.97,29.15 v3(149.97,29.15)
  BOTTOM w0.076: 94.78,53.3 95.61,53.3 96.12,52.79 96.65,52.79 97.28,53.42 98.33,53.42 RC230.2
  BOTTOM w0.102: v3(87.22,35.79) 87.22,40.65 89.93,43.36 91.05,43.36 91.79,44.1 91.79,45.75 89.64,47.9 89.64,51.39 91.55,53.3 94.78,53.3 ; UK1.127 151.29,45.57 v3(151.14,45.73)
PCH_DPWROK_R: length 11.3
  TOP w0.076: v3(99.56,52.92) 99.07,53.41 v2(99.07,54.25)
  IN1 w0.076: v3(99.56,52.92) 100.53,53.89 106.09,53.89 106.66,53.33 v3(106.8,53.33)
  BOTTOM w0.076: RC230.1 99.06,53.42 v3(99.56,52.92)
  BOTTOM w0.089: v3(106.8,53.33) 106.9,53.33 107.37,53.79 UC1.BP30
PCH_JTAG_TCK1: length 15.2
  TOP w0.076: v3(122.82,75.37) 122.82,75.43 123.48,76.09 123.48,76.32 123.87,76.71 124,76.71 125.71,78.43 125.71,81.13 126.7,82.12 126.7,82.52 v2(128.69,84.5) 129.75,85.57
  TOP w0.102: 129.75,85.57 129.83,85.64 RC399.1
  BOTTOM w0.076: UC1.W6 v3(122.82,75.37)
PCH_OPIRCOMP: length 13.9
  TOP w0.076: v3(110,50.53) 110,51.48 109.52,51.96 107.61,51.96 107.59,51.94 105.86,51.94 v1(105.2,51.28) 104.78,50.86 102.7,50.86 102.19,51.37 101.6,51.37 100.67,52.29 100.67,53.13 100.33,53.47 RC6.1
  BOTTOM w0.203: UC1.BW25 110.21,50.78 110,50.58 v3(110,50.53)
PCH_PWR_EN: length 140.8
  TOP w0.102: v2(155.12,45.97) 155.12,45.43 v3(155.28,45.27)
  IN1 w0.127: v3(155.28,45.27) 155.6,45.59 156.4,45.59 157.83,44.17 159.49,44.17 159.68,44.36 160.79,44.36 161,44.14 161.47,44.14 163.66,46.32 175.6,46.32 176.5,45.42 183.32,45.42 184.05,44.69 196.63,44.69 201.69,49.74 203.98,49.74 206.15,51.91 206.15,63.48 208.82,66.15 208.82,75.19 207.67,76.35 205.96,76.35 204.07,74.46 204.07,73.96 203.42,73.3 202.82,73.3 202.51,73.61 202.51,79.09 202.9,79.48 202.9,83.29 201.71,84.48 v3(184.54,84.48)
  BOTTOM w0.102: v3(155.28,45.27) 155.66,45.65 155.93,45.65 156.31,45.28 156.31,44.79 155.85,44.33 155.85,43.39 156.11,43.14 156.11,40.05 154.72,38.66 154.72,38.39 153.9,37.57 UK1.107 149.08,37.57 148.9,37.4 148.2,37.4 CC362.1 148.18,37.4 146.54,37.4 146.21,37.07 146.21,35.62 RK117.2 145.41,34.82 Q5001.2
  BOTTOM w0.254: PR1804.1 v3(184.54,84.48)
PCH_PWR_EN#: length 4
  BOTTOM w0.102: v1(143.32,38.44) 143.09,38.21 143.09,37.07 142.63,36.61 R5092.2 142.63,36.09 142.82,35.9 Q5001.6 Q5001.5
PCH_PWROK: length 155.1
  TOP w0.102: v3(88.5,36.34) 88.22,36.34 v1(87.63,36.94)
  IN1 w0.127: v3(168.59,28.91) 168.29,28.91 167.97,29.22 167.97,29.62 166.53,31.06 160.82,31.06 158.95,29.18 154.23,29.18 153.64,29.77 150.84,29.77 150.46,30.15 148.48,30.15 148.04,30.58 147.77,30.58 147.26,31.1 145.8,31.1 145.61,30.91 143.77,30.91 143.37,31.3 138.64,31.3 138.56,31.22 138.28,31.22 137.95,31.55 131.39,31.55 131.2,31.36 126.34,31.36 125.89,31.81 120.65,31.81 119.84,32.63 118.06,32.63 117.45,32.01 115.97,32.01 115.89,31.94 114.39,31.94 114.14,31.68 111.11,31.68 110.98,31.55 108.02,31.55 107.82,31.35 105.88,31.35 104.24,32.99 102.91,32.99 102.32,32.4 100.49,32.4 99.91,32.98 98.98,32.98 96.72,35.24 89.61,35.24 v3(88.5,36.34)
  BOTTOM w0.076: UC1.BP31 106.73,53.79 106.44,53.5 106.35,53.32 105.8,52.77 105.43,52.77 105.38,52.72 104.54,52.72 104.52,52.74 104.43,52.77 103.72,52.77 103.55,52.72 103.15,52.31 102.61,52.31 101.55,51.26 101.55,51.18 101.38,51 100.01,51 99.94,51.07 99.26,51.07 99.01,51.33 98.47,51.33 CC299.1 97.99,51.14 RC956.2 97.93,50.57 97.93,48.87 97.66,48.23 97.66,45.82 96.97,45.12
  BOTTOM w0.102: v3(168.59,28.91) 169.02,29.33 169.02,31.85 166.61,34.26 166.61,37.78 165,39.39 165,42.21 166.44,43.65 166.44,45.73 166.97,46.25 UK1.32 ; DC3.2 89.69,26.77 85.96,30.5 85.96,32.91 88.5,35.45 v3(88.5,36.34) 88.5,41.3 90.28,43.07 91.17,43.07 93.22,45.12 96.97,45.12
PCH_RSMRST#: length 124.4
  TOP w0.102: v3(143.92,23.71) 144.51,24.3 144.51,26.22 145.8,27.52 149.08,27.52 149.31,27.75 CC361.1 149.41,28.68 150.64,28.68 151.06,29.1 v3(151.06,29.1) ; v3(85.52,32.53) v1(84.6,32.53)
  IN1 w0.127: v3(143.92,23.71) 143.92,24.31 143.53,24.7 141.47,24.7 140.32,25.85 139.33,25.85 138.43,26.75 137.21,26.75 136.67,27.29 136.67,28.18 136.43,28.43 135.11,28.43 134.11,27.43 128.5,27.43 128.37,27.56 127.25,27.56 126.79,27.11 121.98,27.11 120.78,28.31 118.69,28.31 117.88,27.5 114.02,27.5 113.91,27.39 107.06,27.39 106.15,28.3 104.61,28.3 104.01,28.9 97.44,28.9 96.85,28.3 94.2,28.3 v3(93.01,27.11)
  IN2 w0.076: v3(102,52.21) 100.8,51.01 100.8,47.78 100.02,47 99.73,47 98.84,46.11 98.73,45.86 98.73,45.42 96.75,43.44 96.75,42.38 96.14,41.77 95.61,41.77 95.52,41.68 95.4,41.68
  IN2 w0.127: v3(85.52,32.53) 85.52,32.72 90.28,37.49 90.28,39.39 90.84,39.95 91.85,39.95 93.58,41.68 95.4,41.68
  BOTTOM w0.076: CC298.1 100.82,51.83 RC958.2 101.83,52.39 v3(102,52.21) 102.27,52.21 102.62,52.56 103.16,52.56 103.46,52.86 103.7,52.94 103.72,52.94 103.89,53.1 UC1.BR36
  BOTTOM w0.102: UK1.100 151.87,34.77 151.17,34.08 151.17,33.33 150.98,33.13 150.98,32.55 151.51,32.02 151.99,32.02 152.18,31.83 152.18,31.25 151.06,30.13 v3(151.06,29.1) ; v3(93.01,27.11) 92.68,26.77 DC4.2 92.18,26.22 DC3.1 89.56,25.29 89.56,26.52 85.52,30.56 v3(85.52,32.53)
PCH_RTCRST#: length 27.5
  TOP w0.102: v3(90.79,40.79) v2(89.89,40.79)
  IN2 w0.076: v3(102.22,53.54) 100.31,51.62 100.31,49.4 99.18,48.27 98,45.71 96.18,43.89
  IN2 w0.127: 96.18,43.89 94.92,42.63 92.63,42.63 v3(90.79,40.79)
  BOTTOM w0.076: UC1.BR34 104.92,53.44 104.38,53.44 104.37,53.44 104.07,53.52 103.81,53.52 103.77,53.5 103.5,53.5 103.02,53.7 102.39,53.7 v3(102.22,53.54)
  BOTTOM w0.102: R1088.2 v3(90.79,40.79) 90.24,40.24 CC11.2 90.05,39.33 CLRP2.2 90.05,38.35 90.53,37.87 RC93.2
PCH_RTCX1: length 25.3
  IN2 w0.127: v3(107.27,54.3) 107.27,54.28 107.58,53.98 107.68,53.98 108.35,53.31 108.35,53.17 108.66,52.86 108.92,52.86 109.01,52.96 109.62,52.96 109.77,52.81 110.23,52.81 110.45,52.59 110.45,52.27 110.28,52.1 110.28,51.09 110.6,50.77 110.6,50.04 110.52,49.97 110.52,49.36 110.47,49.3 110.47,47.69 110.32,47.54 110.32,47.07 108.28,45.04 107.27,45.04 106.49,44.26 106.49,43.03 105.39,41.93 105.39,40.96 105.32,40.88 105.11,40.68 105.11,40.5 v3(105.24,40.37)
  BOTTOM w0.102: v3(105.24,40.37) 105.09,40.22 105.09,39.08 105.41,38.75 105.41,38.66 RC98.1 105.84,37.51 CC15.1 105.94,37.28 105.94,36.45 YC1.1 ; UC1.BN31 107.27,54.39 v3(107.27,54.3)
PCH_RTCX2: length 25.3
  IN2 w0.127: v3(106.64,54.3) 106.64,54.27 107.15,53.77 107.59,53.77 108.13,53.22 108.13,53.08 108.57,52.65 109.01,52.65 109.1,52.74 109.49,52.74 109.69,52.55 109.69,52.11 110.07,51.73 110.07,51 110.38,50.68 110.38,50.13 110.31,50.06 110.31,49.45 110.26,49.39 110.26,47.78 110.11,47.63 110.11,47.16 108.19,45.25 107.18,45.25 106.28,44.35 106.28,43.12 105.18,42.02 105.18,41.05 104.89,40.76 104.89,40.63 v3(104.64,40.38)
  BOTTOM w0.102: YC1.2 104.81,36.43 104.81,37.23 CC16.1 104.92,37.57 RC98.2 105.22,38.53 105.22,38.67 104.9,39 104.9,40.12 v3(104.64,40.38) ; UC1.BN32 106.64,54.38 v3(106.64,54.3)
PCH_SMBCLK: length 47.4
  TOP w0.102: v3(80.99,23.37) 80.43,23.37 80.25,23.19 RC216.1
  IN2 w0.127: v3(64.75,24.05) 63.33,22.63 52.82,22.63 52.38,23.06 v3(52.38,23.61) ; v3(75.74,23.29) 75.88,23.15 78.06,23.15 79.47,21.74 80.96,21.74 81.43,21.93 81.5,22.09 v3(80.99,23.37)
  BOTTOM w0.102: QC1.1 v3(80.99,23.37) ; v3(75.74,23.29) 75.59,23.13 75.17,23.13 74.8,23.5 67.69,23.5 67.14,24.05 66.77,24.05 66.65,24.18 65.91,24.18 65.78,24.05 v3(64.75,24.05) 64.62,24.18 64.62,27.67 64.52,27.78 JDIMM1.253 ; v3(52.38,23.61) 51.39,24.6 51.39,26.02 50.83,26.58 50.83,27.57 50.63,27.78 JDIMM2.253
PCH_SMBDATA: length 56.7
  TOP w0.102: v3(82.29,20.1) 81.83,20.57 v1(81.3,20.57) 80.87,20.57 80.56,20.26 RC215.1
  IN2 w0.127: v3(82.29,20.1) 81.78,21.38 81.38,21.56 81.32,21.56 81.01,21.43 79.35,21.43 77.94,22.84 75.88,22.84 v3(75.74,22.7)
  BOTTOM w0.102: 53.14,23.39 52.93,23.18 52.13,23.18 51.54,23.77 45.11,23.77 44.22,24.65 44.22,25.44 42.14,27.53 JDIMM2.254 ; 53.14,23.39 52.89,23.63 52.89,23.93 52.45,24.37 52.45,25.72 51.94,26.22 51.94,27.35 52.47,27.88 52.96,27.88 53.31,27.52 54.3,27.52 JDIMM1.254 ; 53.14,23.39 53.39,23.64 57.13,23.64 57.65,23.12 64.69,23.12 65.33,23.77 65.9,23.77 66.02,23.9 66.53,23.9 66.66,23.77 67.02,23.77 67.58,23.22 74.69,23.22 75.05,22.85 75.59,22.85 v3(75.74,22.7) ; QC1.4 v3(82.29,20.1)
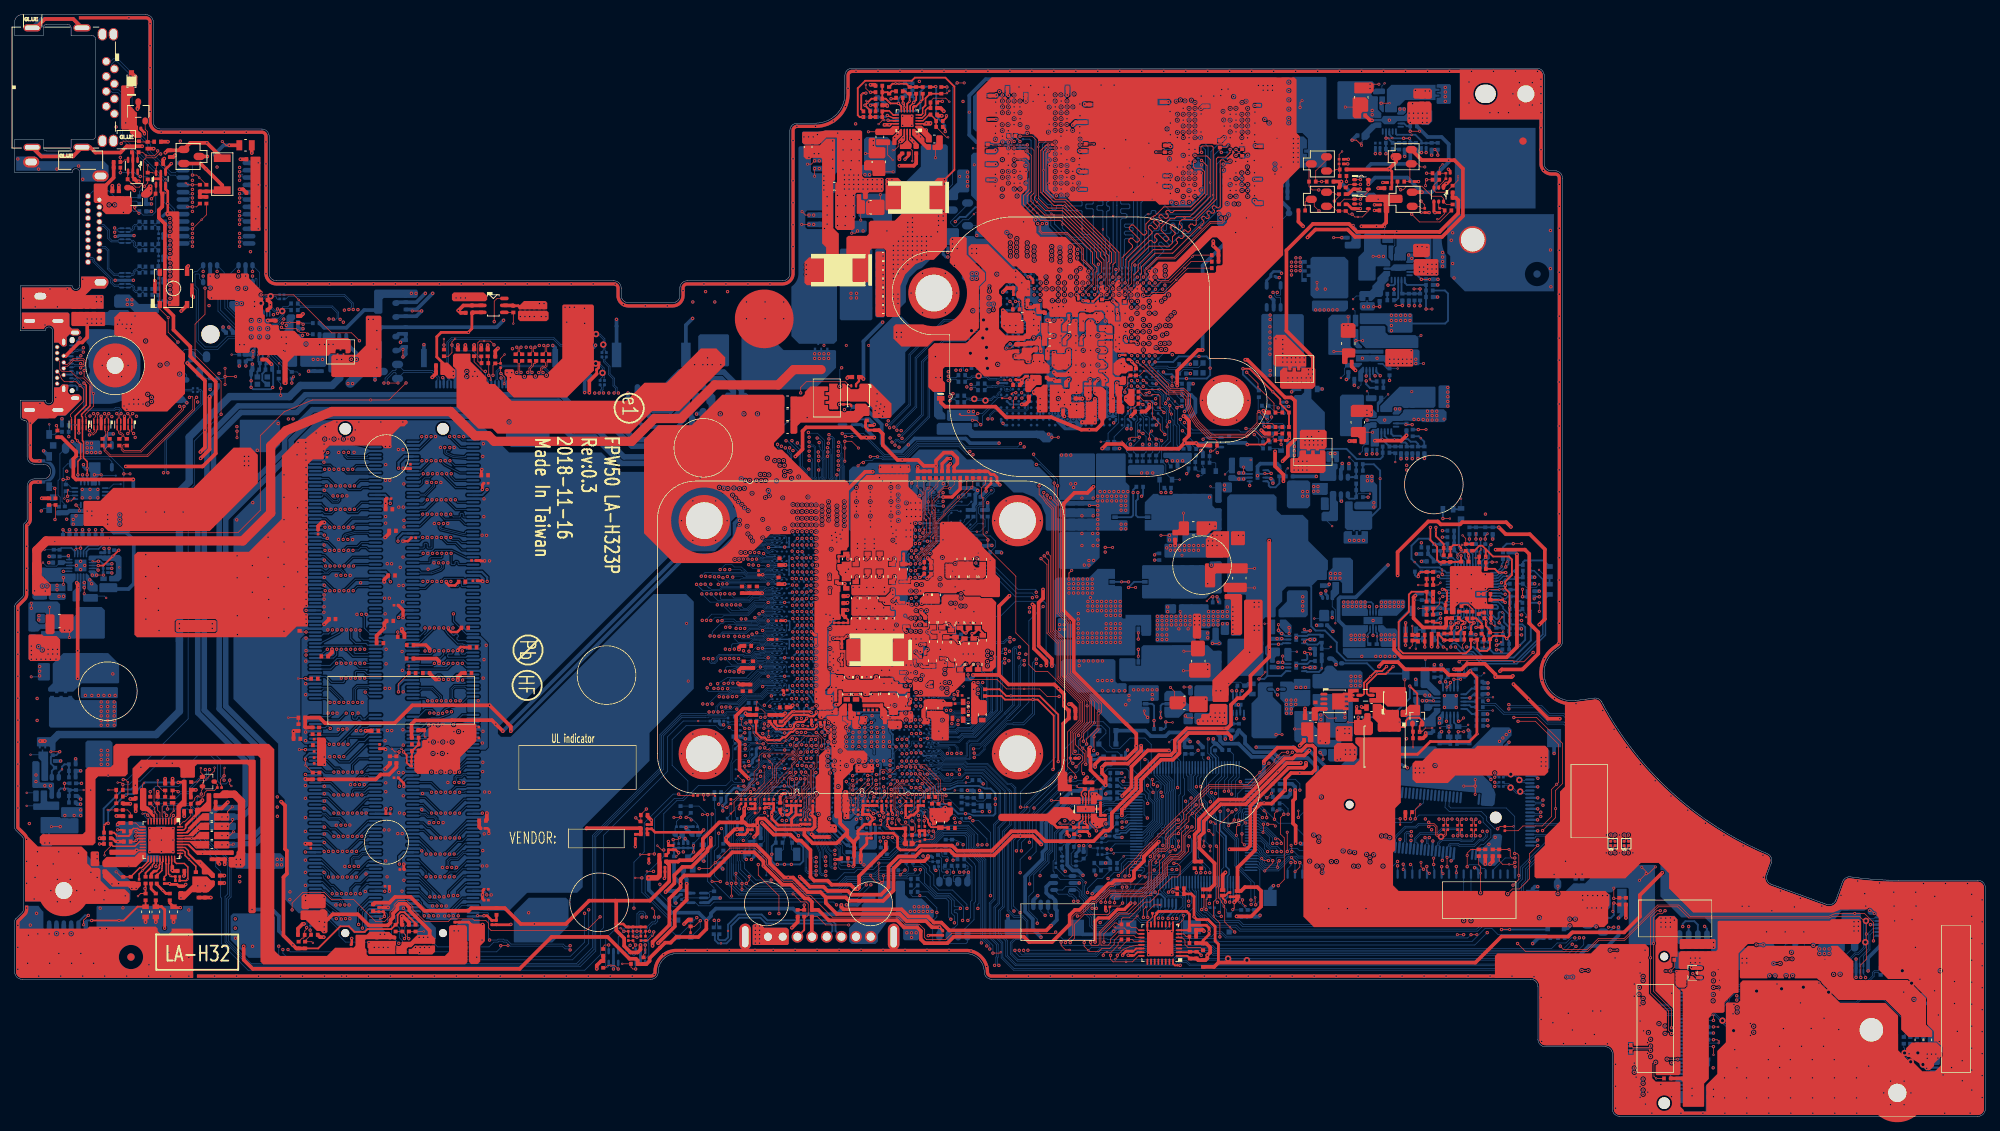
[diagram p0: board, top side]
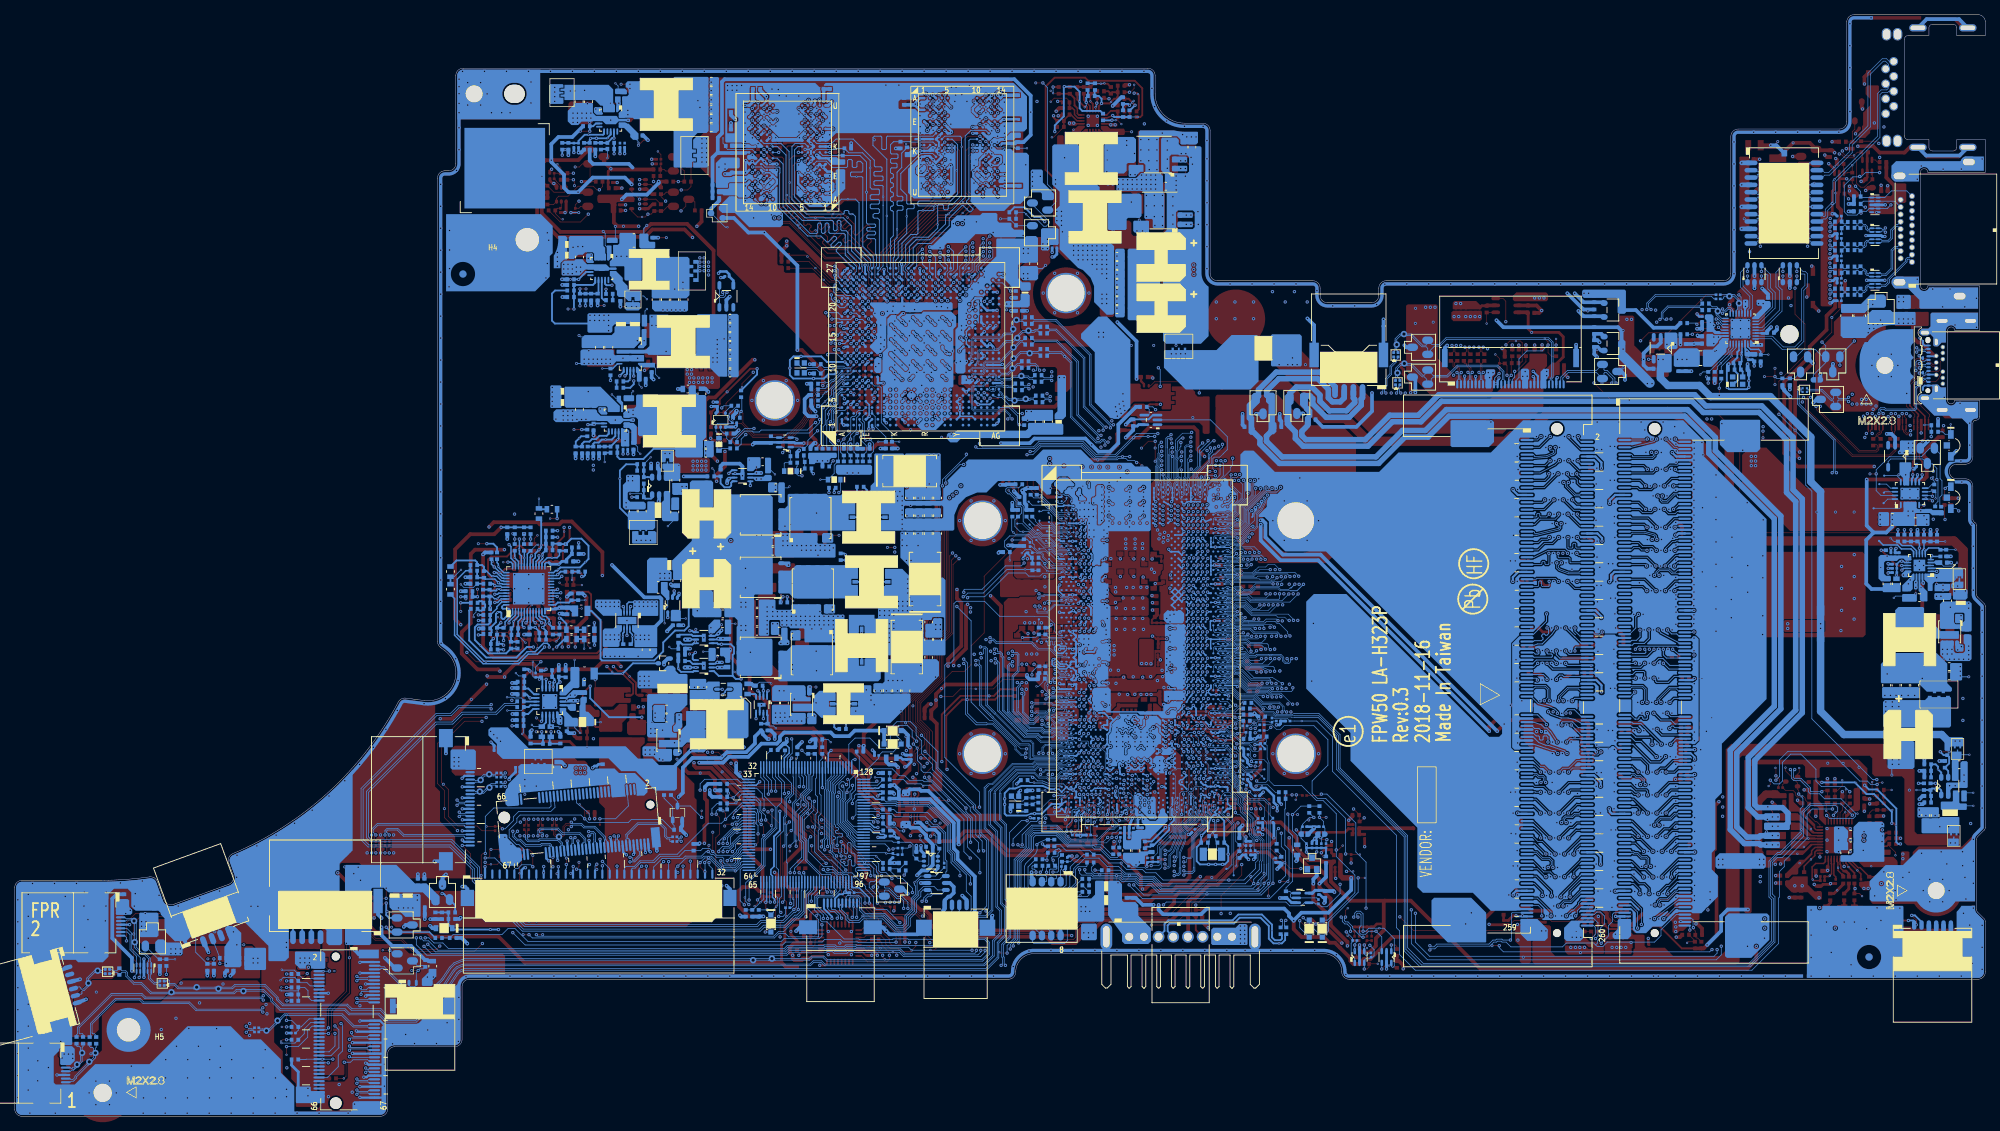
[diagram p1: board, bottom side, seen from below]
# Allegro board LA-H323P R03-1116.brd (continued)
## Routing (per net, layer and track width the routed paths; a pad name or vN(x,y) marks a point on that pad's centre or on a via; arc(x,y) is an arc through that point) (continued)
PCH_SRTCRST#: length 26.3
  TOP w0.102: v2(92.25,40.43) 91.9,40.78 v3(91.56,40.78)
  IN2 w0.076: 95.61,42.22 96.12,42.22 96.42,42.51 96.42,43.63 98.26,45.46 98.26,45.85 99.34,48.2 100.47,49.33 100.47,51.51 101.92,52.96 v3(102.16,52.96)
  IN2 w0.127: v3(91.56,40.78) 92.99,42.22 95.61,42.22
  BOTTOM w0.076: v3(102.16,52.96) 102.2,52.91 102.85,52.91 103.13,52.91 UC1.BR37
  BOTTOM w0.102: R1089.2 v3(91.56,40.78) 92.17,40.78 93.11,39.83 CC10.2 93.3,39.33 CLRP1.2 93.3,37.94 RC91.2
PCH_SUSWARN#: length 88.1
  TOP w0.102: v3(163.01,36.86) v1(163.01,36.18)
  IN1 w0.076: 106.79,41.8 106.73,41.87 106.73,43.11 106.46,43.38 106.46,44.28 106.9,44.72 107.17,44.72 108.3,45.85 108.3,46.71 108.2,46.81 108.2,47.11 107.99,47.32 107.56,47.32 107.4,47.48 106.45,47.48 105.43,48.49 105.43,50.33 v3(105.78,50.68)
  IN1 w0.127: 106.79,41.8 106.79,40.24 107.62,39.4 109.05,39.4 109.8,38.65 110.1,38.65 111.02,37.73 112.43,37.73 114.23,35.94 116.44,35.94 116.88,35.49 121.41,35.49 121.56,35.34 123.08,35.34 123.67,35.94 124.71,35.94 125.28,35.36 128.13,35.36 128.74,34.75 130.83,34.75 131.15,34.44 135.9,34.44 136.41,34.95 137.78,34.95 137.91,34.82 138.92,34.82 138.96,34.86 148.03,34.86 148.41,35.24 149.45,35.24 149.89,34.79 154.2,34.79 154.46,34.53 156.95,34.53 157.61,35.19 158.71,35.19 158.92,35.19 158.92,35.19 159.34,35.19 160.14,35.99 162.3,35.99 162.89,36.57 162.89,36.74 v3(163.01,36.86)
  BOTTOM w0.076: UC1.BV34 105.1,51.24 105.51,50.83 105.63,50.83 105.78,50.68 v3(105.78,50.68)
  BOTTOM w0.102: UK1.17 160.97,46.61 160.73,46.38 160.73,44.75 161.59,43.89 161.59,43.46 162.42,42.63 162.42,37.46 v3(163.01,36.86)
PCH_XTAL24_IN: length 2.9
  BOTTOM w0.076: RC448.2 129.66,42.79 129.68,42.77
  BOTTOM w0.102: 129.68,42.77 RC92.2 129.93,42.58 CC13.1 131.55,42.58 YC2.1
PCH_XTAL24_IN_R: length 5.5
  BOTTOM w0.076: UC1.CK3 124.86,43.99 125.38,43.47 125.73,43.47 125.82,43.56 126.18,43.56 126.52,43.22 127.51,43.22 128.85,41.88 RC448.1
PCH_XTAL24_OUT: length 4.2
  BOTTOM w0.102: YC2.3 132.12,43.01 131.24,43.01 130.81,43.44 CC12.1 129.93,43.44 RC92.1 129.24,43.47 RC447.2
PCH_XTAL24_OUT_R: length 4.3
  BOTTOM w0.076: UC1.CK2 125.49,44.27 125.78,43.97 126.3,43.97 126.51,44.18 127.9,44.18 v1(128.19,44.47) 128.23,44.51 RC447.1
PCIE_CRX_C_DTX_N9: length 3.6
  BOTTOM w0.102: CR13.2 37.46,110.23 36.76,110.23 36.71,110.18 36.71,109.34 35.84,108.46 UL1.18
PCIE_CRX_C_DTX_P9: length 3.7
  BOTTOM w0.102: CR11.2 37.24,110.45 36.6,110.45 36.48,110.33 v4(36.48,109.86) 36.48,109.41 35.9,108.83 35.85,108.83 35.81,108.86 UL1.17
PCIE_CRX_DTX_N9: length 152.9
  IN2 w0.076: 130.92,69.55 129.72,68.35 129.72,68.35 ; 129.68,68.31 129.58,68.2 129.53,68.2 129.24,67.91 129.24,65.99 128.13,64.87 128.13,64.47 128.13,60.62 127.38,59.87 125.23,59.87 124.61,60.49 123.54,60.49 123.03,59.98 122.73,59.98 122.41,59.67 122.41,59.39 122.79,59.01 122.79,58.5 121.65,57.36 121.65,56.83 122.02,56.47 122.02,55.7 121.71,55.39 121.35,55.39 121.14,55.18 121.14,53.91 121.33,53.72 122.38,53.72 122.39,53.73 123.18,53.73 123.53,53.38 v3(123.53,53.2)
  IN2 w0.127: 130.92,69.55 130.98,69.62 130.98,73.46 132.57,75.04 132.57,76.64 131.44,77.77 131.44,84.58 131.97,85.11 131.97,85.42 132.05,85.49 132.05,88.29 114.95,105.39 106.84,105.39 105.97,106.26 81.03,106.26 79.39,107.9 68,107.9 67.33,107.22 47.13,107.22 44.85,109.49 43.95,109.49 43.67,109.22 43.67,108.99 v3(43.44,108.77) ; 129.68,68.31 129.72,68.34 129.72,68.35
  BOTTOM w0.076: UC1.BP5 v3(123.53,53.2)
  BOTTOM w0.102: v3(43.44,108.77) 43.44,108.72 43.54,108.62 43.69,108.62 43.96,108.9 43.96,109.61 43.23,110.34 38.94,110.34 CR13.1
PCIE_CRX_DTX_N10: length 187.8
  IN2 w0.076: 131.43,47.74 131.43,50.29 130.86,50.86 125.91,50.86 124.3,52.46 124.3,53.5 124.04,53.77 124.04,54.39 123.81,54.62 123.48,54.62 122.95,54.09 v3(122.82,54.09)
  IN2 w0.127: 131.43,47.74 134.94,44.24 135.79,44.24 141.87,44.24 144.15,41.96 145.35,41.96 145.83,41.47 147.63,41.47 147.94,41.17 148.46,41.17 149.53,40.1 149.53,38.52 150.65,37.4 151.17,37.4 151.92,38.14 157.11,38.14 157.76,37.49 158.94,37.49 159.37,37.06 159.37,36.21 159.85,35.73 164.77,35.73 165.16,35.33 166.97,35.33 171.41,30.89 190.5,30.89 192.21,32.61 201.16,32.61 202.29,33.75 202.29,36.93 203.92,38.55 203.92,41.52 200.47,44.97 200.47,46.62 202.32,48.47 206.29,48.47 208.26,50.44 211.38,50.44 232.75,29.07 232.75,9.11 232.32,8.68 228.16,8.68 226.93,9.91 224.53,9.91 223.77,10.67 223.22,10.67 v3(223.06,10.51)
  BOTTOM w0.076: UC1.BN6 122.6,54.34 122.82,54.11 v3(122.82,54.09)
  BOTTOM w0.102: JWLAN.35 220.44,10.55 220.59,10.69 222.87,10.69 v3(223.06,10.51)
PCIE_CRX_DTX_N13: length 79.7
  IN2 w0.076: v3(122.89,55.97) 123.08,55.78 123.08,55.64 123.36,55.37 124.26,55.37 125.26,54.37 125.26,52.82 125.99,52.09 126.55,52.09 127.05,51.58 131.32,51.58 132.4,50.51 132.4,48.34 132.37,48.31 132.37,48.09 132.4,48.06 132.4,48.03 132.41,48.02
  IN2 w0.127: v3(184.8,34.72) 184.21,34.72 184.03,34.55 184.03,33.77 182.4,32.14 173.47,32.14 173.04,32.57 171.32,32.57 167.42,36.47 166.24,36.47 165.35,37.36 161.8,37.36 160.34,38.82 159.62,38.82 159.43,39.01 157.84,39.01 157.59,39.26 153.48,39.26 151.26,41.47 149.83,41.47 148.82,42.48 148.21,42.48 147.62,43.07 144.71,43.07 142.43,45.35 135.07,45.35 132.41,48.02
  BOTTOM w0.076: UC1.BK6 v3(122.89,55.97)
  BOTTOM w0.102: JSSD.5 183.23,36.3 183.31,36.21 183.31,35.56 184.15,34.72 v3(184.8,34.72)
PCIE_CRX_DTX_N14: length 82.7
  IN2 w0.076: v3(122.89,56.89) 123.01,56.89 123.56,56.34 123.75,56.34 125.63,54.46 125.63,53.21 126.11,52.73 126.54,52.73 127.22,52.05 131.25,52.05 131.3,52
  IN2 w0.127: 131.3,52 133.84,52 135.24,53.4 138.23,53.4 139.72,51.92 140.14,51.29 140.43,50.59 140.58,49.85 140.58,49.04 142.64,46.97 142.64,46.14 144.2,44.58 147.41,44.58 148.01,43.98 148.01,43.7 148.55,43.17 149.11,43.17 150.12,42.16 151.55,42.16 153.68,40.03 158.14,40.03 158.39,39.77 158.95,39.77 159.2,40.03 160.77,40.03 162.75,38.04 165.68,38.04 166.55,37.17 167.7,37.17 171.6,33.27 173.4,33.27 173.8,32.86 179.89,32.86 182.09,35.06 182.96,35.06 184.64,36.74 184.64,37.31 186.08,38.74 186.42,38.74 186.53,38.62 186.53,38.41 v3(186.38,38.25)
  BOTTOM w0.076: UC1.BJ6 v3(122.89,56.89)
  BOTTOM w0.102: v3(186.38,38.25) 186.51,38.11 186.51,37.77 186.5,37.72 186.35,37.6 JSSD.17
PCIE_CRX_DTX_N15: length 85.6
  IN2 w0.076: 131.68,52.98 130.92,52.98 130.58,52.64 127.58,52.64 126.73,53.49 126.43,53.49 126.13,53.79 126.13,54.66 125.46,55.33 125.46,55.8 123.85,57.41 123.25,57.41 123.17,57.49 123.17,57.59 123.24,57.66 123.24,57.73 123.32,57.82 v3(123.53,57.82)
  IN2 w0.127: v3(190.43,38.85) 190.24,38.65 188.34,38.65 187.31,39.68 185.68,39.68 184.12,38.12 181.63,38.12 179.09,35.58 170.65,35.58 168.11,38.12 166.93,38.12 165.3,39.75 162.47,39.75 161.04,41.17 155.56,41.17 155.27,41.46 153.58,41.46 151.75,43.29 150.57,43.29 149.14,44.71 148.63,44.71 147.78,45.56 146.33,45.56 144.96,46.93 144.83,46.93 141.44,50.31 141.33,50.86 140.97,51.73 140.45,52.51 138.46,54.5 135.01,54.5 133.52,53.02 131.97,53.02 131.94,52.98 131.68,52.98
  BOTTOM w0.076: UC1.BG5 v3(123.53,57.82)
  BOTTOM w0.102: JSSD.29 189.34,37.32 189.5,37.45 189.51,37.61 189.52,37.74 189.52,38.58 189.79,38.85 v3(190.43,38.85)
PCIE_CRX_DTX_N16: length 88
  IN2 w0.076: 131.94,53.66 130.73,53.66 130.05,52.98 127.88,52.98 127.01,53.85 127.01,54.27 126.05,55.23 126.05,55.87 124.4,57.51 124.4,58.14 123.43,59.11 123.43,59.52 v3(123.52,59.6)
  IN2 w0.127: 131.94,53.66 132.75,53.66 132.79,53.7 133.22,53.7 134.71,55.19 138.18,55.19 138.18,55.19 138.74,55.19 140.98,52.95 141.58,52.06 141.99,51.06 143.89,49.17 144.26,49.17 146.92,46.51 148.65,46.51 150.63,44.53 151.47,44.53 153.86,42.14 158.12,42.14 158.39,41.88 161.58,41.88 162.55,40.91 163.27,40.91 163.75,40.43 165.71,40.43 166.88,39.26 168.04,39.26 170.51,36.8 175.02,36.8 175.55,36.27 178.69,36.27 181.23,38.81 183.8,38.81 185.36,40.37 187.81,40.37 188.56,39.62 191.82,39.62 192.76,38.68 192.76,38.16 v3(192.88,38.03)
  BOTTOM w0.076: UC1.BE5 123.25,59.33 v3(123.52,59.6)
  BOTTOM w0.102: JSSD.43 192.83,37.03 192.7,37.18 192.7,37.2 192.7,37.85 v3(192.88,38.03)
PCIE_CRX_DTX_P9: length 152.9
  IN2 w0.076: 130.64,69.63 130.64,69.55 129.07,67.98 129.07,66.05 127.96,64.94 127.96,64.4 127.96,64.4 127.96,60.69 127.31,60.04 125.3,60.04 124.68,60.66 123.47,60.66 122.96,60.15 122.66,60.15 122.25,59.74 122.25,59.32 122.63,58.94 122.63,58.57 121.48,57.43 121.48,56.76 121.85,56.4 121.85,55.77 121.64,55.56 121.28,55.56 120.98,55.25 120.98,53.84 121.26,53.56 122.45,53.56 122.45,53.56 123.11,53.56 123.18,53.49 123.18,53.28 123.1,53.2 v3(122.89,53.2)
  IN2 w0.127: 130.64,69.63 130.73,69.72 130.73,73.56 132.32,75.15 132.32,76.54 131.19,77.67 131.19,84.69 131.72,85.22 131.72,85.52 131.8,85.6 131.8,88.19 114.85,105.14 106.73,105.14 105.87,106 80.93,106 79.29,107.64 68.11,107.64 67.43,106.97 47.02,106.97 44.75,109.24 44.05,109.24 43.92,109.11 43.92,108.61 44.05,108.48 44.24,108.48 44.37,108.61 v3(44.37,108.73)
  BOTTOM w0.076: UC1.BP6 v3(122.89,53.2)
  BOTTOM w0.102: CR11.1 38.94,110.55 43.32,110.55 44.18,109.7 44.18,108.83 44.28,108.73 v3(44.37,108.73)
PCIE_CRX_DTX_P10: length 187.8
  IN2 w0.076: 131.28,47.54 131.27,47.54 131.27,47.58 131.24,47.61 131.24,47.88 131.26,47.91 131.26,50.22 130.79,50.69 125.84,50.69 124.14,52.39 124.14,53.43 123.87,53.7 123.87,54.32 123.74,54.45 123.55,54.45 123.38,54.28 123.38,54.17 v3(123.46,54.09)
  IN2 w0.127: v3(222.76,11.43) 222.46,11.13 222.46,10.95 222.59,10.82 222.78,10.82 222.88,10.93 223.87,10.93 224.63,10.17 227.04,10.17 228.27,8.94 232.22,8.94 232.49,9.21 232.49,28.97 211.28,50.19 208.37,50.19 206.4,48.22 202.42,48.22 200.72,46.51 200.72,45.08 204.17,41.63 204.17,38.45 202.55,36.82 202.55,33.64 201.26,32.35 192.32,32.35 190.6,30.64 171.3,30.64 166.86,35.08 165.06,35.08 164.66,35.48 159.74,35.48 159.11,36.11 159.11,36.95 158.83,37.23 157.66,37.23 157,37.89 152.02,37.89 151.28,37.14 150.54,37.14 149.27,38.41 149.27,40 148.35,40.91 147.83,40.91 147.53,41.22 145.72,41.22 145.24,41.7 144.04,41.7 141.76,43.98 135.68,43.98 134.83,43.98 131.28,47.54
  BOTTOM w0.076: UC1.BN5 123.25,54.3 v3(123.46,54.09)
  BOTTOM w0.102: v3(222.76,11.43) 222.76,11.21 222.46,10.91 220.58,10.91 220.44,11.05 JWLAN.33
PCIE_CRX_DTX_P13: length 79.7
  IN2 w0.076: 132.56,48.22 132.56,50.58 131.39,51.75 127.12,51.75 126.61,52.26 126.06,52.26 125.42,52.89 125.42,54.44 124.33,55.53 123.43,55.53 123.25,55.71 123.25,55.93 123.36,56.04 123.46,56.04 v3(123.53,55.97)
  IN2 w0.127: v3(184.8,35.33) 184.44,34.98 184.1,34.98 183.78,34.65 183.78,33.88 182.29,32.39 173.58,32.39 173.14,32.82 171.42,32.82 167.53,36.72 166.34,36.72 165.46,37.61 161.91,37.61 160.45,39.07 159.73,39.07 159.54,39.26 157.94,39.26 157.7,39.51 153.58,39.51 151.37,41.73 149.93,41.73 148.92,42.74 148.32,42.74 147.73,43.33 144.81,43.33 142.53,45.61 135.18,45.61 132.56,48.22
  BOTTOM w0.076: UC1.BK5 v3(123.53,55.97)
  BOTTOM w0.102: v3(184.8,35.33) 184.77,35.36 184.58,35.36 184.49,35.28 184.49,35.02 184.41,34.94 184.24,34.94 183.52,35.65 183.52,36.1 183.73,36.31 JSSD.7
PCIE_CRX_DTX_P14: length 82.7
  IN2 w0.076: v3(123.53,56.89) 123.44,56.81 123.44,56.7 123.63,56.51 123.82,56.51 125.8,54.53 125.8,53.28 126.18,52.9 126.6,52.9 127.29,52.21 131.34,52.21 131.34,52.22 131.35,52.22
  IN2 w0.127: 131.35,52.22 132.41,52.22 132.44,52.26 133.74,52.26 135.14,53.66 138.34,53.66 139.92,52.08 140.36,51.41 140.52,51.03 140.67,50.66 140.83,49.87 140.83,49.14 142.9,47.08 142.9,46.25 144.31,44.84 147.52,44.84 148.27,44.09 148.27,43.81 148.66,43.42 149.21,43.42 150.22,42.41 151.65,42.41 153.79,40.28 158.24,40.28 158.5,40.03 158.84,40.03 159.09,40.27 159.09,40.28 160.87,40.28 162.85,38.3 165.78,38.3 166.66,37.42 167.8,37.42 171.7,33.52 173.5,33.52 173.91,33.12 179.79,33.12 181.99,35.31 182.86,35.31 184.39,36.84 184.39,37.41 185.97,39 186.52,39 186.79,38.73 186.79,38.43 v3(186.96,38.25)
  BOTTOM w0.076: UC1.BJ5 v3(123.53,56.89)
  BOTTOM w0.102: v3(186.96,38.25) 186.93,38.25 186.73,38.05 186.73,37.74 186.72,37.72 186.86,37.53 JSSD.19
PCIE_CRX_DTX_P15: length 85.6
  IN2 w0.076: v3(122.89,57.82) 123.01,57.7 123.01,57.42 123.18,57.25 123.78,57.25 125.29,55.73 125.29,55.27 125.96,54.59 125.96,53.72 126.37,53.32 126.66,53.32 127.51,52.47 130.65,52.47 130.94,52.76 131.81,52.76
  IN2 w0.127: 131.81,52.76 133.63,52.76 135.11,54.25 138.36,54.25 140.25,52.35 140.75,51.61 141.09,50.79 141.21,50.18 141.26,50.13 144.72,46.67 144.86,46.67 146.22,45.31 147.67,45.31 148.52,44.46 149.04,44.46 150.46,43.03 151.64,43.03 153.47,41.21 155.16,41.21 155.46,40.91 160.94,40.91 162.36,39.49 165.2,39.49 166.82,37.87 168,37.87 170.54,35.33 179.2,35.33 181.74,37.87 184.23,37.87 185.79,39.43 187.2,39.43 188.23,38.4 190.3,38.4 v3(190.43,38.27)
  BOTTOM w0.076: UC1.BG6 v3(122.89,57.82)
  BOTTOM w0.102: v3(190.43,38.27) 190.39,38.22 190.23,38.22 190.14,38.31 190.14,38.55 190.06,38.63 189.88,38.63 189.74,38.49 189.74,37.73 189.71,37.43 189.84,37.28 JSSD.31
PCIE_CRX_DTX_P16: length 88.1
  IN2 w0.076: 131.94,53.44 130.75,53.44 130.12,52.81 127.81,52.81 126.84,53.78 126.84,54.2 125.88,55.16 125.88,55.8 124.24,57.44 124.24,58.07 123.26,59.04 123.26,59.35 123.01,59.62 v3(122.87,59.63)
  IN2 w0.127: 131.94,53.44 132.7,53.44 133.33,53.44 134.82,54.93 138.28,54.93 138.28,54.94 138.64,54.94 140.78,52.79 141.36,51.94 141.78,50.92 143.78,48.92 144.16,48.92 146.81,46.26 148.55,46.26 150.53,44.28 151.37,44.28 153.76,41.89 158.02,41.89 158.28,41.63 161.48,41.63 162.44,40.66 163.16,40.66 163.64,40.18 165.6,40.18 166.77,39.01 167.94,39.01 170.4,36.55 174.91,36.55 175.45,36.01 178.8,36.01 181.34,38.55 183.9,38.55 185.47,40.11 187.7,40.11 188.45,39.36 191.71,39.36 192.5,38.57 192.5,38.24 v3(192.3,38.03)
  BOTTOM w0.076: UC1.BE6 122.87,59.48 v3(122.87,59.63)
  BOTTOM w0.102: JSSD.41 192.33,37.08 192.49,37.21 192.49,37.84 v3(192.3,38.03)
PCIE_CTX_C_DRX_N9: length 4.8
  BOTTOM w0.102: CC327.1 36.04,111.43 35.9,111.43 35.67,111.65 35.67,111.78 35.57,111.88 v4(34.9,111.88) 34.3,111.88 33.81,111.39 33.81,110.47 33.8,110.46 33.8,110.12 33.98,109.94 UL1.14
PCIE_CTX_C_DRX_N10: length 17.4
  BOTTOM w0.102: CC20.2 235.24,11.69 v4(234.37,11.69) 233.92,11.69 233.03,12.57 233.02,12.57 232.33,13.26 232.33,13.28 231.84,13.77 224.11,13.77 222.54,12.19 220.57,12.19 220.43,12.05 JWLAN.29
PCIE_CTX_C_DRX_N13: length 10
  BOTTOM w0.102: CC184.1 179.31,37.5 179.37,37.56 179.37,37.78 179.43,37.84 179.76,37.84 180.09,38.17 180.09,39.21 180.7,39.82 183.69,39.82 185.14,38.37 185.1,37.9 185.05,37.85 184.95,37.86 184.87,37.8 JSSD.11
PCIE_CTX_C_DRX_N14: length 11.3
  TOP w0.102: v3(192.81,40.12) 192.99,39.94 193.53,39.94 193.94,39.53 193.94,38.49 194.05,38.37 194.89,38.37 195.03,38.51 195.03,38.91 CC186.1
  BOTTOM w0.102: v3(192.81,40.12) 192.64,39.95 191.38,39.95 191,39.57 189.58,39.57 188.19,38.18 188.09,37.8 188.09,37.8 188.04,37.59 187.87,37.5 187.78,36.72
PCIE_CTX_C_DRX_N15: length 10.4
  TOP w0.102: v3(197.35,38.27) 197.14,38.48 197.14,38.95 CC288.1
  BOTTOM w0.102: JSSD.35 190.84,37.2 190.84,37.92 191.61,38.69 193.95,38.69 194.58,39.33 197.05,39.33 197.35,39.02 197.35,38.28 v3(197.35,38.27)
PCIE_CTX_C_DRX_N16: length 7.8
  TOP w0.102: CC290.1 198.81,38.93 198.81,38.47 v3(198.62,38.27)
  BOTTOM w0.102: v3(198.62,38.27) 198.81,38.08 198.81,37.87 198.64,37.69 197.32,37.69 197.15,37.85 194.56,37.85 194.01,37.3 193.98,36.99 193.82,36.85 JSSD.47
PCIE_CTX_C_DRX_P9: length 4.8
  BOTTOM w0.102: UL1.13 v4(33.58,110.93) 33.58,111.47 34.21,112.1 34.43,112.1 34.44,112.11 35.35,112.11 35.36,112.1 CC326.1
PCIE_CTX_C_DRX_P10: length 17.4
  BOTTOM w0.102: JWLAN.27 220.41,12.55 220.55,12.41 222.45,12.41 224.02,13.98 231.93,13.98 v4(232.86,13.06) 233.99,11.92 234.89,11.92 234.91,11.91 235.24,11.91 CC19.2
PCIE_CTX_C_DRX_P13: length 10
  BOTTOM w0.102: JSSD.13 185.37,37.76 185.31,37.83 185.37,38.45 183.78,40.04 180.61,40.04 179.88,39.3 179.88,38.26 179.67,38.06 179.07,38.06 CC185.1
PCIE_CTX_C_DRX_P14: length 11.3
  TOP w0.102: v3(192.81,39.54) 192.99,39.72 193.44,39.72 193.72,39.44 193.72,38.4 193.97,38.15 v4(194.48,38.15) 194.97,38.15 195.24,38.42 195.24,38.96 CC187.1
  BOTTOM w0.102: v3(192.81,39.54) 192.61,39.73 191.47,39.73 191.09,39.35 189.67,39.35 188.39,38.07 188.38,38.04 188.3,37.73 188.26,37.58 188.26,37.56 188.34,37.36 JSSD.25
PCIE_CTX_C_DRX_P15: length 10.4
  TOP w0.102: v3(196.76,38.27) 196.92,38.43 196.92,38.92 CC289.1
  BOTTOM w0.102: JSSD.37 191.34,37.21 191.27,37.3 191.13,37.3 191.05,37.37 191.05,37.83 191.7,38.48 194.04,38.48 194.67,39.11 196.96,39.11 197.14,38.93 197.14,38.77 197.05,38.68 196.69,38.68 196.62,38.6 196.62,38.42 v3(196.76,38.27)
PCIE_CTX_C_DRX_P16: length 7.8
  TOP w0.102: v3(199.2,38.27) 199.03,38.45 199.03,38.93 CC291.1
  BOTTOM w0.102: v3(199.2,38.27) 199.03,38.1 199.03,37.78 198.73,37.47 197.23,37.47 197.06,37.64 194.65,37.64 194.22,37.21 194.2,36.98 194.2,36.94 194.32,36.8 JSSD.49
PCIE_CTX_DRX_N9: length 153.6
  IN2 w0.076: 129.23,63.91 129.22,63.89 129.22,63.83 128.47,63.08 128.47,60.73 127.45,59.71 125.99,59.71 125.6,59.32 125.6,56.82 126.35,56.07 126.35,55.16 127.43,54.08 127.78,54.08 128.41,53.45 v3(128.63,53.45)
  IN2 w0.127: v3(45.58,110.08) 45.58,109.38 47.3,107.65 66.85,107.65 67.52,108.33 79.57,108.33 81.21,106.69 106.15,106.69 107.02,105.82 115.13,105.82 125.07,95.88 126.32,95.88 132.94,89.26 132.94,85.05 131.87,83.98 131.87,77.95 133,76.82 133,74.87 131.42,73.28 131.42,66.09 129.23,63.91
  BOTTOM w0.076: v3(128.63,53.45) 128.46,53.45 128.03,53.03 127.56,53.03 127.52,53.07 126.31,53.07 126.31,53.07 125.63,53.07 UC1.BR2
  BOTTOM w0.102: CC327.2 36.99,111.53 37.35,111.88 44.93,111.88 45.94,110.86 45.94,110.44 v3(45.58,110.08)
PCIE_CTX_DRX_N10: length 159.6
  IN2 w0.127: v3(237.12,11.47) 237.89,11.47 238.25,11.83 238.25,15.48 235.06,18.66 235.06,29.67 211.88,52.85 207.27,52.85 205,50.58 201.5,50.58 196.51,45.59 186.89,45.59 185.83,44.53 176.91,44.53 176.47,44.09 172.84,44.09 169.02,45.67 166.23,48.46 158.25,48.46 156.64,50.07 152.83,50.07 152.21,50.69 151.26,50.69 141.68,60.28 131.68,60.28 131.35,59.96 v3(131.35,59.19)
  BOTTOM w0.076: UC1.BR4 124.54,53.67 124.81,53.67 125.16,53.83 125.42,53.83 125.52,53.79 125.73,53.79 125.75,53.8 125.82,53.82 126.2,53.82 126.32,53.7 126.77,53.7 127.32,54.25 127.97,54.25 128.32,54.59 128.86,54.59 129.75,53.7
  BOTTOM w0.102: 129.75,53.7 130.31,53.7 131.87,55.27 131.87,55.75 131.85,55.77 131.85,58.43 131.53,58.74 131.53,59.01 v3(131.35,59.19) ; v3(237.12,11.47) 236.82,11.77 236.56,11.77 236.48,11.69 236.18,11.69 CC20.1
PCIE_CTX_DRX_N13: length 63.3
  IN2 w0.127: v3(130.04,54.67) 130.26,54.9 132.83,54.9 134.34,56.41 139.11,56.41 143.81,51.71 144.25,51.71 147.31,48.65 148.1,48.65 150.6,46.15 152.2,46.15 152.65,45.69 155.81,45.69 156.79,44.71 157.67,44.71 158.41,43.96 162.44,43.96 163.04,43.37 163.81,43.37 164.92,42.26 166.9,42.26 170.72,38.44 175.73,38.44 176.46,37.7 177.64,37.7 v3(177.82,37.52)
  BOTTOM w0.076: UC1.BM4 124.49,55.28 124.8,54.97 126.09,54.97 126.19,54.87 127.89,54.87 128.16,55.14 129.33,55.14 129.54,54.92 129.79,54.92 v3(130.04,54.67)
  BOTTOM w0.102: CC184.2 178.2,37.71 178,37.71 v3(177.82,37.52)
PCIE_CTX_DRX_N14: length 84.7
  TOP w0.102: v3(194.81,40.55) 195,40.36 195,39.87 CC186.2
  IN2 w0.127: v3(194.81,40.55) 194.98,40.71 194.98,41.22 194.56,41.64 188.36,41.64 187.52,40.8 185.18,40.8 183.68,39.3 180.96,39.3 178.4,36.74 176.46,36.74 175.44,37.75 170.34,37.75 167.23,40.86 165.89,40.86 165.89,40.86 164.08,40.86 163.57,41.37 163.07,41.37 162.35,42.09 162.35,42.71 162.07,43 160.92,43 160.24,42.31 159.03,42.31 158.37,42.97 155.51,42.97 154.26,44.22 152.62,44.22 151.87,44.97 150.81,44.97 148.83,46.95 147.1,46.95 146.65,47.39 146.65,48.34 143.99,51 143.55,51 138.82,55.72 134.63,55.72 133.02,54.11 131.97,54.11 131.97,54.11 131.96,54.11 131.95,54.11 130.63,54.11 130.43,53.91 129.65,53.91 129.01,54.55 127.66,54.55 127.31,54.89 127.31,54.89 127.24,54.96 127.24,55.2 v3(127.04,55.39)
  BOTTOM w0.076: v3(127.04,55.39) 126.95,55.48 125.91,55.48 125.75,55.63 125.75,55.63 125.54,55.84 UC1.BL2
PCIE_CTX_DRX_N15: length 85.8
  TOP w0.102: CC288.2 197.14,39.86 197.14,40.34 v3(197.34,40.55)
  IN2 w0.127: v3(130.02,56.43) 130.22,56.22 130.42,56.22 130.8,55.84 132.43,55.84 134.05,57.46 139.42,57.46 143.21,53.66 144.41,53.66 150.58,47.49 151.5,47.49 151.67,47.33 152.35,47.33 153.04,46.64 156.19,46.64 157.18,45.65 163.77,45.65 164.52,44.9 164.52,44.19 165.51,43.2 167.37,43.2 169.09,41.47 171.57,41.47 171.78,41.27 172.04,41.27 173.05,40.27 183.32,40.27 184.79,41.74 187.13,41.74 188.05,42.65 196.51,42.65 197.34,41.83 v3(197.34,40.55)
  BOTTOM w0.076: UC1.BL4 124.12,55.84 124.2,55.93 124.2,56.06 124.42,56.27 124.78,56.27 124.9,56.22 125.05,56.22 125.11,56.24 125.2,56.28 125.23,56.27 125.45,56.27 125.54,56.24 125.73,56.24 125.75,56.24 125.8,56.26 126.3,56.26 126.38,56.18 127.03,56.18 127.28,56.43 v3(130.02,56.43)
PCIE_CTX_DRX_N16: length 87.8
  TOP w0.102: CC290.2 198.83,39.89 198.83,40.33 v3(198.61,40.55)
  IN2 w0.127: v3(198.61,40.55) 198.99,40.93 198.99,41.69 197.47,43.21 188,43.21 186.95,42.17 184.61,42.17 183.16,40.72 176.76,40.72 175.7,41.78 171.9,41.78 171.75,41.93 169.25,41.93 167.55,43.63 166.96,43.63 164.47,46.12 157.32,46.12 156.37,47.07 153.29,47.07 152.61,47.76 151.85,47.76 151.68,47.92 150.76,47.92 144.54,54.15 143.42,54.15 139.63,57.93 133.91,57.93 132.31,56.33 130.74,56.33 130.17,56.9 129.54,56.9 129.12,57.31 128.46,57.31 v3(128.09,56.95)
  BOTTOM w0.076: UC1.BJ4 124.3,56.85 124.86,56.85 125.1,56.75 125.14,56.73 125.42,56.73 125.44,56.74 125.52,56.75 125.74,56.75 125.82,56.72 125.84,56.72 125.85,56.73 126.15,56.73 126.39,56.97 127.56,56.97 127.74,57.14 127.89,57.14 v3(128.09,56.95)
PCIE_CTX_DRX_P9: length 153.7
  IN2 w0.076: v3(128.63,54.04) 128.63,53.88 128.55,53.8 128.29,53.8 127.85,54.25 127.5,54.25 126.52,55.23 126.52,56.14 125.76,56.89 125.76,59.25 126.05,59.54 127.52,59.54 128.63,60.66 128.63,63.01 129.33,63.71 129.4,63.71 129.41,63.73
  IN2 w0.127: v3(46.16,110.08) 46.16,110.07 45.85,109.76 45.85,109.46 47.41,107.91 66.74,107.91 67.42,108.58 79.68,108.58 81.32,106.94 106.26,106.94 107.12,106.08 115.24,106.08 125.18,96.13 126.42,96.13 133.19,89.37 133.19,84.94 132.13,83.88 132.13,78.06 133.26,76.93 133.26,74.76 131.67,73.17 131.67,65.98 129.41,63.73
  BOTTOM w0.076: UC1.BR1 125.94,53.33 126.05,53.23 126.91,53.23 126.98,53.31 126.98,53.41 127.11,53.53 127.26,53.53 127.34,53.46 127.34,53.31 127.42,53.23 127.59,53.23 127.63,53.19 127.96,53.19 128.25,53.48 128.25,53.66 v3(128.63,54.04)
  BOTTOM w0.102: CC326.2 45.02,112.1 46.16,110.95 v3(46.16,110.08)
PCIE_CTX_DRX_P10: length 159.5
  IN2 w0.127: v3(131.99,59.19) 131.61,59.57 131.61,59.85 131.78,60.03 141.57,60.03 151.16,50.44 152.1,50.44 152.73,49.82 156.54,49.82 158.15,48.2 166.13,48.2 168.87,45.46 172.79,43.84 176.58,43.84 177.02,44.27 185.93,44.27 186.99,45.33 196.61,45.33 201.6,50.32 205.1,50.32 207.37,52.6 211.77,52.6 234.81,29.57 234.81,18.56 237.99,15.37 237.99,11.93 237.78,11.72 237.52,11.72 237.35,11.89 236.84,11.89 236.74,12 236.74,12.18 236.85,12.29 v3(237.12,12.29)
  BOTTOM w0.076: 129.75,53.51 129.74,53.51 129.73,53.52 129.67,53.52 129.57,53.63 129.57,53.65 128.79,54.43 128.39,54.43 128.04,54.08 127.39,54.08 126.84,53.54 126.25,53.54 126.13,53.66 125.85,53.66 125.76,53.63 125.48,53.63 125.39,53.66 125.2,53.66 125.02,53.58 124.98,53.54 124.98,53.35 124.93,53.3 124.75,53.3 UC1.BR3
  BOTTOM w0.102: 129.75,53.51 130.39,53.51 132.06,55.19 132.06,58.52 131.75,58.83 131.75,59.07 131.86,59.19 v3(131.99,59.19) ; v3(237.12,12.29) 236.81,11.98 236.47,11.98 236.39,11.91 236.18,11.91 CC19.1
PCIE_CTX_DRX_P13: length 63.2
  IN2 w0.127: v3(177.82,38.11) 177.67,37.95 176.57,37.95 175.83,38.69 170.82,38.69 167,42.51 165.02,42.51 163.92,43.62 163.15,43.62 162.55,44.22 158.52,44.22 157.77,44.97 156.9,44.97 155.91,45.95 152.76,45.95 152.31,46.4 150.71,46.4 148.2,48.9 147.42,48.9 144.36,51.96 143.91,51.96 139.21,56.66 134.23,56.66 132.72,55.15 130.15,55.15 v3(130.04,55.26)
  BOTTOM w0.076: UC1.BM3 124.97,55.22 125.05,55.13 125.21,55.13 125.29,55.21 125.29,55.51 125.36,55.59 125.51,55.59 125.59,55.51 125.59,55.3 125.75,55.13 126.16,55.13 126.26,55.04 127.83,55.04 128.09,55.3 129.4,55.3 129.61,55.09 129.87,55.09 v3(130.04,55.26)
  BOTTOM w0.102: CC185.2 178.2,37.92 178,37.92 v3(177.82,38.11)
PCIE_CTX_DRX_P14: length 84.8
  TOP w0.102: v3(195.4,40.55) 195.22,40.37 195.22,39.87 CC187.2
  IN2 w0.127: v3(127.63,55.39) 127.46,55.23 127.46,55.05 127.74,54.76 129.1,54.76 129.74,54.12 130.34,54.12 130.58,54.36 132.91,54.36 134.52,55.98 138.93,55.98 143.65,51.25 144.1,51.25 146.91,48.44 146.91,47.5 147.2,47.2 148.94,47.2 150.92,45.22 151.98,45.22 152.73,44.47 154.37,44.47 155.61,43.23 158.48,43.23 159.14,42.57 160.13,42.57 160.82,43.25 162.17,43.25 162.61,42.82 162.61,42.2 163.18,41.63 163.68,41.63 164.19,41.12 165.99,41.12 166,41.11 167.33,41.11 170.44,38.01 175.55,38.01 176.56,36.99 178.29,36.99 180.86,39.56 183.58,39.56 185.08,41.05 187.42,41.05 188.26,41.89 194.66,41.89 195.23,41.32 195.23,40.71 v3(195.4,40.55)
  BOTTOM w0.076: v3(127.63,55.39) 127.63,55.39 127.27,55.75 126.9,55.75 126.79,55.65 126.09,55.65 125.94,55.79 UC1.BL1
PCIE_CTX_DRX_P15: length 85.9
  TOP w0.102: v3(196.71,40.55) 196.92,40.33 196.92,39.89 CC289.2
  IN2 w0.127: v3(196.71,40.55) 196.58,40.67 196.58,40.9 196.69,41.02 196.97,41.02 197.09,41.13 197.09,41.72 196.41,42.4 188.15,42.4 187.24,41.49 184.9,41.49 183.42,40.01 172.94,40.01 171.94,41.02 171.67,41.02 171.47,41.22 168.99,41.22 167.26,42.95 165.41,42.95 164.27,44.08 164.27,44.8 163.67,45.4 157.07,45.4 156.08,46.39 152.93,46.39 152.24,47.07 151.56,47.07 151.4,47.24 150.48,47.24 144.31,53.41 143.11,53.41 139.31,57.21 134.16,57.21 132.53,55.58 130.75,55.58 130.33,56.01 130.18,56.01 v3(130.02,55.84)
  BOTTOM w0.076: UC1.BL3 124.43,55.84 124.37,55.9 124.37,55.99 124.48,56.11 124.75,56.11 124.86,56.05 125.08,56.05 125.17,56.09 125.2,56.1 125.38,56.1 125.51,56.07 125.76,56.07 125.78,56.08 125.85,56.09 126.23,56.09 126.31,56.01 127.1,56.01 127.34,56.26 129.65,56.26 129.73,56.18 129.73,56.13 v3(130.02,55.84)
PCIE_CTX_DRX_P16: length 87.8
  TOP w0.102: v3(199.25,40.55) 199.04,40.34 199.04,39.86 CC291.2
  IN2 w0.127: v3(128.09,57.53) 129.21,57.53 129.62,57.12 130.31,57.12 130.85,56.58 132.2,56.58 133.8,58.19 139.74,58.19 143.52,54.4 144.64,54.4 150.87,48.18 151.79,48.18 151.95,48.01 152.71,48.01 153.4,47.33 156.47,47.33 157.43,46.38 164.58,46.38 167.07,43.89 167.65,43.89 169.35,42.18 171.86,42.18 172.01,42.03 175.8,42.03 176.86,40.97 183.05,40.97 184.51,42.43 186.85,42.43 187.89,43.47 197.57,43.47 199.25,41.79 v3(199.25,40.55)
  BOTTOM w0.076: v3(128.09,57.53) 127.87,57.31 127.67,57.31 127.49,57.13 126.32,57.13 126.08,56.89 125.84,56.89 125.76,56.92 125.51,56.92 125.48,56.91 125.46,56.91 125.45,56.91 125.4,56.9 125.18,56.9 125.08,56.94 125.03,56.97 124.96,57.04 124.96,57.34 124.81,57.49 124.69,57.49 124.56,57.36 124.56,57.24 UC1.BJ3
PCIE_RCOMPN: length 4.6
  TOP w0.102: v3(122.82,46.73) 122.9,46.73 v1(124.82,44.81) 124.82,43.78 RC120.2
  BOTTOM w0.076: UC1.CE6 v3(122.82,46.73)
PCIE_RCOMPP: length 4.5
  TOP w0.102: RC120.1 125.23,43.89 125.23,44.88 v1(124,46.11) 123.45,46.66 v3(123.45,46.73)
  BOTTOM w0.076: UC1.CE5 v3(123.45,46.73)
PDB: length 9.8
  TOP w0.102: QA2.1 27.63,45.24 R5260.2 27.25,44.47 26.21,44.47 25.86,44.11 25.86,43.8 25.62,43.57 25.17,43.57 25.07,43.67 v1(24.96,43.67) 24.81,43.67 24.56,43.42 24.56,43.18 RA9.2 CA23.1 24.02,41.04 23.18,40.2 22.97,40.2 22.56,39.78 UA1.40
PEG_CRX_C_GTX_N5: length 11.6
  BOTTOM w0.076: 133.83,102.2 133.86,102.17 136.32,102.17 136.58,101.9 136.58,101.48 136.7,101.36 138.03,101.36 138.25,101.15 138.25,100.97 138.33,100.88 UV1.AB9
  BOTTOM w0.102: CV12.2 129.18,104.33 129.78,104.33 129.79,104.34 130.77,104.34 130.78,104.33 131.59,104.33 v4(132.51,103.41) 133.72,102.2 133.83,102.2
PEG_CRX_C_GTX_N6: length 9.8
  BOTTOM w0.076: UV1.AC10 138.07,101.68 138.18,101.78 138.18,101.9 138.06,102.02 136.7,102.02 136.42,102.3 136.42,102.74 136.28,102.88 134.27,102.88 133.88,103.27 133.85,103.27 133.83,103.28
  BOTTOM w0.102: 133.83,103.28 132.74,104.37 132.73,104.37 131.98,105.11 131.98,105.13 131.48,105.63 131.25,105.63 CV14.2
PEG_CRX_C_GTX_N7: length 12
  BOTTOM w0.076: 135.06,104.69 135.08,104.69 135.1,104.67 137.14,104.67 137.38,104.42 137.38,103.05 137.53,102.91 137.53,102.69 UV1.AC11
  BOTTOM w0.102: CV16.2 129.18,107.37 129.56,107.37 129.74,107.19 v4(130.46,107.19) 131.3,107.19 131.82,106.67 131.84,106.67 132.48,106.03 132.48,106.02 132.66,105.84 133.56,105.84 133.98,105.41 133.98,105.38 134.67,104.69 135.06,104.69
PEG_CRX_C_GTX_N8: length 12.2
  BOTTOM w0.076: 134.04,106.61 134.05,106.59 134.05,106.52 134.26,106.32 138,106.32 138.2,106.12 138.2,104.02 138.39,103.83 138.39,103.51 UV1.AB12
  BOTTOM w0.102: 134.04,106.61 133.79,106.86 132.92,106.86 132.77,107 132.77,108.36 132.48,108.65 v4(132.1,108.65) 131.28,108.65 CV18.2
PEG_CRX_C_GTX_P5: length 11.6
  BOTTOM w0.076: 133.83,101.98 133.86,102 136.25,102 136.42,101.83 136.42,101.41 136.63,101.2 137.96,101.2 138.08,101.08 138.08,100.86 138,100.78 137.8,100.78 UV1.AC9
  BOTTOM w0.102: 133.83,101.98 133.64,101.98 132.69,102.93 132.67,102.93 132.03,103.57 132.03,103.59 131.51,104.11 v4(130.31,104.11) 129.17,104.11 CV11.2
PEG_CRX_C_GTX_P6: length 9.8
  BOTTOM w0.076: 133.98,103.43 133.98,103.4 134.34,103.04 136.34,103.04 136.58,102.8 136.58,102.37 136.76,102.19 138.13,102.19 138.54,101.77 UV1.AB10
  BOTTOM w0.102: 133.98,103.43 v4(132.51,104.91) 131.57,105.85 131.26,105.85 CV13.2
PEG_CRX_C_GTX_P7: length 12
  BOTTOM w0.076: UV1.AD11 137.19,102.52 137.36,102.69 137.36,102.84 137.22,102.98 137.22,104.35 137.07,104.5 135.1,104.5 135.08,104.48 135.06,104.48
  BOTTOM w0.102: 135.06,104.48 134.62,104.48 134.53,104.56 133.79,105.3 133.47,105.62 132.57,105.62 v4(132,106.19) 131.21,106.98 130.95,106.98 130.93,106.96 129.97,106.96 129.96,106.98 129.65,106.98 129.47,107.16 129.17,107.16 CV15.2
PEG_CRX_C_GTX_P8: length 12.2
  BOTTOM w0.076: 133.87,106.47 134.04,106.31 134.04,106.31 134.19,106.16 137.93,106.16 138.04,106.05 138.04,103.95 138.2,103.79 138.2,103.5 138.06,103.36 UV1.AC12
  BOTTOM w0.102: 133.87,106.47 133.7,106.64 132.83,106.64 132.55,106.93 v4(132.55,107.4) 132.55,108.28 132.4,108.42 131.22,108.42 CV17.2
PEG_CRX_GTX_N5: length 70.2
  IN2 w0.127: v3(120.96,50.52) 120.96,50.61 120.8,50.78 119.99,50.78 119.66,51.11 119.66,51.42 118.9,52.18 118.9,53.13 118.29,53.74 118.08,53.74 117.5,54.33 117.5,56.39 118.54,57.43 118.54,57.69 117.84,58.39 117.84,59.42 118.26,59.84 118.26,60.11 118.64,60.49 118.64,61.65 119.5,62.52 119.91,62.52 120.56,63.17 120.56,64.46 121.87,65.77 123.65,65.77 123.86,65.97 123.86,67.68 124.9,68.72 124.9,74.18 125.08,74.36 125.08,84.86 123.43,86.51 122.81,86.51 121.19,88.13 121.19,88.84 119.12,90.91 119.12,91.2 119.62,91.71 v3(119.62,91.99)
  BOTTOM w0.076: v3(120.96,50.52) 120.65,50.84 UC1.BW9
  BOTTOM w0.102: v3(119.62,91.99) 119.76,91.99 120.15,92.37 120.48,92.37 120.76,92.09 121.16,92.09 124.54,95.47 124.54,102.92 125.94,104.31 127.57,104.31 CV12.1
PEG_CRX_GTX_N6: length 73.3
  IN2 w0.127: v3(122.3,52.22) 122.41,52.22 122.54,52.08 122.54,51.83 122.4,51.68 122.03,51.68 121.9,51.81 121.9,52 121.78,52.13 120.71,52.13 120.58,52.25 120.35,52.25 119.8,52.8 119.8,54.53 118.77,55.57 118.77,56.38 119.45,57.07 120.04,57.07 120.29,57.32 120.29,60.89 120.33,60.92 120.33,60.98 120.93,61.58 120.93,61.83 121.37,62.27 124.48,62.27 125.5,63.29 125.5,66.92 126.7,68.13 126.7,68.9 126.13,69.48 126.13,71.55 126.6,72.01 126.6,75.62 127.08,76.11 127.08,76.52 127.05,76.56 127.05,85.43 126.86,85.62 126.35,85.62 123.57,88.4 123.57,90.48 121.26,92.78 121.04,92.78 120.94,92.68 120.94,92.55 v3(120.99,92.5)
  BOTTOM w0.076: UC1.BU6 122.3,52.11 v3(122.3,52.22)
  BOTTOM w0.102: CV14.1 129.62,105.68 126.65,105.68 123.87,102.91 123.87,95.67 120.99,92.79 v3(120.99,92.5)
PEG_CRX_GTX_N7: length 70.6
  IN2 w0.127: v3(119.88,94.02) 120.17,94.02 120.57,94.42 120.96,94.42 124.82,90.55 124.82,88.64 125.69,87.78 126.09,87.78 127.99,85.88 127.99,76.56 127.95,76.52 127.95,75.72 127.4,75.18 127.4,71.38 127.02,71 127.02,69.96 127.55,69.43 127.55,67.97 126.82,67.23 126.82,63.41 124.75,61.34 124.11,61.34 123.8,61.03 123.8,60.98 123.75,60.93 121.49,60.93 121.13,60.57 121.13,56.59 120.72,56.18 120.72,53.77 121.1,53.39 121.1,52.94 121.25,52.79 121.64,52.79 121.79,52.94 121.79,52.96 v3(121.56,53.19)
  BOTTOM w0.076: UC1.BT7 121.56,53.12 v3(121.56,53.19)
  BOTTOM w0.102: v3(119.88,94.02) 119.95,94.02 122.78,96.84 122.78,103.52 126.66,107.4 127.61,107.4 CV16.1
PEG_CRX_GTX_N8: length 74.7
  IN2 w0.127: v3(120.35,51.43) 120.5,51.58 120.5,51.73 120.4,51.82 120.02,51.82 119.37,52.47 119.37,53.49 118.64,54.22 118.64,54.62 118.13,55.13 118.13,56.36 119.01,57.24 119.01,58.5 118.96,58.55 118.96,59.71 119.66,60.41 119.66,61.16 120.16,61.67 120.16,61.93 121.15,62.92 124.32,62.92 124.89,63.49 124.89,67.39 125.57,68.06 125.57,73.78 125.76,73.97 125.76,76.61 125.87,76.72 125.87,85.03 123.25,87.65 122.92,87.65 122.41,88.16 122.41,90.09 119.39,93.11 118.89,93.11 118.53,93.48 118.53,93.87 118.88,94.23 v3(118.88,94.35)
  BOTTOM w0.076: UC1.BU9 120.65,51.72 v3(120.35,51.43)
  BOTTOM w0.102: CV18.1 129.7,108.71 126.69,108.71 121.94,103.96 121.94,97.15 119.14,94.35 v3(118.88,94.35)
PEG_CRX_GTX_P5: length 70.1
  IN2 w0.127: v3(120.04,91.57) 119.85,91.57 119.38,91.1 119.38,91.02 121.45,88.95 121.45,88.23 122.92,86.76 123.53,86.76 125.33,84.96 125.33,74.25 125.15,74.07 125.15,68.61 124.11,67.57 124.11,65.87 123.79,65.55 122.02,65.55 120.81,64.35 120.81,63.06 120.01,62.26 119.61,62.26 118.89,61.55 118.89,60.38 118.51,60 118.51,59.73 118.09,59.31 118.09,58.49 118.79,57.79 118.79,57.33 117.75,56.29 117.75,54.43 118.19,54 118.4,54 119.15,53.24 119.15,52.29 119.91,51.53 119.91,51.22 120.08,51.05 120.99,51.05 121.51,50.53 121.62,50.53 v3(121.63,50.53)
  BOTTOM w0.076: v3(121.63,50.53) 121.63,50.54 121.3,50.86 UC1.BW8
  BOTTOM w0.102: v3(120.04,91.57) 120.04,91.96 120.24,92.16 120.39,92.16 120.67,91.87 121.25,91.87 124.76,95.38 124.76,102.83 126.03,104.1 127.61,104.1 CV11.1
PEG_CRX_GTX_P6: length 73.4
  IN2 w0.127: v3(120.58,92.91) 120.81,92.91 120.94,93.04 121.37,93.04 123.82,90.59 123.82,88.5 126.45,85.87 126.96,85.87 127.3,85.53 127.3,76.02 126.82,75.53 126.82,71.92 126.35,71.46 126.35,69.56 126.92,68.99 126.92,68.04 125.71,66.83 125.71,63.2 124.57,62.06 121.46,62.06 121.18,61.78 121.18,61.47 120.51,60.8 120.51,57.23 120.12,56.85 119.54,56.85 118.98,56.29 118.98,55.66 120.02,54.62 120.02,52.89 120.44,52.47 120.67,52.47 120.8,52.34 121.87,52.34 122.12,52.6 122.55,52.6 v3(122.93,52.22)
  BOTTOM w0.076: v3(122.93,52.22) 122.93,52.12 UC1.BU5
  BOTTOM w0.102: CV13.1 129.71,105.9 126.56,105.9 123.66,103 123.66,95.76 120.81,92.91 v3(120.58,92.91)
PEG_CRX_GTX_P7: length 70.6
  IN2 w0.127: v3(122.15,53.18) 122.01,53.04 122.01,52.85 121.73,52.57 121.16,52.57 120.89,52.85 120.89,53.3 120.51,53.68 120.51,56.27 120.91,56.68 120.91,60.57 120.88,60.61 120.88,60.67 121.38,61.18 123.65,61.18 124.02,61.55 124.66,61.55 126.6,63.5 126.6,67.32 127.34,68.05 127.34,69.34 126.81,69.87 126.81,71 126.77,71.03 126.77,71.1 127.19,71.52 127.19,75.27 127.73,75.81 127.73,85.78 125.99,87.52 125.59,87.52 124.57,88.54 124.57,90.45 120.85,94.16 120.67,94.16 120.29,93.78 v3(120.29,93.61)
  BOTTOM w0.076: UC1.BT6 v3(122.15,53.18)
  BOTTOM w0.102: CV15.1 127.57,107.18 126.75,107.18 123,103.43 123,96.75 120.29,94.05 v3(120.29,93.61)
PEG_CRX_GTX_P8: length 74.6
  IN2 w0.127: v3(119.3,93.94) 118.95,93.94 118.78,93.76 118.78,93.58 119,93.37 119.5,93.37 122.66,90.2 122.66,88.26 123.02,87.9 123.36,87.9 126.12,85.14 126.12,76.61 125.98,76.47 125.98,73.88 125.78,73.69 125.78,67.97 125.11,67.3 125.11,63.35 124.43,62.66 121.25,62.66 120.42,61.83 120.42,61.57 119.91,61.06 119.91,60.31 119.21,59.61 119.21,58.65 119.22,58.64 119.22,57.15 118.35,56.27 118.35,55.22 118.86,54.71 118.86,54.31 119.59,53.58 119.59,52.56 120.11,52.04 120.49,52.04 120.72,51.82 120.72,51.54 120.82,51.44 v3(120.99,51.44)
  BOTTOM w0.076: UC1.BU8 v3(120.99,51.44)
  BOTTOM w0.102: v3(119.3,93.94) 119.22,94.01 119.22,94.12 122.16,97.06 122.16,103.87 126.78,108.49 129.74,108.49 130.01,108.22 CV17.1
PEG_CTX_C_GRX_N5: length 6
  BOTTOM w0.076: 133.6,98.25 133.62,98.25 133.62,98.25 133.77,98.25 133.97,98.45 133.97,98.6 134.25,98.88 134.42,98.88 134.5,98.96 UV1.AG7
  BOTTOM w0.102: CC276.1 129.8,97.99 130.25,97.99 130.36,97.87 v4(130.84,97.87) 131.87,97.87 131.89,97.89 132.82,97.89 132.83,97.87 133.09,97.87 133.47,98.25 133.6,98.25
PEG_CTX_C_GRX_N6: length 4.5
  BOTTOM w0.076: UV1.AE7 135.47,98.87 135.17,98.87 134.98,99.06 134.98,99.34 134.8,99.52 133.98,99.52 133.94,99.48 133.78,99.48 133.78,99.49 133.77,99.49
  BOTTOM w0.102: CC277.1 132.6,99.42 133.31,99.42 133.38,99.49 133.77,99.49
PEG_CTX_C_GRX_N7: length 7.8
  BOTTOM w0.076: UV1.AF9 135.67,100.88 135.74,100.96 135.74,101.11 135.65,101.2 135.13,101.2 134.98,101.05 134.98,100.64 134.72,100.37 134.3,100.37 134.19,100.48 133.9,100.48 133.89,100.46
  BOTTOM w0.102: CC279.1 129.94,100.56 130.35,100.56 130.59,100.79 130.97,100.79 130.99,100.78 131.89,100.78 131.91,100.79 132.52,100.79 132.85,100.46 133.89,100.46
PEG_CTX_C_GRX_N8: length 3.9
  BOTTOM w0.102: CC282.1 131.71,102.68 132.01,102.68 v4(132.64,102.05) 133.31,101.38 134.2,101.38 UV1.AG10
PEG_CTX_C_GRX_P5: length 6.1
  BOTTOM w0.076: 133.66,98.06 133.68,98.08 133.84,98.08 134.13,98.38 134.13,98.53 134.32,98.72 134.42,98.72 134.5,98.64 UV1.AG6
  BOTTOM w0.102: CC281.1 129.82,97.77 130.16,97.77 130.28,97.64 131.36,97.64 131.38,97.66 v4(132.37,97.66) 133.18,97.66 133.35,97.83 133.35,97.87 133.55,98.06 133.66,98.06
PEG_CTX_C_GRX_P6: length 4.5
  BOTTOM w0.076: 133.86,99.68 134.87,99.68 135.01,99.54 135.69,99.54 135.8,99.44 135.8,99.29 135.66,99.16 135.34,99.16 UV1.AF7
  BOTTOM w0.102: CC278.1 132.6,99.63 133.23,99.63 133.29,99.7 133.84,99.7 133.86,99.68
PEG_CTX_C_GRX_P7: length 7.8
  BOTTOM w0.076: UV1.AE9 135.99,100.88 135.91,100.96 135.91,101.17 135.72,101.36 135.06,101.36 134.82,101.12 134.82,100.7 134.65,100.54 134.37,100.54 134.25,100.65 133.94,100.65 133.91,100.68 133.9,100.68
  BOTTOM w0.102: 133.9,100.68 132.94,100.68 132.61,101.01 v4(131.44,101.01) 130.5,101.01 130.27,100.78 129.94,100.78 CC280.1
PEG_CTX_C_GRX_P8: length 3.9
  BOTTOM w0.102: CC283.1 131.71,102.46 131.92,102.46 132.15,102.24 132.15,102.22 132.8,101.57 132.82,101.57 133.22,101.16 134.22,101.16 UV1.AG9
PEG_CTX_GRX_N5: length 67.7
  IN2 w0.127: v3(134.99,62.44) 134.83,62.27 134.27,62.27 134.15,62.4 134.15,62.73 133.73,63.74 133.73,72.24 138.11,76.62 138.85,76.62 141.52,79.29 141.52,83.25 138.48,86.28 138.48,86.99 128.88,96.59 128.88,97.56 128.41,98.03 127.68,98.03 v3(127.5,98.2)
  BOTTOM w0.076: 131,51.93 130.98,51.92 130.98,51.9 130.92,51.84 129.4,51.84 128.76,51.2 126.34,51.2 126.16,51.38 126.09,51.38 126.09,51.38 125.79,51.38 125.74,51.36 125.5,51.36 125.45,51.38 125.14,51.38 125.05,51.34 124.81,51.22 124.25,51.22 UC1.BW4
  BOTTOM w0.102: 131,51.93 132.72,53.66 134.44,55.38 134.44,61.88 134.67,62.1 134.67,62.11 134.69,62.13 134.99,62.43 v3(134.99,62.44) ; CC276.2 128.23,97.99 127.72,97.99 v3(127.5,98.2)
PEG_CTX_GRX_N6: length 67.5
  IN2 w0.127: v3(130.4,99.26) 130.55,99.41 130.93,99.41 131.29,99.05 131.29,96.7 131.81,96.18 131.81,94.89 133.33,93.37 133.56,93.37 134.64,92.29 134.64,91.67 140.1,86.21 140.1,86.12 141.95,84.27 141.95,79.11 139.03,76.19 138.29,76.19 134.27,72.17 134.27,63.59 134.6,63.27 134.98,63.27 v3(135.1,63.15)
  BOTTOM w0.076: 128.64,51.63 128.63,51.63 128.62,51.65 128.57,51.65 128.56,51.66 127.13,51.66 126.78,52.01 126.31,52.01 126.16,51.85 125.83,51.85 125.73,51.88 125.51,51.88 125.41,51.85 125.16,51.85 125.04,51.9 124.61,51.9 UC1.BU4
  BOTTOM w0.102: v3(135.1,63.15) 134.36,63.15 134.22,63.01 134.22,62.76 134.03,62.57 134.03,55.35 130.7,52.01 129.21,52.01 128.83,51.63 128.64,51.63 ; v3(130.4,99.26) 130.58,99.44 130.99,99.44 CC277.2
PEG_CTX_GRX_N7: length 64.2
  IN2 w0.127: v3(132.63,61.45) 132.44,61.65 132.21,61.65 131.3,62.56 131.3,63.02 131.17,63.15 131.17,64.87 132.1,65.8 132.1,72.99 133.75,74.64 133.75,78.26 132.56,79.46 132.56,82.93 133.19,83.56 133.19,84 133.66,84.47 133.66,89.51 125.98,97.19 125.98,98.94 127,99.97 127.56,99.97 127.8,100.2 127.8,100.42 127.66,100.55 127.46,100.55 v3(127.3,100.39)
  BOTTOM w0.076: UC1.BU2 125.56,52.54 127.03,52.54 127.22,52.34 128.39,52.34 128.69,52.64 130.53,52.64 130.61,52.72 130.61,52.73
  BOTTOM w0.102: v3(132.63,61.45) 132.79,61.61 132.91,61.61 133.12,61.41 133.12,55.24 130.61,52.73 ; CC279.2 128.35,100.56 127.46,100.56 v3(127.3,100.39)
PEG_CTX_GRX_N8: length 71.6
  IN2 w0.127: v3(132.67,62.88) 132.54,63.01 132.27,63.01 131.94,63.34 131.94,64.6 132.79,65.45 132.79,72.63 137.72,77.56 138.46,77.56 140.58,79.68 140.58,82.86 137.21,86.23 137.21,86.93 126.73,97.41 126.73,98.64 127.36,99.27 128.27,99.27 129.14,100.15 129.14,101.61 v3(128.96,101.8)
  BOTTOM w0.076: 126.59,52.71 126.58,52.71 126.57,52.72 125.4,52.72 125.21,52.53 124.62,52.53 UC1.BT4
  BOTTOM w0.094: 126.59,52.71 127.23,52.71 127.42,52.52 127.47,52.52 127.48,52.52 127.5,52.52
  BOTTOM w0.102: v3(132.67,62.88) 132.5,63.05 132.09,63.05 131.99,62.95 131.99,60.78 132.7,60.07 132.7,55.21 130.34,52.85 128.65,52.85 128.32,52.52 127.5,52.52 ; CC282.2 130.12,102.67 129.48,102.67 129.15,102.34 129.15,101.99 v3(128.96,101.8)
PEG_CTX_GRX_P5: length 67.7
  IN2 w0.127: v3(127.5,97.62) 127.66,97.77 128.3,97.77 128.62,97.45 128.62,96.49 138.23,86.88 138.23,86.18 141.26,83.14 141.26,79.4 138.74,76.88 138.01,76.88 133.47,72.34 133.47,63.69 133.89,62.68 133.89,62.3 134.17,62.02 134.83,62.02 v3(134.99,61.86)
  BOTTOM w0.076: UC1.BW3 124.49,50.96 124.42,50.88 124.42,50.74 124.49,50.66 124.77,50.66 124.97,50.86 124.97,51.03 125.12,51.19 125.18,51.21 125.42,51.21 125.47,51.19 125.77,51.19 125.83,51.22 126.02,51.22 126.03,51.21 126.09,51.21 126.27,51.04 128.83,51.04 129.47,51.67 131,51.67 131.13,51.8
  BOTTOM w0.102: CC281.2 128.21,97.77 127.66,97.77 v3(127.5,97.62) ; 131.13,51.8 134.66,55.33 134.66,61.79 134.76,61.89 134.96,61.89 v3(134.99,61.86)
PEG_CTX_GRX_P6: length 67.5
  IN2 w0.127: v3(130.4,99.85) 130.58,99.66 131.03,99.66 131.55,99.15 131.55,96.8 132.06,96.29 132.06,95.7 132.06,94.99 133.43,93.62 133.67,93.62 134.9,92.39 134.9,91.78 140.36,86.32 140.36,86.23 142.2,84.38 142.2,79.01 139.13,75.94 138.4,75.94 134.53,72.07 134.53,63.7 134.7,63.52 134.88,63.52 v3(135.1,63.73)
  BOTTOM w0.076: 128.64,51.82 127.2,51.82 126.85,52.17 126.25,52.17 126.09,52.01 125.85,52.01 125.76,52.05 125.48,52.05 125.39,52.01 125.2,52.01 125.08,52.06 124.71,52.06 124.63,52.15 124.63,52.25 UC1.BU3
  BOTTOM w0.102: v3(135.1,63.73) 135.1,63.77 135,63.88 134.81,63.88 134.71,63.77 134.71,63.47 134.6,63.37 134.27,63.37 134.01,63.1 134.01,62.85 133.82,62.66 133.82,55.4 130.62,52.21 129.13,52.21 128.75,51.82 128.64,51.82 ; CC278.2 131.04,99.66 130.59,99.66 v3(130.4,99.85)
PEG_CTX_GRX_P7: length 64.2
  IN2 w0.127: v3(127.3,100.98) 127.47,100.81 127.77,100.81 128.05,100.53 128.05,100.1 127.67,99.72 127.11,99.72 126.23,98.84 126.23,97.3 133.92,89.61 133.92,84.36 133.45,83.89 133.45,83.46 132.81,82.82 132.81,79.56 134.01,78.37 134.01,74.54 132.36,72.89 132.36,65.69 131.43,64.76 131.43,63.25 131.55,63.13 131.55,62.66 132.32,61.9 132.5,61.9 v3(132.63,62.04)
  BOTTOM w0.076: UC1.BU1 126.04,52.37 126.96,52.37 127.16,52.18 128.46,52.18 128.75,52.47 130.6,52.47 130.71,52.58 130.73,52.58 130.74,52.59
  BOTTOM w0.102: v3(132.63,62.04) 132.84,61.83 133,61.83 133.33,61.5 133.33,55.52 133.31,55.49 133.31,55.16 133.25,55.11 130.74,52.59 ; CC280.2 128.35,100.78 127.5,100.78 v3(127.3,100.98)
PEG_CTX_GRX_P8: length 71.6
  IN2 w0.127: v3(129.8,101.8) 129.72,101.88 129.54,101.88 129.4,101.74 129.4,100.04 128.37,99.02 127.47,99.02 126.98,98.53 126.98,97.52 137.46,87.04 137.46,86.33 140.83,82.96 140.83,79.58 138.56,77.31 137.83,77.31 133.04,72.52 133.04,65.35 132.19,64.5 132.19,63.45 132.37,63.27 132.48,63.27 v3(132.67,63.46)
  BOTTOM w0.076: UC1.BT3 124.77,52.84 124.7,52.91 124.7,53.04 124.77,53.12 125.21,53.12 125.44,52.89 126.52,52.89 126.53,52.9
  BOTTOM w0.094: 126.53,52.9 127.31,52.9 127.49,52.71 127.5,52.71
  BOTTOM w0.102: v3(129.8,101.8) 129.71,101.71 129.46,101.71 129.36,101.81 129.36,102.25 129.57,102.46 130.13,102.46 CC283.2 ; 127.5,52.71 128.24,52.71 128.57,53.04 130.26,53.04 132.51,55.29 132.51,55.49 132.48,55.52 132.48,59.98 131.77,60.69 131.77,63.04 132,63.27 132.48,63.27 v3(132.67,63.46)
PEX_PLL_CLK_OUT: length 1.8
  TOP w0.102: RV4.2 136.1,110.78 v3(135.7,111.18)
  BOTTOM w0.102: v3(135.7,111.18) 135.7,111.2 UV1.AF22
PEX_PLL_CLK_OUT#: length 2.1
  TOP w0.102: v3(136.46,111.18) 136.87,111.18 v1(136.99,111.06) 137.02,111.03 RV4.1
  BOTTOM w0.102: UV1.AE22 136.46,111.24 v3(136.46,111.18)
PEX_PLLVDD_GPU: length 3
  TOP w0.102: RV377.2 136.3,105.28 135.83,104.81 v2(135.2,104.81)
  BOTTOM w0.305: v3(139.74,106.19) 139.38,105.84 UV1.AA15 ; v3(139.89,104.42) 139.89,104.45 UV1.AA14
PEX_TERMP: length 4.4
  TOP w0.102: v3(132.91,112.6) v1(132.91,113.26)
  BOTTOM w0.102: UV1.AF25 135.3,114.1 134.91,113.71 134.02,113.71 v3(132.91,112.6) RV376.1
PG_+2.5V: length 49.7
  TOP w0.102: v3(6.14,49.74) v2(4.94,49.74)
  IN2 w0.254: v3(10.14,80.03) 11.67,78.51 15.03,78.51 16.56,76.98 16.56,53.55 15.44,52.44 9.66,52.44 6.97,49.74 v3(6.14,49.74)
  BOTTOM w0.254: PRM8.1 v3(10.14,80.03) ; v3(6.14,49.74) 5.69,49.28 PR2504.2 4.94,49.03 4.94,48.14 PC2507.1 5.06,47.12 PU2501.5
PHZ1_R: length 76.2
  TOP w0.102: v1(202.73,63.34) 202.42,63.65 v3(202.04,63.65)
  IN2 w0.203: v3(155.43,76.6) 155.72,76.6 156.68,75.64 161.7,75.64 162.57,76.5 187.41,76.5 191.88,72.03 193.53,72.03 194.29,72.79 194.78,72.79 195.31,73.32 195.31,77.9 197.56,80.16 201.89,80.16 203.44,78.61 203.44,77.49 204.33,76.6 204.33,67.84 202.95,66.47 202.95,64.18 202.42,63.65 v3(202.04,63.65)
  BOTTOM w0.254: v3(155.43,76.6) 155.63,76.8 PHZ1.1 ; PRZ26.2 202.09,63.7 v3(202.04,63.65)
PLAT_SEL0: length 11.2
  BOTTOM w0.076: UC1.CM35 104.18,43.71 103.74,44.15 102.98,44.15 102.04,43.21 102.04,42.63 101.52,42.11 101.52,41.5 100.43,40.41 100.43,39.07 100.34,38.98 v1(100.34,38.51) 100.34,38.26 99.87,37.79 99.87,37.01 99.94,36.94 RC916.1 RC940.2
PLT_RST#: length 526.1
  TOP w0.102: v3(204.99,53.89) 207.35,53.89 210.51,50.73 210.51,45.56 v2(210.26,45.31) 209.56,44.61 209.56,40.9 208.28,39.62 205.65,39.62 205,38.97 RT3.2 ; v3(148.51,23.77) 148.51,23.77 148.51,24.87 150.02,26.39 150.25,26.39 150.45,26.18 R28.1 150.91,26.92 151.09,27.1 152,27.1 154.14,29.23 154.82,29.23 155.95,30.35 155.95,30.77 157.83,32.66 158.53,32.66 158.91,33.04 158.91,34.13 158.53,34.51 v3(158.06,34.51) ; v3(183.49,127.8) UV12.1
  IN1 w0.127: v3(27.86,101.37) 27.86,100.97 29.34,99.49 29.34,95.05 v3(30.3,94.09)
  IN2 w0.127: v3(183.49,127.8) 184.01,127.28 184.01,126.89 184.89,126 186.77,126 191.03,121.75 192.4,121.75 194.25,119.9 194.25,114.74 200.77,108.22 200.77,87.26 209.11,78.91 209.11,65.46 207.68,64.03 207.68,62.91 207.12,62.35 207.12,56.03 v3(204.99,53.89) 203.12,53.89 198.11,48.88 192.27,48.88 191.95,48.56 188.17,48.56 185.37,45.76 175.15,45.76 169.72,46.7 166.37,50.06 161.48,50.06 v3(161.36,49.94) ; v3(200.78,25.06) 203.27,25.06 203.98,25.78 207.93,25.78 208.65,25.06 210.44,25.06 211.73,23.78 211.73,23.09 212.7,22.12 220.59,22.12 221.17,21.55 222.52,21.55 224.89,19.18 224.89,12.47 v3(225.03,12.33) ; v3(36.01,23.22) 35.38,23.85 35.38,45.52 27.77,53.13 27.77,67.7 26.69,68.78 26.69,90.76 30.02,94.09 v3(30.3,94.09) ; v3(36.69,108.77) 35.18,108.77 34.64,109.32 27.91,109.32 27.25,108.66 26.23,108.66 24.89,107.31 24.89,104.34 v3(27.86,101.37) ; v3(112.06,28.85) 112.49,29.28 113.66,29.28 113.95,28.99 117.95,28.99 118.27,29.31 121.61,29.31 122.2,29.9 125.39,29.9 127.35,27.95 131.03,27.95 131.35,27.63 134.55,27.63 135.35,26.83 139.56,26.83 141.3,25.09 141.3,24.45 142.82,22.93 147.67,22.93 v3(148.51,23.77) ; v3(87.98,31.66) 86.32,29.99 80.08,29.99 v3(78.27,28.18)
  BOTTOM w0.102: v3(225.03,12.33) 224.49,11.8 224.49,9.35 225.54,8.3 JWLAN.44 ; v3(36.01,23.22) 36.01,22.04 36.69,21.35 76.05,21.35 78.27,23.57 v3(78.27,28.18) ; v3(158.06,34.51) 159.62,36.07 159.62,39.2 159.5,39.32 159.5,39.65 159.56,39.71 159.56,41.15 159.23,41.48 159.23,43.59 159.51,43.87 159.51,46.04 159.37,46.18 UK1.13 159.37,49.2 CK4.1 RK115.2 160.87,49.45 v3(161.36,49.94) ; v3(87.98,31.66) 87.98,30.39 89.77,28.6 90.53,28.6 R5270.2 91.35,28.99 91.51,29.15 UC4.4 92.83,29.15 93.26,28.72 94.85,28.72 95.36,29.23 111.68,29.23 v3(112.06,28.85) ; v3(148.51,23.77) 148.57,23.71 153.68,23.71 153.77,23.79 155.77,23.79 156.12,24.14 158.25,24.14 158.61,23.78 163.58,23.78 163.98,23.38 199.09,23.38 v3(200.78,25.06) ; v3(36.69,108.77) 36.46,108.77 36.06,108.38 36.06,108.28 35.85,108.06 35.85,108.06 UL1.19
PLT_RST#_PCH: length 39.5
  IN2 w0.076: v3(102.97,55.95) 103.46,55.46 103.46,50.87 102.44,49.84 101.81,49.84 101.07,49.1 101.07,48.48 100.97,48.37 100.97,47.71 100.09,46.83 99.79,46.83 98.98,46.02 98.92,45.88 98.92,45.32 97.57,43.97 97.57,41.93 96.68,41.04 95.4,41.04
  IN2 w0.127: 95.4,41.04 95.3,41.04 v3(95.11,41.23)
  BOTTOM w0.076: UC1.BJ35 104.25,56.56 103.34,56.56 102.97,56.2 v3(102.97,55.95)
  BOTTOM w0.102: 94.58,30.45 94.72,30.31 94.72,29.92 94.61,29.8 UC4.2 91.16,29.8 R5270.1 ; 94.58,30.45 UC4.1 ; 94.58,30.45 94.83,30.7 CC300.1 95.36,31.17 94.46,32.07 94.46,38.27 94.98,38.79 94.98,41.1 v3(95.11,41.23)
PLT_RST#_SSD: length 12.5
  TOP w0.102: v3(202.21,39.22) 202.54,39.56 RT3.1 v1(204.36,39.56)
  BOTTOM w0.102: v3(202.21,39.22) 201.82,39.22 200.71,40.34 200.71,40.86 199.98,41.59 195.6,41.59 195.02,42.17 JSSD.50
PLT_RST#_TPM: length 3.9
  TOP w0.102: UT1.17 153.27,25.39 152.89,25.78 152.23,25.78 R28.2 152.17,26.53 152.28,26.53 v1(153.1,27.36)
PLT_RST_VGA#: length 87.5
  TOP w0.102: QG4.2 179.66,124.15 180.3,123.51 RV379.2 RV378.1 181.92,123.08 v3(182.35,123.08) 182.74,122.7 v1(183.14,122.7) 183.76,122.7 184.57,123.51 UV15.4
  IN2 w0.127: v3(137.3,98.72) 137.9,98.11 137.9,97.05 139.07,95.88 140.22,95.88 148.99,87.1 156.29,87.1 158.19,88.99 159.44,88.99 159.91,89.46 159.91,90.67 160.43,91.19 160.43,92.6 161.44,93.62 162.54,93.62 163.2,92.96 167.72,92.96 169.21,94.45 169.21,94.57 170.84,96.2 170.84,98.04 170.01,98.87 170.01,101.84 169.11,102.74 169.11,110.72 170.03,111.64 170.03,114.07 174.39,118.43 177.71,118.43 v3(182.35,123.08)
  BOTTOM w0.102: UV1.AC7 137.7,99.2 137.3,98.8 v3(137.3,98.72)
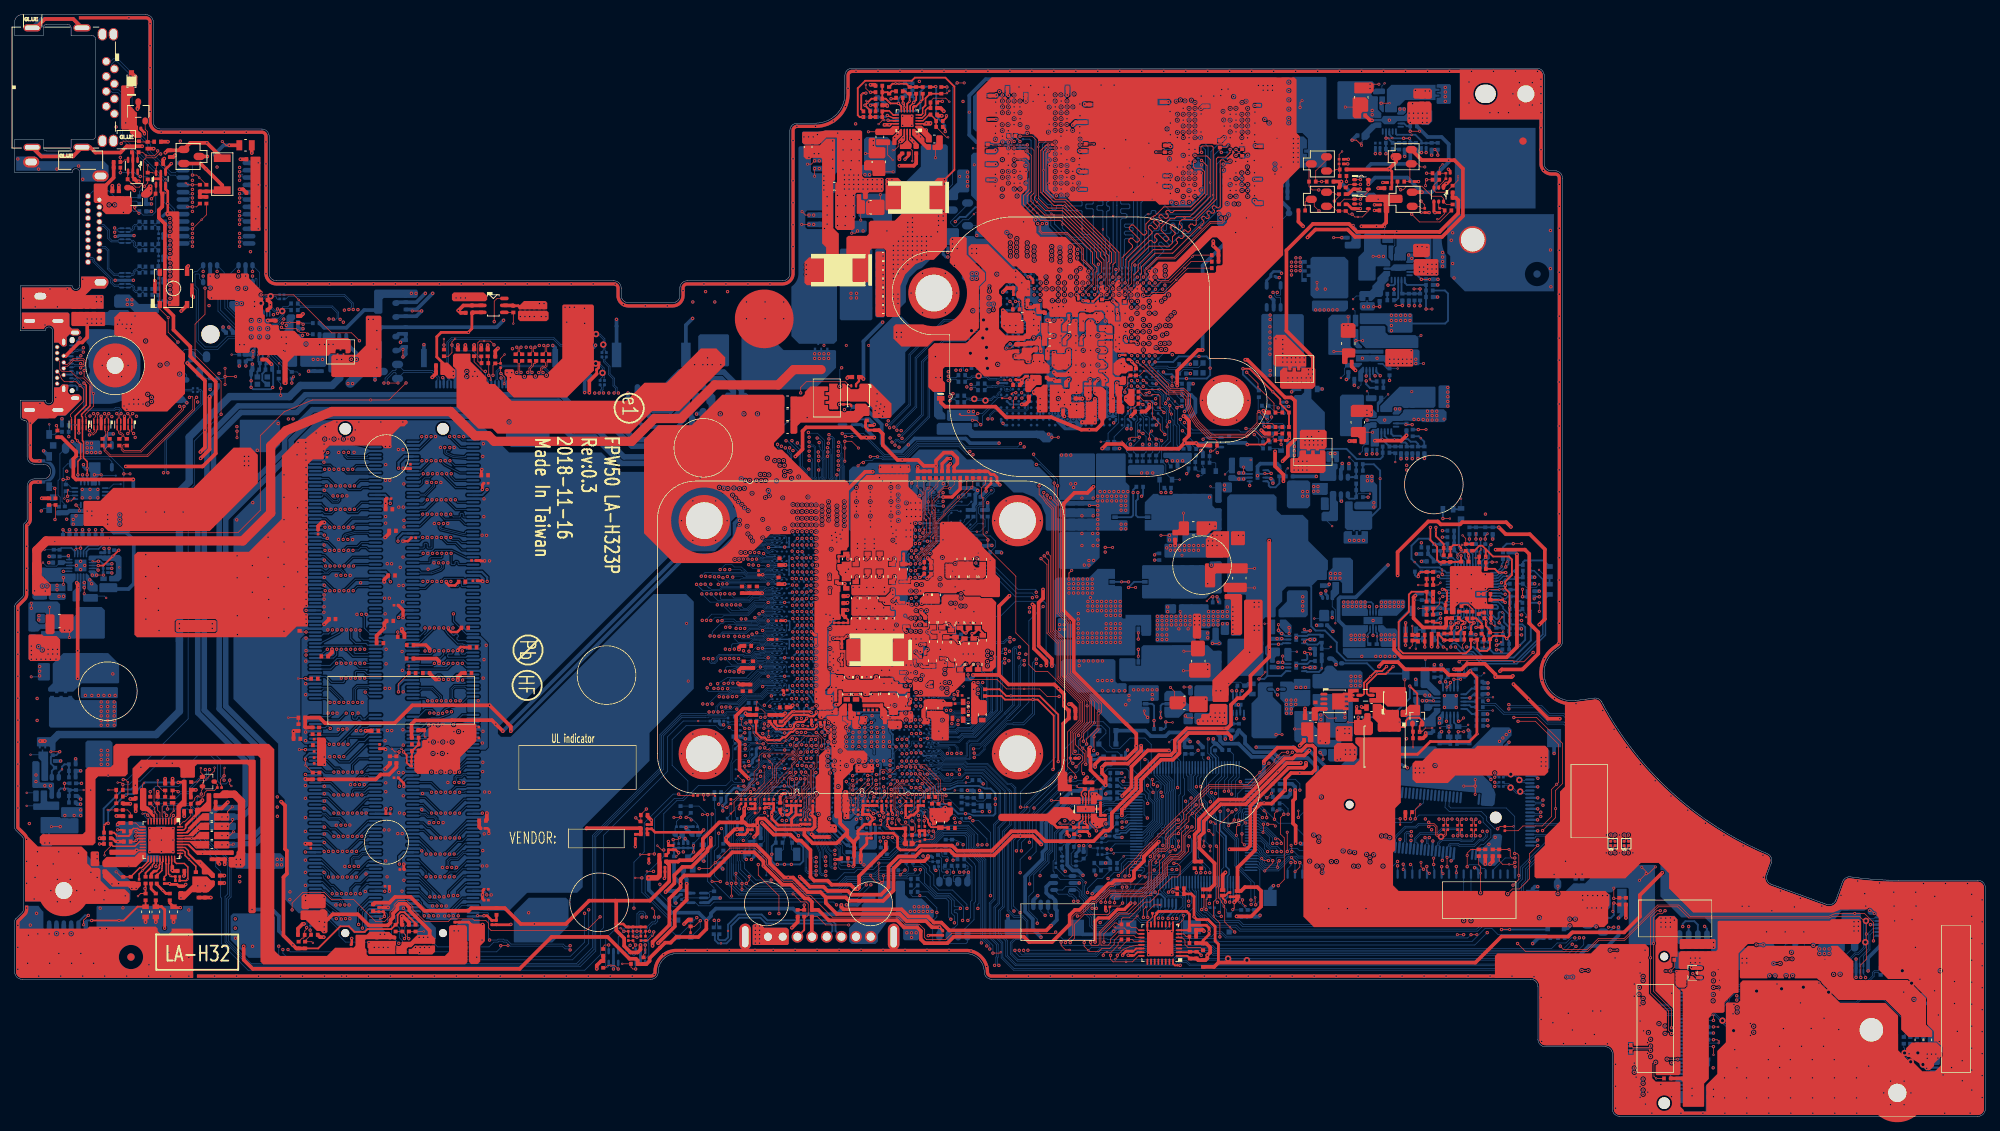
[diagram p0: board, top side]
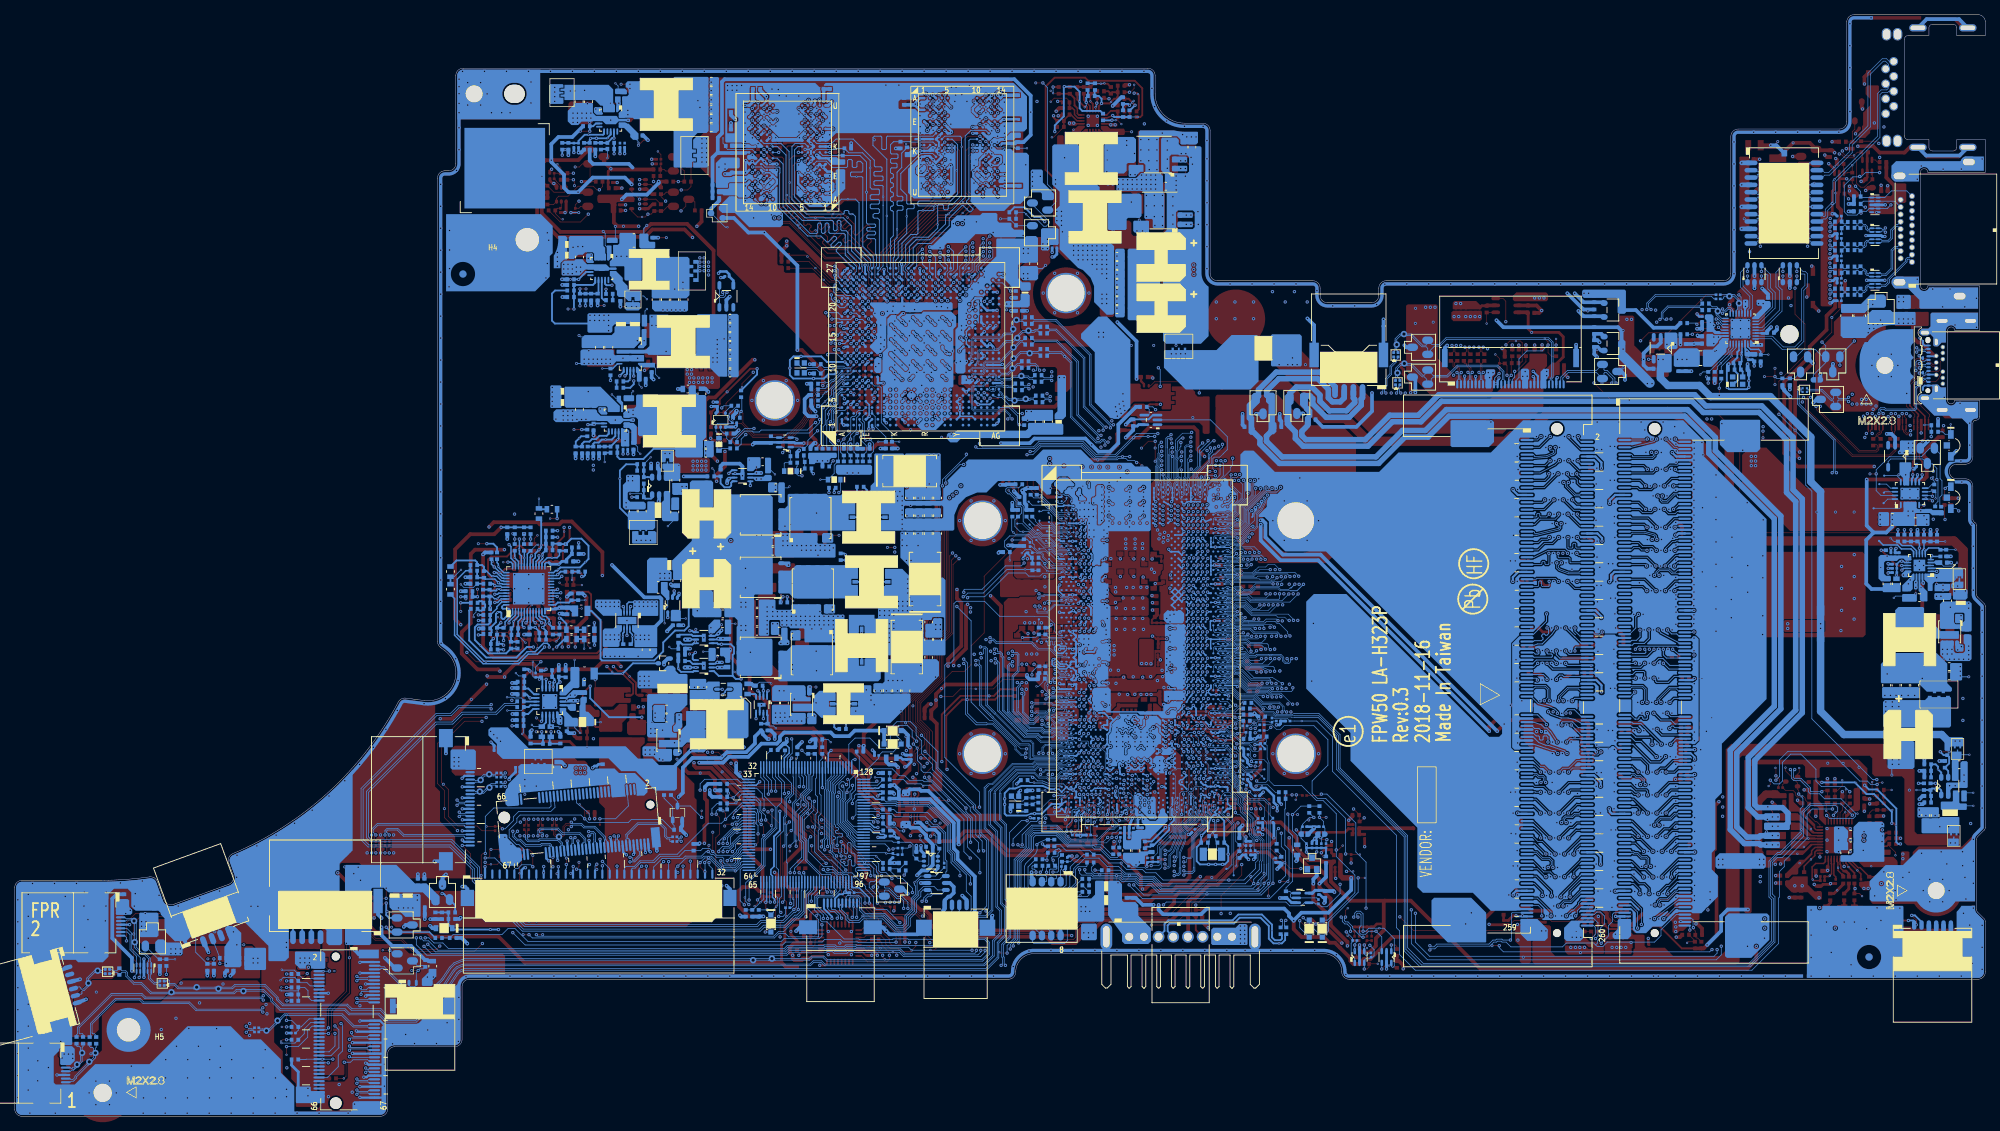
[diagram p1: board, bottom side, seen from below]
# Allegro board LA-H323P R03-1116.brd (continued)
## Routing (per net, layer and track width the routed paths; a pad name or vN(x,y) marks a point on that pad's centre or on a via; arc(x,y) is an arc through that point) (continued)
PLT_RST_VGA_HOLD#: length 61.6
  TOP w0.102: v1(151.81,96.21) 152.23,96.63 152.63,96.63 RV2762.1 153.71,97.22 v3(153.83,97.1) ; UV15.2 v3(183.5,124.48)
  IN2 w0.102: v3(153.83,97.1) 153.83,95.34 155.72,93.45
  IN2 w0.127: 155.72,93.45 156.57,92.6 159.08,92.6 160.99,94.51 162.9,94.51 163.57,93.84 166.65,93.84 168.8,96 168.8,96.45 169.12,96.77 169.12,101.47 168.21,102.38 168.21,111.13 169.12,112.05 169.12,114.42 174.02,119.32 177.31,119.32 182.47,124.48 v3(183.5,124.48)
  BOTTOM w0.102: UV1.C4 154.3,96.74 153.93,97.1 v3(153.83,97.1)
PLT_RST_VGA_MON#: length 76.4
  TOP w0.102: RV379.1 181.28,125.13 UV15.1 v3(183.5,125.13) 184.57,126.21 UV12.4
  IN2 w0.102: v3(153.1,100.38) 153.48,99.99 153.48,99.1 152.71,98.33 152.71,95.92 155.18,93.45
  IN2 w0.127: v3(183.5,125.13) 184.13,124.5 184.13,123.72 183.62,123.21 183.12,123.21 182.74,123.59 182.12,123.59 177.47,118.94 174.18,118.94 169.5,114.27 169.5,111.89 168.59,110.97 168.59,102.54 169.5,101.63 169.5,96.61 169.18,96.29 169.18,95.84 166.81,93.46 163.41,93.46 162.75,94.13 161.15,94.13 159.92,92.9 159.92,91.44 159.13,90.65 157.92,90.65 157.23,89.96 157.23,89.56 v3(157.09,89.43) 156.62,89.43 156.45,89.6 156.45,92.19 155.18,93.45
  BOTTOM w0.102: v3(153.1,100.38) 153.1,100.48 UV1.E9 ; v3(157.09,89.43) 157.36,89.16 157.36,88.95 RV70.1
PLUG_IN#: length 23.5
  TOP w0.127: v2(9.39,26.13) 9.39,26.77 v3(10.04,27.41)
  TOP w0.254: v3(14.04,39.08) 14.69,39.08 RA42.1
  IN2 w0.254: v3(14.04,39.08) 16.27,36.85 16.79,36.85 17.13,36.51 17.13,29.87 14.68,27.41 v3(10.04,27.41)
  BOTTOM w0.254: v3(10.04,27.41) 9.6,27.41 8.7,26.52 JHP.2
PM_BATLOW#: length 12.7
  TOP w0.076: RC103.2 100.31,43.47 100.48,43.63 100.83,43.63 103.36,46.16 103.36,48.03 v1(102.97,48.42) v3(102.22,49.17)
  BOTTOM w0.076: UC1.BV36 103.99,51.58 104.5,51.58 104.63,51.46 104.63,51.07 104.45,50.9 104.08,50.9 103.88,50.85 103.71,50.77 103.57,50.41 103.41,50.31 103.32,50.27 v3(102.22,49.17)
PM_CLKRUN#: length 105.6
  TOP w0.076: v3(107.2,49.7) 107.19,49.7 106.52,49.03 106.52,48.65 105.9,48.03 105.9,47.65 104.12,45.87 104.12,45.65 102.22,43.75 RC107.1
  TOP w0.102: v3(172.28,31.47) 173.11,32.29 173.11,37.99 172.61,38.49 172.61,40.78 v3(173.05,41.22)
  IN1 w0.076: v3(107.2,49.7) 106.83,49.32 106.83,48.66 107.26,48.23 107.58,48.23 107.65,48.16 108.69,48.16 108.95,47.89 108.95,47.64 108.48,47.17 108.48,45.78 107.27,44.57 107.27,43.69 107.04,43.47 107.04,41.55
  IN1 w0.127: v3(172.28,31.47) 171.87,31.88 169.85,31.88 165.74,35.99 165.31,35.99 164.03,37.28 162.82,37.28 162.57,37.03 162.57,36.63 162.17,36.24 160.04,36.24 159.24,35.44 159.03,35.44 158.82,35.44 158.61,35.44 158.61,35.44 157.5,35.44 156.84,34.78 154.57,34.78 154.3,35.04 150,35.04 149.55,35.49 148.31,35.49 147.93,35.11 139.13,35.11 138.58,35.66 138.04,35.66 137.63,35.24 136.34,35.24 135.79,34.69 131.26,34.69 130.94,35.01 128.84,35.01 128.23,35.62 125.38,35.62 124.81,36.19 123.26,36.19 122.7,35.63 121.57,35.63 121.5,35.71 116.97,35.71 116.53,36.15 114.37,36.15 112.54,37.99 111.13,37.99 110.21,38.91 109.91,38.91 109.16,39.66 107.73,39.66 107.04,40.34 107.04,41.55
  BOTTOM w0.076: UC1.BY30 107.61,49.94 107.43,49.76 107.26,49.76 v3(107.2,49.7)
  BOTTOM w0.102: v3(173.05,41.22) 173.05,41.65 172.82,41.88 RK10.1
PM_CLKRUN#_R: length 4.5
  BOTTOM w0.102: UK1.38 169.54,43.97 169.91,43.61 169.91,43.23 v2(170.36,42.77) 170.44,42.69 RK6.2 RK10.2
PM_SLP_A#: length 1.3
  TOP w0.076: v3(102.82,51.79) 102.82,52.22 102.8,52.24 T258.1
  BOTTOM w0.076: v3(102.82,51.79) 102.92,51.89 UC1.BU37
PM_SLP_S0#: length 19.6
  TOP w0.102: T254.1 95.35,43.86 v3(94.53,43.86)
  IN1 w0.076: v3(102.22,56.08) 99.72,56.08 98.95,55.31 98.95,54.73 98.12,53.89 98.12,51.75 98.21,51.65 98.21,48.51 98.12,48.41 98.12,47.15 97.86,46.9
  IN1 w0.127: v3(94.53,43.86) 94.82,43.86 97.86,46.9
  BOTTOM w0.076: UC1.BJ37 103.06,56.92 v3(102.22,56.08)
PM_SLP_S3#: length 88.9
  TOP w0.076: v1(101.18,50.98) 101.34,50.82 v3(102.05,50.82)
  IN1 w0.076: v3(102.05,50.82) 102.45,50.82 103.49,49.78 103.49,45.09
  IN1 w0.127: v3(155.37,33.6) 155.14,33.6 154.97,33.76 154.15,33.76 153.88,34.03 149.96,34.03 149.83,33.89 148.11,33.89 147.91,34.09 139.28,34.09 139.24,34.06 137.59,34.06 137.47,34.18 136.72,34.18 136.22,33.68 130.83,33.68 130.52,33.99 126.58,33.99 125.99,34.58 121.35,34.58 121.09,34.84 116.61,34.84 116.56,34.89 116.17,35.29 113.8,35.29 112.12,36.97 110.71,36.97 109.79,37.89 106.54,37.89 105.9,38.53 105.9,42.67 103.49,45.09
  BOTTOM w0.076: UC1.BU36 103.81,51.89 103.35,51.43 102.67,51.43 v3(102.05,50.82) 101.68,50.82 101.54,50.67 100.38,50.67 100.14,50.43 100.14,50.05 99.87,49.78 99.17,49.78 RC979.1
  BOTTOM w0.102: UK1.6 156.57,46.52 157.47,45.62 157.47,44.4 157.58,44.29 157.58,37.11 157.45,36.98 157.45,35.99 157.11,35.64 157.11,35.42 156.81,35.12 156.8,35.12 155.37,33.69 v3(155.37,33.6)
PM_SLP_S4#: length 235.4
  TOP w0.076: v3(100.82,44.63) 100.6,44.85 100.34,44.85 99.04,43.56 RC983.1
  TOP w0.102: v3(101.39,34.35) 101.39,32.91 104.21,30.1 v3(104.21,27.66) ; v3(143.28,23.71) 143.29,23.71 144.28,24.7 144.28,27.27 144.74,27.73 145.37,27.73 146.97,29.33 147.35,29.33 149.36,31.34 149.77,31.34 150.11,31.68 154.05,31.68 154.67,32.3 154.67,34.69 155.25,35.28 155.25,35.67 155.81,36.22 155.93,36.34 156.82,36.34 157.19,36.71 157.19,37.98 v2(158.63,39.42) 159.74,40.52 159.74,41.14 v3(161.1,42.5)
  IN1 w0.127: v3(100.82,44.63) 102,43.45 102.34,43.45 103.68,42.12 103.68,38.88 101.39,36.6 v3(101.39,34.35) ; v3(143.28,23.71) 143.31,23.74 143.31,24.31 143.18,24.44 141.37,24.44 140.33,25.48 127.36,25.48 126.25,26.6 121.77,26.6 120.57,27.81 118.9,27.81 118.09,26.99 114.23,26.99 114.12,26.88 106.85,26.88 106.07,27.66 v3(104.21,27.66) 103.48,28.39 98.49,28.39 96.31,26.21 92.83,26.21 91.63,27.41 88.67,27.41 88.35,27.73 85.47,27.73 84.98,27.25 82.83,27.25 79.55,23.96 75.46,23.96 73.84,22.34 41.16,22.34 38.36,25.15 37.58,25.15 33.45,29.28 33.45,38.4 31.62,40.23 31.62,43.11 29.37,45.36 24.2,45.36 23.88,45.04 18.97,45.04 17.34,46.67 10.35,46.67 v3(9.11,45.44) ; v3(161.1,42.5) 160.93,42.34 160.41,42.34 160.23,42.51 154.65,42.51 v3(154.47,42.69)
  IN2 w0.076: v3(100.82,44.63) 100.8,44.66 100.8,46.24 101.3,46.75 102.86,46.75 103.6,47.49 103.6,47.64 105.48,49.52 105.48,49.77 105.77,50.06 107.7,50.06 107.9,50.25 108.25,50.25 108.33,50.33 108.33,50.71 108.59,50.97 108.86,50.97 109.21,51.32 v3(109.21,51.43)
  BOTTOM w0.076: UC1.BU27 109.56,51.78 v3(109.21,51.43)
  BOTTOM w0.102: UK1.123 153.97,43.97 154.19,43.76 154.19,43.4 154.47,43.12 v3(154.47,42.69)
  BOTTOM w0.254: PR2501.1 v3(9.11,45.44)
PM_SLP_S5#: length 121.5
  TOP w0.076: v3(107.46,53.33) 108.1,53.33 T257.1
  IN1 w0.076: 98.58,46.18 98.97,46.56 98.97,48.06 99.06,48.15 99.06,52.06 98.97,52.15 98.97,53.54 99.49,54.06 106.16,54.06 106.47,53.75 107.15,53.75 107.46,53.44 107.46,53.33 v3(107.46,53.33)
  IN1 w0.127: 98.58,46.18 98.43,46.03 98.43,45.6 97.52,44.68 97.52,35.88 99.4,34 100.35,34 100.93,33.43 101.9,33.43 102.47,34 102.47,36.45 103.15,37.13 109.47,37.13 111.03,35.57 111.03,33.5 111.76,32.77 113.79,32.77 113.97,32.95 115.44,32.95 115.52,33.03 117.02,33.03 117.64,33.64 120.26,33.64 121.08,32.83 126.31,32.83 126.76,32.38 130.78,32.38 131.06,32.66 136.07,32.66 136.16,32.57 137.48,32.57 137.89,32.98 138.64,32.98 139.56,32.06 144.27,32.06 144.5,32.3 145.57,32.3 146.01,31.86 147.57,31.86 148.08,31.35 148.41,31.35 148.85,30.91 150.83,30.91 151.21,30.53 153.98,30.53 154.5,30.01 158.54,30.01 160.6,32.07 161.83,32.07 162.37,32.62 v3(162.37,33.24)
  BOTTOM w0.076: UC1.BT29 107.82,53.32 107.46,53.32 107.46,53.33 v3(107.46,53.33)
  BOTTOM w0.102: UK1.14 159.76,46.57 159.99,46.34 159.99,44.52 160.9,43.6 160.9,43.21 160.46,42.76 160.46,42.03 161.52,40.97 161.52,37.75 161.16,37.39 161.16,35.06 162.37,33.84 v3(162.37,33.24)
PM_SLP_SUS#: length 98.2
  TOP w0.102: v3(162.14,36.85) v1(162.14,37.6)
  IN1 w0.076: v3(107.94,50.61) 107.65,50.32 107.65,50.21 107.72,50.14 107.72,49.44 107.63,49.35 107.63,48.65 107.79,48.49 108.82,48.49 109.11,48.19 109.11,47.34 108.71,46.93 108.71,45.75 107.44,44.48 107.44,43.5 107.3,43.37 107.3,41.3
  IN1 w0.127: v3(162.14,36.85) 161.78,36.49 159.93,36.49 159.13,35.69 158.71,35.69 158.5,35.69 157.4,35.69 156.74,35.03 154.67,35.03 154.41,35.3 150.1,35.3 149.66,35.75 148.2,35.75 147.82,35.36 139.23,35.36 138.69,35.91 137.94,35.91 137.52,35.49 136.23,35.49 135.69,34.95 131.36,34.95 131.04,35.26 128.95,35.26 128.34,35.87 125.49,35.87 124.92,36.44 122.92,36.44 122.44,35.96 117.02,35.96 116.62,36.37 114.52,36.37 112.64,38.24 111.23,38.24 110.31,39.16 110.01,39.16 109.27,39.91 107.84,39.91 107.3,40.45 107.3,41.3
  IN2 w0.076: v3(107.94,50.61) 107.94,50.53 107.63,50.22 105.7,50.22 105.32,49.84 105.32,49.59 103.88,48.15 101.91,48.15 101.46,47.71 101.46,47.51 100.48,46.52 100.48,44.74 100.33,44.59 100.33,44.29 v3(100.33,44.29)
  BOTTOM w0.076: RC984.1 99.77,43.73 v3(100.33,44.29) ; v3(107.94,50.61) 107.94,51.51 108.26,51.83 UC1.BU29
  BOTTOM w0.102: v3(162.14,36.85) 162.19,36.9 162.19,41.52 161.5,42.21 161.5,43 161.36,43.14 161.36,43.79 160.5,44.65 160.5,46.67 160.57,46.73 UK1.16
PRIMCORE_VID0: length 6.5
  BOTTOM w0.076: UC1.CB36 103.57,48.65 103.17,48.65 103.03,48.65 102.8,48.42 102.16,48.42 101.6,47.86 101.6,47.76 100.94,47.1 99.37,47.1 T62.1
PRIMCORE_VID1: length 6.8
  BOTTOM w0.076: T63.1 98.38,47.27 100.77,47.27 102.09,48.59 102.73,48.59 102.96,48.82 103.01,48.82 103.34,48.82 103.45,48.93 103.62,49 103.97,49 104.26,48.72 UC1.CB35
PROCHOT#: length 74.2
  TOP w0.102: v3(144.64,46.26) 144.61,46.29 144.61,46.67 143.56,47.72 143.56,52.45 145.14,54.04 145.14,56.41 140.86,60.69 139.22,60.69 138.29,61.63 138.29,64.18 136.51,65.96 136.51,73.68 132.7,77.49 v3(132.7,78.63) 132.7,78.8 132.04,79.46 v1(132.04,84.31) 131.85,84.5 131.85,85.77 132.36,86.28 RC3.2
  IN1 w0.127: v3(146.63,36.88) 146.16,37.35 144.96,37.35 144.24,36.63 139.76,36.63 139.17,37.23 138.63,37.23 138.46,37.4 v3(138.36,37.4)
  BOTTOM w0.102: v3(144.64,46.26) 144.26,45.88 143.63,45.88 138.36,40.61 v3(138.36,37.4) ; RC4.1 130.68,78.73 CC292.2 131.19,78.63 v3(132.7,78.63) ; RK9.2 RK8.2 146.91,36.6 v3(146.63,36.88)
PROJECT_ID: length 10.6
  TOP w0.076: v3(102.26,41.45) v1(102.73,40.98)
  BOTTOM w0.076: UC1.CL36 102.88,43.8 102.26,43.17 v3(102.26,41.45) 101.96,41.16 101.63,41.16 100.71,40.23 100.71,39.03 101.2,38.54 101.2,37.09 101.05,36.94 RC127.2 RC128.1
PSI: length 77.2
  TOP w0.102: v3(156.71,96.02) 156.17,96.56 v1(156.17,96.68) 156.17,98.24 155.91,98.5 155.15,98.5 154.95,98.29 154,98.29 153.41,98.88 RV2764.1
  TOP w0.254: PRV1.1 125.94,138.48 v3(126.49,138.48)
  IN2 w0.127: v3(126.49,138.48) 127.72,138.48 128.79,137.41 128.79,125.22 130.16,123.85 130.16,119.12 129.85,118.81 129.85,117.46 130.24,117.07 131.51,117.07 132.82,115.76 132.82,113.66 132.08,112.92 132.08,109.73 133.07,108.73 136.29,108.73 138.39,106.63 140.06,106.63 140.67,106.02 145.25,106.02 146.1,105.16 146.1,103.96 147.31,102.75 147.31,102.34 148.54,101.11 148.95,101.11 149.3,100.76 149.3,99.8 149.83,99.27 151.93,99.27 152.05,99.14 152.51,99.14 152.69,99.33 152.69,100.66 152.84,100.81 154.04,100.81 154.37,100.48 156.48,98.37 156.48,96.25 v3(156.71,96.02)
  BOTTOM w0.102: UV1.B4 155.51,96.29 156.57,96.29 156.71,96.15 v3(156.71,96.02)
PWM_CORE1: length 24
  TOP w0.102: v3(176.64,66.25) 176.02,66.25 v2(175.83,66.44)
  IN1 w0.254: v3(176.64,66.25) 177.66,66.25 178.32,66.91 178.32,68.5 180.7,70.89 182.84,70.89 183.64,71.69 193.99,71.69 v3(194.24,71.43)
  BOTTOM w0.203: PUZ1.17 194.29,71.38 v3(194.24,71.43)
  BOTTOM w0.254: v3(176.64,66.25) 176.32,66.25 176.12,66.05 PUZ2.5
PWM_CORE2: length 25.3
  TOP w0.102: v3(175.89,63.29) 176.47,63.29 v2(176.69,63.08)
  IN1 w0.254: v3(175.89,63.29) 177.61,63.29 181.36,67.04 187.78,67.04 190.74,70 191.63,70 192.01,70.38 193.58,70.38 194.13,70.93 v3(194.72,70.93)
  BOTTOM w0.203: v3(194.72,70.93) 194.78,70.98 PUZ1.16
  BOTTOM w0.254: v3(175.89,63.29) 176.25,62.94 176.25,62.39 176.09,62.24 PUZ3.5
PWM_GT: length 41.4
  TOP w0.102: v3(171.32,87.72) v2(170.47,87.72)
  IN1 w0.254: v3(194.1,73.68) 193.14,74.65 172.97,74.65 169.48,78.14 169.48,79.62 172.34,82.48 172.34,87.2 171.83,87.72 v3(171.32,87.72)
  BOTTOM w0.203: PUZ1.22 194.4,73.38 v3(194.1,73.68)
  BOTTOM w0.254: PUG1.5 170.9,88.15 v3(171.32,87.72)
PWM_SA: length 50.8
  TOP w0.102: v1(202.08,75.61) v3(201.44,75.61)
  IN1 w0.254: v3(201.44,75.61) 202.08,74.98 202.08,71.2 201.63,70.76 195.44,70.76 194.93,70.25 194.17,70.25 193.78,69.87 192.26,69.87 191.88,69.49 190.77,69.49 187.63,66.35 181.21,66.35 177.67,62.81 174.68,62.81 173.97,62.1 173.97,60.98 173.43,60.43 171.29,60.43 167.61,56.75 v3(167.61,54.26)
  BOTTOM w0.203: PUZ1.36 200.81,75.38 201.04,75.61 v3(201.44,75.61)
  BOTTOM w0.254: PUA1.5 v3(167.61,54.26)
PWR_LED#: length 222
  TOP w0.102: v3(5.49,81.43) 5.57,81.5 RLED1.2 CLED1.1
  IN1 w0.127: v3(5.49,81.43) 5.49,80.37 6.31,79.56 8.59,79.56 8.83,79.8 8.83,80.5 9,80.67 10.26,80.67 12.16,82.57 17.07,82.57 32.81,66.82 32.81,45.97 32.14,45.3 32.14,40.42 33.99,38.57 33.99,29.46 37.79,25.66 38.57,25.66 41.13,23.1 47.22,23.1 48.02,23.9 50.91,23.9 52.01,24.99 54.02,24.99 54.48,24.53 54.48,24.14 54.9,23.72 56.76,23.72 57.63,22.85 73.64,22.85 75.25,24.47 79.33,24.47 82.62,27.76 84.77,27.76 85.26,28.24 88.88,28.24 89.2,27.92 92.76,27.92 93.65,28.81 96.64,28.81 97.23,29.41 104.22,29.41 104.82,28.81 106.36,28.81 107.27,27.9 113.59,27.9 113.86,28.18 117.83,28.18 118.67,29.02 124.66,29.02 125.12,28.57 128.1,28.57 128.73,27.94 133.9,27.94 134.9,28.94 136.97,28.94 137.23,28.68 137.8,28.68 138.74,27.74 139.58,27.74 140.59,26.73 143.48,26.73 144.76,25.44 149.07,25.44 149.59,25.97 157.56,25.97 157.86,26.26 v3(157.86,26.99)
  BOTTOM w0.102: UK1.92 156.17,30.83 157.07,29.93 159.04,29.93 159.21,29.76 159.21,28.66 157.86,27.31 v3(157.86,26.99)
PWR_LED#_R: length 2.3
  TOP w0.102: RLED1.1 5.57,85.57 v3(5.47,85.67)
  BOTTOM w0.102: v3(5.47,85.67) 5.23,85.91 LED1.1
PWROK_DDR: length 5.7
  BOTTOM w0.203: PTPM1.1 13.93,77.95 11.99,77.95 11.45,77.41 10.14,77.41 9.79,77.06 PUM1.10
REFADJ_NVVDD: length 2.9
  TOP w0.254: PUV1.6 122.5,137.7 122.64,137.84 122.94,137.84 v1(123.55,138.45) 123.81,138.7 PRV10.2
REFIN_NVVDD: length 5
  TOP w0.203: PUV1.7 122.1,137.84 v3(122.59,138.34)
  TOP w0.254: v3(122.59,138.34) 122.92,138.67 PRV9.1
  BOTTOM w0.102: v3(122.59,138.34) 122.59,137.87 v1(122.79,137.66)
  BOTTOM w0.254: PRV11.1 122.36,139.97 PCV12.1 122.59,138.98 v3(122.59,138.34)
REGN_CHG: length 1.8
  BOTTOM w0.102: PDB2.2 192.34,53.06 v1(191.59,52.31)
RGND_AUXI: length 5.8
  BOTTOM w0.203: 195.86,75.55 196.24,75.55 196.41,75.37 PUZ1.25
  BOTTOM w0.381: 195.86,75.55 195.63,75.32 v1(194.48,75.32) 194.09,75.71 PCZ230.1 193.47,75.98 PRZ107.1 PRZ93.1
RGND_MAIN: length 8.8
  BOTTOM w0.203: 202.24,69.56 202.02,69.78 PUZ1.48
  BOTTOM w0.254: 202.24,69.56 202.24,69.36 202.13,69.25 201.36,69.25 201.19,69.09 201.19,68.66 201.99,67.86 202.18,67.86 202.34,68.02 202.34,68.67 202.47,68.8 202.8,68.8 v1(202.86,68.75) 203.08,68.52 203.08,67.41 203.87,66.62 PRZ21.2 203.67,66.37 203.67,66.01 PRZ95.2
RGND_NVVDD: length 9.9
  TOP w0.254: PRV18.2 PCV26.1 118.78,138.83 v1(119.2,138.41) 119.41,138.2 v3(120.51,138.2) 120.9,137.81 PUV1.10 ; PRV18.2 RV218.2 ; PRV18.2 119.03,139.72 PCV13.2 119.57,139.85 PCV21.2
  BOTTOM w0.254: v3(120.51,138.2) 120.51,138.83 120.89,139.21 PCV12.2 121.45,139.97 PRV13.2
RGND_SA: length 6.6
  TOP w0.127: v3(205.6,70.89) v2(205.6,71.91)
  IN1 w0.381: v3(203.23,71.23) 205.25,71.23 v3(205.6,70.89)
  BOTTOM w0.203: v3(203.23,71.23) 202.85,71.23 202.7,71.38 PUZ1.44
  BOTTOM w0.381: v3(205.6,70.89) PRZ94.2 PRZ22.2
RJ45_MDIN0: length 22.1
  BOTTOM w0.089: TSL1.22 22.23,128.08 21.9,128.41 21.22,128.41 18.15,131.48 18.15,132.51 15.67,134.99 15.67,142.2 13.91,143.95 13.61,143.95 13.19,143.53 13.19,143.3 JLAN.2
RJ45_MDIN1: length 24
  IN2 w0.102: v3(24.24,125.29) 24.1,125.43 23.43,125.43 22.79,126.06 22.79,126.44 17.94,131.29 17.94,132.63 15.91,134.67 15.91,139.82 14.88,140.85 14.68,140.85 13.59,139.76 JLAN.6
  BOTTOM w0.089: TSL1.19 23.52,125.08 23.85,125.41 24.12,125.41 v3(24.24,125.29)
RJ45_MDIN2: length 23.4
  BOTTOM w0.089: JLAN.5 13.16,139.84 13.3,139.69 14.06,139.69 14.37,139.39 14.37,133.55 20.44,127.48 v1(20.44,125.97) 20.44,124.65 21.48,123.6 21.48,122.71 21.77,122.42 22.11,122.42 22.45,122.08 TSL1.16
RJ45_MDIN3: length 25.7
  IN2 w0.102: v3(24.24,119.29) 24.1,119.43 23.92,119.43 23.43,119.93 23.43,123.08 21.28,125.23 21.28,126.65 14.41,133.52 14.41,137.18 13.95,137.64 13.46,137.64 13.29,137.47 13.29,137.08 JLAN.8
  BOTTOM w0.089: v3(24.24,119.29) 24.12,119.41 23.85,119.41 23.52,119.08 TSL1.13
RJ45_MDIP0: length 22.1
  BOTTOM w0.089: TSL1.23 22.24,129.08 21.91,128.75 21.37,128.75 v1(20.57,129.55) 18.5,131.63 18.5,132.65 16.01,135.14 16.01,142.34 14.06,144.29 13.47,144.29 12.95,143.78 12.64,143.78 JLAN.1
RJ45_MDIP1: length 24
  IN2 w0.102: v3(24.24,125.87) 24.1,125.73 23.55,125.73 23.1,126.19 23.1,126.56 18.25,131.41 18.25,132.76 16.21,134.79 16.21,139.95 15.01,141.16 14.59,141.16 13.86,141.88 JLAN.3
  BOTTOM w0.089: TSL1.20 23.51,126.08 23.84,125.75 24.12,125.75 v3(24.24,125.87)
RJ45_MDIP2: length 23.4
  BOTTOM w0.089: JLAN.4 13.25,140.53 13.25,140.23 13.44,140.04 14.21,140.04 14.71,139.53 14.71,133.7 v1(20.57,127.84) 20.79,127.63 20.79,124.79 21.83,123.75 21.83,122.85 21.92,122.77 22.08,122.77 22.4,123.08 TSL1.17
RJ45_MDIP3: length 25.7
  IN2 w0.102: JLAN.7 13.17,137.8 13.31,137.94 14.08,137.94 14.71,137.31 14.71,133.65 21.59,126.78 21.59,125.36 23.73,123.21 23.73,120.05 24.05,119.73 24.1,119.73 v3(24.24,119.87)
  BOTTOM w0.089: v3(24.24,119.87) 24.12,119.75 23.84,119.75 23.51,120.08 TSL1.14
ROM_SCLK: length 26
  TOP w0.102: RV80.2 171.93,94.04 RV381.1 171.45,94.53 169.62,94.53 167.91,92.83 163.1,92.83 161.36,94.58 160.8,95.42 160.08,97.16 160.08,98.36 159.41,99.03 157.52,99.03 157.09,99.46 157.09,99.58 v1(155.68,100.99) 153.92,102.75 v3(153.92,102.95)
  BOTTOM w0.102: v3(153.92,102.95) 154.3,103.33 UV1.C12
ROM_SI: length 27.9
  TOP w0.102: v1(170.81,95.07) 170.74,95.07 169.83,95.98 v3(169.66,96.16) 169.4,95.9 169.4,94.64 167.82,93.06 163.2,93.06 161.53,94.72 161,95.52 160.31,97.2 160.31,97.21 160.31,98.46 159.5,99.26 157.65,99.26 157.36,99.55 157.36,99.85 154.69,102.52 v3(154.69,102.93)
  BOTTOM w0.102: RV65.1 169.82,95.99 v3(169.66,96.16) 169.55,96.26 169.55,98.01 RV84.2 ; UV1.B12 155.1,103.33 v3(154.69,102.93)
ROM_SO: length 21.7
  TOP w0.102: RV81.2 RV64.1 171.71,96.23 171.71,97.28 v1(169.53,99.46) 169.53,99.98 v3(167.99,101.51)
  IN1 w0.127: v3(167.99,101.51) 166.81,101.51 164.23,104.1 161.31,104.1 161.12,103.91 v3(157.85,103.91)
  BOTTOM w0.102: UV1.A12 156.65,104.11 157.65,104.11 v3(157.85,103.91)
RSET: length 3.9
  BOTTOM w0.102: v1(29.59,103.92) RL11.2
  BOTTOM w0.203: UL1.31 32.38,105 32.03,104.64 30.91,104.64 30.63,104.36 RL11.2
RT3602_EN: length 2.6
  BOTTOM w0.203: PUZ1.37 202.01,74.18 202.75,74.92 v1(202.75,75.03) 202.75,75.36 202.93,75.53 PRZ25.1
RT3602_SET1: length 4.1
  TOP w0.102: v1(201.86,66.94) 201.68,66.94 v3(201.29,67.33)
  TOP w0.254: v3(201.29,67.33) PRZ5.2 PRZ17.1
  BOTTOM w0.203: PUZ1.2 200.41,68.4 201.29,67.52 v3(201.29,67.33)
RT3602_SET2: length 5.3
  TOP w0.254: PRZ18.1 199.31,67.94 200.04,67.21 200.04,66.82 199.99,66.77 ; v3(199.25,66.7) 199.91,66.7 199.99,66.77 ; 199.99,66.77 PRZ6.2
  BOTTOM w0.203: PUZ1.5 199.21,67.82 v1(199.41,67.62) 199.49,67.55 199.49,66.94 v3(199.25,66.7)
RT3602_SET3: length 4.6
  TOP w0.254: PRZ19.1 198.01,67.74 198.34,67.41 198.92,67.41 v3(198.99,67.33) v1(198.56,66.9) PRZ11.2
  BOTTOM w0.203: PUZ1.6 198.81,67.51 v3(198.99,67.33)
RT3602_VCC: length 5
  BOTTOM w0.102: PRZ65.2 v1(190.88,70.43)
  BOTTOM w0.203: PUZ1.13 194.96,69.78
  BOTTOM w0.254: 194.96,69.78 194.65,70.1 193.1,70.1 PCZ23.1 191.88,70.42 PRZ65.2
RT3602_VIN:
  vias: v1(194.43,69.27)
RT3602_VREF: length 54.5
  TOP w0.254: 200.59,77.36 201.57,76.39 203.74,76.39 204.15,75.98 204.15,73.86 203.23,72.94 v3(203.23,72.41) 203.23,72.02 203.82,71.43 v1(203.82,69.37) 203.82,65.55 v3(203.44,65.17) 203.06,65.55 201.61,65.55 PRZ2.1 201.15,63.89 200.77,63.51 199.78,63.51 199.42,63.86 PRZ3.1 PRZ4.1 198.56,63.85 197.89,63.18 189.3,63.18 188.7,63.77 188.7,67.44 190.1,68.84 190.1,71.19 190.48,71.57 PRZ64.1 PRZ63.1 ; 200.59,77.36 200.11,77.85 199.72,77.85 199.03,77.16 PRZ49.2 ; 200.59,77.36 PRZ14.1
  BOTTOM w0.203: PUZ1.42 202.27,72.18 202.42,72.33 203.16,72.33 v3(203.23,72.41)
  BOTTOM w0.254: v3(203.23,72.41) 203.49,72.66 PRZ24.2 ; PRZ26.1 PRZ33.1 203.77,64.84 v3(203.44,65.17)
S0_C10_STATE: length 77.7
  TOP w0.102: RC492.2 93.2,43.86 v3(93.94,43.86) 93.94,43.27 v1(94.03,43.19) ; UC7.4 113.82,99.67 113.27,100.22 107.93,100.22 107.17,99.46 v3(107.17,98.7)
  IN1 w0.076: 109.69,85.52 109.71,85.5 109.71,70.4 109.58,70.28 107.52,70.28 107.49,70.24 106.09,70.24 105.93,70.08 105.92,70.08 105.71,69.87 105.71,69.86 105.34,69.49 105.34,68.47 104.25,67.38 104.25,59.06 101.44,56.25 99.66,56.25 98.79,55.38 98.79,54.8 97.95,53.96 97.95,51.67 98.05,51.57 98.05,48.58 97.95,48.48 97.95,47.35 97.68,47.08
  IN1 w0.127: v3(107.17,98.7) 112.01,93.86 112.01,93.01 111.53,92.52 111.53,89.55 109.69,87.71 109.69,85.52 ; 97.68,47.08 95.33,44.72 94.68,44.72 93.94,43.99 v3(93.94,43.86)
S3_DDR: length 4.7
  BOTTOM w0.102: v1(5.48,78.43) PRM12.2
  BOTTOM w0.203: PUM1.7 8.59,77.19 8.36,77.41 PRM11.2 PCM18.1 PRM12.2
S5_DDR: length 4.4
  TOP w0.102: v3(8.99,77.52) 8.48,77.52 v1(8.29,77.32)
  BOTTOM w0.203: PUM1.8 v3(8.99,77.52) 8.99,78.16 PCM17.1 PRM8.2 PRM10.2
SA0_CHA_DIM1: length 6.2
  TOP w0.102: RD1.2 RD3.1 53.31,24.76 53.31,24.42 v3(53.14,24.25)
  BOTTOM w0.102: v3(53.14,24.25) 52.81,24.58 52.81,26.41 53.43,27.03 JDIMM1.256
SA0_CHB_DIM2: length 4.8
  TOP w0.102: v3(39.81,25.75) 39.81,25.56 39.54,25.29 RD22.1 39.54,24.5 39.37,24.32 39.21,24.32 RD19.2
  BOTTOM w0.102: JDIMM2.256 40.06,27.02 39.86,26.82 39.86,25.8 v3(39.81,25.75)
SA1_CHA_DIM1: length 6.2
  TOP w0.102: v1(55.79,25.22) RD4.2 RD5.1 53.54,25 53.54,24.44 v3(53.74,24.24)
  BOTTOM w0.102: v3(53.74,24.24) 53.19,24.79 53.19,25.81 53.41,26.03 JDIMM1.260
SA1_CHB_DIM2: length 4.3
  TOP w0.102: v3(40.29,25.41) 40.29,25.3 40.41,25.18 RD23.1 39.6,23.96 RD20.2 40.51,23.83 v1(40.67,23.67)
  BOTTOM w0.102: v3(40.29,25.41) 40.29,25.88 40.44,26.03 JDIMM2.260
SA2_CHA_DIM1: length 5
  TOP w0.102: RD6.1 RD2.2 52.42,49.49 v3(52.42,49.73) 51.84,49.73 v1(51.42,50.14)
  BOTTOM w0.102: JDIMM1.166 53.49,49.53 53.27,49.3 52.84,49.3 v3(52.42,49.73)
SA2_CHB_DIM2: length 5
  TOP w0.102: RD21.2 RD24.1 v1(39.64,47.9) v3(39.64,48.74)
  BOTTOM w0.254: v3(39.64,48.74) 39.64,49 40.16,49.53 JDIMM2.166
SA_BST: length 1.5
  BOTTOM w0.254: PUA1.4 167.61,57.48 167.75,57.61 PRA2.1
SA_BST_R: length 3.6
  BOTTOM w0.102: v1(165.54,59.05) 165.72,59.23 167.17,59.23 PCA3.1
  BOTTOM w0.508: PCA3.1 167.98,58.76 168.23,59.01 PRA2.2
SA_LG: length 9.9
  TOP w0.102: v3(159.62,54.63) 159.88,54.38 v1(160.56,54.38)
  IN1 w0.508: v3(166.61,54.25) 165.22,55.65 161.91,55.65 160.89,54.63 v3(159.62,54.63)
  BOTTOM w0.254: PUA1.7 v3(166.61,54.25)
SA_LX: length 12
  TOP w0.102: v2(157.59,58.52) 158.16,57.94 PRA4.1
  IN1 w0.508: v3(159.43,56.41) 160.19,57.17 166.1,57.17 166.61,57.68 v3(166.61,58.06)
  BOTTOM w0.254: PCA3.2 166.61,58.64 v3(166.61,58.06) 166.61,58.06 PUA1.2
SA_SNUB:
  vias: v2(162.39,56.92)
SA_UG: length 10.2
  TOP w0.102: v3(160.26,58.57) v2(159.44,58.57)
  IN1 w0.508: v3(167.37,58.06) 167.37,58.82 166.86,59.33 161.02,59.33 v3(160.26,58.57)
  BOTTOM w0.254: v3(167.37,58.06) 167.36,58.06 167.11,57.81 PUA1.3
SATA_CRX_C_DTX_N0: length 7.5
  BOTTOM w0.102: C153.2 258.47,9.51 258.36,9.41 258.07,9.41 257.92,9.25 257.92,8.05 v4(258.52,7.44) 260.49,5.48 260.49,5.3 260.78,5.01 261.02,5.01 261.17,5.15 JHDD.6
SATA_CRX_C_DTX_P0: length 7.5
  BOTTOM w0.102: C154.2 257.58,9.41 257.69,9.3 v4(257.69,8.64) 257.69,7.97 258.04,7.62 258.04,7.6 258.68,6.96 258.7,6.96 260.27,5.39 260.27,5.21 260.59,4.9 260.69,4.79 261,4.79 261.14,4.65 JHDD.7
SATA_CRX_DTX_N0: length 198.5
  IN2 w0.076: 131.96,47.95 131.96,50.45 131.18,51.24 126.2,51.24 124.99,52.45 124.99,54.24 124.16,55.06 122.89,55.06 122.46,54.64 121.66,54.64 121.51,54.77 v3(121.5,55.04)
  IN2 w0.127: v3(234.86,14.81) 234.72,14.66 234.07,14.66 233.54,15.2 233.54,29.26 211.59,51.2 207.75,51.2 205.75,49.19 202.05,49.19 199.68,46.82 199.68,44.67 203.2,41.15 203.2,38.81 201.61,37.22 201.61,34.03 200.87,33.29 191.37,33.29 189.73,31.66 173.34,31.66 172.86,32.14 171.13,32.14 167.25,36.02 165.45,36.02 165.04,36.43 161.95,36.43 160.77,37.61 160.11,37.61 159.55,38.17 158.05,38.17 157.39,38.83 150.79,38.83 150.35,39.26 150.35,40.28 148.58,42.05 148.03,42.05 147.44,42.64 144.43,42.64 142.15,44.92 135.8,44.92 135.79,44.92 134.99,44.92 131.96,47.95
  BOTTOM w0.076: UC1.BN10 120.9,54.58 121.18,54.86 121.32,54.86 v3(121.5,55.04)
  BOTTOM w0.102: C153.1 258.36,10.93 258.36,12.68 254.96,16.09 251.6,16.09 251.1,15.59 244.85,15.59 243.89,14.63 235.05,14.63 v3(234.86,14.81)
SATA_CRX_DTX_P0: length 198.4
  IN2 w0.076: 131.81,47.75 131.75,47.8 131.75,48.01 131.8,48.06 131.8,50.38 131.11,51.07 126.13,51.07 124.82,52.38 124.82,54.17 124.09,54.9 122.96,54.9 122.53,54.47 121.95,54.47 v3(121.56,54.08)
  IN2 w0.127: 131.81,47.75 134.89,44.67 142.04,44.67 144.33,42.39 147.34,42.39 147.93,41.8 148.48,41.8 150.1,40.18 150.1,39.16 150.68,38.57 157.29,38.57 157.94,37.92 159.45,37.92 160,37.36 160.66,37.36 161.84,36.18 164.93,36.18 165.34,35.76 167.15,35.76 171.03,31.88 172.75,31.88 173.24,31.4 189.84,31.4 191.48,33.04 200.98,33.04 201.86,33.93 201.86,37.11 203.45,38.7 203.45,41.26 199.93,44.77 199.93,46.71 202.16,48.94 205.85,48.94 207.86,50.95 211.48,50.95 233.28,29.15 233.28,15.1 233.97,14.41 234.68,14.41 v3(234.86,14.23)
  BOTTOM w0.076: UC1.BN8 121.17,54.58 120.99,54.4 120.99,54.16 121.15,54 121.47,54 v3(121.56,54.08)
  BOTTOM w0.102: v3(234.86,14.23) 235.05,14.41 243.98,14.41 244.94,15.37 251.19,15.37 251.69,15.87 254.87,15.87 258.15,12.59 258.15,11.36 258.05,11.27 257.81,11.27 257.58,11.04 C154.1
SATA_CTX_C_DRX_N0: length 5.3
  BOTTOM w0.102: C156.2 259.37,9.54 259.5,9.41 v4(259.5,8.66) 259.5,7.46 259.71,7.25 259.71,7.23 260.35,6.59 260.37,6.59 260.66,6.29 260.96,6.29 261.1,6.15 JHDD.4
SATA_CTX_C_DRX_P0: length 5.3
  BOTTOM w0.102: JHDD.3 261.13,6.65 260.99,6.51 260.75,6.51 v4(260.19,7.07) 259.72,7.55 259.72,8.19 259.73,8.2 259.73,9.11 259.72,9.12 259.72,9.36 259.86,9.51 260.16,9.51 260.26,9.61 C155.2
SATA_CTX_DRX_N0: length 176.8
  IN2 w0.127: v3(234.81,15.87) 234.64,16.03 234.36,16.03 234.04,16.35 234.04,29.36 211.69,51.71 207.48,51.71 205.41,49.64 201.89,49.64 196.9,44.65 187.49,44.65 186.39,43.54 179.48,43.54 178.6,42.67 176.89,42.67 176.41,43.15 172.65,43.15 168.48,44.88 165.84,47.52 157.86,47.52 156.25,49.13 152.44,49.13 152.28,49.3 151.33,49.3 141.3,59.33 133.24,59.33 131.75,57.84 131.75,57.84 131.52,57.84 v3(131.37,57.69)
  BOTTOM w0.076: 129.77,54.02 129.75,54.02 129.01,54.76 128.25,54.76 127.9,54.41 126.3,54.41 126.17,54.29 126.05,54.29 126.05,54.29 125.83,54.29 125.73,54.32 125.51,54.32 125.41,54.29 125.16,54.29 124.82,54.43 124.51,54.43 UC1.BN4
  BOTTOM w0.102: C156.1 259.37,11.19 259.46,11.27 259.81,11.27 259.91,11.37 259.91,12.07 255.46,16.53 251.41,16.53 250.93,16.05 234.99,16.05 v3(234.81,15.87) ; v3(131.37,57.69) 131.3,57.62 131.3,55.07 130.25,54.02 129.77,54.02
SATA_CTX_DRX_P0: length 176.8
  IN2 w0.127: v3(131.37,58.27) 131.55,58.09 131.65,58.09 133.14,59.58 141.4,59.58 151.44,49.55 152.38,49.55 152.55,49.38 156.36,49.38 157.97,47.77 165.95,47.77 168.63,45.09 172.7,43.4 176.51,43.4 177,42.92 178.49,42.92 179.37,43.8 186.28,43.8 187.39,44.9 196.79,44.9 201.78,49.89 205.3,49.89 207.37,51.96 211.8,51.96 234.3,29.46 234.3,16.46 234.47,16.29 234.64,16.29 v3(234.81,16.45)
  BOTTOM w0.076: UC1.BN3 124.76,54.6 124.86,54.6 125.2,54.45 125.39,54.45 125.48,54.49 125.76,54.49 125.85,54.45 126.11,54.45 126.23,54.58 126.46,54.58 126.58,54.71 126.76,54.71 126.89,54.58 127.07,54.58 127.19,54.71 127.37,54.71 127.5,54.58 127.84,54.58 128.18,54.92 129.08,54.92 129.79,54.21 129.81,54.21
  BOTTOM w0.102: C155.1 260.26,11.13 260.13,11.26 260.13,12.16 255.55,16.75 251.32,16.75 250.84,16.27 234.99,16.27 v3(234.81,16.45) ; v3(131.37,58.27) 131.37,58.24 130.96,57.83 130.96,57.51 131.11,57.36 131.11,55.15 130.17,54.21 129.81,54.21
SATA_GP0: length 7.6
  TOP w0.076: v1(125.05,38.18) 124.65,38.59 v3(124.65,38.91)
  BOTTOM w0.076: v3(124.65,38.91) 124.65,38.54 RC962.1 123.66,39.2 123.66,41.07 123.57,41.15 123.57,41.27 123.05,41.8 122.79,41.8 122.6,42 122.51,42.23 122.51,42.59 122.3,42.8 UC1.CN8
SATA_LED#: length 215.1
  TOP w0.102: RC961.1 v3(123.3,40.41) ; v3(79.83,27.22) 77.95,25.34 64.97,25.34 64.59,25.72 64.59,26.37 64.24,26.72 62.67,26.72 62.44,26.94 59.48,26.94 59.11,26.58 55.95,26.58 54.3,28.23 54.3,28.59 53.46,29.43 52.28,29.43 51.74,28.89 51.74,28.44 51.17,27.87 51.17,27.31 50.45,26.59 49.21,26.59 46.2,29.6 43.18,29.6 42.22,30.55 39.28,30.55 37.83,29.1 v3(37.83,28.16)
  IN1 w0.076: v3(123.3,40.41) 123.3,40.42 123.62,40.74 123.62,41.3 123.86,41.54 125.33,41.54 126.03,40.84 127.3,40.84 127.76,41.3 129.01,41.3 129.68,40.63
  IN1 w0.127: v3(133.05,30.11) 133.04,30.09 125.81,30.09 125.36,30.54 117.95,30.54 117.22,29.82 114.53,29.82 114.24,30.11 113.94,30.41 111.64,30.41 111.51,30.28 108.55,30.28 108.35,30.08 105.35,30.08 104.71,30.72 90.29,30.72 89.35,29.78 87.74,29.78 87.35,30.17 82.77,30.17 v3(79.83,27.22) ; v3(7.37,92.73) 7.37,90.95 7.74,90.58 7.74,87.26 8.38,86.62 14.81,86.62 34.11,67.32 34.11,44.58 33.63,44.09 33.63,40.8 37.78,36.65 37.78,33.14 37.07,32.43 37.07,28.93 v3(37.83,28.16) ; v3(130.65,40.34) 130.42,40.34 130.41,40.33 129.98,40.33 129.68,40.63
  BOTTOM w0.076: v3(123.3,40.41) 123.18,40.41 122.88,40.71 122.88,41.08 122.51,41.45 122.51,41.76 122.42,42.01 122.2,42.23 UC1.CN7
  BOTTOM w0.102: v3(7.37,92.73) 7.36,92.74 RLED2.2 CLED2.1 7.41,94.33 v1(8.31,94.33) ; v3(130.65,40.34) 131.44,40.34 133.05,38.73 v3(133.05,30.11)
SATA_LED#_R: length 3.3
  BOTTOM w0.102: v1(4.72,94.41) 4.72,93.05 ; 4.72,93.05 5.49,93.05 5.83,93.39 RLED2.1 ; 4.72,93.05 LED2.1
SCL_CHG: length 4.4
  BOTTOM w0.102: PRB19.1 199.27,55.68 199.59,55.37 v1(201.53,55.37)
  BOTTOM w0.254: PRB19.1 198.62,55.84 198.37,56.09 PUB1.9
SD_RCOMP: length 2.8
  TOP w0.381: RC76.2 104.38,43.62 v1(104.52,43.76) 104.81,44.05 v3(105.06,44.05)
  BOTTOM w0.2: v3(105.06,44.05) 105.07,44.1 105.41,44.33 UC1.CK33
  BOTTOM w0.203: v3(105.06,44.05) UC1.CM34
SDA_CHG: length 4.3
  BOTTOM w0.102: PRB18.1 199.27,56.75 199.6,57.08 200.57,57.08 200.67,57.18 v1(201.57,57.18)
  BOTTOM w0.254: PRB18.1 199.24,56.59 PUB1.8
SERIRQ: length 143.8
  TOP w0.076: v3(108.69,50.56) 108.69,50.38 108.86,50.21 109.35,50.21 109.66,49.9 109.66,49.55 109.39,49.28 109.39,47.67 108.89,47.16 108.89,43.64 108.44,43.2
  TOP w0.102: v3(160.03,36.91) 160.03,36.16 158.88,35.01 157.84,35.01 157.21,34.37 157.21,32.89 155.05,30.73 155.05,30.37 v2(154.92,30.25) 154.8,30.12 154.44,30.12 151.91,27.59 150.66,27.59 148.1,25.04 148.1,23.46 148.2,23.36 149.11,23.36 149.44,23.69 149.44,24.2 150.41,25.17 R5202.1 ; RC122.1 108.44,40.46 108.06,40.84 108.06,41.45 108.44,41.83 108.44,43.2
  IN1 w0.127: v3(160.03,36.91) 159.87,37.08 159.27,37.08 159.06,37.28 157.04,37.28 156.74,36.98 v3(156.56,36.98) 156.53,37.01 155.8,37.01 155.51,37.29 151.11,37.29 150.34,38.07 150.34,38.72 150.18,38.88 149.9,38.88 149.77,38.76 149.77,38.18 149.64,38.06 149.39,38.06 149.26,38.18 149.26,38.76 149.14,38.88 148.59,38.88 148.36,38.65 148.36,37.98 148.23,37.86 144.63,37.86 144.38,38.11 144.38,38.45 144.12,38.72 143.63,38.72 143.39,38.48 143.39,37.93 143.33,37.87 143.05,37.87 142.92,37.99 142.92,38.32 142.8,38.44 142.54,38.44 142.41,38.32 142.41,37.99 142.29,37.87 141.87,37.87 141.71,38.02 141.71,39.26 141.59,39.39 141.31,39.39 141.18,39.26 141.18,38 141.06,37.87 140.8,37.87 140.68,38 140.68,39.26 140.55,39.39 140.29,39.39 140.17,39.26 140.17,38.25 140.04,38.12 139.79,38.12 139.66,38.25 139.66,39.26 139.53,39.39 139.28,39.39 139.15,39.26 139.15,38.25 139.02,38.12 138.77,38.12 138.64,38.25 138.64,39.26 138.52,39.39 138.26,39.39 138.14,39.26 138.14,38.25 138.01,38.12 137.75,38.12 137.63,38.25 137.63,39.26 137.5,39.39 137.25,39.39 137.12,39.26 137.12,38.26 136.99,38.13 136.74,38.13 136.61,38.26 136.61,39.26 136.48,39.39 135.46,39.39 133.77,37.7 128.98,37.7 128.89,37.79 124.52,37.79 124.33,37.6 121.32,37.6 120.8,37.08 117.78,37.08 117.6,37.26 117.6,37.98 117.41,38.17 116.49,38.17 114.21,40.45 114.21,43.44 114.07,43.57 112.96,43.57 112.84,43.7 112.84,44.49 112.96,44.62 113.65,44.62 113.81,44.78 113.81,47.97 113.96,48.13 114.45,48.13 114.64,48.32 114.64,49.79 114.5,49.93 113.13,49.93 113,49.8 113,47.09 112.38,46.46 111.02,46.46 110.77,46.71 110.77,47.27 110.85,47.35 111.26,47.35 111.38,47.48 111.38,50.58 111.24,50.72 110.7,50.72 110.57,50.59 110.57,50.26 110.45,50.13 108.78,50.13 108.71,50.21 108.71,50.54 v3(108.69,50.56)
  BOTTOM w0.076: UC1.BV28 108.91,50.88 108.69,50.66 v3(108.69,50.56)
  BOTTOM w0.102: UK1.3 155.37,46.54 156.78,45.13 156.78,44.11 156.89,44 156.89,39.82 156.79,39.72 156.79,39.53 156.69,39.43 156.49,39.43 156.38,39.32 156.38,39.12 156.49,39.02 156.69,39.02 156.79,38.92 156.79,38.72 156.69,38.62 155.93,38.62 155.82,38.51 155.82,38.22 155.93,38.12 156.45,38.12 156.56,38.02 v3(156.56,36.98)
SM_INTRUDER#: length 27.3
  TOP w0.102: v3(89.78,37.75) 90.38,37.75 v2(90.64,38.01)
  IN2 w0.076: v3(102.74,53.27) 102.74,53.03 102.31,52.6 101.84,52.6 100.64,51.4 100.64,47.85 99.95,47.16 99.66,47.16 98.71,46.21 98.66,46.12 98.66,46.12 98.52,45.98 98.52,45.45 96.59,43.51 96.59,42.44 96.1,41.96 95.4,41.96
  IN2 w0.127: v3(89.78,37.75) 89.78,39.78 90.28,40.28 91.68,40.28 93.36,41.96 95.4,41.96
  BOTTOM w0.076: v3(102.74,53.27) 102.97,53.27 103.05,53.36 103.41,53.36 103.47,53.33 103.81,53.33 103.86,53.36 104.04,53.36 104.1,53.34 UC1.BR35
  BOTTOM w0.102: v3(89.78,37.75) 89.8,37.75 89.9,37.65 RC94.2
SM_PG_CTRL: length 127.7
  TOP w0.102: v3(6.59,80.03) 6.99,79.62 30.44,79.62 33.49,82.67 33.49,92.86 36.78,96.15 40.61,97.73 v2(48.55,97.73) 51.04,97.73 v3(53.36,100.06)
  IN1 w0.127: v3(113.14,96.41) 113.14,97.34 112.4,98.08 111.72,98.08 110.13,99.66 105.42,99.66 104.97,100.11 92.2,100.11 91.88,99.79 65.57,99.79 64.71,98.94 54.48,98.94 v3(53.36,100.06)
  BOTTOM w0.102: v3(113.14,96.41) 113.52,96.79 RC429.2 114.01,96.47 114.01,95.8 114.14,95.67 UC3.4
  BOTTOM w0.254: PRM12.1 v3(6.59,80.03)
SM_RCOMP0: length 5.3
  TOP w0.305: RC38.1 104.6,53.85 106,55.24 v1(106.27,55.24) 108.47,55.24 v3(108.61,55.1)
  BOTTOM w0.2: UC1.BN28 108.91,54.79 v3(108.61,55.1)
SM_RCOMP1: length 7.7
  TOP w0.305: RC39.1 103.68,53.62 104.03,53.27 104.74,53.27 105.05,53.57 105.05,53.69 v1(105.44,54.09) 106.14,54.78 108.19,54.78 108.39,54.58 108.93,54.58 109.31,54.96 v3(109.31,55.16)
  BOTTOM w0.2: 109.31,54.96 v3(109.31,55.16)
  BOTTOM w0.203: UC1.BN27 109.31,54.96
SM_RCOMP2: length 6.9
  TOP w0.305: RC40.1 103.16,53.61 103.16,53.49 103.84,52.81 v1(104.16,52.81) 105.95,52.81 106.26,53.12 106.26,53.45 106.62,53.82 107.57,53.82 107.99,54.23 v3(107.99,54.31)
  BOTTOM w0.203: v3(107.99,54.31) 107.99,54.32 108.2,54.69 UC1.BN29
SMBALERT#: length 46.5
  TOP w0.076: RC380.1 115.01,43.92 v1(115.53,44.45) v3(116.38,45.3)
  IN1 w0.076: v3(116.38,45.3) 116.73,44.94 116.73,40.5 118.19,39.04 122.76,39.04 122.94,39.21 124.14,39.21 124.21,39.29 125.84,39.29 126.26,38.87 129.68,38.87
  IN1 w0.127: 129.68,38.87 133.33,38.87 135.12,40.66 139.57,40.66 139.87,40.96 143.48,40.96 v3(144.33,40.11)
  BOTTOM w0.076: v3(116.38,45.3) 116.71,44.96 116.71,44.96 UC1.CJ15
  BOTTOM w0.102: R5269.1 142.01,34.59 142.01,38.61 142.94,39.54 143.76,39.54 v3(144.33,40.11)
SMBCLK: length 60.9
  TOP w0.102: v3(84.84,25.25) RC470.1 R5266.1
  IN2 w0.076: v3(117.47,44.1) 117.1,44.46 116.13,44.46 114.89,45.7 114.89,46.34 114.4,46.83 113.46,46.83 107.72,41.09 107.72,40.98 107.42,40.69 107.42,40.63
  IN2 w0.127: v3(86.13,27.18) 86,27.31 86,28.34 86.91,29.26 89,29.26 89.48,29.74 89.48,30.72 89.77,31.01 89.77,33.29 89.93,33.45 91.88,33.45 94.31,35.88 97.87,35.88 98.34,36.35 99.74,36.35 100.4,37.02 100.4,38.46 100.9,38.96 101.96,38.96 102.41,39.4 103.16,39.4 104.23,38.96 105.85,38.96 107.42,40.53 107.42,40.63
  BOTTOM w0.076: UC1.CK14 117.48,44.11 v3(117.47,44.1)
  BOTTOM w0.102: QC1.6 80.99,20.47 80.87,20.34 80.75,20.34 80.59,20.51 80.59,24.25 82,25.66 84.07,25.66 84.48,25.25 v3(84.84,25.25) 84.84,27.63 85.2,27.99 85.72,27.99 85.99,27.72 85.99,27.32 v3(86.13,27.18)
SMBDATA: length 57.8
  TOP w0.102: R5267.1 RC469.1 v3(83.08,25.25) 83.04,25.25 v1(82.62,25.67)
  IN2 w0.076: v3(117.43,45.85) 117.43,45.78 117.01,45.36 117.01,45.04 116.6,44.63 116.2,44.63 115.06,45.77 115.06,46.4 114.47,46.99 113.39,46.99 107.55,41.16 107.55,41.05 107.35,40.85 107.32,40.85 107.1,40.63
  IN2 w0.127: 107.1,40.63 105.73,39.26 104.29,39.26 103.81,39.46 103.22,39.71 102.28,39.71 101.84,39.26 100.77,39.26 100.1,38.59 100.1,37.14 99.61,36.66 98.21,36.66 97.74,36.19 94.19,36.19 91.75,33.76 89.8,33.76 89.47,33.42 89.47,31.13 89.18,30.84 89.18,29.86 88.87,29.56 86.79,29.56 85.7,28.47 85.7,27.34 v3(85.54,27.18)
  BOTTOM w0.076: v3(117.43,45.85) 117.36,45.85 UC1.CH15
  BOTTOM w0.102: v3(85.54,27.18) 85.71,27.35 85.71,27.6 85.61,27.71 85.32,27.71 85.12,27.51 85.12,26 85.33,25.8 85.33,25.04 85.14,24.85 84.49,24.85 84.08,25.25 v3(83.08,25.25) 82.29,24.47 QC1.3
SML0ALERT#: length 6.7
  TOP w0.076: v3(116.39,45.91) 114.66,44.18 T305.1 114.66,42.15 RC218.1 114.32,41.49 114.64,41.17 RC360.1
  BOTTOM w0.076: v3(116.39,45.91) 116.77,45.91 UC1.CG15
SML0CLK: length 3.3
  TOP w0.076: RC49.1 116.31,43.39 116.44,43.52 116.44,44.22 v3(117.48,45.26)
  BOTTOM w0.076: UC1.CH14 117.62,45.41 117.48,45.26 v3(117.48,45.26)
SML0DATA: length 5.2
  TOP w0.076: RC50.1 115.68,43.31 116.02,43.66 116.02,44.3 116.95,45.23 116.95,46.31 116.76,46.51 v3(116.31,46.51)
  BOTTOM w0.076: v3(116.31,46.51) 116.36,46.48 UC1.CF15
SML1ALERT#: length 12.7
  TOP w0.076: 98.09,42.87 101.2,45.98 101.2,46.63 v3(101.68,47.1)
  TOP w0.102: T90.1 98.09,41.74 98.09,42.87
  BOTTOM w0.076: RC379.1 101.21,46.63 v3(101.68,47.1) 101.88,46.9 102.21,46.9 102.55,47.24 102.55,47.72 102.76,47.93 103.05,47.93 103.17,47.81 103.56,47.81 103.59,47.79 103.74,47.79 104.69,47.79 UC1.CC34
SML1CLK: length 5.8
  TOP w0.102: v3(118.09,40.39) 118.19,40.28 118.19,39.81 v1(118.12,39.73) 117.32,39.73 RC467.1
  BOTTOM w0.076: UC1.CN15 117.15,42.47 116.91,42.22 116.8,42.11 116.73,41.96 116.59,41.8 116.4,41.8 116.25,41.66 116.25,41.65 116.25,41.36 116.7,40.91 116.7,40.53 116.92,40.3 118,40.3 v3(118.09,40.39)
SML1DATA: length 4
  TOP w0.076: v3(117.09,41.32) 117.48,41.32 v1(117.69,41.52)
  TOP w0.102: RC468.1 116.63,41.78 v3(117.09,41.32)
  BOTTOM w0.076: UC1.CM15 117.45,42.83 117.45,42.28 117.35,42.18 117.1,42.18 116.94,42.02 116.9,41.93 116.9,41.73 116.94,41.64 117.08,41.49 117.08,41.32 v3(117.09,41.32)
SNB_1V: length 2
  TOP w0.102: PR1007.2 v2(185.16,93.33)
SNB_2.5V: length 1.3
  BOTTOM w0.102: PC2503.1 v1(1.65,44.14)
SNB_DDR: length 1.9
  TOP w0.102: PRM3.2 v2(4.77,69.45)
SNUB_CHG: length 1.5
  TOP w0.102: PRB12.2 v2(174.53,52.85)
SNUB_NVVDD1: length 1.8
  TOP w0.102: PRV7.2 v2(115.36,122.27)
SNUB_NVVDD2: length 1.9
  TOP w0.102: PRV17.2 v2(119.78,128.86)
SNUB_VRAM: length 2.2
  TOP w0.102: PRW6.2 v2(181.43,137.69)
SOC_GPIOA7: length 6.5
  TOP w0.076: RC475.1 102.85,44.03 v1(104.92,46.09) v3(105.73,46.91)
  BOTTOM w0.076: v3(105.73,46.91) 105.87,47.04 105.87,47.89 UC1.CC32
SOC_GPIOA12: length 4.4
  BOTTOM w0.076: T354.1 100.89,47.62 101.84,48.57 101.84,49.42 102.15,49.74 102.41,49.74 103.25,50.58 UC1.BW37
SOC_GPIOB4: length 6.1
  BOTTOM w0.076: T81.1 100,46.94 101.01,46.94 101.78,47.7 101.78,47.81 102.23,48.26 102.87,48.26 103.1,48.49 103.34,48.49 103.47,48.49 103.47,48.48 103.9,48.33 104.36,48.33 UC1.CC35
SOC_GPIOB21: length 7.8
  IN2 w0.076: v3(107.36,47.87) 107.36,47.9 106.98,48.28 104.86,48.28 102.97,46.39 v3(101.71,46.39)
  BOTTOM w0.076: RC409.1 101.32,46 v3(101.71,46.39)
  BOTTOM w0.089: UC1.CC30 v3(107.36,47.87)
SOC_GPP_D7: length 5.3
  TOP w0.076: v1(102.92,50.06) 102.48,50.06 v3(102.27,50.27)
  BOTTOM w0.076: UC1.BV35 104.28,51.21 103.84,51.01 103.83,51.01 103.64,50.92 102.91,50.92 v3(102.27,50.27) 101.58,49.59 101.58,48.86 RC483.1
SOC_GPP_H21: length 13.8
  BOTTOM w0.076: RC473.1 113.56,35.26 RC472.1 112.89,35.94 112.89,36.91 v1(112.57,37.23) 110.89,38.91 110.89,39.67 110.38,40.18 110.38,41.01 110.66,41.29 110.66,41.64 110.6,41.78 110.59,41.79 110.59,41.79 110.56,41.87 110.56,42.59 110.59,42.73 110.62,42.8 110.62,43.23 110.43,43.42 110.43,43.57 110.41,43.58 110.41,46.43 UC1.CF25
SOC_GPP_H23: length 9.9
  BOTTOM w0.076: RC491.1 112.63,35.43 112.63,36.71 v1(111.2,38.15) 110.82,38.53 110.73,38.74 110.73,39.58 110.22,40.09 110.22,41.08 110.49,41.36 110.49,41.61 110.46,41.69 110.35,41.8 110.35,41.8 110.27,41.86 110.13,41.86 110.01,41.97 109.98,42.06 109.98,42.25 110.03,42.38 110.15,42.5 110.26,42.5 110.4,42.65 110.42,42.73 110.42,42.95 110.15,43.22 UC1.CM26
SOC_SVID_ALERT#: length 5.4
  BOTTOM w0.076: UC1.AA3 124.93,73.96 125.41,73.96 125.65,74.19 125.65,74.35 125.86,74.56 126.47,74.56 126.66,74.38 v1(127.89,74.38) 128.91,75.41 RC180.1
SOC_VRALERT#: length 7.8
  TOP w0.076: v3(102.19,47.72) 102.19,45.46 v1(101.52,44.79) 100.63,43.9 100.34,43.9 RC115.2
  BOTTOM w0.076: UC1.CC36 103.72,48.07 103.48,48.3 103.43,48.32 103.16,48.32 102.93,48.09 102.67,48.09 102.3,47.72 v3(102.19,47.72)
SOC_XDP_TDI: length 16.4
  TOP w0.076: 128.1,86.91 128.1,86.16 127.62,85.68 v2(127.49,85.68) 126.69,85.68 126.09,85.09 126.09,84.52 125.35,83.78 125.35,83.17 125.55,82.98 125.55,78.49 124.12,77.07 124.09,77.07 123.9,76.88 123.57,76.88 123.31,76.62 123.31,76.16 123.07,75.91 122.59,75.91 122.26,76.24 v3(122.26,76.29)
  TOP w0.102: RC389.1 128.1,86.91
  BOTTOM w0.076: UC1.U5 UC1.U6 122.26,76.41 v3(122.26,76.29)
SOC_XDP_TDO: length 16.7
  TOP w0.076: v3(123.45,75.37) 123.45,75.83 123.64,76.02 123.64,76.25 123.94,76.55 124.07,76.55 125.88,78.36 125.88,81.07 126.87,82.06 126.87,82.19 129.75,85.07
  TOP w0.102: RC937.1 RC391.1 130.64,85.96 v2(130.51,85.83) 129.75,85.07
  BOTTOM w0.076: UC1.Y5 v3(123.45,75.37) UC1.W5
SOC_XDP_TMS: length 11.2
  TOP w0.076: v3(123.39,78.14) 123.41,78.14 124.9,79.62 124.9,82.04 124.56,82.38 v2(124.56,83.84) 124.56,85.08 125.62,86.15 125.62,86.91
  TOP w0.102: RC390.1 125.62,86.91
  BOTTOM w0.076: UC1.T5 123.25,78 v3(123.39,78.14) 123.39,78.46 UC1.P5
SOC_XDP_TRST#: length 4.9
  TOP w0.076: v2(124.84,76.79) 124.55,76.79 124.02,76.27 CC293.2 RC421.1 123.15,74.78 v3(122.82,74.44)
  BOTTOM w0.076: UC1.AB6 v3(122.82,74.44) UC1.Y6
SPK_L+:
  vias: v1(24.74,36.76)
SPK_L+_CONN: length 148.4
  TOP w0.127: v3(29.03,37.04) 29.71,37.04 v2(29.8,37.13)
  BOTTOM w0.762: JSPK.4 88.67,99.54 90.66,101.53 96.69,101.53 99.11,99.12 99.11,98.27 DA6.3 ; 29.79,37.04 30.65,37.04 30.83,37.22 32.86,37.22 34.78,39.14 34.78,49.95 28.77,55.96 28.77,81.53 37.7,90.46 37.7,92.25 40.98,95.52 73.13,95.52 75.98,92.68 79.12,92.68 82.71,89.09 96.26,89.09 98.9,91.73 98.9,92.46 99.74,93.3
  vias: v3(28.27,37.04)
SPK_L-:
  vias: v1(24.13,37.9)
SPK_L-_CONN: length 148.5
  TOP w0.127: v3(29.03,38.31) 29.32,38.31 v2(29.83,38.82)
  BOTTOM w0.762: 29.82,38.28 30.68,38.28 30.86,38.1 32.49,38.1 33.89,39.5 33.89,49.59 27.88,55.59 27.88,81.9 36.81,90.83 36.81,92.62 40.61,96.41 73.5,96.41 76.35,93.57 79.48,93.57 83.08,89.97 95.89,89.97 98.01,92.1 98.01,92.81 97.44,93.38 ; JSPK.3 87.42,98.03 87.97,97.48 89.03,97.48 89.58,98.03 89.58,99.19 91.03,100.64 96.33,100.64 97.99,98.98 97.99,98.39 DA6.2
  vias: v3(28.27,38.31)
SPK_R+:
  vias: v1(23.77,39.17)
SPK_R+_CONN: length 146
  TOP w0.127: v2(29.66,42.22) 29.03,41.59 v3(29.03,40.85)
  BOTTOM w0.762: 94.93,94.23 94.08,93.38 94.08,92.49 93.02,91.43 84.17,91.43 80.84,94.76 76.95,94.76 74.16,97.56 39.99,97.56 38.46,96.03 30.84,96.03 27.11,92.29 27.11,85.12 25.85,83.87 25.85,55.42 32.32,48.95 32.32,42.13 31.04,40.85 29.84,40.85 ; JSPK.2 86.17,97.99 85.99,97.81 85.99,97.38 87.1,96.26 89.43,96.26 89.43,96.26 90.72,97.55 90.72,98.41 91.82,99.5 93.96,99.5 94.84,98.62 DA7.3
  vias: v3(28.27,40.85)
SPK_R-:
  vias: v1(25.07,39.15)
SPK_R-_CONN: length 147.5
  TOP w0.127: v3(29.03,39.58) 29.71,40.26 v2(29.71,40.51)
  BOTTOM w0.762: DA7.2 92.59,98.29 92.08,98.29 91.7,97.91 91.7,97.2 89.87,95.37 86.74,95.37 85.1,97.01 85.1,97.87 84.92,98.05 JSPK.1 ; 27.29,39.64 26.91,40.03 26.91,41.36 27.67,42.12 31.05,42.12 31.43,42.5 31.43,48.58 24.96,55.05 24.96,84.23 26.22,85.49 26.22,92.66 30.48,96.92 38.1,96.92 39.62,98.45 74.52,98.45 77.32,95.65 81.21,95.65 84.54,92.32 92.65,92.32 93.19,92.86 93.19,93.47 92.44,94.22
  vias: v3(28.27,39.58)
SPOK: length 208.8
  TOP w0.102: RC434.1 CC354.2 92.71,25.91 v3(93.48,26.69) ; v3(191.8,114.19) v2(192.92,114.19) ; v3(145.06,51.99) 145.06,52.24 146.6,53.79 146.6,56.56 143.06,60.11 143.06,64.91 141.67,66.3 141.67,82.94 140.82,83.79 140.32,84.54 140.32,84.54 v3(140.32,85.11)
  IN1 w0.127: v3(93.48,26.69) 93.48,27.08 94.45,28.05 96.97,28.05 97.57,28.65 103.91,28.65 104.5,28.05 106.04,28.05 106.95,27.14 114.01,27.14 114.12,27.25 117.98,27.25 118.79,28.06 120.67,28.06 121.88,26.86 126.9,26.86 127.35,27.31 128.27,27.31 128.4,27.18 134.33,27.18 135.16,28.01 v3(136.25,28.01) ; v3(140.32,85.11) 140.44,85.24 141.69,85.24 142.04,84.89 144.48,84.89 146.4,86.81 156,86.81 156.77,86.04 161.38,86.04 165.13,89.78 171.76,89.78 173.89,87.65 176.51,87.65 177.91,89.05 177.91,90.53 180.82,93.44 186.91,93.44 191.16,97.68 191.16,99.5 190.61,100.05 189.2,100.05 188.85,100.4 v3(187.46,100.4)
  IN2 w0.254: v3(187.46,100.4) 193.55,100.4 195.88,102.73 195.88,111.65 194.69,112.85 193.15,112.85 v3(191.8,114.19)
  BOTTOM w0.102: v3(136.25,28.01) 135.95,28.32 135.95,37.73 136.94,38.72 136.94,41.2 137.7,41.96 137.7,42.46 142.82,47.58 142.82,49.75 v3(145.06,51.99) ; v3(93.48,26.69) 93.48,25.74 DC4.1
  BOTTOM w0.254: PU301.9 190.79,115.2 v3(191.8,114.19) PR304.2 ; v3(187.46,100.4) PR310.2
SPOK_5V: length 2.6
  BOTTOM w0.102: v1(188.58,102.02) PR310.1
  BOTTOM w0.203: PU302.4 186.51,102.68 187.16,102.02 PR310.1
SRN: length 3.3
  BOTTOM w0.102: v1(198.18,53.41) 197.94,53.17 PRB14.1
  BOTTOM w0.254: PRB14.1 196.25,53.74 PUB1.12
SRN_R: length 34.4
  TOP w0.102: v3(196.83,52.47) v2(197.58,52.47)
  IN1 w0.254: v3(196.83,52.47) 196.2,53.11 193.71,53.11 192.25,54.57 191.78,54.57 185.45,60.89 180.55,60.89 177.51,57.86 174,57.86 173.8,58.06 172.41,58.06 v3(172.22,58.25)
  BOTTOM w0.203: v3(172.22,58.25) 172.24,58.27 PRB11.3
  BOTTOM w0.254: v3(196.83,52.47) 196.83,51.79 PRB14.2 196.66,51.62 PCB20.2 198.32,50.84 PCB18.1
SRP: length 3
  BOTTOM w0.102: v1(194.37,53) 194.54,53.17 PRB13.1
  BOTTOM w0.254: PRB13.1 195.75,53.33 PUB1.13
SRP_R: length 33.8
  TOP w0.102: v2(195.56,53.18) v3(195.56,52.47)
  IN1 w0.254: v3(172.19,57.5) 172.37,57.68 173.64,57.68 173.85,57.47 177.67,57.47 180.7,60.51 185.29,60.51 191.61,54.19 192.1,54.19 194.32,51.96 195.05,51.96 v3(195.56,52.47)
  BOTTOM w0.203: v3(172.19,57.5) 171.83,57.87 171.83,58.01 171.56,58.27 171.18,58.27
  BOTTOM w0.254: v3(195.56,52.47) 195.56,51.82 PRB13.2 195.75,51.63 PCB20.1 194.33,50.84 PCB17.1
SS_NVVDD: length 4
  TOP w0.102: PRV31.2 118.3,135.87 v1(117.8,135.38)
  TOP w0.203: PUV1.11 119.8,136.62 119.24,137.18 118.98,137.18
  TOP w0.254: PRV31.2 PRV29.1 118.37,137.18 118.98,137.18
SSD1_IF: length 67.9
  TOP w0.102: v3(175.03,40.79) v1(175.03,41.69)
  IN1 w0.076: 129.68,41.68 127.62,41.68 127.05,41.1 126.35,41.1 125.46,41.99 122.7,41.99 121.84,41.13 121.84,40.49 v3(121.48,40.13)
  IN1 w0.127: 129.68,41.68 130.52,41.68 131.55,40.65 133.3,40.65 135.52,42.86 149.33,42.86 149.66,42.53 152.36,42.53 153.77,41.12 159.52,41.12 159.7,40.94 160.95,40.94 161.13,40.94 161.15,40.93 163.37,40.93 163.92,40.38 165.65,40.38 166.13,40.86 169.19,40.86 169.57,41.23 171.69,41.23 172.63,40.29 174.53,40.29 v3(175.03,40.79)
  BOTTOM w0.076: v3(121.48,40.13) 121.41,40.13 121.13,40.41 121.13,40.72 120.58,41.28 120.58,41.9 UC1.CP10
  BOTTOM w0.102: v3(175.03,40.79) 176.57,42.33 QS1.1 178.33,42.95 RS21.1
SSD_PDET: length 36.8
  TOP w0.102: v1(191.66,42.57) 190.97,41.88 v3(190.97,40.59)
  BOTTOM w0.102: JSSD.61 199.33,36.52 199.95,37.08 200.29,37.08 201.28,38.07 201.28,39.09 200.22,40.14 200.22,40.66 199.78,41.1 191.49,41.1 v3(190.97,40.59) 190.47,40.09 185.02,40.09 184.6,40.51 180.41,40.51 179,39.1 CS16.2 178.79,39.68 178.98,39.87 QS1.2 178.98,42.22 180.16,43.4 RS22.2
STRAP0: length 6.1
  TOP w0.102: v2(153.28,93.49) 153.6,93.17 v3(153.84,93.17)
  BOTTOM w0.102: UV1.D1 153.5,93.51 v3(153.84,93.17) 154.27,92.74 154.27,90.62 RV383.1 RV384.2
STRAP1: length 8
  TOP w0.102: v2(151.98,92.4) 152.23,92.65 v3(153.34,92.65)
  BOTTOM w0.102: RV51.2 RV390.1 152.59,90.62 152.59,91.52 153.34,92.27 v3(153.34,92.65) 153.09,92.91 153.09,94.47 153.5,94.88 UV1.D2
STRAP2: length 10.4
  TOP w0.102: v3(155.64,92.4) 156.17,92.4 v2(156.4,92.17)
  BOTTOM w0.102: RV382.2 RV388.1 156.1,90.62 156.1,91.95 v3(155.64,92.4) 154.7,93.34 154.7,95.3 154.5,95.5 154.14,95.5 153.9,95.74 153.9,96.06 153.66,96.3 153.05,96.3 UV1.E4
STRAP3: length 8
  BOTTOM w0.102: RV389.2 RV387.1 151.6,90.7 151.6,91.84 151.94,92.18 v1(152.66,92.18) 152.86,92.38 152.86,94.72 153.06,94.92 153.06,95.49 UV1.E3
STRAP4: length 8.6
  TOP w0.102: v2(155.03,93.49) 154.72,93.19 v3(154.72,92.4)
  BOTTOM w0.102: RV61.2 RV385.1 155.18,90.62 155.18,91.95 v3(154.72,92.4) 154.72,92.92 153.9,93.74 153.9,95.3 153.5,95.7 UV1.D3
STRAPREF0: length 5.3
  TOP w0.102: v1(153.99,101.7) 153.38,101.09 RV380.1 RV2751.2 152.11,101.09 151.78,100.76 151.78,99.59 151.37,99.18 v3(151.37,98.8)
  BOTTOM w0.102: v3(151.37,98.8) 151.77,98.4 UV1.F6
SUSACK#: length 100.2
  TOP w0.076: v1(96.49,42.4) 96.74,42.15 v3(97.1,42.15) 97.61,42.65 RC110.2
  IN1 w0.127: v3(97.1,42.15) 96.29,42.15 95.93,41.79 95.93,41.21 94.79,40.06 94.79,38.69 94.47,38.37 94.47,36.48 94.8,36.15 96.89,36.15 99.29,33.74 100.22,33.74 100.8,33.17 102,33.17 102.73,33.9 104.48,33.9 106.26,32.11 107.51,32.11 107.7,32.31 110.66,32.31 110.79,32.44 113.82,32.44 114.07,32.7 115.55,32.7 115.63,32.77 117.13,32.77 117.74,33.39 120.16,33.39 120.97,32.57 126.2,32.57 126.66,32.12 130.88,32.12 131.16,32.41 135.97,32.41 136.05,32.32 137.65,32.32 137.81,32.47 138.68,32.47 139.34,31.81 143.58,31.81 143.98,31.41 145.4,31.41 145.59,31.6 147.47,31.6 147.98,31.09 148.31,31.09 148.75,30.66 150.67,30.66 151.05,30.28 153.88,30.28 154.39,29.76 158.65,29.76 160.71,31.82 162.21,31.82 162.96,32.57 v3(162.96,33.24)
  BOTTOM w0.102: UK1.15 160.17,46.71 160.27,46.61 160.27,44.56 161.13,43.7 161.13,43.11 160.69,42.67 160.69,42.33 161.81,41.22 161.81,37.71 161.38,37.29 161.38,35.34 162.96,33.77 v3(162.96,33.24)
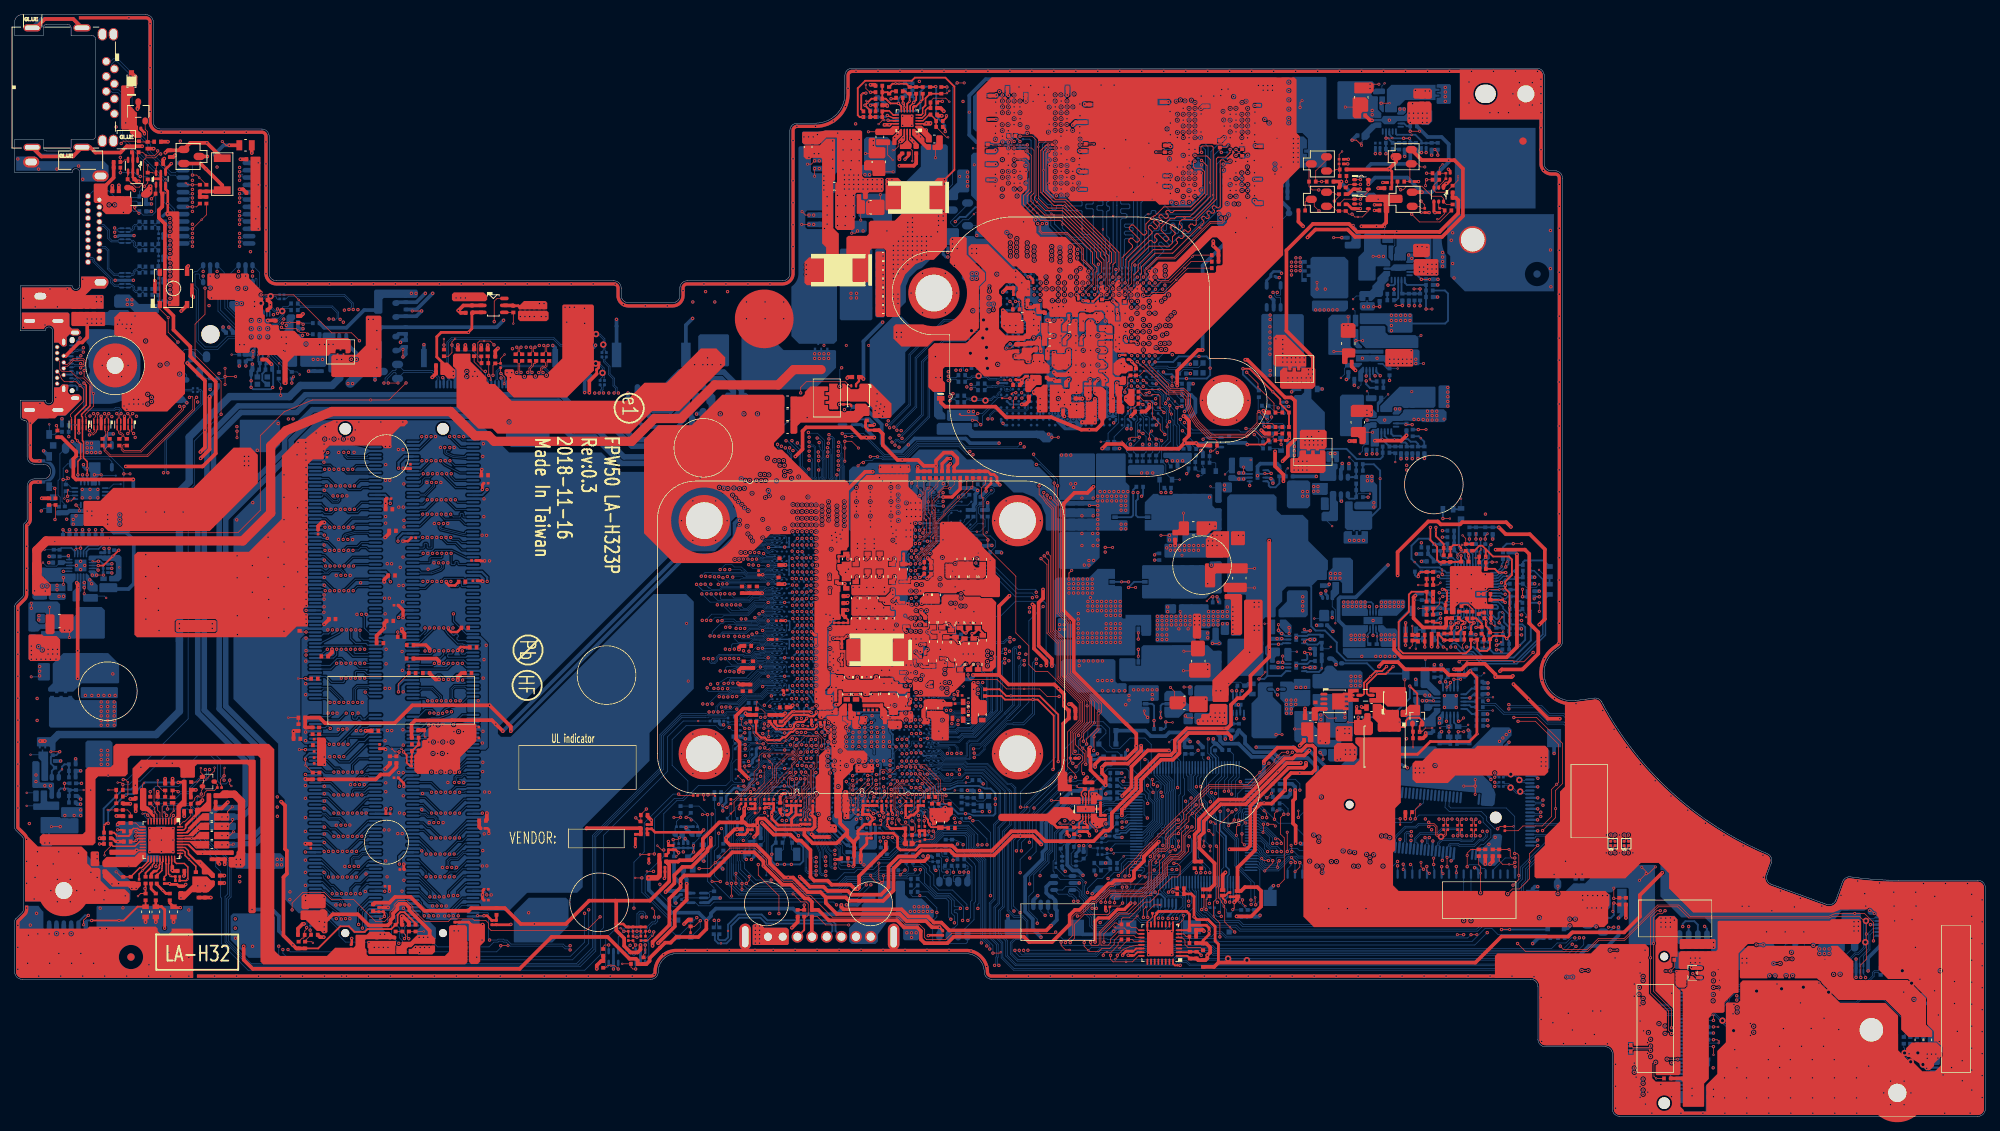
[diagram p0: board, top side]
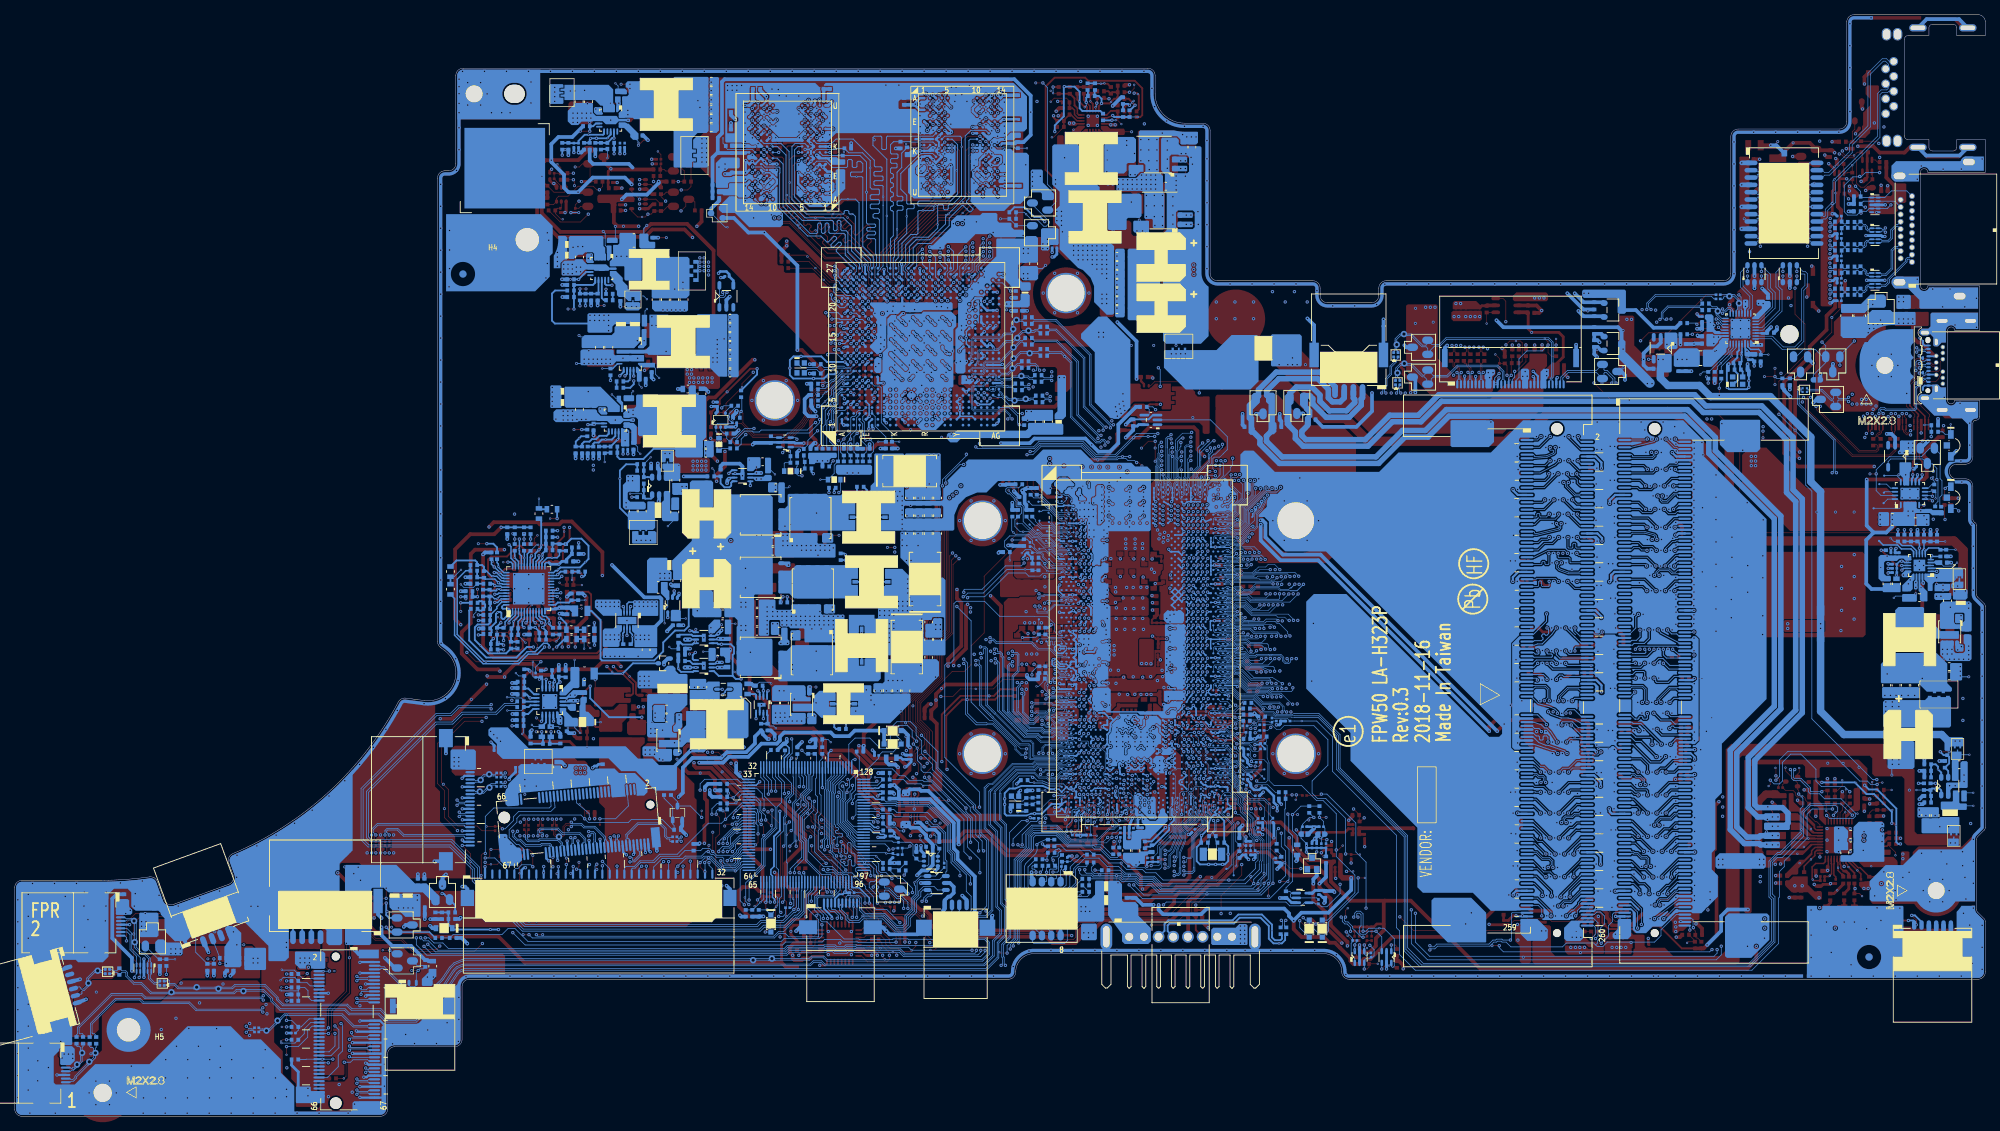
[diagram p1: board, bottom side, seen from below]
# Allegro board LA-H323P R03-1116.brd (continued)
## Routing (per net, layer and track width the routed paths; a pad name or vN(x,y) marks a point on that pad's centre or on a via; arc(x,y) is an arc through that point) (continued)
SUSACK#_R: length 13.2
  TOP w0.076: v3(106.13,49.7) 105.98,49.55 101.91,49.55 101.48,49.12 v1(101.48,48.62) 101.48,47.67 100.82,47.01 100.82,45.92 98.14,43.24 RC110.1
  BOTTOM w0.076: UC1.BY32 106.31,49.88 v3(106.13,49.7)
SUSCLK: length 153.4
  IN2 w0.127: v3(225.03,11.31) 224.7,11.31 223.54,12.48 223.54,18.6 222.13,20.01 217.98,20.01 216.89,21.1 212.28,21.1 209.33,24.05 208.23,24.05 207.53,24.75 204.39,24.75 203.69,24.05 164.17,24.05 163.42,24.8 152.24,24.8 150.69,26.35 148.81,26.35 148.19,26.97 146.58,26.97 145.27,28.28 144.81,28.28 141.25,31.83 140.03,31.83 139.11,32.75 137.62,32.75 137.4,32.53 136.85,32.53 136.65,32.74 131.15,32.74 130.71,32.29 127.46,32.29 126.7,33.05 120.89,33.05 120.64,32.8 117.72,32.8 117.38,32.46 116.89,32.46 116.11,31.69 v3(116.11,31.58)
  BOTTOM w0.102: v3(116.11,31.58) 116.11,31.57 114.74,30.2 98.72,30.2 v3(97.13,31.8) 97.13,35.12 97.01,35.24 RC100.2 96.16,35.24 CC297.2 95.99,35.63 RC460.1 ; JWLAN.42 225.83,8.8 225.03,9.6 v3(225.03,11.31)
SUSCLK_R: length 28.2
  IN2 w0.076: v3(106.69,52.38) 106.69,52.23 107.05,51.87 109.42,51.87 109.62,51.66 109.62,51.37 109.62,51.37 109.62,50.75 109.62,50.75 109.62,50.4 109.81,50.21 109.81,49.4 109.27,48.85 109.27,47.54 108.77,47.04 108.77,46.24 107.97,45.44 103.57,45.44 101.07,42.95 101.07,41.42 100.47,40.82 98.7,40.82 98.51,40.63
  IN2 w0.127: 98.51,40.63 97.14,39.26 v3(96.38,39.26)
  BOTTOM w0.076: UC1.BT32 v3(106.69,52.38) ; RC460.2 96.63,39.01 v3(96.38,39.26)
SUSP#: length 336.4
  TOP w0.102: v3(174.21,49.68) 173.81,49.27 173.02,49.27 168.53,44.79 163.13,44.79 161.5,43.16 161.5,42.26 v2(160.58,41.34) 160.1,40.86 160.1,40.27 158.69,38.86 v3(158.69,38.59) 158.6,38.5 158.04,38.5 157.42,37.88 157.42,36.62 156.91,36.11 156.02,36.11 155.48,35.57 155.48,35.19 154.97,34.67 154.97,32.28 153.56,30.87 149.21,30.87 147.45,29.1 147.07,29.1 145.29,27.33 v3(144.91,27.33) ; RC492.1 90.72,43.77 v3(90.53,43.96) ; UC6.5 146.43,40.01 v3(147.49,38.95)
  IN1 w0.127: v3(189.78,51.52) 188.35,51.52 185.17,48.34 177.77,48.34 176.77,49.35 174.54,49.35 v3(174.21,49.68) ; v3(147.49,38.95) 147.87,38.95 148.32,39.39 150.4,39.39 150.84,38.95 151.8,38.95 152.3,38.44 158.54,38.44 v3(158.69,38.59) ; v3(144.91,27.33) 144.91,27.39 144.46,27.85 143.84,27.85 143.58,28.11 138.73,28.11 137.9,28.94 137.33,28.94 137.08,29.19 134.79,29.19 134.11,28.51 131.9,28.51 131.59,28.82 125.22,28.82 124.77,29.27 118.57,29.27 117.74,28.44 113.77,28.44 113.48,28.15 107.37,28.15 106.46,29.06 104.93,29.06 104.29,29.7 97.16,29.7 96.53,29.06 93.46,29.06 92.78,28.38 89.61,28.38 89.37,28.62 84.65,28.62 v3(84.44,28.41) 84.33,28.3 82.72,28.3 79.14,24.72 75.14,24.72 74.13,23.71 65.83,23.71 65.24,23.11 57.73,23.11 56.84,24 54.98,24 54.73,24.25 54.73,24.63 54.12,25.24 51.8,25.24 50.83,24.28 48.04,24.28 47.12,23.35 41.23,23.35 38.67,25.91 37.9,25.91 34.25,29.56 34.25,38.68 32.42,40.5 32.42,45.22 33.07,45.86 33.07,66.93 16.98,83.01 12.25,83.01 10.37,81.13 8.87,81.13 8.38,80.64 8.38,80.04 v3(8.36,80.03)
  IN2 w0.127: v3(189.78,51.52) 189.94,51.67 196.95,51.67 197.49,52.22 197.49,59 197.09,59.41 197.09,61.48 198.57,62.96 198.57,67.24 195.52,70.29 192.05,70.29 191.82,70.06 191.05,70.06 190.1,71.01 186.16,71.01 185.72,70.57 v3(185.72,69.55) v3(184.72,69.55)
  BOTTOM w0.102: UK1.116 151.69,41.17 151.14,40.62 150.8,40.62 150.57,40.85 RK27.1 CK10.1 149.8,39.47 148.57,39.47 148.05,38.95 v3(147.49,38.95) ; v3(84.44,28.41) 84.44,34.68 85.83,36.08 85.83,40.03 89.77,43.96 v3(90.53,43.96)
  BOTTOM w0.203: Q21.5 185.61,69.44 v3(185.72,69.55) ; v3(184.72,69.55) 184.81,69.46 Q21.3
  BOTTOM w0.254: PRM11.1 v3(8.36,80.03)
SYS_PWROK: length 58.7
  TOP w0.089: v3(120.58,40.43) 120.58,40.43 120.58,40.11 120.91,39.77 121.85,39.77 CC301.2
  TOP w0.102: v3(163.06,40.16) 163.44,40.16 v1(163.71,39.9)
  IN1 w0.076: 129.68,39.41 126.26,39.41 126,39.67 122.86,39.67 122.64,39.45 121.2,39.45 120.8,39.85 120.8,40.21 v3(120.58,40.43)
  IN1 w0.127: v3(163.06,40.17) 162.81,40.42 159.25,40.42 158.86,40.03 155.35,40.03 155.23,39.9 153.74,39.9 151.62,42.02 147.73,42.02 147.4,42.35 145.47,42.35 144.59,41.47 139.66,41.47 139.36,41.17 134.91,41.17 133.14,39.41 129.68,39.41
  BOTTOM w0.076: UC1.CR10 120.32,40.7 120.58,40.45 v3(120.58,40.43)
  BOTTOM w0.102: v3(163.06,40.16) 163.43,39.8 163.43,34.64 163.37,34.57 UK1.74
SYS_RESET#: length 8.8
  TOP w0.089: RC959.2 123,37.52 122.7,37.23 CLRP3.1 122.39,37.92 122.36,37.94 CC302.1 122.79,38.81 122.79,39.88 v3(122.36,40.32)
  BOTTOM w0.076: UC1.CN10 120.78,42.26 121.09,42.26 121.31,42.48 121.74,42.48 121.94,42.27 121.94,41.51 122.31,41.14 122.31,40.36 v3(122.36,40.32)
SYSON: length 253.8
  TOP w0.102: v3(145.23,38.28) 144.68,38.28 RC142.1 ; v3(146.69,23.74) 146.69,23.5 146.86,23.34 147.72,23.34 147.87,23.49 147.87,25.13 150.57,27.83 151.67,27.83 152.76,28.92 v3(152.76,29.1) ; v3(6.79,45.44) v2(6.79,44.64)
  IN1 w0.127: v3(6.79,45.44) 8.26,45.44 8.72,44.98 10.41,44.98 11.83,46.4 17.19,46.4 18.8,44.79 23.99,44.79 24.3,45.11 28.95,45.11 31.36,42.69 31.36,40.12 33.19,38.29 33.19,29.18 37.48,24.89 38.25,24.89 41.05,22.09 73.95,22.09 75.56,23.71 79.65,23.71 82.64,26.69 91.78,26.69 92.52,25.95 96.41,25.95 98.6,28.14 103.14,28.14 104.1,27.18 106.19,27.18 106.74,26.63 114.22,26.63 114.33,26.74 118.19,26.74 119.01,27.55 120.46,27.55 121.66,26.35 126.14,26.35 127.26,25.23 140.14,25.23 142.23,23.13 146.45,23.13 146.69,23.38 v3(146.69,23.74) ; v3(160.17,38.15) 160.14,38.17 157.67,38.17 157.65,38.18 152.2,38.18 151.69,38.69 150.73,38.69 150.29,39.14 148.48,39.14 147.85,38.5 147.18,38.5 146.95,38.73 145.69,38.73 v3(145.23,38.28)
  IN2 w0.254: v3(6.79,45.44) 6.79,49.02 9.82,52.06 15.6,52.06 16.94,53.39 16.94,77.14 15.19,78.89 12.17,78.89 v3(11.03,80.03)
  BOTTOM w0.102: v3(152.76,29.1) 152.76,29.99 153.33,30.57 153.83,30.57 153.88,30.51 CC360.1 154.25,30.59 154.58,30.92 154.83,30.92 154.97,31.05 UK1.95 154.97,32.82 155.16,33.01 155.67,33.01 155.89,33.23 156.35,33.23 157.22,34.11 158.44,34.11 160.44,36.11 160.44,37.88 v3(160.17,38.15)
  BOTTOM w0.254: PR2502.1 v3(6.79,45.44) ; PRM10.1 v3(11.03,80.03)
TBTB_SBU1: length 11.9
  TOP w0.102: D33.9 D33.1 9.75,95.34 9.62,95.47 9.62,95.76 10.72,96.87 v2(10.72,98.62) 10.55,98.8 10.55,99.87 9.47,100.95 v3(9.47,101.75)
  BOTTOM w0.102: v3(9.47,101.75) 9.47,102.91 9.28,103.11 8.83,103.11 8.75,103.02 8.26,103.02 8.08,103.2 JTC1.A8
TBTB_SBU2: length 10.8
  TOP w0.102: JTC1.B8 6.1,101.29 6.38,100.62 6.78,100.22 8.38,100.22 v2(8.91,99.69) 9.38,99.22 9.38,97.53 7.62,95.77 7.62,95.47 7.75,95.34 D33.5 D33.6
TON_DDR: length 4.7
  BOTTOM w0.102: PRM7.2 12.47,78.43 v1(12.92,78.89)
  BOTTOM w0.203: PUM1.9 9.39,77.17 10.09,77.87 11.36,77.87 PRM7.2
TON_NVVDD: length 2.3
  TOP w0.203: PUV1.9 121.3,138.09 v3(121.15,138.23)
  TOP w0.254: PRV15.2 121.09,138.3 v3(121.15,138.23)
  BOTTOM w0.102: v3(121.15,138.23) 121.15,137.85 v1(121.34,137.66)
TP_CLK: length 29.6
  TOP w0.102: v3(157.91,30.6) 158.26,30.6 RK12.1
  IN2 w0.127: v3(151.04,31.27) 151.18,31.42 151.18,31.75 151.58,32.15 154.29,32.15 155.06,31.38 156.1,31.38 156.45,31.03 157.72,31.03 157.91,30.84 v3(157.91,30.6) ; v3(147.49,28.37) 147.59,28.47 149.21,28.47 149.96,27.72 155.88,27.72 156.07,27.53 156.07,27.14 v3(155.95,27.03)
  BOTTOM w0.102: v3(155.95,27.03) 156.1,27.18 156.1,27.49 156.83,28.21 157.25,28.21 157.35,28.32 JTP1.3 ; v3(151.04,31.27) 151.04,30.68 150.4,30.04 DM5.3 150.12,30.77 150.02,30.87 149.59,30.87 148.43,29.71 147.8,29.71 147.49,29.41 v3(147.49,28.37) ; UK1.87 158.17,30.86 v3(157.91,30.6)
TP_DATA: length 31.2
  TOP w0.102: v3(157.32,30.6) 157.33,30.6 157.84,31.11 RK13.1
  IN2 w0.127: v3(146.91,28.37) 146.91,28.38 147.38,28.85 147.76,28.85 147.83,28.78 149.34,28.78 150.1,28.02 156,28.02 156.37,27.66 156.37,27.2 v3(156.54,27.03) ; v3(157.32,30.6) 157.19,30.73 156.32,30.73 155.98,31.07 154.94,31.07 154.16,31.85 151.71,31.85 151.49,31.62 151.49,31.42 v3(151.63,31.27)
  BOTTOM w0.102: v3(156.54,27.03) 156.39,27.17 156.39,27.4 156.95,27.96 157.46,27.96 157.85,28.35 JTP1.2 ; v3(151.63,31.27) 151.63,31.38 151.04,31.97 DM5.2 150.12,31.25 150.02,31.15 149.47,31.15 148.32,29.99 147.68,29.99 146.91,29.22 v3(146.91,28.37) ; UK1.88 157.76,31.04 v3(157.32,30.6)
TP_ENABLE: length 40.3
  BOTTOM w0.102: JTP1.8 154.85,29.81 154.74,29.93 153.71,29.93 153.52,29.73 153.52,28.11 152.86,27.45 150.14,27.45 148.46,25.78 147.58,25.78 147.09,26.27 147.09,27.29 146.23,28.16 146.23,29.65 145.65,30.22 145.65,31.96 145.29,32.33 142.56,32.33 142.1,32.78 DT2.6 141.73,33.34 141.59,33.48 141.59,34.82 141.77,35 141.77,38.69 142.85,39.77 143.41,39.77 144.52,40.88 v1(146.54,40.88) 148.63,40.88 149.06,41.31 150.63,41.31 150.89,41.57 UK1.117
TP_L_BTN: length 21.4
  TOP w0.102: v1(156.19,28.85) 155.37,28.85 154.5,27.98 v3(154.5,27.15)
  IN1 w0.127: v3(141.35,27.4) 141.77,26.98 143.58,26.98 144.87,25.7 148.96,25.7 149.48,26.22 154.2,26.22 154.5,26.52 v3(154.5,27.15)
  BOTTOM w0.102: JTP2.2 140.9,27.85 v3(141.35,27.4) ; JTP1.9 154.35,27.29 v3(154.5,27.15)
TP_R_BTN: length 20.1
  TOP w0.102: v3(153.91,27.15) 153.91,28.21 v1(154.29,28.6)
  IN1 w0.127: v3(153.91,27.15) 153.23,26.47 149.38,26.47 148.85,25.95 144.97,25.95 143.52,27.4 141.94,27.4 141.52,27.82 140.91,27.82 v3(140.5,27.41)
  BOTTOM w0.102: v3(140.5,27.41) 139.9,28.01 JTP2.3 ; JTP1.10 153.85,27.2 v3(153.91,27.15)
TP_SMBCLK: length 98.4
  TOP w0.102: RC81.1 85.75,22.07 85.98,22.3 v1(85.98,22.7) v3(85.98,23.37)
  IN2 w0.127: v3(144.98,29.34) 144.79,29.53 144.79,29.71 142.85,31.65 142.73,31.65 141.72,32.66 141.18,32.66 139.87,33.97 130.86,33.97 128.77,36.05 127.95,36.05 127.71,36.29 123.58,36.29 122.26,34.97 121.64,34.56 121.33,34.43 120.88,34.13 120.24,33.48 115.87,33.48 115.01,34.34 114.92,34.56 112.45,37.03 111.26,37.03 110.33,36.1 109.03,36.1 108.51,35.57 108.51,34.2 107.7,33.4 107.7,30.03 104.75,27.07 102.65,27.07 102.24,27.48 98.14,27.48 95.16,24.51 88.35,24.51 88.25,24.4 87.01,24.4 v3(85.98,23.37)
  BOTTOM w0.102: QC7.6 v3(85.98,23.37) 85.98,23.53 85.68,23.82 R5272.2 ; v3(144.98,29.34) 144.75,29.57 144.75,29.8 144.23,30.32 143.89,30.32 143.7,30.52 143.7,30.69 143.89,30.88 DT2.3 144.87,30.88 145.14,30.61 145.14,30.01 145.72,29.44 145.72,27.88 146.58,27.02 146.58,25.97 147.28,25.27 148.67,25.27 150.35,26.94 153,26.94 153.49,26.46 154.95,26.46 155.37,26.88 155.37,27.26 156.24,28.13 156.24,28.45 156.35,28.56 JTP1.5
TP_SMBDATA: length 107.1
  TOP w0.102: v3(84.68,20.1) 84.3,20.1 84.03,20.37 RC82.1 v1(82.84,20.81)
  IN2 w0.127: v3(144.39,29.34) 144.48,29.43 144.48,29.59 142.73,31.34 142.6,31.34 141.59,32.35 141.05,32.35 139.75,33.66 130.73,33.66 128.65,35.75 127.82,35.75 127.58,35.99 123.71,35.99 122.46,34.74 121.78,34.29 121.48,34.16 121.08,33.89 120.36,33.18 115.74,33.18 114.75,34.17 114.66,34.39 112.33,36.72 111.39,36.72 110.45,35.79 109.16,35.79 108.82,35.45 108.82,34.08 108.01,33.27 108.01,29.9 104.87,26.77 102.52,26.77 102.11,27.18 98.26,27.18 95.28,24.2 88.48,24.2 88.37,24.1 87.1,24.1 86.47,23.46 86.47,23.26 86.09,22.88 84.3,22.88 83.92,23.26 v3(83.92,23.33)
  BOTTOM w0.102: v3(83.92,23.33) 83.35,22.76 83.35,21.89 83.52,21.71 R5271.2 83.98,21.5 84.5,21.5 84.68,21.32 QC7.3 v3(84.68,20.1) ; v3(144.39,29.34) 144.47,29.42 144.47,29.69 144.12,30.04 143.78,30.04 143.51,30.31 142.31,30.31 DT2.4 142.86,30.88 143.34,31.36 144.79,31.36 145.42,30.73 145.42,30.13 146,29.55 146,28 146.86,27.13 146.86,26.08 147.4,25.55 148.56,25.55 150.24,27.22 153.12,27.22 153.6,26.74 154.83,26.74 155.09,27 155.09,27.38 155.96,28.25 155.96,28.45 155.85,28.56 JTP1.6
TPM_GPIO: length 4.3
  TOP w0.102: UT1.6 159.18,24.39 159.57,24 159.57,23.44 159.99,23.02 161.69,23.02 RT10.1
TPM_PP: length 2.5
  TOP w0.102: UT1.7 159.39,24.89 159.75,24.53 RT12.1 RT35.2
TPM_SERIRQ: length 4.1
  TOP w0.102: v1(149.97,25.86) 150.15,25.69 151.3,25.69 R5202.2 152.89,25.17 153.16,24.89 UT1.18
TS_GPIO: length 11.8
  TOP w0.102: v1(60.05,106.09) 59.62,105.66 v3(59.62,105.23) 59.62,104.19 59.14,103.7 R5187.2
  BOTTOM w0.102: JEDP.17 64,100.38 63.58,100.79 63.58,103.35 62.51,104.43 60.42,104.43 v3(59.62,105.23)
TS_GPIO_EC: length 164.5
  TOP w0.102: R5187.1 v3(58.53,105.23) v1(58.53,106.07) ; v3(144.71,47.69) 145.59,48.57 145.59,49.07 145.26,49.39 144.35,49.39 144.18,49.56 144.18,52.4 145.61,53.84 145.61,56.58 142.37,59.83 142.37,60.02 142.37,64.63 140.98,66.02 140.98,75.87 v3(140.38,76.47)
  IN1 w0.127: v3(159.66,42.98) 159.53,42.98 159.53,42.98 154.77,42.98 154.38,43.38 153.49,43.38 151.88,44.99 151.16,44.99 149.22,46.94 146.79,46.94 146.13,47.6 144.79,47.6 v3(144.71,47.69) ; v3(58.53,105.23) 59.81,106.51 96.74,106.51 100.27,102.98 104.61,102.98 105.77,101.81 112.01,101.81 112.41,101.4 113.98,101.4 115.96,99.42 118.85,99.42 130.37,87.9 135.89,87.9 140.83,82.96 140.83,78.89 140.38,78.44 v3(140.38,76.47)
  BOTTOM w0.102: UK1.89 157.37,32.87 157.5,33 158.66,33 160.67,35.01 160.67,37.67 161.06,38.07 161.06,40.46 159.73,41.79 159.73,42.91 v3(159.66,42.98)
TSEN_CORE: length 43.9
  TOP w0.102: v1(162.56,70.31) 163.13,70.89 v3(163.36,70.89)
  IN2 w0.254: v3(195.82,67.33) 195.82,68.35 194.95,69.21 193.89,69.21 193.4,68.73 193.4,66.82 193.15,66.57 188.61,66.57 188.02,67.15 179.09,67.15 178.2,68.04 175.2,68.04 171.34,71.9 163.81,71.9 163.36,71.44 v3(163.36,70.89)
  BOTTOM w0.203: v3(195.82,67.33) 195.82,67.8 196.22,68.21 196.59,68.21 196.81,68.42 PUZ1.11
  BOTTOM w0.254: v3(195.82,67.33) 195.82,67.15 PRZ52.2 ; v3(163.36,70.89) PHZ2.2
TSEN_CORE_R: length 38.1
  TOP w0.102: v1(164.09,70.17) 163.94,70.33 v3(163.94,70.89)
  TOP w0.254: v3(194.42,67.33) 193.58,67.33 PRZ70.1 PRZ67.2
  IN2 w0.254: v3(194.42,67.33) 194.42,67.08 193.53,66.19 188.45,66.19 187.87,66.77 178.89,66.77 178,67.66 175.04,67.66 171.18,71.52 164.19,71.52 163.94,71.27 v3(163.94,70.89)
  BOTTOM w0.254: PHZ2.1 164.27,70.56 v3(163.94,70.89) ; PRZ51.1 v3(194.42,67.33)
TSEN_GT: length 54.6
  TOP w0.102: v3(194.65,73.92) 194.62,73.95 v1(194.62,74.59)
  IN2 w0.127: v3(157.67,85.11) 157.67,84.76 158.93,83.5 168.47,83.5 169.4,82.57 174.32,82.57 176.25,80.64 189.63,80.64 192,83.01 195.41,83.01 196.07,82.36 196.07,79.14 194.25,77.32 194.25,74.32 v3(194.65,73.92)
  BOTTOM w0.203: v3(194.65,73.92) 194.79,73.78 PUZ1.23
  BOTTOM w0.254: PHZ3.1 v3(157.67,85.11) ; v3(194.65,73.92) 194.25,74.32 PRZ66.1
TSEN_GT_R: length 56.6
  TOP w0.254: PRZ71.1 PRZ68.2 191.69,74.26 v1(191.58,74.15) 191.38,73.96 v3(191.38,73.64)
  IN2 w0.127: v3(191.38,73.64) 193.25,75.51 193.25,76.96 195.69,79.4 195.69,82.38 195.31,82.76 192.11,82.76 189.73,80.39 176.14,80.39 174.21,82.32 169.3,82.32 168.37,83.24 158.82,83.24 v3(156.95,85.11)
  BOTTOM w0.254: PHZ3.2 156.95,85.54 v3(156.95,85.11) ; v3(191.38,73.64) 191.12,73.64 190.91,73.85 PRZ69.2
UART_2_CRXD_DTXD: length 133.4
  TOP w0.102: v3(231.63,17.59) v1(232.34,17.59)
  IN2 w0.127: v3(131.33,37.04) 131.33,37.38 131.67,37.72 133.4,37.72 133.73,37.4 137.76,37.4 138.63,36.52 138.82,36.52 139.41,35.92 141.93,35.92 144.07,33.78 144.25,33.71 145.5,32.46 146.04,32.46 146.76,31.73 147.92,31.73 148.54,31.11 150.82,30.17 153.32,30.17 153.99,29.49 158.36,29.49 158.95,30.08 162.83,30.08 163.57,29.34 163.57,28.87 163.81,28.63 163.81,27.28 165.24,25.85 166.6,25.85 166.93,25.52 196.39,25.52 197.05,26.18 201.32,26.18 201.74,26.6 210.47,26.6 211.69,25.38 223.55,25.38 224.4,24.53 228.05,24.53 232.06,20.52 232.06,18.02 v3(231.63,17.59)
  BOTTOM w0.076: 121.01,37.82 119.5,39.33 118.85,39.33 118.52,39.66 118.52,39.93 119,40.4 119,41.48 UC1.CR12
  BOTTOM w0.102: RW11.2 v3(231.63,17.59) ; 121.01,37.82 124.67,37.82 126.58,39.72 130.01,39.72 131.33,38.41 v3(131.33,37.04)
UART_2_CTXD_DRXD: length 138.3
  TOP w0.102: v3(231.63,12.2) v1(232.28,12.2)
  IN2 w0.127: v3(131.91,37.05) 131.91,37.05 131.91,37.2 132.17,37.47 133.3,37.47 133.63,37.14 137.65,37.14 138.53,36.27 138.71,36.27 139.31,35.67 141.82,35.67 143.92,33.57 144.11,33.49 145.4,32.2 145.94,32.2 146.66,31.48 147.81,31.48 148.4,30.9 150.77,29.92 153.21,29.92 153.89,29.24 158.49,29.24 159.08,29.83 162.72,29.83 163.32,29.23 163.32,28.77 163.56,28.53 163.56,27.17 165.13,25.6 166.49,25.6 166.82,25.27 196.49,25.27 197.13,25.9 201.4,25.9 201.84,26.35 208.24,26.35 209.02,25.57 210.65,25.57 212.29,23.93 223.56,23.93 223.97,23.52 226.29,23.52 227.07,22.74 227.07,19.42 229.81,16.67 229.81,13.19 230.8,12.2 v3(231.63,12.2)
  BOTTOM w0.076: UC1.CP12 118.77,41.9 118.77,41.36 118.83,41.29 118.83,40.47 118.36,40 118.36,39.59 118.78,39.17 119.38,39.17 120.91,37.64 124.75,37.64 126.61,39.5 129.89,39.5 130.91,38.49 130.91,36.86 131.13,36.64 131.5,36.64 v3(131.91,37.05)
  BOTTOM w0.102: RW12.2 v3(231.63,12.2)
UFP: length 14.3
  TOP w0.102: v3(6.61,86.88) 7.17,86.88 v2(7.35,87.05)
  BOTTOM w0.102: UU2.4 13.25,89.33 12.9,89.68 8.52,89.68 QU3.1 7.86,89.02 7.22,89.02 6.61,88.41 v3(6.61,86.88) 6.46,86.72 6.46,83.88 6.84,83.5 RU3.1
UFP#: length 24.3
  TOP w0.102: v3(14.88,87.65) v2(15.73,87.65)
  BOTTOM w0.102: UU1.19 14.23,84.71 14.88,85.35 v3(14.88,87.65) 14.88,88.21 13.1,89.99 8.72,89.99 7.55,91.16 QU3.2 6.17,90.38 6.17,86.99 5.91,86.74 5.91,84.77 6.21,84.48 6.21,83.36 RU2.2
UG1_EN2: length 2.7
  TOP w0.102: v1(67.99,108.16) R5201.2 67.98,109.69 UG1.4
UG_CHG: length 13.4
  TOP w0.102: v3(192.53,56.7) v2(193.44,56.7)
  IN2 w0.762: 190.93,56.54 190.75,56.73 180.13,56.73 179.02,55.61
  vias: v3(178.1,54.76) v3(178.1,54.12) v3(191.94,56.7)
UG_DDR: length 7
  TOP w0.102: v3(9.48,72.17) v2(9.48,71.29)
  IN2 w0.762: 3.75,68.88 4.25,69.37 6.94,69.37 8.85,71.28
  vias: v3(3.31,68.31) v3(3.28,67.72) v3(9.48,72.8)
USB2_COMP: length 7.2
  TOP w0.076: RC119.1 126.35,43.02 126.35,43.9 125.92,44.33 125.92,45.73 v1(125.6,46.05) 123.99,47.66 v3(123.61,47.66)
  BOTTOM w0.203: UC1.CC5 123.42,47.73 v3(123.61,47.66)
USB2_ID: length 10.4
  TOP w0.076: 126.6,44.03 126.23,44.39 126.23,45.89 v1(124.74,47.39) 124.11,48.01 121.9,48.01 v3(121.56,47.67)
  TOP w0.102: RC388.1 126.86,42.64 126.6,42.9 126.6,44.03
  BOTTOM w0.076: v3(121.56,47.67) 121.56,47.45 UC1.CE8
USB2_VBUSSENSE: length 7.8
  TOP w0.076: RC402.1 125.08,42.9 125.22,43.04 125.87,43.04 125.97,43.14 125.97,43.9 125.57,44.29 125.57,44.99 123.93,46.63 123.93,46.97 123.69,47.21 v1(123.26,47.21) v3(122.82,47.65)
  BOTTOM w0.076: UC1.CC6 v3(122.82,47.65)
USB3_CRX_DTX_N1: length 219
  TOP w0.102: v3(11.34,95.87) 11.27,95.8 11.27,95.34 11.29,95.31 D31.4 D31.7 11.29,93.75 11.16,93.62 11.16,93.39 10.74,92.98 10.22,92.98 v3(10.2,92.97)
  IN2 w0.076: 122.24,39.45 122.24,39.47 122.2,39.52 122.2,39.61 122.26,39.68 122.68,39.68 122.88,39.88 122.88,41.47 124.96,43.54 124.96,47.19 123.9,48.25 123.12,48.25 v3(122.92,48.46)
  IN2 w0.127: 122.24,39.45 122.24,39.09 121.97,38.82 121.97,38.25 120.95,37.23 120.52,36.87 119.96,36.65 119.28,35.96 117.58,35.96 115.66,37.88 115.16,37.88 113.2,39.83 110.38,39.83 109.55,39.01 108.57,39.01 107.09,37.54 102.95,37.54 101.52,36.11 101.52,35.14 100.63,34.25 96.25,34.25 93.51,31.5 93.51,30.32 89.7,26.51 73.07,26.51 67.87,21.3 30.54,21.3 28.16,23.68 28.16,27.67 31.89,31.39 31.89,41.52 28.56,44.85 27.03,44.85 23.64,48.24 23.64,88.88 18.57,93.95 11.8,93.95 10.97,93.11 10.35,93.11 v3(10.2,92.97) ; v3(11.34,95.87) 11.34,97.25 7.93,100.65 5.89,100.65 JTC1.B10
  BOTTOM w0.076: UC1.CB5 122.92,48.71 v3(122.92,48.46)
USB3_CRX_DTX_N2: length 225.8
  TOP w0.102: v3(15.43,95.87) 15.62,95.68 15.62,95.29 15.47,95.13 D32.2 D32.8 15.47,93.8 15.67,93.6 15.67,93.4 v3(15.43,93.16)
  IN2 w0.076: v3(121.64,49.47) 121.64,49.17 121.82,48.99 123.12,48.99 123.48,48.64 124.13,48.64 125.33,47.43 125.33,43.33 124.74,42.73 124.74,40.32 123.87,39.45
  IN2 w0.127: v3(15.43,93.16) 15.52,93.07 15.52,92.58 16.79,91.31 18.55,91.31 22.95,86.9 22.95,47.68 29.45,41.19 29.45,30.35 27.48,28.38 27.48,23.4 30.26,20.62 68.15,20.62 73.36,25.82 90.05,25.82 94.32,30.09 94.32,31.23 96.13,33.04 101.03,33.04 102.34,34.35 102.34,35.83 103.36,36.85 107.38,36.85 108.33,37.8 109.4,37.8 110.33,38.73 113.16,38.73 114.7,37.19 115.38,37.19 117.37,35.2 119.49,35.2 120.16,35.87 120.48,36.08 120.9,36.25 121.18,36.44 122.73,37.99 122.73,38.31 123.87,39.45 ; v3(9.36,104.27) 9.67,104.27 9.74,104.34 9.74,104.47 9.87,104.6 10.8,104.6 11.28,105.08 14.59,105.08 17.48,102.19 17.48,101.16 19.16,99.48 19.16,97.43 18.43,96.71 16.11,96.71 15.83,96.43 15.83,96.22 15.49,95.87 v3(15.43,95.87)
  BOTTOM w0.076: UC1.BY8 121.64,49.62 v3(121.64,49.47)
  BOTTOM w0.102: v3(9.36,104.27) 9.18,104.45 8.71,104.45 8.6,104.34 8.17,104.34 8.02,104.2 JTC1.A10
USB3_CRX_DTX_N3: length 141.3
  IN2 w0.076: 126.38,39.45 125.84,40 125.84,47.9 124.82,48.91 123.5,48.91 123.19,49.22 122.66,49.22 122.29,49.59 v3(122.26,49.59)
  IN2 w0.127: v3(208.38,43.15) 217.7,43.15 222.13,38.72 222.13,34.46 219.6,31.93 214.89,31.93 211.6,28.65 205.8,28.65 204.57,27.41 197.26,27.41 196.37,26.52 172.09,26.52 171.59,26.02 167.46,26.02 166.95,26.52 166.12,26.52 164.41,28.24 164.41,29.51 163.41,30.51 158.77,30.51 158.18,29.92 154.31,29.92 153.63,30.6 150.9,30.6 148.78,31.48 148.1,32.16 146.94,32.16 146.54,32.57 146.54,32.77 145.76,33.55 144.31,34.15 142.11,36.35 139.59,36.35 139.04,36.91 139.04,37.32 138.52,37.83 134.01,37.83 133.68,38.16 129.15,38.16 128.79,38.52 127.32,38.52 126.38,39.45
  BOTTOM w0.076: UC1.BY7 v3(122.26,49.59)
  BOTTOM w0.102: JIO.14 207.19,42.95 207.29,42.84 207.3,42.85 208.08,42.85 v3(208.38,43.15)
USB3_CRX_DTX_N4: length 137.1
  IN2 w0.076: v3(122.91,50.52) 123.06,50.37 123.06,50.2 123.27,49.98 124.52,49.98 126.58,47.92 126.58,45.74 127.45,44.86 127.45,43.77 127.41,43.73 127.41,43.71
  IN2 w0.127: 127.41,43.71 127.41,39.87 127.87,39.41 129.39,39.41 129.97,38.84 133.96,38.84 134.29,38.51 140.92,38.51 142.24,37.2 148.21,33.21 149.66,33.21 150.09,33.64 153.41,33.64 155,32.05 156.3,32.05 156.72,31.63 158.23,31.63 158.67,31.2 163.73,31.2 165.22,29.71 166.49,29.71 166.73,29.47 166.73,27.94 167.96,26.72 171.2,26.72 171.7,27.21 196.08,27.21 197.19,28.32 203.97,28.32 205.08,29.42 211.41,29.42 214.61,32.62 219.15,32.62 221.37,34.84 221.37,38.5 218.38,41.49 v3(208.08,41.49)
  BOTTOM w0.076: UC1.BW6 v3(122.91,50.52)
  BOTTOM w0.102: v3(208.08,41.49) 207.9,41.31 207.31,41.31 207.16,41.45 JIO.17
USB3_CRX_DTX_P1: length 219
  TOP w0.102: v3(10.2,93.55) 10.55,93.2 10.65,93.2 10.94,93.48 10.94,93.65 10.79,93.79 D31.6 D31.5 10.79,95.21 11.05,95.47 11.05,95.58 v3(10.75,95.87)
  IN2 w0.076: 121.99,39.45 121.99,39.47 122.03,39.52 122.03,39.68 122.2,39.85 122.61,39.85 122.71,39.95 122.71,41.53 124.79,43.61 124.79,47.13 123.83,48.09 122.63,48.09 v3(122.27,48.46)
  IN2 w0.127: v3(10.75,95.87) 10.75,95.97 11.08,96.3 11.08,97.15 7.83,100.4 6.33,100.4 6.19,100.26 6.19,100.03 6.11,99.95 JTC1.B11 ; v3(10.2,93.55) 10.38,93.37 10.86,93.37 11.7,94.2 18.68,94.2 23.89,88.98 23.89,48.35 27.14,45.11 28.66,45.11 32.14,41.63 32.14,31.29 28.42,27.57 28.42,23.79 30.65,21.56 67.76,21.56 72.97,26.76 89.59,26.76 93.25,30.42 93.25,31.61 96.14,34.5 100.53,34.5 101.27,35.24 101.27,36.21 102.84,37.79 106.99,37.79 108.46,39.26 109.45,39.26 110.27,40.09 113.31,40.09 115.27,38.13 115.77,38.13 117.69,36.22 119.17,36.22 119.82,36.86 120.38,37.1 120.78,37.42 121.71,38.35 121.71,38.92 121.99,39.2 121.99,39.45
  BOTTOM w0.076: v3(122.27,48.46) 122.27,48.71 UC1.CB6
USB3_CRX_DTX_P2: length 225.9
  TOP w0.102: v3(16.21,93.16) 16.18,93.16 15.89,93.46 15.89,93.62 15.97,93.7 D32.9 D32.1 15.97,95.16 15.84,95.29 15.84,95.63 v3(16.09,95.87)
  IN2 w0.076: v3(121,49.47) 120.9,49.37 120.9,49.22 121.04,49.08 121.5,49.08 121.76,48.82 123.06,48.82 123.41,48.47 124.06,48.47 125.17,47.36 125.17,43.4 124.57,42.8 124.57,40.39 123.83,39.64 123.7,39.64 123.51,39.45
  IN2 w0.127: v3(16.09,95.87) 16.09,96.32 16.21,96.45 18.54,96.45 19.41,97.33 19.41,99.59 17.74,101.26 17.74,102.29 14.69,105.34 11.18,105.34 10.69,104.85 v3(9.36,104.85) ; v3(16.21,93.16) 16.01,93.16 15.78,92.93 15.78,92.68 16.9,91.56 18.66,91.56 23.21,87.01 23.21,47.79 29.7,41.29 29.7,30.25 27.73,28.28 27.73,23.5 30.37,20.87 68.05,20.87 73.25,26.08 89.94,26.08 94.06,30.2 94.06,31.34 96.02,33.29 100.93,33.29 102.09,34.46 102.09,35.94 103.25,37.1 107.27,37.1 108.22,38.05 109.3,38.05 110.23,38.98 113.27,38.98 114.8,37.45 115.48,37.45 117.48,35.45 119.38,35.45 120,36.07 120.36,36.31 120.78,36.48 121.02,36.64 122.47,38.1 122.47,38.42 123.51,39.45
  BOTTOM w0.076: UC1.BY9 121,49.61 v3(121,49.47)
  BOTTOM w0.102: JTC1.A11 8.08,104.7 8.22,104.56 8.51,104.56 8.62,104.67 9.18,104.67 v3(9.36,104.85)
USB3_CRX_DTX_P3: length 141.3
  IN2 w0.076: 126.74,39.45 126.47,39.72 126.35,39.72 126.01,40.06 126.01,47.97 124.89,49.08 123.57,49.08 123.26,49.38 122.98,49.38 122.91,49.46 v3(122.91,49.59)
  IN2 w0.127: v3(208.38,42.44) 208.55,42.27 208.78,42.27 208.91,42.4 208.91,42.79 209.01,42.9 209.29,42.9 209.41,42.78 209.41,42.37 209.53,42.25 209.77,42.25 209.9,42.37 209.9,42.74 210.05,42.9 217.6,42.9 221.88,38.61 221.88,34.57 219.5,32.19 214.79,32.19 211.5,28.9 205.7,28.9 204.47,27.67 197.15,27.67 196.26,26.78 171.99,26.78 171.48,26.27 167.56,26.27 167.06,26.78 166.23,26.78 164.66,28.34 164.66,29.62 163.52,30.77 158.67,30.77 158.08,30.18 154.41,30.18 153.73,30.86 150.95,30.86 148.93,31.7 148.2,32.42 147.05,32.42 146.79,32.67 146.79,32.88 145.9,33.77 144.46,34.37 142.21,36.61 139.7,36.61 139.29,37.02 139.29,37.42 138.63,38.08 134.11,38.08 133.78,38.41 129.25,38.41 128.89,38.77 127.43,38.77 126.74,39.45
  BOTTOM w0.076: UC1.BY6 v3(122.91,49.59)
  BOTTOM w0.102: JIO.15 207.2,42.45 207.39,42.63 208.19,42.63 v3(208.38,42.44)
USB3_CRX_DTX_P4: length 137.2
  IN2 w0.076: 127.66,43.71 127.66,43.73 127.62,43.77 127.62,44.93 126.74,45.81 126.74,47.99 124.59,50.15 123.34,50.15 123.22,50.26 123.22,50.35 123.39,50.52 v3(123.56,50.52)
  IN2 w0.127: v3(208.08,40.91) 208.26,41.09 208.68,41.09 208.86,40.91 208.86,40.51 208.96,40.41 209.27,40.41 209.39,40.53 209.39,40.95 209.69,41.24 218.27,41.24 221.12,38.4 221.12,34.95 219.04,32.87 214.5,32.87 211.3,29.68 204.97,29.68 203.86,28.57 197.08,28.57 195.98,27.46 171.59,27.46 171.1,26.97 168.07,26.97 166.99,28.05 166.99,29.57 166.59,29.97 165.32,29.97 163.84,31.45 158.77,31.45 158.34,31.88 156.82,31.88 156.4,32.3 155.1,32.3 153.52,33.89 149.98,33.89 149.55,33.46 148.29,33.46 142.4,37.39 141.02,38.77 134.4,38.77 134.07,39.1 130.07,39.1 129.5,39.67 127.97,39.67 127.66,39.98 127.66,43.71
  BOTTOM w0.076: UC1.BW5 v3(123.56,50.52)
  BOTTOM w0.102: JIO.18 207.1,40.95 207.24,41.09 207.9,41.09 v3(208.08,40.91)
USB3_CTX_C_DRX_N1: length 15.1
  TOP w0.102: v3(14.51,95.87) 14.33,95.7 14.33,95.27 14.47,95.14 D32.4 D32.7 14.47,93.63 14.36,93.52 14.36,93.34 14.47,93.24 14.61,93.24 14.88,92.97 14.88,92.78 15.23,92.43 CS31.1
  BOTTOM w0.102: v3(14.51,95.87) 14.51,96.45 14.28,96.68 13.72,96.68 13.54,96.5 9.7,96.5 9.57,96.63 9.57,99.43 9.49,99.51 9.46,99.51 8.81,100.16 8.81,100.28 8.39,100.7 JTC1.A3
USB3_CTX_C_DRX_N2: length 17.3
  TOP w0.102: v3(12.25,95.87) 12.49,95.64 12.49,95.32 12.29,95.12 D31.2 D31.8 12.29,93.52 12.41,93.4 12.41,92.85 CS34.1
  IN2 w0.127: v3(12.25,95.87) 12.25,95.88 12.58,96.21 12.58,97.55 11.6,98.53 11.6,99.42 10.29,100.73 8.47,100.73 7.6,101.6 7.6,103.69 6.74,104.55 6.09,104.55 5.79,104.26 JTC1.B3
USB3_CTX_C_DRX_N3: length 4.1
  BOTTOM w0.102: CS2.2 203.15,46.67 v4(204,46.67) 204.71,46.67 205.57,45.81 205.89,45.81 206.03,45.95 JIO.8
USB3_CTX_C_DRX_N4: length 4.2
  BOTTOM w0.102: CS23.2 203.15,45.4 203.75,45.4 204.5,44.64 204.5,44.62 204.82,44.31 v4(205.28,44.31) 205.85,44.31 206,44.45 JIO.11
USB3_CTX_C_DRX_P1: length 15.1
  TOP w0.102: CS32.1 14.35,92.43 14.66,92.73 14.66,92.88 14.52,93.02 14.38,93.02 14.15,93.25 14.15,93.49 13.97,93.67 D32.6 D32.5 13.97,95.1 14.12,95.24 14.12,95.68 v3(13.93,95.87)
  BOTTOM w0.102: v3(13.93,95.87) 14.3,96.24 14.3,96.36 14.19,96.46 13.81,96.46 13.63,96.28 9.61,96.28 9.36,96.54 9.36,99.34 8.62,100.08 8.62,100.2 8.31,100.51 8.13,100.51 8.02,100.4 8.02,100.3 7.92,100.2 JTC1.A2
USB3_CTX_C_DRX_P2: length 17.3
  TOP w0.102: CS33.1 12.63,92.75 12.63,93.4 12.79,93.57 D31.9 D31.1 12.79,95.16 12.71,95.25 12.71,95.74 v3(12.84,95.87)
  IN2 w0.127: JTC1.B2 5.93,104.81 6.84,104.81 7.86,103.79 7.86,101.7 8.57,100.98 10.4,100.98 11.86,99.53 11.86,98.64 12.84,97.66 v3(12.84,95.87)
USB3_CTX_C_DRX_P3: length 4.1
  BOTTOM w0.102: CS1.2 203.15,46.45 203.44,46.45 203.45,46.44 204.62,46.44 v4(205.17,45.89) 205.46,45.59 205.9,45.59 206.04,45.45 JIO.9
USB3_CTX_C_DRX_P4: length 4.2
  BOTTOM w0.102: CS24.2 203.15,45.18 203.64,45.18 v4(203.97,44.85) 204.74,44.08 205.86,44.08 205.99,43.95 JIO.12
USB3_CTX_DRX_N1: length 215.7
  TOP w0.102: v3(22.5,96.86) 22.78,96.58 22.78,96.48 17.15,90.85 14.92,90.85 14.74,91.03 14.74,91.56 14.84,91.66 15.14,91.66 CS31.2
  IN2 w0.127: v3(22.5,96.86) 22.51,96.88 22.51,99.62 23.97,101.08 23.97,102.98 23.4,103.55 23.4,108 25.59,110.18 26.73,110.18 27.5,110.95 27.82,110.95 29.26,110.95 29.95,111.65 32.05,111.65 32.3,111.91 33.07,111.91 33.45,111.52 51.42,111.52 53.59,109.35 63.91,109.35 65.03,110.47 73.44,110.47 74.11,111.15 79.05,111.15 81.89,108.31 106.83,108.31 107.69,107.45 115.8,107.45 119.82,103.44 131.39,103.44 132.92,101.91 132.92,98.39 143.58,87.73 143.58,85.91 144.26,85.23 144.26,76.93 141.21,73.88 139.25,73.88 136.99,71.62 136.99,70.45 136.58,70.04 136.58,67.02 138.57,65.04 138.57,63.12 138.8,62.88 138.8,61.89 138.51,61.6 v3(137.65,61.6)
  BOTTOM w0.076: 135.42,54.33 135.4,54.32 135.37,54.32 131.7,50.65 130.46,50.65 130.38,50.58 130.38,48.84 130.21,48.66 126.83,48.66 126.08,49.41 125.83,49.41 125.73,49.44 125.51,49.44 125.41,49.41 125.16,49.41 124.86,49.54 124.82,49.55 124.27,49.55 UC1.CA4
  BOTTOM w0.102: v3(137.65,61.6) 137.37,61.6 137.14,61.37 137.14,56.06 135.42,54.33
USB3_CTX_DRX_N2: length 214.8
  TOP w0.102: CS34.2 12.19,91.31 12.19,90.8 12.98,90.01 18.14,90.01 24.5,96.37 24.5,97.8 v3(24.79,98.09)
  IN2 w0.127: v3(24.79,98.09) 24.79,97.95 24.64,97.79 24.38,97.79 24.26,97.92 24.26,99.73 25.05,100.53 25.05,103.38 24.38,104.05 24.38,107.52 26.05,109.19 27.06,109.19 27.7,109.83 28.12,109.83 34.93,109.83 35.68,110.58 50.58,110.58 52.75,108.41 64.6,108.41 65.72,109.53 79.34,109.53 81.5,107.37 106.44,107.37 107.3,106.51 115.42,106.51 119.43,102.5 130.73,102.5 131.98,101.24 131.98,97.92 142.64,87.26 142.64,85.52 143.32,84.84 143.32,77.32 140.82,74.82 138.86,74.82 136.05,72.01 136.05,70.84 135.64,70.43 135.64,66.63 137.63,64.65 137.63,63.9 137.26,63.54 137.17,63.54 137.01,63.7 v3(137.01,64.04)
  BOTTOM w0.076: UC1.CA2 125.52,49.83 125.77,50.09 126.19,50.09 126.6,49.68 126.6,49.59 127.03,49.16 129.66,49.16 129.74,49.23 129.74,50.9 130.17,51.33 131.26,51.33 134.93,55 134.93,55.04 134.95,55.05
  BOTTOM w0.102: v3(137.01,64.04) 136.29,64.04 136.07,63.81 136.07,56.17 134.95,55.05
USB3_CTX_DRX_N3: length 113.7
  IN2 w0.076: v3(127.18,49.51) 127.18,48.87 127.74,48.31 128.25,48.31 128.76,47.8 129.07,47.8 130.37,46.5 130.37,44.28 130.03,43.95 130.03,43.77 129.99,43.72 129.99,43.71
  IN2 w0.127: 129.99,43.71 129.99,42.57 131.66,40.9 141.45,40.9 142.94,39.4 146.09,39.4 147.3,38.18 147.3,37.86 148.27,36.9 148.27,36.2 148.56,35.91 149.08,35.69 151.99,35.69 152.76,36.47 154.8,36.47 155.3,35.96 155.3,35.09 155.62,34.78 157.42,34.78 157.64,35.01 158.21,35.01 159.11,34.1 164.09,34.1 164.49,33.71 165.78,33.71 168.87,30.61 169.39,30.61 170.73,29.27 192.79,29.27 194.5,30.98 201.83,30.98 203.96,33.11 203.96,35.92 206.02,37.98 206.02,43.93 203.26,46.69 201.97,46.69 v3(201.81,46.85)
  BOTTOM w0.076: v3(127.18,49.51) 127.37,49.7 127.37,50.18 127.29,50.25 125.37,50.25 125.26,50.14 124.87,50.14 124.78,50.18 124.57,50.4 UC1.BY4
  BOTTOM w0.102: v3(201.81,46.85) 201.99,46.66 202.21,46.66 CS2.1
USB3_CTX_DRX_N4: length 106.9
  IN2 w0.076: 135.24,43.3 135.22,43.3 135.17,43.34 134.43,43.34 132.95,44.81 131.87,44.81 131.37,45.31 131.37,46.19 129.26,48.31 128.99,48.31 128.56,48.74 128.56,49.43 v3(128.47,49.52)
  IN2 w0.127: v3(201.81,45.58) 201.97,45.42 203.25,45.42 205.28,43.39 205.28,38.55 203.25,36.52 203.25,33.37 201.55,31.67 193.28,31.67 191.57,29.95 171.02,29.95 169.67,31.3 169.16,31.3 166.07,34.39 164.77,34.39 164.38,34.79 159.46,34.79 158.56,35.69 157.78,35.69 157.23,36.24 156.27,36.24 155.31,37.2 152.31,37.2 151.56,36.46 150.26,36.46 149.08,37.64 148.5,37.64 148.1,38.03 148.1,39.63 147.2,40.53 145.36,40.53 144.87,41.02 143.76,41.02 141.48,43.3 135.24,43.3
  BOTTOM w0.076: UC1.BW2 125.54,50.96 125.91,50.59 128.12,50.59 128.47,50.24 v3(128.47,49.52)
  BOTTOM w0.102: v3(201.81,45.58) 202,45.4 202.21,45.4 CS23.1
USB3_CTX_DRX_P1: length 215.7
  TOP w0.102: CS32.2 14.53,91.25 14.53,90.94 14.83,90.63 17.24,90.63 23,96.39 23,96.78 v3(23.08,96.86)
  IN2 w0.127: v3(23.08,96.86) 23.08,97.15 23.01,97.22 22.83,97.22 22.77,97.29 22.77,99.51 24.23,100.97 24.23,103.08 23.66,103.65 23.66,107.89 25.69,109.93 26.83,109.93 27.61,110.7 27.71,110.7 29.36,110.7 30.06,111.4 32.15,111.4 32.41,111.65 32.96,111.65 33.34,111.27 51.32,111.27 53.48,109.1 64.02,109.1 65.14,110.22 73.54,110.22 74.21,110.89 78.95,110.89 81.78,108.06 106.72,108.06 107.59,107.2 115.7,107.2 119.71,103.18 131.28,103.18 132.66,101.8 132.66,98.29 143.33,87.62 143.33,85.8 144,85.13 144,77.03 141.11,74.13 139.15,74.13 136.74,71.72 136.74,70.55 136.33,70.15 136.33,66.91 138.31,64.93 138.31,63.02 138.55,62.78 138.55,62 138.4,61.85 138.19,61.85 138.07,61.98 138.07,62.4 137.86,62.6 137.73,62.6 137.61,62.48 137.61,62.22 v3(137.65,62.18)
  BOTTOM w0.076: 135.26,54.49 135.25,54.47 135.25,54.44 131.63,50.82 130.39,50.82 130.22,50.65 130.22,48.9 130.14,48.83 126.9,48.83 126.15,49.57 125.86,49.57 125.76,49.61 125.48,49.61 125.39,49.57 125.2,49.57 125.03,49.64 124.93,49.91 124.77,49.93 UC1.CA3
  BOTTOM w0.102: v3(137.65,62.18) 137.56,62.27 137.26,62.27 137.19,62.2 137.19,61.72 137.14,61.67 136.93,61.46 136.93,61.28 136.93,56.15 135.66,54.89 135.26,54.49
USB3_CTX_DRX_P2: length 214.8
  TOP w0.102: v3(23.83,98.09) 23.97,98.23 24.19,98.23 24.29,98.13 24.29,96.46 18.06,90.23 13.07,90.23 12.41,90.89 12.41,91.13 12.78,91.51 CS33.2
  IN2 w0.127: v3(137.01,63.15) 137.14,63.28 137.37,63.28 137.88,63.79 137.88,64.75 135.9,66.73 135.9,70.33 136.3,70.73 136.3,71.9 138.97,74.57 140.93,74.57 143.57,77.21 143.57,84.95 142.9,85.63 142.9,87.36 132.23,98.03 132.23,101.35 130.83,102.75 119.53,102.75 115.52,106.76 107.41,106.76 106.54,107.63 81.6,107.63 79.44,109.79 65.62,109.79 64.5,108.67 52.86,108.67 50.69,110.84 35.58,110.84 34.82,110.08 28.23,110.08 27.6,110.08 26.96,109.44 25.94,109.44 24.13,107.63 24.13,103.94 24.8,103.27 24.8,100.63 24,99.84 24,98.26 v3(23.83,98.09)
  BOTTOM w0.076: UC1.CA1 126.03,49.92 126.12,49.92 126.44,49.61 126.44,49.52 126.96,48.99 129.73,48.99 129.9,49.17 129.9,50.83 130.23,51.16 131.33,51.16 135.05,54.88 135.09,54.88 135.1,54.9
  BOTTOM w0.102: v3(137.01,63.15) 137.01,63.11 136.94,63.03 136.74,63.03 136.62,63.15 136.62,63.72 136.52,63.82 136.38,63.82 136.28,63.72 136.28,56.08 135.49,55.29 135.1,54.9
USB3_CTX_DRX_P3: length 113.6
  IN2 w0.076: v3(127.76,49.51) 128.03,49.51 128.12,49.42 128.12,49.1 128,48.98 127.8,48.98 127.61,49.17 127.45,49.17 127.34,49.07 127.34,48.93 127.81,48.47 128.32,48.47 128.82,47.96 129.14,47.96 130.54,46.57 130.54,44.22 130.2,43.88 130.2,43.77 130.24,43.73 130.24,43.71
  IN2 w0.127: v3(201.81,46.27) 201.97,46.43 203.15,46.43 205.76,43.82 205.76,38.09 203.7,36.03 203.7,33.22 201.73,31.24 194.39,31.24 192.68,29.52 170.84,29.52 169.49,30.87 168.98,30.87 165.89,33.96 164.6,33.96 164.2,34.36 159.22,34.36 158.31,35.26 157.54,35.26 157.31,35.03 155.72,35.03 155.56,35.2 155.56,36.07 154.9,36.72 152.66,36.72 151.88,35.95 149.13,35.95 148.7,36.12 148.52,36.31 148.52,37 147.56,37.96 147.56,38.29 146.19,39.66 143.05,39.66 141.55,41.15 131.76,41.15 130.24,42.67 130.24,43.71
  BOTTOM w0.076: UC1.BY3 124.91,50.46 124.91,50.57 125.04,50.7 125.28,50.7 125.35,50.62 125.35,50.48 125.41,50.42 127.36,50.42 127.53,50.24 127.53,49.74 v3(127.76,49.51)
  BOTTOM w0.102: v3(201.81,46.27) 201.99,46.45 202.22,46.45 CS1.1
USB3_CTX_DRX_P4: length 106.9
  IN2 w0.076: v3(129.05,49.52) 129.3,49.52 129.42,49.4 129.42,49.12 129.32,49.02 129.07,49.02 128.93,49.16 128.79,49.16 128.72,49.09 128.72,48.81 129.06,48.47 129.33,48.47 131.54,46.26 131.54,45.37 131.94,44.98 133.02,44.98 134.5,43.51 135.17,43.51 135.22,43.55 135.24,43.55
  IN2 w0.127: v3(201.81,45) 201.98,45.17 203.14,45.17 205.02,43.29 205.02,38.65 202.99,36.62 202.99,33.47 201.44,31.92 193.18,31.92 191.46,30.21 171.12,30.21 169.78,31.55 169.26,31.55 166.17,34.65 164.88,34.65 164.48,35.04 159.57,35.04 158.66,35.95 157.88,35.95 157.33,36.49 156.38,36.49 155.42,37.45 152.2,37.45 151.46,36.71 150.36,36.71 149.18,37.89 148.6,37.89 148.36,38.13 148.36,39.73 147.3,40.79 145.46,40.79 144.98,41.27 143.86,41.27 141.58,43.55 135.24,43.55
  BOTTOM w0.076: v3(129.05,49.52) 129.09,49.56 129.09,49.73 129.01,49.81 128.71,49.81 128.63,49.89 128.63,50.31 128.19,50.76 126.02,50.76 125.94,50.83 UC1.BW1
  BOTTOM w0.102: CS24.1 202.21,45.18 202,45.18 v3(201.81,45)
USB20_N1: length 112.3
  TOP w0.102: RS48.1 220,36.94 LM3.4 219.99,36.74 219.85,36.6 219.85,36.12 v3(220.04,35.94)
  IN2 w0.076: 128.17,43.71 128.17,43.73 128.21,43.77 128.21,44.91 127.4,45.72 127.4,46.44 v3(127.19,46.65)
  IN2 w0.127: 128.17,43.71 128.17,41.61 130.25,39.53 134.25,39.53 134.58,39.2 141.2,39.2 142.67,37.73 148.42,33.89 149.34,33.89 149.77,34.32 153.7,34.32 155.21,32.81 156.51,32.81 157,32.32 158.63,32.32 159.06,31.88 164.08,31.88 165.56,30.4 167.15,30.4 167.88,29.67 167.88,28.57 168.55,27.9 194.97,27.9 196.21,29.14 203.82,29.14 205.26,30.58 209.7,30.58 212.71,33.59 218.36,33.59 219.86,35.08 219.86,35.76 v3(220.04,35.94)
  BOTTOM w0.076: v3(127.19,46.65) 127.4,46.44 127.4,46.31 127.31,46.22 126.9,46.22 126.1,47.03 125.73,47.16 125.48,47.16 125.39,47.13 125.2,47.13 125.03,47.2 124.7,47.2 124.66,47.22 124.61,47.28 124.61,47.35 UC1.CE3
USB20_N1_R: length 15.6
  TOP w0.102: v3(220.04,38.39) 219.85,38.2 219.85,37.73 RS48.2 220,37.52 LM3.3
  BOTTOM w0.102: v3(220.04,38.39) 220.04,39.16 219.25,39.95 JIO.20
USB20_N2: length 108.2
  TOP w0.102: v3(218.21,35.94) 218.02,36.12 218.02,36.73 218.22,36.93 ; 218.22,36.93 LM5.4 ; 218.22,36.93 RS50.1
  IN2 w0.076: v3(128.82,46.66) 129.05,46.89 129.22,46.89 129.35,46.76 129.35,43.77 129.3,43.73 129.3,43.71
  IN2 w0.127: 129.3,43.71 129.3,42.28 131.37,40.21 141.16,40.21 142.68,38.7 145.72,38.7 145.84,38.57 145.84,38.01 146.31,37.55 146.63,37.55 147.56,36.62 147.56,35.94 148.17,35.33 148.94,35.01 154.25,35.01 155.2,34.06 156.34,34.06 157.4,33 159.28,33 159.71,32.57 164.36,32.57 165.85,31.08 167.43,31.08 168.59,29.93 169.1,29.93 170.45,28.58 193.62,28.58 194.87,29.83 202,29.83 203.04,30.87 204.58,30.87 205.56,31.85 210,31.85 212.48,34.32 217.04,34.32 218.04,35.33 218.04,35.78 v3(218.21,35.94)
  BOTTOM w0.076: v3(128.82,46.66) 128.56,46.92 128.36,46.92 128.08,47.2 126.42,47.2 126.14,47.48 126.03,47.48 125.94,47.39 UC1.CE1
USB20_N2_R: length 13.8
  TOP w0.102: 218.22,37.53 RS50.2 ; 218.22,37.53 LM5.3 ; 218.22,37.53 218.02,37.73 218.02,38.2 v3(218.21,38.39)
  BOTTOM w0.102: v3(218.21,38.39) 218.21,39.01 217.94,39.28 216.44,39.28 215.62,38.45 JIO.23
USB20_N3: length 235
  IN2 w0.127: v3(134.2,20.6) 134.03,20.76 134.03,21.01 132.22,22.81 131.64,23.2 130.51,23.69 126.65,23.69 124.62,25.71 121.4,25.71 120.37,26.75 119.33,26.75 118.83,26.25 108.66,26.25 108.21,26.69 105.67,26.69 105.31,26.33 102.34,26.33 101.93,26.75 98.68,26.75 95.7,23.77 88.68,23.77 87.03,22.12 83.3,22.12 81.37,24.05 72.32,24.05 68.46,20.19 30.08,20.19 27.05,23.22 27.05,29.14 28.11,30.2 28.11,33.55 27.29,34.37 27.29,40.41 23.6,44.09 23.6,45.87 20.72,48.75 20.72,87.64 v3(20.89,87.81)
  BOTTOM w0.076: UC1.CG3 124.57,46.15 124.57,46.24 124.63,46.32 124.86,46.39 124.87,46.4 124.88,46.4 124.9,46.41 125.18,46.51 125.27,46.52 125.33,46.52 125.37,46.52 125.39,46.51 125.42,46.51 125.51,46.47 125.73,46.47 125.8,46.5 126.16,46.5 126.77,45.89 127.54,45.89 127.95,46.3 128.97,46.3 129.59,46.92 131.96,46.92 134.41,44.47 134.41,44.06 134.44,44.03 134.44,44.01
  BOTTOM w0.102: v3(20.89,87.81) 20.7,87.99 20.7,92.26 25.6,97.16 25.6,98.93 25.35,99.19 25.06,99.19 LM7.1 ; v3(134.2,20.6) 133.99,20.8 133.99,21.62 134.11,21.74 134.11,23.48 133.1,24.48 133.1,29.01 133.68,29.58 133.68,39.73 134.44,40.49 134.44,44.01
USB20_N3_C: length 24.3
  TOP w0.102: JTC1.B7 6.98,102.34 7.23,102.34 8.04,103.14 9.3,103.14 9.41,103.03 9.41,102.61 9.31,102.51 9.19,102.51 9,102.7 v3(9,102.7)
  IN2 w0.127: v3(9,102.7) 9.18,102.52 9.39,102.52 10.63,102 10.67,101.96 12.23,100.4 14.34,99.36 14.48,99.28 17.68,98.38 18.12,97.94 18.49,97.94 v3(18.65,98.1)
  BOTTOM w0.102: v3(18.65,98.1) 18.81,97.94 20.01,97.94 20.11,98.05 20.11,98.48 DM15.3 20.68,98.5 20.68,97.94 20.79,97.84 20.92,97.84 22.26,99.19 24.18,99.19 LM7.2 ; JTC1.A7 8.01,102.7 8.14,102.57 8.87,102.57 v3(9,102.7)
USB20_N4: length 165
  BOTTOM w0.076: UC1.CD3 124.77,47.95 124.7,48.03 124.7,48.15 124.77,48.23 125.13,48.23 125.38,47.98 126.34,47.98 126.51,47.81 129.17,47.81 129.68,47.3 132.22,47.3 135.14,44.38 135.14,44.07 135.17,44.04 135.17,44.03
  BOTTOM w0.102: RS53.1 255.76,20.01 LM6.4 255.45,20.01 255.31,19.86 254.78,19.86 CC154.2 254.08,19.86 253.55,19.86 253.32,19.64 253.32,19.19 252.39,18.25 251.39,18.25 250.07,16.94 v4(247.33,16.94) 238.86,16.94 238.49,17.3 237.98,17.3 237.96,17.32 237.06,17.32 237.04,17.3 234.75,17.3 233.56,16.11 233.56,15.81 232.44,14.68 223.64,14.68 223.03,14.07 219.02,14.07 218.02,13.08 214.01,13.08 210.17,16.91 208.4,19.57 208.1,19.87 207.43,20.15 136.29,20.15 134.73,21.7 134.73,23.74 133.74,24.73 133.74,28.45 134.3,29.01 134.3,39.34 135.17,40.21 135.17,44.03
USB20_N4_R: length 6.3
  BOTTOM w0.102: LM6.3 256.35,20.01 RS53.2 256.68,20.07 256.89,19.86 v4(257.38,19.86) 257.85,19.86 258.87,18.84 258.87,17.83 259.31,17.39 259.54,17.33 259.66,17.4 259.71,17.58 259.88,17.68 JCR.4
USB20_N5: length 104.6
  IN2 w0.076: 112.21,54 112.2,53.99 112.2,53.95 112.16,53.92 112.16,53.73 112.16,53.73 112.16,52.73 112.2,52.69 112.2,50.37 112,50.17 112,49.55 112.31,49.23 118.38,49.23 118.82,48.79 118.82,46.16 119.29,45.68 119.61,45.68 120.12,45.17 121.86,45.17 121.91,45.22 122.65,45.22 122.88,45.45 122.88,45.74 122.93,45.79 v3(123.1,45.79)
  IN2 w0.127: 112.21,54 113.01,54.8 113.01,57.87 113.54,58.4 114.25,58.4 115.43,59.57 115.43,60.41 116.44,61.42 116.44,64.58 117.8,65.94 117.8,70.32 117.98,70.5 117.98,71.02 117.85,71.15 117.85,72.6 118.36,73.11 118.36,74.7 117.27,75.79 117.27,76.48 116.44,77.3 116.44,79.29 115.81,79.92 115.81,85.64 113.65,87.8 113.65,93.24 112.71,94.18 111.81,94.18 109.34,96.65 104.75,96.65 103.22,98.19 84.38,98.19 84.12,97.94 82.17,97.94 81.9,98.21 81.9,98.52 v3(81.73,98.68)
  BOTTOM w0.076: v3(123.1,45.79) 123.1,46.12 UC1.CG5
  BOTTOM w0.102: R170.1 80.06,103.49 80.27,103.28 80.27,102.95 80.96,102.25 80.96,101.23 81.58,100.6 81.58,99.66 81.94,99.31 81.94,98.89 v3(81.73,98.68)
USB20_N5_R: length 31.7
  BOTTOM w0.102: L12.3 80.12,104.39 80.26,104.53 v4(80.26,105.29) 80.26,105.99 79.75,106.5 78.79,106.5 78.77,106.51 78.33,106.51 76.81,104.99 76.25,104.99 76.03,104.77 D7.2 75.67,104.31 75.67,104.5 75.09,105.09 74.37,105.09 73.45,106 59.61,106 59.15,105.54 59.15,100.87 59.33,100.69 59.33,100.45 59.5,100.28 JEDP.26
USB20_N6: length 155
  BOTTOM w0.076: UC1.CC1 125.94,48.51 125.94,48.38 126.01,48.31 126.48,48.31 126.62,48.17 129.38,48.17 129.85,47.7 132.46,47.7 135.51,44.65 135.58,44.65 135.59,44.64
  BOTTOM w0.102: R5263.1 248.32,18.43 L14.4 248.05,18.42 247.95,18.52 247.95,18.56 247.88,18.63 247.73,18.63 247.63,18.53 247.63,18.18 247.59,18.13 246.87,18.13 246.36,17.62 v4(243.89,17.62) 241.38,17.62 241.37,17.63 240.46,17.63 240.45,17.62 239.08,17.62 238.72,17.98 234.53,17.98 232.79,16.24 232.79,16.02 232.08,15.3 223.32,15.3 222.71,14.69 218.76,14.69 217.77,13.7 214.27,13.7 210.7,17.27 208.91,19.95 208.46,20.39 207.55,20.77 160.27,20.77 159.82,21.23 158.67,21.23 158.21,20.77 136.54,20.77 135.35,21.96 135.35,23.99 134.37,24.97 134.37,28.02 134.92,28.57 134.92,38.82 135.87,39.77 135.87,44.36 135.59,44.64
USB20_N6_R: length 12.8
  BOTTOM w0.102: JFPR.3 253.69,27.15 253.55,27.01 252.76,27.01 v4(252.42,26.67) 252.12,26.36 252.12,24.23 252.1,24.21 252.1,23.31 252.12,23.29 252.12,23.09 251.33,22.3 250.92,22.3 250.22,21.59 250.22,21.11 250.07,20.97 DM16.1 DM16.9 250.07,19.41 250.22,19.27 250.22,18.86 249.61,18.26 249.07,18.26 L14.3 248.9,18.43 R5263.2
USB20_N7: length 101.6
  IN2 w0.076: v3(121.7,46.74) 121.1,46.13 120.05,46.13 119.72,46.47 119.72,48.66 118.61,49.77 113.26,49.77 112.85,50.18 112.85,52.69 112.81,52.73 112.81,53.3 112.78,53.33 112.78,53.52 112.82,53.55 112.82,53.59 112.83,53.6
  IN2 w0.127: v3(80.29,98.68) 80.12,98.85 80.12,99.08 80.25,99.21 84.24,99.21 84.57,98.88 103.55,98.88 105.08,97.34 109.63,97.34 112.1,94.87 113.56,94.87 114.33,94.1 114.33,88.11 116.06,86.38 116.72,86.38 117.46,85.64 117.46,79.61 117.71,79.35 117.71,77.64 118.47,76.88 118.47,75.9 119.24,75.14 119.24,72.39 119.02,72.17 119.02,65.84 117.58,64.41 117.58,61.3 116.7,60.41 116.7,58.46 117.39,57.76 117.39,57.27 115.3,55.18 115.3,54.23 114.94,53.87 113.1,53.87 112.83,53.6
  BOTTOM w0.076: UC1.CG8 121.3,46.33 v3(121.7,46.74)
  BOTTOM w0.102: R5175.1 80.43,99.8 L13.1 80.37,99.62 80.23,99.49 80.23,99.16 80.12,99.04 80.12,98.85 v3(80.29,98.68)
USB20_N7_R: length 20.9
  BOTTOM w0.102: JEDP.14 65.5,100.36 65.64,100.5 65.64,101.66 66.47,102.48 72.01,102.48 73.4,101.09 75.3,101.09 D6.3 76.16,101.7 76.16,101.49 76.54,101.1 76.68,101.1 78.29,102.71 v4(79.22,102.71) 79.77,102.71 80.38,102.09 80.38,100.8 80.37,100.79 L13.2 80.38,100.39 R5175.2
USB20_N10: length 128.5
  BOTTOM w0.076: 136.01,45.03 135.78,45.26 135.33,45.26 132.62,47.96 129.9,47.96 129.53,48.33 126.69,48.33 126.25,48.77 125.85,48.77 125.81,48.76 125.43,48.76 125.39,48.77 125.18,48.77 125.11,48.73 124.87,48.73 124.68,48.81 124.43,48.81 124.29,48.67 124.29,48.59 124.37,48.52 UC1.CC3
  BOTTOM w0.102: 136.01,45.03 136.29,44.75 136.29,39.35 135.33,38.39 135.33,28.06 136.23,27.15 137.39,27.15 137.93,26.61 137.93,24.46 137.8,24.33 136.35,24.33 135.76,23.73 135.76,22.13 136.71,21.18 157.98,21.18 158.44,21.63 159.98,21.63 160.32,21.3 164.98,21.3 165,21.29 165.9,21.29 165.92,21.3 v4(168.01,21.3) 207.34,21.3 208.7,20.74 209.24,20.2 210.28,18.64 211.87,17.05 214.9,17.05 215.52,17.31 218.4,20.19 218.74,20.19 218.88,20.05 JWLAN.5
USB20_P1: length 112.3
  TOP w0.102: v3(219.45,35.94) 219.64,36.12 219.64,36.64 219.49,36.78 LM3.1 219.49,36.94 RS47.1
  IN2 w0.076: 128.42,43.71 128.42,43.73 128.38,43.77 128.38,44.98 127.57,45.79 127.57,46.44 v3(127.78,46.65)
  IN2 w0.127: v3(219.45,35.94) 219.45,35.92 219.6,35.76 219.6,35.19 218.26,33.84 212.61,33.84 209.6,30.83 205.15,30.83 203.72,29.4 196.11,29.4 194.86,28.15 168.65,28.15 168.13,28.67 168.13,29.78 167.25,30.65 165.67,30.65 164.18,32.14 159.17,32.14 158.74,32.57 157.11,32.57 156.61,33.07 155.31,33.07 153.8,34.58 149.67,34.58 149.23,34.14 148.5,34.14 142.84,37.93 141.31,39.45 134.68,39.45 134.35,39.78 130.36,39.78 128.42,41.71 128.42,43.71
  BOTTOM w0.076: UC1.CE4 124.66,47.04 125,47.04 125.16,46.96 125.41,46.96 125.51,47 125.7,47 126.01,46.89 126.84,46.06 127.38,46.06 127.57,46.25 127.57,46.44 v3(127.78,46.65)
USB20_P1_R: length 15.6
  TOP w0.102: v3(219.45,38.39) 219.64,38.2 219.64,37.73 RS47.2 219.49,37.52 LM3.2
  BOTTOM w0.102: JIO.21 207.22,39.45 207.33,39.55 207.33,39.63 207.43,39.73 219.16,39.73 219.82,39.07 219.82,38.76 v3(219.45,38.39)
USB20_P2: length 108.3
  TOP w0.102: RS49.1 217.61,36.93 ; 217.61,36.93 217.81,36.73 217.81,36.12 v3(217.62,35.94) ; 217.61,36.93 LM5.1
  IN2 w0.076: v3(128.82,47.29) 129.05,47.06 129.29,47.06 129.51,46.83 129.51,43.77 129.55,43.73 129.55,43.71
  IN2 w0.127: 129.55,43.71 129.55,42.39 131.48,40.47 141.27,40.47 142.78,38.95 145.82,38.95 146.1,38.67 146.1,38.12 146.41,37.8 146.73,37.8 147.81,36.72 147.81,36.04 148.31,35.54 148.99,35.26 154.35,35.26 155.3,34.31 156.45,34.31 157.5,33.26 159.39,33.26 159.82,32.82 164.47,32.82 165.95,31.34 167.54,31.34 168.7,30.18 169.21,30.18 170.55,28.84 193.52,28.84 194.76,30.08 201.9,30.08 202.94,31.12 204.47,31.12 205.45,32.1 209.9,32.1 212.37,34.58 216.93,34.58 217.61,35.26 217.79,35.43 217.79,35.78 v3(217.62,35.94)
  BOTTOM w0.076: UC1.CE2 125.82,47.65 126.21,47.65 126.49,47.37 128.15,47.37 128.43,47.09 128.62,47.09 v3(128.82,47.29)
USB20_P2_R: length 13.7
  TOP w0.102: 217.61,37.53 217.81,37.73 217.81,38.2 v3(217.62,38.39) ; 217.61,37.53 LM5.2 ; 217.61,37.53 RS49.2
  BOTTOM w0.102: v3(217.62,38.39) 217.99,38.76 217.99,38.92 217.85,39.06 216.53,39.06 215.71,38.23 207.46,38.23 207.36,38.13 207.36,38.04 207.26,37.95 JIO.24
USB20_P3: length 235
  IN2 w0.127: v3(20.3,87.81) 20.47,87.64 20.47,48.65 23.35,45.76 23.35,43.98 27.03,40.3 27.03,34.27 27.86,33.44 27.86,30.31 26.79,29.24 26.79,23.11 29.98,19.93 68.56,19.93 72.42,23.79 81.27,23.79 83.19,21.86 87.14,21.86 88.79,23.52 95.8,23.52 98.78,26.49 101.83,26.49 102.24,26.08 105.42,26.08 105.77,26.44 108.11,26.44 108.55,25.99 118.94,25.99 119.44,26.49 120.26,26.49 121.3,25.46 124.51,25.46 126.54,23.43 130.46,23.43 131.52,22.98 132.06,22.62 133.78,20.9 133.78,20.76 v3(133.61,20.6)
  BOTTOM w0.076: UC1.CG4 124.48,45.82 124.8,45.82 124.97,46 124.97,46.16 125.04,46.26 125.2,46.34 125.39,46.34 125.48,46.31 125.76,46.31 125.82,46.33 126.09,46.33 126.7,45.73 127.61,45.73 128.02,46.14 129.04,46.14 129.65,46.76 131.89,46.76 134.25,44.4 134.25,44.06 134.22,44.03 134.22,44.01
  BOTTOM w0.102: v3(133.61,20.6) 133.78,20.76 133.78,21.71 133.89,21.83 133.89,23.39 132.89,24.39 132.89,29.1 133.46,29.67 133.46,39.82 134.22,40.58 134.22,44.01 ; LM7.4 25.06,98.97 25.26,98.97 25.38,98.85 25.38,97.25 20.49,92.35 20.49,87.99 v3(20.3,87.81)
USB20_P3_C: length 25
  TOP w0.102: v3(9,102.12) 9.17,102.29 9.4,102.29 9.63,102.52 9.63,103.12 9.39,103.36 7.95,103.36 7.14,102.56 6.98,102.56 JTC1.B6
  IN2 w0.127: v3(9,102.12) 9.15,102.26 9.34,102.26 10.49,101.78 10.49,101.78 12.08,100.19 14.22,99.14 14.37,99.04 17.55,98.15 18.02,97.68 18.49,97.68 v3(18.65,97.52)
  BOTTOM w0.102: v3(9,102.12) 9,102.12 8.98,102.12 8.74,102.36 8.21,102.36 8.06,102.2 JTC1.A6 ; v3(18.65,97.52) 18.86,97.73 20.01,97.73 20.11,97.63 20.11,97.14 DM15.2 20.68,97.12 20.68,97.52 20.79,97.63 21.01,97.63 22.35,98.97 24.18,98.97 LM7.3
USB20_P4: length 165
  BOTTOM w0.076: 134.95,44.03 134.95,44.04 134.98,44.07 134.98,44.31 132.15,47.14 129.61,47.14 129.1,47.65 126.44,47.65 126.28,47.81 125.26,47.81 125.15,47.7 124.76,47.7 124.52,47.84 UC1.CD4
  BOTTOM w0.102: 134.95,44.03 134.95,40.3 134.08,39.43 134.08,29.1 133.52,28.54 133.52,24.64 134.51,23.65 134.51,21.61 136.2,19.93 207.39,19.93 207.97,19.69 208.23,19.43 210.01,16.78 213.92,12.86 218.11,12.86 219.1,13.85 223.12,13.85 223.73,14.46 232.52,14.46 233.78,15.72 233.78,16.02 234.84,17.09 v4(237.51,17.09) 238.4,17.09 238.77,16.72 246.86,16.72 246.87,16.71 247.78,16.71 247.79,16.72 250.16,16.72 251.48,18.04 252.48,18.04 253.54,19.1 253.54,19.55 253.64,19.65 254.08,19.65 CC154.1 254.78,19.65 255.31,19.65 255.45,19.51 LM6.1 255.76,19.5 RS54.1
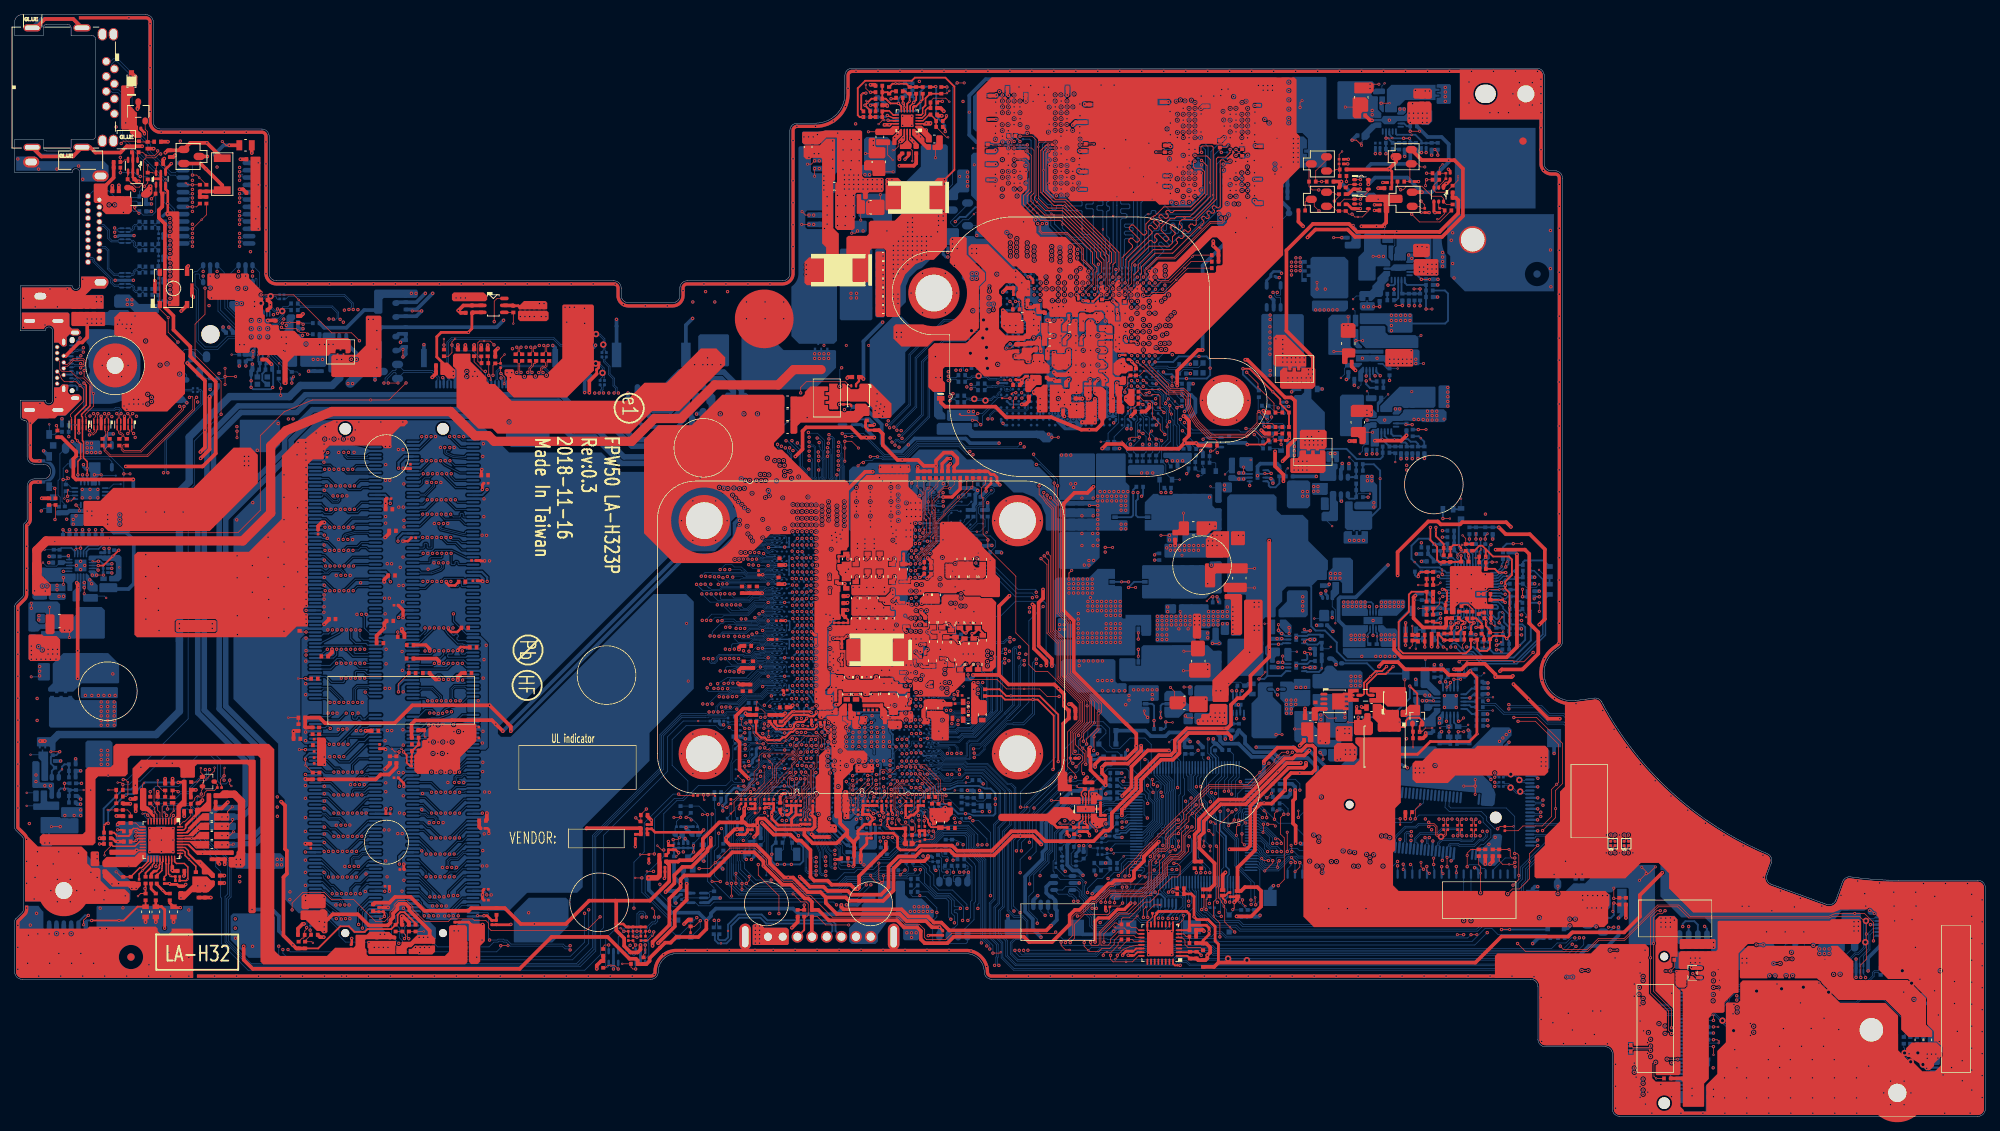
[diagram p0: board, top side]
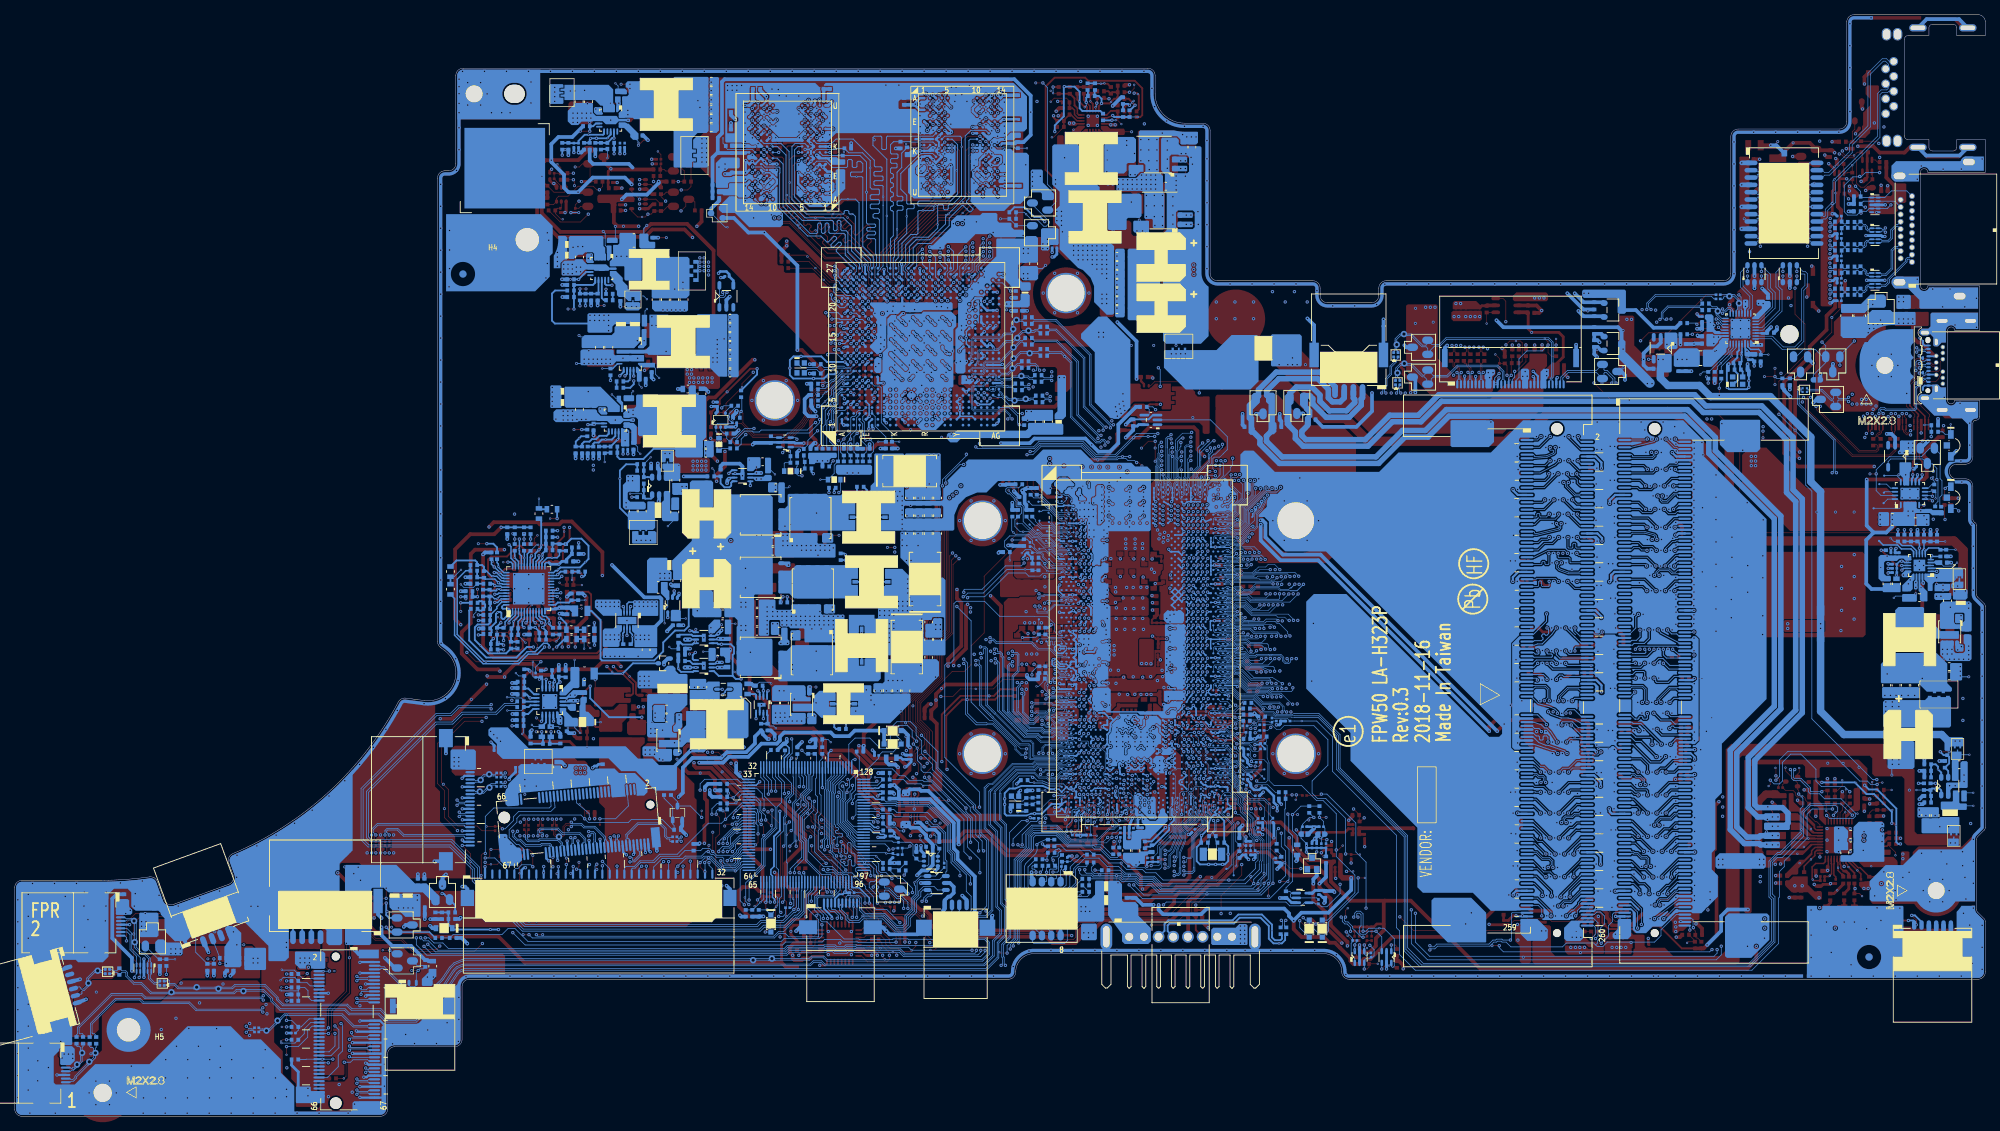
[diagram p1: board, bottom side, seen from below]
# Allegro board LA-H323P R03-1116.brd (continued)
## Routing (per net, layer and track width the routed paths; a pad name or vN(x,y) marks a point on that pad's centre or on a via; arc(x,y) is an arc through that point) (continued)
USB20_P4_R: length 6.3
  BOTTOM w0.102: LM6.2 256.35,19.5 RS54.2 256.68,19.44 256.88,19.64 257.77,19.64 258.66,18.75 258.66,18.18 v4(258.64,18.17) 258.64,17.75 259.2,17.2 259.48,17.12 259.56,17 259.51,16.81 259.58,16.69 260.42,16.47 JCR.5
USB20_P5: length 104.6
  IN2 w0.076: v3(122.33,45.84) 122.38,45.88 122.59,45.88 122.68,45.79 122.68,45.54 122.56,45.42 121.83,45.42 121.78,45.37 120.21,45.37 119.73,45.85 119.38,45.85 118.98,46.25 118.98,48.86 118.45,49.4 112.38,49.4 112.16,49.62 112.16,50.1 112.36,50.3 112.36,53.8 112.39,53.82
  IN2 w0.127: v3(82.32,98.68) 82.15,98.52 82.15,98.32 82.28,98.19 84.02,98.19 84.27,98.45 103.32,98.45 104.86,96.91 109.45,96.91 111.92,94.44 112.81,94.44 113.9,93.35 113.9,87.9 116.06,85.75 116.06,80.03 116.7,79.4 116.7,77.41 117.52,76.58 117.52,75.89 118.61,74.8 118.61,73 118.11,72.49 118.11,71.25 118.23,71.13 118.23,70.39 118.05,70.21 118.05,65.83 116.7,64.47 116.7,61.32 115.68,60.3 115.68,59.47 114.36,58.14 113.65,58.14 113.27,57.76 113.27,54.7 112.39,53.82
  BOTTOM w0.076: UC1.CG6 122.78,46.09 122.78,45.95 122.55,45.73 122.45,45.73 v3(122.33,45.84)
  BOTTOM w0.102: v3(82.32,98.68) 82.15,98.85 82.15,99.4 81.8,99.75 81.8,100.69 81.17,101.32 81.17,102.34 80.48,103.04 80.48,103.28 80.69,103.49 R171.1
USB20_P5_R: length 31.7
  BOTTOM w0.102: L12.2 80.62,104.39 80.47,104.54 80.47,104.73 80.49,104.74 80.49,105.8 80.47,105.81 80.47,106.08 79.83,106.73 v4(79.27,106.73) 78.24,106.73 76.72,105.21 76.28,105.21 76.03,105.46 76.03,105.87 ; 76.03,105.87 D7.3 ; 76.03,105.87 75.46,105.3 74.46,105.3 73.54,106.22 59.52,106.22 58.94,105.63 58.94,100.78 59.11,100.6 59.11,100.43 59,100.31 JEDP.27
USB20_P6: length 155.1
  BOTTOM w0.076: UC1.CC2 125.95,48.14 126.41,48.14 126.55,48 129.31,48 129.78,47.53 132.39,47.53 135.44,44.48
  BOTTOM w0.102: R5264.1 248.32,17.91 L14.1 246.96,17.92 246.45,17.4 244.35,17.4 244.34,17.39 243.43,17.39 243.42,17.4 v4(240.91,17.4) 238.99,17.4 238.63,17.76 234.62,17.76 233.01,16.15 233.01,15.93 232.17,15.09 223.41,15.09 222.8,14.47 218.85,14.47 217.86,13.48 214.18,13.48 210.53,17.13 208.74,19.81 208.34,20.21 207.51,20.55 160.18,20.55 159.73,21.01 158.75,21.01 158.3,20.55 136.45,20.55 135.14,21.87 135.14,23.9 134.16,24.88 134.16,28.11 134.7,28.66 134.7,38.91 135.66,39.86 135.66,44.27 135.44,44.48
USB20_P6_R: length 12.8
  BOTTOM w0.102: JFPR.4 253.55,26.65 253.41,26.79 252.87,26.79 252.33,26.25 v4(252.33,23.76) 252.33,23 251.42,22.08 251.01,22.08 250.43,21.5 250.43,21.12 250.57,20.98 DM16.2 DM16.8 250.57,19.48 250.43,19.34 250.43,18.77 249.7,18.04 249.03,18.04 L14.2 248.91,17.86 R5264.2
USB20_P7: length 101.7
  IN2 w0.076: v3(121.03,46.75) 121.03,46.47 120.86,46.3 120.12,46.3 119.88,46.54 119.88,48.73 118.68,49.93 113.33,49.93 113.01,50.25 113.01,53.42
  IN2 w0.127: 113.01,53.42 113.2,53.61 115.04,53.61 115.55,54.12 115.55,55.07 117.65,57.17 117.65,57.87 116.95,58.57 116.95,60.3 117.84,61.19 117.84,64.3 119.27,65.74 119.27,72.07 119.49,72.28 119.49,75.25 118.73,76.01 118.73,76.98 117.97,77.74 117.97,79.46 117.71,79.71 117.71,85.74 116.82,86.63 116.17,86.63 114.59,88.21 114.59,94.2 113.67,95.12 112.2,95.12 109.73,97.59 105.19,97.59 103.65,99.13 84.68,99.13 84.35,99.46 80.14,99.46 79.87,99.19 79.87,98.85 v3(79.7,98.68)
  BOTTOM w0.076: UC1.CG9 120.78,46.27 121.03,46.51 v3(121.03,46.75)
  BOTTOM w0.102: v3(79.7,98.68) 79.9,98.89 79.9,99.13 80.02,99.25 80.02,99.49 79.87,99.64 L13.4 79.81,99.8 R173.1
USB20_P7_R: length 21
  BOTTOM w0.102: R173.2 79.86,100.39 L13.3 79.87,100.61 80.15,100.89 v4(80.15,101.43) 80.15,102.02 79.69,102.48 78.76,102.48 78.75,102.49 78.38,102.49 76.77,100.89 76.49,100.89 76.16,100.55 76.16,100.02 D6.2 75.88,99.89 75.55,100.22 75.55,100.6 75.27,100.88 73.31,100.88 71.92,102.27 66.56,102.27 65.86,101.57 65.86,100.53 66,100.39 JEDP.13
USB20_P10: length 128.5
  BOTTOM w0.076: UC1.CC4 124.13,48.65 124.13,48.74 124.36,48.98 124.72,48.98 124.9,48.9 125.07,48.9 125.14,48.94 125.42,48.94 125.46,48.92 125.78,48.92 125.81,48.94 126.32,48.94 126.76,48.5 129.6,48.5 129.97,48.13 132.69,48.13 135.4,45.42 135.92,45.42 136.16,45.19
  BOTTOM w0.102: 136.16,45.19 136.51,44.84 136.51,39.26 135.54,38.3 135.54,28.14 136.32,27.37 137.48,27.37 138.15,26.7 138.15,24.37 137.89,24.11 136.44,24.11 135.97,23.64 135.97,22.22 136.8,21.39 157.89,21.39 158.35,21.85 160.07,21.85 160.4,21.52 v4(165.45,21.52) 167.55,21.52 167.56,21.53 168.51,21.53 168.52,21.52 207.39,21.52 208.82,20.93 209.4,20.34 210.45,18.78 211.96,17.27 214.86,17.27 215.39,17.49 218.31,20.41 218.75,20.41 218.89,20.55 JWLAN.3
USB_OC0#: length 3.3
  TOP w0.076: RC965.1 123.93,43.75 123.93,44.09 123.55,44.47 123.26,44.47 v3(122.88,44.85)
  BOTTOM w0.076: v3(122.88,44.85) 122.89,44.85 122.89,44.72 UC1.CK6
USB_OC1#: length 2.9
  TOP w0.076: v3(123.47,44.88) 124.21,44.13 124.21,43.26 RC963.1
  BOTTOM w0.076: v3(123.47,44.88) 123.47,44.64 UC1.CK5
USB_OC2#: length 3.2
  TOP w0.076: v1(120.95,44.88) 121.27,44.56 v3(121.27,43.93) 121.27,43.81 121.66,43.42 122.06,43.42 122.28,43.19 RC966.1
  BOTTOM w0.076: UC1.CK8 v3(121.27,43.93)
USB_OC3#: length 2.9
  TOP w0.076: v3(120.71,43.93) 120.71,43.8 RC964.1 120.81,42.27 v1(120.68,42.27)
  BOTTOM w0.076: UC1.CK9 v3(120.71,43.93)
USB_ON#: length 73.8
  TOP w0.102: v3(207.67,36.95) 206.55,35.83 v1(206.55,34.75) 206.55,32.4 205.17,31.02 204.21,31.02 v3(203.56,30.37)
  IN1 w0.127: v3(203.56,30.37) 203.48,30.37 202.81,29.71 170.22,29.71 165.66,34.28 165.66,34.28 165.22,34.72 160.67,34.72 158.63,32.67 154.99,32.67 154.67,32.99 153.84,32.99 153.56,33.27 153,33.27 152.1,32.37 149.16,32.37 v3(149.08,32.44)
  BOTTOM w0.102: UK1.101 151.62,35.17 150.88,34.43 150.88,33.51 150.64,33.27 149.91,33.27 v3(149.08,32.44) ; v3(207.67,36.95) JIO.26
VCIN0_PH: length 47.6
  TOP w0.254: PH1.1 134.28,58.26 135.19,57.36 v2(135.83,57.36) 139.75,57.36 142.29,54.82 v3(142.29,48.41)
  IN1 w0.127: v3(155.21,44.22) 155.03,44.39 154.57,44.39 152.83,46.13 152.83,46.71 151.79,47.75 149.63,47.75 148.5,48.88 147.51,48.88 147.06,49.32 143.2,49.32 v3(142.29,48.41)
  BOTTOM w0.102: PR9.2 153.89,49.41 153.54,49.05 153.54,47.21 154.87,45.87 154.87,44.93 155.21,44.59 v3(155.21,44.22) 155.39,44.04 155.39,43.21 155.65,42.95 155.65,40.24 153.78,38.37 UK1.109
VCIN1_AC_IN_R: length 90.5
  TOP w0.102: v3(207.04,63.29) 205.77,62.02 v1(204.44,62.02) 204.26,62.2 197.13,62.2 v3(196.95,62.02)
  IN1 w0.127: v3(207.04,63.29) 206.66,62.9 206.66,51.7 204.19,49.23 201.9,49.23 196.84,44.18 183.84,44.18 183.11,44.91 176.29,44.91 175.38,45.82 168.12,45.82 167.52,45.22 166.76,45.22 166.67,45.31 163.36,45.31 161.68,43.63 160.79,43.63 160.58,43.85 159.89,43.85 159.7,43.66 157.62,43.66 156.64,44.64 155.19,44.64 154.67,45.16 v3(154.47,45.16)
  BOTTOM w0.102: v3(196.95,62.02) 197.67,61.3 R5094.2 ; UK1.110 153.86,38.77 155.42,40.34 155.42,42.82 154.8,43.44 154.8,44.32 154.47,44.65 v3(154.47,45.16)
VCIN1_ACOK: length 4.7
  BOTTOM w0.102: v1(198.04,62.02) 198.04,60.04 197.9,59.9 R5094.1
  BOTTOM w0.254: PUB1.5 196.75,59.65 196.92,59.82 PRB15.2 197,59.89 197.01,59.9 R5094.1
VCIN1_PH: length 3.8
  BOTTOM w0.102: PR10.2 PR13.1 v1(151.21,35.47) 151.31,35.57 UK1.102
VD33STB: length 6.7
  TOP w0.102: RA23.1 13.1,36.87 12.25,36.03 v1(12.25,35.61)
  TOP w0.203: RA23.1 13.43,36.85 16.4,36.85 17.03,37.49 UA1.16
VGA_AC_DET: length 21.1
  TOP w0.102: v3(153.09,99.61) 153.28,99.61 153.7,99.18 v1(156.1,99.18) 156.41,99.18 157.04,98.55 158.9,98.55 159.62,97.82 159.62,97.07 160.39,95.2 161.09,94.16 162.87,92.37 163.68,92.37 163.94,92.12 RV2765.1 163.94,91.28 163.43,90.77 v3(163.07,90.77)
  BOTTOM w0.102: UV1.D7 153.5,99.2 v3(153.09,99.61) ; DV4.2 163.77,89.07 163.67,89.17 RV126.1 RV15.1 162.92,90.62 v3(163.07,90.77)
VID_PLLVDD: length 10
  TOP w0.102: v2(142.3,92.64) v3(141.41,92.64)
  BOTTOM w1.016: 130.28,93.37 130.6,93.05 139.31,93.05
  vias: v3(140.98,93.08) v3(146.44,98.74) v3(146.44,97.97)
VR_ALERT#: length 117.8
  IN2 w0.127: v3(199.88,78.76) 199.88,75.94 201.4,74.42 201.4,69.24 200.52,68.35 200.52,60.81 199.09,59.39 199.09,56.63 198.9,56.44 198.9,52.19 197.37,50.66 191.52,50.66 191.2,50.34 187.34,50.34 184.54,47.54 175.31,47.54 174.19,47.73 173.74,47.92 172.05,49.61 169.02,49.61 165.5,53.13 152.29,53.13 143.54,61.88 143.54,62.09 143.54,64.15 139.56,68.14 139.56,70.53 139.36,70.73 v3(139.36,70.89)
  BOTTOM w0.102: v3(139.36,70.89) 139.24,70.89 138.74,71.39 136.62,71.39 133.39,74.62 v1(130.93,74.62) 130.06,74.62 RC179.2 RC180.2
  BOTTOM w0.203: v3(199.88,78.76) 199.88,76.73 199.61,76.46 PUZ1.33
VR_HOT#: length 90.1
  TOP w0.102: v3(154.85,35.45) 154.85,35.58 155.83,36.57 156.72,36.57 156.96,36.81 156.96,38.51 158.43,39.97 158.78,39.97 159.37,40.57 159.37,41.45 162.94,45.02 168.44,45.02 171.73,48.3 171.73,48.62 v2(172.24,49.14) 172.78,49.68 v3(173.56,49.68)
  IN1 w0.127: v3(148.94,36.48) 149.25,36.79 149.77,36.79 149.94,36.61 149.94,35.88 150.28,35.55 154.75,35.55 v3(154.85,35.45)
  IN2 w0.127: v3(198.36,78.76) 198.74,78.38 198.74,75.97 199.75,74.95 199.75,63.78 197.34,61.37 197.34,59.51 197.75,59.1 197.75,52.11 197.05,51.42 191.2,51.42 190.88,51.1 187.02,51.1 184.41,48.48 177.43,48.48 176.7,49.21 174.03,49.21 v3(173.56,49.68)
  BOTTOM w0.102: PRZ100.2 v3(198.36,78.76) ; RK8.1 148.82,36.6 v3(148.94,36.48)
  BOTTOM w0.254: PRZ39.2 v3(198.36,78.76)
VR_ON: length 99.1
  TOP w0.102: v3(204.33,78.13) v2(205.48,78.13)
  IN1 w0.127: v3(160.4,43.43) 160.62,43.21 161.63,43.21 163.47,45.05 166.56,45.05 166.65,44.96 167.62,44.96 168.22,45.56 175.28,45.56 176.18,44.66 183,44.66 183.74,43.92 196.95,43.92 202,48.98 204.29,48.98 206.91,51.6 206.91,62.33 207.7,63.12 207.7,63.9 209.41,65.6 209.41,75.33 207.88,76.86 206.36,76.86 205.09,78.13 v3(204.33,78.13)
  BOTTOM w0.102: v3(160.4,43.43) 160.07,43.09 160.07,42.1 161.29,40.88 161.29,37.97 160.9,37.58 160.9,34.92 158.97,32.98 UK1.85
  BOTTOM w0.254: PRZ25.2 202.93,77.62 203.44,78.13 v3(204.33,78.13)
VR_PSYS: length 4.7
  TOP w0.254: PRZ20.1 201.21,71.25 PCZ7.1 v1(202.38,70.45) 202.89,70.45 v3(203.23,70.11)
  BOTTOM w0.203: PUZ1.46 202.37,70.58 202.84,70.11 v3(203.23,70.11)
VR_PWRGD: length 102.2
  TOP w0.102: v3(203.31,74.95) 203.31,75.5 v1(203.51,75.7)
  IN1 w0.127: v3(203.31,74.95) 203.31,78.24 203.83,78.76 205.09,78.76 206.51,77.34 208.29,77.34 209.66,75.97 209.66,65.44 207.96,63.74 207.96,63.02 207.26,62.32 207.26,51.59 204.4,48.72 202.11,48.72 197.06,43.67 183.63,43.67 182.89,44.41 176.08,44.41 175.17,45.31 168.33,45.31 167.73,44.71 166.55,44.71 166.45,44.8 163.81,44.8 v3(163.18,44.18)
  BOTTOM w0.102: v3(163.18,44.18) 163.18,44.18 163.18,43.95 163.67,43.46 163.67,41.02 163.89,40.79 163.89,38.93 164.86,37.96 164.86,33.96 164.57,33.66 UK1.71
  BOTTOM w0.203: PUZ1.38 202.12,73.78 203.28,74.95 v3(203.31,74.95) 203.69,75.33 PRZ23.1
VR_SVID_CLK: length 120
  TOP w0.102: v3(200.52,78.76) 200.52,79.18 v1(200.85,79.51)
  IN2 w0.127: v3(138.77,70.76) 139.3,70.23 139.3,68.03 143.29,64.05 143.29,62.2 143.29,61.78 152.19,52.88 165.39,52.88 168.91,49.36 171.94,49.36 173.6,47.7 174.12,47.49 175.29,47.28 184.64,47.28 187.44,50.08 191.3,50.08 191.62,50.4 197.48,50.4 199.16,52.09 199.16,56.34 199.35,56.53 199.35,59.29 200.77,60.71 200.77,68.24 201.66,69.13 201.66,74.61 200.13,76.13 200.13,78.38 v3(200.52,78.76)
  BOTTOM w0.076: UC1.AA1 126.11,74.07 128.52,74.07 128.89,73.7 129.68,73.7
  BOTTOM w0.102: PRZ98.2 v3(200.52,78.76) PRZ36.2 ; 129.68,73.7 130.44,73.7 130.87,74.14 133.19,74.14 136.44,70.89 138.64,70.89 v3(138.77,70.76)
VR_SVID_DATA: length 122.3
  TOP w0.102: v3(199.25,78.76) v1(199.25,79.55)
  IN1 w0.127: v3(131.06,75.49) 130.44,75.49 130.21,75.72 128.53,75.72 v3(128.23,75.42)
  IN2 w0.127: v3(199.25,78.76) 199.63,78.38 199.63,75.83 201.15,74.3 201.15,69.34 200.26,68.45 200.26,60.92 198.84,59.5 198.84,56.74 198.65,56.55 198.65,52.3 197.26,50.91 191.41,50.91 191.09,50.59 187.23,50.59 184.43,47.79 175.33,47.79 173.78,48.24 172.15,49.87 169.12,49.87 165.61,53.39 152.4,53.39 143.8,61.99 143.8,64.26 139.81,68.24 139.81,71.05 139.36,71.5 v3(139.29,71.5)
  BOTTOM w0.076: 127.84,74.73 125.79,74.73 125.31,74.24 UC1.AA2
  BOTTOM w0.102: PRZ38.2 v3(199.25,78.76) PRZ99.2 ; v3(139.29,71.5) 139.29,71.8 139.19,71.9 136.79,71.9 133.59,75.1 131.45,75.1 v3(131.06,75.49) ; RC181.2 129.03,76.22 v3(128.23,75.42) 128.23,75.11 127.84,74.73
VRAMCLK_SEL: length 12.9
  BOTTOM w0.076: 102.13,34.35 102.13,35.75 RC901.2 RC900.1 102.22,37.54 102.22,39.84 102.69,40.31 102.69,41.65 102.43,41.9 102.43,43.1 102.88,43.54 103.46,43.54 103.92,43.09 104.49,43.09 104.57,43.16 UC1.CL35
  BOTTOM w0.102: v1(102.13,34.13) 102.13,34.35
VREF: length 3.5
  TOP w0.203: CA31.2 16.97,33.07 v1(17.45,33.56) 18.61,34.72 UA1.22
VREF_NVVDD: length 3.4
  TOP w0.254: PCV21.1 121.43,139.85 121.76,139.52 PRV8.1 v1(122.03,138.48) 121.7,138.14 PUV1.8
VSEN_CORE: length 15.1
  BOTTOM w0.203: PRZ41.2 203.82,68.41 202.95,69.28 202.95,69.51 202.29,70.18 PUZ1.47
  BOTTOM w0.254: PRZ43.1 PCZ11.1 201.68,63.16 204.13,63.16 v1(205.22,64.26) 205.96,64.99 205.96,66.72 205.57,67.11 204.12,67.11 203.87,67.36 PRZ47.2 PRZ41.2
VSEN_GT: length 5.3
  BOTTOM w0.203: PUZ1.27 197.21,75.58 196.73,76.05 v1(196.73,76.23)
  BOTTOM w0.254: v1(196.73,76.23) 196.73,76.78 PCZ21.2
  BOTTOM w0.381: PCZ21.2 PRZ56.2 PRZ50.1 PRZ59.1
VSNS_NVVDD: length 5.5
  TOP w0.254: PRV31.1 RV217.2 PRV24.2 116.65,137.23 v3(115.93,137.94) v1(116.31,138.32) 116.82,138.83 PCV26.2
  BOTTOM w0.254: v3(115.93,137.94) 116.62,137.26 PRV30.2
VSNS_NVVDD_R: length 4.7
  TOP w0.203: v3(118.98,136.55) 119.77,136.22 PUV1.12
  BOTTOM w0.102: v1(115.57,136.34) PRV30.1
  BOTTOM w0.254: v3(118.98,136.55) 118.78,136.34 PRV32.1 PRV30.1
VTTREF_DDR: length 2.7
  BOTTOM w0.102: PCM15.1 5.7,75.06 4.34,75.06 v1(3.86,75.54)
WAKE#: length 21.7
  TOP w0.076: v1(98.64,46.43) 99.31,45.76 v3(99.36,45.76)
  IN2 w0.076: v3(107.32,50.69) 107.06,50.95 106.28,50.95 106.1,51.13 103.96,51.13 102.38,49.55 101.88,49.55 101.46,49.12 101.46,48.63 101.13,48.3 101.13,47.64 100.16,46.67 99.86,46.67 99.44,46.24 99.44,46.19 99.4,46.15 99.4,45.79 v3(99.36,45.76)
  BOTTOM w0.076: RC104.2 100.19,49.78 100.19,49.04 99.8,48.66 98.34,48.66 97.82,48.14 97.82,45.85 98.1,45.57 99.18,45.57 v3(99.36,45.76) ; UC1.BU30 107.32,51.68 v3(107.32,50.69)
WL_OFF#: length 137.1
  TOP w0.076: v1(116.85,44.05) 117.16,43.74 v3(117.16,43.6) 116.95,43.39 RC226.1
  IN1 w0.127: v3(117.16,43.6) 117.5,43.27 117.5,40.92 117.69,40.73 117.69,40.19 118.62,39.26 122.71,39.26 122.94,39.48 125.92,39.48 126.19,39.22 129.08,39.22 129.14,39.15 133.25,39.15 135.01,40.91 139.46,40.91 139.76,41.21 146.19,41.21 146.39,41.42 149.94,41.42 150.27,41.75 151.52,41.75 153.63,39.64 155.33,39.64 155.46,39.77 158.99,39.77 159.38,40.16 162.24,40.16 163.16,39.24 165,39.24 167.73,36.51 167.73,34.8 170.09,32.43 172.57,32.43 173.02,31.99 175.9,31.99 175.95,31.94 203.2,31.94 203.48,32.21 204.88,32.21 205.91,31.19 205.91,27.8 207.52,26.19 208.78,26.19 211.39,23.59 211.39,22.88 212.91,21.36 214.38,21.36 223.9,11.84 223.9,8.33 224.92,7.3 v3(225.94,7.3)
  BOTTOM w0.076: UC1.CM14 117.38,43.45 117.23,43.6 v3(117.16,43.6)
  BOTTOM w0.102: JWLAN.48 v3(225.94,7.3)
WL_PWREN_EC#: length 129
  TOP w0.102: QWL2.2 229.36,18.93 v3(228.81,19.48) ; v3(153.37,32.81) 154.01,32.81 v2(154.16,32.66)
  IN1 w0.127: v3(228.81,19.48) 230.45,19.48 230.97,18.96 232.39,18.96 232.85,18.5 ; 232.85,18.5 245.42,18.5 246.29,19.36 v3(248.01,19.36) ; 232.85,18.5 232.85,17.65 232.35,17.14 231.04,17.14 227.87,13.98 227.87,7.19 226.68,6 224.17,6 221.89,8.28 221.89,10.9 214.31,18.47 213.79,18.47 203.16,29.1 170.47,29.1 165.4,34.17 165.11,34.46 160.78,34.46 158.73,32.42 153.77,32.42 v3(153.37,32.81)
  BOTTOM w0.102: RWL1.1 v3(248.01,19.36) ; UK1.98 153.88,33.97 154.02,33.83 154.02,33.46 v3(153.37,32.81)
XCLK_BIASREF: length 4.9
  BOTTOM w0.114: UC1.CJ1 126.06,45.07 127.56,45.07 128.55,45.48 129.64,45.48 v1(129.71,45.55) 130.27,45.55 RC96.1
XDP_BPM#0: length 2
  BOTTOM w0.076: UC1.U1 126.06,76.8 126.83,76.8 127.36,77.32 T96.1
XDP_BPM#1: length 4.2
  BOTTOM w0.076: T103.1 128.23,77.43 127.81,77.01 127.27,77.01 126.87,76.61 126.27,76.61 126.08,76.42 125.75,76.42 125.49,76.68 UC1.U2
XDP_BPM#2: length 5.7
  BOTTOM w0.076: UC1.U3 124.64,76.9 124.73,76.99 125.12,76.99 125.12,76.99 126.79,76.99 127.45,77.65 128.42,77.65 T78.1
XDP_BPM#3: length 1.9
  TOP w0.076: T79.1 122.64,76.99 v3(122.89,77.24)
  BOTTOM w0.076: v3(122.89,77.24) 122.96,77.18 123.27,77.18 123.57,76.88 123.8,76.88 UC1.U4
XDP_ITP_PMODE: length 14.7
  TOP w0.076: v3(122.96,76.31) 122.96,76.5 123.5,77.04 123.83,77.04 124.02,77.24 124.06,77.24 125.22,78.4 v1(125.22,78.91) 125.22,79.03 125.38,79.19 125.38,82.72 125.15,82.95 125.15,83.99 125.91,84.75 125.91,85.14 126.72,85.95 127.12,85.95 127.28,86.1 127.28,86.91
  TOP w0.102: RC393.2 127.28,86.91
  BOTTOM w0.076: v3(122.96,76.31) 123.16,76.11 123.36,76.11 123.53,75.95 123.53,75.83 UC1.W4
XDP_PRDY#: length 2
  BOTTOM w0.076: UC1.W1 126.98,75.37 T178.1
XDP_PREQ#: length 13.7
  BOTTOM w0.076: 129.68,77.97 129.68,77.65 129.14,77.11 128.15,77.11 127.89,76.84 127.59,76.84 126.51,75.76 125.89,75.76 125.5,75.37 UC1.W2
  BOTTOM w0.102: 129.68,77.97 129.9,78.19 129.9,78.58 130.52,79.19 133.03,79.19 133.71,78.51 133.71,77.69 RC14.1 v1(133,75.84)
XGND: length 4.8
  TOP w0.127: v3(29.26,132.48) 28.81,132.48 v2(28.3,132.99)
  TOP w0.508: RL55.1 v3(29.26,132.48)
  BOTTOM w0.508: TSL1.25 28.49,132.48 v3(29.26,132.48)
XTAL_CLKREQ: length 162.9
  TOP w0.102: RC1154.1 113.62,34.32 v3(113.74,34.21)
  IN1 w0.127: v3(113.74,34.21) 113.74,33.8 113.93,33.61 116.51,33.61 117.3,34.41 120.8,34.41 121.14,34.07 125.78,34.07 126.97,32.88 130.57,32.88 130.85,33.17 136.43,33.17 136.93,33.68 137.26,33.68 137.42,33.51 140.44,33.51 141.29,32.66 144.15,32.66 145.08,33.59 147.7,33.59 147.9,33.38 150.04,33.38 150.17,33.52 153.67,33.52 153.94,33.26 154.76,33.26 155.09,32.93 158.52,32.93 160.57,34.97 165.32,34.97 165.91,34.38 170.33,29.97 200.87,29.97 201.82,30.92 204,30.92 205.15,29.76 205.15,27.47 213.89,18.73 214.44,18.73 222.14,11.03 222.14,8.39 224.28,6.26 226.58,6.26 227.62,7.3 227.62,14.46 v3(231.63,18.48)
  BOTTOM w0.076: v3(113.74,34.21) 112.69,34.21 112.45,34.45 112.45,36.47 110.8,38.13 110.56,38.71 110.56,39.43 109.94,40.05 109.94,41.71 109.81,42.02 109.81,42.29 109.89,42.48 109.89,43.32 109.87,43.33 109.87,44.05 109.58,44.34 108.85,44.34 108.63,44.56 108.63,45.22 UC1.CH29
  BOTTOM w0.102: RW4.2 v3(231.63,18.48)
XTAL_CLKREQ_R: length 5.9
  BOTTOM w0.102: JWLAN.14 228.41,17.8 228.84,18.23 229.78,18.23 RW4.1 230.49,18.93 232.09,18.93 v1(232.46,18.57)
XTAL_OUT: length 7.8
  BOTTOM w0.076: 155.69,102.08 155.59,102.08 155.53,102.02 154.75,102.02 154.67,101.94 154.67,101.76 154.75,101.68 UV1.B10
  BOTTOM w0.089: 155.69,102.08 155.69,102.08
  BOTTOM w0.102: 155.69,102.08 157.1,102.08 157.26,101.91 158.22,101.91 CV209.2 159.32,101.88 160.58,101.88 YV1.3
XTAL_OUTBUFF: length 7.8
  TOP w0.102: v3(157.81,99.68) v2(157.81,100.86)
  BOTTOM w0.102: RV23.1 RV20.1 159.07,99.29 158.2,99.29 v3(157.81,99.68) 157.24,100.25 157.03,100.25 156,101.28 154.7,101.28 UV1.C10
XTALIN: length 8.6
  BOTTOM w0.076: UV1.C11 154.64,102.18 155.46,102.18 155.62,102.35
  BOTTOM w0.102: 155.62,102.35 157.21,102.35 157.38,102.18 158.35,102.18 CV210.2 159.26,102.14 161.39,102.14 YV1.1
XTLI: length 6.5
  BOTTOM w0.203: 33.58,104.51 UL1.28
  BOTTOM w0.254: 33.58,104.51 33.82,104.28 33.82,103.53 34.35,103 RL7.2 34.2,102.61 CL25.2 34.2,101.73 33.76,101.3 33.76,100.41 34.06,100.12 34.19,100.12 YL1.1
XTLO: length 4.8
  BOTTOM w0.203: UL1.29 33.18,104.26
  BOTTOM w0.254: 33.18,104.26 33.23,104.21 v1(33.23,103.84) 33.23,102.97 RL7.1 33.43,101.98 CL24.2 33.09,101.63 33.09,100.88 YL1.3
N17253436: length 4.6
  BOTTOM w0.102: Q5001.3 144.26,34.17 144.05,34.37 144.05,35.87 144.43,36.25 R5093.2 144.43,36.95 v1(145.23,37.75)
N19936727: length 3.6
  BOTTOM w0.102: PQ2.6 179.65,69.52 180.07,69.11 v1(180.07,67.28)
N19936733: length 1
  BOTTOM w0.102: PR20.2 v1(177.2,67.91)
N19945980: length 2
  BOTTOM w0.102: PR1010.1 v1(188.25,89.26)
  BOTTOM w0.254: PR1010.1 188.18,90.54 PC1010.2
N19949685: length 3.1
  TOP w0.102: v1(202.43,71.88) 201.05,71.88 200.74,71.57 200.62,71.57 PRZ20.2
  TOP w0.254: PRZ20.2 PRZ31.1
N19949733: length 2.3
  TOP w0.102: PRZ48.2 197.85,78.84 v1(197.42,79.27)
  TOP w0.254: PRZ48.2 PRZ49.1
N19949817: length 3.7
  BOTTOM w0.102: v1(197.33,77.97) 197.54,77.97 PRZ100.1
  BOTTOM w0.203: PUZ1.31 198.81,76.71 PRZ100.1
N19949829: length 2
  TOP w0.102: PRZ3.2 v1(200.34,63.99)
  TOP w0.254: PRZ6.1 200.34,65.53 PRZ3.2
N19949837: length 1.1
  TOP w0.254: PRZ19.2 PRZ30.1
N19949849: length 4.1
  TOP w0.102: v1(202.95,66.14) 202.83,66.01 PRZ2.2
  TOP w0.254: PRZ5.1 200.59,67.75 200.59,66.89 201.15,66.33 PRZ2.2
N19949851: length 2.2
  TOP w0.102: PRZ4.2 197.65,64.62 197.42,64.4 v1(197.42,63.86)
  TOP w0.254: PRZ4.2 PRZ11.1
N19949853: length 2.2
  TOP w0.203: PRZ18.2 198.78,69.17 v1(198.2,69.75) 198.13,69.82 197.49,69.82 PRZ29.1
N19949855: length 0.8
  TOP w0.254: PRZ17.2 199.83,68.73 PRZ28.1
N19950053: length 2
  BOTTOM w0.102: v1(194.86,64.79) 194.42,65.23 PRZ51.2
  BOTTOM w0.254: PRZ51.2 PRZ52.1
N19950078: length 2.3
  BOTTOM w0.203: PRZ98.1 v1(200.52,76.21) 200.01,75.7 PUZ1.34
N19950080: length 2.1
  BOTTOM w0.203: PRZ99.1 199.21,77.12 v1(199.21,76.18) PUZ1.32
N19950082: length 2
  TOP w0.102: v1(191.36,72.49) PRZ64.2
  TOP w0.254: PRZ64.2 PRZ68.1
N19950094: length 2
  TOP w0.102: v1(191.4,69.29) PRZ63.2
  TOP w0.254: PRZ63.2 PRZ67.1
N19950096: length 2
  TOP w0.102: PRZ74.1 194.09,72.49 v1(194.41,72.8)
  TOP w0.254: PRZ74.1 PRZ71.2
N19950098: length 2.7
  TOP w0.102: PRZ73.1 193.67,69.29 194.31,69.92 v1(194.31,70.63)
  TOP w0.254: PRZ73.1 PRZ70.2
N19950243: length 1.9
  TOP w0.102: v1(199.94,77.35) 199.68,77.08 PRZ14.2
  TOP w0.254: PRZ14.2 PRZ13.1
N19951289: length 3.5
  BOTTOM w0.102: PCZ228.2 206.14,72.17 207.46,72.17 v1(207.87,72.58)
  BOTTOM w0.254: PCZ228.2 PRZ24.1
N19951364: length 2
  BOTTOM w0.102: PRZ66.2 v1(192.69,73.17)
  BOTTOM w0.254: PRZ69.1 PRZ66.2
N19954151: length 1
  BOTTOM w0.254: PRZ85.2 PRZ102.1
N19954155: length 2.3
  BOTTOM w0.102: PRZ87.2 v1(191.05,63.8)
  BOTTOM w0.254: PRZ103.1 PRZ87.2
N19954157: length 2.5
  BOTTOM w0.102: PRG9.1 v1(197.21,84.27)
  BOTTOM w0.254: PRG6.2 197.1,82.82 PRG9.1
N19955043: length 2.8
  BOTTOM w0.102: PRA9.1 208.78,73.62 v1(207.84,74.56)
  BOTTOM w0.254: PRA9.1 PRA6.2
N19956576: length 6.7
  BOTTOM w0.254: PUW1.11 188.33,134.06 188.48,133.92 v1(190.47,133.92) 190.98,133.92 191.82,133.08 PCW1.1 PCW4.1 193.16,132.77 PRW2.1 PRW1.2
N19967665: length 2.2
  BOTTOM w0.102: v1(187.88,130.74) PCW10.2
  BOTTOM w0.254: PRW10.1 188.69,131.97 PCW10.2
N25791938: length 5.5
  BOTTOM w0.102: v1(171.51,121.31) 171.81,121.31 173.71,123.21
  BOTTOM w0.508: RV200.1 172.63,124.93 173.71,123.86 173.71,123.21 QV50.1
N27704602: length 1.8
  TOP w0.102: v1(55.99,51.74) 55.84,51.9 RD11.2
  TOP w0.508: RD11.2 55.03,52.68 CD15.2
N27707230: length 2.3
  TOP w0.102: RD29.2 38.69,53.51 CD82.2 v1(37.31,54.39)
N29443682: length 4.9
  TOP w0.254: PRV10.1 PRV9.2 PRV8.2 121.59,140.88 v1(120.59,140.88) 119.68,140.88 PCV13.1
N31237512: length 2.5
  BOTTOM w0.102: UU1.10 7.78,85.71 7.29,86.2 RU1.2 6.97,86.66 7.13,86.82 v1(7.13,87.19)
N31237514: length 2.4
  BOTTOM w0.102: UU1.9 7.59,85.21 7.51,85.29 RU1.1 6.75,85.07 6.75,84.34 v1(6.79,84.3)
N31237586: length 2.9
  BOTTOM w0.102: UU1.16 11.53,86.87 12.06,87.41 T404.1
N31237588: length 2.4
  BOTTOM w0.102: T405.1 13.47,86.25 12.92,85.71 UU1.17
N31237590: length 1.6
  BOTTOM w0.102: UU1.18 13.7,85.21 T406.1
N31237594: length 4.1
  BOTTOM w0.102: T402.1 11.67,82.95 11.53,83.09 UU1.1
N31237596: length 1.8
  BOTTOM w0.102: T403.1 13.32,84.21 UU1.20
N32566675: length 4.7
  TOP w0.102: QV30.2 194.17,126.89 194.8,127.53 194.8,127.57 CV392.1 CV321.1 RV2747.2 194.24,129.45 v1(194.7,129.9)
N32566729: length 3.5
  TOP w0.102: QV30.5 194.17,124.01 CV317.1 194.69,123.88 RV2748.2 194.98,123.17 194.2,122.4 v1(193.98,122.4)
N34065508: length 7.6
  TOP w0.102: TS123.1 v3(188.91,40.6)
  BOTTOM w0.102: v3(188.91,40.6) 186.76,40.6 185.01,42.34 JSSD.10
N35399579: length 4.8
  BOTTOM w0.102: v1(246.83,21.43) RWL1.2 CWL1.1 249.08,21.43 QWL1.2
N36039023: length 3.1
  TOP w0.102: RA10.2 24.89,45.61 QA2.2 25.6,46.69 25.38,46.91 v1(25.38,47.52)
N36039105: length 5.3
  TOP w0.203: UA1.12 16.94,39.09 16.75,39.27 16.2,39.27 RA42.2
  TOP w0.254: RA41.2 13.56,38.7 v1(14.01,38.25) 15.55,38.25 15.81,38.5 RA42.2
N36039393: length 4.1
  TOP w0.203: UA1.32 22.56,36.29 23,36.29 23.24,36.05 23.24,35.59 v1(23.77,35.06) 24.71,34.12 CA27.1
N36039405: length 4.9
  TOP w0.102: v1(19.01,44.62) 19.01,42.92 19.24,42.69 CA28.1 19.5,41.75 19.81,41.44 UA1.6
N36039462: length 3.7
  TOP w0.102: CA42.1 15.82,41.36 15.38,41.8 RA17.1 RA16.2 v1(12.69,41.8)
N36040271: length 2.9
  TOP w0.102: RA53.1 CA34.2 20.15,44.47 19.52,45.11 v1(19.52,45.85)
N36339666: length 3.8
  TOP w0.102: RN7.1 226.28,20.32 v3(225.79,19.82) v1(225.1,19.82)
  BOTTOM w0.102: v3(225.79,19.82) 225.81,19.8 JWLAN.6
N37258528: length 2.5
  BOTTOM w0.203: C557.1 184.48,64.65 v1(184.48,65.45) 184.48,65.73 184.81,66.07 Q21.12
N37258636: length 2.3
  BOTTOM w0.203: C554.1 185.77,64.47 v1(185.77,65.49) 185.77,65.91 185.61,66.07 Q21.10
N38526335: length 2.4
  BOTTOM w0.102: v1(157.42,51.05) 157.81,51.43 CK9.2 RK109.1
N39192541: length 2
  TOP w0.102: v1(190.56,66.91) PRZ108.1
  TOP w0.381: PRZ108.1 PCZ232.2
N39192659: length 2
  TOP w0.102: PRZ109.1 190.56,64.23 v1(190.22,63.89)
  TOP w0.381: PRZ109.1 191.22,64.92 PCZ231.2
N39559226: length 2.3
  BOTTOM w0.102: v1(120.11,140.94) PRV13.1
  BOTTOM w0.254: PRV13.1 PRV11.2
N39644525: length 4.2
  TOP w0.254: PRV29.2 PCV18.1 v3(116.7,137.94)
  BOTTOM w0.102: v1(116.12,138.54) 116.7,137.97 v3(116.7,137.94)
  BOTTOM w0.254: PRV32.2 PRV33.1 116.87,138.12 v3(116.7,137.94)
N39815852: length 5.4
  TOP w0.102: RV16.2 RV17.2 ; RV17.2 180.15,129.18 179.94,128.98 QV3.2 ; RV17.2 180.68,129.53 180.59,129.61 CV121.1 CV391.1 180.59,131.23 v1(181,131.64)
N40833009: length 8.9
  BOTTOM w0.076: 102.73,34.35 102.73,39.79 104.42,41.49 UC1.CR35
  BOTTOM w0.102: T2406.1 103.31,33.76 102.73,34.35
N42543998: length 15.2
  TOP w0.102: v3(5.7,94.23) 5.82,94.1 RLED3.1
  IN1 w0.127: v3(3.63,82.6) 4.3,83.27 4.3,85.16 6.66,87.52 6.66,93.26 v3(5.7,94.23)
  BOTTOM w0.102: LED1.2 3.94,82.91 v3(3.63,82.6)
N43563713: length 7.3
  TOP w0.102: v3(87.14,25.17) 87.14,24.82 v1(86.95,24.63) 86.3,23.98 R5265.2 R5266.2
  BOTTOM w0.102: QC7.1 85.98,21.52 86.47,22.02 86.47,23.62 86.27,23.82 R5272.1 86.27,24.3 v3(87.14,25.17)
N43563982: length 4.3
  TOP w0.102: v1(84.31,22.96) 84.68,23.32 v3(84.68,23.37) 84.44,23.61 84.44,23.88 84.34,23.98 R5268.2 R5267.2
  BOTTOM w0.102: v3(84.68,23.37) QC7.4 84.68,22.15 84.51,21.99 84.32,21.99 84.02,22.3 R5271.1
N44699188: length 3
  TOP w0.102: R5273.2 227.82,18.26 QWL2.1 226.82,19.58 v1(226.64,19.76)
N91785360: length 11.2
  TOP w0.356: v3(20.87,123.13) v2(20.87,124.54) 20.87,126.19 20.57,126.5 QG1.3
  BOTTOM w0.381: v3(21.18,110.97) 20.99,110.97 20.68,111.27 RG112.1 ; RG113.1 RG114.1 20.43,114.32 20.74,114.02 v3(21.18,114.02) ; v3(21.18,120.11) 20.86,120.11 20.56,120.42 RG118.1 RG117.1 ; v3(20.87,123.13) 20.52,123.13 RG119.1 ; RG115.1 RG116.1 20.68,117.37 20.99,117.06 v3(21.19,117.06)
N100118189: length 11.9
  TOP w0.508: DL1.3 25.33,129.99 v1(26.09,129.24) 28.3,127.02 CL2.2 28.12,126.18 RL57.2 RL58.2 RL59.2 RL60.2
N101473516: length 2.5
  TOP w0.102: v1(155.64,131.55) RV116.1 157.5,131.55 v3(157.54,131.51)
  BOTTOM w0.102: v3(157.54,131.51) 157.54,131.51 UV6.J1
N101473793: length 5.7
  BOTTOM w0.102: UV6.J13 168.12,131.9 171.49,131.9 171.74,132.16 RV120.1 172.12,132.78 v1(172.12,133.43)
N101474312: length 2.9
  TOP w0.102: v3(164.53,131.51) 164.33,131.72 RV118.1 165.19,132.18 v1(165.49,132.49)
  BOTTOM w0.102: UV6.J10 v3(164.53,131.51)
N101484120: length 2.5
  TOP w0.102: v3(145.27,132.52) 145.88,132.52 RV117.1 v1(147.15,132.67)
  BOTTOM w0.102: v3(145.27,132.52) 145.27,132.51 UV7.J1
N101484397: length 4.7
  BOTTOM w0.102: UV7.J13 135.08,132.51 134.68,132.11 134.01,132.11 133.87,132.25 132.44,132.25 132.27,132.08 RV121.1 v1(130.68,132.08)
N101484914: length 6
  TOP w0.102: v3(138.07,132.53) 138.04,132.5 v1(134.3,132.5) 133.36,132.5 133.28,132.59 RV119.1
  BOTTOM w0.102: v3(138.07,132.53) 138.05,132.51 UV7.J10
N114621639: length 3.2
  TOP w0.102: CC95.1 145.7,44.85 144.99,44.85 v1(144.83,45.02)
  TOP w0.203: CC95.1 145.45,44.19 145.45,43.78 145.63,43.6 UC6.12
N114621686: length 3.2
  TOP w0.102: v1(148.13,44.65) CC94.1
  TOP w0.203: CC94.1 146.74,44.65 146.45,44.36 146.45,43.62 146.43,43.6 UC6.10
N119900622: length 4
  BOTTOM w0.102: UV1.A10 157.1,100.48 157.37,100.48 157.73,100.12 v1(158.23,100.12) 158.99,100.12 RV21.1
N119904431: length 9.9
  TOP w0.102: RV43.2 160.79,117.5 v1(160.6,117.31) 157.34,114.04 155.93,114.04 155.49,114.48 v3(155.49,114.5)
  BOTTOM w0.102: UV1.B25 v3(155.49,114.5)
N119904459: length 11.4
  TOP w0.102: v3(153.92,112.02) 154.7,112.02 155.1,112.42 156.68,112.42 v1(158.38,114.13) 159.98,115.72 RV41.1
  BOTTOM w0.381: UV1.D22 v3(153.92,112.02)
N119904461: length 10.7
  TOP w0.102: v3(154.7,113.7) 155.14,113.26 155.66,113.26 156.21,113.81 157.59,113.81 v1(159.51,115.73) 160.38,116.61 RV42.2
  BOTTOM w0.102: UV1.C24 v3(154.7,113.7)
N119910434: length 2.8
  TOP w0.102: v3(152.21,112.07) 152.21,112.2 151.93,112.48 v1(151.93,112.48) 151.78,112.33 151.78,111.64 151.36,111.21 RV82.1
  BOTTOM w0.102: v3(152.21,112.07) 151.8,111.66 UV1.F22
N119910451: length 2.3
  TOP w0.102: RV83.1 149.1,111.44 v1(149.31,111.65) v3(149.73,112.07)
  BOTTOM w0.102: UV1.J22 v3(149.73,112.07)
N124440208: length 1.1
  BOTTOM w0.076: RC102.1 T140.1
N124859178: length 1.6
  TOP w0.076: v3(122.25,67.96) 121.76,67.96 T276.1
  BOTTOM w0.076: v3(122.25,67.96) 122.28,67.96 122.28,67.94 121.95,67.61 UC1.AM7
N125272452: length 3
  TOP w0.076: v1(111.34,53.34) v3(110.97,53.7) 110.97,53.86 110.74,54.1 CC71.1
  BOTTOM w0.076: v3(110.97,53.7) 110.98,53.7 111.31,54.03 UC1.BP24

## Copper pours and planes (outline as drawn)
3V_SN on BOTTOM (solid shape): 183.54,120.34 183.54,118.59 183.33,118.38 181.5,118.38 181.35,118.54 181.35,119.21 181.47,119.32 182.12,119.32 182.28,119.48 182.28,120.33 182.39,120.44 183.43,120.44
5V_SN on TOP (solid shape): 182.8,104.63 182.8,103.67 182.66,103.53 181.87,103.53 181.75,103.4 181.75,102.76 181.62,102.64 181.11,102.64 180.98,102.76 180.98,104.65 181.11,104.78 182.65,104.78
+0.6V_0.6VS on TOP (solid shape): 42.65,27.92 42.65,25.17 42.45,24.96 42.02,24.96 41.7,25.28 41.2,25.28 39.69,26.79 39.1,26.79 38.97,26.92 38.97,27.96 39.1,28.09 41.56,28.09 41.72,28.24 42.33,28.24
+0.6V_0.6VS on TOP (solid shape): 57.36,24.23 57.36,23.6 57.29,23.54 54.56,23.54 54.09,23.07 53.68,23.07 53.45,22.83 53.45,22.17 53.43,22.14 52.09,22.14 52.04,22.2 52.04,23.23 52.13,23.32 52.58,23.3 52.72,23.72 52.83,23.83 53.96,23.83 54.7,24.58 54.74,24.58 54.9,24.74 56.85,24.74
+0.6V_0.6VS on BOTTOM (solid shape): 57.44,25.72 57.44,24.26 57.08,23.9 55.23,23.9 54.85,24.28 54.85,25.4 55.31,25.86 55.31,26.26 55.18,26.38 53.48,26.38 53.42,26.45 53.42,26.64 53.48,26.7 56.46,26.7
+0.6V_0.6VS on BOTTOM (solid shape): 3.64,73.49 3.64,73.35 3.63,73.35 3.63,73.04 3.64,73.04 3.64,72.97 3.66,72.95 4.11,72.95 4.27,72.79 4.47,72.79 4.66,72.6 4.66,72.12 4.58,72.04 3.11,72.04 2.99,72.15 2.99,72.95 3.4,72.95 3.42,72.97 3.42,73.5 3.43,73.51 3.62,73.51
+0.6V_0.6VS on IN1 (solid shape): 32.41,33.32 32.41,31.94 31.96,31.49 30.32,31.49 30.01,31.81 30.01,33.19 30.37,33.56 31.21,33.56 31.43,33.78 31.95,33.78
+0.6V_0.6VS on BOTTOM: 40.14,26.67 40.21,26.74 42.52,26.74 43.92,25.34 43.92,23.41 43.61,23.1 38.75,23.1 36.57,25.28 36.57,27.45 35.05,28.98 32.7,28.98 30.25,31.43 30.25,32.68 30.77,33.21 32.79,33.21 38.4,27.59 38.4,26.26 39.42,25.24 41.33,25.24 42,25.91 42,26.15 41.79,26.35 40.21,26.35 40.09,26.47 40.09,26.57 40.12,26.62
+0.6V_0.6VS on IN1: 4.82,69.49 3.39,70.92 3.39,72.93 3.79,73.34 6.08,73.34 6.56,72.85 6.56,70.01 6.04,69.49
+0.6V_DDRB_VREFCA on TOP: 40.24,52.38 40.24,50.76 40.08,50.6 39.8,50.6 39.41,50.21 39.41,49.82 39.58,49.66 39.8,49.66 40.24,49.22 40.24,48.25 40.58,47.91 40.99,47.91 41.05,47.97 41.05,51.8 41.11,51.85 41.8,51.85 41.86,51.91 41.86,52.37 41.76,52.47 40.34,52.47
+0.6VSP on BOTTOM (solid shape): 4.24,74.84 5.79,74.84 5.84,74.89 7.36,74.89 7.4,74.88 7.44,74.87 7.83,74.87 7.89,74.82 7.89,74.68 7.85,74.64 6.84,74.64 6.28,74.36 6.83,74.05 8.25,74.05 8.3,74 8.3,73.21 7.87,72.77 7.87,71.77 7.78,71.68 7.25,71.68 7.18,71.75 7.18,72.63 6.89,72.92 4.32,72.92 4.05,73.19 4.04,73.19 4.04,73.68 3.03,73.68 3.03,74.63 3.28,74.89 4.19,74.89
+1.0VS_DGPU on TOP (solid shape): outline of 485 points within 124.57,98.83 141.13,119
+1.0VS_DGPU on BOTTOM (solid shape): 126.52,100.99 126.52,96.19 126.89,95.82 126.89,95.15 126.81,95.07 125.78,95.07 125.35,95.5 125.35,100.99 125.5,101.13 126.38,101.13
+1.0VS_DGPU on BOTTOM (solid shape): outline of 889 points within 129.17,101.34 140.44,120.1
+1.0VS_PLLAVDD on BOTTOM (solid shape): 131.56,112.14 131.56,111.38 131.69,111.25 132.18,111.25 132.19,111.25 132.83,111.25 132.85,111.25 133.46,111.25 133.72,111 133.72,110.49 133.59,110.36 130.54,110.36 130.29,110.61 130.29,112.01 130.54,112.27 131.43,112.27
+1.0VS_PLLAVDD on IN2 (solid shape): outline of 1301 points within 132.58,106.04 152.03,112.01
+1.2V_VDDQ on BOTTOM (solid shape): 8.24,56.79 13.71,56.79 13.95,56.54 13.95,53.27 13.72,53.03 4.9,53.03 4.67,53.25 4.67,57.11 4.76,57.2 7.82,57.2
+1.2V_VDDQ on BOTTOM (solid shape): outline of 121 points within 61.51,50.01 64.52,65.51
+1.2V_VDDQ on BOTTOM (solid shape): outline of 150 points within 39.09,50.77 41.89,65.5
+1.2V_VDDQ on BOTTOM (solid shape): outline of 305 points within 48.26,50.12 55.46,65.73
+1.2V_VDDQ on TOP: outline of 1014 points within 5.44,29.15 108.88,91.23 ; 4 cut-outs
+1.2VP on BOTTOM (solid shape): 14.25,61.7 14.25,59.2 14.12,59.08 9.13,59.08 7.98,57.93 4.7,57.93 4.55,58.08 4.55,58.45 5.19,59.09 5.19,61.76 6.63,63.21 12.74,63.21
+1.05V_MPHYPLL on TOP (solid shape): 126.96,54.92 127.22,54.92 127.38,54.77 127.38,51.39 127.26,51.27 125.31,51.27 124.99,51.59 124.99,54.08 126.16,54.08 126.16,54.03 126.16,53.98 126.18,53.93 126.2,53.88 126.23,53.84 126.27,53.81 126.31,53.77 126.36,53.75 126.41,53.74 126.46,53.73 126.51,53.73 126.56,53.74 126.61,53.75 126.66,53.77 126.7,53.81 126.74,53.84 126.77,53.88 126.79,53.93 126.81,53.98 126.82,54.03 126.82,54.08 126.81,54.13 126.79,54.18 126.77,54.23 126.74,54.27 126.7,54.31 126.66,54.34 126.61,54.36 126.56,54.38 126.51,54.39 126.46,54.39 126.41,54.38 126.36,54.36 126.31,54.34 126.27,54.31 126.23,54.27 126.2,54.23 126.18,54.18 126.16,54.13 126.16,54.08 124.99,54.08 124.99,54.16 124.74,54.41 124.38,54.41 124.35,54.44 124.35,55.23 124.46,55.33 126.55,55.33
+1.05V_PRIM on TOP (solid shape): 176.07,90.33 176.77,90.33 176.77,90.86 177.27,90.86 177.27,90.33 177.97,90.33 177.97,90.86 178.57,90.86 178.75,90.68 178.75,88.05 178.47,87.76 174.09,87.76 173.93,87.92 173.93,89.65 174.09,89.81 174.93,89.81 175.17,90.05 175.17,90.66 175.37,90.86 176.07,90.86
+1.05V_PRIM on TOP (solid shape): 144.71,41.29 145.21,41.29 145.33,41.16 145.33,40.58 145.03,40.28 144.65,40.28 144.33,40.47 144.02,40.28 143.85,40.28 143.44,40.69 142.69,40.69 141.83,39.82 141.26,39.82 140.75,40.33 140.75,41.24 141.7,42.19 143.8,42.19
+1.05V_PRIM on TOP (solid shape): 112.14,99.97 112.23,99.91 112.22,99.81 112.5,99.23 112.79,99.81 112.78,99.91 112.87,99.97 113.2,99.97 113.73,99.44 113.8,99.44 114.03,99.21 114.99,99.21 115.17,99.39 115.17,99.79 115.35,99.97 116.82,99.97 119.55,97.24 119.55,95.46 119.36,95.27 117.13,95.27 116.95,95.45 116.95,96.67 116.06,97.56 112.63,97.56 112.57,97.49 112.42,97.49 112.12,97.19 112.31,96.81 112.31,96.54 112.21,96.44 111.15,96.44 111.05,96.53 111.05,97.15 111.04,97.15 111.04,97.18 110.55,97.18 110.54,97.19 110.54,97.61 111.03,97.61 111.04,97.62 111.04,97.7 111.05,97.7 111.05,98.35 111.04,98.35 111.04,98.38 110.56,98.38 110.54,98.41 110.54,98.79 110.55,98.8 111.03,98.8 111.04,98.81 111.04,98.85 111.05,98.85 111.05,98.96 111.06,98.96 111.06,99.55 111.05,99.56 111.05,99.63 111.04,99.63 111.04,99.97
+1.05V_PRIM on TOP (solid shape): outline of 257 points within 119.81,105.02 132.32,119.97
+1.05V_PRIM on BOTTOM (solid shape): 128.76,121 128.76,118.31 128.58,118.13 127.81,118.13 127.63,118.31 127.63,118.71 127.45,118.89 126.53,118.89 126.35,119.07 126.35,121 126.53,121.18 128.58,121.18
+1.05V_PRIM on BOTTOM (solid shape): 123.3,106.76 123.3,106.13 121.43,104.26 121.43,97.41 119.24,95.22 119.21,95.23 119.03,95.24 118.87,95.15 118.15,95.15 116.57,96.73 116.57,105.92 119.76,109.11 120.95,109.11
+1.05V_PRIM on BOTTOM (solid shape): outline of 997 points within 112.35,47.76 119.57,54.95
+1.05V_PRIM on IN2 (solid shape): outline of 220 points within 119.77,105.04 130.92,119.98
+1.05V_PRIM on TOP: outline of 180 points within 112.97,38.76 136.51,57.64
+1.05V_PRIM on VCC: 127.72,35.33 123.79,39.26 122.39,39.26 120.36,41.3 114.43,41.3 112.4,39.26 109.44,39.26 108.82,39.88 108.82,53.64 109.44,54.25 111.64,54.25 112.65,53.23 119.51,53.23 129.67,43.07 130.56,43.07 130.79,42.84 130.79,41.82 131.32,41.3 133.18,41.3 133.71,41.82 133.71,42.71 134.07,43.07 142.84,43.07 151.09,51.33 153.89,51.33 157.21,54.65 157.21,87.5 156.3,88.41 116.93,88.41 116.31,89.03 116.31,97.7 116.93,98.32 117.48,98.32 123.19,92.6 158.37,92.6 161.8,89.17 170.78,89.17 174.21,92.6 175.77,92.6 176.64,91.74 176.64,81.05 175.52,81.05 174.61,80.14 174.61,61.72 173.46,60.58 173.46,57.19 174.61,56.05 174.61,43.69 166.25,35.33 161.25,35.33 160.49,36.09 156.85,36.09 156.09,35.33 ; 1 cut-out
+1.05V_PRIMP on TOP (solid shape): 178.9,93.41 178.9,91.33 178.58,91.01 175.35,91.01 175.22,91.14 175.22,93.45 175.44,93.67 178.64,93.67
+1.05V_PRIMP on BOTTOM (solid shape): 176.82,99.49 176.82,97.89 178.64,96.07 178.64,90.1 178.42,89.88 174.99,89.88 174.86,90.01 174.86,92.19 174.4,92.66 174.4,98.24 174.57,98.41 175.44,98.41 175.83,98.8 175.83,99.63 175.94,99.73 176.57,99.73
+1.05V_VCCST on TOP (solid shape): 121.01,53.79 121.01,53.08 120.76,52.82 119.33,52.82 119.05,53.11 119.05,53.93 119.11,54 120.81,54
+1.05V_VCCST on TOP (solid shape): 143.54,46.88 143.54,46.33 143.54,46.33 143.54,45.74 143.54,45.72 143.54,45.4 143.63,45.31 144.06,45.31 144.16,45.21 144.16,44.43 144.07,44.34 142.35,44.34 142.22,44.47 142.22,46.88 142.35,47.01 143.42,47.01
+1.05V_VCCST on IN1 (solid shape): outline of 419 points within 119.14,51.75 127.33,55.33
+1.05V_VCCSTU_IN on TOP (solid shape): 145.33,43.45 145.33,42.7 145.21,42.57 142.6,42.57 142.48,42.7 142.48,43.45 142.6,43.58 145.21,43.58
+1.05VS_VCCIO on TOP (solid shape): 116.27,54.54 116.27,54.3 116.18,54.21 116.18,53.61 116.03,53.46 115.3,53.46 115.16,53.6 115.16,53.97 115.26,54.07 115.26,54.54 115.3,54.58 115.84,54.58 115.91,54.64 116.17,54.64
+1.05VS_VCCIO on TOP (solid shape): outline of 4531 points within 85.81,55.42 113.75,98.45
+1.05VS_VCCIO on BOTTOM (solid shape): 110.09,69.04 110.19,68.94 110.32,68.97 110.42,69.04 110.48,69.03 110.53,69.04 110.63,68.95 110.75,68.91 110.86,68.97 110.92,69.02 111,69.01 111.21,68.96 111.4,69.06 111.42,69.07 111.5,69.07 112.04,68.53 112.04,67.72 111.57,67.26 111.02,67.26 110.95,67.26 110.89,67.26 110.09,67.26 110.02,67.26 109.96,67.26 109.49,67.26 109.45,67.3 109.43,67.3 109.39,67.32 109.35,67.37 109.35,67.48 109.24,67.58 109.24,68.61 109.7,69.07 110.07,69.07
+1.05VS_VCCIO on BOTTOM (solid shape): 109.42,58.08 111.32,58.08 111.44,58.07 111.55,58.11 111.62,58.11 111.77,58.05 111.92,58.07 111.98,58.01 111.98,56.7 111.78,56.5 111.37,56.5 111.08,56.78 111.06,56.78 111.03,56.81 110.85,56.81 110.77,56.79 110.66,56.75 110.49,56.81 110.31,56.75 110.25,56.74 110.19,56.77 110.12,56.78 109.93,56.78 109.86,56.77 109.8,56.74 109.61,56.8 109.48,56.8 109.43,56.75 109.4,56.73 109.38,56.71 109.19,56.71 109,56.9 109,57.2 109.03,57.22 109.16,57.45 109,57.68 109,58.04 109.11,58.15 109.35,58.15
+1.05VS_VCCIO on IN1 (solid shape): outline of 110 points within 110.85,53.36 116.44,57.58
+1.05VS_VCCIO on IN2 (solid shape): outline of 2570 points within 108.92,56.39 117.58,80.2
+1.05VS_VCCSTG_IO on TOP (solid shape): 110.93,99.5 110.93,99.02 110.86,98.95 110.4,98.95 110.4,98.25 110.92,98.25 110.92,98.22 110.92,97.83 110.92,97.75 110.4,97.75 110.4,97.05 110.49,97.05 110.5,97.05 110.92,97.05 110.92,97.03 110.92,96.43 111.12,96.23 112.84,96.23 113.14,96.06 113.44,96.23 114.4,96.23 114.57,96.39 114.57,97.08 114.71,97.22 116.02,97.22 116.57,96.67 116.57,95.65 116.46,95.55 115.79,95.55 114.87,94.64 107.17,94.64 106.73,94.19 106.73,93.3 106.54,93.11 105.9,93.11 105.77,93.24 105.77,98.13 105.85,98.2 107.41,98.2 107.74,98.53 107.74,98.84 108.49,99.59 110.84,99.59
+1.8V_PRIM on TOP (solid shape): 117.05,48.11 117.18,47.99 117.18,46.97 117.09,46.88 114.73,46.88 114.63,46.98 114.63,47.91 114.74,48.03 115.5,48.03 115.58,47.99 115.6,47.91 115.96,47.52 116.24,47.97 116.25,48.07 116.33,48.11 116.68,48.11
+1.8V_PRIM on TOP (solid shape): 147.56,41.23 147.56,40.93 147.75,40.74 147.92,40.74 148,40.72 148.06,40.71 148.7,40.71 148.77,40.72 148.85,40.74 148.86,40.74 148.95,40.65 148.95,40.35 148.92,40.27 148.84,40.25 148.47,40.08 148.5,39.68 148.51,39.57 148.42,39.51 148.23,39.51 148.01,39.29 147.58,39.29 147.52,39.3 147.46,39.3 146.72,40.04 146.72,41.23 146.8,41.31 147.47,41.31
+1.8V_PRIM on BOTTOM (solid shape): 147.94,40.09 147.94,39.45 147.8,39.31 146.77,39.31 146.51,39.56 146.51,40.21 146.63,40.32 147.72,40.32
+1.8V_PRIM on BOTTOM (solid shape): 182.34,79.32 182.84,79.32 182.84,79.85 183.14,79.85 183.14,79.32 183.64,79.32 183.64,79.85 184.14,79.85 184.14,79.84 184.45,79.84 184.52,79.77 184.52,78.24 184.42,78.14 181.3,78.14 181.2,78.25 181.2,79.65 181.4,79.85 182.34,79.85
+1.8V_PRIM on BOTTOM (solid shape): 116.04,42.07 116.04,41.86 116.01,41.83 115.98,41.77 115.97,41.76 115.95,41.71 115.95,41.1 115.69,40.84 115.66,40.84 115.21,40.95 115.08,40.51 115.04,40.47 115.04,40.09 114.54,39.58 114.54,39.2 114.66,39.07 115.81,39.07 115.93,38.95 116.31,38.95 116.44,38.82 116.44,37.8 116.57,37.68 117.06,37.68 117.15,37.76 117.15,39.55 117.24,39.64 117.5,39.64 117.58,39.55 117.58,36.66 117.33,36.41 115.3,36.41 115.08,36.62 115.08,37.76 114.98,37.87 113.9,37.87 111.48,40.29 111.48,41.12 111.85,41.49 111.85,41.84 112.02,42.02 112.29,42.02 112.6,41.71 112.58,41.67 112.55,41.61 112.54,41.55 112.54,41.46 112.56,41.38 112.61,41.31 112.61,41.3 112.76,41.14 112.76,40.66 113.1,40.32 113.94,40.32 114.18,40.56 114.19,40.56 114.97,41.33 115.04,41.36 115.11,41.32 115.35,41.26 115.5,41.46 115.5,41.55 115.48,41.62 115.45,41.68 115.43,41.75 115.46,41.82 115.72,42.08 115.72,42.09 115.77,42.14 115.97,42.14
+1.8V_PRIM on IN1 (solid shape): 147.84,40.02 147.84,39.41 147.73,39.3 147.53,39.3 147.49,39.3 147.45,39.3 147.01,39.3 146.61,39.69 146.61,39.85 146.98,40.22 147.63,40.22
+1.8V_PRIM on IN1 (solid shape): outline of 350 points within 114.47,38.44 117.91,48.15
+1.8V_PRIM on VCC: 127.22,33.55 124.93,35.83 123.79,35.83 121.88,37.74 114.13,37.74 113.27,38.61 113.27,39.41 114.64,40.79 120.15,40.79 122.18,38.76 123.58,38.76 127.51,34.82 156.3,34.82 157.06,35.58 160.28,35.58 161.04,34.82 166.46,34.82 175.12,43.48 175.12,56.26 173.97,57.4 173.97,60.37 175.12,61.51 175.12,79.92 175.73,80.54 183.9,80.54 184.26,80.18 184.26,77.98 184.03,77.74 178.06,77.74 177.27,76.96 177.27,41.15 169.68,33.55
+1.8VS on TOP (solid shape): 148.01,43.77 148.14,43.77 148.32,43.59 148.32,43.33 148.19,43.2 147.68,43.2 147.56,43.07 147.56,42.7 147.43,42.57 146.86,42.57 146.73,42.7 146.73,44.14 146.8,44.22 147.56,44.22
+1.8VS on BOTTOM (solid shape): 147.71,44.45 147.71,43.77 147.63,43.69 146.77,43.69 146.57,43.89 146.57,44.4 146.79,44.61 147.54,44.61
+1.8VS_AVDD on TOP (solid shape): 23.8,36.27 23.8,35.92 24.71,35.01 25.37,35.01 27.26,33.12 27.26,32.56 27.22,32.52 26.82,32.52 26.35,32.99 25.64,32.99 25.51,33.11 25.51,33.78 23.57,35.73 23.57,36.21 23.19,36.58 22.17,36.58 22.11,36.64 22.11,36.73 22.17,36.79 23.28,36.79
+1.8VSP on BOTTOM (solid shape): 182.45,83.81 182.45,82.73 182.6,82.57 184.97,82.57 185.1,82.44 185.1,80.23 184.87,80 181.67,80 181.36,80.3 181.36,83.76 181.49,83.89 182.37,83.89
+1.35VRAMP on BOTTOM (solid shape): 178.86,141.69 178.86,129.56 178.74,129.43 176.36,129.43 176.33,129.46 176.33,130.24 176.32,130.24 176.32,130.26 175.81,130.26 175.81,130.71 176.32,130.71 176.32,130.73 176.33,130.73 176.33,131.44 176.32,131.44 176.32,131.46 175.81,131.46 175.81,131.91 176.32,131.91 176.32,131.93 176.33,131.93 176.33,132.71 176.32,132.71 176.32,133.42 175.59,134.16 174.64,134.16 174.64,134.16 174.35,134.16 174.11,134.4 174.11,141.7 174.22,141.82 178.74,141.82
+1.35VS_VRAM on TOP (solid shape): outline of 13721 points within 131.17,104.01 175.23,141.75
+1.35VS_VRAM on BOTTOM (solid shape): 176.2,133.23 176.2,132.03 175.68,132.03 175.68,131.33 176.2,131.33 176.2,130.84 175.68,130.84 175.68,130.13 176.2,130.13 176.2,129.48 176.13,129.42 175.28,129.42 175.27,129.43 174.37,129.43 174.1,129.7 174.1,133.5 174.29,133.69 175.74,133.69
+1.35VS_VRAM on BOTTOM (solid shape): 168.66,127.67 168.74,127.55 168.86,127.47 168.87,127.46 169.02,127.31 171.18,127.31 171.31,127.18 171.31,126.67 171.44,126.54 172.83,126.54 172.96,126.42 172.96,125.91 172.83,125.78 172.2,125.78 172.07,125.65 170.29,125.65 169.98,125.34 168.77,125.34 168.77,125.35 168.7,125.4 168.62,125.43 168.61,125.44 168.45,125.59 168.45,125.6 168.39,125.72 168.29,125.81 168.26,125.83 168.26,126.02 168.36,126.09 168.42,126.19 168.43,126.2 168.63,126.4 168.64,126.41 168.83,126.59 168.82,126.85 168.82,126.88 168.34,127.36 168.34,127.59 168.44,127.69 168.64,127.69
+1.35VS_VRAM on BOTTOM (solid shape): 144.36,139.05 144.35,139.02 144.4,138.71 144.68,138.57 145.12,138.57 145.48,138.22 145.48,137.96 145.17,137.66 144.68,137.66 144.68,137.66 144.64,137.67 144.62,137.71 144.53,137.95 144.3,138.05 144.24,138.08 144.1,138.35 143.89,138.44 143.87,138.44 143.81,138.5 143.81,138.54 143.82,138.58 143.86,138.59 144.12,138.7 144.2,138.97 144.2,139 144.31,139.11
+1.35VS_VRAM on BOTTOM (solid shape): outline of 189 points within 140.8,103.97 152.1,111.06
+1.35VS_VRAM on BOTTOM (solid shape): outline of 774 points within 158.79,132.13 171.82,140.99
+1.35VS_VRAM on BOTTOM (solid shape): outline of 1485 points within 130.67,133.01 160.2,140.99
+1.35VS_VRAM on IN1 (solid shape): outline of 619 points within 158.36,125.27 162.02,133.78
+1.35VS_VRAM on IN1 (solid shape): outline of 4947 points within 133.59,104.22 176.39,141.5
+1.35VS_VRAM on IN2 (solid shape): outline of 6429 points within 130.16,100.07 176.38,141.51
+2.5V on TOP (solid shape): 35.4,50.07 35.4,22.64 36.16,21.88 42.57,21.88 43.7,23.01 46.19,23.01 46.46,23.28 46.46,24.68 46.57,24.79 47.99,24.79 48.37,25.17 51.08,25.17 51.55,24.7 51.87,24.7 52.05,24.52 52.05,24.28 51.93,24.16 47.91,24.16 47.79,24.04 47.79,22.93 47.99,22.74 47.99,22.11 48.22,21.88 51.6,21.88 51.6,21.88 58.65,21.88 59.22,22.46 59.22,25.87 59.43,26.08 61.44,26.08 61.67,25.85 61.67,23.93 61.75,23.85 61.75,21.06 61.42,20.73 33.89,20.73 33.51,21.1 33.51,48.84 33.15,49.2 15.78,49.2 15.42,48.84 15.42,46.73 15.06,46.38 11.39,46.38 11.03,46.02 11.03,37.34 10.67,36.98 3.77,36.98 3.41,37.34 3.41,38.14 3.77,38.5 9.28,38.5 9.63,38.86 9.63,47.29 9.99,47.65 13.09,47.65 13.44,48 13.44,50.46 13.8,50.82 34.65,50.82
+2.5V on BOTTOM (solid shape): 5.1,37.86 5.1,36.89 5.05,36.84 3.69,36.84 3.62,36.91 3.62,37.83 3.68,37.9 3.79,37.9 3.79,37.9 5.06,37.9
+2.5V on BOTTOM (solid shape): 50.14,26.73 50.14,25.55 50.83,24.87 50.83,24.45 50.54,24.17 48.74,24.17 48.29,24.62 48.29,26.8 48.42,26.93 49.94,26.93
+2.5V on BOTTOM (solid shape): 63.4,26.84 63.4,26.17 63.38,26.06 63.4,25.94 63.4,24.88 62.46,23.94 60.05,23.94 59.66,24.33 59.66,25.51 61.09,26.94 63.3,26.94
+2.5VP on BOTTOM (solid shape): 6.33,40.66 8.62,40.66 8.71,40.57 8.71,38.73 8.57,38.6 3.62,38.6 3.53,38.69 3.53,40.75 3.6,40.83 6.16,40.83
+3V_FPR on BOTTOM (solid shape): 254.91,29.41 254.91,27.6 254.81,27.5 252.88,27.5 252.66,27.72 252.66,28.16 253.08,28.58 253.08,29.45 253.28,29.64 254.67,29.64
+3V_LID on TOP (solid shape): 16.3,140.42 16.33,140.42 16.33,139.44 15.72,138.83 15.72,137.91 16.31,137.31 16.31,137.25 16.57,137 16.62,137 16.67,136.96 16.67,135.25 16.82,135.09 16.82,134.52 16.96,134.38 17,134.38 17.32,134.06 17.32,133.59 17.2,133.48 16.4,133.48 15.7,134.18 15.7,134.46 15.54,134.61 14.66,134.61 14.52,134.75 14.52,134.96 14.52,135 14.51,135.05 14.51,140.54 14.63,140.65 16.07,140.65
+3V_PRIM on TOP (solid shape): outline of 610 points within 110.7,40.66 116.26,56.33
+3V_PRIM on BOTTOM (solid shape): 113.48,48.78 113.48,48.24 113.46,48.21 113.43,48.19 113.09,47.86 113.43,47.53 113.46,47.51 113.48,47.48 113.48,47.16 113.12,46.8 112.99,46.8 112.98,46.83 112.77,46.95 112.56,46.83 112.55,46.8 111.96,46.8 111.93,46.84 111.93,46.97 112.02,47.36 111.66,47.55 111.6,47.56 111.55,47.62 111.49,47.71 111.4,47.76 111.37,47.78 111.37,47.91 111.38,47.94 111.42,47.96 111.48,47.97 111.54,48 111.72,48.14 111.74,48.14 112.1,48.37 111.94,48.76 111.89,48.83 111.92,48.92 112.17,49.18 113.07,49.18
+3V_PRIM on IN2 (solid shape): outline of 296 points within 116.84,40.28 122.24,42.8
+3VALW on TOP (solid shape): 27.52,67.53 27.52,66.26 27.32,66.06 22.15,66.06 21.95,66.25 21.95,67.5 22.16,67.71 27.35,67.71
+3VALW on TOP (solid shape): 87.61,35.64 87.89,35.92 88.17,35.64 88.17,34.86 88.23,34.78 88.25,34.68 88.25,32.66 87.74,32.15 86.22,32.15 86.09,32.28 86.09,32.79 86.22,32.91 87.49,32.91 87.61,33.04
+3VALW on TOP (solid shape): outline of 87 points within 43.16,100.86 50.02,109.24
+3VALW on BOTTOM (solid shape): 44.75,103.84 44.75,101.66 44.57,101.48 42.94,101.48 42.76,101.66 42.76,103.84 42.94,104.02 44.57,104.02
+3VALW on BOTTOM (solid shape): 22.97,69.62 22.97,64.78 22.87,64.68 22.03,64.68 21.95,64.75 21.95,69.6 22.15,69.8 22.79,69.8
+3VALW on BOTTOM (solid shape): 189.59,70.33 189.59,69.43 188.46,68.29 185.97,68.29 185.91,68.35 185.91,69.12 186.11,69.31 186.11,70.35 186.26,70.51 189.41,70.51
+3VALW on BOTTOM (solid shape): 5.57,51.65 5.57,49.99 5.44,49.87 4.96,49.87 4.83,49.99 4.83,50.32 4.69,50.47 3.1,50.47 3.03,50.53 3.03,51.64 3.13,51.73 5.49,51.73
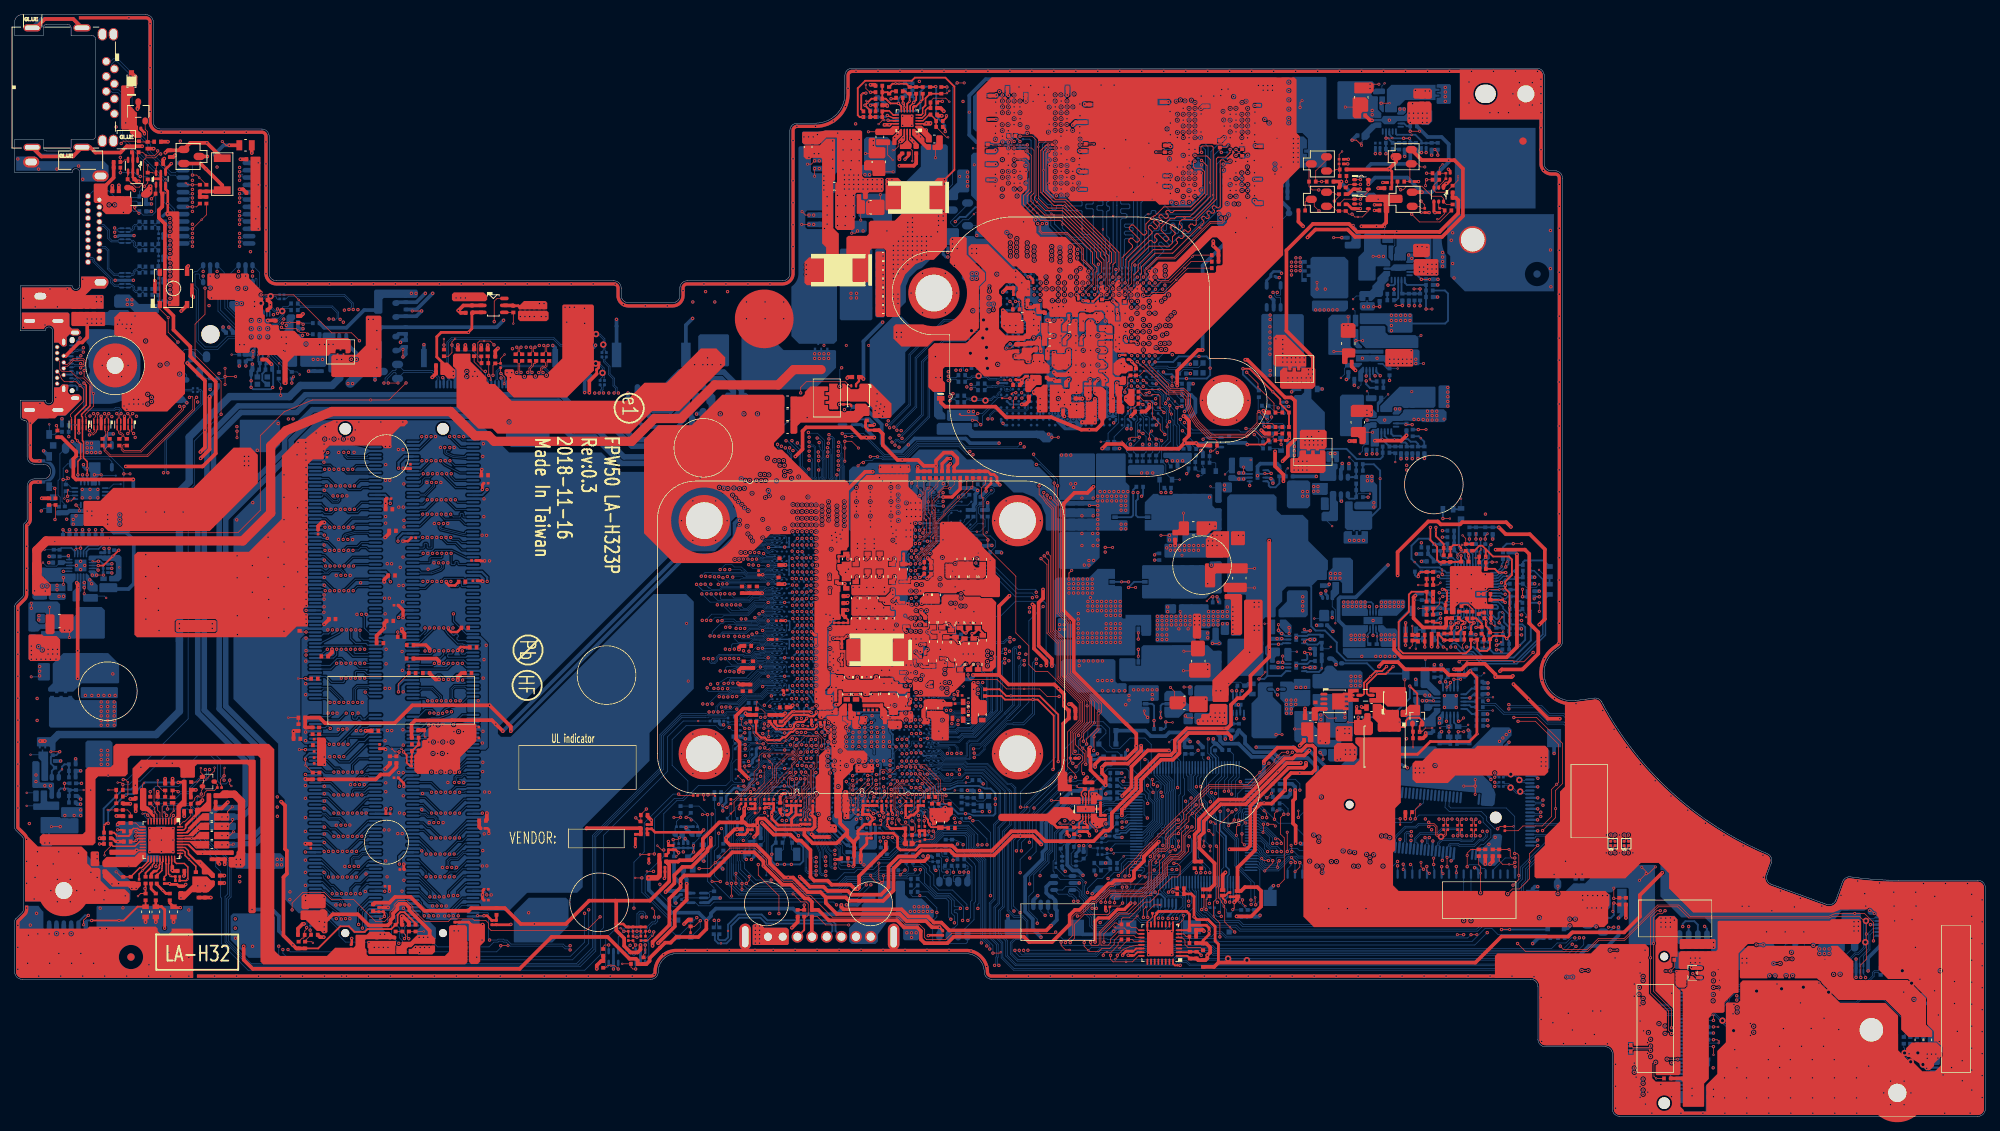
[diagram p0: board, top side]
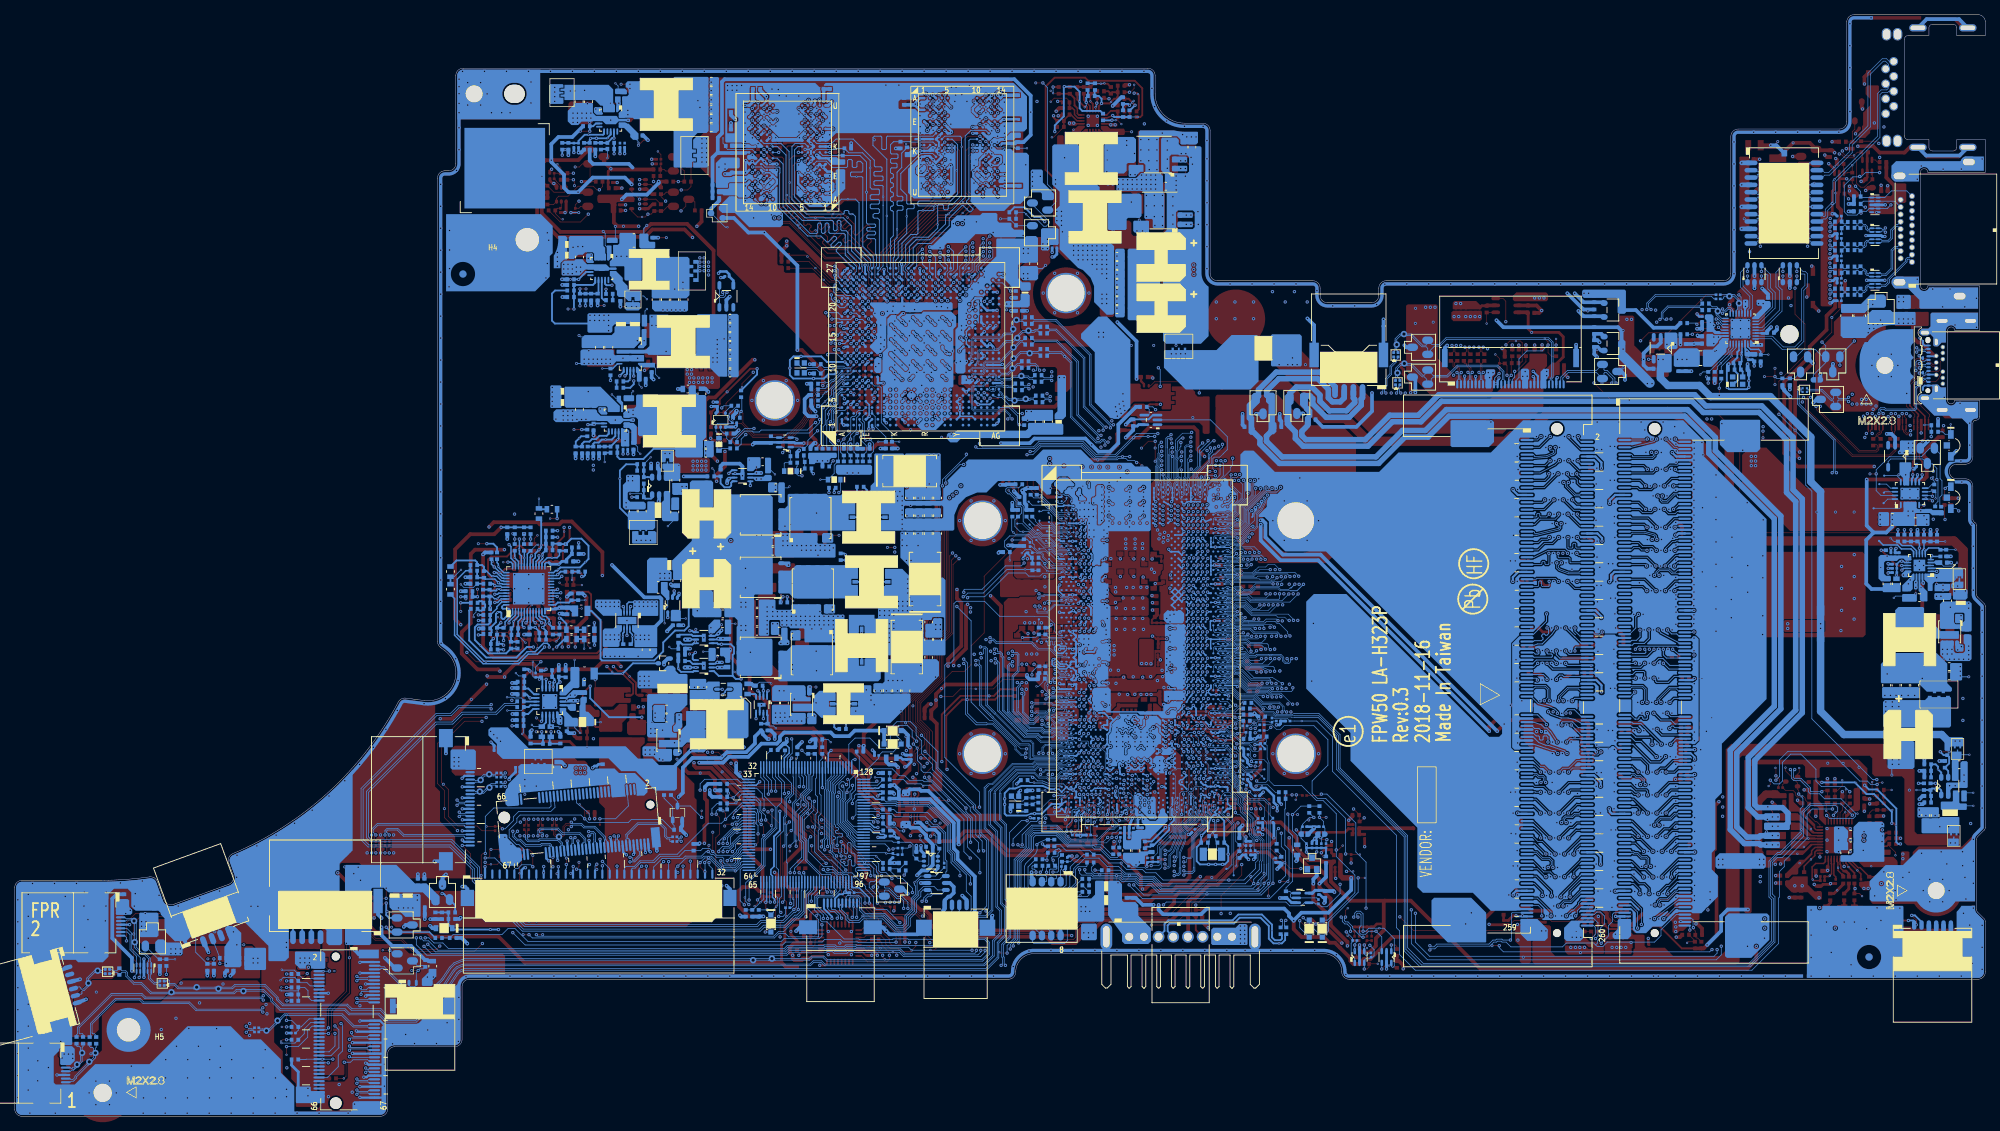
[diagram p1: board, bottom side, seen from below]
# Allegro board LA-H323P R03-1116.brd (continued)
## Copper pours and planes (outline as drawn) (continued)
+3VALW on BOTTOM (solid shape): 180.58,90.66 180.58,89.35 180.45,89.22 179.93,89.22 179.93,89.78 179.44,89.78 179.44,89.22 178.98,89.22 178.84,89.37 178.84,90.65 178.95,90.76 180.48,90.76
+3VALW on BOTTOM (solid shape): 249.54,23.77 249.54,22.63 248.85,21.94 246.01,21.94 245.79,22.15 245.79,23.28 246.23,23.71 247.96,23.71 248.4,24.15 249.16,24.15
+3VALW on BOTTOM (solid shape): 186.03,93.83 186.03,91.47 185.95,91.39 184.95,91.39 184.9,91.44 184.9,93.54 185.15,93.79 185.71,93.79 185.81,93.89 185.97,93.89
+3VALW on IN2 (solid shape): 181.23,90.82 181.23,89.92 181.14,89.84 179.36,89.84 179.13,90.07 179.13,90.66 179.47,91 181.05,91
+3VALW on IN2 (solid shape): 190.32,88.89 190.32,88.03 190.16,87.87 188.7,87.87 188.58,87.99 188.58,88.97 188.7,89.09 190.12,89.09
+3VALW on BOTTOM: 173.78,112.54 173.6,112.73 173.6,117.48 173.6,117.48 173.6,126.15 176.45,128.99 178.82,128.99 180.96,131.13 182.63,131.13 185.28,133.78 186.24,134.75 186.41,134.75 186.47,134.81 186.58,134.81 186.64,134.75 186.64,133.92 186.42,133.7 186.42,132.66 186.37,132.61 185.43,132.61 184.99,132.16 184.99,130.46 184.99,128.95 182.03,128.95 179.55,126.48 179.55,122.8 176.35,119.6 176.35,117.62 176.51,117.46 176.51,116.29 176.04,116.29 176.04,115.58 176.51,115.58 176.51,115.09 176.04,115.09 176.04,114.39 176.51,114.39 176.51,112.73 176.32,112.54
+3VALW on VCC: outline of 99 points within 38.84,20.72 252.2,118.64
+3VALW_DSW on IN1: 98.23,43.49 98.84,44.1 98.84,44.94 99.42,45.53 99.42,52.47 102.47,52.47 103.11,53.11 105.77,53.11 106.66,54 109.55,54 109.98,54.42 110.56,54.42 110.64,54.34 111.08,54.34 111.21,54.22 111.33,54.22 112.18,53.37 112.18,51.41 111.69,50.92 111.51,50.92 110.79,51.64 105.26,51.64 104.31,50.69 102.54,50.69 102.22,50.38 102.22,47.39 102.16,47.39 102.16,37.71 101.02,36.57 98.85,36.57 98.23,37.19
+3VALWP on BOTTOM (solid shape): 181.85,116.73 181.85,111.78 181.66,111.6 177.12,111.6 176.68,112.03 176.68,114.49 176.64,114.49 176.64,114.51 176.16,114.51 176.16,114.96 176.64,114.96 176.64,114.98 176.68,114.98 176.68,115.69 176.64,115.69 176.64,115.71 176.16,115.71 176.16,116.16 176.64,116.16 176.64,116.18 176.68,116.18 176.68,117.01 176.93,117.25 181.33,117.25
+3VL on BOTTOM (solid shape): 185.45,110.95 185.45,110.13 185.26,109.94 183.64,109.94 183.41,110.17 183.41,110.93 183.56,111.08 185.33,111.08
+3VL on IN1 (solid shape): 185.11,110.76 185.11,110.17 184.97,110.03 183.79,110.03 183.66,110.15 183.66,110.79 183.79,110.92 184.96,110.92
+3VLP on BOTTOM (solid shape): 187.55,115.26 187.55,114.71 187.34,114.5 187.34,114.05 186.95,113.66 186.95,113.65 186.78,113.48 186.78,112.82 186.58,112.63 186.58,112.04 186.33,111.78 185.59,111.78 185.03,111.23 184.62,111.23 184.62,111.77 184.18,111.77 184.18,111.23 183.51,111.23 183.34,111.4 183.34,112.42 183.52,112.6 184.78,112.6 185.11,112.93 185.11,113.3 185.79,113.97 185.79,114.4 186.72,115.34 187.47,115.34
+3VS on TOP (solid shape): 72.62,110.99 72.62,110.17 72.55,110.1 68.77,110.1 68.71,110.16 68.71,110.5 69.45,111.24 72.37,111.24
+3VS on TOP (solid shape): 32.88,48.53 32.88,27.89 32.7,27.71 32.04,27.71 31.86,27.89 31.86,47.85 31.68,48.03 24.89,48.03 24.58,47.72 24.58,46.32 24.45,46.19 22.71,46.19 22.59,46.32 22.59,47.47 22.41,47.65 18.41,47.65 16.83,46.07 16.83,44.05 16.69,43.91 16.2,43.91 16.07,44.04 16.07,47.46 17.27,48.66 32.75,48.66
+3VS on BOTTOM (solid shape): 54.97,112.62 54.97,111.88 54.74,111.65 50.33,111.65 50.15,111.47 50.15,109.67 49.97,109.49 49.18,109.49 49,109.67 49,112.62 49.18,112.8 54.79,112.8
+3VS on BOTTOM (solid shape): 187.05,66.57 188.26,66.57 188.51,66.31 188.51,64.13 188.43,64.04 186.39,64.04 186.23,64.2 186.23,64.73 186.1,64.86 186.1,66 185.91,66.19 185.91,66.94 185.97,67 186.62,67
+3VS on BOTTOM (solid shape): 204.11,52.76 204.11,51.96 202.95,50.8 202.95,49.55 202.15,48.76 195.25,48.76 195.17,48.84 187.73,48.84 186.41,47.52 185.98,47.08 184,47.08 181.35,44.44 178.66,44.44 178.4,44.7 178.4,47.68 178.63,47.91 180.83,47.91 181.72,48.8 183.7,48.8 185.39,50.49 193.73,50.49 194,50.22 198.6,50.22 201.45,53.07 203.8,53.07
+3VS on VCC: outline of 91 points within 21.45,9.63 263.38,112.83
+3VS_CAMERA on TOP (solid shape): 60.08,101.8 60.08,100.84 59.89,100.64 59.07,100.64 58.58,101.14 58.12,101.14 58.03,101.23 58.03,102.74 58.13,102.84 59.04,102.84
+3VS_CAMERA on BOTTOM (solid shape): 60.66,101.57 60.66,101.52 60.64,101.41 60.65,101.31 60.64,101.21 60.66,101.12 60.66,101.11 60.66,100.98 60.64,100.86 60.66,100.75 60.66,100.74 60.66,99.39 60.56,99.29 59.94,99.29 59.85,99.37 59.85,99.7 59.86,99.7 59.86,100.51 59.69,100.68 59.69,100.84 59.51,101.02 59.51,101.92 59.57,101.98 60.25,101.98
+3VS_DGPU on TOP (solid shape): 150.52,100.13 150.52,99.73 150.56,99.69 150.56,99.67 150.58,99.67 150.61,99.63 151.03,99.63 151.11,99.55 151.11,99.25 150.99,99.12 150.99,97.28 151.31,96.95 151.31,96.06 151.09,95.84 150.41,95.84 150.24,96.01 150.24,98.28 150.1,98.42 150.1,99.07 150.05,99.12 150.05,100.11 150.2,100.26 150.39,100.26
+3VS_DGPU_AON on TOP (solid shape): 152.7,99.13 152.7,97.14 152.5,96.93 151.96,96.93 151.24,97.65 151.24,98.22 151.44,98.42 151.58,98.42 151.83,98.66 151.83,99.15 151.94,99.26 152.58,99.26
+3VS_DGPU_AON on TOP (solid shape): 189.24,125.57 189.24,124.79 189.06,124.61 187.61,124.61 187.43,124.43 187.43,123.34 187.31,123.21 186.8,123.21 186.67,123.34 186.67,124.61 186.55,124.73 184.29,124.73 184.19,124.83 184.19,125.3 184.64,125.75 189.06,125.75
+3VS_DGPU_AON on TOP (solid shape): 151.37,103.46 151.37,103.45 151.41,103.41 151.41,102.98 151.9,102.49 152.26,102.49 152.45,102.3 152.45,101.73 152.39,101.67 151.86,101.67 151.56,101.37 150.93,101.37 150.68,101.11 150.13,101.11 149.83,101.41 149.83,102.7 150.32,103.19 150.98,103.46 151.35,103.46
+3VS_DGPU_AON on TOP (solid shape): 140.03,100.94 140.03,99.87 139.94,99.78 139.33,99.78 138.58,99.02 138.58,98.97 138.58,98.97 138.58,98.87 138.51,98.81 137.93,98.81 137.78,98.96 137.78,100.4 138,100.62 138.25,100.62 138.26,100.63 138.38,100.63 138.42,100.67 138.42,100.68 138.49,100.75 138.49,101.14 138.51,101.17 139.81,101.17
+3VS_DGPU_AON on BOTTOM (solid shape): 156.73,88.75 156.73,87.81 156.45,87.52 152.01,87.52 151.78,87.74 151.78,88.69 152,88.9 156.58,88.9
+3VS_DGPU_AON on BOTTOM (solid shape): 151.24,103.51 151.24,103.51 151.51,103.24 151.51,101.7 151.22,101.41 150.7,101.41 150.51,101.6 150.51,103.44 150.56,103.49 150.58,103.48 150.74,103.49 150.88,103.57 151.18,103.57
+3VS_DGPU_AON on BOTTOM (solid shape): 139.63,101.01 139.63,99.96 139.59,99.93 138.3,99.93 137.9,100.33 137.9,100.56 138.09,100.56 138.17,100.64 138.33,100.64 138.69,100.6 138.86,100.91 138.85,100.94 139.04,101.12 139.52,101.12
+3VS_DGPU_AON on IN2 (solid shape): outline of 1043 points within 137.1,87.55 155.67,102.36
+3VS_DGPU_AON on IN1: 140.36,89.89 137.69,92.56 137.69,100.44 138.04,100.78 139.05,100.78 139.38,100.45 139.38,99.97 138.52,99.11 138.52,96.92 138.53,96.91 138.53,96.79 140.13,95.19 140.21,95.11 140.21,93.08 141.09,92.2 146.41,92.2 150.07,95.86 150.07,97.72 150.07,97.73 150.11,97.9 150.07,98.07 150.07,98.08 150.07,99.58 150.11,99.66 150.19,99.68 150.63,100.02 150.19,100.37 150.11,100.39 150.07,100.47 150.07,102.59 150.48,103 151.5,103 152.23,102.27 152.23,100.73 152.19,100.72 151.94,100.45 152.06,100.1 152.1,100.02 152.06,99.94 151.91,99.57 152.19,99.29 152.23,99.28 152.23,95.91 152.18,95.86 151.85,95.39 152.4,95.22 152.44,95.25 152.7,94.98 152.7,93.41 152.51,93.21 152.51,91.14 151.98,90.61 142.58,90.61 141.86,89.89
+3VS_SSD on BOTTOM (solid shape): outline of 310 points within 182.41,42.3 201.93,48.06
+3VS_TOUCH on IN1: 53.6,101.55 53.6,110.02 54.09,110.51 57.08,110.51 57.65,109.94 57.65,105.02 57.99,104.68 61.65,104.68 61.99,104.34 61.99,101.53 61.84,101.38 61.46,101.38 61.22,101.13 61.22,100.57 60.6,99.96 55.2,99.96
+3VS_WLAN on TOP (solid shape): outline of 447 points within 226.88,1.29 251.77,26.91
+3VS_WLAN on BOTTOM (solid shape): 251.72,27.67 251.72,24.63 251.54,24.45 249.3,24.45 249.09,24.66 249.09,24.66 249.09,27.63 249.26,27.79 251.6,27.79
+3VS_WLAN on BOTTOM (solid shape): 230.36,3.99 230.36,1.88 230.27,1.79 226.51,1.79 226.42,1.88 226.42,3.36 226.51,3.45 228.24,3.45 228.33,3.54 228.33,3.99 228.42,4.08 230.27,4.08
+3VS_WLAN on BOTTOM (solid shape): 230.49,22.38 230.49,20.82 229.82,20.15 228.95,20.15 228.65,20.7 228.35,20.15 226.48,20.15 226.36,20.27 226.36,22.23 226.62,22.49 230.38,22.49
+5V_TYPEC on TOP (solid shape): 12.34,109.66 12.34,107.92 12.23,107.82 7.85,107.82 7.72,107.95 7.72,109.66 7.81,109.75 12.26,109.75
+5V_TYPEC on TOP (solid shape): outline of 421 points within 13.57,96.16 23.22,109.75
+5V_TYPEC on BOTTOM (solid shape): 11.65,92.1 11.65,90.97 11.92,90.7 11.92,90.44 11.79,90.32 9.63,90.32 9.51,90.44 9.51,90.88 9.51,90.9 9.51,91.41 9.51,91.43 9.51,92.1 9.63,92.22 11.52,92.22
+5V_TYPEC on BOTTOM (solid shape): 16.32,109.12 19.58,109.12 19.74,108.96 19.74,106.52 19.41,106.19 16.34,106.19 14.7,107.49 12.65,107.95 9.57,107.95 9.5,108.02 9.5,109.65 9.6,109.75 12.67,109.75 12.94,110.01 15.44,110.01
+5V_TYPEC on IN1: 8.48,90.06 8.21,90.33 8.21,96.57 9.95,98.32 17.77,98.32 18.4,97.69 18.4,90.24 18.22,90.06
+5V_TYPEC on IN1: 6.71,99.46 6.34,99.84 6.34,104.92 7.07,104.92 7.46,105.32 8.56,105.32 9.5,106.26 9.5,108.96 9.66,109.11 12.2,109.11 12.32,109 12.32,99.75 12.02,99.46
+5V_TYPEC_IC on BOTTOM (solid shape): 11.71,89.17 11.71,87.58 11.22,87.09 11.22,86.15 11.13,86.06 10.4,86.06 10.37,86.09 10.37,87.08 10.29,87.15 10.29,87.84 10.09,88.05 10.09,89.14 10.19,89.24 11.64,89.24
+5VALW on TOP (solid shape): 173.53,101.63 174.23,101.63 174.23,102.16 174.73,102.16 174.73,101.63 175.43,101.63 175.43,102.16 177.14,102.16 177.36,101.94 177.36,99.65 176.96,99.25 172.75,99.25 172.53,99.47 172.53,101.71 172.98,102.16 173.53,102.16
+5VALW on TOP (solid shape): outline of 97 points within 190.58,45.47 209.12,50.57
+5VALW on TOP (solid shape): outline of 121 points within 9.38,79.85 33.16,91.25
+5VALW on BOTTOM (solid shape): 13.99,72.6 13.99,71.59 13.91,71.51 11.63,71.51 11.54,71.6 11.54,72.61 11.67,72.74 13.86,72.74
+5VALW on BOTTOM (solid shape): 209.28,49.88 209.28,47.53 209.05,47.3 205.89,47.3 205.81,47.38 205.81,49.83 206.04,50.06 209.1,50.06
+5VALW on BOTTOM (solid shape): 184.37,70.28 184.37,69.61 184.36,69.55 184.37,69.49 184.37,69.27 184.51,69.12 184.51,68.34 184.44,68.27 183.79,68.27 183.79,68.27 181.04,68.27 180.95,68.36 180.95,70.31 181.02,70.38 183.03,70.38 183.04,70.39 184.26,70.39
+5VALW on BOTTOM (solid shape): 11.15,83.79 11.15,82.57 11.28,82.44 12.81,82.44 12.94,82.32 12.94,80.67 12.81,80.54 9.73,80.54 9.61,80.66 9.61,82.21 9.51,82.32 7.68,82.32 7.57,82.32 7.25,82 5.7,82 5.66,82.04 5.66,82.59 5.78,82.71 7.17,82.71 7.34,82.89 8.23,82.89 8.27,82.85 8.94,82.85 8.95,82.85 9.07,82.84 9.18,82.89 9.25,82.89 9.38,83.02 9.38,83.78 9.46,83.85 11.09,83.85
+5VALW on VCC: 177.78,43.07 177.78,76.75 178.27,77.24 184.24,77.24 184.77,77.77 184.77,80.39 184.11,81.05 177.15,81.05 177.15,91.95 175.98,93.11 173.99,93.11 170.57,89.68 162.01,89.68 158.58,93.11 123.41,93.11 117.69,98.83 107.4,98.83 106.64,99.59 83.57,99.59 82.81,98.83 43.18,98.83 40.39,96.03 36.83,96.03 36.3,95.5 36.3,87.76 34.68,86.13 29.68,86.13 29.07,86.74 29.07,106.47 29.68,107.08 114.56,107.08 125.48,96.16 154.52,96.16 156.55,98.19 161.63,98.19 163.92,100.48 171.79,100.48 172.7,101.39 172.7,105.45 173.32,106.07 177.04,106.07 177.66,105.45 177.66,101.51 178.69,100.48 187.2,100.48 188.96,98.72 188.96,74.8 188.22,74.06 185.81,74.06 184.89,73.15 184.89,69.09 184.28,68.47 181.49,68.47 180.58,67.56 180.58,56.56 181.36,55.77 188.35,55.77 188.96,55.16 188.96,48.68 189.87,47.77 192.54,47.77 192.77,47.54 192.77,44.83 192.54,44.6 182.12,44.6 180.6,43.07 ; 1 cut-out
+5VALWP on TOP (solid shape): 176.1,103.75 176.1,102.37 176.03,102.29 175.98,102.29 175.98,102.29 175.3,102.29 175.3,101.75 174.86,101.75 174.86,102.29 174.11,102.29 174.11,101.75 173.66,101.75 173.66,102.29 171.93,102.29 171.64,102.59 171.64,106.24 172.03,106.64 173.22,106.64
+5VALWP on BOTTOM (solid shape): 175.78,109.23 175.78,104.1 176.1,103.78 176.1,102.27 175.91,102.07 173.86,102.07 172.7,100.92 171.61,100.92 171.54,100.99 171.54,109.34 171.65,109.45 175.56,109.45
+5VLP on BOTTOM (solid shape): 183.99,102.19 183.99,101.52 183.87,101.39 183.87,100.3 183.8,100.24 183.28,100.24 183.19,100.32 183.19,101.67 183.8,102.27 183.91,102.27
+5VS on TOP (solid shape): 11.5,36.02 11.5,34.26 11.37,34.13 10.48,34.13 10.35,34.26 10.35,36.02 10.48,36.15 11.37,36.15
+5VS on TOP (solid shape): 29.23,44.35 29.23,43.57 29.06,43.4 27.2,43.4 27.11,43.49 27.11,44 27.2,44.09 27.96,44.09 28.35,44.48 29.09,44.48
+5VS on TOP (solid shape): 31.43,36.06 31.43,34.27 31.09,33.93 29.39,33.93 29.16,34.16 29.16,35.28 29.25,35.37 29.94,35.37 30.24,35.67 30.24,36.06 30.46,36.28 31.21,36.28
+5VS on TOP (solid shape): 18.78,127.02 18.78,125.88 18.27,125.37 17.43,125.37 17.25,125.55 17.25,125.98 17.84,126.56 17.84,126.57 17.95,126.64 18.03,126.75 18.03,126.76 18.17,126.89 18.17,127.03 18.28,127.15 18.65,127.15
+5VS on TOP (solid shape): outline of 685 points within 235.23,10.81 261.46,23.26
+5VS on BOTTOM (solid shape): 237.4,22.88 237.4,20.09 237.27,19.96 234.55,19.96 234.42,20.09 234.42,22.88 234.55,23.01 237.27,23.01
+5VS on BOTTOM (solid shape): 36.81,35.32 36.81,34.03 36.55,33.78 30.2,33.78 29.94,34.04 29.94,35.44 30.4,35.9 36.22,35.9
+5VS on BOTTOM (solid shape): 184.46,67 184.51,66.95 184.51,66.19 184.2,65.87 184.2,64.05 184.15,64 181.16,64 181.08,64.08 181.08,66.88 181.21,67 184.39,67
+5VS on BOTTOM (solid shape): 50.09,105.68 50.09,103.47 46.21,99.59 45.28,99.59 45.28,100.52 49.08,104.31 49.08,105.72 49.32,105.97 49.8,105.97
+5VS on IN1 (solid shape): outline of 687 points within 9.63,33.8 31.11,42.79
+5VS on VCC: 222.97,17.17 215.61,24.53 171.41,24.53 167.73,28.21 122.01,28.21 118.45,31.77 87,31.77 77.86,22.63 36.03,22.63 35.03,23.62 35.03,85.77 36.81,87.54 36.81,95.29 37.05,95.52 38.84,95.52 38.84,26.97 39.88,25.93 76.67,25.93 89.5,38.76 112.4,38.76 113.92,37.23 121.67,37.23 123.58,35.33 124.72,35.33 127,33.04 169.89,33.04 177.78,40.94 177.78,42.57 180.81,42.57 182.33,44.09 192.75,44.09 193.28,44.62 193.28,47.75 192.75,48.28 190.08,48.28 189.47,48.89 189.47,55.37 188.56,56.28 181.57,56.28 181.08,56.77 181.08,67.35 181.7,67.97 184.28,67.97 184.89,67.35 184.89,63.41 185.81,62.5 195.33,62.5 195.94,61.89 195.94,56.3 202.93,49.32 202.93,45.25 205.98,42.21 205.98,38.27 214.63,29.61 218.57,29.61 225.3,22.88 235.08,22.88 236.71,21.25 236.71,17.78 236.1,17.17 ; 1 cut-out
+5VS on IN1: 25.51,109.1 25.51,105.87 26.33,105.05 38.46,105.05 40.9,102.61 45.8,102.61 46.41,101.99 46.41,99.88 41.07,94.54 37.42,94.54 37.04,94.92 37.04,96.48 39.23,98.67 39.23,100.48 37.32,102.38 26.85,102.38 23.99,105.24 23.99,106.79 22.55,108.22 19.67,108.22 18.91,108.99 18.91,122.32 18.91,122.32 18.91,124.99 18.11,125.79 18.11,127.02 18.36,127.27 21.57,127.27 22.27,126.58 22.27,112.34
+5VS_AVDD on TOP (solid shape): 17.91,35.93 17.91,35.34 16.57,34 12.15,34 12.01,34.14 12.01,34.88 12.54,35.4 16.34,35.4 16.94,36 17.84,36
+5VS_HDD1 on TOP (solid shape): 262.72,9.39 262.72,8.22 261.72,7.22 261.72,6.87 261.16,6.32 260.63,6.32 259.76,7.17 258.71,7.8 258.41,8.09 258.09,8.09 257.9,8.28 257.9,9.3 258.68,10.08 262.03,10.08
+5VS_HDD1 on BOTTOM (solid shape): 262.51,9.12 262.51,7.15 262.36,7.01 261.08,7.01 260.51,7.58 260.51,9.2 260.88,9.58 262.05,9.58
+5VS_KBL on BOTTOM (solid shape): 212.25,20.06 212.25,19.68 213.18,18.75 213.18,17.91 213.05,17.79 211.94,17.79 211.72,18.01 211.72,18.57 211.2,19.1 211.2,20.06 211.26,20.12 212.19,20.12
+5VS_PVDD1 on TOP (solid shape): 24.7,36.29 29.79,36.29 29.87,36.2 29.87,35.74 29.79,35.65 24.89,35.65 23.56,36.98 22.16,36.98 22.11,37.04 22.11,37.14 22.16,37.19 23.8,37.19
+5VS_PVDD2 on TOP (solid shape): 26.81,44.01 26.81,41.61 26.77,41.57 25.46,41.57 23.44,39.55 23.44,39.31 23.12,38.98 22.16,38.98 22.11,39.04 22.11,39.15 22.15,39.19 23.04,39.19 23.19,39.34 23.19,39.83 24.59,41.23 24.59,41.99 24.71,42.12 25.35,42.12 26.14,42.91 26.14,43.98 26.25,44.09 26.73,44.09
+12.6V_BATT on BOTTOM (solid shape): 121.39,32.02 121.39,30.25 121.9,29.74 123.68,29.74 125.33,28.09 125.33,27.2 124.7,26.56 120.38,26.56 120.12,26.82 120.12,32.02 120.25,32.15 121.27,32.15
+12.6V_BATT on BOTTOM (solid shape): 174.28,59.24 174.28,58.33 174.44,58.16 176.61,58.16 176.67,58.11 176.67,56.19 176.43,55.95 176.13,55.95 175.94,56 175.76,55.95 174.58,55.95 174.3,55.67 174.3,54.88 174.15,54.72 173.3,54.72 173.12,54.9 173.12,56.37 172.55,56.94 172.55,57.92 173.11,57.92 173.47,58.27 173.11,58.63 172.55,58.63 172.55,59.25 172.61,59.32 174.2,59.32
+12.6V_BATT on TOP: 127.61,25.8 126.51,26.9 125.44,26.9 125.13,27.21 125.11,27.21 124.65,27.68 122.04,27.68 120.3,29.42 120.3,31.57 122.01,33.27 123.69,33.27 125.01,34.59 133.32,34.59 135.84,37.1 147.39,37.1 148.06,37.77 149.04,37.77 150.33,39.06 150.33,40.04 159.61,49.32 159.61,50.31 160.47,51.18 165.4,51.18 166.1,51.87 166.1,54.67 170.76,59.33 177.95,59.33 179.19,58.09 179.19,56.27 178.97,56.06 176.81,56.06 176.72,55.96 175.52,55.96 175.3,55.75 175.3,54.56 174.99,54.25 172.87,54.25 171.18,52.56 171.18,50.02 167.14,45.98 167.13,45.98 166.61,45.46 162.69,45.46 143.03,25.8
+12.6V_BATT+ on BOTTOM (solid shape): 119.62,32.02 119.62,27.45 117.71,24.83 117.71,23.87 117.35,23.52 114.13,23.52 113.77,23.87 113.77,25.67 115.49,27.39 115.49,28.83 115.88,29.23 117.46,29.23 117.71,29.48 117.71,31.55 117.72,31.56 117.72,31.7 118.17,32.15 119.49,32.15
+19V_ADPIN on BOTTOM (solid shape): 223.66,34.18 223.66,23.63 223.4,23.37 220.3,23.37 220.07,23.59 220.07,31.03 219.92,31.18 218.38,31.18 217.76,30.56 213.06,30.56 211.88,29.38 211.88,29.1 211.58,28.8 210.98,28.8 210.75,29.03 210.75,30 212.52,31.77 214.1,31.77 216.64,34.31 223.53,34.31
+19V_VIN on TOP (solid shape): outline of 1337 points within 175.71,25.8 217.43,51.71
+19V_VIN on BOTTOM (solid shape): 217.6,30.18 217.6,28.53 217.16,28.09 216.31,28.09 215.43,27.21 213.46,27.21 213.34,27.33 213.34,30.19 213.52,30.37 217.41,30.37
+19VB on TOP (solid shape): outline of 86 points within 2.37,71.03 4.93,75.6
+19VB on BOTTOM (solid shape): 4.42,71.77 4.42,70.62 4.3,70.51 2.65,70.51 2.42,70.74 2.42,71.76 2.56,71.9 4.29,71.9
+19VB on BOTTOM (solid shape): 195.66,99.62 195.66,96.72 195.59,96.64 194.23,96.64 194.14,96.73 194.14,99.56 194.31,99.73 195.55,99.73
+19VB on BOTTOM (solid shape): 104.83,104.54 111.87,104.54 112,104.41 112,102.13 109.03,99.16 100.21,99.16 99.09,100.27 99.09,106.37 99.32,106.6 102.78,106.6
+19VB on BOTTOM (solid shape): 190.61,109.39 190.61,107.08 190.43,106.9 187.4,106.9 187.19,107.11 187.19,107.75 186.88,108.07 183.53,108.07 183.4,108.2 183.4,109.51 183.46,109.57 190.43,109.57
+19VB on BOTTOM (solid shape): 182.48,75.84 182.48,71.43 182.42,71.37 181.08,71.37 180.99,71.46 180.99,72.75 180.68,73.06 179.3,73.06 179.12,73.24 179.12,74.26 179.69,74.82 179.69,76.09 179.81,76.22 182.1,76.22
+19VB on BOTTOM (solid shape): 180.34,60.82 183.51,60.82 183.78,60.55 183.78,58.56 183.6,58.38 177.16,58.38 176.96,58.58 176.96,60.23 177.06,60.33 177.96,60.33 178.11,60.33 178.58,60.8 178.58,61.13 178.94,61.49 179.68,61.49
+19VB on BOTTOM (solid shape): 195.84,140.66 195.84,138.26 195.7,138.13 193.98,138.13 193.87,138.23 193.87,138.98 194.42,138.98 194.42,139.53 193.87,139.53 193.87,139.78 194.42,139.78 194.42,140.33 193.87,140.33 193.87,140.71 193.99,140.82 195.67,140.82
+19VB on BOTTOM (solid shape): 194.5,120.13 194.57,120.11 194.61,120.04 194.69,118.67 195.2,117.4 195.2,115.7 194.33,115.7 194.27,115.76 194.27,116.4 193.8,116.87 193.44,116.87 193.34,116.98 193.34,119.87 193.6,120.13
+19VB on TOP: outline of 97 points within 108.69,55.39 209.15,140.87
+19VB_1V on BOTTOM (solid shape): 193.73,99.45 193.73,96.9 193.5,96.66 190.1,96.66 189.33,96.66 189.12,96.87 188.02,96.87 187.83,96.68 187.83,96.14 187.77,96.08 186.3,96.08 186.21,96.17 186.21,96.93 188.82,99.55 193.64,99.55
+19VB_3V on TOP (solid shape): 192.96,118.89 192.96,117.45 192.72,117.21 190.86,117.21 190.67,117.4 190.67,118.86 190.84,119.03 192.82,119.03
+19VB_3V on BOTTOM (solid shape): 193.16,119.92 193.16,117.05 193.09,116.97 192.44,116.97 191.87,117.55 191.24,117.55 190.92,117.87 189.88,117.87 189.69,117.68 189.69,116.84 189.61,116.76 188.12,116.76 188.06,116.82 188.06,117.63 188.17,117.74 188.17,118.5 188.41,118.75 188.41,119.94 188.58,120.11 192.97,120.11
+19VB_5V on BOTTOM (solid shape): 186.91,107.68 186.91,106.97 187.3,106.59 190.99,106.59 191.4,106.18 191.4,104.91 191.3,104.81 184.25,104.81 183.4,105.66 183.4,107.73 183.52,107.86 186.74,107.86
+19VB_CHG on TOP (solid shape): 182.4,53.1 182.4,51.26 182.31,51.16 180.35,51.16 180.1,51.42 180.1,53.01 180.32,53.23 182.27,53.23
+19VB_CHG on BOTTOM (solid shape): 182.47,57.44 182.47,51.9 182.25,51.68 178.45,51.68 178.43,51.7 178.43,52.27 178.47,52.32 178.85,52.32 179.08,52.54 179.08,53.22 178.75,53.55 178.75,54.92 178.52,55.15 178,55.15 177.04,56.11 179.88,56.11 179.88,53.82 180.03,53.66 181.49,53.66 181.77,53.94 181.77,56.03 181.53,56.27 180.04,56.27 179.88,56.11 177.04,56.11 176.97,56.18 176.97,57.53 177.06,57.61 182.29,57.61
+19VB_CPU on TOP (solid shape): 167.75,79.74 167.75,78.05 167.61,77.92 165.93,77.92 165.84,78 165.84,79.7 165.99,79.84 167.65,79.84
+19VB_CPU on TOP (solid shape): 165.52,58.36 165.52,56.67 165.39,56.54 163.43,56.54 163.3,56.66 163.3,58.26 163.48,58.44 165.44,58.44
+19VB_CPU on TOP (solid shape): 170.16,70.33 170.16,63.29 165.52,58.65 165.52,57.47 165.36,57.31 165,57.31 165,57.31 163.39,57.31 163.3,57.39 163.3,59.5 167.62,63.82 167.62,70.33 167.8,70.51 169.98,70.51
+19VB_CPU on BOTTOM (solid shape): 165.43,58.49 165.43,56.75 165.31,56.63 160.2,56.63 160.18,56.65 160.18,57.14 160.19,57.16 160.63,57.16 160.85,57.38 160.85,58.6 161.06,58.82 165.1,58.82
+19VB_CPU on BOTTOM (solid shape): outline of 83 points within 165.34,60.09 179.05,84.86
+19VB_DDR on BOTTOM (solid shape): 6.2,69.88 6.2,66.65 6.07,66.52 3.58,66.52 3.2,66.14 1.98,66.14 1.86,66.26 1.86,68.57 2.84,68.57 2.84,67.61 3.31,67.14 3.97,67.14 3.98,67.14 4.05,67.14 4.25,67.35 4.25,68.59 4.14,68.7 2.98,68.7 2.84,68.57 1.86,68.57 1.86,69.97 2.14,70.25 5.82,70.25
+19VB_VGA_CORE on TOP (solid shape): 111.87,133.26 111.87,127.78 111.62,127.53 111.62,121.21 111.6,121.19 112.38,120.42 112.38,113.75 111.92,113.29 111.18,113.29 110.64,113.84 110.64,118.55 110.09,119.1 110.09,130.61 109.93,130.77 108.66,130.77 108.48,130.59 107.9,130.59 107.56,130.93 107.56,132.24 107.8,132.48 109.78,132.48 110.68,133.38 111.76,133.38
+19VB_VGA_CORE on BOTTOM (solid shape): outline of 165 points within 105.9,105.4 112.38,133.53
+19VB_VRAM on TOP (solid shape): 193.25,139.97 193.25,138.99 193.09,138.83 190.89,138.83 190.71,139.01 190.71,140.05 190.89,140.23 192.98,140.23
+19VB_VRAM on BOTTOM (solid shape): 193.74,140.2 194.29,140.2 194.29,139.91 193.74,139.91 193.74,139.4 194.29,139.4 194.29,139.11 193.74,139.11 193.74,138.65 189.59,138.65 188.82,137.88 188.57,137.88 188.46,137.78 188.46,137.07 188.37,136.98 186.93,136.98 186.85,137.05 186.85,137.98 187.09,138.22 187.09,140.11 187.72,140.74 193.74,140.74
+DVDD on TOP (solid shape): 23.44,45.81 23.44,42.38 23.32,42.26 22.93,42.26 22.66,41.99 22.66,40.57 21.87,39.78 21.77,39.78 21.7,39.84 21.7,40.63 21.81,40.74 21.81,40.74 21.89,40.8 21.95,40.88 21.95,40.88 22.05,40.97 22.05,42.39 22.8,43.15 22.8,45.81 22.93,45.94 23.32,45.94
+DVDD_IO on TOP (solid shape): 17.96,44.66 17.96,42.42 18.08,42.3 18.19,42.3 18.84,41.65 18.84,41.58 18.86,41.35 19.04,41.21 19.05,41.21 19.12,41.14 19.12,40.88 19.07,40.82 18.8,40.82 18.49,41.14 18.48,41.15 18.39,41.34 18.2,41.44 18.18,41.44 18,41.63 17.34,41.63 17.09,41.89 17.09,44.69 17.2,44.8 17.82,44.8
+VCC_CORE on TOP (solid shape): outline of 2188 points within 110.94,57.26 133.84,72.03
+VCC_CORE on BOTTOM (solid shape): 150.03,74.57 150.03,73.62 149.9,73.49 149.24,73.49 149.12,73.36 149.12,72.47 149.24,72.35 150.86,72.35 150.99,72.22 150.99,68.04 151.11,67.92 154.83,67.92 154.96,67.79 154.96,65.68 154.83,65.55 153.74,65.55 153.61,65.68 153.61,66.89 153.49,67.01 152.93,67.01 152.8,66.89 152.8,63.01 152.68,62.89 141.91,62.89 141.78,63.01 141.78,67.98 141.97,67.98 141.97,65.17 142.1,65.04 144.64,65.04 144.76,65.17 144.76,67.58 144.64,67.71 143.75,67.71 143.62,67.84 143.62,67.98 143.49,68.11 142.1,68.11 141.97,67.98 141.78,67.98 141.78,73.17 142.13,73.52 146.51,73.52 147.68,74.7 149.91,74.7
+VCC_CORE on BOTTOM (solid shape): outline of 454 points within 108.96,58.21 111.98,67.17
+VCC_CORE on BOTTOM (solid shape): outline of 978 points within 119.27,58.62 123.7,75.6
+VCC_CORE on VCC: 109.44,58.44 108.82,59.05 108.82,66.08 112.86,70.12 138.39,70.12 144.49,76.22 156.09,76.22 156.7,75.61 156.7,63.63 156.09,63.01 145.93,63.01 141.36,58.44 ; 1 cut-out
+VCC_CORE on IN1: outline of 197 points within 110.83,58.18 151.6,76.56
+VCC_GT on TOP (solid shape): outline of 1565 points within 112.16,70.84 134.35,87.6
+VCC_GT on BOTTOM (solid shape): outline of 1926 points within 113.76,75.05 152,90.98
+VCC_GT on VCC: 113.63,70.63 113.01,71.25 113.01,80.18 114.03,81.19 114.03,85 116.93,87.9 156.09,87.9 156.7,87.29 156.7,77.34 156.09,76.73 144.28,76.73 138.18,70.63
+VCC_GT on IN1: 124.67,85.01 124.67,83.67 125.88,82.47 126.6,82.47 127.75,81.32 127.75,80.06 127.77,80.05 127.77,77.78 127.18,77.2 125.69,77.2 125.31,76.82 125.31,72.37 124.74,71.8 120.29,71.8 119.91,72.19 119.6,72.19 119.34,71.93 114.13,71.93 113.05,73.01 113.05,76.37 114.58,77.9 114.58,85.88 115.86,87.17 122.51,87.17
+VCC_SA on TOP (solid shape): outline of 123 points within 111.74,54.76 122.23,58.12
+VCC_SA on BOTTOM (solid shape): 156,58.69 156,56.83 155.86,56.69 153.68,56.69 153.68,55.87 154.59,55.87 154.73,55.73 154.73,53.74 154.61,53.61 149.33,53.61 146.54,56.41 146.54,57.55 146.67,57.68 151.75,57.68 151.87,57.81 151.87,58.69 152,58.82 155.88,58.82
+VCC_SA on BOTTOM (solid shape): outline of 313 points within 109.41,54.3 121.79,58.53
+VCC_SA on IN1 (solid shape): outline of 83 points within 116.76,55.2 122.01,57.81
+VCC_SA on VCC: 131.53,41.8 131.3,42.04 131.3,43.05 130.77,43.58 129.88,43.58 119.72,53.74 112.86,53.74 111.85,54.76 109.44,54.76 108.82,55.37 108.82,57.32 109.44,57.93 141.57,57.93 146.14,62.5 156.09,62.5 156.7,61.89 156.7,54.86 153.67,51.84 150.88,51.84 142.63,43.58 133.86,43.58 133.21,42.92 133.21,42.04 132.97,41.8
+VCCDPHY_1P24 on TOP (solid shape): 110.71,50.07 110.91,50.01 111.1,50.07 111.11,50.08 111.23,50.08 111.23,49.48 111.18,49.38 111.07,49.4 110.6,49.35 110.65,48.88 110.69,48.81 110.66,48.73 110.56,48.49 110.67,48.25 110.7,48.17 110.67,48.09 110.61,47.63 111.07,47.57 111.18,47.58 111.23,47.49 111.23,47.22 111.22,47.19 111.19,47.17 110.88,46.84 111.19,46.51 111.22,46.5 111.23,46.46 111.23,41.07 111.2,40.99 111.13,40.97 110.77,40.61 111.13,40.25 111.2,40.22 111.23,40.15 111.23,39.89 111.28,39.85 111.91,39.85 112.12,39.63 112.12,38.82 112,38.69 109.58,38.69 109.22,39.05 109.51,39.34 109.51,40.77 109.54,40.84 109.6,40.87 109.89,41.32 109.37,41.45 109.26,41.44 109.2,41.53 109.2,43.36 109.49,43.64 109.5,43.65 109.58,43.71 109.64,43.79 109.67,43.83 109.69,43.96 109.67,44.1 109.64,44.14 109.58,44.22 109.5,44.28 109.2,44.57 109.2,46.32 109.66,46.78 109.66,49.19 110.56,50.08 110.7,50.08
+VCCDPHY_1P24 on BOTTOM (solid shape): 111.46,50.34 111.76,50.14 112.07,50.34 112.08,50.38 112.2,50.38 112.38,50.2 112.38,50.13 112.21,49.84 112.38,49.56 112.38,49.48 112.21,49.31 112.12,49.31 112.11,49.3 111.15,49.3 111.01,49.44 110.83,49.48 110.8,49.47 110.71,49.56 110.69,49.61 110.66,49.65 110.66,49.87 111.17,50.38 111.45,50.38
GND on TOP (solid shape): 115.39,65.01 115.39,61.59 115.27,61.48 113.55,61.48 113.44,61.58 113.44,64.97 113.64,65.16 115.24,65.16
GND on TOP (solid shape): 118.66,117.88 118.66,109.23 118.48,109.05 117.57,109.05 117.39,109.23 117.39,117.88 117.52,118 118.54,118
GND on TOP (solid shape): 120.89,127.6 120.89,123.72 120.76,123.59 118.85,123.59 118.73,123.72 118.73,127.86 118.91,128.04 120.45,128.04
GND on TOP (solid shape): 161.78,68.42 161.78,65.35 161.6,65.17 160.82,65.17 160.64,65.35 160.64,68.42 160.82,68.6 161.6,68.6
GND on TOP (solid shape): 165.59,79.78 165.59,76.35 165.46,76.22 162.54,76.22 162.42,76.35 162.42,78.76 163.49,79.84 165.53,79.84
GND on TOP (solid shape): 182.99,50.38 182.99,48.79 182.61,48.41 180.04,48.41 179.88,48.57 179.88,50.49 180.34,50.95 182.42,50.95
GND on TOP (solid shape): 110.39,116.99 110.39,113.86 109.91,113.38 108.02,113.38 107.69,113.71 107.69,116.58 108.31,117.2 110.18,117.2
GND on TOP (solid shape): 149.7,107.73 149.7,106.83 148.94,106.83 148.66,107.11 147.94,107.11 147.82,107.24 147.82,107.82 147.95,107.95 149.48,107.95
GND on TOP (solid shape): 193.2,138.15 193.2,135.77 192.78,135.35 190.15,135.35 189.89,135.61 189.89,138.27 190.07,138.45 192.9,138.45
GND on TOP (solid shape): 42.28,51.65 42.28,51.65 42.46,51.47 42.46,47.89 42.38,47.81 41.33,47.81 41.23,47.9 41.23,51.65 41.28,51.69 42.23,51.69
GND on TOP (solid shape): 42.42,29.99 42.42,28.56 42.24,28.38 40.17,28.38 40.05,28.26 39.28,28.26 39.1,28.45 39.1,30.04 39.38,30.32 42.09,30.32
GND on TOP (solid shape): 64.12,26.18 64.12,23.9 63.48,23.26 63.48,21.13 63.12,20.78 62.24,20.78 61.92,21.09 61.92,26.15 62.09,26.31 63.99,26.31
GND on TOP (solid shape): 72.81,109.66 72.81,108.78 72.51,108.48 68.91,108.48 68.62,108.77 68.62,109.78 68.75,109.91 72.57,109.91
GND on TOP (solid shape): 194.13,116.8 194.13,114.83 193.99,114.7 190.97,114.7 190.75,114.92 190.75,116.76 190.95,116.96 193.97,116.96
GND on TOP (solid shape): 102.22,25.73 105.28,25.73 105.55,25.46 105.55,23.55 105.38,23.38 100.7,23.38 100.6,23.48 100.6,26.03 100.8,26.24 101.72,26.24
GND on TOP (solid shape): 122.15,88.77 122.15,87.99 121.91,87.75 117.92,87.75 117.81,87.87 117.81,88.81 117.94,88.95 121.97,88.95
GND on TOP (solid shape): 126.13,71.2 126.13,69.92 123.93,69.92 123.78,69.77 123.57,69.77 123.4,69.94 123.4,70.6 124.18,71.38 125.94,71.38
GND on TOP (solid shape): 167.37,71.09 167.37,65.86 167.19,65.68 166.02,65.68 165.84,65.86 165.84,70.4 165.72,70.53 165.08,70.53 164.96,70.66 164.96,71.14 165.08,71.27 167.19,71.27
GND on TOP (solid shape): 52,23.89 52,23.37 51.91,23.28 51.91,22.12 48.37,22.12 48.24,22.25 48.24,22.87 48.08,23.03 48.08,23.87 48.16,23.95 51.94,23.95
GND on TOP (solid shape): 231.94,24.05 231.94,22.99 231.79,22.84 227.56,22.84 227.52,22.81 227.13,22.81 227.02,22.92 227.02,24.07 227.14,24.19 231.8,24.19
GND on TOP (solid shape): 140.83,99.78 140.83,96.16 140.7,96.03 139.49,96.03 139.37,96.16 139.37,98.25 139.24,98.38 138.91,98.38 138.73,98.56 138.73,98.92 139.3,99.49 139.9,99.49 140.25,99.84 140.76,99.84
GND on TOP (solid shape): 190.69,104.53 190.69,102.41 190.56,102.28 187.03,102.28 186.88,102.43 186.88,104.58 186.99,104.69 190.52,104.69
GND on TOP (solid shape): 57.32,23.24 57.32,22.46 56.94,22.07 55.03,22.07 54.99,22.12 53.83,22.12 53.71,22.23 53.71,22.8 53.76,22.85 54.1,22.85 54.56,23.3 57.27,23.3
GND on TOP (solid shape): 135.44,109.67 136.97,109.67 137.27,109.36 137.27,108.63 137.58,108.32 137.58,106.96 137.42,106.8 135.37,106.8 134.48,107.69 134.48,110.11 134.61,110.23 134.87,110.23
GND on TOP (solid shape): 113.67,44.36 113.67,43.37 113.82,43.23 113.82,40.64 113.74,40.56 113.06,40.56 113.01,40.61 113.01,41.39 112.87,41.53 112.87,43.95 113,44.07 113,44.36 113.14,44.5 113.53,44.5
GND on TOP (solid shape): 147.56,97.94 147.56,94.51 147.43,94.38 145.4,94.38 145.27,94.51 145.27,94.86 145.4,94.99 145.91,94.99 146.03,95.11 146.03,97.43 146.1,97.49 146.89,97.49 147.02,97.62 147.02,98 147.15,98.13 147.37,98.13
GND on TOP (solid shape): 165.34,56.1 165.34,53.54 165.16,53.36 161.33,53.36 161.15,53.54 161.15,54.07 161.33,54.25 161.6,54.25 161.78,54.43 161.78,54.76 161.91,54.88 162.74,54.88 162.92,55.06 162.92,56.1 163.1,56.28 165.16,56.28
GND on TOP (solid shape): 144.02,104.61 144.02,102.48 143.41,101.87 142.04,101.87 141.8,101.97 141.38,102.39 141.38,104.29 141.51,104.41 141.86,104.41 142.01,104.27 142.01,104.1 142.12,103.99 143.2,103.99 143.36,104.15 143.36,104.57 143.54,104.75 143.88,104.75
GND on TOP (solid shape): 127.19,42.16 127.81,42.16 127.94,42.03 127.94,41.23 127.5,40.8 127.5,40.48 127.14,40.12 125.78,40.12 125.65,39.99 125.65,39.71 125.06,39.71 125.06,40.12 124.82,40.35 124.82,40.46 124.71,40.57 124.71,42.03 124.74,42.06 126.41,42.06 126.73,42.38 126.96,42.38
GND on TOP (solid shape): 12.12,111.91 12.12,110.18 7.71,110.18 7.71,111.67 7.78,111.73 8.65,111.66 9.45,112.04 12,112.04
GND on TOP (solid shape): 112.22,55.67 112.22,54.85 112.16,54.79 110.77,54.79 110.69,54.7 110.21,54.22 109.74,54.22 109.56,54.4 109.56,54.95 109.63,55.09 109.62,55.25 109.61,55.28 109.69,55.35 111.53,55.35 111.91,55.73 112.16,55.73
GND on TOP (solid shape): 148.48,109.48 148.48,108.84 148.43,108.84 147.79,108.21 147.53,108.21 147.42,108.31 147.42,108.51 147.05,108.88 146.3,108.88 145.88,108.46 145.88,107.06 145.24,107.06 145.12,107.18 145.12,109.49 145.3,109.67 145.88,109.67 146.13,109.41 146.95,109.41 147.34,109.79 148.16,109.79
GND on TOP (solid shape): 139.52,104.97 139.52,104.38 139.37,104.23 138.88,104.23 138.62,103.97 138.62,103.26 138.54,103.18 138.54,102.84 138.46,102.76 137.97,102.76 137.83,102.9 137.83,103.12 137.67,103.28 136.37,103.28 136.2,103.45 136.2,103.86 136.31,103.96 136.96,103.96 136.98,103.98 137.05,103.98 137.31,104.24 137.31,104.73 137.46,104.87 138.82,104.87 138.97,105.02 139.46,105.02
GND on TOP (solid shape): 117.76,70.84 117.76,70.14 118.08,70.14 118.35,69.87 118.35,69.86 118.59,69.62 119.31,69.62 119.34,69.59 119.34,69.13 119.53,68.94 119.91,68.94 119.97,68.88 119.97,68.37 119.91,68.31 117.65,68.31 117.65,68.31 114.21,68.31 114.16,68.37 114.09,68.41 114.07,68.43 114.07,70.21 114.08,70.22 114.08,70.62 114.4,70.94 117.66,70.94
GND on TOP (solid shape): 114.2,56.17 114.2,55.42 114.32,55.29 114.32,55.29 114.39,55.23 114.64,55.23 114.7,55.16 114.7,54.65 114.77,54.59 115.09,54.59 115.11,54.57 115.11,54.17 115.01,54.07 115.01,53.56 115.35,53.22 115.35,52.92 115.27,52.84 114.42,52.84 114.19,53.07 114.19,54.02 114.13,54.08 113.78,54.08 113.65,54.21 113.65,56.27 113.69,56.31 114.07,56.31
GND on TOP (solid shape): 140.79,108.26 140.82,108.24 140.84,108.21 140.84,107.02 140.84,106.92 141.04,106.71 141.79,106.71 141.92,106.59 141.92,106.34 141.8,106.23 140.85,106.23 140.76,106.14 140.76,105.16 140.74,105.14 140.11,105.14 140.09,105.16 140.09,106.15 140.09,106.19 140.09,106.36 140.09,106.36 140.09,106.6 140,106.69 140,108.24 140.03,108.26 140.59,108.26
GND on TOP (solid shape): 12.56,114.19 12.56,113.18 12.3,112.92 10.52,112.92 9,111.4 9,110.18 0.98,110.18 0.98,113.1 5.64,113.1 7.68,113.1 8.45,112.6 9.05,113.3 9.05,114.57 12.17,114.57
GND on TOP (solid shape): 200.01,74.95 200.01,74.32 200.13,74.19 201.53,74.19 201.66,74.06 201.66,72.11 200.95,72.11 200.65,71.8 200.52,71.8 200.42,71.7 199.25,71.7 199.22,71.67 199.19,71.67 199.19,71.65 199.12,71.57 199.12,70.89 199.25,70.76 200.64,70.76 200.77,70.63 200.77,70 200.9,69.87 201.53,69.87 201.66,69.74 201.66,69.36 201.53,69.24 199.18,69.24 199.12,69.24 198.23,70.12 197.09,70.12 196.95,69.98 196.87,69.98 196.87,69.91 196.45,69.49 196.45,68.6 196.32,68.47 195.82,68.47 195.69,68.6 195.69,74.95 195.82,75.08 199.88,75.08
GND on TOP (solid shape): 115.55,134.35 115.55,128.29 115.81,128.04 118.35,128.04 118.47,127.91 118.47,126.27 118.27,126.07 116.51,126.07 116.31,125.88 116.31,125.24 116.19,125.12 115.86,125.12 115.81,125.12 115.68,125.24 115.68,125.88 115.55,126 114.79,126 114.54,125.75 114.54,121.18 114.28,120.92 112.17,120.92 111.87,121.23 111.87,127.24 112.12,127.49 112.12,133.45 112.04,133.53 110.66,133.53 109.73,132.61 107.61,132.61 107.38,132.84 107.38,134.2 107.5,134.33 109.2,134.33 109.88,134.38 110.55,134.51 110.56,134.51 115.39,134.51
GND on TOP (solid shape): 127.05,56.53 127.78,56.53 127.87,56.44 127.87,55.99 127.78,55.9 126.73,55.9 126.58,55.75 126.58,55.49 124.44,55.49 124.23,55.28 124.23,54.39 124.33,54.28 124.37,54.28 124.38,54.27 124.63,54.27 124.79,54.12 124.79,53.64 124.61,53.46 123.78,53.46 123.62,53.63 123.62,53.77 123.82,54.09 123.62,54.41 123.62,55.5 123.93,55.81 123.93,56.71 124.12,56.9 126.68,56.9
GND on TOP (solid shape): 130.7,75.67 130.7,75.23 131.05,74.89 131.43,74.89 131.55,75.01 131.55,75.65 132.44,75.65 132.44,73.74 132.06,73.36 127.11,73.36 126.89,73.58 126.89,75.36 126.96,75.42 127.9,75.42 128.25,75.09 128.56,75.46 128.56,75.53 128.54,75.61 128.55,75.65 128.56,75.68 128.58,75.7 130.51,75.7 130.59,75.7 130.67,75.71
GND on TOP (solid shape): 7.48,109.48 7.48,107.78 7.79,107.46 8.65,107.46 9,107.11 9,106.83 8.87,106.7 7.49,106.7 7.09,106.3 7.09,105.18 6.97,105.05 6.46,105.05 5.95,105.56 5.37,105.56 5.37,107.2 4.77,107.9 3.99,107.4 0.98,107.4 7.29,109.67
GND on TOP (solid shape): 149.7,105.72 149.7,101.24 150.08,100.86 151.37,100.86 151.55,100.68 151.55,99.96 151.36,99.77 150.71,99.77 150.66,99.82 150.66,100.28 150.48,100.45 150.13,100.45 149.9,100.23 149.9,98.25 150.04,98.11 150.04,96.11 149.9,95.98 149.36,95.98 149.21,96.12 149.21,99.46 149.09,99.59 148.95,99.59 148.83,99.72 148.83,99.91 148.95,100.04 149.09,100.04 149.21,100.16 149.21,100.68 148.4,101.49 147.95,101.49 147.86,101.58 147.86,101.78 147.95,101.87 148.75,101.87 149.11,102.24 149.11,102.68 148.46,103.33 147.85,103.33 147.76,103.42 147.76,103.86 147.85,103.95 148.79,103.95 149.11,104.27 149.11,104.71 149.05,104.78 148.7,105.13 147.82,105.13 147.76,105.18 147.76,105.74 147.84,105.81 149.61,105.81
GND on TOP (solid shape): 131.01,59.29 131,59.26 131.07,58.97 131.33,58.84 131.4,58.8 131.43,58.73 131.43,58.68 131.41,58.64 131.38,58.63 131.05,58.43 131.1,58.05 131.12,57.98 131.1,57.92 131.05,57.53 131.38,57.33 131.41,57.32 131.43,57.28 131.43,57.04 131.68,56.79 132.39,56.79 132.57,56.61 132.57,54.88 132.39,54.7 131.48,54.7 131.3,54.52 131.3,53.67 131.12,53.49 130.54,53.49 130.41,53.61 130.41,59.14 130.6,59.33 130.65,59.38 130.92,59.38
GND on TOP (solid shape): 112.03,60.22 112.89,60.22 113.54,59.56 114.19,59.56 114.31,59.54 114.41,59.56 114.42,59.56 114.53,59.56 114.67,59.71 114.67,60.01 114.78,60.11 114.91,60.11 114.91,60.11 114.99,60.11 115.11,59.99 115.11,59.65 115.2,59.56 115.32,59.56 115.34,59.54 116.98,59.54 117.19,59.76 117.19,60.06 117.32,60.19 117.65,60.19 117.75,60.09 117.75,60.01 117.93,59.84 119.7,59.84 119.82,59.72 119.82,59.52 119.94,59.4 119.94,59.39 120.02,59.31 120.42,59.31 120.46,59.28 120.46,59.02 120.51,58.97 121.03,58.97 121.05,58.94 121.05,58.59 121.27,58.38 122.09,58.38 122.09,57.93 121.65,57.93 121.39,57.68 120.57,57.68 120.25,58 116.76,58 116.51,57.74 116.51,57.48 116.36,57.33 115.85,57.33 115.72,57.45 115.72,57.77 115.56,57.92 113.02,57.92 112.95,58 112.95,58.19 112.89,58.25 112.17,58.25 112.17,56.6 111.74,56.6 111.74,58.1 111.65,58.01 111.65,57.95 111.32,57.61 110.85,57.61 110.83,57.64 110.83,58.21 111.27,58.65 111.27,60.24 111.35,60.32 111.92,60.32
GND on TOP (solid shape): outline of 85 points within 1.89,62.12 6.21,65.75
GND on TOP (solid shape): outline of 114 points within 197.05,136 208.35,142.8
GND on TOP (solid shape): 7.35,99.71 7.35,99.33 7.41,98.59 8.14,98.51 8.77,98.51 9.13,98.15 9.13,97.81 6.93,95.61 5.9,95.61 5.5,95.21 3.18,95.21 2.36,94.38 2.36,89.98 2.46,89.74 2.7,89.64 3.7,89.64 3.7,89.18 2.7,89.18 2.14,89.42 1.9,89.98 1.9,94.58 1.79,94.93 1.49,95.15 1.36,95.2 1.1,95.24 0.98,95.48 0.98,97.5 3.99,97.5 4,97.46 4.79,97.01 5.37,97.7 5.37,99.46 6.08,99.46 6.46,99.84 7.22,99.84
GND on TOP (solid shape): 3.71,86.32 2.7,86.32 2.46,86.22 2.36,85.98 2.36,81.48 2.23,80.94 1.86,80.53 1.86,71.21 1.77,70.76 1.52,70.39 0.66,69.53 0.66,39.47 1.52,38.61 1.67,38.42 1.78,38.21 3.17,36.82 9.13,36.82 9.9,36.05 9.9,34.5 10.49,33.9 11.45,33.9 11.7,33.65 11.7,32.19 12.91,30.99 15.03,30.99 15.67,30.35 15.67,29.3 15.35,28.98 9.33,28.98 8.06,27.71 5.32,27.71 3.71,29.32 1.4,29.32 1.4,37.79 1.35,38.06 1.2,38.29 0.29,39.2 0.23,39.29 0.2,39.41 0.2,69.59 0.23,69.71 0.29,69.8 1.2,70.71 1.35,70.94 1.4,71.21 1.4,80.11 1.4,80.11 1.4,80.6 1.44,80.75 1.55,80.86 1.74,81.02 1.86,81.23 1.88,81.3 1.9,81.39 1.9,81.48 1.9,85.15 1.9,85.15 1.9,85.97 2.13,86.54 2.7,86.77 3.71,86.77
GND on TOP (solid shape): 118.44,56.25 118.44,55.87 118.98,55.33 118.98,54.76 119.11,54.63 119.21,54.63 120.41,54.63 120.54,54.63 120.63,54.72 120.63,55.11 120.72,55.2 121.07,55.2 121.15,55.17 121.17,55.08 121.5,54.7 121.82,55.08 121.86,55.21 121.98,55.27 122.3,55.27 122.42,55.21 122.46,55.09 122.48,54.97 122.54,54.86 122.54,54.26 122.49,54.11 122.52,53.95 122.54,53.92 122.36,53.74 121.95,53.74 121.86,53.79 121.86,53.9 121.52,54.44 121.31,53.83 121.33,53.81 121.33,53.74 121.24,53.74 120.84,54.14 119,54.14 118.92,54.06 118.92,53.55 118.86,53.49 118.78,53.49 118.47,53.49 118.38,53.58 118.38,54.03 118,54.4 118,55.61 117.81,55.8 115.68,55.8 115.65,55.8 115.59,55.86 115.59,56.26 115.66,56.32 118.37,56.32
GND on TOP (solid shape): outline of 322 points within 16.32,65.36 53.59,95
GND on TOP (solid shape): outline of 504 points within 54.48,46.71 62.97,53.62
GND on TOP (solid shape): outline of 733 points within 207.23,0.2 268.5,56.87
GND on TOP (solid shape): outline of 209 points within 8.75,0.2 268.5,150.1
GND on TOP (solid shape): outline of 1478 points within 201.83,0.2 227.59,27.31
GND on BOTTOM (solid shape): 6.92,72.5 6.92,71.64 5.03,71.64 4.79,71.87 4.79,72.58 4.87,72.66 6.76,72.66
GND on BOTTOM (solid shape): 6.97,71.25 6.97,70.63 6.78,70.44 4.83,70.44 4.64,70.63 4.64,71.39 6.83,71.39
GND on BOTTOM (solid shape): 4.81,61.74 4.81,59.59 4.67,59.45 3.29,59.45 3.16,59.58 3.16,61.74 3.26,61.84 4.71,61.84
GND on BOTTOM (solid shape): 12.14,111.98 12.14,110.26 12.06,110.18 10.24,110.18 10.15,110.27 10.15,111.92 10.31,112.08 12.03,112.08
GND on BOTTOM (solid shape): 13.34,50.97 13.34,47.6 13.13,47.38 9.9,47.38 9.65,47.64 9.65,51.01 9.9,51.27 13.04,51.27
GND on BOTTOM (solid shape): 14.08,58.44 14.08,57.17 13.95,57.04 9.13,57.04 9,57.17 9,58.44 9.13,58.57 13.95,58.57
GND on BOTTOM (solid shape): 14.59,82.32 14.59,80.67 14.46,80.54 13.25,80.54 13.13,80.67 13.13,82.32 13.25,82.44 14.46,82.44
GND on BOTTOM (solid shape): 36.2,94.81 36.2,91.63 35.2,90.62 31.13,90.62 30.7,91.05 30.7,94.94 30.8,95.04 35.97,95.04
GND on BOTTOM (solid shape): 72.93,94.85 72.93,91.51 72.73,91.31 67.69,91.31 66.99,92.01 66.99,94.73 67.22,94.97 72.82,94.97
GND on BOTTOM (solid shape): 75.52,29.47 75.52,25.94 73.3,23.73 68.13,23.73 68.05,23.8 68.05,27.78 70.1,29.83 75.16,29.83
GND on BOTTOM (solid shape): 118.66,118.2 118.66,109.17 118.48,108.99 117.51,108.99 117.33,109.17 117.33,118.2 117.51,118.38 118.48,118.38
GND on BOTTOM (solid shape): 123.3,26.13 123.3,24.2 123.12,24.02 121.32,24.02 121.14,24.2 121.14,26.13 121.32,26.31 123.12,26.31
GND on BOTTOM (solid shape): 131.6,115.9 131.6,114.47 131.18,114.04 129.4,114.04 129.15,114.3 129.15,115.82 129.33,116.01 131.5,116.01
GND on BOTTOM (solid shape): 147.3,82.82 147.3,81.83 147.18,81.71 142.54,81.71 142.41,81.83 142.41,82.82 142.54,82.95 147.18,82.95
GND on BOTTOM (solid shape): 147.94,79.65 147.94,76.22 146.41,74.7 142.54,74.7 142.41,74.82 142.41,79.59 142.6,79.78 147.81,79.78
GND on BOTTOM (solid shape): 149.48,104.18 149.48,103.85 147.31,101.68 147.11,101.68 146.88,101.91 146.88,102.07 149.12,104.31 149.35,104.31
GND on BOTTOM (solid shape): 176.65,86.46 176.65,83.33 176.27,82.95 173.72,82.95 173.46,83.21 173.46,86.51 173.72,86.76 176.35,86.76
GND on BOTTOM (solid shape): 179.05,86.36 179.05,84.93 178.91,84.79 177.05,84.79 176.89,84.95 176.89,86.31 176.98,86.41 179,86.41
GND on BOTTOM (solid shape): 181.64,55.98 181.64,54 181.44,53.79 180.08,53.79 180.01,53.87 180.01,56.05 180.09,56.14 181.48,56.14
GND on BOTTOM (solid shape): 9.25,42.09 9.25,40.88 9.16,40.79 8.68,40.79 6.42,40.79 6.33,40.88 6.33,42.09 6.42,42.18 9.16,42.18
GND on BOTTOM (solid shape): 9.41,82.17 9.41,80.67 9.28,80.54 7.73,80.54 7.6,80.67 7.6,82.06 7.73,82.19 9.39,82.19
GND on BOTTOM (solid shape): 116.95,118.2 116.95,108.78 116.77,108.61 112.68,108.61 112.5,108.78 112.5,118.2 112.68,118.38 116.77,118.38
GND on BOTTOM (solid shape): 171.4,109.33 171.4,101 171.23,100.83 170.14,100.83 169.98,100.99 169.98,109.28 170.17,109.48 171.26,109.48
GND on BOTTOM (solid shape): 173.93,141.6 173.93,134.3 173.81,134.17 173,134.17 172.69,134.48 172.69,141.32 172.66,141.35 172.66,141.66 172.79,141.79 173.74,141.79
GND on BOTTOM (solid shape): 176.32,71.61 176.32,68.39 176.02,68.09 172.45,68.09 172.32,68.22 172.32,69.11 173.46,70.25 173.46,71.52 173.72,71.78 176.16,71.78
GND on BOTTOM (solid shape): 181.8,111.2 181.8,110.19 181.4,109.8 177.06,109.8 176.88,109.98 176.88,111.16 177.02,111.3 181.7,111.3
GND on BOTTOM (solid shape): 188.51,63.77 188.51,62.57 188.45,62.5 181.74,62.5 181.1,63.14 181.1,63.82 181.15,63.88 184.2,63.88 184.22,63.9 188.39,63.9
GND on BOTTOM (solid shape): 102.22,25.73 105.28,25.73 105.55,25.46 105.55,23.55 105.38,23.38 100.7,23.38 100.6,23.48 100.6,26.03 100.8,26.24 101.72,26.24
GND on BOTTOM (solid shape): 126.98,86.44 126.98,86.06 125.99,85.07 125.82,85.07 125.7,85.18 125.7,85.32 125.07,85.96 124.34,85.96 124.23,86.08 124.23,86.28 125.12,87.17 126.26,87.17
GND on BOTTOM (solid shape): 130.95,96.31 130.95,95.68 131.13,95.5 131.33,95.5 131.41,95.42 131.41,95 131.28,94.87 127.26,94.87 127.11,95.02 127.11,96.29 127.21,96.39 130.87,96.39
GND on BOTTOM (solid shape): 143.49,67.84 143.49,67.46 143.75,67.2 144.38,67.2 144.51,67.08 144.51,65.43 144.38,65.3 142.35,65.3 142.22,65.43 142.22,67.84 142.35,67.97 143.37,67.97
GND on BOTTOM (solid shape): 150.1,62.12 150.1,59.33 150.35,59.08 151.49,59.08 151.62,58.95 151.62,57.93 151.49,57.81 144.95,57.81 142.67,60.09 142.67,62.02 143.02,62.38 149.84,62.38
GND on BOTTOM (solid shape): 165.08,79.4 165.08,76.6 164.7,76.22 156.89,76.22 156.76,76.35 156.76,78 156.89,78.13 159.11,78.13 159.24,78.25 159.24,79.45 159.37,79.58 164.9,79.58
GND on BOTTOM (solid shape): 176.68,59.61 176.68,58.38 176.59,58.29 174.54,58.29 174.42,58.42 174.42,59.61 174.49,59.68 176.61,59.68
GND on BOTTOM (solid shape): 183.11,50.31 183.11,49.29 182.94,49.12 181.62,49.12 180.91,48.41 179.31,48.41 179.08,48.64 179.08,50.04 179.18,50.14 181.01,50.14 181.36,50.49 182.94,50.49
GND on BOTTOM (solid shape): 174.71,92.14 174.71,90.17 174.7,90.16 174.7,89.99 174.61,89.89 173.56,89.89 173.39,90.06 173.39,92.14 173.39,92.15 174.09,92.15 174.14,92.19 174.65,92.19
GND on BOTTOM (solid shape): 202.83,38.26 202.47,34.82 201.83,34.18 200.28,34.18 199.51,34.95 199.66,36.41 199.78,36.55 199.91,36.68 200.23,36.68 201.51,37.96 201.51,38.35 201.68,38.53 202.56,38.53
GND on BOTTOM (solid shape): 16.95,110.84 19.59,110.84 19.68,110.75 19.68,109.7 19.58,109.61 16.43,109.61 15.73,110.31 13.78,110.31 13.56,110.53 13.56,111.84 13.85,112.13 15.65,112.13
GND on BOTTOM (solid shape): 130.16,129 130.16,126.23 129.98,126.05 128.81,126.05 128.63,125.88 128.63,125.17 128.45,124.99 127.16,124.99 126.98,125.17 126.98,125.88 128.51,127.4 128.51,129 128.69,129.18 129.98,129.18
GND on BOTTOM (solid shape): 165.46,56.03 165.46,53.61 165.34,53.49 161.02,53.49 160.85,53.66 160.85,54.92 160.96,55.03 162.82,55.03 162.95,55.16 162.95,56.03 163.07,56.15 165.34,56.15
GND on BOTTOM (solid shape): 226.58,27.1 226.58,25.76 226.19,25.37 226.19,23.68 225.86,23.35 224.3,23.35 224.05,23.59 224.05,27.11 224.3,27.36 226.31,27.36
GND on BOTTOM (solid shape): 159.59,131.24 159.59,131 159.14,130.55 157.94,130.55 157.21,129.82 155.56,129.82 155.44,129.93 155.44,130.48 155.54,130.58 156.32,130.58 156.61,130.86 158.67,130.86 159.17,131.37 159.46,131.37
GND on BOTTOM (solid shape): 3.4,48.24 3.4,45.68 3.53,45.55 5.24,45.55 5.37,45.42 5.37,43.45 5.24,43.33 4.89,43.33 4.76,43.45 4.76,44.52 4.48,44.8 2.52,44.8 2.4,44.93 2.4,48.31 2.54,48.45 3.2,48.45
GND on BOTTOM (solid shape): 20.65,39.42 20.65,36.08 20.47,35.9 19.77,35.9 19.69,35.97 19.69,36.25 19.63,36.32 18.82,36.32 18.71,36.43 18.71,37.32 18.82,37.43 18.82,37.89 18.71,38.01 18.71,38.95 19.32,39.56 20.51,39.56
GND on BOTTOM (solid shape): 191.56,104.43 191.56,102.6 191.43,102.47 187.18,102.47 186.64,103 182.89,103 182.88,103.02 182.88,103.81 182.91,103.84 186.88,103.84 187.02,103.98 187.02,104.48 187.16,104.62 191.37,104.62
GND on BOTTOM (solid shape): 2.96,65.65 2.96,64.54 2.78,64.36 2.78,63.46 3.03,63.2 4.05,63.2 4.31,63.47 4.31,64.83 4.4,64.92 5.95,64.92 6.14,64.72 6.14,63 5.26,62.11 2.16,62.11 1.89,62.38 1.89,65.59 2.06,65.76 2.85,65.76
GND on BOTTOM (solid shape): 185.34,87.4 185.34,86.57 185.77,86.13 185.77,83.11 185.46,82.79 182.83,82.79 182.66,82.96 182.66,83.62 182.9,83.86 184.77,83.86 185.11,84.19 185.11,85.05 184.95,85.21 184.88,85.21 184.79,85.22 184.7,85.21 183.56,85.21 183.45,85.32 183.45,87.4 183.59,87.54 185.2,87.54
GND on BOTTOM (solid shape): 114.22,36.15 115.24,36.15 115.43,35.96 117.46,35.96 117.58,35.83 117.58,35.07 117.01,34.5 116.63,34.5 116.2,34.07 115.59,34.07 115.23,34.43 114.65,34.43 114.6,34.47 114.6,35.45 114.47,35.58 114.28,35.58 114.09,35.77 113.33,35.77 113.27,35.83 113.27,36.28 113.33,36.34 114.03,36.34
GND on BOTTOM (solid shape): 193.29,137.18 193.29,135.74 192.78,135.24 191.87,135.24 191.4,135.71 189.89,135.71 189.83,135.78 188.53,135.78 188.1,135.35 186.73,135.35 186.35,135.74 185.27,135.74 185.18,135.65 184.9,135.65 184.8,135.75 184.8,136.04 184.87,136.1 186.34,136.1 186.47,136.23 186.47,136.25 186.47,136.33 186.64,136.49 189.44,136.49 189.86,136.91 189.86,138.14 189.97,138.25 192.22,138.25
GND on BOTTOM (solid shape): 160.51,90.43 160.51,89.77 160.39,89.64 160.39,89.02 160.33,88.97 159.66,88.97 159.46,89.17 157.68,89.17 157.56,89.29 157.57,89.32 157.59,89.44 157.56,89.56 157.56,89.59 157.48,89.68 157.41,89.74 157.34,89.81 156.75,89.81 156.64,89.92 156.64,90.49 156.7,90.55 160.39,90.55
GND on BOTTOM (solid shape): 171.18,132.68 171.18,132.2 171.11,132.13 167.63,132.13 167.57,132.2 167.57,132.24 167.56,132.28 167.63,132.45 167.82,132.46 167.85,132.44 168.32,132.44 168.52,132.64 169.45,132.64 169.54,132.73 171.13,132.73
GND on BOTTOM (solid shape): 43.16,49.12 43.16,48.79 42.71,48.79 42.7,48.78 41.95,48.78 41.84,48.86 41.7,48.88 40.26,48.88 40.18,48.87 40.11,48.85 40.07,48.85 40.04,48.88 40.02,48.92 40.27,49.17 41.7,49.17 41.82,49.19 41.92,49.24 43.03,49.24
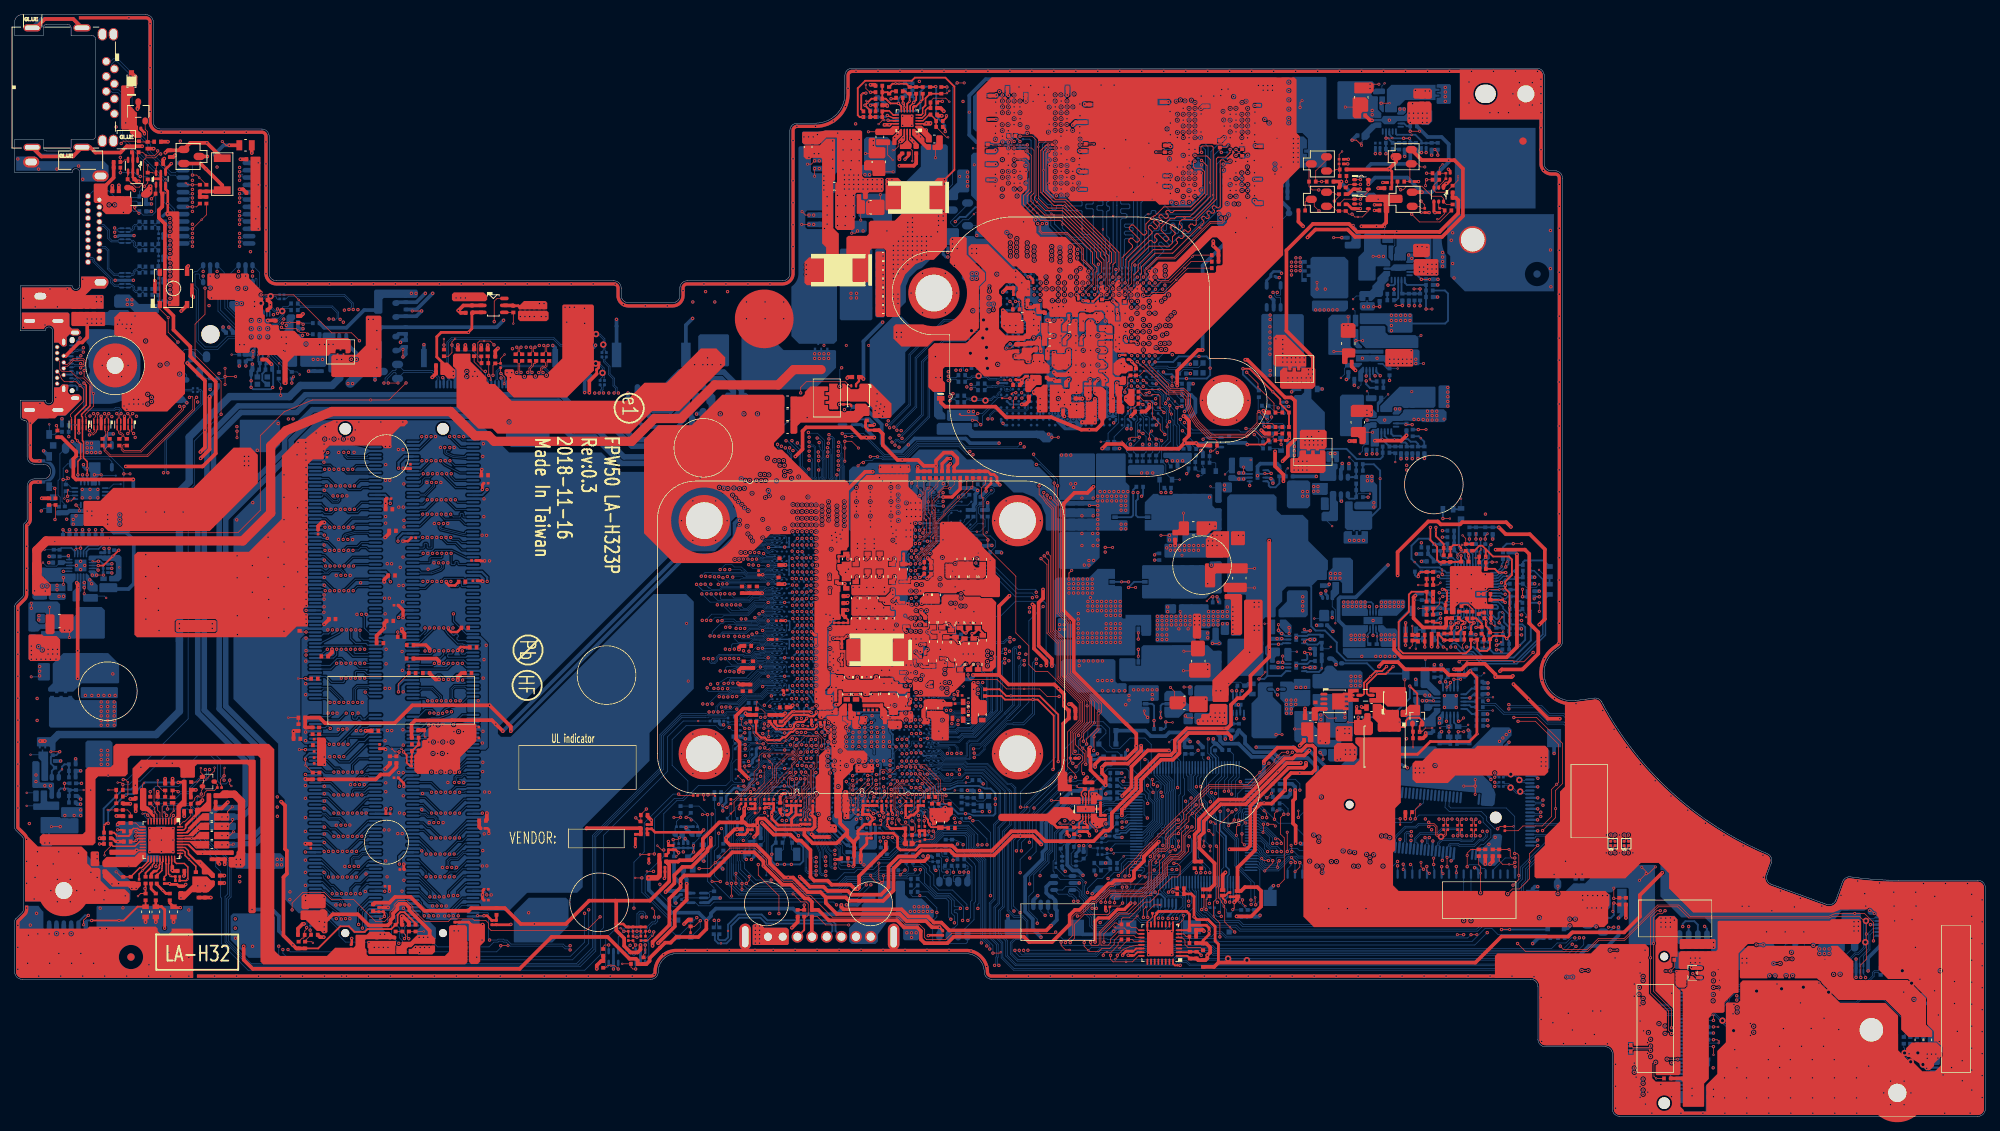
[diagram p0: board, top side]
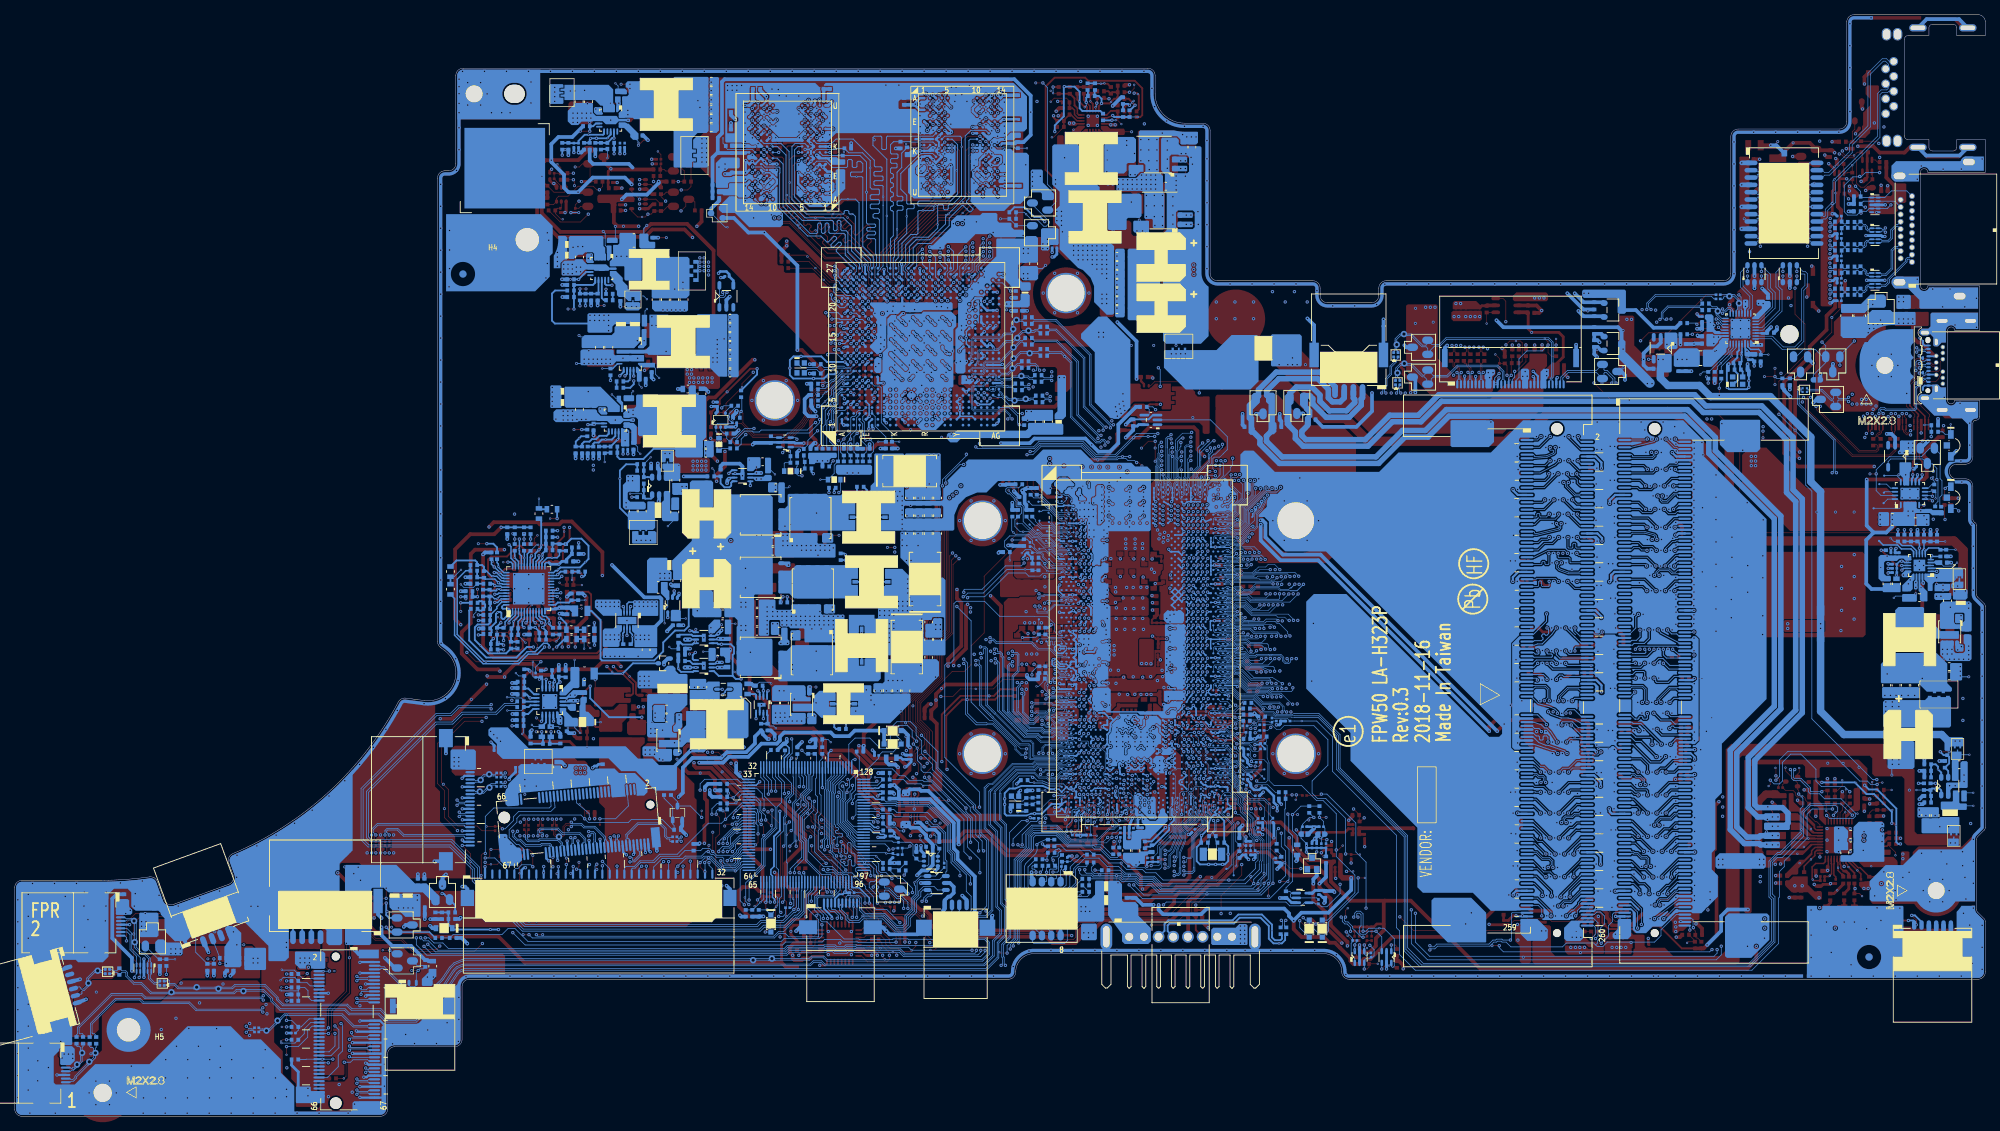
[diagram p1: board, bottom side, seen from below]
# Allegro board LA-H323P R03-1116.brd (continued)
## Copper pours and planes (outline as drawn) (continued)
GND on BOTTOM (solid shape): 192.41,116.75 192.43,116.74 193.75,116.74 194.13,116.36 194.13,114.84 194,114.71 191.71,114.71 190.91,115.52 190.16,115.52 190.11,115.52 189.79,115.52 189.71,115.44 189.66,115.4 189.63,115.36 187.73,115.36 187.59,115.49 186.69,115.49 186.63,115.55 186.63,115.74 186.7,115.81 187.61,115.81 188.05,116.25 190.67,116.25 191.15,116.73 191.15,116.82 191.25,116.92 192.24,116.92
GND on BOTTOM (solid shape): 167.24,70.38 167.24,65.68 167.11,65.55 165.96,65.55 165.83,65.68 165.83,67.58 165.7,67.71 164.45,67.71 164.32,67.58 164.32,66.95 164.19,66.82 163.18,66.82 162.92,66.57 161.15,66.57 161.02,66.44 161.02,64.79 160.89,64.66 155.68,64.66 155.56,64.79 155.56,68.35 155.66,68.45 158.58,68.45 158.73,68.6 158.73,69.74 158.86,69.87 162.67,69.87 162.8,69.74 162.8,69.24 162.92,69.11 164.83,69.11 164.96,69.24 164.96,70.38 165.08,70.51 167.11,70.51
GND on BOTTOM (solid shape): 123.73,85.57 123.73,85.41 124,85.14 124,84.87 123.81,84.68 123.81,84.68 123.57,84.44 123.57,84.11 123.47,84.01 123.4,84.01 123.34,83.99 122.93,83.99 122.84,84.01 122.74,84.01 122.72,84 122.61,84.1 122.61,84.27 122.95,84.6 123,84.64 123.04,84.69 123.28,84.93 123.28,85.55 123.41,85.68 123.62,85.68
GND on BOTTOM (solid shape): 168.24,131.35 168.36,131.23 168.53,131.18 168.71,131.18 168.73,131.15 168.76,131.12 168.83,131.04 168.83,130.68 168.76,130.6 168.71,130.51 168.36,130.51 168.12,130.61 167.89,130.51 167.51,130.51 167.41,130.61 167.41,130.74 168.03,131.35
GND on BOTTOM (solid shape): 195.25,96.08 195.25,95.03 194.93,94.71 191.92,94.71 191.79,94.84 190.24,94.84 190.18,94.9 189.31,94.9 189.27,94.86 187.9,94.86 187.48,94.43 186.1,94.43 185.74,94.8 185.7,94.84 184.8,94.84 184.76,94.8 184.75,94.8 184.7,94.75 184.21,94.75 184.12,94.84 184.12,95.12 184.23,95.23 184.67,95.23 184.75,95.15 185.67,95.15 185.87,95.35 185.87,95.44 186.01,95.58 188.8,95.58 189.28,96.06 189.28,96.26 189.49,96.46 194.87,96.46
GND on BOTTOM (solid shape): 144.81,129.79 144.81,129.77 144.9,129.6 145.07,129.51 145.08,129.51 145.39,129.2 145.39,128.84 145.22,128.67 144.97,128.67 144.88,128.77 144.75,128.83 144.74,128.83 144.61,128.97 144.6,128.98 144.55,129.11 144.45,129.21 144.45,129.65 144.64,129.84 144.75,129.85
GND on BOTTOM (solid shape): 12.56,114.19 12.56,113.18 12.3,112.92 10.52,112.92 9,111.4 9,110.32 8.86,110.18 0.98,110.18 0.98,113.1 7.68,113.1 8.45,112.6 9.05,113.3 9.05,114.57 12.17,114.57
GND on BOTTOM (solid shape): 3.41,130.32 12.17,130.32 12.81,129.69 12.81,127.99 12.35,127.53 10.24,127.53 9.05,127.53 9.05,128.8 8.45,129.5 7.68,129 0.2,129 0.2,130.96 2.78,130.96
GND on BOTTOM (solid shape): 99.48,83.32 99.56,83.29 99.8,83.04 99.83,82.96 99.8,82.89 99.69,82.55 99.94,82.31 99.98,82.3 99.98,81.94 100.15,81.77 99.97,81.59 99.76,81.8 99.76,82.24 99.28,82.73 99.28,83.19 99.31,83.2 99.36,83.23 99.41,83.28
GND on BOTTOM (solid shape): 7.48,109.47 7.48,107.77 7.77,107.47 8.63,107.47 9,107.11 9,106.83 8.87,106.7 7.49,106.7 7.09,106.3 7.09,105.18 6.97,105.05 6.46,105.05 5.95,105.56 5.37,105.56 5.37,107.2 4.77,107.9 3.99,107.4 0.98,107.4 0.98,109.67 7.28,109.67
GND on BOTTOM (solid shape): 61.61,58 61.48,57.87 61.48,57.65 61.6,57.53 61.61,57.49 61.6,57.46 61.54,57.36 61.52,57.24 61.53,57.22 60.84,56.53 60.6,56.47 60.5,56.49 60.48,56.59 60.42,56.91 60.12,57.04 60.1,57.04 59.94,57.2 59.94,58.13 60.14,58.33 61.28,58.33
GND on BOTTOM (solid shape): 115.43,134.33 115.43,130.19 115.3,130.07 114.79,130.07 114.54,129.81 114.54,128.91 114.75,128.69 115.1,128.69 115.76,128.04 118.29,128.04 118.47,127.86 118.47,126.38 118.35,126.26 114.91,126.26 114.66,126.01 114.66,122.57 114.53,122.43 113.65,122.43 113.52,122.3 113.52,121.3 113.39,121.18 112,121.18 111.96,121.21 111.96,125.84 112.12,126 112.12,128.29 112.71,128.88 112.71,133.45 112.44,133.71 110.2,133.71 109.76,133.28 109.76,132.71 109.64,132.59 107.6,132.59 107.36,132.84 107.36,134.25 107.43,134.33 109.2,134.33 109.88,134.38 110.55,134.51 110.56,134.51 115.25,134.51
GND on BOTTOM (solid shape): 143.64,132.38 143.7,132.31 143.78,132.26 143.79,132.26 144.17,131.88 146.44,131.88 146.75,131.57 147.25,131.57 147.33,131.49 147.33,130.91 147.29,130.87 145.99,130.87 145.29,131.56 145.17,131.56 145.13,131.6 143.42,131.6 143.41,131.59 143.35,131.61 143.35,131.66 143.33,131.82 143.23,131.95 143.22,131.95 143.09,132.08 143.07,132.18 143.14,132.25 143.25,132.3 143.32,132.38
GND on BOTTOM (solid shape): 43.45,63.9 43.53,63.87 43.55,63.78 43.57,63.61 43.66,63.46 43.66,63.05 43.38,62.77 41.95,62.77 41.91,62.8 41.92,62.86 41.97,62.89 42.01,62.91 42.04,62.93 42.58,63.37 42.6,63.37 42.9,63.48 42.99,63.78 43.01,63.87 43.09,63.9
GND on BOTTOM (solid shape): 165.4,127.87 165.4,127.86 165.49,127.69 165.66,127.6 165.67,127.59 165.81,127.46 165.82,127.44 165.9,127.29 166.05,127.2 166.07,127.2 166.2,127.06 166.21,127.05 166.26,126.92 166.37,126.82 166.37,126.6 166.3,126.55 166.25,126.48 166.03,126.48 165.94,126.58 165.81,126.64 165.8,126.64 165.65,126.79 165.64,126.81 165.55,126.95 165.4,127.03 165.39,127.03 165.06,127.37 165.06,127.68 165.28,127.9 165.36,127.9
GND on BOTTOM (solid shape): 147.3,90.32 147.3,86.33 147.26,86.25 147.18,86.23 146.73,85.88 147.18,85.54 147.26,85.52 147.3,85.44 147.3,84.22 147.18,84.09 142.53,84.09 142.43,84.19 142.43,85.75 142.56,86.02 142.43,86.3 142.43,86.95 142.43,86.95 142.43,90.33 142.54,90.44 147.18,90.44
GND on BOTTOM (solid shape): 160.92,134.55 161.05,134.51 161.14,134.41 161.18,134.32 161.23,134.32 162.06,133.49 164.56,133.49 164.58,133.51 164.59,133.51 165.19,134.11 165.43,134.11 165.51,134.04 165.51,133.76 165.4,133.51 165.51,133.27 165.51,133.06 165.42,132.97 161.23,132.97 161.11,133.08 161.08,133.17 161.13,133.24 161.24,133.64 160.88,133.84 160.85,133.83 160.8,133.88 160.8,133.94 160.8,134.54 160.81,134.55
GND on BOTTOM (solid shape): 161.92,126.92 162.03,126.94 162.09,126.85 162.09,125.79 161.6,125.3 161.56,125.34 161.47,125.41 161.35,125.44 161.29,125.47 161.26,125.53 161.15,125.76 160.91,125.85 160.87,125.86 160.86,125.9 160.86,125.92 160.87,125.96 160.91,125.97 161.13,126.04 161.25,126.24 161.25,126.25 161.39,126.39 161.4,126.4 161.56,126.48 161.65,126.64 161.65,126.66
GND on BOTTOM (solid shape): 47.19,53.36 47.29,53.3 47.27,53.19 46.97,52.89 46.97,52.88 46.95,52.86 47.1,52.28 47.56,52.66 47.58,52.74 47.66,52.78 48.13,52.78 48.18,52.64 48.2,52.6 48.17,52.52 48.12,52.52 47.56,51.96 45.92,51.96 45.82,52.03 45.84,52.14 47.07,53.36
GND on BOTTOM (solid shape): 121.24,85.9 121.24,84.7 121.5,84.44 121.69,84.44 121.82,84.3 121.82,83.62 121.69,83.48 121.12,83.48 121.03,83.39 121.03,80.78 120.99,80.75 120.67,80.75 120.17,81.25 120.17,81.39 120.24,81.59 120.17,81.78 120.17,82.04 120.24,82.24 120.17,82.43 120.17,82.69 120.24,82.89 120.17,83.08 120.17,83.34 120.24,83.54 120.17,83.73 120.17,83.99 120.24,84.18 120.17,84.38 120.17,84.64 120.24,84.83 120.17,85.03 120.17,85.29 120.24,85.48 120.17,85.68 120.17,85.93 120.36,86.12 121.01,86.12
GND on BOTTOM (solid shape): outline of 101 points within 195.34,112.56 209.88,123.09
GND on BOTTOM (solid shape): outline of 114 points within 197.05,136 208.35,142.8
GND on BOTTOM (solid shape): 58.62,62.76 58.73,62.78 58.8,62.69 58.8,62.63 58.89,62.54 58.51,62.16 58.49,62.16 58.24,61.55 58.85,61.8 58.85,61.82 59.05,62.02 59.32,62.02 59.4,61.98 59.42,61.89 59.41,61.85 59.41,61.79 58.88,61.27 57.15,61.27 57.1,61.3 57.21,61.45 57.23,61.45 57.48,62.06 56.87,61.82 56.87,61.79 56.84,61.77 55.47,61.77 55.39,61.81 55.38,61.9 55.38,61.93 55.39,61.95 55.39,62.1 55.38,62.12 55.38,62.15 55.39,62.24 55.47,62.28 58.14,62.28
GND on BOTTOM (solid shape): 143.55,130.19 143.59,130.18 143.61,130.13 143.87,129.84 144.16,130.12 144.15,130.14 144.2,130.19 144.23,130.18 144.29,130.18 144.35,130.18 144.39,130.17 144.41,130.13 144.41,130.08 144.12,129.78 144.12,129.72 144.07,129.64 143.98,129.62 143.7,129.58 143.56,129.34 143.53,129.27 143.46,129.24 143.26,129.15 143.15,128.95 143.15,128.94 143.1,128.89 143.02,128.97 143.01,128.99 142.89,129.19 142.66,129.25 142.62,129.27 142.61,129.31 142.6,129.34 142.62,129.38 142.66,129.4 142.91,129.49 143.01,129.74 143.04,129.81 143.11,129.84 143.22,129.88 143.31,129.97 143.32,129.97 143.52,130.18
GND on BOTTOM (solid shape): outline of 132 points within 130.94,118.26 144.15,123.26
GND on BOTTOM (solid shape): outline of 143 points within 29.44,21.62 35.5,27.69
GND on BOTTOM (solid shape): 12.65,107.4 14.57,106.93 16.07,105.63 16.44,105.63 16.97,104.47 17.15,103.2 17.15,101.71 17.15,101.56 16.16,98.89 13.77,97.34 13.21,97.24 12.64,97.2 10.18,97.2 10.18,99.73 10.23,99.88 10.24,100.03 10.24,100.13 10.22,100.22 10.07,100.53 9.79,100.75 9.79,101.03 10.01,101.18 10.17,101.38 10.25,101.61 10.25,101.85 10.23,101.97 10.18,102.09 10.14,102.18 10.08,102.25 10.08,103.17 9.79,103.46 9.79,103.6 10.1,103.98 10.13,104.47 10.11,104.52 10.1,104.56 10.13,104.65 10.14,104.72 10.08,105.17 9.79,105.51 9.79,107.4
GND on BOTTOM (solid shape): 135.98,129.63 136.05,129.55 136.13,129.49 136.13,129.21 136,129.1 135.95,128.93 135.92,128.87 135.85,128.84 135.56,128.54 135.81,128.2 135.82,128.19 135.95,128.06 135.96,128.05 136.28,127.78 136.6,128.05 136.61,128.06 136.74,128.19 136.75,128.2 136.91,128.28 137,128.44 137,128.45 137.13,128.59 137.15,128.59 137.3,128.66 137.39,128.8 137.59,128.8 137.64,128.71 137.72,128.64 137.72,128.33 137.42,128.03 137.41,128.03 137.25,127.94 137.16,127.78 137.16,127.77 137.03,127.64 137.01,127.63 136.89,127.58 136.79,127.47 136.57,127.47 136.26,127.64 135.98,127.44 135.79,127.44 135.68,127.59 135.5,127.65 135.43,127.68 135.4,127.75 135.34,127.9 135.22,128.01 135.22,128.22 135.41,128.51 135.22,128.81 135.22,129.02 135.36,129.14 135.4,129.33 135.43,129.4 135.5,129.43 135.67,129.49 135.79,129.63
GND on BOTTOM (solid shape): 137,132.68 137.05,132.67 137.1,132.67 137.18,132.64 137.21,132.55 137.38,132.26 137.71,132.36 137.79,132.36 137.96,132.22 138.19,132.23 138.29,132.22 138.33,132.13 138.33,132.09 138.28,132 138.18,132 137.97,132.04 137.78,131.94 137.72,131.91 137.65,131.93 137.21,131.72 137.65,131.5 137.72,131.52 137.78,131.48 137.97,131.38 138.18,131.42 138.28,131.42 138.33,131.33 138.33,129.05 138.35,129.03 138.35,128.97 138.32,128.92 138.26,128.93 138.23,128.96 138.23,128.98 138.14,129.15 137.97,129.24 137.95,129.24 137.79,129.4 137.79,129.41 137.67,129.58 137.47,129.64 137.45,129.64 137.3,129.78 137.3,130.42 137.32,130.43 137.32,130.66 136.91,131.06 136.87,131.11 136.79,131.18 136.79,131.18 136.61,131.36 136.6,131.41 136.64,131.44 136.65,131.44 136.95,131.71 136.66,131.99 136.63,131.98 136.59,132.03 136.6,132.09 136.6,132.13 136.62,132.21 136.69,132.24 136.91,132.36 136.94,132.6 136.93,132.63 136.97,132.68
GND on BOTTOM (solid shape): 173.1,130.06 173.1,126.79 172.98,126.67 171.49,126.67 171.44,126.72 171.44,127.23 171.24,127.43 169.08,127.43 168.94,127.57 168.92,127.58 168.87,127.61 168.83,127.65 168.81,127.69 168.77,127.74 168.7,127.81 168.65,127.81 168.65,127.82 168.38,127.8 168.22,127.6 168.04,127.6 167.51,127.75 167.62,127.21 167.62,127.02 167.47,126.91 167.41,126.74 167.38,126.67 167.32,126.64 167.17,126.59 167.06,126.48 166.81,126.48 166.77,126.54 166.72,126.58 166.7,126.6 166.7,126.62 166.7,126.81 166.7,126.83 166.72,126.84 166.81,126.93 166.85,127.05 166.86,127.06 166.99,127.19 167,127.2 167.26,127.54 166.96,127.84 166.9,127.87 166.87,127.93 166.82,128.09 166.71,128.2 166.71,128.43 166.75,128.46 166.78,128.5 167.06,128.5 167.17,128.42 167.31,128.38 167.38,128.36 167.41,128.29 167.75,127.99 168.06,128.33 168.08,128.4 168.15,128.44 168.28,128.47 168.38,128.56 168.66,128.56 168.82,128.37 169.05,128.3 170.76,128.3 170.94,128.12 171.84,128.12 172.28,128.56 171.84,128.99 171.73,128.99 171.38,129.34 170,129.34 169.83,129.51 169.83,130.65 169.99,130.81 172.35,130.81
GND on BOTTOM (solid shape): 156.76,129.04 156.76,126.36 157.25,125.87 157.25,125.86 157.45,125.61 157.77,125.65 157.95,125.65 158.27,125.62 158.45,125.89 158.48,125.95 158.59,125.97 158.61,125.93 158.69,125.7 158.91,125.59 158.98,125.56 159,125.49 158.99,125.45 158.95,125.44 158.69,125.33 158.61,125.06 158.62,125.03 158.46,124.87 158.43,124.88 158.14,124.32 158.7,124.61 158.69,124.64 158.85,124.8 158.87,124.79 159.13,124.85 159.25,125.08 159.28,125.14 159.35,125.17 159.57,125.26 159.67,125.48 159.67,125.5 159.72,125.55 159.81,125.45 159.82,125.44 159.94,125.24 160.15,125.17 160.19,125.16 160.21,125.12 160.21,125.09 160.19,125.05 160.16,125.03 159.92,124.47 160.49,124.69 160.51,124.76 160.57,124.79 160.77,124.89 160.85,125.09 160.88,125.16 160.99,125.17 161.01,125.13 161.03,125 161.1,124.88 161.14,124.84 160.36,124.06 157.93,124.06 155.44,126.55 155.44,129.08 155.58,129.22 156.59,129.22
GND on BOTTOM (solid shape): 145.48,130.51 145.56,130.56 145.64,130.53 146.89,129.28 146.89,125.99 146.12,125.22 142.38,125.22 142.29,125.28 142.3,125.39 142.36,125.53 142.35,125.69 142.36,125.76 142.41,125.82 142.55,125.92 142.6,126.09 142.63,126.15 142.7,126.18 142.92,126.28 143.01,126.5 143.01,126.52 143.08,126.59 143.1,126.59 143.31,126.68 143.43,126.96 143.54,126.97 143.56,126.93 143.64,126.7 143.85,126.59 143.92,126.56 143.93,126.45 143.89,126.44 143.66,126.35 143.56,126.13 143.53,126.06 143.47,126.03 143.27,125.46 143.83,125.69 143.85,125.76 143.92,125.79 144.11,125.89 144.2,126.08 144.23,126.15 144.3,126.18 144.51,126.28 144.64,126.56 144.7,126.59 145.01,126.89 144.75,127.23 144.74,127.23 144.61,127.36 144.6,127.38 144.48,127.58 144.26,127.64 144.22,127.66 144.21,127.7 144.21,127.72 144.22,127.76 144.26,127.77 144.51,127.85 144.62,128.09 144.62,128.13 145.44,128.13 145.93,128.62 145.93,129.42 145.47,129.87 145.47,130.5
GND on BOTTOM (solid shape): outline of 87 points within 222.61,0.2 268.5,47.28
GND on BOTTOM (solid shape): outline of 240 points within 163.94,121.3 172.7,126.84
GND on BOTTOM (solid shape): 161.38,130.44 161.46,130.43 161.5,130.36 161.66,130.12 161.95,130.1 162.05,130.09 162.09,130.01 162.09,129.07 162.04,128.99 161.94,128.98 161.67,128.99 161.48,128.78 161.48,128.77 161.35,128.64 161.33,128.64 161.11,128.55 160.98,128.28 160.87,128.27 160.86,128.31 160.55,128.64 160.21,128.34 160.18,128.28 160.11,128.25 159.9,128.15 159.78,127.87 159.5,127.74 159.38,127.47 159.27,127.45 159.25,127.49 159.17,127.73 158.95,127.84 158.88,127.87 158.87,127.98 158.91,127.99 159.14,128.07 159.25,128.29 159.28,128.35 159.35,128.38 159.58,128.49 159.67,128.73 159.69,128.81 159.76,128.84 159.84,128.85 159.92,128.92 160,129 160,129.09 160.04,129.16 160.11,129.18 160.15,129.18 160.22,129.19 160.26,129.15 160.26,129.13 160.72,128.92 160.52,129.39 160.49,129.39 160.45,129.43 160.46,129.49 160.46,129.53 160.49,129.61 160.55,129.64 160.64,129.65 160.72,129.72 160.8,129.8 160.8,129.89 160.84,129.96 160.91,129.98 161.17,130.08 161.26,130.33 161.29,130.41 161.36,130.44
GND on BOTTOM (solid shape): outline of 355 points within 113.01,40.51 116.1,44.11
GND on BOTTOM (solid shape): outline of 392 points within 0.2,28.24 15.79,99.84
GND on BOTTOM (solid shape): outline of 347 points within 140.4,125.22 142.36,132.54
GND on BOTTOM (solid shape): outline of 168 points within 130.4,123.52 138.39,134.22
GND on BOTTOM (solid shape): outline of 144 points within 55.24,54.59 61.59,62.02
GND on BOTTOM (solid shape): outline of 476 points within 102.08,82.34 106.13,87.1
GND on BOTTOM (solid shape): outline of 222 points within 15.33,0.2 268.5,150.1
GND on BOTTOM (solid shape): outline of 16807 points within 29.83,24.99 101.58,94.97
GND on IN1 (solid shape): 210.85,113.17 197.3,113.17 195.66,114.81 195.66,121.37 196.57,122.28 210.85,122.28
GND on IN1 (solid shape): 34.82,85.49 34.82,67.75 34.68,67.61 34.29,67.61 29.7,72.19 29.7,82.08 33.53,85.92 34.39,85.92
GND on IN1 (solid shape): 102.22,25.73 105.28,25.73 105.55,25.46 105.55,23.55 105.38,23.38 100.7,23.38 100.6,23.48 100.6,26.03 100.8,26.24 101.72,26.24
GND on IN1 (solid shape): 12.56,114.19 12.56,113.18 12.3,112.92 10.52,112.92 9,111.4 9,110.18 0.98,110.18 0.98,113.1 7.68,113.1 8.45,112.6 9.05,113.3 9.05,114.57 12.17,114.57
GND on IN1 (solid shape): 3.41,130.32 12.17,130.32 12.85,129.65 12.85,128 12.38,127.53 10.51,127.53 10.51,127.53 9.05,127.53 9.05,128.8 8.83,129.31 8.31,129.5 7.91,129.35 7.68,129 0.2,129 0.2,130.96 2.78,130.96
GND on IN1 (solid shape): 7.48,109.42 7.48,107.77 7.78,107.48 8.64,107.48 9,107.12 9,106.83 8.87,106.7 7.5,106.7 7.09,106.29 7.09,105.18 6.97,105.05 6.46,105.05 5.95,105.56 5.37,105.56 5.37,107.2 4.77,107.9 3.99,107.4 0.98,107.4 0.98,109.65 7.26,109.65
GND on IN1 (solid shape): 2.36,81.48 2.23,80.94 1.86,80.53 1.86,71.21 1.77,70.76 1.52,70.39 0.66,69.53 0.66,39.47 1.52,38.61 1.77,38.24 1.86,37.79 1.86,29.32 1.4,29.32 1.4,37.79 1.35,38.06 1.2,38.29 0.29,39.2 0.23,39.29 0.2,39.41 0.2,69.59 0.23,69.71 0.29,69.8 1.2,70.71 1.35,70.94 1.4,71.21 1.4,80.16 1.4,80.16 1.4,80.6 1.44,80.75 1.81,81.12 1.9,81.47 1.9,81.65 1.9,81.65 1.9,84.21 2.36,84.21
GND on IN1 (solid shape): outline of 204 points within 0.2,27.8 9.7,43.96
GND on IN1 (solid shape): 7.35,99.71 7.35,99.33 7.41,98.59 8.14,98.51 8.77,98.51 9.13,98.15 9.13,97.81 7.05,95.73 5.76,95.73 5.23,95.21 3.16,95.21 2.36,94.41 2.36,89.98 2.46,89.74 2.7,89.64 3.9,89.64 5.56,87.98 3.9,86.32 2.7,86.32 2.46,86.22 2.36,85.98 2.36,82.07 1.9,82.07 1.9,85.55 1.9,85.55 1.9,85.97 2.13,86.54 2.7,86.77 3.9,86.77 5.1,87.97 3.9,89.17 2.7,89.17 2.48,89.2 2.28,89.29 2.29,89.3 2.01,89.59 1.9,89.98 1.9,94.58 1.79,94.93 1.49,95.15 1.49,95.16 1.37,95.2 1.1,95.24 0.98,95.48 0.98,97.5 3.99,97.5 4,97.46 4.79,97.01 5.37,97.7 5.37,99.46 6.08,99.46 6.46,99.84 7.22,99.84
GND on IN1 (solid shape): outline of 756 points within 35.52,29.18 53.59,95.1
GND on IN1 (solid shape): outline of 1119 points within 207.9,0.2 268.5,32.48
GND on IN1 (solid shape): outline of 204 points within 15.33,0.2 268.5,150.1
GND on IN1 (solid shape): outline of 2249 points within 90.6,110.72 130.82,142.8
GND on IN2 (solid shape): 210.85,113.17 197.3,113.17 195.66,114.81 195.66,121.37 196.57,122.28 210.85,122.28
GND on IN2 (solid shape): 124.77,142.7 124.77,141.43 123.95,140.61 116.07,140.61 115.94,140.48 114.11,140.48 113.77,140.65 113.77,142.26 114.28,142.77 114.28,142.8 124.68,142.8
GND on IN2 (solid shape): 102.22,25.73 105.28,25.73 105.55,25.46 105.55,23.55 105.38,23.38 100.7,23.38 100.6,23.48 100.6,26.03 100.8,26.24 101.72,26.24
GND on IN2 (solid shape): 3.41,130.32 12.17,130.32 12.82,129.67 12.82,127.96 12.39,127.53 9.28,127.53 9.05,127.53 9.05,128.8 8.45,129.5 7.68,129 0.2,129 0.2,130.96 2.78,130.96
GND on IN2 (solid shape): 7.47,109.47 7.47,107.78 7.78,107.47 8.65,107.47 9,107.12 9,106.83 8.87,106.7 7.49,106.7 7.09,106.31 7.09,105.18 6.97,105.05 6.46,105.05 5.95,105.56 5.37,105.56 5.37,107.2 4.77,107.9 3.99,107.4 0.98,107.4 0.98,109.67 7.28,109.67
GND on IN2 (solid shape): 20.46,121.12 20.46,110.96 19.68,110.18 0.98,110.18 0.98,113.1 7.68,113.1 8.45,112.6 9.05,113.3 9.05,114.57 12.17,114.57 12.2,114.54 12.44,114.54 13.36,115.47 13.36,120.04 13.59,120.27 13.67,120.27 14.16,120.27 15.69,121.79 19.79,121.79
GND on IN2 (solid shape): 214.87,12.24 216.62,12.24 218.17,10.69 218.17,8.34 218.05,8.22 218.05,8.5 217.7,9.35 216.85,9.7 208.7,9.7 208.13,9.94 207.9,10.5 207.9,17.7 207.89,17.88 207.85,18.05 209.05,18.05
GND on IN2 (solid shape): 2.36,81.48 2.23,80.94 1.86,80.53 1.86,71.21 1.77,70.76 1.52,70.39 0.66,69.53 0.66,39.47 1.52,38.61 1.77,38.24 1.86,37.79 1.86,29.32 1.4,29.32 1.4,37.79 1.35,38.06 1.2,38.29 0.29,39.2 0.23,39.29 0.2,39.41 0.2,69.59 0.23,69.71 0.29,69.8 1.2,70.71 1.35,70.94 1.4,71.21 1.4,80.13 1.4,80.13 1.4,80.6 1.44,80.75 1.81,81.12 1.9,81.47 1.9,81.75 1.9,81.75 1.9,84.21 2.36,84.21
GND on IN2 (solid shape): outline of 210 points within 90.21,109.15 118.63,128.93
GND on IN2 (solid shape): 7.35,99.71 7.35,99.33 7.41,98.59 8.14,98.51 8.68,98.51 9.13,98.06 9.13,97.82 6.93,95.62 5.76,95.62 5.34,95.21 3.17,95.21 2.36,94.4 2.36,89.98 2.46,89.74 2.7,89.64 3.9,89.64 5.56,87.98 3.9,86.32 2.7,86.32 2.46,86.22 2.36,85.98 2.36,82.07 1.9,82.07 1.9,85.76 1.9,85.76 1.9,85.97 2.13,86.54 2.7,86.77 3.9,86.77 5.1,87.97 3.9,89.17 2.7,89.17 2.37,89.24 2.1,89.44 2.11,89.45 1.96,89.7 1.9,89.98 1.9,94.58 1.79,94.93 1.49,95.15 1.49,95.16 1.36,95.19 1.1,95.24 0.98,95.48 0.98,97.5 3.99,97.5 4,97.46 4.79,97.01 5.37,97.7 5.37,99.46 6.08,99.46 6.46,99.84 7.22,99.84
GND on IN2 (solid shape): outline of 252 points within 22.33,117.13 34.5,134.5
GND on IN2 (solid shape): outline of 827 points within 27.72,28.71 53.79,95.37
GND on IN2 (solid shape): outline of 1162 points within 218.05,0.2 268.5,32.48
GND on IN2 (solid shape): outline of 204 points within 15.33,0.2 268.5,150.1
GND on IN2 (solid shape): outline of 2378 points within 0.2,27.8 22.03,86.66
GND on VCC: 40.09,26.44 39.35,27.18 39.35,95.52 40.6,95.52 43.4,98.32 83.02,98.32 83.78,99.08 106.43,99.08 107.19,98.32 115.19,98.32 115.81,97.7 115.81,87.5 113.52,85.22 113.52,81.41 112.5,80.39 112.5,70.48 108.31,66.29 108.31,39.88 107.7,39.26 89.29,39.26 76.46,26.44
GND on VCC: 68.52,100.76 68.18,101.09 68.18,102.23 67.67,102.74 67.67,104.94 68.16,105.43 73.66,105.43 73.9,105.2 73.9,101.98 72.67,100.76
GND on VCC: 191.83,37.29 191.68,37.45 191.68,38.22 192.05,38.59 192.05,40.76 192.38,41.09 199.7,41.09 200,40.8 200,37.59 199.7,37.29
GND on VCC: 217,35.33 216.64,35.69 216.64,38.88 220.48,38.88 221.22,38.14 221.22,35.33
GND on VCC: 218.85,0.2 218.29,0.44 218.05,1 218.05,8.5 217.96,8.96 217.7,9.35 218.27,9.93 246.21,9.93 251.29,15.01 255.02,15.01 259.85,10.18 262.98,10.18 263.89,11.09 263.89,19.81 262.98,20.72 253.33,20.72 252.71,21.33 252.71,32.18 254.78,32.05 256.85,32 267.7,32 268.26,31.76 268.5,31.2 268.5,1 268.26,0.44 267.7,0.2
GND on VCC: 122.46,66.57 122.03,67 122.03,67.91 122.21,68.09 123.62,68.09 123.82,68.3 124.45,68.3 124.54,68.2 124.54,66.81 124.49,66.76 123.7,66.76 123.51,66.57
GND on VCC: 195.8,68.47 195.18,69.09 195.18,74.97 195.8,75.59 201.43,75.59 202.04,74.97 202.04,69.09 201.43,68.47
GND on VCC: outline of 242 points within 0.2,18.9 210.85,150.1
GND on GND: outline of 232 points within 0.2,0.2 268.5,150.1
GNDA on TOP (solid shape): 14.1,32.1 14.43,32.1 14.45,32.08 16.46,32.08 16.52,32.02 17.09,32.02 17.21,31.89 17.21,31.44 16.62,30.84 15.92,30.84 15.44,31.32 13.31,31.32 12.02,32.62 12.02,33.7 12.5,33.7
GNDA on TOP (solid shape): 26.74,32.21 27.13,32.21 27.25,32.08 27.25,31.42 26.4,30.57 24.19,30.57 23.17,29.54 22.42,29.54 22.29,29.67 22.29,30.56 22.42,30.69 23.29,30.69 24.22,31.61 24.22,32.73 26.22,32.73
GNDA on TOP (solid shape): 16.87,36.4 17.84,36.4 17.92,36.33 17.92,36.23 17.85,36.17 16.86,36.17 16.35,35.66 13.02,35.66 12.89,35.78 12.89,36.29 13.01,36.4 16.33,36.4 16.46,36.53 16.74,36.53
GNDA on TOP (solid shape): 1.86,28.21 1.77,27.76 1.52,27.39 0.66,26.53 0.66,19.7 0.76,19.46 1,19.36 24.33,19.36 24.33,18.9 1,18.9 0.44,19.14 0.2,19.7 0.2,26.59 0.23,26.71 0.29,26.8 1.2,27.71 1.35,27.94 1.4,28.21 1.4,28.77 1.86,28.77
GNDA on TOP (solid shape): outline of 214 points within 0.2,18.9 24.34,25.89
GNDA on BOTTOM (solid shape): 1.86,28.21 1.77,27.76 1.52,27.39 0.66,26.53 0.66,19.7 0.76,19.46 1,19.36 24.33,19.36 24.33,18.9 1,18.9 0.44,19.14 0.2,19.7 0.2,26.59 0.23,26.71 0.29,26.8 1.2,27.71 1.35,27.94 1.4,28.21 1.4,28.72 1.86,28.72
GNDA on BOTTOM (solid shape): outline of 120 points within 13.77,34.73 19.77,40.19
GNDA on BOTTOM (solid shape): outline of 226 points within 0.2,18.9 24.33,28.72
GNDA on IN1 (solid shape): 1.86,28.21 1.77,27.76 1.52,27.39 0.66,26.53 0.66,19.7 0.76,19.46 1,19.36 24.32,19.36 24.32,18.9 1,18.9 0.44,19.14 0.2,19.7 0.2,26.59 0.23,26.71 0.29,26.8 1.2,27.71 1.35,27.94 1.4,28.21 1.4,28.77 1.86,28.77
GNDA on IN1 (solid shape): outline of 604 points within 0.2,18.9 27.25,40.21
GNDA on IN2 (solid shape): 17.98,39.47 17.98,37.52 17.92,37.42 17.81,37.44 17.74,37.51 17.74,38.2 17.18,38.76 16.32,38.76 16.03,38.47 16.03,38.05 16.24,37.83 16.21,37.72 16.16,37.68 14.25,39.59 13.83,39.59 13.53,39.29 13.53,38.87 15.66,36.74 15.66,35.92 16.62,34.95 16.62,30.08 16.25,29.71 16.14,29.68 16.08,29.78 16.08,30.67 15.42,31.32 13.11,31.32 12.01,32.42 12.01,36.07 12.9,36.96 12.9,39.09 14.02,40.21 17.24,40.21
GNDA on IN2 (solid shape): 1.86,28.21 1.77,27.76 1.52,27.39 0.66,26.53 0.66,19.7 0.76,19.46 1,19.36 24.32,19.36 24.32,18.9 1,18.9 0.44,19.14 0.2,19.7 0.2,26.59 0.23,26.71 0.29,26.8 1.2,27.71 1.35,27.94 1.4,28.21 1.4,28.77 1.86,28.77
GNDA on IN2 (solid shape): outline of 244 points within 0.2,18.9 27.25,36.78
GNDA on VCC: 1,18.9 0.44,19.14 0.2,19.7 0.2,26.59 0.22,26.71 0.29,26.8 1.2,27.71 1.35,27.94 1.4,28.21 1.4,28.78 3.32,28.78 3.34,28.63 3.41,28.49 6.7,26.78 9.99,28.49 10.06,28.63 10.08,28.78 15.55,28.78 16.08,29.31 16.08,30.67 15.42,31.32 13.11,31.32 12.01,32.42 12.01,36.07 12.9,36.96 12.9,39.09 14.02,40.21 17.24,40.21 17.98,39.47 17.98,35.97 18.31,35.64 20.22,35.64 20.27,35.59 20.27,33.5 19.79,33.03 19.79,31.53 20.12,31.2 20.56,31.2 20.56,31.09 20.71,30.94 21.81,30.94 22.07,30.69 23.29,30.69 24.2,31.6 24.2,34.35 23.42,35.13 22.23,35.13 22.17,35.18 22.17,36.6 22.35,36.78 23.39,36.78 23.94,36.24 23.82,36.13 23.82,35.92 24.73,35.01 25.37,35.01 27.25,33.12 27.25,31.43 26.39,30.56 24.48,30.56 24.08,30.16 24.08,29.44 24.33,29.19 24.33,18.9
GNDA on GND: 1,18.9 0.44,19.14 0.2,19.7 0.2,26.59 0.23,26.71 0.29,26.8 1.2,27.71 1.35,27.94 1.4,28.21 1.4,28.78 3.23,28.78 6.7,26.78 10.17,28.78 15.55,28.78 16.08,29.31 16.08,30.67 15.42,31.32 13.11,31.32 12.01,32.42 12.01,36.07 12.9,36.96 12.9,39.09 14.02,40.21 17.24,40.21 17.98,39.47 17.98,35.97 18.31,35.64 20.22,35.64 20.27,35.59 20.27,33.5 19.79,33.03 19.79,31.53 20.12,31.2 20.56,31.2 20.56,31.09 20.71,30.94 21.81,30.94 22.07,30.69 23.29,30.69 24.2,31.6 24.2,34.35 23.42,35.13 22.23,35.13 22.17,35.18 22.17,36.6 22.35,36.78 23.39,36.78 23.94,36.24 23.82,36.13 23.82,35.92 24.73,35.01 25.37,35.01 27.25,33.12 27.25,31.43 26.39,30.56 24.48,30.56 24.08,30.16 24.08,29.44 24.33,29.19 24.33,18.9
PVCC_NVVDD on TOP (solid shape): 121.81,134.7 121.81,133.16 122.31,132.66 122.31,132.19 122.09,131.97 120.74,131.97 120.7,132.01 120.7,132.55 120.76,132.62 121.02,132.62 121.58,133.18 121.58,134.71 121.61,134.74 121.77,134.74
VCC_1V on BOTTOM (solid shape): 185.69,94.59 185.69,94.03 185.6,93.94 184.96,93.94 184.63,93.61 184.63,91.68 184.59,91.64 183.97,91.64 183.87,91.73 183.87,94.16 184.32,94.61 184.77,94.61 184.85,94.68 185.6,94.68
VCC_5V on BOTTOM (solid shape): 183.72,102.72 183.72,102.61 183.28,102.18 181.46,102.18 181.39,102.25 181.39,102.76 181.44,102.81 183.64,102.81
VCC_CHG on BOTTOM (solid shape): 192.92,61.18 192.92,59.39 194.4,57.91 194.4,57.52 194.32,57.44 193.53,57.44 192.55,58.42 191.86,58.42 191.69,58.59 191.69,61.16 191.84,61.32 192.78,61.32
VCC_VRAM on BOTTOM (solid shape): 186.35,135.54 186.35,134.94 186.29,134.88 185.64,134.88 184.77,134.01 184.77,133.61 184.38,133.22 183.76,133.22 183.63,133.35 183.63,134.08 184.99,135.44 185.19,135.44 185.34,135.59 186.3,135.59
VDD_DDR on BOTTOM (solid shape): 14.58,76.31 14.58,73.37 14.19,72.99 12.97,72.99 12.87,73.08 12.87,73.64 12.99,73.75 13.52,73.75 13.8,74.03 13.8,75.55 13.57,75.78 12.05,75.78 11.74,76.09 11.46,76.09 11.42,76.09 11.38,76.09 11.15,76.09 10.91,75.84 10.14,75.84 10.07,75.91 10.07,76.37 10.23,76.52 13.17,76.52 13.24,76.59 13.43,76.59 13.43,76.59 14.29,76.59
+FAN1 on BOTTOM (solid shape): 240.02,25.68 240.02,25.54 239.86,25.19 239.43,24.07 240.12,23.1 240.12,20.5 239.96,20.34 237.98,20.34 237.8,20.52 237.8,25.03 238.74,25.97 239.72,25.97
+HDMI_CRT_5V on TOP (solid shape): outline of 123 points within 10.78,123.08 15.98,127.27
+LAN_REGOUT on BOTTOM (solid shape): 36.3,105.75 36.3,105.49 37.19,104.6 38.4,104.6 38.52,104.49 38.52,102.39 38.38,102.25 37.33,102.25 35.29,104.29 35.29,104.71 35.03,104.97 35.03,105.95 34.97,106.01 34.97,106.12 35.04,106.18 35.87,106.18
+LAN_VDD_1V0 on BOTTOM (solid shape): 42.48,104.01 42.48,102.43 42.3,102.25 39.11,102.25 38.93,102.43 38.93,104.44 39.28,104.79 41.7,104.79
+LAN_VDD_1V0 on BOTTOM (solid shape): 32.88,105.87 32.88,104.63 32.85,104.6 32.85,103.82 32.67,103.64 31.18,103.64 31.05,103.77 31.05,104.15 31.18,104.28 32.04,104.28 32.62,104.86 32.62,105.87 32.69,105.94 32.81,105.94
+LAN_VDD_1V0 on BOTTOM (solid shape): 38.25,109.25 38.25,108.81 38.02,108.58 38.02,107.08 37.96,107.02 37.19,107.02 36.89,106.72 36.12,106.72 36.08,106.75 35.05,106.75 34.97,106.83 34.97,106.9 35.05,106.98 36.08,106.98 36.24,107.14 36.69,107.14 36.94,107.4 36.94,107.67 36.8,107.81 36.8,107.99 37.06,108.25 37.06,109.16 37.32,109.43 38.07,109.43
+LAN_VDD_1V0 on BOTTOM (solid shape): 31.21,111.28 31.21,110.75 31.04,110.58 30.58,110.58 30.48,110.48 30.48,110.24 31.52,109.2 31.62,109.1 31.73,109.04 31.76,109.02 31.78,109.01 31.78,108.82 31.72,108.76 30.92,108.76 29.26,110.42 29.26,110.42 29.26,111.07 29.43,111.24 29.98,111.24 30.16,111.42 31.07,111.42
+LAN_VDD_1V0 on IN1 (solid shape): 31.34,110.98 31.34,107.58 31.21,107.46 28.99,107.46 28.9,107.55 28.9,110.96 29.07,111.13 31.19,111.13
+LAN_VDD_1V0 on IN2 (solid shape): outline of 647 points within 27.93,102.43 42.38,108.58
+LAN_VDD_3V3 on TOP (solid shape): outline of 804 points within 26.26,99.79 45.83,115
+LAN_VDD_3V3 on BOTTOM (solid shape): 43.75,106.82 43.75,104.84 43.57,104.66 42.16,104.66 41.98,104.84 41.98,106.77 42.16,106.95 43.63,106.95
+LAN_VDD_3V3 on BOTTOM (solid shape): 33.06,111.35 33.06,110.31 32.9,110.15 32.9,109.12 32.84,109.05 32.75,109.05 32.66,109.15 32.66,110 32.61,110.05 32.61,110.14 32.31,110.44 32.31,111.3 32.44,111.44 32.97,111.44
+LAN_VDD_3V3 on BOTTOM (solid shape): 38.04,106.68 38.04,105.17 37.91,105.04 37.02,105.04 36.43,105.63 36.43,105.8 36.37,105.86 36.37,105.87 35.9,106.35 35.05,106.35 34.98,106.41 34.98,106.52 35.04,106.57 36.08,106.57 36.1,106.59 37.02,106.59 37.19,106.76 37.96,106.76
+LAN_VDD_3V3 on BOTTOM (solid shape): 32.11,105.81 32.11,105.11 31.99,104.99 30.35,104.99 30.29,105.04 30.29,105.42 30.38,105.51 31.33,105.51 31.58,105.57 31.77,105.73 31.79,105.75 31.8,105.75 31.92,105.87 32.05,105.87
+LCDVDD on TOP (solid shape): 64.43,111.93 64.43,111.42 64.21,111.2 59.83,111.2 59.62,111.41 59.62,112.15 59.89,112.41 63.94,112.41
+LCDVDD on TOP (solid shape): 78.98,110.58 78.98,105.47 78.85,105.2 78.98,104.93 78.98,101.75 75.29,98.06 68.05,98.06 67.13,98.99 67.13,100.86 66.78,101.2 66.78,101.79 66.92,101.93 67.9,101.93 68.15,101.67 68.13,101.64 68.2,101.25 68.59,101.16 68.62,101.18 68.69,101.11 69.05,101.11 69.12,101.08 69.15,101 69.5,100.59 69.85,101 69.88,101.08 69.95,101.11 70.54,101.11 70.62,101.08 70.64,101 71,100.63 71.36,101 71.38,101.08 71.46,101.11 72.14,101.11 72.15,101.07 72.65,100.79 72.76,101.36 72.73,101.43 72.76,101.5 74.66,103.4 74.66,110.58 74.84,110.76 78.8,110.76
+LCDVDD on BOTTOM (solid shape): 68.1,101.81 68.1,101.35 68.29,101.16 68.29,100.95 68.28,100.94 68.28,100.65 68.14,100.51 68.14,99.7 68.15,99.69 68.15,99.48 67.97,99.3 67.53,99.3 67.35,99.48 67.35,100.47 67.23,100.59 67.24,100.62 67.25,100.92 67.04,101.12 66.86,101.29 66.86,101.81 66.97,101.91 68,101.91
+LCDVDD on IN1: 76.3,108.74 59.74,108.74 58.91,109.56 58.91,112.14 59.23,112.46 76.11,112.46 76.85,111.72 76.85,109.29
+V_DAC on TOP (solid shape): 33.53,130.84 33.53,120.86 33.47,120.8 32.29,120.8 32.16,120.94 32.16,130.88 32.22,130.94 33.42,130.94
+VGA_CORE on TOP (solid shape): 127.11,127.78 127.11,118.64 125.33,116.86 124.29,116.86 122.81,116.25 121.41,114.84 120.76,113.27 120.76,109.36 120.45,109.05 118.97,109.05 118.79,109.23 118.79,118.11 118.52,118.38 116.89,118.38 116.62,118.11 116.62,114.07 116.34,113.8 113.9,113.8 113.39,114.3 113.39,119.86 113.66,120.13 116.17,120.13 116.44,120.39 116.44,121.92 116.71,122.19 120,122.19 125.84,128.04 126.86,128.04
+VGA_CORE on TOP (solid shape): outline of 575 points within 140.49,95.25 149.76,108.86
+VGA_CORE on BOTTOM (solid shape): 127.24,132.35 127.24,127.15 126.22,126.13 126.22,124.23 126.86,123.59 126.86,121.94 126.22,121.31 126.22,118.26 123.71,115.74 123.06,115.47 122,114.42 121.52,113.26 121.52,111.08 119.81,109.37 118.97,109.37 118.79,109.55 118.79,118.7 120.76,120.67 120.76,126.77 123.55,129.56 123.55,132.37 123.79,132.61 126.98,132.61
+VGA_CORE on BOTTOM (solid shape): outline of 3846 points within 140.31,93.6 150.64,109.79
+VGA_CORE on VCC: 125.95,100.73 115.81,110.87 115.81,126.28 116.42,126.89 126.5,126.89 127.11,126.28 127.11,123.61 141.1,109.62 149.1,109.62 149.72,109.01 149.72,100.96 149.48,100.73
+VGA_CORE on IN1: 124.3,128.8 126.98,128.8 127.49,128.29 127.49,123.85 142.29,109.05 148.57,109.05 149.72,107.91 149.72,99.54 149.71,99.54 149.38,99.21 145.88,99.21 145.21,98.54 145.21,95.72 144.25,94.75 140.69,94.75 140.39,95.05 140.39,98.87 140.46,98.87 140.97,99.38 140.97,102.85 140.7,103.12 140.36,103.12 140.11,102.87 140.11,101.54 139.7,101.13 134.21,101.13 133.09,102.24 120.48,102.24 117.37,105.35 117.37,110.98 116.19,112.16 116.19,119.78 117.11,120.7 117.11,121.61
ACDRV_CHG_R on TOP (solid shape): 191.63,56.03 191.63,54.81 191.5,54.68 189.98,54.68 189.77,54.48 189.11,54.48 188.98,54.6 188.98,55.29 189.16,55.47 189.54,55.47 190.23,56.15 191.5,56.15
ACDRV_CHG_R on TOP (solid shape): 184.89,54.88 184.89,53.99 185.2,53.69 185.2,52.26 184.94,52.01 182.79,52.01 182.61,52.19 182.61,54.01 182.67,54.08 183.71,54.08 184.01,54.38 184.01,54.88 184.13,55.01 184.77,55.01
BATDRV_CHG_R on TOP (solid shape): 179.05,55.71 179.05,55.45 178.9,55.31 177.89,55.31 177.68,55.1 177.68,54.05 177.61,53.98 176.94,53.98 176.83,54.1 176.83,55.66 177.02,55.85 178.91,55.85
BST1_NVVDD on TOP (solid shape): 124.05,134.78 124.39,134.78 124.52,134.65 124.52,134.32 125.03,133.81 125.03,133.53 125.02,133.53 125.02,133.29 125.03,133.29 125.03,132.87 124.32,132.87 124.21,132.98 124.21,133.5 122.89,134.82 122.79,134.92 122.79,135.1 122.85,135.16 123.68,135.16
BST1_NVVDD-R on TOP (solid shape): 126.56,133.7 126.56,132.07 126.32,131.83 125.2,131.83 125.14,131.89 125.14,132.53 125.19,132.57 125.49,132.57 125.65,132.74 125.65,133.71 125.78,133.84 126.42,133.84
BST2_NVVDD on TOP (solid shape): 120.6,135.09 120.6,134.71 119.77,133.88 117.46,133.88 117.33,134 117.33,134.59 117.51,134.77 119.36,134.77 119.72,135.13 120.55,135.13
BST2_NVVDD-R on TOP (solid shape): 119.36,133.17 119.36,132.59 119.25,132.48 117.56,132.48 117.46,132.58 117.46,133.24 117.51,133.3 119.23,133.3
BST_1V on BOTTOM (solid shape): 186.63,98.25 186.63,97.63 186.03,97.03 186.03,96.15 185.96,96.08 185.84,96.08 185.73,96.18 185.73,97.4 186.02,97.69 186.02,98.26 186.08,98.32 186.56,98.32
BST_1V_R on BOTTOM (solid shape): 185.68,98.3 185.68,97.67 185.57,97.56 184.34,97.56 184.23,97.67 184.23,98.29 184.32,98.38 185.6,98.38
BST_3V on BOTTOM (solid shape): 187.97,118.76 187.97,117.76 187.93,117.73 187.93,116.84 187.84,116.75 187.73,116.75 187.31,117.17 187.31,118.77 187.33,118.8 187.94,118.8
BST_3V_R on BOTTOM (solid shape): 187.96,119.77 187.96,119.17 187.94,119.16 186.52,119.16 186.5,119.18 186.5,119.76 186.61,119.88 187.84,119.88
BST_5V on BOTTOM (solid shape): 183.22,107.32 183.22,105.59 183.25,105.55 183.25,105.51 183.73,105.03 183.73,104.89 183.64,104.8 182.98,104.8 182.54,105.24 182.54,107.34 182.6,107.4 183.14,107.4
BST_5V_R on BOTTOM (solid shape): 183.2,109.32 183.2,107.84 183.13,107.77 182.52,107.77 182.46,107.83 182.46,109.29 182.53,109.36 183.15,109.36
BST_DDR on BOTTOM (solid shape): 9.1,74.03 9.1,71.69 8.93,71.52 8.93,70.46 8.71,70.24 7.97,70.24 7.89,70.33 7.89,71.59 8.85,72.55 8.85,74.02 8.9,74.07 9.05,74.07
BST_DDR_R on BOTTOM (solid shape): 11.35,71.15 11.35,70.28 11.28,70.21 9.45,70.21 9.36,70.3 9.36,71.23 9.39,71.27 11.23,71.27
BST_VRAM on BOTTOM (solid shape): 186.85,139.13 186.85,138.36 186.67,138.18 186.67,137.03 186.63,136.99 186.49,136.99 186.07,137.41 186.07,139.03 186.06,139.03 186.06,139.1 186.11,139.15 186.84,139.15
BST_VRAM_R on BOTTOM (solid shape): 186.85,140.11 186.85,139.57 186.74,139.46 186.12,139.46 186.08,139.43 185.29,139.43 185.23,139.49 185.23,139.97 185.49,140.24 186.73,140.24
BTST_CHG on BOTTOM (solid shape): 192.96,56.23 194.31,56.23 194.41,56.13 194.41,56.04 194.3,55.93 193.38,55.93 193.28,55.82 193.28,55.62 192.97,55.31 192.28,55.31 192.17,55.42 192.17,56.2 192.27,56.3 192.89,56.3
CHG on BOTTOM (solid shape): 171.55,58.63 171.03,58.63 170.67,58.27 171.03,57.92 171.52,57.92 171.55,57.9 171.55,57.23 172.7,56.08 172.7,52.34 171.94,51.58 168.89,51.58 168.64,51.84 168.64,56.35 169.5,57.21 169.5,58.98 169.72,59.2 171.55,59.2
CHG_N001 on BOTTOM (solid shape): 191.58,57.02 191.58,56.12 191.7,56.01 191.7,54.48 191.28,54.06 191.28,53.32 191.18,53.23 189.84,53.23 189.72,53.34 189.72,54.41 190.51,55.2 190.73,55.2 190.87,55.35 190.87,55.35 190.87,56.29 190.7,56.46 190.7,57.17 190.78,57.25 191.35,57.25
CORE1_BST on BOTTOM (solid shape): 174.11,67 174.11,66.05 173.98,65.92 173.31,65.92 172.5,66.73 172.5,67.69 172.58,67.77 173.34,67.77
CORE1_BST_R on BOTTOM (solid shape): 171.88,67.71 171.88,65.88 171.76,65.76 171.11,65.76 170.99,65.88 170.99,67.67 171.1,67.78 171.81,67.78
CORE1_LG on BOTTOM (solid shape): 158.37,69.74 158.37,68.73 158.24,68.6 156.95,68.6 156.83,68.73 156.83,69.74 156.95,69.87 158.24,69.87
CORE1_LG on IN2 (solid shape): 158.92,69.24 158.29,68.6 156.89,68.6 156.83,68.66 156.83,69.81 156.89,69.87 158.29,69.87
CORE1_LG on IN2 (solid shape): 177.53,65.46 177.53,64.79 177.21,64.47 176.07,64.47 175.21,63.61 175.03,63.61 174.57,64.06 174.57,64.24 175.37,65.04 175.37,65.3 175.75,65.68 177.31,65.68
CORE1_LX on TOP (solid shape): 162.75,75.46 162.83,75.42 162.84,75.32 163.18,74.85 163.51,75.32 163.53,75.42 163.61,75.46 168,75.46 168.13,75.33 168.13,74.19 168,74.06 163.81,74.06 163.69,73.93 163.69,72.28 163.56,72.16 162.42,72.16 162.29,72.28 162.29,75.33 162.42,75.46
CORE1_LX on BOTTOM (solid shape): 162.92,74.44 164.45,74.44 164.57,74.32 164.57,71.45 164.45,71.32 163.08,71.32 162.42,70.66 153.85,70.66 153.72,70.78 153.72,72.16 153.85,72.28 154.51,72.28 154.63,72.41 154.63,73.43 154.51,73.55 153.85,73.55 153.72,73.68 153.72,75.08 153.85,75.2 162.16,75.2
CORE1_LX on BOTTOM (solid shape): 172.87,65.38 173.07,65.19 174,65.19 174.09,65.1 174.09,64.99 174.01,64.92 172.96,64.92 172.93,64.92 172.91,64.93 172.67,64.87 172.43,64.85 171.13,64.85 171.05,64.93 171.05,65.37 171.11,65.43 172.77,65.43
CORE1_LX on IN1 (solid shape): 164.61,72.82 164.13,72.35 162.42,72.35 162.29,72.47 162.29,73.17 162.42,73.3 164.13,73.3
CORE1_LX on IN1 (solid shape): 171.81,67.58 171.81,65.81 172.19,65.43 172.95,65.43 173.11,65.27 173.11,65.07 172.96,64.92 171.43,64.92 171.05,65.3 171.05,67.58 171.18,67.71 171.69,67.71
CORE1_SNUB on TOP (solid shape): 168,72.66 168,71.65 167.88,71.52 164.96,71.52 164.83,71.65 164.83,72.66 164.96,72.79 167.88,72.79
CORE1_UG on BOTTOM (solid shape): 164.57,75.59 164.57,75.33 164.45,75.2 163.69,75.2 163.43,74.95 163.05,74.95 162.92,75.08 162.92,75.59 163.05,75.71 164.45,75.71
CORE1_UG on IN1 (solid shape): 173.21,67.2 173.21,65.81 173.05,65.65 172.35,65.65 172.07,65.93 172.07,67.11 172.69,67.73
CORE2_BST on BOTTOM (solid shape): 174.1,63.77 174.1,62.19 174.02,62.12 173.93,62.12 173.92,62.11 173.32,62.11 173.1,62.33 173.1,63.79 173.22,63.91 173.96,63.91
CORE2_BST_R on BOTTOM (solid shape): 172.52,63.86 172.52,62.88 172.4,62.76 172.06,62.76 171.81,62.51 171.81,61.93 171.75,61.87 171.24,61.87 171.12,62 171.12,63.25 170.93,63.44 170.93,63.82 171.07,63.96 172.42,63.96
CORE2_LG on BOTTOM (solid shape): 162.92,66.19 162.92,65.04 162.8,64.92 161.65,64.92 161.53,65.04 161.53,66.19 161.65,66.31 162.8,66.31
CORE2_LG on IN2 (solid shape): 164.26,65.71 164.26,65.53 163.65,64.92 162.38,64.92 162.26,65.04 162.26,66.19 162.38,66.31 163.65,66.31
CORE2_LG on IN2 (solid shape): 177.58,61.45 177.58,61.13 177.39,60.93 176.43,60.93 175.08,62.29 175.08,62.47 175.37,62.76 176.27,62.76
CORE2_LX on TOP (solid shape): 163.05,61.69 163.05,60.02 162.87,59.84 160.31,59.84 160.13,60.02 160.13,61.69 160.31,61.87 162.87,61.87
CORE2_LX on BOTTOM (solid shape): 163.43,63.52 164.45,63.52 164.57,63.39 164.57,59.47 164.45,59.35 150.97,59.35 150.6,59.71 150.6,62.38 150.73,62.5 152.68,62.5 152.8,62.38 152.8,61.48 153.61,61.48 153.61,63.99 153.91,64.28 162.67,64.28
CORE2_LX on BOTTOM (solid shape): 172.07,61.49 172.94,61.49 173.04,61.38 173.06,61.37 174.01,61.37 174.08,61.29 174.08,61.18 174.01,61.11 173.1,61.11 172.95,60.96 172.74,60.98 171.18,60.98 171.12,61.04 171.12,61.55 171.18,61.62 171.94,61.62
CORE2_LX on IN1 (solid shape): 164.35,61.42 164.35,61.23 163.72,60.6 162.38,60.6 162.26,60.73 162.26,61.81 162.38,61.93 163.84,61.93
CORE2_LX on IN1 (solid shape): 171.42,61.49 173.06,61.49 173.17,61.38 173.17,61.09 173.05,60.98 169.91,60.98 169.78,61.11 169.78,61.62 169.86,61.69 171.22,61.69
CORE2_SNUB on TOP (solid shape): 162.29,64.74 162.29,62.94 162.11,62.76 160.56,62.76 160.38,62.94 160.38,64.74 160.56,64.92 162.11,64.92
CORE2_UG on BOTTOM (solid shape): 165.59,67.33 165.59,65.81 165.46,65.68 164.57,65.68 164.45,65.81 164.45,67.33 164.57,67.46 165.46,67.46
CORE2_UG on IN1 (solid shape): 165.59,67.33 165.59,65.87 165.17,65.45 164.99,65.45 164.45,66 164.45,67.33 164.57,67.46 165.46,67.46
CORE2_UG on IN1 (solid shape): 173.16,62.32 173.16,61.82 173.05,61.7 171.59,61.7 171.35,61.94 169.81,61.94 169.77,61.99 169.77,62.43 169.82,62.49 173,62.49
CORE2_UG_R on BOTTOM (solid shape): 164.19,66.57 164.19,65.04 164.57,64.66 164.57,64.41 164.45,64.28 163.2,64.28 163.06,64.43 163.06,64.86 163.3,65.11 163.3,66.57 163.43,66.7 164.07,66.7
DH1_NVVDD on TOP (solid shape): 125.1,135.66 125.1,135.33 124.93,135.15 123.95,135.15 123.77,135.32 122.83,135.32 122.8,135.36 122.8,135.48 122.84,135.52 123.64,135.52 123.99,135.52 124.25,135.78 124.98,135.78
DH1_NVVDD on BOTTOM (solid shape): 110.15,121.98 110.15,121.39 110.06,121.31 108.15,121.31 108.06,121.39 108.06,121.98 108.15,122.07 110.06,122.07
DH1_NVVDD on IN2 (solid shape): 109.08,121.96 109.08,120.54 108.25,120.54 108.06,120.73 108.06,121.94 108.19,122.07 108.97,122.07
DH1_NVVDD on IN2 (solid shape): 125.33,135.54 125.33,134.52 124.94,134.13 124.46,134.13 124.02,134.57 124.02,135.63 124.22,135.82 125.05,135.82
DH2_NVVDD on TOP (solid shape): 120.59,135.46 120.59,135.38 120.53,135.32 119.66,135.32 119.36,135.02 118.43,135.02 118.35,135.1 118.35,135.4 118.47,135.52 120.53,135.52
DH2_NVVDD on BOTTOM (solid shape): 110.91,129.6 110.91,129.01 110.82,128.93 108.91,128.93 108.82,129.01 108.82,129.6 108.91,129.69 110.82,129.69
DH2_NVVDD on IN2 (solid shape): 118.86,135.52 119.34,135.52 119.48,135.38 119.48,135.2 119.3,135.02 117.71,135.02 117.33,135.4 115.99,135.4 115.81,135.58 115.81,136.24 115.99,136.42 117.97,136.42
DH2_NVVDD on IN2 (solid shape): 109.99,129.52 109.99,128.82 109.86,128.68 108.23,128.68 108.04,128.87 108.04,129.46 108.16,129.59 108.53,129.59 109.03,129.59 109.93,129.59
DL1_NVVDD on TOP (solid shape): 122.2,134.69 122.2,133.68 123.3,132.59 123.3,132.1 123.17,131.97 122.66,131.97 122.54,132.1 122.54,132.62 121.96,133.2 121.96,134.66 122.03,134.72 122.17,134.72
DL1_NVVDD on BOTTOM (solid shape): 116.19,122.07 116.19,120.78 115.96,120.55 114.15,120.55 114.03,120.67 114.03,122.1 114.12,122.19 116.06,122.19
DL1_NVVDD on IN2 (solid shape): 122.92,133.19 122.92,131.86 122.65,131.59 121.9,131.59 121.78,131.72 121.78,133.37 122.07,133.66 122.45,133.66
DL1_NVVDD on IN2 (solid shape): 116.7,122.18 116.7,121.45 116.7,121.31 115.96,120.57 114.77,120.57 114.66,120.67 114.66,121.81 115.3,122.45 116.42,122.45
DL2_NVVDD on TOP (solid shape): 121.41,134.69 121.41,133.19 120.99,132.76 120.63,132.76 120.47,132.92 120.47,133.14 121.19,133.87 121.19,134.69 121.25,134.74 121.37,134.74
DL2_NVVDD on BOTTOM (solid shape): 116.82,129.67 116.82,128.28 116.7,128.16 115.93,128.16 115.22,128.88 114.83,128.88 114.79,128.93 114.79,129.74 114.86,129.81 116.68,129.81
DL2_NVVDD on IN2 (solid shape): 121.39,133.62 121.39,132.61 120.51,131.72 119.64,131.72 119.49,131.87 119.49,132.23 121.01,133.75 121.26,133.75
DL2_NVVDD on IN2 (solid shape): 116.95,129.92 116.95,129.2 116.95,128.39 116.87,128.31 115.79,128.31 115.68,128.42 115.68,129.93 115.89,130.14 116.73,130.14
GPU_PLLVDD on TOP (solid shape): 148.4,99.43 148.83,99 148.83,95.27 148.45,94.89 148.11,94.89 147.73,95.27 147.73,97.88 147.63,98.15 147.39,98.3 147.37,98.31 147.05,98.63 147.05,99.49 147.13,99.57 148.07,99.57
GT_BST on BOTTOM (solid shape): 168.83,89.81 168.83,88.16 168.7,88.03 168,88.03 167.62,88.41 167.17,88.41 166.99,88.59 166.99,89.81 167.11,89.94 168.7,89.94
GT_BST_R on BOTTOM (solid shape): 166.38,89.81 166.38,87.78 166.32,87.71 165.69,87.71 165.56,87.84 165.56,89.75 165.69,89.87 166.32,89.87
GT_LG on BOTTOM (solid shape): 158.62,79.38 158.62,78.38 158.49,78.25 157.21,78.25 157.08,78.38 157.08,79.4 157.27,79.58 158.42,79.58
GT_LG on IN1 (solid shape): 159.3,78.95 158.61,78.25 157.34,78.25 157.21,78.38 157.21,79.52 157.34,79.65 158.61,79.65
GT_LG on IN1 (solid shape): 171.81,86.89 171.81,85.4 171.4,84.98 171.22,84.98 170.8,85.4 170.8,87.1 170.92,87.23 171.47,87.23
GT_LX on TOP (solid shape): 163.94,81.05 163.94,80.16 163.81,80.03 163.3,80.03 162.54,79.27 161.27,79.27 161.15,79.4 161.15,81.05 161.27,81.17 163.81,81.17
GT_LX on BOTTOM (solid shape): 166.6,87.27 168.39,87.27 168.4,87.27 168.74,87.27 168.82,87.2 168.82,87.09 168.75,87.02 168,87.02 167.81,86.82 167.7,86.71 167.56,86.67 165.64,86.67 165.46,86.85 165.46,87.34 165.64,87.52 166.35,87.52
GT_LX on BOTTOM (solid shape): 156.07,84.73 157.79,84.73 157.99,84.92 163.18,84.92 163.3,84.8 163.3,83.33 163.69,82.95 164.45,82.95 164.57,82.82 164.57,80.03 164.45,79.9 154.16,79.9 154.1,79.96 154.1,81.34 155.01,81.34 155.01,82.15 154.1,82.15 154.1,83.78 155.24,84.92 155.87,84.92
GT_LX on IN1 (solid shape): 167.88,87.05 167.88,85.87 167.37,85.36 167.11,85.36 166.61,85.87 166.61,87.05 166.73,87.18 167.75,87.18
GT_SNUB on TOP (solid shape): 160.13,81.05 160.13,79.4 160,79.27 157.97,79.27 157.84,79.4 157.84,79.93 157.95,80.03 158.61,80.03 158.73,80.16 158.73,81.05 158.86,81.17 160,81.17
GT_UG on BOTTOM (solid shape): 165.97,86.38 165.97,85.24 165.84,85.11 164.83,85.11 164.7,85.24 164.7,86.38 164.83,86.51 165.84,86.51
GT_UG on IN1 (solid shape): 165.76,87.23 165.76,87.05 165.34,86.63 165.34,85.24 165.21,85.11 164.7,85.11 164.57,85.24 164.57,86.89 165.25,87.56 165.43,87.56
GT_UG_R on BOTTOM (solid shape): 164.57,86.38 164.57,83.84 164.45,83.71 163.81,83.71 163.69,83.84 163.69,86.38 163.81,86.51 164.45,86.51
IN_1.8V on BOTTOM (solid shape): 180.39,88.96 180.39,88.4 180.19,88.2 180.19,86.85 180.03,86.68 178.06,86.68 177.94,86.81 177.94,88.88 178.13,89.07 180.27,89.07
IN_2.5V on BOTTOM (solid shape): 4.56,49.72 4.56,45.84 4.49,45.77 3.75,45.77 3.64,45.88 3.64,48.46 3.24,48.86 3.24,49.74 3.27,49.77 4.51,49.77
INVPWR_B+ on TOP (solid shape): outline of 152 points within 59.76,93.14 96.88,104.77
INVPWR_B+ on BOTTOM (solid shape): 97.4,106.55 97.4,102.45 97.26,102.31 93.36,102.31 93.2,102.47 93.2,106.44 93.46,106.7 97.26,106.7
INVPWR_B+ on BOTTOM (solid shape): 63.36,101.82 63.36,100.6 63.15,100.4 63.15,99.38 63.08,99.3 62.44,99.3 62.35,99.4 62.35,100.47 62.21,100.6 62.21,101.82 62.39,102 63.18,102
LG_CHG on BOTTOM (solid shape): 178.9,50 178.9,49.31 178.76,49.17 178.1,49.17 177.74,49.52 177.74,49.91 177.97,50.14 178.76,50.14
LG_CHG on BOTTOM (solid shape): 194.88,55.17 194.88,54.38 194.8,54.3 194.8,53.65 194.56,53.41 194.1,53.41 194,53.52 194,54.45 194.52,54.97 194.52,55.14 194.62,55.24 194.82,55.24
LG_CHG on IN2 (solid shape): 194.54,54.39 194.54,53.78 194.54,53.55 194.4,53.41 192.9,53.41 192.88,53.43 192.71,53.61 192.71,54.28 192.95,54.53
LG_CHG on IN2 (solid shape): 179.78,50.06 179.78,49.86 179.27,49.35 177.85,49.35 177.68,49.51 177.68,50.01 177.81,50.13 178.88,50.13 179.14,50.4 179.45,50.4
LG_DDR on BOTTOM (solid shape): 4.1,64.83 4.1,63.57 3.92,63.39 3.13,63.39 2.97,63.56 2.97,64.26 3.11,64.4 3.44,64.4 3.55,64.51 3.55,64.76 3.7,64.92 4.01,64.92
LG_DDR on BOTTOM (solid shape): 11.41,73.99 11.41,73.71 11.24,73.54 10.52,73.54 10.33,73.73 10.33,74.01 10.08,74.26 10.08,74.4 10.15,74.47 10.93,74.47
LG_DDR on IN2 (solid shape): 4.13,65.68 4.13,64.3 4.12,64.29 4.12,63.55 3.96,63.39 3.16,63.39 3,63.55 3,65.68 3.13,65.81 4,65.81
LG_DDR on IN2 (solid shape): 11.97,73.69 11.97,72.46 12.43,72 12.43,71.37 12.1,71.03 11.41,71.03 10.99,71.45 10.99,73.12 10.49,73.62 10.38,73.62 10.33,73.68 10.33,74.07 10.4,74.14 11.52,74.14
LX1_NVVDD on TOP (solid shape): 124.05,133.42 124.05,133.13 124.06,133.12 124.06,132.93 124.35,132.63 124.89,132.63 124.94,132.58 124.94,131.95 124.85,131.86 124.37,131.86 122.39,133.84 122.39,134.67 122.44,134.72 122.75,134.72
LX1_NVVDD on BOTTOM (solid shape): 110.15,123.25 110.15,122.66 110.06,122.58 108.15,122.58 108.06,122.66 108.06,123.25 108.15,123.34 110.06,123.34
LX1_NVVDD on IN2 (solid shape): 110.35,123.36 110.35,122.47 110.22,122.34 108.17,122.34 108.06,122.45 108.06,123.34 108.18,123.46 110.24,123.46
LX1_NVVDD on IN2 (solid shape): 124.73,133.47 124.73,132.13 124.57,131.97 123.75,131.97 123.64,132.08 123.64,132.99 122.83,133.81 122.82,133.81 122.75,133.88 122.75,134.2 122.86,134.32 123.88,134.32
LX1_NVVDD-1 on TOP (solid shape): 118.6,124.9 118.6,123.14 118.42,122.96 116.24,122.96 116.06,123.14 116.06,124.73 116.41,125.08 118.42,125.08
LX1_NVVDD-1 on BOTTOM (solid shape): 119.62,125.69 119.62,121.05 119.49,120.92 117.26,120.92 117.08,121.1 117.08,122.4 116.9,122.58 115.32,122.58 115.04,122.85 115.04,125.62 115.3,125.88 119.43,125.88
LX2_NVVDD on TOP (solid shape): 121,134.67 121,133.87 120.24,133.1 120.24,132.57 120.17,132.51 119.72,132.51 119.68,132.55 119.68,133.59 120.82,134.73 120.94,134.73
LX2_NVVDD on BOTTOM (solid shape): 110.91,130.87 110.91,130.2 110.83,130.12 108.94,130.12 108.82,130.24 108.82,130.8 108.97,130.96 110.82,130.96
LX2_NVVDD on IN2 (solid shape): 111.12,130.87 111.12,130.22 111,130.09 108.93,130.09 108.83,130.2 108.83,130.85 108.95,130.97 111.02,130.97
LX2_NVVDD on IN2 (solid shape): 120.7,134.07 120.7,133.7 120.1,133.1 118.34,133.1 118.19,133.25 118.19,134 118.43,134.23 120.54,134.23
LX2_NVVDD-1 on TOP (solid shape): 117.33,133.37 117.33,132.41 117.51,132.23 118.55,132.23 118.73,132.05 118.73,130.89 118.55,130.7 116.62,130.7 116.44,130.89 116.44,133.36 116.58,133.5 117.2,133.5
LX2_NVVDD-1 on BOTTOM (solid shape): 120.13,132.47 120.13,128.71 120.05,128.63 117.46,128.63 117.08,129.01 117.08,129.91 116.92,130.07 116.04,130.07 115.81,130.3 115.81,133.3 116.13,133.62 118.98,133.62
